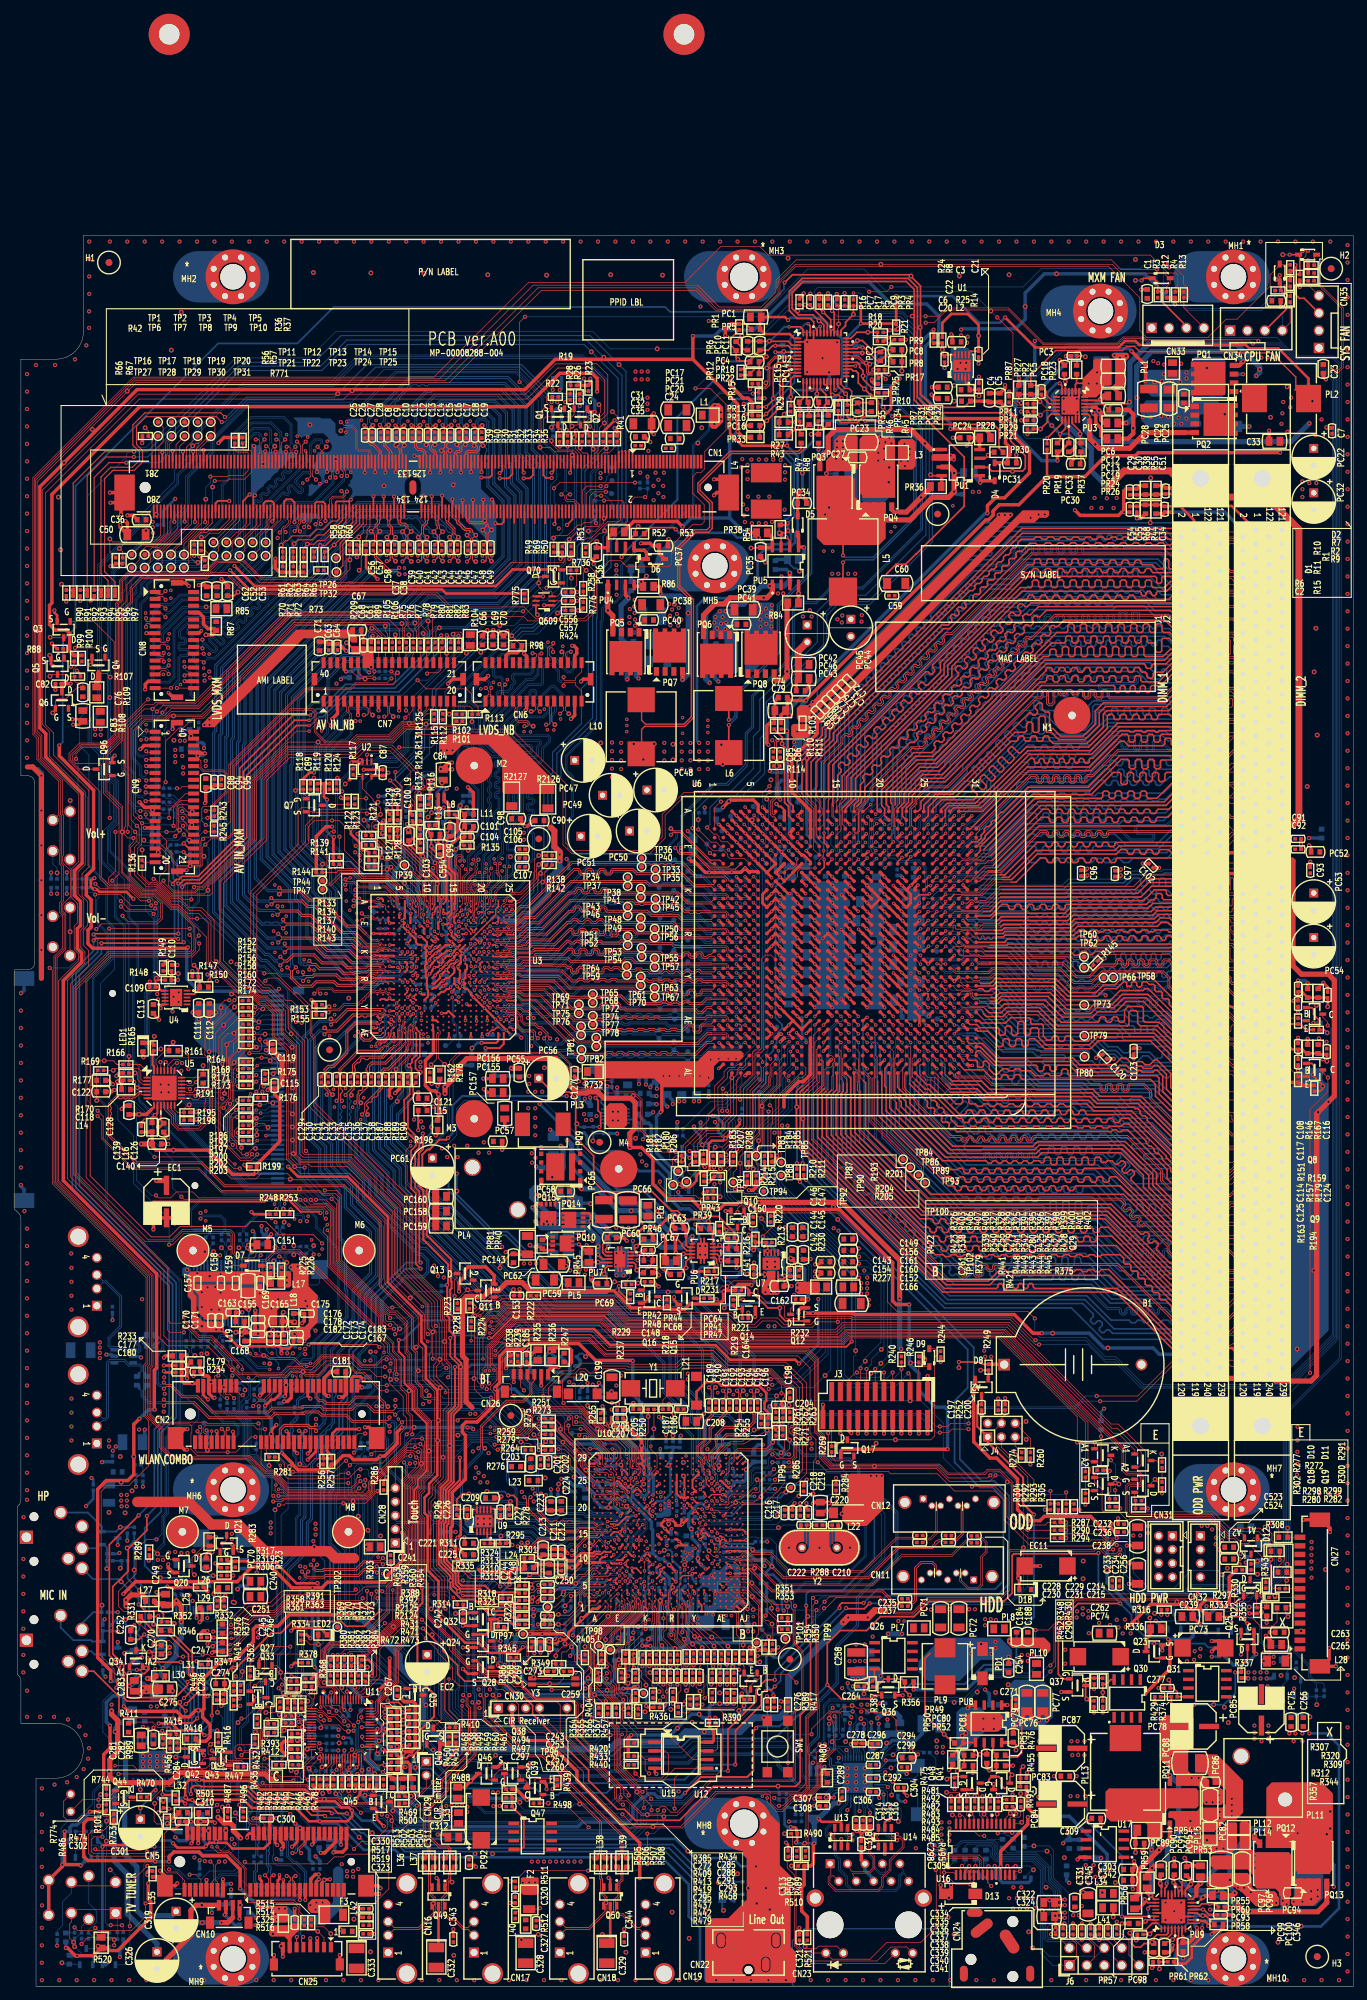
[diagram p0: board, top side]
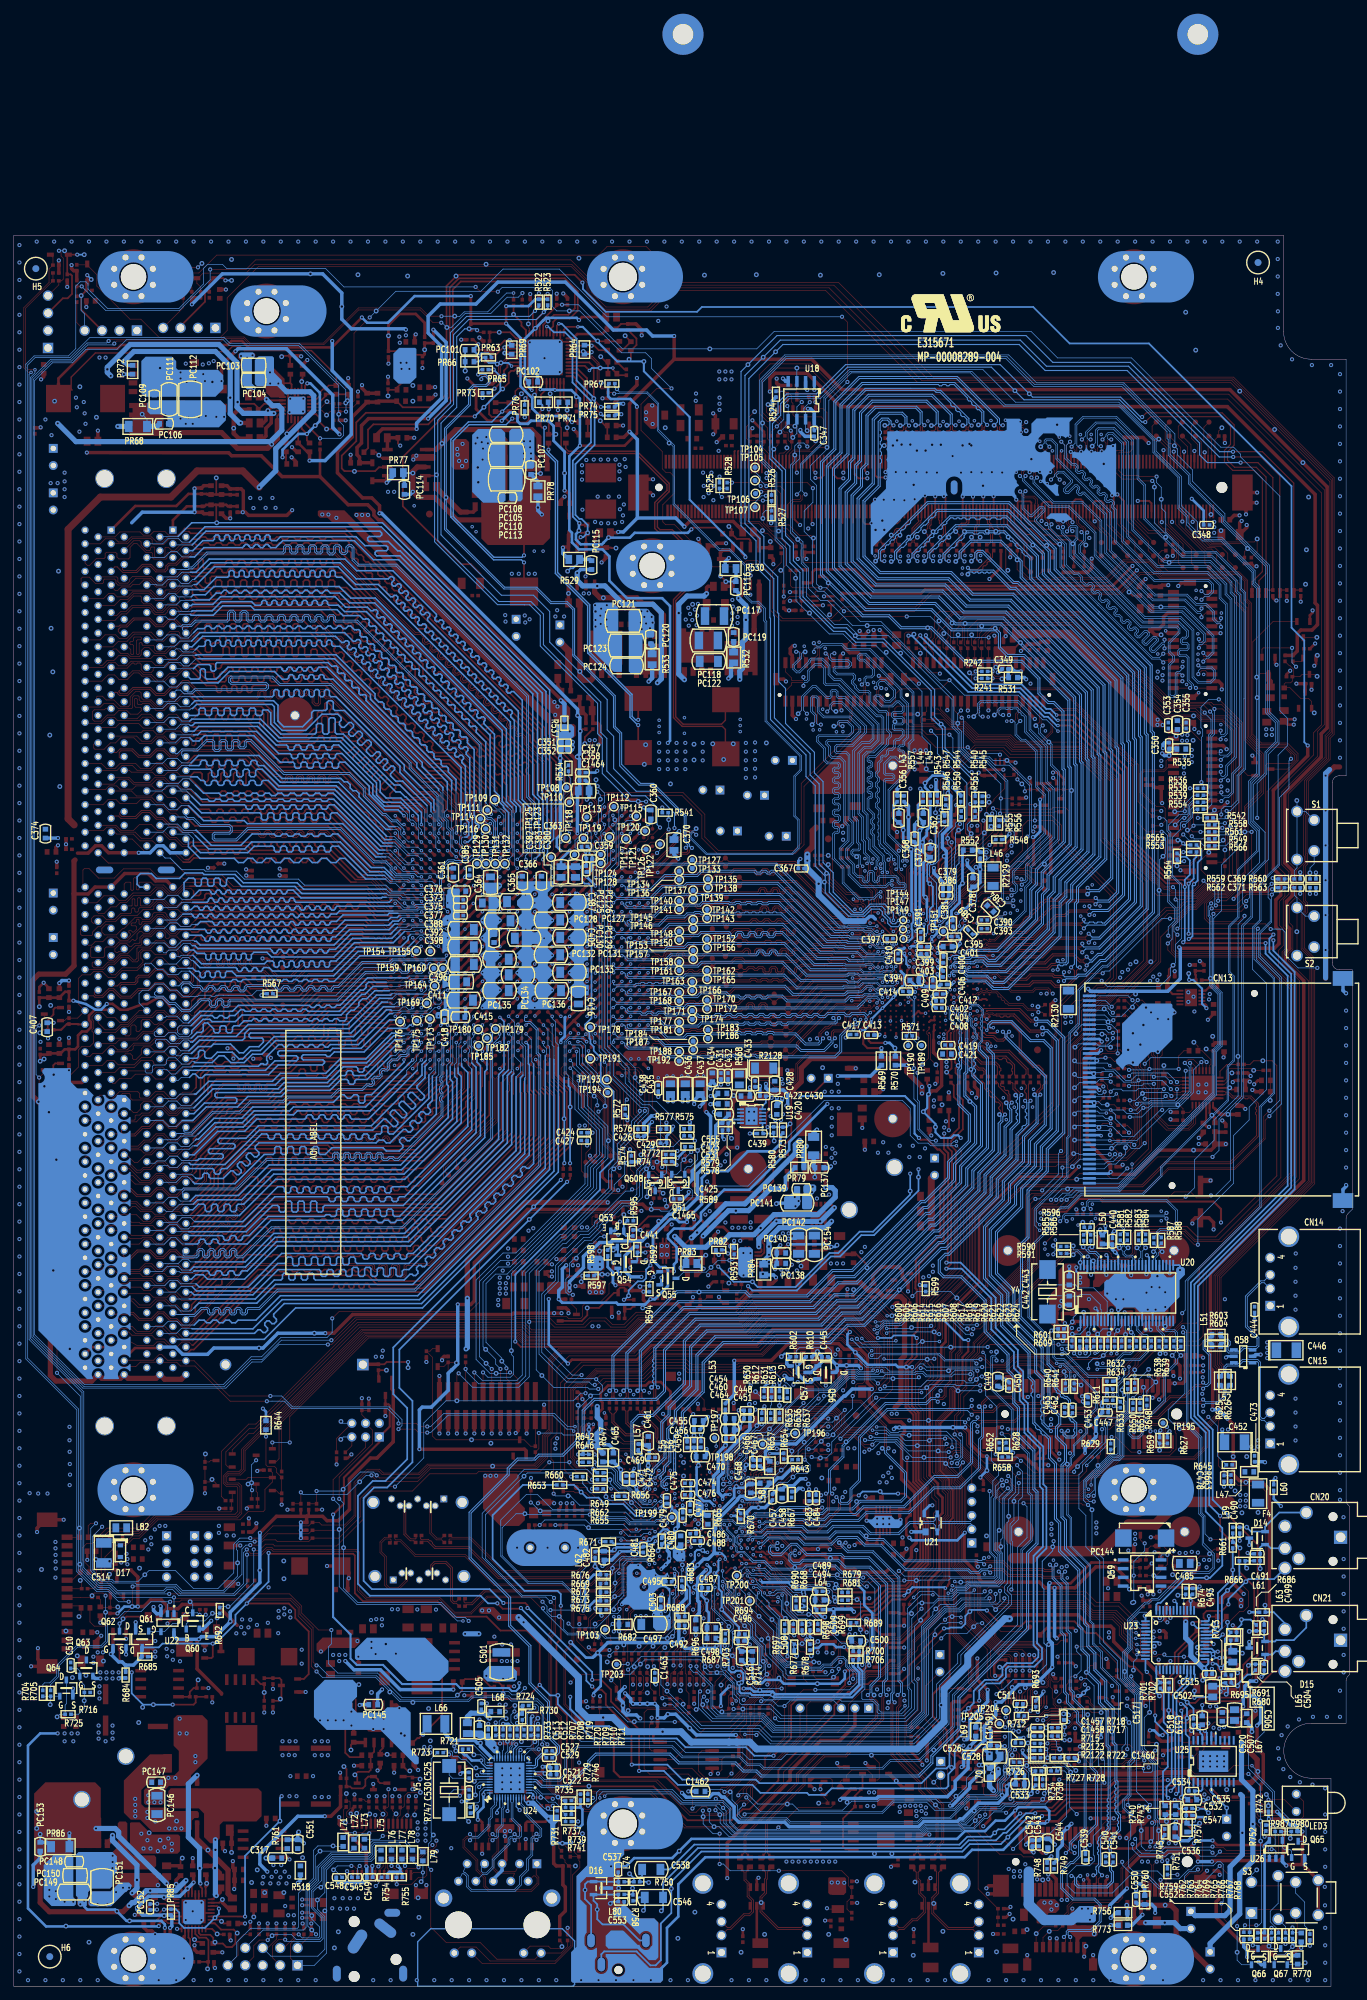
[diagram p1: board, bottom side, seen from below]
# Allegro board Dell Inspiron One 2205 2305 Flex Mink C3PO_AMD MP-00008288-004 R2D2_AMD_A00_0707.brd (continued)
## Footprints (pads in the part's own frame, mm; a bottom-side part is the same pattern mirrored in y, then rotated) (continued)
BGA941_127P5115L4808W620H
  round 0.559 smd: A3(-19.05,-16.51) A4(-19.05,-15.24) A5(-19.05,-13.97) A6(-19.05,-12.7) A7(-19.05,-11.43) A8(-19.05,-10.16) A9(-19.05,-8.89) A10(-19.05,-7.62) A11(-19.05,-6.35) A12(-19.05,-5.08) A13(-19.05,-3.81) A14(-19.05,-2.54) A15(-19.05,-1.27) A16(-19.05,0) A17(-19.05,1.27) A18(-19.05,2.54) A19(-19.05,3.81) A20(-19.05,5.08) A21(-19.05,6.35) A22(-19.05,7.62) A23(-19.05,8.89) A24(-19.05,10.16) A25(-19.05,11.43) A26(-19.05,12.7) A27(-19.05,13.97) A28(-19.05,15.24) A29(-19.05,16.51) AA1(6.35,-19.05) AA2(6.35,-17.78) AA3(6.35,-16.51) AA4(6.35,-15.24) AA5(6.35,-13.97) AA6(6.35,-12.7) AA7(6.35,-11.43) AA8(6.35,-10.16) AA9(6.35,-8.89) AA10(6.35,-7.62) AA11(6.35,-6.35) AA12(6.35,-5.08) AA13(6.35,-3.81) AA14(6.35,-2.54) AA15(6.35,-1.27) AA16(6.35,0) AA17(6.35,1.27) AA18(6.35,2.54) AA19(6.35,3.81) AA20(6.35,5.08) AA21(6.35,6.35) AA22(6.35,7.62) AA23(6.35,8.89) AA24(6.35,10.16) AA25(6.35,11.43) AA26(6.35,12.7) AA27(6.35,13.97) AA28(6.35,15.24) AA29(6.35,16.51) AA30(6.35,17.78) AA31(6.35,19.05) AB1(7.62,-19.05) AB2(7.62,-17.78) AB3(7.62,-16.51) AB4(7.62,-15.24) AB5(7.62,-13.97) AB6(7.62,-12.7) AB7(7.62,-11.43) AB8(7.62,-10.16) AB9(7.62,-8.89) AB10(7.62,-7.62) AB11(7.62,-6.35) AB12(7.62,-5.08) AB13(7.62,-3.81) AB14(7.62,-2.54) AB15(7.62,-1.27) AB16(7.62,0) AB17(7.62,1.27) AB18(7.62,2.54) AB19(7.62,3.81) AB20(7.62,5.08) AB21(7.62,6.35) AB22(7.62,7.62) AB23(7.62,8.89) AB24(7.62,10.16) AB25(7.62,11.43) AB26(7.62,12.7) AB27(7.62,13.97) AB28(7.62,15.24) AB29(7.62,16.51) AB30(7.62,17.78) AB31(7.62,19.05) AC1(8.89,-19.05) AC2(8.89,-17.78) AC3(8.89,-16.51) AC4(8.89,-15.24) AC5(8.89,-13.97) AC6(8.89,-12.7) AC7(8.89,-11.43) AC8(8.89,-10.16) AC9(8.89,-8.89) AC10(8.89,-7.62) AC11(8.89,-6.35) AC12(8.89,-5.08) AC13(8.89,-3.81) AC14(8.89,-2.54) AC15(8.89,-1.27) AC16(8.89,0) AC17(8.89,1.27) AC18(8.89,2.54) AC19(8.89,3.81) AC20(8.89,5.08) AC21(8.89,6.35) AC22(8.89,7.62) AC23(8.89,8.89) AC24(8.89,10.16) AC25(8.89,11.43) AC26(8.89,12.7) AC27(8.89,13.97) AC28(8.89,15.24) AC29(8.89,16.51) AC30(8.89,17.78) AC31(8.89,19.05) AD1(10.16,-19.05) AD2(10.16,-17.78) AD3(10.16,-16.51) AD4(10.16,-15.24) AD5(10.16,-13.97) AD6(10.16,-12.7) AD7(10.16,-11.43) AD8(10.16,-10.16) AD9(10.16,-8.89) AD10(10.16,-7.62) AD11(10.16,-6.35) AD12(10.16,-5.08) AD13(10.16,-3.81) AD14(10.16,-2.54) AD15(10.16,-1.27) AD16(10.16,0) AD17(10.16,1.27) AD20(10.16,5.08) AD21(10.16,6.35) AD22(10.16,7.62) AD23(10.16,8.89) AD24(10.16,10.16) AD25(10.16,11.43) AD26(10.16,12.7) AD27(10.16,13.97) AD28(10.16,15.24) AD29(10.16,16.51) AD30(10.16,17.78) AD31(10.16,19.05) AE1(11.43,-19.05) AE2(11.43,-17.78) AE3(11.43,-16.51) AE4(11.43,-15.24) AE5(11.43,-13.97) AE6(11.43,-12.7) AE7(11.43,-11.43) AE10(11.43,-7.62) AE11(11.43,-6.35) AE12(11.43,-5.08) AE13(11.43,-3.81) AE14(11.43,-2.54) AE15(11.43,-1.27) AE16(11.43,0) AE17(11.43,1.27) AE18(11.43,2.54) AE19(11.43,3.81) AE20(11.43,5.08) AE21(11.43,6.35) AE22(11.43,7.62) AE23(11.43,8.89) AE24(11.43,10.16) AE25(11.43,11.43) AE26(11.43,12.7) AE27(11.43,13.97) AE28(11.43,15.24) AE29(11.43,16.51) AE30(11.43,17.78) AE31(11.43,19.05) AF1(12.7,-19.05) AF2(12.7,-17.78) AF3(12.7,-16.51) AF4(12.7,-15.24) AF5(12.7,-13.97) AF6(12.7,-12.7) AF7(12.7,-11.43) AF8(12.7,-10.16) AF9(12.7,-8.89) AF10(12.7,-7.62) AF11(12.7,-6.35) AF12(12.7,-5.08) AF13(12.7,-3.81) AF14(12.7,-2.54) AF15(12.7,-1.27) AF16(12.7,0) AF17(12.7,1.27) AF18(12.7,2.54) AF19(12.7,3.81) AF20(12.7,5.08) AF21(12.7,6.35) AF22(12.7,7.62) AF23(12.7,8.89) AF24(12.7,10.16) AF25(12.7,11.43) AF26(12.7,12.7) AF27(12.7,13.97) AF28(12.7,15.24) AF29(12.7,16.51) AF30(12.7,17.78) AF31(12.7,19.05) AG1(13.97,-19.05) AG2(13.97,-17.78) AG3(13.97,-16.51) AG4(13.97,-15.24) AG5(13.97,-13.97) AG6(13.97,-12.7) AG7(13.97,-11.43) AG8(13.97,-10.16) AG9(13.97,-8.89) AG10(13.97,-7.62) AG11(13.97,-6.35) AG12(13.97,-5.08) AG13(13.97,-3.81) AG14(13.97,-2.54) AG15(13.97,-1.27) AG16(13.97,0) AG17(13.97,1.27) AG18(13.97,2.54) AG19(13.97,3.81) AG20(13.97,5.08) AG21(13.97,6.35) AG22(13.97,7.62) AG23(13.97,8.89) AG24(13.97,10.16) AG25(13.97,11.43) AG26(13.97,12.7) AG27(13.97,13.97) AG28(13.97,15.24) AG29(13.97,16.51) AG30(13.97,17.78) AG31(13.97,19.05) AH1(15.24,-19.05) AH2(15.24,-17.78) AH3(15.24,-16.51) AH4(15.24,-15.24) AH5(15.24,-13.97) AH6(15.24,-12.7) AH7(15.24,-11.43) AH8(15.24,-10.16) AH9(15.24,-8.89) AH10(15.24,-7.62) AH11(15.24,-6.35) AH12(15.24,-5.08) AH13(15.24,-3.81) AH14(15.24,-2.54) AH15(15.24,-1.27) AH16(15.24,0) AH17(15.24,1.27) AH18(15.24,2.54) AH19(15.24,3.81) AH20(15.24,5.08) AH21(15.24,6.35) AH22(15.24,7.62) AH23(15.24,8.89) AH24(15.24,10.16) AH25(15.24,11.43) AH26(15.24,12.7) AH27(15.24,13.97) AH28(15.24,15.24) AH29(15.24,16.51) AH30(15.24,17.78) AH31(15.24,19.05) AJ1(16.51,-19.05) AJ2(16.51,-17.78) AJ3(16.51,-16.51) AJ4(16.51,-15.24) AJ5(16.51,-13.97) AJ6(16.51,-12.7) AJ7(16.51,-11.43) AJ8(16.51,-10.16) AJ9(16.51,-8.89) AJ10(16.51,-7.62) AJ11(16.51,-6.35) AJ12(16.51,-5.08) AJ13(16.51,-3.81) AJ14(16.51,-2.54) AJ15(16.51,-1.27) AJ16(16.51,0) AJ17(16.51,1.27) AJ18(16.51,2.54) AJ19(16.51,3.81) AJ20(16.51,5.08) AJ21(16.51,6.35) AJ22(16.51,7.62) AJ23(16.51,8.89) AJ24(16.51,10.16) AJ25(16.51,11.43) AJ26(16.51,12.7) AJ27(16.51,13.97) AJ28(16.51,15.24) AJ29(16.51,16.51) AJ30(16.51,17.78) AJ31(16.51,19.05) AK2(17.78,-17.78) AK3(17.78,-16.51) AK4(17.78,-15.24) AK5(17.78,-13.97) AK6(17.78,-12.7) AK7(17.78,-11.43) AK8(17.78,-10.16) AK9(17.78,-8.89) AK10(17.78,-7.62) AK11(17.78,-6.35) AK12(17.78,-5.08) AK13(17.78,-3.81) AK14(17.78,-2.54) AK15(17.78,-1.27) AK16(17.78,0) AK17(17.78,1.27) AK18(17.78,2.54) AK19(17.78,3.81) AK20(17.78,5.08) AK21(17.78,6.35) AK22(17.78,7.62) AK23(17.78,8.89) AK24(17.78,10.16) AK25(17.78,11.43) AK26(17.78,12.7) AK27(17.78,13.97) AK28(17.78,15.24) AK29(17.78,16.51) AK30(17.78,17.78) AL3(19.05,-16.51) AL4(19.05,-15.24) AL5(19.05,-13.97) AL6(19.05,-12.7) AL7(19.05,-11.43) AL8(19.05,-10.16) AL9(19.05,-8.89) AL10(19.05,-7.62) AL11(19.05,-6.35) AL12(19.05,-5.08) AL13(19.05,-3.81) AL14(19.05,-2.54) AL15(19.05,-1.27) AL16(19.05,0) AL17(19.05,1.27) AL18(19.05,2.54) AL19(19.05,3.81) AL20(19.05,5.08) AL21(19.05,6.35) AL22(19.05,7.62) AL23(19.05,8.89) AL24(19.05,10.16) AL25(19.05,11.43) AL26(19.05,12.7) AL27(19.05,13.97) AL28(19.05,15.24) AL29(19.05,16.51) B2(-17.78,-17.78) B3(-17.78,-16.51) B4(-17.78,-15.24) B5(-17.78,-13.97) B6(-17.78,-12.7) B7(-17.78,-11.43) B8(-17.78,-10.16) B9(-17.78,-8.89) B10(-17.78,-7.62) B11(-17.78,-6.35) B12(-17.78,-5.08) B13(-17.78,-3.81) B14(-17.78,-2.54) B15(-17.78,-1.27) B16(-17.78,0) B17(-17.78,1.27) B18(-17.78,2.54) B19(-17.78,3.81) B20(-17.78,5.08) B21(-17.78,6.35) B22(-17.78,7.62) B23(-17.78,8.89) B24(-17.78,10.16) B25(-17.78,11.43) B26(-17.78,12.7) B27(-17.78,13.97) B28(-17.78,15.24) B29(-17.78,16.51) B30(-17.78,17.78) C1(-16.51,-19.05) C2(-16.51,-17.78) C3(-16.51,-16.51) C4(-16.51,-15.24) C5(-16.51,-13.97) C6(-16.51,-12.7) C7(-16.51,-11.43) C8(-16.51,-10.16) C9(-16.51,-8.89) C10(-16.51,-7.62) C11(-16.51,-6.35) C12(-16.51,-5.08) C13(-16.51,-3.81) C14(-16.51,-2.54) C15(-16.51,-1.27) C16(-16.51,0) C17(-16.51,1.27) C18(-16.51,2.54) C19(-16.51,3.81) C20(-16.51,5.08) C21(-16.51,6.35) C22(-16.51,7.62) C23(-16.51,8.89) C24(-16.51,10.16) C25(-16.51,11.43) C26(-16.51,12.7) C27(-16.51,13.97) C28(-16.51,15.24) C29(-16.51,16.51) C30(-16.51,17.78) C31(-16.51,19.05) D1(-15.24,-19.05) D2(-15.24,-17.78) D3(-15.24,-16.51) D4(-15.24,-15.24) D5(-15.24,-13.97) D6(-15.24,-12.7) D7(-15.24,-11.43) D8(-15.24,-10.16) D9(-15.24,-8.89) D10(-15.24,-7.62) D11(-15.24,-6.35) D12(-15.24,-5.08) D13(-15.24,-3.81) D14(-15.24,-2.54) D15(-15.24,-1.27) D16(-15.24,0) D17(-15.24,1.27) D18(-15.24,2.54) D19(-15.24,3.81) D20(-15.24,5.08) D21(-15.24,6.35) D22(-15.24,7.62) D23(-15.24,8.89) D24(-15.24,10.16) D25(-15.24,11.43) D26(-15.24,12.7) D27(-15.24,13.97) D28(-15.24,15.24) D29(-15.24,16.51) D30(-15.24,17.78) D31(-15.24,19.05) E1(-13.97,-19.05) E2(-13.97,-17.78) E3(-13.97,-16.51) E4(-13.97,-15.24) E5(-13.97,-13.97) E6(-13.97,-12.7) E7(-13.97,-11.43) E8(-13.97,-10.16) E9(-13.97,-8.89) E10(-13.97,-7.62) E11(-13.97,-6.35) E12(-13.97,-5.08) E13(-13.97,-3.81) E14(-13.97,-2.54) E15(-13.97,-1.27) E16(-13.97,0) E17(-13.97,1.27) E18(-13.97,2.54) E19(-13.97,3.81) E20(-13.97,5.08) E21(-13.97,6.35) E22(-13.97,7.62) E23(-13.97,8.89) E24(-13.97,10.16) E25(-13.97,11.43) E26(-13.97,12.7) E27(-13.97,13.97) E28(-13.97,15.24) E29(-13.97,16.51) E30(-13.97,17.78) E31(-13.97,19.05) F1(-12.7,-19.05) F2(-12.7,-17.78) F3(-12.7,-16.51) F4(-12.7,-15.24) F5(-12.7,-13.97) F6(-12.7,-12.7) F7(-12.7,-11.43) F8(-12.7,-10.16) F9(-12.7,-8.89) F10(-12.7,-7.62) F11(-12.7,-6.35) F12(-12.7,-5.08) F13(-12.7,-3.81) F14(-12.7,-2.54) F15(-12.7,-1.27) F16(-12.7,0) F17(-12.7,1.27) F18(-12.7,2.54) F19(-12.7,3.81) F20(-12.7,5.08) F21(-12.7,6.35) F22(-12.7,7.62) F23(-12.7,8.89) F24(-12.7,10.16) F25(-12.7,11.43) F26(-12.7,12.7) F27(-12.7,13.97) F28(-12.7,15.24) F29(-12.7,16.51) F30(-12.7,17.78) F31(-12.7,19.05) G1(-11.43,-19.05) G2(-11.43,-17.78) G3(-11.43,-16.51) G4(-11.43,-15.24) G5(-11.43,-13.97) G6(-11.43,-12.7) G7(-11.43,-11.43) G8(-11.43,-10.16) G9(-11.43,-8.89) G10(-11.43,-7.62) G11(-11.43,-6.35) G12(-11.43,-5.08) G13(-11.43,-3.81) G14(-11.43,-2.54) G15(-11.43,-1.27) G16(-11.43,0) G17(-11.43,1.27) G18(-11.43,2.54) G19(-11.43,3.81) G20(-11.43,5.08) G21(-11.43,6.35) G22(-11.43,7.62) G23(-11.43,8.89) G24(-11.43,10.16) G25(-11.43,11.43) G26(-11.43,12.7) G27(-11.43,13.97) G28(-11.43,15.24) G29(-11.43,16.51) G30(-11.43,17.78) G31(-11.43,19.05) H1(-10.16,-19.05) H2(-10.16,-17.78) H5(-10.16,-13.97) H6(-10.16,-12.7) H7(-10.16,-11.43) H8(-10.16,-10.16) H9(-10.16,-8.89) H10(-10.16,-7.62) H11(-10.16,-6.35) H12(-10.16,-5.08) H13(-10.16,-3.81) H14(-10.16,-2.54) H15(-10.16,-1.27) H16(-10.16,0) H17(-10.16,1.27) H18(-10.16,2.54) H19(-10.16,3.81) H20(-10.16,5.08) H23(-10.16,8.89) H24(-10.16,10.16) H25(-10.16,11.43) H26(-10.16,12.7) H27(-10.16,13.97) H28(-10.16,15.24) H29(-10.16,16.51) H30(-10.16,17.78) H31(-10.16,19.05) J1(-8.89,-19.05) J2(-8.89,-17.78) J3(-8.89,-16.51) J4(-8.89,-15.24) J5(-8.89,-13.97) J6(-8.89,-12.7) J7(-8.89,-11.43) J8(-8.89,-10.16) J9(-8.89,-8.89) J10(-8.89,-7.62) J11(-8.89,-6.35) J12(-8.89,-5.08) J13(-8.89,-3.81) J14(-8.89,-2.54) J15(-8.89,-1.27) J16(-8.89,0) J17(-8.89,1.27) J18(-8.89,2.54) J19(-8.89,3.81) J20(-8.89,5.08) J21(-8.89,6.35) J22(-8.89,7.62) J23(-8.89,8.89) J24(-8.89,10.16) J25(-8.89,11.43) J26(-8.89,12.7) J27(-8.89,13.97) J28(-8.89,15.24) J29(-8.89,16.51) J30(-8.89,17.78) J31(-8.89,19.05) K1(-7.62,-19.05) K2(-7.62,-17.78) K3(-7.62,-16.51) K4(-7.62,-15.24) K5(-7.62,-13.97) K6(-7.62,-12.7) K7(-7.62,-11.43) K8(-7.62,-10.16) K9(-7.62,-8.89) K10(-7.62,-7.62) K11(-7.62,-6.35) K12(-7.62,-5.08) K13(-7.62,-3.81) K14(-7.62,-2.54) K15(-7.62,-1.27) K16(-7.62,0) K17(-7.62,1.27) K18(-7.62,2.54) K19(-7.62,3.81) K20(-7.62,5.08) K21(-7.62,6.35) K22(-7.62,7.62) K23(-7.62,8.89) K24(-7.62,10.16) K25(-7.62,11.43) K26(-7.62,12.7) K27(-7.62,13.97) K28(-7.62,15.24) K29(-7.62,16.51) K30(-7.62,17.78) K31(-7.62,19.05) L1(-6.35,-19.05) L2(-6.35,-17.78) L3(-6.35,-16.51) L4(-6.35,-15.24) L5(-6.35,-13.97) L6(-6.35,-12.7) L7(-6.35,-11.43) L8(-6.35,-10.16) L9(-6.35,-8.89) L10(-6.35,-7.62) L11(-6.35,-6.35) L12(-6.35,-5.08) L13(-6.35,-3.81) L14(-6.35,-2.54) L15(-6.35,-1.27) L16(-6.35,0) L17(-6.35,1.27) L18(-6.35,2.54) L19(-6.35,3.81) L20(-6.35,5.08) L21(-6.35,6.35) L22(-6.35,7.62) L23(-6.35,8.89) L24(-6.35,10.16) L25(-6.35,11.43) L26(-6.35,12.7) L27(-6.35,13.97) L28(-6.35,15.24) L29(-6.35,16.51) L30(-6.35,17.78) L31(-6.35,19.05) M1(-5.08,-19.05) M2(-5.08,-17.78) M3(-5.08,-16.51) M4(-5.08,-15.24) M5(-5.08,-13.97) M6(-5.08,-12.7) M7(-5.08,-11.43) M8(-5.08,-10.16) M9(-5.08,-8.89) M10(-5.08,-7.62) M11(-5.08,-6.35) M12(-5.08,-5.08) M13(-5.08,-3.81) M14(-5.08,-2.54) M15(-5.08,-1.27) M16(-5.08,0) M17(-5.08,1.27) M18(-5.08,2.54) M19(-5.08,3.81) M20(-5.08,5.08) M21(-5.08,6.35) M22(-5.08,7.62) M23(-5.08,8.89) M24(-5.08,10.16) M25(-5.08,11.43) M26(-5.08,12.7) M27(-5.08,13.97) M28(-5.08,15.24) M29(-5.08,16.51) M30(-5.08,17.78) M31(-5.08,19.05) N1(-3.81,-19.05) N2(-3.81,-17.78) N3(-3.81,-16.51) N4(-3.81,-15.24) N5(-3.81,-13.97) N6(-3.81,-12.7) N7(-3.81,-11.43) N8(-3.81,-10.16) N9(-3.81,-8.89) N10(-3.81,-7.62) N11(-3.81,-6.35) N12(-3.81,-5.08) N13(-3.81,-3.81) N14(-3.81,-2.54) N15(-3.81,-1.27) N16(-3.81,0) N17(-3.81,1.27) N18(-3.81,2.54) N19(-3.81,3.81) N20(-3.81,5.08) N21(-3.81,6.35) N22(-3.81,7.62) N23(-3.81,8.89) N24(-3.81,10.16) N25(-3.81,11.43) N26(-3.81,12.7) N27(-3.81,13.97) N28(-3.81,15.24) N29(-3.81,16.51) N30(-3.81,17.78) N31(-3.81,19.05) P1(-2.54,-19.05) P2(-2.54,-17.78) P3(-2.54,-16.51) P4(-2.54,-15.24) P5(-2.54,-13.97) P6(-2.54,-12.7) P7(-2.54,-11.43) P8(-2.54,-10.16) P9(-2.54,-8.89) P10(-2.54,-7.62) P11(-2.54,-6.35) P12(-2.54,-5.08) P13(-2.54,-3.81) P14(-2.54,-2.54) P15(-2.54,-1.27) P16(-2.54,0) P17(-2.54,1.27) P18(-2.54,2.54) P19(-2.54,3.81) P20(-2.54,5.08) P21(-2.54,6.35) P22(-2.54,7.62) P23(-2.54,8.89) P24(-2.54,10.16) P25(-2.54,11.43) P26(-2.54,12.7) P27(-2.54,13.97) P28(-2.54,15.24) P29(-2.54,16.51) P30(-2.54,17.78) P31(-2.54,19.05) R1(-1.27,-19.05) R2(-1.27,-17.78) R3(-1.27,-16.51) R4(-1.27,-15.24) R5(-1.27,-13.97) R6(-1.27,-12.7) R7(-1.27,-11.43) R8(-1.27,-10.16) R9(-1.27,-8.89) R10(-1.27,-7.62) R11(-1.27,-6.35) R12(-1.27,-5.08) R13(-1.27,-3.81) R14(-1.27,-2.54) R15(-1.27,-1.27) R16(-1.27,0) R17(-1.27,1.27) R18(-1.27,2.54) R19(-1.27,3.81) R20(-1.27,5.08) R21(-1.27,6.35) R22(-1.27,7.62) R23(-1.27,8.89) R24(-1.27,10.16) R25(-1.27,11.43) R26(-1.27,12.7) R27(-1.27,13.97) R28(-1.27,15.24) R29(-1.27,16.51) R30(-1.27,17.78) R31(-1.27,19.05) T1(0,-19.05) T2(0,-17.78) T3(0,-16.51) T4(0,-15.24) T5(0,-13.97) T6(0,-12.7) T7(0,-11.43) T8(0,-10.16) T9(0,-8.89) T10(0,-7.62) T11(0,-6.35) T12(0,-5.08) T13(0,-3.81) T14(0,-2.54) T15(0,-1.27) T16(0,0) T17(0,1.27) T18(0,2.54) T19(0,3.81) T20(0,5.08) T21(0,6.35) T22(0,7.62) T23(0,8.89) T24(0,10.16) T25(0,11.43) T26(0,12.7) T27(0,13.97) T28(0,15.24) T29(0,16.51) T30(0,17.78) T31(0,19.05) U1(1.27,-19.05) U2(1.27,-17.78) U3(1.27,-16.51) U4(1.27,-15.24) U5(1.27,-13.97) U6(1.27,-12.7) U7(1.27,-11.43) U8(1.27,-10.16) U9(1.27,-8.89) U10(1.27,-7.62) U11(1.27,-6.35) U12(1.27,-5.08) U13(1.27,-3.81) U14(1.27,-2.54) U15(1.27,-1.27) U16(1.27,0) U17(1.27,1.27) U18(1.27,2.54) U19(1.27,3.81) U20(1.27,5.08) U21(1.27,6.35) U22(1.27,7.62) U23(1.27,8.89) U24(1.27,10.16) U25(1.27,11.43) U26(1.27,12.7) U27(1.27,13.97) U28(1.27,15.24) U29(1.27,16.51) U30(1.27,17.78) U31(1.27,19.05) V1(2.54,-19.05) V2(2.54,-17.78) V3(2.54,-16.51) V4(2.54,-15.24) V5(2.54,-13.97) V6(2.54,-12.7) V7(2.54,-11.43) V8(2.54,-10.16) V9(2.54,-8.89) V10(2.54,-7.62) V11(2.54,-6.35) V12(2.54,-5.08) V13(2.54,-3.81) V14(2.54,-2.54) V15(2.54,-1.27) V16(2.54,0) V17(2.54,1.27) V18(2.54,2.54) V19(2.54,3.81) V20(2.54,5.08) V21(2.54,6.35) V22(2.54,7.62) V23(2.54,8.89) V24(2.54,10.16) V25(2.54,11.43) V26(2.54,12.7) V27(2.54,13.97) V28(2.54,15.24) V29(2.54,16.51) V30(2.54,17.78) V31(2.54,19.05) W1(3.81,-19.05) W2(3.81,-17.78) W3(3.81,-16.51) W4(3.81,-15.24) W5(3.81,-13.97) W6(3.81,-12.7) W7(3.81,-11.43) W8(3.81,-10.16) W9(3.81,-8.89) W10(3.81,-7.62) W11(3.81,-6.35) W12(3.81,-5.08) W13(3.81,-3.81) W14(3.81,-2.54) W15(3.81,-1.27) W16(3.81,0) W17(3.81,1.27) W18(3.81,2.54) W19(3.81,3.81) W20(3.81,5.08) W21(3.81,6.35) W22(3.81,7.62) W23(3.81,8.89) W24(3.81,10.16) W25(3.81,11.43) W26(3.81,12.7) W27(3.81,13.97) W28(3.81,15.24) W29(3.81,16.51) W30(3.81,17.78) W31(3.81,19.05) Y1(5.08,-19.05) Y2(5.08,-17.78) Y3(5.08,-16.51) Y4(5.08,-15.24) Y5(5.08,-13.97) Y6(5.08,-12.7) Y7(5.08,-11.43) Y8(5.08,-10.16) Y9(5.08,-8.89) Y10(5.08,-7.62) Y11(5.08,-6.35) Y12(5.08,-5.08) Y13(5.08,-3.81) Y14(5.08,-2.54) Y15(5.08,-1.27) Y16(5.08,0) Y17(5.08,1.27) Y18(5.08,2.54) Y19(5.08,3.81) Y20(5.08,5.08) Y21(5.08,6.35) Y22(5.08,7.62) Y23(5.08,8.89) Y24(5.08,10.16) Y25(5.08,11.43) Y26(5.08,12.7) Y27(5.08,13.97) Y28(5.08,15.24) Y29(5.08,16.51) Y30(5.08,17.78) Y31(5.08,19.05)
C0402
  rect 0.559x0.508 smd: 1(-0.429,0) 2(0.429,0)
C0603
  rect 0.711x0.813 smd: 1(-0.645,0) 2(0.645,0)
C0805
  rect 0.991x1.321 smd: 1(-0.785,0) 2(0.785,0)
C1206
  rect 1.143x1.651 smd: 1(-1.331,0) 2(1.331,0)
C1210
  rect 1.245x2.591 smd: 1(-1.382,0) 2(1.382,0)
CKR900P1140L1140W820H
  round 2.54 hole 2.057: 1(3.2,-3.15) 2(-3.2,3.15)
CKR905P1150L1150W1050H
  round 2.54 hole 2.057: 1(-3.099,-3.299) 2(3.099,3.299)
CKS290L250W210H
  rect 1.321x2.54 smd: 1(-1.295,0) 2(1.295,0)
CKS660L660W280H
  rect 2.794x3.048 smd: 1(-2.697,0) 2(2.697,0)
CKS686L647W500H
  rect 2.21x3.429 smd: 1(-2.959,0) 2(2.959,0)
CKS750L700W520H
  rect 2.794x4.496 smd: 1(-2.647,0) 2(2.647,0)
CKS1000L1000W400H
  rect 3.632x3.988 smd: 1(-3.94,0) 2(3.94,0)
CKS1100L1000W400H
  rect 3.81x4.597 smd: 1(-4.905,0) 2(4.905,0)
CKS1150L1000W500H
  rect 4.115x4.115 smd: 1(-4.757,0) 2(4.757,0)
CMC-2012_CHILISIN
  rect 0.889x0.356 smd: 1(0.843,-0.427) 2(-0.843,-0.427) 3(-0.843,0.427) 4(0.843,0.427)
D0603_AC
  rect 0.61x0.787 smd: A(0.851,0) C(-0.851,0)
DBH4_200P1X4_1000X450
  rect 1.346x1.346 hole 0.838: 1(-3,0)
  round 1.346 hole 0.838: 2(-1.001,0) 3(1.001,0) 4(3,0)
DBH8_200P2X4_1000X505N
  rect 1.346x1.346 hole 0.838: 1(-3,1.001)
  round 1.346 hole 0.838: 2(-3,-1.001) 3(-1.001,1.001) 4(-1.001,-1.001) 5(1.001,1.001) 6(1.001,-1.001) 7(3,1.001) 8(3,-1.001)
DCON_FAN_4_KORTAK
  rect 1.524x1.524 hole 1.092: 1(-3.81,0)
  round 1.524 hole 1.092: 2(-1.27,0) 3(1.27,0) 4(3.81,0)
DCON_JACK_PLUG_5_HOMETOM
  round 1.194 hole 1.194 unplated: (0,-2.55)
  oval 2.007x1.118 hole 0.02: 2(0,2.55)
  oval 1.118x2.007 hole 0.023: 3(-4,1.75) 4(-2.499,-1.75) 5(2.499,-1.75) 6(4,1.75) MH1(-5.1,0) MH2(5.1,0)
DCON_PLUG-AUD_8_SINGATRON
  round 1.295 hole 1.295 unplated: (-3,0) (3.5,0)
  rect 1.93x1.93 hole 1.397: 1(0,1.1)
  round 1.93 hole 1.397: 2(-3.599,-3.899) 3(1.6,-7) 4(3.099,-5.004) 5(4.501,-7) 6(-1.6,-7)
DCON_POWER-JACK_2_SINGATRON
  round 1.6 hole 1.6 unplated: (-3.8,-1.501) (2.301,4) (2.301,-4)
  oval 1.702x3.835 hole 0.036 rot 33: 1(1.826,1.095)
  oval 1.499x3.658 hole 0.033 rot 128: 2(-2.23,3.04)
  oval 2.311x1.168 hole 0.038: MH1(-3.251,5.281)
  oval 1.168x2.311 hole 0.041: MH2(-4.831,-3.579) MH3(4.831,-3.579)
DCON_PUBTON_8_HIGHLY-A
  rect 1.702x1.702 hole 1.194: 1(2.25,-3.899)
  round 1.702 hole 1.194: 2(2.25,2.54) 3(-2.25,-3.899) 4(-2.25,2.54) L1(3.15,0) L2(-3.15,0) M1(2.54,5.839) M2(-2.54,5.839)
DCON_RJ45LEDX2_14_UDE_3
  round 3.912 hole 3.912 unplated: (-5.715,0) (5.715,0)
  rect 1.295x1.295 hole 0.787: 1(5.715,-8.89)
  round 1.295 hole 0.787: 2(4.445,-6.35) 3(3.175,-8.89) 4(1.905,-6.35) 5(0.635,-8.89) 6(-0.635,-6.35) 7(-1.905,-8.89) 8(-3.175,-6.35) 9(-4.445,-8.89) 10(-5.715,-6.35)
  round 2.54 hole 1.6: G1(-7.877,-3.889) G2(7.877,-3.889)
  round 1.346 hole 0.838: L1(6.325,4.11) L2(3.785,4.11) L3(-3.785,4.11) L4(-6.325,4.11)
DCON_SATABOX_7_HOMETOM
  rect 1.016x1.016 hole 0.711: 1(3.81,-0.5)
  round 1.016 hole 0.711: 2(2.54,0.5) 3(1.27,0.5) 4(0,-0.5) 5(-1.27,0.5) 6(-2.54,0.5) 7(-3.81,-0.5)
  round 1.905 hole 1.346: 8(6.48,0) 9(-6.48,0)
DCON_SW_4_DIPTRONICS
  round 1.702 hole 1.194: 1(-2.25,-2.499) 2(2.25,-2.499) 3(-3.5,0) 4(3.5,0)
DCON_USBX1_4_AUK_3
  rect 1.448x1.448 hole 1.041: 1(-3.5,2.71)
  round 1.448 hole 1.041: 2(-1.001,2.71) 3(1.001,2.71) 4(3.5,2.71)
  round 3.048 hole 2.311: H1(-6.571,0) H2(6.571,0)
DCON_USBX1_4_FOXCONN
  rect 1.448x1.448 hole 1.041: 1(-3.5,2.71)
  round 1.448 hole 1.041: 2(-1.001,2.71) 3(1.001,2.71) 4(3.5,2.71)
  round 3.048 hole 2.311: H1(-6.571,0) H2(6.571,0)
DCRY2_49US034H
  round 1.27 hole 0.762: 1(-2.54,0) 2(2.54,0)
DEC063D60H
  rect 1.295x1.295 hole 0.787: 1(-1.25,0)
  round 1.295 hole 0.787: 2(1.25,0)
DEC063D70H
  rect 1.346x1.346 hole 0.838: 1(-1.25,0)
  round 1.346 hole 0.838: 2(1.25,0)
DEC063D110H
  rect 1.346x1.346 hole 0.838: 1(-1.25,0)
  round 1.346 hole 0.838: 2(1.25,0)
DFN5_065P330W080H
  custom 0.537x0.537 smd: D(0,0.681)
  rect 0.432x0.711 smd: G1(0.975,-1.4) S1(-0.975,-1.4) S2(-0.325,-1.4) S3(0.325,-1.4)
DFN5_127P610W110H
  custom 1.201x1.201 smd: D(0,0.925)
  rect 0.762x1.27 smd: G1(1.905,-2.86) S1(-1.905,-2.86) S2(-0.635,-2.86) S3(0.635,-2.86)
DFN10_127P600W080H
  rect 3.988x0.914 smd: D1(0,-1.661)
  rect 0.66x0.635 smd: D2(-0.635,-2.835) D3(0.635,-2.835) D4(1.905,-2.835) G2(-1.905,-2.835) G3(-1.905,2.84) S1(-0.635,2.84) S2(0.635,2.84) S3(1.905,2.84)
  rect 3.988x2.667 smd: G1(0,0.79)
DH2_200P1X3_K3
  rect 1.346x1.346 hole 0.838: 1(-1.999,0)
  round 1.346 hole 0.838: 2(0,0)
DH5_200P1X6_K5
  rect 1.346x1.346 hole 0.838: 1(-5.001,0)
  round 1.346 hole 0.838: 2(-3,0) 3(-1.001,0) 4(1.001,0) 6(5.001,0)
DH5_200P1X6_K6
  rect 1.346x1.346 hole 0.838: 1(-5.001,0)
  round 1.346 hole 0.838: 2(-3.002,0) 3(-1.003,0) 4(0.996,0) 5(2.995,0)
DH6_200P2X3N
  rect 1.346x1.346 hole 0.838: 1(0,0)
  round 1.346 hole 0.838: 2(0,1.999) 3(1.999,0) 4(1.999,1.999) 5(4,0) 6(4,1.999)
DH9_254P2X5N_K10
  rect 1.524x1.524 hole 1.092: 1(0,0)
  round 1.524 hole 1.092: 2(0,2.54) 3(2.54,0) 4(2.54,2.54) 5(5.08,0) 6(5.08,2.54) 7(7.62,0) 8(7.62,2.54) 9(10.16,0)
DWAF4_254P575W1006L
  rect 1.524x1.524 hole 1.092: 1(-3.81,0)
  round 1.524 hole 1.092: 2(-1.27,0) 3(1.27,0) 4(3.81,0)
FM_A
  round 1.016 smd: 1(0,0)
HOLE_3-7_8MM_BOT14
  round 3.708 hole 3.708 unplated: (0,0)
  round 1.27 hole 0.889: 2(2.817,1.166) 3(1.166,2.817) 4(-1.166,2.817) 5(-2.817,1.166) 6(-2.817,-1.166) 7(-1.166,-2.817) 8(1.166,-2.817) 9(2.817,-1.166)
HOLE_4-1_8MM_BOT14
  round 4.089 hole 4.089 unplated: (0,0)
  round 1.27 hole 0.889: 2(2.817,1.166) 3(1.166,2.817) 4(-1.166,2.817) 5(-2.817,1.166) 6(-2.817,-1.166) 7(-1.166,-2.817) 8(1.166,-2.817) 9(2.817,-1.166)
HOLE_STEEL-INSERT
  round 4.496 hole 1.118: 1(0,0)
L0402
  rect 0.559x0.508 smd: 1(-0.429,0) 2(0.429,0)
L0603
  rect 0.711x0.813 smd: 1(-0.645,0) 2(0.645,0)
L0805
  rect 0.991x1.321 smd: 1(-0.785,0) 2(0.785,0)
L1206
  rect 1.143x1.651 smd: 1(-1.331,0) 2(1.331,0)
L1806
  rect 1.346x1.6 smd: 1(-2.095,0) 2(2.095,0)
LED2_254P460L880W074H
  round 1.321 hole 0.838: A(-1.27,0) C(1.27,0)
LED0603
  rect 0.711x0.813 smd: A(0.645,0) C(-0.645,0)
LED0603_BRIGHT
  rect 0.711x0.813 smd: A(-0.645,0) C(0.645,0)
LQFP48_710L710W160H
  rect 0.279x1.27 smd: 1(-2.751,-4.333) 2(-2.25,-4.333) 3(-1.75,-4.333) 4(-1.25,-4.333) 5(-0.749,-4.333) 6(-0.249,-4.333) 7(0.249,-4.333) 8(0.749,-4.333) 9(1.25,-4.333) 10(1.75,-4.333) 11(2.25,-4.333) 12(2.751,-4.333) 25(2.751,4.333) 26(2.25,4.333) 27(1.75,4.333) 28(1.25,4.333) 29(0.749,4.333) 30(0.249,4.333) 31(-0.249,4.333) 32(-0.749,4.333) 33(-1.25,4.333) 34(-1.75,4.333) 35(-2.25,4.333) 36(-2.751,4.333)
  rect 1.27x0.279 smd: 13(4.333,-2.751) 14(4.333,-2.25) 15(4.333,-1.75) 16(4.333,-1.25) 17(4.333,-0.749) 18(4.333,-0.249) 19(4.333,0.249) 20(4.333,0.749) 21(4.333,1.25) 22(4.333,1.75) 23(4.333,2.25) 24(4.333,2.751) 37(-4.333,2.751) 38(-4.333,2.25) 39(-4.333,1.75) 40(-4.333,1.25) 41(-4.333,0.749) 42(-4.333,0.249) 43(-4.333,-0.249) 44(-4.333,-0.749) 45(-4.333,-1.25) 46(-4.333,-1.75) 47(-4.333,-2.25) 48(-4.333,-2.751)
LQFP64_700L700W160H
  rect 0.178x1.27 smd: 1(-3,-4.257) 2(-2.601,-4.257) 3(-2.2,-4.257) 4(-1.801,-4.257) 5(-1.4,-4.257) 6(-1.001,-4.257) 7(-0.599,-4.257) 8(-0.201,-4.257) 9(0.201,-4.257) 10(0.599,-4.257) 11(1.001,-4.257) 12(1.4,-4.257) 13(1.801,-4.257) 14(2.2,-4.257) 15(2.601,-4.257) 16(3,-4.257) 33(3,4.257) 34(2.601,4.257) 35(2.2,4.257) 36(1.801,4.257) 37(1.4,4.257) 38(1.001,4.257) 39(0.599,4.257) 40(0.201,4.257) 41(-0.201,4.257) 42(-0.599,4.257) 43(-1.001,4.257) 44(-1.4,4.257) 45(-1.801,4.257) 46(-2.2,4.257) 47(-2.601,4.257) 48(-3,4.257)
  rect 1.27x0.178 smd: 17(4.257,-3) 18(4.257,-2.601) 19(4.257,-2.2) 20(4.257,-1.801) 21(4.257,-1.4) 22(4.257,-1.001) 23(4.257,-0.599) 24(4.257,-0.201) 25(4.257,0.201) 26(4.257,0.599) 27(4.257,1.001) 28(4.257,1.4) 29(4.257,1.801) 30(4.257,2.2) 31(4.257,2.601) 32(4.257,3) 49(-4.257,3) 50(-4.257,2.601) 51(-4.257,2.2) 52(-4.257,1.801) 53(-4.257,1.4) 54(-4.257,1.001) 55(-4.257,0.599) 56(-4.257,0.201) 57(-4.257,-0.201) 58(-4.257,-0.599) 59(-4.257,-1.001) 60(-4.257,-1.4) 61(-4.257,-1.801) 62(-4.257,-2.2) 63(-4.257,-2.601) 64(-4.257,-3)
OTHER_SMT213
  round 5.41 hole 1.118: 1(0,0)
QFN10_050P310W100HG
  rect 0.279x1.016 smd: 1(-1.001,-1.6) 2(-0.5,-1.6) 3(0,-1.6) 4(0.5,-1.6) 5(1.001,-1.6) 6(1.001,1.6) 7(0.5,1.6) 8(0,1.6) 9(-0.5,1.6) 10(-1.001,1.6)
  rect 2.54x1.778 smd: G(0,0)
QFN28_500L500W080HG
  rect 0.279x1.016 smd: 1(-1.501,-2.515) 2(-1.001,-2.515) 3(-0.5,-2.515) 4(0,-2.515) 5(0.5,-2.515) 6(1.001,-2.515) 7(1.501,-2.515) 15(1.501,2.515) 16(1.001,2.515) 17(0.5,2.515) 18(0,2.515) 19(-0.5,2.515) 20(-1.001,2.515) 21(-1.501,2.515)
  rect 1.016x0.279 smd: 8(2.515,-1.501) 9(2.515,-1.001) 10(2.515,-0.5) 11(2.515,0) 12(2.515,0.5) 13(2.515,1.001) 14(2.515,1.501) 22(-2.515,1.501) 23(-2.515,1.001) 24(-2.515,0.5) 25(-2.515,0) 26(-2.515,-0.5) 27(-2.515,-1.001) 28(-2.515,-1.501)
  rect 3.607x3.607 smd: G(0,0)
QFN32_510L510W093HG
  rect 0.254x1.016 smd: 1(-1.75,-2.558) 2(-1.25,-2.558) 3(-0.749,-2.558) 4(-0.249,-2.558) 5(0.249,-2.558) 6(0.749,-2.558) 7(1.25,-2.558) 8(1.75,-2.558) 17(1.75,2.558) 18(1.25,2.558) 19(0.749,2.558) 20(0.249,2.558) 21(-0.249,2.558) 22(-0.749,2.558) 23(-1.25,2.558) 24(-1.75,2.558)
  rect 1.016x0.254 smd: 9(2.558,-1.75) 10(2.558,-1.25) 11(2.558,-0.749) 12(2.558,-0.249) 13(2.558,0.249) 14(2.558,0.749) 15(2.558,1.25) 16(2.558,1.75) 25(-2.558,1.75) 26(-2.558,1.25) 27(-2.558,0.749) 28(-2.558,0.249) 29(-2.558,-0.249) 30(-2.558,-0.749) 31(-2.558,-1.25) 32(-2.558,-1.75)
  rect 3.505x3.505 smd: G(0,0)
QFN48_600L600W090HG
  oval 0.178x0.914 smd: 1(-2.2,-2.857) 2(-1.801,-2.857) 3(-1.4,-2.857) 4(-1.001,-2.857) 5(-0.599,-2.857) 6(-0.201,-2.857) 7(0.201,-2.857) 8(0.599,-2.857) 9(1.001,-2.857) 10(1.4,-2.857) 11(1.801,-2.857) 12(2.2,-2.857) 25(2.2,2.857) 26(1.801,2.857) 27(1.4,2.857) 28(1.001,2.857) 29(0.599,2.857) 30(0.201,2.857) 31(-0.201,2.857) 32(-0.599,2.857) 33(-1.001,2.857) 34(-1.4,2.857) 35(-1.801,2.857) 36(-2.2,2.857)
  oval 0.914x0.178 smd: 13(2.857,-2.2) 14(2.857,-1.801) 15(2.857,-1.4) 16(2.857,-1.001) 17(2.857,-0.599) 18(2.857,-0.201) 19(2.857,0.201) 20(2.857,0.599) 21(2.857,1.001) 22(2.857,1.4) 23(2.857,1.801) 24(2.857,2.2) 37(-2.857,2.2) 38(-2.857,1.801) 39(-2.857,1.4) 40(-2.857,1.001) 41(-2.857,0.599) 42(-2.857,0.201) 43(-2.857,-0.201) 44(-2.857,-0.599) 45(-2.857,-1.001) 46(-2.857,-1.4) 47(-2.857,-1.801) 48(-2.857,-2.2)
  rect 4.394x4.394 smd: G(0,0)
QFN48_700L700W100HG
  oval 0.305x1.016 smd: 1(-2.751,-3.51) 2(-2.25,-3.51) 3(-1.75,-3.51) 4(-1.25,-3.51) 5(-0.749,-3.51) 6(-0.249,-3.51) 7(0.249,-3.51) 8(0.749,-3.51) 9(1.25,-3.51) 10(1.75,-3.51) 11(2.25,-3.51) 12(2.751,-3.51) 25(2.751,3.51) 26(2.25,3.51) 27(1.75,3.51) 28(1.25,3.51) 29(0.749,3.51) 30(0.249,3.51) 31(-0.249,3.51) 32(-0.749,3.51) 33(-1.25,3.51) 34(-1.75,3.51) 35(-2.25,3.51) 36(-2.751,3.51)
  oval 1.016x0.305 smd: 13(3.51,-2.751) 14(3.51,-2.25) 15(3.51,-1.75) 16(3.51,-1.25) 17(3.51,-0.749) 18(3.51,-0.249) 19(3.51,0.249) 20(3.51,0.749) 21(3.51,1.25) 22(3.51,1.75) 23(3.51,2.25) 24(3.51,2.751) 37(-3.51,2.751) 38(-3.51,2.25) 39(-3.51,1.75) 40(-3.51,1.25) 41(-3.51,0.749) 42(-3.51,0.249) 43(-3.51,-0.249) 44(-3.51,-0.749) 45(-3.51,-1.25) 46(-3.51,-1.75) 47(-3.51,-2.25) 48(-3.51,-2.751)
  rect 5.232x5.232 smd: G(0,0)
R0402
  rect 0.559x0.508 smd: 1(-0.429,0) 2(0.429,0)
R0603
  rect 0.711x0.813 smd: 1(-0.645,0) 2(0.645,0)
R0805
  rect 0.991x1.321 smd: 1(-0.785,0) 2(0.785,0)
R1206
  rect 1.143x1.651 smd: 1(-1.331,0) 2(1.331,0)
SCON_B2B_40_AUK
  round 0.559 hole 0.559 unplated: (-10.351,-1.9) (10.351,-1.9)
  rect 0.61x1.6 smd: 1(-9.5,-2.799) 2(-8.499,-2.799) 3(-7.501,-2.799) 4(-6.5,-2.799) 5(-5.499,-2.799) 6(-4.501,-2.799) 7(-3.5,-2.799) 8(-2.499,-2.799) 9(-1.501,-2.799) 10(-0.5,-2.799) 11(0.5,-2.799) 12(1.501,-2.799) 13(2.499,-2.799) 14(3.5,-2.799) 15(4.501,-2.799) 16(5.499,-2.799) 17(6.5,-2.799) 18(7.501,-2.799) 19(8.499,-2.799) 20(9.5,-2.799) 21(9.5,2.799) 22(8.499,2.799) 23(7.501,2.799) 24(6.5,2.799) 25(5.499,2.799) 26(4.501,2.799) 27(3.5,2.799) 28(2.499,2.799) 29(1.501,2.799) 30(0.5,2.799) 31(-0.5,2.799) 32(-1.501,2.799) 33(-2.499,2.799) 34(-3.5,2.799) 35(-4.501,2.799) 36(-5.499,2.799) 37(-6.5,2.799) 38(-7.501,2.799) 39(-8.499,2.799) 40(-9.5,2.799)
  rect 0.838x1.803 smd: 41(-10.825,0.401) 42(10.825,0.401)
SCON_HAD-VERTICAL_25P_K25
  rect 0.737x2.794 smd: 1(-7.62,-2.032) 2(-7.62,2.032) 3(-6.35,-2.032) 4(-6.35,2.032) 5(-5.08,-2.032) 6(-5.08,2.032) 7(-3.81,-2.032) 8(-3.81,2.032) 9(-2.54,-2.032) 10(-2.54,2.032) 11(-1.27,-2.032) 12(-1.27,2.032) 13(0,-2.032) 14(0,2.032) 15(1.27,-2.032) 16(1.27,2.032) 17(2.54,-2.032) 18(2.54,2.032) 19(3.81,-2.032) 20(3.81,2.032) 21(5.08,-2.032) 22(5.08,2.032) 23(6.35,-2.032) 24(6.35,2.032) 26(7.62,2.032)
SCON_MINIPCI_52_ACES
  round 1.6 hole 1.6 unplated: (-12.499,0)
  round 1.092 hole 1.092 unplated: (12.499,0)
  rect 0.61x2.007 smd: 1(-11.801,-4.1) 2(-11.4,4.1) 3(-11.001,-4.1) 4(-10.599,4.1) 5(-10.201,-4.1) 6(-9.799,4.1) 7(-9.401,-4.1) 8(-8.999,4.1) 9(-8.6,-4.1) 10(-8.199,4.1) 11(-7.8,-4.1) 12(-7.399,4.1) 13(-7,-4.1) 14(-6.599,4.1) 15(-6.2,-4.1) 16(-5.799,4.1) 17(-2.2,-4.1) 18(-1.801,4.1) 19(-1.4,-4.1) 20(-1.001,4.1) 21(-0.599,-4.1) 22(-0.201,4.1) 23(0.201,-4.1) 24(0.599,4.1) 25(1.001,-4.1) 26(1.4,4.1) 27(1.801,-4.1) 28(2.2,4.1) 29(2.601,-4.1) 30(3,4.1) 31(3.401,-4.1) 32(3.8,4.1) 33(4.201,-4.1) 34(4.6,4.1) 35(5.001,-4.1) 36(5.4,4.1) 37(5.801,-4.1) 38(6.2,4.1) 39(6.601,-4.1) 40(7,4.1) 41(7.402,-4.1) 42(7.8,4.1) 43(8.199,-4.1) 44(8.6,4.1) 45(8.999,-4.1) 46(9.401,4.1) 47(9.799,-4.1) 48(10.201,4.1) 49(10.599,-4.1) 50(11.001,4.1) 51(11.4,-4.1) 52(11.801,4.1)
  rect 2.311x3.2 smd: X1(-14.651,-3.5) X2(14.651,-3.5)
SCON_SKT_MEMARY-CARD_40_TAI
  round 0.991 hole 0.991 unplated: (-14,0) (14,-11.999)
  rect 0.406x1.905 smd: P1(-13.65,12.05) P2(-12.949,12.05) P3(-12.25,12.05) P4(-11.549,12.05) P5(-10.851,12.05) P6(-10.15,12.05) P7(-9.449,12.05) P8(-8.75,12.05) P9(-8.049,12.05) P10(-7.351,12.05) P11(-6.65,12.05) P12(-5.951,12.05) P13(-5.25,12.05) P14(-4.549,12.05) P15(-3.851,12.05) P16(-3.15,12.05) P17(-2.451,12.05) P18(-1.75,12.05) P19(-1.049,12.05) P20(-0.351,12.05) P21(0.351,12.05) P22(1.049,12.05) P23(1.75,12.05) P24(2.451,12.05) P25(3.15,12.05) P26(3.851,12.05) P27(4.549,12.05) P28(5.25,12.05) P29(5.951,12.05) P30(6.65,12.05) P31(7.351,12.05) P32(8.049,12.05) P33(8.75,12.05) P34(9.449,12.05) P35(10.15,12.05) P36(10.851,12.05) P37(11.549,12.05) P38(12.25,12.05) P39(12.949,12.05) P40(13.65,12.05)
  rect 2.159x2.997 smd: P41(-16.175,-24.9) P42(16.175,-24.9)
SCON_SW_4_HUA-JIE
  rect 1.524x1.397 smd: 1(-3.752,1.501) 2(3.752,1.501) 3(-3.752,-1.501) 4(3.752,-1.501)
SCRY2_450W800L150H
  rect 2.032x2.032 smd: 1(-3.515,0) 2(3.515,0)
SCRY2_450W800L150H_TXC
  rect 2.743x2.413 smd: 1(-3.244,0) 2(3.244,0)
SCRY4_140W670L130H
  rect 1.194x0.61 smd: 1(-3.15,-0.45) 2(3.15,-0.45) 3(3.15,0.45) 4(-3.15,0.45)
SEC630D580H
  rect 2.921x0.787 smd: 1(2.283,0) 2(-2.283,0)
SEC630D600H
  rect 2.794x0.787 smd: 1(2.37,0) 2(-2.37,0)
SF1206
  rect 1.143x1.803 smd: 1(-1.331,0) 2(1.331,0)
SKT_BAT2032
  rect 1.702x1.702 hole 1.194: 1(12.078,0)
  round 1.702 hole 1.194: 2(-7.922,0)
SKT_SSO8
  rect 0.457x1.981 smd: 1(-1.905,-3.785) 2(-0.635,-3.785) 3(0.635,-3.785) 4(1.905,-3.785) 5(1.905,3.785) 6(0.635,3.785) 7(-0.635,3.785) 8(-1.905,3.785)
SLT_DDR3-240_LOTES_WHT
  round 2.743 hole 2.438: (0,0) (138.001,0)
  oval 0.991x2.54 hole 0.028 unplated: (57,0.005)
  rect 1.067x1.067 hole 0.66: 1(7.501,-0.95)
  round 1.067 hole 0.66: 2(8.501,-2.85) 3(9.5,-0.95) 4(10.5,-2.85) 5(11.501,-0.95) 6(12.502,-2.85) 7(13.5,-0.95) 8(14.501,-2.85) 9(15.502,-0.95) 10(16.502,-2.85) 11(17.501,-0.95) 12(18.501,-2.85) 13(19.5,-0.95) 14(20.5,-2.85) 15(21.501,-0.95) 16(22.502,-2.85) 17(23.5,-0.95) 18(24.501,-2.85) 19(25.502,-0.95) 20(26.502,-2.85) 21(27.501,-0.95) 22(28.501,-2.85) 23(29.5,-0.95) 24(30.5,-2.85) 25(31.501,-0.95) 26(32.502,-2.85) 27(33.5,-0.95) 28(34.501,-2.85) 29(35.502,-0.95) 30(36.502,-2.85) 31(37.501,-0.95) 32(38.501,-2.85) 33(39.5,-0.95) 34(40.5,-2.85) 35(41.501,-0.95) 36(42.502,-2.85) 37(43.5,-0.95) 38(44.501,-2.85) 39(45.502,-0.95) 40(46.502,-2.85) 41(47.501,-0.95) 42(48.501,-2.85) 43(49.5,-0.95) 44(50.5,-2.85) 45(51.501,-0.95) 46(52.502,-2.85) 47(53.5,-0.95) 48(54.501,-2.85) 49(59.499,-0.95) 50(60.5,-2.85) 51(61.501,-0.95) 52(62.502,-2.85) 53(63.5,-0.95) 54(64.501,-2.85) 55(65.502,-0.95) 56(66.502,-2.85) 57(67.501,-0.95) 58(68.501,-2.85) 59(69.499,-0.95) 60(70.5,-2.85) 61(71.501,-0.95) 62(72.502,-2.85) 63(73.5,-0.95) 64(74.501,-2.85) 65(75.501,-0.95) 66(76.502,-2.85) 67(77.5,-0.95) 68(78.501,-2.85) 69(79.499,-0.95) 70(80.5,-2.85) 71(81.501,-0.95) 72(82.502,-2.85) 73(83.5,-0.95) 74(84.501,-2.85) 75(85.501,-0.95) 76(86.502,-2.85) 77(87.5,-0.95) 78(88.501,-2.85) 79(89.499,-0.95) 80(90.5,-2.85) 81(91.501,-0.95) 82(92.502,-2.85) 83(93.5,-0.95) 84(94.501,-2.85) 85(95.501,-0.95) 86(96.502,-2.85) 87(97.5,-0.95) 88(98.501,-2.85) 89(99.499,-0.95) 90(100.5,-2.85) 91(101.501,-0.95) 92(102.502,-2.85) 93(103.5,-0.95) 94(104.501,-2.85) 95(105.501,-0.95) 96(106.502,-2.85) 97(107.5,-0.95) 98(108.501,-2.85) 99(109.499,-0.95) 100(110.5,-2.85) 101(111.501,-0.95) 102(112.502,-2.85) 103(113.5,-0.95) 104(114.501,-2.85) 105(115.501,-0.95) 106(116.502,-2.85) 107(117.5,-0.95) 108(118.501,-2.85) 109(119.499,-0.95) 110(120.503,-2.85) 111(121.501,-0.95) 112(122.502,-2.85) 113(123.5,-0.95) 114(124.501,-2.85) 115(125.501,-0.95) 116(126.502,-2.85) 117(127.5,-0.95) 118(128.501,-2.85) 119(129.499,-0.95) 120(130.503,-2.85) 121(7.501,2.85) 122(8.501,0.95) 123(9.5,2.85) 124(10.5,0.95) 125(11.501,2.85) 126(12.502,0.95) 127(13.5,2.85) 128(14.501,0.95) 129(15.502,2.85) 130(16.502,0.95) 131(17.501,2.85) 132(18.501,0.95) 133(19.5,2.85) 134(20.5,0.95) 135(21.501,2.85) 136(22.502,0.95) 137(23.5,2.85) 138(24.501,0.95) 139(25.502,2.85) 140(26.502,0.95) 141(27.501,2.85) 142(28.501,0.95) 143(29.5,2.85) 144(30.5,0.95) 145(31.501,2.85) 146(32.502,0.95) 147(33.5,2.85) 148(34.501,0.95) 149(35.502,2.85) 150(36.502,0.95) 151(37.501,2.85) 152(38.501,0.95) 153(39.5,2.85) 154(40.5,0.95) 155(41.501,2.85) 156(42.502,0.95) 157(43.5,2.85) 158(44.501,0.95) 159(45.502,2.85) 160(46.502,0.95) 161(47.501,2.85) 162(48.501,0.95) 163(49.5,2.85) 164(50.5,0.95) 165(51.501,2.85) 166(52.502,0.95) 167(53.5,2.85) 168(54.501,0.95) 169(59.499,2.85) 170(60.5,0.95) 171(61.501,2.85) 172(62.502,0.95) 173(63.5,2.85) 174(64.501,0.95) 175(65.502,2.85) 176(66.502,0.95) 177(67.501,2.85) 178(68.501,0.95) 179(69.499,2.85) 180(70.5,0.95) 181(71.501,2.85) 182(72.502,0.95) 183(73.5,2.85) 184(74.501,0.95) 185(75.501,2.85) 186(76.502,0.95) 187(77.5,2.85) 188(78.501,0.95) 189(79.499,2.85) 190(80.5,0.95) 191(81.501,2.85) 192(82.502,0.95) 193(83.5,2.85) 194(84.501,0.95) 195(85.501,2.85) 196(86.502,0.95) 197(87.5,2.85) 198(88.501,0.95) 199(89.499,2.85) 200(90.5,0.95) 201(91.501,2.85) 202(92.502,0.95) 203(93.5,2.85) 204(94.501,0.95) 205(95.501,2.85) 206(96.502,0.95) 207(97.5,2.85) 208(98.501,0.95) 209(99.499,2.85) 210(100.5,0.95) 211(101.501,2.85) 212(102.502,0.95) 213(103.5,2.85) 214(104.501,0.95) 215(105.501,2.85) 216(106.502,0.95) 217(107.5,2.85) 218(108.501,0.95) 219(109.499,2.85) 220(110.5,0.95) 221(111.501,2.85) 222(112.502,0.95) 223(113.5,2.85) 224(114.501,0.95) 225(115.501,2.85) 226(116.502,0.95) 227(117.5,2.85) 228(118.501,0.95) 229(119.499,2.85) 230(120.503,0.95) 231(121.501,2.85) 232(122.502,0.95) 233(123.5,2.85) 234(124.501,0.95) 235(125.501,2.85) 236(126.502,0.95) 237(127.5,2.85) 238(128.501,0.95) 239(129.499,2.85) 240(130.503,0.95)
SLT_MXM-3_314_ACES_1
  round 1.092 hole 1.092 unplated: (-41.001,0)
  oval 0.991x2.057 hole 0.008 unplated: (1.999,0)
  round 1.6 hole 1.6 unplated: (41.001,0)
  rect 0.279x2.007 smd: 1(-30,-3.749) 2(-29.751,3.5) 3(-29.5,-3.749) 4(-29.251,3.5) 5(-29.002,-3.749) 6(-28.75,3.5) 7(-28.501,-3.749) 8(-28.25,3.5) 9(-28.001,-3.749) 10(-27.75,3.5) 11(-27.501,-3.749) 12(-27.252,3.5) 13(-27,-3.749) 14(-26.751,3.5) 15(-26.5,-3.749) 16(-26.251,3.5) 17(-25.999,-3.749) 18(-25.751,3.5) 19(-25.502,-3.749) 20(-25.25,3.5) 21(-25.001,-3.749) 22(-24.75,3.5) 23(-24.501,-3.749) 24(-24.252,3.5) 25(-24,-3.749) 26(-23.752,3.5) 27(-23.5,-3.749) 28(-23.251,3.5) 29(-23,-3.749) 30(-22.751,3.5) 31(-22.502,-3.749) 32(-22.25,3.5) 33(-22.001,-3.749) 34(-21.75,3.5) 35(-21.501,-3.749) 36(-21.25,3.5) 37(-21.001,-3.749) 38(-20.752,3.5) 39(-20.5,-3.749) 40(-20.251,3.5) 41(-20,-3.749) 42(-19.751,3.5) 43(-19.5,-3.749) 44(-19.251,3.5) 45(-19.002,-3.749) 46(-18.75,3.5) 47(-18.501,-3.749) 48(-18.25,3.5) 49(-18.001,-3.749) 50(-17.75,3.5) 51(-17.501,-3.749) 52(-17.252,3.5) 53(-17,-3.749) 54(-16.751,3.5) 55(-16.5,-3.749) 56(-16.251,3.5) 57(-15.999,-3.749) 58(-15.751,3.5) 59(-15.502,-3.749) 60(-15.25,3.5) 61(-15.001,-3.749) 62(-14.75,3.5) 63(-14.501,-3.749) 64(-14.252,3.5) 65(-14,-3.749) 66(-13.752,3.5) 67(-13.5,-3.749) 68(-13.251,3.5) 69(-13,-3.749) 70(-12.751,3.5) 71(-12.502,-3.749) 72(-12.25,3.5) 73(-12.002,-3.749) 74(-11.75,3.5) 75(-11.501,-3.749) 76(-11.25,3.5) 77(-11.001,-3.749) 78(-10.752,3.5) 79(-10.5,-3.749) 80(-10.251,3.5) 81(-10,-3.749) 82(-9.751,3.5) 83(-9.5,-3.749) 84(-9.251,3.5) 85(-9.002,-3.749) 86(-8.75,3.5) 87(-8.501,-3.749) 88(-8.25,3.5) 89(-8.001,-3.749) 90(-7.75,3.5) 91(-7.501,-3.749) 92(-7.252,3.5) 93(-7,-3.749) 94(-6.751,3.5) 95(-6.5,-3.749) 96(-6.251,3.5) 97(-5.999,-3.749) 98(-5.751,3.5) 99(-5.502,-3.749) 100(-5.25,3.5) 101(-5.001,-3.749) 102(-4.75,3.5) 103(-4.501,-3.749) 104(-4.249,3.5) 105(-4,-3.749) 106(-3.752,3.5) 107(-3.5,-3.749) 108(-3.251,3.5) 109(-3,-3.749) 110(-2.751,3.5) 111(-2.502,-3.749) 112(-2.25,3.5) 113(-2.002,-3.749) 114(-1.75,3.5) 115(-1.501,-3.749) 116(-1.25,3.5) 117(-1.001,-3.749) 118(-0.752,3.5) 119(-0.5,-3.749) 120(-0.251,3.5) 121(0,-3.749) 122(0.249,3.5) 123(0.5,-3.749) 124(0.749,3.5) 125(0.998,-3.749) 133(3,-3.749) 134(3.249,3.5) 135(3.5,-3.749) 136(3.749,3.5) 137(4,-3.749) 138(4.249,3.5) 139(4.498,-3.749) 140(4.75,3.5) 141(4.999,-3.749) 142(5.25,3.5) 143(5.499,-3.749) 144(5.751,3.5) 145(5.999,-3.749) 146(6.248,3.5) 147(6.5,-3.749) 148(6.749,3.5) 149(7,-3.749) 150(7.249,3.5) 151(7.498,-3.749) 152(7.75,3.5) 153(7.998,-3.749) 154(8.25,3.5) 155(8.499,-3.749) 156(8.75,3.5) 157(8.999,-3.749) 158(9.248,3.5) 159(9.5,-3.749) 160(9.749,3.5) 161(10,-3.749) 162(10.249,3.5) 163(10.5,-3.749) 164(10.749,3.5) 165(10.998,-3.749) 166(11.25,3.5) 167(11.499,-3.749) 168(11.75,3.5) 169(11.999,-3.749) 170(12.25,3.5) 171(12.499,-3.749) 172(12.748,3.5) 173(13,-3.749) 174(13.249,3.5) 175(13.5,-3.749) 176(13.749,3.5) 177(14,-3.749) 178(14.249,3.5) 179(14.498,-3.749) 180(14.75,3.5) 181(14.999,-3.749) 182(15.25,3.5) 183(15.499,-3.749) 184(15.751,3.5) 185(15.999,-3.749) 186(16.248,3.5) 187(16.5,-3.749) 188(16.749,3.5) 189(17,-3.749) 190(17.249,3.5) 191(17.498,-3.749) 192(17.75,3.5) 193(17.998,-3.749) 194(18.25,3.5) 195(18.499,-3.749) 196(18.75,3.5) 197(18.999,-3.749) 198(19.248,3.5) 199(19.5,-3.749) 200(19.748,3.5) 201(20,-3.749) 202(20.249,3.5) 203(20.5,-3.749) 204(20.749,3.5) 205(20.998,-3.749) 206(21.25,3.5) 207(21.499,-3.749) 208(21.75,3.5) 209(21.999,-3.749) 210(22.25,3.5) 211(22.499,-3.749) 212(22.748,3.5) 213(23,-3.749) 214(23.249,3.5) 215(23.5,-3.749) 216(23.749,3.5) 217(24,-3.749) 218(24.249,3.5) 219(24.498,-3.749) 220(24.75,3.5) 221(24.999,-3.749) 222(25.25,3.5) 223(25.499,-3.749) 224(25.751,3.5) 225(25.999,-3.749) 226(26.248,3.5) 227(26.5,-3.749) 228(26.749,3.5) 229(27,-3.749) 230(27.249,3.5) 231(27.501,-3.749) 232(27.75,3.5) 233(27.998,-3.749) 234(28.25,3.5) 235(28.499,-3.749) 236(28.75,3.5) 237(28.999,-3.749) 238(29.248,3.5) 239(29.5,-3.749) 240(29.748,3.5) 241(30,-3.749) 242(30.249,3.5) 243(30.5,-3.749) 244(30.749,3.5) 245(30.998,-3.749) 246(31.25,3.5) 247(31.499,-3.749) 248(31.75,3.5) 249(31.999,-3.749) 250(32.25,3.5) 251(32.499,-3.749) 252(32.748,3.5) 253(33,-3.749) 254(33.249,3.5) 255(33.5,-3.749) 256(33.749,3.5) 257(34,-3.749) 258(34.249,3.5) 259(34.498,-3.749) 260(34.75,3.5) 261(34.999,-3.749) 262(35.25,3.5) 263(35.499,-3.749) 264(35.751,3.5) 265(35.999,-3.749) 266(36.248,3.5) 267(36.5,-3.749) 268(36.749,3.5) 269(37,-3.749) 270(37.249,3.5) 271(37.501,-3.749) 272(37.749,3.5) 273(37.998,-3.749) 274(38.25,3.5) 275(38.499,-3.749) 276(38.75,3.5) 277(38.999,-3.749) 278(39.248,3.5) 279(39.5,-3.749) 280(39.748,3.5) 281(40,-3.749)
  rect 0.356x2.007 smd: EA1(-35.499,-3.749) EA2(-35.999,-3.749) EA3(-36.5,-3.749) EA4(-37,-3.749) EA5(-37.501,-3.749) EA6(-37.998,-3.749) EA7(-38.499,-3.749) EA8(-38.999,-3.749) EA9(-39.5,-3.749) EA10(-40,-3.749) EB1(-35.25,3.5) EB2(-35.751,3.5) EB3(-36.248,3.5) EB4(-36.749,3.5) EB5(-37.249,3.5) EB6(-37.749,3.5) EB7(-38.25,3.5) EB8(-38.75,3.5) EB9(-39.248,3.5) EB10(-39.748,3.5) EC1(-30.5,-3.749) EC2(-30.998,-3.749) EC3(-31.499,-3.749) EC4(-31.999,-3.749) EC5(-32.499,-3.749) EC6(-33,-3.749) EC7(-33.5,-3.749) EC8(-34,-3.749) EC9(-34.498,-3.749) EC10(-34.999,-3.749) ED1(-30.249,3.5) ED2(-30.749,3.5) ED3(-31.25,3.5) ED4(-31.75,3.5) ED5(-32.25,3.5) ED6(-32.748,3.5) ED7(-33.249,3.5) ED8(-33.749,3.5) ED9(-34.249,3.5) ED10(-34.75,3.5)
  rect 2.997x5.258 smd: X1(-44,0.749) X2(43.998,0.749)
  round 5.994 hole 2.997: XH1(-37.501,-65.999) XH2(37.501,-65.999)
SMA
  rect 2.032x1.524 smd: A(2.134,0) C(-2.134,0)
SO8_127P400W175H
  rect 0.508x1.575 smd: 1(-1.905,-2.756) 2(-0.635,-2.756) 3(0.635,-2.756) 4(1.905,-2.756) 5(1.905,2.756) 6(0.635,2.756) 7(-0.635,2.756) 8(-1.905,2.756)
SO8_127P540W216H
  rect 0.508x1.397 smd: 1(-1.905,-3.978) 2(-0.635,-3.978) 3(0.635,-3.978) 4(1.905,-3.978) 5(1.905,3.978) 6(0.635,3.978) 7(-0.635,3.978) 8(-1.905,3.978)
SOD323
  rect 1.016x0.61 smd: A(1.308,0) C(-1.308,0)
SON10_050P315W100H
  rect 0.279x0.864 smd: 1(-1.001,-1.481) 2(-0.5,-1.481) 3(0,-1.481) 4(0.5,-1.481) 5(1.001,-1.481) 6(1.001,1.481) 7(0.5,1.481) 8(0,1.481) 9(-0.5,1.481) 10(-1.001,1.481)
  custom 0.413x0.413 smd: G(0,0)
SOP8_127P394W168HG
  rect 0.508x1.397 smd: 1(-1.905,-2.728) 2(-0.635,-2.728) 3(0.635,-2.728) 4(1.905,-2.728) 5(1.905,2.728) 6(0.635,2.728) 7(-0.635,2.728) 8(-1.905,2.728)
  rect 2.286x2.286 smd: G(0,0)
SOT23_3P
  rect 0.508x1.118 smd: 1(-0.95,-1.151) 2(0.95,-1.151) 3(0,1.151)
SOT23_3P_AKA
  rect 0.508x1.016 smd: A1(-0.95,-1.181) A2(0.95,-1.181) K(0,1.181)
SOT23_3P_BCE
  rect 0.508x1.016 smd: B(-0.95,-1.181) C(0,1.181) E(0.95,-1.181)
SOT23_3P_GDS
  rect 0.508x1.016 smd: D(0,1.181) G(-0.95,-1.181) S(0.95,-1.181)
SOT23_5P
  rect 0.508x1.016 smd: 1(-0.95,-1.311) 2(0,-1.311) 3(0.95,-1.311) 4(0.95,1.311) 5(-0.95,1.311)
SOT23_6P
  rect 0.508x1.143 smd: 1(-0.94,-1.359) 2(0,-1.359) 3(0.94,-1.359) 4(0.94,1.359) 5(0,1.359) 6(-0.94,1.359)
SOT143_4P
  rect 0.889x1.016 smd: 1(-0.749,-1.308)
  rect 0.508x1.016 smd: 2(0.95,-1.308) 3(0.95,1.308) 4(-0.95,1.308)
SOT363_5P
  rect 0.305x0.965 smd: 1(-0.65,-1.095) 2(0,-1.095) 3(0.65,-1.095) 4(0.65,1.095) 5(-0.65,1.095)
SOT363_6P
  rect 0.305x1.067 smd: 1(-0.65,-1.168) 2(0,-1.168) 3(0.65,-1.168) 4(0.65,1.168) 5(0,1.168) 6(-0.65,1.168)
SSOP28_065P538W199H
  rect 0.381x1.473 smd: 1(-4.224,-3.736) 2(-3.574,-3.736) 3(-2.926,-3.736) 4(-2.276,-3.736) 5(-1.626,-3.736) 6(-0.975,-3.736) 7(-0.325,-3.736) 8(0.325,-3.736) 9(0.975,-3.736) 10(1.626,-3.736) 11(2.276,-3.736) 12(2.926,-3.736) 13(3.574,-3.736) 14(4.224,-3.736) 15(4.224,3.736) 16(3.574,3.736) 17(2.926,3.736) 18(2.276,3.736) 19(1.626,3.736) 20(0.975,3.736) 21(0.325,3.736) 22(-0.325,3.736) 23(-0.975,3.736) 24(-1.626,3.736) 25(-2.276,3.736) 26(-2.926,3.736) 27(-3.574,3.736) 28(-4.224,3.736)
SWAF4_100P290W600L
  rect 0.61x1.549 smd: 1(1.501,2.527) 2(0.5,2.527) 3(-0.5,2.527) 4(-1.501,2.527)
  rect 1.194x1.803 smd: MH1(2.799,0) MH2(-2.799,0)
SWAF6_100P290W800L
  rect 0.61x1.549 smd: 1(2.499,2.53) 2(1.501,2.53) 3(0.5,2.53) 4(-0.5,2.53) 5(-1.501,2.53) 6(-2.499,2.53)
  rect 1.194x1.803 smd: MH1(3.8,0) MH2(-3.8,0)
SWAF8_100P290W1000L_AUK
  rect 0.61x1.524 smd: 1(3.5,2.525) 2(2.499,2.525) 3(1.501,2.525) 4(0.5,2.525) 5(-0.5,2.525) 6(-1.501,2.525) 7(-2.499,2.525) 8(-3.5,2.525)
  rect 1.194x1.778 smd: G1(-4.801,0) G2(4.801,0)
SWAF14_125P370W2225L
  rect 0.787x1.6 smd: 1(-8.125,2.901) 2(-6.876,2.901) 3(-5.626,2.901) 4(-4.374,2.901) 5(-3.124,2.901) 6(-1.875,2.901) 7(-0.625,2.901) 8(0.625,2.901) 9(1.875,2.901) 10(3.124,2.901) 11(4.374,2.901) 12(5.626,2.901) 13(6.876,2.901) 14(8.125,2.901)
  rect 2.108x2.997 smd: H1(-10.676,0) H2(10.676,0)
SWAF30_100P580W1730L
  round 0.559 hole 0.559 unplated: (-7.851,-1.9) (7.851,-1.9)
  rect 0.61x1.6 smd: 1(-7,-2.799) 2(-5.999,-2.799) 3(-5.001,-2.799) 4(-4,-2.799) 5(-3,-2.799) 6(-1.999,-2.799) 7(-1.001,-2.799) 8(0,-2.799) 9(1.001,-2.799) 10(1.999,-2.799) 11(3,-2.799) 12(4,-2.799) 13(5.001,-2.799) 14(5.999,-2.799) 15(7,-2.799) 16(7,2.799) 17(5.999,2.799) 18(5.001,2.799) 19(4,2.799) 20(3,2.799) 21(1.999,2.799) 22(1.001,2.799) 23(0,2.799) 24(-1.001,2.799) 25(-1.999,2.799) 26(-3,2.799) 27(-4,2.799) 28(-5.001,2.799) 29(-5.999,2.799) 30(-7,2.799)
  rect 0.838x1.803 smd: 31(-8.326,0.401) 32(8.326,0.401)
TC352819B
  rect 1.397x2.286 smd: 1(-1.458,0) 2(1.458,0)
TC734318D
  rect 2.413x2.54 smd: 1(-3.111,0) 2(3.111,0)
TC734328D
  rect 2.413x2.54 smd: 1(-3.111,0) 2(3.111,0)
TC734331D
  rect 2.413x2.54 smd: 1(-3.111,0) 2(3.111,0)
TP20
  round 0.508 smd: 1(0,0)
TP30
  round 0.762 smd: 1(0,0)
TQFN24_410L410W080HG
  rect 0.305x1.016 smd: 1(-1.25,-2.057) 2(-0.749,-2.057) 3(-0.249,-2.057) 4(0.249,-2.057) 5(0.749,-2.057) 6(1.25,-2.057) 13(1.25,2.057) 14(0.749,2.057) 15(0.249,2.057) 16(-0.249,2.057) 17(-0.749,2.057) 18(-1.25,2.057)
  rect 1.016x0.305 smd: 7(2.057,-1.25) 8(2.057,-0.749) 9(2.057,-0.249) 10(2.057,0.249) 11(2.057,0.749) 12(2.057,1.25) 19(-2.057,1.25) 20(-2.057,0.749) 21(-2.057,0.249) 22(-2.057,-0.249) 23(-2.057,-0.749) 24(-2.057,-1.25)
  rect 2.642x2.642 smd: G(0,0)
TSSOP20_065P450W110HG
  rect 0.305x1.27 smd: 1(-2.926,-3.058) 2(-2.276,-3.058) 3(-1.626,-3.058) 4(-0.975,-3.058) 5(-0.325,-3.058) 6(0.325,-3.058) 7(0.975,-3.058) 8(1.626,-3.058) 9(2.276,-3.058) 10(2.926,-3.058) 11(2.926,3.058) 12(2.276,3.058) 13(1.626,3.058) 14(0.975,3.058) 15(0.325,3.058) 16(-0.325,3.058) 17(-0.975,3.058) 18(-1.626,3.058) 19(-2.276,3.058) 20(-2.926,3.058)
  rect 4.293x3.099 smd: G(0,0)
TSSOP56_050P620W120H
  rect 0.279x1.524 smd: 1(-6.749,-4.061) 2(-6.251,-4.061) 3(-5.751,-4.061) 4(-5.25,-4.061) 5(-4.75,-4.061) 6(-4.249,-4.061) 7(-3.749,-4.061) 8(-3.251,-4.061) 9(-2.751,-4.061) 10(-2.25,-4.061) 11(-1.75,-4.061) 12(-1.25,-4.061) 13(-0.749,-4.061) 14(-0.249,-4.061) 15(0.249,-4.061) 16(0.749,-4.061) 17(1.25,-4.061) 18(1.75,-4.061) 19(2.25,-4.061) 20(2.751,-4.061) 21(3.251,-4.061) 22(3.749,-4.061) 23(4.249,-4.061) 24(4.75,-4.061) 25(5.25,-4.061) 26(5.751,-4.061) 27(6.251,-4.061) 28(6.749,-4.061) 29(6.749,4.061) 30(6.251,4.061) 31(5.751,4.061) 32(5.25,4.061) 33(4.75,4.061) 34(4.249,4.061) 35(3.749,4.061) 36(3.251,4.061) 37(2.751,4.061) 38(2.25,4.061) 39(1.75,4.061) 40(1.25,4.061) 41(0.749,4.061) 42(0.249,4.061) 43(-0.249,4.061) 44(-0.749,4.061) 45(-1.25,4.061) 46(-1.75,4.061) 47(-2.25,4.061) 48(-2.751,4.061) 49(-3.251,4.061) 50(-3.749,4.061) 51(-4.249,4.061) 52(-4.75,4.061) 53(-5.25,4.061) 54(-5.751,4.061) 55(-6.251,4.061) 56(-6.749,4.061)
unnamed
  round 1.016 smd: 1(0,0)

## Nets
AVDD: C372.1 L45.2 U3.E12(AVDD2(NC)) U3.F12(AVDD1(NC))
AVDD33_LAN: C287.1 C289.1 C292.1 C296.1 C306.1 C505.1 L68.2 R490.1 R510.1 R521.1 R707.2 R721.1 R724.1 R729.1 R730.1 R731.1 R733.1 R737.1 R739.1 U13.5 U14.5 U24.12(AVDD33_1) U24.27(DVDD33_1) U24.39(DVDD33_2) U24.42(AVDD33_2) U24.47(AVDD33_3) U24.48(AVDD33_4)
AVDD33_REG: C512.1 C513.1 R733.2 U24.34(VDDREG_2) U24.35(VDDREG_1)
AVDDDI: C368.1 R557.2 U3.F14(AVDDDI(NC))
AVDDQ: C362.1 L44.2 U3.H15(AVDDQ(NC))
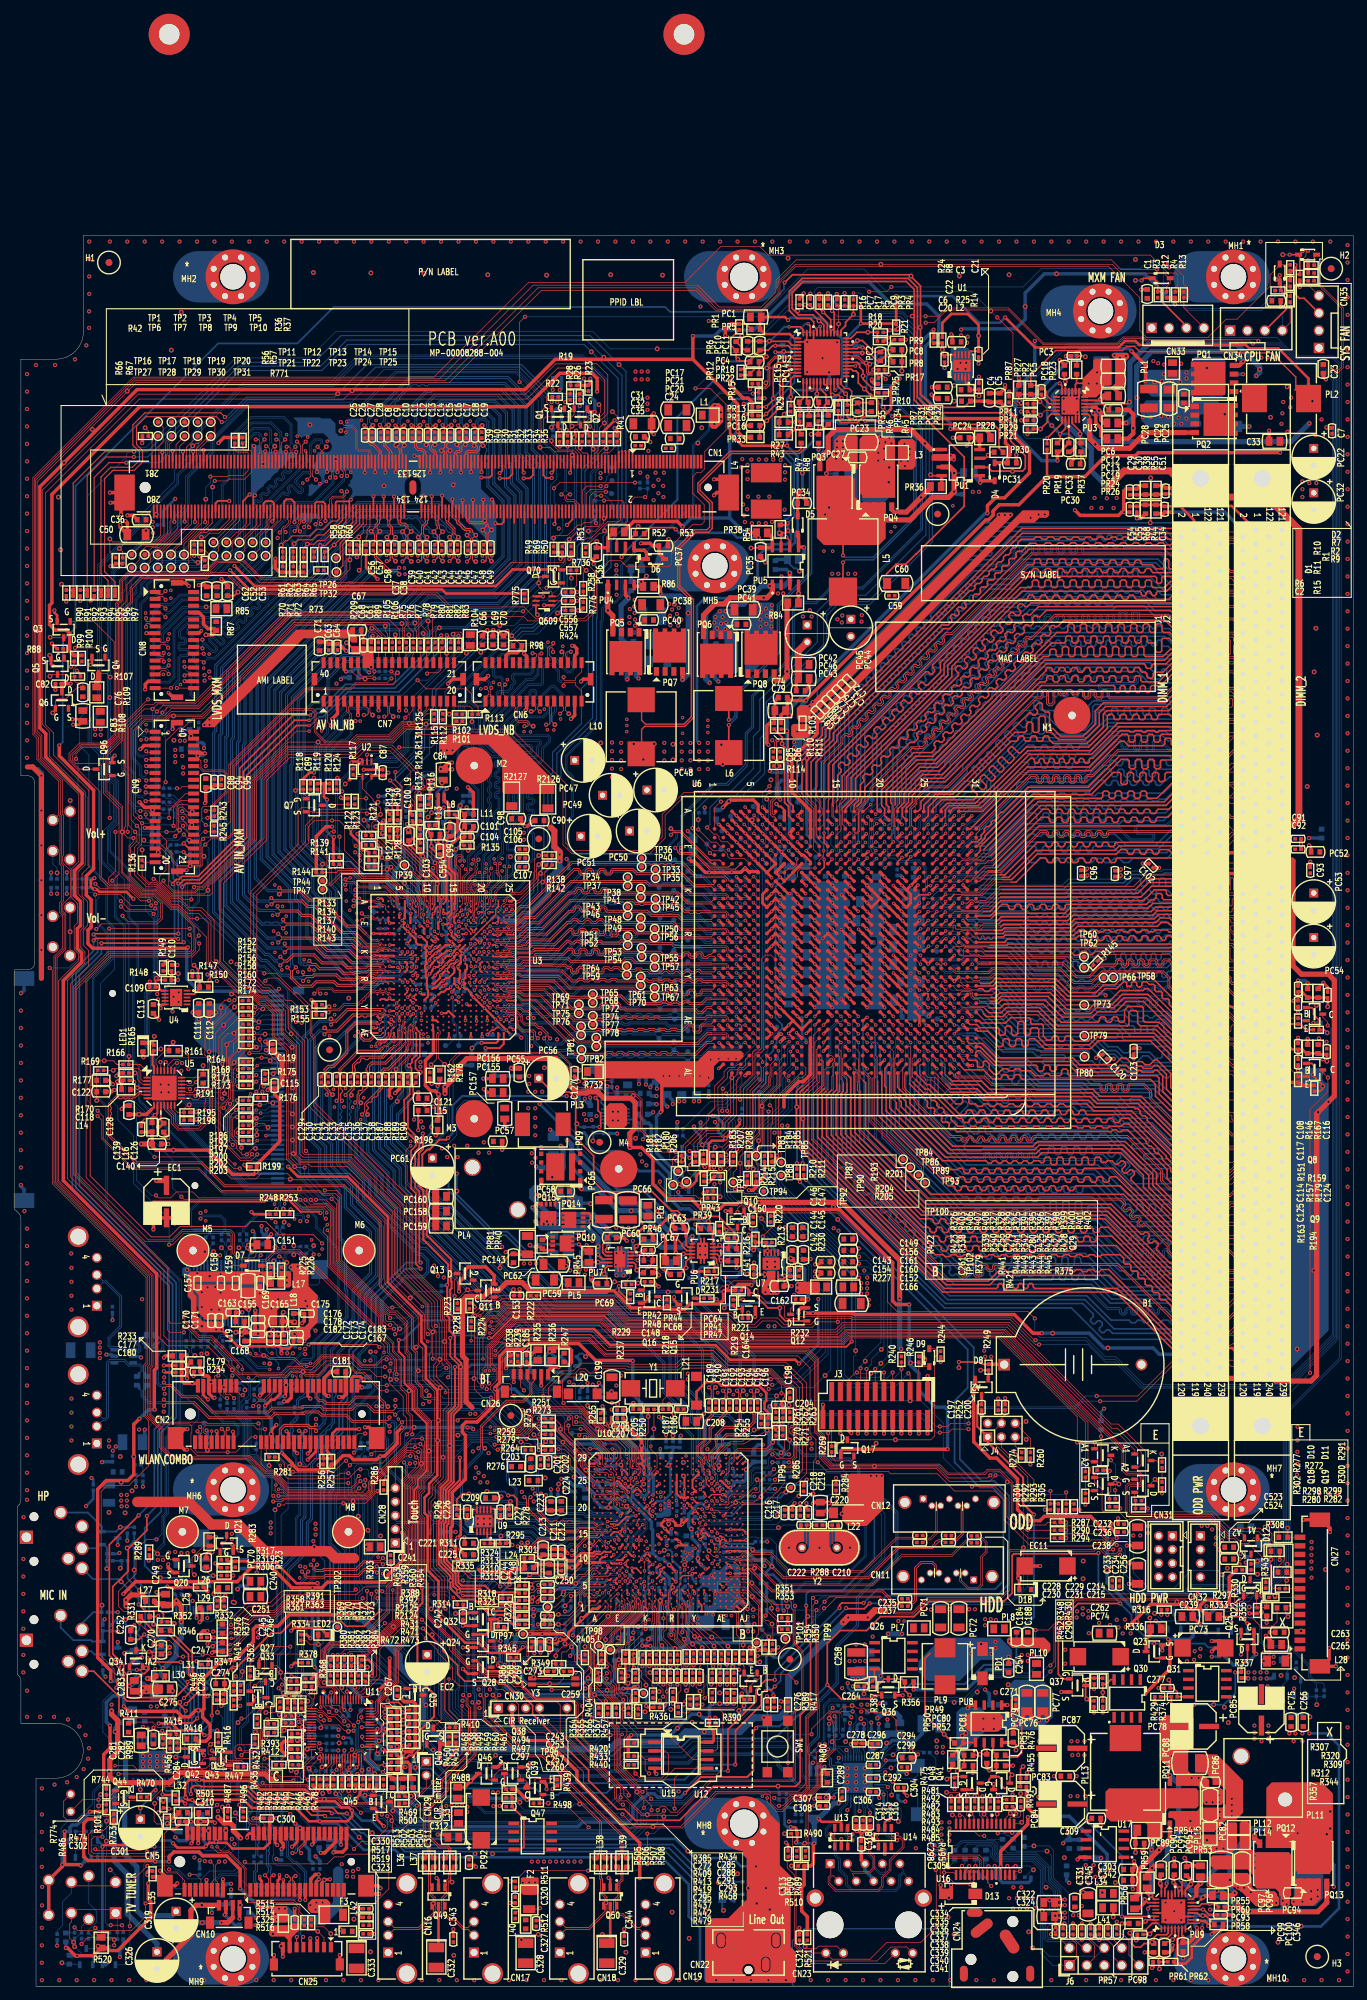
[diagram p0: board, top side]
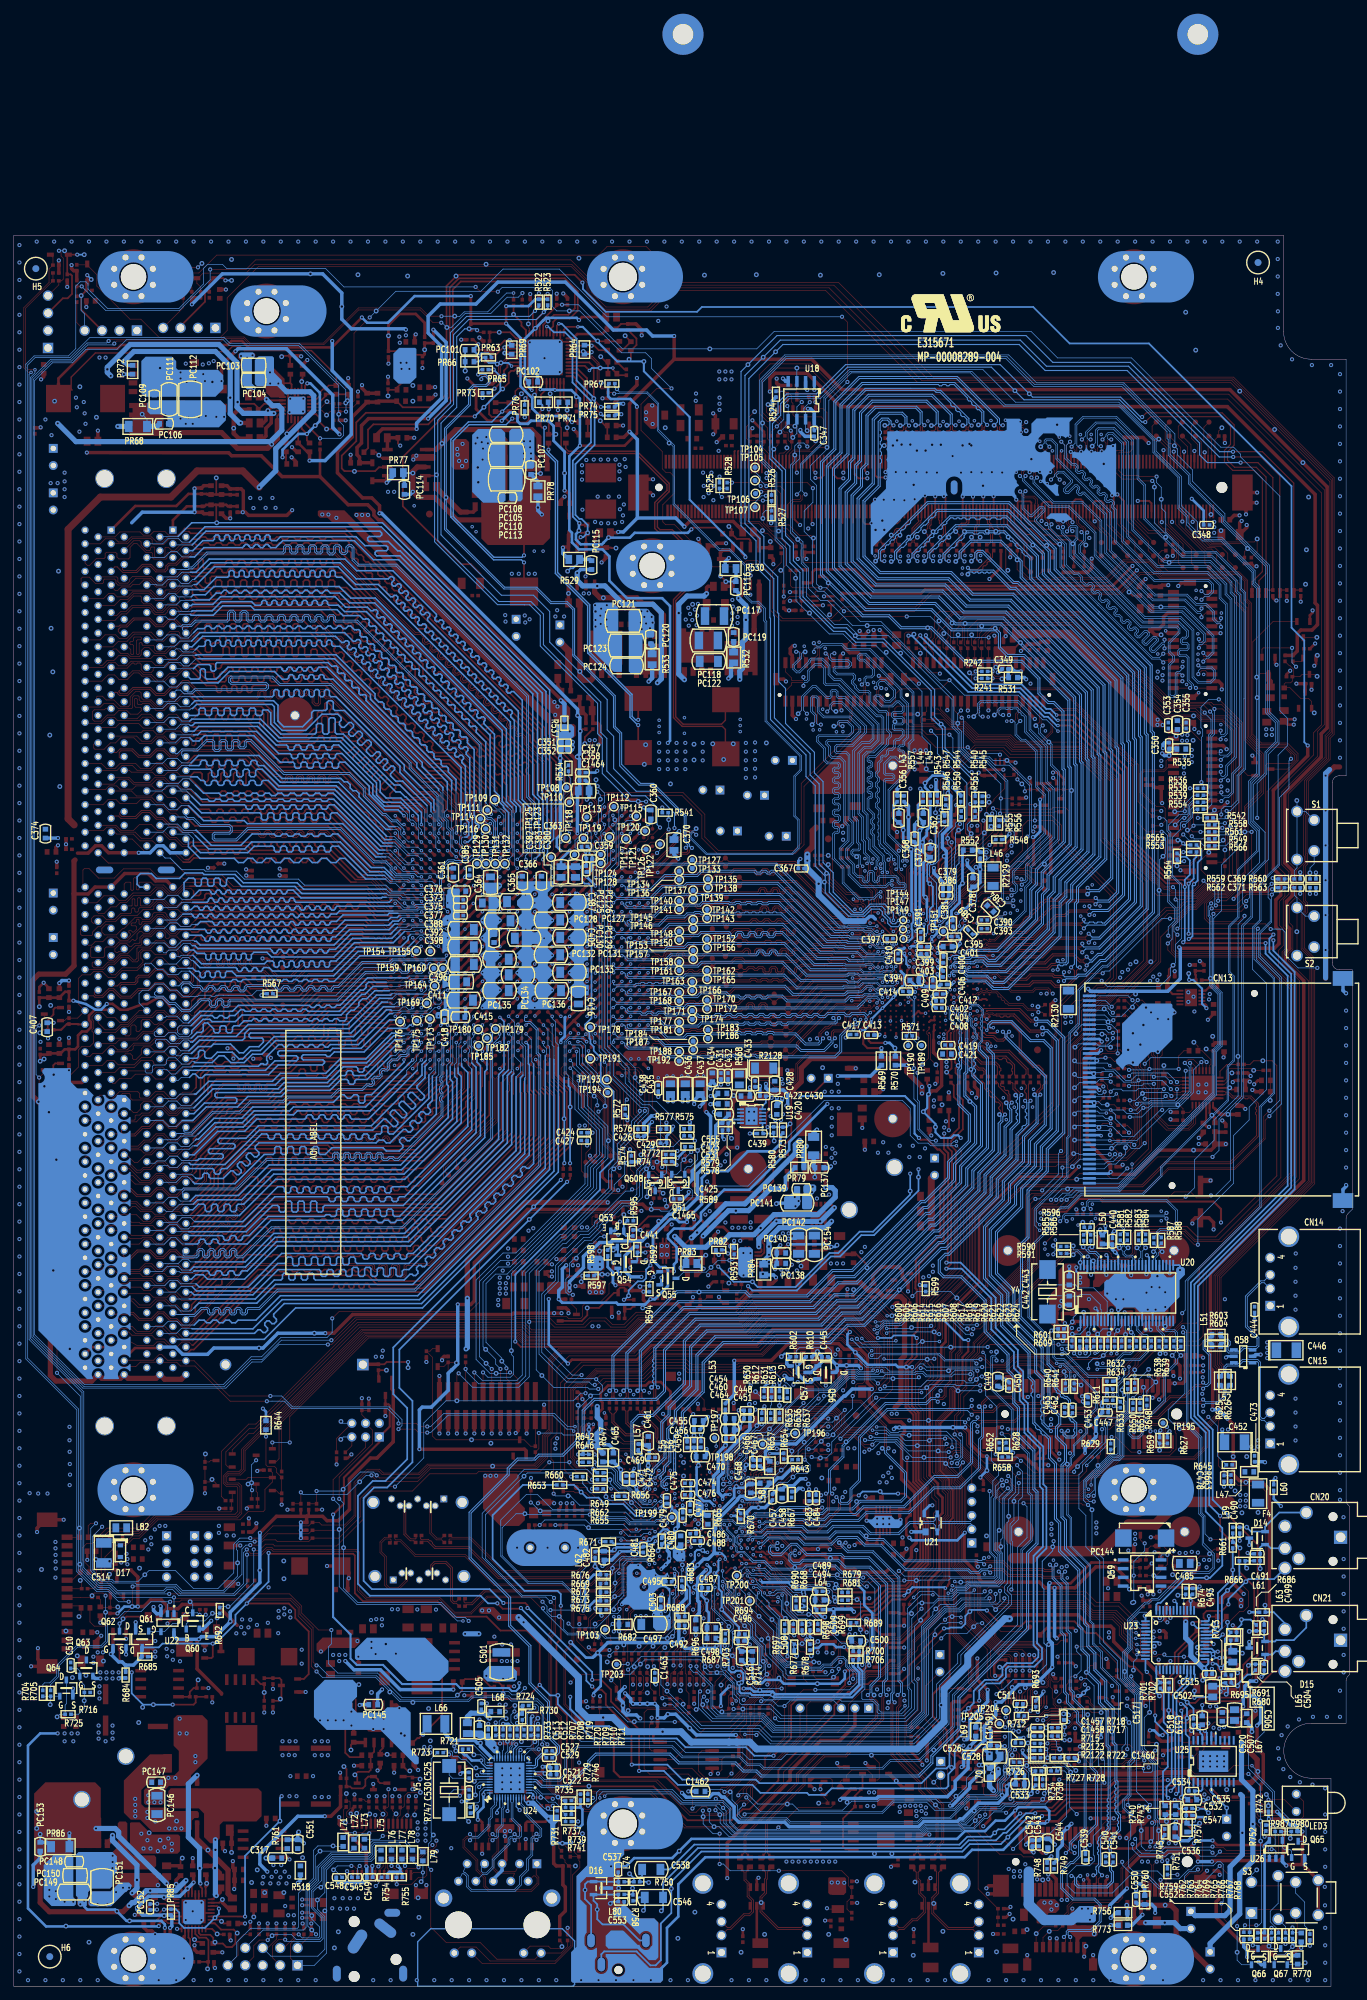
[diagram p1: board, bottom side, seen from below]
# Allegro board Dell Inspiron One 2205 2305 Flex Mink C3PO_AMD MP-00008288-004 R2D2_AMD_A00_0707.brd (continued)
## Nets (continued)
GND: B1.2(NEG) C1.2 C2.2 C3.2 C4.2 C5.2 C6.2 C7.2 C20.2 C21.2 C22.2 C23.2 C24.1 C29.2 C30.2 C31.2 C32.2 C33.2 C35.1 C36.2 C50.2 C52.2 C53.2 C54.2 C55.2 C59.2 C60.2 C61.2 C62.2 C63.2 C64.2 C66.2 C67.2 C68.2 C69.2 C70.2 C71.2 C72.2 C73.2 C74.2 C75.2 C77.2 C78.2 C79.2 C80.2 C81.2 C82.2 C83.2 C84.2 C87.1 C88.2 C89.1 C90.2 C91.2 C92.2 C93.2 C94.2 C95.2 C96.2 C97.2 C98.2 C99.2 C100.2 C101.2 C102.2 C103.2 C104.2 C105.2 C106.2 C107.2 C108.2 C109.2 C110.2 C111.2 C112.2 C113.2 C114.2 C115.2 C117.2 C118.2 C119.2 C120.2 C121.2 C122.2 C123.2 C125.2 C126.2 C127.2 C128.2 C139.2 C140.2 C141.2 C142.2 C143.2 C144.2 C145.2 C146.2 C147.2 C148.2 C149.2 C150.2 C151.2 C152.2 C153.2 C154.2 C155.2 C156.2 C157.2 C158.2 C159.2 C160.2 C161.2 C162.2 C163.2 C164.2 C165.2 C166.2 C167.2 C168.2 C169.2 C170.2 C171.2 C172.2 C173.2 C174.2 C175.2 C176.2 C177.2 C178.2 C179.2 C180.2 C181.2 C182.2 C183.2 C184.2 C185.2 C186.2 C187.1 C188.2 C197.2 C198.2 C199.2 C200.2 C201.2 C202.2 C203.2 C204.2 C205.1 C206.2 C207.2 C208.2 C209.2 C210.1 C211.2 C212.2 C213.2 C216.2 C217.2 C218.2 C219.2 C220.2 C221.2 C222.1 C223.2 C224.2 C225.2 C226.2 C227.2 C232.2 C233.2 C234.2 C236.2 C238.2 C239.2 C240.2 C241.2 C242.2 C243.2 C244.2 C245.2 C246.2 C247.1 C248.2 C250.2 C251.2 C253.2 C254.2 C255.1 C256.2 C257.2 C258.2 C259.1 C260.2 C261.1 C262.2 C263.2 C264.2 C265.2 C266.2 C268.2 C269.2 C271.2 C272.2 C273.1 C276.2 C277.2 C278.2 C279.2 C280.2 C284.2 C286.2 C287.2 C289.2 C290.2 C292.2 C294.2 C296.2 C297.2 C298.1 C299.2 C300.2 C302.2 C303.2 C304.2 C306.2 C307.2 C308.2 C309.2 C310.2 C311.2 C312.2 C313.2 C314.2 C315.2 C316.2 C318.1 C320.2 C321.2 C322.2 C323.2 C324.2 C325.2 C327.2 C328.2 C329.2 C330.2 C331.2 C332.2 C333.2 C334.2 C335.2 C336.2 C337.2 C338.2 C339.2 C340.2 C341.2 C342.2 C343.2 C344.2 C345.2 C346.2 C347.2 C348.1 C349.2 C350.2 C351.2 C352.2 C353.2 C354.2 C355.2 C356.2 C357.2 C358.2 C359.2 C361.2 C362.2 C363.2 C364.2 C365.2 C366.2 C367.2 C368.2 C369.2 C370.2 C371.2 C372.2 C373.2 C374.2 C375.2 C377.2 C378.2 C379.2 C380.2 C381.2 C382.2 C383.2 C384.2 C385.2 C386.2 C387.2 C388.2 C389.2 C390.2 C391.2 C392.2 C393.2 C394.2 C395.2 C396.2 C397.2 C398.2 C399.2 C400.2 C401.2 C402.2 C403.2 C404.2 C405.2 C406.2 C407.2 C408.2 C409.2 C410.2 C411.2 C412.2 C413.2 C414.2 C416.2 C417.2 C418.2 C419.2 C420.2 C421.2 C422.2 C423.2 C424.2 C425.2 C426.2 C427.2 C428.2 C429.2 C430.2 C431.2 C432.2 C433.2 C434.2 C435.2 C436.2 C437.2 C438.2 C439.2 C440.2 C441.2 C442.2 C443.2 C444.2 C446.2 C447.2 C448.2 C449.2 C450.2 C451.2 C452.2 C453.2 C454.2 C455.2 C456.2 C457.2 C458.2 C459.2 C460.2 C461.2 C464.2 C465.2 C466.2 C467.2 C468.2 C469.2 C470.2 C471.2 C472.2 C473.2 C474.2 C475.2 C476.2 C477.2 C478.2 C479.2 C480.2 C481.2 C482.2 C483.2 C484.2 C485.2 C486.2 C487.2 C488.2 C489.2 C492.2 C494.2 C495.2 C496.2 C497.2 C498.2 C500.2 C501.2 C503.2 C505.2 C508.2 C509.2 C511.1 C512.2 C513.2 C514.2 C516.2 C517.1 C521.2 C522.2 C523.2 C524.2 C525.1 C530.1 C531.2 C533.2 C536.2 C539.2 C542.2 C543.2 C544.2 C547.1 C549.2 C550.2 C552.2 C554.2 C555.2 C556.2 C557.2 C1457.2 C1458.2 C1459.2 C1460.2 C1462.2 C1463.2 C1464.2 C1465.2 CN1.11(GND#11) CN1.13(GND#13) CN1.15(GND#15) CN1.17(GND#17) CN1.36(GND#36) CN1.37(GND#37) CN1.46(GND#46) CN1.47(GND#47) CN1.52(GND#52) CN1.53(GND#53) CN1.58(GND#58) CN1.59(GND#59) CN1.64(GND#64) CN1.65(GND#65) CN1.70(GND#70) CN1.71(GND#71) CN1.76(GND#76) CN1.77(GND#77) CN1.82(GND#82) CN1.83(GND#83) CN1.88(GND#88) CN1.89(GND#89) CN1.94(GND#94) CN1.95(GND#95) CN1.100(GND#100) CN1.101(GND#101) CN1.106(GND#106) CN1.107(GND#107) CN1.112(GND#112) CN1.113(GND#113) CN1.118(GND#118) CN1.119(GND#119) CN1.124(GND#124) CN1.125(GND#125) CN1.133(GND#133) CN1.134(GND#134) CN1.139(GND#139) CN1.140(GND#140) CN1.145(GND#145) CN1.146(GND#146) CN1.151(GND#151) CN1.152(GND#152) CN1.157(GND#157) CN1.166(GND#166) CN1.173(GND#173) CN1.174(GND#174) CN1.179(GND#179) CN1.180(GND#180) CN1.185(GND#185) CN1.186(GND#186) CN1.191(GND#191) CN1.192(GND#192) CN1.197(GND#197) CN1.198(GND#198) CN1.203(GND#203) CN1.204(GND#204) CN1.209(GND#209) CN1.210(GND#210) CN1.215(GND#215) CN1.216(GND#216) CN1.221(GND#221) CN1.222(GND#222) CN1.228(GND#228) CN1.244(GND#244) CN1.250(GND#250) CN1.251(GND#251) CN1.256(GND#256) CN1.257(GND#257) CN1.262(GND#262) CN1.263(GND#263) CN1.268(GND#268) CN1.269(GND#269) CN1.275(GND#275) CN1.EC1(GND#EC1) CN1.EC2(GND#EC2) CN1.EC3(GND#EC3) CN1.EC4(GND#EC4) CN1.EC5(GND#EC5) CN1.EC6(GND#EC6) CN1.EC7(GND#EC7) CN1.EC8(GND#EC8) CN1.EC9(GND#EC9) CN1.EC10(GND#EC10) CN1.ED1(GND#ED1) CN1.ED2(GND#ED2) CN1.ED3(GND#ED3) CN1.ED4(GND#ED4) CN1.ED5(GND#ED5) CN1.ED6(GND#ED6) CN1.ED7(GND#ED7) CN1.ED8(GND#ED8) CN1.ED9(GND#ED9) CN1.ED10(GND#ED10) CN1.X1 CN1.X2 CN2.4(GND_4) CN2.9(GND_9) CN2.15(GND_15) CN2.18(GND_18) CN2.21(GND_21) CN2.26(GND_26) CN2.27(GND_27) CN2.29(GND_29) CN2.34(GND_34) CN2.35(GND_35) CN2.37(RESERVED_37) CN2.40(GND_40) CN2.43(RESERVED_43) CN2.50(GND_50) CN2.X1 CN2.X2 CN5.4(GND_4) CN5.9(GND_9) CN5.15(GND_15) CN5.18(GND_18) CN5.21(GND_21) CN5.26(GND_26) CN5.27(GND_27) CN5.29(GND_29) CN5.34(GND_34) CN5.35(GND_35) CN5.37(RESERVED_37) CN5.40(GND_40) CN5.43(RESERVED_43) CN5.50(GND_50) CN5.X1 CN5.X2 CN6.7 CN6.14 CN6.17 CN6.24 CN6.31(GND1) CN6.32(GND2) CN7.3 CN7.6 CN7.9 CN7.12 CN7.15 CN7.42(GND2) CN8.7 CN8.14 CN8.17 CN8.24 CN8.31(GND1) CN8.32(GND2) CN9.3 CN9.6 CN9.9 CN9.12 CN9.15 CN9.41(GND1) CN9.42(GND2) CN11.1(G1) CN11.4(G2) CN11.7(G3) CN11.8(X1) CN11.9(X2) CN12.1(G1) CN12.4(G2) CN12.7(G3) CN12.8(X1) CN12.9(X2) CN13.P11(GND_1) CN13.P31(GND_2) CN13.P41(GND_3) CN13.P42(GND_4) CN14.4(GND) CN14.H1(GND3) CN14.H2(GND4) CN15.4(GND) CN15.H1(GND3) CN15.H2(GND4) CN16.4(GND) CN16.H1(GND3) CN16.H2(GND4) CN17.4(GND) CN17.H1(GND3) CN17.H2(GND4) CN18.4(GND) CN18.H1(GND3) CN18.H2(GND4) CN19.4(GND) CN19.H1(GND3) CN19.H2(GND4) CN23.G1 CN23.G2 CN24.2 CN24.MH1 CN24.MH2 CN24.MH3 CN25.3 CN25.4 CN25.8 CN25.G1(GND1) CN25.G2(GND2) CN26.2 CN27.10 CN27.11 CN27.12 CN27.13 CN27.H1 CN27.H2 CN28.4 CN30.1 CN31.1 CN31.3 CN31.5 CN31.7 CN32.3 CN32.4 CN33.1(GND) CN34.1(GND) CN35.1(GND) D13.A D17.A D18.A EC1.2 EC11.2 J1.2(VSS58) J1.5(VSS57) J1.8(VSS56) J1.11(VSS55) J1.14(VSS54) J1.17(VSS53) J1.20(VSS52) J1.23(VSS51) J1.26(VSS50) J1.29(VSS49) J1.32(VSS48) J1.35(VSS47) J1.38(VSS46) J1.41(VSS45) J1.44(VSS44) J1.47(VSS43) J1.80(VSS42) J1.83(VSS41) J1.86(VSS40) J1.89(VSS39) J1.92(VSS38) J1.95(VSS37) J1.98(VSS36) J1.101(VSS35) J1.104(VSS34) J1.107(VSS33) J1.110(VSS32) J1.113(VSS31) J1.116(VSS30) J1.117(SA0) J1.119(SA2) J1.121(VSS29) J1.124(VSS28) J1.127(VSS27) J1.130(VSS26) J1.133(VSS25) J1.136(VSS24) J1.139(VSS23) J1.142(VSS22) J1.145(VSS21) J1.148(VSS20) J1.151(VSS19) J1.154(VSS18) J1.157(VSS17) J1.160(VSS16) J1.163(VSS15) J1.166(VSS14) J1.199(VSS13) J1.202(VSS12) J1.205(VSS11) J1.208(VSS10) J1.211(VSS9) J1.214(VSS8) J1.217(VSS7) J1.220(VSS6) J1.223(VSS5) J1.226(VSS4) J1.229(VSS3) J1.232(VSS2) J1.235(VSS1) J1.237(SA1) J1.239(VSS0) J2.2(VSS58) J2.5(VSS57) J2.8(VSS56) J2.11(VSS55) J2.14(VSS54) J2.17(VSS53) J2.20(VSS52) J2.23(VSS51) J2.26(VSS50) J2.29(VSS49) J2.32(VSS48) J2.35(VSS47) J2.38(VSS46) J2.41(VSS45) J2.44(VSS44) J2.47(VSS43) J2.80(VSS42) J2.83(VSS41) J2.86(VSS40) J2.89(VSS39) J2.92(VSS38) J2.95(VSS37) J2.98(VSS36) J2.101(VSS35) J2.104(VSS34) J2.107(VSS33) J2.110(VSS32) J2.113(VSS31) J2.116(VSS30) J2.117(SA0) J2.119(SA2) J2.121(VSS29) J2.124(VSS28) J2.127(VSS27) J2.130(VSS26) J2.133(VSS25) J2.136(VSS24) J2.139(VSS23) J2.142(VSS22) J2.145(VSS21) J2.148(VSS20) J2.151(VSS19) J2.154(VSS18) J2.157(VSS17) J2.160(VSS16) J2.163(VSS15) J2.166(VSS14) J2.199(VSS13) J2.202(VSS12) J2.205(VSS11) J2.208(VSS10) J2.211(VSS9) J2.214(VSS8) J2.217(VSS7) J2.220(VSS6) J2.223(VSS5) J2.226(VSS4) J2.229(VSS3) J2.232(VSS2) J2.235(VSS1) J2.239(VSS0) J3.1 J3.2(14) J3.4(15) J3.6(16) J3.8(17) J3.10(18) J3.12(19) J3.14(20) J3.16(21) J3.18(22) J3.20(23) J3.22(24) J3.26 J6.5 L25.2 L31.2 L32.2 L35.2 L60.2 L69.1 LED2.C M1.1 M2.1 M3.1 M4.1 M5.1 M6.1 M7.1 M8.1 MH1.2 MH1.3 MH1.4 MH1.5 MH1.6 MH1.7 MH1.8 MH1.9 MH2.2 MH2.3 MH2.4 MH2.5 MH2.6 MH2.7 MH2.8 MH2.9 MH3.2 MH3.3 MH3.4 MH3.5 MH3.6 MH3.7 MH3.8 MH3.9 MH4.2 MH4.3 MH4.4 MH4.5 MH4.6 MH4.7 MH4.8 MH4.9 MH5.2 MH5.3 MH5.4 MH5.5 MH5.6 MH5.7 MH5.8 MH5.9 MH6.2 MH6.3 MH6.4 MH6.5 MH6.6 MH6.7 MH6.8 MH6.9 MH7.2 MH7.3 MH7.4 MH7.5 MH7.6 MH7.7 MH7.8 MH7.9 MH8.4 MH8.5 MH8.6 MH8.7 MH9.2 MH9.3 MH9.4 MH9.5 MH9.6 MH9.7 MH9.8 MH9.9 MH10.2 MH10.3 MH10.4 MH10.5 MH10.6 MH10.7 MH10.8 MH10.9 PC1.2 PC3.1 PC6.2 PC7.1 PC9.1 PC12.2 PC13.2 PC16.2 PC17.2 PC18.1 PC20.2 PC21.2 PC22.2 PC23.2 PC24.1 PC25.2 PC27.2 PC28.2 PC29.2 PC30.2 PC31.2 PC32.2 PC33.2 PC34.2 PC35.1 PC36.1 PC37.2 PC38.2 PC39.2 PC40.2 PC41.2 PC42.2 PC43.2 PC44.2 PC45.2 PC46.2 PC47.2 PC48.2 PC49.2 PC50.2 PC51.2 PC52.2 PC53.2 PC54.2 PC55.2 PC56.2 PC57.2 PC58.2 PC59.2 PC60.1 PC61.2 PC62.2 PC63.1 PC65.2 PC66.2 PC70.2 PC71.2 PC72.2 PC73.2 PC74.2 PC75.2 PC76.2 PC77.2 PC78.2 PC79.1 PC81.2 PC82.2 PC83.2 PC84.2 PC85.2 PC86.2 PC87.2 PC88.2 PC89.2 PC91.2 PC92.2 PC93.2 PC94.2 PC96.2 PC97.2 PC98.2 PC99.2 PC100.2 PC102.2 PC103.2 PC104.2 PC105.2 PC106.2 PC107.2 PC108.2 PC109.2 PC110.2 PC111.2 PC112.2 PC113.2 PC117.2 PC118.2 PC119.2 PC120.2 PC121.2 PC122.2 PC123.2 PC124.2 PC125.2 PC126.2 PC127.2 PC128.2 PC129.2 PC130.2 PC131.2 PC132.2 PC133.2 PC134.2 PC135.2 PC136.2 PC137.2 PC138.2 PC139.2 PC140.2 PC141.2 PC142.2 PC143.2 PC144.2 PC146.2 PC147.2 PC148.2 PC149.2 PC150.2 PC151.2 PC152.2 PC153.2 PC154.2 PC155.2 PC156.2 PC157.2 PC158.2 PC159.2 PC160.2 PD1.A PQ2.S1(1) PQ2.S2(2) PQ2.S3(3) PQ3.S1(1) PQ3.S2(2) PQ3.S3(3) PQ5.S1(1) PQ5.S2(2) PQ5.S3(3) PQ6.S1(1) PQ6.S2(2) PQ6.S3(3) PQ9.S1(7) PQ9.S2(6) PQ9.S3(5) PQ11.S1(7) PQ11.S2(6) PQ11.S3(5) PQ13.S1(1) PQ13.S2(2) PQ13.S3(3) PQ14.S1(1) PQ14.S2(2) PQ14.S3(3) PQ15.S1(1) PQ15.S2(2) PQ15.S3(3) PR15.2 PR25.2 PR27.1 PR29.2 PR39.2 PR43.2 PR46.2 PR47.2 PR48.2 PR50.1 PR52.2 PR57.2 PR58.2 PR61.1 PR73.2 PR74.2 PR75.2 PR76.2 PR82.2 PR87.2 PU1.6(GND) PU2.2(GND) PU2.45(VDD_G4) PU2.47(VDD_G2) PU2.G(PAD_GND) PU3.1(VTTGND) PU3.3(GND) PU3.4(MODE) PU3.17(NC) PU3.18(PGND) PU3.G(PAD) PU4.6(GND) PU5.6(GND) PU6.G PU7.G PU8.4(GND) PU8.G PU9.8(NC) PU9.11(FB1) PU9.21(GND) PU9.22(PGND) PU9.29(SKIP#) PU9.G Q3.S Q4.S Q5.S Q10.E Q11.E Q12.S Q13.S Q14.E Q15.S Q16.E Q20.S Q21.S Q23.S Q24.S Q25.S Q27.E Q28.S Q32.E Q33.E Q36.S Q37.S Q38.S Q39.E Q40.S Q41.S Q42.S Q43.S Q45.E Q46.S Q48.S Q49.2 Q50.2 Q53.E Q54.S Q55.S Q57.S Q58.2 Q60.E Q61.S Q62.S Q64.S Q65.S Q66.S Q96.S Q609.1(S1) Q609.4(S2) R5.2 R14.2 R17.1 R20.1 R22.2 R35.1 R38.2 R41.2 R43.2 R56.2 R59.2 R66.2 R67.2 R68.2 R70.2 R71.2 R72.2 R88.2 R90.2 R92.2 R94.2 R103.2 R107.2 R110.1 R116.2 R118.1 R129.2 R130.2 R135.2 R144.1 R146.2 R147.2 R153.2 R155.2 R157.2 R162.1 R170.1 R181.1 R185.1 R188.2 R195.2 R196.1 R199.2 R206.2 R208.2 R214.2 R216.2 R248.2 R253.2 R254.1 R259.1 R260.2 R262.2 R264.1 R270.2 R274.2 R283.2 R295.2 R304.2 R305.2 R307.2 R316.1 R319.2 R325.1 R335.2 R340.1 R341.1 R342.1 R347.2 R350.2 R351.2 R357.2 R391.2 R394.2 R403.2 R406.2 R407.2 R408.2 R417.2 R425.2 R426.2 R427.2 R428.2 R429.2 R441.2 R446.2 R450.1 R452.2 R455.2 R476.2 R481.1 R484.1 R497.2 R500.2 R511.2 R517.2 R518.2 R541.2 R543.2 R544.2 R545.2 R546.1 R555.2 R560.2 R563.2 R578.2 R605.1 R609.2 R627.2 R630.2 R631.2 R634.2 R644.2 R654.2 R663.2 R664.1 R669.2 R670.2 R672.2 R673.2 R675.2 R685.2 R690.2 R693.2 R694.1 R696.2 R708.2 R710.2 R719.1 R720.1 R741.1 R747.2 R757.1 R760.2 R768.2 R980.2 R1017.2 S3.M1 S3.M2 U1.G U2.3(G) U3.A2(VSSAPCIE1) U3.A25(VSSAHT1) U3.AA4(VSSAPCIE32) U3.AA11(VDD_MEM2(NC)) U3.AA14(VSS26) U3.AB1(VSSAPCIE34) U3.AB2(VSSAPCIE40) U3.AB5(VSSAPCIE33) U3.AB7(VSSAPCIE35) U3.AB10(VDD_MEM5(NC)) U3.AB11(VSS28) U3.AB15(VSS29) U3.AB17(VSS30) U3.AB19(VSS31) U3.AB21(VSS33) U3.AC3(VSSAPCIE36) U3.AC4(VSSAPCIE37) U3.AC10(VDD_MEM6(NC)) U3.AC12(VSS25) U3.AD10(VDD_MEM4(NC)) U3.AD23(IOPLLVSS(NC)) U3.AD25(VSSAHT27) U3.AE1(VSSAPCIE38) U3.AE4(VSSAPCIE39) U3.AE10(VDD_MEM1(NC)) U3.AE14(VSS1) U3.AE18(MEM_VREF(NC)) U3.AE20(VSS32) U3.B1(VSSAPCIE2) U3.B12(PLLVSS(NC)) U3.B13(VSSLTP18(NC)) U3.C14(VSSLT1(VSS)) U3.C16(VSSLT3(VSS)) U3.C18(VSSLT4(VSS)) U3.C20(VSSLT5(VSS)) U3.C22(VSSLT7(VSS)) U3.D3(VSSAPCIE3) U3.D5(VSSAPCIE4) U3.D11(VSS2) U3.D15(VSSLT2(VSS)) U3.D23(VSSAHT2) U3.E4(VSSAPCIE5) U3.E14(VSS4) U3.E15(VSS5) U3.E20(VSSLT6(VSS)) U3.E22(VSSAHT3) U3.F18(GREEN#(NC)) U3.F19(BLUE#(NC)) U3.G1(VSSAPCIE6) U3.G2(VSSAPCIE7) U3.G4(VSSAPCIE8) U3.G8(VSS3) U3.G15(AVSSDI(NC)) U3.G17(RED#(NC)) U3.G22(VSSAHT4) U3.G24(VSSAHT5) U3.G25(VSSAHT6) U3.H7(VSSAPCIE9) U3.H14(AVSSQ(NC)) U3.H19(VSSAHT7) U3.H20(VSSAHT20) U3.J4(VSSAPCIE10) U3.J12(VSS7) U3.J15(VSS6) U3.J22(VSSAHT8) U3.K11(VSS34) U3.K14(VSS8) U3.L1(VSSAPCIE12) U3.L2(VSSAPCIE13) U3.L4(VSSAPCIE14) U3.L7(VSSAPCIE15) U3.L12(VSS11) U3.L15(VSS10) U3.L17(VSSAHT9) U3.L22(VSSAHT10) U3.L24(VSSAHT11) U3.L25(VSSAHT12) U3.M6(VSSAPCIE16) U3.M11(VSS9) U3.M14(VSS12) U3.M20(VSSAHT13) U3.N4(VSSAPCIE17) U3.N13(VSS13) U3.N22(VSSAHT14) U3.P6(VSSAPCIE18) U3.P12(VSS14) U3.P15(VSS15) U3.P20(VSSAHT15) U3.R1(VSSAPCIE19) U3.R2(VSSAPCIE20) U3.R4(VSSAPCIE21) U3.R7(VSSAPCIE11) U3.R11(VSS16) U3.R14(VSS17) U3.R19(VSSAHT16) U3.R22(VSSAHT17) U3.R24(VSSAHT18) U3.R25(VSSAHT19) U3.T12(VSS18) U3.U4(VSSAPCIE23) U3.U11(VSS20) U3.U14(VSS19) U3.U15(VSS21) U3.U22(VSSAHT21) U3.V6(VSSAPCIE25) U3.V7(VSSAPCIE22) U3.V8(VSSAPCIE24) U3.V12(VSS22) U3.V19(VSSAHT22) U3.W1(VSSAPCIE26) U3.W2(VSSAPCIE27) U3.W4(VSSAPCIE28) U3.W7(VSSAPCIE29) U3.W8(VSSAPCIE30) U3.W11(VSS23) U3.W15(VSS24) U3.W22(VSSAHT23) U3.W24(VSSAHT24) U3.W25(VSSAHT25) U3.Y6(VSSAPCIE31) U3.Y11(VDD_MEM3(NC)) U3.Y18(VSS27) U3.Y21(VSSAHT26) U4.G U5.7(VD33P) U5.G(GND) U6.A3(VSS_1) U6.A7(VSS_2) U6.A9(VSS_3) U6.A11(VSS_4) U6.AA4(VSS_167) U6.AA5(VSS_168) U6.AA7(VSS_169) U6.AA9(VSS_170) U6.AA11(VSS_171) U6.AA13(VSS_172) U6.AA15(VSS_173) U6.AA17(VSS_174) U6.AA19(VSS_175) U6.AA21(VSS_176) U6.AA23(VSS_177) U6.AB2(VSS_178) U6.AB3(VSS_179) U6.AB8(VSS_180) U6.AB10(VSS_181) U6.AB12(VSS_182) U6.AB14(VSS_183) U6.AB16(VSS_184) U6.AB18(VSS_185) U6.AB20(VSS_186) U6.AB22(VSS_187) U6.AC7(VSS_188) U6.AC9(VSS_189) U6.AC11(VSS_190) U6.AC13(VSS_191) U6.AC15(VSS_192) U6.AC17(VSS_193) U6.AC19(VSS_194) U6.AC21(VSS_195) U6.AC23(VSS_196) U6.AD8(VSS_197) U6.AD10(VSS_198) U6.AD12(VSS_199) U6.AD14(VSS_200) U6.AD16(VSS_201) U6.AD20(VSS_202) U6.AD22(VSS_203) U6.AD24(VSS_204) U6.AE4(VSS_205) U6.AE5(VSS_206) U6.AE7(NP/VSS2) U6.AE11(VSS_207) U6.AF2(VSS_208) U6.AF3(VSS_209) U6.AF8(VSS_210) U6.AF10(VSS_211) U6.AF12(VSS_212) U6.AF14(VSS_213) U6.AF16(VSS_214) U6.AF18(VSS_215) U6.AF20(VSS_216) U6.AF22(VSS_217) U6.AF24(VSS_218) U6.AF26(VSS_219) U6.AF28(VSS_220) U6.AG10(VSS_221) U6.AG11(VSS_222) U6.AH14(VSS_223) U6.AH16(VSS_224) U6.AH18(VSS_225) U6.AH20(VSS_226) U6.AH22(VSS_227) U6.AH24(VSS_228) U6.AH26(VSS_229) U6.AH28(VSS_230) U6.AH30(VSS_231) U6.AJ7(TEST13) U6.AK2(VSS_232) U6.AK14(VSS_233) U6.AK16(VSS_234) U6.AK18(VSS_235) U6.AK20(VSS_236) U6.AK22(VSS_237) U6.AK24(VSS_238) U6.AK26(VSS_239) U6.AK28(VSS_240) U6.AK30(VSS_241) U6.AL5(VSS_242) U6.B4(VSS_5) U6.B9(VSS_6) U6.B11(VSS_7) U6.B14(VSS_8) U6.B16(VSS_9) U6.B18(VSS_10) U6.B20(VSS_11) U6.B22(VSS_12) U6.B24(VSS_13) U6.B26(VSS_14) U6.B28(VSS_15) U6.B30(VSS_16) U6.C3(VSS_17) U6.D14(VSS_18) U6.D16(VSS_19) U6.D18(VSS_20) U6.D20(VSS_21) U6.D22(VSS_22) U6.D24(VSS_23) U6.D26(VSS_24) U6.D28(VSS_25) U6.D30(VSS_26) U6.E11(VSS_27) U6.F4(VSS_28) U6.F6(TEST9) U6.F14(VSS_29) U6.F16(VSS_30) U6.F18(VSS_31) U6.F20(VSS_32) U6.F22(VSS_33) U6.F24(VSS_34) U6.F26(VSS_35) U6.F28(VSS_36) U6.F30(VSS_37) U6.G9(VSS_38) U6.G11(VSS_39) U6.H8(VSS_40) U6.H10(VSS_41) U6.H12(VSS_42) U6.H14(VSS_43) U6.H16(VSS_44) U6.H18(VSS_45) U6.H20(NP/VSS1) U6.H24(VSS_46) U6.H26(VSS_47) U6.H28(VSS_48) U6.H30(VSS_49) U6.J4(VSS_50) U6.J5(VSS_51) U6.J7(VSS_52) U6.J9(VSS_53) U6.J11(VSS_54) U6.J13(VSS_55) U6.J15(VSS_56) U6.J17(VSS_57) U6.J19(VSS_58) U6.J21(VSS_59) U6.J23(VSS_60) U6.K2(VSS_61) U6.K3(VSS_62) U6.K8(VSS_63) U6.K10(VSS_64) U6.K12(VSS_65) U6.K14(VSS_66) U6.K16(VSS_67) U6.K18(VSS_68) U6.K20(VSS_69) U6.K22(VSS_70) U6.K24(VSS_71) U6.K26(VSS_72) U6.K28(VSS_73) U6.K30(VSS_74) U6.L7(VSS_75) U6.L9(VSS_76) U6.L11(VSS_77) U6.L13(VSS_78) U6.L15(VSS_79) U6.L17(VSS_80) U6.L19(VSS_81) U6.L21(VSS_82) U6.L23(VSS_83) U6.M8(VSS_84) U6.M10(VSS_85) U6.M12(VSS_86) U6.M14(VSS_87) U6.M16(VSS_88) U6.M18(VSS_89) U6.M20(VSS_90) U6.M22(VSS_91) U6.N4(VSS_92) U6.N5(VSS_93) U6.N7(VSS_94) U6.N9(VSS_95) U6.N11(VSS_96) U6.N13(VSS_97) U6.N15(VSS_98) U6.N17(VSS_99) U6.N19(VSS_100) U6.N21(VSS_101) U6.N23(VSS_102) U6.P2(VSS_103) U6.P3(VSS_104) U6.P8(VSS_105) U6.P10(VSS_106) U6.P12(VSS_107) U6.P14(VSS_108) U6.P16(VSS_109) U6.P18(VSS_110) U6.P20(VSS_111) U6.P22(VSS_112) U6.R7(VSS_113) U6.R9(VSS_114) U6.R11(VSS_115) U6.R13(VSS_116) U6.R15(VSS_117) U6.R17(VSS_118) U6.R19(VSS_119) U6.R21(VSS_120) U6.R23(VSS_121) U6.T8(VSS_122) U6.T10(VSS_123) U6.T12(VSS_124) U6.T14(VSS_125) U6.T16(VSS_126) U6.T18(VSS_127) U6.T20(VSS_128) U6.T22(VSS_129) U6.U4(VSS_130) U6.U5(VSS_131) U6.U7(VSS_132) U6.U9(VSS_133) U6.U11(VSS_134) U6.U13(VSS_135) U6.U15(VSS_136) U6.U17(VSS_137) U6.U19(VSS_138) U6.U21(VSS_139) U6.U23(VSS_140) U6.V2(VSS_141) U6.V3(VSS_142) U6.V10(VSS_143) U6.V12(VSS_144) U6.V14(VSS_145) U6.V16(VSS_146) U6.V18(VSS_147) U6.V20(VSS_148) U6.V22(VSS_149) U6.W7(VSS_150) U6.W9(VSS_151) U6.W11(VSS_152) U6.W13(VSS_153) U6.W15(VSS_154) U6.W17(VSS_155) U6.W19(VSS_156) U6.W21(VSS_157) U6.W23(VSS_158) U6.Y8(VSS_159) U6.Y10(VSS_160) U6.Y12(VSS_161) U6.Y14(VSS_162) U6.Y16(VSS_163) U6.Y18(VSS_164) U6.Y20(VSS_165) U6.Y22(VSS_166) U7.G U9.G U10.A2(VSS_3) U10.A9(VSSIO_USB_1) U10.A28(VSS_2) U10.AA11(VSS_38) U10.AA12(VSS_39) U10.AA21(VSSIO_PCIECLK_16) U10.AA23(VSSIO_PCIECLK_17) U10.AA26(VSSIO_PCIECLK_20) U10.AB7(VSS_26) U10.AB16(VSSIO_SATA_3) U10.AB23(VSSIO_PCIECLK_18) U10.AC9(VSS_27) U10.AC14(VSSIO_SATA_4) U10.AC26(VSSIO_PCIECLK_21) U10.AD4(VSS_25) U10.AD6(VSS_24) U10.AD23(VSSIO_PCIECLK_19) U10.AE12(VSSIO_SATA_5) U10.AE14(VSSIO_SATA_6) U10.AE26(VSSIO_PCIECLK_25) U10.AF9(VSSIO_SATA_7) U10.AF11(VSSIO_SATA_8) U10.AF13(VSSIO_SATA_9) U10.AF16(VSSIO_SATA_10) U10.AF25(VSS_45) U10.AG8(VSSIO_SATA_11) U10.AH7(VSSIO_SATA_12) U10.AH11(VSSIO_SATA_13) U10.AH13(VSSIO_SATA_14) U10.AH16(VSSIO_SATA_15) U10.AH29(VSS_47) U10.AJ2(VSS_1) U10.AJ7(VSSIO_SATA_16) U10.AJ11(VSSIO_SATA_17) U10.AJ13(VSSIO_SATA_18) U10.AJ16(VSSIO_SATA_19) U10.AJ28(VSS_31) U10.B9(VSSIO_USB_4) U10.B10(VSSIO_USB_2) U10.B29(VSS_32) U10.C7(TEMP_COMM) U10.C9(VSSIO_USB_14) U10.D8(VSSAN_HWM) U10.D9(VSSIO_USB_17) U10.D10(VSSIO_USB_5) U10.D12(VSSIO_USB_6) U10.D14(VSSIO_USB_7) U10.D17(VSSIO_USB_8) U10.D23(VSS_5) U10.E5(VSS_4) U10.E6(VSS_7) U10.E9(VSSIO_USB_9) U10.E25(VSS_6) U10.F9(VSSIO_USB_10) U10.F12(VSSIO_USB_11) U10.F14(VSSIO_USB_12) U10.F16(VSSIO_USB_13) U10.F18(VSSIO_USB_16) U10.F24(VSS_8) U10.G4(VSS_40) U10.G8(VSS_42) U10.G9(VSS_43) U10.G11(VSSIO_USB_15) U10.H7(VSS_46) U10.H12(VSSIO_USB_18) U10.H14(VSSIO_USB_19) U10.H16(VSSIO_USB_20) U10.H18(VSSIO_USB_21) U10.H19(VSSIO_USB_28) U10.H23(VSSIO_PCIECLK_14) U10.H26(VSSIO_PCIECLK_15) U10.J4(VSS_41) U10.J7(VSS_21) U10.J11(VSSIO_USB_22) U10.J19(VSSIO_USB_23) U10.J23(VSSIO_PCIECLK_13) U10.K11(VSSIO_USB_3) U10.K12(VSSIO_USB_24) U10.K14(VSSIO_USB_25) U10.K16(VSSIO_USB_26) U10.K18(VSSIO_USB_27) U10.K20(VSSIO_PCIECLK_27) U10.L4(VSS_51) U10.L8(VSS_52) U10.L12(VSS_19) U10.L18(VSS_20) U10.L21(VSSIO_PCIECLK_26) U10.M11(VSS_18) U10.M12(VSS_44) U10.M18(VSS_16) U10.M19(VSSXL) U10.M20(VSSPL_SYS) U10.M22(VSSIO_PCIECLK_3) U10.M24(VSSIO_PCIECLK_4) U10.M26(VSSIO_PCIECLK_5) U10.N4(VSS_50) U10.N15(VSS_9) U10.P3(VSS_22) U10.P6(VSS_49) U10.P10(VSS_13) U10.P20(VSSIO_PCIECLK_2) U10.P21(VSSIO_PCIECLK_1) U10.P22(VSSIO_PCIECLK_6) U10.P24(VSSIO_PCIECLK_7) U10.P26(VSSIO_PCIECLK_8) U10.R13(VSS_10) U10.R17(VSS_11) U10.T10(VSS_12) U10.T20(VSSIO_PCIECLK_9) U10.T22(VSSIO_PCIECLK_10) U10.T24(VSSIO_PCIECLK_11) U10.U4(VSS_33) U10.U15(VSS_15) U10.V4(VSS_23) U10.V8(VSS_28) U10.V10(VSS_48) U10.V11(VSS_14) U10.V19(VSS_17) U10.V20(VSSIO_PCIECLK_12) U10.W9(VSS_29) U10.W10(VSS_30) U10.W20(VSSIO_PCIECLK_24) U10.W21(VSSIO_PCIECLK_23) U10.Y4(EFUSE) U10.Y10(VSS_35) U10.Y11(VSS_37) U10.Y12(VSS_36) U10.Y14(VSSIO_SATA_1) U10.Y16(VSSIO_SATA_2) U10.Y18(VSS_34) U10.Y20(VSSIO_PCIECLK_22) U11.44(VSS) U12.4(VSS) U13.2 U14.2 U15.4(GND) U16.10(GND) U18.1(A0) U18.2(A1) U18.4(GND) U19.G U20.6(GNDREF) U20.12(GND48) U20.19(GNDSRC#19) U20.22(GNDSRC#22) U20.29(GNDSB_SRC) U20.33(GNDATIG#33) U20.36(GNDATIG#36) U20.43(GND) U20.44(GNDA) U20.48(GNDCPU) U20.54(GNDHTT) U21.1(GND) U22.3(GND) U23.4(DVSS1) U23.7(DVSS2) U24.24(GND) U24.G U26.3(GND)
GND_AUDIO: C249.2 C252.1 C275.2 C281.2 C282.2 C283.2 C301.2 C490.2 C491.2 C493.2 C499.2 C504.2 C507.2 C515.2 C520.2 C537.2 C550.1 C553.2 CN20.1(PIN1) CN20.4(PIN4) CN20.6(PIN6) CN21.1(PIN1) CN21.4(PIN4) CN22.2 CN22.4 CN22.MH1 CN22.MH2 D14.3 D15.3 D16.3 L25.1 L31.1 L32.1 L35.1 L60.1 MH8.2 MH8.3 MH8.8 MH8.9 R674.1 R686.1 R756.2 R760.1 R773.2 U23.26(AVSS1) U23.42(AVSS2) U25.1(NC1) U25.2(NC2) U25.4(SGND) U25.6(NC6) U25.7(NC7) U25.10(PGND1) U25.11(PGND2) U25.14(NC14) U25.19(NC19) U25.20(NC20) U25.G
P0V75_VTT_SUS: C91.1 C92.1 J1.48(VTT2) J1.49(VTT3) J1.120(VTT1) J1.240(VTT0) J2.48(VTT2) J2.49(VTT3) J2.120(VTT1) J2.240(VTT0) PC6.1 PC12.1 PC103.1 PC104.1 PR23.2 PU3.2(VTTSNS) PU3.24(VTT)
P1V1: L9.1 L20.2 L21.1 L22.1 PC55.1 PC56.1 PC64.2 PC155.1 PC156.1 PC157.1 PL3.2 PR41.1 R187.2 R217.2 R310.1 R540.1 R569.2 R665.2 R2126.1 R2127.1 R2129.2 R2130.2
P1V1_PWRGD: Q12.D R220.1 R232.2
P1V1ALW: C221.1 C225.1 L24.1 L53.1 R301.1 R311.2 R657.2 R714.2 U9.1(VOUT#1) U9.2(VOUT#2) U9.3(VOUT#3)
P1V2_CPU_VDDHT: C431.1 C432.1 C433.1 C434.1 C435.1 C436.1 C437.1 C438.1 R568.2 R572.1 R732.2 R2128.1 U6.AJ1(VLDT_A_1) U6.AJ2(VLDT_A_2) U6.AJ3(VLDT_A_3) U6.AJ4(VLDT_A_4)
P1V2_CPU_VDDNB_RUN: C59.1 C60.1 C359.1 C360.2 C363.1 C380.1 C382.1 C383.1 L5.2 PC26.2 PC42.1 PC43.1 PC44.1 PC45.1 PC46.1 PR32.2 PR65.2 PU2.24(NB_CSN) R315.1 U6.A4(VDDNB_1) U6.A6(VDDNB_2) U6.B5(VDDNB_3) U6.B7(VDDNB_4) U6.C6(VDDNB_5) U6.C8(VDDNB_6) U6.D7(VDDNB_7) U6.D9(VDDNB_8) U6.E8(VDDNB_9) U6.E10(VDDNB_10) U6.F9(VDDNB_11) U6.F11(VDDNB_12) U6.G10(VDDNB_13) U6.G12(VDDNB_14)
P1V2_CPU_VDDR: C72.1 C73.1 C75.1 C77.1 C78.1 C80.1 C81.1 C143.1 C144.1 C145.1 C146.1 C147.1 C149.1 C152.1 C154.1 C156.1 C160.1 C161.1 C166.1 C424.1 C427.1 R213.1 R227.2 R321.1 U6.A12(VDDR_1) U6.AG12(VDDR_5) U6.AH12(VDDR_6) U6.AJ12(VDDR_7) U6.AK12(VDDR_8) U6.AL12(VDDR_9) U6.B12(VDDR_2) U6.C12(VDDR_3) U6.D12(VDDR_4) U7.1(VOUT#1) U7.2(VOUT#2) U7.3(VOUT#3)
P1V5: C485.1 PC144.1 Q59.1(S1) Q59.2(S2) Q59.3(S3) R178.1 R234.2 R436.2 R501.2 R706.2
P1V5_CPU_VDDIO_SUS: C7.1 C33.1 C34.1 C51.1 C74.1 C79.1 C93.1 C96.1 C97.1 C102.1 C116.1 C120.1 C123.1 C124.1 C162.1 C272.1 C373.1 C374.1 C375.1 C376.2 C377.1 C388.1 C392.1 C396.1 C398.1 C407.1 C411.1 C415.2 C418.1 C420.1 J1.51(VDD21) J1.54(VDD20) J1.57(VDD19) J1.60(VDD18) J1.62(VDD17) J1.65(VDD16) J1.66(VDD15) J1.69(VDD14) J1.72(VDD13) J1.75(VDD12) J1.78(VDD11) J1.170(VDD10) J1.173(VDD9) J1.176(VDD8) J1.179(VDD7) J1.182(VDD6) J1.183(VDD5) J1.186(VDD4) J1.189(VDD3) J1.191(VDD2) J1.194(VDD1) J1.197(VDD0) J2.51(VDD21) J2.54(VDD20) J2.57(VDD19) J2.60(VDD18) J2.62(VDD17) J2.65(VDD16) J2.66(VDD15) J2.69(VDD14) J2.72(VDD13) J2.75(VDD12) J2.78(VDD11) J2.170(VDD10) J2.173(VDD9) J2.176(VDD8) J2.179(VDD7) J2.182(VDD6) J2.183(VDD5) J2.186(VDD4) J2.189(VDD3) J2.191(VDD2) J2.194(VDD1) J2.197(VDD0) J3.21(11) J3.23(12) PC5.2 PC13.1 PC22.1 PC32.1 PC52.1 PC53.1 PC54.1 PL2.2 PR2.2 PR20.1 PU3.8(VDDQ) PU3.23(VLDOIN) Q59.5(D1) Q59.6(D2) Q59.7(D3) Q59.8(D4) R21.1 R27.1 R44.1 R55.1 R74.1 R111.1 R145.2 R151.1 R159.1 R163.1 R167.1 R179.1 R180.1 R182.1 R183.1 R184.1 R193.1 R194.1 R201.1 R215.2 R240.1 R385.1 R419.1 R522.1 R523.1 R537.1 R567.2 R574.1 R575.1 R576.1 R577.1 R677.1 U6.AB24(VDDIO_21) U6.AB26(VDDIO_22) U6.AB28(VDDIO_23) U6.AB30(VDDIO_24) U6.AC24(VDDIO_25) U6.AD26(VDDIO_26) U6.AD28(VDDIO_27) U6.AD30(VDDIO_28) U6.AF30(VDDIO_29) U6.M24(VDDIO_1) U6.M26(VDDIO_2) U6.M28(VDDIO_3) U6.M30(VDDIO_4) U6.P24(VDDIO_5) U6.P26(VDDIO_6) U6.P28(VDDIO_7) U6.P30(VDDIO_8) U6.T24(VDDIO_9) U6.T26(VDDIO_10) U6.T28(VDDIO_11) U6.T30(VDDIO_12) U6.V25(VDDIO_13) U6.V26(VDDIO_14) U6.V28(VDDIO_15) U6.V30(VDDIO_16) U6.Y24(VDDIO_17) U6.Y26(VDDIO_18) U6.Y28(VDDIO_19) U6.Y29(VDDIO_20) U7.7(VIN#7) U7.8(VIN#8) U7.9(VIN#9) U19.7(VIN#7) U19.8(VIN#8) U19.9(VIN#9)
P1V5_CTL: Q20.G R289.2
P1V5_DDR3_PWRGD: PR20.2 PU3.13(PGOOD) R595.1
P1V5_TV: C310.1 C539.1 C544.1 CN5.6(1.5V) CN5.28(P_1.5V_28) CN5.48(P_1.5V_48) R501.1
P1V5_WW: C179.1 C181.1 C453.1 CN2.6(1.5V) CN2.28(P_1.5V_28) CN2.48(P_1.5V_48) R234.1
P1V8: C84.1 C87.2 C111.1 C112.1 L8.1 L11.2 L13.2 L15.1 L43.1 L44.1 L46.1 Q17.G R124.2 R132.2 R150.1 R313.1 R552.1 R557.1 R570.2 R599.2 R647.1 U2.5(VCC) U4.1(VOUT#1) U4.2(VOUT#2) U4.3(VOUT#3)
P1V8_CARD: C128.1 U5.8(VDDU)
P1V25: C391.1 C394.1 C399.1 C400.1 C401.1 C403.1 C406.1 C409.1 C412.1 PC57.1 PC61.1 PC67.2 PC158.1 PC159.1 PC160.1 PL4.2 PR42.1 R237.2 R732.1 U3.J11(VDDC_4) U3.J14(VDDC_2) U3.J16(VDDC_22) U3.K12(VDDC_1) U3.K15(VDDC_5) U3.L11(VDDC_8) U3.L14(VDDC_7) U3.M12(VDDC_6) U3.M13(VDDC_9) U3.M15(VDDC_10) U3.N12(VDDC_11) U3.N14(VDDC_12) U3.P11(VDDC_13) U3.P13(VDDC_14) U3.P14(VDDC_15) U3.R12(VDDC_16) U3.R15(VDDC_17) U3.T11(VDDC_18) U3.T14(VDDC_21) U3.T15(VDDC_19) U3.U12(VDDC_20) U3.U16(VDDC_3)
P1V25_PWRGD: PR3.1 Q15.D R231.2
P2V5_CPU_VDDA_RUN: C4.1 C5.1 C357.1 C358.1 C1464.1 L2.2 R678.1 U6.C10(VDDA_1) U6.D10(VDDA_2)
P3V3: C3.1 C36.1 C50.1 C113.1 C118.1 C126.1 C163.1 C175.1 C262.1 C347.1 C348.2 C379.1 C386.1 C511.2 CN1.278(3V3#278) CN1.280(3V3#280) J1.236(VDDSPD) J2.236(VDDSPD) J2.237(SA1) L14.1 L17.1 L18.1 L19.1 L29.1 L45.1 L50.1 L55.1 L57.1 L62.1 L70.1 LED1.A PC74.1 Q1.G Q2.G Q30.1 Q30.2 Q30.3 R2.1 R4.1 R7.2 R10.2 R11.1 R12.2 R19.1 R23.1 R30.1 R34.1 R36.1 R37.1 R42.1 R49.1 R50.1 R60.2 R69.1 R119.1 R120.1 R121.2 R122.1 R125.2 R127.1 R128.1 R137.1 R139.1 R140.1 R141.1 R177.2 R198.2 R223.1 R226.1 R233.2 R235.1 R244.1 R246.2 R252.1 R256.1 R271.2 R280.2 R282.2 R284.2 R285.2 R289.1 R297.2 R300.2 R302.2 R333.1 R354.1 R355.2 R363.1 R369.2 R370.2 R371.2 R372.2 R373.2 R375.1 R384.2 R390.1 R393.2 R402.1 R412.2 R420.1 R424.1 R433.1 R438.1 R443.2 R444.2 R445.2 R466.2 R467.2 R474.2 R487.1 R492.2 R493.2 R495.2 R524.2 R525.1 R527.1 R548.2 R589.2 R592.1 R593.1 R628.1 R632.1 R642.2 R646.2 R649.2 R655.2 R656.2 R659.1 R676.1 R682.1 R689.2 R700.2 R711.2 R712.1 R734.2 R748.1 R751.1 R754.2 R755.2 R771.2 R772.1 R776.1 U1.7(VIN#7) U1.8(VIN#8) U1.9(VIN#9) U3.H11(VDD33_1(NC)) U3.H12(VDD33_2(NC)) U4.7(VIN#7) U4.8(VIN#8) U4.9(VIN#9) U5.10(V33) U11.8(3VCC) U12.8(VDD) U15.8(VCC) U18.8(VCC)
P3V3_AUDIO_DVDD: C240.1 C245.1 C246.1 C251.1 L26.2 L29.2 R332.1 U23.1(DVDD)
P3V3_AVCC_SIO: C526.1 C528.1 L70.2 U11.50(AVCC(3.3V))
P3V3_BAT: B1.1(POS) R249.2
P3V3_BT: C185.1 C445.2 CN26.1 Q56.D R235.2 R236.2 R238.1 R247.1 R247.2
P3V3_CARD: C115.1 C119.1 C139.1 C140.1 CN13.P3(XD-VCC) CN13.P21(SD-VCC) CN13.P28(MS-VCC) EC1.1 L16.1 R199.1
P3V3_CF33: L16.2 U5.9(CF_V33)
P3V3_SB: C475.1 C495.1 C497.1 C503.1 R682.2 U10.AA2(VDDIO_33_PCIGP_6) U10.AA7(VDDIO_33_PCIGP_9) U10.AA9(VDDIO_33_PCIGP_10) U10.AA19(VDDIO_33_PCIGP_12) U10.AB4(VDDIO_33_PCIGP_7) U10.AC8(VDDIO_33_PCIGP_8) U10.AC21(VDDIO_33_PCIGP_5) U10.AE5(VDDIO_33_PCIGP_4) U10.AF7(VDDIO_33_PCIGP_11) U10.AH1(VDDIO_33_PCIGP_1) U10.V6(VDDIO_33_PCIGP_2) U10.Y19(VDDIO_33_PCIGP_3)
P3V3_STB_EN: PC93.1 PR85.2 PU9.13(PGOOD1) PU9.27(EN2)
P3V3_STBY: C67.1 C88.1 C94.1 C95.1 C209.1 C300.1 C447.1 C492.1 C517.2 CN2.24(P_3.3VAUX) CN5.24(P_3.3VAUX) CN9.33 CN9.34 D8.A2 L23.1 L26.1 L64.1 L68.1 PC83.1 PC84.1 PC87.1 PL13.2 PU9.30(VOUT2) Q30.5 Q30.6 Q30.7 Q30.8 Q56.S Q70.G R209.1 R218.1 R221.1 R228.2 R236.1 R251.2 R257.1 R265.2 R273.2 R275.2 R276.2 R279.2 R286.2 R287.1 R290.1 R292.1 R293.1 R294.1 R322.2 R326.1 R359.2 R360.2 R361.2 R378.1 R389.1 R404.2 R405.2 R422.2 R423.2 R431.2 R439.1 R451.1 R462.2 R463.2 R464.2 R465.2 R468.2 R559.1 R562.1 R594.1 R598.1 R610.1 R611.2 R612.1 R613.1 R635.2 R683.2 R688.2 R697.2 R698.2 R699.2 R703.2 R745.1 R749.1 R762.1 R763.1 U9.7(VIN#7) U9.8(VIN#8) U9.9(VIN#9) U11.24(3VSB) U22.5(VCC) U26.5(VCC)
P3V3_TV: C302.1 C536.1 C542.1 C543.1 CN5.2(3.3V) CN5.52(P_3.3V) R474.1
P3V3_TV1: CN5.39(RESERVED_39) CN5.41(RESERVED_41) R748.2 R749.2
P3V3_WLAN: CN2.39(RESERVED_39) CN2.41(RESERVED_41) R256.2 R257.2
P3V3_WW: C177.1 C180.1 C449.1 C450.1 CN2.2(3.3V) CN2.52(P_3.3V) R233.1
P5V: C1.1 C2.1 C23.1 C31.1 C32.1 C35.2 C232.1 C236.1 C238.1 C239.1 C548.1 C549.1 CN1.1(5V#1) CN1.3(5V#3) CN1.5(5V#5) CN1.7(5V#7) CN1.9(5V#9) CN31.2 CN33.2(+12V) CN34.2(+12V) CN35.2(+12V) D4.A D5.A D6.A L82.1 PC31.1 PC34.1 PC37.1 PC60.2 PC63.2 PC73.1 PR1.1 PR5.1 PR9.1 PR10.2 PR13.2 PR16.2 PU6.7(V5IN) PU7.7(V5IN) Q31.1 Q31.2 Q31.3 R1.1 R3.1 R6.1 R16.1 R24.1 R149.1 R230.1 R231.1 R232.1 R272.2 R336.1 R442.1 R459.1 R460.1 R461.1 R475.1 R482.1 R483.1 R516.2 R573.1 R742.2 U16.11(VCC)
P5V_AUDIO_AVDD: C249.1 C275.1 C493.1 C515.1 L27.2 L30.2 U23.25(AVDD1) U23.38(AVDD2)
P5V_LDO: C346.1 PC91.1 PR60.1 PR85.1 PU9.7(LDO) PU9.19(PVCC) PU9.20(NC_2)
P5V_ODD: C514.1 C523.1 C524.1 CN32.1 CN32.2 D17.C L82.2
P5V_STB_EN: PC152.1 PR60.2 PU9.14(EN1)
P5V_STBY: C82.1 C266.1 CN7.41(GND1) CN30.2 L30.1 PC33.1 PC75.1 PC78.1 PC85.1 PL11.1 PR19.1 PU3.15(VDDP) PU9.9(BYP) PU9.10(VOUT1) Q6.D Q31.5 Q31.6 Q31.7 Q31.8 Q47.5 Q47.6 Q47.7 Q47.8 R296.1 R334.1 R416.1 R531.1 R535.1 R752.2 R775.1
P5V_TOUCH: C241.1 CN28.1 R303.2 U21.4(VCC)
P5V_USB: F2.1 F3.1 F4.1 L27.1 L33.2 R303.1 R488.1 R520.1 R767.1 R770.2 R2122.1 R2123.1 R2124.1 R2125.1
P5V_USB5V1: C327.1 C328.1 C329.1 C344.1 CN18.1(VCC) CN19.1(VCC) L40.2 Q50.5 R512.2
P5V_USB5V3: C323.1 C332.1 C333.1 C343.1 CN16.1(VCC) CN17.1(VCC) L42.2 Q49.5 R519.2
P5V_USB_CAM: C325.1 CN25.7 R516.1
P5V_USB_CTL: Q39.B R498.2
P5V_USB_CTL1: Q38.G Q39.C Q46.G R439.2
P12V: C258.1 C501.1 PL8.1 PR28.2 PR33.1 PR38.2 Q26.1 Q26.2 Q26.3 R52.1 R418.1 R744.1
P12V_HDD: C184.1 C188.1 C233.1 C234.1 C256.1 CN31.4 CN31.6 CN31.8 D18.C EC11.1 PL8.2
P12V_STBY: L67.1 PL7.2 Q26.5 Q26.6 Q26.7 Q26.8
P12VFAN_SON_N: Q41.G Q48.D R455.1 R491.2
P19V_CONVERTER: C510.2 L28.1 Q63.D
P19V_FILT: L4.1 PC38.1 PC39.1 PC40.1 PC41.1 PC117.1 PC118.1 PC121.1 PC122.1 PC123.1 PC124.1 PQ7.D(5) PQ8.D(5)
P19V_FILT_NB: L3.1 PC23.1 PC27.1 PC105.1 PC108.1 PC110.1 PC113.1 PQ4.D(5)
P19V_INVERTER: C263.1 C265.1 CN27.1 CN27.2 CN27.3 CN27.4 CN27.5 L28.2
P19V_MXM: C24.2 CN1.EA1(PWR_SRC1) CN1.EA2(PWR_SRC2) CN1.EA3(PWR_SRC3) CN1.EA4(PWR_SRC4) CN1.EA5(PWR_SRC5) CN1.EA6(PWR_SRC6) CN1.EA7(PWR_SRC7) CN1.EA8(PWR_SRC8) CN1.EA9(PWR_SRC9) CN1.EA10(PWR_SRC10) CN1.EB1(PWR_SRC11) CN1.EB2(PWR_SRC12) CN1.EB3(PWR_SRC13) CN1.EB4(PWR_SRC14) CN1.EB5(PWR_SRC15) CN1.EB6(PWR_SRC16) CN1.EB7(PWR_SRC17) CN1.EB8(PWR_SRC18) CN1.EB9(PWR_SRC19) CN1.EB10(PWR_SRC20) L1.1 PC17.1 PC20.1 PC21.1
P19V_SYS: C331.1 C345.1 L1.2 L3.2 L4.2 L34.2 L41.2 PL1.2 PL5.2 PL6.2 PL10.1 PL12.1 PL14.1 PL15.2 Q63.S R99.1 R100.1 R317.1 R323.1 R337.1 R348.1 R356.1 R491.1 R494.1 R684.1 R716.2
P19V_SYS_FILE: PC94.1 PC96.1 PC97.1 PC148.1 PC149.1 PC150.1 PC151.1 PL12.2 PL14.2 PQ12.D(5) PR62.2 PU9.6(VIN)
VBAT: D8.A1 R249.1
VBAT_IN: C268.1 C269.1 R386.1 U10.B1(VDDBT_RTC_G)
VDD0_NB_CS: PC26.1 PR31.1 PR32.1 PU2.23(NB_CS)
VDD0_NB_ENABLE: PR30.1 PU2.42(NB_DRVON)
VDD0_NB_PWM: PU1.2(PWM) PU2.44(NB_G)
VDD18: C381.1 R552.2 U3.F9(VDD18_1) U3.G9(VDD18_2)
VDD18_MEM: R196.2 U3.AD11(VDD18_MEM2(NC)) U3.AE11(VDD18_MEM1(NC))
VDD_PCIE: C384.1 C389.1 C390.1 C393.1 C402.1 R2129.1 R2130.1 U3.A6(VDDPCIE_1) U3.B6(VDDPCIE_2) U3.C6(VDDPCIE_3) U3.D6(VDDPCIE_4) U3.E6(VDDPCIE_5) U3.F6(VDDPCIE_6) U3.G7(VDDPCIE_7) U3.H8(VDDPCIE_8) U3.J9(VDDPCIE_9) U3.K9(VDDPCIE_10) U3.L9(VDDPCIE_12) U3.M9(VDDPCIE_11) U3.P9(VDDPCIE_13) U3.R9(VDDPCIE_14) U3.T9(VDDPCIE_15) U3.U9(VDDPCIE_17) U3.V9(VDDPCIE_16)
VDDA18HTPLL: C356.1 L43.2 U3.H17(VDDA18HTPLL)
VDDA18PCIE: C121.1 C395.1 C404.1 C408.1 C419.1 C421.1 L15.2 U3.AA9(VDDA18PCIE_11) U3.AB9(VDDA18PCIE_12) U3.AD9(VDDA18PCIE_13) U3.AE9(VDDA18PCIE_14) U3.H9(VDDA18PCIE_7) U3.J10(VDDA18PCIE_1) U3.K10(VDDA18PCIE_3) U3.L10(VDDA18PCIE_5) U3.M10(VDDA18PCIE_4) U3.P10(VDDA18PCIE_2) U3.R10(VDDA18PCIE_9) U3.T10(VDDA18PCIE_8) U3.U10(VDDA18PCIE_15) U3.W9(VDDA18PCIE_6) U3.Y9(VDDA18PCIE_10)
VDDA18PCIEPLL: C378.1 L46.2 U3.D7(VDDA18PCIEPLL1) U3.E7(VDDA18PCIEPLL2)
VDDAN_1.1V_USB_S: C244.1 C248.1 L24.2 U10.C11(VDDAN_11_USB_S_1) U10.D11(VDDAN_11_USB_S_2)
VDDAN_P1V1_CLK: C199.1 C206.1 C207.1 C448.1 C451.1 L20.1 U10.J20(VDDAN_11_CLK_6) U10.J21(VDDAN_11_CLK_5) U10.J22(VDDAN_11_CLK_8) U10.J28(VDDAN_11_CLK_3) U10.K21(VDDAN_11_CLK_7) U10.K26(VDDAN_11_CLK_4) U10.K28(VDDAN_11_CLK_1) U10.K29(VDDAN_11_CLK_2)
VDDAN_P1V1_PCIE: C186.1 C208.1 C474.1 C476.1 L21.2 R255.1 U10.U26(VDDAN_11_PCIE_1) U10.V22(VDDAN_11_PCIE_2) U10.V26(VDDAN_11_PCIE_3) U10.V27(VDDAN_11_PCIE_4) U10.V28(VDDAN_11_PCIE_5) U10.V29(VDDAN_11_PCIE_6) U10.W22(VDDAN_11_PCIE_7) U10.W26(VDDAN_11_PCIE_8)
VDDAN_P1V1_SATA: C216.1 C217.1 C218.1 C219.1 C220.1 L22.2 R671.1 U10.AD18(VDDAN_11_SATA_6) U10.AE16(VDDAN_11_SATA_7) U10.AE18(VDDAN_11_SATA_5) U10.AF18(VDDAN_11_SATA_4) U10.AG19(VDDAN_11_SATA_3) U10.AH20(VDDAN_11_SATA_2) U10.AJ20(VDDAN_11_SATA_1)
VDDAN_P3V3_HWM_S: C489.1 C494.1 L64.2 U10.D6(VDDAN_33_HWM_S)
VDDAN_P3V3_USB_S: C223.1 C224.1 C483.1 C484.1 L23.2 R667.1 U10.A18(VDDAN_33_USB_S_1) U10.A19(VDDAN_33_USB_S_2) U10.A20(VDDAN_33_USB_S_3) U10.B18(VDDAN_33_USB_S_4) U10.B19(VDDAN_33_USB_S_5) U10.B20(VDDAN_33_USB_S_6) U10.C18(VDDAN_33_USB_S_7) U10.C20(VDDAN_33_USB_S_8) U10.D18(VDDAN_33_USB_S_9) U10.D19(VDDAN_33_USB_S_10) U10.D20(VDDAN_33_USB_S_11) U10.E19(VDDAN_33_USB_S_12)
VDDCR_P1V1: C477.1 C479.1 C480.1 C486.1 C488.1 R665.1 U10.N13(VDDCR_11_1) U10.N17(VDDCR_11_3) U10.R15(VDDCR_11_2) U10.U13(VDDCR_11_4) U10.U17(VDDCR_11_5) U10.V12(VDDCR_11_6) U10.V18(VDDCR_11_7) U10.W12(VDDCR_11_8) U10.W18(VDDCR_11_9)
VDDCR_P1V1_GBE_S: C496.1 C516.1 R694.2 R714.1 U10.L7(VDDCR_11_GBE_S_1) U10.L9(VDDCR_11_GBE_S_2)
VDDCR_P1V1_S: C466.1 C467.1 R657.1 U10.F26(VDDCR_11_S_1) U10.G26(VDDCR_11_S_2)
VDDCR_P1V1_USB_S: C211.1 C212.1 C213.1 R301.2 U10.A11(VDDCR_11_USB_S_1) U10.B11(VDDCR_11_USB_S_2)
VDDG_NB: R117.1 R120.2 R124.1
VDDHTRX: C98.1 C105.1 C106.1 C107.1 R2127.2 U3.A23(VDDHTRX_7) U3.B23(VDDHTRX_6) U3.D22(VDDHTRX_5) U3.E21(VDDHTRX_4) U3.F20(VDDHTRX_3) U3.G19(VDDHTRX_2) U3.H18(VDDHTRX_1)
VDDHTTX: C127.1 C413.1 C414.1 C417.1 C428.1 R2128.2 U3.AA21(VDDHTTX_5) U3.AB22(VDDHTTX_4) U3.AC23(VDDHTTX_3) U3.AD24(VDDHTTX_2) U3.AE25(VDDHTTX_1) U3.M17(VDDHTTX_13) U3.P17(VDDHTTX_12) U3.R17(VDDHTTX_11) U3.T17(VDDHTTX_10) U3.U17(VDDHTTX_9) U3.V18(VDDHTTX_8) U3.W19(VDDHTTX_7) U3.Y20(VDDHTTX_6)
VDDIO_AZ_S: C487.1 C498.1 R687.1 U10.M8(VDDIO_AZ_S)
VDDIO_GBE_S: R696.1 U10.M6(VDDIO_GBE_S_1) U10.P8(VDDIO_GBE_S_2)
VDDIO_P1V8_FC: C465.1 C471.1 C472.1 R647.2 U10.AC22(VDDIO_18_FC_4) U10.AE25(VDDIO_18_FC_2) U10.AF22(VDDIO_18_FC_1) U10.AF24(VDDIO_18_FC_3)
VDDIO_P3V3_GBE_S: R688.1 U10.M10(VDDIO_33_GBE_S)
VDDIO_P3V3_PCIGP: C455.1 C456.1 L56.2
VDDIO_P3V3_S: C201.1 C202.1 C203.1 L58.2 R276.1 U10.A21(VDDIO_33_S_1) U10.B21(VDDIO_33_S_3) U10.D21(VDDIO_33_S_2) U10.J9(VDDIO_33_S_6) U10.K10(VDDIO_33_S_4) U10.L10(VDDIO_33_S_5) U10.T6(VDDIO_33_S_7) U10.T8(VDDIO_33_S_8)
VDDLT18: C101.1 C104.1 L11.1 U3.A15(VDDLT18_1(NC)) U3.B15(VDDLT18_2(NC))
VDDLTP18: C103.1 C554.1 L13.1 U3.A13(VDDLTP18(NC))
VDDPL_P1V1_SYS_S: C454.1 C460.1 C464.1 L53.2 U10.L22(VDDPL_11_SYS_S)
VDDPL_P3V3_PCIE: C461.1 C469.1 L57.2 U10.AE28(VDDPL_33_PCIE)
VDDPL_P3V3_SATA: C481.1 C482.1 L62.2 U10.AD14(VDDPL_33_SATA)
VDDPL_P3V3_SYS: C459.1 C470.1 L55.2 L56.1 U10.M21(VDDPL_33_SYS)
VDDPL_P3V3_USB_S: C457.1 C458.1 R667.2 U10.F19(VDDPL_33_USB_S)
VDDRF_GBE_S: R394.1 U10.V1(VDDRF_GBE_S)
VDDXL_P3V3_S: C468.1 L58.1 U10.L20(VDDXL_33_S)
VIN0: C508.1 R677.2 U10.A3(VIN0/GPIO175)
VIN1: C509.1 R678.2 U10.B4(VIN1/GPIO176)
VIN2: C260.1 R321.2 U10.A4(VIN2/GPIO177)
VIN3: C257.1 R318.2 U10.C5(VIN3/GPIO178)
VIN4: C253.1 R315.2 U10.A7(VIN4/GPIO179)
VIN5: C250.1 R313.2 U10.B7(VIN5/GPIO180)
VIN6: C243.1 R310.2 U10.B8(VIN6/GBE_STAT3/GPIO181)
VIN_19: C303.1 C317.1 C342.1 L34.1 L41.1 U17.5(D_0) U17.6(D_1) U17.7(D_2) U17.8(D_3)
14M_25M_48M_OSC: TP197.1 U10.L25(14M_25M_48M_OSC)
32K_X1: C273.2 R349.2 U10.C1(32K_X1) Y3.4
32K_X2: C259.2 R349.1 U10.C2(32K_X2) Y3.1
2668_BK_ENA: R106.1 R343.1 R558.1
2668_BK_ENA_MXM_R: CN9.30 R558.2
2668_BK_ENA_NB_R: CN7.30 R106.2
2668_BK_PWM: R75.2 R299.1 R561.1
2668_BK_PWM_MXM_R: CN9.29 R561.2
2668_BK_PWM_NB_R: CN7.29 R75.1
2668_DETECT_N: Q18.G Q19.G Q22.G Q96.G R89.1 R272.1 R536.1 R752.1 U10.H3(BLINK/USB_OC7#/GEVENT18#)
2668_DETECT_N_MXM_R: CN9.32 R536.2
2668_DETECT_N_NB_R: CN7.32 R89.2
2668_LVDD_EN: R105.1 R277.1 R542.1
2668_LVDD_EN_MXM_R: CN9.31 R542.2
2668_LVDD_EN_NB_R: CN7.31 R105.2
A_RST_N: C261.2 R338.1 R457.1
A_RX0N: C196.1 U3.Y8(SB_RX0N)
A_RX0N_C: C196.2 U10.AD27(A_TX0N)
A_RX0P: C195.1 U3.AA8(SB_RX0P)
A_RX0P_C: C195.2 U10.AD26(A_TX0P)
A_RX1N: C194.1 U3.Y7(SB_RX1N)
A_RX1N_C: C194.2 U10.AC29(A_TX1N)
A_RX1P: C193.1 U3.AA7(SB_RX1P)
A_RX1P_C: C193.2 U10.AC28(A_TX1P)
A_RX2N: C192.1 U3.AA6(SB_RX2N)
A_RX2N_C: C192.2 U10.AB28(A_TX2N)
A_RX2P: C191.1 U3.AA5(SB_RX2P)
A_RX2P_C: C191.2 U10.AB29(A_TX2P)
A_RX3N: C190.1 U3.Y5(SB_RX3N)
A_RX3N_C: C190.2 U10.AB27(A_TX3N)
A_RX3P: C189.1 U3.W5(SB_RX3P)
A_RX3P_C: C189.2 U10.AB26(A_TX3P)
A_TX0N: C138.2 U10.AE23(A_RX0N)
A_TX0N_C: C138.1 U3.AE7(SB_TX0N)
A_TX0P: C137.2 U10.AE24(A_RX0P)
A_TX0P_C: C137.1 U3.AD7(SB_TX0P)
A_TX1N: C136.2 U10.AD24(A_RX1N)
A_TX1N_C: C136.1 U3.AD6(SB_TX1N)
A_TX1P: C135.2 U10.AD25(A_RX1P)
A_TX1P_C: C135.1 U3.AE6(SB_TX1P)
A_TX2N: C134.2 U10.AC25(A_RX2N)
A_TX2N_C: C134.1 U3.AC6(SB_TX2N)
A_TX2P: C133.2 U10.AC24(A_RX2P)
A_TX2P_C: C133.1 U3.AB6(SB_TX2P)
A_TX3N: C132.2 U10.AB24(A_RX3N)
A_TX3N_C: C132.1 U3.AE5(SB_TX3N)
A_TX3P: C131.2 U10.AB25(A_RX3P)
A_TX3P_C: C131.1 U3.AD5(SB_TX3P)
A_VBAT: C197.1 C533.1 D8.K J4.1 U11.47(VBAT)
ALLOW_LDTSTOP: R126.1 U10.G21(ALLOW_LDTSTP/DMA_ACTIVE#)
AMP_IN_L: C534.2 C535.2 R774.2 U25.3(IN1+)
AMP_IN_R: C518.2 C519.2 U25.18(IN2-)
AMP_MODE: R415.2 R456.1 R989.1 U25.17(MODE)
AMP_SVRR: C301.1 R470.2 U25.5(SVRR)
AP_VOLUME_DOWN: C371.1 R112.1 R115.1 R562.2 S2.2 S2.3 S2.4 U10.D4(USB_OC4#/IR_RX0/GEVENT16#)
AP_VOLUME_DOWN_MXM_R: CN9.18 R115.2
AP_VOLUME_DOWN_NB_R: CN7.18 R112.2
AP_VOLUME_UP: C369.1 R101.1 R102.1 R559.2 S1.2 S1.3 S1.4 U10.E8(USB_OC3#/AC_PRES/TDO/GEVENT15#)
AP_VOLUME_UP_MXM_R: CN9.19 R101.2
AP_VOLUME_UP_NB_R: CN7.19 R102.2
AU6433_RST_N: R169.2 U5.2(CHIPRESETN)
AUDIO_INDICATE: R78.2 R539.1 U23.3(GPIO1/DMIC-DATA3/4)
AUDIO_INDICATE_MXM_R: CN9.26 R539.2
AUDIO_INDICATE_NB_R: CN7.26 R78.1
AUDIO_MUTE: R79.2 R554.2 R987.1 U26.1(A)
AUDIO_MUTE_AMP_CTRL: Q65.G R980.1 R987.2 U26.4(Y)
AUDIO_MUTE_MXM_R: CN9.25 R554.1
AUDIO_MUTE_NB_R: CN7.25 R79.1
AUX_CAL: R144.2 U3.C8(AUX_CAL(NC))
AUX_MUX: TP203.1 U10.AF1(AD20/GPIO20)
AV_MODE: R77.2 R538.1 U10.D1(USB_OC6#/IR_TX1/GEVENT6#)
AV_MODE_MXM_R: CN9.27 R538.2
AV_MODE_NB_R: CN7.27 R77.1
AZ_BIT_CLK: C247.2 R339.1 U23.6(BIT-CLK)
AZ_BIT_CLK_R: R339.2 R408.1 U10.M3(AZ_BITCLK)
AZ_RST_N: C279.1 R329.1 R441.1 U23.11(RESET#)
AZ_RST_R_N: R329.2 U10.P2(AZ_RST#)
AZ_SDATA_IN0: R403.1 U10.L2(AZ_SDIN0/GPIO167)
AZ_SDATA_IN1: R379.1 R406.1 U10.M2(AZ_SDIN1/GPIO168)
AZ_SDATA_IN1_R: R379.2 U23.8(SDATA-IN)
AZ_SDATA_IN2: R407.1 U10.M1(AZ_SDIN2/GPIO169)
AZ_SDATA_OUT: R327.1 R340.2 R436.1 U23.5(SDATA-OUT)
AZ_SDOUT_R: R327.2 U10.N1(AZ_SDOUT)
AZ_SYNC: C255.2 R328.1 U23.10(SYNC)
AZ_SYNC_R: R328.2 U10.N2(AZ_SYNC)
BKL_PWM_R: Q19.S R282.1 R299.2 R307.1 R309.1
BLK_EN: D12.K R330.1
BLK_PWM: D11.K R291.1
BOARD_ID0: R292.2 R304.1 U10.G24(KSI_0/GPIO201)
BOARD_ID1: R293.2 R305.1 U10.G25(KSI_1/GPIO202)
BRIGHT_ADJUST: CN27.8 R309.2
BT_DISABLE: R652.1 R658.1 U10.AF20(SATA_IS4#/FANOUT3/GPIO55)
BT_DISABLE_N: CN26.6 R238.2
BT_DISABLE_R: CN2.5(RESERVED_5) CN2.51(RESERVED_51) R628.2 R652.2 R658.2
BT_LED: R239.1 U10.E22(EC_PWM1/EC_TIMER1/GPIO198)
CIR_BLTX_TIP_DRIVE: Q45.C R459.2 R460.2 R461.2 R469.2
CLK_48M_CARD: R166.1 R614.2
CLK_48M_R_CARD: R614.1 R615.1 U20.10(48MHZ_1)
CLK_48M_R_USB: R616.1 U20.11(48MHZ_0)
CLK_48M_SIO: R615.2 U11.1(IOCLK)
CLK_48M_USB: R324.2 R616.2
CLK_100M_NBGFX_DN: R253.1 R588.2 U3.T1(GFX_REFCLKN)
CLK_100M_NBGFX_DP: R248.1 R587.2 U3.T2(GFX_REFCLKP)
CLK_100M_NBGFX_R_DN: R588.1 U20.34(ATIG2C_LPRS)
CLK_100M_NBGFX_R_DP: R587.1 U20.35(ATIG2T_LPRS)
CLK_100M_NBHT_DN: R590.1 U3.C24(HT_REFCLKN)
CLK_100M_NBHT_DP: R591.1 U3.C25(HT_REFCLKP)
CLK_100M_NBHT_R_DN: R590.2 U20.55(HTT0C/66M_LPRS)
CLK_100M_NBHT_R_DP: R591.2 U20.56(HTT0T/66M_LPRS)
CLK_100M_PCIE_LAN_DN: R619.2 U24.20(REFCLK_N)
CLK_100M_PCIE_LAN_DP: R620.2 U24.19(REFCLK_P)
CLK_100M_PCIE_LAN_R_DN: R619.1 U20.17(SRC2C_LPRS)
CLK_100M_PCIE_LAN_R_DP: R620.1 U20.18(SRC2T_LPRS)
CLK_100M_PCIE_TUNER_DN: CN5.11(REFCLK_N) R621.2
CLK_100M_PCIE_TUNER_DP: CN5.13(REFCLK_P) R622.2
CLK_100M_PCIE_TUNER_R_DN: R621.1 U20.23(SRC1C_LPRS)
CLK_100M_PCIE_TUNER_R_DP: R622.1 U20.24(SRC1T_LPRS)
CLK_100M_PCIE_WLAN_DN: CN2.11(REFCLK_N) R623.2
CLK_100M_PCIE_WLAN_DP: CN2.13(REFCLK_P) R624.2
CLK_100M_PCIE_WLAN_R_DN: R623.1 U20.25(SRC0C_LPRS)
CLK_100M_PCIE_WLAN_R_DP: R624.1 U20.26(SRC0T_LPRS)
CLK_200M_CPU_DN: C85.1 R586.2 R596.2
CLK_200M_CPU_DN_R: R586.1 U20.50(CPUKG0C_LPRS)
CLK_200M_CPU_DP: C86.1 R585.2 R596.1
CLK_200M_CPU_DP_R: R585.1 U20.51(CPUKG0T_LPRS)
CLK_ICH_RTCX1: C187.2 R250.1 U10.L26(25M_X1) Y1.2
CLK_ICH_RTCX2: C205.2 R250.2 U10.L27(25M_X2) Y1.1
CLK_PCI_33M_DEBUG: R281.1 R396.2
CLK_PCI_33M_DEBUG_R: CN2.19(RESERVED/UIM_C4) R281.2
CLK_PCI_33M_SIO: C1463.1 R397.2 R425.1 U11.2(PCICLK)
CLK_REQ1_N: TP199.1 U10.AB18(CLK_REQ1#/FANOUT4/GPIO61)
CLK_REQ2_N: TP95.1 U10.AH21(CLK_REQ2#/FANIN4/GPIO62)
CLK_REQG_N: R655.1 R660.2 U10.AA20(CLK_REQG#/GPIO65/OSCIN)
CLK_VDD: C155.1 C157.1 C158.1 C159.1 C167.1 C169.1 C170.1 C171.1 C183.1 L17.2 R225.1 R606.1 U20.1(VDDHTT) U20.20(VDDSRC#20) U20.21(VDDSRC#21) U20.30(VDDSB_SRC) U20.37(VDDATIG) U20.42(VDD) U20.49(VDDCPU)
CLK_VDD48: C168.1 C176.1 C178.1 C182.1 L19.2 U20.9(VDD48)
CLK_VDDA: C151.1 C440.1 L50.2 U20.45(VDDA)
CLK_VDDREF: C165.1 C172.1 C173.1 C174.1 L18.2 U20.5(VDDREF)
CLK_XTAL_IN: C442.1 U20.7(X1) Y4.1
CLK_XTAL_OUT: C443.1 U20.8(X2) Y4.2
CLPCLK0_R: R636.1 U10.H24(LPCCLK0)
CLPCLK1_R: R637.1 U10.H25(LPCCLK1)
CMOS_CLR: J4.5 R274.1
CMOS_PW_CLR: J4.6 R260.1
COM1_C1N: C545.2 U16.14(C1-)
COM1_C1P: C545.1 U16.12(C1+)
COM1_C2N: C305.2 U16.16(C2-)
COM1_C2P: C305.1 U16.15(C2+)
COM1_CTS_N: R493.1 U11.13(CTSA#/GP67) U16.22(R4OUT)
COM1_DCD_N: R754.1 U11.19(GP61/DCDA#) U16.8(R1OUT)
COM1_DSR_N: R755.1 U11.14(DSRA#/GP66) U16.5(R2OUT)
COM1_DTR_N: U11.16(DTRA#/GP64) U16.20(T3IN)
COM1_EN: R483.2 U16.24(EN)
COM1_RI_N: R485.1 R495.1 U11.20(GP60/RIA#)
COM1_RTS_N: R693.1 R712.2 U11.15((2E_4E_SEL) RTSA#/GP65) U16.7(T1IN)
COM1_RXD: CN7.17 CN9.17 R492.1 U11.17(GP63/SINA) U16.26(R3OUT)
COM1_SD: R482.2 U16.25(S\D\)
COM1_T4IN: R484.2 U16.21(T4IN)
COM1_T4OUT: R481.2 U16.28(T4OUT)
COM1_TXD: CN7.16 CN9.16 R363.2 R391.1 U11.18(GP62/SOUTA (FAN_SET)) U16.6(T2IN)
COM1_V1N: C298.2 U16.17(V-)
COM1_V1P: C548.2 U16.13(V+)
CPU_ALERT_N: R180.2 U6.AL4(ALERT_L)
CPU_CLKIN_SC_N: C85.2 R114.2 U6.B8(CLKIN_L)
CPU_CLKIN_SC_P: C86.2 R114.1 U6.A8(CLKIN_H)
CPU_CORE_TYPE: R18.1 R21.2 U6.G5(CORE_TYPE)
CPU_DBRDY: J3.9(5) U6.B6(DBRDY)
CPU_DBREQ_N: J3.7(4) R240.2 U6.A5(DBREQ_L)
CPU_FAN_PWM: R11.2 R15.1 U11.61(CPUFANOUT/GP94)
CPU_FAN_TACH: D1.A R10.1 U11.60(CPUFANIN/GP93)
CPU_HTREF0: R206.1 U6.V7(HTREF0)
CPU_HTREF1: R572.2 U6.V8(HTREF1)
CPU_M_VREF_SUS: C351.1 C352.1 R103.1 R537.2 U6.F12(M_VREF)
CPU_M_ZN: R184.2 U6.AH11(M_ZN)
CPU_M_ZP: R185.2 U6.AJ11(M_ZP)
CPU_MEMHOT_N: Q8.C Q9.C Q29.C U10.J2(PCI_PME#/GEVENT4#)
CPU_PRESENT_N: R182.2 R662.1 R692.1 U6.AL3(CPU_PRESENT_L)
CPU_PRESENT_R_N: R662.2 U10.AB21(SMARTVOLT1/SATA_IS2#/GPIO50)
CPU_PROCHOT_1.5_N: R207.2 U10.H21(PROCHOT#)
CPU_PROCHOT_1.5_R_N: R207.1 R574.2 U6.AL7(PROCHOT_L)
CPU_PSI_N: TP122.1 U6.F1(PSI_L)
CPU_PWRGD: C426.1 J3.5(3) R222.1 R576.2 U6.C9(PWROK) U10.K19(LDT_PG)
CPU_SIC: R193.2 U6.AL6(SIC)
CPU_SID: R183.2 U6.AK6(SID)
CPU_SVC: PU2.39(SVC/VID3) R5.1 R522.2 U6.C1(SVC/VID3)
CPU_SVD: PU2.40(SVD/VID2) R17.2 R523.2 U6.E3(SVD/VID2)
CPU_TCK: J3.11(6) U6.AH10(TCK)
CPU_TDI: J3.15(8) U6.AL10(TDI)
CPU_TDO: J3.19(10) U6.AK10(TDO)
CPU_TEST2: TP193.1 U6.AJ6(TEST2)
CPU_TEST3: TP178.1 U6.AH7(TEST3)
CPU_TEST6: TP92.1 U6.AJ5(TEST6)
CPU_TEST7: TP121.1 U6.E5(TEST7)
CPU_TEST8_DIG_T: TP120.1 U6.D4(TEST8)
CPU_TEST10_ANALOGOUT: TP128.1 U6.G7(TEST10)
CPU_TEST12: TP194.1 U6.AH9(TEST12)
CPU_TEST14: TP115.1 U6.C5(TEST14)
CPU_TEST15: TP124.1 U6.F8(TEST15)
CPU_TEST16: TP117.1 U6.E7(TEST16)
CPU_TEST17: TP112.1 U6.D6(TEST17)
CPU_TEST18: TP119.1 U6.E9(TEST18)
CPU_TEST19: TP113.1 U6.F10(TEST19)
CPU_TEST20: TP91.1 U6.AJ8(TEST20)
CPU_TEST21_SCANEN: R208.1 U6.AL8(TEST21)
CPU_TEST22_SCANSHIFTEN: R214.1 U6.AJ9(TEST22)
CPU_TEST23_TSTUPD: TP191.1 U6.AH8(TEST23)
CPU_TEST24: TP94.1 U6.AK8(TEST24)
CPU_TEST25_H_BYPASSCLK_H: R111.2 U6.A10(TEST25_H)
CPU_TEST25_H_BYPASSCLK_L: R110.2 U6.B10(TEST25_L)
CPU_TEST26_BURNIN_L: TP90.1 U6.AK5(TEST26)
CPU_TEST27_SINGLECHAIN: R215.1 TP83.1 U6.AK9(TEST27)
CPU_TEST28_H_PLLCHRZ_H: TP125.1 U6.J10(TEST28_H)
CPU_TEST28_L_PLLCHRZ_L: TP123.1 U6.H9(TEST28_L)
CPU_TEST29_H_FBCLKOUT_H: R534.1 TP110.1 U6.C11(TEST29_H)
CPU_TEST29_L_FBCLKOUT_L: R534.2 TP108.1 U6.D11(TEST29_L)
CPU_THERMDA: C291.1 C293.1 R211.2 R413.1
CPU_THERMDA_R: R211.1 U6.AG8(THERMDA)
CPU_THERMDC: R210.2 R458.1
CPU_THERMDC_R: R210.1 U6.AG9(THERMDC)
CPU_THERMTRIP_L: Q608.S R201.2 U6.AK7(THERMTRIP_L)
CPU_THERMTRIP_N: R204.2 R205.2 U10.J6(THRMTRIP#/SMBALERT#/GEVENT2#)
CPU_THERMTRIP_R_N: Q608.D R204.1
CPU_TMS: J3.13(7) U6.AL9(TMS)
CPU_TRST_N: J3.17(9) U6.AJ10(TRST_L)
CPU_VCORE: C360.1 C361.1 C364.1 C365.1 C366.1 C376.1 C385.1 C387.1 C405.1 C415.1 C416.1 L6.2 L10.2 PC47.1 PC48.1 PC49.1 PC50.1 PC51.1 PC125.1 PC126.1 PC127.1 PC128.1 PC129.1 PC130.1 PC131.1 PC132.1 PC133.1 PC134.1 PC135.1 PC136.1 PR67.2 PU2.15(VDD_CS2) PU2.16(VDD_CS2N) PU2.19(VDD_CS4) PU2.20(VDD_CS4N) R45.2 R46.2 R318.1 R437.1 U6.AA8(VDD_128) U6.AA10(VDD_129) U6.AA12(VDD_130) U6.AA14(VDD_131) U6.AA16(VDD_132) U6.AA18(VDD_133) U6.AA20(VDD_134) U6.AA22(VDD_135) U6.AB7(VDD_136) U6.AB9(VDD_137) U6.AB11(VDD_138) U6.AB13(VDD_139) U6.AB15(VDD_140) U6.AB17(VDD_141) U6.AB19(VDD_142) U6.AB21(VDD_143) U6.AB23(VDD_144) U6.AC4(VDD_145) U6.AC5(VDD_146) U6.AC8(VDD_147) U6.AC10(VDD_148) U6.AC12(VDD_149) U6.AC14(VDD_150) U6.AC16(VDD_151) U6.AC18(VDD_152) U6.AC20(VDD_153) U6.AC22(VDD_154) U6.AD2(VDD_155) U6.AD3(VDD_156) U6.AD7(VDD_157) U6.AD9(VDD_158) U6.AD11(VDD_159) U6.AD23(VDD_160) U6.AE10(VDD_161) U6.AE12(VDD_162) U6.AF7(VDD_163) U6.AF9(VDD_164) U6.AF11(VDD_165) U6.AG4(VDD_166) U6.AG5(VDD_167) U6.AG7(VDD_168) U6.AH2(VDD_169) U6.AH3(VDD_170) U6.B3(VDD_1) U6.C2(VDD_2) U6.C4(VDD_3) U6.D3(VDD_4) U6.D5(VDD_5) U6.E4(VDD_6) U6.E6(VDD_7) U6.F5(VDD_8) U6.F7(VDD_9) U6.G6(VDD_10) U6.G8(VDD_11) U6.H7(VDD_12) U6.H11(VDD_13) U6.H23(VDD_14) U6.J8(VDD_15) U6.J12(VDD_16) U6.J14(VDD_17) U6.J16(VDD_18) U6.J18(VDD_19) U6.J20(VDD_20) U6.J22(VDD_21) U6.J24(VDD_22) U6.K7(VDD_23) U6.K9(VDD_24) U6.K11(VDD_25) U6.K13(VDD_26) U6.K15(VDD_27) U6.K17(VDD_28) U6.K19(VDD_29) U6.K21(VDD_30) U6.K23(VDD_31) U6.L4(VDD_32) U6.L5(VDD_33) U6.L8(VDD_34) U6.L10(VDD_35) U6.L12(VDD_36) U6.L14(VDD_37) U6.L16(VDD_38) U6.L18(VDD_39) U6.L20(VDD_40) U6.L22(VDD_41) U6.M2(VDD_42) U6.M3(VDD_43) U6.M7(VDD_44) U6.M9(VDD_45) U6.M11(VDD_46) U6.M13(VDD_47) U6.M15(VDD_48) U6.M17(VDD_49) U6.M19(VDD_50) U6.M21(VDD_51) U6.M23(VDD_52) U6.N8(VDD_53) U6.N10(VDD_54) U6.N12(VDD_55) U6.N14(VDD_56) U6.N16(VDD_57) U6.N18(VDD_58) U6.N20(VDD_59) U6.N22(VDD_60) U6.P7(VDD_61) U6.P9(VDD_62) U6.P11(VDD_63) U6.P13(VDD_64) U6.P15(VDD_65) U6.P17(VDD_66) U6.P19(VDD_67) U6.P21(VDD_68) U6.P23(VDD_69) U6.R4(VDD_70) U6.R5(VDD_71) U6.R8(VDD_72) U6.R10(VDD_73) U6.R12(VDD_74) U6.R14(VDD_75) U6.R16(VDD_76) U6.R18(VDD_77) U6.R20(VDD_78) U6.R22(VDD_79) U6.T2(VDD_80) U6.T3(VDD_81) U6.T7(VDD_82) U6.T9(VDD_83) U6.T11(VDD_84) U6.T13(VDD_85) U6.T15(VDD_86) U6.T17(VDD_87) U6.T19(VDD_88) U6.T21(VDD_89) U6.T23(VDD_90) U6.U8(VDD_91) U6.U10(VDD_92) U6.U12(VDD_93) U6.U14(VDD_94) U6.U16(VDD_95) U6.U18(VDD_96) U6.U20(VDD_97) U6.U22(VDD_98) U6.V9(VDD_99) U6.V11(VDD_100) U6.V13(VDD_101) U6.V15(VDD_102) U6.V17(VDD_103) U6.V19(VDD_104) U6.V21(VDD_105) U6.V23(VDD_106) U6.W4(VDD_107) U6.W5(VDD_108) U6.W8(VDD_109) U6.W10(VDD_110) U6.W12(VDD_111) U6.W14(VDD_112) U6.W16(VDD_113) U6.W18(VDD_114) U6.W20(VDD_115) U6.W22(VDD_116) U6.Y2(VDD_117) U6.Y3(VDD_118) U6.Y7(VDD_119) U6.Y9(VDD_120) U6.Y11(VDD_121) U6.Y13(VDD_122) U6.Y15(VDD_123) U6.Y17(VDD_124) U6.Y19(VDD_125) U6.Y21(VDD_126) U6.Y23(VDD_127)
CPU_VDD_FB_H: PR22.1 PR67.1 U6.G2(VDD_FB_H)
CPU_VDD_FB_L: PR15.1 PU2.7(VDD_VS-) U6.G1(VDD_FB_L)
CPU_VDDA_RUN_OUT: C6.1 C20.1 L2.1 R25.2 U1.1(VOUT#1) U1.2(VOUT#2) U1.3(VOUT#3)
CPU_VDDIO_FB_H: TP88.1 U6.AK11(VDDIO_FB_H)
CPU_VDDIO_FB_L: TP85.1 U6.AL11(VDDIO_FB_L)
CPU_VDDNB_RUN_FB_H: PR17.1 PR65.1 U6.G4(VDDNB_FB_H)
CPU_VDDNB_RUN_FB_L: PR25.1 PU2.30(NB_VS-) U6.G3(VDDNB_FB_L)
CPU_VDDR_SUS_SENSE: TP118.1 U6.E12(VDDR_SENSE)
CTSA: L72.1 U16.23(R4IN)
CTSA_L: C340.1 J6.8 L72.2
DAC_RSET: R546.2 U3.G14(DAC_RSET(PWM_GPIO1))
DBGSELECT2: R270.1 R271.1 U10.AF26(FC_FBCLKIN)
DCDA: L75.1 U16.9(R1IN)
DCDA_L: C335.1 J6.1 L75.2
DCIN: C309.1 C322.1 C324.1 C551.1 CN24.1(1+) D13.C R761.1 U17.1(S_0) U17.2(S_1) U17.3(S_2)
DDC_CLK0: CN7.13 R139.2 U3.A8(DDC_CLK0/AUX0P(NC))
DDC_CLK1: TP47.1 U3.B7(DDC_CLK1/AUX1P(NC))
DDC_DATA0: CN7.14 R141.2 U3.B8(DDC_DATA0/AUX0N(NC))
DDC_DATA1: TP44.1 U3.A7(DDC_DATA1/AUX1N(NC))
DDR3_P1V5_CS: PR37.1 PU3.16(CS)
DDR3_P1V5_DH: PR24.1 PU3.21(UGATE)
DDR3_P1V5_DL: PQ2.G1(4) PU3.19(LGATE)
DDR3_P1V5_EN_S3: PR11.2 PR87.1 PU3.10(S3)
DDR3_P1V5_EN_S5: PR14.2 PR29.1 PU3.11(S5)
DDR3_P1V5_FILT: PC30.1 PR19.2 PR37.2 PU3.6(DEM) PU3.14(VDD)
DDR3_P1V5_LL: PL2.1 PQ1.S1(1) PQ1.S2(2) PQ1.S3(3) PQ2.D(5) PR26.2 PR68.1 PR72.2 PU3.20(PHASE)
DDR3_P1V5_SET: PC5.1 PR2.1 PR27.2 PU3.9(FB)
DDR3_P1V5_VBST: PC19.1 PU3.22(BOOT)
DDRQ0_N: R635.1 U10.J25(LDRQ0#)
DDRQ1_N: R284.1 U10.AA18(LDRQ1#/CLK_REQ6#/GPIO49)
DDSPC_HPD: Q96.D R57.2 R771.1
DP_A_HPD: CN1.276(DP_A_HPD) R66.1
DP_B_HPD: CN1.274(DP_B_HPD) R67.1
DP_D_HPD: CN1.236(DP_D_HPD) R56.1
DRV_P0_ENABLE: PU2.43(VDD_DRVON) R53.1 R54.1
DSRA: L76.1 U16.4(R2IN)
DSRA_L: C338.1 J6.6 L76.2
DTRA: L79.1 U16.1(T3OUT)
DTRA_L: C336.1 J6.4 L79.2
EAPD_MUTE_CTRL: R414.1 U26.2(B)
EAR_L_FIL: C490.1 CN20.2(PIN2) D14.2 L59.2
EAR_R_FIL: C491.1 CN20.3(PIN3) D14.1 L61.2
EC_A20M_N: R649.1 U10.AD21(GA20IN/GEVENT0#) U11.11(GA20M)
EECS_LAN: R720.2 U24.30(EECS/SCL)
EEDI: R719.2 U24.32(EEDI/SDA)
EEDO_LED3: R489.2 U24.31(LED3/EEDO)
EEDO_LED3_R: CN23.L4 R489.1 R510.2
EESK_LED1: R509.2 U24.37(LED1/EESK)
EESK_LED1_R: C313.1 CN23.L3 R490.2 R509.1
EN_LAN_SW: R707.1 R708.1 U24.33(ENSWREG)
ENABKL: CN27.7 R312.2 R704.1
ENABKL_R: Q22.S R312.1 R343.2 R355.1 R357.1
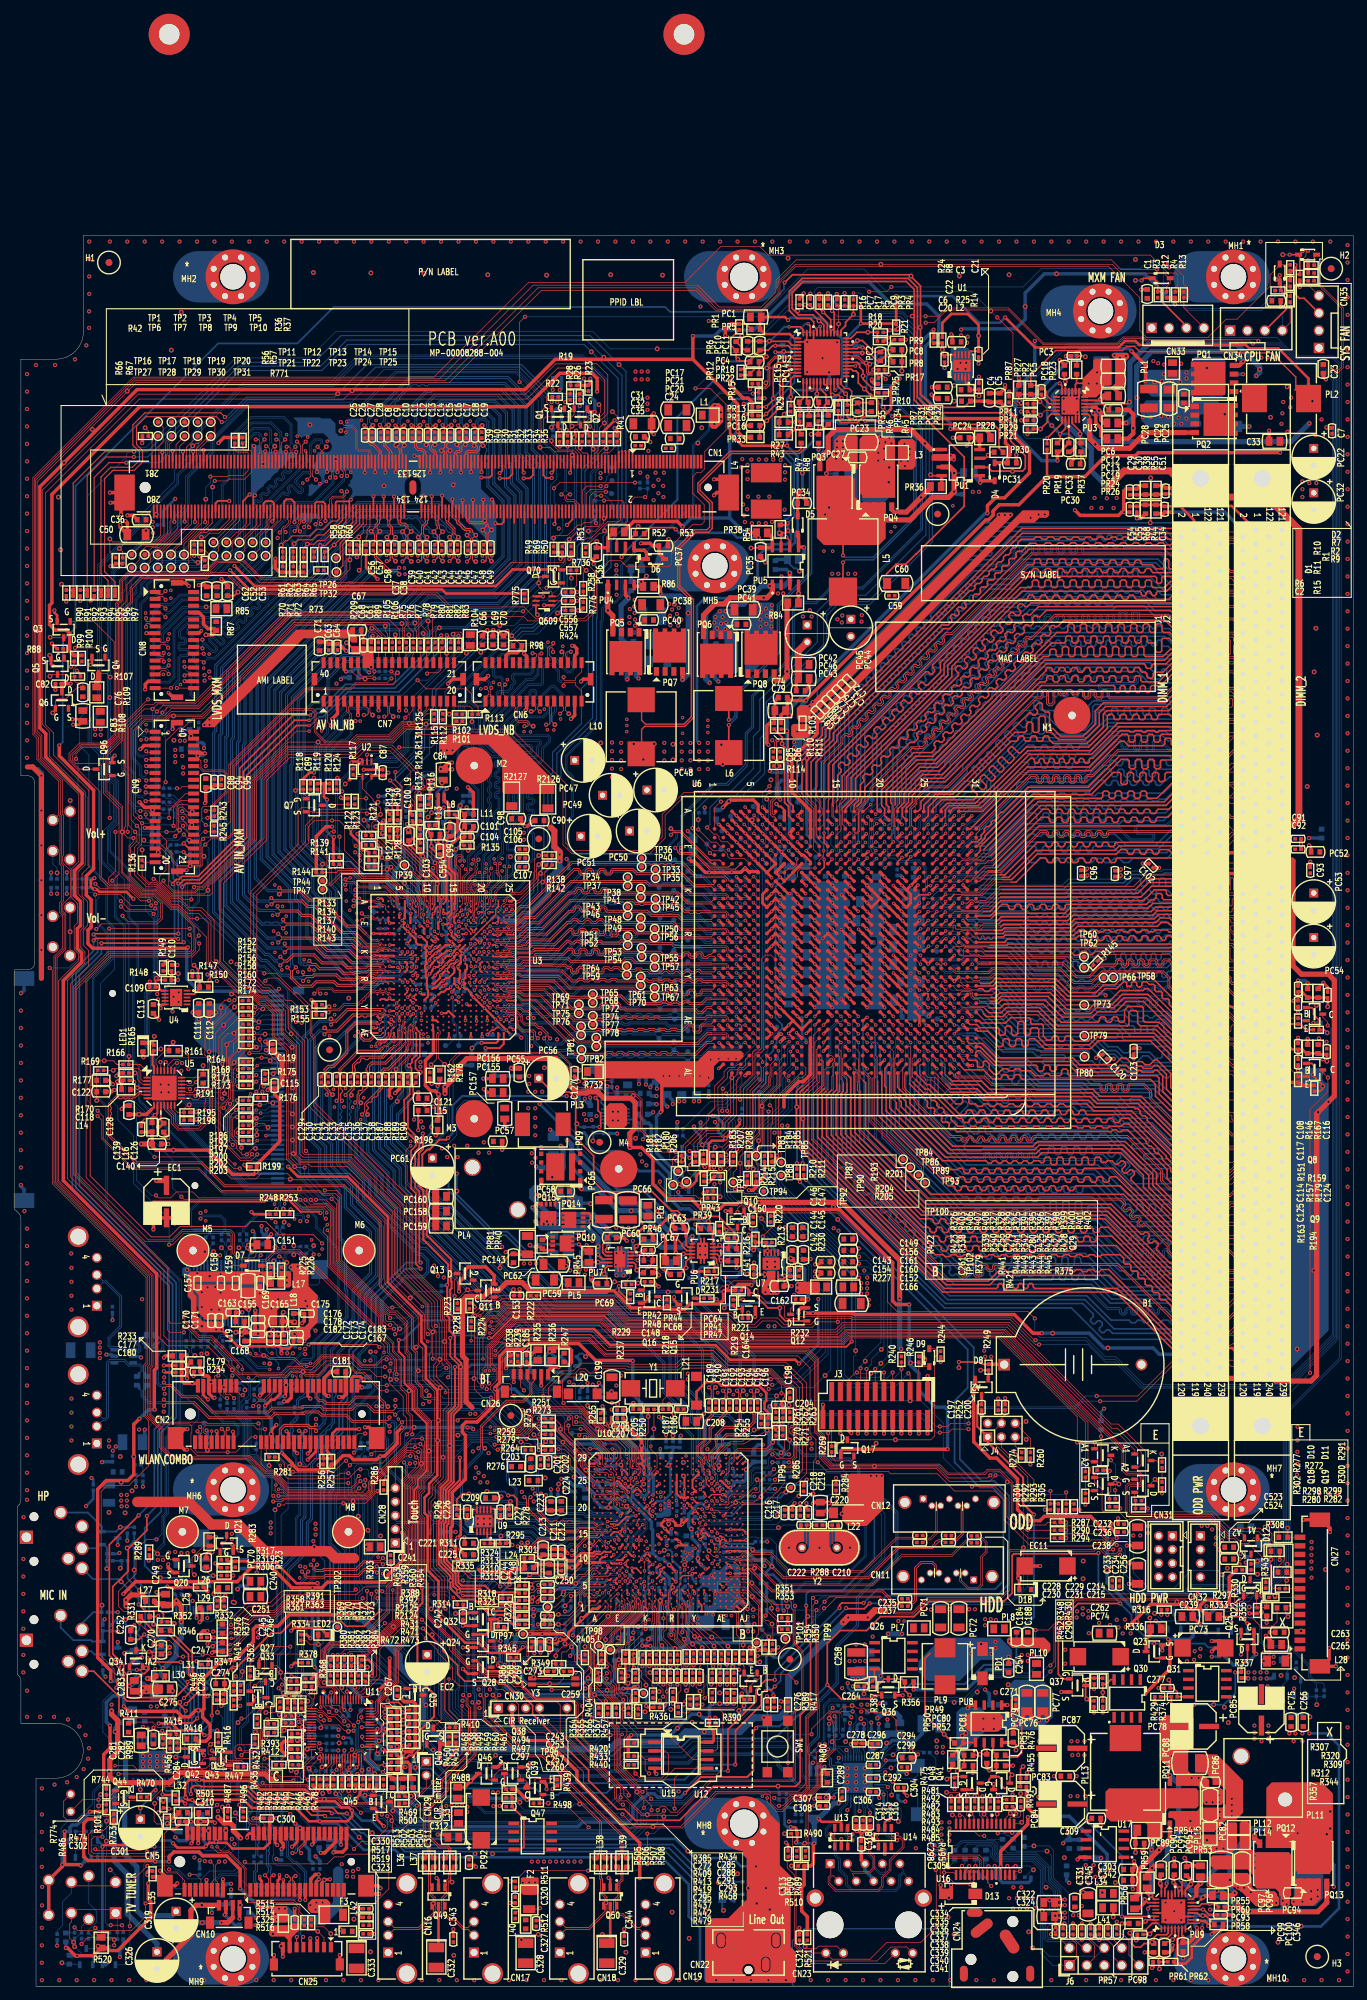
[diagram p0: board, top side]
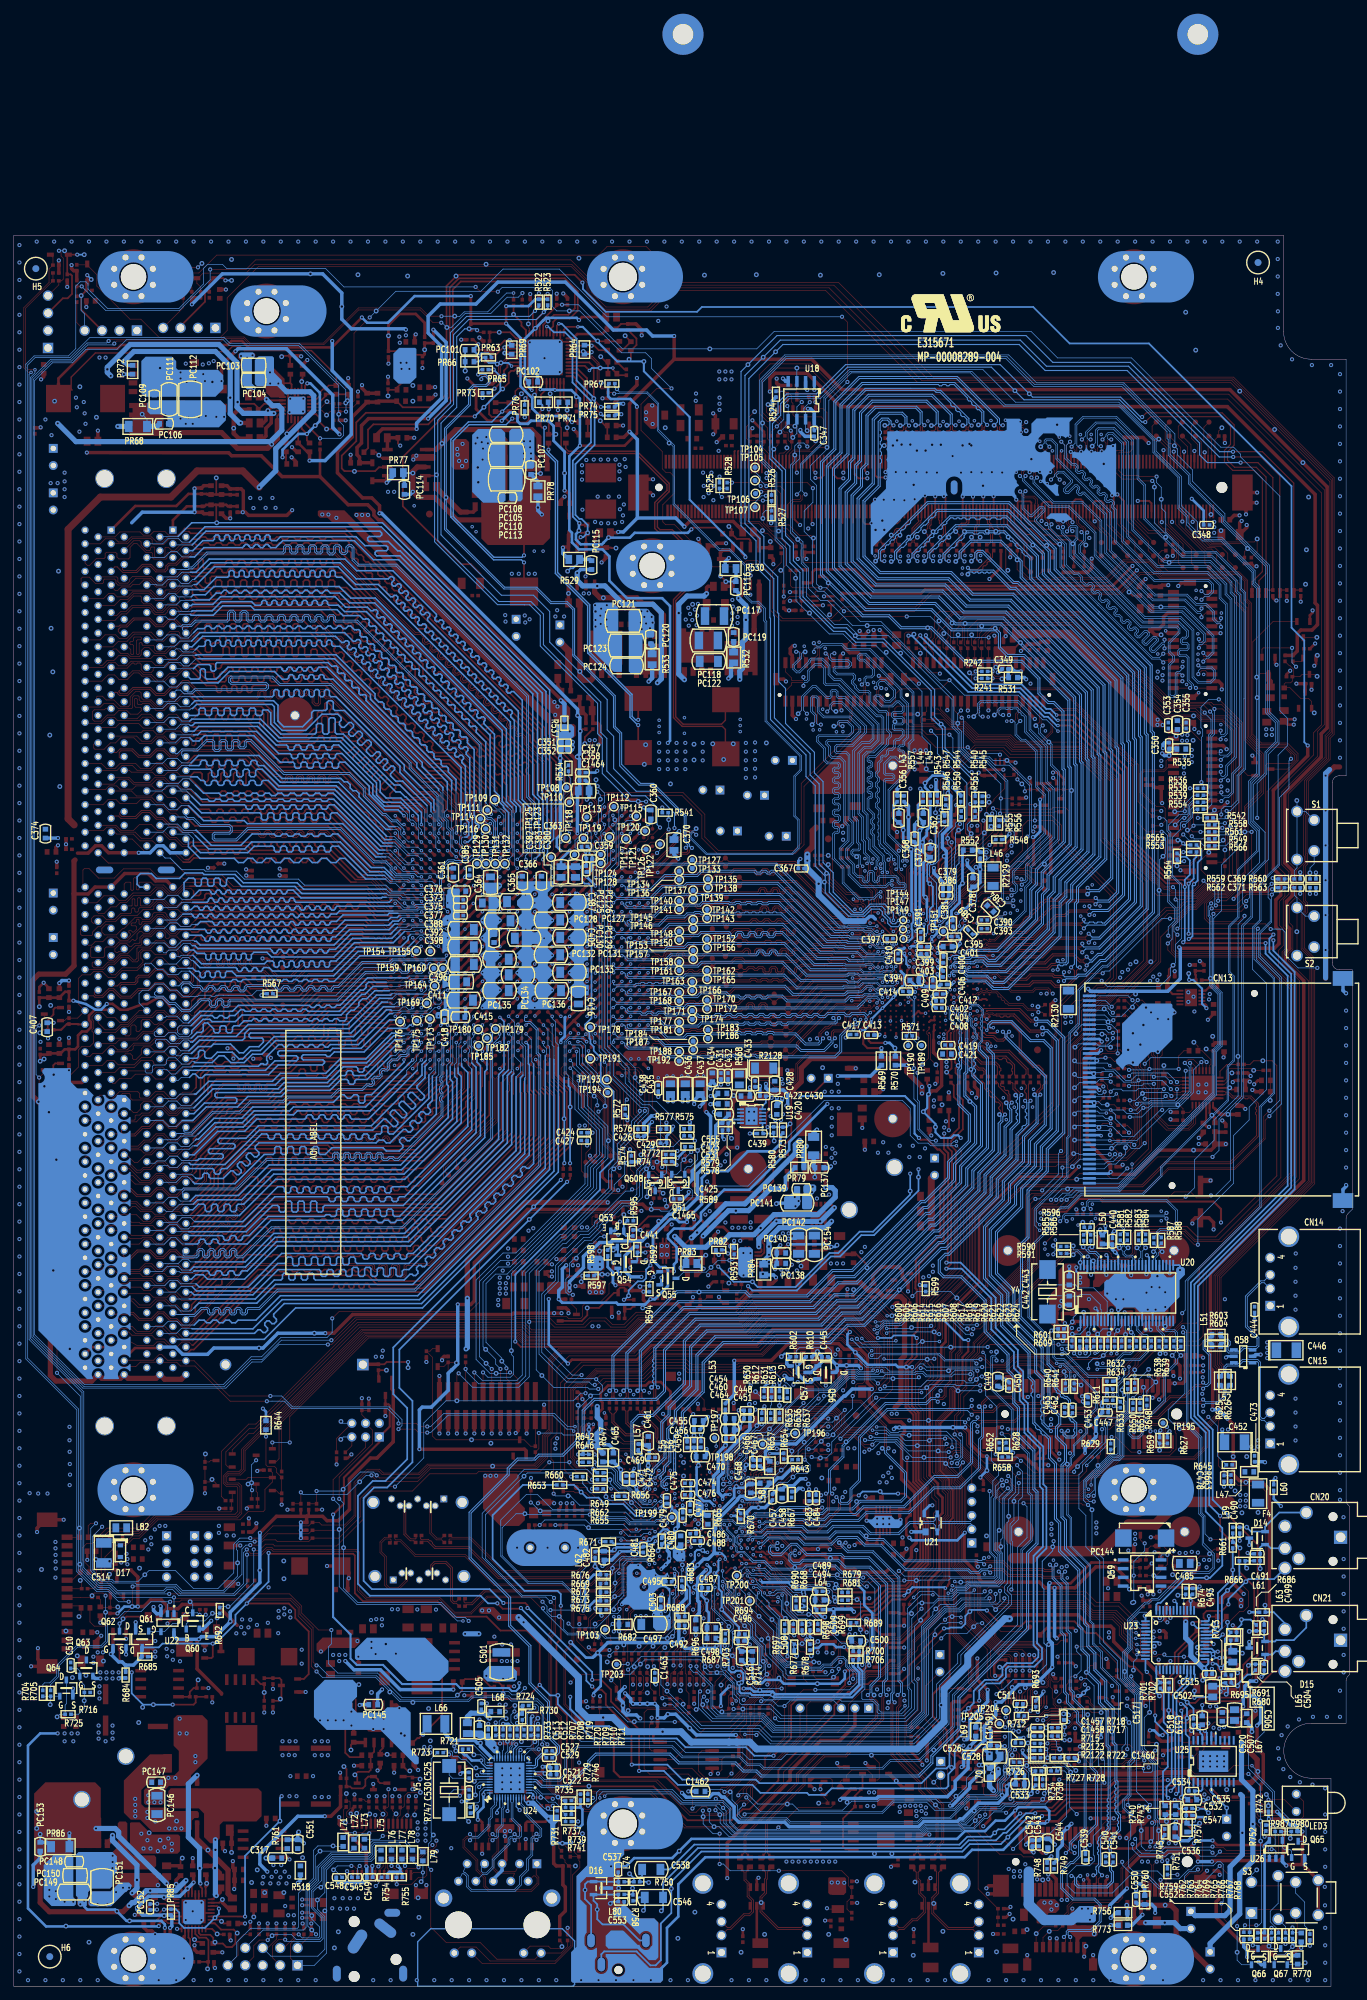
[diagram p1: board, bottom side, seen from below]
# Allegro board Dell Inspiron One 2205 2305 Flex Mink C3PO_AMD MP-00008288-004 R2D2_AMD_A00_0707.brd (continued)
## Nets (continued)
EXT_PCIE_LAN_CLKREQ_N: R735.2 R737.2 U24.16(CLKREQB)
FC_CLK_R: R263.1 U10.AH28(FC_CLK)
FC_FBCLKOUT_R: R261.1 R262.1 U10.AG28(FC_FBCLKOUT)
FP_RST_N: C276.1 R367.1 R389.2 SW1.1(A) SW1.2(A1)
FP_RST_R_N: R367.2 U10.J1(SYS_RESET#/GEVENT19#)
GBE_COL: R325.2 U10.T1(GBE_COL)
GBE_CRS: R341.2 U10.T4(GBE_CRS)
GBE_LED1: TP96.1 U10.D7(GBE_LED1/GEVENT9#)
GBE_LED2: TP200.1 U10.G5(GBE_LED2/GEVENT10#)
GBE_MDIO: R703.1 U10.L5(GBE_MDIO)
GBE_PHY_INTR: R683.1 U10.V7(GBE_PHY_INTR)
GBE_RXERR: R342.2 U10.V5(GBE_RXERR)
GBE_SATA0: TP102.1 U10.K3(GBE_STAT0/GEVENT11#)
GFX_CLK_DN: CN1.153(PEX_REFCLK#) R584.2
GFX_CLK_DP: CN1.155(PEX_REFCLK) R583.2
GFX_CLK_R_DN: R584.1 U20.38(ATIG1C_LPRS)
GFX_CLK_R_DP: R583.1 U20.39(ATIG1T_LPRS)
GFX_TX8N_C: C57.1 U3.H2(GFX_TX8N)
GFX_TX8P_C: C56.1 U3.H1(GFX_TX8P)
GFX_TX9N_C: C37.1 U3.J1(GFX_TX9N)
GFX_TX9P_C: C58.1 U3.J2(GFX_TX9P)
GFX_TX10N_C: C39.1 U3.K3(GFX_TX10N)
GFX_TX10P_C: C38.1 U3.K4(GFX_TX10P)
GFX_TX11N_C: C41.1 U3.K2(GFX_TX11N)
GFX_TX11P_C: C40.1 U3.K1(GFX_TX11P)
GFX_TX12N_C: C43.1 U3.M3(GFX_TX12N)
GFX_TX12P_C: C42.1 U3.M4(GFX_TX12P)
GFX_TX13N_C: C45.1 U3.M2(GFX_TX13N)
GFX_TX13P_C: C44.1 U3.M1(GFX_TX13P)
GFX_TX14N_C: C47.1 U3.N1(GFX_TX14N)
GFX_TX14P_C: C46.1 U3.N2(GFX_TX14P)
GFX_TX15N_C: C49.1 U3.P2(GFX_TX15N)
GFX_TX15P_C: C48.1 U3.P1(GFX_TX15P)
GPIO33: TP103.1 U10.AG6(INTF#/GPIO33)
GPIO170: R450.2 R451.2 U10.M4(AZ_SDIN3/GPIO170)
GPIO196: R654.1 U10.E26(SDA3_LV/GPIO196)
GPIO199: R259.2 R275.1 U10.F22(EC_PWM2/EC_TIMER2/GPIO199)
GPIO200: R264.2 R279.1 U10.E21(EC_PWM3/EC_TIMER3/GPIO200)
GPIO206: TP202.1 U10.D28(KSI_5/GPIO206)
GPIO207: TP198.1 U10.C29(KSI_6/GPIO207)
GPIO208: TP196.1 U10.C28(KSI_7/GPIO208)
GPIO208_MXM_R: CN9.20 R136.2
GPIO208_NB_N: CN7.20 R113.2
GPON7: R165.2 U5.28(GPON7)
GPP_TX0N_C: C130.1 U3.AC2(GPP_TX0N)
GPP_TX0P_C: C129.1 U3.AC1(GPP_TX0P)
GPP_TX1N_C: C540.1 U3.AB3(GPP_TX1N)
GPP_TX1P_C: C541.1 U3.AB4(GPP_TX1P)
GPP_TX2N_C: C462.1 U3.AA1(GPP_TX2N)
GPP_TX2P_C: C463.1 U3.AA2(GPP_TX2P)
HDA_SPKR: R653.1 U10.AF19(SPKR/GPIO66)
HDT_RST#_OUT: D9.C J3.3(2) R246.1
HP_L: R661.1 U23.33(HPOUT-L(PORT-I-L))
HP_R: R666.1 U23.32(HPOUT-R(PORT-I-R))
HP_SENSE: CN20.5(PIN5) R352.1
HPD: R121.1 U3.D10(HPD(NC))
HSYNC: CN1.164(VGA_HSYNC) R64.1 R64.2
HSYNC_N: R96.1 R96.2 R127.2 R129.1 U3.A11(DAC_HSYNC(PWM_GPIO4))
HT_CADIN0_N: TP40.1 U3.D25(HT_TXCAD0N) U6.J2(L0_CADIN_L0)
HT_CADIN0_P: TP36.1 U3.D24(HT_TXCAD0P) U6.J3(L0_CADIN_H0)
HT_CADIN1_N: TP35.1 U3.E25(HT_TXCAD1N) U6.K1(L0_CADIN_L1)
HT_CADIN1_P: TP33.1 U3.E24(HT_TXCAD1P) U6.J1(L0_CADIN_H1)
HT_CADIN2_N: TP37.1 U3.F25(HT_TXCAD2N) U6.L2(L0_CADIN_L2)
HT_CADIN2_P: TP34.1 U3.F24(HT_TXCAD2P) U6.L3(L0_CADIN_H2)
HT_CADIN3_N: TP41.1 U3.F22(HT_TXCAD3N) U6.M1(L0_CADIN_L3)
HT_CADIN3_P: TP38.1 U3.F23(HT_TXCAD3P) U6.L1(L0_CADIN_H3)
HT_CADIN4_N: TP46.1 U3.H22(HT_TXCAD4N) U6.P1(L0_CADIN_L4)
HT_CADIN4_P: TP43.1 U3.H23(HT_TXCAD4P) U6.N1(L0_CADIN_H4)
HT_CADIN5_N: TP49.1 U3.J24(HT_TXCAD5N) U6.R2(L0_CADIN_L5)
HT_CADIN5_P: TP48.1 U3.J25(HT_TXCAD5P) U6.R3(L0_CADIN_H5)
HT_CADIN6_N: TP56.1 U3.K25(HT_TXCAD6N) U6.T1(L0_CADIN_L6)
HT_CADIN6_P: TP50.1 U3.K24(HT_TXCAD6P) U6.R1(L0_CADIN_H6)
HT_CADIN7_N: TP52.1 U3.K22(HT_TXCAD7N) U6.U2(L0_CADIN_L7)
HT_CADIN7_P: TP51.1 U3.K23(HT_TXCAD7P) U6.U3(L0_CADIN_H7)
HT_CADIN8_N: TP133.1 U3.G21(HT_TXCAD8N) U6.K6(L0_CADIN_L8)
HT_CADIN8_P: TP127.1 U3.F21(HT_TXCAD8P) U6.J6(L0_CADIN_H8)
HT_CADIN9_N: TP136.1 U3.H21(HT_TXCAD9N) U6.K5(L0_CADIN_L9)
HT_CADIN9_P: TP134.1 U3.G20(HT_TXCAD9P) U6.K4(L0_CADIN_H9)
HT_CADIN10_N: TP138.1 U3.J21(HT_TXCAD10N) U6.M6(L0_CADIN_L10)
HT_CADIN10_P: TP135.1 U3.J20(HT_TXCAD10P) U6.L6(L0_CADIN_H10)
HT_CADIN11_N: TP139.1 U3.K17(HT_TXCAD11N) U6.M5(L0_CADIN_L11)
HT_CADIN11_P: TP137.1 U3.J18(HT_TXCAD11P) U6.M4(L0_CADIN_H11)
HT_CADIN12_N: TP143.1 U3.J19(HT_TXCAD12N) U6.P5(L0_CADIN_L12)
HT_CADIN12_P: TP142.1 U3.L19(HT_TXCAD12P) U6.P4(L0_CADIN_H12)
HT_CADIN13_N: TP146.1 U3.L18(HT_TXCAD13N) U6.T6(L0_CADIN_L13)
HT_CADIN13_P: TP145.1 U3.M19(HT_TXCAD13P) U6.R6(L0_CADIN_H13)
HT_CADIN14_N: TP150.1 U3.P21(HT_TXCAD14N) U6.T5(L0_CADIN_L14)
HT_CADIN14_P: TP148.1 U3.M21(HT_TXCAD14P) U6.T4(L0_CADIN_H14)
HT_CADIN15_N: TP156.1 U3.M18(HT_TXCAD15N) U6.V6(L0_CADIN_L15)
HT_CADIN15_P: TP152.1 U3.P18(HT_TXCAD15P) U6.U6(L0_CADIN_H15)
HT_CADOUT0_N: TP81.1 U3.Y24(HT_RXCAD0N) U6.AG1(L0_CADOUT_L0)
HT_CADOUT0_P: TP82.1 U3.Y25(HT_RXCAD0P) U6.AH1(L0_CADOUT_H0)
HT_CADOUT1_N: TP77.1 U3.V23(HT_RXCAD1N) U6.AG3(L0_CADOUT_L1)
HT_CADOUT1_P: TP78.1 U3.V22(HT_RXCAD1P) U6.AG2(L0_CADOUT_H1)
HT_CADOUT2_N: TP75.1 U3.V24(HT_RXCAD2N) U6.AE1(L0_CADOUT_L2)
HT_CADOUT2_P: TP76.1 U3.V25(HT_RXCAD2P) U6.AF1(L0_CADOUT_H2)
HT_CADOUT3_N: TP72.1 U3.U25(HT_RXCAD3N) U6.AE3(L0_CADOUT_L3)
HT_CADOUT3_P: TP74.1 U3.U24(HT_RXCAD3P) U6.AE2(L0_CADOUT_H3)
HT_CADOUT4_N: TP65.1 U3.T24(HT_RXCAD4N) U6.AC3(L0_CADOUT_L4)
HT_CADOUT4_P: TP68.1 U3.T25(HT_RXCAD4P) U6.AC2(L0_CADOUT_H4)
HT_CADOUT5_N: TP63.1 U3.P23(HT_RXCAD5N) U6.AA1(L0_CADOUT_L5)
HT_CADOUT5_P: TP67.1 U3.P22(HT_RXCAD5P) U6.AB1(L0_CADOUT_H5)
HT_CADOUT6_N: TP61.1 U3.P24(HT_RXCAD6N) U6.AA3(L0_CADOUT_L6)
HT_CADOUT6_P: TP70.1 U3.P25(HT_RXCAD6P) U6.AA2(L0_CADOUT_H6)
HT_CADOUT7_N: TP64.1 U3.N25(HT_RXCAD7N) U6.W1(L0_CADOUT_L7)
HT_CADOUT7_P: TP59.1 U3.N24(HT_RXCAD7P) U6.Y1(L0_CADOUT_H7)
HT_CADOUT8_N: TP188.1 U3.AC25(HT_RXCAD8N) U6.AH4(L0_CADOUT_L8)
HT_CADOUT8_P: TP192.1 U3.AC24(HT_RXCAD8P) U6.AH5(L0_CADOUT_H8)
HT_CADOUT9_N: TP184.1 U3.AB24(HT_RXCAD9N) U6.AG6(L0_CADOUT_L9)
HT_CADOUT9_P: TP187.1 U3.AB25(HT_RXCAD9P) U6.AH6(L0_CADOUT_H9)
HT_CADOUT10_N: TP183.1 U3.AA25(HT_RXCAD10N) U6.AF4(L0_CADOUT_L10)
HT_CADOUT10_P: TP186.1 U3.AA24(HT_RXCAD10P) U6.AF5(L0_CADOUT_H10)
HT_CADOUT11_N: TP177.1 U3.Y23(HT_RXCAD11N) U6.AE6(L0_CADOUT_L11)
HT_CADOUT11_P: TP181.1 U3.Y22(HT_RXCAD11P) U6.AF6(L0_CADOUT_H11)
HT_CADOUT12_N: TP170.1 U3.W20(HT_RXCAD12N) U6.AC6(L0_CADOUT_L12)
HT_CADOUT12_P: TP172.1 U3.W21(HT_RXCAD12P) U6.AD6(L0_CADOUT_H12)
HT_CADOUT13_N: TP167.1 U3.V20(HT_RXCAD13N) U6.AB4(L0_CADOUT_L13)
HT_CADOUT13_P: TP168.1 U3.V21(HT_RXCAD13P) U6.AB5(L0_CADOUT_H13)
HT_CADOUT14_N: TP163.1 U3.U21(HT_RXCAD14N) U6.AA6(L0_CADOUT_L14)
HT_CADOUT14_P: TP166.1 U3.U20(HT_RXCAD14P) U6.AB6(L0_CADOUT_H14)
HT_CADOUT15_N: TP162.1 U3.U18(HT_RXCAD15N) U6.Y4(L0_CADOUT_L15)
HT_CADOUT15_P: TP165.1 U3.U19(HT_RXCAD15P) U6.Y5(L0_CADOUT_H15)
HT_CLKIN0_N: TP45.1 U3.H25(HT_TXCLK0N) U6.N2(L0_CLKIN_L0)
HT_CLKIN0_P: TP42.1 U3.H24(HT_TXCLK0P) U6.N3(L0_CLKIN_H0)
HT_CLKIN1_N: TP141.1 U3.L20(HT_TXCLK1N) U6.P6(L0_CLKIN_L1)
HT_CLKIN1_P: TP140.1 U3.L21(HT_TXCLK1P) U6.N6(L0_CLKIN_H1)
HT_CLKOUT0_N: TP69.1 U3.T23(HT_RXCLK0N) U6.AC1(L0_CLKOUT_L0)
HT_CLKOUT0_P: TP71.1 U3.T22(HT_RXCLK0P) U6.AD1(L0_CLKOUT_H0)
HT_CLKOUT1_N: TP171.1 U3.AA22(HT_RXCLK1N) U6.AD4(L0_CLKOUT_L1)
HT_CLKOUT1_P: TP174.1 U3.AB23(HT_RXCLK1P) U6.AD5(L0_CLKOUT_H1)
HT_CTLIN0_N: TP54.1 U3.M25(HT_TXCTL0N) U6.V1(L0_CTLIN_L0)
HT_CTLIN0_P: TP53.1 U3.M24(HT_TXCTL0P) U6.U1(L0_CTLIN_H0)
HT_CTLIN1_N: TP157.1 U3.R18(HT_TXCTL1N) U6.V5(L0_CTLIN_L1)
HT_CTLIN1_P: TP153.1 U3.P19(HT_TXCTL1P) U6.V4(L0_CTLIN_H1)
HT_CTLOUT0_N: TP55.1 U3.M23(HT_RXCTL0N) U6.W3(L0_CTLOUT_L0)
HT_CTLOUT0_P: TP57.1 U3.M22(HT_RXCTL0P) U6.W2(L0_CTLOUT_H0)
HT_CTLOUT1_N: TP158.1 U3.R20(HT_RXCTL1N) U6.W6(L0_CTLOUT_L1)
HT_CTLOUT1_P: TP161.1 U3.R21(HT_RXCTL1P) U6.Y6(L0_CTLOUT_H1)
HT_RXCALN: R138.1 U3.A24(HT_RXCALN)
HT_RXCALP: R138.2 U3.C23(HT_RXCALP)
HT_TXCALN: R142.2 U3.B25(HT_TXCALN)
HT_TXCALP: R142.1 U3.B24(HT_TXCALP)
I2C_CLK: R140.2 R143.2 U3.B9(I2C_CLK)
I2C_DATA: R134.2 R137.2 U3.A9(I2C_DATA)
INL: C535.1 R82.2 R553.2
INL_MXM_R: CN9.22 R553.1
INL_NB_R: CN7.22 R82.1
INR: C519.1 R81.2 R565.2
INR_MXM_R: CN9.23 R565.1
INR_NB_R: CN7.23 R81.1
INTR_ALERT_N: TP97.1 U10.B2(INTRUDER_ALERT#)
IOPLLVDD18(NC): R570.1 U3.AE23(IOPLLVDD18(NC))
IOPLLVDD(NC): R569.1 U3.AE24(IOPLLVDD(NC))
ISOLATEB_N: R710.1 R711.1 U24.26(ISOLATEB)
JDREF_AUD: R674.2 U23.40(JDREF)
KB_RST_N: U10.AE21(KBRST#/GEVENT1#) U11.12(KBRST#)
KBC_LOW_BAT_N: R404.1 U10.E1(IR_LED#/LLB#/GPIO184)
LAD0: R370.1 R380.2 R648.2 U10.J27(LAD0)
LAD0_R: CN2.8(UIM_PWR) R648.1
LAD1: R371.1 R381.2 R651.2 U10.J26(LAD1)
LAD1_R: CN2.10(UIM_DATA) R651.1
LAD2: R372.1 R382.2 R650.2 U10.H29(LAD2)
LAD2_R: CN2.12(UIM_CLK) R650.1
LAD3: R373.1 R383.2 R639.2 U10.H28(LAD3)
LAD3_R: CN2.14(UIM_RESET) R639.1
LAN_ACT_LED_N: R723.2 U24.40(LED0)
LAN_ACT_LED_R_N: C321.1 CN23.L1 R723.1
LAN_EVDD10: C521.1 C522.1 R480.2 U24.21(EVDD10)
LAN_MDI0_DN: CN23.2 U14.3 U24.2(MDIN0)
LAN_MDI0_DP: CN23.1 U14.4 U24.1(MDIP0)
LAN_MDI1_DN: CN23.4 U14.1 U24.5(MDIN1)
LAN_MDI1_DP: CN23.3 U14.6 U24.4(MDIP1)
LAN_MDI2_DN: CN23.8 U13.3 U24.8(MDIN2)
LAN_MDI2_DP: CN23.7 U13.4 U24.7(MDIP2)
LAN_MDI3_DN: CN23.10 U13.1 U24.11(MDIN3)
LAN_MDI3_DP: CN23.9 U13.6 U24.10(MDIP3)
LAN_REGOUT: L66.1 U24.36(REGOUT)
LAN_SMBALERT: R721.2 U24.38(GPO/SMBALERT)
LAN_VDD10: C278.1 C294.1 C299.1 C304.1 C307.1 C308.1 C314.1 C315.1 C316.1 L66.2 R480.1 U24.3(AVDD10_1) U24.6(AVDD10_2) U24.9(AVDD10_3) U24.13(DVDD10_1) U24.29(DVDD10_2) U24.41(DVDD10_3) U24.45(AVDD10_4)
LAN_XTAL1: C525.2 U24.43(CKXTAL1) Y5.1
LAN_XTAL2: C530.2 U24.44(CKXTAL2) Y5.2
LCDVCC: C63.1 C64.1 C71.1 C353.1 C354.1 C355.1 CN7.38 CN7.39 CN7.40 CN9.38 CN9.39 CN9.40 R85.1 R104.1 R108.2
LCDVCC_1: C76.2 C83.1 Q6.S R108.1 R109.1
LCDVCC_DISCHARGHE: Q4.D R109.2
LCDVCC_MXM: C52.1 C53.1 C62.1 CN8.28 CN8.29 CN8.30 R85.2 R87.1
LCDVCC_NB: C66.1 C69.1 C70.1 CN6.28 CN6.29 CN6.30 R98.1 R104.2
LDT_RST_D_N: D9.A J3.24(25) Q17.D R244.2 R269.1
LDT_RST_N: C425.1 Q7.S Q17.S R123.1 R269.2 R575.2 U6.C7(RESET_L) U10.J24(LDT_RST#)
LDT_STOP_N: C429.1 R577.2 U2.2(IN) U6.D8(LDTSTOP_L) U10.G22(LDT_STP#)
LED_AMBER_EN: R410.1 U10.D5(GBE_LED0/GPIO183)
LED_SATA_N: LED3.C(CATHODE) U10.AD11(SATA_ACT#/GPIO67)
LINE_L: C546.1 U23.23(LINE1-L(PORT-C-L))
LINE_L_FIL: C553.1 CN22.3 D16.2 L80.2
LINE_R: C538.1 U23.24(LINE1-R(PORT-C-R))
LINE_R_FIL: C537.1 CN22.6 D16.1 L74.2
LINE_SENSE: CN22.5 R701.2
LPC_CLK0: R612.2 R630.1 R636.2
LPC_CLK1: R613.2 R631.1 R637.2
LPC_LFRAME_N: R368.1 R369.1 R638.2 U10.G28(LFRAME#)
LPC_LFRAME_R_N: CN2.16(UIM_VPP) R638.1
LPC_SCI_N: R423.1 U10.K2(LPC_PME#/GEVENT3#)
LPC_SMI_N: R265.1 U10.J29(LPC_SMI#/GEVENT23#)
LVDDPWR_EN: Q3.G Q18.S R277.2 R302.1 R644.1
LVDDPWR_R_EN: D10.K R298.1
M704_1: C76.1 Q5.D Q6.G R100.2 R107.1
M_VDDIO_PWRGD: TP126.1 U6.F3(M_VDDIO_PWRGD)
MA1_CS_L0: TP164.1 U6.AA25(MA1_CS_L0)
MA1_CS_L1: TP173.1 U6.AD27(MA1_CS_L1)
MA1_ODT0: TP169.1 U6.AC27(MA1_ODT0)
MA1_ODT1: TP175.1 U6.AE27(MA1_ODT1)
MA_CLK_H0: TP130.1 U6.G20(MA_CLK_H0)
MA_CLK_H1: TP131.1 U6.G19(MA_CLK_H1)
MA_CLK_H3: TP159.1 U6.W26(MA_CLK_H3)
MA_CLK_H5: TP154.1 U6.U27(MA_CLK_H5)
MA_CLK_H6: TP180.1 U6.AE20(MA_CLK_H6)
MA_CLK_H7: TP185.1 U6.AG21(MA_CLK_H7)
MA_CLK_L0: TP129.1 U6.G21(MA_CLK_L0)
MA_CLK_L1: TP132.1 U6.H19(MA_CLK_L1)
MA_CLK_L3: TP160.1 U6.W25(MA_CLK_L3)
MA_CLK_L5: TP155.1 U6.U26(MA_CLK_L5)
MA_CLK_L6: TP179.1 U6.AE19(MA_CLK_L6)
MA_CLK_L7: TP182.1 U6.AG20(MA_CLK_L7)
MB1_CS_DT0: TP79.1 U6.AD31(MB1_ODT0)
MB1_CS_DT1: TP80.1 U6.AG31(MB1_ODT1)
MB1_CS_L0: TP73.1 U6.AB31(MB1_CS_L0)
MB1_CS_L1: TP176.1 U6.AE29(MB1_CS_L1)
MB_CLK_H0: TP114.1 U6.C19(MB_CLK_H0)
MB_CLK_H1: TP109.1 U6.A18(MB_CLK_H1)
MB_CLK_H3: TP66.1 U6.Y31(MB_CLK_H3)
MB_CLK_H5: TP60.1 U6.U31(MB_CLK_H5)
MB_CLK_H6: TP86.1 U6.AL19(MB_CLK_H6)
MB_CLK_H7: TP93.1 U6.AJ19(MB_CLK_H7)
MB_CLK_L0: TP116.1 U6.D19(MB_CLK_L0)
MB_CLK_L1: TP111.1 U6.A19(MB_CLK_L1)
MB_CLK_L3: TP58.1 U6.Y30(MB_CLK_L3)
MB_CLK_L5: TP62.1 U6.U30(MB_CLK_L5)
MB_CLK_L6: TP84.1 U6.AL18(MB_CLK_L6)
MB_CLK_L7: TP89.1 U6.AK19(MB_CLK_L7)
MEM_MA0_CLK0_N: J1.185(CK0N) U6.W27(MA_CLK_L4)
MEM_MA0_CLK0_P: J1.184(CK0P) U6.V27(MA_CLK_H4)
MEM_MA0_CLK1_N: J1.64(NC_CK1N) U6.V24(MA_CLK_L2)
MEM_MA0_CLK1_P: J1.63(NC_CK1P) U6.U24(MA_CLK_H2)
MEM_MA0_CS_L0: J1.193(CS0) U6.AA24(MA0_CS_L0)
MEM_MA0_CS_L1: J1.76(CS1) U6.AC25(MA0_CS_L1)
MEM_MA0_ODT0: J1.195(ODT0) U6.AC28(MA0_ODT0)
MEM_MA0_ODT1: J1.77(ODT1) U6.AE28(MA0_ODT1)
MEM_MA_ADD0: J1.188(A0) U6.W24(MA_ADD0)
MEM_MA_ADD1: J1.181(A1) U6.T27(MA_ADD1)
MEM_MA_ADD2: J1.61(A2) U6.U25(MA_ADD2)
MEM_MA_ADD3: J1.180(A3) U6.T25(MA_ADD3)
MEM_MA_ADD4: J1.59(A4) U6.R27(MA_ADD4)
MEM_MA_ADD5: J1.58(A5) U6.R26(MA_ADD5)
MEM_MA_ADD6: J1.178(A6) U6.R25(MA_ADD6)
MEM_MA_ADD7: J1.56(A7) U6.P27(MA_ADD7)
MEM_MA_ADD8: J1.177(A8) U6.R24(MA_ADD8)
MEM_MA_ADD9: J1.175(A9) U6.N27(MA_ADD9)
MEM_MA_ADD10: J1.70(A10) U6.Y25(MA_ADD10)
MEM_MA_ADD11: J1.55(A11) U6.P25(MA_ADD11)
MEM_MA_ADD12: J1.174(A12) U6.N26(MA_ADD12)
MEM_MA_ADD13: J1.196(A13) U6.AC26(MA_ADD13)
MEM_MA_ADD14: J1.172(A14) U6.N24(MA_ADD14)
MEM_MA_ADD15: J1.171(A15) U6.M27(MA_ADD15)
MEM_MA_BANK0: J1.71(BA0) U6.AA27(MA_BANK0)
MEM_MA_BANK1: J1.190(BA1) U6.Y27(MA_BANK1)
MEM_MA_BANK2: J1.52(A16_BA2) U6.N25(MA_BANK2)
MEM_MA_CAS_N: J1.74(CAS_N) U6.AB25(MA_CAS_L)
MEM_MA_CHECK0: J1.39(CB0) U6.H27(MA_CHECK0)
MEM_MA_CHECK1: J1.40(CB1) U6.H29(MA_CHECK1)
MEM_MA_CHECK2: J1.45(CB2) U6.K27(MA_CHECK2)
MEM_MA_CHECK3: J1.46(CB3) U6.L24(MA_CHECK3)
MEM_MA_CHECK4: J1.158(CB4) U6.G27(MA_CHECK4)
MEM_MA_CHECK5: J1.159(CB5) U6.G28(MA_CHECK5)
MEM_MA_CHECK6: J1.164(CB6) U6.J26(MA_CHECK6)
MEM_MA_CHECK7: J1.165(CB7) U6.K25(MA_CHECK7)
MEM_MA_CKE0: J1.50(CKE0) U6.M25(MA_CKE0)
MEM_MA_CKE1: J1.169(CKE1) U6.L27(MA_CKE1)
MEM_MA_DATA0: J1.3(DQ0) U6.G14(MA_DATA0)
MEM_MA_DATA1: J1.4(DQ1) U6.E14(MA_DATA1)
MEM_MA_DATA2: J1.9(DQ2) U6.E16(MA_DATA2)
MEM_MA_DATA3: J1.10(DQ3) U6.H17(MA_DATA3)
MEM_MA_DATA4: J1.122(DQ4) U6.H13(MA_DATA4)
MEM_MA_DATA5: J1.123(DQ5) U6.G13(MA_DATA5)
MEM_MA_DATA6: J1.128(DQ6) U6.E15(MA_DATA6)
MEM_MA_DATA7: J1.129(DQ7) U6.G16(MA_DATA7)
MEM_MA_DATA8: J1.12(DQ8) U6.E17(MA_DATA8)
MEM_MA_DATA9: J1.13(DQ9) U6.G18(MA_DATA9)
MEM_MA_DATA10: J1.18(DQ10) U6.F21(MA_DATA10)
MEM_MA_DATA11: J1.19(DQ11) U6.G22(MA_DATA11)
MEM_MA_DATA12: J1.131(DQ12) U6.G17(MA_DATA12)
MEM_MA_DATA13: J1.132(DQ13) U6.F17(MA_DATA13)
MEM_MA_DATA14: J1.137(DQ14) U6.E21(MA_DATA14)
MEM_MA_DATA15: J1.138(DQ15) U6.E22(MA_DATA15)
MEM_MA_DATA16: J1.21(DQ16) U6.F23(MA_DATA16)
MEM_MA_DATA17: J1.22(DQ17) U6.G23(MA_DATA17)
MEM_MA_DATA18: J1.27(DQ18) U6.C26(MA_DATA18)
MEM_MA_DATA19: J1.28(DQ19) U6.E26(MA_DATA19)
MEM_MA_DATA20: J1.140(DQ20) U6.D23(MA_DATA20)
MEM_MA_DATA21: J1.141(DQ21) U6.E23(MA_DATA21)
MEM_MA_DATA22: J1.146(DQ22) U6.E25(MA_DATA22)
MEM_MA_DATA23: J1.147(DQ23) U6.F25(MA_DATA23)
MEM_MA_DATA24: J1.30(DQ24) U6.E27(MA_DATA24)
MEM_MA_DATA25: J1.31(DQ25) U6.C28(MA_DATA25)
MEM_MA_DATA26: J1.36(DQ26) U6.F27(MA_DATA26)
MEM_MA_DATA27: J1.37(DQ27) U6.G26(MA_DATA27)
MEM_MA_DATA28: J1.149(DQ28) U6.C27(MA_DATA28)
MEM_MA_DATA29: J1.150(DQ29) U6.D27(MA_DATA29)
MEM_MA_DATA30: J1.155(DQ30) U6.E28(MA_DATA30)
MEM_MA_DATA31: J1.156(DQ31) U6.E29(MA_DATA31)
MEM_MA_DATA32: J1.81(DQ32) U6.AF27(MA_DATA32)
MEM_MA_DATA33: J1.82(DQ33) U6.AG29(MA_DATA33)
MEM_MA_DATA34: J1.87(DQ34) U6.AH27(MA_DATA34)
MEM_MA_DATA35: J1.88(DQ35) U6.AJ27(MA_DATA35)
MEM_MA_DATA36: J1.200(DQ36) U6.AE26(MA_DATA36)
MEM_MA_DATA37: J1.201(DQ37) U6.AF29(MA_DATA37)
MEM_MA_DATA38: J1.206(DQ38) U6.AJ29(MA_DATA38)
MEM_MA_DATA39: J1.207(DQ39) U6.AJ28(MA_DATA39)
MEM_MA_DATA40: J1.90(DQ40) U6.AF25(MA_DATA40)
MEM_MA_DATA41: J1.91(DQ41) U6.AH25(MA_DATA41)
MEM_MA_DATA42: J1.96(DQ42) U6.AG23(MA_DATA42)
MEM_MA_DATA43: J1.97(DQ43) U6.AE22(MA_DATA43)
MEM_MA_DATA44: J1.209(DQ44) U6.AG26(MA_DATA44)
MEM_MA_DATA45: J1.210(DQ45) U6.AJ26(MA_DATA45)
MEM_MA_DATA46: J1.215(DQ46) U6.AE23(MA_DATA46)
MEM_MA_DATA47: J1.216(DQ47) U6.AF23(MA_DATA47)
MEM_MA_DATA48: J1.99(DQ48) U6.AE21(MA_DATA48)
MEM_MA_DATA49: J1.100(DQ49) U6.AF21(MA_DATA49)
MEM_MA_DATA50: J1.105(DQ50) U6.AF17(MA_DATA50)
MEM_MA_DATA51: J1.106(DQ51) U6.AE17(MA_DATA51)
MEM_MA_DATA52: J1.218(DQ52) U6.AG22(MA_DATA52)
MEM_MA_DATA53: J1.219(DQ53) U6.AD21(MA_DATA53)
MEM_MA_DATA54: J1.224(DQ54) U6.AE18(MA_DATA54)
MEM_MA_DATA55: J1.225(DQ55) U6.AG17(MA_DATA55)
MEM_MA_DATA56: J1.108(DQ56) U6.AE16(MA_DATA56)
MEM_MA_DATA57: J1.109(DQ57) U6.AG15(MA_DATA57)
MEM_MA_DATA58: J1.114(DQ58) U6.AE13(MA_DATA58)
MEM_MA_DATA59: J1.115(DQ59) U6.AD13(MA_DATA59)
MEM_MA_DATA60: J1.227(DQ60) U6.AD17(MA_DATA60)
MEM_MA_DATA61: J1.228(DQ61) U6.AG16(MA_DATA61)
MEM_MA_DATA62: J1.233(DQ62) U6.AG14(MA_DATA62)
MEM_MA_DATA63: J1.234(DQ63) U6.AE14(MA_DATA63)
MEM_MA_DM0: J1.125(DQS9P_DM0) U6.H15(MA_DM0)
MEM_MA_DM1: J1.134(DQS10P_DM1) U6.E18(MA_DM1)
MEM_MA_DM2: J1.143(DQS11P_DM2) U6.E24(MA_DM2)
MEM_MA_DM3: J1.152(DQS12P_DM3) U6.B29(MA_DM3)
MEM_MA_DM4: J1.203(DQS13P_DM4) U6.AH29(MA_DM4)
MEM_MA_DM5: J1.212(DQS14P_DM5) U6.AJ25(MA_DM5)
MEM_MA_DM6: J1.221(DQS15P_DM6) U6.AF19(MA_DM6)
MEM_MA_DM7: J1.230(DQS16P_DM7) U6.AF15(MA_DM7)
MEM_MA_DM8: J1.161(DQS17P_DM8) U6.J25(MA_DM8)
MEM_MA_DQS0_N: J1.6(DQS0N) U6.G15(MA_DQS_L0)
MEM_MA_DQS0_P: J1.7(DQS0P) U6.F15(MA_DQS_H0)
MEM_MA_DQS1_N: J1.15(DQS1N) U6.F19(MA_DQS_L1)
MEM_MA_DQS1_P: J1.16(DQS1P) U6.E19(MA_DQS_H1)
MEM_MA_DQS2_N: J1.24(DQS2N) U6.D25(MA_DQS_L2)
MEM_MA_DQS2_P: J1.25(DQS2P) U6.C25(MA_DQS_H2)
MEM_MA_DQS3_N: J1.33(DQS3N) U6.C29(MA_DQS_L3)
MEM_MA_DQS3_P: J1.34(DQS3P) U6.D29(MA_DQS_H3)
MEM_MA_DQS4_N: J1.84(DQS4N) U6.AG28(MA_DQS_L4)
MEM_MA_DQS4_P: J1.85(DQS4P) U6.AG27(MA_DQS_H4)
MEM_MA_DQS5_N: J1.93(DQS5N) U6.AG25(MA_DQS_L5)
MEM_MA_DQS5_P: J1.94(DQS5P) U6.AG24(MA_DQS_H5)
MEM_MA_DQS6_N: J1.102(DQS6N) U6.AG19(MA_DQS_L6)
MEM_MA_DQS6_P: J1.103(DQS6P) U6.AG18(MA_DQS_H6)
MEM_MA_DQS7_N: J1.111(DQS7N) U6.AE15(MA_DQS_L7)
MEM_MA_DQS7_P: J1.112(DQS7P) U6.AD15(MA_DQS_H7)
MEM_MA_DQS8_N: J1.42(DQS8N) U6.J27(MA_DQS_L8)
MEM_MA_DQS8_P: J1.43(DQS8P) U6.J28(MA_DQS_H8)
MEM_MA_EVENT_L: J1.187(NC) Q9.E R163.2 R567.1 U6.W30(MA_EVENT_L)
MEM_MA_RAS_N: J1.192(RAS_N) U6.AA26(MA_RAS_L)
MEM_MA_RESET_N: J1.168(RESET_N) U6.E20(MA_RESET_L)
MEM_MA_WE_N: J1.73(WE_N) U6.AB27(MA_WE_L)
MEM_MB0_CLK0_N: J2.185(CK0N) U6.W28(MB_CLK_L4)
MEM_MB0_CLK0_P: J2.184(CK0P) U6.W29(MB_CLK_H4)
MEM_MB0_CLK1_N: J2.64(NC_CK1N) U6.W31(MB_CLK_L2)
MEM_MB0_CLK1_P: J2.63(NC_CK1P) U6.V31(MB_CLK_H2)
MEM_MB0_CS_L0: J2.193(CS0) U6.AC31(MB0_CS_L0)
MEM_MB0_CS_L1: J2.76(CS1) U6.AE30(MB0_CS_L1)
MEM_MB0_ODT0: J2.195(ODT0) U6.AD29(MB0_ODT0)
MEM_MB0_ODT1: J2.77(ODT1) U6.AF31(MB0_ODT1)
MEM_MB_ADD0: J2.188(A0) U6.AA30(MB_ADD0)
MEM_MB_ADD1: J2.181(A1) U6.U28(MB_ADD1)
MEM_MB_ADD2: J2.61(A2) U6.U29(MB_ADD2)
MEM_MB_ADD3: J2.180(A3) U6.T29(MB_ADD3)
MEM_MB_ADD4: J2.59(A4) U6.T31(MB_ADD4)
MEM_MB_ADD5: J2.58(A5) U6.R30(MB_ADD5)
MEM_MB_ADD6: J2.178(A6) U6.R31(MB_ADD6)
MEM_MB_ADD7: J2.56(A7) U6.R28(MB_ADD7)
MEM_MB_ADD8: J2.177(A8) U6.R29(MB_ADD8)
MEM_MB_ADD9: J2.175(A9) U6.P31(MB_ADD9)
MEM_MB_ADD10: J2.70(A10) U6.AA29(MB_ADD10)
MEM_MB_ADD11: J2.55(A11) U6.P29(MB_ADD11)
MEM_MB_ADD12: J2.174(A12) U6.N30(MB_ADD12)
MEM_MB_ADD13: J2.196(A13) U6.AE31(MB_ADD13)
MEM_MB_ADD14: J2.172(A14) U6.N29(MB_ADD14)
MEM_MB_ADD15: J2.171(A15) U6.N28(MB_ADD15)
MEM_MB_BANK0: J2.71(BA0) U6.AA28(MB_BANK0)
MEM_MB_BANK1: J2.190(BA1) U6.AA31(MB_BANK1)
MEM_MB_BANK2: J2.52(A16_BA2) U6.N31(MB_BANK2)
MEM_MB_CAS_N: J2.74(CAS_N) U6.AC29(MB_CAS_L)
MEM_MB_CHECK0: J2.39(CB0) U6.G31(MB_CHECK0)
MEM_MB_CHECK1: J2.40(CB1) U6.H31(MB_CHECK1)
MEM_MB_CHECK2: J2.45(CB2) U6.L28(MB_CHECK2)
MEM_MB_CHECK3: J2.46(CB3) U6.L29(MB_CHECK3)
MEM_MB_CHECK4: J2.158(CB4) U6.G29(MB_CHECK4)
MEM_MB_CHECK5: J2.159(CB5) U6.G30(MB_CHECK5)
MEM_MB_CHECK6: J2.164(CB6) U6.K31(MB_CHECK6)
MEM_MB_CHECK7: J2.165(CB7) U6.K29(MB_CHECK7)
MEM_MB_CKE0: J2.50(CKE0) U6.M29(MB_CKE0)
MEM_MB_CKE1: J2.169(CKE1) U6.M31(MB_CKE1)
MEM_MB_DATA0: J2.3(DQ0) U6.D13(MB_DATA0)
MEM_MB_DATA1: J2.4(DQ1) U6.A13(MB_DATA1)
MEM_MB_DATA2: J2.9(DQ2) U6.A15(MB_DATA2)
MEM_MB_DATA3: J2.10(DQ3) U6.C15(MB_DATA3)
MEM_MB_DATA4: J2.122(DQ4) U6.F13(MB_DATA4)
MEM_MB_DATA5: J2.123(DQ5) U6.E13(MB_DATA5)
MEM_MB_DATA6: J2.128(DQ6) U6.A14(MB_DATA6)
MEM_MB_DATA7: J2.129(DQ7) U6.B15(MB_DATA7)
MEM_MB_DATA8: J2.12(DQ8) U6.A16(MB_DATA8)
MEM_MB_DATA9: J2.13(DQ9) U6.A17(MB_DATA9)
MEM_MB_DATA10: J2.18(DQ10) U6.A21(MB_DATA10)
MEM_MB_DATA11: J2.19(DQ11) U6.C21(MB_DATA11)
MEM_MB_DATA12: J2.131(DQ12) U6.D15(MB_DATA12)
MEM_MB_DATA13: J2.132(DQ13) U6.C16(MB_DATA13)
MEM_MB_DATA14: J2.137(DQ14) U6.A20(MB_DATA14)
MEM_MB_DATA15: J2.138(DQ15) U6.B21(MB_DATA15)
MEM_MB_DATA16: J2.21(DQ16) U6.A22(MB_DATA16)
MEM_MB_DATA17: J2.22(DQ17) U6.B23(MB_DATA17)
MEM_MB_DATA18: J2.27(DQ18) U6.B25(MB_DATA18)
MEM_MB_DATA19: J2.28(DQ19) U6.A26(MB_DATA19)
MEM_MB_DATA20: J2.140(DQ20) U6.D21(MB_DATA20)
MEM_MB_DATA21: J2.141(DQ21) U6.C22(MB_DATA21)
MEM_MB_DATA22: J2.146(DQ22) U6.A24(MB_DATA22)
MEM_MB_DATA23: J2.147(DQ23) U6.A25(MB_DATA23)
MEM_MB_DATA24: J2.30(DQ24) U6.A28(MB_DATA24)
MEM_MB_DATA25: J2.31(DQ25) U6.A29(MB_DATA25)
MEM_MB_DATA26: J2.36(DQ26) U6.F31(MB_DATA26)
MEM_MB_DATA27: J2.37(DQ27) U6.F29(MB_DATA27)
MEM_MB_DATA28: J2.149(DQ28) U6.A27(MB_DATA28)
MEM_MB_DATA29: J2.150(DQ29) U6.B27(MB_DATA29)
MEM_MB_DATA30: J2.155(DQ30) U6.E30(MB_DATA30)
MEM_MB_DATA31: J2.156(DQ31) U6.E31(MB_DATA31)
MEM_MB_DATA32: J2.81(DQ32) U6.AJ31(MB_DATA32)
MEM_MB_DATA33: J2.82(DQ33) U6.AJ30(MB_DATA33)
MEM_MB_DATA34: J2.87(DQ34) U6.AL26(MB_DATA34)
MEM_MB_DATA35: J2.88(DQ35) U6.AL25(MB_DATA35)
MEM_MB_DATA36: J2.200(DQ36) U6.AG30(MB_DATA36)
MEM_MB_DATA37: J2.201(DQ37) U6.AH31(MB_DATA37)
MEM_MB_DATA38: J2.206(DQ38) U6.AK27(MB_DATA38)
MEM_MB_DATA39: J2.207(DQ39) U6.AL27(MB_DATA39)
MEM_MB_DATA40: J2.90(DQ40) U6.AJ24(MB_DATA40)
MEM_MB_DATA41: J2.91(DQ41) U6.AH23(MB_DATA41)
MEM_MB_DATA42: J2.96(DQ42) U6.AH21(MB_DATA42)
MEM_MB_DATA43: J2.97(DQ43) U6.AJ21(MB_DATA43)
MEM_MB_DATA44: J2.209(DQ44) U6.AK25(MB_DATA44)
MEM_MB_DATA45: J2.210(DQ45) U6.AL24(MB_DATA45)
MEM_MB_DATA46: J2.215(DQ46) U6.AL22(MB_DATA46)
MEM_MB_DATA47: J2.216(DQ47) U6.AJ22(MB_DATA47)
MEM_MB_DATA48: J2.99(DQ48) U6.AL20(MB_DATA48)
MEM_MB_DATA49: J2.100(DQ49) U6.AH19(MB_DATA49)
MEM_MB_DATA50: J2.105(DQ50) U6.AJ16(MB_DATA50)
MEM_MB_DATA51: J2.106(DQ51) U6.AH15(MB_DATA51)
MEM_MB_DATA52: J2.218(DQ52) U6.AL21(MB_DATA52)
MEM_MB_DATA53: J2.219(DQ53) U6.AK21(MB_DATA53)
MEM_MB_DATA54: J2.224(DQ54) U6.AL17(MB_DATA54)
MEM_MB_DATA55: J2.225(DQ55) U6.AL16(MB_DATA55)
MEM_MB_DATA56: J2.108(DQ56) U6.AK15(MB_DATA56)
MEM_MB_DATA57: J2.109(DQ57) U6.AL14(MB_DATA57)
MEM_MB_DATA58: J2.114(DQ58) U6.AG13(MB_DATA58)
MEM_MB_DATA59: J2.115(DQ59) U6.AF13(MB_DATA59)
MEM_MB_DATA60: J2.227(DQ60) U6.AJ15(MB_DATA60)
MEM_MB_DATA61: J2.228(DQ61) U6.AL15(MB_DATA61)
MEM_MB_DATA62: J2.233(DQ62) U6.AL13(MB_DATA62)
MEM_MB_DATA63: J2.234(DQ63) U6.AH13(MB_DATA63)
MEM_MB_DM0: J2.125(DQS9P_DM0) U6.B13(MB_DM0)
MEM_MB_DM1: J2.134(DQS10P_DM1) U6.B17(MB_DM1)
MEM_MB_DM2: J2.143(DQS11P_DM2) U6.A23(MB_DM2)
MEM_MB_DM3: J2.152(DQS12P_DM3) U6.C30(MB_DM3)
MEM_MB_DM4: J2.203(DQS13P_DM4) U6.AK29(MB_DM4)
MEM_MB_DM5: J2.212(DQS14P_DM5) U6.AJ23(MB_DM5)
MEM_MB_DM6: J2.221(DQS15P_DM6) U6.AH17(MB_DM6)
MEM_MB_DM7: J2.230(DQS16P_DM7) U6.AJ14(MB_DM7)
MEM_MB_DM8: J2.161(DQS17P_DM8) U6.J29(MB_DM8)
MEM_MB_DQS0_N: J2.6(DQS0N) U6.C13(MB_DQS_L0)
MEM_MB_DQS0_P: J2.7(DQS0P) U6.C14(MB_DQS_H0)
MEM_MB_DQS1_N: J2.15(DQS1N) U6.C17(MB_DQS_L1)
MEM_MB_DQS1_P: J2.16(DQS1P) U6.D17(MB_DQS_H1)
MEM_MB_DQS2_N: J2.24(DQS2N) U6.C23(MB_DQS_L2)
MEM_MB_DQS2_P: J2.25(DQS2P) U6.C24(MB_DQS_H2)
MEM_MB_DQS3_N: J2.33(DQS3N) U6.C31(MB_DQS_L3)
MEM_MB_DQS3_P: J2.34(DQS3P) U6.D31(MB_DQS_H3)
MEM_MB_DQS4_N: J2.84(DQS4N) U6.AL29(MB_DQS_L4)
MEM_MB_DQS4_P: J2.85(DQS4P) U6.AL28(MB_DQS_H4)
MEM_MB_DQS5_N: J2.93(DQS5N) U6.AL23(MB_DQS_L5)
MEM_MB_DQS5_P: J2.94(DQS5P) U6.AK23(MB_DQS_H5)
MEM_MB_DQS6_N: J2.102(DQS6N) U6.AJ17(MB_DQS_L6)
MEM_MB_DQS6_P: J2.103(DQS6P) U6.AK17(MB_DQS_H6)
MEM_MB_DQS7_N: J2.111(DQS7N) U6.AJ13(MB_DQS_L7)
MEM_MB_DQS7_P: J2.112(DQS7P) U6.AK13(MB_DQS_H7)
MEM_MB_DQS8_N: J2.42(DQS8N) U6.J30(MB_DQS_L8)
MEM_MB_DQS8_P: J2.43(DQS8P) U6.J31(MB_DQS_H8)
MEM_MB_EVENT_L: J2.187(NC) Q8.E R145.1 R151.2 U6.V29(MB_EVENT_L)
MEM_MB_RAS_N: J2.192(RAS_N) U6.AB29(MB_RAS_L)
MEM_MB_RESET_N: J2.168(RESET_N) U6.B19(MB_RESET_L)
MEM_MB_WE_N: J2.73(WE_N) U6.AC30(MB_WE_L)
MEMA_VREFCA_SUS: C108.1 C116.2 C117.1 J1.67(VREFCA) R146.1 R167.2
MEMA_VREFDQ_SUS: C34.2 C54.1 C55.1 J1.1(VREFDQ) R44.2 R68.1
MEMB_VREFCA_SUS: C114.1 C124.2 C125.1 J2.67(VREFCA) R157.1 R179.2
MEMB_VREFDQ_SUS: C29.1 C30.1 C51.2 J2.1(VREFDQ) R38.1 R55.2
MIC1-VREFO: Q34.K U23.28(MIC1-VREFO)
MIC1_JD: CN21.5(PIN5) R702.2
MIC1_L: C506.1 U23.21(MIC1-L(PORT-B-L))
MIC1_L_FIL: C499.1 CN21.2(PIN2) D15.2 L63.2
MIC1_R: C502.1 U23.22(MIC1-R(PORT-B-R))
MIC1_R_FIL: C504.1 CN21.3(PIN3) D15.1 L65.2
MIC_CLK: R515.1 U23.46(DMIC-CLK1/2)
MIC_CLK_R: CN25.1 R515.2
MIC_DAT: R514.1 U23.2(GPIO0/DMIC-DATA1/2)
MIC_DAT_R: CN25.2 R514.2
MXM_BLEN: D12.A2 R32.1
MXM_CLKREQ_N: CN1.154(PEX_CLK_REQ#) R59.1 R60.1
MXM_DDPC_CTRLCLK: CN1.225(DP_C_AUX) CN9.13 R36.2
MXM_DDPC_CTRLDATA: CN1.223(DP_C_AUX#) CN9.14 R37.2
MXM_DDSP_CLK_DN: CN1.217(DP_C_L3#) CN9.2
MXM_DDSP_CLK_DP: CN1.219(DP_C_L3) CN9.1
MXM_DDSP_TX0_DN: CN1.211(DP_C_L2#) CN9.5
MXM_DDSP_TX0_DP: CN1.213(DP_C_L2) CN9.4
MXM_DDSP_TX1_DN: CN1.205(DP_C_L1#) CN9.8
MXM_DDSP_TX1_DP: CN1.207(DP_C_L1) CN9.7
MXM_DDSP_TX2_DN: CN1.199(DP_C_L0#) CN9.11
MXM_DDSP_TX2_DP: CN1.201(DP_C_L0) CN9.10
MXM_DDSPC_HPD: CN1.234(DP_C_HPD) R57.1
MXM_LVDS_DDC_CLK: CN1.35(LVDS_DDC_CLK) Q1.S R19.2 R28.2
MXM_LVDS_DDC_DATA: CN1.33(LVDS_DDC_DAT) Q2.S R23.2 R26.1
MXM_LVDS_L_CLK_DN: CN1.176(LVDS_LCLK#) CN8.20
MXM_LVDS_L_CLK_DP: CN1.178(LVDS_LCLK) CN8.21
MXM_LVDS_L_TX0_DN: CN1.200(LVDS_LTX0#) CN8.12
MXM_LVDS_L_TX0_DP: CN1.202(LVDS_LTX0) CN8.13
MXM_LVDS_L_TX1_DN: CN1.194(LVDS_LTX1#) CN8.15
MXM_LVDS_L_TX1_DP: CN1.196(LVDS_LTX1) CN8.16
MXM_LVDS_L_TX2_DN: CN1.188(LVDS_LTX2#) CN8.18
MXM_LVDS_L_TX2_DP: CN1.190(LVDS_LTX2) CN8.19
MXM_LVDS_L_TX3_DN: CN1.182(LVDS_LTX3#) CN8.22
MXM_LVDS_L_TX3_DP: CN1.184(LVDS_LTX3) CN8.23
MXM_LVDS_PWM: D11.A2 R31.1
MXM_LVDS_U_CLK_DN: CN1.169(LVDS_UCLK#) CN8.8
MXM_LVDS_U_CLK_DP: CN1.171(LVDS_UCLK) CN8.9
MXM_LVDS_U_TX0_DN: CN1.193(LVDS_UTX0#) CN8.1
MXM_LVDS_U_TX0_DP: CN1.195(LVDS_UTX0) CN8.2
MXM_LVDS_U_TX1_DN: CN1.187(LVDS_UTX1#) CN8.3
MXM_LVDS_U_TX1_DP: CN1.189(LVDS_UTX1) CN8.4
MXM_LVDS_U_TX2_DN: CN1.181(LVDS_UTX2#) CN8.5
MXM_LVDS_U_TX2_DP: CN1.183(LVDS_UTX2) CN8.6
MXM_LVDS_U_TX3_DN: CN1.175(LVDS_UTX3#) CN8.10
MXM_LVDS_U_TX3_DP: CN1.177(LVDS_UTX3) CN8.11
MXM_LVDSPWR_EN: D10.A2 R33.1
MXM_PANEL_ID0: CN9.35 R245.1
MXM_PANEL_ID2: CN9.36 R243.1
MXM_PWR_EN: CN1.8(PWR_EN) R258.2
MXM_PWR_GOOD: CN1.6(PWR_GOOD) R526.2 R527.2
MXM_PWR_LEVEL: CN1.18(PWR_LEVEL) R50.2
MXM_PWRGD: R353.2 R526.1
MXM_PWRGD_R: R353.1 U10.AJ6(INTE#/GPIO32)
MXM_RST_N: CN1.156(PEX_RST#) R58.1 R73.1
MXM_STD_SW_N: CN1.19(PEX_STD_SW#) R41.1
MXM_VGA_DDC_CLK: CN1.160(VGA_DDC_CLK) TP26.1
MXM_VGA_DDC_DATA: CN1.158(VGA_DDC_DAT) TP32.1
MXM_VGA_DISABLE_N: CN1.21(VGA_DISABLE#) R34.2 R35.2
NB_ALLOW_LDTSTOP: R126.2 R132.1 U3.C12(ALLOW_LDTSTOP)
NB_HDMI_CLK_TX3_DN: CN7.2 U3.D2(GFX_TX3N)
NB_HDMI_CLK_TX3_DP: CN7.1 U3.D1(GFX_TX3P)
NB_LCD_BKL_EN: D12.A1 R547.2
NB_LCD_BKL_EN_R: R543.1 R547.1 U3.G12(LVDS_ENA_BL(PWM_GPIO2))
NB_LCD_BKL_PWM: D11.A1 R556.2
NB_LCD_BKL_PWM_R: R555.1 R556.1 U3.F7(LVDS_BLON(PCE_RCALRP))
NB_LCD_DDC_CLK: R39.1 R143.1
NB_LCD_DDC_DATA: R40.1 R134.1
NB_LCD_PWR_EN: D10.A1 R550.2
NB_LCD_PWR_EN_R: R544.1 R550.1 U3.E9(LVDS_DIGON(PCE_TCALRP))
NB_LDT_STOP_N: R117.2 U2.4(OUTPUT) U3.C10(LDTSTOP#)
NB_LVDS_L_CLK_DN: CN6.20 U3.A16(TXCLK_LN(DBG_GPIO3))
NB_LVDS_L_CLK_DP: CN6.21 U3.B16(TXCLK_LP(DBG_GPIO1))
NB_LVDS_L_TX0_DN: CN6.12 U3.B22(TXOUT_L0N(NC))
NB_LVDS_L_TX0_DP: CN6.13 U3.A22(TXOUT_L0P(NC))
NB_LVDS_L_TX1_DN: CN6.15 U3.B21(TXOUT_L1N(NC))
NB_LVDS_L_TX1_DP: CN6.16 U3.A21(TXOUT_L1P(NC))
NB_LVDS_L_TX2_DN: CN6.18 U3.A20(TXOUT_L2N(DBG_GPIO0))
NB_LVDS_L_TX2_DP: CN6.19 U3.B20(TXOUT_L2P(NC))
NB_LVDS_L_TX3_DN: CN6.22 U3.B19(TXOUT_L3N(DBG_GPIO2))
NB_LVDS_L_TX3_DP: CN6.23 U3.A19(TXOUT_L3P(NC))
NB_LVDS_U_CLK_DN: CN6.8 U3.D17(TXCLK_UN(PCIE_RESET_GPIO1))
NB_LVDS_U_CLK_DP: CN6.9 U3.D16(TXCLK_UP(PCIE_RESET_GPIO4))
NB_LVDS_U_TX0_DN: CN6.1 U3.A18(TXOUT_U0N(NC))
NB_LVDS_U_TX0_DP: CN6.2 U3.B18(TXOUT_U0P(NC))
NB_LVDS_U_TX1_DN: CN6.3 U3.B17(TXOUT_U1N(PCIE_RESET_GPIO2))
NB_LVDS_U_TX1_DP: CN6.4 U3.A17(TXOUT_U1P(PCIE_RESET_GPIO3))
NB_LVDS_U_TX2_DN: CN6.5 U3.D21(TXOUT_U2N(NC))
NB_LVDS_U_TX2_DP: CN6.6 U3.D20(TXOUT_U2P(NC))
NB_LVDS_U_TX3_DN: CN6.10 U3.D19(TXOUT_U3N(NC))
NB_LVDS_U_TX3_DP: CN6.11 U3.D18(TXOUT_U3P(PCIE_RESET_GPIO5))
NB_OSC: R601.1 R609.1 U3.E11(REFCLK_P/OSCIN(OSCIN))
NB_OSC_R: R601.2 U20.2(REF2)
NB_PANEL_ID0: CN7.35 R242.1
NB_PANEL_ID2: CN7.36 R241.1
NB_PWRGD: R223.2 R224.1 U10.AC19(NB_PWRGD)
NB_PWRGD_IN: R133.2 U3.A10(POWERGOOD)
NB_RST_IN_N: Q7.D R122.2 R123.2 R457.2 U3.D8(SYSRESET#)
NB_THERMDA: C285.1 C288.1 R189.2 R409.1
NB_THERMDA_R: R189.1 U3.AE8(THERMALDIODE_P)
NB_THERMDC: R190.2 R434.1
NB_THERMDC_R: R190.1 U3.AD8(THERMALDIODE_N)
NB_VDDHT: C90.1 C367.1 C397.1 C410.1 R2126.2 U3.J17(VDDHT_1) U3.K16(VDDHT_2) U3.L16(VDDHT_3) U3.M16(VDDHT_4) U3.P16(VDDHT_5) U3.R16(VDDHT_6) U3.T16(VDDHT_7)
NB_VGA_B: R94.1 R95.1 R95.2 U3.E19(BLUE(DFT_GPIO3))
NB_VGA_G: R92.1 R93.1 R93.2 U3.E18(GREEN(DFT_GPIO1))
NB_VGA_R: R90.1 R91.1 R91.2 U3.G18(RED(DFT_GPIO0))
NBLINK_RCLK_DN: R155.1 R582.2 U3.V3(GPPSB_REFCLKN(SB_REFCLKN))
NBLINK_RCLK_DP: R153.1 R581.2 U3.V4(GPPSB_REFCLKP(SB_REFCLKP))
NBSILK_CLK_R_DN: R582.1 U20.40(ATIG0C_LPRS)
NBSILK_CLK_R_DP: R581.1 U20.41(ATIG0T_LPRS)
NC_MXM_GPIO0: CN1.26(GPIO0) TP106.1
NC_MXM_GPIO1: CN1.28(GPIO1) TP105.1
NC_MXM_GPIO2: CN1.30(GPIO2) TP104.1
P2E_SLOT0_PRSNT_1_N: R528.1 U10.AJ21(SMARTVOLT2/SHUTDOWN#/GPIO51)
P2E_SLOT0_PRSNT_1_N_R: CN1.2(PRSNT_R#) R525.2 R528.2
P2E_SLOT0_PRSNT_2_N: CN1.281(PRSNT_L#) R42.2
PANEL_ID0: R242.2 R245.2 R290.2 R308.1 U10.E28(KSI_2/GPIO203)
PANEL_ID0_R: CN27.14 R308.2
PANEL_ID1: R287.2 R320.1 U10.E29(KSI_3/GPIO204)
PANEL_ID1_R: CN27.9 R320.2
PANEL_ID2: R241.2 R243.2 R294.2 R344.1 U10.B28(KSO_0/GPIO209)
PANEL_ID2_R: CN27.6 R344.2
PC_BEEP: C274.2 C286.1 R446.1 R653.2 R740.1
PC_BEEP_SPEAKER: R740.2 R743.1
PC_MODE: R76.2 R549.1 U10.E4(USB_OC5#/IR_TX0/GEVENT17#)
PC_MODE_MXM_R: CN9.28 R549.2
PC_MODE_NB_R: CN7.28 R76.1
PC_STATUS: R80.2 R566.2 U10.D29(KSI_4/GPIO205)
PC_STATUS_MXM_R: CN9.24 R566.1
PC_STATUS_NB_R: CN7.24 R80.1
PCE_CALRN: R187.1 U3.AB8(PCE_CALRN(PCE_BCALRN))
PCE_CALRP: R188.1 U3.AC8(PCE_CALRP(PCE_BCALRP))
PCI_AD23: R675.1 U10.AE9(AD23/GPIO23)
PCI_AD24: R673.1 U10.AD9(AD24/GPIO24)
PCI_AD25: R672.1 U10.AC11(AD25/GPIO25)
PCI_AD26: R351.1 U10.AF6(AD26/GPIO26)
PCI_AD27: R350.1 U10.AF4(AD27/GPIO27)
PCI_AD29: R401.1 U10.AH2(AD29/GPIO29)
PCI_CLK0: R396.1 U10.W2(PCICLK0)
PCI_CLK1_R: R397.1 U10.W1(PCICLK1/GPO36)
PCI_CLK2: R398.2 R426.1 R443.1
PCI_CLK2_R: R398.1 U10.W3(PCICLK2/GPO37)
PCI_CLK3: R399.2 R427.1 R444.1
PCI_CLK3_R: R399.1 U10.W4(PCICLK3/GPO38)
PCI_CLK4: R400.2 R428.1 R445.1
PCI_CLK4_R: R400.1 U10.Y1(PCICLK4/14M_OSC/GPO39)
PCI_GNT0_N: R669.1 R676.2 U10.AD12(GNT0#)
PCI_GNT2_N: TP99.1 U10.AH6(GNT2#/GPO45)
PCI_REQ2_N: TP101.1 U10.AH4(REQ2#/CLK_REQ8#/GPIO41)
PCI_RI_R_N: R326.2 U10.K1(RI#/GEVENT22#)
PCI_RST_N: C280.1 R395.2 R448.1 R449.1
PCI_RST_R_N: CN2.17(RESERVED/UIM_C8) R449.2
PCIE_CALRN_R: R255.2 U10.AD28(PCIE_CALRN)
PCIE_CALRP_R: R254.2 U10.AD29(PCIE_CALRP)
PCIE_EXPCARD_PWREN_N: R405.1 U10.H2(GEVENT5#)
PCIE_LAN_CLKREQ_N: R729.2 R735.1 R746.1
PCIE_MXM_NB_RX8N: C26.1 CN1.147(PEX_RX0#)
PCIE_MXM_NB_RX8N_C: C26.2 U3.L6(GFX_RX8N)
PCIE_MXM_NB_RX8P: C25.1 CN1.149(PEX_RX0)
PCIE_MXM_NB_RX8P_C: C25.2 U3.L5(GFX_RX8P)
PCIE_MXM_NB_RX9N: C28.1 CN1.141(PEX_RX1#)
PCIE_MXM_NB_RX9N_C: C28.2 U3.L8(GFX_RX9N)
PCIE_MXM_NB_RX9P: C27.1 CN1.143(PEX_RX1)
PCIE_MXM_NB_RX9P_C: C27.2 U3.M8(GFX_RX9P)
PCIE_MXM_NB_RX10N: C9.1 CN1.135(PEX_RX2#)
PCIE_MXM_NB_RX10N_C: C9.2 U3.M7(GFX_RX10N)
PCIE_MXM_NB_RX10P: C8.1 CN1.137(PEX_RX2)
PCIE_MXM_NB_RX10P_C: C8.2 U3.P7(GFX_RX10P)
PCIE_MXM_NB_RX11N: C11.1 CN1.121(PEX_RX3#)
PCIE_MXM_NB_RX11N_C: C11.2 U3.M5(GFX_RX11N)
PCIE_MXM_NB_RX11P: C10.1 CN1.123(PEX_RX3)
PCIE_MXM_NB_RX11P_C: C10.2 U3.P5(GFX_RX11P)
PCIE_MXM_NB_RX12N: C13.1 CN1.115(PEX_RX4#)
PCIE_MXM_NB_RX12N_C: C13.2 U3.P8(GFX_RX12N)
PCIE_MXM_NB_RX12P: C12.1 CN1.117(PEX_RX4)
PCIE_MXM_NB_RX12P_C: C12.2 U3.R8(GFX_RX12P)
PCIE_MXM_NB_RX13N: C15.1 CN1.109(PEX_RX5#)
PCIE_MXM_NB_RX13N_C: C15.2 U3.R5(GFX_RX13N)
PCIE_MXM_NB_RX13P: C14.1 CN1.111(PEX_RX5)
PCIE_MXM_NB_RX13P_C: C14.2 U3.R6(GFX_RX13P)
PCIE_MXM_NB_RX14N: C17.1 CN1.103(PEX_RX6#)
PCIE_MXM_NB_RX14N_C: C17.2 U3.P3(GFX_RX14N)
PCIE_MXM_NB_RX14P: C16.1 CN1.105(PEX_RX6)
PCIE_MXM_NB_RX14P_C: C16.2 U3.P4(GFX_RX14P)
PCIE_MXM_NB_RX15N: C19.1 CN1.97(PEX_RX7#)
PCIE_MXM_NB_RX15N_C: C19.2 U3.T3(GFX_RX15N)
PCIE_MXM_NB_RX15P: C18.1 CN1.99(PEX_RX7)
PCIE_MXM_NB_RX15P_C: C18.2 U3.T4(GFX_RX15P)
PCIE_NB_HDMI_TX0_DN: CN7.5 U3.B2(GFX_TX2N)
PCIE_NB_HDMI_TX0_DP: CN7.4 U3.C3(GFX_TX2P)
PCIE_NB_HDMI_TX1_DN: CN7.8 U3.B4(GFX_TX1N)
PCIE_NB_HDMI_TX1_DP: CN7.7 U3.A4(GFX_TX1P)
PCIE_NB_HDMI_TX2_DN: CN7.11 U3.B5(GFX_TX0N)
PCIE_NB_HDMI_TX2_DP: CN7.10 U3.A5(GFX_TX0P)
PCIE_NB_MXM_TX8N: C57.2 CN1.148(PEX_TX0#)
PCIE_NB_MXM_TX8P: C56.2 CN1.150(PEX_TX0)
PCIE_NB_MXM_TX9N: C37.2 CN1.142(PEX_TX1#)
PCIE_NB_MXM_TX9P: C58.2 CN1.144(PEX_TX1)
PCIE_NB_MXM_TX10N: C39.2 CN1.136(PEX_TX2#)
PCIE_NB_MXM_TX10P: C38.2 CN1.138(PEX_TX2)
PCIE_NB_MXM_TX11N: C41.2 CN1.120(PEX_TX3#)
PCIE_NB_MXM_TX11P: C40.2 CN1.122(PEX_TX3)
PCIE_NB_MXM_TX12N: C43.2 CN1.114(PEX_TX4#)
PCIE_NB_MXM_TX12P: C42.2 CN1.116(PEX_TX4)
PCIE_NB_MXM_TX13N: C45.2 CN1.108(PEX_TX5#)
PCIE_NB_MXM_TX13P: C44.2 CN1.110(PEX_TX5)
PCIE_NB_MXM_TX14N: C47.2 CN1.102(PEX_TX6#)
PCIE_NB_MXM_TX14P: C46.2 CN1.104(PEX_TX6)
PCIE_NB_MXM_TX15N: C49.2 CN1.96(PEX_TX7#)
PCIE_NB_MXM_TX15P: C48.2 CN1.98(PEX_TX7)
PCIE_NIC_RX_DN0: C527.1 U3.AD4(GPP_RX0N)
PCIE_NIC_RX_DP0: C529.1 U3.AE3(GPP_RX0P)
PCIE_NIC_TX_DN0: C130.2 U24.18(HSIN)
PCIE_NIC_TX_DP0: C129.2 U24.17(HSIP)
PCIE_RST_N: R421.1 R728.1
PCIE_RST_R_N: R421.2 U10.P1(PCIE_RST#)
PCIE_RST_TV_N: CN5.22(PERST*) R496.1
PCIE_RST_WLAN_N: CN2.22(PERST*) R633.1
PCIE_TUNER_CLKREQ_N: CN5.7(CLKREQ*) R751.2
PCIE_TUNER_RX_DN1: CN5.23(PERN0) U3.AD3(GPP_RX1N)
PCIE_TUNER_RX_DP1: CN5.25(PERP0) U3.AE2(GPP_RX1P)
PCIE_TUNER_TX_DN1: C540.2 CN5.31(PETN0)
PCIE_TUNER_TX_DP1: C541.2 CN5.33(PETP0)
PCIE_WAKE_MXM_N: CN1.4(WAKE#) R51.2
PCIE_WAKE_N: R51.1 R486.1 R629.1 R709.2 R730.2 U10.H6(WAKE#/GEVENT8#)
PCIE_WAKE_TV_N: CN5.1(WAKE*) R486.2
PCIE_WAKE_WLAN_N: CN2.1(WAKE*) R629.2
PCIE_WLAN_CLKREQ_N: CN2.7(CLKREQ*) R627.1 R659.2
PCIE_WLAN_RX_DN2: CN2.23(PERN0) U3.AD2(GPP_RX2N)
PCIE_WLAN_RX_DP2: CN2.25(PERP0) U3.AD1(GPP_RX2P)
PCIE_WLAN_TX_DN2: C462.2 CN2.31(PETN0)
PCIE_WLAN_TX_DP2: C463.2 CN2.33(PETP0)
PD#: D7.A R225.2 U20.52(PD#)
PE6_LAN_RXN_C: C527.2 U24.23(HSON)
PE6_LAN_RXP_C: C529.2 U24.22(HSOP)
PE_GPIO0: R354.2 U10.AJ4(INTH#/GPIO35)
PE_WAKE_NIC_N: R709.1 R724.2 U24.28(LANWAKEB)
PERSTB: R738.1 U24.25(PERSTB)
PLLVDD: C100.1 L9.2 U3.A12(PLLVDD(NC))
PLLVDD18: C99.1 L8.2 U3.D14(PLLVDD18(NC))
PSON_N: Q23.G Q25.G Q28.G Q36.G Q37.G Q61.D Q62.G R684.2 R685.1
PSON_N_1V5: Q20.D Q21.G R283.1 R317.2
PSON_N_1V5_CTRL: PC70.1 Q59.4(G) R306.2
PSON_N_3V3_CTRL: C290.1 Q30.4 R430.2
PSON_N_5V_CTRL: C277.1 Q31.4 R374.2
PSON_N_12V_CTRL: C264.1 Q26.4 R387.2
PSOUT_SIO_N: R365.1 R471.1 R472.1
PU_DVI_HPD: CN1.31(DVI_HPD) R30.2
PU_SIO_PSON_N: R462.1 U11.33(GP51/PSON#)
PU_SIO_RSTOUT1_N: R465.1 U11.38(GP36/RSTOUT1#)
PU_SIO_RSTOUT2_N: R464.1 U11.37(GP37/RSTOUT2#)
PVIEN: R541.1 U6.E2(PVIEN/VID1)
PWM1_P0: PU2.48(VDD_G1) PU4.2(PWM)
PWM1_P0_SENSE_N: PR35.2 R47.1
PWM1_P0_SENSE_P: PC15.1 PR71.2 PU2.14(VDD_CS1N) R46.1
PWM3_P0: PU2.46(VDD_G3) PU5.2(PWM)
PWM3_P0_SENSE_N: PR34.2 R48.1
PWM3_P0_SENSE_P: PC14.1 PR70.2 PU2.18(VDD_CS3N) R45.1
PWR_ACT_LED1_N: R358.1 R362.1 R454.1
PWR_ACT_LED1_WHITE: Q67.G R765.1 R766.2 S3.L1
PWR_ACT_LED1_WHITE_R: Q66.D R520.2 R765.2 R769.1
PWR_ACT_LED_AMBER: Q67.D R764.2 R769.2 S3.L2
PWR_ACT_LED_AMBER_R: Q33.C R763.2 R764.1 R766.1 R767.2
PWR_ACT_LED_N: R432.1 R435.1 R453.1
PWRBTN_R_N: C552.1 R759.1 R762.2 S3.1 S3.2
PWRBTN_SIO_N: R472.2 R473.1 R759.2
PWRGD_PS: C556.1 Q70.D Q609.3(D2) R258.1 R477.1 R776.2
PWROK_SIO: R466.1 U11.41(GP32/PWROK)
REF0/SEL_HTT6: R605.2 R606.2 U20.4(REF0/SEL_HTT66)
REFCLK_N: R551.1 U3.F11(REFCLK_N(PWM_GPIO3))
REMOTE_P: C267.1 Q35.B Q35.C
RESERVED_3: CN2.3(RESERVED_3) TP195.1
RESTORE#: R226.2 U20.53(RESTORE#)
RIA: L71.1 U16.18(R5IN)
RIA_L: C341.1 J6.9 L71.2
RSMRST_N: C1462.1 R422.1 R478.1 U10.G1(RSMRST#)
RST_PLTRST_N: R58.2 R496.2 R633.2 R727.1 R728.2 R738.2
RSVD: TP151.1 U3.G11(RSVD4)
RSVD1: TP144.1 U3.E17(RSVD1)
RSVD2: TP149.1 U3.F17(RSVD2)
RSVD3: TP147.1 U3.F15(RSVD3)
RTC_CLK: TP201.1 U10.D2(RTCCLK)
RTSA: L78.1 U16.2(T1OUT)
RTSA_L: C339.1 J6.7 L78.2
RXDA: L73.1 U16.27(R3IN)
RXDA_L: C334.1 J6.2 L73.2
SA0: R181.2 TP87.1 U6.AK4(SA0)
SATA_CALRN: R671.2 U10.AA14(SATA_CALRN)
SATA_CALRP: R664.2 U10.AB14(SATA_CALRP)
SATA_RX_C_DN0: C235.1 CN11.5(RX-)
SATA_RX_C_DN1: C229.1 CN12.5(RX-)
SATA_RX_C_DP0: C237.1 CN11.6(RX+)
SATA_RX_C_DP1: C231.1 CN12.6(RX+)
SATA_RXN0: C235.2 U10.AJ8(SATA_RX0N)
SATA_RXN1: C229.2 U10.AG10(SATA_RX1N)
SATA_RXP0: C237.2 U10.AH8(SATA_RX0P)
SATA_RXP1: C231.2 U10.AF10(SATA_RX1P)
SATA_TX_C_DN0: C214.1 CN11.3(TX-)
SATA_TX_C_DN1: C230.1 CN12.3(TX-)
SATA_TX_C_DP0: C215.1 CN11.2(TX+)
SATA_TX_C_DP1: C228.1 CN12.2(TX+)
SATA_TXN0: C214.2 U10.AJ9(SATA_TX0N)
SATA_TXN1: C230.2 U10.AJ10(SATA_TX1N)
SATA_TXP0: C215.2 U10.AH9(SATA_TX0P)
SATA_TXP1: C228.2 U10.AH10(SATA_TX1P)
SATA_X1: C222.2 R288.2 U10.AD16(SATA_X1) Y2.2
SATA_X2: C210.2 R288.1 U10.AC16(SATA_X2) Y2.1
SB800_MEMHOT_N: Q29.E R401.2 R402.2
SB_A_RST_N: R338.2 U10.L1(A_RST#)
SB_AZ_VDDIO: C500.1 R687.2 R700.1 R706.1
SB_OSC: R600.1 R660.1
SB_OSC_R: R600.2 U20.3(REF1)
SB_PCI_RST_R_N: R395.1 U10.V2(PCIRST#)
SB_PCIE_LAN_CLKREQ_N: R285.1 R746.2 U10.AA16(CLK_REQ3#/SATA_IS1#/GPIO63)
SB_PDRST_N: C200.1 J4.4 R252.2 U10.AG4(INTG#/GPIO34)
SB_PWRGD: R345.2 R753.1 U10.H5(PWR_GOOD)
SB_RTCRST_N: J4.3 R386.2
SB_SRC_CLK_DN: R617.2 U10.P23(PCIE_RCLKN/NB_LNK_CLKN)
SB_SRC_CLK_DP: R618.2 U10.M23(PCIE_RCLKP/NB_LNK_CLKP)
SB_SRC_CLK_R_DN: R617.1 U20.15(SRC3C_LPRS)
SB_SRC_CLK_R_DP: R618.1 U20.16(SRC3T_LPRS)
SB_TEST0: R697.1 U10.B3(TEST0)
SB_TEST1: R698.1 U10.C4(TEST1/TMS)
SB_TEST2: R699.1 U10.F6(TEST2)
SCLK1: R731.2 U24.14(SMBCLK)
SCLK2: R273.1 U10.D25(SCL2/GPIO193)
SD_D0/MMC_D0/MS_D0/XD_D0: CN13.P17(MS-DATA0) CN13.P32(XD-D0) R202.1 U5.24(DATA0)
SD_D1/MMC_D1/MS_D1/XD_D1: CN13.P10(XD-D1) R200.1 R203.1 U5.25(DATA1)
SD_D2/MMC_D2/MS_D2/XD_D2: CN13.P9(XD-D2) R172.1 R186.1 U5.16(DATA2)
SD_D3/MMC_D3/MS_D3/XD_D3: CN13.P8(XD-D3) CN13.P24(MS-DATA3) R174.1 U5.17(DATA3)
SD_D4/MMC_D4/MS_D4/XD_D4: CN13.P7(XD-D4) R164.1 U5.18(DATA4)
SD_D5/MMC_D5/MS_D5/XD_D5: CN13.P6(XD-D5) R171.1 U5.20(DATA5)
SD_D6/MMC_D6/MS_D6/XD_D6: CN13.P5(XD-D6) R192.1 U5.22(DATA6)
SD_D7/MMC_D7/MS_D7/XD_D7: CN13.P4(XD-D7) R197.1 U5.23(DATA7)
SD_ON: R656.1 U10.AE19(SATA_IS5#/FANIN3/GPIO59)
SDA2: R251.1 U10.F23(SDA2/GPIO194)
SDATA1: R739.2 R741.2 U24.15(SMBDATE)
SDCDN/XDWRN: CN13.P1(SD-CD) R158.2 U5.26(CTRL3)
SDCLK/XDALE/MSBS: CN13.P13(MS-BS) R175.2 R176.1 R191.2
SDCLK/XDALE/MSBS_P35_R: CN13.P35(XD-ALE) R175.1
SDCLK/XDALE/MSBS_R: CN13.P20(SD-CLK) R176.2
SDCMD/XDRBN: CN13.P25(SD-CMD) R152.2 U5.19(CTRL2)
SDWP/XDCLE/MSCLK: CN13.P2(SD-WP) R156.2 R161.1 R168.1
SENSE_A: R701.1 R702.1 U23.13(SENSE A)
SENSE_B: R352.2 U23.34(SENSE B)
SERIRQ: R384.1 U10.AB19(SERIRQ/GPIO48) U11.3(SERIRQ)
SIO_CIR_LED: CN30.6 U11.64(CIRLED/GP57)
SIO_CIR_RX: CN30.3 U10.F3(IR_RX1/GEVENT20#) U11.45(GP24/CIRRX)
SIO_CIR_TX: R438.2 R499.1 U11.46(GP25/CIRTX)
SIO_CIR_WB: CN30.4 U11.21(GP97/CIRRXWB)
SIO_DEEP_S5: R463.1 U11.36(DEEP_S5)
SIO_GND: C267.2 C285.2 C288.2 C291.2 C293.2 C295.2 C526.2 C528.2 L69.2 Q35.E R434.2 R458.2 R479.2 U11.56(CPUD-(AGND))
SIO_GRN_LED: R359.1 R453.2 U11.23(GP86/GRN_LED)
SIO_KBCLK: R715.1 R2123.2 U11.29(GP21/KCLK)
SIO_KBDATA: R722.1 R2122.2 U11.30(GP20/KDAT)
SIO_LPC_LAD0: R380.1 U11.7(LAD0)
SIO_LPC_LAD1: R381.1 U11.6(LAD1)
SIO_LPC_LAD2: R382.1 U11.5(LAD2)
SIO_LPC_LAD3: R383.1 U11.4(LAD3)
SIO_MSECLK: R718.1 R2125.2 U11.27(GP23/MCLK)
SIO_MSEDATA: R717.1 R2124.2 U11.28(GP22/MDAT)
SIO_OVT_N: R467.1 U11.42(OVT#/GP31/RESETCON#)
SIO_P1V5_DDR3_SENSE: R419.2 U11.53(VIN3/AUXTIN)
SIO_P5V_SENSE: R442.2 R479.1 U11.49(VIN2)
SIO_PSIN_N: R473.2 U11.32(GP53/PSIN#)
SIO_PSOUT_N: R431.1 R471.2 U11.31(GP54/PSOUT#)
SIO_RSMRST_N: R468.1 R478.2 U11.48(GP90/RSMRST#)
SIO_RSTOUT0_N: R727.2 R734.1 U11.39(GP35/RSTOUT0#)
SIO_SMB_CLK: R392.1 R412.1 U11.26(GP83/MSCL2/SCL2)
SIO_SMB_DATA: R388.1 R393.1 U11.25(BEEP/GP84/MSDA2/SDA2)
SIO_VCCP_SENSE: R437.2 U11.51(CPUVCORE)
SIO_YLW_LED: R360.1 R454.2 U11.22(GP87/YLW_LED)
SLP_S3_N: PR11.1 R113.1 R136.1 R364.1 R447.1 R705.1 R736.1 U11.34(GP50/SLP_S3#) U22.2(1B)
SLP_S5_N: PR14.1 R366.1 R498.1 R602.1 R726.1 U22.1(1A)
SMB_CLK_MAIN: J1.118(SCL) J2.118(SCL) R607.1 R641.2 R646.1 U10.AD22(SCL0/GPIO43)
SMB_CLK_MAIN_R: R607.2 U20.13(SMBCLK)
SMB_CLK_SUS: CN1.34(SMB_CLK) R392.2
SMB_CLK_WLAN_R: CN2.30(SMB_CLK) R641.1
SMB_DATA_MAIN: J1.238(SDA) J2.238(SDA) R608.1 R640.2 R642.1 U10.AE22(SDA0/GPIO47)
SMB_DATA_MAIN_R: R608.2 U20.14(SMBDAT)
SMB_DATA_SUS: CN1.32(SMB_DAT) R388.2
SMB_DATA_WLAN_R: CN2.32(SMB_DATA) R640.1
SP_DDR3_RST_N: TP100.1 U10.H4(DDR3_RST#/GEVENT7#)
SPDIF-OUT: R83.2 R564.2 U23.48(SPDIFO1)
SPDIF-OUT_MXM_R: CN9.21 R564.1
SPDIF-OUT_NB_R: CN7.21 R83.1
SPEK_SUMOUT_L: C534.1 R346.2
SPEK_SUMOUT_R: C518.1 R331.2
SPI_CLK: U10.K4(SPI_CLK/GPIO162) U12.6(SCK) U15.6(SCK)
SPI_CS_N: R420.2 U10.K9(SPI_CS1#/GPIO165) U12.1(C\E\) U15.1(CS#)
SPI_DATAIN: R440.1 U10.J5(SPI_DI/GPIO164)
SPI_DATAOUT: U10.E2(SPI_DO/GPIO163) U12.5(SI) U15.5(SI)
SPI_DI_R: R440.2 U12.2(SO) U15.2(SO)
SPI_HOLD_N: R390.2 U12.7(HOLD#) U15.7(HOLD#)
SPI_WP_N: R433.2 U12.3(WP#) U15.3(WP#)
SPK_L-N: CN10.1 R756.1
SPK_L-P: C319.2 CN10.2
SPK_R-N: C326.2 CN10.4
SPK_R-P: CN10.3 R773.1
SPM_CLKN: R571.2 TP189.1 U3.W14(MEM_CKN(NC))
SPM_CLKP: R571.1 TP190.1 U3.V15(MEM_CKP(NC))
SPM_COMPN: R178.2 U3.AD12(MEM_COMPN(NC))
SPM_COMPP: R162.2 U3.AE12(MEM_COMPP(NC))
STRP_DAT: TP39.1 U3.B10(STRP_DATA)
SUMOUT_L: R346.1 U23.35(LOUT1-L(PORT-D-L))
SUMOUT_R: R331.1 U23.36(LOUT1-R(PORT-D-R))
SUS_STAT_N: R131.2 U10.G6(SUS_STAT#)
SUS_STAT_R_N: R116.1 R125.1 R131.1 U3.D12(SUS_STAT#(PWM_GPIO5))
SYS_FAN1_PWM: R2.2 R9.1 U10.W5(FANOUT0/GPIO52)
SYS_FAN1_TACH: D2.A R7.1 U10.W7(FANIN0/GPIO56)
SYS_FAN_PWM: R4.2 R13.1 U11.63(SYSFANOUT/GP96)
SYS_FAN_TACH: D3.A R12.1 U11.62(SYSFANIN/GP95)
SYS_PWROK: PR4.1 R222.2
TDMS_HPD: R548.1 U3.D9(TMDS_HPD(NC))
TEMPIN: R690.1 U10.A5(TEMPIN2/GPIO173) U10.A6(TEMPIN1/GPIO172) U10.B5(TEMPIN3/TALERT#/GPIO174) U10.B6(TEMPIN0/GPIO171)
TEST_EN: R135.1 U3.D13(TESTMODE)
TH_PWM_MXM: CN1.24(TH_PWM) TP107.1
THERMALERT_VGA_N: CN1.22(TH_ALERT#) R49.2
THERMTRIP_VGA_N: C1465.1 CN1.20(TH_OVERT#) Q51.S R69.2
TOUCH_PANEL_DETECT: CN28.5 R286.1 R643.2
TP_DP_A_AUX: CN1.279(DP_A_AUX) TP6.1
TP_DP_A_AUX_N: CN1.277(DP_A_AUX#) TP1.1
TP_DP_A_L0: CN1.255(DP_A_L0) TP10.1
TP_DP_A_L0_N: CN1.253(DP_A_L0#) TP5.1
TP_DP_A_L1: CN1.261(DP_A_L1) TP9.1
TP_DP_A_L1_N: CN1.259(DP_A_L1#) TP4.1
TP_DP_A_L2: CN1.267(DP_A_L2) TP8.1
TP_DP_A_L2_N: CN1.265(DP_A_L2#) TP3.1
TP_DP_A_L3: CN1.273(DP_A_L3) TP7.1
TP_DP_A_L3_N: CN1.271(DP_A_L3#) TP2.1
TP_DP_B_AUX: CN1.272(DP_B_AUX) TP16.1
TP_DP_B_AUX_N: CN1.270(DP_B_AUX#) TP27.1
TP_DP_B_L0: CN1.248(DP_B_L0) TP20.1
TP_DP_B_L0_N: CN1.246(DP_B_L0#) TP31.1
TP_DP_B_L1: CN1.254(DP_B_L1) TP19.1
TP_DP_B_L1_N: CN1.252(DP_B_L1#) TP30.1
TP_DP_B_L2: CN1.260(DP_B_L2) TP18.1
TP_DP_B_L2_N: CN1.258(DP_B_L2#) TP29.1
TP_DP_B_L3: CN1.266(DP_B_L3) TP17.1
TP_DP_B_L3_N: CN1.264(DP_B_L3#) TP28.1
TP_DP_D_AUX: CN1.232(DP_D_AUX) TP11.1
TP_DP_D_AUX_N: CN1.230(DP_D_AUX#) TP21.1
TP_DP_D_L0: CN1.208(DP_D_L0) TP15.1
TP_DP_D_L0_N: CN1.206(DP_D_L0#) TP25.1
TP_DP_D_L1: CN1.214(DP_D_L1) TP14.1
TP_DP_D_L1_N: CN1.212(DP_D_L1#) TP24.1
TP_DP_D_L2: CN1.220(DP_D_L2) TP13.1
TP_DP_D_L2_N: CN1.218(DP_D_L2#) TP23.1
TP_DP_D_L3: CN1.226(DP_D_L3) TP12.1
TP_DP_D_L3_N: CN1.224(DP_D_L3#) TP22.1
TP_GPIO61: TP98.1 U10.G2(ROM_RST#/GPIO161)
TP_SIO_PECI_REQ_N: TP205.1 U11.57(GP92/PECI_REQ#/TSI_CLK)
TSI: TP204.1 U11.59(PECI/TSI_DAT)
TV_ON: CN5.20(W_DISABLE*) R487.2
TXDA: L77.1 U16.3(T2OUT)
TXDA_L: C337.1 J6.3 L77.2
USB0N: CN14.2(D-) L51.3 Q58.3 R604.2
USB0P: CN14.3(D+) L51.2 Q58.4 R603.2
USB5V2: C444.1 C446.1 C452.1 C473.1 CN14.1(VCC) CN15.1(VCC) L47.2 Q58.5 R645.2
USB6N: CN15.2(D-) L52.3 Q58.1 R626.2
USB6P: CN15.3(D+) L52.2 Q58.6 R625.2
USB_0N: L51.4 R604.1 U10.B16(USB_HSD0N)
USB_0P: L51.1 R603.1 U10.A16(USB_HSD0P)
USB_1N: U5.6(DM) U10.A17(USB_HSD1N)
USB_1P: U5.5(DP) U10.B17(USB_HSD1P)
USB_2N: L39.4 R507.1 U10.J18(USB_HSD2N)
USB_2P: L39.1 R508.1 U10.J16(USB_HSD2P)
USB_3N: CN2.36(USB_D_N) U10.E16(USB_HSD3N)
USB_3P: CN2.38(USB_D_P) U10.E18(USB_HSD3P)
USB_4N: L38.1 R506.1 U10.A14(USB_HSD4N)
USB_4P: L38.4 R505.1 U10.B14(USB_HSD4P)
USB_5N: L36.1 R502.1 U10.C16(USB_HSD5N)
USB_5P: L36.4 R513.1 U10.D16(USB_HSD5P)
USB_6N: L52.4 R626.1 U10.G18(USB_HSD6N)
USB_6P: L52.1 R625.1 U10.G16(USB_HSD6P)
USB_7N: CN28.2 U10.G14(USB_HSD7N) U21.2(I/O-1)
USB_7P: CN28.3 U10.G12(USB_HSD7P) U21.3(I/O-2)
USB_8N: CN25.6 U10.C13(USB_HSD8N)
USB_8P: CN25.5 U10.D13(USB_HSD8P)
USB_9N: L37.4 R503.1 U10.B13(USB_HSD9N)
USB_9P: L37.1 R504.1 U10.A13(USB_HSD9P)
USB_10N: CN26.4 U10.J14(USB_HSD10N)
USB_10P: CN26.3 U10.J12(USB_HSD10P)
USB_11N: CN5.36(USB_D_N) U10.E12(USB_HSD11N)
USB_11P: CN5.38(USB_D_P) U10.E14(USB_HSD11P)
USB_48M_R: R324.1 U10.A10(USBCLK/14M_25M_48M_OSC)
USB_OC0: R679.2 U10.F8(USB_OC0#/TRST#/GEVENT12#)
USB_OC1: R668.2 U10.E7(USB_OC1#/TDI/GEVENT13#)
USB_OC2: R681.2 U10.F7(USB_OC2#/TCK/GEVENT14#)
USB_OCP_0_6: C478.1 R645.1 R663.1 R679.1
USB_OCP_2_4: C320.1 R511.1 R512.1 R668.1
USB_OCP_5_9: C330.1 R517.1 R519.1 R681.1
USB_RCOMP_R: R670.1 U10.G19(USB_RCOMP)
USB_SB_REAR_P_DN2_FILTER: CN19.2(D-) L39.3 Q50.1 R507.2
USB_SB_REAR_P_DN4_FILTER: CN18.2(D-) L38.2 Q50.3 R506.2
USB_SB_REAR_P_DN5_FILTER: CN16.2(D-) L36.2 Q49.3 R502.2
USB_SB_REAR_P_DN9_FILTER: CN17.2(D-) L37.3 Q49.1 R503.2
USB_SB_REAR_P_DP2_FILTER: CN19.3(D+) L39.2 Q50.6 R508.2
USB_SB_REAR_P_DP4_FILTER: CN18.3(D+) L38.3 Q50.4 R505.2
USB_SB_REAR_P_DP5_FILTER: CN16.3(D+) L36.3 Q49.4 R513.2
USB_SB_REAR_P_DP9_FILTER: CN17.3(D+) L37.2 Q49.6 R504.2
V_AMP: C281.1 C282.1 C507.1 C520.1 L67.2 R411.1 U25.15(VP1) U25.16(VP2)
VCT_LAN: C318.2 CN23.5 CN23.6
VGA_BLUE: CN1.172(VGA_BLUE) R61.1 R61.2 R70.1
VGA_GREEN: CN1.170(VGA_GREEN) R62.1 R62.2 R71.1
VGA_RED: CN1.168(VGA_RED) R63.1 R63.2 R72.1
VLDT_HT3_RUN_B: C370.1 U6.H1(VLDT_B_1) U6.H2(VLDT_B_2) U6.H5(VLDT_B_3) U6.H6(VLDT_B_4)
VLDT_P1V2: C422.1 C423.1 C531.1 C555.1 R227.1 R568.1 R579.1 U19.1(VOUT#1) U19.2(VOUT#2) U19.3(VOUT#3)
VREF_AUD: C283.1 U23.27(VREF)
VREF_DDR: PC18.2 PU3.5(VTTREF)
VREF_SIO: C295.1 U11.52(VREF)
VRM_PWRGD: D7.C PC7.2 PU2.41(PWRGOOD) R16.2 R314.1
VSYNC: CN1.162(VGA_VSYNC) R65.1 R65.2
VSYNC_N: R97.1 R97.2 R128.2 R130.1 U3.B11(DAC_VSYNC(PWM_GPIO6))
WLAN_ON: CN2.20(W_DISABLE*) R611.1 R632.2 R634.1 U10.B26(SCL3_LV/GPIO195)
XDCDN: CN13.P40(XD-CD) U5.12(XDCDN)
XDCEN: CN13.P37(XD-CE) U5.13(XDCEN)
XDCIS: R195.1 R198.1 U5.14(XDCIN)
XDRDN/MSINS: R154.2 R173.1 U5.11(CTRL4)
XDWPN: R160.2 U5.15(XDWPN)
N52255643: R540.2 R545.1 R551.2
N56144747: C89.2 Q7.G R118.2 R119.2
N87830775: CN1.27(PNL_BL_PWM) R31.2
N87830784: CN1.25(PNL_BL_EN) R32.2
N87830786: CN1.23(PNL_PWR_EN) R33.2
N174239812: R366.2 U10.H1(SLP_S5#)
N174239814: R364.2 U10.F1(SLP_S3#)
N182610771: C198.1 R263.2
N182623261: C204.1 R261.2
N182697602: C122.1 R169.1 R177.1
N182697659: R191.1 U5.21(CTRL0)
N182697747: CN13.P26(MS-SCLK) R168.2
N182697749: CN13.P23(MMC-DAT5) R171.2
N182697751: CN13.P18(MMC-DAT6) R192.2
N182697755: CN13.P16(MMC-DAT7) R197.2
N182697757: CN13.P27(MMC-DAT4) R164.2
N182697759: CN13.P22(MS-INS) R173.2
N182697767: CN13.P12(SD-DAT1) R203.2
N182697769: CN13.P30(SD-DAT2) R172.2
N182697771: CN13.P29(SD-DAT3) R174.2
N182697773: CN13.P14(SD-DAT0) R202.2
N182697798: CN13.P38(XD-RE) R154.1
N182697803: CN13.P36(XD-CLE) R156.1
N182697808: CN13.P15(MS-DATA1) R200.2
N182697810: CN13.P19(MS-DATA2) R186.2
N182697812: CN13.P34(XD-WE) R158.1
N182697814: CN13.P33(XD-WP) R160.1
N182697816: CN13.P39(XD-R/B) R152.1
N182697915: R161.2 U5.27(CTRL1)
N182698008: R170.2 U5.3(REXT)
N182698044: LED1.C R165.1
N182698057: R166.2 U5.1(EXT48IN)
N182846361: Q3.D Q4.G Q5.G R88.1 R99.2
N183186081: R413.2 U11.54(CPUTIN)
N183186300: R409.2 U11.55(SYSTIN)
N183418266: R448.2 U11.10(LRESET#)
N183418576: R368.2 U11.9(LFRAME#)
N184743934: Q1.D R39.2
N184744092: Q2.D R40.2
N185605081: R332.2 R347.1 U23.9(DVDD-IO)
N185663521: CN21.6(PIN6) R686.2
N185663595: L65.1 R695.1 R713.2
N185663597: L63.1 R680.1 R691.2
N185693726: C326.1 U25.12(OUT2A) U25.13(OUT2B)
N185693750: C319.1 U25.8(OUT1A) U25.9(OUT1B)
N187384381: Q37.D R348.2 R430.1 R452.1
N187384477: Q25.D R337.2 R374.1 R429.1
N187857917: R385.2 U11.58(VTT)
N188827131: R365.2 U10.F2(PWR_BTN#)
N188975577: R477.2 U11.40(GP34/ATXPGD)
N192917727: C317.2 C551.2 R518.1 R761.2 U17.4(G)
N192922009: L6.1 PC115.2 PQ6.D(5) PQ8.S1(1) PQ8.S2(2) PQ8.S3(3) PU5.7(SW) R48.2 R533.1
N192922017: PQ8.G1(4) R84.2
N192922021: PQ7.G1(4) R86.2
N192922293: L10.1 PC116.2 PQ5.D(5) PQ7.S1(1) PQ7.S2(2) PQ7.S3(3) PU4.7(SW) R47.2 R532.1
N192922340: D6.C PU4.1(BST) R530.1
N192922344: PU4.3(EN) R53.2
N192922348: PQ5.G1(4) PU4.5(DRVL)
N192922350: PU4.8(DRVH) R86.1
N192922354: PC116.1 R530.2
N192922358: PC36.2 PU4.4(VCC) R52.2
N192922382: D5.C PU5.1(BST) R529.1
N192922384: PC115.1 R529.2
N192922424: PC119.1 R532.2
N192922446: PC120.1 R533.2
N192922456: PU5.3(EN) R54.2
N192922460: PQ6.G1(4) PU5.5(DRVL)
N192922462: PU5.8(DRVH) R84.1
N192922466: PC35.2 PR38.1 PU5.4(VCC)
N192993943: PC16.1 PR33.2 PU2.11(12VMON)
N192993945: PR13.1 PR74.1 PU2.8(VDD_OFFSET)
N192993947: PR7.2 PR76.1 PU2.21(ILIM)
N192993966: PR16.1 PR75.1 PU2.10(V_FIX)
N192993980: PR12.1 PR18.1 PU2.9(VDD_DIFFOUT)
N192993988: PC9.2 PR3.2 PU2.38(ENABLE)
N192993994: PR4.2 PU2.37(PWROK)
N192994000: PC1.1 PC102.1 PR5.2 PU2.1(VCCA) PU2.22(VCCB)
N192994006: PR10.1 PR73.1 PU2.29(NB_OFFSET)
N192994026: PC8.1 PR8.2
N192994032: PC10.2 PC11.2 PU2.3(VDD_COMP)
N192994036: PC15.2 PR35.1 PR71.1 PU2.13(VDD_CS1)
N192994062: PR17.2 PU2.31(NB_VS+)
N192994066: PU2.36(VID1) R18.2 R20.2
N192994068: PC2.1 PC101.2 PR8.1 PR9.2 PR63.2 PR69.1 PU2.33(NB_FB)
N192994078: PR7.1 PU2.27(ROSC)
N192994094: PC4.2 PC11.1 PR1.2 PR6.1 PR12.2 PR64.1 PU2.4(VDD_FB)
N192994131: PC2.2 PC8.2 PU2.34(NB_COMP)
N192994159: PQ3.G1(4) PU1.5(DRVL)
N192994176: PR30.2 PU1.3(EN)
N192994181: PC24.2 PR28.1 PU1.4(VCC)
N192994193: PQ4.G1(4) PR36.2
N192994197: D4.C PR77.1 PU1.1(BST)
N192994201: L5.1 PC114.2 PQ3.D(5) PQ4.S1(1) PQ4.S2(2) PQ4.S3(3) PR31.2 PR78.2 PU1.7(SW)
N192994203: PC114.1 PR77.2
N192994205: PR36.1 PU1.8(DRVH)
N192994229: PU2.12(PSI_L) R29.2
N192994235: PC107.1 PR78.1
N192994292: PR64.2 PU2.5(VDD_DROOP)
N192994300: R27.2 R29.1 R43.1
N192994369: PR63.1 PR66.1 PU2.28(NB_DIFFOUT)
N192994816: PR69.2 PU2.32(NB_DROOP)
N192995254: PC4.1 PR18.2
N192995282: PC101.1 PR66.2
N192995298: PR22.2 PU2.6(VDD_VS+)
N192995372: PC10.1 PR6.2
N193056398: PR57.1 PU9.31(ILIM2)
N193056406: PC82.1 PC86.1 PC88.1 PC146.1 PC147.1 PL15.1 PQ11.D1 PQ11.D2(2) PQ11.D3(3) PQ11.D4(4)
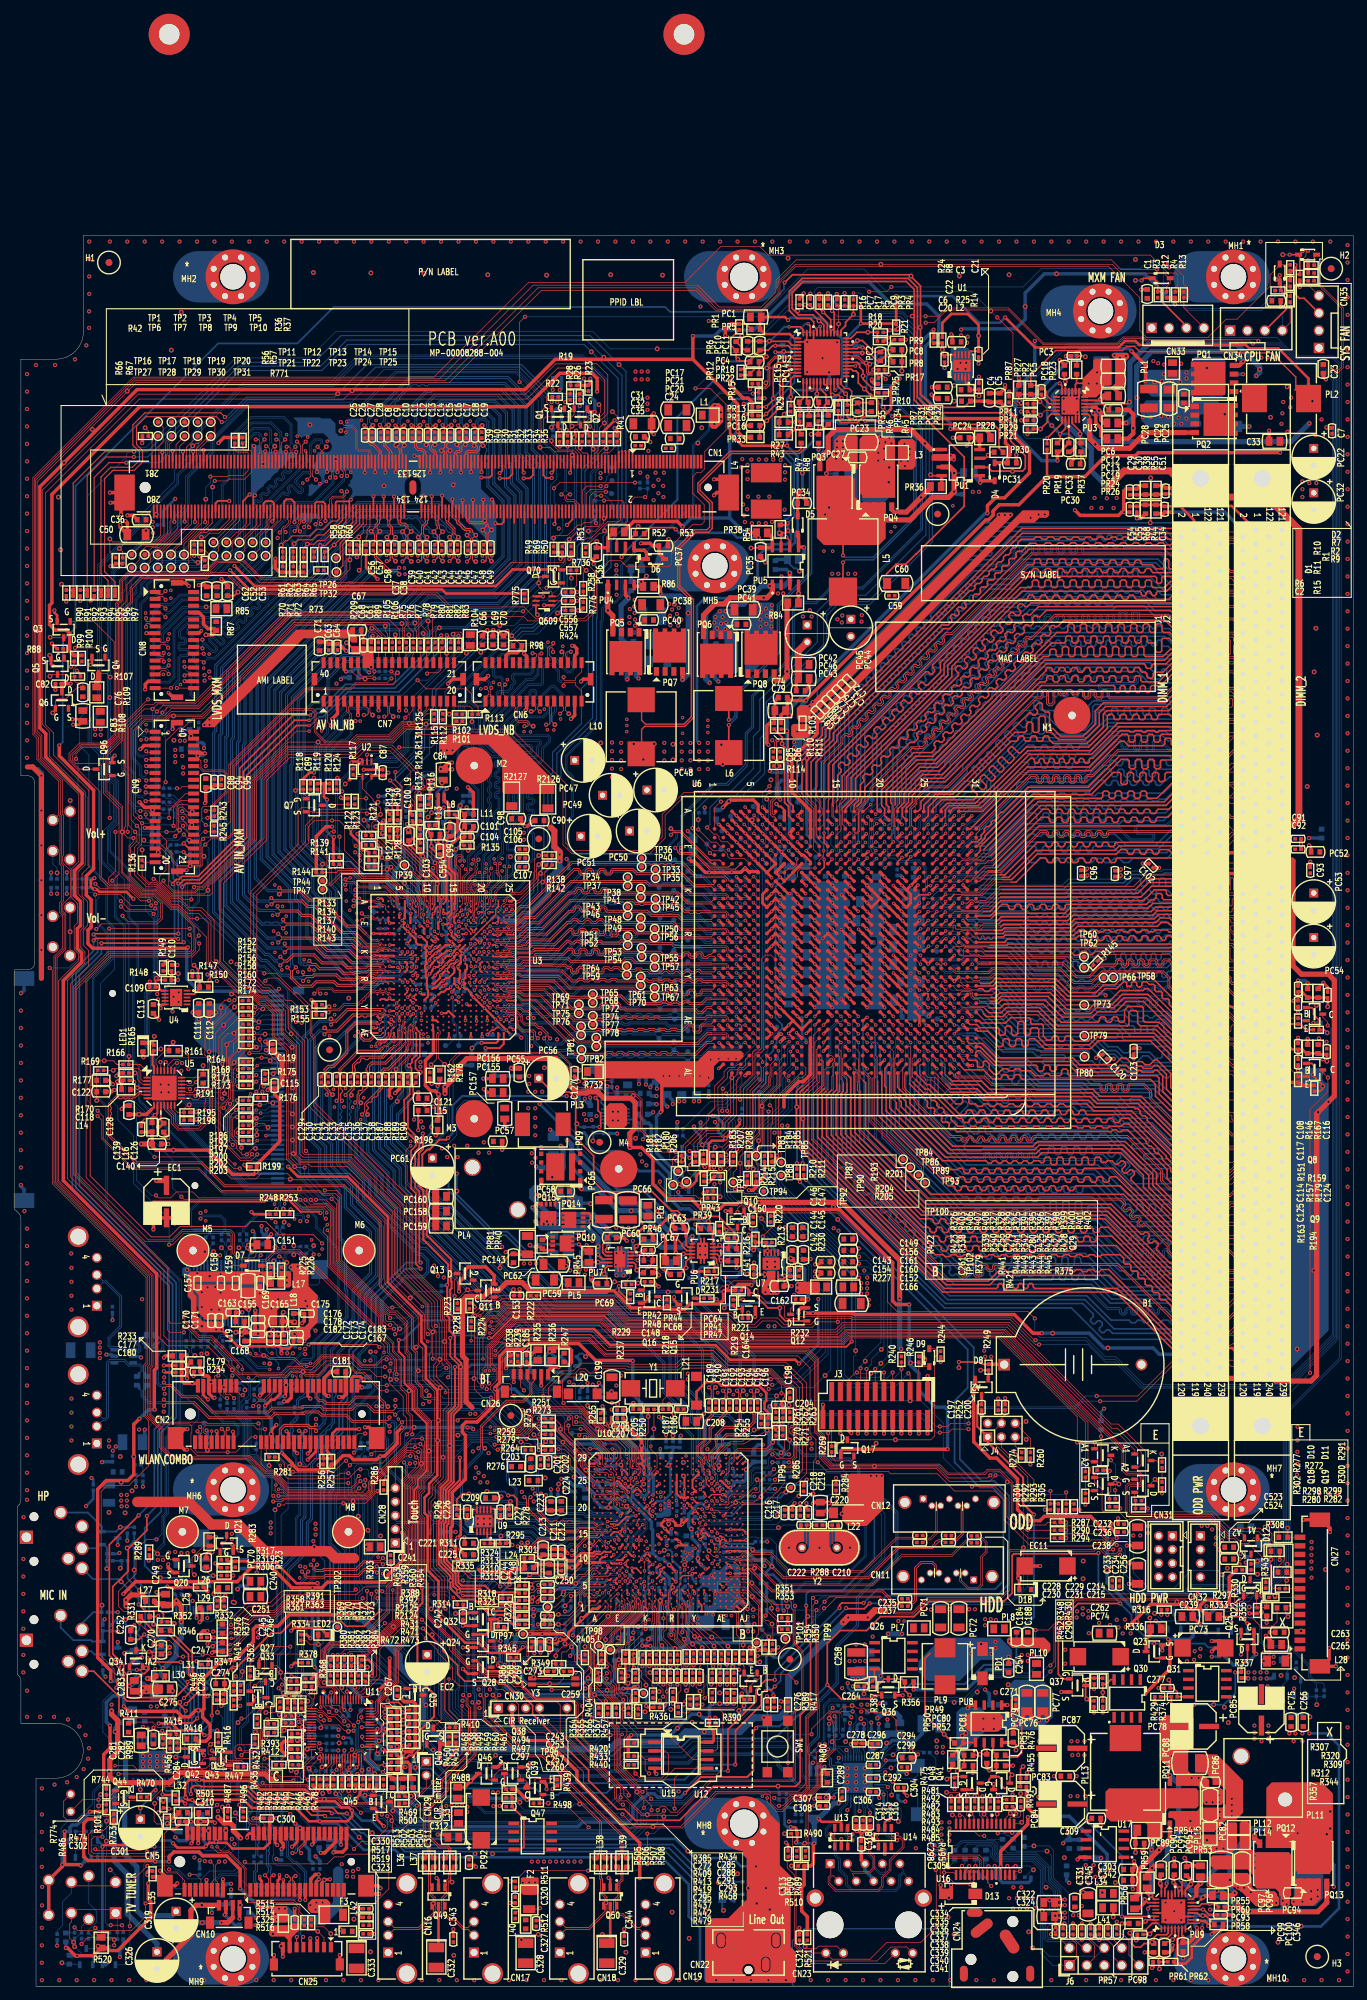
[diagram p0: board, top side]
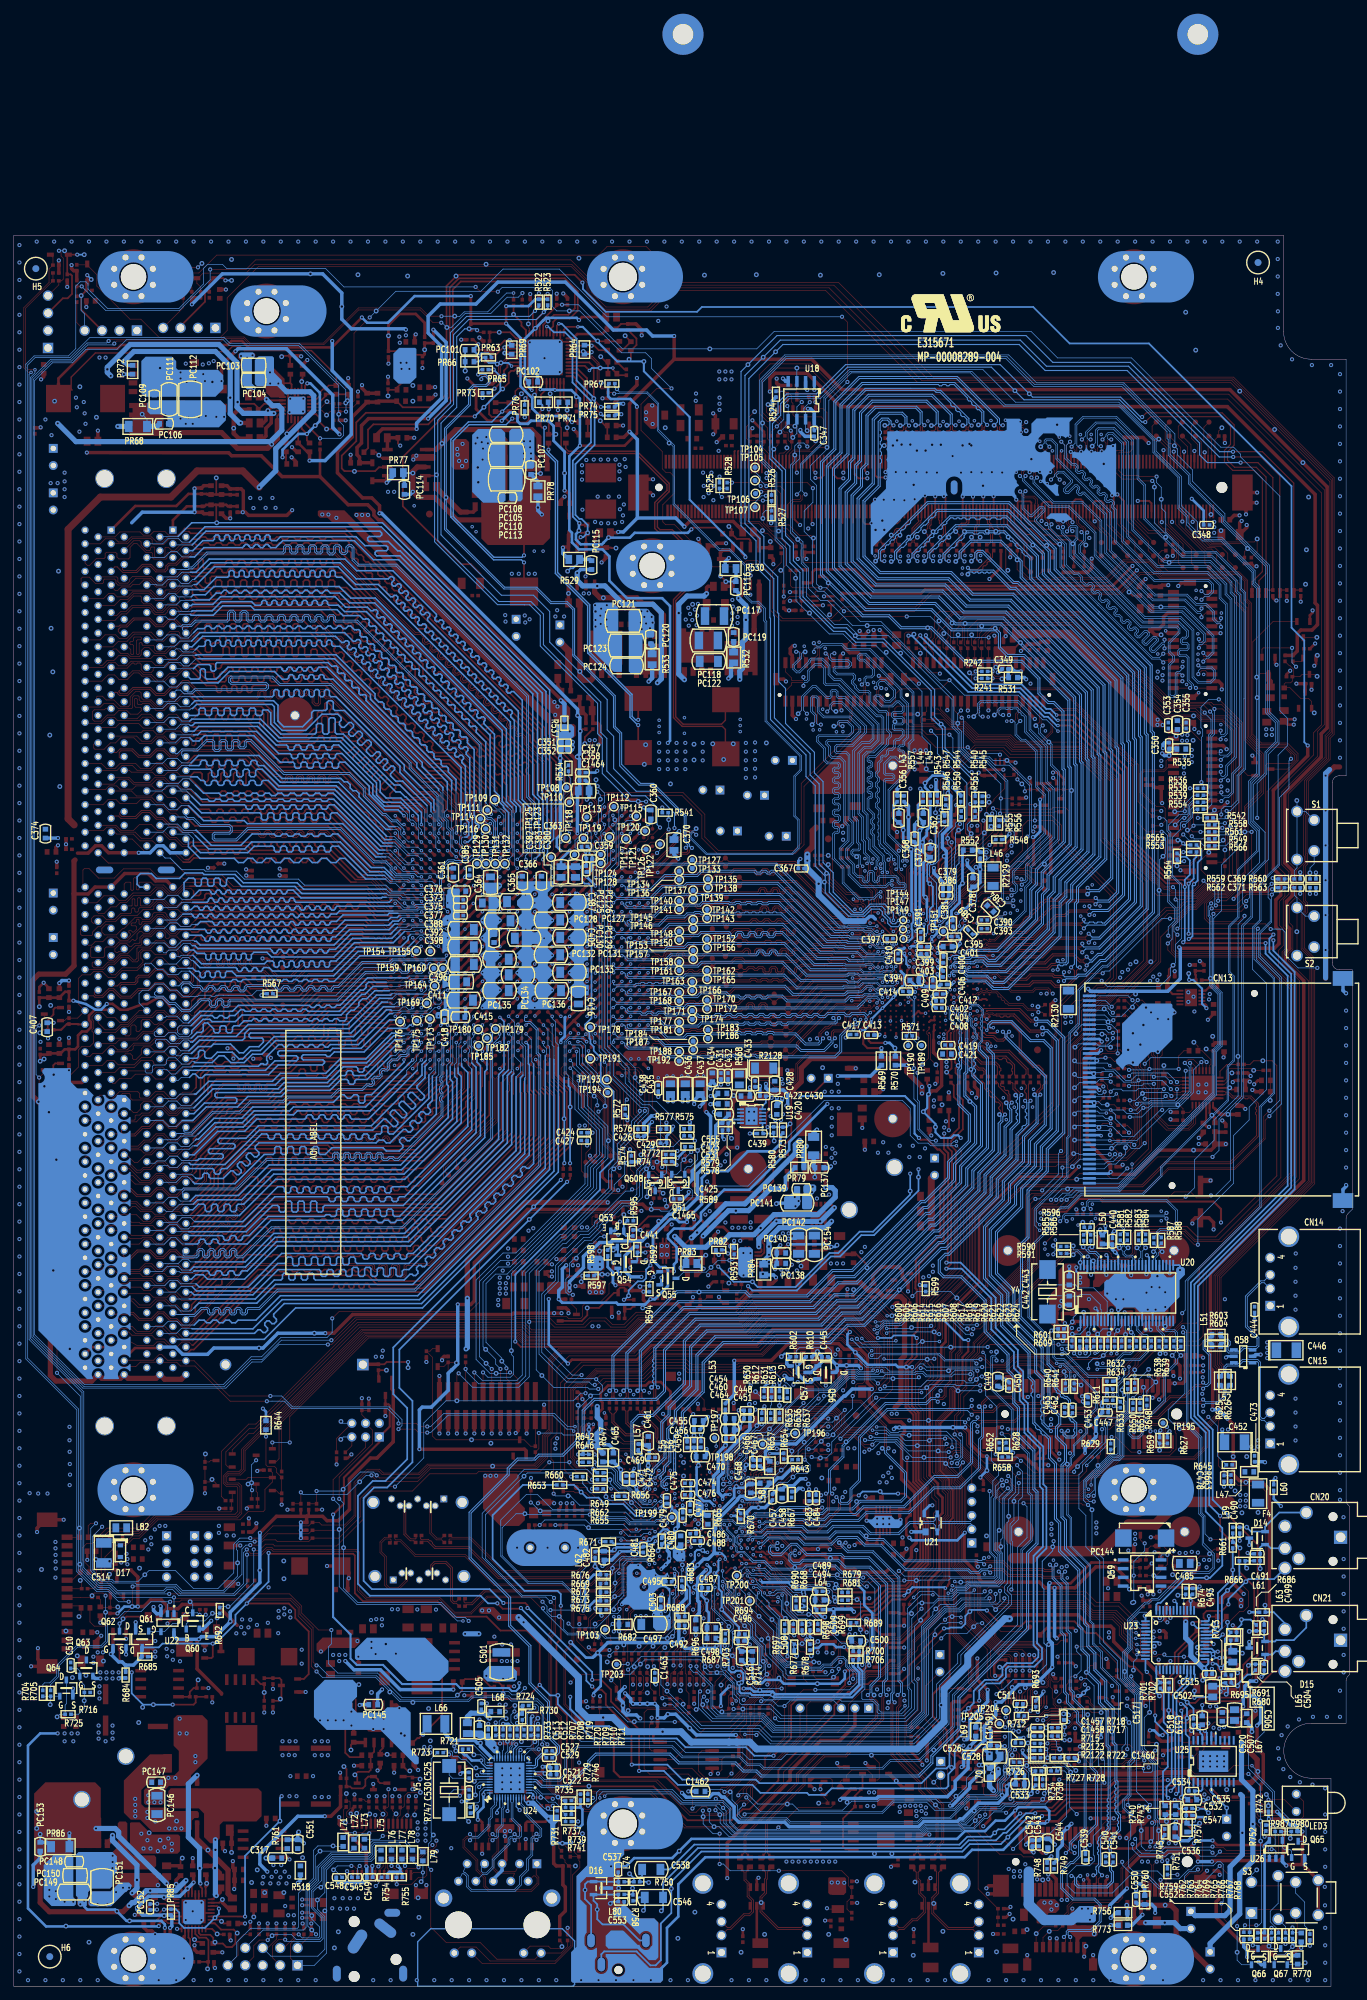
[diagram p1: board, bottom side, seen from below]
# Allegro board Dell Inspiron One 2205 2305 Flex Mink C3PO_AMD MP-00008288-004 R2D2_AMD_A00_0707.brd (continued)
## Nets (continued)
N193056421: PL11.2 PQ12.S1(1) PQ12.S2(2) PQ12.S3(3) PQ13.D(5) PR53.1 PR86.1 PU9.16(PHASE1)
N193056423: PC95.1 PR53.2
N193056457: PR61.2 PR62.1 PU9.4(ENLDO)
N193056459: PC95.2 PU9.17(BOOT1)
N193056479: PQ12.G1(4) PR55.1
N193056505: PR58.1 PU9.12(ILIM1)
N193056515: PQ13.G1(4) PU9.18(LGATE1)
N193056523: PR55.2 PU9.15(UGATE1)
N193057133: PQ11.G3(8) PU9.23(LGATE2)
N193057135: PQ11.G2(1) PR56.2
N193057155: PL13.1 PQ11.G1 PR54.1 PR59.2 PU9.25(PHASE2)
N193057159: PC89.1 PR54.2
N193057381: PC99.1 PU9.3(VCC) PU9.32(FB2)
N193057437: PC90.2 PR59.1
N193057441: PR56.1 PU9.26(UGATE2)
N193057451: PC90.1 PU9.24(BOOT2)
N193057466: PC100.1 PU9.5(NC_1)
N193057470: PC98.1 PU9.1(REF)
N193064874: C430.1 R573.2 R580.1 U19.10(VDD)
N193064906: R578.1 R579.2 U19.4(ADJ)
N193064914: C439.1 R580.2 U19.6(EN)
N193065496: C142.1 R230.2 R597.1 U7.10(VDD)
N193065531: R213.2 R216.1 U7.4(ADJ)
N193065687: C109.1 R148.2 U4.6(EN)
N193065695: C110.1 R148.1 R149.2 U4.10(VDD)
N193065727: R147.1 R150.2 U4.4(ADJ)
N193065785: C22.1 R8.1 R24.2 U1.10(VDD)
N193065820: R14.1 R25.1 U1.4(ADJ)
N193065828: C21.1 R8.2 U1.6(EN)
N193066078: Q21.D R306.1 R319.1 R323.2
N193066341: C226.1 R278.1 R296.2 U9.10(VDD)
N193066404: R295.1 R311.1 U9.4(ADJ)
N193066412: C227.1 R278.2 U9.6(EN)
N193073716: PR21.2 PU3.12(TON)
N193073747: PQ1.G1(4) PR24.2 PR72.1
N193073757: PC25.1 PC28.1 PC29.1 PC109.1 PC111.1 PC112.1 PL1.1 PQ1.D(5) PR21.1
N193073929: PC3.2 PR23.1
N193074055: PC19.2 PR26.1
N193074069: PC106.1 PR68.2
N193081910: C254.1 C271.1 PC76.1 PC77.1 PL10.2 PR51.2 PU8.2(VIN)
N193081924: PC71.1 PC72.1 PL7.1 PL9.2 PR49.2
N193082210: PC145.2 PD1.C PL9.1 PU8.3(SW)
N193082214: PR49.1 PR50.2 PU8.5(FB)
N193082220: PC80.1 PC81.1 PU8.6(COMP)
N193082230: PC145.1 PU8.1(BOOT)
N193082234: PC80.2 PR52.1
N193082279: PR51.1 PU8.7(EN) Q41.D R476.1
N193082337: PC79.2 PU8.8(SS)
N193417260: Q60.C Q61.G R316.2 U22.4(1Y)
N193492984: Q62.D R333.2
N193492998: Q23.D R336.2
N193522844: Q46.D R488.2
N193522855: C297.1 Q38.D Q47.4 R494.2 R497.1
N193554651: C311.1 C312.1 L33.1 PC92.1 Q47.1 Q47.2 Q47.3
N194450047: PC14.2 PR34.1 PR70.1 PU2.17(VDD_CS3)
N194724765: Q24.G Q32.C R322.1
N194724769: C242.1 Q32.B R314.2
N194724824: Q24.D Q28.D R345.1 R689.1
N194724852: Q11.C Q13.G R228.1
N194724856: C153.1 Q11.B R224.2
N194724902: Q13.D R133.1 R599.1
N195279140: CN29.1 R469.1
N195279169: CN29.2 R500.1
N195279187: Q45.B R499.2
N195352331: R417.1 SW1.3(B) SW1.4(B1)
N195361688: CN6.27 R98.2
N195453329: R28.1 U18.6(SCL)
N195453367: R22.1 U18.7(WP)
N195453377: R524.1 U18.3(A2)
N195454034: CN8.27 R87.2
N195764479: R747.1 U24.46(RSET)
N195806874: CN23.L2 R521.2
N196390709: R726.2 U11.43(GP30/SLP_S5#)
N196851843: C274.1 U23.12(PCBEEP-IN)
N197768843: C141.1 R597.2 U7.6(EN)
N198554672: R643.1 U10.F25(EC_PWM0/EC_TIMER0/GPIO197)
N198880140: Q60.B R692.2
N199565995: L59.1 R661.2
N199565999: L61.1 R666.2
N200059938: R26.2 U18.5(SDA)
N200259909: L80.1 R758.2
N200335304: C538.2 R750.1
N200335513: C546.2 R758.1
N200484025: R560.1 S1.1
N201366209: CN34.3 D1.C R6.2
N201366217: CN34.4 R15.2
N201366253: CN33.3 D3.C R3.2
N201366255: CN33.4 R13.2
N201793917: CN26.5 R239.2
N203761921: F2.2 L40.1
N203766757: F3.2 L42.1
N204331890: PL4.1 PQ10.S1(1) PQ10.S2(2) PQ10.S3(3) PQ14.D(5) PQ15.D(5) PR40.2 PR81.1 PR84.2 PU7.8(SW)
N204331892: PC143.1 PR81.2
N204331896: PR48.1 PU7.2(TRIP)
N204331899: PR46.1 PU7.5(RF)
N204331902: PU7.3(EN) Q55.D R593.2
N204331904: Q10.C Q55.G R594.2
N204331910: C150.1 Q10.B R220.2
N204331919: PC69.1 PU7.10(VBST)
N204331920: PC69.2 PR84.1
N204331927: PC59.1 PC62.1 PC138.1 PC140.1 PC142.1 PC154.1 PL5.1 PQ10.D(5)
N204331931: PR45.1 PU7.9(DRVH)
N204331932: PQ10.G1(4) PR40.1 PR45.2
N204331939: PC67.1 PR42.2 PR82.1 PU7.4(VFB)
N204332065: C148.1 Q16.B R229.1
N204332069: Q15.G Q16.C R218.2
N204332072: PU7.1(PGOOD) R229.2 R237.1
N205761409: C164.1 Q14.B R219.1
N205761415: PL3.1 PQ9.G1 PR79.2 PR80.1 PR83.2 PU6.8(SW)
N205761421: PC58.1 PC65.1 PC66.1 PC139.1 PC141.1 PL6.1 PQ9.D1 PQ9.D2(2) PQ9.D3(3) PQ9.D4(4)
N205761425: Q12.G Q14.C R221.2
N205761490: PU6.1(PGOOD) R217.1 R219.2
N205761590: PC137.1 PR80.2
N205761596: PR47.1 PU6.2(TRIP)
N205761604: PU6.3(EN) Q54.D R592.2
N205761606: Q53.C Q54.G R598.2
N205761614: PR39.1 PU6.5(RF)
N205761624: C441.1 Q53.B R595.2
N205761636: PC68.2 PR83.1
N205761638: PC68.1 PU6.10(VBST)
N205761660: PQ9.G2(1) PR44.2 PR79.1
N205761662: PR44.1 PU6.9(DRVH)
N205761686: PC64.1 PR41.2 PR43.1 PU6.4(VFB)
N205761688: PQ9.G3(8) PU6.6(DRVL)
N206167081: LED3.A R742.1
N206210192: R335.1 U10.A8(VIN7/GBE_LED3/GPIO182)
N207033685: LED2.A R334.2
N208253507: C270.1 U23.30(CBN)
N208253520: C270.2 U23.29(CBP)
N208262425: C252.2 U23.31(CPVEE)
N208289349: L74.1 R750.2
N208402932: Q34.A2 R713.1
N208403148: Q34.A1 R691.1
N208745696: CN35.3 D2.C R1.2
N208745698: CN35.4 R9.2
N208938368: C502.2 R695.2
N208939242: C506.2 R680.2
N209450511: C61.1 C68.1 CN7.33 CN7.34 R209.2
N209450591: C349.1 CN7.37 R531.2
N210544606: C350.1 CN9.37 R535.2
N211359803: Q48.G R475.2
N211486769: Q36.D R356.2 R387.1
N212412188: C445.1 Q56.G Q57.D R610.2
N212418796: Q57.G R602.2
N214468883: Q44.D R470.1
N214468911: Q42.D R456.2
N214468913: Q42.G Q43.D R416.2
N214468931: Q43.G R447.2
N214485400: C284.1 R411.2 R415.1 R418.2
N214797167: Q18.D R280.1 R298.2
N214902487: Q19.D R291.2 R300.1
N214902576: Q22.D R297.1 R330.2
N215117175: C532.1 C547.2 R743.2 R757.2
N215339663: Q64.D R725.1
N215339673: Q64.G R704.2 R705.2
N215401845: R768.1 S3.3 S3.4
N215440771: Q66.G R358.2 R435.2
N216543933: R485.2 U16.19(R5OUT)
N218750210: R563.1 S2.1
N218776850: C510.1 Q63.G R716.1 R725.2
N219210322: Q27.B R361.1 R432.2
N219249647: Q27.C R376.1 R745.2
N220111595: EC2.2 Q40.D
N220115319: Q40.G R410.2
N220126171: Q67.S R770.1
N221267533: Q51.D R205.1
N222009354: EC2.1 Q33.B R362.2 R377.1 R378.2
N222009357: R376.2 R377.2
N222245952: Q44.G R744.2 R1017.1
N222245969: Q44.S R753.2
N222289486: R414.2 U23.47(EAPD)
N222354100: L14.2 U5.4(VD33R)
N224524412: C532.2 R774.1
N224651695: Q65.D R989.2
N224726667: PC153.1 PR86.2
N224816065: PQ14.G1(4) PQ15.G1(4) PU7.6(DRVL)
N225179532: C1457.1 R718.2
N225179536: C1458.1 R717.2
N225179540: C1459.1 R715.2
N225179544: C1460.1 R722.2
N228109207: C557.1 Q609.2(G1) R424.2
N228109241: Q609.5(G2) Q609.6(D1) R775.2
N228109265: Q70.S R736.2
N228231724: Q608.G R74.2 R772.2
N228265287: Q51.G R73.2 R589.1
N229090690: F4.2 L47.1
N229157893: Q9.B R194.2
N229157940: Q8.B R159.2
N229158005: Q29.B R375.2

Pads without a net: CN1 10 12 14 16 29 38 39 40 41 42 43 44 45 48 49 50 51 54 55 56 57 60 61 62 63 66 67 68 69 72 73 74 75 78 79 80 81 84 85 86 87 90 91 92 93 159 161 163 165 167 227 229 231 233 235 237 238 239 240 241 242 243 245 247 249 XH1 XH2; CN2 42 44 45 46 47 49; CN5 3 5 8 10 12 14 16 17 19 30 32 42 44 45 46 47 49 51; CN6 25 26; CN8 25 26; CN10 MH1 MH2; CN26 MH1 MH2; H1 1; H2 1; H3 1; H4 1; H5 1; H6 1; J1 53 68 79 126 135 144 153 162 167 198 204 213 222 231; J2 53 68 79 126 135 144 153 162 167 198 204 213 222 231; J4 2; NOREF 1; NOREF#2 1; NOREF#4 1; NOREF#5 1; NOREF#6 1; NOREF#7 1; PU2 25 26 35; PU3 7; PU9 2 28; U1 5; U2 1; U3 A3 A14 AA12 AA15 AA17 AA18 AA19 AA20 AB12 AB13 AB14 AB16 AB18 AB20 AC14 AC16 AC18 AC20 AC22 AD13 AD14 AD15 AD16 AD17 AD18 AD19 AD20 AD21 AD22 AE13 AE15 AE16 AE17 AE19 AE21 AE22 B3 B14 C1 C2 C4 D4 E1 E2 E5 E8 F1 F2 F3 F4 F5 F8 G5 G6 H3 H4 H5 H6 J5 J6 J7 J8 U1 U2 U5 U6 U7 U8 V1 V2 V5 V11 V14 V17 W6 W12 W17 W18 Y1 Y2 Y3 Y4 Y12 Y14 Y15 Y17 Y19; U4 5; U6 AD25 AE24 AE25 AJ18 AJ20 AK3 B2 C18 C20 D1 D2 E1 F2 G24 G25 H25 L25 L26 L30 L31; U7 5; U9 5; U10 A12 A22 A23 A24 A25 A26 A27 AA1 AA3 AA4 AA5 AA6 AA8 AA10 AA22 AA24 AA25 AA28 AA29 AB1 AB2 AB5 AB6 AB9 AB11 AB12 AC1 AC2 AC3 AC4 AC5 AC6 AC12 AC18 AD1 AD2 AD5 AD7 AD8 AD19 AE1 AE2 AE3 AE4 AE6 AE7 AE8 AE11 AE29 AF2 AF3 AF5 AF8 AF12 AF14 AF17 AF21 AF23 AF27 AF28 AF29 AG1 AG2 AG12 AG14 AG17 AG21 AG23 AG25 AG26 AG29 AH3 AH5 AH12 AH14 AH17 AH18 AH19 AH22 AH23 AH24 AH25 AH26 AH27 AJ3 AJ5 AJ12 AJ14 AJ17 AJ18 AJ19 AJ22 AJ23 AJ24 AJ25 AJ26 AJ27 B12 B22 B23 B24 B25 B27 C22 C24 C26 D3 D22 D24 D26 D27 E11 E23 E24 E27 F4 F5 F11 F21 F28 F29 G27 G29 H9 H11 J8 J10 L6 L23 L24 L28 L29 M5 M7 M9 M25 M28 M29 N26 N27 N28 N29 P4 P5 P7 P9 P25 P28 P29 T2 T5 T7 T9 T21 T23 T25 T26 T27 T28 T29 U1 U2 U3 U28 U29 V9 V21 V23 V24 V25 W6 W8 W23 W24 W25 W28 W29 Y2 Y9 Y21 Y26 Y27 Y28 Y29; U11 35; U19 5; U20 27 28 31 32 46 47; U23 14 15 16 17 18 19 20 37 39 41 43 44 45; Y3 2 3

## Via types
v1: diameter 0.711, hole 0.356, TOP to BOTTOM, 1050 vias
v2: diameter 0.61, hole 0.305, TOP to BOTTOM, 3332 vias
v3: diameter 0.508, hole 0.254, TOP to BOTTOM, 1268 vias
v4: diameter 0.457, hole 0.254, TOP to BOTTOM, 12 vias
v5: diameter 0.711, hole 0.305, TOP to BOTTOM, 59 vias
v6: diameter 0.711, hole 0.254, TOP to BOTTOM, 4 vias

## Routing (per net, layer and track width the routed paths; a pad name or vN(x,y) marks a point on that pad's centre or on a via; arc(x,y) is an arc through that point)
AVDD: length 20.2
  TOP w0.3: v3(62.04,155.28) 61.69,154.93 U3.E12 61.68,154.85 61.68,154.07 U3.F12
  BOTTOM w0.25: 61.97,157.13 61.97,155.36 v3(62.04,155.28)
  BOTTOM w0.4: C372.1 61.64,164.45 ; 61.64,164.45 62.46,163.63 62.46,158.91 v1(62.18,158.62) 61.97,158.41 61.97,157.13 ; 61.64,164.45 61.72,164.45 62.46,165.19 62.46,167.17 61.99,167.64 61.99,168.4 61.48,168.91 L45.2
AVDD33_LAN: length 67.3
  TOP w0.381: U14.5 126.76,23.88 127.14,24.26 v2(127.39,24.26) ; v2(113.8,20.95) 113.98,21.13 R490.1 113.98,22.49 113.87,22.61 113.87,22.99 113.68,23.18 v2(113.04,23.18) ; U13.5 120.41,23.76 120.2,23.96 117.54,23.96 v2(117.08,24.42) ; C289.1 120.03,27 v2(120.03,26.67)
  TOP w0.508: v2(116.47,20.83) 116.34,20.7 116.34,17.91 115.96,17.53 R510.1 114.99,14.78 114.64,14.43 114.64,10.97 115.45,10.16 R521.1
  BOTTOM w0.178: v2(121.17,34.42) 121.4,34.19 U24.27 ; v2(127.52,30.73) 127.34,30.56 U24.42 ; U24.12 120.6,26.99 120.28,26.67 v2(120.03,26.67) ; v2(126.88,32.89) 126.88,32.51 126.13,31.76 U24.39 ; U24.47 126.33,28.56 126.57,28.32 v2(126.57,27.94) ; U24.48 125.66,27.71 v2(125.93,27.43)
  BOTTOM w0.381: v2(116.47,20.83) v1(115.07,20.83) 113.93,20.83 v2(113.8,20.95) ; R721.1 129.6,33.95 129.3,33.65 129.04,33.65 128.28,32.89 v2(126.88,32.89) ; 112.43,26.04 112.15,25.76 112.15,23.56 112.53,23.18 v2(113.04,23.18) ; 112.43,26.04 R729.1 ; 112.43,26.04 R737.1 R739.1 ; R707.2 v2(124.79,38.42) ; v2(126.57,27.94) 126.57,26.1 127.39,25.27 v2(127.39,24.26)
  BOTTOM w0.508: v2(121.87,39.18) 121.37,39.67 R730.1 120.91,40.82 R724.1
  BOTTOM w0.762: v2(117.08,24.42) 116.79,24.12 ; 116.79,24.12 116.79,24.13 119.33,26.67 v2(120.03,26.67) ; 116.79,24.12 116.47,23.8 v2(116.47,20.83) ; R733.1 128.92,39.24 128.38,39.78 126.41,39.78 v2(125.68,39.05)
AVDD33_REG: length 1.9
  BOTTOM w0.178: 124.34,34.16 124.2,34.02 U24.34 ; U24.35 124.6,34.1 124.6,34.1
  vias: v1(124.98,34.74)
AVDDDI: length 19.7
  TOP w0.127: 63.19,154.06 U3.F14
  TOP w0.3: v3(63.64,154.51) 63.19,154.06
  BOTTOM w0.4: v3(63.64,154.51) 63.47,154.68 63.47,156.66 63.61,156.8 63.61,166.55 C368.1
  BOTTOM w0.508: R557.2 64.65,171.91 v1(64.65,170.31) 64.65,167.26 64.1,166.7 C368.1
AVDDQ: length 21.6
  TOP w0.3: 63.65,153 63.94,152.71 U3.H15
  TOP w0.305: 63.65,153 63.65,153.57 v3(63.56,153.66)
  BOTTOM w0.305: 63.01,156.96 63.01,154.38 63.59,153.8 63.59,153.69 63.56,153.66 v3(63.56,153.66)
  BOTTOM w0.381: C362.1 62.49,169.57 63.26,170.33 63.26,172.03 62.75,172.54 L44.2
  BOTTOM w0.4: 63.01,156.96 63.01,168.33 v1(63,168.34) 62.49,168.85 C362.1
GND: length 1785.4
  TOP w0.102: v3(56.44,142.46) 56.83,142.86 U3.Y6 ; 99.23,72.02 U10.AA23 ; 101.24,74.52 U10.AC26 ; U3.M6 56.84,149.21 ; 99.64,74.52 U10.AA26 ; 60.84,148.98 U3.M11 ; U10.E6 87.74,59.42 ; U3.H14 63.19,152.46
  TOP w0.127: 63.19,154.86 U3.E14
  TOP w0.178: v2(48.78,31.88) 48.91,32.01 U11.44
  TOP w0.229: U3.AD23 70.2,139.66 69.81,139.26 69.47,139.26 v3(68.84,138.63)
  TOP w0.254: U10.J7 90.53,60.9 v3(89.93,60.9) 89.93,60.58 89.93,60.43 U10.H7 ; U10.E9 U10.F9 ; v3(57.14,151.86) 57.64,152.36 U3.H7 ; U10.D23 v4(86.27,72.12) ; CN1.53 77,220.09 77.38,219.71 v2(78.21,219.71) ; U3.E15 64.04,155.01 U3.D15 ; v3(106.53,64.99) 106.46,64.92 U10.AJ13 U10.AH13 ; CN1.58 75.75,213.11 ; v2(76.36,57.45) 76.44,57.53 C250.2 ; v3(92.95,61.44) 92.79,61.44 U10.L8 ; CN1.11 87.5,220.48 ; CN1.151 v2(52.5,220.54) ; CN1.112 v2(62.25,217.13) ; PU2.45 116.38,238.53 ; CN1.71 72.5,220.23 71.92,219.65 v2(70.65,219.65) ; v2(59.49,217.04) 59.25,216.8 CN1.124 ; CN1.145 v2(54,220.5) ; U10.E25 87.82,73.53 88,73.53 88.38,73.15 88.38,72.98 U10.F24 88.62,72.82 89.37,72.07 v3(89.37,71.98) ; PU9.29 168.55,10.67 PU9.G ; v3(98.69,71.06) 99.33,70.42 U10.AA21 ; U3.L22 69.71,149.99 70.78,149.99 U3.L24 70.95,149.95 71.54,149.95 U3.L25 71.71,149.99 72.73,149.99 v3(72.76,150.01) ; U10.N4 94.04,57.33 v3(94.22,57.15) 94.45,56.92 U10.P3 ; v3(70.24,151.44) 70.02,151.66 U3.J22 ; U3.W7 57.64,143.65 v3(58.03,143.26) ; v3(57.24,144.06) 57.64,144.46 U3.V7 ; v3(70.23,145.08) 69.82,145.08 U3.U22 ; CN1.59 75.5,220.11 75.03,219.65 v2(74.15,219.65) ; U3.AB7 58.05,141.67 58.07,141.67 v3(58.08,141.66) ; v2(70.03,213.11) 70.16,212.98 70.92,212.98 71.25,213.31 CN1.76 ; v3(103.21,74.91) 102.84,74.54 U10.AE26 ; CN1.186 43.75,215.99 44,216.23 44.94,216.23 45.25,215.92 CN1.180 ; v2(76.34,78.87) 76.92,78.87 R259.1 ; CN1.119 v2(60.5,220.48) ; v3(94.09,59) 94.5,59.42 U10.P6 ; v3(103.2,65.25) 103.53,64.92 U10.AF13 ; v3(103.2,65.25) 102.91,65.54 U10.AE14 ; v3(103.2,65.25) 102.74,64.79 U10.AE12 ; CN1.52 77.25,213.13 77.23,213.11 ; v3(106.56,66.04) 106.09,66.51 U10.AJ16 U10.AH16 104.36,66.51 v3(104.3,66.57) 104.24,66.51 U10.AF16 ; CN1.203 39.5,223.51 v2(39.49,223.52) ; U3.H19 67.24,152.45 67.75,151.94 v3(67.75,151.99) 67.8,151.99 68.04,152.23 U3.H20 ; v2(80.91,220.47) 81,220.56 CN1.37 ; CN1.77 71,220.76 v2(70.65,220.41) ; v2(34.22,217.3) 33.25,216.33 CN1.228 ; U10.A2 83.81,56.12 v3(83.7,56.01) ; PU2.47 115.38,239.53 PU2.2 ; v3(66.98,146.24) 66.96,146.22 67.24,146.5 U3.R19 ; CN1.215 v2(36.5,223.58) ; U10.AF9 104.02,61.33 v3(104.02,61.32) 104.04,61.32 U10.AG8 ; CN1.36 81.25,213.65 v2(80.45,212.85) ; U3.G17 65.66,153.26 v3(65.75,153.34) ; U3.F18 66.44,154.05 v3(66.85,153.64) 67.24,154.03 U3.F19 ; U10.AH7 U10.AJ7 105.68,60.15 106.82,60.15 v3(106.82,60.16) ; U10.AD6 101.94,59.42 v3(101.48,59.88) ; U3.N22 69.84,148.26 v3(70.25,148.26) ; U3.W25 71.74,143.56 v3(72.91,143.56) ; PU9.G 169.54,10.17 PU9.11 ; PU9.G 168.55,11.17 ; U10.D12 87.23,63.73 v3(87.31,63.73) ; v3(69.23,142.51) 69.19,142.51 U3.Y21 ; v3(87.26,62.87) 86.91,62.52 U10.D10 ; U3.W1 53.38,143.8 53.9,143.8 U3.W2 54.31,143.66 v3(54.6,143.95) 54.6,143.97 54.91,143.66 U3.W4 ; CN1.113 v2(62,220.5) ; v3(54.84,140.86) 55.24,140.46 U3.AC4 ; U10.D17 87.25,67.32 v3(87.39,67.18) 87.88,67.18 U10.F18 89.09,68.4 89.54,68.4 ; CN1.15 86.5,220.49 ; CN1.82 69.75,216.31 v2(69.53,216.53) ; U3.C20 67.67,156.46 v3(67.55,156.34) ; CN1.191 42.5,223.49 v3(42.35,223.65) ; U10.J4 90.84,57.34 v3(91.06,57.12) ; 48.75,216.33 48.7,216.28 46.92,216.28 46.75,216.11 CN1.174 ; 48.75,216.33 v2(48.95,216.53) ; 48.75,216.33 CN1.166 ; v3(69.07,156.34) 69.2,156.46 U3.C22 ; v3(90.4,74.9) 90.04,74.54 U10.H26 ; U3.G22 69.81,153.1 v3(70.34,153.1) 70.68,153.1 U3.G24 ; U10.F14 88.15,65.93 v3(88.15,66.17) ; CN1.46 78.75,213.11 v2(78.62,212.98) ; PU9.22 168.04,11.67 168.55,11.17 ; PU3.17 154.56,229.5 155.06,229 PU3.18 ; CN1.89 v2(68,220.55) ; v3(67.67,144.05) 67.26,144.46 U3.V19 ; CN1.125 59,222.88 v2(58.22,222.88) ; U3.AE20 68.04,138.38 v3(68.09,138.33) ; v2(34.98,217.17) 34.75,216.94 CN1.222 ; CN1.47 78.5,220.76 v2(78.21,220.47) ; U3.D23 70.44,155.06 v3(70.24,154.86) 70.24,154.86 U3.E22 ; v2(76.16,56.01) 76.16,56.19 76.49,56.52 C253.2 ; v3(72.65,139.37) 72.36,139.66 U3.AD25 ; U3.V6 57.19,144.81 v3(57.19,145.26) ; U3.U15 63.66,144.88 v3(63.66,144.83) ; U10.D14 87.29,66.17 v3(88.15,66.17) ; U3.W22 69.82,143.48 v3(70.28,143.48) 70.67,143.48 U3.W24 ; U10.AB23 100.55,71.8 v3(100.55,71.42) ; U10.AB16 100.04,66.39 v3(100.04,66.01) 100.67,66.01 U10.AC14 ; U10.AH29 105.24,76.92 v3(105.82,77.5) ; U10.G9 88.93,61.68 v3(88.93,61.57) 88.93,61.43 U10.G8 ; v3(88.15,66.17) 88.54,66.56 U10.F16 ; v3(92.44,57.12) 92.44,57.12 U10.L4 ; v2(74.15,220.47) 74,220.62 CN1.65 ; 168.55,11.17 PU9.21 ; CN1.209 v2(38,223.52) ; CN1.139 v2(55.5,220.54) ; CN1.70 72.75,213.16 ; U3.E20 68.04,154.9 v3(68.44,155.3) ; U10.G4 89.24,57.23 v3(89.37,57.1) ; CN1.101 v2(65,220.52) ; v2(96.4,120.27) 96.58,120.09 R181.1 ; U10.AF11 103.74,63.42 104.16,63.42 v3(104.24,63.34) 104.32,63.42 104.74,63.42 U10.AH11 104.97,63.45 105.51,63.45 U10.AJ11 105.67,63.35 106.63,63.35 v3(106.71,63.27) ; C243.2 76.39,58.55 v2(76.29,58.45) ; U3.M20 67.79,148.95 v3(67.79,148.45) 67.79,147.96 U3.P20 ; CN1.118 v2(60.75,217.03) ; U3.C18 66.44,156.53 v3(66.19,156.78) ; U3.R7 57.64,146.67 v3(58.04,146.26) ; U3.L7 57.65,150.21 57.94,150.5 v3(57.94,150.66) ; CN1.107 v2(63.5,220.59) ; CN1.100 v2(65.25,216.45) ; CN1.94 v2(66.75,216.52) ; U10.AC9 100.89,62.34 v3(100.89,62.63) ; CN1.146 v2(53.75,217.02) ; v3(101.56,72.39) U10.AD23 ; v3(99.76,59.73) 100.24,60.22 U10.AB7 ; CN1.83 69.5,220.08 69.19,219.77 v2(67.99,219.77) ; v3(60.44,150.46) U3.K11 v3(61.24,151.26) ; CN1.134 v2(56.75,216.99) ; CN1.152 v2(52.25,217.04) ; U3.W8 58.44,143.66 v3(58.04,144.06) 58.43,144.46 U3.V8 ; U3.R22 69.78,146.72 70.7,146.72 U3.R24 70.96,146.74 71.53,146.74 U3.R25 71.73,146.77 72.73,146.77 v3(72.81,146.85) ; CN1.95 v2(66.5,220.56) ; U3.D11 60.84,156.21 v3(61.02,156.26) 61.27,156.63 61.27,156.89 U3.B12 ; U10.C7 86.38,60.46 v3(86.38,61.26) 86.73,60.92 U10.D8 ; CN1.133 v2(57,220.47) ; CN1.88 v2(68.25,216.53) ; C22.2 v2(135.46,235.71) ; v2(34.86,224.35) 35,224.2 CN1.221 ; CN1.17 86,220.5 ; CN1.197 v2(41,223.51) ; CN1.13 87,220.47 ; PU9.8 v2(171.21,8.36) ; CN1.157 v2(51,220.49) ; v3(72.84,153.32) 72.69,153.18 71.72,153.18 U3.G25 ; CN1.64 74.25,213.13 ; CN1.140 v2(55.25,216.99) ; CN1.106 v2(63.75,216.6)
  TOP w0.279: v2(40.75,213.26) CN1.198 40.75,216.15 40.31,216.59 39.55,216.59 39.25,216.29 CN1.204 ; CN1.180 45.25,213.45 v2(45.27,213.44) ; CN1.257 v2(26,223.53) ; CN1.192 42.25,213.49 v2(42.12,213.36) ; CN1.268 v2(23.25,213.31) ; CN1.275 v2(21.5,223.43) ; CN1.262 v2(24.75,213.35) ; CN1.185 v2(44,220.57) ; CN1.216 36.25,216 36.58,216.33 37.44,216.33 37.75,216.02 CN1.210 37.75,213.62 v2(37.52,213.39) ; CN1.250 v2(27.75,213.27) ; CN1.263 v2(24.5,223.53) ; v2(31.25,216.36) 29.59,216.36 29.25,216.01 CN1.244 ; CN1.173 v2(47,220.54) ; CN1.179 v2(45.5,220.59) ; CN1.256 v2(26.25,213.29) ; CN1.251 v2(27.5,223.75) ; CN1.269 v2(23,223.63)
  TOP w0.3: v3(64.69,152.91) 64.54,152.91 U3.G15 ; U10.K20 91.78,69.62 v3(92.15,69.98) ; v3(99.01,57.19) 99.01,57.54 U10.Y4 ; U10.AJ28 v3(106.63,76.58) ; U3.E4 v3(54.64,154.86) 54.44,155.06 54.44,155.66 U3.D3 ; U10.Y20 98.74,69.68 98.36,70.06 v3(98.36,70.04) 98.38,70.02 98.38,70.02 97.98,70.42 U10.W21 ; U3.B13 62.44,156.29 v3(62.48,156.26) 63.04,156.26 U3.C14 ; U10.AJ2 106.04,56.01 v3(106.43,55.62) ; v3(54.64,142.06) U3.AA4 ; U3.P6 57.14,148.01 57.14,148.01 v3(57.14,148.46) 57.14,148.47 57.14,149.06 56.99,149.21 56.84,149.21 ; v3(84.85,77.6) 85.24,77.2 U10.B29 ; U3.R11 v3(61.24,147.26) U3.P12 v3(62.04,148.06) U3.N13 v3(62.84,148.86) U3.M14 63.44,149.46 63.69,149.46 v3(63.82,149.58) 64.04,149.81 U3.L15 64.09,150.06 64.45,150.42 v3(64.45,150.42) ; U3.R14 63.22,146.86 63.79,147.43 ; v3(104.02,73.34) U10.AF25 ; U3.J12 61.54,151.26 v3(61.24,151.26) ; v3(55.24,138.26) 55.24,138.86 U3.AE4 ; U3.AB21 68.84,141.26 v3(68.84,140.66) ; 87.74,59.42 87.34,59.02 v3(87.34,58.99) 87.36,58.99 87.56,58.79 87.56,58.79 U10.E5 ; v3(99.37,75.15) 99.64,74.87 99.64,74.52 99.5,74.52 98.74,73.75 98.74,72.59 99.23,72.1 ; v3(54.64,145.26) U3.U4 ; 61.72,149.83 61.42,149.83 v3(61.24,149.66) 61.24,149.46 60.84,149.06 60.84,148.98 60.36,148.5 v3(60.36,148.47) ; v3(54.62,148.57) 54.73,148.46 U3.N4 ; 63.19,154.86 63.02,154.69 v3(62.39,154.69) ; 101.24,74.52 101.24,74.95 v3(101,75.13) ; v3(52.27,153.34) 53.16,153.34 U3.G1 53.32,153.33 53.97,153.33 U3.G2 54.14,153.35 v3(54.59,153.35) 55.15,153.35 ; 63.19,152.46 63.49,152.16 v3(63.64,152.16) 64.04,151.76 U3.J15 ; U3.A2 53.64,158.27 53.48,158.43 v3(52.93,158.43) ; v3(61.19,144.21) 61.19,144.11 60.74,143.66 U3.W11 ; U3.AE14 63.24,138.16 v3(63.29,138.11) ; U3.AC3 54.63,140.27 54.63,140.27 v3(54.84,140.06) ; U3.J4 54.65,151.66 v3(54.64,151.66) ; U3.AE1 52.84,138.86 51.93,138.86 v3(51.7,139.09) ; v3(56.04,140.66) 56.04,141.26 U3.AB5
  TOP w0.305: 63.79,147.43 64.04,147.68 U3.P15 64.04,148.26 v3(63.84,148.46) ; U3.AE18 66.44,138.24 v3(66.46,138.23) ; v3(83.73,76.23) 83.84,76.12 U10.A28 ; U6.A9 112.11,171.34 111.82,171.63 111.61,171.84 111.33,171.84 v2(110.95,172.22) ; v3(63.49,145.51) 63.23,145.26 U3.U14 62.54,144.86 62.16,144.86 61.77,144.46 U3.V12 ; R425.2 101.61,44.12 v2(101.46,43.97) ; v3(93.61,74.9) 93.24,74.54 U10.M26 ; U10.M24 93.53,72.82 v3(93.91,73.2) ; v3(52.09,146.94) 52.14,146.89 53.21,146.89 U3.R1 53.27,146.89 54.01,146.89 U3.R2 U3.R4 ; v3(88.12,63.83) 88.54,64.25 U10.F12 ; U3.R14 62.83,146.86 v3(62.4,146.43) 62.3,146.33 62.17,146.33 61.94,146.1 U3.T12 61.32,145.44 61.03,145.44 U3.U11 ; U3.AB15 63.99,141.26 U3.AA14 62.87,141.73 v3(62.16,141.73) ; U5.7 20.28,129.35 U5.G ; U10.AD4 v3(102.04,57.15) ; v3(65.55,149.49) 65.64,149.59 U3.L17 ; U10.V4 97.24,57.71 v3(97.65,57.3) ; 154.06,230.5 155.06,231.5 PU3.1 ; 154.06,230.5 PU3.G 153.56,230.5 PU3.4 ; 154.06,230.5 PU3.3 ; U3.G8 58.05,153.65 v3(58.05,153.67) ; U3.Y18 66.07,142.86 v3(65.85,143.08) ; U10.D9 86.99,61.57 v3(88.29,61.57) ; v3(96,57.28) U10.U4 ; U6.AF10 113.34,139.38 v3(112.73,138.77) 113.38,138.12 U6.AG10 ; v3(65.66,140.66) 65.64,140.67 U3.AB17 ; v3(92.91,70.87) 92.91,70.79 U10.L21 ; U10.G11 89.91,62.67 v3(90.24,62.67) ; v3(56.14,156.21) 56.02,156.08 56.02,155.66 U3.D5 ; v3(64.5,156.08) 64.47,156.08 U3.D15 ; v3(98.99,67.43) 98.74,67.68 U10.Y18 ; U3.W15 64.35,143.66 v3(64.68,143.33) ; U3.AB2 53.64,141.26 v3(53.24,140.86) 52.84,141.26 U3.AB1 ; v3(110.09,135.06) 109.58,135.57 U6.AJ7 ; U3.AC12 61.4,140.7 60.84,140.7 60.89,140.75 60.89,141.2 U3.AB11 ; v3(90.46,63.86) 90.14,64.18 U10.H12 ; v3(67.28,140.61) 67.24,140.64 U3.AB19 ; v3(89.02,62.72) 88.54,62.24 U10.F9 ; v3(86.18,62.74) 85.96,62.52 U10.B10 85.24,62.12 U10.B9 U10.C9 ; U3.C16 65.11,156.73 v3(65.11,156.77) ; v3(63.49,150.86) U3.K14 62.42,150.33 62.22,150.33 U3.L12 61.72,149.83 61.72,149.83 ; U3.B1 51.86,157.26 v3(51.7,157.1) ; v3(52.34,150.14) 53.16,150.14 U3.L1 53.3,150.11 53.99,150.11 U3.L2 54.1,150.11 55.18,150.11 U3.L4 ; 99.23,72.1 99.23,72.02 98.95,72.02 v3(98.69,71.75) ; Q609.4 v2(76.96,202.45) ; U6.H10 U6.J9 ; v2(142.76,17.53) 142.99,17.3 U16.10 ; U3.G4 55.15,153.35 ; U10.H23 90.61,72.49 v3(90.64,72.49) 90.74,72.49 U10.J23
  TOP w0.381: Q96.S 14.21,178.92 v2(14.55,179.26) ; v3(126.72,136.2) U6.AH20 ; v3(115.3,160.32) U6.J11 ; v2(43.6,176.79) 42.94,176.79 42.05,175.9 R118.1 ; U6.K10 v3(114.02,159.06) U6.L11 ; v2(29.35,65.41) 29.34,65.42 R283.2 ; U6.L19 v3(124.18,159.06) U6.K18 ; v3(121.64,165.41) U6.F16 ; U6.D18 124.06,167.83 124.06,167.85 v3(124.03,167.88) ; v2(65.29,49.34) 65.29,49.34 Q24.S ; R116.2 60.46,173.15 60.46,175.51 v2(60.65,175.7) ; U6.P2 102.9,154.95 102.89,154.95 v3(102.59,155.25) ; C341.2 v2(160.54,9.4) ; U6.N7 110.24,156.55 v3(110.27,156.55) 110.27,156.58 U6.M8 v3(111.48,156.52) U6.N9 ; U6.P12 v3(116.56,153.98) U6.R13 ; U6.AF16 121.51,138.87 v3(121.52,138.87) ; C171.2 v2(29.79,98.55) ; U6.N17 v3(121.64,156.52) U6.M16 ; v3(134.34,133.66) U6.AK26 ; v3(129.26,165.41) U6.F22 ; U6.AA13 v3(116.56,146.36) U6.Y12 ; U6.AB12 v3(116.56,143.82) U6.AC13 ; v2(75.04,32.51) 75.04,32.29 74.68,31.94 Q38.S ; v2(152.98,11.81) 151.86,11.81 C322.2 151.93,12.64 v2(152.98,12.64) ; v2(28.08,57.53) 27.51,58.1 L25.2 ; 111.9,84.5 C204.2 111.69,85.06 v2(112.15,85.52) 112.28,85.65 112.28,86.08 112.73,86.54 C198.2 ; U6.AA21 v3(126.71,146.37) U6.Y20 ; v3(111.48,141.28) U6.AD8 ; C254.2 v2(144.79,48.01) ; U6.M12 v3(116.56,156.52) U6.N13 ; U6.L17 v3(121.64,159.06) U6.K16 ; U6.L13 v3(116.56,159.06) U6.K12 ; R107.2 9.58,191.08 v2(9.04,191.62) ; U6.U21 v3(126.72,151.44) U6.T20 ; v3(134.34,160.33) U6.K26 ; v2(11.03,192.48) 11.25,192.7 Q4.S ; U6.L21 v3(126.72,159.06) U6.K20 ; CN2.15 31.86,79.28 31.86,80.7 v2(31.79,80.77) ; v2(112.36,20.93) 112.66,20.62 C313.2 ; v2(147.46,31.11) 147.38,31.04 R455.2 ; v3(121.64,133.66) U6.AK16 ; Q609.1 v2(77.12,201.15) ; v3(119.1,167.95) U6.D14 ; U6.A7 v3(108.94,171.76) ; v2(34.89,42.12) 34.89,41.48 34.49,41.09 Q33.E ; L31.2 28.2,46.86 v2(28.2,47.56) ; U6.W17 v3(121.64,148.9) U6.V16 ; U6.W23 U6.V22 v3(127.99,150.17) ; U6.J15 v3(119.1,161.6) U6.H14 ; U6.R23 v3(129.26,153.98) U6.P22 ; v2(23.06,22.86) 23.32,22.86 23.97,23.51 C302.2 ; PR87.2 v2(144.85,232.28) ; R94.2 11.57,202.21 11.21,201.85 v2(11.04,201.85) ; v2(98.88,46.74) R394.2 ; C118.2 17.16,131.95 v2(17.41,131.7) ; U6.AF2 v3(102.59,140.01) ; U6.AB8 v3(111.48,143.82) U6.AC9 ; R307.2 184.29,63.36 v2(184.29,62.1) ; v3(134.34,136.2) U6.AH26 ; v3(114.02,170.49) U6.B11 ; C180.2 21.92,89.41 v2(21.73,89.6) ; v2(102.75,43.94) R426.2 ; R484.1 v2(142.12,27.69) ; v3(121.64,169.22) U6.B16 ; U6.AB18 v3(124.18,143.82) U6.AC19 ; U6.AB20 v3(126.72,143.82) U6.AC21 U6.AD22 ; v2(21.03,140.78) 20.2,141.6 C113.2 ; U6.N11 v3(114.02,156.52) U6.M10 ; v2(86.51,15.8) 86.75,15.55 Q50.2 ; R274.2 146.36,76.91 v2(145.81,77.47) ; Q25.S v2(178.64,50.61) ; U13.2 120.41,21.43 v2(120.41,21.43) ; U6.AK20 v3(126.72,134.93) ; U6.R9 v3(111.48,153.98) U6.P8 110.29,154.07 v3(110.29,154.04) 110.26,154.04 U6.R7 ; v2(34.49,112.78) 34.81,112.46 R248.2 ; U6.L9 112.11,158.47 111.53,159.05 v3(111.51,159.05) 111.51,159.07 110.88,159.7 U6.K8 110.26,159.12 v3(110.24,159.12) 110.24,159.09 U6.L7 ; U6.AH16 121.53,136.31 v3(121.54,136.31) ; C336.2 v2(154.19,9.14) ; R253.2 40.06,113.01 v2(40.21,113.16) ; v2(5.54,192.34) 5.28,192.59 Q5.S ; v2(104.79,43.94) R428.2 ; U6.P18 v3(124.13,154.03) U6.R19 ; U6.T18 v3(124.18,151.44) U6.U19 ; v3(111.48,148.9) U6.W9 ; v2(145.91,25.15) 145.91,25.35 145.6,25.65 145.6,25.91 C298.1 ; U6.P16 v3(121.64,153.98) U6.R17 ; U6.J21 v3(126.72,161.6) ; U6.AB14 v3(119.1,143.82) U6.AC15 ; L32.2 24.44,27 v2(24.84,26.61) ; U6.AB2 v3(102.59,145.09) ; U6.AD10 v3(114.02,141.28) U6.AE11 ; v2(93.48,30.92) 93.25,31.15 U15.4 U12.4 ; C200.2 v2(144.28,85.66) ; U6.C3 v3(103.86,169.22) ; v2(5.78,200.41) 5.78,200.09 6.17,199.69 Q3.S ; U6.AF26 133.1,139.98 v3(132.8,139.98) ; C277.2 v2(166.63,43.43) ; R406.2 v2(91.45,46.61) ; C334.2 v2(151.65,9.14) ; U6.V3 104.19,149.84 v3(103.86,150.17) ; v3(110.24,139.97) 110.26,139.97 U6.AF8 ; v3(103.86,160.33) U6.K3 ; v3(107.68,165.39) 107.69,165.39 U6.F6 ; C255.1 v2(95.51,43.94) ; v3(127.99,160.33) U6.K22 U6.L23 ; C221.2 65.52,64.53 v2(65.52,65.38) ; U6.AC17 v3(121.64,143.82) U6.AB16 ; R260.2 v2(147.97,76.01) ; v2(142.63,29.46) 142.59,29.43 Q41.S ; U6.AK2 102.62,133.69 v3(102.54,133.69) ; U6.B30 v3(139.42,170.49) ; U6.L15 v3(119.1,159.06) U6.K14 ; R129.2 54.18,171.18 v2(54.18,171.45) ; v2(76.21,52.7) C260.2 C257.2 ; C339.2 v2(158,9.14) ; v2(152.98,10.73) 152.05,10.73 C324.2 151.67,9.97 v2(152.98,9.97) ; v3(124.32,165.27) 124.31,165.27 124.3,165.27 123.8,164.78 U6.F18 ; v3(102.59,160.33) 102.92,160 U6.K2 ; U6.AF12 115.34,138.8 v3(115.32,138.8) ; v2(77.23,69.72) 77.62,69.33 C223.2 C224.2 ; U6.AK24 v3(131.8,134.93) ; U6.AA5 v3(106.4,146.36) ; C320.2 v2(72.13,12.14) ; v2(109.58,42.26) 109.61,42.23 C276.2 ; U6.AD12 v3(115.29,141.28) ; v2(8.52,183.77) 9.41,183.77 9.89,184.25 C83.2 9.92,184.28 9.65,184.55 v2(8.39,184.55) ; U6.Y8 v3(111.48,146.36) U6.AA9 ; v3(134.34,170.49) U6.B26 ; C271.2 v2(145.81,40.01) ; v3(139.52,134.13) 138.95,134.13 U6.AK30 ; U6.W15 v3(119.1,148.9) U6.V14 ; R340.1 v2(94.5,43.94) ; v3(139.42,165.41) U6.F30 ; v2(49.06,178.23) 49.21,178.39 U2.3 ; U6.AB22 v3(129.26,143.82) U6.AC23 ; U6.AB3 v3(103.86,145.09) ; v3(124.03,169.35) 124.06,169.33 124.07,169.33 U6.B18 ; C284.2 26.22,34.62 26.49,34.35 Q42.S 27.35,33.87 v2(27.57,33.66) ; U6.AA19 v3(124.18,146.36) U6.Y18 ; v2(113.61,70.36) 113.29,70.04 C217.2 C216.2 ; v3(110.56,81.85) 110.56,81.39 R270.2 ; v2(129.93,30.92) 130.04,31.04 C299.2 ; U6.U15 v3(119.1,151.44) U6.T14 ; v3(121.64,167.95) U6.D16 ; R305.2 v2(155.13,69.42) ; U6.J5 v3(106.4,161.6) ; U6.W21 v3(126.72,148.9) U6.V20 ; v3(114.02,166.68) U6.E11 ; v2(99.15,110.97) 99.35,110.97 99.95,110.37 PR39.2 ; U6.AD24 131.8,141.28 v3(131.8,140.01) ; C338.2 v2(156.73,9.14) ; v3(108.95,83.52) 108.72,83.19 R254.1 ; U6.R15 v3(119.1,153.98) U6.P14 ; C218.2 v2(114.44,70.36) ; C167.2 v2(42.17,93.98) ; v3(128.02,147.58) 128.02,147.61 U6.Y22 U6.AA23 ; U6.Y14 v3(119.1,146.36) U6.AA15 ; U6.T16 v3(121.64,151.44) U6.U17 ; U6.AC11 v3(114.02,143.82) U6.AB10 ; R88.2 6.17,194.82 v2(5.41,195.58) ; C557.2 v2(81.93,201.8) ; Q28.S 65.98,45.53 v2(65.29,46.23) ; U6.H16 v3(121.64,161.6) U6.J17 ; R511.2 v2(72.16,15.29) ; v2(53.76,23.32) 52.77,24.31 52.77,25.53 52.38,25.91 Q45.E ; v3(110.26,160.28) U6.J7 ; v2(172.6,52.83) 171.61,53.83 C239.2 ; R316.1 v2(167.03,54.12) ; C259.1 81.59,45.87 v2(81.75,45.72) ; U6.B4 105.76,169.89 105.16,170.49 v3(105.13,170.49) U6.A3 ; C343.2 v2(63.89,8.32) ; Q43.S 28.96,34.1 v2(28.71,34.34) ; v3(129.26,138.74) U6.AF22 ; v3(117.83,136.2) U6.AH14 ; U6.U7 110.24,151.47 v3(110.24,151.47) 110.24,151.47 U6.T8 v3(111.48,151.44) U6.U9 ; R90.2 v2(7.5,201.68) ; C115.2 37.33,131.62 37.03,131.32 36.52,131.32 v2(36.27,131.06) ; v2(92.26,100.41) 92.26,100.13 91.64,99.51 Q16.E ; v3(113.9,138.87) 113.9,138.86 U6.AG11 ; U6.V10 v3(114.02,148.9) U6.W11 ; U6.J23 129.87,160.97 v3(129.3,161.54) ; C269.2 v2(77.86,48.64) ; v3(110.29,145.07) 110.23,145.07 U6.AA7 ; v3(103.86,155.25) 104.13,154.98 104.13,154.98 U6.P3 ; U6.AA11 v3(114.02,146.36) U6.Y10 ; C144.2 113.55,105.58 v2(113.55,105.03) ; v3(131.8,136.2) U6.AH24 ; v2(29.22,61.59) 29.86,60.96 R319.2 ; v3(136.88,167.95) U6.D28 ; v2(96.02,83.34) 96.61,83.92 C186.2 ; U6.F4 v3(105.26,165.29) ; v3(110.27,147.59) 110.26,147.59 U6.W7 ; U6.W19 v3(124.18,148.9) U6.V18 ; C327.2 v2(76.8,9.57) ; Q49.2 61.73,15.48 v2(61.45,15.76) ; v2(30.68,56.9) 30.49,56.71 C246.2 C245.2 ; U6.AA17 v3(121.64,146.36) U6.Y16 ; v3(131.8,138.74) U6.AF24 ; R67.2 R66.2 14.69,207.24 14.29,206.83 v2(13.95,206.83) ; R350.2 110.82,48.97 v2(111.22,49.37) ; C307.2 116.66,27.5 v2(116.47,27.3) ; R325.1 v2(97.86,46.74) ; v3(126.72,138.74) U6.AF20 ; U6.AE4 v3(105.13,141.28) ; C153.2 73.59,101.39 v2(73.54,101.54) ; v2(130,27.75) 129.54,28.21 C304.2 ; v3(119.1,169.22) U6.B14 ; C268.2 v2(76.59,48.62) ; v2(139.46,28.7) 139.4,28.64 Q48.S ; v2(77.48,28.7) 77.48,29.31 Q39.E ; PC70.2 27.89,62.93 28.18,63.22 v2(28.79,63.22) ; U6.U11 v3(114.02,151.44) U6.T10 ; v3(139.42,162.87) U6.H30 ; v3(126.72,167.95) U6.D20 ; v3(135.61,138.74) U6.AF28 ; CN2.4 27.48,86.13 v2(28.14,85.47) ; R335.2 v2(70.37,56.52) ; v3(139.42,136.2) U6.AH30 ; v3(136.88,162.87) U6.H28 ; U6.P10 v3(114.02,153.98) U6.R11 ; C226.2 65.92,68.05 v2(65.82,67.94) ; U6.W13 v3(116.56,148.9) U6.V12 ; v3(136.88,136.2) U6.AH28 ; v2(99.77,44.01) C280.2 ; C340.2 v2(159.27,9.14) ; C344.2 v2(88.78,8.32) ; v2(100.4,83.38) 100.4,83.35 C208.2 ; Q27.E 35.57,47.44 v2(35.82,47.69) ; U6.T12 v3(116.56,151.44) U6.U13 ; U6.H18 123.53,162.24 v3(122.97,162.8) ; R295.2 71.64,64.59 72.17,64.59 v2(72.5,64.26) ; v3(131.8,165.41) U6.F24 ; v3(102.59,150.17) 102.92,149.84 U6.V2 ; U6.U4 v3(105.13,151.44) ; C556.2 v2(81.93,203.07) ; U6.J13 v3(116.56,161.6) U6.H12 ; C89.1 43.06,175.51 v2(43.57,176.02) ; v3(121.64,141.28) U6.AD16 ; v2(42.62,99.06) 43.05,98.63 C175.2 ; v3(129.26,167.95) U6.D22 ; v2(182.83,51.56) C263.2 ; R429.2 v2(166.08,41.35) ; R403.2 90.12,46.52 v2(90.25,46.39) ; v2(40.27,51.79) 40.68,52.2 44.47,52.2 LED2.C ; R408.2 v2(93.48,46.61) ; U6.AC7 110.26,142.51 v3(110.27,142.51) ; C278.2 v2(124.15,35.37) 124.85,35.37 C296.2 ; R481.1 v2(136.41,27.69) ; v2(115.33,70.36) 115.33,69.77 C219.2 ; Q32.E 65.29,52.51 v2(65.29,52.52) ; U6.N5 v3(106.4,156.52) ; C227.2 v2(70.75,67.82) ; v3(134.34,162.87) U6.H26 ; v3(119.1,165.41) U6.F14 ; v3(136.88,170.49) U6.B28 ; R304.2 v2(150.08,69.42) ; U6.U5 v3(106.43,151.41) ; U6.J19 v3(124.18,161.6) ; U6.N19 v3(124.18,156.52) U6.M18 ; U6.AE5 v3(106.4,141.28) ; C248.2 78.95,60.53 v2(78.9,60.58) ; U6.M14 v3(119.1,156.52) U6.N15 ; C337.2 v2(155.46,9.14) ; C187.1 95.28,84.79 v2(95.32,84.84) ; U6.N21 v3(126.72,156.52) U6.M20 ; CN5.4 25.93,21.03 v2(25.73,20.83) ; C294.2 131.07,33.27 v2(131.58,33.78) ; v3(126.72,141.28) U6.AD20 ; C273.1 76.87,45.87 v2(76.74,45.75) ; R41.2 R35.1 ; v2(152.92,9.14) 152.73,8.95 C335.2 ; v2(55.64,172.21) 55.76,172.09 R130.2 ; v2(76.82,60.58) 77.21,60.19 C244.2 ; R206.2 101.74,119.38 v2(101.86,119.25) ; v3(134.34,167.95) U6.D26 ; v2(116.47,26.29) C308.2 ; U6.AF3 v3(103.86,140.01) ; U6.N4 v3(105.13,156.52) ; R446.2 C286.2 30.41,41.12 v2(30.11,40.83) ; v3(136.88,165.41) U6.F28 ; U6.H8 v3(111.5,161.58) U6.J9 ; U6.P20 v3(126.72,153.98) U6.R21 U6.T22 U6.U23 ; v3(136.88,133.66) U6.AK28 ; v3(124.18,136.2) U6.AH18 ; R92.2 v2(9.54,201.8) ; v2(96.53,43.94) C279.2 ; v3(124.18,133.66) U6.AK18 ; U6.AK22 v3(129.26,134.93) ; R407.2 v2(92.47,46.61) ; v3(131.8,162.87) U6.H24 ; v3(117.83,138.74) U6.AF14 ; v3(139.42,167.95) U6.D30 ; U6.J4 v3(105.13,161.6) ; v3(129.26,136.2) U6.AH22 ; U6.N23 v3(129.2,156.58) U6.M22 v3(128.05,157.73) ; v3(126.72,165.41) U6.F20 ; U6.AA4 v3(105.13,146.36) ; v3(131.8,170.49) U6.B24 ; C310.2 28.97,24 v2(29.16,23.81) ; v3(129.26,169.22) U6.B22 ; v2(103.77,43.94) R427.2 ; v3(134.34,165.41) U6.F26 ; C87.1 v2(50.83,177.21) ; v3(131.8,167.95) U6.D24 ; C177.2 v2(21.73,90.42) ; v3(126.72,169.22) U6.B20
  TOP w0.4: v3(136.83,160.31) 136.88,160.36 136.89,160.36 136.24,159.71 U6.K28 ; U6.G11 114.42,163.27 114.4,163.27 113.38,162.26 U6.H10 ; U6.K24 131.16,160 131.58,160.41 v3(131.58,160.4) ; U6.K30 138.78,159.75 138.17,160.37 v3(138.17,160.41)
  TOP w0.406: CN5.50 v2(47.53,20.62) ; C142.2 112.79,104.49 v2(112.79,105.03) ; CN2.29 40.68,78.1 41.12,77.66 v2(41.12,77.65) ; U10.A9 U10.B9 ; R452.2 v2(157.24,39.88) ; C109.2 19.65,146.31 v2(19.67,146.33) ; v2(122.11,43.69) C264.2 ; v3(39.13,15.49) CN5.29 ; v2(38.24,20.57) 37.93,20.93 CN5.26 ; C21.2 v2(140.41,236.35) ; CN5.43 44.73,15.11 45.19,15.57 v2(45.91,15.57) ; U3.A25 72.4,158.06 v3(72.68,158.34) ; CN5.27 38.33,15.44 38.56,15.66 v3(38.56,16.22) ; v2(93.8,101.92) 93.1,102.62 C148.2 ; Q10.E v2(103.55,112.94) ; PR43.2 103.06,110.79 v2(103.7,110.16) ; v2(106.69,111.38) 106.87,111.2 C150.2 ; v2(39.35,85.93) 39.35,85.95 39.48,86.08 CN2.26 ; CN5.21 35.93,15.37 35.71,15.6 v3(35.71,15.99) ; v2(43.57,45.47) 43.57,45.16 R391.2 ; v2(50.18,81.15) 46.92,81.15 46.28,80.52 CN2.43 ; CN2.50 49.08,88.59 49.31,88.82 50.38,88.82 v2(50.82,88.39) ; C141.2 107.66,105.36 v2(107.71,105.41) ; v2(42.68,76.71) 43.88,77.91 CN2.37 ; v2(33.86,21.65) 33.86,21.97 34.13,22.24 CN5.18 ; PR47.2 105.18,104.66 v2(105.17,104.65) ; v2(40.4,20.32) 40.45,20.32 41.13,21 CN5.34 ; R14.2 v2(140.47,234.44) ; U6.A11 v3(114.02,170.49) ; CN2.27 39.88,80.55 v2(39.58,80.85) ; v2(96.05,100.38) 96.05,99.95 Q15.S ; v2(43.32,20.64) 43.53,20.85 CN5.40 ; v2(42.33,12.57) CN5.37 ; C330.2 50.05,11.3 v2(49.79,11.56) ; v2(116.6,104.14) 117.22,104.14 C154.2 116.97,103.38 v2(116.6,103.38) ; CN2.34 42.68,85.98 v2(43.06,85.6) ; v2(41.54,12.57) 41.53,12.58 CN5.35 ; Q36.S v2(129.36,42.38) ; v2(106.94,109.47) 107.18,109.24 R216.2 ; v2(29.4,80.85) 29.48,80.77 CN2.9 ; v2(116.6,105.16) 117.09,105.16 C143.2 ; CN2.21 37.48,81.13 v2(38.11,81.76) ; v2(49.92,10.54) 50.43,10.03 R517.2 ; CN2.35 43.08,78 v2(42.68,77.6) ; C290.2 v2(158.51,39.88)
  TOP w0.5: U6.AK14 118.46,134.49 v3(118.96,134.98) ; U6.B9 U6.A9 ; U6.AE7 110.24,139.98 v3(110.24,139.97) ; v3(119.07,141.33) 118.48,141.92 U6.AD14 ; U6.AF18 v3(124.18,140.01) ; U6.G9 U6.H8 ; v3(126.72,161.6) U6.H20
  TOP w0.508: Q12.S 114.58,98.82 114.18,98.42 v2(114.18,98.04) ; Q14.E 107.89,97.57 v2(107.83,97.51) ; v2(26.81,204.09) 27.71,204.09 C62.2 C52.2 ; v2(71.77,197.42) 71.77,197.24 C70.2 70.75,197.11 v2(70.5,197.36) ; C238.2 v2(162,64.2) ; CN2.18 36.28,86.61 v2(35.72,86.06) ; v2(46.24,168.91) 45.35,168.91 43.93,167.49 R144.1 ; J3.14 v2(125.36,80.52) ; v3(83.17,61.72) v3(83.83,61.72) 84.44,61.72 U10.A9 ; v2(30.11,204.98) 31,204.09 C53.2 ; C145.2 115.9,105.88 v2(115.94,105.92) ; C179.2 26.05,89.46 v2(26.05,88.9) ; PC16.2 v2(106.23,227.34) ; CN8.7 v2(19.19,197.09) ; v2(51.01,81.41) 51.62,81.41 52.73,80.3 CN2.X2 ; C93.2 v2(188.73,163.8) ; v2(121.87,80.58) 121.55,80.9 J3.20 ; v2(28.08,51.75) 27.44,51.75 27.14,51.45 C247.1 ; v2(61.99,32.89) 61.92,32.96 Q40.S 63.01,35.27 R450.1 ; v2(159.65,67.44) 159.65,66.8 160.28,66.17 C236.2 ; C127.2 81.54,132.46 v2(82.18,131.83) ; CN25.8 v2(39.06,4.32) ; PC63.1 96.15,110.32 95.87,110.6 v2(95.87,111.71) ; 51.91,14.64 51.91,13.7 52.16,13.46 v2(53.1,13.46) ; 51.91,14.64 CN5.X2 ; 51.91,14.64 52.93,14.64 v2(53.3,14.27) ; v2(66.05,165.4) 66.33,165.68 R135.2 ; C99.2 v2(63.38,169.54) ; C98.2 73.82,169.91 73.82,169.45 v2(74.31,168.96) 74.69,168.96 75.53,169.8 C90.2 ; R162.1 60.46,131.72 v2(60.74,131.44) ; v2(78.22,230.73) 78.22,230.73 78.32,230.83 R22.2 ; v2(154.52,222.71) 153.92,222.11 PC30.2 ; v2(106.74,119.2) 106.89,119.35 R208.2 ; PC46.2 113.86,190.2 PC43.2 ; R155.2 43.92,142.96 R153.2 43.5,143.39 43.49,143.39 v2(43.24,143.64) ; J3.1 v2(132.98,88.9) ; v2(162.29,58.61) C256.2 ; v2(15.38,212.85) 15.38,212.48 C50.2 16.4,213.15 v2(16.11,213.44) ; v2(177.37,10.4) 177.35,10.41 PC93.2 ; CN25.4 v2(43.06,6.98) ; PR61.1 165.82,2.81 v2(165.68,2.67) ; v2(29.31,141.85) C112.2 v2(28.33,140.92) ; v3(22.39,188.42) 23.04,187.76 CN8.32 ; CN7.42 63.79,190.39 v2(63.13,189.74) ; v2(109.8,180.85) 109.57,181.08 109.57,183.59 109.95,183.97 R110.1 110.63,185.7 C79.2 110.73,187.19 C74.2 ; C92.2 v2(187.38,166.35) C91.2 ; v2(93.1,226.06) 92.78,226.38 C31.2 92.78,228.79 v2(93.1,229.11) ; PU8.4 139.26,40.95 v2(138.82,40.51) ; U6.AL5 106.77,133.03 v3(106.4,132.65) ; C2.2 v2(184.43,244.59) ; R185.1 110.53,120.09 111.06,120.62 v2(111.06,120.98) ; C272.2 54.24,38.99 v2(53.99,39.12) ; v2(14.81,132.59) 15.25,133.03 R170.1 ; J3.6 v2(130.44,80.52) ; v2(24.75,190.09) 24.76,190.09 CN8.17 ; C1.2 164.11,247.15 v2(164.09,247.14) ; v2(81.04,184.59) 81.58,185.13 CN6.14 ; v2(19.01,188.9) 19.01,189.64 19.46,190.09 CN8.14 ; C20.2 134.12,231.27 v2(133.55,231.84) ; v2(89.16,108.58) 88.71,109.04 PC60.1 ; C232.2 v2(160.74,68.15) ; v2(144.26,233.22) 144.26,232.77 143.53,232.04 C5.2 C4.2 ; CN9.41 23.12,184.05 23,183.93 v2(23,183.13) ; J3.26 v2(117.74,84.71) ; C139.2 18.43,125.6 v2(18.93,126.11) ; U14.2 v2(126.76,19.3) ; PC89.2 164.55,20.01 v2(164.22,19.68) ; C321.2 v2(114.31,8.51) ; C207.2 89.16,82.14 v2(89.16,81.92) ; v2(19.14,177.75) 19.16,177.73 CN9.6 ; v2(70.9,71.35) 70.67,71.12 C209.2 ; PC36.1 84.34,207.86 v2(84.34,207.14) ; R146.2 v2(188.35,146.11) ; C265.2 183,50.31 v2(182.26,51.05) ; v2(81.22,195.25) 81.47,195.25 81.88,194.85 81.88,194.13 81.58,193.83 CN6.17 ; v2(160.06,232.82) 160.82,232.06 PC13.2 ; v2(76.08,63.63) 76.6,64.15 C213.2 77.37,64.15 v2(77.84,63.68) C211.2 C212.2 79.95,63.68 v3(80.55,63.07) ; v2(161.63,214.71) 161.25,214.71 160.79,214.25 155.2,214.25 v2(154.44,215.01) ; v2(161.63,214.71) 161.55,214.79 161.55,217.81 161.86,218.11 C29.2 C30.2 163.93,218.58 R38.2 ; v2(161.63,214.71) C54.2 ; PC24.1 v2(136.66,225.55) ; C119.2 36.89,137.21 v2(36.49,137.6) ; PR50.1 136.66,32.07 v2(136.09,31.5) ; v2(63.7,178.24) 63.19,178.24 62.43,177.48 C84.2 v2(63.74,177.25) ; v2(56.01,185.83) 56,185.84 CN7.12 ; C188.2 C184.2 v2(144.93,50.28) ; v2(192.47,46.6) 190.45,46.6 ; 190.45,46.6 191.48,47.62 v2(191.48,49.25) ; 190.45,46.6 CN27.H1 ; CN25.G1 v2(37.76,4.55) ; CN5.15 v2(30.33,15.59) ; R1017.2 13.17,25.43 v2(10.93,25.43) ; v2(13.86,217.57) 15.41,217.57 ; 15.41,217.57 CN1.X2 16,215.54 15.48,215.02 v2(15.48,214.4) ; 15.41,217.57 15.41,216.53 14.98,216.1 v2(13.94,216.1) ; PR46.2 92.99,109.32 92.4,109.91 v2(92.39,109.91) ; CN9.42 23.81,162.56 v2(25.03,162.56) ; v2(133.62,232.93) 133.63,232.92 C6.2 ; v2(149.36,61.21) EC11.2 146.19,60.26 v2(146.19,59.44) 146.35,59.27 D18.A ; v2(18.3,180.19) 18.84,180.73 CN9.3 ; C82.2 v2(5.93,188.85) ; CN6.32 82.84,190.39 v2(82.5,190.06) ; R500.2 55.97,26.16 v2(56.22,25.91) ; 21.88,15.68 21.88,16.1 v2(21.16,16.83) ; 21.88,15.68 21.61,15.95 L35.2 ; 21.88,15.68 CN5.X1 23.34,14.64 v2(23.68,14.99) ; CN7.15 58.99,185.88 v2(58.99,185.88) ; v2(6.93,17.72) 9.47,17.72 v2(9.61,17.58) ; v2(6.93,17.72) 6.93,17.44 S3.M2 S3.M1 ; v2(6.93,17.72) 7.26,18.05 v2(7.26,22.54) ; R5.2 v2(118.49,246.6) ; v2(174.41,7.59) 174.88,8.06 175.55,8.06 176.04,8.56 PR58.2 ; PC52.2 188.85,165.9 v2(188.56,166.19) ; C325.2 v2(40.78,11.3) ; J3.2 v2(132.98,80.52) ; v2(74.94,92.75) 74.56,92.37 C185.2 ; v2(25.9,141.85) C111.2 v2(26.81,140.87) ; v2(111.62,41.53) 111.7,41.45 R417.2 ; v2(40.84,95.89) 41.46,95.27 C183.2 ; v2(116.28,70.36) 116.43,70.51 C220.2 118.48,70.51 v2(118.63,70.36) ; R147.2 v2(25.87,147.85) ; R68.2 164.05,213.82 v2(163.46,213.82) C55.2 ; C68.2 50.81,196.34 v2(50.49,196.66) 50.5,196.67 C67.2 ; v2(156.25,162.79) 156.02,162.56 C96.2 ; v2(64.72,101.22) 64.72,102.5 65.54,103.33 65.54,104.27 66.05,104.77 Q13.S 68.59,104.77 69.84,103.53 Q11.E ; R341.1 v2(97.74,43.94) ; v2(68.97,190.88) 68.48,190.39 CN6.31 ; C300.2 v2(34.76,24.46) ; C261.1 90.43,41.27 v3(90.31,41.15) ; v2(50.01,185.17) 50.01,187.18 CN7.6 ; C225.2 64.92,63.47 64.92,63.74 v2(64.93,63.73) ; CN8.24 26.84,197.09 v3(27.19,197.43) ; v2(101.86,219.51) 103.49,219.51 104,219 CN1.X1 102.27,217.57 v2(101.86,217.17) ; PC9.1 v2(119.76,246.49) ; CN9.15 18.94,168.73 v2(18.93,168.73) ; C97.2 160.97,162.51 v2(161.15,162.69) ; v2(148.09,38.73) 148.09,39.44 PC76.2 146.95,39.56 v2(146.95,38.73) ; C120.2 v2(160.11,135.1) ; CN5.9 v2(27.93,15.49) ; C346.2 v2(170.19,4.06) ; v2(16.42,214.25) 17.21,214.25 C36.2 ; C121.2 v2(58.78,130.21) ; v2(69.73,197.55) 69.67,197.49 C69.2 ; C222.1 114.52,66.25 114.49,66.22 ; v2(28.75,48.57) 28.93,48.76 R347.2 ; C100.2 57.41,169.04 v2(57.16,169.29) ; J3.4 v2(131.71,80.52) ; R188.2 56.04,130.73 v2(55.41,130.1) ; v2(124.85,234.04) 124.85,233.81 125.26,233.4 PR25.2 ; PR15.2 v2(109.23,231.29) ; v2(46.24,184.59) 47,185.36 47,187.18 CN7.3 ; C197.2 v2(140.85,83.06) ; v2(23.3,111.1) 23.3,111.51 22.87,111.93 EC1.2 20.88,111.93 20.2,111.25 v2(20.2,110.24) ; PC3.1 153.2,237.49 v2(153.12,237.41) ; v2(150.38,38.73) 150.38,39.44 PC77.2 149.24,39.56 v2(149.24,38.73) ; 119.95,66.22 119.95,66.22 C210.1 ; v2(22.36,123.57) 21.71,124.23 C126.2 ; J3.18 v2(122.82,80.52) ; C61.2 51.95,196.53 v2(52.14,196.72) ; v2(67.19,17.4) 66.99,17.6 C311.2 ; PR29.2 v2(146.65,228.09) ; v2(25.09,78.17) 24.71,78.17 23.43,79.45 CN2.X1 24.72,81.15 v2(25.16,81.15) ; v2(113.42,226.82) 113.42,226.76 R43.2 ; PC34.2 115.34,216.4 v2(114.76,216.98) ; PC7.1 v2(115.9,246.54) ; J3.8 v2(129.17,80.52) ; v2(37.35,109.54) 37.35,109.47 36.86,108.99 C151.2 ; C108.2 v2(186.95,146.49) ; C125.2 v2(186.95,133.43) ; C3.2 136.59,240.46 v2(136.43,240.61) ; v2(187.72,67.95) CN27.H2 190.38,67.95 191.6,66.73 v2(191.6,66.17) ; PC91.2 v2(168.92,18.67) ; C181.2 45.98,89.53 45.08,88.63 CN2.40 45.08,86.37 45.48,85.98 v2(45.73,85.98) ; v2(18.17,172.47) 18.91,171.73 CN9.12 ; v2(163.38,6.68) 163.54,6.84 PC98.2 ; R157.2 v2(188.35,138) ; C101.2 66.82,168.64 v2(66.3,168.12) 66.35,168.07 C104.2 ; C33.2 v2(182.74,226.59) ; v2(142,31.43) 141.62,31.81 PC81.2 ; PC33.2 153.8,223.51 v2(154.47,224.18) ; PR52.2 v2(139.58,31.11) ; R476.2 v2(145.43,32.13) ; CN7.9 52.99,185.85 v2(53.01,185.84) ; v2(127.16,240.15) 126.65,239.64 R20.1 ; v2(26.46,127.38) 26.37,127.29 R195.2 ; CN26.2 v2(76.7,87.5) ; C66.2 68.15,196.85 v2(68.84,197.55) ; C110.2 v2(23.68,148.77) ; v2(106.31,116.46) 106.72,116.79 R214.2 ; R72.2 R71.2 R70.2 38.59,205.95 37.96,206.58 v2(37.96,207.95) ; v2(48.27,194.5) 47.27,195.5 C64.2 C63.2 45.39,195.84 C71.2 ; v2(174.38,50.29) 175.52,50.29 176.35,49.47 PC73.2 174.89,49.28 v2(174.38,48.77) ; C128.2 16.07,128.28 v2(15.58,127.79) ; v2(136.41,14.73) 136.41,14.22 135.67,13.49 D13.A 135.52,13.46 134.88,14.1 v2(134.88,14.73) ; C140.2 v2(22.36,122.68) ; v2(61.61,22.1) 62.73,22.1 C312.2 ; C102.2 v2(164.32,163.52) ; PC155.2 68.84,130.18 v2(68.34,130.68) ; v2(31.63,64.39) 31.82,64.2 Q21.S ; C242.2 v2(65.29,52.52) ; PC99.2 v2(164.61,4.94) ; PC157.2 v2(71.38,125.03) ; PC100.2 168.29,4.94 168.67,5.32 v2(168.67,5.97) ; C122.2 14.11,130.3 14.36,130.56 v2(14.55,130.56) ; C241.2 54.75,61.32 v2(54.54,61.11) ; CN25.G2 v2(47.36,4.55) ; PC156.2 v2(68.27,132.21) ; C7.2 191.08,227 v2(191.08,227.08) ; R357.2 v2(182.38,52.96) ; v2(109.36,207.39) 108.66,208.09 PC35.1 ; v2(61.33,123.93) 61.61,124.21 R196.1 ; Q20.S 23.06,60.26 22.36,60.96 v2(22.36,61.47) ; v2(27.7,172.34) 27.82,172.47 C88.2 28.75,174.61 C94.2 C95.2 ; R41.2 87.73,226.6 v2(87.39,226.95) ; C103.2 61.95,167.26 61.43,166.75 v2(61.43,166.78) 61.92,166.28 C554.2 ; PR57.2 v2(161.3,9.14) ; Q37.S v2(152.48,42.87) ; J3.12 v2(126.63,80.52) ; v2(145.81,37.97) 145.48,37.64 PC79.1 ; v2(33.46,119.66) 33.73,119.38 R199.2 ; v2(93.84,103.58) 93.48,103.94 PR48.2 ; C323.2 v2(52.33,7.62) ; Q46.S 70.35,31.94 v2(70.92,32.51) ; v2(19.09,174.77) 19.12,174.73 CN9.9 ; C206.2 v2(89.38,83.91) ; v2(49.84,208.15) 49.79,208.2 R59.2 ; J3.22 v2(120.28,80.52) ; C23.2 190.64,234.44 v2(191.02,234.06) ; C309.2 v2(158.2,23.38) ; C162.2 v2(113.17,101.98) ; 111.9,84.5 R262.2 ; PC18.1 152.92,236.19 v2(152.23,236.88) ; R56.2 v2(26.14,208.36) ; R351.2 v2(112.6,52.75) ; CN6.24 74.58,193.74 v2(74.18,194.13) ; v2(162.89,14.16) 162.84,14.3 C342.2 C303.2 163.08,17.26 v2(163.08,18.22) ; CN25.3 v2(44.06,7.01) ; PC31.2 v2(145.92,223.08) ; v2(74.41,185.85) 74.48,185.93 74.48,186 74.58,186.1 CN6.7 ; v2(92.59,224.92) 91.83,225.68 C32.2 ; J3.10 v2(127.9,80.52) ; R17.1 v2(117.22,246.51) ; C123.2 v2(163,135.13) ; PC37.2 95.14,210.7 v2(95.26,210.82) ; PR27.1 v2(146.28,234.24) ; v2(90.12,84.96) 90.11,84.95 C205.1 ; R441.2 v2(95.88,41.15) ; v2(25.35,203.96) 24.9,204.41 CN8.31 ; Q23.S v2(167.18,48.93) ; R342.1 v2(98.75,43.94) ; J3.16 v2(124.09,80.52) ; C164.2 v2(106.87,98.12) ; C117.2 v2(186.95,141.92) ; C114.2 v2(186.95,138.15)
  TOP w0.635: PC57.2 v2(71,121.86)
  TOP w0.762: 3.88,146.81 v2(3.88,150.94) v2(3.88,156.02) v2(3.88,161.1) v2(3.88,166.18) v2(3.88,171.26) v2(3.88,176.34) 2.61,177.61 1.85,177.61 ; PC55.2 v2(72.34,133.72)
  TOP w1.016: PC159.2 PC158.2 PC160.2 61.33,117.65 PC61.2 ; PC46.2 PC42.2 114.16,194.51 PC45.2
  INT1 w0.508: 0.77,147.13 1.53,147.13
  INT1 w0.762: 1.92,177.55 2.74,177.55 3.88,176.4 v2(3.88,176.34) v2(3.88,171.26) v2(3.88,166.18) v2(3.88,161.1) v2(3.88,156.02) v2(3.88,150.94) 3.88,147.76 3.25,147.13 1.53,147.13
  BOTTOM w0.178: U24.24 119.94,33.16 v2(120.05,33.26)
  BOTTOM w0.254: v2(28.08,49.91) 28.34,50.17 U23.7 ; U20.29 25.23,105.04 25.09,104.9 v2(25.09,104.33) ; v2(29.22,101.85) 29.22,103.82 29.59,104.19 U20.36 29.59,106.16 v2(29.92,106.49) ; U20.54 38.59,104.11 38.77,103.93 39.99,103.93 40.21,104.14 v2(40.21,104.71) ; U20.33 v2(28.09,101.8) ; U20.12 v2(34.09,98.53) ; U20.22 29.09,98.11 v2(28.65,98.55) ; C359.2 111.14,165.73 111.14,164.97 110.71,164.54 C363.2 ; v2(76.36,57.45) 76.44,57.53 C250.2 ; v2(37.41,98.74) 37.09,98.42 U20.6 ; U20.19 30.59,98.58 ; v2(35.82,106.49) 35.59,106.25 U20.48 ; U20.44 33.59,100.31 v2(33.35,100.08) ; U20.43 33.09,101.91
  BOTTOM w0.279: U23.4 v2(28.91,51.67)
  BOTTOM w0.305: v3(57.14,151.86) 57.14,152.56 C395.2 ; v3(62.39,154.69) 62.39,154.02 C391.2 ; C425.2 96.48,123.88 v2(95.77,123.16) ; v3(58.05,153.67) 58.05,154.26 C381.2 ; v2(142.76,17.53) 142.76,16.46 142.71,16.41 C549.2 ; C389.2 54.7,153.24 v3(54.59,153.35)
  BOTTOM w0.381: v2(82.12,109.66) 80.98,109.66 PC142.2 81.1,108.9 v2(82.12,108.9) ; R631.2 v2(83.45,87.88) ; v2(44.97,42.93) 45.12,42.77 45.12,42.57 R693.2 ; C547.1 22.87,24.89 22.62,24.64 21.66,24.64 v2(21.47,24.45) ; C356.2 66.05,171.5 v2(65.82,171.73) ; v2(119.44,39.32) 119.64,39.12 R710.2 ; v2(80.4,164.21) 80.7,163.91 C367.2 ; R675.2 109.53,54.15 v2(109.36,53.98) ; v3(90.49,68.53) 89.83,68.53 89.32,68.02 R670.2 ; v2(26.62,80.84) 26.93,80.52 R627.2 ; C369.2 v2(7.58,162.26) ; v2(109.99,177.04) 110.25,176.78 C357.2 ; C361.2 130.96,162.86 131.79,162.86 v3(131.8,162.87) ; v2(48.91,40.26) 48.91,41.07 C511.1 ; C480.2 98.37,63.79 v3(99.12,63.79) ; CN13.P31 36.86,137.97 v2(36.49,137.6) ; CN13.P11 36.67,123.97 v3(36.59,123.89) ; v3(132.8,139.98) 132.22,140.56 C418.2 ; C512.2 v2(125.87,38.23) ; v2(84.08,104.44) 84.08,105.04 PC138.2 PC140.2 83.84,107.43 v2(83.32,107.95) ; C1459.2 49.08,35.88 48.76,36.2 v2(47.89,36.2) ; R563.2 v2(5.3,159.13) ; v3(99.76,59.73) 100.01,59.48 C495.2 ; C459.2 v2(94.88,80.33) ; v2(88.17,46.73) 88.2,46.73 C516.2 ; R560.2 v2(5.3,162.23) ; v2(80.15,54.6) 80.68,54.6 81.04,54.96 R690.2 ; C1465.2 97.42,114.68 96.66,115.44 v2(96.66,115.7) ; R708.2 v2(123.71,38.23) 122.95,38.23 122.69,37.97 R719.1 ; v2(72.4,51.31) 72.92,50.79 C500.2 73.24,50.61 v2(73.24,51.26) ; C508.2 81.42,51.31 v2(81.3,51.12) ; C372.2 61.48,166.73 v2(61.43,166.78) ; C483.2 C484.2 v2(77.18,70.69) ; v3(87.36,77.67) 87.36,76.73 C466.2 ; v3(104.6,75.44) 104.79,75.12 C472.2 C471.2 ; v2(112.79,24) R741.1 ; v2(174.38,48.01) R685.2 ; C440.2 34.94,109.73 v2(34.68,109.98) ; R630.2 85.69,87.3 v2(85.1,87.88) ; C348.1 21.65,214.93 v2(23.38,216.66) ; C468.2 86.51,71.87 v4(86.27,72.12) ; C481.2 104.1,63.2 v3(104.24,63.34) 104.24,63.34 106.64,63.34 v3(106.71,63.27) ; R644.2 158.25,83.69 v2(158.7,84.14) ; C397.2 67.78,152.02 v3(67.75,151.99) ; R669.2 R672.2 R673.2 110.37,56.13 111.14,55.37 v2(111.14,54.86) ; v2(47.18,37.38) 46.91,37.66 C1457.2 ; R694.1 88.48,50.42 C496.2 88.28,50.29 v2(87.77,49.78) ; v2(129.74,26.92) 129.04,26.92 128.66,27.3 C530.1 ; C443.2 v2(41.22,104.84) ; R696.2 v2(95.64,51.18) ; v2(42.17,93.98) 42,94.16 R609.2 ; C444.2 v2(14.23,97.03) ; C1458.2 v2(47.13,36.45) ; C478.2 v2(18.68,72.77) ; v3(111.5,161.58) 110.26,160.34 v3(110.26,160.28) ; C477.2 96.47,70.64 v3(96.39,70.72) 96.39,71.59 C476.2 96.36,73.28 C474.2 ; v2(129.93,30.92) 129.69,31.16 C525.1 ; C442.2 41.78,99.24 v2(42.37,99.82) ; R578.2 91.75,123.62 v2(91.51,123.38) ; v2(127.52,26.16) 127.52,25.91 128.2,25.22 R747.2 ; C513.2 v2(127.14,38.86) ; v3(65.55,149.49) 65.61,149.56 C410.2 ; v3(84.85,77.6) 82.86,77.6 R654.2 ; R720.1 v2(121.68,38.35) ; R663.2 v2(17.66,72.77) ; C487.2 93.82,57.55 v3(94.22,57.15) ; v2(89.16,81.92) 88.6,82.48 C207.2 C206.2 v2(89.38,83.91) ; Q62.S v2(178.64,48.33) ; R545.2 v2(52.99,173.34) ; C407.2 v2(189.19,140.35) ; U18.1 v2(78.37,232.54) ; R541.2 v2(100.52,171.7) ; R605.1 v2(39.7,92.2) ; L60.2 11.44,73.79 v2(11.19,74.04) ; v2(78.69,50.61) 79,50.93 C509.2 ; C492.2 v2(97.24,51.56) ; R768.2 v2(6.17,5.91) ; C371.2 v2(7.58,159.13)
  BOTTOM w0.4: 114.63,141.18 114.72,141.09 114.72,138.38 115.29,137.81 v3(115.29,137.47)
  BOTTOM w0.406: v2(98.94,125.22) 99.07,125.09 99.07,124.67 99.91,123.83 C429.2 ; C403.2 62,150.21 61.45,149.66 v3(61.24,149.66) ; Q54.S 106.98,104.05 v2(106.69,103.76) ; v2(107.2,110.36) 107.2,110.27 107.45,110.02 Q53.E ; v3(61.33,143.26) 61.33,143.1 60.72,142.49 C408.2 ; v2(102.02,125.88) 102.47,125.43 102.47,124.46 103.11,123.83 C426.2 ; v2(52.46,170.81) 52.72,170.56 R555.2 ; v2(174.13,11.18) 174.18,11.13 PC152.2 ; v3(61.24,147.26) 61.1,147.11 C409.2 ; v2(100.65,103.2) 100.65,102.42 Q55.S ; v2(73.8,138.18) 73.34,138.63 C417.2 ; v3(61.19,144.21) 60.87,144.53 C402.2 ; C439.2 v2(87.77,124.21) ; C441.2 v2(103.7,110.16) ; v3(63.49,145.51) 63.49,145.57 64.44,146.52 C394.2 ; C505.2 v2(126.07,41.2)
  BOTTOM w0.5: C412.2 58.39,145.92 v3(58.04,146.26) ; v3(60.44,150.46) 60.36,150.54 59.7,150.54 ; v3(61.24,151.26) 61.41,151.42 C399.2 ; C406.2 59.99,148.28 60.17,148.28 v3(60.36,148.47)
  BOTTOM w0.508: C431.2 v2(91.96,131.34) ; v2(51.64,191.39) 51.49,191.39 50.99,191.89 C349.2 ; C531.2 92.67,127 v2(93,127.33) ; PC102.2 118.68,235.03 v2(118.63,235.09) ; C358.2 111.18,175.09 C1464.2 111.18,173.19 v2(111.52,172.85) ; C404.2 60.64,143.65 v3(61.19,144.21) ; C470.2 94.05,77.4 v3(94.05,78.3) ; C350.2 27.32,181.15 27.57,180.9 v2(27.57,180.34) ; v2(63.38,169.54) 63.76,169.16 C368.2 ; v3(57.14,151.86) 57.57,151.43 C401.2 ; C494.2 76.41,56.26 v2(76.16,56.01) ; v2(93.51,128.47) 93.46,128.52 C423.2 ; v2(93.86,82.93) 94.44,82.36 C455.2 94.55,81.56 C456.2 ; J2.199 186.25,130.11 186.95,130.81 v2(186.95,133.43) ; v2(99.71,128.91) 99.71,129.52 C435.2 98.94,129.52 v2(98.94,128.91) ; Q64.S v2(186.39,43.37) ; v2(48.78,31.88) 47.75,30.85 C533.2 v3(47.75,28.46) ; v2(166.23,53.24) 167.44,52.03 Q60.E ; Q57.S 82.14,88.46 82.61,88.93 v2(82.71,88.93) ; C475.2 100.3,71.17 v3(100.55,71.42) ; v2(47.53,20.62) 46.9,21.26 C542.2 C543.2 45.39,21.47 C544.2 44.15,21.47 v2(43.32,20.64) ; C427.2 v2(111.47,122.48) ; v2(192.16,14.48) 192.16,17.65 191.15,18.67 PC153.2 ; C1462.2 v2(96.72,28.38) ; v2(95.87,128.5) 95.87,129.03 C437.2 94.5,129.39 94.5,128.7 v2(95.06,128.14) ; C555.2 92.79,129.67 v2(93.48,129.67) ; 0.9,144.59 1.35,145.04 CN13.P42 ; v2(18.93,81.09) 18.93,79.57 C452.2 ; v2(31.51,14.92) 30.87,14.92 30.24,14.29 R760.2 ; v2(96.78,128.91) 96.78,129.52 C436.2 97.55,129.52 v2(97.55,128.91) ; v2(93.55,130.75) 93.55,131.43 C434.2 92.59,131.12 v2(92.59,130.94) ; C1460.2 40.17,32.97 40.04,32.97 v2(39.84,32.77) ; v2(59.95,171.32) 59.4,170.76 R546.1 ; C460.2 90.04,80.1 C464.2 ; C460.2 89.42,81.03 89.16,81.28 v2(89.16,81.92) ; C460.2 C454.2 ; v2(53.99,39.12) 54.85,38.25 L69.1 ; C453.2 38.65,85.93 v2(39.35,85.93) ; C422.2 v2(87.76,130.93) ; v2(109.23,61.21) 108.98,61.47 C482.2 107.89,62.09 v3(106.71,63.27) ; v2(83.04,129.29) 83.04,129.07 C420.2 v2(83.83,129.46) ; v2(35.72,86.06) 35.75,86.08 R634.2 ; v3(100.04,66.01) 100.59,65.45 R664.1 ; 59.7,150.54 59.55,150.39 C400.2 ; C467.2 C466.2 ; v2(79.64,73.91) 80.4,73.91 81.42,72.9 82.57,72.9 C458.2 83.74,72.4 C457.2 ; C550.2 v2(31.51,14.1) ; v2(10.93,25.43) 10.93,25.4 9.03,23.5 8.39,23.5 8.03,23.13 R980.2 v2(7.26,22.54) ; C363.2 110.75,164.23 110.75,163.86 110.81,163.8 110.81,162.69 111.17,162.32 C380.2 ; PR73.2 v2(126.7,231.34) ; v2(38.11,18.54) 38.54,18.37 C539.2 ; v2(58.18,174.62) 57.03,173.48 R544.2 ; C465.2 107.64,78.23 108.28,78.87 v3(109.04,78.87) ; C430.2 v2(86.29,131.11) 86.39,131.02 C433.2 ; v2(85.42,131.44) 85.42,130.81 85.15,130.55 C428.2 82.87,130.55 82.24,129.92 82.24,128.46 v2(82.43,128.27) ; C552.2 15.81,5.76 15.31,5.27 v2(15.31,4.25) ; v3(99.51,53.62) 100.42,52.7 C497.2 100.91,53.27 v3(101.75,54.11) ; C488.2 94.96,64.23 v3(95.01,64.18) ; v2(56.08,163.98) 56.08,163.26 55.26,162.43 C378.2 ; v3(95.7,66.65) 95.59,66.54 C486.2 ; R757.1 23.45,22.47 v2(23.06,22.86) ; v2(106.49,228.98) 107.24,228.98 PR75.2 ; C424.2 v2(110.68,124.33) ; C432.2 v2(90.94,131.42) ; v2(79.4,232.51) 79.64,232.75 U18.2 ; v3(68.84,138.63) 68.92,138.56 C413.2 ; Q58.2 14.31,91.76 14.06,92.01 13.35,92.01 v2(13.35,92.01) ; v2(82.94,234.19) 82.55,233.79 82.55,233.77 U18.4 ; v2(174.64,55.24) 174.64,54.74 174.17,54.27 U22.3 173.55,55.31 v2(173.62,55.37) ; CN13.P41 1.35,116.06 0.82,116.59 ; C374.2 v2(188.55,167.25) ; C370.2 98.82,167.51 v2(98.05,168.28) ; v2(106.21,230.5) 106.23,230.53 106.97,230.53 PR74.2 ; C449.2 51.15,88.72 v2(50.82,88.39) 50.43,88.39 C450.2 ; R543.2 60.46,174.12 60.65,174.31 v2(60.65,175.7) ; C473.2 12.79,76.41 v2(12.71,76.33) ; v3(129.3,161.54) 129.04,161.8 C385.2 ; U26.3 10.17,18.14 v2(9.61,17.58) ; v2(92.29,106.53) 92.72,106.96 PR82.2 ; v2(13.66,3.56) 13.24,3.14 Q66.S ; v2(120.56,228.54) 120.57,228.55 PR76.2 ; C503.2 v3(100.72,54.23) ; v2(153.62,15.05) 153.24,15.43 R518.2 ; C447.2 35.55,84.48 v2(35.55,84.48) ; C362.2 v2(62.49,171.7) ; R425.2 101.61,44.12 v2(101.46,43.97) ; v3(63.66,144.83) 64.53,144.83 C414.2 ; v2(80.4,226.69) 80.4,226.44 79.72,225.76 C347.2 ; U21.1 v2(64.23,66.19) ; C438.2 v2(101.1,129.54) ; v2(41.29,39.5) 41.46,39.67 C517.1 ; v2(186.95,146.49) 187.97,146.49 v2(188.35,146.11) ; Q61.S v2(177.24,53.03) ; C522.2 C521.2 115.92,32.22 v2(116.27,32.56) ; C536.2 25.59,21.77 25.03,21.21 23.89,21.21 v2(23.38,21.72) ; C386.2 C379.2 59.62,160.83 60.95,162.15 v2(60.95,162.89) ; C479.2 97.55,70.05 v3(97.54,70.05) ; Q65.S v2(6.93,17.72)
  BOTTOM w0.635: PC137.2 76.13,119.23 v2(75.96,119.41)
  BOTTOM w0.762: v2(170.7,228.35) 171.46,227.58 PC106.2 ; 3.88,146.88 v2(3.88,150.94) v2(3.88,156.02) v2(3.88,161.1) v2(3.88,166.18) v2(3.88,171.26) v2(3.88,176.34) 3.88,176.66 3.31,177.23
  vias: v1(5.09,193.87) v1(5.54,185.48) v1(6.36,216.92) v1(6.68,209.23) v1(6.81,204.22) v1(7.19,221.93) v1(11.31,226.76) v1(16.39,232.35) v1(22.81,238.32) v1(23.12,185.04) v1(24.27,243.84) v1(36.21,221.74) v1(38.81,5.84) v1(43,227.46) v1(43.51,249.62) v1(46.75,222.44) v1(47.38,8.26) v1(51.89,249.56) v1(53.8,218.57) v1(55.76,224.66) v1(59.64,249.49) v1(59.64,8) v1(60.97,12.06) v1(63.7,15.18) v1(63.89,218.69) v1(66.3,225.17) v1(68.46,213.49) v1(68.91,249.3) v1(73.8,6.79) v1(77.48,249.24) v1(85.61,7.56) v1(86.12,12.19) v1(86.82,249.3) v1(94.37,249.24) v1(95.77,10.79) v1(98.25,6.99) v1(112.66,251.71) v1(126.19,250.82) v1(130.57,249.11) v1(137.62,249.11) v1(138.57,36.83) v1(140.79,49.85) v1(144.85,249.3) v1(163.27,251.52) v1(165.68,6.41) v1(183.59,56.9) v1(184.03,6.41) v1(186.83,92.84) v1(187.4,51.75) v1(188.8,120.4) v1(189.18,132.78) v1(189.24,104.27) v1(190.96,60.71) v2(0.9,144.65) v2(0.9,142.11) v2(0.9,139.57) v2(0.9,137.03) v2(0.9,134.49) v2(0.9,131.95) v2(0.9,129.41) v2(0.9,126.87) v2(0.9,124.33) v2(0.9,121.79) v2(0.9,119.25) v2(0.9,116.71) v2(1.41,112.9) v2(1.79,234.82) v2(1.79,232.28) v2(1.79,229.74) v2(1.79,227.2) v2(1.79,224.66) v2(1.79,222.12) v2(1.79,219.58) v2(1.79,217.04) v2(1.79,214.5) v2(1.79,211.96) v2(1.79,209.42) v2(1.79,206.88) v2(1.79,204.34) v2(1.79,201.8) v2(1.79,199.26) v2(1.79,196.72) v2(1.79,194.18) v2(1.79,191.64) v2(1.79,189.1) v2(1.79,186.56) v2(1.79,184.02) v2(1.79,181.48) v2(1.79,178.94) v2(1.79,110.36) v2(1.79,107.82) v2(1.79,105.28) v2(1.79,102.74) v2(1.79,100.2) v2(1.79,97.66) v2(1.79,95.12) v2(1.79,92.58) v2(1.79,90.04) v2(1.79,87.5) v2(1.79,84.96) v2(1.79,82.42) v2(1.79,79.88) v2(1.79,77.34) v2(1.79,74.8) v2(1.79,72.26) v2(3.08,236.14) v2(5.88,236.14) v2(8.23,106.74) v2(8.27,104.65) v2(8.27,102.62) v2(8.27,100.58) v2(8.27,98.55) v2(8.27,85.6) v2(8.27,83.57) v2(8.27,81.53) v2(8.27,79.5) v2(8.77,236.98) v2(10.42,239.01) v2(10.83,243.97) v2(10.83,241.55) v2(10.86,254.13) v2(10.86,251.59) v2(10.86,249.05) v2(10.86,246.51) v2(13.85,254.13) v2(16.39,254.13) v2(18.11,175.64) v2(18.11,81.09) v2(18.17,174.18) v2(18.55,100.08) v2(18.93,254.13) v2(20.84,62.1) v2(21.22,61.02) v2(21.27,131.36) v2(21.35,130.21) v2(21.47,254.13) v2(21.6,62.1) v2(21.7,83.69) v2(21.78,88.7) v2(21.85,86.3) v2(22.36,182.63) v2(22.42,131.32) v2(22.42,130.21) v2(23,141.99) v2(23.12,144.15) v2(23.89,144.78) v2(23.89,143.38) v2(24.01,254.13) v2(26.17,18.77) v2(26.55,254.13) v2(27.24,98.94) v2(27.25,101.09) v2(27.57,0.89) v2(27.7,18.22) v2(29.09,254.13) v2(29.98,101.03) v2(30.62,18.16) v2(31.63,254.13) v2(31.63,65.91) v2(31.63,65.15) v2(32.62,63.47) v2(34.17,254.13) v2(34.43,100.08) v2(35.19,0.89) v2(35.25,60.26) v2(35.57,57.98) v2(35.7,100.9) v2(36.71,254.13) v2(37.73,0.89) v2(38.3,210.96) v2(38.36,100.08) v2(39.25,254.13) v2(40.27,0.89) v2(40.4,37.59) v2(41.59,61.19) v2(41.79,254.13) v2(42.33,61.04) v2(42.81,0.89) v2(43.88,82.63) v2(44.33,254.13) v2(45.35,0.89) v2(46.87,254.13) v2(47.89,0.89) v2(49.41,254.13) v2(50.43,0.89) v2(51.95,254.13) v2(52.68,84.48) v2(52.97,0.89) v2(54.49,254.13) v2(54.62,80.77) v2(55.45,85.41) v2(57.03,254.13) v2(59.12,134.62) v2(59.09,133.93) v2(59.32,0.89) v2(59.5,84.81) v2(59.57,254.13) v2(59.98,86.74) v2(61.86,0.89) v2(62.11,254.13) v2(64.4,0.89) v2(64.65,254.13) v2(65.24,41.61) v2(66.75,77.91) v2(66.94,0.89) v2(67.19,254.13) v2(67.45,67.31) v2(67.45,68.14) v2(67.57,43.24) v2(67.7,40.51) v2(68.34,68.12) v2(68.34,67.31) v2(69.04,77.66) v2(69.22,68.13) v2(69.23,67.31) v2(69.23,43.24) v2(69.73,254.13) v2(69.66,28.24) v2(69.73,26.24) v2(70.39,28.24) v2(70.65,26.26) v2(71,107.7) v2(71.07,77.85) v2(71.51,106.93) v2(72.02,0.89) v2(72.27,254.13) v2(72.53,78.36) v2(73.29,64.07) v2(73.44,78.36) v2(73.87,72.01) v2(74.18,168.02) v2(74.18,167) v2(74.18,105.28) v2(74.56,0.89) v2(74.81,254.13) v2(75.07,105.28) v2(75.25,136.96) v2(75.32,121.34) v2(75.37,119.96) v2(75.45,72.49) v2(75.6,70.61) v2(75.75,122) v2(75.86,120.68) v2(75.96,105.28) v2(76.21,115.32) v2(76.54,138.79) v2(76.69,122.25) v2(77.1,0.89) v2(77.16,115.32) v2(77.35,254.13) v2(77.38,71.53) v2(77.99,114.74) v2(78.6,116.46) v2(78.7,115.67) v2(79,137.92) v2(79.26,212.34) v2(79.64,0.89) v2(79.89,254.13) v2(82.43,254.13) v2(82.94,109.66) v2(83.04,64.14) v2(83.58,109.16) v2(84.15,108.58) v2(84.97,254.13) v2(85.34,220.41) v2(85.33,219.68) v2(85.35,0.89) v2(87.13,127.38) v2(87.13,126.11) v2(87.51,254.13) v2(87.64,207.01) v2(87.64,206.25) v2(87.64,205.49) v2(87.64,111.28) v2(87.64,110.49) v2(87.56,105.08) v2(87.64,87.5) v2(87.69,202.69) v2(87.67,106.78) v2(87.67,103.56) v2(87.89,127.38) v2(87.89,126.11) v2(87.89,0.89) v2(88.33,88.95) v2(88.53,110.49) v2(88.71,106.81) v2(88.68,103.56) v2(89.42,110.49) v2(89.55,199.45) v2(89.55,198.56) v2(89.61,200.6) v2(90.05,254.13) v2(90.24,200.98) v2(90.31,201.93) v2(90.31,200.03) v2(90.31,110.49) v2(90.37,199.07) v2(90.37,198.18) v2(90.43,0.89) v2(91.12,220.47) v2(91.92,52.02) v2(92.18,231.39) v2(92.18,230.5) v2(92.18,229.62) v2(92.31,223.65) v2(92.59,254.13) v2(93.05,218.54) v2(93.08,216.46) v2(93.36,220.47) v2(93.76,219.43) v2(93.76,217.47) v2(94.47,218.54) v2(94.5,216.92) v2(94.58,220.47) v2(95.13,254.13) v2(95.6,231.99) v2(95.64,230.94) v2(96.78,0.89) v2(97.67,254.13) v2(99.32,0.89) v2(99.83,107.82) v2(99.83,106.55) v2(99.9,244.67) v2(100.21,254.13) v2(100.59,107.82) v2(100.59,106.55) v2(100.91,78.23) v2(101.1,242.57) v2(101.93,198.63) v2(102.06,199.45) v2(102.31,197.8) v2(102.69,200.28) v2(102.75,254.13) v2(102.88,198.5) v2(103.13,199.45) v2(103.26,82.11) v2(103.52,197.68) v2(103.58,200.28) v2(103.64,198.63) v2(105.29,254.13) v2(107.83,254.13) v2(109.61,105.54) v2(109.61,104.78) v2(110.37,254.13) v2(110.75,105.54) v2(110.75,104.78) v2(111.2,202.88) v2(111.47,110.54) v2(111.71,205.36) v2(111.96,202.88) v2(112.23,110.54) v2(112.79,63.88) v2(112.91,254.13) v2(113.55,181.23) v2(113.55,180.47) v2(115.45,254.13) v2(115.45,239.52) v2(115.45,235.13) v2(115.78,186.41) v2(115.96,0.89) v2(116.11,185.19) v2(116.24,187.07) v2(117.23,63.88) v2(117.68,237.15) v2(117.99,254.13) v2(118.5,0.89) v2(119.64,223.27) v2(119.64,222.5) v2(119.82,239.46) v2(119.77,225.04) v2(119.77,224.16) v2(120.53,254.13) v2(120.64,222.44) v2(120.66,225.04) v2(120.66,224.16) v2(120.66,223.27) v2(121.04,0.89) v2(121.3,31.75) v2(121.3,30.73) v2(121.3,29.72) v2(121.3,28.7) v2(121.68,63.88) v2(122.08,44.78) v2(122.57,31.75) v2(122.57,30.73) v2(122.57,29.72) v2(122.57,28.7) v2(122.69,22.61) v2(122.87,44.78) v2(122.97,107.47) v2(123,106.27) v2(123,105.26) v2(123,103.23) v2(123.07,254.13) v2(123.3,102.41) v2(123.3,101.65) v2(123.3,100.89) v2(123.45,22.61) v2(123.45,21.84) v2(123.58,0.89) v2(123.71,44.78) v2(123.76,104.24) v2(123.84,31.75) v2(123.84,30.73) v2(123.84,29.72) v2(123.84,28.7) v2(124.19,103.23) v2(124.19,102.41) v2(124.19,101.65) v2(124.19,100.89) v2(124.42,99.97) v2(124.42,99.21) v2(125.61,254.13) v2(126.15,45.21) v2(126.12,0.89) v2(128.15,254.13) v2(128.66,0.89) v2(130.69,254.13) v2(131.2,0.89) v2(133.23,254.13) v2(133.49,54.86) v2(133.74,0.89) v2(135.77,254.13) v2(136.21,54.89) v2(136.35,222.95) v2(136.28,0.89) v2(136.79,222.38) v2(137.36,235.59) v2(137.78,236.47) v2(138.31,254.13) v2(138.5,235.59) v2(138.62,236.47) v2(139.05,54.91) v2(139.33,48.44) v2(139.58,217.68) v2(139.89,54.91) v2(140.09,0.89) v2(140.47,217.68) v2(140.85,254.13) v2(141.11,38.99) v2(141.11,37.47) v2(142.28,48.39) v2(142.63,38.99) v2(142.63,37.47) v2(142.63,0.89) v2(142.89,50.16) v2(142.89,49.28) v2(143.39,254.13) v2(143.4,214.31) v2(144.24,214.31) v2(145.07,214.31) v2(145.93,254.13) v2(148.47,254.13) v2(149.11,27.56) v2(149.24,35.69) v2(149.24,33.66) v2(150.12,35.69) v2(150.12,33.66) v2(150.12,27.56) v2(150.25,48.77) v2(151.01,254.13) v2(151.01,0.89) v2(151.14,35.69) v2(151.14,33.66) v2(151.14,27.56) v2(151.39,30.61) v2(152.8,231.25) v2(152.85,229.37) v2(153.05,49.02) v2(153.05,46.99) v2(153.55,254.13) v2(153.55,0.89) v2(154.19,10.35) v2(154.72,231.24) v2(154.82,229.26) v2(155.01,10.35) v2(155.46,11.68) v2(156.09,254.13) v2(156.09,0.89) v2(156.47,51.44) v2(157.87,58.1) v2(157.98,52.94) v2(158.63,254.13) v2(158.63,0.89) v2(160.21,237.57) v2(161.01,237.21) v2(161.17,254.13) v2(161.17,0.89) v2(161.89,237.46) v2(163.71,254.13) v2(163.71,0.89) v2(164.35,228.6) v2(165.49,228.6) v2(166.25,254.13) v2(166.25,0.89) v2(167.02,228.73) v2(167.65,12.19) v2(167.65,9.65) v2(168.03,228.6) v2(168.54,33.53) v2(168.54,32.64) v2(168.79,254.13) v2(168.79,0.89) v2(168.92,227.58) v2(168.92,10.92) v2(169.56,228.47) v2(169.81,36.83) v2(169.94,227.58) v2(169.94,12.19) v2(169.94,9.65) v2(170.83,38.99) v2(170.83,36.83) v2(171.33,254.13) v2(171.33,0.89) v2(171.46,30.35) v2(172.48,30.35) v2(173.49,28.83) v2(173.62,26.8) v2(173.87,254.13) v2(173.87,0.89) v2(174,14.73) v2(174.51,26.8) v2(175.4,27.81) v2(175.4,26.8) v2(176.41,254.13) v2(178.19,14.35) v2(178.45,62.23) v2(178.45,61.47) v2(178.57,62.99) v2(178.95,254.13) v2(179.08,14.35) v2(179.33,61.72) v2(180.1,13.72) v2(181.37,11.94) v2(181.49,254.13) v2(181.62,237.24) v2(182.51,237.24) v2(182.51,43.69) v2(182.51,42.8) v2(182.51,41.91) v2(182.76,11.94) v2(182.76,0.89) v2(183.78,12.14) v2(184.03,254.13) v2(185.3,0.89) v2(186.32,12.32) v2(186.57,254.13) v2(187.59,12.32) v2(187.84,0.89) v2(188.93,64.72) v2(188.92,63.79) v2(188.91,62.82) v2(188.91,61.86) v2(188.89,60.86) v2(188.93,59.52) v2(188.86,13.84) v2(188.86,12.7) v2(189.11,254.13) v2(189.81,14.03) v2(189.81,13.08) v2(190.38,0.89) v2(191.65,254.13) v2(192.92,0.89) v2(194.17,253.62) v2(194.17,251.08) v2(194.17,248.54) v2(194.17,246) v2(194.17,243.46) v2(194.17,240.92) v2(194.17,238.38) v2(194.17,235.84) v2(194.17,233.3) v2(194.17,230.76) v2(194.17,228.22) v2(194.17,225.68) v2(194.17,223.14) v2(194.17,220.6) v2(194.17,218.06) v2(194.17,215.52) v2(194.17,212.98) v2(194.17,210.44) v2(194.17,207.9) v2(194.17,205.36) v2(194.17,202.82) v2(194.17,200.28) v2(194.17,197.74) v2(194.17,195.2) v2(194.17,192.66) v2(194.17,190.12) v2(194.17,187.58) v2(194.17,185.04) v2(194.17,182.5) v2(194.17,179.96) v2(194.17,177.42) v2(194.17,174.88) v2(194.17,172.34) v2(194.17,169.8) v2(194.17,167.26) v2(194.17,164.72) v2(194.17,162.18) v2(194.17,159.64) v2(194.17,157.1) v2(194.17,154.56) v2(194.17,152.02) v2(194.17,149.48) v2(194.17,146.94) v2(194.17,144.4) v2(194.17,141.86) v2(194.17,139.32) v2(194.17,136.78) v2(194.17,134.24) v2(194.17,131.7) v2(194.17,129.16) v2(194.17,126.62) v2(194.17,124.08) v2(194.17,121.54) v2(194.17,119) v2(194.17,116.46) v2(194.17,113.92) v2(194.17,111.38) v2(194.17,108.84) v2(194.17,106.3) v2(194.17,103.76) v2(194.17,101.22) v2(194.17,98.68) v2(194.17,96.14) v2(194.17,93.6) v2(194.17,91.06) v2(194.17,88.52) v2(194.17,85.98) v2(194.17,83.44) v2(194.17,80.9) v2(194.17,78.36) v2(194.17,75.82) v2(194.17,73.28) v2(194.17,70.74) v2(194.17,68.2) v2(194.17,65.66) v2(194.17,63.12) v2(194.17,60.58) v2(194.17,58.04) v2(194.17,55.5) v2(194.17,52.96) v2(194.17,50.42) v2(194.17,47.88) v2(194.17,45.34) v2(194.17,42.8) v2(194.17,40.26) v2(194.17,37.72) v2(194.17,35.18) v2(194.17,32.64) v2(194.17,30.1) v2(194.17,27.56) v2(194.17,25.02) v2(194.17,22.48) v2(194.17,19.94) v2(194.17,17.4) v2(194.17,14.86) v2(194.17,12.32) v2(194.17,9.78) v2(194.17,7.24) v2(194.17,4.7) v2(194.17,2.16) v3(18.4,181.56) v3(19.06,200.03) v3(19.14,183.77) v3(21.64,191.08) v3(22.5,197) v3(22.46,194.03) v3(22.49,193.17) v3(22.74,203.33) v3(22.74,202.18) v3(24.14,189.61) v3(24.67,192.96) v3(27.52,192) v3(27.82,112.9) v3(27.82,111.51) v3(28.33,194.06) v3(28.27,91.38) v3(36.33,90.74) v3(36.58,226.03) v3(36.74,157.35) v3(37.41,111.82) v3(37.53,151.92) v3(37.58,156.01) v3(37.7,153.7) v3(37.88,160.43) v3(37.91,150.6) v3(37.86,113.92) v3(38.03,226.03) v3(38.9,148.03) v3(39.03,157.3) v3(39.32,113.98) v3(39.53,153.44) v3(39.61,226.01) v3(39.56,155.88) v3(39.95,110.88) v3(40.78,111.76) v3(41.16,225.78) v3(41.24,147.75) v3(41.54,92.9) v3(41.51,59.49) v3(41.97,218.95) v3(42.15,149.53) v3(42.68,225.65) v3(42.81,146.38) v3(42.76,112.18) v3(43.25,108.71) v3(43.53,62.07) v3(43.6,148.01) v3(43.68,223.65) v3(44.33,106.55) v3(44.44,218.88) v3(44.7,182.85) v3(44.78,107.38) v3(45.4,219.2) v3(45.35,144.59) v3(45.52,225.04) v3(45.87,138.44) v3(46.44,130.66) v3(46.61,142.86) v3(46.6,141.51) v3(46.57,128.06) v3(47.96,128.1) v3(48.24,226.36) v3(48.25,159.72) v3(48.2,130.79) v3(48.3,158.06) v3(48.37,227.89) v3(48.8,156.72) v3(48.86,161.47) v3(48.95,220.54) v3(49.23,128.05) v3(49.55,138.41) v3(49.79,156.31) v3(49.87,155.24) v3(50.23,158.47) v3(50.33,184.28) v3(50.4,126.23) v3(50.53,228.12) v3(50.83,129.42) v3(50.99,91.11) v3(51.95,136.91) v3(52.64,228.07) v3(52.6,92.42) v3(52.94,62.51) v3(53.03,184.89) v3(53.58,60.07) v3(54.14,208.41) v3(55.05,228.04) v3(55.54,208.41) v3(55.89,184.94) v3(55.89,82.61) v3(56.43,208.41) v3(56.78,206.58) v3(56.86,205.69) v3(57.28,227.97) v3(57.83,208.41) v3(58.72,208.34) v3(59.6,227.91) v3(60.11,208.34) v3(60.21,138.3) v3(60.21,137.41) v3(61,208.34) v3(61.83,227.99) v3(62.4,208.34) v3(63.29,208.34) v3(64.09,228.02) v3(64.68,208.34) v3(65.19,163.23) v3(65.83,208.28) v3(66.35,227.97) v3(66.64,163.47) v3(67.22,208.28) v3(67.89,188.98) v3(68.11,208.34) v3(68.69,163.47) v3(69.51,208.34) v3(69.73,189.93) v3(69.84,164.21) v3(71,164.26) v3(71,162.46) v3(71.77,190.31) v3(74.2,182.75) v3(75.14,182.73) v3(76.78,194.88) v3(77.15,186.02) v3(77.6,183.02) v3(77.67,195.77) v3(78.54,182.99) v3(79.51,184.59) v3(79.84,195.19) v3(89.16,184.53) v3(89.16,183.64) v3(89.16,182.75) v3(91.87,52.84) v3(92.01,64.82) v3(92.18,63.77) v3(92.4,53.41) v3(92.96,69.21) v3(93.88,64.42) v3(94.1,70.07) v3(94.08,69.4) v3(94.77,65.49) v3(95.21,62.85) v3(96.4,68.52) v3(96.36,62.84) v3(97.29,184.78) v3(97.29,182.5) v3(97.54,62.18) v3(97.67,63.25) v3(98.32,63.03) v3(100.98,184.4) v3(100.98,183.51) v3(100.98,182.63) v3(102.42,86.46) v3(104.7,86.18) v3(106.64,86.15) v3(108.7,86.16) v3(117.88,209.04) v3(119.17,209.04) v3(127.65,211.87) v3(128.21,212.6) v3(136.66,215.64)
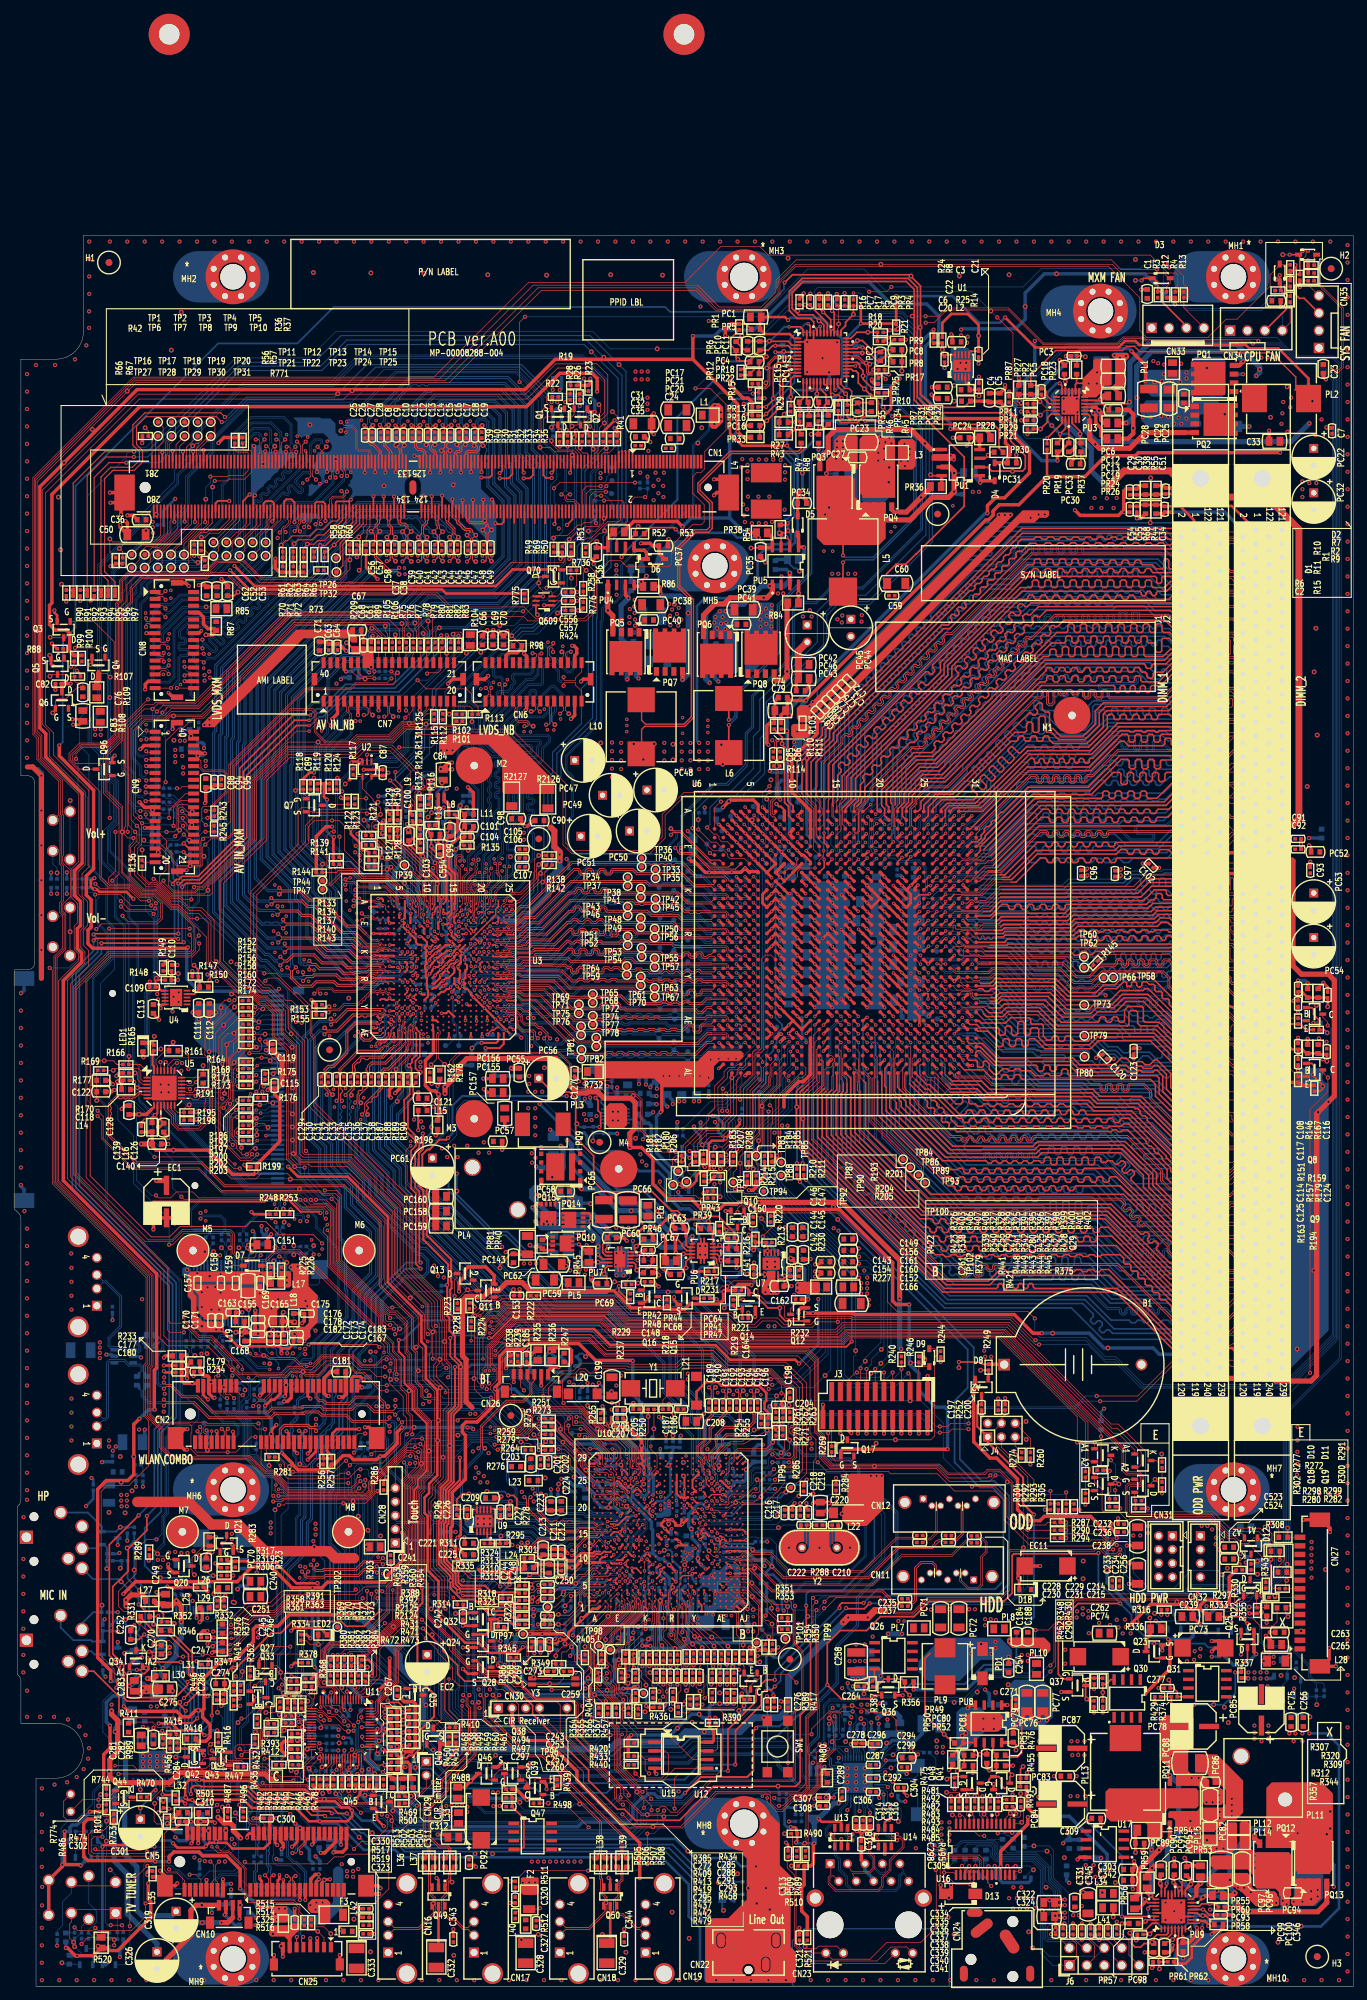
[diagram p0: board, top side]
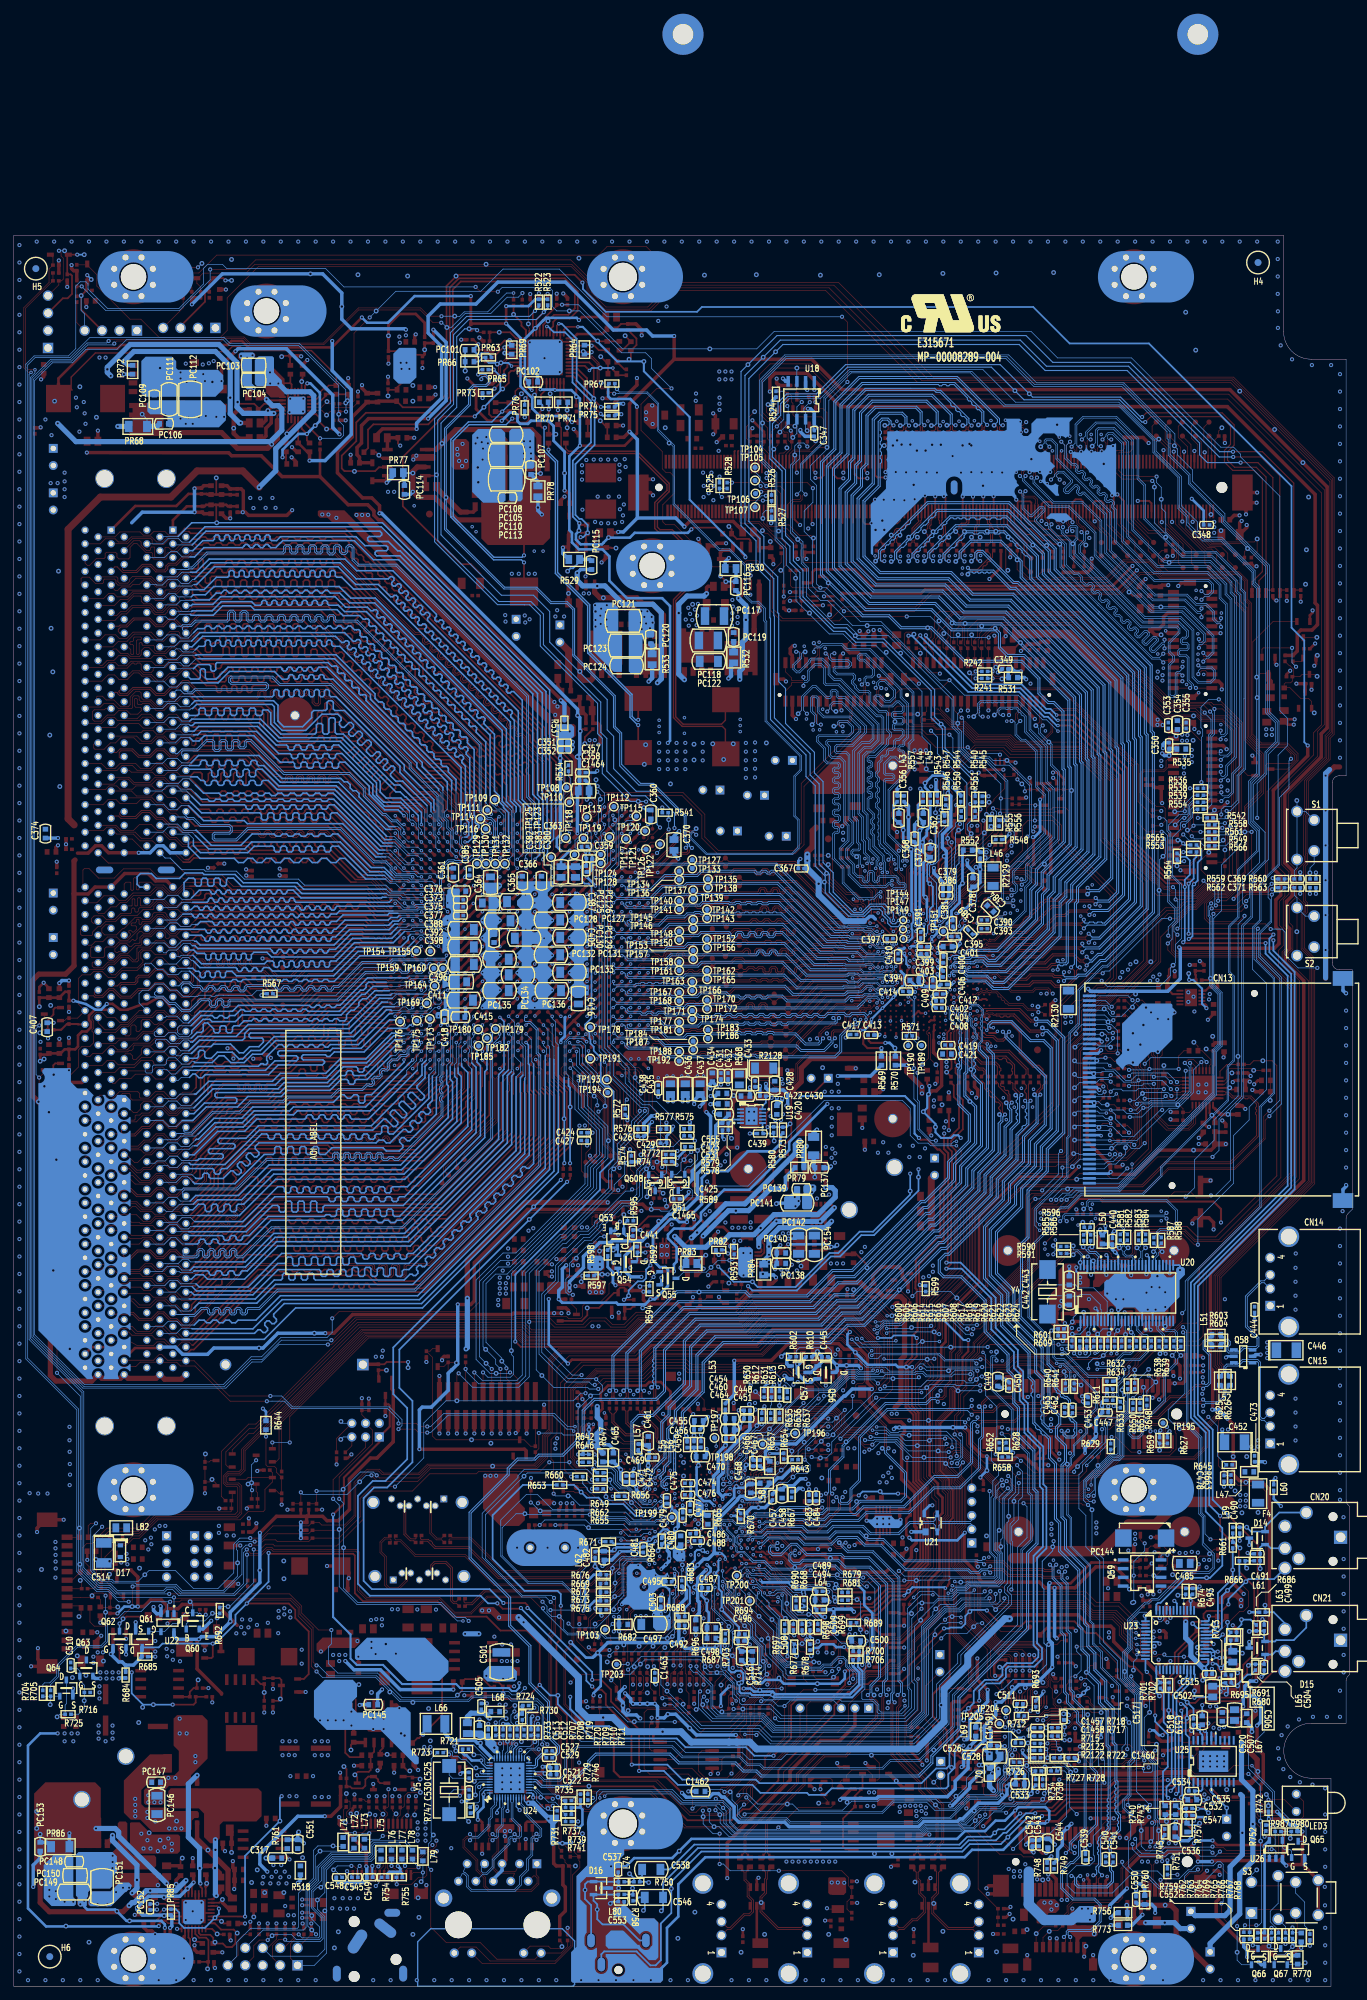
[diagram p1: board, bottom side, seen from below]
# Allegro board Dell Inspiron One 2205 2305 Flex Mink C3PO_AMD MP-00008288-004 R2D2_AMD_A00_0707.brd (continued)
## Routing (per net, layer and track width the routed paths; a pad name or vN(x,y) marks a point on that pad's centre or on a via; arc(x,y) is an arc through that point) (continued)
GND_AUDIO: length 248.5
  TOP w0.381: v2(26.49,47.37) 27,46.86 L31.1 ; L25.1 22.36,58.1 v2(22.24,58.23) ; v2(21.54,27.94) 21.62,27.86 L32.1 ; 42.29,28.66 35.74,28.66 34.49,29.91 27.61,29.91 27.48,30.04 v2(26.87,30.04) 25.41,30.04 24.84,29.46 24.84,27.5 25.2,27.14 25.85,27.14 v2(25.86,27.15) 26.15,26.86 26.17,26.86 26.22,26.86 26.47,26.61 27.15,26.61 27.51,26.61 28.08,27.18 33.34,27.18 34.53,25.98 40.9,25.98 42.86,24.03 v2(44.44,24.03) 48.45,24.03 49.16,24.74 49.16,25.55 v2(49.11,25.6) 48.68,26.03 47.57,26.03 46.65,26.95 44,26.95 42.29,28.66
  TOP w0.508: C249.2 20.94,57.11 v2(20.65,57.4) ; L35.1 19.55,16.81 19.31,16.57 v2(19.31,16.24) ; C252.1 16.9,52.07 v2(17.41,52.58)
  BOTTOM w0.254: U23.42 25.54,55.76 v2(25.92,56.13)
  BOTTOM w0.279: U23.26 22.22,48.17 v2(22.57,48.51)
  BOTTOM w0.381: C499.2 12.84,53.21 v2(13.09,53.47) ; L60.1 11.44,70.99 v2(10.39,69.94) ; C553.2 106.07,11.19 106.06,11.18 ; C490.2 v2(16.39,64.9) ; 100.85,2.41 99.83,3.43 99.83,8.51 98.18,10.16 98.18,14.86 94.24,18.8 56.46,18.8 55.38,19.88 50.85,19.88 47,23.72 44.74,23.72 v2(44.44,24.03) 44.14,24.32 44.14,25.53 44.71,26.1 48.61,26.1 v2(49.11,25.6) 50.58,24.13 51.95,24.13 53.48,22.61 56.43,22.61 57.57,21.46 96.28,21.46 v1(98.05,19.68) 99.07,18.67 104.61,18.67 105.8,17.47 C537.2 v2(107.98,17.47) 108.01,17.5 111.06,17.5 112.74,15.82 112.74,12.01 112.15,11.43 112.15,5.07 CN22.MH2 ; D14.3 v2(15,64.27) ; C491.2 15.12,62.99 v2(15.25,63.12) ; R686.1 v2(15,54.48) ; R674.1 C493.2 22.57,57.96 v2(22.24,58.23) ; C504.2 12.84,45.47 v2(13.22,45.09)
  BOTTOM w0.508: R773.2 35.16,8.89 v2(35.19,8.92) ; C550.1 31.23,11.93 R760.1 29.21,11.93 28.71,11.43 v2(28.71,10.69) ; R756.2 34.43,10.72 v2(35.19,9.96) ; C515.2 20.41,46.18 v2(20.46,46.23) ; D15.3 v2(15,50.16) ; D16.3 v2(109.43,14.3)
  vias: v2(1.28,68.33) v2(1.26,62.23) v2(1.26,59.69) v2(1.26,57.15) v2(1.26,54.61) v2(1.26,52.07) v2(1.26,48.26) v2(1.26,45.72) v2(1.79,70.87) v2(1.79,43.05) v2(1.79,39.24) v2(3.69,39.24) v2(3.95,28.83) v2(3.95,25.02) v2(3.95,22.48) v2(3.95,19.94) v2(3.95,17.4) v2(3.95,8.51) v2(3.95,5.97) v2(3.95,3.43) v2(3.95,0.89) v2(4,14.48) v2(3.97,11.79) v2(5.73,39.24) v2(5.79,29.38) v2(6.49,0.89) v2(7.63,29.72) v2(7.76,38.86) v2(9.03,30.48) v2(9.03,0.89) v2(9.41,37.85) v2(10.04,31.62) v2(10.3,36.58) v2(10.68,33.15) v2(10.81,34.67) v2(11.57,0.89) v2(14.11,0.89) v2(16.65,0.89) v2(18.68,43.43) v2(18.68,33.53) v2(18.68,32.77) v2(18.68,32) v2(19.19,42.93) v2(19.19,0.89) v2(19.7,33.53) v2(19.7,32.77) v2(19.7,32) v2(19.82,40.77) v2(20.71,40.77) v2(20.71,33.53) v2(20.71,32.77) v2(20.71,32) v2(21.73,33.53) v2(21.73,32.77) v2(21.73,32) v2(21.73,0.89) v2(102.18,0.89) v2(104.72,0.89) v2(107.26,0.89) v2(109.8,0.89) v2(112.34,0.89)
P0V75_VTT_SUS: length 238.8
  TOP w0.254: 154.7,233.5 PR23.2 ; 154.7,233.5 155.64,233.5 ; 154.7,233.5 154.52,233.32 154.52,232.35 PU3.2
  TOP w0.508: v2(176.79,165.11) J2.48 181.19,165.11 182.21,166.12 183.09,166.12 184.16,165.05 185.71,165.05 ; 186.22,159.11 184.16,159.11 183.16,160.11 J2.49 178.84,162.08 175.42,162.08 174.36,161.01 172.71,161.01 J1.49
  TOP w0.762: J1.120 170.6,88.42 173.02,88.42 J1.240 174.27,88.54 178.35,88.54 J2.120 179.47,88.54 182.15,88.54 J2.240 183.65,88.16 188.84,88.16 189.66,88.98 189.66,127.1 v1(189.88,127.32) v1(191.4,128.84) 192.24,129.68 192.24,146.53 191.35,147.42 187.44,147.42 186.22,148.64 186.22,163.91 186.07,164.06
  TOP w1.016: v2(159.24,218.34) 161.63,220.73 168.29,220.73 172.1,216.92 182.38,216.92 187.08,212.22 187.08,170.05 186.19,169.16
  BOTTOM w0.508: v2(176.79,165.11) 175.14,165.11 174.13,166.12 173.21,166.12 172.2,165.11 J1.48
  BOTTOM w0.762: v2(156.45,233.45) 155.26,232.26 151.85,232.26 151.29,231.7 151.29,229.49 156.83,223.95 156.83,220.75 v2(159.24,218.34)
  vias: v2(157.64,233.45) v2(157.67,235.08)
P1V1: length 131.1
  TOP w0.254: PR41.1 105.18,108.62 PC64.2 104.83,109.83 102.53,112.14 100.57,112.14 100.14,111.71 97.79,111.71 96.54,112.95 95.64,112.95 92.86,115.74 85.85,115.74 84.34,117.25 84.34,120.95 81.72,123.57 81.72,129.34 80.81,130.25 78.34,130.25 PC56.1
  TOP w0.305: v2(64.84,76.99) 64.84,73.76 63.21,72.12 63.21,67.36 62.93,67.08 62.93,62.03 64.63,60.33 64.63,58.83 65.1,58.36 68.51,58.36 69.49,57.38 73.32,57.38 R310.1
  TOP w0.406: R217.2 v2(98.82,104.14)
  TOP w0.508: v2(54.79,129.44) 54.57,129.66 54.57,130.58 55.03,131.04 R187.2 ; v2(57.69,172.03) 57.59,171.92 57.59,170.95 L9.1
  BOTTOM w0.356: R540.1 v2(54.94,174.37)
  BOTTOM w0.381: v2(76.46,128.52) 82.03,122.96 82.03,121.82 87.82,116.03 91.5,116.03 94.88,112.65 94.88,111.63 96.15,110.36 98.82,110.36 99.69,109.49 99.69,108.95 98.44,107.7 98.44,105.54 98.82,105.16 v2(98.82,104.14)
  BOTTOM w0.508: v2(74.94,132.59) 70.17,132.59 R569.2 ; R665.2 94.2,68.59 94.75,69.13 94.75,70.1 v3(95.32,70.68)
  vias: v1(125.23,75.76) v1(125.49,79.1) v2(40.97,141.29) v2(40.97,140.46) v2(41.79,141.22) v2(41.79,140.34) v2(49.6,165.16) v2(50.24,164.72) v2(50.3,163.96) v2(62.11,180.02) v2(62.94,180.02) v2(63.76,180.02) v2(74.81,130.3) v2(74.81,127.89) v2(74.94,131.44) v2(75.83,130.3) v2(75.83,127.89) v2(75.83,126.49) v2(75.83,125.22) v2(75.83,123.95) v2(76.85,130.3) v2(80.78,88.01) v2(81.42,87.63) v2(98.05,89.23) v2(98.05,88.42) v2(115.83,79.82) v2(116.09,79.06) v2(116.09,78.3) v2(124.72,74.36) v2(125.55,74.36) v2(126.31,74.36) v3(95.32,70.04)
P1V1_PWRGD: length 19.9
  TOP w0.102: v2(113.55,100.71) 113.75,100.51 R232.2 113.75,99.39 113.03,98.67 Q12.D ; R220.1 110.58,112.19 110.75,112.01 110.75,111 v2(108.98,109.22)
  BOTTOM w0.102: v2(108.98,109.22) 109.61,109.22 110.63,108.2 111.14,108.2 113.04,106.3 v1(113.04,106.05) 113.29,106.05 114.03,105.31 114.03,103.53 114.56,103 114.56,101.09 114.18,100.71 v2(113.55,100.71)
P1V1ALW: length 130.1
  TOP w0.381: v2(70.37,46.74) 70.56,46.74 71.27,46.02 73.75,46.02 v2(73.92,45.85)
  TOP w0.508: 67.57,60.71 67.96,60.33 72.09,60.33 ; 65.29,61.4 64.22,62.47 64.22,63.87 63.51,64.58 63.51,66.8 63.74,67.03 63.74,71.94 65.65,73.85 65.65,80.27 65.21,80.71 65.21,81.66 65.75,82.19 67.37,82.19 70.34,85.17 70.34,86.64 v2(69.99,87) 69.99,87.25 70.65,87.91 70.65,91.74 71.69,92.78 74.01,92.78 74.83,93.61 82.17,93.61 84.62,91.16 89.98,91.16 v2(90.03,91.11) ; 72.09,60.33 72.53,60.77 74.11,60.77 L24.1 74.26,61 R301.1 ; 72.09,60.33 v2(72.09,58.53)
  BOTTOM w0.381: v2(70.37,46.74) 70.37,47.04 70.65,47.32 70.65,48.49 69.91,49.23 69.91,54.33 71.09,55.51 71.09,57.53 v2(72.09,58.53) ; R714.2 87.39,44.83 86.72,44.16 85.97,44.16 85.51,44.63 83.37,44.63 82.81,44.07 v1(77.93,44.07) 74.69,44.07 73.92,44.83 v2(73.92,45.85)
  BOTTOM w0.508: L53.1 91.32,84.9 90.03,86.19 v2(90.03,91.11) ; R657.2 85.48,77.1 85.48,77.88 85.03,78.33 84.82,78.33 84.15,78.99 81.04,78.99 74.05,85.98 73.86,85.98 72.85,87 v2(69.99,87)
P1V2_CPU_VDDHT: length 34.7
  TOP w0.381: v2(105.6,126.14) 105.6,125.55 v1(103.54,123.49) 103.21,123.16 101.56,123.16 101.1,122.71 101.1,121.64 100.97,121.5 100.97,119.77 101.23,119.51 101.23,119 100.92,118.7 99.91,118.7 99.32,118.11 99.32,117.35 98.37,116.4 97.29,116.4 v2(96.85,116.84)
  TOP w0.508: v2(94.09,127.33) 94.27,127.51 94.27,132.36 v3(94.5,132.59)
  BOTTOM w0.381: R572.1 105.6,126.62 v2(105.6,126.14)
  BOTTOM w0.508: v2(96.85,116.84) 96.15,117.54 96.15,118.75 93.48,121.41 93.48,126.72 v2(94.09,127.33)
  vias: v3(95.39,132.59) v3(96.78,132.59) v3(97.67,132.59) v3(98.94,132.59) v3(99.83,132.59) v3(101.1,132.33) v3(101.4,134.96) v3(102.54,135.09) v3(103.94,135.09) v3(105.08,135.09)
P1V2_CPU_VDDNB_RUN: length 322.9
  TOP w0.203: v2(121.93,231.46) 121.93,232.35 121.55,232.73 120.98,232.73 120.38,233.33 PU2.24
  TOP w0.254: R315.1 69.78,55.19 67.5,57.47 64.72,57.47 63.84,58.34 63.84,59.97 62.14,61.67 62.14,67.54 62.42,67.82 62.42,72.45 63.56,73.59 63.56,83.4 64.68,84.52 64.68,90.53 63.45,91.76 v2(63.45,94.42) ; v2(69.1,94.44) 69.51,94.44 72.67,97.6 85.93,97.6 88.3,95.23 102.92,95.23 105,93.14 121.14,93.14 121.92,93.92 v2(121.93,93.92) ; 127.01,205.74 128.41,207.14 129.8,207.14 131.27,208.6 131.33,208.6 138.31,215.58 138.31,222.76 132.41,228.66 v2(127.84,228.66) ; PR32.2 124.79,229.37 v2(123.84,229.37) PC26.2 ; 120.66,203.23 v2(120.66,207.39)
  TOP w0.381: U6.G10 113.37,163.51 112.11,164.77 U6.F9 111.69,165.2 111.69,165.24 v3(111.66,165.26) 111.64,165.26 111.52,165.38 111.51,165.38 U6.E8 v3(110.21,166.68) U6.D7 v3(108.99,167.91) U6.C6 v3(107.71,169.18) U6.B5 v3(106.41,170.48) U6.A4 ; U6.A6 v3(108.93,170.5) U6.B7 110.13,169.3 v3(110.37,169.3) 110.37,169.06 U6.C8 v3(111.53,167.9) U6.D9 v3(112.73,166.7) U6.E10 v3(113.98,165.45) U6.F11 114.94,164.78 115.92,163.8 U6.G12
  TOP w0.5: v2(103.19,171.73) 104.24,172.79 107.61,172.79 108.3,172.1 U6.A6
  TOP w0.508: PC43.1 115.73,189.31 PC46.1
  BOTTOM w0.203: v2(121.93,231.46) 121.93,231.27 v2(123.84,229.37) 125.34,227.86 128.76,227.86 131.33,225.3 131.33,214.07 131.28,214.02 131.28,213.96 125.09,207.77 121.04,207.77 v2(120.66,207.39)
  BOTTOM w0.254: v2(69.1,94.44) 67.14,94.44 66.79,94.79 63.82,94.79 v2(63.45,94.42) ; 112.15,163.01 112.2,162.96 112.2,160.99 111.82,160.6 111.26,160.6 110.83,160.17 110.83,141.02 111.77,140.08 111.77,139.52 111.14,138.89 111.14,138.05 110.98,137.9 110.98,137.34 110.5,136.86 110.5,136.27 109.48,135.25 109.48,131.7 108.85,131.06 108.34,131.06 107.62,130.35 107.62,120.48 109.59,118.52 109.59,116.01 121.93,103.67 v2(121.93,93.92) ; PR65.2 v2(125.08,235.48) 124.12,234.52 124.12,232.38 v1(126.5,230) v2(127.84,228.66)
  BOTTOM w0.381: C359.1 112.29,165.78 111.77,165.26 v3(111.66,165.26) 111.66,164.36 111.58,164.27 C363.1 111.58,164.26 C380.1 ; v3(113.98,165.45) 115.26,164.17 C382.1
  BOTTOM w0.508: C360.2 102.79,171.33 v2(103.19,171.73) ; C382.1 115.19,163.01 113.25,163.01 C383.1 113.09,163.01 112.15,163.01 111.99,163.18 C380.1
  vias: v2(114.82,199.52) v2(115.83,200.43) v2(116.09,199.52) v2(119.09,205.74) v2(119.85,199.11) v2(119.98,205.74) v2(120.48,198.65) v2(120.56,199.67) v2(121.42,205.74) v2(122.44,205.74) v2(123.4,199.72) v2(123.35,198.78)
P1V2_CPU_VDDR: length 151.2
  TOP w0.305: v2(64.12,90.2) 64.15,90.17 64.15,84.52 63.18,83.56 63.18,73.75 62.04,72.61 62.04,68.05 61.76,67.77 61.76,61.47 63.46,59.77 63.46,57.96 65.09,56.34 67,56.34 69.23,54.1 71.13,54.1 72.53,52.7 R321.1
  TOP w0.381: v2(114.26,90.69) 113.69,91.26 104.21,91.26 102.08,93.39 86.76,93.39 84.42,95.73 73.62,95.73 v2(73.19,95.3)
  TOP w0.508: 117.23,184.4 116.93,184.1 116.93,182.5 113.22,178.79 113.22,173.94 115.92,171.23 U6.A12 U6.B12 U6.C12 U6.D12 ; 112.05,128.09 112.05,129.64 114.18,131.78 114.9,131.78 115.92,132.8 U6.AL12 U6.AK12 U6.AJ12 U6.AH12 U6.AG12 ; C72.1 C73.1 C75.1 C77.1 C78.1 C80.1 C81.1
  BOTTOM w0.381: v2(117.06,100.1) 117.06,93.49 v2(114.26,90.69) ; v2(64.12,90.2) v1(64.96,90.2) 66.18,90.2 66.51,90.53 70.6,90.53 v1(72.4,92.33) 73.54,93.47 73.54,94.95 v2(73.19,95.3)
  vias: v2(111.8,125.37) v2(112.58,125.35) v2(119.31,110.41) v2(120,110.06) v2(147.99,213.89) v2(149.16,214.37) v2(150.05,214.38)
P1V5: length 160
  TOP w0.305: R178.1 61.92,131.44 v2(61.61,131.13) ; v2(44.52,112.65) 44.35,112.82 41.64,112.82 39.78,114.68 36.78,114.68 36.4,114.3 20.2,114.3 19.12,113.22 v2(19.12,111.25)
  TOP w0.381: v2(91.98,40.82) 92.16,40.64 R436.2 ; v2(88.65,43.37) 89.42,43.37 89.86,43.37 90.18,43.69 v2(90.74,43.69)
  TOP w0.508: v2(25.09,88.52) 25.09,90.37 R234.2
  TOP w0.762: v2(29.6,24.64) 30.46,23.78 31.41,23.78 31.86,23.34 31.86,22.64 v2(32.9,21.59)
  INT1 w0.381: v2(57.03,123.57) 57.03,123.32 47.57,113.86 45.73,113.86 v2(44.52,112.65)
  INT1 w0.762: v2(72.73,46.94) 72.73,46.68 71.89,45.85 69.73,45.85 67.96,47.62 62.18,47.62 61.65,47.1 61.65,45.62 60.54,44.51 55.57,44.51 54.62,45.47 53.48,45.47 52.84,46.1 51.25,46.1 50.32,47.03 45.71,47.03 45.01,46.32 45.01,45.65 43.49,44.13 43.13,44.13 42.31,43.32 42.31,38.26 40.79,36.74 38.94,36.74 37.71,35.51 37.71,31.61 36.97,30.86 36.97,24.45 35.13,22.61 33.54,22.61 32.9,21.97 v2(32.9,21.59)
  BOTTOM w0.305: v2(57.03,123.57) 57.41,123.95 58.05,123.95 58.43,123.57 59.9,123.57 60.72,124.39 v1(60.72,125.16) 60.72,125.6 v1(62.49,127.38) 61.92,127.95 61.92,129.79 61.61,130.11 v2(61.61,131.13)
  BOTTOM w0.381: v2(90.74,43.69) 91.98,42.44 v2(91.98,40.82) ; v2(88.65,43.37) 87.67,43.37 87.17,42.93 84.44,42.93 84.05,42.53 73.18,42.53 71.82,43.89 71.82,45.69 72.73,46.61 v2(72.73,46.94) R706.2
  vias: v2(22.49,63.17) v2(23.38,63.27) v2(24.27,63.12) v2(25.16,63.12) v2(26.05,63.37) v2(29.6,25.53)
P1V5_CPU_VDDIO_SUS: length 488.5
  TOP w0.203: 186.62,232.61 186.62,234.39 183.11,237.9 178.26,237.9 178.06,238.1 163.89,238.1 163.13,238.86 161.99,238.86 161.38,238.25 151.64,238.25 148.02,234.63 PR2.2 149.11,233.18 PC5.2 149.86,232.71 150.27,232.3 150.27,231.78 151.05,231 PU3.8
  TOP w0.254: 186.52,232.51 186.62,232.61 ; v2(113.68,227.83) R27.1
  TOP w0.305: R159.1 188.1,139.32 187.26,140.16 R151.1 185.68,140.16 185.63,140.11 J2.189 ; v2(158.18,231.14) 158.04,231 PU3.23
  TOP w0.381: v3(131.8,155.25) U6.P24 ; v3(139.43,157.73) 139.36,157.73 U6.M30 ; v2(158.76,149.71) 158.1,149.71 R145.2 ; v3(136.88,152.71) U6.T28 ; v3(131.8,151.44) U6.T24 ; C116.1 191.27,145.54 v2(190.64,146.18) 189.88,145.41 R167.1 ; v3(136.88,155.25) U6.P28 ; v3(134.37,152.73) 134.36,152.73 U6.T26 ; 188.48,233.4 188.48,234.19 184.1,238.57 179.86,238.57 179.35,239.07 163.83,239.07 163.26,239.65 161.73,239.65 160.79,238.71 148.65,238.71 v2(144.28,243.08) ; v3(131.8,143.82) U6.AB24 ; v3(136.88,141.28) U6.AD28 ; v2(123.26,244.73) v2(123.26,242.19) 128.33,242.19 R21.1 ; U6.AB30 138.78,144.45 v3(138.17,143.83) ; v3(131.8,146.36) U6.Y24 ; U6.AD26 133.13,141.34 v3(133.13,141.31) ; U6.AF30 138.13,140.03 v3(138.12,140.03) ; v3(134.34,157.79) U6.M26 ; v2(56.53,35.94) R419.1 ; v3(134.34,146.36) U6.Y26 ; v3(138.15,152.71) U6.T30 ; v3(133.07,148.9) U6.V25 ; v3(136.88,157.79) U6.M28 ; U6.V28 136.25,149.54 v3(136.88,150.17) ; v3(138.15,155.25) U6.P30 ; v3(134.34,155.25) U6.P26 ; v3(134.34,143.82) U6.AB26 ; PR20.1 150.38,219.9 ; v3(131.8,142.55) U6.AC24 ; v3(138.15,148.9) U6.V30 ; U6.Y29 v3(136.88,146.36) U6.Y28 ; v3(136.88,143.82) U6.AB28 ; v3(131.8,157.79) U6.M24
  TOP w0.4: U6.V26 v3(133.07,148.9) ; U6.AD30 v3(139.42,141.28)
  TOP w0.406: R215.2 108.6,117.22 109.23,117.86 R184.1 ; v2(128.41,246.19) R21.1
  TOP w0.508: R194.1 187.37,131.24 R163.1 185.06,131.65 J2.197 ; v2(98.44,119.63) 98.9,120.09 R182.1 ; v2(184.35,223.39) 163.69,223.37 163.26,222.94 158.94,222.94 155.9,219.9 150.38,219.9 146.27,215.8 143.43,215.8 142.57,214.94 142.57,214.85 142.52,214.8 142.52,214.26 141.86,213.6 141.47,213.6 115.3,187.42 v2(115.3,187.29) 112.96,187.29 C74.1 112.54,186.04 C79.1 111.64,185.14 R111.1 ; R201.1 101.18,117.22 v2(101.05,117.22) R193.1 ; C272.1 R385.1 55.69,40.34 55.31,40.72 53.88,40.72 v2(53.78,40.82) ; R215.2 107.99,116.38 107.55,115.95 v2(106.94,115.95) ; v2(54.62,47.75) 54.62,44.68 v2(53.12,43.18) ; v2(157.54,135.23) 158.02,135.71 C120.1 ; PL2.2 188.48,233.4 ; R55.1 167.31,218.58 C51.1 168.59,218.23 v2(168.66,218.16) ; C97.1 160.97,161.65 v2(161.12,161.8) ; R44.1 167.31,214.49 C34.1 v2(168.66,214.71) ; R183.1 103.49,120.09 103.69,120.3 v2(103.69,120.32) ; C96.1 156.15,161.7 v2(156.27,161.82) ; v2(100.53,119.32) 100.34,119.51 R180.1 ; C102.1 v2(166.71,162.92) ; C123.1 v2(163.86,136.62)
  TOP w0.762: v2(158.18,231.14) 158.68,231.65 PC13.1 ; v2(128.92,100.2) 128.92,105.79 120.53,114.17 v2(108.47,114.17)
  INT1 w0.508: 36.14,50.8 41.41,50.8 42.43,49.78 50.49,49.78 51.89,48.39 53.99,48.39 v2(54.62,47.75) 56.34,49.47 62.62,49.47 63.19,50.04 67.07,50.04 67.96,49.15 71.13,49.15 71.89,48.39 74.56,48.39 75.13,47.82 79.2,47.82 79.51,48.13 v2(80.91,48.13)
  BOTTOM w0.381: R567.2 158.68,144.58 v2(158.91,144.35) ; v2(113.68,227.83) 114.57,228.73 118.37,228.73 119.45,229.81 119.45,231.33 121.17,233.04 121.17,240.09 v2(123.26,242.19) ; R74.1 98.94,120.14 v2(98.44,119.63) ; v2(144.28,243.08) 143.52,242.32 140.47,242.32 136.6,246.19 v2(128.41,246.19) ; R523.1 R522.1 119.02,245.73 120.03,244.73 v2(123.26,244.73)
  BOTTOM w0.508: R677.1 81.29,48.51 v2(80.91,48.13) ; v2(101.66,126.77) 102.12,126.77 103.21,125.68 R576.1 ; R577.1 v2(99.91,125.81) ; v2(56.53,35.94) 56.14,35.94 55.7,36.39 55.7,38.9 53.78,40.82 v2(53.78,40.82) 53.12,41.48 v2(53.12,43.18) ; v2(96.53,125.88) 96.48,125.83 R575.1 ; R574.1 103.92,120.09 v2(103.69,120.32) ; v2(168.66,218.16) v2(168.66,214.71) 176.27,214.71 177.81,213.17
  BOTTOM w0.635: R537.1 114.77,186.76 v2(115.3,187.29)
  BOTTOM w0.762: v2(158.18,231.14) 158.18,231.09 157.32,230.23 156.44,230.23 155.94,229.73 155.94,226.65 157.61,224.99 185.94,224.99 v2(188.6,227.65) ; v2(128.92,100.2) 128.92,93.03 v2(129.11,92.84)
  vias: v1(182.95,228.54) v1(185.37,232.98) v1(188.29,174.75) v1(188.48,206.12) v1(189.05,230.89) v1(189.3,191.45) v1(189.56,197.8) v1(189.62,142.88) v1(189.75,182.25) v1(190.57,135.06) v2(35.44,51.56) v2(35.44,50.8) v2(37.29,67.56) v2(37.29,66.8) v2(37.29,65.98) v2(43.83,67.37) v2(43.83,66.61) v2(43.83,65.79) v2(61.1,104.97) v2(61.1,104.08) v2(61.67,103.44) v2(62.49,103.25) v2(82.94,127.03) v2(83.22,126.19) v2(84.03,126.19) v2(84.75,126.75) v2(91.15,121.18) v2(91.39,120.14) v2(92.02,119.57) v2(109.36,101.09) v2(109.8,101.85) v2(110.18,101.09) v2(111.07,101.09) v2(184.54,227.58) v2(184.67,229.11) v2(184.8,230.76) v2(185.43,226.44) v2(185.81,230) v2(185.94,231.39) v2(187.59,220.47) v2(187.59,219.2) v2(187.59,218.06) v2(187.59,216.92) v2(188.61,218.95) v2(189.49,225.93) v2(189.62,218.95) v2(190,138.07) v2(190.38,228.22) v2(191.1,137.57) v3(130.53,150.17) v3(130.54,147.56) v3(130.53,145.09) v3(131.8,152.71)
P1V5_CTL: length 4.5
  TOP w0.102: R289.2 20.11,63.68 v1(20.79,62.99) 21.12,62.66 22.19,62.66 22.68,62.16 Q20.G
P1V5_DDR3_PWRGD: length 311.1
  TOP w0.102: v2(105.29,112.78) 105.29,113.28 105.67,113.67 106.56,113.67 107.58,112.65 119.77,112.65 127.14,105.28 127.14,99.69 128.53,98.3 147.58,98.3 v2(148.6,97.28)
  TOP w0.254: 150.38,225.48 152.56,227.66 PU3.13 ; 150.38,225.48 v2(150.37,225.48) ; 150.38,225.48 PR20.2
  BOTTOM w0.102: v2(105.29,112.78) 104.74,112.22 R595.1 ; v2(150.37,225.48) 147.36,225.48 146.98,225.86 146.98,227.36 147.65,228.03 v1(147.65,228.98) 147.65,233.16 153.5,239.01 163.65,239.01 164.48,239.84 178.57,239.84 179.97,238.44 184.48,238.44 186.45,236.47 189.37,236.47 191.95,233.89 191.95,94.91 184.67,87.63 164.48,87.63 160.41,91.69 158.89,91.69 156.09,94.49 149.36,94.49 148.6,95.25 v2(148.6,97.28)
P1V5_TV: length 33.1
  TOP w0.508: CN5.28 38.73,21.16 39.13,20.76 39.13,20.26 v2(38.87,20) ; CN5.48 46.73,21.02 45.14,19.43 v2(44.59,19.43) ; R501.1 26.76,25.23 C310.1 26.73,23.98 CN5.6 v2(26.73,20.84)
  INT1 w0.508: v2(44.59,19.43) 44.21,19.81 42.87,19.81 41.54,21.15 40.02,21.15 v2(38.87,20) 38.3,19.43 37.48,19.43 36.97,18.92 31.81,18.92 29.65,21.08 26.97,21.08 v2(26.73,20.84)
  BOTTOM w0.508: C539.1 v2(38.87,20) ; v2(44.59,19.43) 44.33,19.68 C544.1
P1V5_WW: length 14.8
  TOP w0.508: C181.1 48.28,89.47 CN2.48 48.28,86.24 47.86,85.83 v2(47.25,85.83) ; R234.1 26.98,90.89 C179.1 27.62,88.9 28.08,88.9 28.28,88.7 CN2.6 28.28,86.35 28.9,85.72 v2(29.09,85.72) ; v2(39.25,85.19) 39.74,85.19 40.28,85.74 CN2.28
  BOTTOM w0.508: v2(39.25,85.19) 38.98,84.91 C453.1
P1V8: length 329.1
  TOP w0.305: R313.1 72.94,55.68 70.02,55.68 67.79,57.91 64.91,57.91 64.22,58.6 64.22,60.15 62.52,61.85 62.52,67.36 62.8,67.64 62.8,72.29 63.94,73.43 63.94,83.24 65.06,84.36 65.06,90.74 64.11,91.69 64.11,94.71 63.32,95.5 63.32,97.35 63,97.66 v2(63,102.16) 63.13,102.29 63.13,105.16 59.52,108.76 59.52,115.95 58.86,116.61 58.86,121.35 59.47,121.96 59.47,124.18 v2(59.45,124.21) ; L15.1 v2(58.78,124.69)
  TOP w0.381: v2(58.37,166.62) 58.37,166.18 58.86,165.69 R132.2 ; U2.5 52.13,176.35 C87.2 54,176.35 v2(54.43,176.78) ; v2(47,176.02) 46.87,175.9 R124.2
  TOP w0.508: L8.1 63.21,172.13 62.56,172.78 62.56,173.67 ; L11.2 66.82,173.85 v2(66.03,174.65) ; v2(135.9,78.23) 120.6,78.23 120.35,77.98 Q17.G ; 61.73,173.61 61.71,173.58 61.71,169.42 61.43,169.14 L13.2 ; v2(130.31,99.31) 130.3,99.3 128.42,99.3 127.9,99.82 127.9,105.41 120.15,113.16 107.96,113.16 106.94,114.17 105.42,114.17 105.17,113.92 103.39,113.92 102.75,113.28 99.96,113.28 98.54,114.71 95.13,114.71 92.97,116.87 92.97,120.52 91.32,122.17 v2(89.61,122.17)
  TOP w0.762: v2(62.69,130.05) v2(62.69,131) 64.91,133.22 v2(64.91,134.18) 65.86,135.13 78.88,135.13 80.27,133.73 80.27,131.75 81.92,130.1 83.32,130.1 83.5,130.28 84.94,130.28 85.86,129.35 89.74,129.35 90.37,128.71 90.37,124.97 89.61,124.21 v2(89.61,122.17)
  INT1 w0.762: v2(89.61,122.17) 85.2,122.17 84.01,120.98 84.01,114.73 82.98,113.7 82.98,112.24 80.9,110.16 80.9,107.56 79.64,106.3 79.64,104.33 81.1,102.87 81.1,93.09 82.27,91.92 108.3,91.92 111.3,88.93 111.3,87.23 109.99,85.93 v2(109.99,84.45)
  BOTTOM w0.381: L44.1 62.49,173.99 v2(62.94,174.43)
  BOTTOM w0.406: R599.2 62.9,102.05 v2(63,102.16)
  BOTTOM w0.508: R570.2 66.55,134.18 v2(64.91,134.18) ; v2(130.31,99.31) 130.31,90.64 131.2,89.76 131.23,89.76 131.71,89.28 131.71,86.8 134.15,84.36 135.49,84.36 135.9,83.95 v2(135.9,78.23) ; v2(66.03,174.65) 66.3,174.37 L43.1 R557.1 ; v2(53.3,165.17) L46.1 54.52,165.48 R552.1
  BOTTOM w0.762: v2(109.99,84.45) 109.99,82.87 109.48,82.36 109.48,81.03 110.03,80.48 110.03,78.53 109.18,77.67 R647.1
  vias: v1(29.35,149.22) v1(31.51,149.22) v2(28.08,147.37) v2(28.38,146.56) v2(28.99,147.07) v2(29.45,146.43) v2(32.32,148.87) v2(32.68,148.08) v2(33.51,147.73) v2(33.82,146.91) v2(58.18,126.24) v2(59.19,125.98) v2(59.45,125.09) v2(61.35,174.75) v2(64.37,174.45)
P1V8_CARD: length 4.3
  TOP w0.305: 19.95,127.76 20.28,128.09 U5.8
  TOP w0.508: C128.1 18.1,126.99 v1(18.11,127) 18.12,126.99 19.18,126.99 19.95,127.76
P1V25: length 114.2
  TOP w0.254: v2(92.37,104.83) 92.93,105.39 PR42.1 92.93,107.05 92.72,107.26 PC67.2 ; v3(60.46,151.26) 60.84,151.64 U3.J11 ; R237.2 89.26,100.03 88.02,101.27 v2(88.02,101.98) ; U3.T14 62.79,146.06 v3(62.44,145.71) 62.38,145.71 61.94,145.27 U3.U12 ; v3(63.52,150.22) 63.57,150.22 63.93,150.59 63.93,150.62 64.04,150.72 U3.K15 ; U3.M15 64.03,148.97 63.59,148.97 63.33,148.72 63.33,148.55 U3.N14 ; v3(61.14,148.37) 60.84,148.08 U3.P11 60.84,147.86 v3(60.44,147.46)
  TOP w0.3: U3.P14 v3(62.84,148.06) ; v3(62.84,148.06) U3.P13 62.44,147.64 v3(62.09,147.29) ; v3(62.84,148.06) U3.N14 ; v3(61.14,148.37) 61.14,148.41 61.19,148.46 U3.N12 v3(62.04,148.86) ; v3(62.04,148.86) U3.M12 ; v3(62.04,148.86) U3.M13 v3(62.44,149.78) ; U3.T15 U3.R15
  TOP w0.305: U3.U16 64.84,145.26 v3(64.44,145.66) 64.04,146.05 U3.T15 ; v3(62.09,147.29) 61.94,147.14 U3.R12 61.14,146.06 U3.T11 ; v3(63.52,150.22) 63.36,150.06 U3.L14 62.67,149.78 v3(62.44,149.78) ; U3.K15 64.05,150.86 v3(64.45,151.26) 64.84,151.65 U3.J16 ; v3(64.44,149.36) U3.M15 ; v3(60.44,149.46) 60.44,149.66 U3.L11 61.24,150.45 v3(61.34,150.45) 61.74,150.86 U3.K12 62.74,151.66 U3.J14 63.34,151.66 v3(63.51,151.49)
  BOTTOM w0.102: v3(60.46,151.26) 59.76,151.26 C401.1
  BOTTOM w0.254: v2(63.19,119) v1(63.19,117.86) 63.19,115.89 69.67,109.41 71.51,109.41 74.62,106.3 75.96,106.3 80.91,101.35 87.39,101.35 v2(88.02,101.98) ; v2(64.4,118.36) v1(64.4,115.82) 64.4,115.32 69.8,109.92 71.77,109.92 74.88,106.81 76.15,106.81 81.1,101.85 86.62,101.85 87.39,102.62 90.13,102.62 92.34,104.83 v2(92.37,104.83)
  BOTTOM w0.305: v3(63.52,150.22) 63.06,150.22 C403.1 ; C391.1 62.87,152.13 v3(63.51,151.49) 63.44,151.42 C399.1
  BOTTOM w0.381: C401.1 60.29,151.43 v3(60.46,151.26) ; v3(63.51,151.49) 64.21,151.49 v3(64.45,151.26)
  BOTTOM w0.508: v3(62.09,147.29) 62.9,147.29 63.14,147.05 63.14,146.54 C394.1 63.16,146.13 62.74,145.71 v3(62.44,145.71) 62.35,145.62 C409.1 60.24,145.62 C412.1 ; C403.1 62.86,150.2 v3(62.44,149.78) 62.04,149.38 v3(62.04,148.86) ; v3(60.44,149.46) 60.07,149.09 C400.1 ; C406.1 60.01,147.03 v3(60.44,147.46)
  vias: v2(62.24,122.05) v2(63,120.78) v2(64.02,122.43) v2(64.53,120.78) v2(65.92,122.43) v2(67.57,121.41) v2(68.34,122.94) v2(69.1,121.41) v2(82.97,131.47) v2(83.13,132.14)
P1V25_PWRGD: length 325.4
  TOP w0.102: v2(148.73,94.11) 148.52,94.11 145.27,97.36 122.11,97.36 121.93,97.54 114.44,97.54 114.18,97.28 112.41,97.28 112.15,97.54 112.15,99.06 111.77,99.44 109.74,99.44 108.28,100.9 108.28,102.3 107.83,102.74 104.66,102.74 103.9,101.98 103.08,101.98 102.09,100.99 100.75,100.99 100.42,100.66 R231.2 Q15.D ; PR3.1 120.91,246.61 v2(120.89,246.63) ; v2(180.35,239.27) 179.97,239.65 164.73,239.65 164.35,240.03 161.55,240.03 160.64,239.12 149.82,239.12 144.77,244.17 135.77,244.17 133.92,242.32 v2(132.71,242.32)
  BOTTOM w0.102: v2(148.73,94.11) 156,94.11 158.81,91.3 160.38,91.3 164.35,87.33 184.75,87.33 192.15,94.73 192.15,234.07 189.49,236.73 186.57,236.73 184.22,239.08 180.54,239.08 v2(180.35,239.27) ; v2(120.89,246.63) 121.5,246.02 123.12,246.02 125.49,243.66 129.22,243.66 131.27,241.62 v1(131.9,241.62) 132.6,242.32 v2(132.71,242.32)
P2V5_CPU_VDDA_RUN: length 481.1
  TOP w0.254: L2.2 138.32,230 133.87,230 131.95,231.91 131.95,247.66 130.33,249.29 113.28,249.29 v2(112.15,248.16)
  TOP w0.381: v2(74.03,49.4) 73.19,48.56 69.05,48.56 67.57,50.04 65.61,50.04 61.73,53.91 61.73,59 60.15,60.59 60.15,68.49 59.7,68.94 59.7,71.18 60.36,71.84 60.36,73.21 61.57,74.42 61.57,86.84 59.89,88.52 59.89,93.22 59.24,93.87 59.24,97.63 54.37,102.51 54.37,112.06 48.49,117.93 41.27,117.93 v2(39.83,119.38)
  TOP w0.508: U6.C10 113.38,168.48 v3(112.88,167.91) 113.29,167.32 U6.D10 ; v2(141.71,214.55) 141.71,215.67 142.84,216.8 144.19,216.8 147.84,220.45 147.84,223.52 145.68,225.68 145.68,228.59 C5.1 C4.1 141.86,230.89 L2.2 ; v2(6.49,180.72) 6.49,179.22 11.49,174.22 11.49,162.78 10.42,161.71 10.42,158.95 11.13,158.25 11.13,154.28 10.67,153.82 10.67,151.87 11.35,151.19 25.07,151.19 v2(25.21,151.33)
  INT1 w0.381: v2(38.49,145.29) 37.29,144.08 37.29,139.27 38.56,138 38.56,120.65 v2(39.83,119.38)
  BOTTOM w0.254: v2(6.49,180.72) 6.99,181.22 6.99,196.03 8.85,197.89 8.85,218.52 29.63,239.29 41.17,239.29 46.48,244.6 94.75,244.6 95.45,243.9 108.76,243.9 112.07,247.22 112.07,248.08 v2(112.15,248.16)
  BOTTOM w0.381: v2(74.03,49.4) 75.17,49.4 75.58,49.81 77.25,49.81 77.79,49.28 78.42,49.28 78.73,48.97 R678.1
  BOTTOM w0.508: v2(25.21,151.33) 25.06,151.18 25.06,146.76 26.88,144.93 38.14,144.93 v2(38.49,145.29) ; v3(112.88,167.91) 112.88,173.98 C1464.1 112.58,174.28 C358.1 C357.1 112.58,178.74 v1(112.91,179.07) 112.91,179.13 112.53,179.51 112.53,184.78 v1(112.85,185.1) 112.85,185.99 141.41,214.55 v2(141.71,214.55)
P3V3: length 491.2
  TOP w0.178: v2(48.02,40.26) 47.71,40.57 U11.8
  TOP w0.254: v2(104.79,41.15) R445.2 ; v2(103.77,41.15) R444.2 ; v2(105.93,42.67) 105.93,42.12 R375.1 ; R443.2 v2(101.61,41.15)
  TOP w0.3: v3(61.24,152.16) 60.99,152.16 U3.H11 ; U3.H12 61.29,152.86 v3(61.24,152.86)
  TOP w0.305: U5.10 21.28,126.15 C126.1
  TOP w0.381: R487.1 31.06,25.51 v2(31.06,26.29) ; v2(47.05,48.26) 47.05,47.6 R370.2 ; R302.2 v2(155.97,70.15) ; 45.03,175.18 45.03,173.29 v2(45.48,172.85) ; 45.03,175.18 R119.1 ; 45.03,175.18 R120.1 ; R282.2 v2(165.06,69.6) ; 51.97,45.26 v2(52.02,45.21) ; 51.97,45.26 R384.2 ; 51.97,45.26 52.16,45.45 52.16,46.91 51.52,47.55 R373.2 ; R355.2 v2(179.89,54.31) ; R492.2 137.55,27.56 v2(137.42,27.69) ; R372.2 v2(49.03,48.26) ; R393.2 36.92,38.72 v2(36.75,38.88) ; R402.1 107.26,49.15 v2(107.07,49.34) ; v2(79.51,207.9) 79.77,208.15 R69.1 R49.1 ; J2.237 183.61,93.1 J2.236 180.35,93.1 179.35,92.11 178.19,92.11 177.34,92.96 173.85,92.96 J1.236 ; R493.2 v2(140.98,27.69) ; R223.1 66.56,99.55 67,99.11 v2(67,98.93) ; v2(52.85,204.99) 51.18,206.65 R60.2 ; R140.1 R137.1 51.22,165.48 50.68,165.48 50.43,165.74 50.43,166.37 48.96,167.84 v2(48.96,168.55) ; v2(119.64,74.04) R284.2 ; Q1.G v2(79.3,229.78) ; R412.2 36.92,36.59 v2(36.59,36.26) ; v2(46.34,48.23) 46.34,47.9 45.98,47.55 R369.2 ; v2(55.45,169.04) 55.76,168.72 R128.1 ; R289.1 19.59,62.08 v2(19.52,62) ; v3(111.2,81.85) 111.45,81.85 111.9,81.41 R271.2 ; U15.8 U12.8 101.64,35.56 101.81,35.74 101.81,37.16 101.21,37.77 R390.1 ; v2(52.27,28.51) 52.72,28.96 R438.1 ; R127.1 v2(54.62,169.04) ; R285.2 114.95,73.41 115.33,73.79 v2(115.38,73.79) ; v2(26.93,208.28) 26.98,208.28 27.56,207.69 R771.2 ; R300.2 v2(167.14,71.81) ; R495.2 145.35,27.92 v2(145.36,27.94) ; R252.1 v2(143.27,85.6) ; v2(49.54,28.45) 49.67,28.57 R467.2 R466.2 ; R34.1 85.7,226.41 v2(87.39,228.09) ; v2(81.8,226.58) 81.66,226.44 R30.1 ; R371.2 v2(48.02,48.26)
  TOP w0.406: v2(14.3,131.38) 13.73,131.95 R177.2 ; R280.2 160.79,69.85 v2(161.05,69.6) ; R121.2 53.48,169.54 v2(53.73,169.8) ; R363.1 43.24,43.03 v2(43.14,42.93) ; v2(46.52,167.39) 46.42,167.29 R139.1 R141.1 ; C126.1 21.15,125.17 v2(20.86,125.17)
  TOP w0.508: R297.2 176.92,59.61 v2(176.92,55.31) 176.03,55.31 175.08,56.26 173.49,56.26 172.71,55.48 172.71,54.99 ; L14.1 15.56,131.67 C118.1 15.12,131.95 v2(14.93,131.76) ; v2(186.57,250.7) 186.57,250.19 186.27,249.89 R10.2 R11.1 ; v2(83.86,234.16) 83.86,233.5 R23.1 83.53,233.17 R19.1 ; R233.2 21.98,91.82 v2(21.73,91.57) ; R246.2 132.3,91.74 132.6,91.44 v2(132.6,91.19) ; v2(26.93,53.02) 27.32,53.4 27.32,54.85 L29.1 26.78,55.12 26.49,54.83 v2(26.49,53.66) ; v2(169.05,244.98) R4.1 R12.2 ; v2(29.67,224.79) 30.48,225.6 R36.1 R37.1 ; R198.2 26.34,126.15 v2(26.48,126.29) ; v2(149.62,95.12) 148.35,95.12 145.63,97.84 122.39,97.84 122.18,98.04 v2(116.28,98.04) v2(115.2,98.04) ; v2(80.78,207.9) 81.04,208.15 R50.1 ; v2(188.43,251.38) R7.2 R2.1 ; 172.71,54.99 R333.1 ; 172.71,54.99 171.08,54.99 170.44,55.63 165.49,55.63 162.44,52.58 ; R354.1 v2(108.21,48.97) ; v2(58.94,173.8) 59.07,173.67 R125.2 ; R424.1 v2(82.05,200.41) 82.48,200.41 R776.1 ; R256.1 44.41,76.02 v2(44.28,75.9) ; v2(84.49,229.31) 83.68,229.31 83.38,229.61 Q2.G ; v2(75.3,92.02) 76.01,92.73 R235.1 ; LED1.A 18.68,135.38 v2(18.76,135.31) ; v2(41.86,96.58) 42.19,96.92 C175.1 42.18,97.99 L18.1 ; v2(89.8,36.6) 89.37,36.17 R420.1 R433.1 ; R42.1 18.6,224.84 v2(18.55,224.79) ; v2(33.16,98.17) C163.1 L19.1 ; v2(101.21,39.09) R390.1 ; v2(134.88,90.93) R244.1 ; R122.1 47.71,173.02 v2(47.51,173.16)
  TOP w0.635: v2(23.06,24.13) 23.06,24.46 R474.2
  INT1 w0.381: v2(118.63,38.23) 119.39,37.59 122.18,37.59 122.82,38.23 122.82,38.48 123.58,39.24 124.09,39.24 124.72,39.88 127.77,39.88 129.58,38.07 136.06,38.07 140.37,33.76 140.37,30.28 141.62,29.03 141.62,28.77 ; 141.62,28.77 140.98,28.13 v2(140.98,27.69) 140.16,26.86 138.25,26.86 v2(137.42,27.69) ; 141.62,28.77 142.12,28.77 142.38,28.51 144.79,28.51 v2(145.36,27.94) 143.53,26.1 143.53,24.54 143.05,24.06 140.22,24.06 139.04,22.89 v2(139.04,17.5)
  INT1 w0.508: v2(188.43,251.38) 187.75,250.7 v2(186.57,250.7) 186.57,250.41 180.43,244.27 169.76,244.27 v2(169.05,244.98) ; v2(118.63,38.23) 118.63,38.3 117.49,39.45 114.29,39.45 113.04,38.2 108.98,38.2 108.62,38.56 104.18,38.56 v2(103.72,39.01)
  BOTTOM w0.381: v3(34.05,88.65) 34.55,88.14 R632.1 ; v2(176.92,55.31) v1(177.75,55.31) 178.89,55.31 v2(179.89,54.31) ; v2(58.94,173.8) 58.81,173.93 58.81,175.58 59.57,176.34 61.16,176.34 v1(62.24,175.26) 62.24,174.62 61.48,173.86 L45.1 ; R689.2 73.08,52.1 v2(73.16,52.02) ; v2(36.71,110.24) 36.71,109.66 36.47,109.42 L50.1 35.95,109.87 v2(35.95,110.74) ; R646.2 v2(112.79,76.33) ; R525.1 92.18,219.03 v2(92.18,219.9) ; R734.2 46.62,28.78 46.62,28.19 47.38,27.43 48.52,27.43 v2(48.78,27.69) ; R712.1 48.64,39.64 v2(48.02,40.26) ; v2(36.59,36.26) 36.59,38.72 v2(36.75,38.88) ; v2(110.6,75.34) 110.07,74.8 R649.2 ; R700.2 72.7,49.17 v2(72.99,49.45) ; 138.66,16.68 140.27,16.68 140.54,16.41 140.54,15.89 R754.2 ; 138.66,16.68 138.39,16.41 R755.2 ; 138.66,16.68 138.66,17.1 138.81,17.24 138.81,17.27 v2(139.04,17.5) ; v2(112.02,54.72) 111.76,54.99 111.76,58.69 110.5,59.94 R676.1 109.53,60.37 v1(110.31,61.15) L62.1 ; R751.1 v2(26.93,18.35) ; v2(118.63,38.23) R711.2 ; v3(111.2,81.85) v1(111.2,81.09) 111.2,79.06 112.07,78.18 R642.2 v2(112.79,77.47) ; v3(61.24,152.16) v3(61.24,152.86) 61.02,152.86 60.53,153.35 60.53,153.92 60.82,154.22 60.82,155.28 60.16,155.94 60.16,157.02 59.14,158.04 C386.1 ; v2(49.41,77.72) 50,78.31 R628.1 ; R655.2 v2(110.75,72.45) ; R656.2 v3(107.77,71.37) ; R772.1 98.82,121.16 v2(98.31,120.65) 97.21,121.74 R589.2
  BOTTOM w0.406: v2(45.48,172.85) 45.48,168.2 46.29,167.39 v2(46.52,167.39) ; R548.2 50.76,167.03 v2(49.92,167.87) ; v2(48.02,40.26) 48.02,41.1 C511.2 ; R593.1 v2(90.05,108.58) ; R659.1 28.08,80.84 v2(27.95,80.96)
  BOTTOM w0.508: J1.236 171.45,93.1 170.39,92.05 166.76,92.05 165.85,92.96 v1(159.27,92.96) 158.68,92.96 156.53,95.12 v1(151.2,95.12) v2(149.62,95.12) ; v2(105.93,42.67) 105.13,41.87 105.13,41.49 v2(104.79,41.15) v2(103.77,41.15) v1(102.69,41.15) v2(101.61,41.15) 101.21,40.74 v2(101.21,39.09) 100.24,39.09 v1(99.71,39.62) 98.56,39.62 v1(96.53,37.59) 95.54,36.6 v2(89.8,36.6) ; L55.1 96.91,80.07 v2(97.04,80.2) ; v2(84.67,213.11) 84.59,213.18 R527.1 ; v2(137.87,241.3) 138,241.43 145.81,241.43 147.2,242.82 v1(147.2,244.67) 147.2,246.63 150,249.43 v1(151.78,249.43) 164.6,249.43 v2(169.05,244.98) ; v2(84.49,229.31) 84.49,230.94 R524.2 ; C386.1 C379.1 58.76,161.37 59.14,161.75 59.14,165.32 59.7,165.87 59.7,167.77 58.48,168.99 58.48,173.34 v2(58.94,173.8) ; v2(103.56,103.33) 105.12,103.33 105.93,104.14 105.93,106.43 104.61,107.74 R592.1 ; R748.1 44.46,18.29 v2(43.83,18.92) ; v2(79.3,229.78) 78.92,229.78 78.37,229.24 U18.8 C347.1 ; v2(103.72,39.01) 103.8,39.01 104.3,39.52 105.73,39.52 106.23,40.03 106.23,40.88 v1(106.25,40.89) 106.23,40.91 106.23,41.35 106.79,41.91 106.79,42.77 v2(105.98,43.59) ; v3(106.83,53.84) R682.1 v2(106.83,51.7) ; v3(103.58,77.47) 104.02,77.91 L57.1
  BOTTOM w0.762: v2(51.57,31.62) 51.57,30.99 52.09,30.47 L70.1 52.84,29.08 v2(52.27,28.51)
  vias: v1(19.12,212.03) v1(20.58,214.38) v2(20.11,213.3) v2(20.11,212.53) v2(20.12,211.71) v2(20.76,144.53) v2(20.86,143.74) v2(39.63,103.25) v2(39.63,102.49) v2(107.58,51.69) v2(137.87,240.47) v2(138.82,240.28) v2(138.76,239.4) v2(159.57,52.63) v2(160.54,53.39) v2(160.81,52.28) v2(161.41,51.39) v2(161.73,53.43) v2(161.86,52.32) v2(162.58,51.41) v3(107.58,53.85)
P3V3_AUDIO_DVDD: length 0.9
  BOTTOM w0.305: v2(30.24,53.98) 30.13,53.86 U23.1
  vias: v1(32.01,55.88) v1(32.46,57.85)
P3V3_AVCC_SIO: length 8.3
  TOP w0.178: v2(50.62,34.99) 50.74,34.86 U11.50
  BOTTOM w0.254: v1(54.37,32.23) 53.32,32.23 L70.2
  BOTTOM w0.381: v2(50.62,34.99) 51.72,34.99 C526.1 51.78,34.01 C528.1
  BOTTOM w0.762: L70.2 52.71,31.76 51.3,33.17 C528.1
P3V3_BAT: length 7.6
  TOP w0.254: R249.2 141,90.6 140.66,90.93 v2(137.55,90.93)
  TOP w0.508: B1.1 144.09,90.6 R249.2
  BOTTOM w0.254: v1(137.55,90.11) v2(137.55,90.93)
P3V3_BT: length 12.3
  TOP w0.508: CN26.1 77.69,89.65 78.22,90.17 v2(79.23,90.17) ; R238.1 71.94,91.87 71.56,91.49 v2(71.56,90.02) ; C185.1 74.56,90.93 v2(75.07,90.42)
  BOTTOM w0.508: C445.2 76.34,91.69 v2(75.07,90.42) ; v2(71.56,90.02) 71.97,90.42 v1(73.67,90.42) v2(75.07,90.42) ; v2(75.07,90.42) 75.04,90.4 75.04,89.64 75.26,89.42 Q56.D
P3V3_CARD: length 60.7
  TOP w0.508: C115.1 37.05,130.76 v2(36.84,130.56) ; C115.1 37.86,129.92 38.62,129.16 38.62,123.06 35.24,119.68 R199.1 35.24,118.67 v2(35.19,118.62) 34.83,118.26 31.74,118.26 28.2,121.79 v1(23.12,121.79) 20.58,121.79 20.07,122.31 C140.1 20,122.74 L16.1 19.93,124.41 C139.1 ; C115.1 38.32,130.76 38.94,131.38 ; C119.1 v2(36.59,136.35)
  TOP w0.762: v2(20.65,117.37) 21.91,117.37 22.11,117.17 EC1.1 ; C140.1 v2(18.43,122.68) ; 38.94,131.38 38.94,135.02 C119.1
  INT1 w0.762: v2(18.43,122.68) 18.43,118.81 19.87,117.37 v2(20.65,117.37)
  BOTTOM w0.406: CN13.P21 37.26,130.97 v2(36.84,130.56) ; v2(35.19,118.62) 35.44,118.37 CN13.P3 ; v2(36.59,136.35) 37.07,135.87 CN13.P28
P3V3_CF33: length 2.9
  TOP w0.305: U5.9 20.78,127.2 v1(20.46,126.87)
  TOP w0.508: L16.2 20,126.42 v1(20.46,126.87)
P3V3_SB: length 26.9
  TOP w0.203: v3(98.72,60.11) 98.42,59.81 97.38,59.81 96.98,59.42 U10.V6
  TOP w0.254: U10.AA7 98.82,60.22 v3(98.72,60.11) ; U10.AC21 101.14,69.91 v3(100.85,69.62) ; v3(99.11,69.22) 99.11,69.25 ; 99.11,69.25 98.74,68.88 U10.Y19 ; 99.11,69.25 99.11,69.29 99.54,68.87 U10.AA19 ; v3(100.09,54.61) 100.09,55.5 99.64,55.95 U10.AA2 ; U10.AE5 102.75,58.62 v3(103.19,58.17) ; v3(100.66,60.77) 100.89,60.77 U10.AC8 ; v3(100.51,57.12) 100.44,57.19 U10.AB4 ; v3(99.99,61.41) 99.59,61.82 U10.AA9
  TOP w0.3: v3(104.23,60.16) 104.18,60.12 U10.AF7 ; v3(105.69,54.86) U10.AH1
  BOTTOM w0.102: v3(103.64,53.98) 103.58,53.91 C497.1
  BOTTOM w0.381: C495.1 98.72,59.36 v3(98.72,60.11)
  BOTTOM w0.4: v3(100.85,69.62) 100.16,70.31 C475.1 99.58,70.31 99.11,69.84 v3(99.11,69.22)
  BOTTOM w0.508: v3(100.66,60.77) 100.02,61.41 v3(99.99,61.41) 99.99,61.43 99.53,61.9 v1(99.53,62.31) 99.52,62.32 99.52,63.18 99.77,63.44 99.77,64.16 98.67,65.27 98.67,66.51 v1(98.56,66.61) 98.18,66.99 98.18,68.76 98.64,69.22 v3(99.11,69.22) ; C503.1 100.72,56.91 v3(100.51,57.12)
  vias: v3(102.88,53.98) v3(104.4,53.98)
P3V3_STB_EN: length 17.2
  TOP w0.254: v2(165.11,11.3) 165.11,11.41 165.37,11.67 PU9.27 ; PC93.1 174,10.41 173.24,11.18 v2(173.11,11.18) 172.36,11.18 172.35,11.17 PU9.13
  BOTTOM w0.254: v2(173.11,11.18) 173.06,11.22 PR85.2 171.38,11.22 170.89,10.73 170.89,9.21 170.19,8.51 167.14,8.51 v1(165.68,9.97) 165.11,10.54 v2(165.11,11.3)
P3V3_STBY: length 617.7
  TOP w0.102: 154.92,34.67 v2(154.92,33.69)
  TOP w0.178: v2(41.36,38.51) 41.46,38.51 42.3,37.67 U11.24
  TOP w0.254: v2(161.3,10.16) PU9.30 ; v2(84.95,46.69) 84.95,46.96 85.43,47.45 R405.2 ; R273.2 v2(76.34,81.53) ; R279.2 v2(76.34,78.11) ; R251.2 v2(76.34,82.68) ; R275.2 v2(76.46,80.39)
  TOP w0.381: R378.1 40.78,47.12 v2(40.27,46.61) ; R359.2 39.76,42.1 v2(39.95,42.29) 40.78,42.29 ; v2(82.28,48.06) 82.28,47.78 82.61,47.45 R404.2 ; R326.1 88.95,45.61 v2(89.36,45.21) 88.99,44.84 R423.2 ; v2(12.77,20.32) 13.03,20.57 19.7,20.57 v2(20.36,21.23) ; Q70.G 78.81,204.41 78.62,204.6 78.62,205.99 78.24,206.38 72.53,206.38 70.11,203.96 34.94,203.96 v2(32.01,206.88) ; v2(62.62,32.26) 62.62,32.51 64.27,34.16 R451.1 ; v2(17.28,158.39) 16.27,159.41 12.3,159.41 11.92,159.79 v2(11.67,159.79) 11.49,159.79 11.09,160.2 11.09,161.01 11.49,161.42 v2(11.59,161.42) ; R465.2 R464.2 45.48,28.68 v2(45.86,28.3) ; 40.78,42.29 R360.2 ; 40.78,42.29 41.08,42.59 R361.2 ; v2(23.06,20.83) 23.7,20.19 27.62,20.19 v2(27.82,20.4) 28.33,20.9 30.86,20.9 31.7,20.07 36.31,20.07 37.13,20.89 CN5.24 ; v2(78.34,28.7) 78.87,29.23 R439.1 ; 152.03,68.45 R292.1 ; R286.2 53.73,73.66 v2(54.18,74.1) ; 71.26,52.07 71.28,52.07 71.28,52.09 ; 71.26,52.07 v2(70.75,51.56) ; 71.26,52.07 71.28,52.09 ; 71.28,52.09 R322.2 ; R293.1 153.17,68.45 ; R389.1 110.63,42.29 v2(110.53,42.39) ; v2(92.59,49.59) v2(91.42,49.59) ; v2(49.79,27.3) 49.79,27.43 50.3,27.94 50.3,28.32 50.56,28.57 51.32,28.57 51.7,28.96 R468.2
  TOP w0.406: v2(85.63,84.48) 85.63,83.77 R265.2 ; CN2.24 38.68,86.32 37.81,85.45 37.37,85.45 v2(36.49,84.56) ; R463.2 44.46,28.75 v2(44.13,28.42) 43.44,29.11 R462.2
  TOP w0.508: CN5.24 37.13,24.45 C300.1 v2(38.12,24.46) ; 65.23,98.63 R228.2 ; 152.33,68.45 156.73,68.45 v2(159.14,66.04) ; 152.33,68.45 150,68.45 149.36,67.82 147.71,67.82 146.09,69.44 146.09,73.88 143.04,76.93 142.09,76.93 139.71,79.31 139.71,86.8 139.9,87 D8.A2 ; 152.33,68.45 152.33,68.45 R287.1 v2(153.17,67.56) ; v2(29.79,57.09) 29.79,57.97 L26.1 28.97,57.29 v2(28.97,57.09) ; v2(168.03,50.55) 168.29,50.29 168.29,46.23 164.73,42.67 164.73,42.55 ; v2(80.86,90.63) 81.11,90.88 81.11,92.61 80.73,92.99 78.5,92.99 R236.1 ; v2(107.33,102.11) 107.2,102.23 105.42,102.23 104.99,101.81 R221.1 103.39,101.35 103.26,101.22 v2(103.26,101.17) 103.26,99.97 102.68,99.39 98.36,99.39 97.55,98.58 95.57,98.58 R218.1 94.67,98.81 89.8,98.81 87.29,101.32 86.24,101.32 ; v2(153.17,65.28) R294.1 ; R422.2 85,44.17 v2(85.21,43.96) ; R431.2 40.04,34.54 v2(39.66,34.92) ; v3(38.92,77.67) 40.42,76.17 40.42,76.05 41.26,75.21 45.63,75.21 46.11,75.69 R257.1 46.55,76.02 47.81,77.29 48.75,77.29 49.34,76.71 52.72,76.71 v3(53.22,77.22) 53.86,77.22 55.7,79.06 55.7,80.7 v2(56.4,81.4) ; v2(75.06,51.34) 75.08,51.32 v2(76.85,51.32) 79.9,51.32 v2(80.01,51.2) ; v2(153.17,66.42) R290.1
  TOP w0.762: 86.24,101.32 86.15,101.22 77.1,101.22 76.85,101.47 74.94,101.47 73.92,102.49 71.64,102.49 70.5,101.35 69.23,101.35 68.34,100.46 65.8,100.46 65.23,99.89 65.23,91.82 65.75,91.3 65.75,85.17 66.61,84.3
  INT1 w0.381: 29.98,185.67 29.98,192.41 32.4,194.82 32.4,206.5 v2(32.01,206.88) ; v2(40.27,46.61) 40.14,46.61 39.13,45.59
  INT1 w0.762: v2(24.52,176.66) 21.09,176.66 20.33,175.9 20.33,170.31 19.76,169.74 19.76,167.7 17.28,165.23 v2(17.28,158.39) 17.28,141.54 16.01,140.27 16.01,129.98 14.62,128.59 14.62,117.54 23.82,108.33 23.82,91.44 25.47,89.79 26.36,89.79 26.87,89.28 26.87,87.57 24.08,84.77 24.08,68.45 25.73,66.8 25.73,65.34 27.89,63.18 27.89,59.25 28.97,58.17 v2(28.97,57.09)
  BOTTOM w0.254: v2(161.3,10.16) 161.3,18.99 v1(156.22,24.07) 156.22,27.43 v2(155.97,27.69) ; R635.2 86.02,84.1 v2(85.63,84.48)
  BOTTOM w0.381: R698.2 80.15,51.34 v2(80.01,51.2) ; v2(82.28,48.06) 82.28,50.01 82.69,50.42 R697.2 ; v2(11.59,161.42) 11.47,161.29 R559.1 ; v2(110.53,42.39) 110.53,42.7 109.48,43.74 109.48,48.13 v1(109.93,48.58) ; v2(54.18,74.1) 54.18,74.17 v1(53.22,75.12) v3(53.22,77.22) ; v1(113.87,50.1) 111.64,47.87 110.63,47.87 110.48,48.02 ; v2(76.85,51.32) 77.43,51.89 R699.2 ; v2(11.67,159.79) 11.42,159.79 11.19,160.02 R562.1 ; v2(36.49,84.56) 36.49,85.13 36.27,85.34 R611.2 ; U26.5 12.77,20.55 v2(12.77,20.32) R763.1 R762.1 ; v2(27.82,20.4) 27.82,20.84 27.57,21.09 27.57,21.8 R745.1 ; v2(23.06,20.83) 22.66,21.23 v2(20.36,21.23) ; R703.2 91.42,50.4 v2(91.42,49.59) ; v2(38.46,43.42) 39.13,42.75 v1(39.13,42.74) 39.57,42.29 v2(39.95,42.29) ; R612.1 84.59,87.25 v2(84.21,87.63)
  BOTTOM w0.406: R598.1 108.47,104.78 107.71,104.01 107.71,102.49 v2(107.33,102.11) ; v2(82.71,87.34) 82.31,86.93 R613.1 ; R594.1 v2(103.26,101.17)
  BOTTOM w0.508: R749.1 42.93,18.47 42.93,19.88 42.24,20.57 42.24,22.35 41.53,23.05 ; v2(153.17,65.28) v2(153.17,66.42) v2(153.17,67.56) ; v2(41.36,38.51) 41.67,38.81 C517.2 ; 98.02,50.06 97.17,49.21 92.97,49.21 v2(92.59,49.59) ; 98.02,50.06 98.1,50.15 C492.1 R688.2 98.31,54.05 98.31,55.23 97.01,56.53 97.01,57.63 97.63,58.24 R683.2 ; 98.02,50.06 108.44,50.06 v1(109.93,48.58) 110.48,48.02 ; v2(56.4,81.4) 56.41,81.39 58.16,81.39 ; v2(75.6,54.95) 72.99,54.95 v2(72.59,54.55) ; v2(75.6,54.95) 75.51,54.86 75.51,51.8 v2(75.06,51.34) ; v2(75.6,54.95) 75.68,54.86 L64.1 ; U22.5 171.65,50.99 171.21,50.55 v2(168.03,50.55) 167.65,50.93 165.62,50.93 163.46,53.09 v1(163.46,53.15) 163.46,54.48 159.14,58.8 v1(159.14,60.58) v2(159.14,66.04) ; v2(36.49,84.56) 36.41,84.48 C447.1 37.35,82.62 v1(37.35,80.45) 37.35,80.01 38.92,78.44 v3(38.92,77.67) ; 41.53,23.05 v1(41.54,23.05) ; 41.53,23.05 v2(40.9,23.68) ; 58.16,81.39 v1(58.18,81.41) ; 58.16,81.39 v2(65.97,81.39) 66.55,81.39 v2(66.79,81.15) ; R610.1 80.63,90.63 v2(80.86,90.63) 80.86,89.26 79.61,88.01 v2(79.31,88.01) 78.8,88.01 78.34,88.47 Q56.S
  vias: v2(24.52,177.55) v2(27.63,183.71) v2(28.35,184.49) v2(28.39,183.73) v2(38.94,43.94) v2(66.36,83.39) v2(67.09,83.39) v2(67.07,74.04) v2(67.19,75.56) v2(67.57,74.8) v2(67.83,73.41) v2(68.34,74.3) v2(68.84,73.41) v2(123.33,41.02) v2(123.33,40.01) v2(124.22,41.02) v2(153.81,27.69) v2(153.93,35.69) v2(154.06,33.66) v2(154.7,30.61) v2(154.82,35.69) v2(154.82,27.69) v2(155.84,35.69) v2(155.84,33.66)
P3V3_TV: length 36.1
  TOP w0.508: CN5.52 48.33,20.13 47.76,19.56 46.49,19.56 v2(46.43,19.49) ; C302.1 24.79,24.04 ; C302.1 v2(25.66,24) ; C302.1 25.13,23.7 CN5.2
  INT1 w0.508: v2(25.66,24) 26.05,23.62 26.05,22.54 26.81,21.78 29.86,21.78 31.95,19.68 36.21,19.68 38.49,21.97 45.41,21.97 46.43,20.95 v2(46.43,19.49)
  BOTTOM w0.508: v2(25.66,24) 25.79,23.88 C536.1 ; v2(46.43,19.49) 46.62,19.68 C542.1 C543.1
P3V3_TV1: length 4.7
  TOP w0.508: v2(44.29,16.29) 43.8,16.29 43.13,15.62 CN5.39 ; CN5.41 43.93,15.23 v2(44.3,15.59)
  vias: v1(45.1,15.49)
P3V3_WLAN: length 10.3
  TOP w0.102: R256.2 44.92,76.83 43.7,76.83 42.58,75.72 41.84,75.72 v1(41.51,76.05)
  TOP w0.406: CN2.39 44.68,77.63 44.97,77.34 R256.2 R257.2 46.11,77.34 45.48,77.97 CN2.41
P3V3_WW: length 9
  TOP w0.381: CN2.52 50.36,87.46 v2(50.59,87.23)
  TOP w0.508: CN2.2 26.68,87.62 26.48,87.82 v2(25.86,87.82) 24.71,87.82 24.33,88.2 24.33,89.39 C180.1 C177.1 24.32,91.78 R233.1
  BOTTOM w0.381: C450.1 50.43,87.07 v2(50.59,87.23)
  BOTTOM w0.508: v2(50.59,87.23) 51.44,87.23 C449.1
P5V: length 271.8
  TOP w0.254: 89.42,223.65 89.5,223.57 CN1.3 ; CN1.5 89,223.56 88.91,223.65 ; 89.93,223.65 90,223.57 CN1.1 ; 89.27,109.49 88.99,109.78 86.93,109.78 86.34,109.18 PC60.2 85.91,108.61 85.91,108.31 85.66,108.07 85.66,106.86 86.1,106.42 PU7.7 ; PR1.1 106.52,242.14 PR5.1 ; CN1.7 88.5,223.55 88.4,223.65 ; 97.8,109.22 97.8,107.95 98.11,107.64 PU6.7 ; 88.02,223.52 88,223.5 CN1.9
  TOP w0.305: v2(143.64,17.45) U16.11
  TOP w0.381: R475.1 v2(136.92,28.7) ; v2(138.82,27.69) 138.69,27.37 R482.1 ; R483.1 v2(139.84,27.69)
  TOP w0.406: 127.65,232.11 127.65,232.92 v2(128.92,234.19) ; 127.65,232.11 127.65,229.74 125.93,228.03 v2(123.9,228.03) ; 127.65,232.11 PR10.2 ; R230.1 114.51,104.54 v2(114.51,105.03) ; 89.27,109.49 90.53,109.49 91.63,110.59 93.81,110.59 95.64,112.42 96.25,112.42 96.91,111.76 96.91,111.34 ; v2(159.52,75.06) 159.4,75.18 R272.2 ; PR16.2 PR13.2 ; v2(102.25,100.08) 102.12,100.2 R231.1 ; R24.1 v2(133.87,241.3)
  TOP w0.508: v2(147.58,24.64) 147.58,23.62 143.64,19.67 v2(143.64,17.45) ; v2(114.76,217.87) 114.05,217.41 PC34.1 114.06,216.02 D5.A ; v2(91.22,210.19) 92.54,210.19 92.92,209.8 PC37.1 93.85,208.71 D6.A ; v2(114.95,246.57) 114.32,245.95 R16.1 ; v2(96.91,111.32) 96.91,111.34 97.51,110.74 PC63.2 97.8,110.09 97.8,109.22 ; R232.1 v2(115.61,100.08) ; R1.1 v2(187.21,247.52) ; v2(22.21,149.33) 22.19,149.3 22.16,149.3 21.62,148.77 R149.1 ; v2(103.52,240.47) 103.52,241.3 104.35,242.14 PR1.1 ; v2(22.49,18.16) 22.49,18.86 23.19,19.56 26.81,19.56 27.37,19 30.87,19 32.83,17.04 v2(32.83,14.25) ; PR13.2 107.44,230.71 106.82,231.33 106.12,231.33 104.21,233.24 v2(104.21,234.25) ; v2(54.37,30.91) 55,30.28 R459.1 R460.1 R461.1 57.61,30.68 57.61,32.26 57.22,32.64 R442.1 ; v2(129.81,239.84) PR9.1 ; v2(12.15,24.36) 10.65,24.36 10.04,23.75 10.04,18.91 10.64,18.31 20.31,18.31 v2(20.46,18.16) ; D4.A 144.62,221.91 PC31.1 144.63,222.72 144.99,223.08 144.99,224.14 144.33,224.79 144.33,227.33 143.32,228.35 v2(134.63,228.35) ; 37.55,11.38 37.4,11.53 37.4,11.56 v2(35.29,11.56)
  BOTTOM w0.381: v2(12.15,24.36) 12.2,24.41 R742.2
  BOTTOM w0.406: v2(115.61,100.08) 115.1,99.57 107.2,99.57 106.94,99.31 103.01,99.31 v2(102.25,100.08) 101.61,100.08 99.71,101.98 99.71,104.41 100.05,104.75 100.89,104.75 101.88,105.74 101.88,109.21 99.32,111.76 98.5,111.76 98.05,111.32 v2(96.91,111.32) 96.91,111.76 94.75,113.92 94.75,117.73 93.74,118.75 90.94,118.75 88.07,121.62 84.44,121.62 83.32,122.73 83.32,123.9 R573.1 ; v2(114.76,217.87) v1(114.76,220.41) 114.76,223.52 116.34,225.11 116.34,227.27 117.1,228.03 119.64,228.03 120.09,227.58 121.23,227.58 121.61,227.97 121.61,228.85 121.98,229.23 122.7,229.23 v2(123.9,228.03)
  BOTTOM w0.508: v2(22.49,18.16) v2(20.46,18.16) ; v2(134.63,228.35) 132.01,230.96 132.01,239.45 v2(133.87,241.3) ; v2(35.29,11.56) 35.29,11.81 v2(32.83,14.25) ; v2(143.64,17.45) 143.57,17.38 C549.1 143.57,15.45 143.9,15.11 147.71,15.11 148.01,15.42 C548.1 ; v2(54.37,30.91) 55.74,29.54 55.74,28.85 58.28,26.31 v2(58.58,26.31) ; v2(114.51,105.03) 115.07,104.47 115.07,101.85 115.61,101.32 v2(115.61,100.08)
  BOTTOM w1.524: 40.52,10.03 40.9,9.65 44.84,9.65 47.13,11.94 47.13,16.7
  vias: v2(37.98,10.54) v2(38.21,9.68) v2(38.49,11.3) v2(39.38,11.3) v2(47.64,17.78) v2(48.4,16.76) v2(48.4,16) v2(49.29,16.76) v2(49.29,15.94) v2(50.05,17.08) v2(90.43,235.2) v2(90.43,234.06) v2(91.32,235.2) v2(91.32,234.06) v2(92.21,235.2) v2(92.21,234.06) v2(109.8,96.14) v2(110.69,96.14) v2(135.01,23.88) v2(135.01,22.99) v2(135.01,22.1) v2(135.01,21.21) v2(136.15,23.88) v2(136.15,22.99) v2(136.15,22.1) v2(136.15,21.21) v2(141.23,92.58) v2(141.36,91.69) v2(142.25,91.69) v2(154.7,53.72) v2(154.76,54.61) v2(155.59,55.05) v2(155.59,54.17) v2(156.41,54.67) v2(156.41,53.72) v2(162.95,65.66) v2(163.97,65.66) v2(165.11,67.06) v2(165.11,66.04) v2(170.78,47.34) v2(171.82,47.56) v2(171.89,48.8) v2(172.73,49.15) v2(172.65,48.06) v2(172.92,67.06) v2(173.75,67.06) v2(174.45,66.55)
P5V_AUDIO_AVDD: length 21.6
  TOP w0.762: L27.2 20.72,55.69 21.73,55.69 21.88,55.54 C249.1 22.95,55.54 v2(23.54,56.13) 24.27,55.41 v2(24.27,53.09)
  BOTTOM w0.254: v1(21.79,44.58) 21.27,45.1 C515.1 ; C493.1 23.54,57.07 v2(23.54,56.13) U23.38
  BOTTOM w0.279: U23.25 21.14,47.67 20.97,47.5 20.97,46.96 v2(21.58,46.35)
  BOTTOM w0.508: C515.1 21.27,46.05 v2(21.58,46.35)
  BOTTOM w0.762: v2(24.27,53.09) 24.27,50.74 23.51,49.97 23.51,48.13 21.73,46.35 v2(21.58,46.35)
P5V_LDO: length 28.2
  TOP w0.254: 170.19,7.24 170.04,7.39 PU9.7 ; PU9.19 169.54,14.22 169.04,14.72 PU9.20
  TOP w0.508: v2(177.05,11.43) 176.92,11.56 PR60.1 ; PC91.1 168.79,16.12 v2(168.79,15.11) 169.04,14.86 169.04,14.72 ; v2(172.22,8.51) 172.22,7.49 171.09,6.36 C346.1 170.19,7.24
  BOTTOM w0.508: v2(172.22,8.51) 171.97,8.76 171.97,10.24 PR85.1 176.24,10.37 177.05,11.18 v2(177.05,11.43) 175.37,13.11 170.8,13.11 v1(169.68,14.22) v2(168.79,15.11)
P5V_ODD:
  vias: v1(176.67,60.9) v2(175.02,65.34) v2(174.95,64.39) v2(175.4,63.63) v2(175.84,64.96)
P5V_STB_EN: length 5.4
  TOP w0.254: PR60.2 174.89,12.01 v2(174.1,12.01) 172.93,12.01 172.59,11.67 PU9.14
  BOTTOM w0.254: PC152.1 175.12,12.01 v2(174.1,12.01)
P5V_STBY: length 249.2
  TOP w0.203: PU9.10 172.71,9.67 172.86,9.53 172.5,9.17 PU9.9
  TOP w0.254: PU3.15 153.56,224.81 PC33.1
  TOP w0.381: v2(27.63,36.58) 26.93,37.27 23.89,37.27 22.87,38.29 v2(20.97,38.29) ; PC33.1 152.26,223.51 PR19.1 ; 172.86,9.53 173.37,9.53 173.87,9.02 v2(173.87,8.76) ; v2(29.47,37.27) 29.67,37.08 R416.1 ; v2(43.06,50.67) 42.51,51.23 R334.1 ; v2(31.38,206.25) 34.17,203.45 62.24,203.45 62.83,202.87 R775.1 ; v2(64.53,65.34) 64.97,65.79 64.97,68.09 R296.1
  TOP w0.508: Q6.D 6.87,189.66 C82.1 v2(8.14,189.74) ; v2(56.45,66.07) 56.54,65.98 56.54,62.08 54.37,59.91 54.37,59.33 53.9,58.86 45.57,58.86 44.74,58.04 v2(43.37,58.04) 40.4,58.04 37.35,61.09 34.55,61.09 32.4,58.93 17.6,58.93 v2(15.82,57.15) ; v2(91.05,15.75) 91.05,20.87 81.9,30.02 81.9,31.33 77.44,35.79 74.64,35.79 72.45,37.99 CN30.2 ; v2(151.9,222.22) PR19.1
  TOP w0.762: L30.1 20.19,44.83 v2(19.31,44.83)
  BOTTOM w0.381: R752.2 v2(11.87,23.48) ; v2(188.61,36.83) 191.15,36.83 192.92,35.05 192.92,11.35 190.29,8.71 187.45,8.71 v1(187.4,8.76) 187.35,8.71 173.92,8.71 v2(173.87,8.76) ; v2(56.45,66.07) 56.45,66.05 57.54,64.96 64.15,64.96 v2(64.53,65.34) ; v2(27.63,36.58) 28.16,36.58 28.86,37.27 v2(29.47,37.27)
  BOTTOM w0.508: v2(43.37,58.04) 43.37,50.98 v2(43.06,50.67) ; v2(47.51,190.37) 47.76,190.63 R531.1 ; v2(148.6,239.65) 148.6,235.33 145.83,232.56 145.83,226.03 149.64,222.22 v2(151.9,222.22)
  vias: v1(176.22,40.64) v1(176.79,38.42) v2(23.38,180.09) v2(23.38,179.2) v2(23.38,178.31) v2(24.39,179.2) v2(27.82,178.5) v2(27.82,177.74) v2(46.87,189.74) v2(75.32,18.16) v2(76.21,18.16) v2(77.1,18.16) v2(77.99,18.16) v2(78.88,18.16) v2(79.77,18.16) v2(80.66,18.16) v2(81.54,18.16) v2(82.43,18.16) v2(180.6,37.97) v2(180.6,36.96) v2(180.6,36.07) v2(181.62,35.69) v2(182.64,37.97) v2(182.64,36.96) v2(182.64,36.07) v2(185.68,36.83) v2(186.32,35.69) v2(186.57,36.83) v2(187.59,36.83) v2(187.59,35.69)
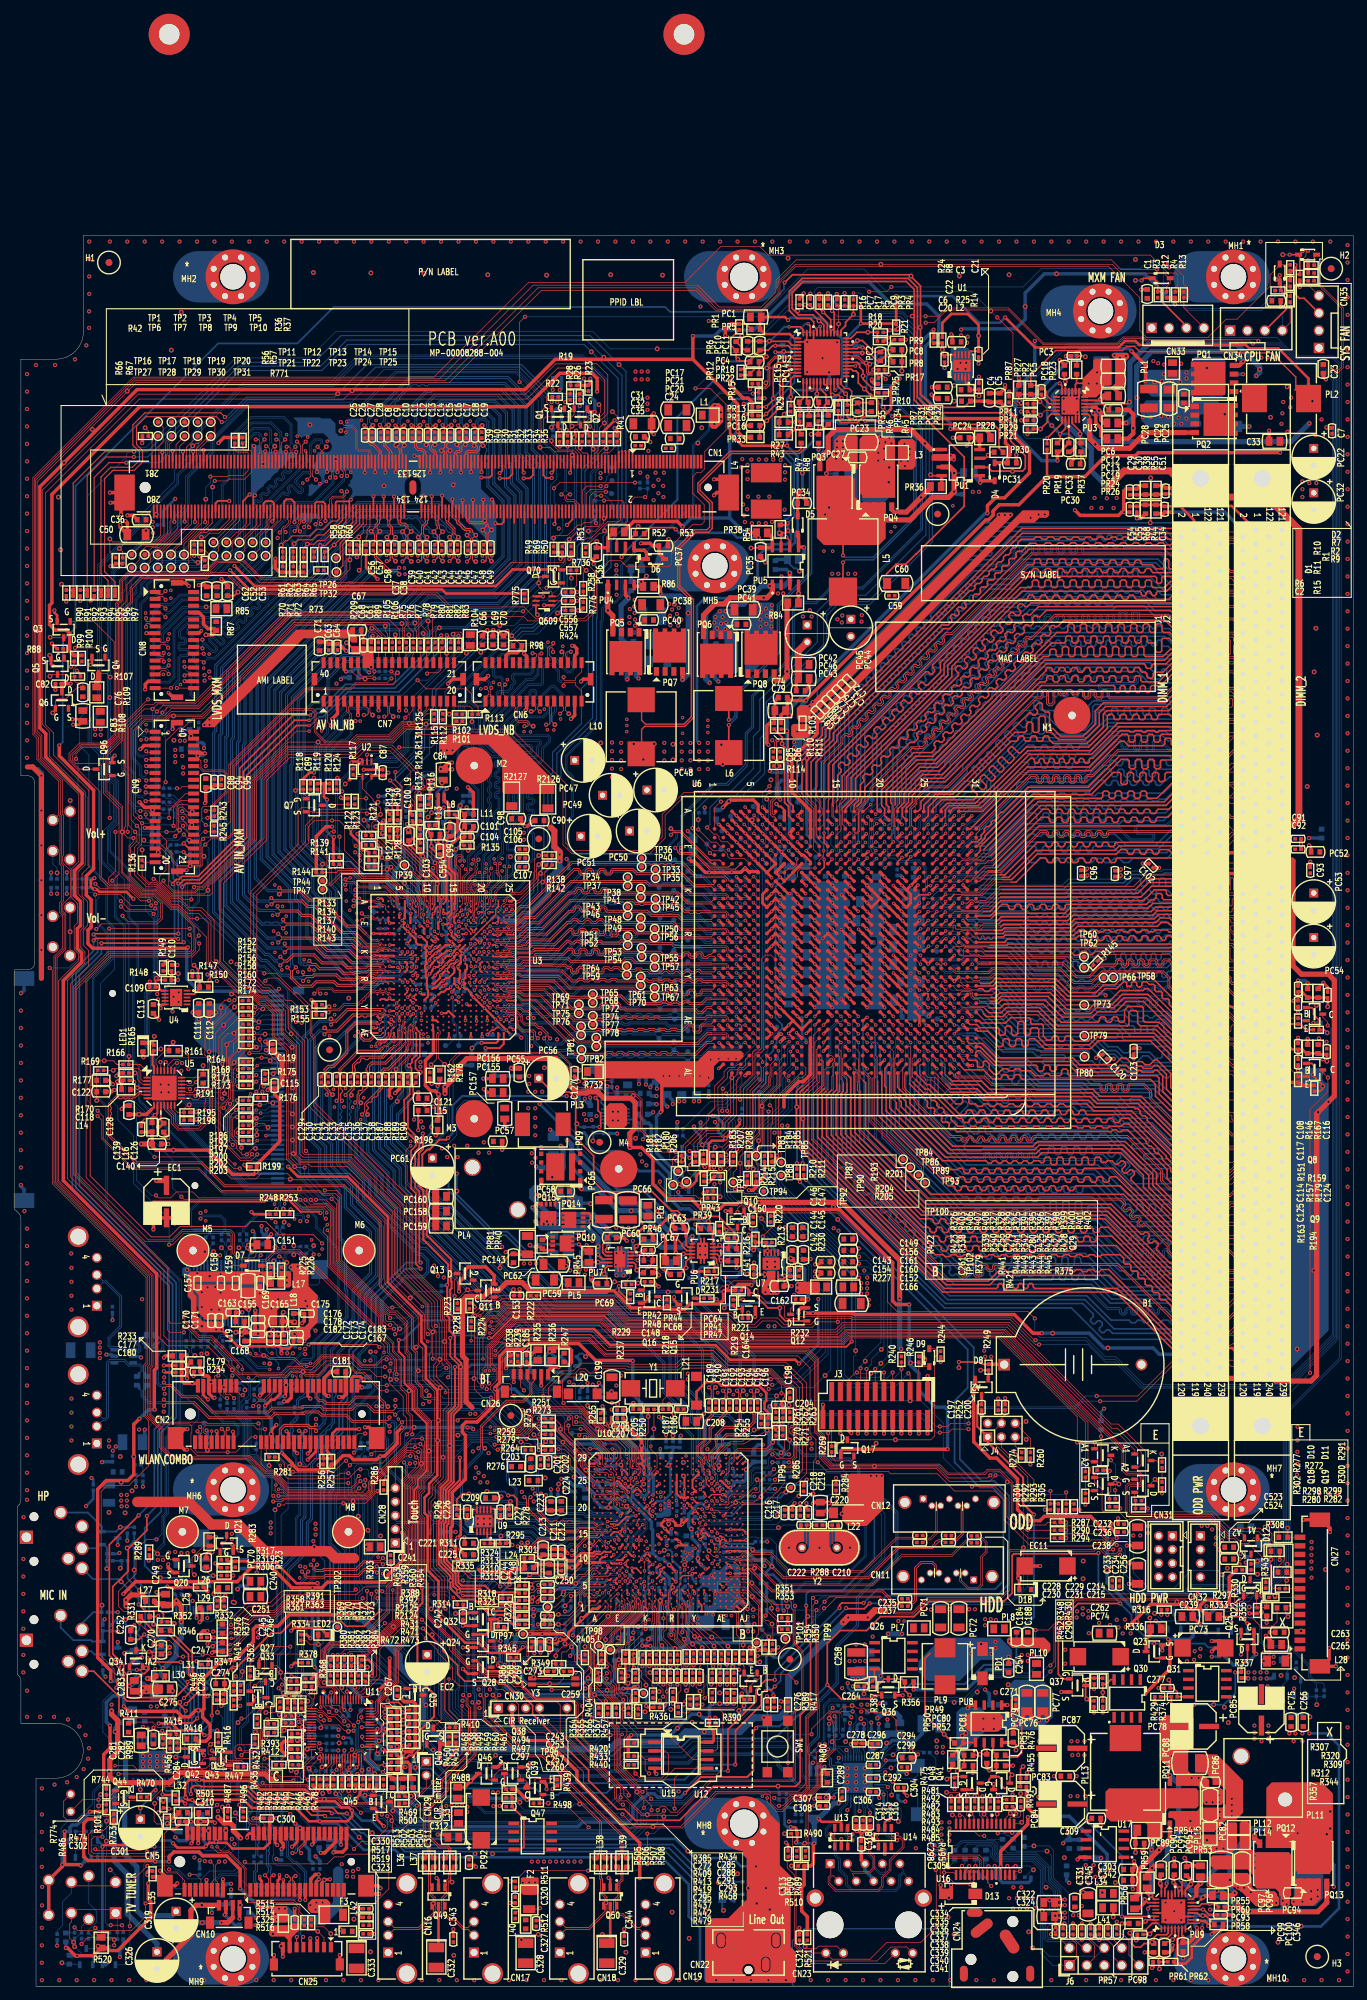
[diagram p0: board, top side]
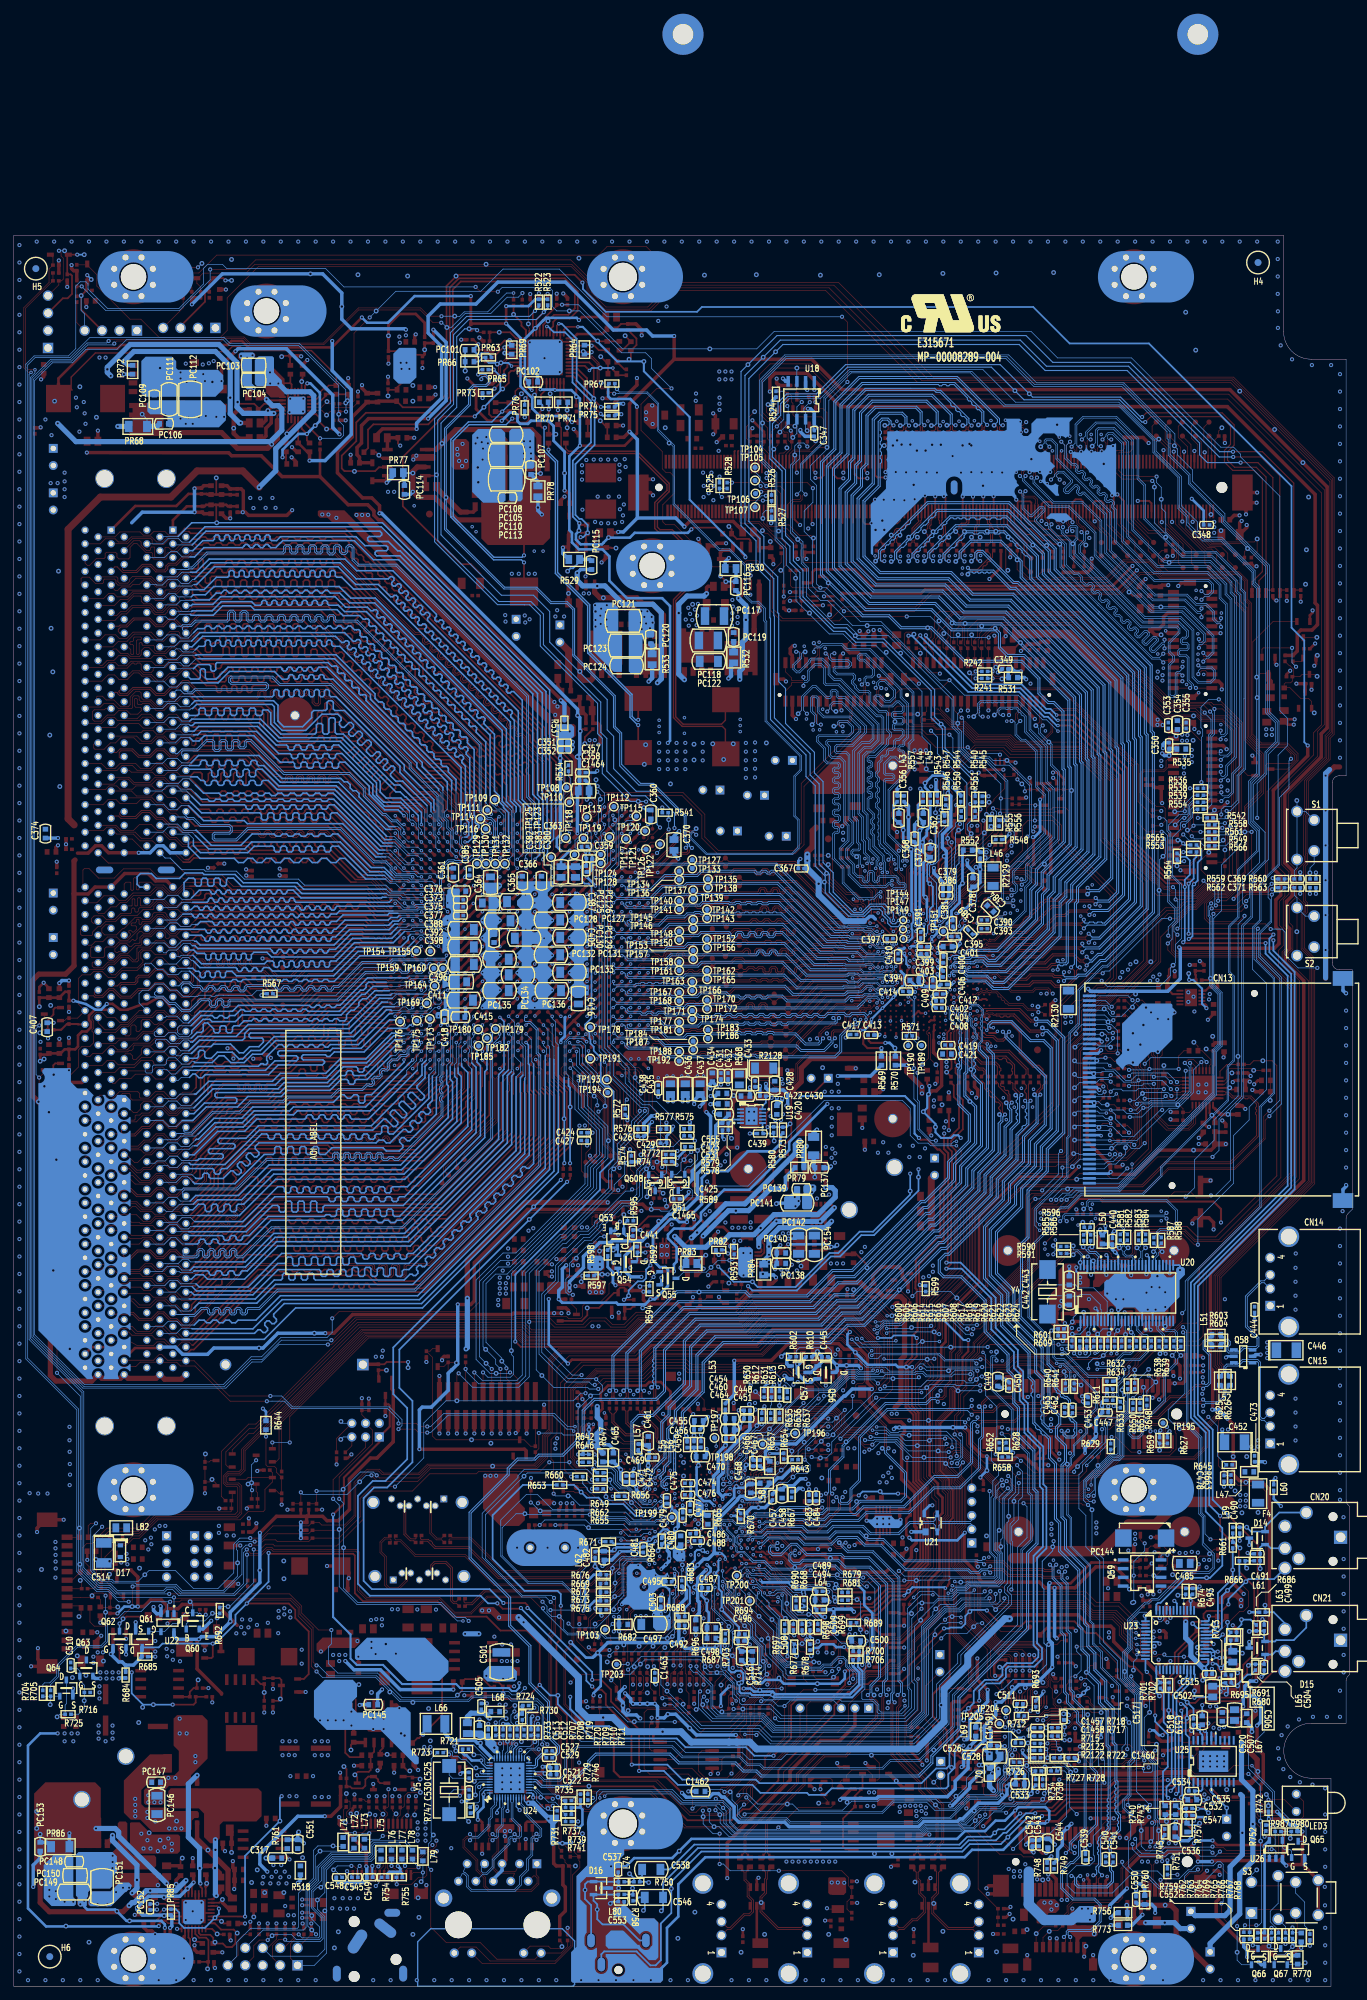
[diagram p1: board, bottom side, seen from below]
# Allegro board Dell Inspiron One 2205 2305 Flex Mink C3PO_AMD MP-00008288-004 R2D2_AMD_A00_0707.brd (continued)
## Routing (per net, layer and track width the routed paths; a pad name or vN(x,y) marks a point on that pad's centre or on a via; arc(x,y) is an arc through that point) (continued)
P5V_TOUCH: length 10.8
  INT1 w0.508: CN28.1 55.44,64.57 57.15,64.57 59.83,67.25 59.83,67.26 61.17,68.61 v2(61.17,70.05)
  BOTTOM w0.381: U21.4 62.37,69.24 61.56,70.05 v2(61.17,70.05)
  vias: v1(53.29,65.6)
P5V_USB: length 75.2
  TOP w0.508: v2(39.7,33.91) 39.32,33.91 38.9,34.33 38.9,35.33 39.25,35.69 R2124.1 R2125.1 ; v2(19.44,14.99) 19.44,12.7 19.82,12.32 19.82,10.03 15,5.21 13.73,5.21 13.37,5.57 R520.1 11.46,4.45 v2(9.09,4.45) 8.84,4.45 7.69,5.59 v2(7.44,5.59) ; v2(74.01,15.07) 74.01,14.26 74.37,13.9 F2.1 ; v2(75.83,15.11) 75.83,14.35 75.38,13.9 F2.1 ; F2.1 v2(74.94,15.11)
  TOP w0.762: L27.1 19.05,56.46 18.51,57 16.94,57 v2(16.2,56.26) v2(16.2,55.37)
  TOP w1.524: 49.41,62.36 46.68,62.36 45.67,63.37 36.46,63.37 32.57,67.26 28.64,67.26 25.35,70.55 17.85,70.55
  BOTTOM w0.381: v2(47.13,34.35) R2123.1 ; R2122.1 47.38,33.27 48.02,33.91 v2(48.02,34.35)
  BOTTOM w0.508: R770.2 8.02,4.45 v2(9.09,4.45) ; v2(7.44,5.59) R767.1
  vias: v1(13.73,69.02) v1(16.08,68.96) v2(15.5,71.56) v2(15.5,70.74) v2(15.57,69.91) v2(16.33,71.56) v2(16.33,70.74) v2(16.33,69.91) v2(43.06,11.81) v2(43.83,11.18) v2(43.95,12.19) v2(44.84,12.19) v2(62.11,26.04) v2(62.11,25.15) v2(62.75,25.53) v2(62.88,26.29) v2(63.51,25.53) v2(63.49,24.79) v2(63.64,26.29) v2(64.4,26.29) v2(65.16,26.29) v2(65.92,26.16) v2(65.92,25.4)
P5V_USB5V1: length 5.7
  TOP w0.381: 86.24,6.21 86.75,6.72 Q50.5
  vias: v1(76.27,7.56) v1(89.04,4.95)
P5V_USB5V3: length 6.3
  TOP w0.381: Q49.5 61.73,5.89 61.42,5.57
  vias: v1(51.83,5.02) v1(63.96,4.51)
P5V_USB_CAM:
  vias: v1(37.6,7.62)
P5V_USB_CTL: length 2.8
  TOP w0.102: v1(77.73,26.67) R498.2 76.44,27.02 76.96,27.55 Q39.B
P5V_USB_CTL1: length 18.4
  TOP w0.102: R439.2 78.85,30.3 76.02,30.3 75.77,30.05 75.77,29.08 75.56,28.88 Q39.C 74.6,29.81 74.37,30.04 73.71,30.04 Q38.G 73.71,30.7 72.91,31.5 70.62,31.5 69.9,30.77 Q46.G 69.16,30.04 68.91,30.29 68.91,32.51 v1(70.05,33.66)
P12V: length 587.2
  TOP w0.508: v2(106.94,211.84) 107.05,211.73 108.04,211.73 PR38.2 ; v2(136.31,226.85) 141.29,226.85 142.15,225.99 PR28.2 ; 27.37,40.2 27.57,40.4 27.57,44.89 30.14,47.47 32,47.47 34.76,50.22 34.76,52.02 35.19,52.45 38.29,52.45 39.94,54.1 49.35,54.1 v2(49.92,53.53) ; 27.37,40.2 27.37,39.19 28.46,38.1 28.46,36.32 27.82,35.69 26.69,35.69 R418.1 ; 27.37,40.2 26.36,40.2 25.41,39.24 24.39,39.24 23.58,40.06 16.6,40.06 v2(15.89,40.77) ; 98.79,236.98 105.29,230.48 v2(105.29,226.44) 106.11,225.62 PR33.1 ; 98.79,236.98 v2(98.79,240.37) ; 98.79,236.98 78.75,236.98 74.33,232.57 17.82,232.57 3.66,218.41 3.66,183.29 4.52,182.43 4.52,179.05 9.82,173.76 9.82,163.61 8.75,162.54 8.75,158.85 9.58,158.02 9.58,154.51 9.11,154.05 9.11,151.15 9.74,150.52 9.74,149.16 7.07,146.48 7.07,117.37 20.66,103.78 20.66,90.06 20.33,89.73 20.33,84.07 v2(20.39,84.01) ; v2(18.17,82.68) 17.35,81.85 17.35,74.55 16.46,73.66 13.35,73.66 12.08,72.39 12.08,47.88 13.98,45.97 v2(13.98,44.45) ; v2(13.88,37.97) 13.88,34.67 12.96,33.76 12.96,29.72 13.35,29.34 R744.1 ; v2(97.29,212.6) 96.52,213.37 90.18,213.37 89.57,212.77 89.57,212.77 88.81,212 R52.1
  TOP w1.016: v2(120.72,53.02) v2(121.42,53.72) v2(124.28,53.72) 125.3,54.74 v2(125.77,54.74) v2(126.76,54.74)
  BOTTOM w0.508: 15.64,42.28 15.64,43.71 14.9,44.45 v2(13.98,44.45) ; 15.64,42.28 15.89,42.04 v2(15.89,40.77) ; 15.64,42.28 14.29,42.28 13.35,41.34 13.35,38.5 v2(13.88,37.97) ; 104.15,213.87 106.18,211.84 v2(106.94,211.84) ; 104.15,213.87 98.56,213.87 v2(97.29,212.6) ; 104.15,213.87 104.15,225.3 v2(105.29,226.44) ; v2(20.39,84.01) 20.36,83.97 19.47,83.97 v2(18.17,82.68) ; v2(98.79,240.37) 101.93,240.37 102.8,241.25 107.66,241.25 114.63,248.22 124.47,248.22 127.66,245.03 132.87,245.03 134.63,243.27 134.63,240.82 132.66,238.85 132.66,231.33 136.31,227.69 v2(136.31,226.85)
  BOTTOM w1.016: v2(121.42,53.72) v2(120.72,53.02) 112.72,45.02 112.72,40.45 111.42,39.14 v1(109.13,39.14) 107.71,39.14 105.65,37.08 v1(100.47,37.08) 97.8,37.08 96.29,35.57 90.81,35.57 90.8,35.57 89.69,35.57 89.68,35.57 87.78,35.57 86.78,34.57 63.42,34.57 59.46,38.53 59.46,43.31 56.02,46.75 56.02,48.13 50.61,53.54 v2(49.92,53.53)
  vias: v2(121.61,47.37) v2(122.38,47.37) v2(122.57,49.78) v2(123.14,47.37) v2(123.84,49.78) v2(123.9,47.37) v2(124.98,50.93) v2(141.36,53.47) v2(141.36,52.58) v2(142.19,53.47) v2(142.95,53.34)
P12V_HDD:
  vias: v1(155.64,59.36) v1(155.66,61.95)
P12V_STBY: length 149.7
  TOP w0.762: v2(14.11,40.13) 14.11,39.62 15,38.73 15,34.16 13.85,33.02 13.85,30.54 14.74,29.65 22.55,29.65 24.01,31.11 28.33,31.11 28.52,30.92 36.46,30.92 37.22,30.16 v2(37.92,30.16)
  INT1 w0.762: v2(37.92,30.16) 38.61,30.85 38.61,35.07 39.36,35.81 40.55,35.81 41.45,34.91 42.52,34.91 43.23,35.62 43.23,36.81 43.35,36.93 43.35,41.17 44.08,41.9 44.08,43.31 44.79,44.01 49.8,44.01 50.05,44.26 53.8,44.26 54.49,43.56 60.91,43.56 62.94,45.59 64.65,45.59 64.91,45.34 66.69,45.34 67.61,44.42 71.27,44.42 72.61,43.08 75.96,43.08 77.27,44.39 81.8,44.39 83.51,46.1 83.51,47.18 84.31,47.98 88.87,47.98 89.29,47.56 102.53,47.56 102.78,47.82 106.12,47.82 107.14,46.8 110.92,46.8 112.91,48.79 124.7,48.79 v2(127.24,51.33) v2(129.25,51.33)
  BOTTOM w0.762: v2(129.25,51.33) v2(127.24,51.33)
  vias: v2(14.11,41.02)
P12VFAN_SON_N: length 10.9
  TOP w0.254: Q48.D 141.64,29.59 141.91,29.85 141.91,30.11 142.34,30.54 Q41.G 143.36,30.54 143.77,30.12 143.77,29.21 144.16,28.83 145.73,28.83 145.99,29.08 R491.2 R455.1 146.52,31.63 v1(146.9,32)
P19V_CONVERTER:
  vias: v1(181.94,47.37) v1(185.75,48.13) v2(182,48.64) v2(182.76,48.64) v2(183.4,48.01) v2(183.4,47.12)
P19V_FILT:
  vias: v1(96.1,201.29) v1(110.25,200.25) v2(95.32,201.36) v2(95.45,199.64) v2(95.51,198.25) v2(95.77,200.53) v2(96.15,199.01) v2(96.47,199.9) v2(96.72,200.79) v2(96.66,198.18) v2(97.1,199.07) v2(106.12,215.84) v2(106.25,214.25) v2(106.37,213.3) v2(106.69,215.14) v2(106.82,216.98) v2(107.39,213.11) v2(108.34,216.98) v2(108.41,213.11) v2(108.6,201.17) v2(108.63,198.02) v2(108.72,200.15) v2(108.66,199.07) v2(109.42,213.11) v2(109.42,200.66) v2(109.55,199.64) v2(109.48,198.44) v2(109.93,216.98) v2(110.25,199.01) v2(110.25,198.06) v2(110.31,213.3) v2(110.31,201.17) v2(112.15,215.07)
P19V_FILT_NB:
  vias: v1(127.33,219.07) v1(127.39,221.23) v2(125.8,223.35) v2(125.78,222.23) v2(125.93,224.75) v2(126.15,225.66) v2(126.64,223.98) v2(126.69,222.38) v2(126.82,224.91) v2(127.45,225.56) v2(127.71,224.73)
P19V_INVERTER:
  vias: v1(184.48,45.28) v1(186.45,44.96)
P19V_MXM:
  vias: v1(99.52,224.79) v1(100.09,227.01)
P19V_SYS: length 315.8
  TOP w0.254: R348.1 v2(157.24,43.31)
  TOP w0.381: v2(44.08,58.75) 44.03,58.7 41.03,58.7 38.01,61.72 33.97,61.72 33.8,61.9 R323.1
  TOP w0.406: R323.1 31.13,61.9 R317.1
  TOP w0.508: v2(149.68,24.77) 148.79,24.77 147.39,26.16 147.39,27.8 147.38,27.81 R491.1 ; v2(179.72,44.83) 179.64,44.91 R337.1 ; R100.1 R99.1 8.01,194.49 8.01,197.04 7.5,197.55 5.85,197.55 5.07,198.34 5.07,201.14 5.41,201.49 5.41,217.3 18.2,230.09 74.55,230.09 79.41,234.95 84.08,234.95 84.85,234.19 v2(84.85,232.28) ; R356.1 v2(130.96,43.22) ; v2(74.61,27.15) 73.06,28.7 R494.1
  INT1 w0.508: v2(130.96,43.22) 123.74,43.22 122.25,41.72 115.14,41.72 112.98,39.56 109.99,39.56 109.68,39.88 93.42,39.88 92.85,39.31 86.5,39.31 85.8,40.01 83.45,40.01 82.18,38.73 63.13,38.73 59.45,42.42 53.99,42.42 52.97,41.4 v2(51.95,41.4)
  BOTTOM w0.508: v2(74.61,27.15) 74.41,27.36 69.29,27.36 69.03,27.61 58.98,27.61 57.85,28.75 57.85,29.87 55.97,31.75 55.97,33.45 53.59,35.83 53.59,37.86 51.94,39.51 51.94,41.39 v2(51.95,41.4) 51.09,41.4 48.55,43.94 46.18,43.94 43.7,46.42 v2(43.7,46.48) 43.7,49.97 44.21,50.48 44.21,58.62 v2(44.08,58.75) ; v2(182.38,44.83) 183.12,44.83 Q63.S ; v2(179.72,44.83) 179.64,44.91 R337.1 ; v2(146.7,47.37) 145.43,46.1 141.59,46.1 138.71,43.22 v2(130.96,43.22) ; v2(158.06,16.7) 159.14,17.78 159.14,19.24 153.62,24.77 v2(149.68,24.77)
  vias: v1(155.65,13.65) v1(158.44,13.65) v1(159.52,16.95) v1(173.68,21.27) v1(175.27,22.35) v2(82.05,103.63) v2(82.31,104.39) v2(83.07,103.63) v2(83.2,104.39) v2(91.32,111.25) v2(93.61,112.9) v2(94.24,112.39) v2(101.92,227.56) v2(101.99,230.25) v2(102.87,229.26) v2(102.9,228.3) v2(105.87,221.3) v2(105.99,222.44) v2(106.75,221.62) v2(106.75,220.66) v2(106.75,219.52) v2(107.33,222.38) v2(108.41,222.38) v2(109.48,222.38) v2(110.5,222.38) v2(111.58,222.31) v2(112.22,221.55) v2(112.22,220.54) v2(112.22,219.46) v2(129.11,222.19) v2(129.61,224.66) v2(129.68,221.42) v2(130.12,222.19) v2(130.34,223.09) v2(130.39,223.93) v2(146.7,48.26) v2(147.58,48.26) v2(147.58,47.37) v2(148.47,48.26) v2(154.89,15.94) v2(155.27,14.99) v2(155.52,16.7) v2(156.03,17.65) v2(156.16,15.88) v2(156.41,14.99) v2(156.79,16.7) v2(156.86,215.34) v2(157.17,17.65) v2(157.31,216.79) v2(157.43,15.94) v2(157.62,14.99) v2(158.3,215.34) v2(158.63,15.94) v2(158.76,14.99) v2(159.09,216.74) v2(160.08,215.32) v2(160.54,216.79) v2(165.87,236.73) v2(166.57,236.41) v2(167.46,236.22) v2(169.94,236.35) v2(171.97,20.76) v2(171.97,19.81) v2(172.48,21.53) v2(173.05,20.26) v2(174,19.68) v2(175.08,20.07) v2(175.52,21.27) v2(176.1,20.07) v2(176.41,22.23) v2(179.72,45.72) v2(180.6,45.72) v2(180.6,44.83) v2(181.49,45.72) v2(181.49,44.83) v2(182.38,45.72) v2(186.83,76.07) v2(186.8,74.52) v2(186.88,81.48) v2(186.88,79.53) v2(186.85,77.85) v2(186.85,73) v2(190.08,71.77) v2(191.44,71.77) v2(192.68,71.83)
P19V_SYS_FILE: length 26.6
  TOP w0.254: PU9.6 169.54,7.11 169.3,6.87 169.3,4.02 PR62.2
  TOP w0.381: v2(172.98,8.51) 172.98,7.24 171.46,5.71 171.46,4.19 170.57,3.3 169.1,3.3 PR62.2
  BOTTOM w0.381: 184.67,11.75 184.67,11.56 184.29,11.18 180.22,11.18 v1(179.97,10.92) 178.57,9.53 v1(178.13,9.53) 173.49,9.53 172.98,9.02 v2(172.98,8.51)
  vias: v2(180.59,19.01) v2(180.59,18.1) v2(180.62,17.21) v2(184.73,12.45) v2(185.3,11.94)
VBAT: length 2.6
  TOP w0.102: 140.68,89.74 140.68,89.74 v1(140.7,89.74)
  TOP w0.254: 140.68,89.74 R249.1
  TOP w0.305: R249.1 141.87,88.94 141.8,88.87 D8.A1
VBAT_IN: length 12.6
  TOP w0.381: C269.1 78.1,50.21 78.36,49.96 78.95,49.96 v1(79.49,50.5)
  TOP w0.406: v1(79.49,50.5) 80.27,50.5 80.66,50.88 80.66,51.5 81.43,52.27 81.47,52.27 84.19,54.99 84.91,54.99 U10.B1 ; C269.1 C268.1 R386.1
VDD0_NB_CS: length 7.7
  TOP w0.254: PR32.1 124.79,230.66 PC26.1 122.49,230.34 PR31.1 121.27,230.36 121.27,231.74 v1(121.04,231.97) 120.99,231.97 119.88,233.08 PU2.23
VDD0_NB_ENABLE: length 61.8
  TOP w0.254: PR30.1 143.38,224.05 143.38,226.73 142.61,227.51 134.61,227.51 131.04,231.08 131.04,247.15 129.88,248.32 114.86,248.32 113.25,246.71 113.25,244.41 114.2,243.46 116.28,243.46 v1(117.17,242.57) 117.28,242.57 117.87,241.98 PU2.42
VDD0_NB_PWM: length 74.6
  TOP w0.254: PU1.2 140.61,221.25 141.8,221.25 142.34,220.7 145.32,220.7 v1(145.36,220.66) 145.4,220.7 146.82,220.7 147.22,221.1 147.22,222.94 145.1,225.06 145.1,227.79 143.69,229.19 133.78,229.19 131.49,231.48 131.49,247.43 130.16,248.77 114.71,248.77 112.84,246.9 112.84,244.07 113.99,242.93 115.91,242.93 116.41,242.43 116.41,241.79 116.88,241.32 PU2.44
VDD18: length 14.2
  TOP w0.254: v3(59.04,154.46) 59.29,154.46 U3.F9 59.58,153.95 59.58,153.37 U3.G9
  BOTTOM w0.381: v3(59.04,154.46) 59.04,154.84 58.64,155.24 C381.1
  BOTTOM w0.4: R552.2 56.78,165.36 v1(56.78,160.66) 57.21,160.22 57.21,157.81 58.38,156.64 58.38,155.91 58.18,155.7 C381.1
VDD18_MEM: length 15.8
  TOP w0.3: U3.AE11 60.95,139.36 60.95,139.95 U3.AD11
  TOP w0.305: 61,137.79 61,139.1 U3.AE11
  TOP w0.508: R196.2 61.73,126.25 v1(61.73,129.92) 61.22,130.43 60.59,130.43 59.83,131.19 59.83,134.85 61,136.02 61,137.79
VDD_PCIE: length 11.6
  TOP w0.3: v3(56.44,154.46) U3.F6 v3(57.24,153.66) U3.G7 U3.H8 58.44,152.06 58.79,151.71 59.19,151.71 U3.J9
  TOP w0.305: U3.V9 59.35,144.46 v3(59.07,144.74) ; v3(56.44,154.46) U3.E6 56.84,154.86 v3(56.45,155.24) 56.84,155.64 U3.D6 U3.C6 U3.B6 U3.A6
  BOTTOM w0.3: v3(56.44,154.46) v3(57.24,153.66)
  BOTTOM w0.305: C389.1 55.94,153.96 v3(56.44,154.46) ; C402.1 59.28,144.53 v3(59.07,144.74)
  vias: v1(48.65,143.92) v3(57.92,145.14) v3(58.56,145.16)
VDDA18HTPLL: length 22.9
  TOP w0.3: U3.H17 64.98,152.24 64.75,152.24 v3(64.73,152.22)
  BOTTOM w0.3: v3(64.73,152.22) 64.6,152.22 64.09,152.73 64.09,153.86 64.19,153.96 64.19,154.74 63.95,154.98 63.95,156.37 64.2,156.62
  BOTTOM w0.381: C356.1 66.22,169.53 66.81,170.13 66.81,172.04 L43.2
  BOTTOM w0.4: 64.2,156.62 64.2,165.53 65.42,166.75 v1(65.42,168.4) 65.42,168.9 C356.1
VDDA18PCIE: length 11.6
  TOP w0.3: 60.19,145.11 60.19,144.16 U3.W9
  TOP w0.305: 60.19,145.11 U3.U10 U3.T10 U3.R10 59.88,147.02 59.88,147.8 U3.P10 59.79,148.21 59.79,148.71 U3.M10 59.89,149.11 59.89,149.91 U3.L10 59.89,150.21 59.89,150.7 U3.K10 59.78,151.12 59.78,151.39 U3.J10 60.04,152.11 U3.H9 59.27,152.88 v3(59.02,152.88)
  BOTTOM w0.305: v3(59.02,152.88) 58.99,152.91 C395.1
  vias: v1(59.76,128.4) v2(60.95,129.03) v2(60.97,128.14) v3(59.24,141.76) v3(59.24,140.69) v3(59.51,138.68) v3(59.51,138.05)
VDDA18PCIEPLL: length 12.4
  TOP w0.3: U3.D7 57.64,154.86 U3.E7
  TOP w0.305: 57.64,156.2 U3.D7 U3.E7
  TOP w0.381: 57.64,156.2 v3(57.72,156.28)
  BOTTOM w0.4: C378.1 55.61,159.78 55.61,157.66 56.25,157.02 56.68,157.02 57.42,156.28 v3(57.72,156.28)
  BOTTOM w0.508: L46.2 54.21,162.7 v1(54.23,162.69) 54.23,160.79 54.89,160.14 C378.1
VDDAN_1.1V_USB_S: length 12.9
  TOP w0.254: 84.34,62.61 84.69,62.96 85.02,62.96 85.07,62.91 85.41,62.91 85.65,63.15 85.65,63.16 85.81,63.32 U10.C11 86.11,63.25 86.77,63.25 U10.D11
  TOP w0.305: 84.34,62.61 82.85,62.61 82.19,61.96
  TOP w0.508: L24.2 76.1,61.48 C244.1 77.96,61.39 C248.1 80.23,61.39 80.61,61.01 v1(81.21,61.01) 81.6,61.01 82.19,61.6 82.19,61.96
VDDAN_P1V1_CLK: length 28.4
  TOP w0.305: 91.24,76.12 U10.K28 91.67,75.69 v3(91.67,75.13) 91.67,74.55 U10.K26 ; 91.24,76.12 U10.K29 91.34,76.82 91.34,77.32 ; 91.24,76.12 U10.J28
  TOP w0.508: 91.34,77.32 v2(91.34,77.58) 91.34,79.41 89.58,81.17 88.85,81.17 88.5,81.51 87.54,81.51 86.94,82.11 86.94,82.87
  BOTTOM w0.381: 91.73,71.3 91.4,71.63 v3(90.66,71.63)
  BOTTOM w0.5: v3(91.73,70.95) 91.73,71.3 92.37,71.94 92.37,73.48
  BOTTOM w0.508: 92.37,73.48 92.37,74.07 91.67,74.77 v3(91.67,75.13) 91.67,77.25 v2(91.34,77.58) 87.77,81.15 87.77,81.34 87.76,81.35 87.76,82.69 C207.1 C206.1
  vias: v1(87.83,84.77) v2(87.01,84.96) v2(86.96,84)
VDDAN_P1V1_PCIE: length 25.8
  TOP w0.3: v3(97.58,70.87) 97.92,71.22 U10.W22 ; U10.V22 97.23,71.22 97.56,70.89
  TOP w0.305: v3(97.58,70.87) 97.56,70.89 v3(97.56,72.37) 97.56,74.36 ; U10.V22 96.44,71.74 U10.U26
  TOP w0.381: R255.1 109.74,83.59 109.23,84.1 109.23,85.03 109.48,85.28 109.48,86.44 108.42,87.5 102.93,87.5 102.42,88.01 100.72,88.01 99.32,86.61 L21.2
  vias: v1(97.42,76.3) v1(97.42,74.32) v3(97.8,77.24)
VDDAN_P1V1_SATA: length 0.8
  BOTTOM w0.381: R671.1 v2(109.61,64.77)
  vias: v1(111.26,66.8)
VDDAN_P3V3_HWM_S: length 14.2
  TOP w0.254: U10.D6 86.69,59.16 v4(86.25,59.16)
  BOTTOM w0.381: v1(76.85,53.78) 77.23,53.78 78.04,54.59 L64.2 78.25,55.08 C494.1 78.25,56.89 78.04,57.1 C489.1
  BOTTOM w0.406: v4(86.25,59.16) 85.91,58.83 82.13,58.83 81.11,57.81 78.31,57.81 C489.1
VDDAN_P3V3_USB_S: length 3.6
  BOTTOM w0.381: C483.1 v2(79.13,72.39) ; C484.1 v2(78.12,72.39)
  BOTTOM w0.508: R667.1 81.12,72.06 80.66,72.52 80.15,72.52 v2(80.02,72.39)
  vias: v1(77.28,74.04) v1(79.23,73.15)
VDDCR_P1V1: length 11.3
  TOP w0.102: 94.2,65.12 U10.N13
  TOP w0.305: U10.W12 97.36,64.22 v3(96.78,64.8) ; v3(96.34,63.98) 96.58,64.22 U10.V12
  TOP w0.381: U10.U13 96.47,65.12 v3(96.78,64.8) ; 94.24,67.12 U10.N17
  TOP w0.4: U10.R15 94.74,66.62 v3(94.74,66.67) 94.68,66.67 94.24,67.12 94.24,67.44 v3(94.76,67.97) 94.79,67.94 v3(95.76,67.94) 96.24,67.47 U10.U17 97.06,67.12 v3(97.24,67.29) ; U10.V18 97.14,67.39 v3(97.24,67.29) ; v3(97.24,67.29) 97.94,67.99 U10.W18 ; 94.2,65.12 93.71,65.61 93.71,65.74 v3(93.69,65.76)
  vias: v1(95.26,67.37)
VDDCR_P1V1_GBE_S: length 18.3
  TOP w0.254: U10.L7 92.92,60.22 v3(92.95,60.19) ; U10.L9 92.15,62.2 v3(92.11,62.2)
  BOTTOM w0.305: 92.82,60.19 92.75,60.19 92.34,60.6 92.34,61.98 v3(92.11,62.2) ; 92.82,60.19 92.29,59.66 92.29,57.89 91.86,57.45 v1(91.86,54.89) 91.86,54.83 89.34,52.31 R694.2 ; 92.82,60.19 v3(92.95,60.19)
  BOTTOM w0.381: R714.1 C516.1 89.47,49.29 C496.1 89.47,51.18 R694.2
VDDCR_P1V1_S: length 6.5
  TOP w0.254: U10.G26 89.24,74.73 88.78,75.18 88.48,75.18 v3(88.46,75.17) 88.44,75.14 U10.F26
  BOTTOM w0.406: v3(88.46,75.17) 88.46,75.78 v1(88.3,75.95) 87.79,75.95 87.62,75.77 C466.1 C467.1 85.65,75.17 R657.1
VDDCR_P1V1_USB_S: length 11.2
  TOP w0.254: 84.18,63.06 U10.A11 U10.B11
  TOP w0.381: 81.4,62.01 82.45,63.06 84.18,63.06
  TOP w0.508: 81.4,62.01 80.5,62.01 79.69,62.82 C212.1 C211.1 77.01,62.82 C213.1 76.48,62.36 v1(76.02,62.36) R301.2
VDDG_NB: length 6.1
  TOP w0.102: v2(47.7,174.05) 47.43,174.32 R124.1 R120.2 ; v2(48.78,175.79) 48.78,177.16 48.95,177.34 R117.1
  BOTTOM w0.102: v2(47.7,174.05) 47.7,174.69 v1(48.14,175.13) 48.78,175.77 v2(48.78,175.79)
VDDHTRX: length 7.3
  TOP w0.203: U3.A23 U3.B23 70.06,156.88 70.06,156.08 U3.D22 U3.E21 U3.F20 U3.G19 U3.H18
  vias: v1(72.21,164.53)
VDDHTTX: length 26.9
  TOP w0.3: U3.P17 U3.R17 v3(65.24,146.46) 65.52,146.18 65.52,146.18 U3.T17 65.5,145.92 65.5,145.91 v3(65.24,145.65) 65.5,145.39 65.5,145.39 U3.U17 65.89,145.26 66.44,144.7 U3.V18 ; U3.P17 65.89,148.21 ; U3.P17 65.89,148.21 ; 65.89,148.21 65.89,148.71 U3.M17 ; U3.AB22 v3(70.04,140.86) U3.AC23 U3.AD24 v3(71.64,139.26) U3.AE25
  TOP w0.305: U3.AB22 U3.AA21 68.84,142.06 v3(68.44,142.47) 68.43,142.47 U3.Y20 U3.W19 v3(66.84,144.06) U3.V18
  TOP w0.508: v2(82.31,133.41) 82.29,133.4 C127.1
  BOTTOM w0.305: v3(71.64,139.26) 71.03,139.26 70.14,140.15 70.04,140.25 v3(70.04,140.86) 70.04,140.89 68.29,142.65 68.23,142.65 67.06,143.81 67.06,143.83 v3(66.84,144.06)
  BOTTOM w0.4: 65.79,147.87 65.24,147.32 v3(65.24,146.46) 65.24,145.65 v3(65.24,145.65) 65.26,145.63 65.55,145.63 66.57,144.61 66.57,144.33 v3(66.84,144.06)
  vias: v1(77.16,133.79)
VDDIO_AZ_S: length 12.7
  TOP w0.254: v3(93.99,61.39) 93.62,61.02 U10.M8
  BOTTOM w0.381: v3(93.99,61.39) 93.48,60.88 93.48,60.43 94.78,59.13 94.78,58.14 C487.1 94.8,57.92 94.8,56.92 v1(94.04,56.16) 94.04,56.16 94.04,54.72 93.74,54.42 93.74,53.1 94,52.83 C498.1 R687.1
VDDIO_GBE_S: length 10.7
  TOP w0.254: U10.P8 94.5,61.02 v3(94.14,60.66) 94.04,60.55 94.04,59.94 U10.M6
  BOTTOM w0.508: R696.1 95.64,53.85 95.13,54.36 95.13,55.93 95.36,56.16 95.36,57.63 v1(95.83,58.1) 95.36,58.57 95.36,59.44 94.15,60.66 v3(94.14,60.66)
VDDIO_P1V8_FC: length 14
  TOP w0.203: U10.AC22 101.54,71.62 103.14,71.62
  TOP w0.254: 103.14,71.62 v3(103.16,71.6) 103.35,71.6 U10.AF22
  TOP w0.305: U10.AE25 102.94,73.62 U10.AF24 103.91,72.64 v3(104.28,72.64)
  BOTTOM w0.508: v3(103.16,71.6) 103.61,71.6 103.89,71.89 104.28,72.27 v3(104.28,72.64) 104.79,73.15 C472.1 C471.1 106.2,73.48 106.56,73.85 v1(106.56,75.25) 106.56,75.3 C465.1 R647.2
VDDIO_P3V3_GBE_S: length 12.5
  BOTTOM w0.305: R688.1 97.24,55.05 96.51,55.79 96.51,58.1 96.98,58.57 96.98,60.9 95.77,62.1 95.77,63.25 95.45,63.56 94.69,63.56 v1(94.63,63.5) 94.34,63.21 v3(93.93,63.21)
VDDIO_P3V3_PCIGP: length 3
  BOTTOM w0.508: C455.1 95.88,82.32 C456.1 v1(95.9,80.2) L56.2
VDDIO_P3V3_S: length 34.5
  TOP w0.102: U10.K10 92.13,63.01 v3(92.13,63.05)
  TOP w0.254: U10.L10 92.54,62.64 v3(92.13,63.05) 91.74,62.66 U10.K10 ; U10.J9 v3(91.34,62.22) ; v3(96.37,60.35) 96.33,60.35 95.9,60.78 95.9,60.82 95.81,60.9 U10.T8 ; v3(96.31,58.9) 95.81,59.4 U10.T6
  TOP w0.305: 86.57,70.26 86.83,70.52 U10.D21
  BOTTOM w0.305: v3(92.13,63.05) 91.83,63.05 91.34,62.55 v3(91.34,62.22)
  BOTTOM w0.406: v3(92.13,63.05) 92.16,63.05
  BOTTOM w0.508: 92.75,63.05 93.02,63.05 93.83,62.23 94.49,62.23 v1(95.37,61.35) v3(96.37,60.35) 96.37,58.95 v3(96.31,58.9) ; 92.75,63.05 92.95,63.25 92.95,66.45 92.75,66.65 92.75,67.67 89.55,70.87 89.55,70.99 89.16,71.37 88.61,71.37 88.2,70.96 86.34,70.96 85.61,71.7 85.61,72.39 84.96,73.04 L58.2 84.47,73.28 83.7,74.04 83.07,74.04 81.67,75.44 v2(79.77,75.44) ; 92.75,63.05 92.16,63.05
VDDLT18: length 17.1
  TOP w0.254: v1(64.91,171.96) 64.91,171.31 L11.1
  TOP w0.305: 64.12,157.74 U3.A15 U3.B15
  TOP w0.4: C104.1 65.45,167.34 64.68,167.34 63.28,165.94 63.28,162.88 64.12,162.04 64.12,157.74
  TOP w0.508: L11.1 C101.1 65.53,167.42 C104.1
VDDLTP18: length 12.9
  TOP w0.254: U3.A13 62.44,157.68 62.83,158.06 62.83,158.24 62.85,158.27
  TOP w0.305: 62.85,158.27 62.85,161.87 62.16,162.55 62.16,164.68 C554.1 61.59,164.92 60.72,165.8 v1(60.72,166.05) 60.66,166.11 C103.1 60.34,168.06 L13.1
VDDPL_P1V1_SYS_S: length 14
  TOP w0.102: v3(92.97,71.56) 92.71,71.56 U10.L22
  BOTTOM w0.5: 92.37,75.55 92.37,77.72 v1(91.32,78.77)
  BOTTOM w0.508: v1(91.32,78.77) 91.25,78.84 C464.1 91.25,80.94 C460.1 C454.1 91.32,82.69 L53.2 ; v3(92.97,71.56) 93.05,71.64 93.05,74.3 92.37,74.98 92.37,75.55
VDDPL_P3V3_PCIE: length 6
  TOP w0.254: v3(102.57,75.15) 102.57,75.45 U10.AE28
  BOTTOM w0.508: v3(102.57,75.15) v1(102.57,75.84) 102.57,76.88 C469.1 102.42,78.65 C461.1 103.2,78.79 103.39,78.98 L57.2
VDDPL_P3V3_SATA: length 9.5
  BOTTOM w0.305: v3(101.51,64.85) 101.51,64.8 101.92,64.39 102.4,64.39 102.73,64.06 C481.1
  BOTTOM w0.381: L62.2 110.22,63.38 C482.1 107.71,63.38 v1(107.5,63.59) 107.16,63.93 103.39,63.93 C481.1
VDDPL_P3V3_SYS: length 13
  TOP w0.305: U10.M21 92.95,70.03 v3(92.95,70.02)
  BOTTOM w0.381: L56.1 95.9,78.03 95.59,77.72 C470.1 95.59,76.63 95.25,76.3 v1(95.25,75.88) 95.52,75.61 95.52,71.69 94.5,70.68 93.61,70.68 v3(92.95,70.02) ; L56.1 96.87,78.5 L55.2 ; L56.1 C459.1
VDDPL_P3V3_USB_S: length 5.6
  TOP w0.305: U10.F19 88.54,68.82 v3(88.23,68.5)
  BOTTOM w0.508: C457.1 85.56,69.72 v1(86.5,69.72) 87.51,69.72 88.23,69.01 v3(88.23,68.5)
VDDRF_GBE_S: length 8.4
  TOP w0.102: U10.V1 97.01,55.49 97.01,55.14 96.73,54.86 96.73,51.36 v1(97.55,50.55) 97.55,50.1 98.88,48.77 R394.1
VDDXL_P3V3_S: length 10.9
  TOP w0.254: U10.L20 92.44,69.52 92.44,68.88 v3(92.88,68.45)
  BOTTOM w0.406: C468.1 88.01,73.16 88.56,72.62 89.55,72.62 v1(89.72,72.8) 90.05,72.47 90.05,71.22 92.83,68.45 v3(92.88,68.45)
  BOTTOM w0.508: C468.1 86.37,73.16 L58.1
VIN0: length 11.4
  TOP w0.102: U10.A3 84.34,56.92 84.08,57.18 83.26,57.18 v3(83.07,56.98)
  BOTTOM w0.102: v3(83.07,56.98) 82.94,56.86 82.94,54.86 81.42,53.34 C508.1 81.88,52.75 82.05,52.58 82.05,50.59 R677.2 80.23,49.83 v1(80.15,49.91)
VIN1: length 14.8
  TOP w0.102: v3(84.84,57.32) 85.23,57.72 U10.B4
  BOTTOM w0.102: v3(84.84,57.32) 84.34,57.32 83.93,57.73 82.76,57.73 81.8,56.77 81.8,54.61 80.72,53.53 79.43,53.53 79,53.1 C509.1 79.08,52.75 79.51,52.32 79.51,50.34 R678.2 78.26,49.83 v1(77.86,50.23)
VIN2: length 13.6
  TOP w0.102: R321.2 75.39,52.7 75.89,52.2 77.53,52.2 C260.1 v1(79.21,52.7) 80.02,52.7 82.51,55.19 82.51,57 83.23,57.72 U10.A4
VIN3: length 15
  TOP w0.102: U10.C5 85.69,58.17 83.39,58.17 82.26,57.03 82.26,55.45 80.78,53.98 C257.1 77.4,54.61 76.21,54.61 v1(75.58,53.98) R318.2
VIN4: length 12.2
  TOP w0.102: R315.2 74.97,55.19 75.27,55.5 76.97,55.5 77.99,56.52 C253.1 79.06,56.52 v1(79.97,57.43) 80.32,57.78 82.14,57.78 84.44,60.08 U10.A7
VIN5: length 13.2
  TOP w0.102: U10.B7 84.84,60.52 84.26,60.52 84.03,60.28 84.03,59.96 82.17,58.1 79.31,58.1 78.74,57.53 C250.1 77.56,57.05 76.7,57.05 76.54,56.9 76.16,56.9 v1(75.32,56.06) 75.17,56.21 R313.2
VIN6: length 13.8
  TOP w0.102: U10.B8 85.3,61.25 84.19,61.25 82.94,60.01 82.22,60.01 81.01,58.8 78.29,58.8 C243.1 77.58,59 75.91,59 75.37,58.47 v1(75.37,58.01) 75.12,58.01 R310.2
VIN_19: length 2.3
  TOP w0.381: v1(160.03,10.1) 160.05,10.25 L34.1
  BOTTOM w0.762: C317.1 v2(158.25,18.67)
  vias: v1(160.35,15.11)
14M_25M_48M_OSC: length 7.2
  TOP w0.102: v3(92.67,78.66) 92.67,78.2 93.57,77.29 93.57,75.58 92.85,74.86 92.85,74.11 U10.L25
  BOTTOM w0.102: TP197.1 92.67,79.64 v3(92.67,78.66)
32K_X1: length 16.8
  TOP w0.102: U10.C1 86.04,55.17 80.3,49.43 79.74,49.43 78.81,48.5 v1(78.81,48.13) 78.81,47.54 R349.2 78.83,46.16 C273.2 78.55,45.26 78.13,44.85 Y3.4
32K_X2: length 19.6
  TOP w0.102: Y3.1 79.08,43.95 79.97,44.85 C259.2 79.69,46.16 R349.1 79.69,48.56 79.83,48.7 80.36,48.7 v1(81.11,49.45) 81.11,49.48 83.7,52.07 86.45,54.81 86.45,55.68 86.04,56.08 U10.C2
2668_BK_ENA: length 316.8
  TOP w0.102: R106.1 55,196.15 54.62,196.53 54.62,198.37 54.34,198.65 40.68,198.65 27.19,185.17 22.57,185.17 21.89,184.48 18.85,184.48 17.33,182.97 17.33,170.51 18.43,169.42 v2(18.55,169.42) 18.45,169.32 18.45,166.32 17.92,165.79 17.92,162.03 19.42,160.52 20.56,160.52 22.61,158.47 24.04,158.47 25.41,157.1 27.24,157.1 29.04,155.3 29.04,149.61 33.28,145.36 34.05,145.36 35.62,143.79 36.59,143.79 38.64,141.73 38.64,138.84 40.65,136.84 40.65,120.85 41.54,119.96 48.52,119.96 55.33,113.15 55.33,103.77 59.9,99.19 59.9,95.28 v2(60.18,95) ; R343.1 182.26,65.18 181.21,66.22 176.87,66.22 174.33,68.76 162.75,68.76 162.37,69.14 162.37,72.64 162.55,72.82 164.02,72.82 164.48,73.28 164.48,74.32 163.84,74.96 162.19,74.96 161.81,75.34 161.81,78.21 144.34,95.68 121.09,95.68 120.08,94.67 105.67,94.67 103.59,96.75 89.27,96.75 86.89,99.14 71.59,99.14 70.19,97.74 69.11,97.74 68.27,96.9 68.27,95.57 v3(67.83,95.12)
  BOTTOM w0.102: R558.1 19.77,169.42 v2(18.55,169.42) ; v2(60.18,95) 60.59,95 v1(60.91,95.31) 67.64,95.31 v3(67.83,95.12)
2668_BK_ENA_MXM_R: length 9.4
  TOP w0.102: v2(23.12,169.04) 23.12,171.65 24.2,172.73 CN9.30
  BOTTOM w0.102: v1(24.01,168.4) 23.76,168.4 v2(23.12,169.04) 23,169.16 R558.2
2668_BK_ENA_NB_R: length 4.3
  TOP w0.102: CN7.30 54.99,194.89 R106.2 55.47,195.37 55.47,196.83 v1(55.45,196.85)
2668_BK_PWM: length 284.9
  TOP w0.102: v3(67.77,97.66) 69.48,99.38 70.81,99.38 71.18,99.75 87.14,99.75 89.53,97.36 103.97,97.36 105.73,95.61 119.54,95.61 120.61,96.67 144.94,96.67 159.73,81.89 160.77,81.89 164.76,77.9 164.76,71.35 R299.1 ; R75.2 56.02,197.61 54.6,199.03 40.42,199.03 27.09,185.7 22.82,185.7 21.85,184.73 18.5,184.73 16.95,183.18 16.95,169.88 v2(17.79,169.04) 18.12,168.71 18.12,166.57 17.44,165.89 17.44,161.9 19.19,160.15 20.64,160.15 22.72,158.06 24.06,158.06 25.44,156.69 27.04,156.69 28.59,155.14 28.59,149.45 33.11,144.93 34.19,144.93 35.69,143.43 36.54,143.43 38.26,141.71 38.26,138.51 40.24,136.53 40.24,120.65 41.13,119.76 42.84,119.76 43.22,119.38 48.47,119.38 55.08,112.78 55.08,103.3 v3(59.38,99)
  BOTTOM w0.102: R561.1 18.68,168.15 v2(17.79,169.04) ; v3(67.77,97.66) v1(67.07,97.66) 66.88,97.66 65.54,99 v3(59.38,99)
2668_BK_PWM_MXM_R: length 8.9
  TOP w0.102: CN9.29 25.52,171.73 25.08,172.16 23.99,172.16 23.63,171.81 23.63,168.53 23.25,168.15 v2(22.11,168.15)
  BOTTOM w0.102: R561.2 v2(22.11,168.15)
2668_BK_PWM_NB_R: length 6
  TOP w0.102: CN7.29 56,194.87 R75.1 56.53,195.4 56.53,198.37 v1(56.4,198.5)
2668_DETECT_N: length 746.9
  TOP w0.102: Q18.G 157.33,74.81 R272.1 ; Q18.G 160.86,74.1 161.11,73.85 Q19.G ; Q18.G 157.33,73.44 158.41,72.36 158.41,69.39 158.66,69.14 160.84,69.14 162.04,67.94 174,67.94 176.7,65.25 177.59,65.25 178.57,64.26 179.97,64.26 181.71,62.52 181.71,59.11 179.45,56.86 Q22.G 179.02,56.26 178.76,56.01 v2(178.26,56.01) ; v2(127.71,247.52) 127.01,246.82 v2(124.47,246.82) ; v2(19.28,19.62) 19.02,19.35 11.47,19.35 11.14,19.68 11.14,21.35 11.57,21.78 v2(12.77,21.78) ; v2(99.17,232.74) 101.31,232.74 103.62,230.43 103.62,226.64 100.52,223.55 100.52,221.03 99.99,220.5 99.38,220.5 98.77,219.89 98.77,217.47 100.44,215.8 100.44,213.31 100.02,212.89 98.73,212.89 96.02,210.19 96.02,209.04 95.64,208.66 95.64,207.14 95.26,206.76 89.16,206.76 88.28,207.65 86.62,207.65 84.72,205.74 84.72,200.41 83.2,198.88 74.75,198.88 74.12,199.52 v2(64.91,199.52) ; R89.1 v2(52.97,196.47) 52.97,196.72 52.46,197.23 51.7,197.23 51.38,197.55 51.38,197.87 51.06,198.18 40.97,198.18 27.49,184.71 25.97,184.71 24.52,183.26 23.89,183.26 21.98,181.36 v2(21.98,175.39) ; v2(19.44,187.45) 19.4,187.45 15.95,184 15.95,177.1 15.19,176.34 14.21,176.34 Q96.G ; v2(88.66,41.72) 87.64,42.74 87.64,43.88 87.2,44.32 87.2,45.78 87.01,45.97 87.01,46.58 86.19,47.4 86.19,49.41 86.95,50.18 86.95,51.16 90.18,54.39 90.18,55.03 90.34,55.19 90.34,55.44 90.31,55.48 90.31,55.92 90.38,55.99 90.38,56.23 90.31,56.39 90.31,56.65 U10.H3
  INT1 w0.089: v2(32.01,20.7) 35.32,20.7 37.73,23.11 38.36,23.11 39.22,23.96 39.22,34.21 39.42,34.41 40.46,34.41 40.56,34.31 42.87,34.31 43.85,35.29 43.85,36.09 43.94,36.18 43.94,40.91 45.6,42.58 45.6,43.05 45.86,43.31 46.62,43.31 46.87,43.05 46.87,42.55 47.38,42.04 49.67,42.04 51.06,43.43 52.08,43.43 52.84,42.67 53.35,42.67 53.6,42.93 59.7,42.93 63.38,39.24 81.42,39.24 81.93,39.75 81.93,41.27 83.07,42.42 86.88,42.42 87.58,41.72 v2(88.66,41.72) ; v2(178.26,56.01) 173.18,56.01
  INT1 w0.102: 173.18,56.01 172.41,55.24 165.81,55.24 164.86,54.29 164.86,50.8 163.9,49.85 146.63,49.85 145.62,48.83 145.62,43.62 144.66,42.67 132.79,42.67 131.65,43.81 123.39,43.81 121.93,42.35 114.95,42.35 112.66,40.07 110.31,40.07 109.99,40.39 93.99,40.39 92.21,42.16 89.1,42.16 v2(88.66,41.72)
  BOTTOM w0.102: v2(32.01,20.7) 32.01,19.96 30.95,18.9 27.19,18.9 26.7,19.39 22.6,19.39 22.16,18.95 19.95,18.95 v2(19.28,19.62) ; v2(64.91,199.52) 61.48,199.52 58.43,196.47 v2(52.97,196.47) ; v2(124.47,246.82) 123.84,247.46 116.98,247.46 116.53,247.01 116.53,244.67 115.9,244.03 v1(114.06,244.03) 112.53,244.03 106.44,237.93 102.94,237.93 102.07,237.06 102.07,235.64 v2(99.17,232.74) ; v2(12.77,21.78) 12.77,22.43 R752.1 ; R536.1 21.68,175.08 v2(21.98,175.39) 21.98,181.93 21.79,182.12 21.79,183.07 22.05,183.32 22.05,186.31 20.9,187.45 v2(19.44,187.45) ; v2(178.26,56.01) 179.72,56.01 181.21,57.5 182.92,57.5 185.81,60.39 185.81,83.95 193.24,91.38 193.24,236.26 192.03,237.47 187.03,237.47 185.97,238.54 185.97,247.64 185.33,248.28 184.49,248.28 184.18,247.96 184.18,247.23 181.32,244.37 170.95,244.37 167.37,247.95 167.37,250.2 166.76,250.8 164.58,250.8 163.97,250.19 149.55,250.19 146.89,247.52 v2(127.71,247.52)
2668_DETECT_N_MXM_R: length 3.6
  TOP w0.102: CN9.32 24.37,174.73 24.14,174.5 v2(23.63,174.5)
  BOTTOM w0.102: v2(23.63,174.5) R536.2
2668_DETECT_N_NB_R: length 6.2
  TOP w0.102: CN7.32 52.99,194.87 R89.2 53.24,194.9 53.48,195.14 53.48,196.72 52.4,197.8 v1(52.02,197.8)
2668_LVDD_EN: length 276
  TOP w0.102: R277.1 155.97,82.17 143.5,94.64 121.63,94.64 120.64,93.65 105.22,93.65 103.13,95.73 88.74,95.73 86.35,98.12 72.3,98.12 69.84,95.66 v3(69.63,95.66) ; v2(55.23,95.76) 54.24,95.76 53.5,96.49 53.5,97.67 46,105.17 46,112.83 45.21,113.61 42.54,113.61 v2(41.6,114.55) ; v2(18.3,170.31) 17.59,171.02 17.59,182.93 18.93,184.28 22.01,184.28 22.67,184.94 27.34,184.94 40.8,198.4 52.18,198.4 53.99,196.6 R105.1
  BOTTOM w0.102: R542.1 20.16,170.05 18.55,170.05 v2(18.3,170.31) 17.79,170.31 17,169.51 17,167.74 16.77,167.51 16.77,165.61 19.06,163.32 19.06,156.67 20.18,155.55 20.18,145.97 18.96,144.75 18.96,136.93 19.8,136.09 19.8,129.82 33.89,115.72 39.86,115.72 40.65,114.94 41.22,114.94 v2(41.6,114.55) ; v3(69.63,95.66) 69.01,95.66 68.15,96.52 65.86,96.52 64.53,97.85 58.7,97.85 56.6,95.76 v1(56.08,95.76) v2(55.23,95.76)
2668_LVDD_EN_MXM_R: length 7
  TOP w0.102: CN9.31 24.9,173.73 22.49,171.32 v2(22.49,170.18)
  BOTTOM w0.102: R542.2 v2(22.49,170.18)
2668_LVDD_EN_NB_R: length 5.9
  TOP w0.102: v1(53.99,198.12) 53.99,197.36 54.3,197.04 54.3,196.34 54.49,196.15 54.49,195.14 54.26,194.9 R105.2 53.99,194.89 CN7.31
A_RST_N: length 6.8
  TOP w0.102: v1(91.83,39.98) 91.6,40.21 91.04,40.21 R457.1 90.89,40.51 90.89,42.26 C261.2 90.87,43.15 91.04,43.15 91.32,43.43 91.32,44.27 90.81,44.78 R338.1
A_RX0N: length 96.4
  TOP w0.152: v3(58.99,142.51) 58.64,142.86 U3.Y8 ; v5(108.17,86.74) 107.85,86.42 107.85,85.81 108.21,85.45 C196.1
  BOTTOM w0.102: 57.21,138.15 57.21,138.18 57.17,138.22 57.17,138.66 57.29,138.78 57.29,139.01 57.17,139.13 57.17,139.36 57.42,139.61 57.51,139.61 57.61,139.61 57.77,139.78 57.77,139.96 57.93,140.12 58.02,140.12 58.12,140.12 58.28,140.28 58.28,140.47 58.72,140.91 58.72,142.24 v3(58.99,142.51)
  BOTTOM w0.152: 57.21,138.15 57.21,137.85 57.36,137.7 57.36,137.42 57.21,137.26 57.21,136.99 57.36,136.83 57.36,136.55 57.21,136.4 57.21,136.12 57.36,135.97 57.36,135.69 57.21,135.54 57.21,135.26 57.36,135.11 57.36,134.83 57.21,134.67 57.21,133.81 57.45,133.57 57.45,128.43 55.93,126.9 55.93,123.16 58.98,120.11 58.98,117.79 62.34,114.43 62.88,114.43 72.92,104.39 75.79,104.39 79.47,100.71 87.74,100.71 88.33,101.31 98.42,101.31 107.85,91.88 107.85,87.06 v5(108.17,86.74)
A_RX0N_C: length 12.9
  TOP w0.102: U10.AD27 101.94,75.41 101.94,75.78 101.73,75.99 101.73,76.29 101.75,76.3 101.75,76.73 101.73,76.74 101.73,77.28 103.19,78.73 103.19,79.46 103.24,79.51 103.24,79.52
  TOP w0.152: C196.2 108.21,83.71 107.85,83.35 107.85,82.12 105.91,80.18 103.75,80.18 103.24,79.67 103.24,79.52
A_RX0P: length 95.5
  TOP w0.152: U3.AA8 58.44,142.06 v3(58.03,142.46) ; C195.1 107.2,85.45 107.56,85.81 107.56,85.96 107.56,85.96 107.56,86.42 v2(107.24,86.74)
  BOTTOM w0.102: 56.92,138.15 56.92,138.18 56.96,138.22 56.96,139.44 58.52,141 58.52,141.98 v3(58.03,142.46)
  BOTTOM w0.152: v2(107.24,86.74) 107.25,86.74 107.56,87.05 107.56,91.76 98.3,101.02 88.45,101.02 87.86,100.42 79.35,100.42 75.66,104.1 72.79,104.1 62.76,114.13 62.22,114.13 58.68,117.67 58.68,119.99 55.64,123.04 55.64,127.03 57.16,128.55 57.16,133.44 56.92,133.69 56.92,138.15
A_RX0P_C: length 13.8
  TOP w0.102: 102.95,79.52 102.95,79.51 102.99,79.47 102.99,78.81 101.53,77.36 101.53,76.65 101.54,76.64 101.54,76.39 101.53,76.38 101.53,75.91 101.74,75.7 101.74,75.45 101.73,75.44 101.73,75.19 102.04,74.88 U10.AD26
  TOP w0.152: C195.2 107.2,83.71 107.56,83.35 107.56,82.25 105.79,80.47 103.63,80.47 102.95,79.79 102.95,79.52
A_RX1N: length 94.3
  TOP w0.152: C194.1 106.18,85.45 105.76,85.87 105.76,86.36 v5(106.14,86.74) ; v3(57.25,142.47) 57.25,142.52 57.59,142.86 U3.Y7
  BOTTOM w0.102: 56.31,138 56.31,138.02 56.27,138.07 56.27,139.53 57.64,140.91 57.64,142.07 v3(57.25,142.47)
  BOTTOM w0.152: v5(106.14,86.74) 105.82,87.06 105.82,92.27 98.23,99.86 79.05,99.86 75.4,103.5 72.59,103.5 62.51,113.58 61.97,113.58 58.09,117.46 58.09,119.8 55.01,122.87 55.01,128.08 56.59,129.65 56.59,132.96 56.31,133.24 56.31,138
A_RX1N_C: length 10.7
  TOP w0.102: U10.AC29 101.26,76.53 101.26,77.53 102.3,78.57 102.3,79.3 102.34,79.35 102.34,79.36
  TOP w0.152: 102.34,79.36 102.34,80.21 103.4,81.27 105.09,81.27 105.45,81.63 105.82,82 105.82,83.78 106.18,84.14 C194.2
A_RX1P: length 93.3
  TOP w0.152: v2(105.21,86.74) 105.47,86.48 105.47,85.75 105.17,85.45 C193.1 ; v3(57.2,141.65) 57.61,142.06 U3.AA7
  BOTTOM w0.102: 56.02,138 56.02,138.02 56.06,138.07 56.06,139.62 57.44,141 57.44,141.41 v3(57.2,141.65)
  BOTTOM w0.152: 56.02,138 56.02,133.12 56.3,132.84 56.3,129.78 54.72,128.2 54.72,122.75 57.8,119.68 57.8,117.34 61.85,113.28 62.39,113.28 72.46,103.21 75.28,103.21 78.93,99.57 98.11,99.57 105.53,92.14 105.53,87.05 105.22,86.74 v2(105.21,86.74)
A_RX1P_C: length 11.6
  TOP w0.102: 102.05,79.36 102.05,79.35 102.09,79.3 102.09,78.65 101.05,77.61 101.05,76.77 100.93,76.65 100.93,76.33 101.24,76.01 U10.AC28
  TOP w0.152: 102.05,79.36 102.05,80.33 103.28,81.56 104.97,81.56 105.53,82.12 105.53,83.78 105.17,84.14 C193.2
A_RX2N: length 92.6
  TOP w0.102: U3.AA6 56.83,142.06 v3(56.44,141.66)
  TOP w0.152: C192.1 104.15,85.45 103.79,85.81 103.79,85.84 103.79,86.42 v5(104.11,86.74)
  BOTTOM w0.102: v3(56.44,141.66) 56.43,141.66 55.59,140.82 55.59,139.88 55.1,139.4 55.1,138.89 54.8,138.58 54.8,138.08 55.38,137.5 55.38,136.58 55.42,136.54 55.42,136.53
  BOTTOM w0.152: 55.42,136.53 55.42,132.6 54.16,131.34 54.16,122.52 57.2,119.48 57.2,117.13 61.61,112.73 62.15,112.73 72.26,102.62 74.95,102.62 78.55,99.01 97.47,99.01 103.87,92.61 103.87,86.99 v5(104.11,86.74)
A_RX2N_C: length 10.2
  TOP w0.102: 101.45,79.89 101.45,79.86 101.4,79.81 101.4,79.38 100.68,78.66 100.42,78.66 100.11,78.35 100.11,77.84 100.74,77.2 100.74,76.78 100.44,76.48 U10.AB28
  TOP w0.152: C192.2 104.15,84.12 103.79,83.76 103.79,83.49 101.45,81.15 101.45,79.89
A_RX2P: length 93.4
  TOP w0.102: U3.AA5 v3(55.64,141.66)
  TOP w0.152: v2(103.18,86.74) 103.5,86.42 103.5,85.96 103.5,85.96 103.5,85.81 103.13,85.45 C191.1
  BOTTOM w0.102: v3(55.64,141.66) 55.84,141.46 55.84,141.39 55.38,140.93 55.38,139.96 54.9,139.48 54.9,138.97 54.6,138.67 54.6,138 55.17,137.42 55.17,136.59 55.13,136.55 55.13,136.53
  BOTTOM w0.152: v2(103.18,86.74) 103.44,86.74 103.57,86.87 103.57,92.49 97.35,98.72 78.43,98.72 74.83,102.32 72.13,102.32 62.03,112.43 61.48,112.43 56.91,117.01 56.91,119.36 53.87,122.4 53.87,131.46 55.13,132.72 55.13,132.97 54.87,133.22 54.87,133.48 55.13,133.73 55.13,133.99 54.87,134.24 54.87,134.49 55.13,134.75 55.13,135 54.87,135.25 54.87,135.51 55.13,135.76 55.13,136.53
A_RX2P_C: length 9.4
  TOP w0.102: 101.16,79.89 101.16,79.88 101.19,79.84 101.19,79.47 100.59,78.87 100.34,78.87 99.9,78.43 99.9,77.76 100.54,77.12 100.54,77.02 U10.AB29
  TOP w0.152: C191.2 103.13,84.14 103.5,83.78 103.5,83.61 101.16,81.27 101.16,79.89
A_RX3N: length 94.8
  TOP w0.152: C190.1 102.12,85.45 101.76,85.81 101.76,86.92 v5(102.08,87.24) ; U3.Y5 55.65,142.46 v3(55.64,142.46)
  BOTTOM w0.102: v3(55.64,142.46) 55.64,142.67 55.51,142.8 54.56,142.8 53.94,142.17 53.94,141.59 54.06,141.46 54.06,141.16 54.19,141.03 54.19,140.8 54.06,140.68 54.06,140.45 54.19,140.32 54.19,140.09 54.06,139.96 54.06,139.74 54.19,139.61 54.19,139.38 54.06,139.25 54.06,137.73 54.43,137.36 54.43,136.86 54.47,136.81 54.47,136.8
  BOTTOM w0.152: 54.47,136.8 54.47,136.35 54.07,135.94 53.3,135.17 53.3,122.18 56.31,119.17 56.31,116.73 61.16,111.87 61.78,111.87 72.78,100.88 75.47,100.88 78.19,98.16 96.58,98.16 101.76,92.98 101.76,91.39 101.92,91.23 101.92,91.01 101.76,90.85 101.76,90.65 101.92,90.49 101.92,90.25 101.76,90.09 101.76,89.89 101.89,89.76 101.89,89.51 101.76,89.38 101.76,89.15 101.92,89 101.92,88.77 101.76,88.61 101.76,88.39 101.92,88.23 101.92,87.99 101.76,87.83 101.76,87.56 v5(102.08,87.24)
A_RX3N_C: length 10.4
  TOP w0.102: 100.59,79.61 100.59,79.6 100.54,79.56 100.54,79.35 100.31,79.12 100.12,79.12 99.57,78.57 99.57,77.35 100.17,76.75 100.17,76.29 100.13,76.26 100.13,75.99 100.34,75.79 100.34,75.42 U10.AB27
  TOP w0.152: C190.2 102.12,84.14 101.76,83.78 101.76,83.14 100.88,82.26 100.59,81.97 100.59,79.61
A_RX3P: length 94.1
  TOP w0.152: v2(101.14,87.24) 101.46,86.92 101.46,85.81 101.1,85.45 C189.1 ; U3.W5 55.63,143.25 v3(55.63,143.22)
  BOTTOM w0.102: 54.18,136.8 54.18,136.82 54.23,136.87 54.23,137.28 53.86,137.64 53.86,141.38 53.73,141.5 53.73,142.26 54.48,143 55.42,143 v3(55.63,143.22)
  BOTTOM w0.152: 54.18,136.8 54.18,136.47 53.86,136.14 53.01,135.29 53.01,122.06 56.02,119.05 56.02,116.6 61.04,111.58 61.66,111.58 72.65,100.58 75.35,100.58 78.07,97.87 96.45,97.87 101.46,92.86 101.46,87.56 v2(101.14,87.24)
A_RX3P_C: length 11.2
  TOP w0.102: 100.3,79.61 100.3,79.39 100.23,79.32 100.04,79.32 99.37,78.66 99.37,77.27 99.97,76.67 99.97,76.38 99.93,76.34 99.93,75.91 100.13,75.7 100.13,75.18 100.44,74.88 U10.AB26
  TOP w0.152: C189.2 101.1,84.14 101.46,83.78 101.46,83.26 100.76,82.56 100.3,82.09 100.3,79.61
A_TX0N: length 98.9
  TOP w0.152: U10.AE23 102.74,72.2 102.96,72.42 v3(103.14,72.42) ; C138.2 53.71,131.65 53.55,131.5 53.55,130.76 52.91,130.11 52.91,129.79 52.65,129.54 52.33,129.54 52.05,129.25 52.05,128.94 51.89,128.78 51.57,128.78 51.27,128.47 51.27,128.26 51.51,128.02 51.51,127.83 51.27,127.58 51.27,127.1 v5(51.4,126.97)
  BOTTOM w0.152: v5(51.4,126.97) 51.19,126.77 51.19,126.09 51.58,125.71 51.58,121.49 54.53,118.54 54.53,116 60.36,110.17 61.04,110.17 72.12,99.1 74.73,99.1 77.37,96.46 95.04,96.46 97.45,94.05 97.45,87.81 101.97,83.29 104.02,83.29 105.08,82.23 105.08,77.07 104.02,76.02 104.02,74.42 103.59,73.99 103.59,73.46 102.86,72.72 102.86,72.54 102.98,72.42 v3(103.14,72.42)
A_TX0N_C: length 8.9
  TOP w0.102: U3.AE7 57.62,139.24 57.62,137.13 57.28,136.79 57.28,136.53 57.32,136.49 57.32,136.46
  TOP w0.152: 57.32,136.46 57.32,136.29 57.17,136.14 54.48,133.45 53.87,133.45 53.66,133.24 53.66,132.86 C138.1
A_TX0P: length 97.9
  TOP w0.152: U10.AE24 102.74,72.79 v3(102.36,72.42) ; C137.2 53,131.65 53.26,131.38 53.26,130.88 50.98,128.59 50.98,127.37 v2(50.58,126.97)
  BOTTOM w0.152: v2(50.58,126.97) 50.9,126.66 50.9,125.97 51.29,125.59 51.29,121.37 54.24,118.42 54.24,115.87 60.23,109.88 60.92,109.88 71.99,98.81 74.61,98.81 77.25,96.16 94.92,96.16 97.15,93.93 97.15,87.69 101.85,82.99 103.9,82.99 104.79,82.11 104.79,77.19 103.73,76.14 103.73,74.54 103.3,74.11 103.3,73.58 102.75,73.03 102.56,72.84 102.56,72.62 v3(102.36,72.42)
A_TX0P_C: length 9.9
  TOP w0.102: U3.AD7 57.41,139.83 57.41,139.46 57.34,139.38 57.34,139.13 57.41,139.05 57.41,137.22 57.07,136.88 57.07,136.52 57.03,136.47 57.03,136.46
  TOP w0.152: C137.1 53.36,132.88 53.36,133.36 53.74,133.74 54.36,133.74 56.97,136.35 57.03,136.41 57.03,136.46
A_TX1N: length 94.3
  TOP w0.152: v5(50.4,128.68) 50.16,128.92 50.16,129.72 51.53,131.09 51.53,131.46 51.73,131.65 C136.2 ; v3(102.32,73.22) 101.94,72.83 U10.AD24
  BOTTOM w0.152: v3(102.32,73.22) 102.38,73.28 102.38,74.51 101.97,74.93 101.97,75.34 100.26,77.04 100.26,78.87 100.75,79.36 100.75,82.18 99.67,83.26 99.67,84.37 96.53,87.51 96.53,93.17 94.1,95.61 77.01,95.61 74.4,98.21 71.79,98.21 60.67,109.32 59.99,109.32 53.64,115.67 53.64,118.22 50.73,121.14 50.73,125.23 49.9,126.06 49.9,127.56 50.21,127.88 50.21,128.49 v5(50.4,128.68)
A_TX1N_C: length 10.8
  TOP w0.102: 56.18,136.44 56.19,136.45 56.19,136.46 56.63,136.9 56.63,137.01 57.16,137.54 57.16,138.97 56.84,139.29 U3.AD6
  TOP w0.152: 56.18,136.44 55.53,135.78 54.07,134.33 52.05,134.33 51.7,133.98 51.7,132.79 C136.1
A_TX1P: length 94.8
  TOP w0.152: C135.2 51.06,131.65 51.24,131.47 51.24,131.21 51.09,131.06 50.81,131.06 50.68,130.94 50.68,130.66 50.52,130.49 50.18,130.49 50.05,130.37 50.05,130.02 49.87,129.84 49.87,128.98 v2(49.6,128.71) ; v3(101.51,73.22) 101.91,73.62 U10.AD25
  BOTTOM w0.152: v2(49.6,128.71) 49.92,128.4 49.92,128 49.6,127.68 49.6,125.94 50.44,125.11 50.44,121.02 53.35,118.1 53.35,115.54 59.87,109.03 60.55,109.03 71.66,97.92 74.28,97.92 76.88,95.31 93.98,95.31 96.24,93.05 96.24,87.39 99.38,84.25 99.38,83.13 100.46,82.05 100.46,79.48 99.97,78.99 99.97,76.92 101.68,75.21 101.68,74.81 102.09,74.39 102.09,73.79 102.04,73.74 v3(101.51,73.22)
A_TX1P_C: length 10.4
  TOP w0.102: U3.AE6 56.96,138.74 56.96,137.63 56.42,137.09 56.42,136.98 56.11,136.67 56.09,136.66 56.08,136.65 55.99,136.65 55.98,136.64
  TOP w0.152: C135.1 51.04,132.51 51.41,132.88 51.41,133.2 51.19,133.41 51.19,133.67 51.41,133.88 51.41,134.1 51.93,134.62 53.95,134.62 55.32,135.99 55.98,136.64
A_TX2N: length 93.3
  TOP w0.152: v3(101.59,74.04) 101.16,73.62 U10.AC25 ; v5(49.03,129.79) 48.93,129.9 48.93,130.18 49.44,130.68 49.44,131.52 49.57,131.65 C134.2
  BOTTOM w0.152: v5(49.03,129.79) 48.75,129.51 48.75,129.24 48.97,129.02 48.97,128.79 48.75,128.57 48.75,127.81 48.98,127.58 48.98,127.3 48.75,127.08 48.75,126.91 48.94,126.72 48.94,126.34 48.75,126.15 48.75,125.95 49.86,124.84 49.86,120.8 52.75,117.91 52.75,115.31 59.59,108.47 60.3,108.47 71.46,97.32 73.94,97.32 76.51,94.75 92.85,94.75 95.62,91.99 95.62,87 98.75,83.86 98.75,82.34 99.87,81.22 99.87,79.71 99.56,79.39 99.56,76.48 100.35,75.69 100.35,75.09 100.93,74.51 101.12,74.51 101.59,74.04 v3(101.59,74.04)
A_TX2N_C: length 13.7
  TOP w0.102: U3.AC6 56.79,140.41 56.79,140.04 56.54,139.78 56.54,139.52 56.57,139.48 56.57,139.02 56.5,138.95 56.5,137.74 55.56,136.8 55.23,136.8 54.99,136.57 54.99,136.5 54.98,136.49
  TOP w0.152: C134.1 49.89,132.51 49.49,132.91 49.49,133.2 49.62,133.33 49.62,133.6 49.49,133.73 49.49,134.11 49.9,134.52 50.15,134.52 50.36,134.73 50.36,134.98 50.57,135.19 50.87,135.19 51.09,134.98 51.43,134.98 51.65,135.19 53.68,135.19 54.76,136.27 54.98,136.49
A_TX2P: length 93
  TOP w0.152: v3(100.81,74.04) 100.75,73.97 100.75,73.21 U10.AC24 ; C133.2 49.12,131.46 49.12,130.85 48.19,129.92 v2(48.19,129.82)
  BOTTOM w0.152: v3(100.81,74.04) 100.81,74.2 100.72,74.3 100.72,74.31 100.06,74.97 100.06,75.56 99.27,76.36 99.27,79.51 99.58,79.83 99.58,81.1 98.46,82.22 98.46,83.74 95.32,86.88 95.32,91.87 92.73,94.46 76.39,94.46 73.82,97.03 71.33,97.03 60.18,108.18 59.47,108.18 52.46,115.19 52.46,117.79 49.57,120.68 49.57,124.72 48.46,125.83 48.46,129.53 48.19,129.79 v2(48.19,129.82)
A_TX2P_C: length 14.1
  TOP w0.102: 54.78,136.7 54.79,136.71 54.85,136.71 55.15,137.01 55.48,137.01 56.3,137.83 56.3,139.03 56.37,139.11 56.37,139.39 56.33,139.43 56.33,139.87 56.54,140.07 56.54,140.58 56.84,140.89 U3.AB6
  TOP w0.152: C133.1 49.2,132.78 49.2,134.23 50.45,135.48 53.56,135.48 54.78,136.7
A_TX3N: length 95
  TOP w0.152: v3(99.88,72.36) 100.34,72.82 U10.AB24 ; v2(47.66,128.98) 47.48,129.16 47.48,130.02 47.74,130.28 47.74,130.51 47.48,130.76 47.48,131.22 C132.2
  BOTTOM w0.152: v2(47.66,128.98) 47.41,128.73 47.41,127.89 47.64,127.67 47.64,127.38 47.41,127.16 47.41,126.87 47.64,126.65 47.64,126.49 47.41,126.27 47.41,125.65 47.69,125.37 47.92,125.37 48.09,125.2 48.09,124.97 48.98,124.08 48.98,120.48 51.87,117.59 51.87,114.98 59.23,107.62 59.94,107.62 71.13,96.43 73.59,96.43 76.12,93.9 91.69,93.9 94.7,90.89 94.7,86.65 97.74,83.61 97.74,81.35 98.87,80.22 98.87,74.68 99.27,74.27 99.93,74.27 100.7,73.51 100.7,72.87 100.33,72.5 100.02,72.5 v3(99.88,72.36)
A_TX3N_C: length 12.8
  TOP w0.102: U3.AE5 55.94,139.16 55.94,138.02 55.44,137.52 54.95,137.52 54.29,136.86 53.91,136.86 53.73,136.67 53.73,136.61 53.71,136.59
  TOP w0.152: C132.1 47.52,132.9 47.52,133.49 50.07,136.04 53.16,136.04 53.71,136.59
A_TX3P: length 93.9
  TOP w0.152: U10.AB25 100.34,73.61 v3(99.88,73.15) ; C131.2 47.18,131.37 47.18,129.29 v2(46.87,128.98)
  BOTTOM w0.152: v3(99.88,73.15) 99.88,72.96 99.92,72.92 100.12,72.92 100.22,72.81 100.4,72.99 100.4,73.39 99.81,73.98 99.15,73.98 98.58,74.55 98.58,80.1 97.45,81.23 97.45,83.49 94.41,86.53 94.41,90.77 91.57,93.61 76,93.61 73.47,96.14 71,96.14 59.82,107.33 59.1,107.33 51.57,114.86 51.57,117.47 48.69,120.36 48.69,123.96 47.89,124.76 47.12,125.53 47.12,128.73 v2(46.87,128.98)
A_TX3P_C: length 13.7
  TOP w0.102: U3.AD5 56.04,139.69 55.74,139.38 55.74,139.13 55.74,139.13 55.74,138.1 55.36,137.72 54.87,137.72 54.21,137.06 53.83,137.06 53.57,136.81 53.51,136.81 53.5,136.8
  TOP w0.152: C131.1 47.23,132.84 47.23,133.61 49.95,136.33 53.04,136.33 53.5,136.8
A_VBAT: length 165.5
  TOP w0.178: v2(49.79,31.88) 50.11,32.19 U11.47
  TOP w0.305: v2(97.65,28.17) 99.94,30.46 106.7,30.46 107.58,31.34 107.58,37.19 v2(108.01,37.62) ; D8.K C197.1 140.39,84.76 140.22,84.58 140.22,81.53 J4.1 141.74,79.25 146.9,74.09 146.9,70.28 v2(148.47,68.71)
  INT1 w0.305: v2(113.93,42.16) 114.56,42.8 120.91,42.8 121.35,43.23 v2(121.35,44.15)
  BOTTOM w0.305: v2(113.93,42.16) 113.93,40.39 111.42,37.87 108.27,37.87 v2(108.01,37.62) ; v2(121.35,44.15) 121.35,43.48 121.83,43 122.44,43 122.87,43.43 129.96,43.43 130.54,44.02 138.42,44.02 141.21,46.81 145.02,46.81 145.93,47.73 145.93,51.24 148.47,53.78 v2(148.47,68.71)
  BOTTOM w0.508: v2(97.65,28.17) 97.02,27.54 93.66,27.54 93.13,28.07 92.34,28.07 91.83,27.56 91.48,27.56 90.05,26.14 90.05,24.59 89.37,23.9 82.69,23.9 82.04,23.25 63.17,23.25 62.42,24 57.53,24 57.16,24.37 56.77,24.37 54.47,26.67 51.57,26.67 50.3,27.94 v1(50.3,29.08) 49.92,29.46 C533.1 49.04,31.13 v2(49.79,31.88)
ALLOW_LDTSTOP: length 178.9
  TOP w0.102: R126.1 59.07,168.64 58.61,169.1 58.61,170.92 58.21,171.33 58.21,172.56 57.61,173.16 57.61,177.03 54.67,179.96 50.94,179.96 49.99,179.01 40.08,179.01 36.72,175.64 36.72,166.99 30.41,160.68 30.41,149.4 33.64,146.18 34.38,146.18 35.93,144.63 36.92,144.63 39.46,142.09 39.46,139.19 41.46,137.19 41.46,121.28 41.97,120.78 48.98,120.78 56.14,113.61 56.14,104.1 60.77,99.48 60.77,96.09 61.38,95.48 61.38,90.86 61.05,90.53 61.05,88.56 62.75,86.86 v3(62.75,86.49) ; v2(79.2,78.23) 80.09,78.23 81.86,76.46 81.86,75.63 84.13,73.36 84.13,72.77 84.34,72.57 86.89,72.57 87.19,72.27 87.19,71.78 87.4,71.56 87.4,71.06 88.1,70.36 88.1,69.88 88.23,69.75 88.95,69.75 U10.G21
  BOTTOM w0.102: v3(62.75,86.49) 69.61,86.49 76.21,79.88 76.85,79.88 v1(77.35,79.38) 78.5,78.23 v2(79.2,78.23)
AMP_IN_L: length 6.4
  TOP w0.254: v2(20.97,27.37) 21.49,26.85 R774.2
  BOTTOM w0.254: U25.3 21.83,28.66 22.05,28.45 C534.2 22.95,27.46 C535.2 21.73,27.18 v1(21.66,27.11) 21.22,27.11 v2(20.97,27.37)
AMP_IN_R: length 4.8
  BOTTOM w0.254: U25.18 21.83,36.61 22.17,36.96 22.17,37.77 C519.2 21.88,38.12 C518.2 23.12,37.54 v1(23.43,37.24)
AMP_MODE: length 5.3
  TOP w0.254: R989.1 21.47,36.24 v2(21.47,37.21) 21.98,36.7 R415.2 22.7,35.56 R456.1
  BOTTOM w0.254: U25.17 21.18,36.92 v2(21.47,37.21)
AMP_SVRR: length 8
  TOP w0.254: R470.2 19.25,27.56 20.27,28.57 v2(20.53,28.57)
  BOTTOM w0.254: U25.5 v2(20.53,28.57) 20.53,28.27 18.3,26.04 v1(18.3,25.97) C301.1
AP_VOLUME_DOWN: length 274.3
  TOP w0.102: S2.4 8.05,153.63 v1(8.08,153.61) 8.05,153.58 S2.3 ; v2(21.68,161.04) 21.68,160.76 23.12,159.31 26.35,159.31 26.81,159.77 27.43,159.77 34.68,167.02 34.68,175.71 39.6,180.63 49.22,180.63 50.18,181.58 54.85,181.58 56.78,183.51 58.53,183.51 59.5,184.48 R115.1 R112.1 ; v2(12.08,126.75) 12.69,126.14 12.69,123.43 17.11,119 26.74,119 30.04,115.7 44.37,115.7 44.82,115.24 46.29,115.24 47.13,114.4 47.13,105.6 54.62,98.11 55.51,98.11 57.06,96.56 57.06,92.43 57.54,91.95 57.54,87.8 58.45,86.89 58.45,84.28 60.51,82.21 60.51,74.88 59.27,73.63 59.27,72.51 58.76,72.01 58.76,68.53 59.27,68.02 59.27,59.46 60.11,58.62 60.11,54.01 63.97,50.15 63.97,49.07 66.24,46.8 67.45,46.8 68.59,45.66 70.56,45.66 71.02,45.19 72.32,45.19 v2(72.73,44.78) ; v2(19.87,157.44) 16.97,157.44 15.4,159.01 v2(11.72,159.01)
  TOP w0.125: U10.D4 86.84,57.64 86.54,57.35 86.53,57.35 v4(86.49,57.31)
  BOTTOM w0.102: v2(12.08,126.75) 10.3,128.52 10.3,146.97 13.42,150.09 13.42,153.34 11.75,155.02 11.75,158.98 v2(11.72,159.01) 11.37,159.36 10.53,159.36 R562.2 C371.1 8.44,158.93 8.05,158.53 S2.4 6.8,155.87 S2.2 ; v2(72.73,44.78) 72.73,45.8 73.61,46.67 73.61,47.49 74.12,48.01 74.94,48.01 76.02,46.93 77.1,46.93 77.54,46.48 79,46.48 79.45,46.93 82.37,46.93 83.63,48.18 83.63,53.52 86.65,56.54 86.65,57.16 v4(86.49,57.31) ; v2(21.68,161.04) 20.03,159.38 20.03,157.59 v2(19.87,157.44)
AP_VOLUME_DOWN_MXM_R: length 61.9
  TOP w0.102: R115.2 60,185.34 58.43,183.77 56.65,183.77 54.7,181.81 50.06,181.81 49.1,180.85 44.59,180.85 v1(44.21,181.23) 39.84,181.23 34.43,175.82 34.43,167.05 27.37,159.99 26.73,159.99 26.27,159.54 23.2,159.54 22.36,160.38 22.36,164.72 21.35,165.73 CN9.18
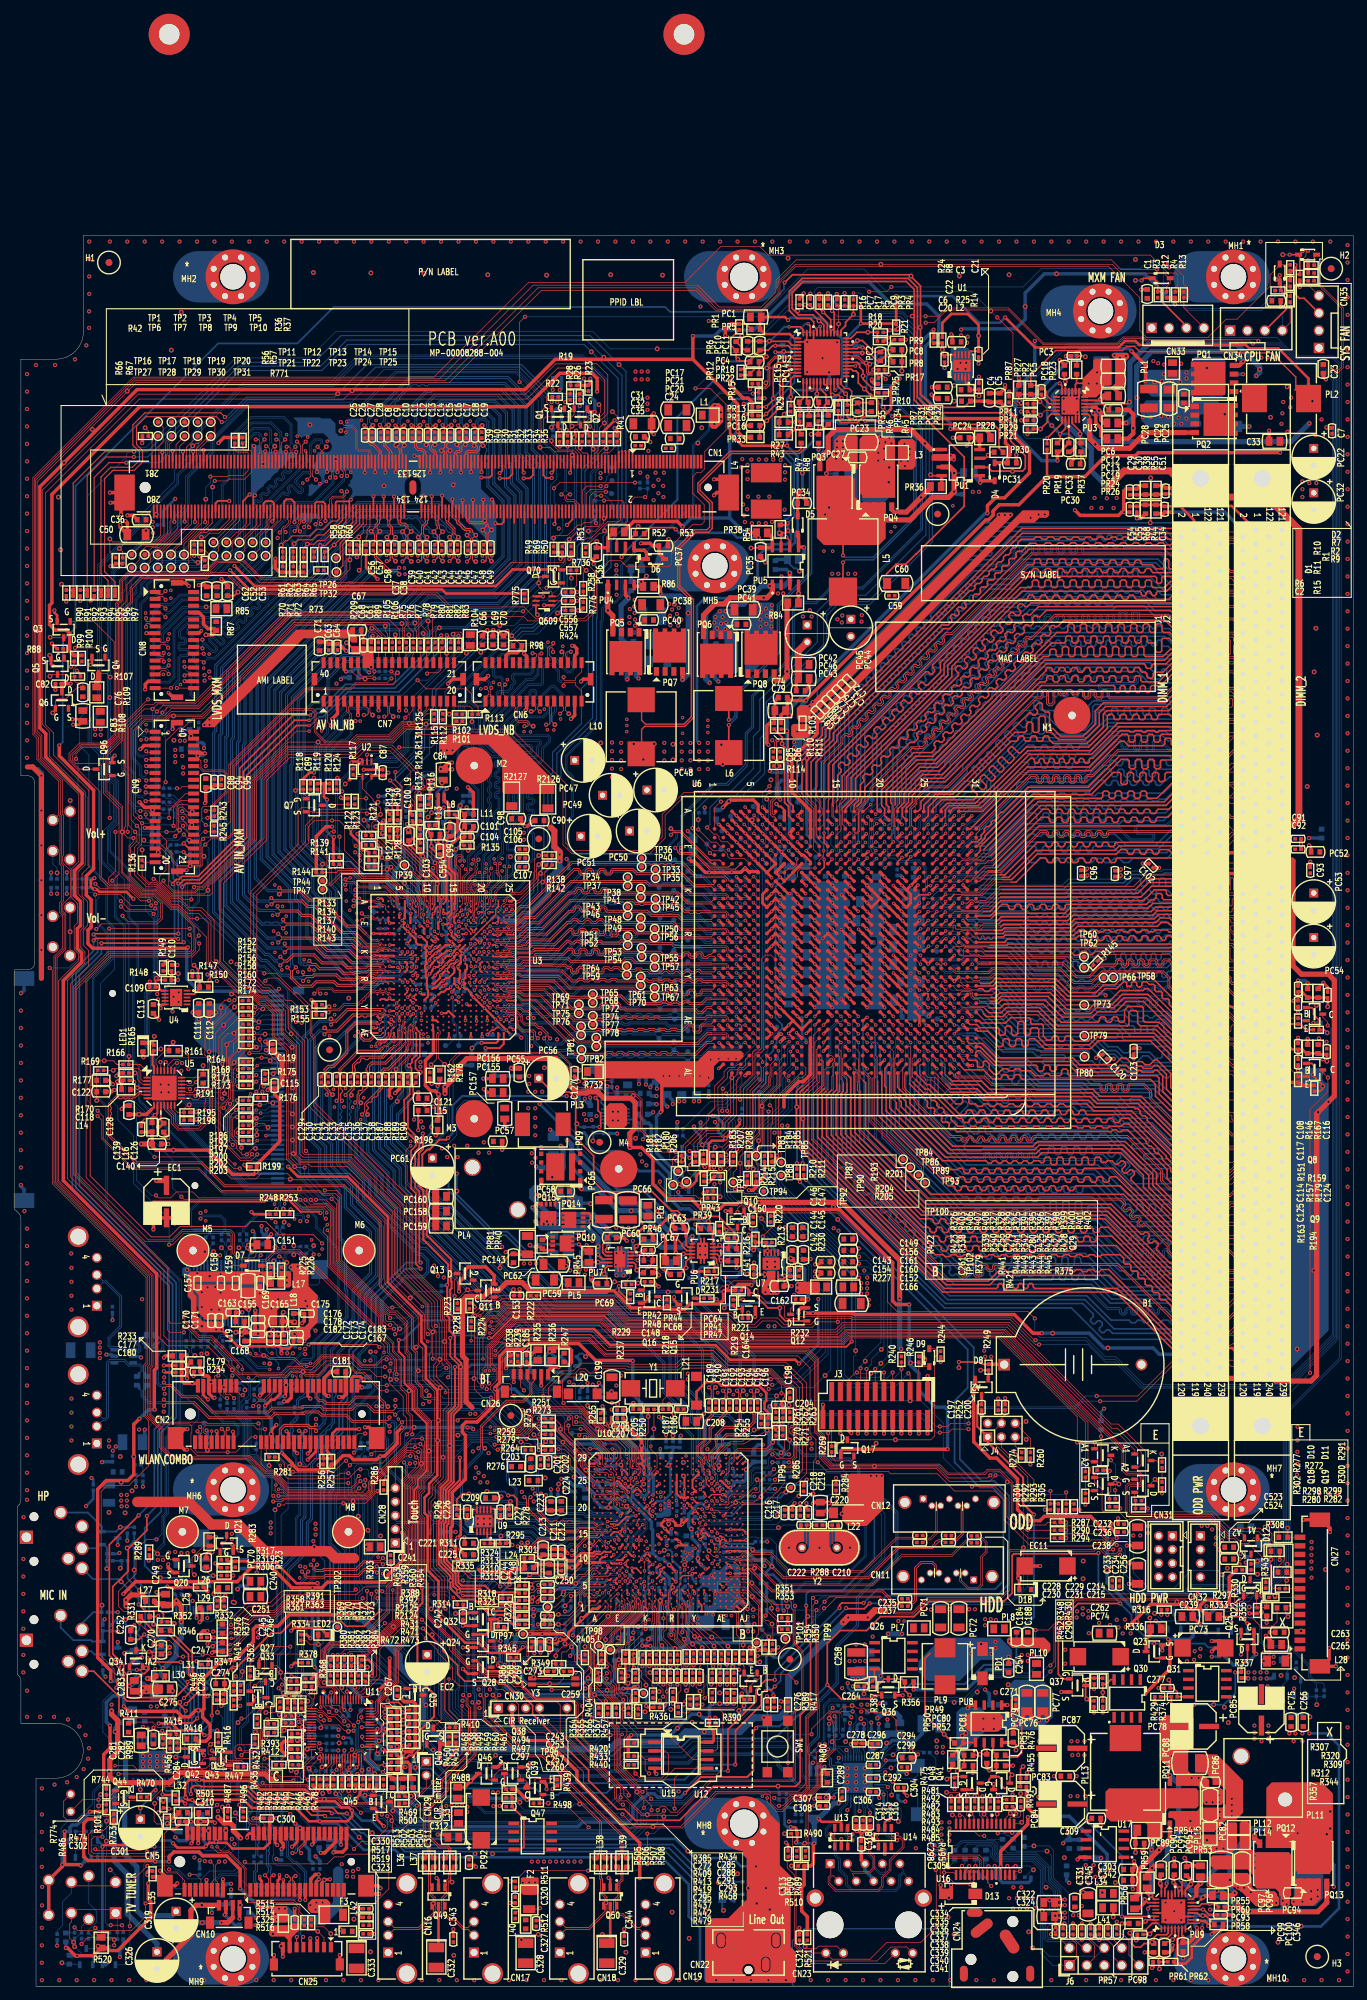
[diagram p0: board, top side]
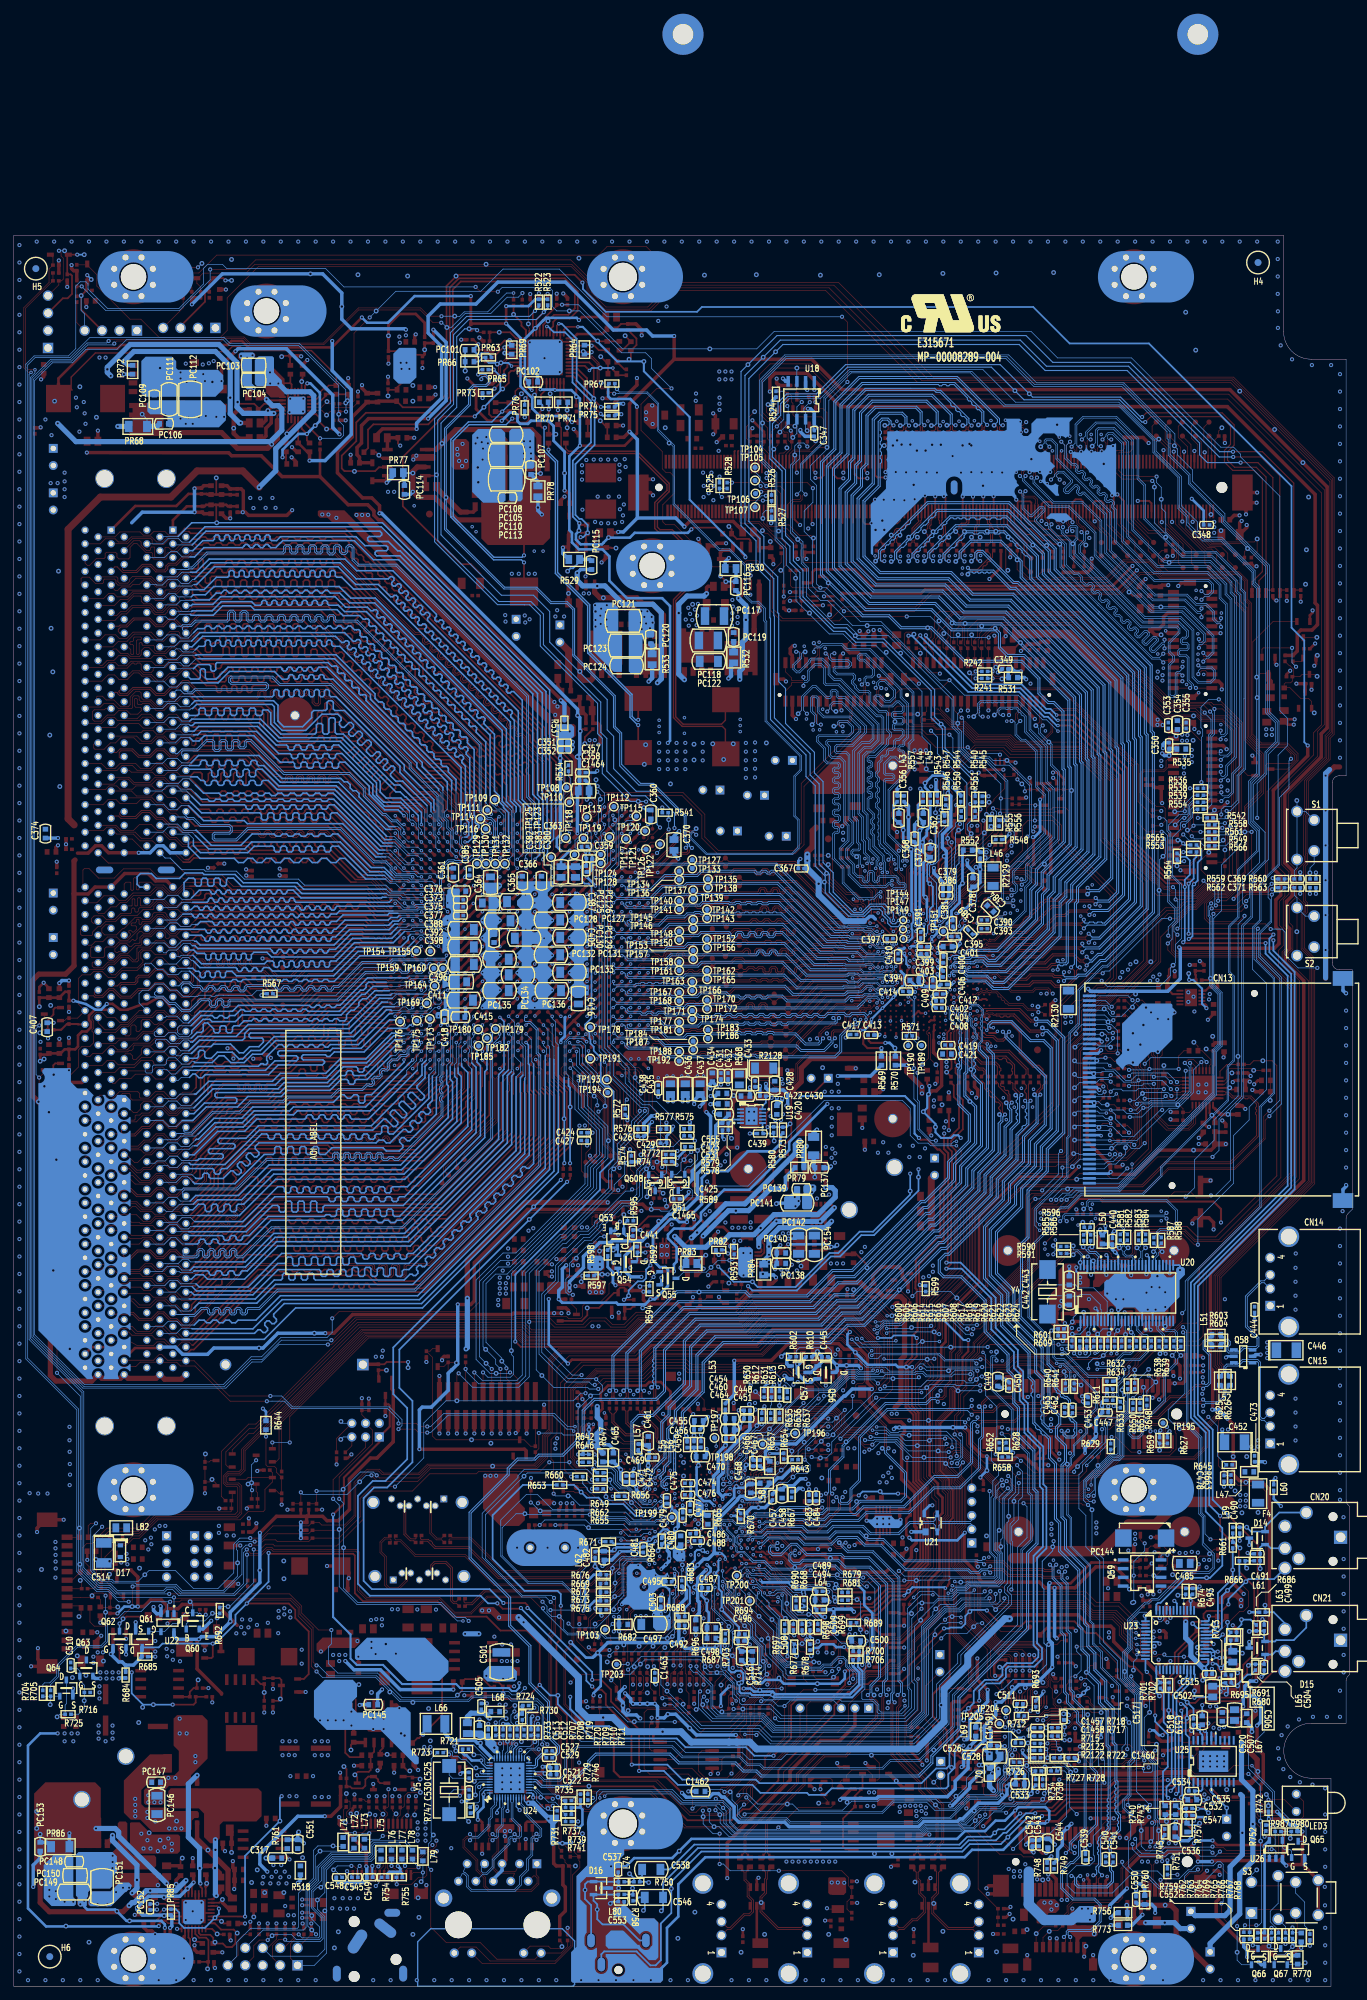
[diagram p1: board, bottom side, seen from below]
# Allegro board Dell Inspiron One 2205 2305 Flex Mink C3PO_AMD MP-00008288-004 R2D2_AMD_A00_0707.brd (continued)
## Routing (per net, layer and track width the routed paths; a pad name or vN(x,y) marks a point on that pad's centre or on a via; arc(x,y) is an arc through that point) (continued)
AP_VOLUME_DOWN_NB_R: length 6.6
  TOP w0.102: v1(59.9,183.85) 60.01,183.95 62.75,183.95 62.93,184.12 62.93,184.78 R112.2 61.99,185.71 CN7.18
AP_VOLUME_UP: length 283.1
  TOP w0.102: R102.1 R101.1 64.45,183.51 61.09,183.51 60.63,183.06 57.08,183.06 55.13,181.1 50.43,181.1 49.48,180.15 39.84,180.15 35.19,175.5 35.19,166.95 28.78,160.54 28.78,159.26 28.42,158.9 22.79,158.9 20.41,161.29 v2(20.23,161.29) ; v2(19.54,158.12) 18.32,158.12 16.57,159.87 12.46,159.87 v2(11.74,160.58) ; v2(69.94,47.75) 69.1,47.75 68.59,48.26 65.16,48.26 64.17,49.25 64.17,50.23 60.31,54.09 60.31,58.7 59.48,59.53 59.48,68.14 58.99,68.63 58.99,71.78 59.5,72.29 59.5,73.57 60.72,74.79 60.72,82.3 58.65,84.36 58.65,86.98 57.8,87.83 57.8,92.08 57.26,92.61 57.26,96.8 55.7,98.36 54.68,98.36 47.33,105.71 47.33,114.86 46.75,115.44 44.91,115.44 44.45,115.9 30.13,115.9 26.82,119.2 17.2,119.2 12.89,123.51 12.89,126.72 v2(12.08,127.53) ; U10.E8 87.67,61.02 v4(87.26,60.6)
  BOTTOM w0.102: v2(12.08,127.53) 10.55,129.06 10.55,146.84 13.63,149.91 13.63,153.44 11.95,155.12 11.95,158.26 12.26,158.57 12.26,160.07 v2(11.74,160.58) 11.62,160.71 10.12,160.71 9.87,160.96 R559.2 C369.1 8.44,162.51 8.05,162.9 S1.3 S1.4 ; S1.4 8.05,172.69 v1(8.08,172.72) ; S1.4 6.8,171.12 S1.2 ; v2(19.54,158.12) 19.54,160.45 20.23,161.14 v2(20.23,161.29) ; v2(69.94,47.75) 69.56,48.13 69.56,57.94 70.52,58.9 71.36,58.9 71.74,59.28 75.02,59.28 75.42,59.69 84.72,59.69 85.63,60.6 v4(87.26,60.6)
AP_VOLUME_UP_MXM_R: length 65.2
  TOP w0.102: CN9.19 21.34,164.73 22.03,164.03 22.03,162.61 21.09,161.67 21.09,160.91 22.9,159.11 27.61,159.11 v1(28.14,159.64) 28.14,160.19 34.93,166.99 34.93,175.61 39.73,180.4 49.35,180.4 50.3,181.36 55,181.36 56.91,183.26 60.55,183.26 61,183.72 63.79,183.72 R101.2
AP_VOLUME_UP_NB_R: length 3.1
  TOP w0.102: CN7.19 62.99,185.61 v1(63.31,185.29) R102.2
AU6433_RST_N: length 7.9
  TOP w0.102: R169.2 v1(14.36,133.41) 14.62,133.67 18.04,133.67 18.36,133.35 18.36,132.14 18.66,131.85 U5.2
AUDIO_INDICATE: length 242.2
  TOP w0.102: v2(48.82,75.91) 49.11,76.2 53.54,76.2 56.21,78.87 56.21,80.52 57.1,81.41 57.1,82.74 56.59,83.25 56.59,85.85 54.62,87.82 v2(54.62,89.66) ; R78.2 59.07,196.22 58.88,196.41 58.88,199.14 58.15,199.86 39.85,199.86 26.55,186.56 21.6,186.56 v2(20.71,185.67) ; v2(62.88,90.04) 62.24,90.68 62.24,96.77 62.05,96.96 62.05,99.93 57.48,104.5 57.48,114.27 43.5,128.25 43.5,138.07 43.04,138.52 43.04,142.2 40.71,144.53 40.68,144.53 38.36,146.85 36.91,146.85 v2(36.51,146.46) ; v2(49.67,57.78) 49.35,57.47 38.81,57.47 37.22,55.88 33.86,55.88 31.51,53.53 v2(31.51,52.64)
  BOTTOM w0.102: v2(62.88,90.04) 62.39,90.04 62.01,89.66 v1(58.81,89.66) 58.56,89.92 54.87,89.92 v2(54.62,89.66) ; U23.3 31.03,52.17 v2(31.51,52.64) ; v2(20.71,185.67) 20.33,185.29 20.33,182.5 20.71,182.12 20.71,173 21.25,172.47 R539.1 22.16,171.98 22.97,171.98 23.51,171.45 23.51,170.36 24.22,169.65 24.83,169.65 25.03,169.44 25.03,168.53 26.17,167.39 26.17,161.82 24.9,160.55 24.9,152.59 25.76,151.73 25.76,149.07 26.49,148.34 26.49,147.19 28.04,145.64 35.7,145.64 v2(36.51,146.46) ; v2(49.67,57.78) 49.49,57.96 49.49,64.78 49.6,64.9 49.6,66.99 48.65,67.94 48.65,70.68 48.04,71.29 48.04,74.97 48.82,75.75 v2(48.82,75.91)
AUDIO_INDICATE_MXM_R: length 7.7
  TOP w0.102: v2(24.47,170.18) 24.47,169.85 25.59,168.73 CN9.26
  BOTTOM w0.102: R539.2 23.14,172.47 23.71,171.9 23.71,170.71 24.24,170.18 v2(24.47,170.18) 24.78,170.18 v1(25.79,169.16)
AUDIO_INDICATE_NB_R: length 4.8
  TOP w0.102: CN7.26 59.07,192.86 R78.1 59.5,194.9 59.61,195.01 59.61,196.94 v1(59.51,197.04)
AUDIO_MUTE: length 273
  TOP w0.102: R79.2 60.21,196.21 60.08,196.34 60.08,197.36 59.19,198.25 59.19,199.2 58.33,200.06 39.55,200.06 26.27,186.79 20.81,186.79 v2(20.08,186.06) 18.9,186.06 16.39,183.55 16.39,168.21 v2(16.46,168.15) ; v2(5.09,148.34) 5.47,147.96 5.47,116.9 19.12,103.25 19.12,90.81 18.81,90.49 18.81,83.06 19.51,82.36 19.51,75.82 16.65,72.96 13.47,72.96 12.58,72.07 12.58,48.13 14.49,46.23 14.49,44.96 14.81,44.64 v2(14.81,43.5) ; v2(14.67,168.15) 14.67,162.43 13.68,161.44 13.68,160.82 13.97,160.53 16.88,160.53 18.4,159 20.29,159 21.56,157.74 21.56,155.53 20.78,154.75 12.65,154.75 v2(11.89,153.99)
  BOTTOM w0.102: v2(5.09,148.34) 7.88,148.34 9.79,150.24 9.79,153.54 10.23,153.99 v2(11.89,153.99) ; v2(14.67,168.15) v1(15.66,168.15) v2(16.46,168.15) ; R554.2 21.19,171.45 20.46,172.19 20.46,181.99 20.08,182.37 v2(20.08,186.06) ; v2(14.81,43.5) 12.84,41.53 12.84,37.02 15.12,34.73 15.12,31.75 11.6,28.22 11.6,24.16 11.24,23.8 R987.1 11.24,20.65 11.34,20.55 12.08,20.55 12.25,20.37 12.25,19.43 12.07,19.25 U26.1
AUDIO_MUTE_AMP_CTRL: length 7.5
  BOTTOM w0.102: v1(9.03,21.54) 8.89,21.68 R980.1 R987.2 10.17,22.34 U26.4 10.17,21.25 10.17,20.19 9.92,19.94 9.09,19.94 8.83,19.68 Q65.G
AUDIO_MUTE_MXM_R: length 8.7
  TOP w0.102: v2(24.52,169.04) 24.52,168.78 25.58,167.73 CN9.25
  BOTTOM w0.102: v2(24.52,169.04) 23.3,170.26 23.3,170.94 22.79,171.45 R554.1 22.54,171.05 22.36,170.88 20.52,170.88 v1(20.08,171.32)
AUDIO_MUTE_NB_R: length 6.6
  TOP w0.102: CN7.25 59.99,194.68 R79.1 60.21,194.92 60.7,195.41 60.7,196.22 60.4,196.51 60.4,197.55 60.21,197.74 v1(60.21,198.88)
AUX_CAL: length 18.2
  TOP w0.1: 57.86,158.03 57.88,157.99 57.88,157.95
  TOP w0.102: U3.C8 57.97,156.93 57.97,157.79 57.97,157.8 57.92,157.85 57.88,157.95 ; 57.11,158.93 57.86,158.18 57.86,158.03 ; v1(44.84,163.45) 44.79,163.4 R144.2
  TOP w0.125: 57.11,158.93 56.83,158.93 54.39,161.37 50.54,161.37 49.4,162.51 47.14,162.51 46.86,162.23 46.06,162.23 46.05,162.24 46.04,162.23 R144.2
AUX_MUX: length 11.2
  TOP w0.102: U10.AF1 103.64,55.12 103.9,54.86 104.53,54.86 105.17,54.23 105.17,51.18 105.55,50.8 v2(105.55,46.96)
  BOTTOM w0.102: v2(105.55,46.96) 105.62,46.89 TP203.1
AV_MODE: length 319.1
  TOP w0.102: v2(21.5,185.52) 22.31,186.33 26.68,186.33 40,199.66 56.64,199.66 57.29,199.01 57.29,198.06 58.05,197.29 R77.2 ; v2(84.08,39.04) 84.29,39.24 84.29,40.94 82.61,42.62 82.61,46.3 81.54,47.37 81.54,48.2 82.21,48.86 82.21,49.69 86.84,54.32 U10.D1 ; v2(24.52,48.01) 23.94,48.01 23.37,48.57 23.37,49.51 22.49,50.39 20.61,50.39 16.39,54.61 15.82,54.61 15.12,55.31 15.12,57.53 17.66,60.07 17.66,63.56 19.19,65.09 v2(20.65,65.09) ; v2(53.54,57.53) 52.91,58.17 50.94,58.17 49.86,57.09 39.25,57.09 37.54,55.37 34.05,55.37 32,53.33 32,52.44 31.7,52.13 31.06,52.13 30.87,51.94 30.87,48.2 30.68,48.01 28.59,48.01 28.27,48.32 v2(27.38,48.32) ; v2(25.47,154.05) v2(13.75,154.05)
  BOTTOM w0.102: v2(84.08,39.04) 83.63,38.58 65.03,38.58 63.38,40.23 63.38,44.26 63.75,44.63 63.75,52.44 v1(62.88,53.31) 62.88,53.64 60.26,56.26 58.15,56.26 57.24,57.18 53.9,57.18 v2(53.54,57.53) ; v2(20.65,65.09) 21.45,65.89 21.45,68.49 21.91,68.95 21.91,80 23.94,82.03 23.94,102.82 13.27,113.49 13.27,128.09 11.31,130.05 11.31,146.89 13.98,149.56 13.98,153.82 v2(13.75,154.05) ; v2(24.52,48.01) 27.06,48.01 v2(27.38,48.32) ; v2(21.5,185.52) 21.5,185.45 20.58,184.53 20.58,182.63 20.97,182.25 20.97,173.74 21.22,173.48 R538.1 22.19,172.97 23,172.97 23.91,172.06 23.91,170.81 24.06,170.66 25.25,170.66 26.74,169.16 26.74,168.4 26.43,168.08 26.43,161.77 25.16,160.5 25.16,154.37 v2(25.47,154.05)
AV_MODE_MXM_R: length 7.3
  TOP w0.102: CN9.27 25.63,169.73 24.98,170.38 24.98,170.56 v2(24.39,171.15)
  BOTTOM w0.102: R538.2 23.12,173.48 24.39,172.21 v2(24.39,171.15) 25.82,171.15 v1(25.87,171.09)
AV_MODE_NB_R: length 6.3
  TOP w0.102: CN7.27 57.99,193.94 58.05,194 R77.1 58.38,194.9 58.56,195.07 58.56,197.36 58.3,197.61 v1(58.3,198.56)
AZ_BIT_CLK: length 93.9
  TOP w0.102: v3(31.56,50.67) 31.95,50.67 32.95,51.68 32.95,52.82 34.55,54.42 37.81,54.42 39.27,55.88 50.94,55.88 51.32,56.26 v2(51.32,57.59) ; C247.2 v2(28.97,50.8) ; R339.1 93.48,44.17 94.45,43.21 v2(94.45,42.19)
  BOTTOM w0.102: v2(51.32,57.59) 51.32,56.07 51.73,55.66 56.34,55.66 57.19,54.81 59.24,54.81 62.01,52.04 62.01,39.66 64.46,37.21 84.29,37.21 86.04,38.97 93.15,38.97 94.63,40.45 v1(94.63,41.02) 94.82,41.21 94.82,41.82 v2(94.45,42.19) ; v3(31.56,50.67) 31.56,50.67 U23.6 29.42,50.67 29.28,50.8 v2(28.97,50.8)
AZ_BIT_CLK_R: length 12.3
  TOP w0.102: R339.2 93.48,45.75 v1(94.29,46.56) 93.99,46.85 93.99,47.8 R408.1 93.69,48.51 93.69,52.39 93.74,52.44 93.74,56.14 93.24,56.63 U10.M3
AZ_RST_N: length 99.5
  TOP w0.102: v2(52.84,56.52) 52.84,55.94 51.94,55.04 39.51,55.04 37.94,53.47 35,53.47 33.94,52.41 33.94,51.14 31.95,49.15 31.95,48.64 31.62,48.31 v3(31.37,48.31) ; R441.1 96.02,43 96.02,45.13 C279.1 96.53,46.51 v2(96.4,46.63) 96.53,46.76 R329.1
  BOTTOM w0.102: v2(52.84,56.52) 52.86,56.52 53.1,56.27 56.87,56.27 57.8,55.35 59.45,55.35 62.52,52.27 62.52,39.87 64.67,37.72 84.08,37.72 85.86,39.5 92.41,39.5 93.42,40.51 93.42,43.69 95.45,45.72 95.96,45.72 96.4,46.16 v2(96.4,46.63) ; v1(31.89,46.04) 31.89,47.24 31.37,47.76 v3(31.37,48.31) 31.3,48.24 30.2,48.24 U23.11
AZ_RST_R_N: length 9.2
  TOP w0.102: R329.2 96.53,48.84 v1(96.18,49.2) 96.05,49.2 94.55,50.7 94.55,51.63 95.01,52.09 95.01,54.38 94.54,54.85 94.54,55.49 94.84,55.79 U10.P2
AZ_SDATA_IN0: length 10.1
  TOP w0.102: R403.1 90.12,49.15 91.41,50.44 92.19,50.44 v1(92.31,50.57) 92.82,51.08 92.82,53.09 92.95,53.21 92.95,54.83 92.69,55.09 92.69,55.49 92.84,55.72 92.84,56.05 92.44,56.45 U10.L2
AZ_SDATA_IN1: length 16.2
  TOP w0.102: U10.M2 93.17,55.93 93.11,55.78 92.91,55.43 92.91,55.18 93.23,54.86 93.23,52.9 93.1,52.77 93.1,49.3 92.6,48.8 91.81,48.8 91.45,48.44 R406.1 91.45,48.28 91.96,47.77 91.96,45.2 92.83,44.33 92.83,43.84 92.97,43.69 R379.1 93.06,42.93 v1(93.87,42.93)
AZ_SDATA_IN1_R: length 87.8
  TOP w0.102: R379.2 93.59,41.99 v2(93.99,41.59) ; v2(51.95,57.15) 51.95,55.94 51.59,55.58 39.32,55.58 37.85,54.1 34.75,54.1 33.3,52.65 33.3,51.45 31.63,49.78 v3(31.38,49.78)
  BOTTOM w0.102: U23.8 31.27,49.67 v3(31.38,49.78) ; v2(51.95,57.15) 51.95,56.2 52.21,55.94 56.42,55.94 57.3,55.07 59.34,55.07 62.27,52.15 62.27,39.76 64.56,37.47 84.18,37.47 85.95,39.24 92.66,39.24 93.99,40.56 v2(93.99,41.59)
AZ_SDATA_IN2: length 10.7
  TOP w0.102: U10.M1 93.51,55.05 93.51,52.67 93.38,52.54 93.38,49.04 92.65,48.31 R407.1 92.47,48.28 92.97,47.78 92.97,46.11 92.56,45.69 v1(92.55,45.69)
AZ_SDATA_OUT: length 96.2
  TOP w0.102: R436.1 94.75,40.64 95.01,40.89 v2(95.01,42.95) 95.01,45.13 R340.2 94.5,45.67 94.99,46.16 94.99,46.93 94.5,47.42 R327.1 ; v3(31.51,51.5) 31.95,51.5 32.62,52.16 32.62,52.99 34.36,54.74 37.77,54.74 39.23,56.2 50.37,56.2 v2(50.68,56.52)
  BOTTOM w0.102: U23.5 31.18,51.17 v3(31.51,51.5) ; v2(95.01,42.95) 95.01,42.93 95.26,42.67 95.26,40.58 93.28,38.59 86.03,38.59 84.39,36.96 64.35,36.96 61.76,39.55 61.76,51.94 59.16,54.53 57.11,54.53 56.26,55.38 52.47,55.38 v1(51.95,54.86) 50.68,56.13 v2(50.68,56.52)
AZ_SDOUT_R: length 7.7
  TOP w0.102: R327.2 94.5,49.4 v1(94.27,49.63) 93.95,49.95 93.95,52.2 93.99,52.24 93.99,54.53 93.95,54.57 93.95,55.63 U10.N1
AZ_SYNC: length 93.6
  TOP w0.102: C255.2 95.51,46.56 v2(95.54,46.58) 95.51,46.61 R328.1 ; v3(31.35,48.96) 31.7,49.3 31.7,49.34 33.62,51.26 33.62,52.53 34.87,53.78 37.89,53.78 39.4,55.3 51.69,55.3 52.33,55.94 52.33,56.77 52.72,57.15 v2(52.72,57.53)
  BOTTOM w0.102: v2(52.72,57.53) 52.72,57.4 53.57,56.55 57,56.55 57.92,55.63 60.01,55.63 v1(60.67,54.97) 61.1,54.53 61.1,54.08 62.77,52.4 62.77,39.97 64.77,37.97 83.96,37.97 85.76,39.77 92.09,39.77 93.15,40.84 93.15,43.87 95.54,46.25 v2(95.54,46.58) ; v3(31.35,48.96) 31.06,48.67 U23.10
AZ_SYNC_R: length 9.1
  TOP w0.102: U10.N2 94.35,56.21 94.35,55.59 94.23,55.48 94.23,54.66 94.5,54.4 v2(94.5,53.59) 94.5,52.02 94.23,51.76 94.23,50.58 95.13,49.68 95.13,48.69 R328.2
BKL_PWM_R: length 32.5
  TOP w0.102: Q19.S 163.17,70.86 R299.2 R282.1 163.28,69.21 163.38,69.11 174.59,69.11 176.97,66.73 181.42,66.73 182.66,65.48 182.66,64.55 183.01,64.21 R307.1 183.01,62.18 v1(183.02,62.17) 182.95,62.1 182.95,58.36 183.4,57.91 R309.1
BLK_EN: length 2.6
  TOP w0.102: v1(181.05,61.91) 180.65,61.52 R330.1 D12.K
BLK_PWM: length 2.9
  TOP w0.102: v1(167.08,77.53) 167.14,77.47 R291.1 166.52,76.38 166.32,76.58 D11.K
BOARD_ID0: length 139.6
  TOP w0.102: v3(69.18,89.66) 69.1,89.74 69.1,92.99 73.02,96.91 85.38,96.91 87.75,94.54 102.56,94.54 104.66,92.44 115.35,92.44 116.72,91.08 116.72,80.84 117.49,80.07 117.49,77.07 118.91,75.64 134.43,75.64 136.03,74.04 141.74,74.04 v2(142.12,74.42) ; R292.2 R304.1 v2(150.89,72.14) ; U10.G24 v3(88.94,73.22)
  BOTTOM w0.102: v3(69.18,89.66) 69.53,89.31 71.85,89.31 72.15,89.6 73.54,89.6 76.4,86.74 79.58,86.74 82.33,83.99 82.33,82.04 84.75,79.63 86.3,79.63 88.15,77.79 88.15,76.96 88.91,76.2 88.91,74.9 88.48,74.47 88.48,73.68 v3(88.94,73.22) ; v2(150.89,72.14) 147.27,72.14 v1(147.01,72.39) 144.5,74.9 142.61,74.9 v2(142.12,74.42)
BOARD_ID1: length 140.3
  TOP w0.102: R305.1 R293.2 v2(153.17,71.95) ; U10.G25 v3(88.91,74.04) ; v3(69.81,89.74) 69.33,90.22 69.33,92.91 73.11,96.7 85.31,96.7 87.66,94.34 102.48,94.34 104.58,92.24 115.19,92.24 116.51,90.92 116.51,80.73 117.23,80.01 117.23,76.96 118.76,75.44 134.25,75.44 136.15,73.53 142,73.53 v2(142.89,74.42)
  BOTTOM w0.102: v3(69.81,89.74) 70.04,89.51 71.74,89.51 72.08,89.85 73.61,89.85 76.46,87 79.61,87 82.54,84.07 82.54,82.13 84.83,79.83 86.39,79.83 88.35,77.87 88.35,77.06 89.11,76.3 89.11,74.78 88.91,74.57 v3(88.91,74.04) ; v2(153.17,71.95) 152.86,71.63 146.44,71.63 v1(144.6,73.47) 143.65,74.42 v2(142.89,74.42)
BRIGHT_ADJUST: length 3.4
  TOP w0.102: CN27.8 185.11,57.9 R309.2 185.1,58.91 v1(185.3,59.12)
BT_DISABLE: length 105.6
  TOP w0.102: U10.AF20 104.02,69.72 104.4,70.1 104.6,70.1 104.85,70.36 104.85,70.74 105.04,70.93 105.8,70.93 106.31,71.44 107.07,71.44 107.58,71.95 108.34,71.95 108.53,72.14 108.53,73.47 109.54,74.47 110.75,74.47 111.8,75.52 113.04,75.52 113.52,76 113.52,76.66 113.92,77.05 113.92,86.96 113.07,87.81 112.38,87.81 110.25,89.94 103.85,89.94 101.59,92.2 86.05,92.2 83.74,94.51 74.3,94.51 73.59,93.8 70.52,93.8 69.56,92.84 69.56,90.65 70.24,89.97 70.24,88.27 69.3,87.33 69.3,86.94 69.89,86.36 69.89,85.32 67.3,82.73 64.83,82.73 v2(64.53,82.42) ; v2(51.95,77.49) 52.33,77.87 53.81,77.87 55.26,79.31 55.26,81 v2(56.4,82.14)
  BOTTOM w0.102: R658.1 51.55,77.09 v2(51.95,77.49) 51.45,78 R652.1 ; v2(64.53,82.42) v1(61.73,82.42) 56.68,82.42 v2(56.4,82.14)
BT_DISABLE_N: length 3.2
  TOP w0.102: R238.2 72.7,90.59 CN26.6 v2(72.7,88.01)
BT_DISABLE_R: length 38
  TOP w0.102: CN2.5 27.88,80.4 27.76,80.52 27.63,80.52 27.44,80.71 27.44,81.28 27.89,81.72 34.75,81.72 35.32,81.15 v2(36.46,81.15) ; CN2.51 49.48,79.95 50.05,80.52 v2(51.06,80.52) ; v2(40.52,74.93) 40.65,74.8 46.37,74.8 48.09,76.53 v2(48.27,76.53)
  BOTTOM w0.102: v2(36.46,81.15) 36.46,79.25 v1(40.02,75.69) 40.52,75.18 v2(40.52,74.93) ; R628.2 50.43,79.88 v2(51.06,80.52) ; R628.2 R652.2 ; R628.2 50.43,79.12 50.94,78.61 50.94,77.9 R658.2 48.83,77.09 v2(48.27,76.53)
BT_LED: length 38
  TOP w0.102: v2(72.78,85.98) 72.34,86.42 72.34,87.57 72.08,87.82 71.32,87.82 71.05,88.09 71.05,91.57 71.84,92.35 72.81,92.35 R239.1 ; U10.E22 87.89,71.22 88.42,70.69 88.86,70.69 v3(88.88,70.71)
  BOTTOM w0.102: v2(72.78,85.98) 72.78,84.2 76.08,80.9 77.23,80.9 79.69,78.44 79.69,76.78 v2(79.77,76.71) 78.98,75.92 78.98,75.13 79.44,74.68 80.97,74.68 v1(81.48,74.17) 82.24,73.41 83.58,73.41 84.47,72.52 84.67,72.52 85.1,72.09 85.1,71.4 86.09,70.41 88.58,70.41 v3(88.88,70.71)
CIR_BLTX_TIP_DRIVE: length 8.2
  TOP w0.102: R461.2 R460.2 ; R460.2 56.53,28.57 55.97,28.02 R469.2 54.85,27.69 54.6,27.43 Q45.C 54.79,26.86 55.08,26.57 v1(55.08,25.55) ; R460.2 R459.2
CLK_48M_CARD: length 85.1
  TOP w0.13: v2(44.78,108.2) 43.51,109.47 38.49,109.47 36.59,111.38 34.36,111.38 33.67,110.68 24.08,110.68 22.55,109.16 19.89,109.16 11,118.05 11,134.11 11.69,134.81 v1(13.03,134.81) 14.35,134.81 14.89,134.28 R166.1
  INT1 w0.114: v2(44.78,108.2) 45.35,107.63 45.35,95.38 44.71,94.74 41.73,94.74 40.52,93.54 v2(40.52,92.2)
  BOTTOM w0.13: v2(40.52,92.2) 39.95,91.63 38.56,91.63 38.11,92.08 38.11,92.73 R614.2
CLK_48M_R_CARD: length 5.7
  BOTTOM w0.13: v1(37.09,95) 36.33,95.76 35.32,95.76 35.09,95.99 U20.10 ; v1(37.09,95) 36.65,94.55 R615.1 ; v1(37.09,95) 37.67,94.42 R614.1
CLK_48M_R_USB: length 3.3
  BOTTOM w0.13: U20.11 34.59,95.92 v1(35.44,95.06) 35.63,94.87 R616.1
CLK_48M_SIO: length 89.3
  TOP w0.13: U11.1 50.51,42.16 51.45,42.16 v2(51.83,42.55)
  INT1 w0.114: v3(37.48,92.2) 38.17,91.5 43.86,91.5 43.98,91.39 43.98,90.09 44.09,89.98 44.55,89.98 44.66,90.09 44.66,91.39 44.78,91.5 45.24,91.5 45.35,91.39 45.35,90.09 45.46,89.98 45.92,89.98 46.04,90.09 46.04,91.39 46.15,91.5 47.51,91.5 48.14,90.87 48.14,86.49 48.33,86.3 48.84,86.3 49.1,86.55 49.1,89.34 49.6,89.85 51.89,89.85 52.65,89.09 52.65,88.07 47.32,82.74 47.32,75.63 42.81,71.12 42.81,65.53 v2(43.51,64.83)
  BOTTOM w0.13: v2(43.51,64.83) 43.51,64.14 v1(43.64,64.01) 43.64,63.44 45.16,61.91 45.16,58.09 44.92,57.85 44.92,49.99 44.52,49.59 44.52,46.86 46.68,44.7 49.41,44.7 50.87,43.24 51.13,43.24 v2(51.83,42.55) ; v3(37.48,92.2) 37.09,92.2 36.65,92.65 R615.2
CLK_48M_USB: length 76.2
  TOP w0.13: v2(63.51,63.53) 63.51,62.23 66.37,59.37 70.46,59.37 71.92,57.91 73.01,57.91 R324.2
  INT1 w0.114: v2(63.51,63.53) 60.56,60.58 56.4,60.58 55.13,59.31 52.21,59.31 48.65,62.87 41.92,62.87 40.9,63.88 40.9,73.66 44.97,77.72 44.97,85.22 42.68,87.5 40.52,87.5 38.43,89.6 v3(38.43,89.98)
  BOTTOM w0.13: R616.2 35.63,92.52 v1(36.27,91.88) 36.71,91.44 37.73,91.44 38.43,90.74 v3(38.43,89.98)
CLK_100M_NBGFX_DN: length 71.3
  TOP w0.099: v2(43.64,144.59) 43.76,144.59 43.95,144.78 43.95,145.11 44.26,145.41 46.24,145.41 46.59,145.06 49.62,145.06 50.09,145.53 50.6,145.53 51.07,146.01 52.79,146.01 U3.T1 ; v5(39.13,113.22) 39.13,112.54 R253.1
  INT1 w0.089: v5(39.13,113.22) 38.74,113.61 38.74,116.11 41.1,118.47 41.1,121.35 39.72,122.73 39.72,138.33 38.8,139.25 38.8,142.8 41.35,145.35 43.64,145.35 43.96,145.03 43.96,144.91 v2(43.64,144.59)
  BOTTOM w0.099: R588.2 28.24,109.49 28.24,109.8 27.93,110.11 26.11,110.11 25.47,110.74 25.47,113.07 27.02,114.62 38.36,114.62 38.75,114.24 38.75,113.6 v5(39.13,113.22)
CLK_100M_NBGFX_DP: length 71.7
  TOP w0.099: v2(38.11,113.22) 38.11,112.54 R248.1 ; U3.T2 53.27,146.06 52.97,145.75 51.18,145.75 50.7,145.28 50.19,145.28 49.72,144.81 46.49,144.81 46.13,145.16 44.36,145.16 44.21,145.01 44.21,144.78 44.4,144.59 v2(44.52,144.59)
  INT1 w0.089: v2(38.11,113.22) 38.5,113.61 38.5,116.21 40.85,118.57 40.85,121.25 39.48,122.63 39.48,138.23 38.56,139.15 38.56,142.9 41.25,145.59 43.74,145.59 44.2,145.13 44.2,144.91 v2(44.52,144.59)
  BOTTOM w0.099: R587.2 28.49,109.49 28.49,109.91 28.03,110.36 26.21,110.36 25.73,110.85 25.73,112.97 27.13,114.36 38.26,114.36 38.49,114.13 38.49,113.6 v2(38.11,113.22)
CLK_100M_NBGFX_R_DN: length 4.3
  BOTTOM w0.099: 27.74,107 28.24,107.5 28.24,107.81 R588.1 ; 27.74,107 v1(27.7,107) ; 27.74,107 28.08,107 28.27,106.81 28.27,106.45 28.71,106 28.71,105.85 28.59,105.73 U20.34
CLK_100M_NBGFX_R_DP: length 4.1
  BOTTOM w0.099: R587.1 28.49,107.81 28.49,107.47 v1(28.97,107) 28.71,107 28.52,106.81 28.52,106.55 28.97,106.11 28.97,105.85 29.09,105.73 U20.35
CLK_100M_NBHT_DN: length 134.7
  TOP w0.099: v3(71.64,156.9) 71.64,156.86 U3.C24
  INT1 w0.089: v5(43.55,107.89) 43.55,107.57 43.35,107.37 42.63,107.37 42.17,107.82 42.17,109.69 39.47,112.39 37.88,112.39 37.4,112.88 37.4,122.52 37.65,122.77 37.65,137.72 36.46,138.91 36.46,144.42 35.75,145.13 35.75,160.11 40.38,164.75 40.38,171.41 49.56,180.59 52.63,180.59 53.7,179.53 57.07,179.53 57.82,180.28 60.23,180.28 60.93,180.97 67.23,180.97 68.19,180.02 71.38,180.02 72.54,178.87 72.54,164.83 73.68,163.69 73.68,162.15 71.9,160.37 71.9,157.04 71.75,156.9 v3(71.64,156.9)
  BOTTOM w0.099: v5(43.55,107.89) 43.55,107.61 43.32,107.38 42.86,107.38 R590.1
CLK_100M_NBHT_DP: length 135.9
  TOP w0.099: v3(72.45,156.87) 72.04,156.46 U3.C25
  INT1 w0.089: v3(72.45,156.87) 72.31,156.87 72.14,157.04 72.14,160.27 73.92,162.05 73.92,163.79 72.78,164.93 72.78,178.97 71.48,180.26 68.29,180.26 67.33,181.22 60.83,181.22 60.13,180.52 57.72,180.52 56.97,179.77 53.8,179.77 52.73,180.84 49.46,180.84 40.14,171.51 40.14,164.85 35.51,160.21 35.51,145.03 36.22,144.32 36.22,138.81 37.41,137.62 37.41,122.87 37.16,122.62 37.16,112.78 37.78,112.15 39.37,112.15 41.93,109.59 41.93,107.72 42.53,107.13 43.35,107.13 43.55,106.93 v2(43.55,106.62)
  BOTTOM w0.099: R591.1 42.86,107.12 43.32,107.12 43.55,106.89 v2(43.55,106.62)
CLK_100M_NBHT_R_DN: length 4.9
  BOTTOM w0.099: U20.55 39.09,105.95 39.25,106.11 39.25,106.55 39.95,107.25 40.59,107.25 40.65,107.31 v1(40.65,107.85) 40.8,107.7 41.56,107.7 R590.2
CLK_100M_NBHT_R_DP: length 4.1
  BOTTOM w0.099: R591.2 40.84,106.74 v1(40.65,106.55) 40.65,106.62 40.27,107 40.06,107 39.51,106.45 39.51,106.03 39.59,105.95 U20.56
CLK_100M_PCIE_LAN_DN: length 157.9
  INT1 w0.089: v5(51.82,92.42) 51.31,91.91 50.79,91.91 50.12,92.58 42.56,92.58 v2(42.3,92.84)
  BOTTOM w0.099: R619.2 29.92,92.79 29.92,92.52 31.06,91.38 33.22,91.38 35.63,88.96 38.36,88.96 41.92,92.52 42.05,92.52 42.3,92.77 v2(42.3,92.84) ; U24.20 119.31,30.96 119.22,30.86 118.4,30.86 117.66,30.12 115.5,30.12 114.72,30.91 114.72,33.2 112.89,35.03 99.02,35.03 97.52,33.53 89.16,33.53 88.02,32.38 86.21,32.38 85.71,31.88 68.46,31.88 67.32,33.02 63.09,33.02 58.24,37.87 58.24,42.44 48.27,52.41 48.27,63.63 46.87,65.02 46.87,71.45 47.32,71.89 47.32,77.56 49.67,79.91 49.67,83.97 52.67,86.97 52.67,91.69 52.45,91.91 51.98,91.91 51.82,92.07 v5(51.82,92.42)
CLK_100M_PCIE_LAN_DP: length 158.3
  INT1 w0.089: v2(51.82,91.15) 51.31,91.67 50.69,91.67 50.02,92.34 42.56,92.34 v2(42.3,92.08)
  BOTTOM w0.099: v2(51.82,91.15) 51.82,91.5 51.98,91.66 52.34,91.66 52.41,91.59 52.41,87.08 49.41,84.08 49.41,80.01 47.06,77.66 47.06,72 46.62,71.55 46.62,64.92 48.02,63.52 48.02,52.3 57.99,42.33 57.99,37.77 62.99,32.77 67.22,32.77 68.36,31.62 85.81,31.62 86.32,32.13 88.12,32.13 89.27,33.28 97.63,33.28 99.13,34.77 112.78,34.77 114.46,33.09 114.46,30.81 115.4,29.87 117.77,29.87 118.5,30.61 119.26,30.61 119.31,30.56 U24.19 ; R620.2 29.67,92.79 29.67,92.41 30.96,91.12 33.12,91.12 35.53,88.71 38.47,88.71 42.03,92.27 42.17,92.27 42.3,92.14 v2(42.3,92.08)
CLK_100M_PCIE_LAN_R_DN: length 4
  BOTTOM w0.099: R619.1 29.92,94.41 29.92,94.57 30.02,94.68 30.55,94.68 31.47,95.59 31.47,96.14 31.59,96.26 U20.17
CLK_100M_PCIE_LAN_R_DP: length 4
  BOTTOM w0.099: R620.1 29.67,94.41 29.67,94.68 29.92,94.93 30.45,94.93 31.21,95.69 31.21,96.14 31.09,96.26 U20.18
CLK_100M_PCIE_TUNER_DN: length 110.3
  TOP w0.099: v2(28.5,18.16) 29,17.65 29,15.47 28.73,15.2 CN5.11
  INT1 w0.089: v5(28.01,92.14) 27.75,91.88 27.75,90.9 28.26,90.4 28.26,86.77 27.49,86.01 27.49,82.83 25.98,81.32 25.98,77.19 25.46,76.67 25.46,69.57 27.37,67.66 27.37,66.01 30.41,62.97 30.41,59.22 34.3,55.33 34.3,50.42 35.7,49.02 39.51,49.02 41.48,47.05 41.48,44.64 40.7,43.87 40.7,41.87 38.72,39.89 36.33,39.89 34.67,38.23 34.67,33.81 34.3,33.44 34.3,26.27 30.84,22.81 28.49,22.81 26.02,25.27 25.12,25.27 24.52,24.68 24.52,20.92 25.66,19.77 25.66,18.18 26.32,17.53 28.75,17.53 29.01,17.78 29.01,17.96 28.81,18.16 v2(28.5,18.16)
  BOTTOM w0.099: v5(28.01,92.14) 28.01,92.15 27.76,92.4 27.76,92.79 R621.2
CLK_100M_PCIE_TUNER_DP: length 111.1
  TOP w0.099: CN5.13 29.53,15.2 29.26,15.47 29.26,17.65 v2(29.77,18.16)
  INT1 w0.089: v2(29.77,18.16) 29.44,18.16 29.25,17.97 29.25,17.68 28.85,17.28 26.22,17.28 25.42,18.08 25.42,19.67 24.28,20.82 24.28,24.78 25.02,25.51 26.12,25.51 28.59,23.05 30.74,23.05 34.06,26.37 34.06,33.54 34.43,33.91 34.43,38.33 36.23,40.13 38.62,40.13 40.46,41.97 40.46,43.97 41.24,44.74 41.24,46.95 39.41,48.78 35.6,48.78 34.06,50.32 34.06,55.23 30.17,59.12 30.17,62.87 27.13,65.91 27.13,67.56 25.22,69.47 25.22,76.77 25.74,77.29 25.74,81.42 27.25,82.93 27.25,86.11 28.01,86.87 28.01,90.3 27.51,90.8 27.51,91.81 v2(27.19,92.14)
  BOTTOM w0.099: v2(27.19,92.14) 27.25,92.15 27.51,92.4 27.51,92.79 R622.2
CLK_100M_PCIE_TUNER_R_DN: length 3.7
  BOTTOM w0.099: U20.23 28.59,96.26 28.47,96.14 28.47,95.66 27.63,94.83 27.63,94.82 27.64,94.82 27.64,94.17 27.78,94.03 R621.1
CLK_100M_PCIE_TUNER_R_DP: length 3.4
  BOTTOM w0.099: R622.1 27.38,94.28 27.38,94.71 27.38,94.71 27.38,94.93 28.21,95.77 28.21,96.14 28.09,96.26 U20.24
CLK_100M_PCIE_WLAN_DN: length 22.8
  TOP w0.099: v2(30.16,81.18) 30.55,80.79 30.55,80.28 30.28,80 CN2.11
  BOTTOM w0.099: R623.2 25.73,92.92 25.73,92.39 v1(26.24,91.88) 25.73,91.38 25.73,90.87 27.44,89.15 27.44,85.34 30.55,82.23 31.95,82.23 32.66,81.52 32.66,80.4 32.01,79.76 31.13,79.76 30.48,80.4 30.48,80.87 v2(30.16,81.18)
CLK_100M_PCIE_WLAN_DP: length 22
  TOP w0.099: CN2.13 31.08,80 30.81,80.28 30.81,80.94 v2(31.05,81.18)
  BOTTOM w0.099: v2(31.05,81.18) 30.73,80.87 30.73,80.51 31.23,80.01 31.91,80.01 32.41,80.51 32.41,81.42 31.85,81.98 30.45,81.98 27.19,85.24 27.19,89.05 25.47,90.76 25.47,91.38 v1(24.97,91.88) 25.47,92.39 25.47,92.71 25.01,93.17 R624.2
CLK_100M_PCIE_WLAN_R_DN: length 4.5
  BOTTOM w0.099: R623.1 25.73,94.28 25.73,95.14 25.96,95.38 27.16,95.38 27.46,95.68 27.46,96.14 27.59,96.26 U20.25
CLK_100M_PCIE_WLAN_R_DP: length 4.7
  BOTTOM w0.099: U20.26 27.09,96.26 27.21,96.14 27.21,95.79 27.06,95.63 25.86,95.63 25.47,95.25 25.47,94.23 25.27,94.03 R624.1
CLK_200M_CPU_DN: length 222.5
  TOP w0.127: v2(110.35,181.5) 110.67,181.18 110.67,180 C85.1
  INT1 w0.102: v2(37.98,111.3) 38.45,111.3 38.62,111.12 38.62,110.78 38.33,110.49 37.86,110.49 36.45,111.9 36.45,121.89 35.92,122.42 34.65,122.42 33.4,123.67 33.4,145.44 31.19,147.65 31.19,157.57 39.51,165.88 39.51,173.84 47.67,182 56.74,182 57.39,181.36 59.72,181.36 60.25,181.88 68.68,181.88 69.44,181.11 81.01,181.11 84.9,185 84.9,202.66 86.53,204.29 89.77,204.29 92.53,207.05 92.53,212.96 95.42,215.85 102.83,215.85 105.05,218.07 110.96,218.07 116.53,212.5 116.53,203.07 113.29,199.83 113.29,193.83 112.04,192.57 112.04,188.76 110.61,187.33 110.61,181.76 v2(110.35,181.5)
  BOTTOM w0.127: v2(37.98,111.3) 38.19,111.09 R596.2 38.46,110.28 38.46,109.81 R586.2
CLK_200M_CPU_DN_R: length 5.4
  BOTTOM w0.127: U20.50 36.59,105.97 36.69,106.08 36.69,106.41 37.32,107.03 38.18,107.03 38.48,107.32 38.48,107.57 38.35,107.7 v1(37.92,107.7) 38.11,107.89 R586.1
CLK_200M_CPU_DP: length 223.9
  TOP w0.127: v2(111.11,181.5) 110.96,181.35 110.96,180.21 111.34,179.83 C86.1
  INT1 w0.102: v2(111.11,181.5) 110.85,181.76 110.85,187.23 112.28,188.66 112.28,192.47 113.54,193.73 113.54,199.73 116.77,202.97 116.77,212.6 111.06,218.31 104.95,218.31 102.73,216.09 95.32,216.09 92.29,213.06 92.29,207.15 89.67,204.53 86.43,204.53 84.66,202.76 84.66,185.1 80.91,181.36 69.54,181.36 68.78,182.12 60.15,182.12 59.62,181.6 57.49,181.6 56.84,182.25 47.57,182.25 39.27,173.94 39.27,165.98 30.95,157.67 30.95,147.55 33.16,145.34 33.16,123.57 34.55,122.17 35.82,122.17 36.21,121.79 36.21,111.8 37.76,110.25 38.43,110.25 38.86,110.68 38.86,110.9 v5(39.25,111.3)
  BOTTOM w0.127: R585.2 38.75,109.84 38.75,110.25 R596.1 39.05,111.09 v5(39.25,111.3)
CLK_200M_CPU_DP_R: length 5.1
  BOTTOM w0.127: U20.51 37.09,105.97 36.98,106.08 36.98,106.29 37.43,106.74 38.3,106.74 38.76,107.2 38.76,107.27 v1(39.19,107.7) 39.13,107.76 R585.1
CLK_ICH_RTCX1: length 15.7
  TOP w0.102: Y1.2 96.12,87.09 94.42,85.4 C187.2 R250.1 93.12,81.23 v1(93.1,81.2) 93.1,80.35 92.21,79.46 92.21,77.72 92.09,77.6 92.09,76.79 92.14,76.74 92.14,76.74 92.15,76.73 92.15,76.3 92.14,76.29 92.14,75.99 92.31,75.81 92.45,75.81 92.8,75.46 92.8,75.23 92.44,74.88 U10.L26
CLK_ICH_RTCX2: length 14.1
  TOP w0.102: U10.L27 92.44,75.53 92.36,75.61 92.23,75.61 91.93,75.91 91.93,76.38 91.94,76.39 91.94,76.64 91.93,76.65 91.93,76.66 91.86,76.73 91.86,80.21 92.28,80.63 v1(92.28,82.99) 92.28,84.03 R250.2 C205.2 90.96,85.88 Y1.1
CLK_PCI_33M_DEBUG: length 103.4
  TOP w0.102: R281.1 38.42,77.09 39.28,76.23 39.28,75.16 40.08,74.36 47.06,74.36 47.45,74.74 v2(48.59,74.74) ; v2(100.51,41.96) 100.91,42.36 R396.2
  BOTTOM w0.102: v2(100.51,41.96) 99.39,41.96 94.97,37.55 86.42,37.55 84.58,35.71 64.03,35.71 60.54,39.2 60.54,44.01 57.48,47.07 57.48,48.39 50.05,55.82 50.05,56.77 50.68,57.4 50.68,58.24 50.25,58.67 50.25,64.38 50.3,64.43 50.3,67.5 50.05,67.75 v1(50.05,68.45) 50.05,70.94 49.08,71.91 49.08,74.25 v2(48.59,74.74)
CLK_PCI_33M_DEBUG_R: length 3.6
  TOP w0.102: v1(37.05,75.86) 37.05,75.86 R281.2 36.68,77.45 CN2.19
CLK_PCI_33M_SIO: length 80.9
  TOP w0.102: v3(57.01,52.96) 57.01,52.9 53.19,49.08 53.19,45.05 51.6,43.47 51.6,43.4 50.75,42.55 50.24,42.55 50.11,42.42 U11.2 ; R425.1 101.61,46.48 v2(101.74,46.61) 101.93,46.8 R397.2
  BOTTOM w0.102: v3(57.01,52.96) 58.96,52.96 59.12,52.81 60.01,52.81 60.79,52.02 v1(60.79,51.21) 61.14,50.86 61.14,39.26 64.08,36.32 84.62,36.32 86.25,37.96 94.77,37.96 100.72,43.91 100.72,45.21 101.15,45.64 R425.1 101.61,46.48 v2(101.74,46.61)
CLK_REQ1_N: length 1.8
  TOP w0.102: U10.AB18 100.14,67.84 v3(99.78,67.49)
  BOTTOM w0.102: TP199.1 99.78,67.66 v3(99.78,67.49)
CLK_REQ2_N: length 9
  TOP w0.102: TP95.1 111.64,72.64 109.23,70.23 106.28,70.23 106.23,70.19 105.9,70.19 105.57,70.52 U10.AH21
CLK_REQG_N: length 16.7
  TOP w0.13: U10.AA20 100.02,69.62 v3(100.14,69.49)
  BOTTOM w0.13: R660.2 112.1,73.22 111.45,72.57 111.45,72.33 111.01,71.88 109.68,71.88 109.12,72.44 R655.1 108.72,72.06 v1(108.72,71.31) 108.72,71.25 108.27,70.79 106.13,70.79 104.33,68.99 100.65,68.99 v3(100.14,69.49)
CLK_VDD: length 26.9
  TOP w0.381: v2(30.11,95.63) 32.52,93.22 38.56,93.22 38.87,92.9 ; C167.1 40.6,93.54 39.97,92.9 38.87,92.9 ; 38.87,92.9 v2(38.87,92.2)
  TOP w0.508: v2(26.59,103.86) 26.59,102.89 C157.1 ; v2(39.83,95.69) 40.52,95 C183.1 C167.1
  BOTTOM w0.254: v2(39.83,95.69) 39.59,95.93 U20.1 ; U20.37 30.09,103.8 v2(29.98,103.7) ; v2(29.35,95.63) 29.59,95.87 U20.21 ; U20.30 v2(26.59,103.86) ; v2(32.21,103.57) 32.59,103.95 U20.42 ; v2(30.11,95.63) 30.09,95.65 U20.20 ; U20.49 36.09,103.9 v2(35.82,103.63)
  BOTTOM w0.381: v2(38.87,92.2) 38.68,92.39 R606.1
  vias: v1(27.25,96.14) v1(28.4,103.44)
CLK_VDD48: length 9.7
  TOP w0.508: v2(35.06,98.42) 35.01,98.38 C176.1 C178.1 C182.1 34.44,95 34.17,95.26 C168.1 ; C168.1 32.22,95.26 v1(32.21,95.25) ; C168.1 33.49,95.31 L19.2
  BOTTOM w0.254: U20.9 35.59,97.77 35.06,98.3 v2(35.06,98.42)
CLK_VDDA: length 7.4
  TOP w0.508: v2(34.55,106.93) 34.05,107.44 v1(34.05,107.95) 34.11,108.01 C151.1
  BOTTOM w0.254: 34.36,106.74 34.34,106.74 34.09,106.49 U20.45
  BOTTOM w0.508: 34.36,106.74 v2(34.55,106.93) 34.94,107.31 C440.1 36.36,108.09 L50.2
CLK_VDDREF: length 9.5
  TOP w0.508: v1(39.13,98.17) 39.01,98.05 C165.1 ; C165.1 39.01,95.03 C174.1 C173.1 C172.1 37.22,95.25 v2(37.59,95.62) ; C165.1 40.51,96.84 L18.2
  BOTTOM w0.254: U20.5 v2(37.59,95.62)
CLK_XTAL_IN: length 13.3
  BOTTOM w0.102: U20.7 36.59,98.55 36.71,98.68 36.71,99.31 38.17,100.77 39.63,100.77 39.88,100.53 C442.1 41.26,100.57 44.04,100.57 44.4,100.21 Y4.1
CLK_XTAL_OUT: length 14.7
  BOTTOM w0.102: U20.8 36.09,97.91 35.7,98.3 35.7,99.76 37.67,101.73 39.89,101.73 40.32,102.16 C443.1 44.07,102.16 44.4,102.49 Y4.2
CLPCLK0_R: length 14.2
  TOP w0.102: v3(90.68,73.38) 90.63,73.3 U10.H24
  BOTTOM w0.102: v1(91.63,73.15) 91.4,73.38 v3(90.68,73.38) 90.68,73.65 91.03,74.01 91.03,76.77 86.85,80.95 86.32,80.95 84.72,82.55 R636.1
CLPCLK1_R: length 13.1
  TOP w0.102: v3(90.45,74.05) 90.45,73.93 90.14,73.62 U10.H25
  BOTTOM w0.102: v3(90.45,74.05) 90.82,74.42 90.82,76.55 86.72,80.65 85.43,80.65 v1(84.89,81.19) R637.1
CMOS_CLR: length 4.4
  TOP w0.102: J4.5 145.74,78.72 R274.1
  BOTTOM w0.102: v1(147.36,79.65) 147,80.01 J4.5
CMOS_PW_CLR: length 6.9
  TOP w0.102: J4.6 147.97,79.79 R260.1
  BOTTOM w0.102: v1(147.33,82.27) 147.07,82.01 J4.6
COM1_C1N: length 2.5
  TOP w0.102: v2(146.44,16.76) 145.69,16.76 145.59,16.66 U16.14
  BOTTOM w0.102: v2(146.44,16.76) 145.73,16.05 C545.2
COM1_C1P: length 3.3
  TOP w0.102: U16.12 144.26,16.23 144.26,17.18 v2(144.6,17.53)
  BOTTOM w0.102: C545.1 144.94,15.95 144.94,17.18 v2(144.6,17.53)
COM1_C2N: length 6.5
  TOP w0.102: v1(146.54,28.07) 146.57,28.04 C305.2 146.11,26.97 146,26.86 146,25.87 146.49,25.37 146.49,24.82 146.31,24.64 145.1,24.64 144.94,24.48 U16.16
COM1_C2P: length 3.7
  TOP w0.102: U16.15 146.5,23.68 v1(146.7,23.88) 146.94,24.12 146.94,25.71 146.57,26.09 C305.1
COM1_CTS_N: length 111.6
  TOP w0.102: v2(46.11,42.8) 46.09,42.8 45.71,42.42 U11.13 ; U16.22 141.04,24.46 140.57,24.92 140.57,25.25 140.98,25.65 R493.1 140.55,26.05 140.41,26.19 v2(140.41,28.7)
  INT1 w0.089: v2(46.11,42.8) 46.11,42.3 46.69,41.72 49.73,41.72 50.18,41.27 51.19,41.27 52.16,40.3 54.85,40.3 55.74,39.41 61.25,39.41 62.58,38.08 90.64,38.08 92.04,36.68 112.71,36.68 114.74,38.72 117.19,38.72 118.69,37.21 135.9,37.21 138,35.12 138,31.56 140.41,29.15 v2(140.41,28.7)
COM1_DCD_N: length 134.8
  TOP w0.102: v2(142.25,14.61) 141.69,15.17 U16.8 141.69,16.95 141.17,17.46 141.17,18.48 140.54,19.11 135.96,19.11 134.88,20.19 134.38,20.19 v2(134,20.57) ; U11.19 43.91,39.66 44.21,39.37 v2(44.59,39.37)
  INT1 w0.089: v2(44.59,39.37) 44.33,39.12 44.33,38.1 44.59,37.85 46.49,37.85 46.75,38.1 47.19,38.1 47.45,38.35 47.45,38.73 47.95,39.24 49.6,39.24 50.11,39.75 50.87,39.75 52.53,38.1 60.7,38.1 62.03,36.77 84.7,36.77 86.16,35.31 116.34,35.31 116.98,35.94 135.27,35.94 136.92,34.29 136.92,31.24 135.27,29.59 135.27,26.29 136.03,25.53 138.31,25.53 138.69,25.15 138.69,24.13 137.74,23.18 137.74,20.76 137.17,20.19 134.38,20.19 v2(134,20.57)
  BOTTOM w0.102: R754.1 141.44,15.88 141.82,15.5 141.82,15.04 v2(142.25,14.61)
COM1_DSR_N: length 131.7
  TOP w0.102: U16.5 139.74,15.39 v2(139.2,14.86) 137.04,14.86 136.03,15.88 135.14,15.88 134.82,16.19 134.82,18.92 134.63,19.11 v2(133.93,19.11) ; U11.14 45.31,40.93 45.42,40.82 45.93,40.82 46.24,40.51 46.49,40.51 v2(46.87,40.13)
  INT1 w0.089: v2(133.93,19.11) 136.85,19.11 138.12,20.38 138.12,22.92 139.08,23.88 139.08,25.4 138.5,25.97 136.22,25.97 135.65,26.54 135.65,29.34 137.42,31.11 137.42,34.54 135.52,36.45 118.31,36.45 116.85,37.91 115.07,37.91 113.04,35.88 91.7,35.88 90.31,37.27 62.24,37.27 60.91,38.61 52.78,38.61 51.13,40.26 49.86,40.26 49.35,39.75 47.25,39.75 v2(46.87,40.13)
  BOTTOM w0.102: v2(139.2,14.86) 139.2,15.39 139.25,15.44 R755.1
COM1_DTR_N: length 116
  TOP w0.102: v3(44.59,40.64) 44.51,40.72 U11.16 ; U16.20 v2(142.34,24.93)
  INT1 w0.089: v3(44.59,40.64) 45.16,41.21 49.48,41.21 49.92,40.77 50.94,40.77 51.95,39.75 54.62,39.75 55.51,38.86 61.02,38.86 62.35,37.53 90.41,37.53 91.81,36.13 112.94,36.13 114.97,38.16 116.96,38.16 118.42,36.7 135.65,36.7 137.62,34.73 137.62,30.92 135.84,29.15 135.84,26.67 136.28,26.23 141.04,26.23 v2(142.34,24.93)
COM1_EN: length 2.8
  TOP w0.102: U16.24 139.74,24.77 v1(139.3,25.12) 139.84,25.58 R483.2
COM1_RI_N: length 120.9
  TOP w0.102: v2(45.03,38.73) 44.46,38.73 43.93,39.27 U11.20 ; R495.1 143.97,27.18 143.7,26.91 R485.1 v2(143.27,27.69)
  INT1 w0.089: v2(45.03,38.73) 45.1,38.8 45.1,39.75 44.84,40.01 44.33,40.01 44.14,40.2 44.14,40.82 44.79,41.47 49.6,41.47 50.05,41.02 51.06,41.02 52.05,40.03 54.74,40.03 55.63,39.14 61.13,39.14 62.47,37.81 90.53,37.81 91.93,36.41 112.82,36.41 114.85,38.45 117.07,38.45 118.56,36.96 135.77,36.96 137.81,34.92 137.81,28.83 136.92,27.94 136.92,26.8 137.3,26.42 142.31,26.42 v2(143.27,27.69)
COM1_RTS_N: length 127.1
  TOP w0.102: v2(133.42,21.21) 133.42,20.45 133.93,19.94 134.76,19.94 135.84,18.86 140.28,18.86 140.79,18.35 140.79,17.27 141.04,17.03 U16.7 ; U11.15 44.91,40.95 45.06,40.81 45.06,40.7 v2(45.81,39.95) 46.14,39.62 47,39.62 v2(48.02,38.61)
  INT1 w0.089: v2(48.02,38.61) 48.02,36.83 48.4,36.45 49.79,36.45 50.3,36.96 51.45,36.96 51.95,36.45 54.87,36.45 55.95,37.53 60.46,37.53 61.8,36.2 84.47,36.2 85.93,34.73 116.03,34.73 117.04,33.72 119.2,33.72 119.45,33.97 120.28,33.97 120.66,33.59 130.5,33.59 131.2,34.29 131.96,34.29 134.88,31.37 134.88,26.04 137.55,23.37 137.55,21.02 136.98,20.45 134.88,20.45 134.12,21.21 v2(133.42,21.21)
  BOTTOM w0.102: R693.1 46.11,40.23 v2(45.81,39.95) ; v2(48.02,38.61) 48.02,39.13 R712.2
COM1_RXD: length 330.4
  TOP w0.102: R492.1 137.55,25.02 v2(137.68,24.89) 138.06,24.89 138.44,24.52 U16.26 ; CN9.17 20.9,166.73 22.85,164.78 22.85,163.91 23.71,163.04 27.07,163.04 27.32,163.29 27.32,165.86 v2(27.76,166.31) 28.59,167.13 31.13,167.13 32.04,168.05 32.04,177.72 40.19,185.86 43.25,185.86 43.64,185.48 43.64,182.69 45.22,181.1 48.97,181.1 49.91,182.04 54.54,182.04 56.53,184.02 58.3,184.02 60.34,186.06 60.82,186.06 60.99,186.23 CN7.17 ; v3(45.54,110.11) 45.79,109.86 45.79,105.02 53.22,97.59 53.22,95.76 55.23,93.75 55.23,92.54 56.35,91.43 56.35,87.36 57.35,86.36 57.35,83.69 57.92,83.12 v2(57.92,80.39) ; v2(48.58,37.97) 47.95,37.97 46.62,39.3 45.7,39.3 44.87,40.13 44.33,40.13 44,40.46 U11.17 43.25,40.73 43.57,41.05 43.57,41.91 43.7,42.04 43.7,43.28 44.02,43.6 44.02,44.64 44.27,44.9 44.27,45.37 44.77,45.86 44.77,48.78 45.99,50 51.2,50 52.13,50.93 52.13,51.94 54.62,54.43 54.62,58.04 55.32,58.74 55.32,59.52 57.37,61.57 57.37,66.6 56.75,67.21 56.75,73.43 57.37,74.04 57.37,74.59 58.35,75.58 v2(58.35,76.24)
  INT1 w0.089: v2(137.68,24.89) 136.35,24.89 135.08,26.16 135.08,29.72 136.66,31.31 136.66,34.16 135.39,35.43 129.32,35.43 127.73,33.85 120.77,33.85 120.39,34.23 119.35,34.23 119.1,33.97 117.15,33.97 116.13,34.99 86.03,34.99 84.57,36.45 61.9,36.45 60.57,37.78 55.76,37.78 54.68,36.7 52.08,36.7 51.57,37.21 50.18,37.21 49.67,36.7 48.91,36.7 48.58,37.03 v2(48.58,37.97)
  BOTTOM w0.102: v2(57.92,80.39) 57.03,79.5 57.03,77.1 57.45,76.69 57.9,76.69 v2(58.35,76.24) ; v2(27.76,166.31) 28.29,165.77 28.29,156.12 35.7,148.72 36.36,148.72 39.97,145.11 39.97,140.25 41.27,138.94 41.27,123.96 41.65,123.58 41.65,117.92 46.24,113.33 46.24,110.81 v3(45.54,110.11)
COM1_SD: length 7.2
  TOP w0.102: U16.25 139.09,24.55 138.69,24.94 R482.2 138.3,26.05 138.11,26.24 138.11,27.69 137.6,28.19 135.8,28.19 v1(135.75,28.24)
COM1_T4IN: length 3
  TOP w0.102: U16.21 141.69,24.59 v1(141.21,25.07) 141.21,25.14 R484.2
COM1_T4OUT: length 2.8
  TOP w0.102: R481.2 136.41,25.65 136.6,25.46 v1(136.6,24.96) 136.85,24.96 137.14,24.67 U16.28
COM1_TXD: length 351.6
  TOP w0.102: v2(57.56,76.15) 57.16,75.75 57.16,74.17 56.53,73.53 56.53,67.06 57.16,66.42 57.16,61.65 55.07,59.55 55.07,58.8 54.37,58.1 54.37,54.46 51.93,52.03 51.93,51.03 51.12,50.22 45.92,50.22 44.56,48.86 44.56,46.01 44.06,45.5 44.06,45.03 43.76,44.73 43.76,44.51 43.57,44.32 42.89,44.32 R391.1 R363.2 42.38,42.78 43.32,41.85 43.32,41.15 43,40.83 42.56,40.83 42.36,40.64 42.36,40.26 42.56,40.07 U11.18 44.02,40.07 44.21,39.88 44.79,39.88 45.53,39.14 45.53,39.14 v2(45.87,38.8) ; v2(57.1,80.39) 57.61,80.9 57.61,83.06 57.1,83.57 57.1,86.17 56.14,87.12 56.14,91.31 55.03,92.43 55.03,93.62 52.97,95.68 52.97,97.51 45.57,104.91 45.57,109.25 44.97,109.86 44.97,110.36 v3(45.54,110.93) ; U16.6 140.39,17.06 140.54,17.21 140.54,18.29 140.22,18.61 135.71,18.61 134.63,19.68 v2(133.36,19.68) ; CN7.16 59.99,186.04 58.21,184.26 56.43,184.26 54.44,182.27 49.76,182.27 48.84,181.36 45.29,181.36 43.89,182.75 43.89,185.67 43.44,186.12 40.12,186.12 31.81,177.81 31.81,168.14 31.06,167.39 27.7,167.39 v2(27.44,167.13) 27.11,166.8 27.11,163.37 26.99,163.25 23.84,163.25 23.05,164.03 23.05,164.92 22.11,165.86 22.11,166.88 21.26,167.73 CN9.16
  INT1 w0.089: v2(45.87,38.8) 46.75,38.8 47.45,39.5 49.48,39.5 49.99,40.01 51,40.01 52.65,38.35 60.81,38.35 62.14,37.02 84.81,37.02 86.27,35.56 116.24,35.56 116.87,36.2 135.39,36.2 137.23,34.35 137.23,31.24 135.46,29.46 135.46,26.42 136.15,25.72 138.44,25.72 138.89,25.27 138.89,24 137.93,23.05 137.93,20.51 137.11,19.68 v2(133.36,19.68)
  BOTTOM w0.102: v3(45.54,110.93) 45.98,111.38 45.98,113.23 41.41,117.81 41.41,123.51 41.06,123.86 41.06,138.81 39.73,140.14 39.73,145.02 36.28,148.46 35.62,148.46 28.05,156.03 28.05,164.11 v1(27.57,164.59) 27.19,164.97 27.19,166.88 v2(27.44,167.13) ; v2(57.56,76.15) 57.27,76.44 57.27,76.52 56.75,77.04 56.75,80.05 v2(57.1,80.39)
COM1_V1N: length 3
  TOP w0.102: C298.2 144.49,25.75 v1(145.04,25.2) 144.29,24.44 U16.17
COM1_V1P: length 6.4
  TOP w0.102: v2(145.81,17.53) 145.44,17.53 144.94,17.02 U16.13
  BOTTOM w0.102: v2(145.81,17.53) 147.84,17.53 v1(148.41,16.95) 148.24,16.95 C548.2
CPU_ALERT_N: length 15.2
  TOP w0.102: R180.2 100.34,122.38 v1(100.16,122.56) 101.38,123.77 103.02,123.77 103.92,124.68 103.92,125.63 105.12,126.82 105.12,131.88 105.76,132.52 U6.AL4
CPU_CLKIN_SC_N: length 10.3
  TOP w0.127: U6.B8 110.84,170.15 110.66,170.33 110.4,170.33 110.06,170.67 110.06,172.58 110.9,173.42 110.9,177.43 R114.2 110.88,178.05 110.88,178.6 C85.2
CPU_CLKIN_SC_P: length 9.8
  TOP w0.127: C86.2 111.16,178.62 111.16,178.03 R114.1 111.19,177.5 111.19,173.3 110.35,172.47 110.35,170.84 110.53,170.65 110.65,170.65 110.84,170.84 U6.A8
CPU_CORE_TYPE: length 107.1
  TOP w0.102: v2(98.74,168.71) 98.74,168.4 101.76,165.38 103.37,165.38 103.87,164.88 103.87,164.58 104.19,164.26 106.29,164.26 107.03,163.52 U6.G5
  TOP w0.152: R18.1 127.18,240.91 v2(127.49,241.22) 127.52,241.25 R21.2
  BOTTOM w0.152: v2(98.74,168.71) 98.74,170.87 101.94,174.07 104.32,174.07 107.61,177.35 107.61,182.07 108.54,183.01 108.54,187.41 116.92,195.79 116.92,200.25 119.28,202.62 123.95,202.62 132.75,211.41 132.75,227.69 130.47,229.97 130.47,240.26 129.3,241.43 v1(128.66,241.43) 127.7,241.43 v2(127.49,241.22)
CPU_DBRDY: length 103.1
  TOP w0.102: J3.9 v2(127.9,89.41) ; v3(107.71,170.56) 108.3,169.96 U6.B6 ; v2(103.64,130.05) 103.8,129.9 v2(103.8,127.51)
  BOTTOM w0.102: v2(103.8,127.51) 103.8,127.2 105.01,125.98 105.01,124.71 107.02,122.71 107.02,120.18 108.34,118.86 108.34,116.26 115.08,109.52 115.38,109.52 120.91,103.99 120.91,89.03 121.68,88.27 126.76,88.27 v2(127.9,89.41) ; v3(107.71,170.56) 107.71,170.18 v1(107.44,169.91) 107.25,169.72 107.25,163.63 108.5,162.38 108.5,136.94 105.37,133.8 105.37,131.77 v2(103.64,130.05)
CPU_DBREQ_N: length 108.5
  TOP w0.102: v2(103.06,127.51) 103.06,130.63 v2(103.16,130.73) ; R240.2 v2(129.17,89.92) J3.7 ; U6.A5 v3(106.4,171.76)
  BOTTOM w0.102: v2(103.06,127.51) 103.06,127.36 104.58,125.83 104.58,124.41 106.56,122.43 106.56,120.06 107.94,118.69 107.94,116.09 114.91,109.12 115.21,109.12 120.41,103.92 120.41,88.9 121.55,87.76 127.26,87.76 129.17,89.66 v2(129.17,89.92) ; v2(103.16,130.73) 104.47,132.04 v1(104.47,132.36) 104.47,133.77 108.09,137.39 108.09,162.05 106.84,163.3 106.84,171.32 v3(106.4,171.76)
CPU_FAN_PWM: length 432.2
  TOP w0.102: v2(50.17,72.54) 49.77,72.14 39.89,72.14 37.6,74.42 36.4,74.42 33.93,76.9 23,76.9 21.33,78.56 21.33,81.17 19.31,83.19 19.31,90.23 19.63,90.55 19.63,103.44 5.93,117.15 5.93,149.88 7.2,151.16 7.2,156.08 6.8,156.48 6.8,157.76 7.08,158.05 7.08,163.22 6.76,163.54 6.76,164.77 6.84,164.85 6.84,170.49 6.69,170.64 6.69,175.56 3.47,178.79 3.47,181.9 2.85,182.52 2.85,219.56 17.41,234.12 61.87,234.12 75.52,247.78 99.45,247.78 102.63,244.6 108.72,244.6 110.88,246.76 110.88,248.49 113.85,251.46 159.77,251.46 161.16,250.07 v2(166.38,250.07) ; v2(185.1,247.6) R11.2 R15.1 ; U11.61 52.48,39.27 53.02,39.8 53.02,41.38 53.91,42.27 53.91,42.53 55.66,44.28 55.66,48.84 58.1,51.28 58.1,57.4 v3(58.41,57.71)
  BOTTOM w0.102: v2(185.1,247.6) 181.6,244.09 170.85,244.09 166.38,248.56 v2(166.38,250.07) ; v3(58.41,57.71) 58.18,57.71 57.82,58.06 56.4,58.06 55.87,58.6 51.84,58.6 51.17,59.27 51.17,63.02 51.73,63.58 51.73,66.14 v1(51.45,66.42) 51.45,71.27 v2(50.17,72.54)
CPU_FAN_TACH: length 442.8
  TOP w0.102: v2(50.13,74.32) 49.73,73.93 49.73,73.34 49.03,72.64 39.95,72.64 37.67,74.93 36.6,74.93 34.22,77.3 26.59,77.3 25.66,78.23 25.66,80.52 25.79,80.64 25.79,81.6 25.47,81.92 21.22,81.92 19.82,83.31 19.82,89.98 20.14,90.3 20.14,103.57 6.37,117.34 6.37,146.44 9.28,149.35 9.28,150.39 8.66,151.02 8.66,154.41 9.13,154.89 9.13,157.68 8.32,158.49 8.32,162.82 9.33,163.82 9.33,173.64 3.95,179.01 3.95,182.18 3.25,182.87 3.25,219.14 17.73,233.62 63.33,233.62 76.73,247.01 99.2,247.01 102.19,244.03 109.07,244.03 111.48,246.44 111.48,248.2 113.79,250.51 159.33,250.51 163.9,245.94 163.9,241.17 164.92,240.16 173.81,240.16 176.48,242.82 178.06,242.82 182.89,247.65 182.89,249.3 184.29,250.7 D1.A 184.4,250.75 R10.1 ; v3(58.86,57.25) 58.86,55.92 58.33,55.39 58.33,51.21 55.89,48.77 55.89,44.2 54.11,42.42 54.11,42.19 53.25,41.33 53.25,39.59 52.53,38.86 U11.60
  BOTTOM w0.102: v3(58.86,57.25) 58.23,57.25 57.62,57.86 56.3,57.86 55.76,58.39 51.66,58.39 50.94,59.12 50.94,63.08 51.19,63.34 v1(51.19,64.03) 51.19,65.05 50.91,65.33 50.91,71.12 49.69,72.34 49.69,73.89 v2(50.13,74.32)
CPU_HTREF0: length 32.8
  TOP w0.102: U6.V7 109.12,149.08 109.12,136.44 108.72,136.04 108.06,136.04 107.84,135.82 107.84,132.44 106.18,130.78 106.18,125.32 103.11,122.25 v1(102.07,122.25) 101.74,121.92 R206.1
CPU_HTREF1: length 26.2
  TOP w0.102: U6.V8 110.18,150.2 109.35,150.2 108.76,149.61 108.76,136.6 108.54,136.38 107.79,136.38 107.5,136.09 107.5,132.77 105.67,130.94 v2(105.67,129.16)
  BOTTOM w0.102: v2(105.67,129.16) 105.93,128.91 R572.2
CPU_M_VREF_SUS: length 15.9
  TOP w0.381: U6.F12 v3(115.29,165.41)
  BOTTOM w0.381: v3(115.29,165.41) 115.88,166 115.88,167.22 115.37,167.73 115.37,169.33
  BOTTOM w0.5: 115.37,179.96 115.37,178.9 v1(115.39,178.88) 115.37,178.86 115.37,169.33
  vias: v2(114.01,182.78) v2(115.35,182.88)
CPU_M_ZN: length 21
  TOP w0.102: v3(114.03,137.43) 114.62,136.84 U6.AH11 ; R184.2 109.23,121.16 109.74,121.67 109.74,127.33 v2(109.82,127.41)
  BOTTOM w0.102: v3(114.03,137.43) 114.02,137.43 113.7,137.11 112.46,137.11 112.13,136.78 112.13,134.47 110.5,132.84 110.5,131.06 108.85,129.41 v1(108.85,128.21) 109.65,127.41 v2(109.82,127.41)
CPU_M_ZP: length 19.5
  TOP w0.102: v3(114.02,136.21) 114.65,135.57 U6.AJ11 ; R185.2 110.17,121.03 110.17,125.5 110.37,125.7 110.37,127.94 v2(109.99,128.32)
  BOTTOM w0.102: v3(114.02,136.21) 113.55,136.68 112.76,136.68 112.56,136.47 112.56,134.26 111.01,132.72 111.01,130.24 v1(110.44,129.67) 109.99,129.22 v2(109.99,128.32)
CPU_MEMHOT_N: length 220.5
  TOP w0.102: v2(113.88,44.25) 112.68,45.45 109.08,45.45 108.21,44.58 v2(107.96,44.58) 107.2,43.81 Q29.C ; v2(188.7,89.35) 188.7,127.73 191.3,130.33 v2(191.3,132.36) 190.55,133.11 Q9.C ; v3(89.75,41.55) 89.75,42.41 89.48,42.67 88.65,42.67 88.13,43.19 88.13,44.22 87.79,44.55 87.79,45.97 87.44,46.33 87.44,48.48 88.45,49.5 88.45,49.72 88.94,50.21 88.94,52.29 91.1,54.44 91.1,55.55 91.19,55.64 91.19,56.17 U10.J2 ; v2(191.27,139.95) 191.27,140.44 190.55,141.16 Q8.C ; v2(172.35,57.15) 154.82,57.15 153.05,55.37 153.05,54.36 150.58,51.89 v2(148.73,51.89)
  INT1 w0.089: v2(120.53,43.43) 120.22,43.12 115.01,43.12 v2(113.88,44.25)
  BOTTOM w0.102: v2(191.27,139.95) 191.75,139.48 191.75,132.81 v2(191.3,132.36) ; v2(172.35,57.15) 180.16,57.15 181.11,58.1 182.7,58.1 185.3,60.71 185.3,85.96 v2(188.7,89.35) ; v2(148.73,51.89) 148.73,49.86 149.16,49.43 149.16,46.99 147.79,45.62 142,45.62 138.47,42.09 130.67,42.09 129.83,42.93 122.9,42.93 122.41,42.44 121.52,42.44 v2(120.53,43.43) ; v3(89.75,41.55) 90.26,42.06 90.26,44.1 91.63,45.47 93.99,45.47 94.5,45.97 94.5,47.05 94.99,47.55 103.08,47.55 v1(103.71,46.93) 105.19,45.44 107.1,45.44 v2(107.96,44.58)
CPU_PRESENT_N: length 147.2
  TOP w0.102: v2(98.31,121.67) 99.02,120.95 R182.2 99.2,121.59 98.94,121.84 98.94,122.81 100.77,124.64 102.61,124.64 103.1,125.12 103.1,126.1 104.3,127.3 104.3,132.84 U6.AL3 ; v2(116.98,76.33) 118.31,74.99 127.25,74.99 127.6,74.65 134.4,74.65 136.92,72.14 142.76,72.14 144.11,70.79 144.11,68 147.97,64.14 156.98,64.14 157.24,64.39 158.33,64.39 159.22,63.5 159.9,63.5 v2(160.03,63.63) ; v2(112.28,89.03) 112.48,89.03 114.32,87.19 114.32,76.59 v2(114.06,76.33) 114.06,75.95 113.04,74.93 111.9,74.93 v2(110.75,73.79)
  BOTTOM w0.102: v2(116.98,76.33) v2(114.06,76.33) ; R692.1 164.84,55.31 v1(163.78,55.31) 163.52,55.31 160.03,58.8 v2(160.03,63.63) ; R662.1 v2(110.75,73.79) ; v2(98.31,121.67) 98.44,121.79 100.98,121.79 102.18,120.59 102.18,119.63 103.41,118.4 103.41,114.91 104.66,113.67 106.18,113.67 109.1,110.74 109.1,110.41 110.86,108.66 111.8,108.66 115.68,104.78 115.68,102.65 117.66,100.67 117.66,93.05 113.64,89.03 v2(112.28,89.03)
CPU_PRESENT_R_N: length 11.4
  TOP w0.102: U10.AB21 100.72,70.52 v3(100.72,70.61)
  BOTTOM w0.102: R662.2 v1(108.15,73.79) 108.04,73.67 108.04,73.15 106.89,72.01 105.78,72.01 103.47,69.7 101.95,69.7 101.04,70.61 v3(100.72,70.61)
CPU_PROCHOT_1.5_N: length 105.9
  TOP w0.102: v2(81.85,82.93) 82.54,82.93 86,79.48 87.86,79.48 88.96,78.38 88.96,77.67 89.16,77.47 v3(89.16,77.47) ; v2(109.84,87) 108.72,88.11 103.09,88.11 101.16,90.04 97.5,90.04 96.84,89.38 88.91,89.38 88.76,89.53 85.96,89.53 85.35,88.93 83.53,88.93 82.92,89.53 82.48,89.53 81.7,88.75 80.25,88.75 79.79,88.29 79.79,85.12 v2(79.94,84.96) ; U10.H21 90.14,70.4 89.81,70.73 89.81,72.51 89.7,72.62 89.7,73.94 v3(89.77,74.02) ; v2(104.91,116.08) 104.28,116.08 103.64,116.71 103.64,118.52 104.66,119.53 R207.2
  BOTTOM w0.102: v2(81.85,82.93) 79.94,84.84 v2(79.94,84.96) ; v2(109.84,87) 111.16,87 111.36,87.2 116.29,87.2 v1(118.06,88.96) 118.88,89.79 118.88,104.29 115,108.18 114.54,108.18 112.74,109.98 111.34,109.98 110.42,110.9 110.42,111.25 105.85,115.82 105.17,115.82 v2(104.91,116.08) ; v3(89.16,77.47) 89.95,76.68 89.95,74.24 89.77,74.06 v3(89.77,74.02)
CPU_PROCHOT_1.5_R_N: length 15.2
  TOP w0.102: U6.AL7 109.57,133.03 109.41,132.87 109.41,131.47 107.91,129.97 107.91,124.61 v2(105.22,121.92) 104.66,121.36 R207.1
  BOTTOM w0.102: R574.2 105.04,121.74 v2(105.22,121.92)
CPU_PSI_N: length 2.3
  TOP w0.102: v2(101.28,165.07) 101.58,164.78 U6.F1
  BOTTOM w0.102: TP122.1 100.85,165.51 v2(101.28,165.07)
CPU_PWRGD: length 210.5
  TOP w0.102: v2(130.19,89.28) 130.44,89.03 J3.5 ; U6.C9 112.11,168.59 v3(111.47,169.24) ; v2(119.9,96.77) 116.98,96.77 116.22,96.01 111.77,96.01 110.88,96.9 108.91,96.9 108.02,96.01 105.92,96.01 104.17,97.76 89.69,97.76 87.31,100.15 75.58,100.15 R222.1 74.71,100.15 70.95,100.15 70.69,99.89 69.35,99.89 66.98,97.51 66.98,86.96 68.18,85.75 v2(69.35,85.75) ; v2(78.75,77.09) 78.9,77.24 79.93,77.24 80.45,76.72 80.45,75.77 83.32,72.9 83.32,72.4 84.01,71.71 84.01,71.27 84.3,70.99 86.84,70.99 87.26,70.56 87.26,70.13 87.87,69.52 89.19,69.52 89.48,69.82 90.01,69.82 90.61,69.22 91.34,69.22 U10.K19
  BOTTOM w0.102: v2(130.19,89.28) 128.15,87.25 121.42,87.25 119.9,88.77 v2(119.9,96.77) 119.9,103.86 115.04,108.71 114.74,108.71 107.53,115.92 107.53,116.74 105.99,118.28 105.99,122.36 104.53,123.83 C426.1 R576.2 104.07,125.71 102.58,127.2 102.58,127.83 102.73,127.99 103.62,127.99 108.14,132.51 108.14,134.67 109.72,136.25 109.72,162.28 110.12,162.69 110.12,164.82 110.6,165.3 110.6,166.22 110.88,166.5 110.88,168.02 111.47,168.61 v3(111.47,169.24) ; v2(78.75,77.09) 78.62,76.96 v1(77.48,76.96) 76.59,76.96 75.83,77.72 75.83,79.27 v2(69.35,85.75)
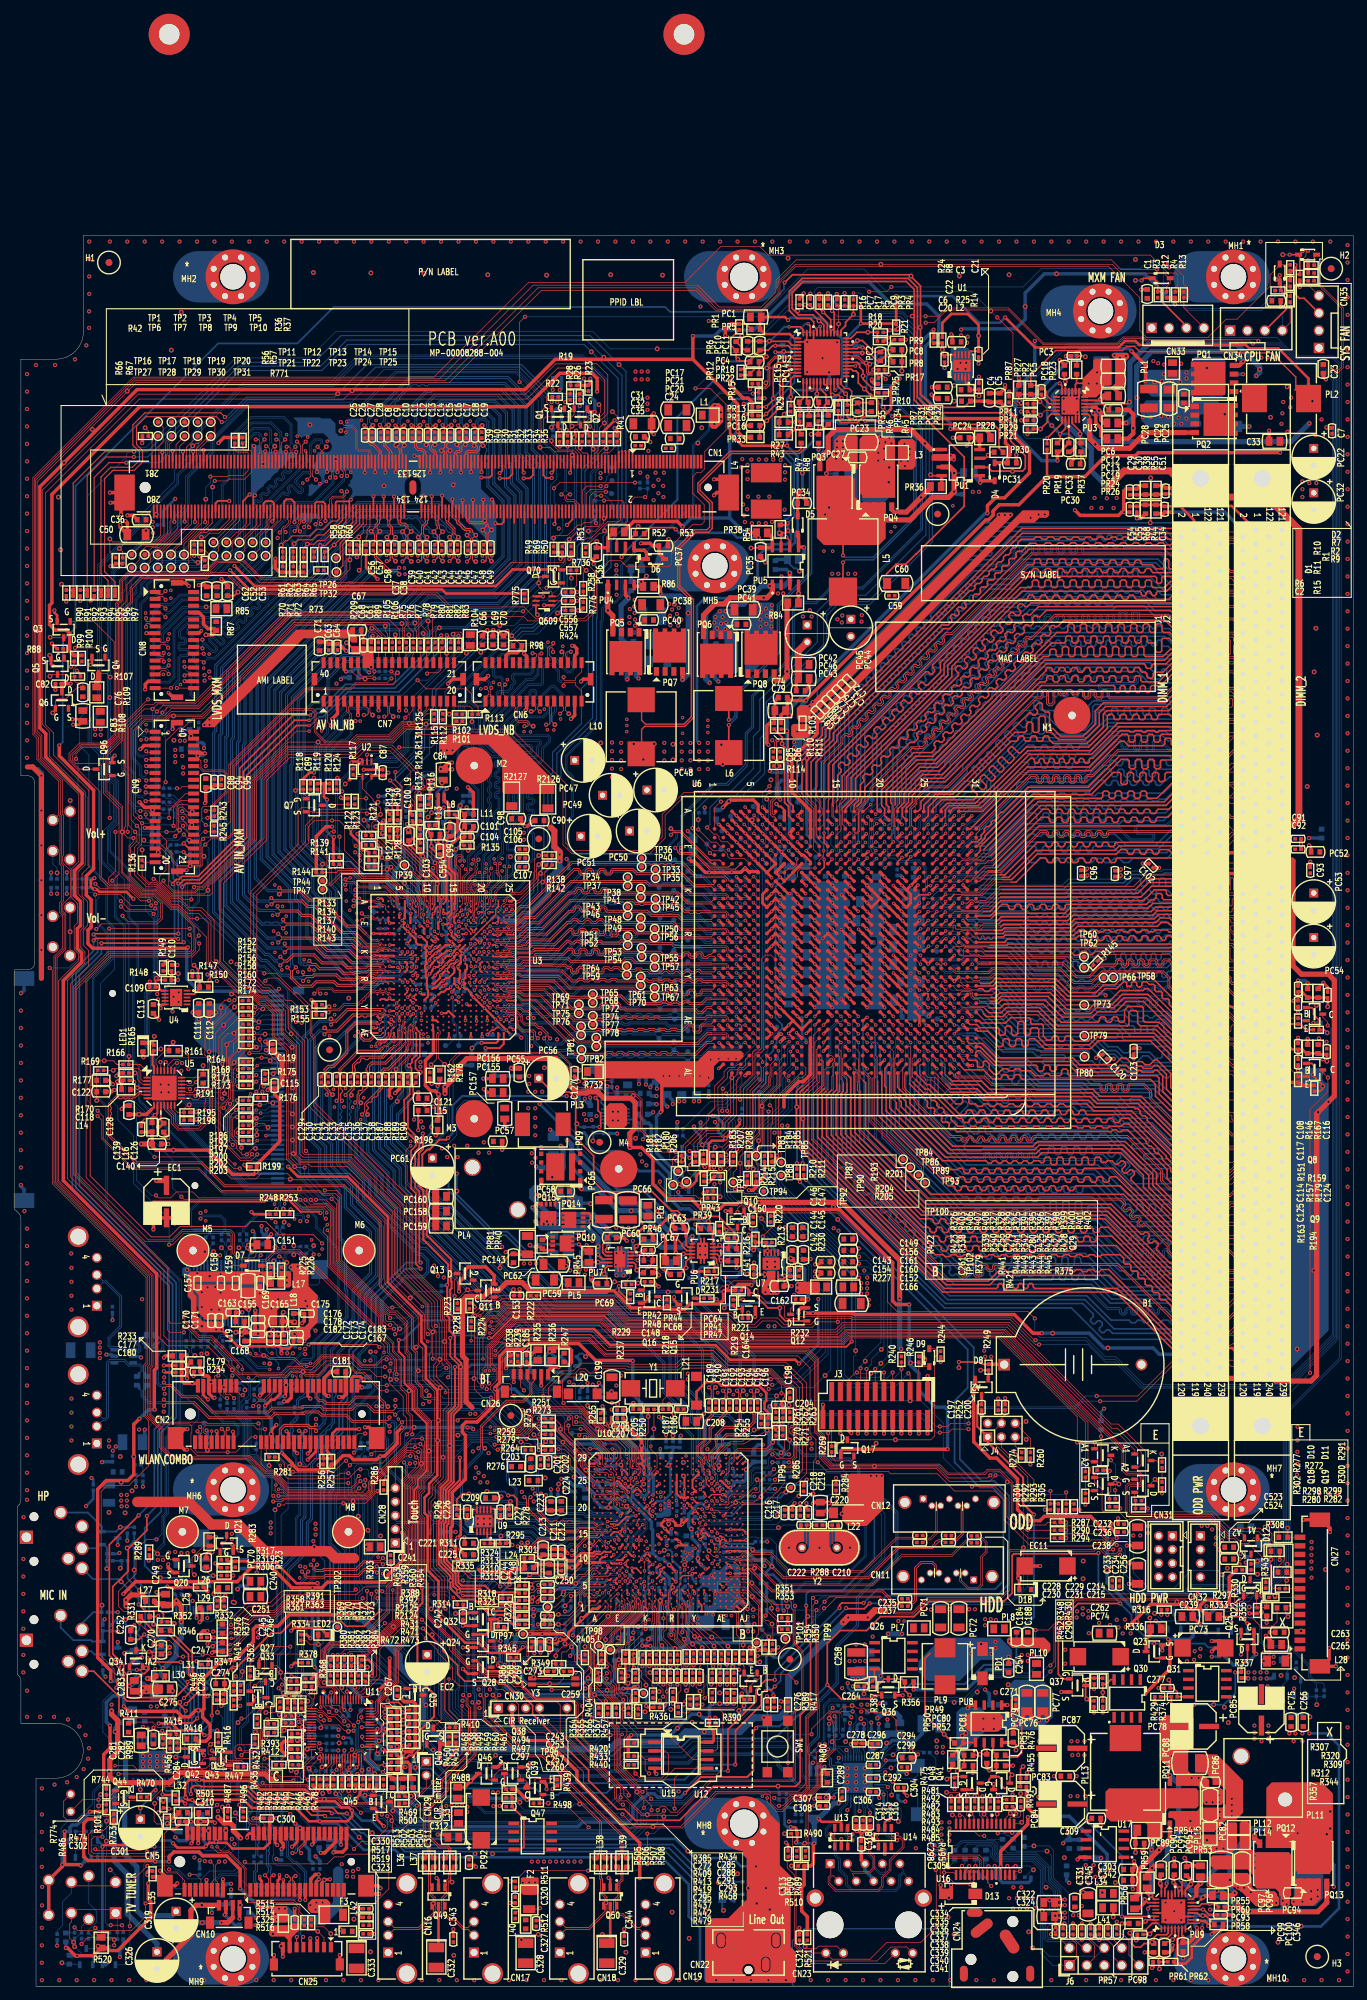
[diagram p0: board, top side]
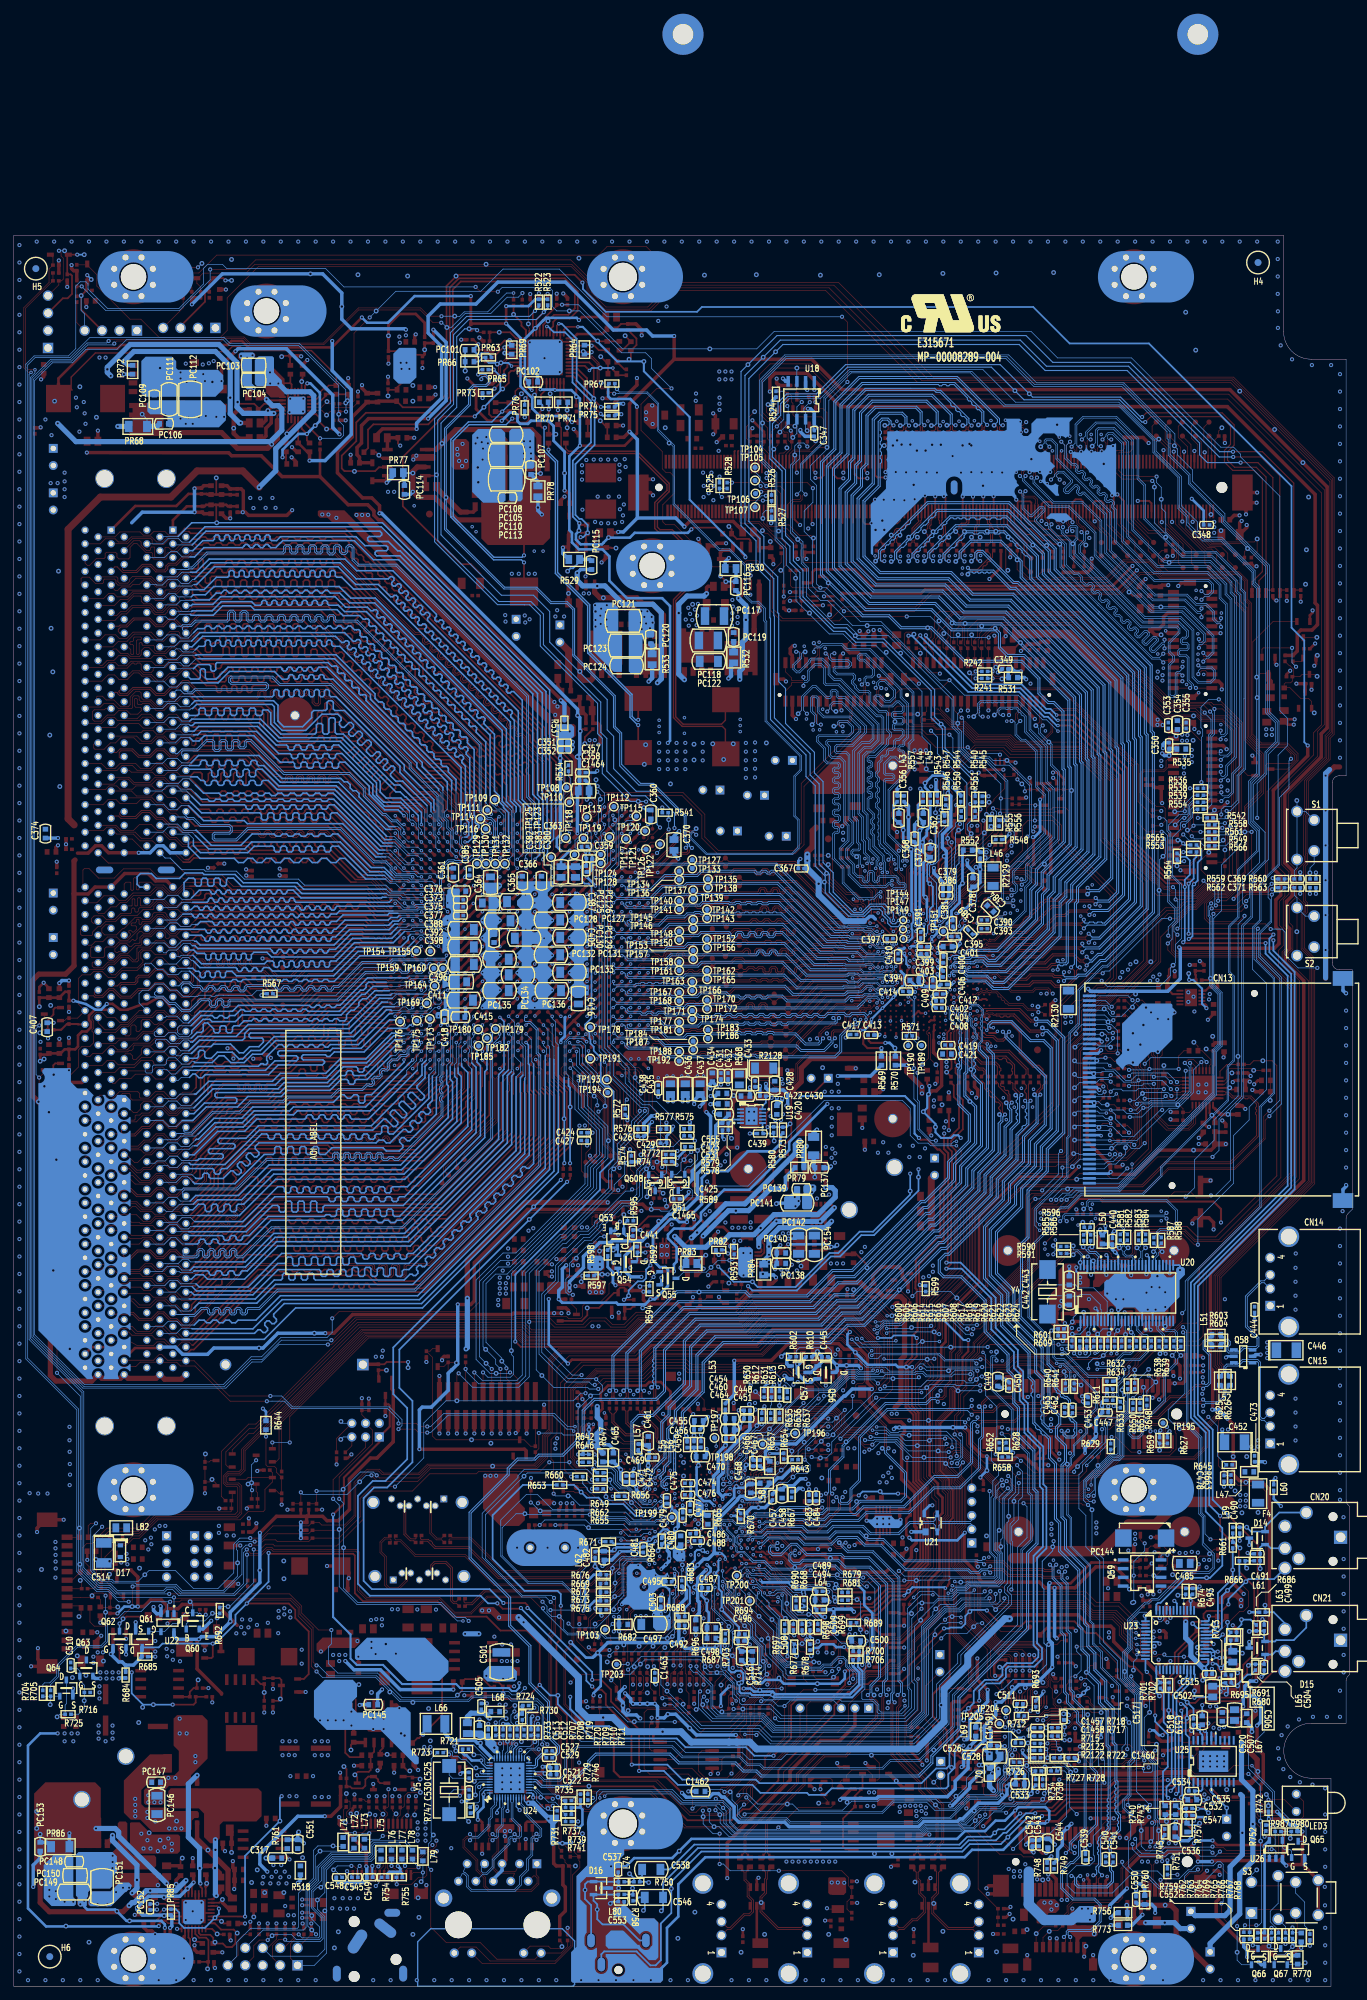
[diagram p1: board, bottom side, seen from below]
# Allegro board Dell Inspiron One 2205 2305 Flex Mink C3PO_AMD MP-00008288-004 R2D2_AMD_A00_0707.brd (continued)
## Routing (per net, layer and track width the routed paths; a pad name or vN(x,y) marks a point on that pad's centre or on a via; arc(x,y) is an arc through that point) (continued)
CPU_SIC: length 19.6
  TOP w0.102: U6.AL6 108.27,132.99 108.27,132.21 106.67,130.61 106.67,125.22 102.98,121.54 102.63,121.54 102.45,121.36 102.45,119.43 v1(102.82,119.06) 102.46,118.7 101.72,118.7 101.1,118.08 R193.2
CPU_SID: length 16.3
  TOP w0.102: R183.2 103.18,120.95 v1(103.64,121.11) 103.64,121.62 107.12,125.09 107.12,130.45 108.68,132.02 108.68,132.39 108.81,132.52 108.81,133.79 U6.AK6
CPU_SVC: length 109.7
  TOP w0.102: v2(102.88,172.55) 102.84,172.55 101.95,171.67 U6.C1
  TOP w0.254: PU2.39 119.38,243.8 119.15,244.03 v2(119.06,244.03) 119.06,244.3 R5.1
  BOTTOM w0.152: v2(119.06,244.03) 119.86,243.23 129.02,243.23 131.38,240.87 131.38,230.62 133.69,228.31 133.69,210.41 124.52,201.24 120.61,201.24 120.6,201.24 119.84,201.24 118.29,199.69 118.29,195.22 109.94,186.87 109.94,182.46 109.26,181.78 109.26,176.66 105.19,172.59 v1(104.02,172.59) 102.92,172.59 v2(102.88,172.55)
  BOTTOM w0.254: v2(119.06,244.03) 118.49,244.6 R5.1
CPU_SVD: length 115.6
  TOP w0.102: U6.E3 104.49,166.06 103.85,166.7 103.01,166.7 102.6,167.11 102.6,167.46 102.25,167.82 101.81,167.82 v2(100.85,168.78)
  TOP w0.254: R17.2 117.22,244.41 v2(117.78,243.85) 118.88,242.76 PU2.40
  BOTTOM w0.152: v2(100.85,168.78) 101.28,169.21 101.28,171.7 102.98,173.41 104.99,173.41 108.6,177.01 108.6,181.76 109.48,182.65 109.48,187.06 117.83,195.41 117.83,199.87 119.66,201.7 124.33,201.7 133.23,210.6 133.23,228.12 130.92,230.43 130.92,240.56 128.71,242.77 118.86,242.77 v2(117.78,243.85)
  BOTTOM w0.254: v2(117.78,243.85) 117.22,244.41 R17.2
CPU_TCK: length 63.4
  TOP w0.102: v3(113.01,136.16) 113.38,136.53 U6.AH10 ; v2(126.63,89.41) J3.11
  BOTTOM w0.102: v2(126.63,89.41) 125.93,88.71 122.63,88.71 122.21,89.13 122.21,91.72 122.52,92.02 122.52,92.57 v1(122.5,92.58) 122.52,92.6 122.52,103.77 110.07,116.21 110.07,118.99 108.44,120.61 108.44,125.26 111.44,128.26 111.44,132.51 113.01,134.08 v3(113.01,136.16)
CPU_TDI: length 57.5
  TOP w0.102: v3(112.76,132.59) 113.2,133.03 U6.AL10 ; v2(124.09,89.92) J3.15
  BOTTOM w0.102: v3(112.76,132.59) 112.33,132.15 112.33,128 109.26,124.92 109.26,120.95 110.96,119.25 110.96,116.51 122.69,104.78 124.41,104.78 126.63,102.55 126.63,93.15 v1(126.25,92.77) 124.79,91.31 124.79,90.61 v2(124.09,89.92)
CPU_TDO: length 62.4
  TOP w0.102: v3(113.93,133.73) 113.38,134.28 U6.AK10 ; v2(122.69,89.41) 122.52,89.41 121.55,88.44 J3.19
  BOTTOM w0.102: v2(122.69,89.41) 122.82,89.28 v1(124.72,89.28) 125.61,89.28 127.65,91.31 127.65,102.87 123.71,106.81 121.85,106.81 111.77,116.89 111.77,119.59 110.07,121.29 110.07,124.59 113.24,127.76 113.24,131.14 113.55,131.44 113.55,133.35 v3(113.93,133.73)
CPU_TEST2: length 3.9
  TOP w0.102: U6.AJ6 108.3,135.55 108.95,134.9 v3(108.95,134.62)
  BOTTOM w0.102: v3(108.95,134.62) 108.6,134.26 TP193.1
CPU_TEST3: length 3.5
  TOP w0.102: v3(110.35,137.52) 109.67,136.84 U6.AH7
  BOTTOM w0.102: TP178.1 110.75,139.45 110.75,138.56 110.5,138.3 110.5,137.67 v3(110.35,137.52)
CPU_TEST6: length 25.4
  TOP w0.102: U6.AJ5 107.01,135.57 106.48,135.04 106.48,134.2 106.1,133.82 105.56,133.82 105.23,133.49 104.19,133.49 103.81,133.11 103.81,132.3 102.45,130.94 102.45,127.53 102.58,127.41 102.58,125.58 102.04,125.04 100.57,125.04 97.75,122.22 97.75,118.85 95.9,116.99 TP92.1
CPU_TEST7: length 1.7
  TOP w0.125: v3(106.42,166.7) 106.65,166.46 107.03,166.08 U6.E5
  BOTTOM w0.102: v3(106.42,166.7) 106.24,166.7 TP121.1
CPU_TEST8_DIG_T: length 3.4
  TOP w0.125: v3(105.18,167.93) 105.76,167.35 U6.D4
  BOTTOM w0.102: TP120.1 103.25,168.52 104.59,168.52 v3(105.18,167.93)
CPU_TEST10_ANALOGOUT: length 1.7
  TOP w0.125: U6.G7 v3(108.94,164.14)
  BOTTOM w0.102: TP128.1 108.94,164.09 v3(108.94,164.14)
CPU_TEST12: length 10.6
  TOP w0.102: v3(112.81,137.6) 112.8,137.6 112.11,136.92 U6.AH9
  BOTTOM w0.102: v3(112.81,137.6) 112.32,137.6 111.69,136.98 111.69,134.67 109.99,132.97 109.99,131.7 TP194.1
CPU_TEST14: length 3.5
  TOP w0.125: v3(106.27,169.23) 106.91,168.59 U6.C5
  BOTTOM w0.102: v3(106.27,169.23) 105.67,169.82 104.89,169.82 TP115.1
CPU_TEST15: length 1.9
  TOP w0.102: U6.F8 110.26,165.37 v3(110.15,165.48)
  BOTTOM w0.102: v3(110.15,165.48) 110,165.37 TP124.1
CPU_TEST16: length 2
  TOP w0.125: v3(108.89,166.89) 108.9,166.89 108.9,166.75 109.57,166.08 U6.E7
  BOTTOM w0.102: TP117.1 108.71,166.89 v3(108.89,166.89)
CPU_TEST17: length 5.3
  TOP w0.125: v3(107.67,167.93) 107.9,167.7 108.28,167.32 U6.D6
  BOTTOM w0.102: TP112.1 108.29,171.12 108.29,168.91 107.67,168.29 v3(107.67,167.93)
CPU_TEST18: length 1.8
  TOP w0.127: v3(111.39,166.75) U6.E9
  BOTTOM w0.102: v3(111.39,166.75) 111.83,167.19 TP119.1
CPU_TEST19: length 6.7
  TOP w0.127: U6.F10 v3(112.75,165.41)
  BOTTOM w0.102: TP113.1 112.35,169.47 112.35,167.77 113.24,166.88 113.24,165.9 v3(112.75,165.41)
CPU_TEST20: length 21
  TOP w0.102: TP91.1 104.66,118.49 105.14,118.97 105.14,121.11 108.32,124.28 108.32,129.73 109.82,131.23 109.82,132.48 110.05,132.72 110.05,134.19 110.84,134.98 U6.AJ8
CPU_TEST21_SCANEN: length 13.9
  TOP w0.102: U6.AL8 111.05,132.82 111.05,131.34 108.72,129.01 108.72,123.52 v1(108.37,123.16) 108.37,122.43 R208.1
CPU_TEST22_SCANSHIFTEN: length 19.9
  TOP w0.102: R214.1 107.58,118.95 v1(107.58,119.06) 107.4,119.24 107.4,121.17 108.93,122.7 108.93,128.83 111.35,131.26 111.35,134.78 112.11,135.54 U6.AJ9
CPU_TEST23_TSTUPD: length 2
  TOP w0.102: U6.AH8 110.84,136.72 111.26,136.3 v3(111.26,136.25)
  BOTTOM w0.102: v3(111.26,136.25) 111.26,135.38 TP191.1
CPU_TEST24: length 24.1
  TOP w0.102: TP94.1 108.72,115.44 106.44,115.44 105.67,116.2 v1(105.67,119.89) 105.67,120.84 107.14,122.3 107.14,122.69 108.52,124.08 108.52,129.64 110.07,131.19 110.07,132.28 110.3,132.52 110.3,133.76 U6.AK8
CPU_TEST25_H_BYPASSCLK_H: length 13
  TOP w0.254: U6.A10 113.38,171.93 112.63,172.68 112.63,182.65 v1(112.47,182.82) 112.17,183.11 R111.2
CPU_TEST25_H_BYPASSCLK_L: length 14.4
  TOP w0.254: U6.B10 113.36,169.86 112.74,170.48 112.74,171.82 112.15,172.4 112.15,180.47 111.8,180.82 v1(111.8,181) 111.8,181.94 R110.2
CPU_TEST26_BURNIN_L: length 22.6
  TOP w0.102: U6.AK5 107.03,134.29 106.4,133.66 106.25,133.51 105.58,133.51 105.22,133.15 105.22,132.82 104.71,132.31 104.71,127.05 103.51,125.85 103.51,124.9 102.82,124.21 100.93,124.21 99.48,122.76 99.48,121.92 99.71,121.69 99.71,119.05 TP90.1
CPU_TEST27_SINGLECHAIN: length 18.1
  TOP w0.102: R215.1 108.28,118.37 108.28,119.51 108.02,119.76 TP83.1 108.02,121.51 109.13,122.61 109.13,128.74 111.62,131.24 111.62,133.81 U6.AK9
CPU_TEST28_H_PLLCHRZ_H: length 6.1
  TOP w0.102: U6.J10 113.39,160.97 114.05,161.63 114.05,162.39 114.53,162.88 v3(116.59,162.88)
  BOTTOM w0.102: TP125.1 116.59,164.33 v3(116.59,162.88)
CPU_TEST28_L_PLLCHRZ_L: length 4
  TOP w0.125: v3(113.94,164.18) 113.94,163.37 113.45,162.88 112.76,162.88 U6.H9
  BOTTOM w0.102: TP123.1 113.94,164.2 v3(113.94,164.18)
CPU_TEST29_H_FBCLKOUT_H: length 9.3
  TOP w0.102: U6.C11 114.65,168.64 v3(114.05,169.25)
  BOTTOM w0.102: v3(114.05,169.25) 114.61,169.82 114.61,171.91 TP110.1 113.85,172.67 113.85,175.95 114.18,176.28 R534.1
CPU_TEST29_L_FBCLKOUT_L: length 11.7
  TOP w0.102: U6.D11 114.65,167.32 v3(114.06,167.92)
  BOTTOM w0.102: v3(114.06,167.92) 114.06,168.06 114.86,168.87 114.86,174.2 TP108.1 114.44,175.03 114.84,175.44 114.84,177.19 R534.2
CPU_THERMDA: length 187.1
  TOP w0.254: v2(121.12,55.09) 121.22,54.99 123.76,54.99 v2(124.55,55.78) ; v2(110.73,43.66) 110.25,43.18 109.36,43.18 108.75,42.57 108.75,41 105.01,37.26 105.01,32.33 v2(104.96,32.28) ; v2(115.3,117.45) 114.95,117.81 R211.2 ; R413.1 v2(56.59,36.96) 56.84,37.21 C291.1 C293.1
  BOTTOM w0.254: v2(56.59,36.96) 56.6,36.96 58.68,34.87 58.68,32.16 59.12,31.72 60.62,31.72 62.75,29.59 86.37,29.59 86.88,30.1 97.6,30.1 99.78,32.28 v2(104.96,32.28) ; v2(115.3,117.45) 119.21,113.54 v1(119.26,113.54) 119.26,113.49 139.71,93.04 139.71,86.26 137.68,84.23 137.68,76.77 140.85,73.6 142.7,73.6 144.85,71.44 144.85,58.61 143.13,56.88 127,56.88 125.89,55.78 v2(124.55,55.78) ; v2(110.73,43.66) 111.58,44.51 111.58,45.53 121.12,55.07 v2(121.12,55.09)
CPU_THERMDA_R: length 23.3
  TOP w0.254: R211.1 114.95,119.73 v2(114.79,119.89)
  TOP w0.508: U6.AG8 111.43,138.7 v3(111.64,138.7)
  BOTTOM w0.102: v3(111.64,138.7) 112.05,138.29 114.1,138.29 114.81,137.58 114.81,132.35
  BOTTOM w0.254: v2(114.79,119.89) 114.79,126.33 v1(114.82,126.36) 114.79,126.4 114.79,130.72 114.81,130.75 114.81,132.35
CPU_THERMDC: length 186.3
  TOP w0.254: v2(114.39,117.17) 113.93,117.63 R210.2 ; v2(56.65,35.05) 57.37,35.05 R458.1 ; v2(110.73,44.63) 109.41,44.63 107.99,43.21 107.99,41.48 103.9,37.39 v2(103.9,31.37) ; v2(120.15,55.09) 120.15,55.5 120.48,55.83 v2(123.66,55.83)
  BOTTOM w0.254: v2(103.9,31.37) 100.28,31.37 98.25,29.34 87.39,29.34 86.22,28.17 79.44,28.17 79.14,27.88 76.8,27.88 75.86,28.82 59.19,28.82 58.84,29.17 58.84,30.91 57.92,31.83 57.92,34.14 57.01,35.05 v2(56.65,35.05) ; v2(120.15,55.09) 120.06,55.09 110.73,45.76 v2(110.73,44.63) ; v2(114.39,117.17) 119.86,111.7 v1(119.9,111.7) 119.9,111.66 138.82,92.74 138.82,87.17 136.92,85.27 136.92,76.33 140.6,72.64 142.5,72.64 144.03,71.12 144.03,59.05 142.82,57.85 125.68,57.85 v2(123.66,55.83)
CPU_THERMDC_R: length 23
  TOP w0.254: v2(113.96,119.89) 113.93,119.86 R210.1
  TOP w0.508: U6.AG9 112.07,138.11 v3(111.54,137.58)
  BOTTOM w0.102: v3(111.54,137.58) 111.56,137.58 112.04,138.06 114.03,138.06 114.53,137.55 114.53,132.95 114.17,132.6 114.17,132.21
  BOTTOM w0.254: 114.17,132.21 114.17,131.14 113.96,130.92 113.96,128.1 v1(113.93,128.08) 113.96,128.05 v2(113.96,119.89)
CPU_THERMTRIP_L: length 23.3
  TOP w0.102: v2(102.75,117.09) 102.75,117.49 102.8,117.54 R201.2 102.8,118.26 104.23,119.68 104.23,121.62 107.48,124.87 107.48,130.28 109.07,131.86 109.07,133.79 U6.AK7
  BOTTOM w0.102: v1(102.75,115) v2(102.75,117.09) 102.5,117.35 Q608.S
CPU_THERMTRIP_N: length 174.7
  TOP w0.102: 91.21,59.44 91.21,59.44 U10.J6 ; v3(57.67,122.43) 56.98,121.74 56.98,116.19 57.99,115.18 57.99,104.71 62.56,100.14 62.56,97.35 62.88,97.03 62.88,91.25 63.64,90.49 63.64,84.52 62.83,83.7 62.83,73.9 61.68,72.75 61.68,68.3 61.4,68.02 61.4,61.29 63.05,59.64 63.05,57.86 63.35,57.56 63.35,53.37 65.99,50.74 67.89,50.74 69.11,49.52 71.65,49.52 72.37,50.24 74.48,50.24 74.86,49.86 74.86,48.21 75.77,47.31 v2(75.77,45.91) ; R204.2 R205.2 100.4,114.81 v2(100.15,114.55) 99.9,114.81 99.58,114.81 99.2,115.19 95.51,115.19 93.99,116.71 v2(93.99,117.22)
  TOP w0.125: 91.21,59.44 91.19,59.47 91.03,59.47 v3(90.55,58.98)
  BOTTOM w0.102: v1(99.9,113.6) 99.9,114.3 v2(100.15,114.55) ; v3(57.67,122.43) 61.42,122.43 61.8,122.81 63.26,122.81 64.4,123.95 64.4,127.89 65.54,129.03 76.92,129.03 82.56,123.39 82.56,122.05 88.05,116.56 93.33,116.56 v2(93.99,117.22) ; v3(90.55,58.98) 90.55,58.79 89.8,58.04 89.8,56.05 85.1,51.35 v1(85.1,50.67) 84.85,50.42 84.85,48.39 82.5,46.04 82.5,45.53 82.18,45.21 76.46,45.21 v2(75.77,45.91)
CPU_THERMTRIP_R_N: length 3.5
  TOP w0.102: R204.1 101.79,116.17 101.94,116.33 v2(101.94,116.84)
  BOTTOM w0.102: v1(100.4,115.51) 100.75,115.85 Q608.D 101.55,116.44 v2(101.94,116.84)
CPU_TMS: length 57
  TOP w0.102: U6.AL9 112.11,132.6 112.76,131.96 v3(112.76,131.91) ; v2(125.36,89.92) J3.13
  BOTTOM w0.102: v2(125.36,89.92) v1(126.19,90.74) 127.14,91.69 127.14,102.67 124.06,105.74 122.31,105.74 111.36,116.69 111.36,119.42 109.66,121.12 109.66,124.75 112.76,127.85 v3(112.76,131.91)
CPU_TRST_N: length 60.9
  TOP w0.102: J3.17 122.82,88.11 123.23,88.52 v2(123.23,90.02) ; v3(113.93,134.87) 113.93,135.02 113.38,135.56 U6.AJ10
  BOTTOM w0.102: v2(123.23,90.02) 123.23,90.32 123.9,91 v1(123.9,91.06) 123.9,91.5 126.2,93.8 126.2,102.35 124.81,103.73 123.12,103.73 110.55,116.31 110.55,119.08 108.85,120.78 108.85,125.09 111.9,128.14 111.9,132.33 113.55,133.99 113.55,134.49 v3(113.93,134.87)
CPU_VCORE: length 572.3
  TOP w0.203: L10.2 91.32,179.58 91.32,183.07 91.77,183.51 97.61,183.51 98.88,184.78 98.88,201.99 96.9,203.97 96.9,209.47 99.22,211.79 101.06,211.79 101.61,212.34 101.61,216.12 99.83,217.89 99.83,218.72 104.38,223.27 114.31,223.27 115.25,224.21 115.25,227 R46.2
  TOP w0.254: v2(104.02,183.71) L6.2 104.02,178.97 ; 118.37,233.27 PU2.20 ; 118.37,233.27 118.02,233.27 117.87,233.41 PU2.19 ; 118.37,233.27 118.37,232.65 v3(118.29,232.57) ; PU2.16 116.38,232.71 v3(116.16,232.5) 116.08,232.5 115.88,232.7 PU2.15 ; v2(117.62,227.02) 118.01,227.02 R45.2
  TOP w0.305: R318.1 73.24,53.72 72.34,53.72 71.38,54.67 69.55,54.67 67.33,56.9 v3(65.29,56.9) ; v2(63.13,123.57) 62.87,123.31 61.86,123.31 60.43,121.88 60.12,121.88 59.37,121.13 59.37,116.89 60.02,116.24 60.02,109.41 63.57,105.85 63.57,102.68 63.64,102.62 63.64,101.66 63.45,101.47 63.45,97.98 64.02,97.41 v2(64.02,97.03) ; v2(55.94,94.13) 55.94,92.47 56.78,91.63 56.78,87.84 57.94,86.68 57.94,84.07 60.01,82 60.01,75.09 58.71,73.79 58.71,72.79 58.2,72.29 58.2,68.22 58.71,67.72 58.71,58.68 58.89,58.49 58.89,58.37 v3(59.27,57.99) 59.4,57.86 59.4,55.85 58.66,55.12 58.66,44.98 61.1,42.55 61.1,39.31 59.07,37.27 59.07,34.61 58.08,33.62 57.43,33.62 57.08,33.27 56.07,33.27 R437.1
  TOP w0.356: v3(110.27,138.76) 109.62,138.11 U6.AG7 ; v3(122.92,153.95) 123.52,153.35 U6.R18 ; U6.R16 120.98,153.35 v3(120.41,153.92) ; v3(117.74,152.65) 118.43,153.35 U6.R14
  TOP w0.381: U6.L22 U6.M23 ; U6.AB11 v3(114.02,145.09) U6.AA10 ; U6.L10 v3(114.02,157.79) U6.M11 ; v3(115.2,159.15) U6.K11 ; U6.AF9 v3(112.75,140.01) U6.AE10 ; U6.P11 v3(114.02,155.25) U6.N10 ; U6.W12 v3(116.56,147.63) U6.Y13 ; U6.L20 U6.M19 v3(124.18,157.79) U6.L18 ; U6.L20 U6.K19 v3(124.18,160.33) U6.J18 ; U6.L20 U6.M21 ; U6.N12 v3(116.56,155.25) U6.P13 ; v3(102.59,152.71) 102.83,152.47 U6.T2 ; U6.V15 119.09,150.18 ; 119.09,150.18 v3(119.12,150.18) ; 119.09,150.18 U6.U14 ; U6.W5 v3(106.4,148.9) ; U6.AC5 v3(106.4,143.82) ; U6.AG4 v3(105.13,138.74) ; U6.AB19 v3(124.18,145.09) U6.AA18 ; U6.W18 v3(124.18,147.63) U6.Y19 ; v3(129.26,162.87) U6.H23 ; U6.AD2 v3(102.59,142.55) ; v3(110.27,161.48) 110.2,161.54 110.2,161.58 109.57,162.21 U6.H7 ; U6.Y21 v3(126.71,147.64) U6.W20 ; U6.AA16 v3(121.64,145.09) U6.AB17 ; U6.AE12 U6.AF11 ; U6.W22 v3(129.26,147.63) U6.Y23 ; U6.D5 v3(107.69,166.67) U6.E6 v3(108.94,165.42) U6.F7 U6.G8 U6.H7 ; U6.P21 v3(126.72,155.25) U6.N20 ; U6.V9 v3(111.48,150.17) U6.U8 ; U6.AD9 v3(111.48,142.55) U6.AC8 ; U6.T13 v3(116.56,152.71) U6.R12 ; 119.07,155.28 U6.P15 ; 119.07,155.28 U6.N14 ; 119.07,155.28 v3(119.12,155.28) ; U6.W4 v3(105.13,148.9) ; U6.K23 130.52,160.33 v3(130.55,160.33) ; U6.R5 v3(106.4,153.98) ; v3(102.62,137.43) 103.21,136.84 U6.AH2 ; U6.K21 v3(126.72,160.33) U6.J20 ; U6.L14 v3(119.1,157.79) U6.M15 ; U6.U10 v3(114.02,150.17) U6.V11 ; U6.B3 v3(105.09,169.26) U6.C4 ; U6.AA22 v3(129.26,145.09) U6.AB23 ; v3(119.12,160.33) 119.1,160.33 ; 119.1,160.33 U6.J14 ; 119.1,160.33 U6.K15 ; U6.K13 v3(116.56,160.33) U6.J12 ; U6.AH3 104.48,136.84 v3(103.89,137.43) ; U6.Y15 v3(119.1,147.63) U6.W14 ; U6.P19 v3(124.18,155.25) U6.N18 ; U6.Y7 110.31,146.26 v3(110.32,146.26) ; U6.H7 U6.G6 v3(107.67,164.14) U6.F5 v3(106.4,165.41) U6.E4 v3(105.19,166.62) U6.D3 v3(103.86,167.95) U6.C2 v3(102.59,169.22) ; v3(122.85,156.58) U6.M17 ; U6.Y2 v3(102.59,147.63) ; U6.J8 U6.K9 112.63,159.18 v3(112.9,159.18) ; U6.V21 v3(126.72,150.17) U6.U20 ; U6.T11 v3(114.02,152.71) U6.R10 ; U6.T19 U6.R18 ; U6.AA8 v3(111.48,145.09) U6.AB9 ; U6.Y11 v3(114.02,147.63) U6.W10 ; v3(124.18,142.55) U6.AC18 ; U6.N22 129.33,155.18 v3(129.37,155.18) 129.37,155.14 U6.P23 ; v3(103.86,152.71) 104.11,152.46 U6.T3 ; U6.Y3 v3(103.86,147.63) ; U6.P7 110.26,155.31 v3(110.29,155.31) 110.29,155.34 U6.N8 v3(111.48,155.25) U6.P9 ; U6.AB7 110.23,143.8 v3(110.32,143.8) ; U6.AB13 v3(116.56,145.09) U6.AA12 ; U6.T17 U6.R16 ; U6.T23 v3(129.26,152.71) U6.R22 ; U6.T9 v3(111.48,152.71) U6.R8 110.29,152.79 v3(110.27,152.79) 110.27,152.77 U6.T7 ; U6.L12 v3(116.56,157.79) U6.M13 ; U6.R4 v3(105.13,153.98) ; U6.R20 v3(126.72,152.71) U6.T21 ; v2(112.52,224.4) 106.01,224.4 104.21,226.19 v2(104.21,230.06) ; U6.N16 v3(121.64,155.25) U6.P17 ; U6.AA14 119.11,145.08 ; 119.11,145.08 U6.AB15 ; 119.11,145.08 v3(119.12,145.08) ; U6.AC10 v3(114.02,142.55) U6.AD11 ; U6.AG5 v3(106.4,138.74) ; U6.Y17 v3(121.64,147.63) U6.W16 ; v3(116.56,142.55) U6.AC12 ; U6.U16 v3(121.64,150.17) U6.V17 ; U6.T15 U6.R14 ; U6.M7 110.24,157.82 v3(110.24,157.82) 110.24,157.82 U6.L8 v3(111.48,157.79) U6.M9 ; U6.V19 v3(124.18,150.17) U6.U18 ; U6.U12 v3(116.56,150.17) U6.V13 ; v3(126.72,142.55) U6.AC20 ; v3(110.27,138.76) 110.19,138.76 U6.AF7 ; U6.W8 v3(111.48,147.63) U6.Y9 ; U6.U22 v3(129.26,150.17) U6.V23 ; U6.AB21 v3(126.72,145.09) U6.AA20 ; U6.AD7 110.24,141.25 v3(110.24,141.24) ; U6.M3 v3(103.86,157.79) ; v3(119.1,142.55) U6.AC14 ; U6.AD3 v3(103.86,142.55) ; U6.K17 v3(121.64,160.33) U6.J16 ; U6.AC22 v3(129.26,142.55) U6.AD23 ; v3(131.8,161.6) U6.J24 ; U6.J22 v3(129.26,160.33) ; U6.L5 v3(106.4,159.06) ; U6.AC4 v3(105.13,143.82) ; U6.L16 v3(120.45,158.98) ; U6.L4 v3(105.13,159.06)
  TOP w0.4: U6.N22 U6.M21 ; U6.J24 130.55,160.36 v3(130.55,160.33) ; U6.H11 U6.J12 ; v3(120.39,143.81) 121,143.2 U6.AC16 ; U6.AD9 U6.AE10 U6.AF11 ; U6.K7 109.57,159.69 108.95,159.06 108.95,157.79 U6.M7 ; v3(129.26,160.33) U6.K23 130.52,159.08 130.52,157.78 U6.M23 ; U6.R22 U6.P21 ; U6.D5 v3(106.42,167.93) U6.C4 ; U6.AA22 U6.Y21 ; U6.W22 U6.V21 ; U6.AC22 U6.AB21 ; U6.K21 U6.L22 ; U6.U22 U6.T21
  TOP w0.508: U6.M2 v3(102.59,157.79)
  INT1 w0.305: v2(80.4,129.67) 80.4,132.84 81.35,133.79 81.35,134.43
  BOTTOM w0.203: v2(117.62,227.02) 117.74,226.9 117.74,223.65 116.09,222 116.09,205.79 111.39,201.09 111.39,194.22 111.31,194.14 105.22,188.05 105.22,184.84 104.09,183.71 v2(104.02,183.71)
  BOTTOM w0.305: v2(80.4,129.67) 65.16,129.67 63.76,128.27 63.76,124.21 v2(63.13,123.57) ; v2(55.94,94.13) 56.61,94.13 59.49,97 63.99,97 v2(64.02,97.03) ; v3(59.27,57.99) 59.4,58.12 64.07,58.12 v1(64.65,57.54) v3(65.29,56.9)
  BOTTOM w0.381: v2(99.71,181.1) 99.39,181.42 99.39,201.04 100.53,202.18 105.67,202.18 108.21,204.72 108.21,208.28 109.23,209.3 112.66,209.3 113.68,210.31 113.68,211.71 114.06,212.09 114.06,222.86 v2(112.52,224.4) 112.52,231.25 113.76,232.5 v3(116.16,232.5) 116.23,232.57 v3(118.29,232.57) ; PR67.2 108.41,233.33 108.41,231.58 108.02,231.2 105.17,231.2 104.21,230.25 v2(104.21,230.06)
  BOTTOM w0.5: v3(129.26,142.55) 129.17,142.46 129.17,141.28 C415.1
  BOTTOM w0.508: v3(102.59,169.22) 102.18,169.63 C360.1
  vias: v1(85.35,181.1) v1(90.18,180.97) v1(91.58,178.69) v1(93.17,180.97) v1(95.9,180.91) v1(95.9,178.63) v1(99.32,175.13) v1(102.94,180.85) v1(103.13,177.99) v2(87.01,181.17) v2(87.01,179.9) v2(87.01,178.63) v2(87.01,177.36) v2(87.01,176.09) v2(88.34,181.1) v2(88.34,179.83) v2(88.34,178.56) v2(88.34,177.29) v2(88.34,176.02) v2(94.63,181.1) v2(94.63,179.83) v2(94.63,178.56) v2(97.17,181.1) v2(97.17,179.83) v2(97.17,178.56) v2(97.17,177.29) v2(98.44,181.1) v2(98.44,179.83) v2(98.44,178.56) v2(98.44,177.29) v2(99.71,179.83) v2(99.71,178.56) v2(99.71,177.29) v2(100.98,181.1) v2(100.98,179.83) v2(100.98,178.56) v2(100.98,177.29)
CPU_VDD_FB_H: length 113.3
  TOP w0.152: U6.G2 102.7,164.03 101.34,164.03 97.07,168.3 95.9,168.3 v5(95.58,168.62) ; v2(107.12,232.64) 107.46,232.97 PR22.1
  BOTTOM w0.102: v5(95.58,168.62) 95.93,168.28 96.12,168.28 96.53,167.86 96.53,167.26 94.11,164.83 81.52,164.83 80.58,165.78 80.58,169.95 81.15,170.52 81.15,176.19 80.25,177.1 80.25,179.24 85.29,184.29 85.29,198.82 85.48,199.01 85.48,200.72 86.5,201.74 87.48,201.74 88.28,202.55 88.28,206.97 90.69,209.37 92.16,209.37 98.72,215.93 98.72,224.42 101.04,226.75 101.04,230.57 102.69,232.22 106.75,232.22 107.12,232.59 v2(107.12,232.64)
  BOTTOM w0.152: v2(107.12,232.64) 107.46,232.97 107.46,233.43 PR67.1
CPU_VDD_FB_L: length 119.7
  TOP w0.152: v2(95.58,167.73) 95.9,168.05 96.96,168.05 101.23,163.78 101.3,163.78 101.57,163.51 U6.G1 ; PU2.7 113.46,237.03 113.31,237.18 110.83,237.18 109.99,236.34 109.99,233.27 109.41,232.69 108.55,232.69 108.39,232.54 PR15.1 107.7,232.15 v2(107.53,231.98)
  BOTTOM w0.102: v2(95.58,167.73) 95.93,168.07 96.03,168.07 96.33,167.78 96.33,167.34 94.02,165.04 81.61,165.04 80.78,165.86 80.78,169.86 81.35,170.43 81.35,176.28 80.45,177.18 80.45,179.16 85.55,184.26 85.55,198.69 85.74,198.88 85.74,200.64 86.58,201.49 87.53,201.49 88.5,202.46 88.5,206.9 90.75,209.15 92.27,209.15 98.94,215.82 98.94,224.29 101.24,226.59 101.24,230.48 102.77,232.02 106.86,232.02 106.89,231.98 v2(107.53,231.98)
CPU_VDDA_RUN_OUT:
  vias: v1(136.85,233.17) v1(136.85,230.89)
CPU_VDDIO_FB_H: length 19.1
  TOP w0.102: TP88.1 112.28,118.75 112.28,122.71 111.54,123.44 111.54,124.82 111.26,125.09 111.26,129.44 114.16,132.33 114.74,132.33 115.25,132.84 115.25,133.73 114.68,134.3 U6.AK11
CPU_VDDIO_FB_L: length 15.2
  TOP w0.102: U6.AL11 114.5,133.03 110.88,129.41 110.88,124.97 111.24,124.61 111.24,123.93 110.96,123.65 110.96,122.05 111.64,121.36 TP85.1
CPU_VDDNB_RUN_FB_H: length 108
  TOP w0.152: v2(127.34,234.77) 127.24,234.67 126.93,234.67 126.71,234.89 PR17.1 ; U6.G4 104.98,162.73 101.17,162.73 99,164.9 96.87,164.9 96.58,165.18 96.58,165.43 v2(96.2,165.81)
  BOTTOM w0.152: PR65.1 126.99,235.48 127.34,235.13 v2(127.34,234.77) 127.32,234.79 126.23,234.79 125.61,234.17 125.61,233.54 126.14,233.02 127.97,233.02 128.48,232.5 128.48,230.32 131.99,226.81 131.99,212.3 123.47,203.78 118.8,203.78 116.69,201.68 114.35,201.68 113.29,200.62 113.29,193.9 107.38,187.98 107.38,183.49 106.44,182.55 106.44,177.98 103.67,175.21 101.78,175.21 97.06,170.49 97.06,166.86 96.54,166.34 96.54,166.04 96.32,165.81 v2(96.2,165.81)
CPU_VDDNB_RUN_FB_L: length 111.2
  TOP w0.152: v2(97.09,165.84) 96.84,165.59 96.84,165.28 96.97,165.15 99.11,165.15 101.24,163.02 104,163.02 U6.G3 ; PU2.30 121.79,237.03 121.92,237.16 122.87,237.16 124.12,235.92 124.12,235.02 124.41,234.72 125.61,234.72 125.82,234.52 PR25.1 125.84,234.26 126.22,234.65 126.4,234.65 126.88,234.16 v2(126.88,234.09)
  BOTTOM w0.152: v2(97.09,165.84) 96.95,165.84 96.8,165.99 96.8,166.23 97.32,166.76 97.32,170.39 101.89,174.96 103.91,174.96 106.72,177.76 106.72,182.47 107.63,183.38 107.63,187.88 113.55,193.8 113.55,194.01 113.55,194.01 113.55,200.51 114.43,201.4 116.77,201.4 118.9,203.53 123.58,203.53 132.24,212.2 132.24,226.92 128.74,230.42 128.74,232.61 128.07,233.27 126.24,233.27 125.87,233.65 125.87,234.07 126.27,234.47 126.76,234.47 126.88,234.34 v2(126.88,234.09)
CPU_VDDR_SUS_SENSE: length 1.9
  TOP w0.102: v3(115.29,166.69) 115.92,166.05 U6.E12
  BOTTOM w0.102: v3(115.29,166.69) 114.72,167.26 TP118.1
CTSA: length 6.5
  TOP w0.102: U16.23 140.39,22.76 140.54,22.61 142.89,22.61 v2(143.2,22.29)
  BOTTOM w0.102: v2(143.2,22.29) 144.22,22.29 144.54,21.97 144.81,21.97 145.38,21.41 L72.1
CTSA_L: length 30
  TOP w0.102: C340.1 J6.8
  BOTTOM w0.102: L72.2 145.48,20.12 145.91,19.68 v1(150.38,19.68) 151.08,18.99 151.08,15.62 152.41,14.29 152.41,8.57 152.79,8.19 158.67,8.19 J6.8
DAC_RSET: length 20.2
  TOP w0.165: v3(62.22,153.11) 63.04,153.11 U3.G14
  BOTTOM w0.165: v3(62.22,153.11) 61.86,153.46 61.86,154.51 61.55,154.82 61.55,155.82
  BOTTOM w0.254: 61.55,155.82 61.55,156.9 61.1,157.35 61.1,160.15 v1(61.54,160.59) 61.92,160.97 61.92,163.39 61.5,163.8 61.01,163.8 60.72,164.1 60.72,169.16 60.26,169.62 R546.2
DBGSELECT2: length 12.2
  TOP w0.102: R271.1 R270.1 110.88,79.68 v1(110.42,79.22) 109.52,78.31 105.27,78.31 104.07,77.11 104.07,74.95 U10.AF26
DCDA: length 2.8
  TOP w0.102: v2(141.87,17.46) 141.99,17.46 142.34,17.12 U16.9
  BOTTOM w0.102: L75.1 141.49,17.84 v2(141.87,17.46)
DCDA_L: length 33.2
  TOP w0.102: J6.1 154.7,4.09 154.7,6.16 154.06,6.79 153.05,6.79 152.73,7.11 C335.1
  BOTTOM w0.102: J6.1 151.2,3.05 149.43,4.83 149.43,10.73 v1(149.68,10.99) 149.43,11.24 149.43,16.95 148.22,18.16 142.95,18.16 142.19,18.92 142.19,19.65 142.01,19.82 L75.2
DCIN: length 3.8
  BOTTOM w0.508: C551.1 R761.1 ; C551.1 153.62,22.35 v1(153.49,22.48) ; C551.1 153.25,21.35 v2(152.73,20.83)
  vias: v1(135.96,10.03) v1(136.09,12.89) v1(136.85,7.56) v1(147.71,7.94) v1(148.28,5.59) v2(144.85,12.83) v2(145.43,11.3) v2(145.49,14.41) v2(146,12.83) v2(146.44,11.3) v2(146.63,14.41) v2(147.08,12.83) v2(147.46,11.3) v2(148.28,12.83) v2(148.6,11.37)
DDC_CLK0: length 44.1
  TOP w0.102: v2(47.31,167.46) 47.28,167.43 R139.2 ; CN7.13 56.99,185.84 v2(57.01,185.83)
  TOP w0.125: R139.2 47.89,163.83 48.91,163.83 50.71,162.03 54.47,162.03 57.03,159.46 57.31,159.46 58.35,158.42 58.35,158.15 U3.A8
  BOTTOM w0.102: v2(47.31,167.46) 47,167.77 47,174.88 49.99,177.86 52.02,177.86 52.97,178.82 55.51,178.82 56.91,180.21 56.91,182.75 57.48,183.32 v1(57.48,183.96) 57.48,185.35 v2(57.01,185.83)
DDC_CLK1: length 16.7
  TOP w0.102: TP47.1 44.84,160.22 45.02,160.4 46.16,160.4 47.75,161.99 49.23,161.99 50.43,160.78 53.96,160.78 56.25,158.5 56.93,158.5 57.19,158.24 57.19,157.31 U3.B7
DDC_DATA0: length 48.4
  TOP w0.1: 58.19,157.8 58.16,157.87
  TOP w0.102: CN7.14 57.99,185.87 v2(56.91,184.78) ; U3.B8 58.19,157.8 ; 58.16,157.87 58.16,157.87 58.1,158.03 58.1,158.24 57.14,159.21 ; v2(46.47,168.2) 46.04,168.2 45.48,167.64 45.48,163.19 45.86,162.81 46.67,162.81 R141.2
  TOP w0.125: R141.2 47.91,162.79 49.5,162.79 50.6,161.7 54.44,161.7 56.93,159.21 57.14,159.21
  BOTTOM w0.102: v2(46.47,168.2) 46.75,168.48 46.75,175.01 v1(50.3,178.56) 52.33,178.56 52.84,179.07 55.38,179.07 56.65,180.34 56.65,184.53 v2(56.91,184.78)
DDC_DATA1: length 15.8
  TOP w0.102: U3.A7 57.54,157.76 57.54,158.19 57.03,158.7 56.73,158.7 54.44,160.99 50.54,160.99 49.25,162.28 47.59,162.28 45.98,160.68 45.2,160.68 TP44.1
DDR3_P1V5_CS: length 3.9
  TOP w0.254: PR37.1 155.2,224.93 v1(155.2,226.12) 155.2,226.49 154.06,227.64 PU3.16
DDR3_P1V5_DH: length 4.9
  TOP w0.254: 156.98,230 155.87,230 PU3.21
  TOP w0.508: 156.98,230 157.49,230 v1(157.97,229.51) 158.25,229.24 158.25,228.09 158.63,227.71 PR24.1
DDR3_P1V5_DL: length 21
  TOP w0.254: 156.6,228.09 156.6,228.73 156.33,229 PU3.19
  TOP w0.635: PQ2.G1 170.52,226.31
  TOP w0.762: 170.52,226.31 164.73,226.31 162.44,224.03 158,224.03 v1(157.43,224.6) 156.6,225.43 156.6,228.09
DDR3_P1V5_EN_S3: length 8.1
  TOP w0.102: PR87.1 145.63,229.93 148.16,229.93 148.4,230.17 PR11.2 149.05,230.5 v1(149.36,230.82) 150.18,230 PU3.10
DDR3_P1V5_EN_S5: length 5.1
  TOP w0.102: PU3.11 150.07,229.5 v1(149.43,228.85) 148.92,229.36 PR14.2 PR29.1
DDR3_P1V5_FILT: length 22.3
  TOP w0.254: PU3.14 153.06,226.89 v2(152.28,226.11) 152.28,225.18 PR19.2 ; PU3.6 152.56,233.15 v2(152.23,233.48) ; 155.33,222.71 PR37.2 ; 155.33,222.71 v2(155.84,222.71) ; 155.33,222.71 155.33,221.86 PC30.1
  BOTTOM w0.381: v2(152.23,233.48) 151.78,233.48 150.4,232.11 150.4,228 v1(151.08,227.33) 151.86,226.54 151.86,226.53 v2(152.28,226.11) 153.53,226.11 155.84,223.8 v2(155.84,222.71)
DDR3_P1V5_LL: length 44.1
  TOP w0.254: v2(157.11,229.11) 156.72,229.5 PU3.20
  TOP w0.508: v2(157.11,229.11) 157.49,228.73 157.49,227.71 158.25,226.95 158.25,225.81 158.63,225.43 PR26.2
  BOTTOM w0.508: PR72.2 v2(178.94,234.81)
  BOTTOM w0.762: v2(157.11,229.11) 161.55,229.11 162.47,230.02 162.47,236.5 165.11,239.14 178.04,239.14 181.37,235.82 v1(181.37,235.52) 181.37,235.08 v2(180.86,234.57) ; PR68.1 v2(179.84,227.2)
DDR3_P1V5_SET: length 7.2
  TOP w0.254: PU3.9 150.7,230.5 149.58,231.62 PC5.1 149.54,231.89 PR2.1 148.02,231.89 PR27.2 146.28,231.05 v1(146.38,230.95)
DDR3_P1V5_VBST: length 7.5
  TOP w0.254: v1(162.38,230.76) 162.13,230.5 159.97,230.5 159.39,229.92 PC19.1 158.5,230.5 PU3.22
DDRQ0_N: length 11.6
  TOP w0.102: U10.J25 91.37,73.62 v3(91.64,73.89)
  BOTTOM w0.102: R635.1 86.75,81.89 v1(86.75,81.66) 86.75,81.48 91.24,77 91.24,74.29 v3(91.64,73.89)
DDRQ1_N: length 23.7
  TOP w0.102: v2(119.67,70.46) 119.67,72.19 R284.1 ; U10.AA18 99.55,68.02 v3(99.91,68.38)
  BOTTOM w0.102: v3(99.91,68.38) 99.91,68.35 100.52,67.74 101.31,67.74 101.59,67.47 105.28,67.47 105.94,68.14 109.83,68.14 110.94,69.24 v1(118.3,69.24) 118.37,69.24 119.49,70.36 119.57,70.36 v2(119.67,70.46)
DDSPC_HPD: length 52.1
  TOP w0.102: R57.2 27.75,209.12 28.2,208.66 28.2,207.34 R771.1 27.59,206.83 26.81,206.06 16.52,206.06 15.25,204.79 15.25,202.02 14.69,201.47 14.69,182.21 13.35,180.87 9.67,180.87 8.16,179.36 8.16,178.57 9.44,177.29 Q96.D
DP_A_HPD: length 14.5
  TOP w0.102: R66.1 13.85,208.94 v1(13.85,210.82) 14.3,210.38 20.29,210.38 21.25,211.34 CN1.276
DP_B_HPD: length 12.2
  TOP w0.102: CN1.274 21.75,211.46 20.45,210.16 15.99,210.16 v1(15.25,209.42) 15.72,208.96 R67.1
DP_D_HPD: length 11.9
  TOP w0.102: v1(26.68,207.39) 26.3,207.39 25.6,208.09 25.6,209.68 25.9,209.98 R56.1 26.14,210.8 27.11,211.77 27.93,211.77 28.2,212.04 29.63,212.04 31.25,213.66 CN1.236
DRV_P0_ENABLE: length 61.7
  TOP w0.254: v2(96.28,212.22) 96.02,212.47 92.6,212.47 R53.1 ; PU2.43 117.38,241.71 v3(117.33,241.76)
  TOP w0.305: v2(112.6,213.11) 112.35,212.86 R54.1
  BOTTOM w0.254: v2(112.6,213.11) 113.55,214.06 113.55,222.22 110.91,224.87 110.91,230.91 113.6,233.6 113.6,239.83 114.69,240.92 116.32,240.92 117.16,241.76 v3(117.33,241.76)
  BOTTOM w0.381: v2(112.6,213.11) 112.66,213.04 112.66,211.96 113.09,211.53 113.09,210.72 112.41,210.03 109.31,210.03 109.1,210.24 109.1,210.25 v1(108.34,211.01) 105.23,211.01 104.53,211.71 96.78,211.71 v2(96.28,212.22)
DSRA: length 2.8
  TOP w0.102: U16.4 139.09,16.75 139.52,17.18 139.62,17.18 v2(139.96,17.53)
  BOTTOM w0.102: v2(139.96,17.53) L76.1
DSRA_L: length 38
  TOP w0.102: J6.6 158.01,5.59 156.73,6.85 C338.1
  BOTTOM w0.102: J6.6 157.52,4.38 150.7,4.38 149.68,5.4 149.68,10.16 150.76,11.24 v1(150.76,12.57) 149.68,13.65 149.68,17.08 148.35,18.41 143.08,18.41 142.44,19.05 142.44,20.19 142.19,20.45 140.22,20.45 139.96,20.19 L76.2
DTRA: length 5
  TOP w0.102: U16.1 136.77,16.57 v2(135.39,16.57)
  BOTTOM w0.102: L79.1 v2(135.39,16.57) 135.39,15.49 v1(135.65,15.24)
DTRA_L: length 37.3
  TOP w0.102: J6.4 155.66,5.59 154.19,7.04 154.19,7.56 ; 154.19,7.56 v2(153.49,7.56) 153.51,7.57 C336.1 154.19,7.56
  BOTTOM w0.102: v2(153.49,7.56) 152.98,7.05 150.63,7.05 150.44,7.24 150.44,8.64 151.59,9.78 v1(151.59,10.29) 151.9,10.6 151.9,14.03 150.57,15.37 150.57,17.27 148.66,19.18 143.46,19.18 143.2,19.43 143.2,20.7 142.72,21.18 137.87,21.18 137.18,20.49 136.37,20.49 135.44,19.57 L79.2
EAPD_MUTE_CTRL: length 44.9
  TOP w0.102: R414.1 v2(32.84,40.85) ; v2(20.36,20.35) 20.1,20.35 19.95,20.19 18.76,20.19 18.35,19.79 11.92,19.79 v2(11.75,19.96)
  BOTTOM w0.102: v2(32.84,40.85) 32.83,40.85 31.93,39.94 31.93,33.08 32.46,32.55 32.46,27.83 33.21,27.08 33.21,26.06 30.74,23.6 v1(30.74,22.68) 30.74,20.42 30.06,19.74 27.77,19.74 27.24,20.27 20.43,20.27 v2(20.36,20.35) ; U26.2 11.12,19.67 11.42,19.96 v2(11.75,19.96)
EAR_L_FIL: length 12.5
  BOTTOM w0.254: L59.2 C490.1 16.38,66.87 v1(15.38,66.87) 14.74,66.23 D14.2 12.7,66.94 10.65,69 CN20.2
EAR_R_FIL: length 7.1
  BOTTOM w0.254: v1(13.41,60.83) 13.42,60.85 L61.2 C491.1 13.42,63.61 13.44,63.62 13.44,63.89 13.01,64.33 D14.1 12.4,64.33 11.87,63.8 CN20.3
EC_A20M_N: length 179.5
  TOP w0.102: v2(116.77,55.98) 116.29,55.5 116.29,51.49 116.83,50.95 116.83,40.56 115.38,39.12 115.38,28.88 114.64,28.15 102.35,28.15 97.27,23.06 89.5,23.06 82.84,29.72 82.84,31.22 77.05,37.01 74.94,37.01 73.42,38.53 73.42,41.02 71.19,43.24 70.18,43.24 69.67,43.75 64.78,43.75 63.76,44.77 63.76,46.48 61.55,48.7 61.55,49 v2(59.88,50.67) ; v3(101.55,70.74) 101.94,70.35 U10.AD21 ; v2(53.92,52.9) 52.39,51.36 52.39,50.88 51.31,49.8 46.07,49.8 44.97,48.69 44.97,45.75 44.49,45.27 44.49,44.81 44.23,44.54 44.23,43.74 44.5,43.48 46.2,43.48 46.62,43.05 46.62,42.55 46.51,42.43 U11.11
  BOTTOM w0.102: v2(116.77,55.98) 117.49,56.69 120.97,56.69 126.76,62.48 126.76,68.88 121.55,74.09 121.55,74.36 120.66,75.25 111.39,75.25 110.44,74.3 109.48,74.3 109.12,74.66 R649.1 107.96,74.8 107.58,74.42 107.58,73.34 106.69,72.45 105.61,72.45 103.31,70.15 102.2,70.15 101.61,70.74 v3(101.55,70.74) ; v2(59.88,50.67) 59.14,51.41 56.12,51.41 v1(55.15,52.37) 54.63,52.9 v2(53.92,52.9)
EECS_LAN: length 4.8
  BOTTOM w0.102: v1(121.04,35.64) 121.3,35.89 121.3,36.12 121.68,36.5 ; U24.30 122.6,33.98 122.54,34.04 122.54,34.67 122.29,34.92 122.29,35.45 121.68,36.07 121.68,36.5 ; 121.68,36.5 R720.2
EEDI: length 3.6
  BOTTOM w0.102: U24.32 123.4,33.91 123.02,34.29 123.02,35.64 v1(123.07,35.69) 122.69,36.07 R719.2
EEDO_LED3: length 33.7
  TOP w0.102: v2(122.06,40.03) 120.43,40.03 120.23,39.83 119.09,39.83 118.88,39.62 118.88,39.01 119.52,38.38 119.52,34.47 117.36,32.31 117.36,28.98 115.58,27.2 115.58,20.11 R489.2
  BOTTOM w0.102: U24.31 123,33.96 122.79,34.17 122.79,34.8 122.51,35.08 122.51,35.56 122.18,35.89 122.18,38.1 122.57,38.48 122.57,39.52 v2(122.06,40.03) 121.99,40.09 v1(121.99,40.89)
EEDO_LED3_R: length 33.6
  TOP w0.102: R489.1 114.69,18.37 114.69,18.08 R510.2 ; R510.2 113.83,17.22 113.83,5.94 116.09,3.68 125.61,3.68 127.65,5.71 129.95,5.71 CN23.L4 ; R510.2 v1(113.17,17.53)
EESK_LED1: length 45.5
  TOP w0.102: v2(130.82,34.95) 128.41,37.36 128.41,38.73 127.26,39.88 124.34,39.88 123.71,40.51 122.69,40.51 122.5,40.7 120.67,40.7 120.03,40.06 118.96,40.06 118.63,39.73 118.63,38.91 119.26,38.28 119.26,34.54 117.16,32.44 117.16,29.08 115.26,27.19 115.26,21.07 113.93,19.74 R509.2
  BOTTOM w0.102: v1(130.59,34.29) 130.82,34.52 v2(130.82,34.95) 130.59,35.18 128.03,35.18 125.66,32.81 U24.37
EESK_LED1_R: length 35.8
  TOP w0.102: C313.1 112.66,18.29 112.53,18.16 112.53,17.27 113.6,16.21 113.6,5.85 116.15,3.3 126.74,3.3 CN23.L3 ; C313.1 R509.1 ; C313.1 113.29,19.51 113.29,22.05 R490.2 v1(112.15,22.23)
EN_LAN_SW: length 7.9
  BOTTOM w0.102: v1(123.26,38.99) 123.9,38.99 124.28,38.61 124.28,37.02 124.77,36.53 ; U24.33 123.8,34.27 123.65,34.43 123.65,35.62 123.71,35.69 R708.1 124.77,36.53 ; R707.1 124.77,36.53
ENABKL: length 26.3
  TOP w0.102: v2(181.62,56.9) 182,57.28 183.27,57.28 183.57,56.97 R312.2 185.24,56.64 185.25,56.65 CN27.7
  BOTTOM w0.102: v2(181.62,56.9) v1(181.62,54.48) 181.62,50.29 182.26,49.66 185.81,49.66 188.73,46.74 188.73,45.21 189.75,44.2 190.51,44.2 190.76,43.94 R704.1
ENABKL_R: length 7.9
  TOP w0.102: R355.1 182.29,55.17 R357.1 182.38,56.31 R312.1 ; R355.1 179.92,55.17 v1(179.84,55.24) ; R355.1 180.92,55.23 Q22.S 180.92,57.34 181.57,57.99 R343.2
EXT_PCIE_LAN_CLKREQ_N: length 7.3
  BOTTOM w0.102: R737.2 R735.2 115.2,27.05 v1(115.71,27.56) 116.15,28 117.99,28 119.35,29.36 U24.16
FC_CLK_R: length 14.1
  TOP w0.102: R263.1 112.91,82.17 112.66,81.92 112.66,79.78 v1(112.89,79.55) 112.89,78.31 112.28,77.7 112.28,77.44 111.9,77.06 111.49,77.06 110.58,77.98 110.12,77.98 109.39,77.25 106.37,77.25 U10.AH28
FC_FBCLKOUT_R: length 15.5
  TOP w0.102: U10.AG28 104.81,76.49 104.81,77.5 105.29,77.98 109.74,77.98 109.99,78.23 111.14,78.23 v1(111.64,77.72) 112.13,78.21 112.13,79.6 112.41,79.88 112.41,81.48 111.9,81.99 R262.1 R261.1
FP_RST_N: length 34.7
  TOP w0.102: v2(111.42,40.67) 111.34,40.59 R389.2 C276.1 109.63,40.57 SW1.2 SW1.1 ; R367.1 90.62,38.51 v2(98.69,38.51)
  BOTTOM w0.102: v2(111.42,40.67) 107.71,40.67 105.55,38.51 104.63,38.51 v1(104.6,38.54) 104.56,38.51 v2(98.69,38.51)
FP_RST_R_N: length 18
  TOP w0.102: U10.J1 90.84,54.47 88.25,51.89 88.25,51.03 v1(87.96,50.74) 88.25,50.44 88.25,49.58 87.23,48.57 87.23,46.19 87.59,45.83 87.59,44.44 87.92,44.11 87.92,43.07 88.58,42.42 88.97,42.42 89.29,42.1 89.29,41.14 89.42,41.01 R367.2
GBE_COL: length 8.2
  TOP w0.102: U10.T1 95.64,55.25 v2(96.02,54.86) 96.02,52.07 96.33,51.77 96.33,50.62 97.86,49.09 R325.2
GBE_CRS: length 16.4
  TOP w0.102: U10.T4 95.26,57.34 95.26,54.93 95.82,54.37 95.82,51.69 96.12,51.38 96.12,50.47 97.37,49.22 97.37,46.47 97.74,46.1 R341.2 98.12,45.64 98.25,45.51 98.25,43.43 v1(97.86,43.05)
GBE_LED1: length 11.3
  TOP w0.102: U10.D7 86.41,59.69 84.34,59.69 82.04,57.39 80.87,57.39 79.21,55.73 79.21,55.72 78.73,55.24 TP96.1
GBE_LED2: length 1.3
  TOP w0.102: v3(89.67,58.99) 89.34,58.66 U10.G5
  BOTTOM w0.102: v3(89.67,58.99) TP200.1
GBE_MDIO: length 9.8
  TOP w0.102: U10.L5 92.51,58.62 v3(92.92,59.03)
  BOTTOM w0.102: v3(92.92,59.03) 92.92,58.65 93.31,58.26 93.31,54.99 90.82,52.49 v1(90.82,52.39) 90.82,51.86 R703.1
GBE_PHY_INTR: length 3.1
  TOP w0.102: v3(97.6,60.66) 97.16,60.22 U10.V7
  BOTTOM w0.102: R683.1 97.67,60.58 v3(97.6,60.66) 97.59,60.66 v1(97.59,61.38)
GBE_RXERR: length 17.4
  TOP w0.102: v1(99.83,42.99) 99.26,43.56 99.26,45.51 99.13,45.64 R342.2 98.75,46.04 98.37,46.42 98.37,48.9 96.53,50.74 96.53,54.94 96.8,55.21 96.8,58.45 U10.V5
GBE_SATA0: length 16.1
  TOP w0.102: U10.K3 91.64,56.68 91.98,56.34 91.98,55.17 91.76,54.94 91.76,54.24 90.1,52.59 v2(90.1,51.52) ; TP102.1 91.96,43.05 v1(91.96,43.88) 91.96,44.26 91.32,44.89 91.32,45.85 90.76,46.41 v3(90.75,48.94)
  BOTTOM w0.102: v2(90.1,51.52) 90.31,51.32 90.31,49.38 v3(90.75,48.94)
GFX_CLK_DN: length 156.2
  TOP w0.099: v2(47.51,227.84) 48.02,227.33 49.2,227.33 49.88,226.65 49.88,224.12 50.23,223.77 51.65,223.77 51.88,223.55 51.88,223.27 52,223.14 CN1.153
  INT1 w0.089: v2(47.51,227.84) 47.51,227.52 47.31,227.32 46.81,227.32 46.43,226.95 46.43,222.57 45.67,221.81 41.58,221.81 40.14,220.37 40.14,214.76 36.71,211.33 36.71,190.94 32.64,186.87 32.64,179.02 26.45,172.83 22.52,172.83 21.3,171.61 21.3,169.37 20.98,169.05 20.98,166.83 18.62,164.47 18.62,137.54 17.47,136.4 17.47,133.41 18.04,132.84 18.04,130.39 16.72,129.07 16.72,117.78 22.41,112.09 26.8,112.09 v2(27.06,111.82)
  BOTTOM w0.099: v2(27.06,111.82) 27.32,112.08 29.92,112.08 30.49,111.51 30.49,109.9 R584.2
GFX_CLK_DP: length 155.4
  TOP w0.099: v5(47.51,226.57) 48.02,227.08 49.1,227.08 49.62,226.55 49.62,224.02 50.12,223.52 51.55,223.52 51.62,223.44 51.62,223.26 51.5,223.14 CN1.155
  INT1 w0.089: v5(47.51,226.57) 47.51,226.88 47.31,227.08 46.91,227.08 46.67,226.85 46.67,222.47 45.77,221.56 41.68,221.56 40.38,220.27 40.38,214.66 36.96,211.23 36.96,190.84 32.88,186.77 32.88,178.92 26.55,172.59 22.62,172.59 21.54,171.51 21.54,169.27 21.22,168.95 21.22,166.73 18.86,164.36 18.86,137.44 17.71,136.3 17.71,133.51 18.29,132.94 18.29,130.29 16.97,128.97 16.97,117.88 22.51,112.33 26.74,112.33 v2(27.06,112.65)
  BOTTOM w0.099: R583.2 30.74,109.9 30.74,111.61 30.02,112.33 27.38,112.33 v2(27.06,112.65)
GFX_CLK_R_DN: length 4.3
  BOTTOM w0.099: R584.1 30.22,108.66 30.46,108.43 30.46,108.43 30.55,108.33 30.55,108.01 v1(30.11,107.57) 30.62,107.06 30.62,105.98 30.59,105.95 U20.38
GFX_CLK_R_DP: length 4.5
  BOTTOM w0.099: U20.39 31.09,105.95 30.87,106.16 30.87,107.06 v1(31.38,107.57) 31.09,107.57 30.81,107.85 30.81,108.35 R583.1
GFX_TX8N_C: length 84.6
  TOP w0.102: U3.H2 53.27,152.46 52.97,152.15 52.71,152.15 52.61,152.26 52.05,152.26 51.07,153.24 51,153.24 50.99,153.26
  TOP w0.152: 50.99,153.26 49.97,154.27 48.38,154.27 44.6,158.05 42.89,158.05 41.54,159.39 38.87,159.39 v5(38.56,159.08) ; v2(55.99,206.6) 55.77,206.38 54.58,206.38 54.02,206.95 53.54,207.42 52.7,208.26 52.7,208.58 C57.1
  BOTTOM w0.152: v5(38.56,159.08) 38.54,159.08 38.19,159.44 36.83,159.44 34.9,161.37 34.9,180 35.17,180.27 35.17,189.95 48.99,203.77 49.75,203.77 52.26,206.28 55.67,206.28 v2(55.99,206.6)
GFX_TX8P_C: length 84.7
  TOP w0.102: U3.H1 52.14,152.46 51.2,153.39 51.2,153.46 51.19,153.47
  TOP w0.152: 51.19,153.47 50.09,154.57 48.5,154.57 47.92,155.14 47.92,155.15 47.92,155.36 47.5,155.79 47.27,155.79 46.85,156.22 46.85,156.23 46.85,156.44 46.42,156.87 46.2,156.87 45.77,157.3 45.77,157.3 45.77,157.52 45.34,157.95 45.12,157.95 44.72,158.34 44.26,158.34 44.08,158.52 43.75,158.52 43.57,158.34 43.01,158.34 41.67,159.69 38.87,159.69 v2(38.56,160) ; v5(55.99,205.67) 55.99,205.87 55.77,206.09 54.46,206.09 54.18,206.36 53.97,206.36 53.81,206.52 53.81,206.74 53.63,206.92 53.43,206.92 53.2,207.15 53.2,207.35 53.03,207.52 52.81,207.52 52.67,207.67 52.67,207.88 52.41,208.14 52.41,208.94 C56.1
  BOTTOM w0.152: v2(38.56,160) 38.29,159.73 36.96,159.73 35.19,161.49 35.19,179.88 35.46,180.15 35.46,189.82 49.11,203.48 49.87,203.48 52.38,205.99 52.64,205.99 52.77,205.86 53.01,205.86 53.14,205.99 53.3,205.99 53.45,205.84 53.69,205.84 53.83,205.99 54.08,205.99 54.23,205.84 54.45,205.84 54.6,205.99 54.83,205.99 54.97,205.84 55.21,205.84 55.36,205.99 55.87,205.99 55.99,205.86 v5(55.99,205.67)
GFX_TX9N_C: length 85.7
  TOP w0.102: 50.24,152.61 50.25,152.59 50.32,152.59 51.25,151.66 53.24,151.66 U3.J1
  TOP w0.152: v2(37.4,157.6) 37.75,157.95 41.77,157.95 42.59,157.14 43.71,157.14 47.5,153.34 49.5,153.34 50.24,152.61 ; C37.1 54.99,208.76 54.99,208.08 v5(55.48,207.59)
  BOTTOM w0.152: v5(55.48,207.59) 54.99,208.08 54.99,208.8 54.63,209.16 53.83,209.16 49.3,204.62 48.63,204.62 34.26,190.26 34.26,180.59 34.03,180.36 34.03,159.29 35.4,157.92 37.08,157.92 v2(37.4,157.6)
GFX_TX9P_C: length 85.6
  TOP w0.102: U3.J2 53.67,151.66 53.37,151.96 53.06,151.96 52.97,151.87 51.33,151.87 50.46,152.74 50.46,152.8 50.44,152.82
  TOP w0.152: v2(37.38,158.52) 37.38,158.52 37.65,158.24 41.9,158.24 42.71,157.43 43.83,157.43 47.62,153.64 49.62,153.64 50.44,152.82 ; C58.1 54.7,208.76 54.7,207.72 54.56,207.59 v2(54.21,207.59)
  BOTTOM w0.152: v2(37.38,158.52) 37.07,158.21 35.53,158.21 34.33,159.41 34.33,180.24 34.56,180.47 34.56,190.14 48.75,204.33 49.42,204.33 53.95,208.86 54.51,208.86 54.7,208.68 54.7,207.85 54.43,207.59 v2(54.21,207.59)
GFX_TX10N_C: length 94.6
  TOP w0.102: U3.K3 54.27,151.03 53.9,151.03 53.77,151.16 53.51,151.16 53.41,151.06 53.07,151.06 52.9,151.23 50.65,151.23 50.27,151.61 50.21,151.61 50.19,151.63
  TOP w0.152: v5(57.76,207.54) 57.27,208.03 57.27,208.76 C39.1 ; 50.19,151.63 49.35,152.47 46.42,152.47 43.06,155.83 41.79,155.83 41.14,156.48 38.7,156.48 v2(38.29,156.06)
  BOTTOM w0.152: v5(57.76,207.54) 57.27,208.03 57.27,208.99 55.64,210.63 51.14,210.63 48.09,207.58 48.09,205.29 33.41,190.61 33.41,181.12 33.17,180.88 33.17,158.91 35.53,156.55 37.8,156.55 v2(38.29,156.06)
GFX_TX10P_C: length 94.5
  TOP w0.102: 50.4,151.83 50.41,151.81 50.41,151.75 50.73,151.43 52.98,151.43 53.15,151.26 53.33,151.26 53.43,151.37 53.85,151.37 53.99,151.23 54.52,151.23 54.89,150.86 U3.K4
  TOP w0.152: C38.1 56.98,208.76 56.98,208.03 v2(56.49,207.54) ; v2(38.29,157.33) 38.29,157.05 38.57,156.77 41.26,156.77 41.91,156.12 43.18,156.12 46.54,152.76 49.47,152.76 50.4,151.83
  BOTTOM w0.152: v2(56.49,207.54) 56.5,207.54 56.98,208.02 56.98,208.87 55.52,210.34 51.26,210.34 48.38,207.45 48.38,205.17 33.7,190.49 33.7,181 33.46,180.76 33.46,159.03 35.65,156.84 38.09,156.84 38.29,157.05 v2(38.29,157.33)
GFX_TX11N_C: length 99.9
  TOP w0.102: U3.K2 53.5,150.86 53.27,150.86 52.97,150.55 50.19,150.55 49.87,150.88 49.73,151.02 49.54,151.21 49.48,151.21 49.46,151.22
  TOP w0.152: v2(39.1,154.08) 39.59,154.57 43.02,154.57 46,151.59 49.1,151.59 49.46,151.22 ; v5(60.05,207.59) 59.56,208.08 59.56,208.76 C41.1
  BOTTOM w0.152: v2(39.1,154.08) 38.61,154.57 35.98,154.57 32.31,158.25 32.31,181.22 32.56,181.47 32.56,190.98 46.69,205.11 46.69,208.08 47.73,209.12 48.81,210.2 50.62,212 56.26,212 59.64,208.63 59.64,208 v5(60.05,207.59)
GFX_TX11P_C: length 99.9
  TOP w0.102: U3.K1 52.74,150.76 50.28,150.76 49.87,151.16 49.69,151.35 49.69,151.41 49.67,151.43
  TOP w0.152: 49.67,151.43 49.22,151.88 46.12,151.88 43.14,154.86 39.41,154.86 39.1,155.17 v2(39.1,155.35) ; v2(58.78,207.59) 59.13,207.59 59.27,207.72 59.27,208.84 58.99,209.12 C40.1
  BOTTOM w0.152: v2(58.78,207.59) 59.19,207.59 59.34,207.75 59.34,208.51 58.31,209.54 58.22,209.54 58,209.54 57.61,209.93 57.62,210.02 57.62,210.24 57.23,210.62 57.14,210.62 56.92,210.62 56.54,211.01 56.54,211.1 56.54,211.31 56.14,211.71 55.28,211.71 55.11,211.53 54.52,211.53 54.34,211.71 53.76,211.71 53.58,211.53 53,211.53 52.82,211.71 52.24,211.71 52.06,211.53 51.47,211.53 51.3,211.71 50.74,211.71 50.19,211.16 50.19,211.15 50.19,210.94 49.76,210.51 49.54,210.51 49.11,210.08 49.11,210.07 49.11,209.86 48.68,209.43 48.46,209.43 48.09,209.06 48.09,208.84 47.6,208.35 47.38,208.35 46.98,207.96 46.98,204.99 32.85,190.86 32.85,181.35 32.6,181.1 32.6,158.37 36.1,154.86 36.38,154.86 36.54,155.02 37.07,155.02 37.22,154.86 37.55,154.86 37.7,155.02 38.26,155.02 38.42,154.86 38.95,154.86 39.1,155.02 v2(39.1,155.35)
GFX_TX12N_C: length 106.5
  TOP w0.102: U3.M3 54.17,149.53 53.8,149.53 53.77,149.56 53.51,149.56 53.48,149.53 53,149.53 52.97,149.56 52.71,149.56 52.68,149.53 52.09,149.53 51.84,149.78 50.17,149.78 50.13,149.74 50.1,149.74
  TOP w0.152: v5(62.33,207.59) 61.85,208.08 61.85,208.76 C43.1 ; 50.1,149.74 49.64,149.74 48.66,150.71 45.44,150.71 43.62,152.53 38.88,152.53 v2(38.39,152.04)
  BOTTOM w0.152: v5(62.33,207.59) 61.85,208.08 61.85,208.85 57.8,212.89 50.25,212.89 45.72,208.36 45.72,205.41 31.71,191.39 31.71,181.88 31.44,181.62 31.44,157.84 36.76,152.53 37.9,152.53 v2(38.39,152.04)
GFX_TX12P_C: length 106.4
  TOP w0.102: 50.1,150.03 50.13,150.03 50.17,149.98 51.92,149.98 52.17,149.73 52.6,149.73 52.63,149.77 53.05,149.77 53.09,149.73 53.4,149.73 53.43,149.77 53.85,149.77 53.89,149.73 54.42,149.73 54.89,149.26 U3.M4
  TOP w0.152: 50.1,150.03 49.76,150.03 48.79,151 45.56,151 43.74,152.82 38.88,152.82 v2(38.39,153.31) ; C42.1 61.55,208.76 61.55,208.08 v2(61.06,207.59)
  BOTTOM w0.152: v2(38.39,153.31) 37.9,152.82 36.88,152.82 31.74,157.96 31.74,181.49 32,181.76 32,191.27 46.02,205.29 46.02,208.24 50.37,212.6 57.68,212.6 58.08,212.2 58.08,211.96 58.49,211.54 58.71,211.54 58.74,211.54 59.16,211.12 59.16,210.88 59.57,210.46 59.79,210.46 59.82,210.46 60.24,210.05 60.24,209.8 60.65,209.38 60.87,209.38 60.9,209.38 61.55,208.73 61.55,208.08 v2(61.06,207.59)
GFX_TX13N_C: length 111.4
  TOP w0.102: U3.M2 53.43,149.05 53.06,149.05 52.97,148.95 52.71,148.95 52.66,149.01 49.57,149.01 49.52,148.97 49.51,148.97
  TOP w0.152: 49.51,148.97 49.05,148.97 48.22,149.8 45.11,149.8 43.81,151.09 39.82,151.09 v2(39.33,150.6) ; v5(64.62,207.59) 64.13,208.08 64.13,208.76 C45.1
  BOTTOM w0.152: v2(39.33,150.6) 38.84,151.09 36.8,151.09 30.59,157.3 30.59,181.97 30.85,182.23 30.85,191.75 44.86,205.76 44.86,208.72 50.33,214.19 58.62,214.19 62.25,210.55 64.13,208.68 64.13,208.08 v5(64.62,207.59)
GFX_TX13P_C: length 111.4
  TOP w0.102: 49.51,149.26 49.52,149.26 49.57,149.21 52.8,149.21 U3.M1
  TOP w0.152: C44.1 63.84,208.76 63.84,208.08 v2(63.35,207.59) ; 49.51,149.26 49.17,149.26 48.34,150.09 45.23,150.09 43.93,151.38 39.56,151.38 39.33,151.61 v2(39.33,151.87)
  BOTTOM w0.152: v2(63.35,207.59) 63.84,208.08 63.84,208.56 63.43,208.97 63.13,208.97 62.95,209.14 62.95,209.44 62.75,209.65 62.44,209.65 62.24,209.85 62.24,210.16 62,210.4 61.75,210.4 61.58,210.57 61.58,210.82 61.38,211.02 61.13,211.02 60.97,211.18 60.97,211.43 60.8,211.59 60.55,211.59 60.36,211.79 60.36,212.04 60.17,212.23 59.89,212.23 59.73,212.39 59.73,212.67 59.5,212.9 59.27,212.9 59.07,213.11 59.07,213.33 58.66,213.74 58.5,213.89 58.18,213.89 58.02,213.74 57.72,213.74 57.57,213.89 57.31,213.89 57.16,213.74 56.91,213.74 56.75,213.89 56.42,213.89 56.22,213.69 55.78,213.69 55.58,213.89 55.02,213.89 54.82,213.69 54.26,213.69 54.05,213.89 53.5,213.89 53.29,213.69 52.73,213.69 52.53,213.89 51.97,213.89 51.77,213.69 51.21,213.69 51.01,213.89 50.45,213.89 45.15,208.6 45.15,205.64 31.15,191.63 31.15,182.11 30.88,181.85 30.88,157.42 36.92,151.38 39.13,151.38 39.33,151.59 v2(39.33,151.87)
GFX_TX14N_C: length 118.1
  TOP w0.102: 48.98,148.23 49,148.23 49.05,148.27 51.21,148.27 51.49,148.55 53.15,148.55 U3.N1
  TOP w0.152: v2(38.7,148.7) 39.18,149.19 39.73,149.19 40.63,150.08 43.54,150.08 44.71,148.92 47.68,148.92 48.37,148.23 48.98,148.23 ; v5(67.16,207.52) 66.96,207.52 66.67,207.81 66.67,208.76 C47.1
  BOTTOM w0.152: v2(38.7,148.7) 38.21,149.19 37.91,149.19 36.95,150.15 36.45,150.15 29.73,156.87 29.73,182.31 30,182.58 30,192.1 44,206.1 44,209.1 50.02,215.13 60.54,215.13 66.67,208.99 66.67,207.81 66.96,207.52 v5(67.16,207.52)
GFX_TX14P_C: length 118.1
  TOP w0.102: 48.98,148.52 49,148.52 49.05,148.47 51.13,148.47 51.4,148.75 53.05,148.75 53.09,148.79 53.71,148.79 U3.N2
  TOP w0.152: v2(38.7,149.97) 39.18,149.48 39.61,149.48 40.51,150.38 43.67,150.38 44.83,149.21 47.8,149.21 48.49,148.52 48.98,148.52 ; C46.1 66.38,208.76 66.38,208.01 v2(65.89,207.52)
  BOTTOM w0.152: v2(38.7,149.97) 38.21,149.48 38.03,149.48 37.07,150.44 36.57,150.44 30.02,156.99 30.02,182.19 30.29,182.45 30.29,191.98 44.29,205.98 44.29,208.98 50.14,214.83 60.42,214.83 60.68,214.57 60.68,214.31 61.08,213.9 61.35,213.9 61.75,213.5 61.75,213.23 62.16,212.83 62.42,212.83 62.83,212.42 62.83,212.16 63.24,211.75 63.5,211.75 63.91,211.34 63.91,211.08 64.32,210.67 64.58,210.67 64.99,210.26 64.99,210 65.4,209.59 65.66,209.59 66.38,208.87 66.38,207.98 65.93,207.52 v2(65.89,207.52)
GFX_TX15N_C: length 124.3
  TOP w0.102: 50.62,146.75 51.2,146.75 51.85,147.4 52.38,147.4 52.48,147.3 53.28,147.3 U3.P2
  TOP w0.152: 50.62,146.75 50.01,146.75 49.79,146.53 47.43,146.53 46.79,147.18 43.71,147.18 43.46,146.93 42.49,146.93 v2(42,146.44) ; C49.1 68.96,208.76 68.96,208.08 v5(69.45,207.59)
  BOTTOM w0.152: v2(42,146.44) 41.69,146.75 40.2,146.75 39.82,147.13 38.73,147.13 36.59,149.26 35.93,149.26 28.83,156.37 28.83,182.61 29.14,182.93 29.14,192.45 33.13,196.44 43.13,206.44 43.13,209.45 49.93,216.24 61.92,216.24 69.04,209.13 69.04,208 v5(69.45,207.59)
GFX_TX15P_C: length 124.3
  TOP w0.102: 50.62,147.04 51.21,147.04 51.78,147.61 52.79,147.61 U3.P1
  TOP w0.152: v2(68.18,207.59) 68.27,207.49 68.51,207.49 68.67,207.64 68.67,208.76 C48.1 ; 50.62,147.04 49.89,147.04 49.67,146.82 47.55,146.82 46.91,147.47 43.58,147.47 43.34,147.22 42.05,147.22 41.92,147.35 41.92,147.63 v2(42,147.71)
  BOTTOM w0.152: v2(42,147.71) 42.12,147.58 42.12,147.27 41.9,147.04 40.32,147.04 39.94,147.42 38.85,147.42 36.71,149.56 36.05,149.56 29.12,156.49 29.12,182.49 29.44,182.81 29.44,192.33 33.34,196.24 37.01,199.91 43.42,206.32 43.42,209.33 50.05,215.95 61.8,215.95 64.35,213.4 64.35,213.16 64.58,212.93 64.82,212.93 65.09,212.67 65.09,212.45 65.37,212.17 65.59,212.17 65.8,211.96 65.8,211.71 66.05,211.46 66.3,211.46 66.56,211.19 66.56,210.92 66.81,210.67 67.09,210.67 67.32,210.43 67.32,210.21 67.57,209.96 67.8,209.96 68.01,209.75 68.01,209.5 68.24,209.27 68.48,209.27 68.74,209.01 68.74,207.7 68.64,207.59 v2(68.18,207.59)
GPIO33: length 14
  TOP w0.102: v2(107.75,52.78) 106.43,52.78 106.23,52.98 106.23,55.13 105.65,55.72 105.65,56.29 105.36,56.58 104.85,56.58 104.09,57.34 102.56,57.34 102.37,57.53 102.37,58.8 102.56,58.99 103.2,58.99 103.33,58.86 103.99,58.86 U10.AG6
  BOTTOM w0.102: TP103.1 108.58,51.94 v2(107.75,52.78)
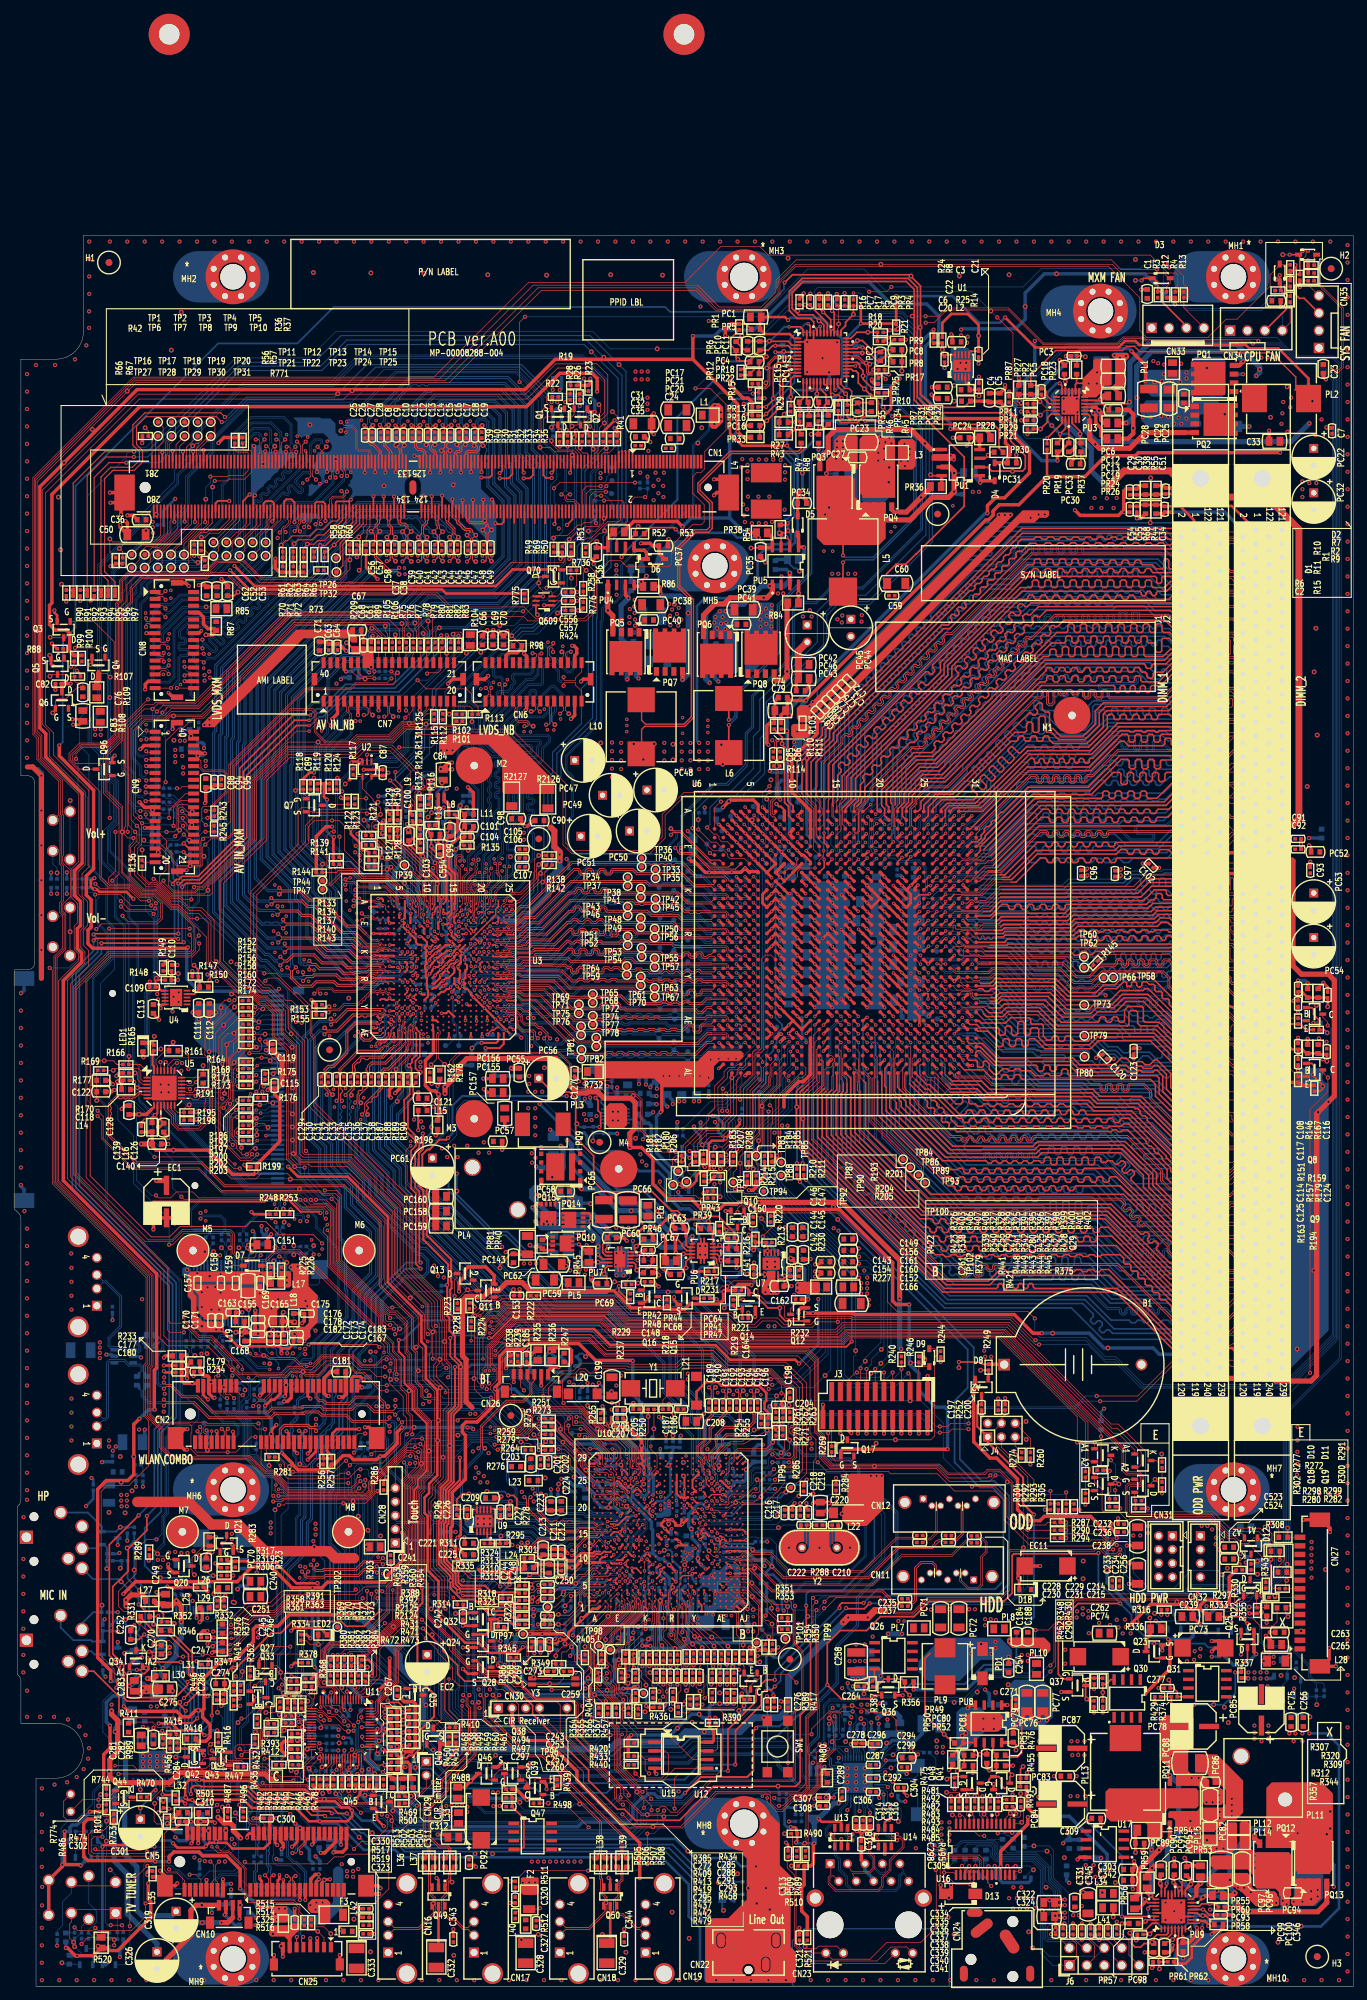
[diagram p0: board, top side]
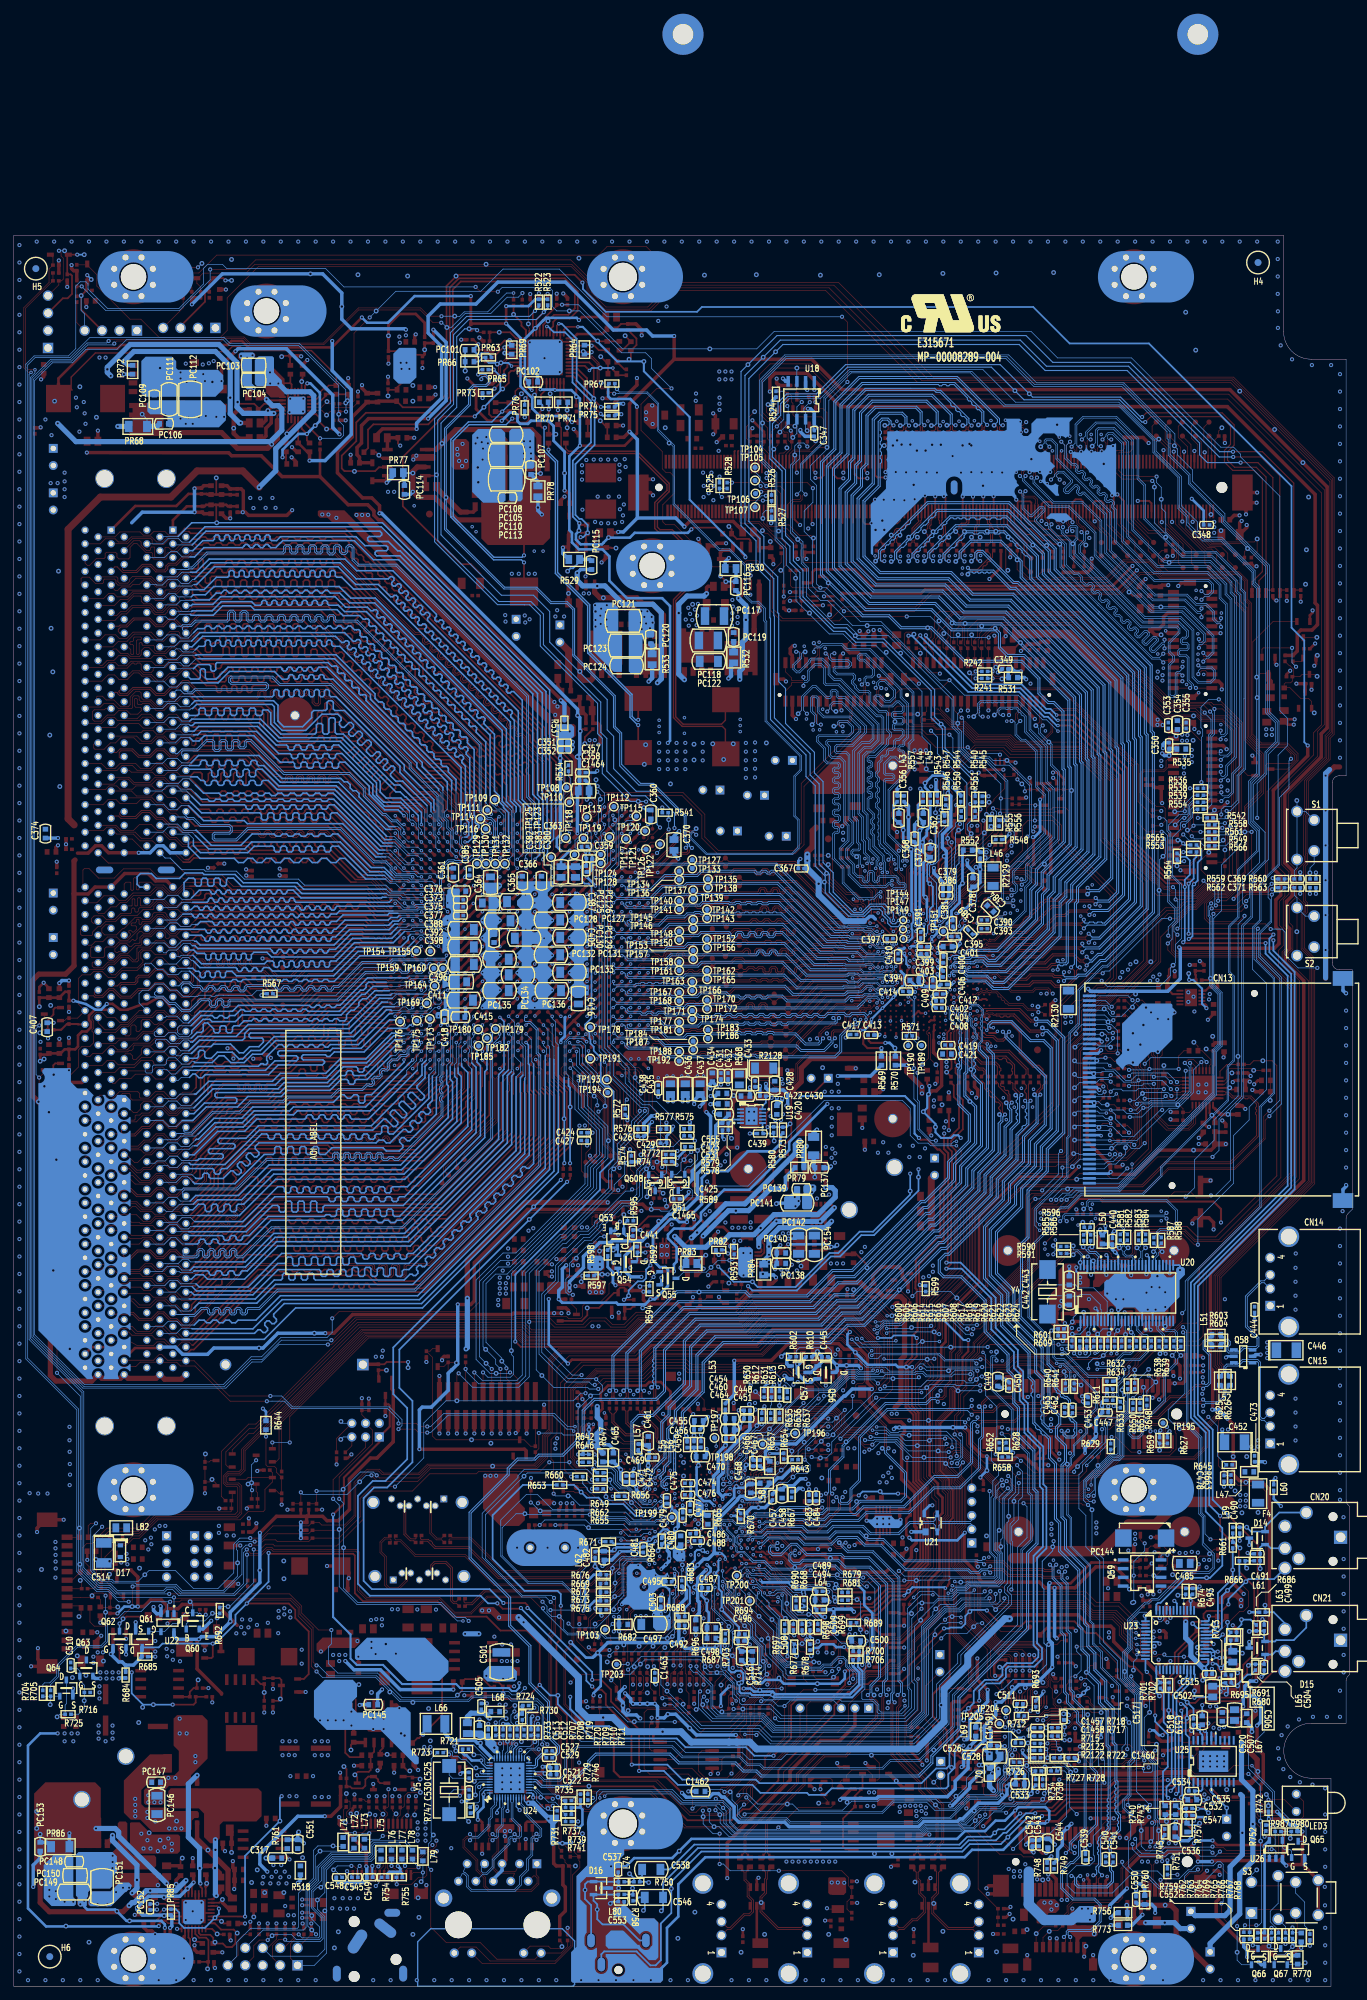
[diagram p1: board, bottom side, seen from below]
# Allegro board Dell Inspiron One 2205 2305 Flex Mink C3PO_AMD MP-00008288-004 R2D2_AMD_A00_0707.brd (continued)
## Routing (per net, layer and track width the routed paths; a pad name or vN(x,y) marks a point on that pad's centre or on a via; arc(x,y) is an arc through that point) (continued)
GPIO170: length 55.4
  TOP w0.102: v3(92.85,58.09) 93.23,57.72 U10.M4 ; v3(63.26,44.77) 63.26,40.2 64.91,38.54 64.91,36.51 64.77,36.37 R451.2 R450.2
  INT1 w0.089: v2(83.13,43.37) 83.13,42.86 82.62,42.35 72.34,42.35 70.94,43.75 64.27,43.75 v3(63.26,44.77)
  BOTTOM w0.102: v2(83.13,43.37) 86.93,43.37 88.39,44.83 88.39,45.85 88.99,46.45 89.45,46.45 89.66,46.66 89.66,47.48 v1(90.31,48.13) 90.68,48.51 90.99,48.51 91.19,48.71 91.19,49.11 90.82,49.49 90.82,51.49 90.18,52.13 90.18,52.64 90.82,53.28 91.25,53.28 92.95,54.97 92.95,57.99 v3(92.85,58.09)
GPIO196: length 10.9
  TOP w0.102: v2(83.83,78.31) 84.9,78.31 85.65,77.56 85.65,76.01 85.91,75.74 86.9,75.74 87.26,75.39 87.26,75.21 87.64,74.83 U10.E26
  BOTTOM w0.102: R654.1 82.36,76.79 81.65,77.5 v1(81.65,77.95) 81.65,78 81.95,78.31 v2(83.83,78.31)
GPIO199: length 18.9
  TOP w0.102: 78.16,79.26 R259.2 78.7,78.71 80.19,78.71 82.43,76.47 82.43,75.69 84.71,73.41 84.97,73.41 85.01,73.46 85.47,73.46 85.51,73.41 85.76,73.41 85.81,73.46 86.47,73.46 86.64,73.29 86.94,73.29 87.18,73.05 87.18,72.58 87.4,72.37 87.4,71.87 87.65,71.63 87.95,71.63 88.36,71.22 U10.F22 ; 78.16,79.26 R275.1 ; 78.16,79.26 77.61,79.82 76.15,79.82 v1(75.64,80.33)
GPIO200: length 20
  TOP w0.102: v1(73.75,79.3) 74.05,79.3 74.28,79.07 75.02,79.07 75.24,78.84 R264.2 75.88,77.47 77.53,77.47 R279.1 78.62,77.65 80.1,77.65 80.92,76.83 80.92,75.88 83.73,73.08 83.73,72.57 84.64,71.65 86.98,71.65 87.18,71.46 87.18,70.97 87.74,70.4 U10.E21
GPIO206: length 73
  TOP w0.102: U10.D28 86.86,76.12 87.26,76.52 87.26,77.11 86.9,77.47 86.9,77.56 82.8,81.66 81.42,81.66 81.23,81.85 81.23,83.06 81.1,83.19 75.83,83.19 75.45,82.8 75.45,81.34 74.01,79.91 72.43,79.91 70.94,78.42 70.61,78.42 v2(70.36,78.17) ; v2(56.72,76.31) 56.95,76.07 56.95,74.3 56.3,73.64 56.3,66.9 56.95,66.25 56.95,61.76 54.81,59.62 54.81,58.93 54.11,58.23 54.11,54.61 51.17,51.66 47.69,51.66 TP202.1
  BOTTOM w0.102: v2(70.36,78.17) 69.88,78.17 68.87,79.18 66.63,79.18 65.47,78.02 65.47,76.81 65.08,76.41 59.5,76.41 v1(59.24,76.15) 58.68,75.59 57.32,75.59 57.06,75.85 57.06,75.97 v2(56.72,76.31)
GPIO207: length 7.9
  TOP w0.102: U10.C29 86.04,77.48 83.51,80.01 v2(83.07,80.01)
  BOTTOM w0.102: v2(83.07,80.01) 84.06,80.01 84.76,79.31 85.55,79.31 TP198.1
GPIO208: length 8.2
  TOP w0.102: v2(82.24,80.26) 82.52,80.54 83.31,80.54 86.37,77.48 86.37,76.45 86.04,76.12 U10.C28
  BOTTOM w0.102: TP196.1 81.96,80.54 v2(82.24,80.26)
GPIO208_MXM_R: length 3.5
  TOP w0.102: v1(18.55,165.53) R136.2 18.83,163.73 CN9.20
GPIO208_NB_N: length 5.3
  TOP w0.102: CN7.20 63.99,186.61 64.15,186.46 66.28,186.46 66.64,186.1 R113.2 66.64,184.23 v1(66.62,184.21)
GPON7: length 4.2
  TOP w0.102: v1(21.28,136.53) 21.02,136.26 R165.2
  TOP w0.305: U5.28 20.28,133.99 20.08,134.19 20.08,136.08 R165.2
GPP_TX0N_C: length 14.1
  TOP w0.152: C130.1 45.35,132.84 45.35,133.44 45.76,133.86 46.49,133.86 48.52,135.89 48.52,138.96 49.73,140.16 52.67,140.16 52.7,140.13 53.12,140.13 53.45,140.46 U3.AC2
GPP_TX0P_C: length 13.7
  TOP w0.152: C129.1 45.06,132.9 45.06,133.57 45.64,134.15 46.37,134.15 48.23,136.01 48.23,139.08 49.61,140.46 U3.AC1
GPP_TX1N_C: length 146.6
  TOP w0.102: U3.AB3 54.34,141.36 53.97,141.36 53.77,141.56 53.51,141.56 53.43,141.48 53.05,141.48 52.97,141.56 52.45,141.56 52.27,141.38 51.92,141.38 51.88,141.33 51.85,141.33
  TOP w0.152: 51.85,141.33 51.37,141.33 51.18,141.15 50.91,141.15 50.73,141.33 50.41,141.33 50.25,141.17 50,141.17 49.85,141.33 49.35,141.33 47.01,138.99 45.45,138.99 v2(45.12,138.66)
  BOTTOM w0.152: C540.1 35.57,18.92 35.41,19.09 35.41,19.91 35.57,20.08 35.57,20.29 35.41,20.46 35.41,20.7 35.57,20.87 35.57,21.08 35.41,21.25 35.41,21.48 34.05,22.84 34.05,23.19 34.2,23.34 34.2,23.6 34.05,23.75 34.05,24 34.2,24.16 34.2,24.43 34.05,24.59 34.05,24.85 34.43,25.23 34.43,25.37 34.58,25.53 34.58,25.76 34.43,25.91 34.43,26.19 34.58,26.34 34.58,26.62 34.43,26.77 34.43,27.05 34.58,27.2 34.58,27.46 34.43,27.61 34.43,27.91 34.61,28.09 34.61,28.37 34.43,28.55 34.43,28.83 34.63,29.03 34.63,29.26 34.43,29.46 34.43,29.72 34.58,29.87 34.58,35.05 34.97,35.44 34.97,40.43 36.06,41.51 36.06,44.44 37.64,46.02 37.64,48.46 38.67,49.49 38.67,52.36 39.14,52.83 39.14,60.9 41.92,63.68 41.92,67.79 42.43,68.29 42.43,75.95 41.92,76.45 41.92,78.66 43.24,79.98 43.24,81.48 42.76,81.97 42.76,82.97 44.33,84.55 44.33,88.7 45.32,89.69 45.32,92.94 49.44,97.05 49.44,101.24 51.98,103.78 51.98,109.9 48.31,113.57 48.31,116.27 45.44,119.13 45.44,122.33 43.11,124.66 43.11,137.69 44.47,139.04 44.74,139.04 v2(45.12,138.66)
GPP_TX1P_C: length 146.1
  TOP w0.102: 51.85,141.62 51.88,141.62 51.92,141.58 52.18,141.58 52.37,141.77 53.05,141.77 53.14,141.68 53.35,141.68 53.43,141.77 53.85,141.77 54.05,141.56 54.57,141.56 54.69,141.44 55.05,141.44 U3.AB4
  TOP w0.152: v5(45.15,139.6) 45.46,139.28 46.89,139.28 49.23,141.62 51.85,141.62
  BOTTOM w0.152: C541.1 35.11,19.19 35.11,21.36 33.75,22.72 33.75,24.98 34.14,25.36 34.14,29.84 34.29,29.99 34.29,35.17 34.68,35.56 34.68,40.55 35.77,41.63 35.77,44.56 37.35,46.14 37.35,48.58 38.38,49.61 38.38,52.48 38.85,52.95 38.85,61.02 41.63,63.8 41.63,67.91 42.14,68.41 42.14,75.82 41.63,76.33 41.63,78.78 42.95,80.1 42.95,81.36 42.47,81.84 42.47,83.1 44.04,84.67 44.04,88.82 45.03,89.81 45.03,93.06 49.15,97.17 49.15,101.37 51.69,103.9 51.69,109.78 48.02,113.45 48.02,116.14 45.15,119.01 45.15,122.21 42.82,124.54 42.82,137.81 44.35,139.33 44.88,139.33 v5(45.15,139.6)
GPP_TX2N_C: length 73.9
  TOP w0.152: U3.AA1 53.17,142.13 48.54,142.13 46.87,140.45 46.4,140.45 46.09,140.13 v2(46.09,140.08)
  BOTTOM w0.152: v2(46.09,140.08) 46.09,140.13 45.79,140.42 44.46,140.42 42.17,138.14 42.17,124.4 44.58,121.99 44.58,118.78 47.38,115.98 47.38,109.15 48.33,108.2 48.33,101.54 48.52,101.34 48.52,97.43 44.46,93.37 44.46,90.6 43.9,90.04 43.9,89.81 43.74,89.65 43.51,89.65 43.32,89.46 43.32,89.1 43.47,88.95 43.47,88.72 43.32,88.57 43.32,88.34 43.47,88.19 43.47,87.99 43.32,87.83 43.32,87.66 43.47,87.5 43.47,87.33 43.32,87.17 43.32,86.97 43.11,86.77 43.11,86.54 42.96,86.39 42.73,86.39 42.53,86.18 42.53,85.95 42.38,85.8 42.15,85.8 41.95,85.6 41.67,85.6 41.34,85.27 41.34,84.51 41.48,84.36 C462.1
GPP_TX2P_C: length 73.9
  TOP w0.152: U3.AA2 53.68,142.42 48.42,142.42 46.75,140.74 46.21,140.74 v5(46.06,140.89)
  BOTTOM w0.152: v5(46.06,140.89) 45.88,140.72 44.33,140.72 41.88,138.26 41.88,124.28 44.29,121.87 44.29,118.66 47.09,115.86 47.09,109.03 48.04,108.08 48.04,101.41 48.23,101.22 48.23,97.55 44.17,93.49 44.17,90.72 43.03,89.58 43.03,87.09 41.83,85.89 41.55,85.89 41.04,85.39 41.04,84.64 C463.1
HDA_SPKR: length 14.2
  TOP w0.254: v3(103.24,68.53) 103.62,68.92 U10.AF19
  BOTTOM w0.254: v3(103.24,68.53) 104.48,68.53 106.18,70.23 108.88,70.23 109.82,71.17 111.53,71.17 v1(112.34,71.98) 113.38,73.03 R653.1
HDT_RST#_OUT: length 7.3
  TOP w0.102: R246.1 130.58,90.88 v1(130.5,90.81) ; R246.1 J3.3 ; R246.1 132.33,90.26 D9.C
HP_L: length 14.5
  BOTTOM w0.254: U23.33 20.61,51.67 20.27,52.01 19.95,52.01 19.57,52.39 19.57,57.28 17.41,59.44 v1(17.41,60.64) R661.1
HP_R: length 13.7
  BOTTOM w0.254: U23.32 20.41,51.17 20.08,51.5 19.7,51.5 19,52.2 19,56.83 v1(18.17,57.66) 16.44,59.39 R666.1
HP_SENSE: length 16.3
  TOP w0.254: R352.1 21.36,53.36 21.66,53.66 21.66,54.23 21.22,54.67 19,54.67 v2(18.04,55.63)
  BOTTOM w0.254: CN20.5 11.39,59.31 15.12,59.31 v1(15.5,58.93) 18.04,56.39 v2(18.04,55.63)
HPD: length 17.5
  TOP w0.102: U3.D10 60.4,156.01 60.52,156.96 60.57,157.06 60.57,157.46 60.53,157.53 60.48,157.74 60.57,157.88 60.57,158.91 60.78,159.12 60.78,160.9 58.98,162.7 58.98,163.16 56.4,165.74 55.38,165.74 53.48,167.64 R121.1 52.59,168.73 v1(52.59,168.91)
HSYNC: length 9.8
  TOP w0.165: R64.2 R64.1 43.62,208.96 v1(44.52,209.87) 45.32,209.87 46.9,211.46 47.43,211.46 49.25,213.28 CN1.164
HSYNC_N: length 197.6
  TOP w0.102: U3.A11 60.89,157.7 60.89,158.92 61.06,159.09 61.06,160.97 59.45,162.59
  TOP w0.165: v2(30.62,228.57) 30.01,229.18 18.95,229.18 17.2,227.43 17.2,224.49 18.17,223.52 18.17,222.28 17.16,221.26 13.98,221.26 12.56,219.84 12.56,205.76 13.6,204.72 R96.1 R96.2 ; v2(54.68,175.64) 55.83,174.5 55.83,173.55 55,172.72 55,171.58 55.19,171.39 55.19,170 55.07,169.88 R129.1 54.05,169.31 54.05,167.96 54.54,167.46 R127.2 54.62,167 55.38,166.24 56.37,166.24 59.45,163.17 59.45,162.59
  BOTTOM w0.165: v2(30.62,228.57) 30.67,228.63 30.9,228.63 33.74,231.47 46.55,231.47 v1(47.05,231.97) 51.29,236.21 73.81,236.21 78.07,231.95 82.39,231.95 83.65,230.68 83.65,229.11 84.85,227.91 84.85,222.5 83.07,220.73 83.07,210.9 81.93,209.75 81.93,207.39 80.47,205.93 80.47,202.25 75.58,197.36 73.92,197.36 72.34,195.77 68.4,195.77 61.35,188.72 61.35,184.78 59.7,183.13 59.7,180.15 55.19,175.64 v2(54.68,175.64)
HT_CADIN0_N: length 37.8
  TOP w0.099: 73.06,156.46 73.05,156.45 73.01,156.45 72.45,155.89 72.12,155.89 72.04,155.82 U3.D25 ; 99.93,161.47 99.96,161.47 99.96,161.47 103.4,161.47 103.72,161.15 103.72,161.02 103.63,160.93 103.26,160.93 U6.J2
  TOP w0.127: 73.06,156.46 73.7,157.11 74.8,157.11 81.24,163.55 90.84,163.55 TP40.1 91.32,163.3 91.59,163.56 92.45,163.56 92.59,163.42 92.96,163.42 93.1,163.56 93.47,163.56 93.6,163.42 93.98,163.42 94.11,163.56 94.48,163.56 94.62,163.42 94.99,163.42 95.13,163.56 95.5,163.56 95.74,163.32 96.02,163.32 96.26,163.56 97.16,163.56 99.25,161.47 99.93,161.47
HT_CADIN0_P: length 38.3
  TOP w0.099: U6.J3 104.1,160.97 103.95,161.12 103.95,161.24 103.49,161.7 100.05,161.7 100.05,161.7 100.03,161.71 99.99,161.71 99.94,161.76 99.93,161.76 ; U3.D24 71.51,155.93 71.79,155.93 71.99,156.13 72.37,156.13 72.81,156.57 72.81,156.59 72.85,156.63 72.85,156.65 72.86,156.66
  TOP w0.127: 72.86,156.66 73.59,157.39 74.68,157.39 81.12,163.84 90.82,163.84 TP36.1 91.82,163.85 97.28,163.85 99.37,161.76 99.93,161.76
HT_CADIN1_N: length 38.3
  TOP w0.099: U3.E25 71.41,154.86 71.35,154.91 71.35,155.06 71.41,155.11 72.82,155.11 72.85,155.14 72.88,155.14 72.91,155.17 72.98,155.17 72.98,155.18
  TOP w0.127: U6.K1 101.46,160.19 98.88,160.19 97.16,161.91 93.85,161.91 TP35.1 92.86,161.91 90.6,161.91 89.98,162.52 87.19,162.52 87.07,162.4 87.07,162.14 86.77,161.85 86.16,161.85 85.86,162.14 85.86,162.4 85.74,162.52 85.35,162.52 85.23,162.4 85.23,162.14 84.93,161.85 84.32,161.85 84.02,162.14 84.02,162.4 83.9,162.52 83.52,162.52 83.39,162.4 83.39,162.14 83.1,161.85 82.48,161.85 82.19,162.14 82.19,162.4 82.06,162.52 81.53,162.52 75.32,156.31 74.11,156.31 72.98,155.18
HT_CADIN1_P: length 38.8
  TOP w0.099: U3.E24 70.92,154.86 71.13,155.06 71.13,155.15 71.32,155.34 72.73,155.34 72.77,155.38 72.78,155.38
  TOP w0.127: U6.J1 101.95,160.61 101.81,160.47 99,160.47 97.28,162.19 93.85,162.19 TP33.1 92.86,162.19 90.71,162.19 90.1,162.81 87.08,162.81 86.78,162.52 86.78,162.26 86.66,162.13 86.27,162.13 86.15,162.26 86.15,162.52 85.85,162.81 85.24,162.81 84.94,162.52 84.94,162.26 84.82,162.13 84.44,162.13 84.31,162.26 84.31,162.52 84.01,162.81 83.4,162.81 83.1,162.52 83.1,162.26 82.98,162.13 82.6,162.13 82.47,162.26 82.47,162.52 82.18,162.81 81.42,162.81 75.2,156.59 73.99,156.59 72.78,155.38
HT_CADIN2_N: length 37.3
  TOP w0.099: U6.L2 103.36,158.29 103.56,158.29 103.77,158.51 103.77,158.73 103.57,158.93 101.43,158.93 101.42,158.92 101.41,158.92 ; 74.42,155.52 74.4,155.52 74.39,155.53 74.25,155.53 73.12,154.4 71.96,154.4 71.76,154.19 71.76,154.11 71.81,154.06 U3.F25
  TOP w0.127: 101.41,158.92 98.37,158.92 97.03,160.26 92.39,160.26 91.89,160.77 89.78,160.77 TP37.1 88.8,160.77 81.09,160.77 75.85,155.52 74.42,155.52
HT_CADIN2_P: length 37.8
  TOP w0.099: 101.41,159.21 101.42,159.21 101.46,159.16 101.51,159.16 101.51,159.16 103.67,159.16 104,158.83 104,158.59 104.16,158.43 U6.L3 ; 74.36,155.8 74.31,155.75 74.15,155.75 73.02,154.62 71.87,154.62 71.53,154.29 71.53,154.17 71.42,154.06 U3.F24
  TOP w0.127: 74.36,155.8 75.73,155.8 80.98,161.05 88.8,161.05 TP34.1 89.78,161.05 92.01,161.05 92.51,160.55 97.15,160.55 98.49,159.21 101.41,159.21
HT_CADIN3_N: length 38.4
  TOP w0.099: 73.42,153.76 73.4,153.76 73.37,153.79 72.65,153.79 72.37,153.52 71.81,153.52 71.77,153.56 71.5,153.56 71.46,153.53 71.03,153.53 70.99,153.56 70.72,153.56 70.69,153.54 70.16,153.54 U3.F22
  TOP w0.127: 73.42,153.76 73.61,153.76 74.61,154.76 76.41,154.76 80.76,159.12 81.61,159.12 81.91,159.41 81.91,159.61 82.03,159.74 82.41,159.74 82.54,159.61 82.54,159.41 82.83,159.12 83.45,159.12 83.74,159.41 83.74,159.61 83.87,159.74 84.25,159.74 84.38,159.61 84.38,159.41 84.67,159.12 85.29,159.12 85.58,159.41 85.58,159.61 85.71,159.74 86.09,159.74 86.22,159.61 86.22,159.41 86.51,159.12 90.7,159.12 TP41.1 91.69,159.12 96.52,159.12 97.99,157.65 101.46,157.65 U6.M1
HT_CADIN3_P: length 38.1
  TOP w0.099: U3.F23 70.23,154.06 70.14,153.97 70.14,153.88 70.25,153.77 70.6,153.77 70.62,153.79 71.08,153.79 71.12,153.75 71.36,153.75 71.4,153.79 71.86,153.79 71.9,153.75 72.28,153.75 72.55,154.02 73.37,154.02 73.4,154.05 73.42,154.05
  TOP w0.127: 73.42,154.05 73.49,154.05 74.49,155.05 76.29,155.05 80.65,159.4 81.49,159.4 81.62,159.53 81.62,159.73 81.92,160.02 82.53,160.02 82.83,159.73 82.83,159.53 82.95,159.4 83.33,159.4 83.46,159.53 83.46,159.73 83.75,160.02 84.37,160.02 84.66,159.73 84.66,159.53 84.79,159.4 85.17,159.4 85.3,159.53 85.3,159.73 85.59,160.02 86.21,160.02 86.5,159.73 86.5,159.53 86.63,159.4 90.7,159.4 TP38.1 91.69,159.4 96.64,159.4 98.11,157.93 101.46,157.93 U6.L1
HT_CADIN4_N: length 37.9
  TOP w0.099: 74.36,152.55 74.34,152.53 74.3,152.53 74.18,152.41 74.04,152.28 73.78,152.28 73.43,151.92 71.81,151.92 71.77,151.96 71.5,151.96 71.46,151.93 71.03,151.93 70.99,151.96 70.72,151.96 70.69,151.94 70.16,151.94 U3.H22
  TOP w0.127: U6.P1 101.46,155.11 97.23,155.11 96.53,155.81 92.72,155.81 92.09,156.45 89.78,156.45 TP46.1 88.8,156.45 88.53,156.45 88.52,156.44 86.27,156.44 85.98,156.73 85.98,156.94 85.85,157.07 85.47,157.07 85.34,156.94 85.34,156.73 85.05,156.44 84.43,156.44 84.14,156.73 84.14,156.94 84.01,157.07 83.63,157.07 83.5,156.94 83.5,156.73 83.21,156.44 82.59,156.44 82.3,156.73 82.3,156.94 82.17,157.07 81.79,157.07 81.66,156.94 81.66,156.73 81.37,156.44 80.86,156.44 77.53,153.11 74.92,153.11 74.36,152.55
HT_CADIN4_P: length 37.7
  TOP w0.099: U3.H23 70.23,152.46 70.14,152.37 70.14,152.28 70.25,152.17 70.6,152.17 70.62,152.19 71.08,152.19 71.12,152.15 71.36,152.15 71.4,152.19 71.86,152.19 71.9,152.15 73.33,152.15 73.69,152.5 73.95,152.5 74.14,152.69 74.14,152.73 74.16,152.75
  TOP w0.127: 74.16,152.75 74.8,153.4 77.41,153.4 80.74,156.72 81.25,156.72 81.38,156.85 81.38,157.06 81.67,157.35 82.29,157.35 82.58,157.06 82.58,156.85 82.71,156.72 83.09,156.72 83.22,156.85 83.22,157.06 83.51,157.35 84.13,157.35 84.42,157.06 84.42,156.85 84.55,156.72 84.93,156.72 85.06,156.85 85.06,157.06 85.35,157.35 85.97,157.35 86.26,157.06 86.26,156.85 86.39,156.72 88.4,156.72 88.41,156.73 88.8,156.73 TP43.1 89.78,156.73 92.21,156.73 92.84,156.1 96.65,156.1 97.35,155.39 101.46,155.39 U6.N1
HT_CADIN5_N: length 37.5
  TOP w0.099: U6.R2 103.56,153.35 103.72,153.51 103.72,153.73 103.58,153.87 101.49,153.87 101.45,153.83 101.43,153.83 ; 74.77,151.91 74.75,151.9 74.71,151.9 74.59,151.78 74.38,151.57 74.01,151.57 73.87,151.43 71.84,151.43 71.77,151.35 71.52,151.35 71.21,151.66 U3.J24
  TOP w0.127: 101.43,153.83 96.86,153.83 95.89,154.8 91.69,154.8 TP49.1 90.7,154.8 87.75,154.8 87.33,155.21 86.94,155.21 86.53,154.8 85.91,154.8 85.49,155.21 85.1,155.21 84.69,154.8 84.07,154.8 83.65,155.21 83.27,155.21 82.85,154.8 82.23,154.8 81.81,155.21 81.43,155.21 81.01,154.8 80.56,154.8 78.03,152.26 75.11,152.26 74.77,151.91
HT_CADIN5_P: length 37
  TOP w0.099: 101.43,154.12 101.45,154.12 101.46,154.1 103.67,154.1 103.95,153.82 103.95,153.56 104.16,153.35 U6.R3 ; 74.56,152.12 74.55,152.1 74.55,152.06 74.29,151.8 73.92,151.8 73.78,151.66 U3.J25
  TOP w0.127: 101.43,154.12 96.97,154.12 96.01,155.08 91.69,155.08 TP48.1 90.7,155.08 87.86,155.08 87.45,155.5 86.83,155.5 86.41,155.08 86.02,155.08 85.61,155.5 84.99,155.5 84.57,155.08 84.18,155.08 83.77,155.5 83.15,155.5 82.73,155.08 82.35,155.08 81.93,155.5 81.31,155.5 80.89,155.08 80.45,155.08 77.91,152.55 75,152.55 74.56,152.12
HT_CADIN6_N: length 37.1
  TOP w0.099: U3.K25 72.17,150.98 74.78,150.98 74.92,151.12 75.04,151.24 75.08,151.24 75.1,151.26
  TOP w0.127: U6.T1 102.04,152.17 102.04,152.37 101.84,152.57 96.47,152.57 95.76,153.27 93.72,153.27 TP56.1 92.74,153.27 90.47,153.27 89.94,153.8 88.03,153.8 87.91,153.67 87.91,153.12 87.64,152.86 86.98,152.86 86.7,153.14 86.7,153.67 86.58,153.8 86.19,153.8 86.07,153.67 86.07,153.33 85.77,153.03 85.16,153.03 84.86,153.33 84.86,153.67 84.74,153.8 84.36,153.8 84.23,153.67 84.23,153.33 83.94,153.03 83.32,153.03 83.02,153.33 83.02,153.67 82.9,153.8 82.52,153.8 82.39,153.67 82.39,153.33 82.1,153.03 81.48,153.03 81.19,153.33 81.19,153.67 81.06,153.8 80.91,153.8 78.68,151.56 75.41,151.56 75.1,151.26
HT_CADIN6_P: length 37.7
  TOP w0.099: U3.K24 71.61,150.86 71.96,151.21 74.69,151.21 74.88,151.4 74.88,151.44 74.9,151.46
  TOP w0.127: 74.9,151.46 75.29,151.85 78.56,151.85 80.79,154.08 81.18,154.08 81.47,153.79 81.47,153.45 81.6,153.32 81.98,153.32 82.11,153.45 82.11,153.79 82.4,154.08 83.02,154.08 83.31,153.79 83.31,153.45 83.44,153.32 83.82,153.32 83.94,153.45 83.94,153.79 84.24,154.08 84.85,154.08 85.15,153.79 85.15,153.45 85.28,153.32 85.66,153.32 85.78,153.45 85.78,153.79 86.08,154.08 86.69,154.08 86.99,153.79 86.99,153.25 87.1,153.14 87.52,153.14 87.62,153.24 87.62,153.79 87.92,154.08 90.06,154.08 90.58,153.56 92.74,153.56 TP50.1 93.72,153.56 95.88,153.56 96.58,152.85 101.46,152.85 U6.R1
HT_CADIN7_N: length 37.6
  TOP w0.099: 75.72,150.78 75.71,150.77 75.67,150.77 75.27,150.37 73.16,150.37 73.07,150.46 72.51,150.46 72.37,150.32 71.81,150.32 71.77,150.36 71.5,150.36 71.46,150.32 71.03,150.32 70.99,150.36 70.72,150.36 70.69,150.34 70.16,150.34 U3.K22 ; U6.U2 103.56,150.81 103.72,150.97 103.72,151.19 103.57,151.34 101.48,151.34 101.45,151.3 101.43,151.3
  TOP w0.127: 101.43,151.3 96.08,151.3 95.67,151.72 92.54,151.72 92.13,152.13 89.78,152.13 TP52.1 88.8,152.13 88.39,152.13 88.08,151.82 85.56,151.82 85.31,152.07 84.93,152.07 84.69,151.82 83.97,151.82 83.73,152.07 83.35,152.07 83.1,151.82 82.39,151.82 82.14,152.07 81.76,152.07 81.52,151.82 80.93,151.82 80.69,152.07 80.5,152.07 79.3,150.87 75.81,150.87 75.72,150.78
HT_CADIN7_P: length 37.8
  TOP w0.099: 75.52,150.98 75.5,150.96 75.51,150.92 75.18,150.6 73.25,150.6 73.17,150.68 72.42,150.68 72.28,150.55 71.9,150.55 71.86,150.59 71.4,150.59 71.36,150.55 71.12,150.55 71.08,150.59 70.62,150.59 70.6,150.57 70.25,150.57 70.14,150.68 70.14,150.77 70.23,150.86 U3.K23 ; U6.U3 104.16,150.81 103.95,151.02 103.95,151.28 103.67,151.56 101.47,151.56 101.45,151.59 101.43,151.59
  TOP w0.127: 75.52,150.98 75.7,151.15 79.19,151.15 80.39,152.35 80.8,152.35 81.05,152.11 81.4,152.11 81.64,152.35 82.26,152.35 82.51,152.11 82.98,152.11 83.23,152.35 83.85,152.35 84.09,152.11 84.57,152.11 84.81,152.35 85.43,152.35 85.68,152.11 87.96,152.11 88.27,152.42 88.8,152.42 TP51.1 89.78,152.42 92.24,152.42 92.66,152 95.79,152 96.2,151.59 101.43,151.59
HT_CADIN8_N: length 45.6
  TOP w0.102: U6.K6 108.29,159.7 108.29,159.7
  TOP w0.124: 108.29,159.7 108.28,159.7 107.67,160.31 v3(107.65,160.31)
  TOP w0.127: U3.G21 v3(69.24,153.66)
  BOTTOM w0.099: 74.04,154.15 74.03,154.15 74,154.18 73.48,154.18 73.43,154.23 70.78,154.23 70.67,154.13 70.04,154.13 69.57,153.66 v3(69.24,153.66)
  BOTTOM w0.127: 74.04,154.15 74.8,154.15 83.96,163.31 95.66,163.31 TP133.1 96.64,163.31 101.99,163.31 104.44,160.85 107.11,160.85 v3(107.65,160.31)
HT_CADIN8_P: length 45.4
  TOP w0.127: v3(69.25,154.42) 68.89,154.06 U3.F21 ; v3(107.62,161.63) 107.64,161.63 U6.J6
  BOTTOM w0.099: 74.04,154.44 74.03,154.44 74,154.41 73.57,154.41 73.52,154.45 70.68,154.45 70.58,154.35 69.33,154.35 v3(69.25,154.42)
  BOTTOM w0.127: 74.04,154.44 74.68,154.44 83.84,163.59 95.66,163.59 TP127.1 96.64,163.59 102.1,163.59 104.56,161.14 107.13,161.14 v3(107.62,161.63)
HT_CADIN9_N: length 46.2
  TOP w0.124: U6.K5 v3(106.4,160.33)
  TOP w0.127: v3(68.44,152.85) 68.83,152.46 U3.H21
  BOTTOM w0.099: v3(68.44,152.85) 68.44,152.88 68.7,153.14 68.82,153.14 68.97,152.99 69.61,152.99 70.17,153.54 71.06,153.54 71.27,153.75 73.14,153.75 73.39,153.51 73.75,153.51 73.78,153.48 73.8,153.48
  BOTTOM w0.127: 73.8,153.48 75.43,153.48 76.04,154.09 81.67,159.72 84.23,162.28 84.53,162.28 84.8,162 85.25,162 85.53,162.28 85.91,162.28 86.18,162 86.84,162 87.11,162.28 94.76,162.28 95.38,161.66 97.56,161.66 TP136.1 98.55,161.66 100.08,161.66 102.16,159.58 105.63,159.58 105.91,159.85 105.91,160.15 106.09,160.33 v3(106.4,160.33)
HT_CADIN9_P: length 45.7
  TOP w0.124: U6.K4 v3(105.13,160.33)
  TOP w0.127: v3(68.44,153.65) 68.05,153.26 U3.G20
  BOTTOM w0.099: 73.8,153.76 73.79,153.76 73.76,153.73 73.48,153.73 73.23,153.98 71.18,153.98 70.97,153.77 70.07,153.77 69.52,153.21 69.06,153.21 68.91,153.37 68.62,153.37 68.44,153.54 v3(68.44,153.65)
  BOTTOM w0.127: 73.8,153.76 75.31,153.76 75.84,154.29 81.67,160.12 84.11,162.56 84.64,162.56 84.92,162.29 85.14,162.29 85.41,162.56 86.03,162.56 86.3,162.29 86.72,162.29 87,162.56 94.88,162.56 95.5,161.94 97.56,161.94 TP134.1 98.55,161.94 100.2,161.94 102.28,159.86 105.51,159.86 105.62,159.97 105.62,160.13 105.42,160.33 v3(105.13,160.33)
HT_CADIN10_N: length 45.9
  TOP w0.124: U6.M6 108.29,157.16 v3(107.62,157.82)
  TOP w0.127: U3.J21 69.14,151.51 v3(69.14,151.85)
  BOTTOM w0.099: v3(69.14,151.85) 68.94,152.05 68.94,152.24 69.13,152.43 71.08,152.43 71.24,152.6 71.51,152.6 71.54,152.57 71.56,152.57
  BOTTOM w0.127: 71.56,152.57 73.2,152.57 73.39,152.76 76.01,152.76 76.69,153.44 81.67,158.42 83.77,160.52 93.36,160.52 TP138.1 94.35,160.5 96.87,160.5 97.3,160.07 100.43,160.07 102.18,158.31 107.13,158.31 v3(107.62,157.82)
HT_CADIN10_P: length 46.3
  TOP w0.124: U6.L6 108.29,158.43 v3(107.62,159.09)
  TOP w0.127: U3.J20 68.44,151.61 v3(68.44,151.85)
  BOTTOM w0.099: v3(68.44,151.85) 68.71,152.13 68.71,152.33 69.04,152.66 70.99,152.66 71.15,152.82 71.51,152.82 71.54,152.85 71.56,152.85
  BOTTOM w0.127: v3(107.62,159.09) 107.13,158.6 102.3,158.6 100.54,160.36 97.41,160.36 96.98,160.79 94.37,160.79 TP135.1 93.38,160.81 83.66,160.81 81.67,158.82 76.49,153.64 75.89,153.04 73.27,153.04 73.08,152.85 71.56,152.85
HT_CADIN11_N: length 47.5
  TOP w0.124: U6.M5 v3(106.4,157.79)
  TOP w0.125: v3(66.41,151.86) 66.41,151.67 65.94,151.19
  TOP w0.127: 65.94,151.19 65.94,151.07 65.72,150.86 U3.K17
  BOTTOM w0.099: 71.97,151.87 71.96,151.87 71.94,151.89 70.08,151.89 69.35,151.16 67.02,151.16 66.64,151.54 66.64,151.64 v3(66.41,151.86)
  BOTTOM w0.127: v3(106.4,157.79) 106.24,157.79 106.11,157.66 106.11,157.41 105.73,157.02 102.04,157.02 100.2,158.86 96.52,158.86 TP139.1 95.51,158.88 83.43,158.88 81.67,157.12 77.34,152.79 76.57,152.02 73.69,152.02 73.54,151.87 71.97,151.87
HT_CADIN11_P: length 46.9
  TOP w0.124: U6.M4 v3(105.13,157.79)
  TOP w0.127: U3.J18 67.07,151.83 v3(67.07,151.85)
  BOTTOM w0.099: 71.97,152.15 71.96,152.15 71.93,152.12 69.99,152.12 69.25,151.38 67.12,151.38 66.86,151.64 66.86,151.65 v3(67.07,151.85)
  BOTTOM w0.127: v3(105.13,157.79) 105.25,157.91 105.7,157.91 105.83,157.78 105.83,157.52 105.61,157.31 104.81,157.31 104.68,157.43 104.48,157.43 104.35,157.31 103.66,157.31 103.54,157.43 103.28,157.43 103.16,157.31 102.16,157.31 100.32,159.15 96.52,159.15 TP137.1 95.55,159.16 83.31,159.16 81.67,157.52 77.14,152.99 76.45,152.3 73.57,152.3 73.42,152.15 71.97,152.15
HT_CADIN12_N: length 45.9
  TOP w0.124: v3(106.43,155.25) 106.43,155.22 U6.P5
  TOP w0.127: v3(66.84,150.66) 67.24,151.06 U3.J19
  BOTTOM w0.099: v3(66.84,150.66) 67.01,150.66 67.52,150.14 67.88,150.14 68.26,149.77 71.38,149.77 72.13,150.51 72.24,150.51 72.29,150.47 72.3,150.47
  BOTTOM w0.127: v3(106.43,155.25) 106.19,155.25 105.92,154.98 105.92,154.78 105.57,154.43 100.96,154.43 99.76,155.63 97.24,155.63 96.8,156.07 95.87,156.07 95.69,156.26 95.09,156.26 94.91,156.07 94.48,156.07 TP143.1 93.5,156.07 83.22,156.07 77.62,150.47 72.3,150.47
HT_CADIN12_P: length 45.6
  TOP w0.124: v3(105.13,155.25) 105.41,154.97 U6.P4
  TOP w0.127: U3.L19 67.25,150.21 v3(67.69,150.65)
  BOTTOM w0.099: v3(67.69,150.65) 68.35,149.99 71.29,149.99 72.05,150.75 72.29,150.75 72.3,150.75
  BOTTOM w0.127: v3(105.13,155.25) 105.54,155.25 105.64,155.16 105.64,154.9 105.45,154.71 101.07,154.71 99.87,155.92 97.35,155.92 96.92,156.35 95.99,156.35 95.8,156.54 94.98,156.54 94.79,156.35 94.15,156.35 93.99,156.51 ; 72.3,150.75 77.5,150.75 83.1,156.35 83.83,156.35 83.96,156.49 84.33,156.49 84.47,156.35 84.84,156.35 84.98,156.49 85.35,156.49 85.49,156.35 85.86,156.35 86,156.49 86.37,156.49 86.5,156.35 86.87,156.35 87.01,156.49 87.38,156.49 87.52,156.35 87.89,156.35 88.03,156.49 88.4,156.49 88.54,156.35 89.17,156.35 89.31,156.49 89.68,156.49 89.82,156.35 90.19,156.35 90.32,156.49 90.69,156.49 90.83,156.35 91.2,156.35 91.34,156.49 91.71,156.49 91.85,156.35 92.22,156.35 92.36,156.49 92.73,156.49 92.86,156.35 93.88,156.35 93.99,156.46 93.99,156.51 ; 93.99,156.51 TP142.1
HT_CADIN13_N: length 46.6
  TOP w0.124: U6.T6 v3(107.67,152.71)
  TOP w0.127: v3(66.89,149.62) 66.44,150.06 U3.L18
  BOTTOM w0.099: v3(66.89,149.62) 67,149.62 67.15,149.47 67.15,149.18 67.43,148.89 67.96,148.89 68.33,149.27 71.16,149.27 71.19,149.24 71.22,149.24
  BOTTOM w0.127: 71.22,149.24 73.35,149.24 73.69,149.58 78.03,149.58 83,154.54 95.53,154.54 TP146.1 96.02,154.23 96.34,154.54 99.45,154.54 100.79,153.2 107.18,153.2 v3(107.67,152.71)
HT_CADIN13_P: length 46
  TOP w0.124: U6.R6 v3(107.67,153.98)
  TOP w0.127: U3.M19 67.24,149.24 v3(67.64,149.64)
  BOTTOM w0.099: 71.22,149.52 71.19,149.52 71.16,149.49 68.24,149.49 67.86,149.12 67.53,149.12 67.38,149.27 67.38,149.41 67.61,149.64 v3(67.64,149.64)
  BOTTOM w0.127: 71.22,149.52 73.23,149.52 73.57,149.86 77.91,149.86 82.88,154.83 95.53,154.83 TP145.1 96.02,155.06 96.25,154.83 99.56,154.83 100.9,153.49 107.18,153.49 v3(107.67,153.98)
HT_CADIN14_N: length 46.9
  TOP w0.127: U6.T5 v3(106.4,152.71) ; v3(68.44,148.45) 68.44,148.11 U3.P21
  BOTTOM w0.099: 74.29,148.69 74.27,148.69 74.24,148.72 73.97,148.72 73.86,148.62 70.93,148.62 70.84,148.7 70.04,148.7 69.34,148.01 68.89,148.01 v3(68.44,148.45)
  BOTTOM w0.127: 74.29,148.69 78.44,148.69 79.94,150.19 81.67,151.92 83.12,153.37 83.94,153.37 84.06,153.24 84.06,153.02 84.36,152.73 84.97,152.73 85.27,153.02 85.27,153.24 85.39,153.37 85.77,153.37 85.9,153.24 85.9,153.02 86.19,152.73 86.81,152.73 87.1,153.02 87.1,153.24 87.23,153.37 87.61,153.37 87.74,153.24 87.74,153.02 88.03,152.73 88.65,152.73 88.94,153.02 88.94,153.24 89.07,153.37 89.45,153.37 89.58,153.24 89.58,153.02 89.87,152.73 90.49,152.73 90.78,153.02 90.78,153.24 90.91,153.37 94.78,153.37 95.26,152.89 97.56,152.89 TP150.1 98.55,152.89 99.57,152.89 100.56,151.91 105.6,151.91 105.91,152.22 105.91,152.55 106.07,152.71 v3(106.4,152.71)
HT_CADIN14_P: length 46.6
  TOP w0.124: v3(105.13,152.71) 105.28,152.86 105.57,152.86 105.85,152.58 105.85,152.4
  TOP w0.127: U6.T4 105.85,152.17 105.85,152.4 ; U3.M21 69.09,148.96 v3(69.09,148.45)
  BOTTOM w0.099: 74.29,148.97 74.27,148.97 74.24,148.95 73.87,148.95 73.77,148.84 71.02,148.84 70.94,148.93 69.94,148.93 69.43,148.41 69.13,148.41 v3(69.09,148.45)
  BOTTOM w0.127: v3(105.13,152.71) 105.22,152.81 105.5,152.81 105.62,152.68 105.62,152.34 105.48,152.19 104.79,152.19 104.63,152.35 104.43,152.35 104.28,152.19 103.54,152.19 103.36,152.37 103.13,152.37 102.95,152.19 101.84,152.19 101.69,152.35 101.46,152.35 101.31,152.19 100.67,152.19 99.69,153.18 98.55,153.18 TP148.1 97.56,153.18 95.38,153.18 94.9,153.65 90.79,153.65 90.5,153.36 90.5,153.14 90.37,153.01 89.99,153.01 89.86,153.14 89.86,153.36 89.57,153.65 88.95,153.65 88.66,153.36 88.66,153.14 88.53,153.01 88.15,153.01 88.02,153.14 88.02,153.36 87.73,153.65 87.11,153.65 86.82,153.36 86.82,153.14 86.69,153.01 86.31,153.01 86.19,153.14 86.19,153.36 85.89,153.65 85.28,153.65 84.98,153.36 84.98,153.14 84.85,153.01 84.47,153.01 84.35,153.14 84.35,153.36 84.05,153.65 83,153.65 81.67,152.32 79.74,150.39 78.33,148.97 74.29,148.97
HT_CADIN15_N: length 46.2
  TOP w0.124: U6.V6 v3(107.67,150.17)
  TOP w0.127: U3.M18 66.44,148.61 v3(66.49,148.56)
  BOTTOM w0.099: v3(66.49,148.56) 66.7,148.35 66.7,148.04 66.99,147.75 68.23,147.75 68.4,147.57 71.28,147.57 71.66,147.96 73.75,147.96 73.78,147.93 73.8,147.93
  BOTTOM w0.127: 93.99,151.47 TP156.1 ; 93.99,151.47 93.99,151.54 93.78,151.75 82.8,151.75 78.99,147.93 73.8,147.93 ; 93.99,151.47 94.27,151.75 96.69,151.75 97.3,151.15 99.67,151.15 100.15,150.66 107.18,150.66 v3(107.67,150.17)
HT_CADIN15_P: length 46.3
  TOP w0.124: U6.U6 v3(107.67,151.44)
  TOP w0.127: U3.P18 66.44,147.85 v3(67.14,148.55)
  BOTTOM w0.099: v3(67.14,148.55) 66.92,148.34 66.92,148.14 67.09,147.97 68.33,147.97 68.5,147.8 71.19,147.8 71.57,148.19 73.75,148.19 73.78,148.22 73.8,148.22
  BOTTOM w0.127: 93.99,152.47 94.42,152.03 96.81,152.03 97.41,151.43 99.79,151.43 100.27,150.95 107.18,150.95 v3(107.67,151.44) ; 93.99,152.47 93.99,152.32 93.7,152.03 82.69,152.03 78.87,148.22 73.8,148.22 ; 93.99,152.47 TP152.1
HT_CADOUT0_N: length 37.1
  TOP w0.099: U3.Y24 71.61,142.86 71.92,143.16 72.52,143.16 72.63,143.05 73.85,143.05 73.96,143.16 75.16,143.16 75.85,142.47 75.91,142.47 75.91,142.46
  TOP w0.127: U6.AG1 101.46,137.61 100.8,137.61 99.09,135.91 96.75,135.91 96.51,136.14 95.78,136.14 95.55,135.91 95.17,135.91 94.93,136.14 94.2,136.14 93.96,135.91 93.58,135.91 93.34,136.14 92.62,136.14 92.38,135.91 92,135.91 91.76,136.14 91.03,136.14 90.79,135.91 90.41,135.91 90.17,136.14 89.45,136.14 89.21,135.91 88.83,135.91 88.59,136.14 87.86,136.14 87.62,135.91 87.24,135.91 87,136.14 86.28,136.14 86.04,135.91 83.05,135.91 TP81.1 82.07,135.91 81.65,135.91 80.93,136.62 80.93,137.45 75.91,142.46
HT_CADOUT0_P: length 36.5
  TOP w0.099: 75.71,142.26 75.7,142.27 75.7,142.3 75.07,142.93 74.08,142.93 74.08,142.93 73.98,142.82 72.53,142.82 72.53,142.83 72.43,142.93 72.12,142.93 U3.Y25
  TOP w0.127: U6.AH1 101.95,137.21 101.83,137.33 100.92,137.33 99.21,135.62 96.63,135.62 96.39,135.86 95.9,135.86 95.66,135.62 95.05,135.62 94.81,135.86 94.32,135.86 94.08,135.62 93.46,135.62 93.22,135.86 92.73,135.86 92.49,135.62 91.88,135.62 91.64,135.86 91.15,135.86 90.91,135.62 90.29,135.62 90.05,135.86 89.56,135.86 89.32,135.62 88.71,135.62 88.47,135.86 87.98,135.86 87.74,135.62 87.12,135.62 86.88,135.86 86.39,135.86 86.15,135.62 83.05,135.62 TP82.1 82.07,135.62 81.53,135.62 80.64,136.51 80.64,137.33 75.71,142.26
HT_CADOUT1_N: length 39.3
  TOP w0.099: U3.V23 70.23,144.46 70.14,144.37 70.14,144.28 70.25,144.17 70.6,144.17 70.62,144.19 71.08,144.19 71.12,144.15 71.36,144.15 71.4,144.19 71.86,144.19 71.9,144.15 72.28,144.15 72.46,144.32 73.43,144.32 73.97,143.79 75.91,143.79 76.67,143.02 76.67,143.02 76.75,142.94 76.8,142.94 76.81,142.93 ; 101.46,138.89 101.47,138.89 101.5,138.86 103.69,138.86 103.97,138.58 103.97,138.3 104.17,138.11 U6.AG3
  TOP w0.127: 101.46,138.89 100.83,138.89 99.38,137.44 86.32,137.44 86.08,137.68 85.21,137.68 TP77.1 84.23,137.68 82.06,137.68 76.81,142.93
HT_CADOUT1_P: length 39.2
  TOP w0.099: 101.46,138.61 101.47,138.61 101.5,138.64 103.6,138.64 103.74,138.49 103.74,138.32 103.53,138.11 U6.AG2 ; U3.V22 70.16,143.94 70.69,143.94 70.72,143.96 70.99,143.96 71.03,143.92 71.46,143.92 71.5,143.96 71.77,143.96 71.81,143.92 72.37,143.92 72.55,144.1 73.34,144.1 73.87,143.56 75.81,143.56 76.45,142.93 76.45,142.93 76.6,142.77 76.6,142.74 76.61,142.73
  TOP w0.127: 101.46,138.61 100.95,138.61 99.5,137.16 86.2,137.16 85.96,137.4 85.21,137.4 TP78.1 84.23,137.4 81.94,137.4 76.61,142.73
HT_CADOUT2_N: length 36.9
  TOP w0.099: U3.V24 71.61,144.46 71.97,144.82 73.83,144.82 74.25,144.4 76.67,144.4 77.3,143.76 77.35,143.76 77.39,143.72
  TOP w0.127: U6.AE1 101.46,140.15 100.01,140.15 99.72,139.86 99.72,139.25 99.59,139.12 99.21,139.12 99.08,139.25 99.08,139.86 98.79,140.15 98.03,140.15 97.21,139.33 96.57,139.33 96.38,139.52 95.56,139.52 95.37,139.33 94.99,139.33 94.8,139.52 93.97,139.52 93.78,139.33 93.4,139.33 93.21,139.52 92.39,139.52 92.2,139.33 91.82,139.33 91.63,139.52 90.8,139.52 90.61,139.33 90.23,139.33 90.04,139.52 89.22,139.52 89.03,139.33 88.65,139.33 88.46,139.52 87.63,139.52 87.44,139.33 87.06,139.33 86.87,139.52 86.05,139.52 85.86,139.33 85.48,139.33 85.29,139.52 84.65,139.52 84.47,139.33 82.99,139.33 TP75.1 82,139.33 81.78,139.33 77.39,143.72
HT_CADOUT2_P: length 36.3
  TOP w0.099: U3.V25 72.17,144.59 73.73,144.59 74.15,144.17 76.58,144.17 77.18,143.56 77.18,143.53 77.19,143.52
  TOP w0.127: 77.19,143.52 81.66,139.05 82,139.05 TP76.1 82.99,139.05 84.58,139.05 84.77,139.24 85.17,139.24 85.36,139.05 85.98,139.05 86.16,139.24 86.76,139.24 86.94,139.05 87.56,139.05 87.75,139.24 88.34,139.24 88.53,139.05 89.15,139.05 89.33,139.24 89.93,139.24 90.11,139.05 90.73,139.05 90.92,139.24 91.51,139.24 91.7,139.05 92.32,139.05 92.5,139.24 93.1,139.24 93.28,139.05 93.9,139.05 94.09,139.24 94.68,139.24 94.87,139.05 95.49,139.05 95.67,139.24 96.27,139.24 96.45,139.05 97.32,139.05 98.14,139.87 98.67,139.87 98.8,139.74 98.8,139.13 99.09,138.84 99.71,138.84 100,139.13 100,139.74 100.13,139.87 101.83,139.87 101.95,139.75 U6.AF1
HT_CADOUT3_N: length 36.8
  TOP w0.099: U3.U25 71.67,145.29 77.15,145.29 77.85,144.59 77.88,144.59 77.89,144.57 ; U6.AE3 104.36,140.51 104.21,140.51 103.97,140.75 103.97,141.07 103.64,141.4 101.48,141.4 101.45,141.43 101.44,141.43
  TOP w0.127: 101.44,141.43 100.83,141.43 100.53,141.13 94.02,141.13 93.82,141.33 93.2,141.33 93.01,141.13 92.43,141.13 92.24,141.33 91.62,141.33 91.42,141.13 90.85,141.13 90.65,141.33 90.03,141.33 89.84,141.13 89.26,141.13 89.07,141.33 88.45,141.33 88.25,141.13 87.68,141.13 87.48,141.33 86.86,141.33 86.67,141.13 85.82,141.13 85.61,140.92 84.64,140.92 TP72.1 83.72,140.86 81.58,140.86 77.89,144.55 77.89,144.57
HT_CADOUT3_P: length 37.3
  TOP w0.099: 77.61,144.49 77.61,144.51 77.06,145.06 71.9,145.06 71.72,144.88 71.22,144.88 U3.U24 ; U6.AE2 103.56,140.65 103.75,140.84 103.75,140.98 103.55,141.18 101.48,141.18 101.45,141.15 101.44,141.15
  TOP w0.127: 77.61,144.49 77.61,144.43 81.46,140.57 83.72,140.57 TP74.1 84.77,140.64 85.73,140.64 85.94,140.84 86.78,140.84 86.98,141.04 87.36,141.04 87.56,140.84 88.37,140.84 88.57,141.04 88.95,141.04 89.15,140.84 89.95,140.84 90.15,141.04 90.53,141.04 90.73,140.84 91.54,140.84 91.74,141.04 92.12,141.04 92.32,140.84 93.12,140.84 93.32,141.04 93.7,141.04 93.9,140.84 100.64,140.84 100.95,141.15 101.44,141.15
HT_CADOUT4_N: length 37.3
  TOP w0.099: U3.T24 71.61,146.06 71.97,146.42 73.1,146.42 73.21,146.53 73.75,146.53 73.77,146.56 73.8,146.56 ; 101.42,143.97 101.43,143.97 101.46,143.94 103.74,143.94 104.06,143.62 104.06,143.62 U6.AC3
  TOP w0.127: 101.42,143.97 100.68,143.97 100.01,143.31 98.41,143.31 98.18,143.54 97.43,143.54 97.2,143.31 96.82,143.31 96.59,143.54 95.85,143.54 95.62,143.31 95.24,143.31 95.01,143.54 94.26,143.54 94.03,143.31 91.44,143.31 91.32,143.43 91.32,143.7 91.02,143.99 90.41,143.99 90.11,143.7 90.11,143.43 89.99,143.31 89.47,143.31 88.37,144.4 85.81,144.4 85.61,144.2 84.54,144.2 TP65.1 83.88,144.2 80.96,144.2 78.59,146.56 73.8,146.56
HT_CADOUT4_P: length 36.7
  TOP w0.099: 73.8,146.27 73.77,146.27 73.75,146.3 73.3,146.3 73.19,146.19 72.18,146.19 U3.T25 ; U6.AC2 103.31,143.1 103.59,143.1 103.84,143.35 103.84,143.53 103.65,143.71 101.47,143.71 101.44,143.68 101.42,143.68
  TOP w0.127: 101.42,143.68 100.79,143.68 100.13,143.02 98.29,143.02 98.06,143.25 97.55,143.25 97.32,143.02 96.71,143.02 96.48,143.25 95.97,143.25 95.74,143.02 95.12,143.02 94.89,143.25 94.38,143.25 94.15,143.02 91.33,143.02 91.03,143.32 91.03,143.58 90.91,143.71 90.52,143.71 90.4,143.58 90.4,143.32 90.1,143.02 89.35,143.02 88.26,144.11 85.93,144.11 85.73,143.91 84.87,143.91 TP68.1 83.56,143.91 80.84,143.91 78.48,146.27 73.8,146.27
HT_CADOUT5_N: length 37
  TOP w0.099: 74.2,147.25 74.18,147.25 74.16,147.22 73.89,147.22 73.58,147.52 72.46,147.52 72.28,147.35 71.9,147.35 71.86,147.39 71.4,147.39 71.36,147.35 71.12,147.35 71.08,147.39 70.62,147.39 70.6,147.37 70.25,147.37 70.14,147.48 70.14,147.57 70.23,147.66 U3.P23
  TOP w0.127: U6.AA1 101.95,145.46 101.73,145.23 100.13,145.23 99.84,144.94 99.84,144.68 99.71,144.56 99.33,144.56 99.2,144.68 99.2,144.94 98.91,145.23 98.29,145.23 98,144.94 98,144.68 97.87,144.56 97.49,144.56 97.36,144.68 97.36,144.94 97.07,145.23 96.45,145.23 96.16,144.94 96.16,144.68 96.03,144.56 95.65,144.56 95.52,144.68 95.52,144.94 95.23,145.23 94.7,145.23 94.39,144.92 93.72,144.92 TP63.1 92.74,144.92 90.67,144.92 90.05,145.54 80.96,145.54 79.25,147.25 74.2,147.25
HT_CADOUT5_P: length 37.1
  TOP w0.099: 74.2,146.96 74.17,146.96 74.14,146.99 73.8,146.99 73.49,147.29 72.55,147.29 72.37,147.12 71.81,147.12 71.77,147.16 71.5,147.16 71.46,147.12 71.03,147.12 70.99,147.16 70.72,147.16 70.69,147.14 70.16,147.14 U3.P22
  TOP w0.127: U6.AB1 101.46,144.95 100.25,144.95 100.12,144.82 100.12,144.57 99.83,144.27 99.21,144.27 98.92,144.57 98.92,144.82 98.79,144.95 98.41,144.95 98.28,144.82 98.28,144.57 97.99,144.27 97.37,144.27 97.08,144.57 97.08,144.82 96.95,144.95 96.57,144.95 96.44,144.82 96.44,144.57 96.15,144.27 95.53,144.27 95.24,144.57 95.24,144.82 95.11,144.95 94.82,144.95 94.51,144.64 93.72,144.64 TP67.1 92.74,144.64 90.56,144.64 89.94,145.26 80.84,145.26 79.14,146.96 74.2,146.96
HT_CADOUT6_N: length 36.6
  TOP w0.099: U6.AA3 104.16,145.73 103.95,145.94 103.95,146.2 103.67,146.48 101.49,146.48 101.46,146.51 101.45,146.51 ; 74.66,148.04 74.63,148.04 74.6,148.01 71.96,148.01 71.61,147.66 U3.P24
  TOP w0.127: 74.66,148.04 79.78,148.04 81.25,146.57 81.88,146.57 82.12,146.81 82.85,146.81 83.09,146.57 83.47,146.57 83.7,146.81 84.43,146.81 84.67,146.57 85.05,146.57 85.29,146.81 86.02,146.81 86.26,146.57 86.64,146.57 86.87,146.81 87.6,146.81 87.84,146.57 90.7,146.57 TP61.1 91.54,146.73 92.16,146.73 92.38,146.51 92.76,146.51 92.99,146.74 93.74,146.74 93.96,146.51 94.35,146.51 94.57,146.74 95.32,146.74 95.55,146.51 95.93,146.51 96.16,146.74 96.91,146.74 97.13,146.51 97.52,146.51 97.74,146.74 98.49,146.74 98.72,146.51 99.1,146.51 99.33,146.74 100.08,146.74 100.3,146.51 101.45,146.51
HT_CADOUT6_P: length 36.2
  TOP w0.099: 101.45,146.23 101.47,146.23 101.5,146.25 103.58,146.25 103.72,146.11 103.72,145.65 103.54,145.47 103.31,145.47 103.22,145.55 U6.AA2 ; 74.66,147.75 74.63,147.75 74.6,147.78 72.16,147.78 U3.P25
  TOP w0.127: 101.45,146.23 100.19,146.23 99.96,146.45 99.44,146.45 99.22,146.23 98.6,146.23 98.38,146.45 97.86,146.45 97.63,146.23 97.02,146.23 96.79,146.45 96.27,146.45 96.05,146.23 95.43,146.23 95.21,146.45 94.69,146.45 94.46,146.23 93.85,146.23 93.62,146.45 93.1,146.45 92.88,146.23 92.26,146.23 92.05,146.44 91.38,146.44 91.2,146.26 TP70.1 90.7,146.29 87.72,146.29 87.48,146.53 86.99,146.53 86.75,146.29 86.14,146.29 85.9,146.53 85.41,146.53 85.17,146.29 84.55,146.29 84.31,146.53 83.82,146.53 83.58,146.29 82.97,146.29 82.73,146.53 82.24,146.53 82,146.29 81.13,146.29 79.67,147.75 74.66,147.75
HT_CADOUT7_N: length 36.6
  TOP w0.099: 76.91,148.87 76.88,148.87 76.85,148.84 76.49,148.84 76.39,148.74 74.24,148.74 73.96,148.46 U3.N25
  TOP w0.127: 76.91,148.87 80.27,148.87 80.63,148.51 80.96,148.51 81.25,148.22 81.25,147.88 81.38,147.76 81.76,147.76 81.89,147.88 81.89,148.22 82.18,148.51 82.8,148.51 83.09,148.22 83.09,147.88 83.22,147.76 83.6,147.76 83.73,147.88 83.73,148.22 84.02,148.51 84.64,148.51 84.93,148.22 84.93,147.88 85.06,147.76 85.44,147.76 85.57,147.88 85.57,148.22 85.86,148.51 86.52,148.51 86.78,148.26 86.96,148.26 87.22,148.51 88,148.51 88.41,148.1 88.67,148.1 TP64.1 89.16,148.37 89.44,148.1 90.29,148.1 90.52,148.32 91.27,148.32 91.5,148.1 92.32,148.1 92.65,147.77 94.22,147.77 94.53,148.08 95.13,148.08 95.44,147.77 95.81,147.77 96.11,148.08 96.72,148.08 97.02,147.77 97.39,147.77 97.7,148.08 98.3,148.08 98.61,147.77 98.98,147.77 99.28,148.08 99.76,148.08 100.09,147.75 101.89,147.75 102.09,147.96 102.09,148.13 U6.W1
HT_CADOUT7_P: length 37
  TOP w0.099: U3.N24 71.21,148.46 71.52,148.15 71.77,148.15 71.84,148.23 74.06,148.23 74.34,148.51 76.48,148.51 76.58,148.62 76.85,148.62 76.88,148.59 76.91,148.59
  TOP w0.127: U6.Y1 101.48,147.47 99.97,147.47 99.64,147.8 99.4,147.8 99.09,147.49 98.49,147.49 98.18,147.8 97.82,147.8 97.51,147.49 96.91,147.49 96.6,147.8 96.23,147.8 95.92,147.49 95.32,147.49 95.01,147.8 94.65,147.8 94.34,147.49 92.53,147.49 92.21,147.81 91.38,147.81 91.16,148.04 90.63,148.04 90.41,147.81 89.66,147.81 TP59.1 88.67,147.81 88.3,147.81 87.88,148.23 87.34,148.23 87.08,147.98 86.66,147.98 86.41,148.23 85.98,148.23 85.85,148.1 85.85,147.77 85.56,147.47 84.94,147.47 84.65,147.77 84.65,148.1 84.52,148.23 84.14,148.23 84.01,148.1 84.01,147.77 83.72,147.47 83.1,147.47 82.81,147.77 82.81,148.1 82.68,148.23 82.3,148.23 82.17,148.1 82.17,147.77 81.88,147.47 81.26,147.47 80.97,147.77 80.97,148.1 80.84,148.23 80.51,148.23 80.15,148.59 76.91,148.59
HT_CADOUT8_N: length 41.9
  TOP w0.124: U6.AH4 v3(105.13,137.47)
  TOP w0.127: v3(72.48,140.83) 72.11,140.46 U3.AC25
  BOTTOM w0.127: v3(72.48,140.83) 72.2,140.55 72.2,140.29 72.31,140.19 72.99,140.19 74.66,138.52 74.66,136.25 75.38,135.52 85.1,135.52 85.34,135.76 86.06,135.76 86.3,135.52 86.68,135.52 86.92,135.76 87.65,135.76 87.89,135.52 88.27,135.52 88.51,135.76 89.23,135.76 89.47,135.52 89.85,135.52 90.09,135.76 90.82,135.76 91.06,135.52 91.44,135.52 91.68,135.76 92.4,135.76 92.64,135.52 97.44,135.52 TP188.1 98.67,135.52 99.99,135.52 101.26,136.8 105.38,136.8 105.7,137.12 105.7,137.34 105.57,137.47 v3(105.13,137.47)
HT_CADOUT8_P: length 42.6
  TOP w0.124: U6.AH5 v3(106.4,137.47)
  TOP w0.127: U3.AC24 71.27,140.46 v3(71.63,140.82)
  BOTTOM w0.127: v3(106.4,137.47) 106.11,137.47 105.98,137.34 105.98,137 105.49,136.51 101.38,136.51 100.1,135.24 98.52,135.24 TP192.1 97.59,135.24 92.52,135.24 92.29,135.48 91.8,135.48 91.56,135.24 90.94,135.24 90.7,135.48 90.21,135.48 89.97,135.24 89.35,135.24 89.12,135.48 88.63,135.48 88.39,135.24 87.77,135.24 87.53,135.48 87.04,135.48 86.8,135.24 86.18,135.24 85.95,135.48 85.46,135.48 85.22,135.24 75.27,135.24 74.38,136.13 74.38,138.4 72.88,139.9 72.19,139.9 71.92,140.18 71.92,140.53 v3(71.63,140.82)
HT_CADOUT9_N: length 42.7
  TOP w0.099: U3.AB24 71.61,141.26 71.96,141.6 72.75,141.6 73.29,141.06 73.29,140.7 73.32,140.67 73.32,140.65
  TOP w0.124: U6.AG6 107.67,138.74 v3(107.57,138.84)
  TOP w0.127: 73.32,140.65 73.32,140.07 74.09,139.3 75.57,139.3 75.88,138.99 75.88,138.41 v2(76.2,138.09)
  BOTTOM w0.127: 96.05,137.64 96.52,137.18 100.1,137.18 101.18,138.26 106.98,138.26 v3(107.57,138.84) ; 96.05,137.64 TP184.1 ; 96.05,137.64 96.05,137.58 95.58,137.11 80.92,137.11 80.25,136.45 76.99,136.45 75.93,137.52 75.93,137.82 v2(76.2,138.09)
HT_CADOUT9_P: length 42
  TOP w0.099: 73.04,140.65 73.04,140.67 73.07,140.7 73.07,140.97 72.66,141.38 72.16,141.38 U3.AB25
  TOP w0.124: U6.AH6 108.3,136.85 107.65,137.5 v3(107.62,137.53)
  TOP w0.127: v2(75.37,138.09) 75.6,138.32 75.6,138.87 75.45,139.01 73.98,139.01 73.04,139.95 73.04,140.65
  BOTTOM w0.127: v2(75.37,138.09) 75.64,137.82 75.64,137.4 76.87,136.17 80.37,136.17 81.03,136.83 95.59,136.83 TP187.1 96.02,136.6 96.31,136.89 100.22,136.89 101.3,137.97 107.55,137.97 107.62,137.9 v3(107.62,137.53)
HT_CADOUT10_N: length 42.3
  TOP w0.099: U3.AA25 73.22,142.06 73.96,141.31 73.96,140.63 74.31,140.28 74.96,140.28 74.96,140.29
  TOP w0.124: U6.AF4 105.9,139.52 105.9,139.88 105.62,140.16 105.24,140.16 105.13,140.04 v3(105.13,140.01)
  TOP w0.127: v2(77.99,138.07) 77.69,138.37 77.69,138.85 76.79,139.76 76.38,139.76 75.85,140.29 74.96,140.29
  BOTTOM w0.127: v3(105.13,140.01) 105.22,140.11 105.52,140.11 105.62,140.01 105.62,139.7 105.46,139.53 101.02,139.53 99.77,138.28 97.45,138.28 96.94,138.79 94.4,138.79 TP183.1 93.41,138.87 90.15,138.87 89.95,139.06 89.14,139.06 88.94,138.87 88.56,138.87 88.36,139.06 87.56,139.06 87.36,138.87 86.98,138.87 86.78,139.06 85.97,139.06 85.77,138.87 85.39,138.87 85.19,139.06 84.39,139.06 84.19,138.87 81.07,138.87 80.01,137.8 79.6,137.39 77.8,137.39 77.63,137.56 77.63,137.71 v2(77.99,138.07)
HT_CADOUT10_P: length 42.9
  TOP w0.099: 74.85,140 74.27,140 73.74,140.53 73.74,141.22 73.13,141.83 71.84,141.83 71.77,141.75 71.52,141.75 71.21,142.06 U3.AA24
  TOP w0.124: U6.AF5 v3(106.4,140.01)
  TOP w0.127: v2(77.1,138.07) 77.4,138.37 77.4,138.73 76.67,139.47 76.26,139.47 75.73,140 74.85,140
  BOTTOM w0.127: v3(106.4,140.01) 106.08,140.01 105.91,139.84 105.91,139.58 105.58,139.25 101.14,139.25 99.88,137.99 97.33,137.99 96.82,138.5 94.32,138.5 TP186.1 93.33,138.58 90.03,138.58 89.83,138.78 89.26,138.78 89.06,138.58 88.44,138.58 88.25,138.78 87.67,138.78 87.48,138.58 86.86,138.58 86.66,138.78 86.09,138.78 85.89,138.58 85.27,138.58 85.08,138.78 84.5,138.78 84.31,138.58 81.19,138.58 80.21,137.6 79.72,137.11 77.68,137.11 77.35,137.44 77.35,137.83 77.34,137.84 77.33,137.84 77.33,137.85 v2(77.1,138.07)
HT_CADOUT11_N: length 42.7
  TOP w0.099: v2(75.6,141.03) 75.32,141.31 75.32,141.65 74.81,142.16 74.15,142.16 73.76,142.54 71.9,142.54 71.86,142.59 71.4,142.59 71.36,142.55 71.12,142.55 71.08,142.59 70.62,142.59 70.6,142.56 70.25,142.56 70.14,142.68 70.14,142.77 70.23,142.86 U3.Y23
  TOP w0.124: U6.AE6 107.94,141.01 v3(107.67,141.28)
  BOTTOM w0.127: 98.05,140.17 TP177.1 ; 98.05,140.17 98.05,140.12 97.94,140 95.34,140 94.88,140.46 89.52,140.46 89.33,140.26 88.75,140.26 88.56,140.46 87.94,140.46 87.74,140.26 87.17,140.26 86.97,140.46 86.35,140.46 86.16,140.26 85.58,140.26 85.39,140.46 84.77,140.46 84.57,140.26 84,140.26 83.8,140.46 83.18,140.46 82.99,140.26 82.41,140.26 82.22,140.46 75.39,140.46 75.33,140.52 75.33,140.76 v2(75.6,141.03) ; 98.05,140.17 98.24,139.98 99.95,139.98 100.76,140.79 107.18,140.79 v3(107.67,141.28)
HT_CADOUT11_P: length 43.1
  TOP w0.099: v2(74.77,141.03) 75.1,141.35 75.1,141.55 74.71,141.94 74.05,141.94 73.67,142.32 71.81,142.32 71.77,142.36 71.5,142.36 71.46,142.32 71.03,142.32 70.99,142.36 70.72,142.36 70.69,142.34 70.16,142.34 U3.Y22
  TOP w0.124: U6.AF6 v3(107.67,140.01)
  BOTTOM w0.127: v3(107.67,140.01) 107.18,140.5 100.87,140.5 100.07,139.7 98.33,139.7 98.05,139.42 ; 98.05,139.42 98.05,139.5 97.83,139.72 95.22,139.72 94.76,140.18 89.64,140.18 89.44,139.98 88.64,139.98 88.44,140.18 88.06,140.18 87.86,139.98 87.05,139.98 86.85,140.18 86.47,140.18 86.27,139.98 85.47,139.98 85.27,140.18 84.89,140.18 84.69,139.98 83.88,139.98 83.68,140.18 83.3,140.18 83.1,139.98 82.3,139.98 82.1,140.18 75.27,140.18 75.04,140.41 75.04,140.77 v2(74.77,141.03) ; 98.05,139.42 TP181.1
HT_CADOUT12_N: length 43.1
  TOP w0.124: U6.AC6 v3(107.67,143.82)
  TOP w0.127: v3(68.46,143.26) 68.46,143.24 68.04,143.65 U3.W20
  BOTTOM w0.099: v3(68.46,143.26) 68.46,143.27 68.83,143.64 68.83,143.78 69.2,144.14 70.6,144.14 71.23,143.51 71.27,143.51 71.28,143.5
  BOTTOM w0.127: 71.28,143.5 72.13,142.65 90.56,142.65 91.09,143.18 93.53,143.18 TP170.1 94.48,143.14 96.9,143.14 97.35,142.69 99.24,142.69 99.88,143.33 107.18,143.33 v3(107.67,143.82)
HT_CADOUT12_P: length 42.7
  TOP w0.124: U6.AD6 v3(107.67,142.55)
  TOP w0.127: v3(69.24,143.23) 68.84,143.63 U3.W21
  BOTTOM w0.099: 71.08,143.3 71.07,143.31 71.07,143.35 70.51,143.92 69.29,143.92 69.06,143.69 69.06,143.42 v3(69.24,143.23)
  BOTTOM w0.127: 71.08,143.3 72.01,142.37 90.68,142.37 91.21,142.9 93.46,142.9 TP172.1 94.48,142.86 96.78,142.86 97.23,142.41 99.36,142.41 99.99,143.04 107.18,143.04 v3(107.67,142.55)
HT_CADOUT13_N: length 42.6
  TOP w0.124: U6.AB4 105.41,144.81 v3(105.13,145.09)
  TOP w0.127: U3.V20 67.81,144.69 v3(67.81,144.97)
  BOTTOM w0.099: 71.78,144.3 71.77,144.3 71.76,144.29 71.38,144.29 71.07,144.6 68.18,144.6 v3(67.81,144.97)
  BOTTOM w0.127: v3(105.13,145.09) 105.42,145.09 105.62,144.89 105.62,144.7 105.49,144.57 99.38,144.57 99.1,144.29 98.55,144.29 TP167.1 97.56,144.29 95.5,144.29 94.96,144.83 91.13,144.83 90.68,144.37 89.35,144.37 89.07,144.1 88.65,144.1 88.38,144.37 87.76,144.37 87.49,144.1 87.07,144.1 86.79,144.37 86.18,144.37 85.9,144.1 85.48,144.1 85.21,144.37 83,144.37 82.29,143.66 73.9,143.66 73.26,144.3 71.78,144.3
HT_CADOUT13_P: length 42.6
  TOP w0.124: v3(106.4,145.09) 106.71,144.79 U6.AB5
  TOP w0.127: v3(68.44,144.02) 68.84,144.42 U3.V21
  BOTTOM w0.099: 71.78,144.02 71.77,144.02 71.73,144.06 71.29,144.06 70.97,144.38 68.54,144.38 68.44,144.28 v3(68.44,144.02)
  BOTTOM w0.127: v3(106.4,145.09) 106.09,145.09 105.91,144.9 105.91,144.58 105.61,144.28 99.5,144.28 99.22,144 98.55,144 TP168.1 97.56,144 95.38,144 94.84,144.54 91.25,144.54 90.8,144.09 89.46,144.09 89.19,143.81 88.53,143.81 88.26,144.09 87.88,144.09 87.61,143.81 86.95,143.81 86.67,144.09 86.29,144.09 86.02,143.81 85.36,143.81 85.09,144.09 83.11,144.09 82.4,143.38 73.78,143.38 73.14,144.02 71.78,144.02
HT_CADOUT14_N: length 42.8
  TOP w0.124: U6.AA6 108.25,145.73 v3(107.62,146.36)
  TOP w0.127: U3.U21 69.09,145.46 v3(69.09,145.24)
  BOTTOM w0.099: 71.91,144.99 71.9,144.99 71.88,144.97 71.56,144.97 70.79,145.74 69.95,145.74 69.44,145.24 v3(69.09,145.24)
  BOTTOM w0.127: v3(107.62,146.36) 107.62,145.95 107.54,145.87 104.55,145.87 104.34,146.08 103.71,146.08 103.56,146.23 103.2,146.23 103.05,146.08 102.69,146.08 102.54,146.23 102.18,146.23 102.04,146.08 101.68,146.08 101.53,146.23 101.17,146.23 101.02,146.08 100.66,146.08 100.51,146.23 100.15,146.23 100,146.08 97.45,146.08 97.18,145.81 96.41,145.81 96.15,146.08 ; 96.15,146.08 96.15,146.01 95.95,145.81 82.61,145.81 81.42,144.63 73.95,144.63 73.59,144.99 71.91,144.99 ; 96.15,146.08 TP163.1
HT_CADOUT14_P: length 43.2
  TOP w0.124: U6.AB6 108.25,144.46 v3(107.62,145.09)
  TOP w0.127: v3(68.44,145.11) 68.42,145.13 68.42,145.33 U3.U20
  BOTTOM w0.099: v3(68.44,145.11) 68.44,145.11 68.75,144.81 69.33,144.81 70.04,145.52 70.69,145.52 71.46,144.74 71.86,144.74 71.9,144.7 71.91,144.7
  BOTTOM w0.127: 71.91,144.7 73.47,144.7 73.83,144.34 81.54,144.34 82.72,145.53 95.95,145.53 96.15,145.32 96.15,145.26 ; 96.15,145.26 TP166.1 ; 96.15,145.26 96.41,145.53 97.3,145.53 97.57,145.8 104.22,145.8 104.44,145.58 107.13,145.58 v3(107.62,145.09)
HT_CADOUT15_N: length 43.8
  TOP w0.124: U6.Y4 105.4,147.36 v3(105.13,147.63)
  TOP w0.127: v3(66.26,146.2) 66.26,145.89 U3.U18
  BOTTOM w0.099: v3(66.26,146.2) 66.66,145.8 68.7,145.8 69.16,146.25 71.31,146.25 71.89,145.68 72.41,145.68 72.44,145.7 72.45,145.7
  BOTTOM w0.127: 72.45,145.7 74.14,145.7 74.28,145.57 80.84,145.57 82.7,147.43 93.75,147.43 93.99,147.67 ; 93.99,147.67 TP162.1 ; 93.99,147.67 93.99,147.65 94.18,147.46 97.17,147.46 97.53,147.1 105.44,147.1 105.62,147.29 105.62,147.48 105.42,147.68 105.17,147.68 v3(105.13,147.63)
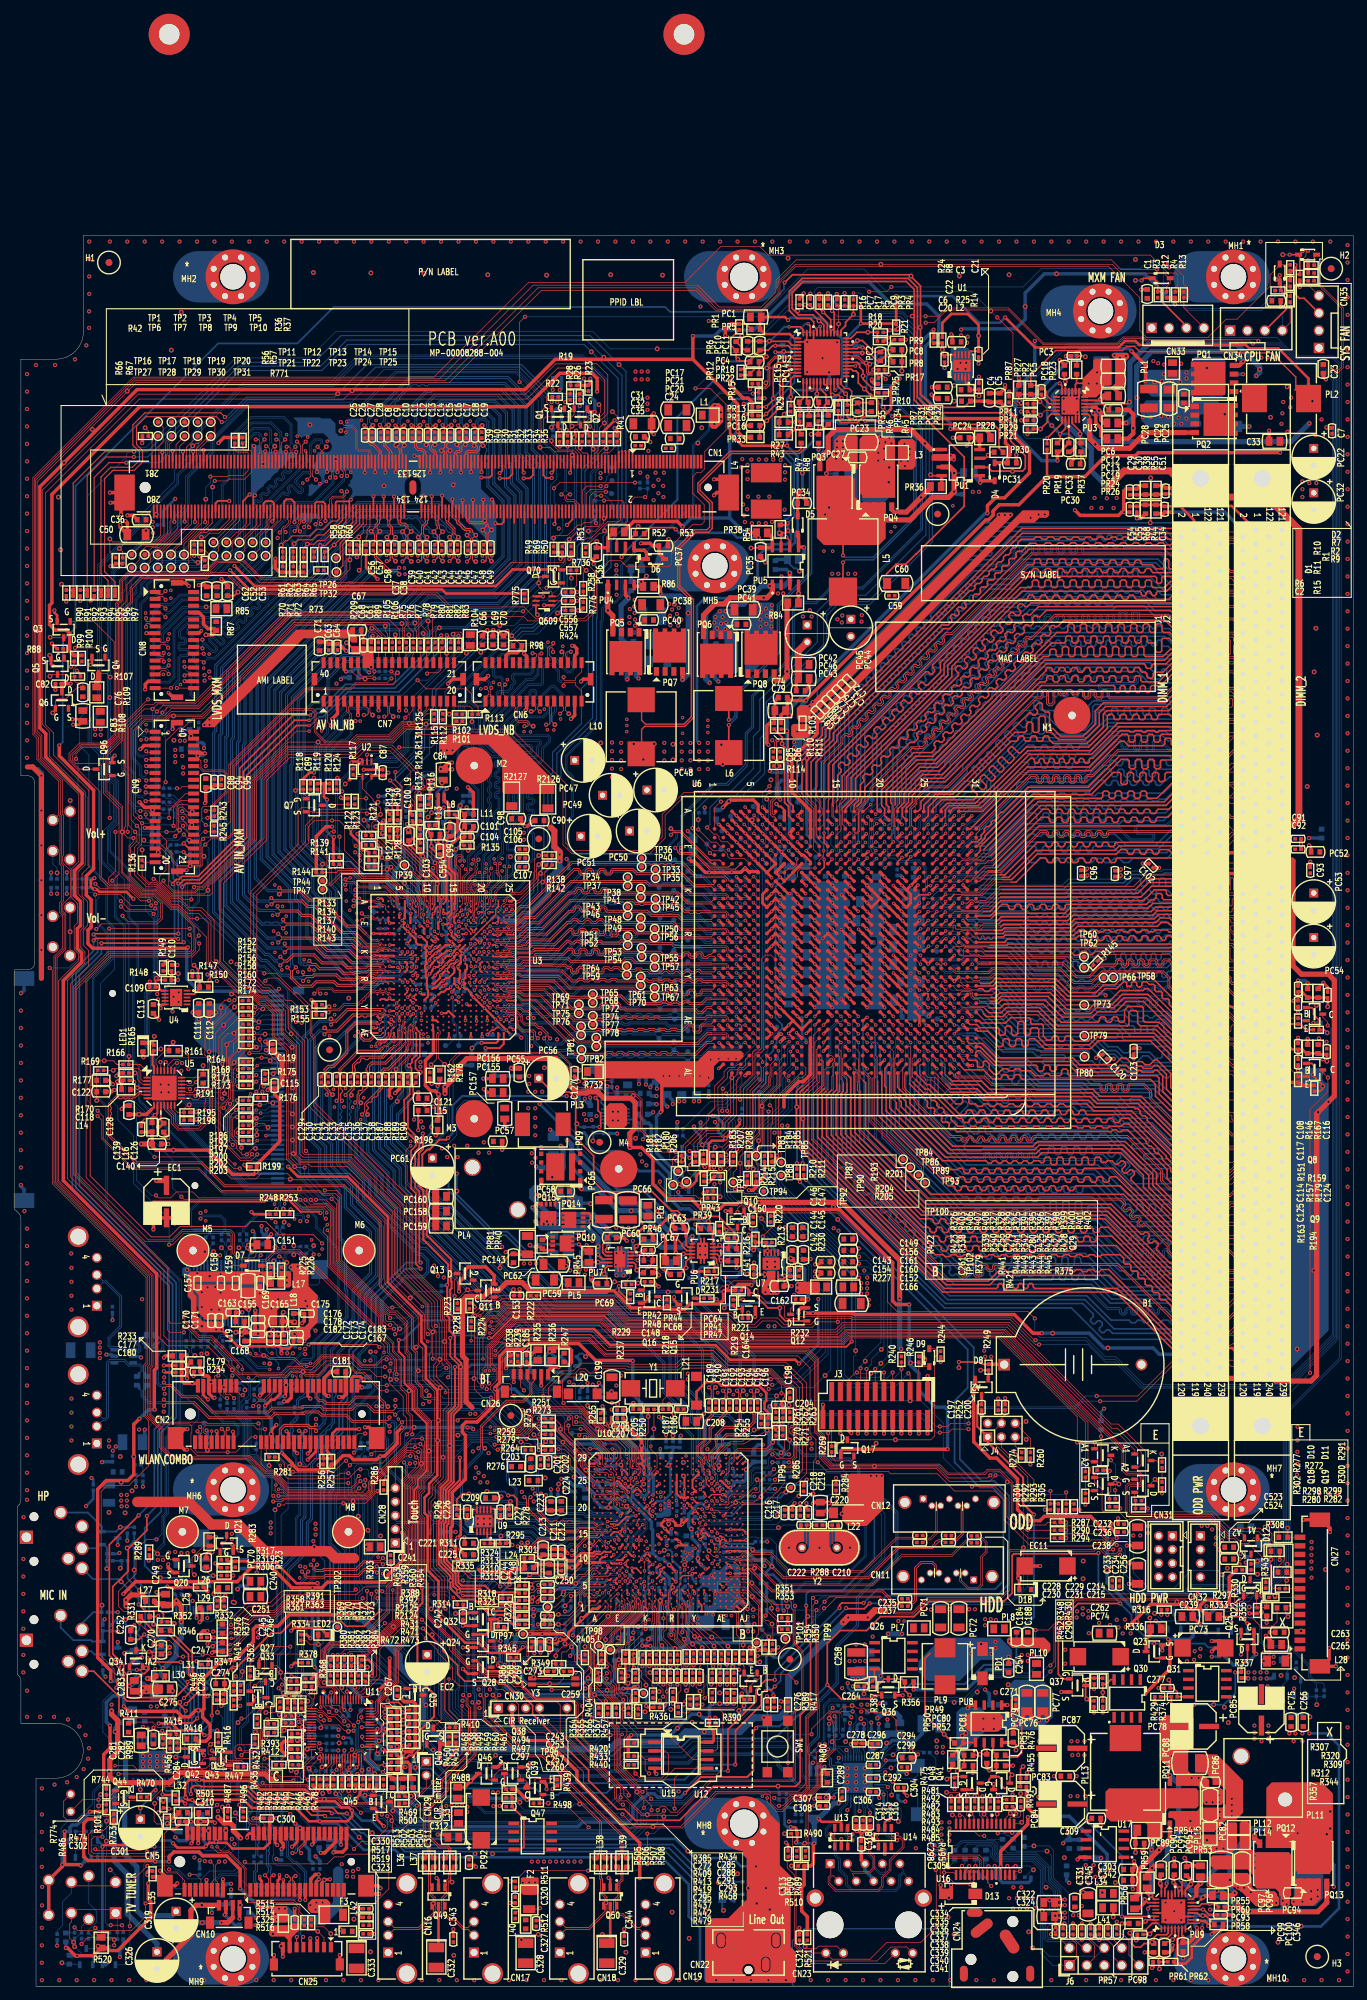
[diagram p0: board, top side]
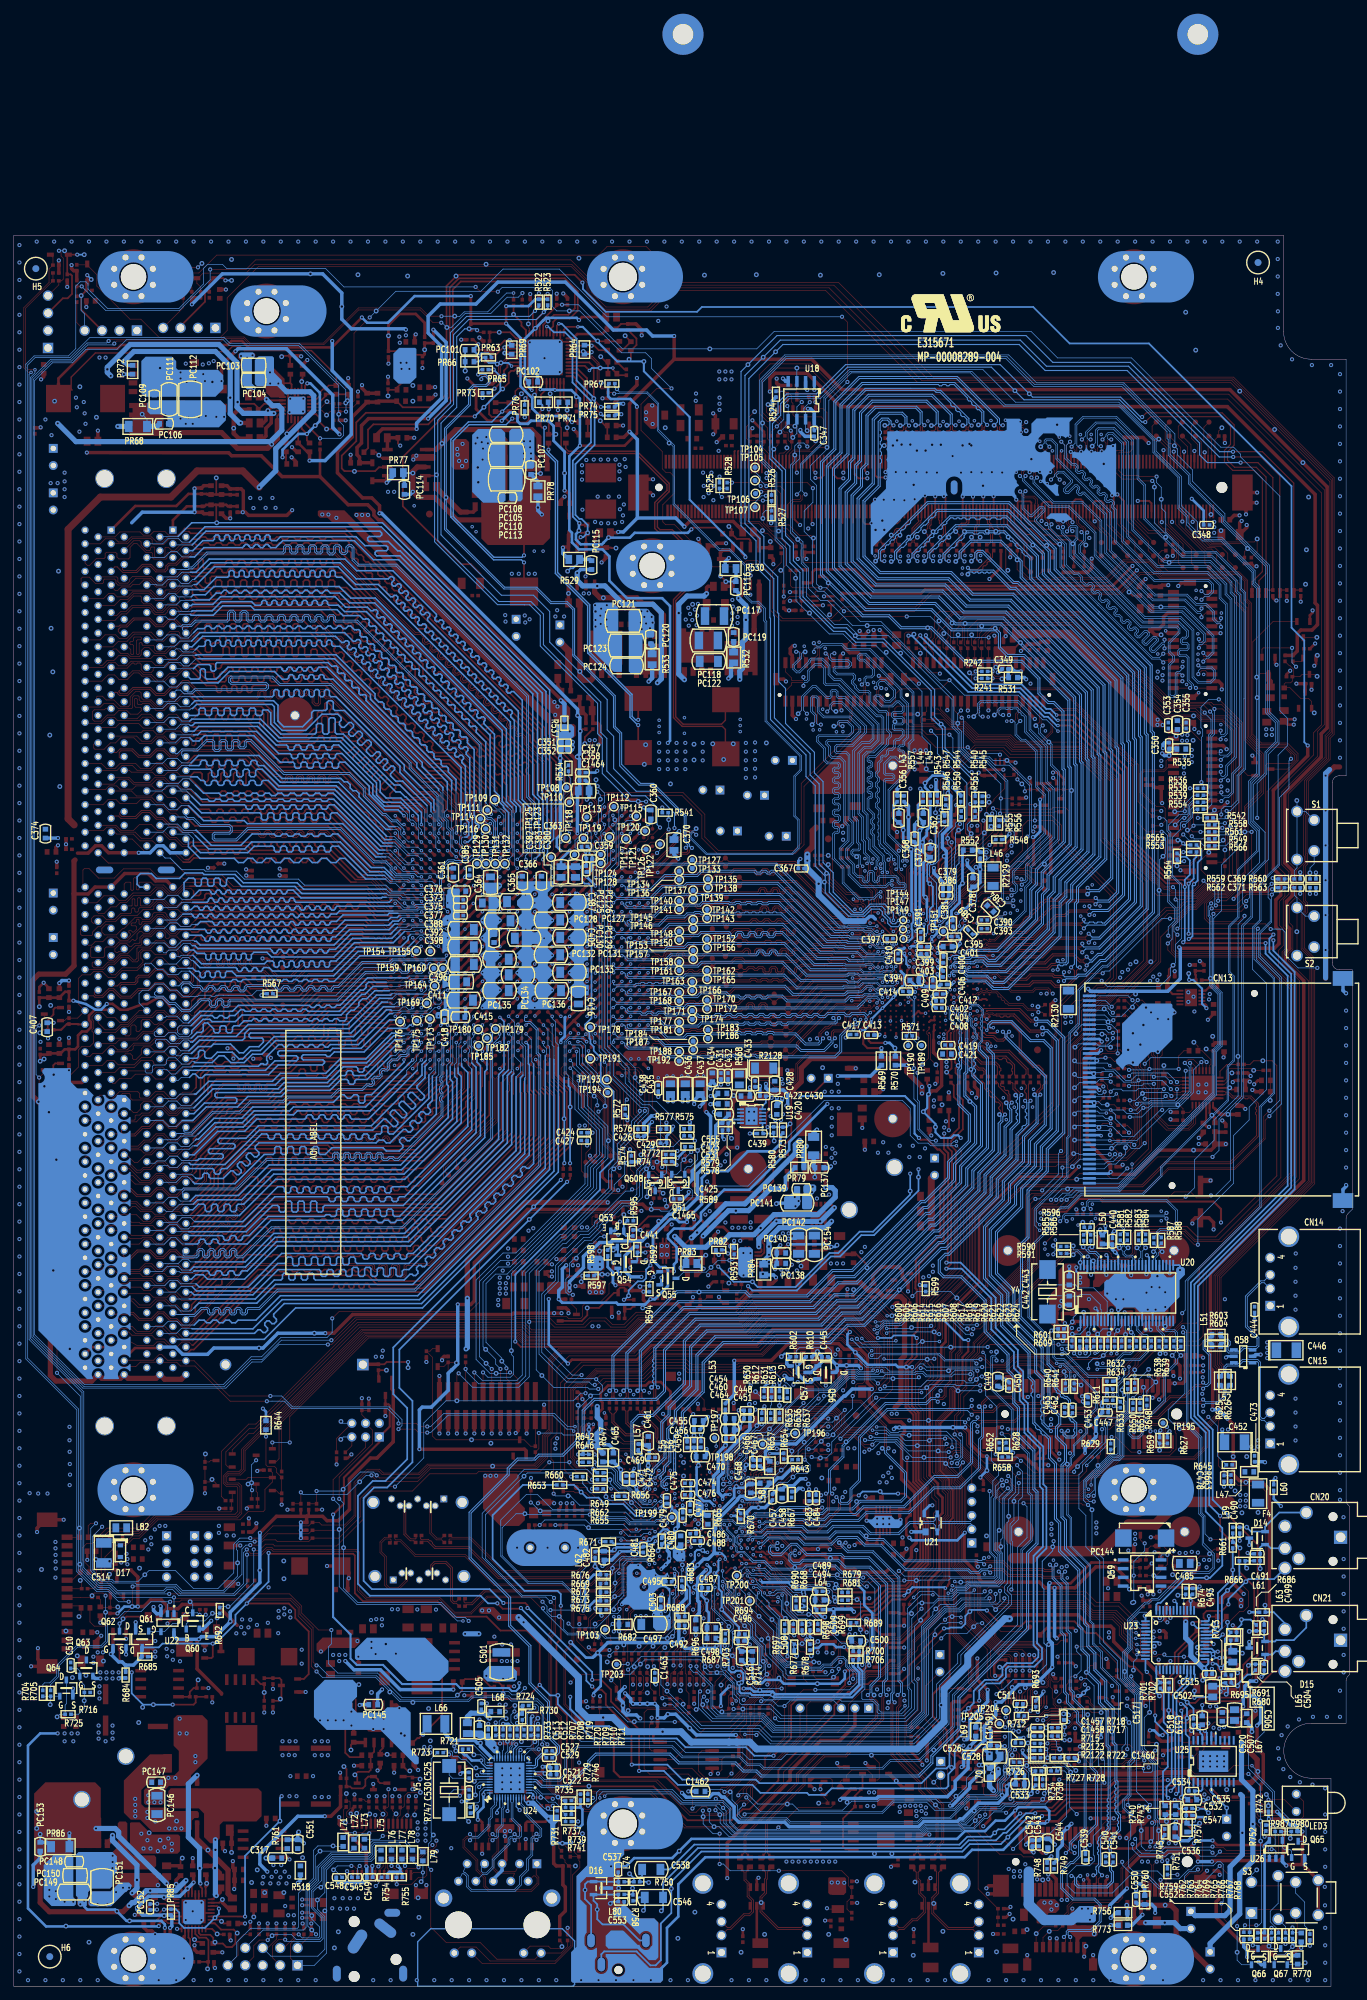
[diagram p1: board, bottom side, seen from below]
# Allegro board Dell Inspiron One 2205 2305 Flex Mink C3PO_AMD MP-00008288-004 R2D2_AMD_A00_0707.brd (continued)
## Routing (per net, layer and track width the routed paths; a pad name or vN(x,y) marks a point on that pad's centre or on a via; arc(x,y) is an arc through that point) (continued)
HT_CADOUT15_P: length 44.2
  TOP w0.124: v3(106.4,147.63) 106.68,147.35 U6.Y5
  TOP w0.127: U3.U19 67.24,145.35 66.97,145.08 v3(66.97,145.07)
  BOTTOM w0.099: 72.45,145.42 72.44,145.42 72.41,145.45 71.8,145.45 71.22,146.03 69.25,146.03 68.8,145.57 66.87,145.57 66.71,145.41 66.71,145.3 66.93,145.07 v3(66.97,145.07)
  BOTTOM w0.127: 93.99,146.86 93.99,146.89 93.74,147.14 82.81,147.14 80.96,145.28 74.16,145.28 74.03,145.42 72.45,145.42 ; 93.99,146.86 TP165.1 ; 93.99,146.86 94.31,147.18 97.06,147.18 97.41,146.82 105.56,146.82 105.91,147.17 105.91,147.47 106.07,147.63 v3(106.4,147.63)
HT_CLKIN0_N: length 37.8
  TOP w0.099: 101.24,156.38 101.26,156.38 101.27,156.39 103.55,156.39 103.72,156.22 103.72,155.78 103.54,155.6 103.31,155.6 103.22,155.69 U6.N2 ; 73.7,153.01 73.68,152.99 73.64,152.99 73.52,152.87 73.23,152.58 72.16,152.58 U3.H25
  TOP w0.127: TP45.1 93.36,157.48 ; 93.36,157.48 93.36,157.53 93.42,157.59 94.39,157.59 94.52,157.46 94.52,157.29 94.81,157 95.43,157 95.72,157.29 95.72,157.46 95.85,157.59 96.4,157.59 97.61,156.38 98.25,156.38 98.39,156.24 98.75,156.24 98.9,156.38 99.26,156.38 99.41,156.24 99.77,156.24 99.91,156.38 101.24,156.38 ; 93.36,157.48 93.24,157.59 91.7,157.59 91.54,157.43 91.2,157.43 91.03,157.59 90.4,157.59 89.95,158.04 89.2,158.04 89.05,157.89 88.7,157.89 88.54,158.04 88.19,158.04 88.04,157.89 87.68,157.89 87.53,158.04 81.01,158.04 76.9,153.92 74.74,153.92 73.83,153.01 73.71,153.01 73.7,153.01
HT_CLKIN0_P: length 38
  TOP w0.099: U6.N3 104.16,155.89 103.95,156.1 103.95,156.31 103.64,156.62 101.31,156.62 101.27,156.66 101.24,156.66 ; 73.5,153.21 73.48,153.19 73.48,153.15 73.13,152.8 71.96,152.8 71.61,152.46 U3.H24
  TOP w0.127: 73.5,153.21 73.59,153.3 73.71,153.3 74.62,154.21 76.78,154.21 80.89,158.32 90.07,158.32 90.52,157.88 92.86,157.88 TP42.1 93.36,158.22 93.7,157.88 94.51,157.88 94.81,157.58 94.81,157.41 94.93,157.28 95.31,157.28 95.44,157.41 95.44,157.58 95.73,157.88 96.52,157.88 97.73,156.66 101.24,156.66
HT_CLKIN1_N: length 46.3
  TOP w0.124: v3(107.64,155.25) 108.28,154.62 U6.P6
  TOP w0.127: v3(68.36,150.7) 68.36,150.52 U3.L20
  BOTTOM w0.099: v3(68.36,150.7) 68.8,150.26 70.72,150.26 71.67,151.21 71.79,151.21 71.82,151.18 71.85,151.18
  BOTTOM w0.127: 71.85,151.18 73.97,151.18 74.06,151.28 77.13,151.28 83.57,157.72 84.94,157.72 85.13,157.53 85.96,157.53 86.15,157.72 86.53,157.72 86.72,157.53 87.54,157.53 87.73,157.72 88.11,157.72 88.3,157.53 89.13,157.53 89.32,157.72 89.7,157.72 89.89,157.53 90.71,157.53 90.9,157.72 94.59,157.72 94.97,157.34 97.56,157.34 TP141.1 98.05,157.05 98.34,157.34 99.95,157.34 101.55,155.74 107.15,155.74 v3(107.64,155.25)
HT_CLKIN1_P: length 45.7
  TOP w0.124: v3(107.64,156.52) 108.28,155.89 U6.N6
  TOP w0.127: U3.L21 69.07,150.43 v3(69.07,150.71)
  BOTTOM w0.099: 71.85,151.47 71.83,151.47 71.81,151.44 71.58,151.44 70.62,150.48 69.29,150.48 v3(69.07,150.71)
  BOTTOM w0.127: 71.85,151.47 73.85,151.47 73.95,151.57 77.02,151.57 83.45,158 85.06,158 85.25,157.82 85.84,157.82 86.03,158 86.65,158 86.83,157.82 87.43,157.82 87.61,158 88.23,158 88.42,157.82 89.01,157.82 89.2,158 89.82,158 90,157.82 90.6,157.82 90.78,158 94.71,158 95.09,157.62 97.56,157.62 TP140.1 98.05,157.91 98.34,157.62 100.07,157.62 101.67,156.03 107.55,156.03 107.64,156.12 v3(107.64,156.52)
HT_CLKOUT0_N: length 36.9
  TOP w0.099: 78.17,145.63 78.16,145.64 78.11,145.64 77.88,145.87 73.52,145.87 73.36,145.71 71.93,145.71 71.86,145.79 71.42,145.79 71.33,145.69 71.16,145.69 71.06,145.79 70.62,145.79 70.58,145.75 70.27,145.75 70.17,145.85 70.17,145.98 70.25,146.06 U3.T23
  TOP w0.127: U6.AC1 101.46,142.69 100.76,142.69 100.08,142.02 99.59,142.02 99.27,142.34 89.11,142.34 88.95,142.51 88.41,142.51 88.28,142.64 88.28,142.96 87.99,143.26 87.37,143.26 87.08,142.96 87.08,142.64 86.95,142.51 86.57,142.51 86.44,142.64 86.44,142.96 86.15,143.26 85.53,143.26 85.24,142.96 85.24,142.64 85.11,142.51 82.67,142.51 TP69.1 81.69,142.51 81.3,142.51 78.17,145.63
HT_CLKOUT0_P: length 37.4
  TOP w0.099: U3.T22 69.83,146.06 69.95,145.94 69.95,145.75 70.18,145.52 70.67,145.52 70.72,145.56 70.97,145.56 71.06,145.47 71.42,145.47 71.52,145.56 71.77,145.56 71.84,145.49 73.45,145.49 73.61,145.65 77.78,145.65 77.97,145.46 77.97,145.43
  TOP w0.127: 77.97,145.43 81.18,142.22 81.69,142.22 TP71.1 82.67,142.22 85.23,142.22 85.52,142.52 85.52,142.84 85.65,142.97 86.03,142.97 86.16,142.84 86.16,142.52 86.45,142.22 87.07,142.22 87.36,142.52 87.36,142.84 87.49,142.97 87.87,142.97 88,142.84 88,142.52 88.29,142.22 88.83,142.22 89,142.06 99.15,142.06 99.47,141.73 100.2,141.73 100.88,142.41 101.46,142.41 U6.AD1
HT_CLKOUT1_N: length 42.5
  TOP w0.124: U6.AD4 105.76,141.93 105.14,142.55 v3(105.13,142.55)
  TOP w0.127: v3(70.21,141.82) 69.97,142.06 U3.AA22
  BOTTOM w0.127: v3(70.21,141.82) 70.59,141.43 70.63,141.43 71.02,141.82 72.97,141.82 73.28,141.51 73.64,141.51 73.95,141.82 76.47,141.82 76.91,141.38 77.55,141.38 77.87,141.71 78.46,141.71 78.78,141.38 79.13,141.38 79.46,141.71 80.04,141.71 80.37,141.38 80.72,141.38 81.04,141.71 81.63,141.71 81.95,141.38 82.3,141.38 82.63,141.71 83.21,141.71 83.54,141.38 83.89,141.38 84.21,141.71 84.8,141.71 85.12,141.38 85.47,141.38 85.8,141.71 86.38,141.71 86.71,141.38 87.06,141.38 87.38,141.71 87.97,141.71 88.29,141.38 88.64,141.38 88.97,141.71 89.55,141.71 89.88,141.38 90.23,141.38 90.55,141.71 91.14,141.71 91.46,141.38 91.81,141.38 92.14,141.71 92.72,141.71 93.05,141.38 95.07,141.38 95.31,141.62 95.66,141.62 TP171.1 96.64,141.62 97.4,141.62 97.56,141.78 98.45,141.78 98.6,141.62 99.85,141.62 100.25,142.01 101.12,142.01 101.39,141.74 101.81,141.74 102.09,142.01 102.7,142.01 102.98,141.74 103.39,141.74 103.67,142.01 105.43,142.01 105.62,142.21 105.62,142.38 105.45,142.55 v3(105.13,142.55)
HT_CLKOUT1_P: length 42.5
  TOP w0.124: v3(106.4,142.55) 106.41,142.55 107.03,141.93 U6.AD5
  TOP w0.127: v3(70.83,140.84) 70.83,140.87 U3.AB23
  BOTTOM w0.127: v3(70.83,140.84) 70.83,141.23 71.14,141.54 72.85,141.54 73.16,141.22 73.76,141.22 74.07,141.54 76.36,141.54 76.8,141.1 77.67,141.1 77.99,141.42 78.34,141.42 78.67,141.1 79.25,141.1 79.58,141.42 79.93,141.42 80.25,141.1 80.84,141.1 81.16,141.42 81.51,141.42 81.84,141.1 82.42,141.1 82.75,141.42 83.1,141.42 83.42,141.1 84.01,141.1 84.33,141.42 84.68,141.42 85.01,141.1 85.59,141.1 85.92,141.42 86.27,141.42 86.59,141.1 87.18,141.1 87.5,141.42 87.85,141.42 88.18,141.1 88.76,141.1 89.09,141.42 89.44,141.42 89.76,141.1 90.35,141.1 90.67,141.42 91.02,141.42 91.35,141.1 91.93,141.1 92.26,141.42 92.61,141.42 92.93,141.1 95.18,141.1 95.42,141.34 95.66,141.34 TP174.1 96.64,141.34 97.52,141.34 97.67,141.49 98.33,141.49 98.49,141.34 99.97,141.34 100.36,141.73 101,141.73 101.28,141.45 101.93,141.45 102.2,141.73 102.58,141.73 102.86,141.45 103.51,141.45 103.79,141.73 105.55,141.73 105.91,142.09 105.91,142.39 106.07,142.55 v3(106.4,142.55)
HT_CTLIN0_N: length 39
  TOP w0.099: U3.M25 72.12,149.34 73.11,149.34 73.56,149.79 75.62,149.79 75.78,149.95 75.9,150.07 75.94,150.07 75.96,150.09
  TOP w0.127: 75.96,150.09 76.04,150.17 79.92,150.17 80.66,150.9 81.14,150.9 81.26,150.78 81.26,150.41 81.56,150.11 82.17,150.11 82.47,150.41 82.47,150.78 82.59,150.9 82.97,150.9 83.1,150.78 83.1,150.41 83.4,150.11 84.01,150.11 84.31,150.41 84.31,150.78 84.43,150.9 84.81,150.9 84.94,150.78 84.94,150.41 85.23,150.11 85.85,150.11 86.14,150.41 86.14,150.78 86.27,150.9 86.65,150.9 86.78,150.78 86.78,150.41 87.07,150.11 87.69,150.11 87.98,150.41 87.98,150.78 88.11,150.9 88.33,150.9 88.75,150.48 90.83,150.48 TP54.1 91.82,150.48 93.97,150.48 94.71,149.73 95.39,149.73 95.69,150.03 95.69,150.26 95.81,150.38 96.19,150.38 96.32,150.26 96.32,150.03 96.62,149.73 97.23,149.73 97.53,150.03 97.53,150.26 97.65,150.38 98.03,150.38 98.16,150.26 98.16,150.03 98.45,149.73 99.07,149.73 99.36,150.03 99.36,150.26 99.49,150.38 99.87,150.38 100,150.26 100,150.03 100.29,149.73 100.91,149.73 101.21,150.03 101.89,150.03 102.09,149.83 102.09,149.68 U6.V1
HT_CTLIN0_P: length 39.5
  TOP w0.099: U3.M24 71.61,149.26 71.92,149.56 73.02,149.56 73.47,150.01 75.53,150.01 75.74,150.23 75.74,150.27 75.76,150.29
  TOP w0.127: 75.76,150.29 75.92,150.45 79.8,150.45 80.54,151.19 81.25,151.19 81.55,150.89 81.55,150.53 81.67,150.4 82.05,150.4 82.18,150.53 82.18,150.89 82.48,151.19 83.09,151.19 83.39,150.89 83.39,150.53 83.51,150.4 83.89,150.4 84.02,150.53 84.02,150.89 84.31,151.19 84.93,151.19 85.22,150.89 85.22,150.53 85.35,150.4 85.73,150.4 85.86,150.53 85.86,150.89 86.15,151.19 86.77,151.19 87.06,150.89 87.06,150.53 87.19,150.4 87.57,150.4 87.7,150.53 87.7,150.89 87.99,151.19 88.45,151.19 88.87,150.76 90.83,150.76 TP53.1 91.82,150.76 94.08,150.76 94.83,150.02 95.28,150.02 95.4,150.14 95.4,150.38 95.7,150.67 96.31,150.67 96.61,150.38 96.61,150.14 96.73,150.02 97.11,150.02 97.24,150.14 97.24,150.38 97.53,150.67 98.15,150.67 98.45,150.38 98.45,150.14 98.57,150.02 98.95,150.02 99.08,150.14 99.08,150.38 99.37,150.67 99.99,150.67 100.28,150.38 100.28,150.14 100.41,150.02 100.79,150.02 101.09,150.31 101.46,150.31 U6.U1
HT_CTLIN1_N: length 46
  TOP w0.124: U6.V5 106.98,149.54 v3(106.4,150.12)
  TOP w0.127: v3(66.19,147.23) 66.19,146.96 U3.R18
  BOTTOM w0.099: v3(66.19,147.23) 66.19,147.2 66.64,146.76 67.36,146.76 67.74,147.14 71.84,147.14 72.03,147.34 72.44,147.34 72.47,147.31 72.49,147.31
  BOTTOM w0.127: 96.02,149.89 TP157.1 ; 96.02,149.89 96.02,149.96 95.89,150.1 86.76,150.1 86.47,150.39 86.47,150.54 86.34,150.67 85.96,150.67 85.83,150.54 85.83,150.39 85.54,150.1 84.92,150.1 84.63,150.39 84.63,150.54 84.5,150.67 84.12,150.67 83.99,150.54 83.99,150.39 83.7,150.1 82.55,150.1 79.58,147.14 73.47,147.14 73.3,147.31 72.49,147.31 ; 96.02,149.89 96.24,150.1 99.19,150.1 99.92,149.37 105.57,149.37 105.93,149.73 105.93,149.91 106.13,150.12 v3(106.4,150.12)
HT_CTLIN1_P: length 45.2
  TOP w0.124: v3(105.18,150.13) 105.69,150.13 105.9,149.91 105.9,149.68 U6.V4
  TOP w0.127: U3.P19 67.24,147.58 v3(66.89,147.23)
  BOTTOM w0.099: v3(66.89,147.23) 66.89,147.11 66.96,147.05 67.33,147.05 67.65,147.37 71.75,147.37 71.94,147.56 72.44,147.56 72.47,147.59 72.49,147.59
  BOTTOM w0.127: 96.02,150.72 95.68,150.38 86.88,150.38 86.75,150.51 86.75,150.66 86.46,150.95 85.84,150.95 85.55,150.66 85.55,150.51 85.42,150.38 85.04,150.38 84.91,150.51 84.91,150.66 84.62,150.95 84,150.95 83.71,150.66 83.71,150.51 83.58,150.38 82.43,150.38 79.47,147.42 73.59,147.42 73.42,147.59 72.49,147.59 ; 96.02,150.72 TP153.1 ; 96.02,150.72 96.02,150.67 96.31,150.38 99.31,150.38 100.03,149.66 105.46,149.66 105.64,149.85 105.64,150.09 105.52,150.22 105.27,150.22 v3(105.18,150.13)
HT_CTLOUT0_N: length 37
  TOP w0.099: U3.M23 70.23,149.26 70.14,149.17 70.14,149.08 70.25,148.97 70.6,148.97 70.62,148.99 71.08,148.99 71.12,148.95 71.36,148.95 71.4,148.99 71.86,148.99 71.9,148.95 73.59,148.95 74.04,149.4 75.8,149.4 75.83,149.43 75.86,149.43 ; U6.W3 104.1,148.27 103.98,148.38 103.98,148.71 103.69,149 101.52,149 101.46,149.06 101.43,149.06
  TOP w0.127: 75.86,149.43 76.01,149.43 76.39,149.81 80.67,149.81 81.05,149.43 88.46,149.43 88.85,149.82 89.96,149.82 90.55,149.24 92.74,149.24 TP55.1 93.23,149.47 93.46,149.24 94.31,149.24 94.49,149.06 101.43,149.06
HT_CTLOUT0_P: length 36.8
  TOP w0.099: 101.4,148.77 101.42,148.77 101.43,148.77 103.6,148.77 103.76,148.61 103.76,148.4 103.63,148.27 U6.W2 ; U3.M22 70.16,148.74 70.69,148.74 70.72,148.76 70.99,148.76 71.03,148.72 71.46,148.72 71.5,148.76 71.77,148.76 71.81,148.72 73.68,148.72 74.14,149.18 75.8,149.18 75.83,149.15 75.86,149.15
  TOP w0.127: 75.86,149.15 76.13,149.15 76.51,149.53 80.55,149.53 80.94,149.15 88.58,149.15 88.97,149.54 89.84,149.54 90.43,148.96 92.74,148.96 TP57.1 93.23,148.74 93.44,148.96 94.19,148.96 94.37,148.77 101.4,148.77
HT_CTLOUT1_N: length 44.5
  TOP w0.124: v3(107.63,148.9) 108.26,148.27 U6.W6
  TOP w0.127: v3(67.74,146.26) 67.74,146.41 U3.R20
  BOTTOM w0.099: v3(67.74,146.26) 67.97,146.49 67.97,146.71 68.2,146.94 69.13,146.94 69.26,146.81 71.63,146.81 72.07,146.38 72.47,146.38 72.5,146.41 72.51,146.41
  BOTTOM w0.127: 98.05,149.1 TP158.1 ; 98.05,149.1 98.42,148.73 99.59,148.73 99.91,148.41 107.35,148.41 107.63,148.69 107.63,148.89 v3(107.63,148.9) ; 98.05,149.1 98.05,148.94 97.85,148.73 95.42,148.73 94.85,149.3 82.95,149.3 80.31,146.66 73.65,146.66 73.39,146.41 72.51,146.41
HT_CTLOUT1_P: length 44.1
  TOP w0.124: v3(107.6,147.63) 108.24,147 U6.Y6
  TOP w0.127: v3(68.44,146.25) 68.44,146.31 U3.R21
  BOTTOM w0.099: 72.51,146.12 72.48,146.12 72.45,146.15 71.97,146.15 71.54,146.59 69.16,146.59 69.04,146.72 68.29,146.72 68.19,146.62 68.19,146.5 v3(68.44,146.25)
  BOTTOM w0.127: 72.51,146.12 73.51,146.12 73.77,146.38 80.43,146.38 83.07,149.02 94.73,149.02 95.31,148.45 97.84,148.45 98.05,148.23 98.05,148.16 ; 98.05,148.16 98.34,148.45 99.47,148.45 99.79,148.12 107.35,148.12 107.6,147.87 v3(107.6,147.63) ; 98.05,148.16 TP161.1
HT_RXCALN: length 10.6
  TOP w0.102: R138.1 v1(76.34,164.72) 75.7,164.08 75.7,161.42 73.61,159.32 72.34,159.32 71.24,158.23 U3.A24
HT_RXCALP: length 13
  TOP w0.102: R138.2 78.29,164.32 77.99,164.02 76.97,164.02 v1(76.34,163.39) 76.02,163.07 76.02,161.29 73.73,159 72.34,159 71.64,158.31 71.64,157.99 71.38,157.73 71.19,157.73 70.88,157.42 70.88,156.89 U3.C23
HT_TXCALN: length 9.4
  TOP w0.102: U3.B25 72.14,157.35 72.85,157.35 73.35,157.86 73.54,157.86 76.53,160.85 v1(76.91,160.85) 77.23,161.16 77.23,162.33 78.22,163.32 R142.2
HT_TXCALP: length 9.4
  TOP w0.102: U3.B24 71.57,157.58 72.65,157.58 73.25,158.18 73.42,158.18 76.34,161.1 76.34,161.86 v1(76.59,162.12) 76.59,162.5 77.42,163.32 R142.1
I2C_CLK: length 11.9
  TOP w0.102: U3.B9 59.24,156.88 58.91,157.57 58.91,157.75 59,158 59,158.35 58.85,158.5 58.85,159.17 58.43,159.59 58.43,160.02 56.78,161.67 56.14,161.67 v1(54.81,163) 54.62,163.19 53.35,163.19 53.22,163.07 R143.2 52.38,163.98 R140.2
I2C_DATA: length 12.5
  TOP w0.102: U3.A9 59.22,157.68 59.22,158.51 59.12,158.61 59.12,159.49 58.94,159.66 58.94,160.15 56.91,162.18 56.4,162.18 54.62,163.96 53.92,163.96 v1(53.48,164.4) 53.22,164.66 52.9,164.66 R137.2 52.43,165.81 R134.2
INL: length 231.7
  TOP w0.254: R82.2 63.51,196.22 v2(62.94,196.79) ; v2(23.84,160.6) 24.09,160.6 24.65,161.16 26.92,161.16 33.28,167.53 33.28,176.91 40.78,184.4 v3(42.87,184.4) ; v2(24.9,40.13) 23.76,41.27 22.87,41.27 22.1,42.04 16.66,42.04 16.39,42.31 16.39,45.34 15.87,45.86 15.87,46.82 14.29,48.41 14.29,58.22 16.52,60.45 16.52,63.69 19.25,66.42 v2(19.25,68.52) ; v2(23.84,153.31) 11.62,153.31 v2(11.49,153.19)
  BOTTOM w0.254: R553.2 22.7,164.51 23.1,164.11 23.1,161.34 v2(23.84,160.6) v2(23.84,153.31) ; v3(42.87,184.4) 43.06,184.4 44.14,185.48 44.74,185.48 48.33,189.08 55.36,189.08 62.94,196.66 v2(62.94,196.79) ; v2(19.25,68.52) 20.84,70.1 20.84,80.88 23,83.03 23,102.23 8.9,116.33 8.9,147.45 12.08,150.62 12.08,152.6 v2(11.49,153.19) ; v2(24.9,40.13) 24.78,40.01 24.78,27.62 v1(24.9,27.5) 24.28,27.5 C535.1
INL_MXM_R: length 2.7
  TOP w0.254: v2(24.6,165.2) 25.07,164.73 CN9.22
  BOTTOM w0.254: R553.1 24.57,165.23 v2(24.6,165.2)
INL_NB_R: length 2.6
  TOP w0.102: R82.1 63.08,194.9 62.92,194.74 v1(62.92,194.17) 62.92,193.72 62.99,193.65 CN7.22
INR: length 218.3
  TOP w0.254: v2(18.04,68.58) 13.78,64.31 13.78,48.2 15.31,46.66 15.31,45.66 15.89,45.09 15.89,42.02 16.38,41.52 21.29,41.52 v2(21.85,40.96) ; R81.2 62.24,196.66 v2(62.11,196.79) ; v2(23.05,160.53) 23.05,160.73 23.53,161.21 23.91,161.21 24.37,161.67 26.71,161.67 32.78,167.74 32.78,177.42 40.53,185.17 v3(43.06,185.17) ; v2(11.49,152.35) 11.77,152.63 23.73,152.63 v2(23.81,152.55)
  BOTTOM w0.254: v3(43.06,185.17) 43.95,186.06 44.58,186.06 48.16,189.64 55.15,189.64 62.11,196.6 v2(62.11,196.79) ; C519.1 v2(21.85,40.96) ; v2(11.49,152.35) 11.49,150.85 8.39,147.75 8.39,116.08 22.49,101.98 22.49,83.25 20.33,81.09 20.33,70.87 v2(18.04,68.58) ; R565.2 21.98,165.53 21.98,164.21 22.52,163.68 22.52,161.06 v2(23.05,160.53) 23.28,160.3 23.28,152.96 23.68,152.55 v2(23.81,152.55)
INR_MXM_R: length 3.9
  TOP w0.254: CN9.23 25.37,165.73 v2(24.62,166.47)
  BOTTOM w0.254: v1(25.41,166.94) 25.09,166.94 v2(24.62,166.47) 24.39,166.24 R565.1
INR_NB_R: length 5.4
  TOP w0.102: R81.1 61.99,194.65 CN7.23 61.99,191.65 61.67,191.33 60.21,191.33 v2(60.08,191.2)
INTR_ALERT_N: length 13.2
  TOP w0.102: U10.B2 84.64,55.51 83.41,55.51 79.76,51.86 74.6,51.86 TP97.1
IOPLLVDD18(NC): length 6.6
  TOP w0.305: U3.AE23 70.44,137.72 70.14,137.41 v2(68.02,137.41)
  BOTTOM w0.381: v2(68.02,137.41) 67.38,137.41 v1(66.62,136.65) 66.56,136.59 R570.1
IOPLLVDD(NC): length 5.7
  TOP w0.305: U3.AE24 71.24,137.27 70.62,136.65 v2(68.59,136.65)
  BOTTOM w0.508: R569.1 v2(68.59,136.65)
ISOLATEB_N: length 9
  BOTTOM w0.102: v1(118.65,39.04) 119.14,38.56 119.14,37.04 R710.1 R711.1 118.63,36.09 118.53,35.99 118.53,35.18 119.04,34.67 120.18,34.67 121,33.85 U24.26
JDREF_AUD: length 3.7
  BOTTOM w0.102: v1(25.41,56.96) 25.27,57.1 R674.2 24.27,56.58 24.54,56.3 U23.40
KB_RST_N: length 161.4
  TOP w0.102: v2(88.53,25.04) 90.28,23.29 97.04,23.29 102.14,28.4 114.12,28.4 115.17,29.46 115.17,39.24 116.62,40.69 116.62,50.8 116.06,51.36 116.06,56.34 v2(116.29,56.57) ; U10.AE21 103.87,70.14 104.02,70.29 104.02,71.25 104.47,71.69 106.82,71.69 107.58,72.45 v3(107.96,72.45) ; U11.12 46.11,41.02 46.24,40.89 47.25,40.89 47.38,40.77 47.38,40.01 v2(49.41,37.97)
  BOTTOM w0.102: v3(107.96,72.45) 108.09,72.45 108.86,73.23 111.03,73.23 111.52,73.71 111.52,74.55 111.73,74.76 120.19,74.76 v1(120.66,74.3) 126.29,68.67 126.29,62.32 120.86,56.9 116.62,56.9 v2(116.29,56.57) ; v2(49.41,37.97) 49.85,37.54 49.85,34.62 50.28,34.19 50.28,32.36 50.61,32.03 50.61,30.56 51.45,29.72 51.45,28.19 51.95,27.69 55.84,27.69 57.9,25.63 60.82,25.63 61.99,26.8 66.81,26.8 68.4,25.21 88.34,25.21 88.5,25.04 v2(88.53,25.04)
KBC_LOW_BAT_N: length 9.3
  TOP w0.102: U10.E1 87.64,55.56 87.58,55.5 87.58,54.72 83.07,50.22 v1(83.07,49.45) R404.1
LAD0: length 123.4
  TOP w0.102: R380.2 v2(47,45.97) R370.1 47.02,46.69 47.53,47.21 47.53,48.48 48.08,49.02 51.41,49.02 55.76,53.38 55.76,59.39 57.77,61.4 57.77,66.95 57.21,67.51 57.21,73.1 57.77,73.66 57.77,74.17 59.09,75.49 59.09,77.52 v2(58.79,77.83) 58.3,77.83 58.1,78.03 57.07,78.03 52.16,73.11 52.16,71.98 51.25,71.07 39.01,71.07 38.87,70.93 38.17,70.93 v2(37.67,71.44) ; v2(70.98,79.55) 71.82,80.39 73.73,80.39 74.94,81.6 74.94,83.06 75.58,83.69 82.64,83.69 86.25,80.09 88.12,80.09 89.84,78.37 89.84,76.74 89.74,76.64 89.74,75.59 89.91,75.41 90.43,75.41 90.53,75.32 U10.J27
  BOTTOM w0.102: v2(70.98,79.55) 70.5,79.55 70.42,79.47 69.8,79.47 69.6,79.67 66.35,79.67 64.65,77.98 v1(60.34,77.98) 60.18,77.83 v2(58.79,77.83) ; R648.2 29.92,84.2 30.94,83.19 32.07,83.19 33.26,81.99 33.26,77.19 33.88,76.57 34.78,76.57 37.39,73.97 37.39,71.72 v2(37.67,71.44)
LAD0_R: length 6.6
  TOP w0.102: CN2.8 29.08,88.82 29.22,88.96 v2(29.67,88.96)
  BOTTOM w0.102: v2(29.67,88.96) 28.71,88.01 v1(28.61,88.01) 29.92,86.7 R648.1
LAD1: length 124.3
  TOP w0.102: R381.2 v2(48.02,45.97) R371.1 48.02,46.74 48.52,47.24 48.52,48.51 48.78,48.77 51.44,48.77 55.97,53.29 55.97,59.31 57.98,61.32 57.98,67.18 57.44,67.72 57.44,72.92 57.98,73.46 57.98,74.07 59.29,75.38 59.29,78.11 58.92,78.49 58.33,78.49 v2(58.3,78.51) 57.25,78.51 51.95,73.22 51.95,72.06 51.17,71.27 39.44,71.27 39.28,71.44 v2(38.43,71.44) ; v3(69.89,80.99) 70.05,81.15 73.29,81.15 74.18,82.04 74.18,83.34 75.29,84.45 82.74,84.45 86.5,80.7 88.37,80.7 90.51,78.55 90.51,76.76 90.55,76.73 90.55,76.3 90.51,76.27 90.51,75.79 90.61,75.69 90.94,75.69 91.2,75.44 91.2,74.87 U10.J26
  BOTTOM w0.102: v3(69.89,80.99) 67.92,80.99 67.34,80.41 65.3,80.41 65.15,80.26 v1(64.55,80.26) 59.07,80.26 58.3,79.5 v2(58.3,78.51) ; R651.2 30.94,83.63 31.13,83.44 32.1,83.44 33.47,82.07 33.47,77.27 33.97,76.78 34.87,76.78 37.59,74.05 37.59,72.27 v2(38.43,71.44)
LAD1_R: length 5
  TOP w0.102: CN2.10 29.88,86.33 30.55,85.66 v2(30.94,85.66)
  BOTTOM w0.102: v1(30.43,87.25) 30.43,86.17 v2(30.94,85.66) R651.1
LAD2: length 117.9
  TOP w0.102: v3(38.05,73.03) 37.92,72.9 37.92,72.26 38.24,71.95 39.13,71.95 39.6,71.48 51.08,71.48 51.75,72.14 51.75,73.32 57.43,78.99 v2(59.09,78.99) 59.5,78.59 59.5,75.3 58.18,73.98 58.18,73.31 57.67,72.8 57.67,67.82 58.18,67.31 58.18,61.23 56.17,59.22 56.17,53.21 51.28,48.32 49.92,48.32 49.54,47.94 49.54,47.24 49.03,46.74 R372.1 v2(49.03,45.97) R382.2 ; U10.H29 90.04,76.52 90.04,78.45 88.2,80.29 86.33,80.29 82.68,83.95 75.45,83.95 74.69,83.19 74.69,81.79 73.54,80.64 70.8,80.64 v2(70.17,80.01)
  BOTTOM w0.102: v2(59.09,78.99) 59.35,78.74 v1(63.36,78.74) 64.98,78.74 66.17,79.92 69.6,79.92 69.68,80.01 v2(70.17,80.01) ; v3(38.05,73.03) 38.05,73.88 34.92,77.01 34.04,77.01 33.7,77.34 33.7,82.17 31.95,83.92 R650.2
LAD2_R: length 8.5
  TOP w0.102: v2(31.95,85.66) 31.44,86.17 30.81,86.17 30.68,86.3 CN2.12
  BOTTOM w0.102: v1(29.67,89.85) 31.16,88.36 31.16,86.46 v2(31.95,85.66) R650.1
LAD3: length 123.4
  TOP w0.102: v3(69.29,80.52) 70.11,80.52 70.5,80.9 73.42,80.9 74.43,81.92 74.43,83.31 75.32,84.2 82.71,84.2 86.42,80.49 88.29,80.49 90.26,78.52 90.26,76.73 90.34,76.64 90.34,76.39 90.04,76.08 U10.H28 ; R383.2 49.77,45.54 v2(49.77,46) 50.46,46.69 ; R373.1 50.46,46.69 ; 50.46,46.69 50.03,46.69 49.79,46.93 49.79,47.82 50.05,48.07 51.32,48.07 56.37,53.13 56.37,59.14 58.38,61.15 58.38,67.43 57.9,67.92 57.9,72.59 58.38,73.08 58.38,73.9 59.7,75.22 59.7,79.4 v2(59.32,79.78) 57.86,79.78 51.55,73.47 51.55,72.23 51,71.68 39.71,71.68 39,72.39 v3(38.43,72.39)
  BOTTOM w0.102: v3(38.43,72.39) 38.68,72.64 38.68,73.53 34.99,77.23 34.13,77.23 33.92,77.44 33.92,82.26 32.52,83.66 32.52,86.18 R639.2 ; v3(69.29,80.52) 67.89,80.52 67.55,80.18 65.84,80.18 65.16,79.5 v1(61.61,79.5) 61.33,79.78 v2(59.32,79.78)
LAD3_R: length 3.5
  TOP w0.102: CN2.14 31.48,88.75 v2(31.7,88.96)
  BOTTOM w0.102: R639.1 v2(31.7,88.96) v1(31.7,89.79)
LAN_ACT_LED_N: length 8.3
  BOTTOM w0.102: R723.2 132.2,34.26 131.28,34.26 131.07,34.06 131.07,33.58 130.96,33.46 130.25,33.46 129.8,33.02 129.11,33.02 127.89,31.8 v1(127.65,31.8) 127.6,31.75 126.63,31.75 126.24,31.36 U24.40
LAN_ACT_LED_R_N: length 49.9
  TOP w0.102: v2(134.19,16.95) 134.25,16.89 134.25,8.64 131.96,6.35 127.01,6.35 124.6,3.94 119.08,3.94 CN23.L1 115.25,4.84 114.31,5.78 C321.1
  BOTTOM w0.102: R723.1 134.19,33.13 134.19,22.35 v1(133.87,22.03) 134.19,21.72 134.19,21.15 134.57,20.76 134.57,17.34 v2(134.19,16.95)
LAN_EVDD10: length 6.8
  TOP w0.381: v2(117.94,31.98) 117.94,31.43 R480.2
  BOTTOM w0.178: U24.21 119.13,31.36 119.01,31.24 117.87,31.24 v1(117.61,30.99) 117.44,30.81 C522.1
  BOTTOM w0.381: C521.1 C522.1
  BOTTOM w0.508: C521.1 116.93,31.98 v2(117.94,31.98)
LAN_MDI0_DN: length 30.2
  TOP w0.099: U14.3 127.7,21.49 127.8,21.59 128.21,21.59 v2(128.52,21.27) 128.84,21.59 128.94,21.59 129.3,21.23 129.3,20.3 127.39,18.39 127.39,17 126.25,15.85 126.25,14.58 125.76,14.1 119.64,14.1 118.76,14.99 118.76,15.77 119.06,16.08 119.28,16.08 CN23.2
  BOTTOM w0.099: U24.2 124.6,26.87 124.67,26.8 124.67,26.36 125.23,25.8 125.23,24.64 125.61,24.26 125.61,23.26 127.29,21.59 128.41,21.59 128.52,21.47 v2(128.52,21.27)
LAN_MDI0_DP: length 31.4
  TOP w0.099: CN23.1 118.88,17.74 118.88,16.26 118.5,15.88 118.5,14.88 119.54,13.84 125.87,13.84 126.5,14.48 126.5,15.75 127.65,16.89 127.65,18.29 129.55,20.19 129.55,21.34 129.05,21.84 128.84,21.84 v2(128.52,22.16) 128.21,21.84 127.8,21.84 127.7,21.94 U14.4
  BOTTOM w0.099: v2(128.52,22.16) 128.21,21.84 127.39,21.84 125.87,23.37 125.87,24.36 125.49,24.74 125.49,25.91 124.93,26.47 124.93,26.8 125,26.87 U24.1
LAN_MDI1_DN: length 19.3
  TOP w0.099: CN23.4 122.06,16.37 122.1,16.48 124.61,16.48 125.3,17.17 125.3,18.92 124.6,19.62 124.6,21.48 124.7,21.59 124.93,21.59 v2(125.24,21.27) 125.56,21.59 125.72,21.59 125.82,21.49 U14.1
  BOTTOM w0.099: U24.5 123.4,26.87 123.47,26.8 123.47,26.02 123.71,25.78 123.71,23.37 124.37,22.71 124.37,21.82 124.65,21.54 124.97,21.54 v2(125.24,21.27)
LAN_MDI1_DP: length 19
  TOP w0.099: U14.6 125.82,21.94 125.72,21.84 125.56,21.84 v2(125.24,22.16) 124.93,21.84 124.6,21.84 124.34,21.59 124.34,19.51 125.04,18.81 125.04,17.27 124.5,16.73 121.99,16.73 121.86,16.77 CN23.3
  BOTTOM w0.099: U24.4 123.8,26.87 123.73,26.8 123.73,26.12 123.96,25.89 123.96,23.47 124.62,22.81 124.62,21.92 124.75,21.8 124.88,21.8 v2(125.24,22.16)
LAN_MDI2_DN: length 18.9
  TOP w0.099: U13.3 121.35,21.49 121.45,21.59 121.72,21.59 v2(122.04,21.27)
  BOTTOM w0.099: CN23.8 126.72,16.26 126.09,16.26 125.04,17.3 125.04,18.38 122.72,20.7 122.72,21.43 122.56,21.59 122.35,21.59 v2(122.04,21.27) 121.72,21.59 121.3,21.59 121.04,21.84 121.04,23.24 122.27,24.47 122.27,26.8 122.2,26.87 U24.8
LAN_MDI2_DP: length 18.6
  TOP w0.099: U13.4 121.35,21.94 121.45,21.84 121.72,21.84 v2(122.04,22.16)
  BOTTOM w0.099: U24.7 122.6,26.87 122.53,26.8 122.53,24.37 121.3,23.14 121.3,21.95 121.4,21.84 121.68,21.84 121.99,22.16 v2(122.04,22.16) 122.05,22.16 122.36,21.84 122.67,21.84 122.97,21.54 122.97,20.8 125.29,18.48 125.29,17.41 126.19,16.51 126.63,16.51 126.88,16.76 126.88,17.36 CN23.7
LAN_MDI3_DN: length 30.1
  TOP w0.099: v2(118.84,21.31) 119.12,21.59 119.37,21.59 119.47,21.49 U13.1
  BOTTOM w0.099: U24.11 121,26.87 121.07,26.8 121.07,26.68 120.13,25.74 120.13,25 118.08,22.95 118.08,21.89 118.33,21.64 118.52,21.64 v2(118.84,21.31) 119.13,21.6 119.27,21.6 119.39,21.48 119.39,19.08 120.03,18.44 120.03,16.91 121.04,15.9 121.04,14.75 121.95,13.84 128.39,13.84 129.04,14.5 129.04,16.02 129.16,16.14 129.36,16.34 129.4,16.34 129.55,16.41 129.68,16.37 CN23.10
LAN_MDI3_DP: length 29.6
  TOP w0.099: U13.6 119.47,21.94 119.37,21.84 119.2,21.84 v2(118.84,22.2)
  BOTTOM w0.099: U24.10 121.4,26.87 121.33,26.8 121.33,26.57 120.38,25.63 120.38,24.89 118.33,22.84 118.33,21.99 118.43,21.89 118.53,21.89 v2(118.84,22.2) 119.16,21.88 119.35,21.88 119.64,21.59 119.64,19.18 120.28,18.55 120.28,17.02 121.3,16 121.3,14.86 122.06,14.1 128.28,14.1 128.79,14.61 128.79,16.13 129.26,16.6 129.34,16.6 129.43,16.64 129.48,16.77 CN23.9
LAN_REGOUT: length 10.4
  BOTTOM w0.203: 125.42,33.34 125.3,33.21 U24.36
  BOTTOM w0.508: 125.42,33.34 127.01,34.92 v1(127.01,35.43) 127.46,35.43 127.84,35.81 131.2,35.81 132.19,36.8 L66.1
LAN_SMBALERT: length 4.5
  BOTTOM w0.102: R721.2 128.74,34.5 v1(127.96,33.72) 127.01,33.72 126.38,33.08 126.38,32.38 126.15,32.16 U24.38
LAN_VDD10: length 14.8
  TOP w0.381: v2(121.8,35.24) 121.8,35.37 C278.1 ; v2(119.33,27.5) C307.1
  BOTTOM w0.178: U24.45 126.86,29.36 v2(127.2,29.02) ; U24.6 123,25.6 v2(123.07,25.53) ; U24.3 124.2,26.05 124.6,25.65 v2(124.6,25.27) ; U24.9 121.8,26.16 v2(121.3,25.65) ; v2(121.8,35.24) 121.8,34.92 122.2,34.53 U24.29 ; U24.13 119.55,28.16 119.33,27.94 ; v2(126.82,31.18) 126.6,30.96 U24.41
  BOTTOM w0.381: 119.33,27.94 v2(119.33,27.5)
  vias: v1(134.31,35.75) v1(134.57,40.45) v2(134.31,34.86) v2(134.31,34.04) v2(135.2,34.86) v2(135.2,34.04)
LAN_XTAL1: length 7.7
  BOTTOM w0.102: U24.43 127.59,30.16 v1(127.9,29.84) 128.2,29.84 C525.2 131.09,30.3 131.56,30.78 Y5.1
LAN_XTAL2: length 10.9
  BOTTOM w0.102: U24.44 127.16,29.76 127.75,29.17 v1(127.75,27.86) 128.51,28.62 C530.2 130.9,28.62 131.56,27.96 Y5.2
LCDVCC:
  vias: v1(23.19,181.48) v1(25.66,182.12) v2(11.71,183.1) v2(11.71,182.27) v2(12.53,183.1) v2(12.53,182.27) v2(24.01,182.25) v2(24.08,181.42) v2(24.78,182.31) v2(24.78,181.42) v2(27.64,190.97) v2(27.65,190.18) v2(28.33,191.49) v2(28.42,190.61)
LCDVCC_1:
  vias: v1(13.85,187.71)
LCDVCC_DISCHARGHE: length 4
  TOP w0.102: v1(13.92,190.69) 13.38,191.22 Q4.D
  TOP w0.762: R109.2 11.95,190.06 12.2,190.31 Q4.D
LCDVCC_MXM: length 1.7
  TOP w0.254: C53.1 32,202.55 v1(32.52,203.07)
  vias: v1(27.89,200.91)
LCDVCC_NB:
  vias: v1(65.8,194.18) v1(67.89,194.31)
LDT_RST_D_N: length 34
  TOP w0.102: D9.A 134,92.88 134.37,92.5 R244.2 134,91.62 134,80.14 133.46,79.6 v1(128.31,79.6) Q17.D 120.64,79.6 119.69,78.66 R269.1 J3.24
LDT_RST_N: length 286.6
  TOP w0.102: v2(118.5,80.58) 118.5,78.31 R269.2 119.01,77.03 119.52,76.52 121.93,76.52 122.25,76.83 Q17.S ; v3(91.74,72.24) 91.21,72.77 U10.J24 ; Q7.S 43.32,171.07 43.38,171.01 51.13,171.01 v2(51.32,170.81) ; v2(109.94,174.8) 109,173.86 97.48,173.86 94.32,170.7 94.32,167.41 92.34,165.43 81.34,165.43 80.27,166.5 80.27,175.2 72.36,183.11 62.73,183.11 61.93,182.31 v2(58.68,182.31) ; v3(84.66,89.84) 85.16,90.35 89.22,90.35 89.37,90.2 96.48,90.2 97.14,90.86 101.5,90.86 103.43,88.93 109.64,88.93 v2(110.15,88.42) ; v3(108.94,169.22) 109.57,168.59 U6.C7 ; v2(51.19,173.02) R123.1
  BOTTOM w0.102: v3(84.66,89.84) 84.54,89.84 82.59,87.88 82.38,87.88 81.67,87.17 81.67,85.53 82.94,84.26 82.94,82.3 85,80.24 86.56,80.24 88.76,78.04 88.76,77.24 89.55,76.45 89.55,74.57 89.34,74.37 89.34,73.81 89.6,73.56 89.9,73.56 90.51,72.95 91.03,72.95 v3(91.74,72.24) ; v1(110.17,175.74) 110.17,175.03 v2(109.94,174.8) 108.95,173.81 108.95,172.43 109.35,172.03 109.35,169.71 108.94,169.3 v3(108.94,169.22) 108.94,168.64 109.46,168.13 109.46,167.59 109.36,167.49 109.36,166.6 109.15,166.4 108.44,166.4 108.09,166.04 108.09,163.37 108.91,162.56 108.91,136.66 105.92,133.67 105.92,131.56 103.26,128.91 101.36,128.91 99.07,126.62 99.07,126.62 R575.2 C425.1 98.92,122.3 101.48,122.3 102.63,121.16 102.63,119.82 103.82,118.63 103.82,115.14 104.89,114.07 106.39,114.07 109.61,110.85 109.61,110.54 111.09,109.07 111.97,109.07 116.09,104.95 116.09,102.82 118.07,100.84 118.07,92.33 114.26,88.52 110.25,88.52 v2(110.15,88.42) 109.23,87.5 109.23,86.69 109.69,86.23 110.63,86.23 112.79,84.07 112.79,80.64 113.14,80.3 114.91,80.3 115.2,80.58 v2(118.5,80.58) ; v2(51.32,170.81) 51.19,170.94 v2(51.19,173.02) 51.19,175.13 53.6,177.55 55.89,177.55 58.18,179.83 58.18,181.8 v2(58.68,182.31)
LDT_STOP_N: length 246.3
  TOP w0.102: v3(110.2,167.96) 110.84,167.32 U6.D8 ; U2.2 v2(51.32,179.39) ; v2(77.73,85.6) 77.73,87.12 79.82,89.2 81.54,89.2 82.28,89.94 83.12,89.94 83.73,89.33 85.15,89.33 85.76,89.94 89.01,89.94 89.16,89.79 96.66,89.79 97.32,90.45 101.33,90.45 103.26,88.52 109.13,88.52 110.04,87.6 v2(110.35,87.6) ; v2(80.73,82.7) 80.07,82.04 80.07,80.64 83.59,77.11 83.6,77.11 84.06,76.66 84.44,76.66 84.85,76.25 84.85,75.93 85.09,75.69 85.38,75.69 85.81,75.26 86.4,75.26 86.75,74.9 86.98,74.9 87.18,74.7 87.18,74.35 87.39,74.14 87.39,73.49 87.65,73.23 87.82,73.23 88.07,72.97 88.07,72.77 88.43,72.42 88.61,72.42 88.89,72.14 88.89,71.83 89.34,71.38 U10.G22 ; v2(109.99,173.99) 109.46,173.46 97.65,173.46 94.75,170.56 94.75,167.23 92.54,165.02 81.11,165.02 79.87,166.27 79.87,174.78 71.96,182.69 62.89,182.69 60.66,180.47 v2(56.02,180.47)
  BOTTOM w0.102: v2(110.35,87.6) 110.75,87.6 111.16,88.01 114.41,88.01 118.48,92.08 118.48,104.06 114.97,107.57 114.36,107.57 112.43,109.5 111.24,109.5 110.02,110.72 110.02,111.05 106.59,114.48 105.12,114.48 104.23,115.37 104.23,118.86 103.07,120.02 103.07,122.11 102.37,122.81 C429.1 R577.2 100.77,126.85 102.32,128.4 103.39,128.4 107.66,132.66 107.66,134.82 109.31,136.48 109.31,162.79 108.49,163.61 108.49,165.74 108.7,165.94 109.41,165.94 109.76,166.29 109.76,167.08 110.2,167.52 v3(110.2,167.96) 109.84,168.32 109.84,172.62 v1(109.55,172.91) 109.55,173.55 v2(109.99,173.99) ; v2(77.73,85.6) 77.86,85.6 80.73,82.73 v2(80.73,82.7) ; v2(51.32,179.39) 51.51,179.58 55.13,179.58 v2(56.02,180.47)
LED_AMBER_EN: length 45.2
  TOP w0.102: R410.1 64.19,38.64 62.64,40.2 62.64,45.74 v3(63.26,46.35) ; v4(87.22,58.1) 87.22,58.14 U10.D5
  INT1 w0.089: v2(77.67,47.12) 77.67,45.78 77.04,45.15 73.54,45.15 73.23,45.47 72.53,45.47 72.27,45.21 69.16,45.21 67.48,46.89 63.8,46.89 v3(63.26,46.35)
  BOTTOM w0.125: v4(87.22,58.1) 86.67,58.1 86.07,57.5 86.07,56.98 84.97,55.88 84.97,55.37 83.39,53.78 83.39,48.32 82.31,47.24 v1(78.43,47.24) 77.8,47.24 v2(77.67,47.12)
LED_SATA_N: length 170.6
  TOP w0.102: v2(112.4,56.15) 112.98,56.15 113.17,55.96 113.17,54.99 113.4,54.76 113.4,49.96 114.64,48.72 114.64,41.12 113.52,40 113.52,30.32 113.24,30.04 101.2,30.04 96.51,25.35 95.59,25.35 94.75,26.19 94.14,26.19 93.67,25.72 v2(93.67,25.65) ; v3(104.28,64.99) 103.78,64.49 103.54,64.49 103.06,64.01 102.75,64.01 102.6,63.86 102.6,63.58 102.27,63.24 U10.AD11 ; v2(50.43,25.27) 49.54,26.16 49.16,26.16 48.86,26.46 47.77,26.46 46.94,27.29 44.27,27.29 42.4,29.16 35.82,29.16 34.69,30.29 28.08,30.29 27.82,30.54 24.54,30.54 23.08,29.08 21.86,29.08 19.8,27.03 16.04,27.03 15.5,27.56 14.36,27.56 13.85,27.05 13.85,25.02 13.6,24.77 12.96,24.77 12.84,24.89 9.79,24.89 9.15,24.26 7.57,24.26 7.12,24.7 7.12,26.96 LED3.C
  BOTTOM w0.102: v3(104.28,64.99) 104.39,64.88 105.71,64.88 106.26,65.43 108.06,65.43 108.21,65.28 110.06,65.28 110.95,64.39 110.95,61.72 112.4,60.27 v2(112.4,56.15) ; v2(50.43,25.27) 50.56,25.4 52.21,25.4 53.17,24.43 53.55,24.43 55.04,22.95 56.57,22.95 56.94,22.58 61.81,22.58 62.56,21.83 90.82,21.83 92.23,23.24 v1(92.97,23.24) 93.67,23.94 v2(93.67,25.65)
LINE_L: length 102.8
  TOP w0.254: v2(26.45,28.48) 26.55,28.57 33.84,28.57 35.09,27.33 41.67,27.33 43.5,25.5 45.88,25.5 v2(46.19,25.2)
  BOTTOM w0.254: v2(26.45,28.48) 26.45,28.49 25.79,29.15 25.79,39.03 26.11,39.34 26.11,42.4 23.54,44.97 U23.23 ; v2(46.19,25.2) 47.53,25.2 50.38,22.35 50.81,22.35 51.9,21.26 55.89,21.26 57.02,20.13 95.32,20.13 100.41,15.05 C546.1 100.41,11.24 v1(100.66,10.99)
LINE_L_FIL: length 18.1
  BOTTOM w0.254: v1(108.09,12.06) 107.83,12.32 C553.1 106.92,12.33 L80.2 106.95,13.35 D16.2 110.53,12.48 109.99,11.94 v1(109.99,11.18) 109.99,9.78 109.23,9.02 106.18,9.02 103.84,6.67 CN22.3
LINE_R: length 100.7
  TOP w0.254: v2(25.66,28.01) 25.66,28.83 26.05,29.21 27.06,29.21 27.19,29.08 34.07,29.08 35.32,27.84 41.92,27.84 43.75,26.01 46.29,26.01 47.13,25.17 v2(48.37,25.17)
  BOTTOM w0.254: v2(48.37,25.17) 50.68,22.86 51.57,22.86 v1(52.08,22.35) 52.65,21.78 56.08,21.78 57.23,20.64 95.85,20.64 99.47,17.02 C538.1 ; v2(25.66,28.01) 25.6,28.01 25.28,28.29 25.28,39.24 25.6,39.55 25.6,42.19 22.95,44.84 22.95,45.42 23.04,45.51 U23.24
LINE_R_FIL: length 15.9
  BOTTOM w0.254: C537.1 106.94,15.84 106.92,15.81 L74.2 ; v1(106.88,14.29) 106.92,14.32 L74.2 ; CN22.6 110.88,6.69 110.88,11.81 111.77,12.7 v1(111.77,14.03) 111.77,14.86 111.38,15.25 D16.1 108.61,15.25 108.57,15.21 L74.2
LINE_SENSE: length 118.5
  TOP w0.254: v2(45.2,24.79) 45.07,24.92 43.24,24.92 41.34,26.82 34.86,26.82 33.68,28 27.38,28 v2(26.81,27.43)
  BOTTOM w0.254: R701.2 27.47,42.9 27.47,38.44 26.3,37.27 26.3,29.78 27.06,29.02 27.06,27.69 v2(26.81,27.43) ; v2(45.2,24.79) 45.43,24.56 47.33,24.56 v1(50.18,21.72) 51.19,20.7 55.73,20.7 56.8,19.62 94.82,19.62 99.2,15.24 99.2,14.23 v1(99.2,14.22) 99.2,14.22 99.2,10.67 100.72,9.15 100.72,3.81 101.48,3.05 102.25,3.05 104.28,5.08 108.98,5.08 109.4,4.66 CN22.5
LPC_CLK0: length 5.1
  BOTTOM w0.102: v1(86.94,86.61) 86.13,85.8 R630.1 R612.2 84.59,84.71 84.72,84.58 R636.2
LPC_CLK1: length 3.5
  BOTTOM w0.102: R613.2 83.32,85.68 R631.1 v1(83.45,84.58) R637.2
LPC_LFRAME_N: length 125.9
  TOP w0.102: U10.G28 89.24,76.45 89.57,76.78 89.57,78.34 88.03,79.88 86.17,79.88 82.61,83.44 75.7,83.44 75.19,82.93 75.19,81.47 73.89,80.16 72.36,80.16 71.09,78.89 v2(69.91,78.89) ; R368.1 R369.1 45.98,46.69 45.4,47.27 45.4,48.44 46.35,49.39 51.49,49.39 55.56,53.46 55.56,59.47 57.57,61.48 57.57,66.8 56.98,67.39 56.98,73.23 57.57,73.81 57.57,74.4 58.85,75.68 58.85,76.7 v2(58.51,77.04) 58.17,77.38 58.17,77.54 57.94,77.77 57.1,77.77 52.36,73.03 52.36,71.89 51.31,70.84 39.1,70.84 38.87,70.61 v2(37.67,70.61)
  BOTTOM w0.102: v2(37.67,70.61) 38.3,70.61 38.93,71.24 38.93,73.58 35.03,77.47 34.3,77.47 34.12,77.65 34.12,82.35 32.74,83.73 32.74,86.99 R638.2 ; v2(69.91,78.89) 69.39,79.42 66.5,79.42 64.12,77.04 v1(62.39,77.04) v2(58.51,77.04)
LPC_LFRAME_R_N: length 4.2
  TOP w0.102: CN2.16 32.28,86.79 32.97,86.11 v2(33.22,86.11)
  BOTTOM w0.102: R638.1 32.92,87.87 33.54,87.25 v1(33.54,86.87) 33.54,86.42 v2(33.22,86.11)
LPC_SCI_N: length 12.4
  TOP w0.102: U10.K2 91.39,55.87 91.39,55.54 91.31,55.45 91.31,54.37 89.21,52.27 89.21,50.15 88.66,49.59 88.66,49.41 88.02,48.78 v1(88.02,47.56) 87.64,47.18 87.64,46.42 R423.1
LPC_SMI_N: length 8.9
  TOP w0.102: R265.1 85.35,82.61 v1(86.05,81.92) 86.05,81.72 86.88,80.9 88.45,80.9 90.84,78.51 U10.J29
LVDDPWR_EN: length 266.4
  TOP w0.102: Q18.S 156.75,72.2 156.35,71.8 R302.1 R277.2 156.73,74.88 156.73,75.44 156.98,75.69 158,75.69 158.25,75.95 v2(158.25,80.07) 158.25,80.64 143.85,95.05 121.42,95.05 120.43,94.06 105.42,94.06 103.34,96.14 88.91,96.14 86.52,98.53 71.99,98.53 70.24,96.77 v3(69.45,96.77) ; v2(43.89,114.55) 45.35,114.55 46.66,113.25 46.66,105.45 54.68,97.42 v2(54.68,97.35) ; Q3.G 11.53,198.79 14.49,195.83 14.49,182.35 13.22,181.09 9.43,181.09 7.9,179.56 7.9,178.53 12.4,174.03 12.4,161.33 13.63,160.1 16.7,160.1 18.2,158.6 19.82,158.6 20.56,157.86 v2(20.56,157.73)
  BOTTOM w0.102: v2(158.25,80.07) R644.1 ; v2(54.68,97.35) 57.16,97.35 58.18,98.36 64.78,98.36 66.11,97.03 68.34,97.03 68.59,96.77 v3(69.45,96.77) ; v2(43.89,114.55) 42.3,116.14 v1(41.48,116.14) 41.26,116.36 34.17,116.36 20.41,130.12 20.41,136.35 19.57,137.18 19.57,144.5 20.79,145.72 20.79,155.7 20.99,155.91 20.99,157.3 v2(20.56,157.73)
LVDDPWR_R_EN: length 6.7
  TOP w0.102: D10.K v2(159.69,76.62) ; v2(160.28,72.26) 160.33,72.21 R298.1
  BOTTOM w0.102: v2(159.69,76.62) 160.35,75.96 v1(160.35,73.34) 160.35,72.33 v2(160.28,72.26)
M704_1: length 15.2
  TOP w0.102: R100.2 9.79,192.97 9.16,192.35 9.04,192.35 8.53,191.83 8.53,190.95 R107.1 ; v1(5.12,190.8) 5.56,191.1 Q5.D 7.29,191.1 7.63,190.75 R107.1 ; R107.1 8.73,190.1 8.96,189.87 9.73,189.87 9.92,189.67 C76.1 9.86,189.17 9.09,189.17 7.5,187.58 6.36,187.58 5.92,187.14 Q6.G
M_VDDIO_PWRGD: length 2.1
  TOP w0.102: v3(103.97,165.53) 104.49,165.01 U6.F3
  BOTTOM w0.102: TP126.1 103.89,165.61 v3(103.97,165.53)
MA1_CS_L0: length 1.8
  TOP w0.249: U6.AA25 v3(133.07,145.09)
  BOTTOM w0.102: TP164.1 133.66,145.73 133.07,145.14 v3(133.07,145.09)
MA1_CS_L1: length 2.3
  TOP w0.249: U6.AD27 v3(135.61,141.28)
  BOTTOM w0.102: v3(135.61,141.28) 134.75,141.28 TP173.1
MA1_ODT0: length 2
  TOP w0.249: U6.AC27 v3(135.61,142.55)
  BOTTOM w0.102: v3(135.61,142.55) 135.47,142.55 134.83,143.19 TP169.1
MA1_ODT1: length 1.8
  TOP w0.125: v3(135.62,140.01) 134.98,140.65 U6.AE27
  BOTTOM w0.102: v3(135.62,140.01) 135.63,140.01 136.28,140.65 TP175.1
MA_CLK_H0: length 2.1
  TOP w0.125: v3(126.79,164.21) 126.72,164.15 126.08,163.51 U6.G20
  BOTTOM w0.102: v3(126.79,164.21) 126.79,163.91 126.39,163.51 TP130.1
MA_CLK_H1: length 2.2
  TOP w0.125: U6.G19 124.81,163.51 125.45,164.15 v3(125.55,164.25)
  BOTTOM w0.102: v3(125.55,164.25) 125.3,164.25 124.85,163.8 TP131.1
MA_CLK_H3: length 1.9
  TOP w0.125: U6.W26 134.34,147.63 v3(134.35,147.63)
  BOTTOM w0.102: TP159.1 133.81,148.28 133.79,148.3 133.79,148.19 v3(134.35,147.63)
MA_CLK_H5: length 1.9
  TOP w0.125: v3(135.64,151.48) 134.97,150.81 U6.U27
  BOTTOM w0.102: TP154.1 135.68,151.48 v3(135.64,151.48)
MA_CLK_H6: length 1.8
  TOP w0.125: U6.AE20 v3(126.72,140.01)
  BOTTOM w0.102: v3(126.72,140.01) 126.72,139.99 TP180.1
MA_CLK_H7: length 1.6
  TOP w0.125: v3(127.81,137.52) 127.35,137.98 U6.AG21
  BOTTOM w0.102: TP185.1 127.81,137.52 v3(127.81,137.52)
MA_CLK_L0: length 1.9
  TOP w0.102: U6.G21 127.35,163.5 v3(126.75,162.9)
  BOTTOM w0.102: v3(126.75,162.9) 126.9,162.9 127.51,163.51 TP129.1
MA_CLK_L1: length 2
  TOP w0.102: U6.H19 124.81,162.25 v3(124.29,162.77)
  BOTTOM w0.102: TP132.1 123.45,163.36 124.04,162.77 v3(124.29,162.77)
MA_CLK_L3: length 1.9
  TOP w0.125: U6.W25 133.07,147.63 v3(133.1,147.63)
  BOTTOM w0.102: v3(133.1,147.63) 132.52,148.21 132.52,148.3 132.49,148.27 TP160.1
MA_CLK_L5: length 1.7
  TOP w0.125: U6.U26 133.7,150.81 v3(134.37,151.48)
  BOTTOM w0.102: v3(134.37,151.48) 134.37,150.8 TP155.1
MA_CLK_L6: length 1.8
  TOP w0.125: v3(125.44,140.01) 124.81,140.64 U6.AE19
  BOTTOM w0.102: v3(125.44,140.01) 124.88,139.45 TP179.1
MA_CLK_L7: length 1.8
  TOP w0.125: v3(126.7,137.53) 126.7,137.63 126.22,138.11 U6.AG20
  BOTTOM w0.102: v3(126.7,137.53) 126.11,138.11 TP182.1
MB1_CS_DT0: length 17.8
  TOP w0.102: U6.AD31 140.3,141.68 140.3,141.66 141.14,140.81 144.06,140.81 144.79,141.54 148.9,141.54 151.55,138.88 155.4,138.88 TP79.1
MB1_CS_DT1: length 16.9
  TOP w0.102: U6.AG31 141.4,138.11 143.1,136.41 149.15,136.41 149.5,136.06 155.19,136.06 TP80.1
MB1_CS_L0: length 17
  TOP w0.102: U6.AB31 142.47,144.46 143.24,145.22 151.02,145.22 153.24,143 155.73,143 TP73.1
MB1_CS_L1: length 1.6
  TOP w0.102: v3(138.04,141.12) 137.57,140.65 U6.AE29
  BOTTOM w0.102: v3(138.04,141.12) 138.64,140.53 TP176.1
MB_CLK_H0: length 2.8
  TOP w0.125: U6.C19 124.81,168.6 v3(125.58,169.36)
  BOTTOM w0.102: TP114.1 126.71,170.05 126.02,169.36 v3(125.58,169.36)
MB_CLK_H1: length 2.4
  TOP w0.125: v3(124.69,172.12) 124.43,171.85 124.42,171.85 123.69,171.13 U6.A18
  BOTTOM w0.102: v3(124.69,172.12) 124.92,172.34 TP109.1
MB_CLK_H3: length 20.2
  TOP w0.102: U6.Y31 142.01,147 142.54,147.53 152.01,147.53 154,145.54 157.14,145.54 158.49,146.89 TP66.1
MB_CLK_H5: length 16.4
  TOP w0.102: U6.U31 140.83,150.81 141.4,150.24 153.59,150.24 154.24,149.58 155.4,149.58 TP60.1
MB_CLK_H6: length 16.7
  TOP w0.102: U6.AL19 124.43,133.03 124.29,132.88 124.29,132.7 124.75,132.24 124.75,126.09 130.47,120.38 TP86.1
MB_CLK_H7: length 22
  TOP w0.102: U6.AJ19 125.45,134.93 125.45,132.41 125.21,132.17 125.21,126.59 132.4,119.41 132.4,117.27 TP93.1
MB_CLK_L0: length 2
  TOP w0.125: v3(125.58,167.98) 125.5,167.98 125.45,167.93 124.83,167.32 U6.D19
  BOTTOM w0.102: TP116.1 126.24,168.59 125.64,167.99 125.59,167.99 v3(125.58,167.98)
MB_CLK_L1: length 1.6
  TOP w0.102: v3(125.43,170.72) 125.43,170.72 125.02,171.13 U6.A19
  BOTTOM w0.102: v3(125.43,170.72) 125.99,171.29 TP111.1
MB_CLK_L3: length 23.3
  TOP w0.102: U6.Y30 139.14,147 139.63,146.51 140.55,146.51 140.73,146.69 142.12,146.69 142.76,147.32 151.9,147.32 153.93,145.29 157.26,145.29 158.3,146.33 159.42,146.33 TP58.1
MB_CLK_L5: length 18.1
  TOP w0.102: U6.U30 138.78,150.74 139.2,150.33 140.42,150.33 140.78,149.97 153.34,149.97 154.05,149.26 154.92,149.26 TP62.1
MB_CLK_L6: length 15.1
  TOP w0.102: U6.AL18 123.66,133.03 124.47,132.21 124.47,125.99 129.4,121.06 TP84.1
MB_CLK_L7: length 19.5
  TOP w0.102: U6.AK19 125.25,133.87 125.25,132.51 125,132.27 125,126.39 132.09,119.3 132.09,118.59 TP89.1
MEM_MA0_CLK0_N: length 50.7
  TOP w0.13: v3(134.37,148.93) 134.68,148.93 134.97,148.63 U6.W27
  BOTTOM w0.13: v3(134.37,148.93) 134.57,148.93 134.77,148.73 134.77,148.33 135.54,147.56 136.41,147.56 136.7,147.85 136.7,148.32 136.83,148.45 137.21,148.45 137.34,148.32 137.34,147.85 137.63,147.56 138.49,147.56 138.82,147.89 139.29,147.89 139.62,147.56 143.68,147.56 147.73,143.51 163.42,143.51 163.5,143.43 163.5,142.9 163.79,142.61 164.39,142.61 164.68,142.9 164.68,143.43 164.81,143.56 165.19,143.56 165.32,143.43 165.32,142.9 165.61,142.61 166.21,142.61 166.5,142.9 166.5,143.43 166.63,143.56 167.69,143.56 169.24,142.01 170.56,142.01 171.54,143 172.39,143 173.34,143.95 174.34,143.95 174.5,144.11 J1.185
MEM_MA0_CLK0_P: length 50.6
  TOP w0.13: U6.V27 134.97,149.17 135.24,148.9 v3(135.61,148.9)
  BOTTOM w0.13: v3(135.61,148.9) 135.51,149 135.23,149 135.04,148.81 135.04,148.45 135.65,147.83 136.3,147.83 136.43,147.96 136.43,148.44 136.72,148.72 137.32,148.72 137.61,148.44 137.61,147.96 137.74,147.83 138.38,147.83 138.71,148.16 139.4,148.16 139.73,147.83 143.8,147.83 147.85,143.78 163.53,143.78 163.77,143.54 163.77,143.01 163.9,142.88 164.28,142.88 164.41,143.01 164.41,143.54 164.7,143.83 165.3,143.83 165.59,143.54 165.59,143.01 165.72,142.88 166.1,142.88 166.23,143.01 166.23,143.54 166.52,143.83 167.8,143.83 169.35,142.29 170.44,142.29 171.43,143.27 172.28,143.27 173.23,144.22 174.23,144.22 174.48,144.48 174.48,144.71 174.09,145.1 173.71,145.1 J1.184
MEM_MA0_CLK1_N: length 48.9
  TOP w0.125: v3(131.95,148.88) 131.29,149.54 U6.V24
  BOTTOM w0.13: v3(131.95,148.88) 131.95,149.33 132.1,149.48 134.64,149.48 134.75,149.37 139.75,149.37 140.12,148.99 144.14,148.99 147.65,145.48 148.29,145.48 148.42,145.35 148.42,145.24 148.71,144.95 149.31,144.95 149.6,145.24 149.6,145.35 149.73,145.48 150.11,145.48 150.24,145.35 150.24,145.24 150.53,144.95 151.13,144.95 151.42,145.24 151.42,145.35 151.55,145.48 151.93,145.48 152.06,145.35 152.06,145.24 152.34,144.95 152.95,144.95 153.24,145.24 153.24,145.35 153.37,145.48 153.74,145.48 153.87,145.35 153.87,145.24 154.16,144.95 154.77,144.95 155.06,145.24 155.06,145.35 155.18,145.48 155.56,145.48 155.69,145.35 155.69,145.24 155.98,144.95 156.59,144.95 156.87,145.24 156.87,145.35 157.15,145.63 160.96,145.63 161.15,145.44 161.15,145.18 161.49,144.84 161.99,144.84 162.33,145.17 162.33,145.4 162.41,145.48 162.84,145.48 162.97,145.35 162.97,145.21 163.31,144.86 163.8,144.86 164.15,145.21 164.15,145.35 164.28,145.48 164.66,145.48 164.79,145.35 164.79,145.24 165.07,144.95 165.68,144.95 165.97,145.24 165.97,145.35 166.1,145.48 166.47,145.48 166.6,145.35 166.6,145.24 166.89,144.95 167.5,144.95 167.79,145.24 167.79,145.35 167.92,145.48 168.93,145.48 169.47,146.02 170.24,146.02 170.35,145.91 170.59,145.67 170.59,145.37 170.33,145.11 J1.64
MEM_MA0_CLK1_P: length 49
  TOP w0.125: U6.U24 131.79,150.18 v3(131.95,150.18)
  BOTTOM w0.13: J1.63 171.43,145.72 170.92,145.72 170.65,146 170.54,146.11 170.35,146.29 169.36,146.29 168.81,145.75 167.8,145.75 167.51,145.46 167.51,145.35 167.38,145.22 167.01,145.22 166.88,145.35 166.88,145.46 166.59,145.75 165.98,145.75 165.7,145.46 165.7,145.35 165.57,145.22 165.19,145.22 165.06,145.35 165.06,145.46 164.77,145.75 164.17,145.75 163.88,145.46 163.88,145.32 163.69,145.14 163.43,145.14 163.24,145.32 163.24,145.46 162.95,145.75 162.3,145.75 162.06,145.51 162.06,145.29 161.88,145.11 161.61,145.11 161.42,145.3 161.42,145.55 161.07,145.9 157.04,145.9 156.6,145.46 156.6,145.35 156.47,145.22 156.09,145.22 155.96,145.35 155.96,145.46 155.68,145.75 155.07,145.75 154.78,145.46 154.78,145.35 154.65,145.22 154.28,145.22 154.15,145.35 154.15,145.46 153.86,145.75 153.25,145.75 152.96,145.46 152.96,145.35 152.84,145.22 152.46,145.22 152.33,145.35 152.33,145.46 152.04,145.75 151.43,145.75 151.15,145.46 151.15,145.35 151.02,145.22 150.64,145.22 150.51,145.35 150.51,145.46 150.22,145.75 149.62,145.75 149.33,145.46 149.33,145.35 149.2,145.22 148.82,145.22 148.69,145.35 148.69,145.46 148.4,145.75 147.76,145.75 144.25,149.27 140.24,149.27 139.86,149.64 134.86,149.64 134.75,149.75 132.16,149.75 131.95,149.95 v3(131.95,150.18)
MEM_MA0_CS_L0: length 49.3
  TOP w0.229: U6.AA24 v3(131.8,145.09)
  BOTTOM w0.099: v3(131.8,145.09) 132.27,145.09 132.8,144.56 134.63,144.56 134.75,144.44 139.32,144.44 139.86,143.9 ; 169.48,136.26 170.66,136.26 171.27,136.87 172.35,136.87 173.11,136.11 175.61,136.11 J1.193
  BOTTOM w0.229: 139.86,143.9 141.71,143.9 146.13,139.49 160.64,139.49 161.35,138.78 161.35,138.13 161.68,137.79 167.95,137.79 169.48,136.26
MEM_MA0_CS_L1: length 47.8
  TOP w0.229: U6.AC25 v3(133.07,142.55)
  BOTTOM w0.099: v3(133.07,142.55) 133.65,142.55 134.48,141.73 138.37,141.73 139.34,140.75
  BOTTOM w0.229: 139.34,140.75 140.25,140.75 144.37,136.62 148.54,136.62 148.9,136.27 156.3,136.27 156.53,136.04 156.53,135.76 156.3,135.53 153.83,135.53 153.6,135.3 153.6,135.02 153.83,134.79 156.95,134.79 158.32,133.42 169.59,133.42 J1.76
MEM_MA0_ODT0: length 47.7
  TOP w0.229: U6.AC28 v3(136.88,142.55)
  BOTTOM w0.099: 139.96,142.11 138.88,142.11 138.33,142.65 137.86,142.65 137.51,142.31 137.13,142.31 v3(136.88,142.55) ; J1.195 175.84,133.87 175.84,133.22 175.66,133.03 174.94,133.03 174.77,133.2 174.77,134.01 174.6,134.18 172.97,134.18 172.72,134.43 172.72,134.95 172.43,135.24 171.43,135.24 170.52,134.33 169.41,134.33 169.05,134.68 168.74,134.68
  BOTTOM w0.229: 139.96,142.11 140.08,142.23 140.7,142.23 145.17,137.75 156.85,137.75 158.84,135.76 160.22,135.76 161.44,134.54 163.38,134.54 164.36,135.52 165.11,135.52 166.09,134.54 168.6,134.54 168.74,134.68
MEM_MA0_ODT1: length 46.9
  TOP w0.229: U6.AE28 136.25,140.65 v3(136.89,140.01)
  BOTTOM w0.099: J1.77 171.61,131.91 171.08,131.91 170.6,132.38 169.4,132.38
  BOTTOM w0.229: 169.4,132.38 168.91,132.88 168.56,132.88 168.01,132.33 167.56,132.33 167.1,132.79 157.87,132.79 156.47,134.2 150.04,134.2 149.72,134.52 149.72,134.7 149.95,134.93 152.82,134.93 153.05,135.16 153.05,135.44 152.82,135.67 149.58,135.67 149.34,135.43 148.96,135.43 148.3,136.09 143.96,136.09 140.51,139.53 137.78,139.53 137.31,140.01 v3(136.89,140.01)
MEM_MA_ADD0: length 47.1
  TOP w0.229: v3(131.8,147.63) U6.W24
  BOTTOM w0.099: 169.55,140.32 170.25,140.32 171.23,141.3 172.74,141.3 172.93,141.11 J1.188 ; v3(131.8,147.63) 132.28,147.15 137.34,147.15 137.61,146.89
  BOTTOM w0.229: 169.55,140.32 167.86,142.01 163.14,142.01 162.28,142.88 151.93,142.88 151.63,142.58 151.22,142.58 150.89,142.9 150.48,142.9 150.16,142.58 149.74,142.58 149.42,142.9 149.01,142.9 148.68,142.58 148.27,142.58 147.95,142.9 147.45,142.9 143.45,146.89 137.61,146.89
MEM_MA_ADD1: length 48
  TOP w0.229: U6.T27 135.48,152.58 v3(135.67,152.58)
  BOTTOM w0.099: 136.63,151.47 135.67,152.43 v3(135.67,152.58) ; 169.37,147.86 170.57,147.86 171.06,147.37 172.54,147.37 173.28,148.11 174.07,148.11 174.99,149.02 175.81,149.02 175.96,148.87 175.96,148.45 J1.181
  BOTTOM w0.229: 136.63,151.47 138,150.1 144.57,150.1 148.31,146.36 149.05,146.36 149.33,146.64 149.79,146.64 150.07,146.36 150.52,146.36 150.81,146.64 151.26,146.64 151.54,146.36 152,146.36 152.28,146.64 152.73,146.64 153.01,146.36 153.47,146.36 153.75,146.64 154.21,146.64 154.49,146.36 154.94,146.36 155.22,146.64 155.68,146.64 155.96,146.36 156.42,146.36 156.7,146.64 161.57,146.64 161.85,146.36 162.31,146.36 162.59,146.64 163.05,146.64 163.33,146.36 167.87,146.36 169.37,147.86
MEM_MA_ADD2: length 47.2
  TOP w0.229: U6.U25 v3(133.12,151.49)
  BOTTOM w0.099: 136.71,152.2 135.88,153.02 135.44,153.02 134.63,152.2 134.26,152.2 133.92,151.87 133.55,151.49 v3(133.12,151.49) ; 169.6,148.27 171.64,148.27 J1.61
  BOTTOM w0.102: 136.71,152.18 136.71,152.2
  BOTTOM w0.229: 136.71,152.18 138.15,150.74 144.84,150.74 148.4,147.18 162.55,147.18 163.21,147.84 163.95,147.84 164.16,147.63 164.16,147.13 164.36,146.93 164.69,146.93 164.9,147.13 164.9,147.63 165.11,147.84 165.42,147.84 165.63,147.63 165.63,147.16 165.84,146.96 166.17,146.96 166.37,147.16 166.37,147.63 166.59,147.84 166.89,147.84 167.11,147.63 167.11,147.13 167.31,146.93 167.64,146.93 167.84,147.13 167.84,147.63 168.06,147.84 168.48,147.84 168.91,148.27 169.6,148.27
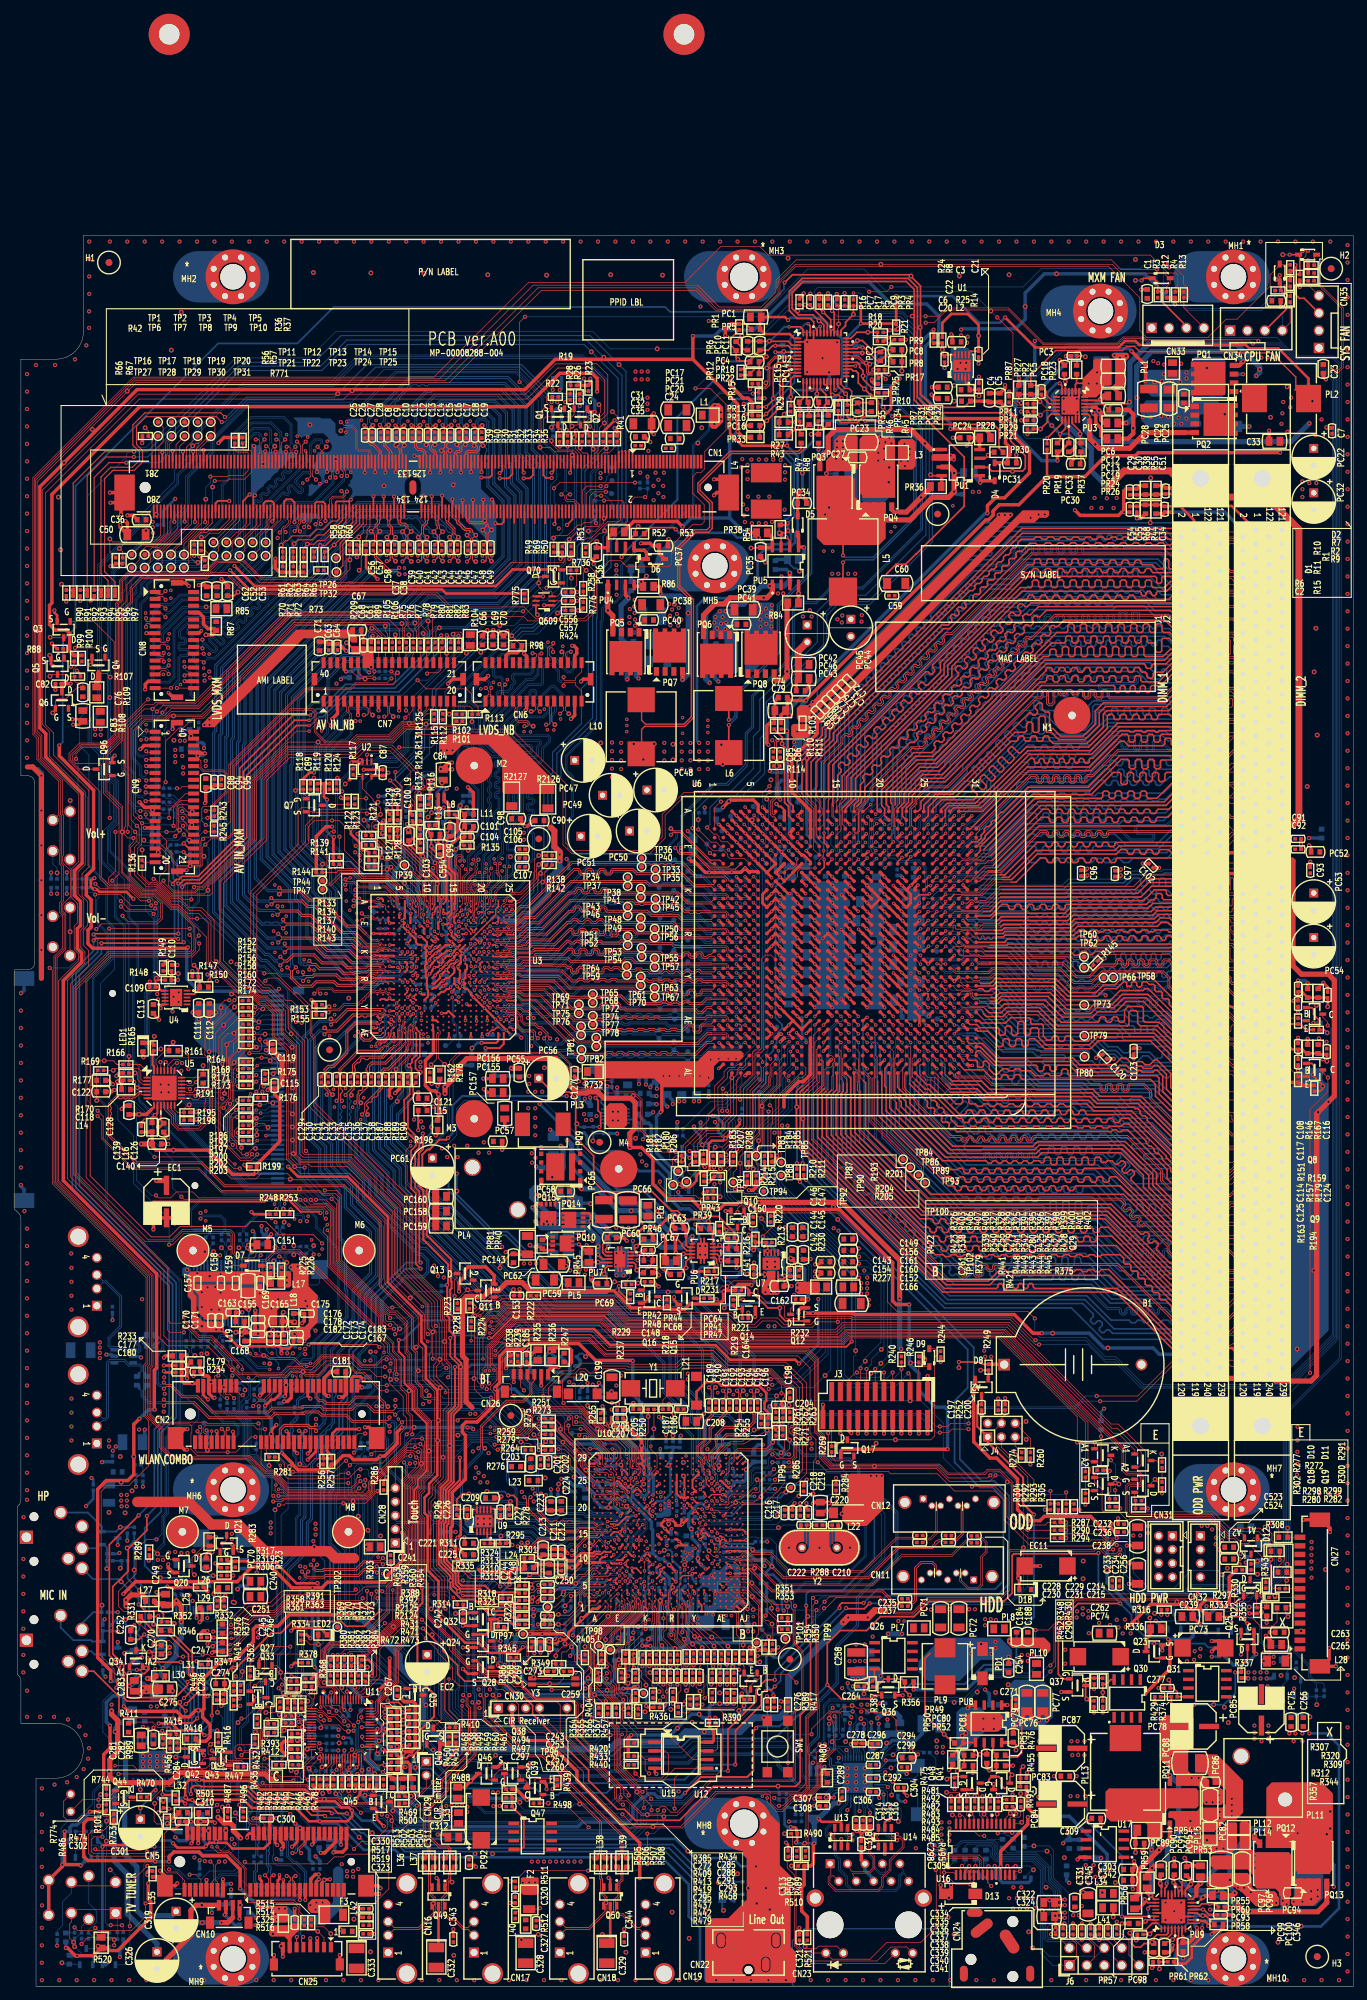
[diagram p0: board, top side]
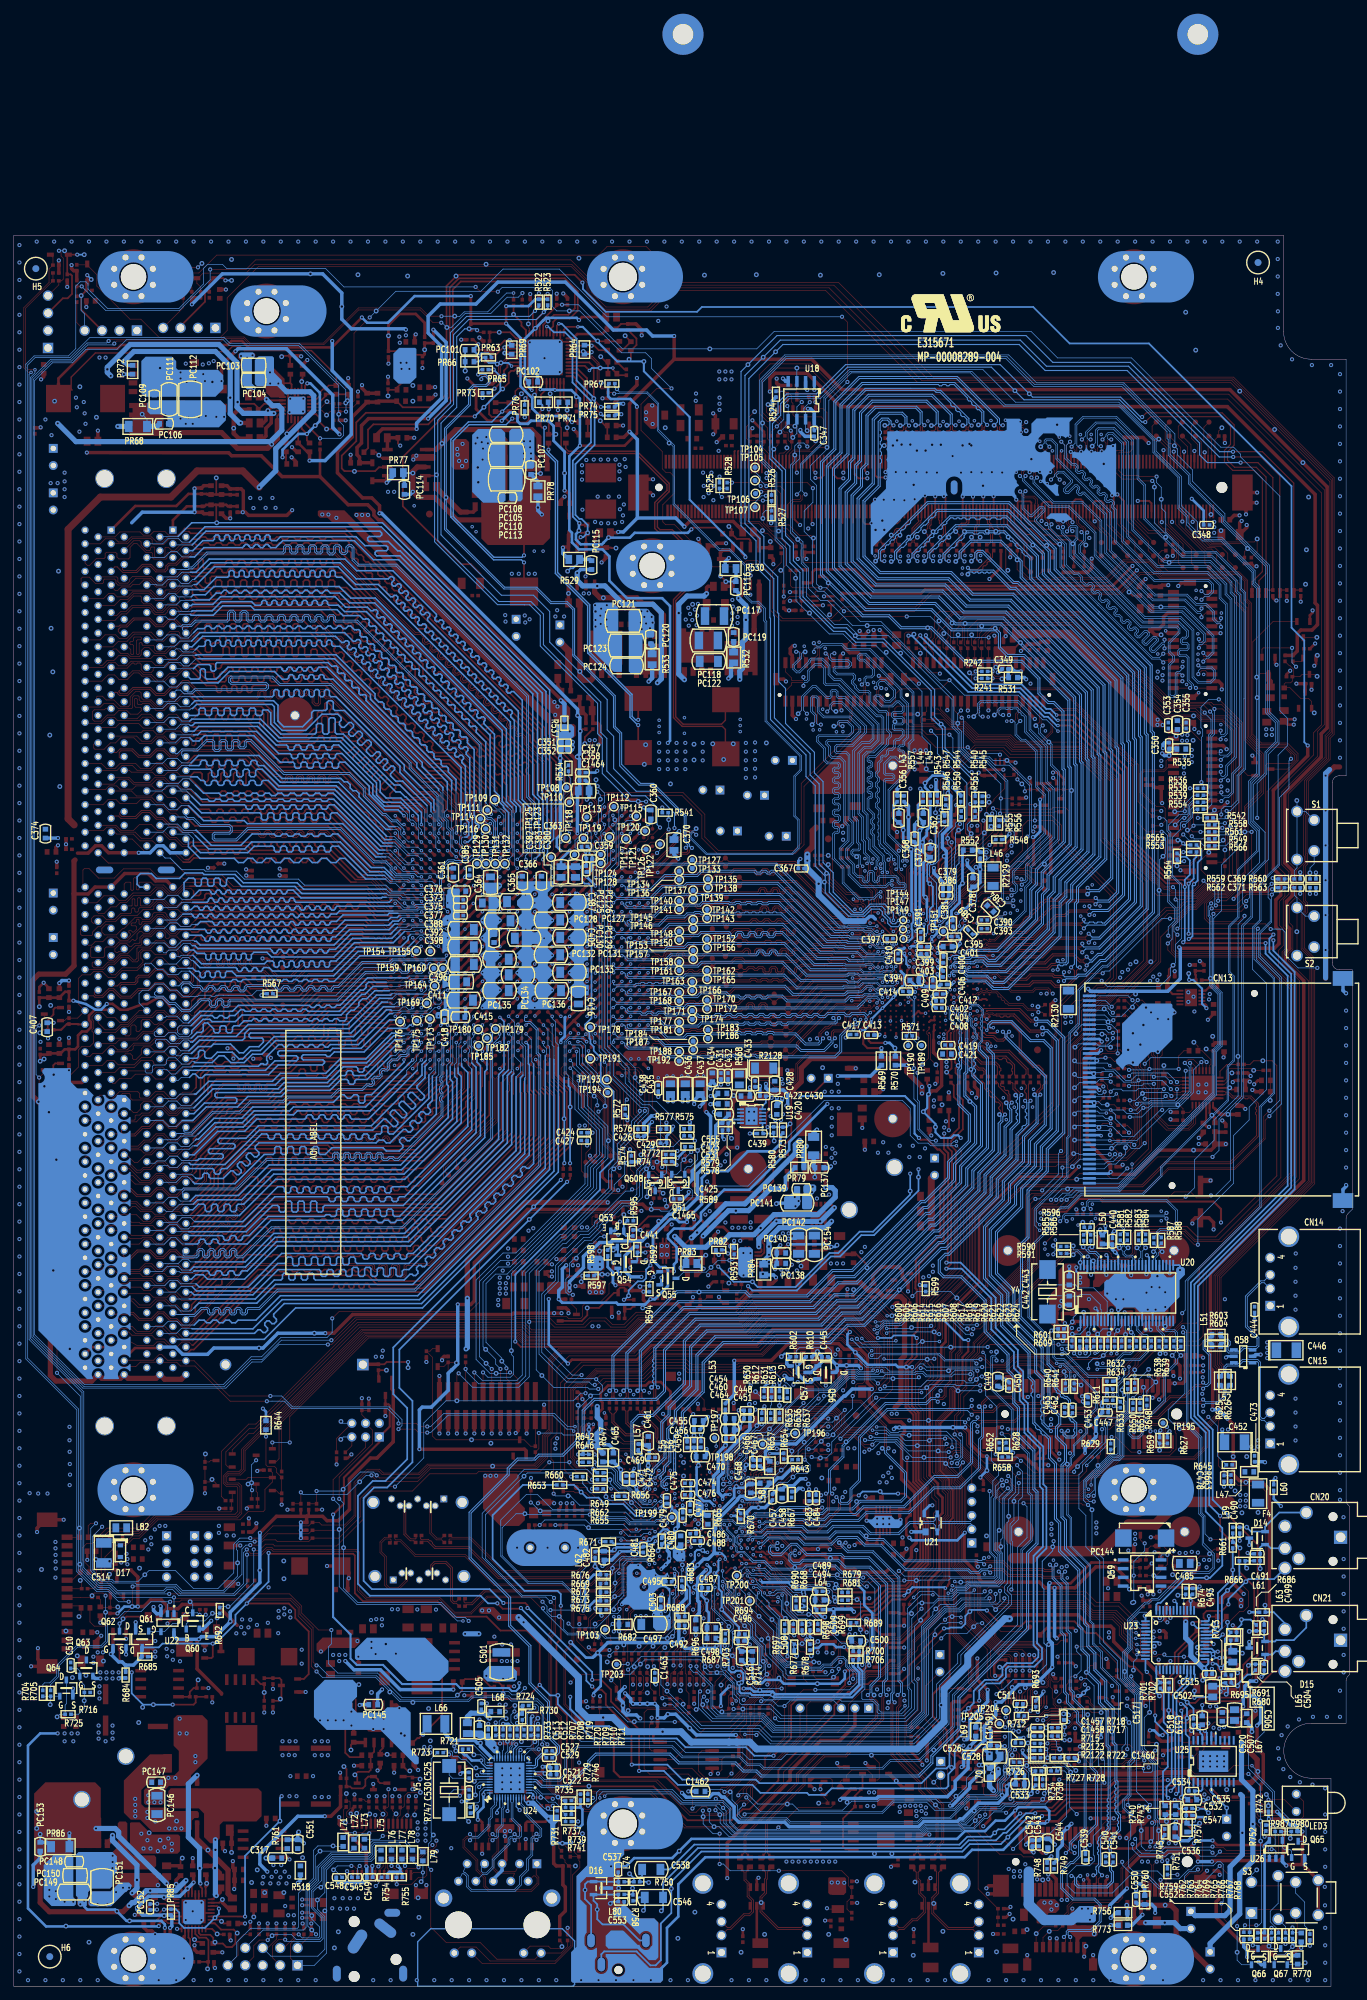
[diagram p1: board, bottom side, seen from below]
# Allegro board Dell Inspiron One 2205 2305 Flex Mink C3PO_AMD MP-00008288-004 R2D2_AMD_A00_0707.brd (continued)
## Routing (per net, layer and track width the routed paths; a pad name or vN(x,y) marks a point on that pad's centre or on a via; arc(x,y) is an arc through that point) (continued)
MEM_MA_ADD3: length 47.3
  TOP w0.229: U6.T25 133.04,152.69 v3(133.07,152.69)
  BOTTOM w0.099: J1.180 173.5,148.9 171.33,148.9 170.39,149.85 169.53,149.85 169.08,149.39 168.88,149.39 168.81,149.32 ; v3(133.07,152.69) 133.21,152.69 133.79,153.26 137.13,153.26 137.2,153.19
  BOTTOM w0.229: 137.2,153.19 137.52,152.87 137.52,152.44 138.58,151.37 145.1,151.37 148.6,147.87 157.3,147.87 157.81,148.38 158.54,148.38 158.76,148.17 158.76,148.05 158.97,147.83 159.28,147.83 159.49,148.05 159.49,148.17 159.71,148.38 160.02,148.38 160.23,148.17 160.23,148.05 160.45,147.83 160.75,147.83 160.97,148.05 160.97,148.17 161.18,148.38 161.49,148.38 161.7,148.17 161.7,148.05 161.92,147.83 162.23,147.83 162.44,148.05 162.44,148.17 162.66,148.38 167.87,148.38 168.81,149.32
MEM_MA_ADD4: length 47.2
  TOP w0.229: U6.R27 135.24,153.35 v3(135.61,153.72)
  BOTTOM w0.099: J1.59 171.68,149.98 170.8,149.98 170.61,150.18 168.88,150.18 ; v3(135.61,153.72) 136.49,153.72 136.58,153.63 138.08,153.63
  BOTTOM w0.229: 168.88,150.18 167.64,148.94 158.47,148.94 158.08,149.33 157.31,149.33 157.09,149.12 157.09,148.67 156.88,148.45 156.57,148.45 156.36,148.67 156.36,149.12 156.14,149.33 155.84,149.33 155.62,149.12 155.62,148.67 155.41,148.45 155.1,148.45 154.88,148.67 154.88,149.12 154.67,149.33 154.36,149.33 154.15,149.12 154.15,148.67 153.93,148.45 153.63,148.45 153.41,148.67 153.41,149.12 153.2,149.33 152.89,149.33 152.67,149.12 152.67,148.67 152.46,148.45 152.15,148.45 151.94,148.67 151.94,149.12 151.72,149.33 151.42,149.33 151.2,149.12 151.2,148.67 150.99,148.45 150.68,148.45 150.47,148.67 150.47,149.12 150.25,149.33 149.94,149.33 149.73,149.12 149.73,148.67 149.51,148.45 149.21,148.45 148.99,148.67 148.99,149.12 148.78,149.33 148.04,149.33 145.36,152.01 139.7,152.01 138.08,153.63
MEM_MA_ADD5: length 47.4
  TOP w0.229: v3(134.32,153.78) 133.89,153.35 U6.R26
  BOTTOM w0.099: 138.61,153.94 137.21,153.94 136.91,154.24 133.93,154.24 133.69,154 133.69,153.67 133.82,153.54 134.08,153.54 v3(134.32,153.78)
  BOTTOM w0.229: 138.61,153.94 139.91,152.64 145.63,152.64 148.34,149.93 157.43,149.93 158.11,150.6 160.02,150.6 160.38,150.24 160.38,149.74 160.6,149.52 160.9,149.52 161.12,149.74 161.12,150.24 161.34,150.46 161.64,150.46 161.86,150.24 161.86,149.74 162.07,149.52 162.38,149.52 162.59,149.74 162.59,150.24 162.81,150.46 163.11,150.46 163.33,150.24 163.33,149.74 163.55,149.52 163.85,149.52 164.07,149.74 164.07,150.24 164.28,150.46 164.59,150.46 164.8,150.24 164.8,149.74 165.02,149.52 165.32,149.52 165.54,149.74 165.54,150.24 165.76,150.46 166.06,150.46 166.28,150.24 166.28,149.74 166.49,149.52 166.8,149.52 167.01,149.74 167.01,150.24 167.23,150.46 168.3,150.46 168.78,150.94 169.74,150.94 J1.58
MEM_MA_ADD6: length 47.8
  TOP w0.229: v3(133.07,153.98) U6.R25
  BOTTOM w0.099: v3(133.07,153.98) 133.55,154.47 137.52,154.47 137.73,154.26 139.1,154.26 ; J1.178 173.13,150.53 172.81,150.53 172.4,150.94 171.25,150.94 170.29,151.9 169.32,151.9 168.99,151.57
  BOTTOM w0.229: 168.99,151.57 168.6,151.57 168.16,151.14 157.65,151.14 157.33,150.82 157.33,150.71 157.11,150.49 156.8,150.49 156.59,150.71 156.59,150.82 156.37,151.03 156.07,151.03 155.85,150.82 155.85,150.71 155.64,150.49 155.33,150.49 155.12,150.71 155.12,150.82 154.9,151.03 154.6,151.03 154.38,150.82 154.38,150.71 154.16,150.49 153.86,150.49 153.64,150.71 153.64,150.82 153.43,151.03 153.12,151.03 152.91,150.82 152.91,150.71 152.69,150.49 152.39,150.49 152.17,150.71 152.17,150.82 151.95,151.03 151.65,151.03 151.43,150.82 151.43,150.71 151.22,150.49 150.91,150.49 150.7,150.71 150.7,150.82 150.48,151.03 150.18,151.03 149.96,150.82 149.96,150.71 149.74,150.49 149.44,150.49 149.22,150.71 149.22,150.82 149.01,151.03 148.13,151.03 145.89,153.28 140.08,153.28 139.1,154.26
MEM_MA_ADD7: length 46.9
  TOP w0.229: v3(135.68,155.22) 135.08,154.62 U6.P27
  BOTTOM w0.099: v3(135.68,155.22) 136.15,155.69 138.44,155.69 138.57,155.55
  BOTTOM w0.229: J1.56 167.64,153.1 167.18,152.64 167.18,152.42 166.96,152.2 166.65,152.2 166.44,152.42 166.44,152.64 166.22,152.85 165.92,152.85 165.7,152.64 165.7,152.42 165.49,152.2 165.18,152.2 164.97,152.42 164.97,152.64 164.75,152.85 164.44,152.85 164.23,152.64 164.23,152.42 164.01,152.2 163.71,152.2 163.49,152.42 163.49,152.64 163.28,152.85 162.97,152.85 162.76,152.64 162.76,152.42 162.54,152.2 162.24,152.2 162.02,152.42 162.02,152.64 161.8,152.85 161.5,152.85 161.28,152.64 161.28,152.42 161.07,152.2 160.76,152.2 160.55,152.42 160.55,152.64 160.33,152.85 160.03,152.85 159.81,152.64 159.81,152.42 159.59,152.2 159.29,152.2 159.07,152.42 159.07,152.64 158.86,152.85 158.55,152.85 158.34,152.64 158.34,152.42 158.12,152.2 157.82,152.2 157.6,152.42 157.6,152.64 157.38,152.85 157.08,152.85 156.86,152.64 156.86,152.42 156.65,152.2 156.34,152.2 156.13,152.42 156.13,152.64 155.91,152.85 155.61,152.85 155.39,152.64 155.39,152.42 155.17,152.2 154.87,152.2 154.65,152.42 154.65,152.64 154.44,152.85 154.13,152.85 153.92,152.64 153.92,152.42 153.7,152.2 153.4,152.2 153.18,152.42 153.18,152.64 152.96,152.85 152.66,152.85 152.44,152.64 152.44,152.42 152.23,152.2 151.92,152.2 151.71,152.42 151.71,152.64 151.49,152.85 151.19,152.85 150.97,152.64 150.97,152.42 150.75,152.2 150.45,152.2 150.23,152.42 150.23,152.64 150.02,152.85 149.71,152.85 149.5,152.64 149.5,152.42 149.28,152.2 148.98,152.2 148.76,152.42 148.76,152.64 148.55,152.85 148.11,152.85 146.42,154.55 140.39,154.55 139.78,155.15 138.97,155.15 138.57,155.55
MEM_MA_ADD8: length 47.3
  TOP w0.229: v3(131.95,154.03) U6.R24
  BOTTOM w0.099: 139.1,154.72 133.05,154.72 132.35,154.03 v3(131.95,154.03) ; J1.177 175.46,151.96 173.01,151.96 172.34,151.29 171.51,151.29 170.5,152.3 168.74,152.3
  BOTTOM w0.102: 168.74,152.3 168.64,152.21
  BOTTOM w0.229: 168.64,152.21 168.39,152.21 167.85,151.67 148.32,151.67 146.08,153.91 140.31,153.91 139.5,154.72 139.1,154.72
MEM_MA_ADD9: length 49.3
  TOP w0.229: v3(135.56,156.48) 134.98,155.89 U6.N27
  BOTTOM w0.099: v3(135.56,156.48) 135.74,156.3 139.03,156.3 ; 168.51,154.65 169.04,154.65 169.3,154.39 170.72,154.39 171.23,154.9 172.24,154.9 173.04,154.1 175.61,154.1 J1.175
  BOTTOM w0.229: 168.51,154.65 168.22,154.65 167.77,155.09 166.1,155.09 165.88,154.88 165.88,154.76 165.67,154.55 165.36,154.55 165.15,154.76 165.15,154.88 164.93,155.09 164.63,155.09 164.41,154.88 164.41,154.76 164.19,154.55 163.89,154.55 163.67,154.76 163.67,154.88 163.46,155.09 163.15,155.09 162.94,154.88 162.94,154.76 162.72,154.55 162.42,154.55 162.2,154.76 162.2,154.88 161.98,155.09 161.68,155.09 161.46,154.88 161.46,154.76 161.25,154.55 160.94,154.55 160.73,154.76 160.73,154.88 160.51,155.09 160.21,155.09 159.99,154.88 159.99,154.76 159.77,154.55 159.47,154.55 159.25,154.76 159.25,154.88 159.04,155.09 158.73,155.09 158.52,154.88 158.52,154.76 158.3,154.55 158,154.55 157.78,154.76 157.78,154.88 157.56,155.09 157.26,155.09 157.04,154.88 157.04,154.76 156.83,154.55 156.52,154.55 156.31,154.76 156.31,154.88 156.09,155.09 155.79,155.09 155.57,154.88 155.57,154.76 155.35,154.55 155.05,154.55 154.83,154.76 154.83,154.88 154.62,155.09 154.31,155.09 154.1,154.88 154.1,154.76 153.88,154.55 153.58,154.55 153.36,154.76 153.36,154.88 153.14,155.09 152.84,155.09 152.62,154.88 152.62,154.76 152.41,154.55 152.1,154.55 151.89,154.76 151.89,154.88 151.67,155.09 151.37,155.09 151.15,154.88 151.15,154.76 150.94,154.55 150.63,154.55 150.41,154.76 150.41,154.88 150.2,155.09 149.89,155.09 149.68,154.88 149.68,154.76 149.46,154.55 149.16,154.55 148.94,154.76 148.94,154.88 148.73,155.09 147.99,155.09 147.04,156.04 140.54,156.04 140.29,156.3 139.03,156.3
MEM_MA_ADD10: length 47
  TOP w0.229: v3(133.07,146.36) U6.Y25
  BOTTOM w0.099: 140.74,146.26 137.63,146.26 137.09,146.8 133.33,146.8 133.07,146.54 v3(133.07,146.36) ; 169.19,139.9 170.85,139.9 171.16,139.6 171.16,138.96 170.88,138.68 170.33,138.68 J1.70
  BOTTOM w0.229: 169.19,139.9 167.7,141.39 166.09,141.39 165.74,141.05 165.35,141.05 165,141.39 164.61,141.39 164.27,141.05 163.88,141.05 163.53,141.39 162.79,141.39 161.93,142.25 161.52,142.25 161.28,142.01 160.55,142.01 160.24,142.32 159.81,142.32 159.5,142.01 159.07,142.01 158.76,142.32 158.34,142.32 158.03,142.01 157.6,142.01 157.29,142.32 156.86,142.32 156.55,142.01 156.13,142.01 155.82,142.32 155.39,142.32 155.08,142.01 154.65,142.01 154.34,142.32 153.92,142.32 153.61,142.01 153.18,142.01 152.87,142.32 152.44,142.32 152.13,142.01 147.55,142.01 144.48,145.08 144.07,145.08 143.67,145.49 143.67,145.9 143.3,146.26 140.74,146.26
MEM_MA_ADD11: length 48.9
  TOP w0.229: v3(133.07,155.25) U6.P25
  BOTTOM w0.099: 138.87,155.93 134.35,155.93 133.67,155.25 v3(133.07,155.25)
  BOTTOM w0.229: 138.87,155.93 139.12,155.68 140.07,155.68 140.45,155.3 146.73,155.3 148.07,153.96 148.32,153.96 148.54,153.74 148.54,153.61 148.75,153.4 149.06,153.4 149.27,153.61 149.27,153.74 149.49,153.96 149.79,153.96 150.01,153.74 150.01,153.61 150.23,153.4 150.53,153.4 150.75,153.61 150.75,153.74 150.96,153.96 151.27,153.96 151.48,153.74 151.48,153.61 151.7,153.4 152,153.4 152.22,153.61 152.22,153.74 152.44,153.96 152.74,153.96 152.96,153.74 152.96,153.61 153.17,153.4 153.48,153.4 153.69,153.61 153.69,153.74 153.91,153.96 154.21,153.96 154.43,153.74 154.43,153.61 154.65,153.4 154.95,153.4 155.17,153.61 155.17,153.74 155.38,153.96 155.69,153.96 155.9,153.74 155.9,153.61 156.12,153.4 156.42,153.4 156.64,153.61 156.64,153.74 156.86,153.96 157.16,153.96 157.38,153.74 157.38,153.61 157.59,153.4 157.9,153.4 158.11,153.61 158.11,153.74 158.33,153.96 158.63,153.96 158.85,153.74 158.85,153.61 159.07,153.4 159.37,153.4 159.59,153.61 159.59,153.74 159.8,153.96 160.11,153.96 160.32,153.74 160.32,153.61 160.54,153.4 160.84,153.4 161.06,153.61 161.06,153.74 161.28,153.96 161.58,153.96 161.8,153.74 161.8,153.61 162.01,153.4 162.32,153.4 162.53,153.61 162.53,153.74 162.75,153.96 163.05,153.96 163.27,153.74 163.27,153.61 163.48,153.4 163.79,153.4 164.01,153.61 164.01,153.74 164.22,153.96 164.53,153.96 164.74,153.74 164.74,153.61 164.96,153.4 165.26,153.4 165.48,153.61 165.48,153.74 165.69,153.96 166,153.96 166.22,153.74 166.22,153.61 166.43,153.4 166.74,153.4 166.95,153.61 166.95,153.74 167.17,153.96 171.66,153.96 J1.55
MEM_MA_ADD12: length 48.3
  TOP w0.229: v3(134.34,156.52) U6.N26
  BOTTOM w0.099: v3(134.34,156.52) 134.82,156.52 135.21,156.91 135.89,156.91 136.17,156.63 139.77,156.63 ; J1.174 173.51,155.31 171.22,155.31 170.34,156.18
  BOTTOM w0.229: 170.34,156.18 169.09,156.18 168.87,155.96 168.87,155.89 168.66,155.67 168.35,155.67 168.14,155.89 168.14,155.96 167.92,156.18 167.62,156.18 167.4,155.96 167.4,155.89 167.19,155.67 166.88,155.67 166.66,155.89 166.66,155.96 166.45,156.18 166.14,156.18 165.93,155.96 165.93,155.89 165.71,155.67 165.41,155.67 165.19,155.89 165.19,155.96 164.98,156.18 164.67,156.18 164.45,155.96 164.45,155.89 164.24,155.67 163.93,155.67 163.72,155.89 163.72,155.96 163.5,156.18 163.2,156.18 162.98,155.96 162.98,155.89 162.77,155.67 162.46,155.67 162.24,155.89 162.24,155.96 162.03,156.18 161.72,156.18 161.51,155.96 161.51,155.89 161.29,155.67 160.99,155.67 160.77,155.89 160.77,155.96 160.56,156.18 160.25,156.18 160.03,155.96 160.03,155.89 159.82,155.67 159.51,155.67 159.3,155.89 159.3,155.96 159.08,156.18 158.78,156.18 158.56,155.96 158.56,155.89 158.35,155.67 158.04,155.67 157.82,155.89 157.82,155.96 157.61,156.18 157.3,156.18 157.09,155.96 157.09,155.89 156.87,155.67 156.57,155.67 156.35,155.89 156.35,155.96 156.14,156.18 155.83,156.18 155.62,155.96 155.62,155.89 155.4,155.67 155.09,155.67 154.88,155.89 154.88,155.96 154.66,156.18 154.36,156.18 154.14,155.96 154.14,155.89 153.93,155.67 153.62,155.67 153.41,155.89 153.41,155.96 153.19,156.18 152.88,156.18 152.67,155.96 152.67,155.89 152.45,155.67 152.15,155.67 151.93,155.89 151.93,155.96 151.72,156.18 151.41,156.18 151.2,155.96 151.2,155.89 150.98,155.67 150.67,155.67 150.46,155.89 150.46,155.96 150.24,156.18 149.94,156.18 149.72,155.96 149.72,155.89 149.51,155.67 149.2,155.67 148.99,155.89 148.99,155.96 148.77,156.18 147.98,156.18 147.53,156.63 139.77,156.63
MEM_MA_ADD13: length 47.1
  TOP w0.229: v3(134.34,142.55) U6.AC26
  BOTTOM w0.099: 139.81,141.67 139.68,141.79 138.84,141.79 138.58,142.05 134.84,142.05 v3(134.34,142.55) ; 168.98,133.92 170.4,133.92 171.46,132.86 172.02,132.86 172.7,133.54 173.27,133.54 J1.196
  BOTTOM w0.229: 139.81,141.67 140.28,141.67 144.78,137.17 148.88,137.17 149.24,136.8 149.61,136.8 149.98,137.17 150.35,137.17 150.72,136.8 151.09,136.8 151.45,137.17 151.82,137.17 152.19,136.8 152.56,136.8 152.93,137.17 153.29,137.17 153.66,136.8 154.03,136.8 154.4,137.17 154.9,137.17 155.23,136.83 155.61,136.83 155.94,137.17 156.39,137.17 158.15,135.41 158.15,134.91 158.03,134.78 158.03,134.47 158.24,134.26 158.55,134.26 158.67,134.38 158.98,134.38 159.35,134.01 168.89,134.01 168.98,133.92
MEM_MA_ADD14: length 50.6
  TOP w0.229: v3(131.8,156.52) U6.N24
  BOTTOM w0.099: 139.98,158.23 139.24,158.23 138.09,157.08 136.54,157.08 136.31,157.31 ; 168.91,157.9 170.5,157.9 171.3,157.1 173.71,157.1 J1.172 ; v3(131.8,156.52) 132.23,156.96 133.71,156.96 133.99,157.24 134.79,157.24 134.86,157.31
  BOTTOM w0.102: 136.31,157.31 134.86,157.31
  BOTTOM w0.229: 139.98,158.23 140.31,157.9 153.89,157.9 154.1,158.11 154.1,158.29 154.32,158.51 154.63,158.51 154.84,158.29 154.84,158.11 155.06,157.9 155.36,157.9 155.58,158.11 155.58,158.29 155.79,158.51 156.1,158.51 156.31,158.29 156.31,158.11 156.53,157.9 156.84,157.9 157.05,158.11 157.05,158.29 157.27,158.51 157.57,158.51 157.79,158.29 157.79,158.11 158,157.9 158.31,157.9 158.52,158.11 158.52,158.29 158.74,158.51 159.05,158.51 159.26,158.29 159.26,158.11 159.48,157.9 159.78,157.9 160,158.11 160,158.29 160.21,158.51 160.52,158.51 160.73,158.29 160.73,158.11 160.95,157.9 161.26,157.9 161.47,158.11 161.47,158.29 161.69,158.51 161.99,158.51 162.21,158.29 162.21,158.11 162.42,157.9 162.73,157.9 162.94,158.11 162.94,158.29 163.16,158.51 163.47,158.51 163.68,158.29 163.68,158.11 163.9,157.9 164.2,157.9 164.42,158.11 164.42,158.29 164.63,158.51 164.94,158.51 165.15,158.29 165.15,158.11 165.37,157.9 165.67,157.9 165.89,158.11 165.89,158.29 166.11,158.51 166.41,158.51 166.63,158.29 166.63,158.11 166.84,157.9 168.91,157.9
MEM_MA_ADD15: length 47.9
  TOP w0.229: U6.M27 135.58,157.77 v3(135.58,158.01)
  BOTTOM w0.099: J1.171 175.44,158.28 173.16,158.28 172.52,158.91 171.09,158.91 170.51,158.33 169.3,158.33 169.1,158.53
  BOTTOM w0.102: 140.76,158.63 138.97,158.63 138.57,158.23 135.8,158.23 v3(135.58,158.01)
  BOTTOM w0.229: 140.76,158.63 141.31,158.63 141.42,158.52 153.15,158.52 154.29,159.66 155.03,159.66 155.24,159.45 155.24,159.32 155.46,159.1 155.76,159.1 155.98,159.32 155.98,159.45 156.2,159.66 156.5,159.66 156.72,159.45 156.72,159.32 156.93,159.1 157.24,159.1 157.45,159.32 157.45,159.45 157.67,159.66 157.97,159.66 158.19,159.45 158.19,159.32 158.4,159.1 158.71,159.1 158.93,159.32 158.93,159.45 159.14,159.66 159.45,159.66 159.66,159.45 159.66,159.32 159.88,159.1 160.18,159.1 160.4,159.32 160.4,159.45 160.61,159.66 160.92,159.66 161.14,159.45 161.14,159.32 161.35,159.1 161.66,159.1 161.87,159.32 161.87,159.45 162.09,159.66 162.39,159.66 162.61,159.45 162.61,159.32 162.82,159.1 163.13,159.1 163.35,159.32 163.35,159.45 163.56,159.66 163.87,159.66 164.08,159.45 164.08,159.32 164.3,159.1 164.6,159.1 164.82,159.32 164.82,159.45 165.03,159.66 165.34,159.66 165.56,159.45 165.56,159.32 165.77,159.1 166.08,159.1 166.29,159.32 166.29,159.45 166.51,159.66 167.96,159.66 169.1,158.53
MEM_MA_BANK0: length 46.9
  TOP w0.229: v3(135.61,145.09) U6.AA27
  BOTTOM w0.099: 140.31,145 140.22,145.09 136.48,145.09 136.15,145.41 135.93,145.41 v3(135.61,145.09) ; J1.71 169.14,138.11
  BOTTOM w0.229: 169.14,138.11 168.31,138.94 167.65,138.94 167.4,139.19 167.4,140.11 167.19,140.31 166.74,140.31 165.88,139.45 165.88,139.12 165.65,138.89 165.19,138.89 164.96,139.12 164.96,139.67 164.73,139.9 164.28,139.9 164.05,139.67 164.05,139.12 163.82,138.89 163.36,138.89 163.13,139.12 163.13,139.67 162.9,139.9 162.17,139.9 161.45,140.62 160.36,140.62 160.05,140.94 159.63,140.94 159.31,140.62 158.89,140.62 158.58,140.94 158.15,140.94 157.84,140.62 157.42,140.62 157.1,140.94 156.68,140.94 156.37,140.62 155.95,140.62 155.63,140.94 155.21,140.94 154.89,140.62 154.47,140.62 154.16,140.94 153.74,140.94 153.42,140.62 153,140.62 152.68,140.94 152.26,140.94 151.95,140.62 151.53,140.62 151.21,140.94 150.79,140.94 150.47,140.62 150.05,140.62 149.74,140.94 149.32,140.94 149,140.62 148.58,140.62 148.26,140.94 147.84,140.94 147.53,140.62 146.79,140.62 146.52,140.89 146.52,141.5 145.86,142.16 145.43,142.16 144.72,142.87 144.72,143.3 144.18,143.84 143.57,143.84 142.41,145 140.31,145
MEM_MA_BANK1: length 46.9
  TOP w0.229: v3(135.61,146.36) U6.Y27
  BOTTOM w0.099: J1.190 174.37,139.11 174.53,138.94 174.53,138.56 174.31,138.33 173.04,138.33 172.47,138.89 171.47,138.89 170.94,138.36 169.5,138.36 169.07,138.79 ; v3(135.61,146.36) 135.09,146.36 134.98,146.25 134.98,145.92 135.11,145.8 138.59,145.8 138.76,145.63 140.52,145.63
  BOTTOM w0.229: 140.52,145.63 142.68,145.63 143.84,144.48 144.31,144.48 147.31,141.47 161.74,141.47 162.7,140.52 166.1,140.52 166.43,140.84 167.42,140.84 169.07,139.19 169.07,138.79
MEM_MA_BANK2: length 47.1
  TOP w0.229: v3(133.07,156.52) U6.N25
  BOTTOM w0.099: v3(133.07,156.52) 133.68,156.52 134.12,156.96 134.9,156.96 135.06,157.11 135.98,157.11 136.24,156.86 138.31,156.86 138.77,157.31 139.71,157.31
  BOTTOM w0.229: 139.71,157.31 147.92,157.31 148.14,157.1 148.14,156.97 148.35,156.76 148.66,156.76 148.87,156.97 148.87,157.1 149.09,157.31 149.39,157.31 149.61,157.1 149.61,156.97 149.83,156.76 150.13,156.76 150.35,156.97 150.35,157.1 150.56,157.31 150.87,157.31 151.08,157.1 151.08,156.97 151.3,156.76 151.6,156.76 151.82,156.97 151.82,157.1 152.04,157.31 152.34,157.31 152.56,157.1 152.56,156.97 152.77,156.76 153.08,156.76 153.29,156.97 153.29,157.1 153.51,157.31 153.81,157.31 154.03,157.1 154.03,156.97 154.24,156.76 154.55,156.76 154.77,156.97 154.77,157.1 154.98,157.31 155.29,157.31 155.5,157.1 155.5,156.97 155.72,156.76 156.02,156.76 156.24,156.97 156.24,157.1 156.45,157.31 156.76,157.31 156.98,157.1 156.98,156.97 157.19,156.76 157.5,156.76 157.71,156.97 157.71,157.1 157.93,157.31 158.23,157.31 158.45,157.1 158.45,156.97 158.66,156.76 158.97,156.76 159.19,156.97 159.19,157.1 159.4,157.31 159.71,157.31 159.92,157.1 159.92,156.97 160.14,156.76 160.44,156.76 160.66,156.97 160.66,157.1 160.87,157.31 161.18,157.31 161.4,157.1 161.4,156.97 161.61,156.76 161.92,156.76 162.13,156.97 162.13,157.1 162.35,157.31 162.65,157.31 162.87,157.1 162.87,156.97 163.08,156.76 163.39,156.76 163.6,156.97 163.6,157.1 163.82,157.31 164.13,157.31 164.34,157.1 164.34,156.97 164.56,156.76 164.86,156.76 165.08,156.97 165.08,157.1 165.29,157.31 165.6,157.31 165.81,157.1 165.81,156.97 166.03,156.76 166.34,156.76 166.55,156.97 166.55,157.1 166.77,157.31 167.07,157.31 167.29,157.1 167.29,156.97 167.5,156.76 167.81,156.76 168.02,156.97 168.02,157.1 168.24,157.31 168.67,157.31 169.15,156.82 169.63,156.82 J1.52
MEM_MA_CAS_N: length 46.9
  TOP w0.229: v3(133.07,143.82) 133.07,144.51 132.97,144.6 132.58,144.6 U6.AB25
  BOTTOM w0.099: v3(133.07,143.82) 132.93,143.82 132.73,143.62 132.73,143.26 132.93,143.05 133.62,143.05 133.82,143.26 133.82,144.12 133.96,144.26 134.55,144.26 135.71,143.1 138.48,143.1 138.89,142.68 139.53,142.68
  BOTTOM w0.229: 139.53,142.68 141.14,142.68 145.49,138.33 157.06,138.33 159.09,136.3 160.44,136.3 161.66,135.08 162.18,135.08 163.16,136.06 165.33,136.06 166.21,135.18 166.94,135.18 167.17,135.41 167.17,136.12 167.38,136.32 167.88,136.32 168.09,136.12 168.09,135.41 168.32,135.18 169.84,135.18 J1.74
MEM_MA_CHECK0: length 46.9
  TOP w0.229: v3(135.61,162.87) U6.H27
  BOTTOM w0.099: J1.39 169.83,174.11 169.07,173.34 ; 140.14,165.49 138,163.36 136.09,163.36 v3(135.61,162.87)
  BOTTOM w0.102: 140.95,165.49 140.14,165.49
  BOTTOM w0.229: 140.95,165.49 141.72,165.49 148.31,172.09 149.05,172.09 149.28,171.86 149.28,171.68 149.51,171.45 149.96,171.45 150.19,171.68 150.19,171.86 150.42,172.09 150.88,172.09 151.11,171.86 151.11,171.68 151.34,171.45 151.79,171.45 152.02,171.68 152.02,171.86 152.25,172.09 152.71,172.09 152.94,171.86 152.94,171.68 153.17,171.45 153.62,171.45 153.85,171.68 153.85,171.86 154.08,172.09 154.54,172.09 154.77,171.86 154.77,171.68 154.99,171.45 155.45,171.45 155.68,171.68 155.68,171.86 155.91,172.09 156.37,172.09 156.59,171.86 156.59,171.68 156.82,171.45 157.28,171.45 157.51,171.68 157.51,171.86 157.74,172.09 158.19,172.09 158.42,171.86 158.42,171.68 158.65,171.45 159.11,171.45 159.34,171.68 159.34,171.86 159.57,172.09 160.02,172.09 160.25,171.86 160.25,171.68 160.48,171.45 160.94,171.45 161.17,171.68 161.17,171.86 161.39,172.09 167.81,172.09 169.07,173.34
MEM_MA_CHECK1: length 46.2
  TOP w0.229: v3(138.15,162.87) U6.H29
  BOTTOM w0.099: 141.31,164.96 140.27,164.96 138.18,162.87 v3(138.15,162.87)
  BOTTOM w0.229: 141.31,164.96 141.95,164.96 147.9,170.92 148.64,170.92 148.87,170.69 148.87,170.1 149.09,169.88 149.55,169.88 149.78,170.1 149.78,170.69 150.01,170.92 150.47,170.92 150.69,170.69 150.69,170.1 150.92,169.88 151.38,169.88 151.61,170.1 151.61,170.69 151.84,170.92 152.29,170.92 152.52,170.69 152.52,170.1 152.75,169.88 153.21,169.88 153.44,170.1 153.44,170.69 153.67,170.92 154.12,170.92 154.35,170.69 154.35,170.1 154.58,169.88 155.04,169.88 155.27,170.1 155.27,170.69 155.49,170.92 155.95,170.92 156.18,170.69 156.18,170.1 156.41,169.88 156.87,169.88 157.09,170.1 157.09,170.69 157.32,170.92 157.78,170.92 158.01,170.69 158.01,170.1 158.24,169.88 158.69,169.88 158.92,170.1 158.92,170.69 159.15,170.92 167.63,170.92 169.82,173.1 J1.40
MEM_MA_CHECK2: length 47.4
  TOP w0.229: U6.K27 134.98,159.7 135.61,160.33 v3(135.61,160.33)
  BOTTOM w0.099: 140.98,161.81 140.04,160.87 137.66,160.87 137.53,160.74 136.02,160.74 135.61,160.33 v3(135.61,160.33) ; J1.45 171.53,167.83 169.5,167.83 168.83,167.16 168.83,166.93
  BOTTOM w0.229: 140.98,161.81 143.43,161.81 147.69,166.07 148.59,166.07 148.82,165.84 148.82,165.46 149.05,165.23 149.51,165.23 149.73,165.46 149.73,165.84 149.96,166.07 150.42,166.07 150.65,165.84 150.65,165.46 150.88,165.23 151.33,165.23 151.56,165.46 151.56,165.84 151.79,166.07 152.25,166.07 152.48,165.84 152.48,165.46 152.71,165.23 153.16,165.23 153.39,165.46 153.39,165.84 153.62,166.07 154.08,166.07 154.31,165.84 154.31,165.46 154.53,165.23 154.99,165.23 155.22,165.46 155.22,165.84 155.45,166.07 155.91,166.07 156.13,165.84 156.13,165.46 156.36,165.23 156.82,165.23 157.05,165.46 157.05,165.84 157.28,166.07 159.95,166.07 160.89,165.13 167.8,165.13 168.83,166.15 168.83,166.93
MEM_MA_CHECK3: length 45.8
  TOP w0.229: v3(133.23,159.14) 133.06,158.98 131.72,158.98 U6.L24
  BOTTOM w0.099: 140.82,161.28 140.17,160.63 139.37,160.63 138.62,159.88 134.35,159.88 133.61,159.14 v3(133.23,159.14)
  BOTTOM w0.229: J1.46 169.56,166.75 169.56,165.99 167.85,164.29 162.88,164.29 162.27,163.68 161.53,163.68 160.92,164.29 160.18,164.29 159.57,163.68 158.84,163.68 158.23,164.29 157.49,164.29 156.88,163.68 156.14,163.68 155.54,164.29 154.8,164.29 154.19,163.68 153.45,163.68 152.84,164.29 152.11,164.29 151.5,163.68 150.76,163.68 150.15,164.29 149.41,164.29 148.8,163.68 148.07,163.68 147.46,164.29 146.72,164.29 143.71,161.28 140.82,161.28
MEM_MA_CHECK4: length 46.9
  TOP w0.229: v3(135.61,164.14) U6.G27
  BOTTOM w0.099: 139.83,166.53 139.48,166.53 137.67,164.73 136.2,164.73 v3(135.61,164.14) ; 168.54,174.98 169.44,175.88 170.34,175.88 171.02,175.19 173.62,175.19 J1.158
  BOTTOM w0.229: 168.54,174.98 167.35,173.79 165.11,173.79 164.75,173.43 164.19,173.43 163.83,173.79 163.28,173.79 162.92,173.43 162.37,173.43 162,173.79 161.45,173.79 161.09,173.43 160.54,173.43 160.17,173.79 159.62,173.79 159.26,173.43 158.71,173.43 158.35,173.79 157.79,173.79 157.43,173.43 156.88,173.43 156.52,173.79 155.96,173.79 155.6,173.43 155.05,173.43 154.69,173.79 154.14,173.79 153.77,173.43 153.22,173.43 152.86,173.79 152.31,173.79 151.94,173.43 151.39,173.43 151.03,173.79 150.48,173.79 150.12,173.43 149.56,173.43 149.2,173.79 148.47,173.79 141.21,166.53 139.83,166.53
MEM_MA_CHECK5: length 47.6
  TOP w0.229: v3(136.88,164.14) U6.G28
  BOTTOM w0.099: J1.159 173.41,174.11 172.68,174.84 171.16,174.84 170.7,174.37 169.14,174.37 168.54,173.78 ; 140.04,166.08 139.45,166.08 138.94,165.57 138.94,164.9 137.66,163.63 137.18,163.63 136.88,163.92 v3(136.88,164.14)
  BOTTOM w0.229: 168.54,173.78 167.66,172.9 166.76,172.9 166.48,172.62 165.85,172.62 165.57,172.9 164.93,172.9 164.65,172.62 164.02,172.62 163.74,172.9 163.1,172.9 162.82,172.62 162.19,172.62 161.91,172.9 161.28,172.9 161,172.62 160.36,172.62 160.08,172.9 159.45,172.9 159.17,172.62 158.53,172.62 158.25,172.9 157.62,172.9 157.34,172.62 156.7,172.62 156.42,172.9 155.79,172.9 155.51,172.62 154.87,172.62 154.6,172.9 153.96,172.9 153.68,172.62 153.05,172.62 152.77,172.9 152.13,172.9 151.85,172.62 151.22,172.62 150.94,172.9 150.3,172.9 150.02,172.62 149.39,172.62 149.11,172.9 148.37,172.9 141.55,166.08 140.04,166.08
MEM_MA_CHECK6: length 46.6
  TOP w0.229: v3(134.34,161.6) U6.J26
  BOTTOM w0.099: J1.164 173.53,169.29 171.13,169.29 170.21,168.37 168.54,168.37 ; 139.88,161.81 139.53,161.46 137.38,161.46 137.07,161.15 134.79,161.15 v3(134.34,161.6)
  BOTTOM w0.229: 139.88,161.81 141.03,162.95 142.9,162.95 147.79,167.84 148.52,167.84 148.85,167.51 149.44,167.51 149.77,167.84 150.35,167.84 150.68,167.51 151.27,167.51 151.6,167.84 152.18,167.84 152.51,167.51 153.1,167.51 153.43,167.84 154.01,167.84 154.34,167.51 154.93,167.51 155.26,167.84 155.84,167.84 156.17,167.51 156.75,167.51 157.08,167.84 160.26,167.84 161.91,166.19 166.21,166.19 168.4,168.37 168.54,168.37
MEM_MA_CHECK7: length 48.1
  TOP w0.229: v3(133.43,160.32) 133.05,160.32 U6.K25
  BOTTOM w0.099: v3(133.43,160.32) 134.06,160.95 137.33,160.95 137.61,161.22 139.83,161.22 ; 168.54,167.61 169.02,168.08 170.37,168.08 171.12,168.84 172.53,168.84 173.26,168.11 J1.165
  BOTTOM w0.229: 139.83,161.22 140.95,162.35 143.1,162.35 147.43,166.67 160.34,166.67 161.35,165.66 166.59,165.66 168.54,167.61
MEM_MA_CKE0: length 46.9
  TOP w0.229: U6.M25 v3(133.07,157.79)
  BOTTOM w0.102: 140.7,159.17 140.46,158.93 138.68,158.93 138.31,158.56 134,158.56 133.23,157.79 v3(133.07,157.79)
  BOTTOM w0.229: 140.7,159.17 153.01,159.17 154.04,160.2 161.77,160.2 162.98,161.41 163.78,161.41 164.01,161.18 164.01,160.48 164.23,160.25 164.69,160.25 164.92,160.48 164.92,161.18 165.15,161.41 165.61,161.41 165.83,161.18 165.83,160.48 166.06,160.25 166.52,160.25 166.75,160.48 166.75,161.18 166.98,161.41 167.43,161.41 167.66,161.18 167.66,160.48 167.89,160.25 168.35,160.25 168.58,160.48 168.58,161.18 168.81,161.41 169.54,161.41 170.19,160.76 170.19,159.39 J1.50
MEM_MA_CKE1: length 47.1
  TOP w0.229: U6.L27 134.98,158.43 135.61,159.06 v3(135.61,159.06)
  BOTTOM w0.102: 140.74,159.8 140.17,159.23 138.22,159.23 138.05,159.06 v3(135.61,159.06)
  BOTTOM w0.229: 140.74,159.8 152.79,159.8 153.71,160.73 161.55,160.73 162.76,161.94 167.28,161.94 167.5,162.16 170.06,162.16 170.85,161.37 174.23,161.37 174.94,162.08 176.54,162.08 177.02,161.59 177.02,160.5 176.63,160.11 J1.169
MEM_MA_DATA0: length 95
  TOP w0.229: v3(119.06,164.17) 119.06,164.1 U6.G14
  BOTTOM w0.099: J1.3 171.64,209.94 169,209.94
  BOTTOM w0.229: 169,209.94 167,211.95 141.66,211.95 141.4,211.69 141.4,211.41 141.63,211.18 143.22,211.18 143.44,210.95 143.44,210.67 143.22,210.44 140.42,210.44 139.06,209.08 138.71,209.08 117.99,188.36 117.99,173.74 117.3,173.04 117.3,167.65 118.39,166.56 118.39,164.84 119.06,164.17 v3(119.06,164.17)
MEM_MA_DATA1: length 95.3
  TOP w0.229: v3(117.9,167.97) 117.9,166.61 U6.E14
  BOTTOM w0.229: v3(117.9,167.97) 117.9,172.75 118.69,173.55 118.69,188.31 138.75,208.36 142.12,208.36 142.35,208.59 142.35,208.87 142.12,209.1 140.71,209.1 140.51,209.3 140.51,209.63 140.71,209.83 143.82,209.83 145.14,211.15 156.12,211.15 156.7,210.57 157.44,210.57 157.66,210.78 157.66,211.18 157.87,211.4 158.18,211.4 158.39,211.18 158.39,210.78 158.61,210.57 158.91,210.57 159.13,210.78 159.13,211.18 159.34,211.4 159.65,211.4 159.87,211.18 159.87,210.78 160.08,210.57 160.39,210.57 160.6,210.78 160.6,211.18 160.82,211.4 161.12,211.4 161.34,211.18 161.34,210.78 161.55,210.57 161.86,210.57 162.08,210.78 162.08,211.18 162.29,211.4 162.6,211.4 162.81,211.18 162.81,210.78 163.03,210.57 163.33,210.57 163.55,210.78 163.55,211.18 163.76,211.4 164.07,211.4 164.29,211.18 164.29,210.78 164.5,210.57 164.81,210.57 165.02,210.78 165.02,211.18 165.24,211.4 165.54,211.4 165.76,211.18 165.76,210.78 165.97,210.57 167.46,210.57 168.92,209.11 J1.4
MEM_MA_DATA2: length 95.3
  TOP w0.229: v3(121.64,166.68) U6.E16
  BOTTOM w0.099: J1.9 171.66,203.96 169.05,203.96 168.83,204.18 168.65,204.18 ; 121.19,167.13 v3(121.64,166.68)
  BOTTOM w0.102: 121.19,171.09 121.19,167.13
  BOTTOM w0.229: 121.19,171.09 121.19,171.79 122.07,172.67 122.07,184.38 122.59,184.9 122.59,185.2 122.39,185.41 122.39,185.71 122.6,185.93 122.91,185.93 123.11,185.72 123.42,185.72 123.63,185.94 123.63,186.24 123.43,186.45 123.43,186.75 123.64,186.97 123.95,186.97 124.15,186.77 124.46,186.77 124.67,186.98 124.67,187.29 124.47,187.49 124.47,187.8 124.69,188.01 124.99,188.01 125.19,187.81 125.5,187.81 125.72,188.02 125.72,188.33 125.51,188.53 125.51,188.84 125.73,189.05 126.03,189.05 126.24,188.85 126.54,188.85 126.76,189.07 126.76,189.37 126.55,189.57 126.55,189.88 126.77,190.1 127.07,190.1 127.28,189.89 127.58,189.89 127.8,190.11 127.8,190.41 127.59,190.62 127.59,190.92 127.81,191.14 128.12,191.14 128.32,190.93 128.63,190.93 128.84,191.15 128.84,191.45 128.64,191.66 128.64,191.96 128.85,192.18 129.16,192.18 129.36,191.97 129.67,191.97 129.88,192.19 129.88,192.5 129.68,192.7 129.68,193.01 129.89,193.22 130.2,193.22 130.4,193.02 130.71,193.02 130.93,193.23 130.93,193.54 130.72,193.74 130.72,194.05 130.94,194.26 131.24,194.26 131.45,194.06 131.75,194.06 131.97,194.27 131.97,194.58 131.76,194.78 131.76,195.09 131.98,195.31 132.28,195.31 132.49,195.1 132.79,195.1 133.01,195.32 133.01,195.62 132.8,195.83 132.8,196.13 133.02,196.35 133.33,196.35 133.53,196.14 133.83,196.14 134.05,196.36 134.05,196.66 133.85,196.87 133.85,197.17 134.06,197.39 134.37,197.39 134.57,197.18 134.88,197.18 135.09,197.4 135.09,197.71 134.89,197.91 134.89,198.21 135.1,198.43 135.41,198.43 135.61,198.23 135.92,198.23 136.13,198.44 136.13,198.75 135.93,198.95 135.93,199.26 136.15,199.47 136.45,199.47 136.66,199.27 136.96,199.27 137.18,199.48 137.18,199.79 136.97,199.99 136.97,200.3 137.19,200.51 137.49,200.51 137.7,200.31 138,200.31 138.22,200.53 138.22,200.83 138.01,201.04 138.01,201.34 138.23,201.56 138.53,201.56 138.74,201.35 139.04,201.35 139.26,201.57 139.26,201.87 139.06,202.08 139.06,202.38 139.27,202.6 139.58,202.6 139.78,202.39 140.09,202.39 141.88,204.18 145.17,204.18 147.75,206.76 165.77,206.76 168.36,204.18 168.65,204.18
MEM_MA_DATA3: length 95.8
  TOP w0.229: v3(121.65,162.85) 121.65,162.83 122.23,162.24 U6.H17
  BOTTOM w0.099: 121.8,171.09 122.07,170.82 122.07,163.28 v3(121.65,162.85)
  BOTTOM w0.229: J1.10 169.58,203.43 167.27,203.43 165.46,205.23 163.84,205.23 163.63,205.45 163.63,206 163.41,206.22 163.11,206.22 162.89,206 162.89,205.45 162.68,205.23 162.37,205.23 162.15,205.45 162.15,206 161.94,206.22 161.63,206.22 161.42,206 161.42,205.45 161.2,205.23 160.9,205.23 160.68,205.45 160.68,206 160.47,206.22 160.16,206.22 159.94,206 159.94,205.45 159.73,205.23 159.42,205.23 159.21,205.45 159.21,206 158.99,206.22 158.69,206.22 158.47,206 158.47,205.45 158.26,205.23 157.95,205.23 157.73,205.45 157.73,206 157.52,206.22 157.21,206.22 157,206 157,205.45 156.78,205.23 156.48,205.23 156.26,205.45 156.26,206 156.05,206.22 155.74,206.22 155.52,206 155.52,205.45 155.31,205.23 155,205.23 154.79,205.45 154.79,206 154.57,206.22 154.27,206.22 154.05,206 154.05,205.45 153.84,205.23 153.53,205.23 153.31,205.45 153.31,206 153.1,206.22 152.79,206.22 152.58,206 152.58,205.45 152.36,205.23 152.06,205.23 151.84,205.45 151.84,206 151.63,206.22 151.32,206.22 151.11,206 151.11,205.45 150.89,205.23 150.58,205.23 150.37,205.45 150.37,206 150.15,206.22 149.85,206.22 149.63,206 149.63,205.45 149.42,205.23 149.11,205.23 148.9,205.45 148.9,206 148.68,206.22 148.37,206.22 148.16,206 148.16,205.45 147.94,205.23 147.21,205.23 145.49,203.52 142,203.52 122.65,184.17 122.65,172.67 121.8,171.83 121.8,171.09
MEM_MA_DATA4: length 95.8
  TOP w0.229: v3(117.92,164.1) 117.92,162.96 U6.H13
  BOTTOM w0.099: 171.05,211.19 173.63,211.19 J1.122
  BOTTOM w0.229: v3(117.92,164.1) 117.92,164.35 117.24,165.03 117.24,166.24 116.35,167.13 116.35,168.45 116.03,168.77 116.03,173.93 116.93,174.83 116.93,188.81 141.29,213.17 169.06,213.17 171.05,211.19
MEM_MA_DATA5: length 95.7
  TOP w0.102: U6.G13 117.19,164.01 117.82,164.64 117.82,165.38 v3(117.84,165.39)
  BOTTOM w0.099: 169.37,210.35 170.46,210.35 170.97,210.86 172.54,210.86 173.29,210.11 J1.123
  BOTTOM w0.229: 169.37,210.35 167.13,212.59 141.47,212.59 117.46,188.58 117.46,174.41 116.67,173.62 116.67,168.94 116.8,168.81 116.8,167.39 117.84,166.35 v3(117.84,165.39)
MEM_MA_DATA6: length 95.5
  TOP w0.229: v3(120.37,166.68) U6.E15
  BOTTOM w0.099: 169.24,205.96 170.49,205.96 171.17,205.28 173.53,205.28 J1.128
  BOTTOM w0.102: 119.84,171.02 120.37,170.48 v3(120.37,166.68)
  BOTTOM w0.229: 169.24,205.96 168.46,205.96 166.54,207.89 146.73,207.89 145.03,206.19 139.77,206.19 133.41,199.83 133.41,199.53 133.64,199.31 133.64,199 133.42,198.78 133.12,198.78 132.89,199.01 132.59,199.01 132.37,198.79 132.37,198.49 132.6,198.26 132.6,197.96 132.38,197.74 132.07,197.74 131.85,197.96 131.55,197.96 131.33,197.75 131.33,197.44 131.55,197.22 131.55,196.92 131.34,196.7 131.03,196.7 130.81,196.92 130.51,196.92 130.29,196.71 130.29,196.4 130.51,196.18 130.51,195.87 130.3,195.66 129.99,195.66 129.77,195.88 129.46,195.88 129.25,195.66 129.25,195.36 129.47,195.14 129.47,194.83 129.25,194.62 128.95,194.62 128.73,194.84 128.42,194.84 128.21,194.62 128.21,194.32 128.43,194.1 128.43,193.79 128.21,193.57 127.91,193.57 127.68,193.8 127.38,193.8 127.16,193.58 127.16,193.28 127.39,193.05 127.39,192.75 127.17,192.53 126.86,192.53 126.64,192.76 126.34,192.76 126.12,192.54 126.12,192.23 126.34,192.01 126.34,191.71 126.13,191.49 125.82,191.49 125.6,191.71 125.3,191.71 125.08,191.5 125.08,191.19 125.3,190.97 125.3,190.67 125.09,190.45 124.78,190.45 124.56,190.67 124.25,190.67 124.04,190.46 124.04,190.15 124.26,189.93 124.26,189.62 124.04,189.41 123.74,189.41 123.52,189.63 123.21,189.63 123,189.41 123,189.11 123.22,188.89 123.22,188.58 123,188.37 122.7,188.37 122.47,188.59 122.17,188.59 120.91,187.33 120.91,172.84 119.84,171.77 119.84,171.02
MEM_MA_DATA7: length 96
  TOP w0.229: v3(121.64,164.14) U6.G16
  BOTTOM w0.099: 168.68,204.93 168.93,204.93 169.55,204.31 170.55,204.31 171.17,204.93 172.52,204.93 173.35,204.1 174.2,204.1 174.28,204.19 175.53,204.19 J1.129 ; 120.81,164.97 v3(121.64,164.14)
  BOTTOM w0.102: 120.81,164.97 120.81,170.94 120.5,171.25
  BOTTOM w0.229: 168.68,204.93 166.27,207.34 147.45,207.34 145.1,205 140.75,205 140.45,205 140.12,205.32 139.82,205.32 139.6,205.1 139.6,204.8 139.93,204.48 139.93,204.17 139.71,203.96 139.41,203.96 139.08,204.28 138.78,204.28 138.56,204.06 138.56,203.76 138.88,203.44 138.88,203.13 138.67,202.91 138.36,202.91 138.04,203.24 137.74,203.24 137.52,203.02 137.52,202.72 137.84,202.39 137.84,202.09 137.63,201.87 137.32,201.87 137,202.19 136.69,202.19 136.48,201.98 136.48,201.67 136.8,201.35 136.8,201.05 136.58,200.83 136.28,200.83 135.96,201.15 135.65,201.15 135.44,200.94 135.44,200.63 135.76,200.31 135.76,200 135.54,199.79 135.24,199.79 134.92,200.11 134.61,200.11 134.39,199.89 134.39,199.59 134.72,199.27 134.72,198.96 121.49,185.74 121.49,172.79 120.5,171.79 120.5,171.25
MEM_MA_DATA8: length 84.2
  TOP w0.229: v3(122.92,166.64) 122.33,166.05 U6.E17
  BOTTOM w0.229: v3(122.92,166.64) 122.96,166.64 122.9,166.69 122.9,170.95 123.65,171.69 123.65,171.89 124.29,172.54 124.29,173.42 124.97,174.09 124.97,182.37 126.5,183.9 126.5,184.21 126.34,184.37 126.34,184.67 126.56,184.89 126.87,184.89 127.02,184.73 127.33,184.73 127.54,184.95 127.54,185.25 127.39,185.41 127.39,185.71 127.6,185.93 127.91,185.93 128.06,185.77 128.37,185.77 128.59,185.99 128.59,186.29 128.43,186.45 128.43,186.76 128.64,186.97 128.95,186.97 129.11,186.81 129.41,186.81 129.63,187.03 129.63,187.34 129.47,187.49 129.47,187.8 129.69,188.01 129.99,188.01 130.15,187.86 130.45,187.86 130.67,188.07 130.67,188.38 130.51,188.53 130.51,188.84 130.73,189.06 131.03,189.06 131.19,188.9 131.5,188.9 131.71,189.11 131.71,189.42 131.55,189.58 131.55,189.88 131.77,190.1 132.07,190.1 132.23,189.94 132.54,189.94 132.75,190.16 132.75,190.46 132.6,190.62 132.6,190.92 132.81,191.14 133.12,191.14 133.27,190.98 133.58,190.98 133.8,191.2 133.8,191.5 133.64,191.66 133.64,191.97 133.85,192.18 134.16,192.18 134.32,192.02 134.62,192.02 134.84,192.24 134.84,192.54 134.68,192.7 134.68,193.01 134.9,193.22 135.2,193.22 135.36,193.07 135.66,193.07 135.88,193.28 135.88,193.59 135.72,193.74 135.72,194.05 135.94,194.27 136.24,194.27 136.4,194.11 136.7,194.11 136.92,194.32 136.92,194.63 136.76,194.79 136.76,195.09 136.98,195.31 137.28,195.31 137.44,195.15 137.75,195.15 137.96,195.37 137.96,195.67 137.81,195.83 137.81,196.13 138.02,196.35 138.33,196.35 138.48,196.19 138.79,196.19 139,196.41 139,196.71 138.85,196.87 138.85,197.17 139.06,197.39 139.37,197.39 139.53,197.23 139.83,197.23 140.05,197.45 140.05,197.75 139.89,197.91 139.89,198.22 140.11,198.43 140.41,198.43 140.57,198.28 140.87,198.28 141.09,198.49 141.09,198.8 140.93,198.95 140.93,199.26 141.15,199.47 141.45,199.47 141.61,199.32 141.91,199.32 142.13,199.53 142.13,199.84 141.97,200 141.97,200.3 142.19,200.52 142.49,200.52 142.65,200.36 142.96,200.36 143.48,200.88 146.66,200.88 148.18,202.4 164.88,202.4 166,201.28 168.96,201.28 169.14,201.11 J1.12
MEM_MA_DATA9: length 81.9
  TOP w0.229: U6.G18 123.54,163.68 v3(124.19,164.32)
  BOTTOM w0.099: 123.92,171.47 124.65,171.47 125.6,172.42 125.6,173.42 ; J1.13 171.62,200.29 170.75,200.29 170.69,200.24 169.09,200.24
  BOTTOM w0.102: 123.92,171.47 123.35,170.9 123.35,165.16 v3(124.19,164.32)
  BOTTOM w0.229: 169.09,200.24 168.99,200.34 166.1,200.34 164.76,201.68 160.34,201.68 159.82,201.16 159.09,201.16 158.87,201.38 158.87,201.65 158.65,201.86 158.35,201.86 158.13,201.65 158.13,201.38 157.92,201.16 157.61,201.16 157.4,201.38 157.4,201.65 157.18,201.86 156.88,201.86 156.66,201.65 156.66,201.38 156.44,201.16 156.14,201.16 155.92,201.38 155.92,201.65 155.71,201.86 155.4,201.86 155.19,201.65 155.19,201.38 154.97,201.16 154.67,201.16 154.45,201.38 154.45,201.65 154.24,201.86 153.93,201.86 153.71,201.65 153.71,201.38 153.5,201.16 153.19,201.16 152.98,201.38 152.98,201.65 152.76,201.86 152.46,201.86 152.24,201.65 152.24,201.38 152.03,201.16 151.72,201.16 151.5,201.38 151.5,201.65 151.29,201.86 150.98,201.86 150.77,201.65 150.77,201.38 150.55,201.16 150.25,201.16 150.03,201.38 150.03,201.65 149.82,201.86 149.51,201.86 149.29,201.65 149.29,201.38 149.08,201.16 147.73,201.16 146.8,200.23 143.62,200.23 125.6,182.22 125.6,173.42
MEM_MA_DATA10: length 82.3
  TOP w0.229: v3(127.99,165.41) U6.F21
  BOTTOM w0.099: v3(127.99,165.41) 128.62,166.04 129.4,166.04
  BOTTOM w0.102: 129.28,167.39 129.59,167.39 129.77,167.21 129.77,166.42 129.4,166.04
  BOTTOM w0.229: J1.18 169.02,195.11 167.49,196.63 148.12,196.63 147.22,195.73 146.91,195.73 146.67,195.98 146.36,195.98 146.15,195.76 146.15,195.45 146.39,195.21 146.39,194.91 146.18,194.69 145.87,194.69 145.63,194.93 145.32,194.93 145.11,194.72 145.11,194.41 145.35,194.17 145.35,193.87 145.13,193.65 144.83,193.65 144.59,193.89 144.28,193.89 144.06,193.68 144.06,193.37 144.31,193.13 144.31,192.82 144.09,192.61 143.79,192.61 143.54,192.85 143.24,192.85 143.02,192.63 143.02,192.33 143.27,192.09 143.27,191.78 143.05,191.57 142.74,191.57 142.5,191.81 142.2,191.81 141.98,191.59 141.98,191.29 142.22,191.04 142.22,190.74 142.01,190.52 141.7,190.52 141.46,190.77 141.16,190.77 140.94,190.55 140.94,190.24 141.18,190 141.18,189.7 140.97,189.48 140.66,189.48 140.42,189.72 140.11,189.72 139.9,189.51 139.9,189.2 140.14,188.96 140.14,188.66 139.92,188.44 139.62,188.44 139.38,188.68 139.07,188.68 138.86,188.47 138.86,188.16 139.1,187.92 139.1,187.61 138.88,187.4 138.58,187.4 138.33,187.64 138.03,187.64 137.81,187.42 137.81,187.12 138.06,186.88 138.06,186.57 137.84,186.36 137.54,186.36 137.29,186.6 136.99,186.6 136.77,186.38 136.77,186.08 137.01,185.83 137.01,185.53 136.8,185.31 136.49,185.31 136.25,185.56 135.95,185.56 135.73,185.34 135.73,185.04 135.97,184.79 135.97,184.49 135.76,184.27 135.45,184.27 135.21,184.51 134.9,184.51 134.69,184.3 134.69,183.99 134.93,183.75 134.93,183.45 134.71,183.23 134.41,183.23 134.17,183.47 133.86,183.47 133.65,183.26 133.65,182.95 133.89,182.71 133.89,182.4 133.67,182.19 133.37,182.19 133.12,182.43 132.82,182.43 132.6,182.21 132.6,181.91 132.85,181.67 132.85,181.36 132.63,181.15 132.33,181.15 132.08,181.39 131.78,181.39 131.56,181.17 131.56,180.87 131.8,180.63 131.8,180.32 131.59,180.1 131.28,180.1 131.04,180.35 130.74,180.35 130.52,180.13 130.52,179.83 130.76,179.58 130.76,179.28 130.55,179.06 130.24,179.06 130,179.3 129.69,179.3 129.48,179.09 129.48,178.78 129.72,178.54 129.72,178.24 129.2,177.71 129.2,170.01 128.71,169.52 128.71,167.67 128.98,167.39 129.28,167.39
MEM_MA_DATA11: length 82
  TOP w0.229: U6.G22 128.62,163.79 v3(129.27,164.43)
  BOTTOM w0.099: 168.54,194.68 168.88,194.34 170.31,194.34 170.77,194.81 171.34,194.81 171.81,194.34 J1.19 ; 129.83,169.26 129.83,167.64 130.08,167.39 130.08,166.32 129.82,166.07 129.82,165.63 130.08,165.37 130.08,164.85 129.66,164.43 v3(129.27,164.43)
  BOTTOM w0.229: 168.54,194.68 168.04,195.18 167.3,195.18 167.09,195.39 167.09,195.85 166.87,196.07 166.56,196.07 166.35,195.85 166.35,195.39 166.13,195.18 165.83,195.18 165.61,195.39 165.61,195.85 165.4,196.07 165.09,196.07 164.88,195.85 164.88,195.39 164.66,195.18 164.35,195.18 164.14,195.39 164.14,195.85 163.92,196.07 163.62,196.07 163.4,195.85 163.4,195.39 163.19,195.18 162.88,195.18 162.67,195.39 162.67,195.85 162.45,196.07 162.14,196.07 161.93,195.85 161.93,195.39 161.71,195.18 161.41,195.18 161.19,195.39 161.19,195.85 160.98,196.07 160.67,196.07 160.46,195.85 160.46,195.39 160.24,195.18 159.93,195.18 159.72,195.39 159.72,195.85 159.5,196.07 159.2,196.07 158.98,195.85 158.98,195.39 158.77,195.18 158.46,195.18 158.25,195.39 158.25,195.85 158.03,196.07 157.72,196.07 157.51,195.85 157.51,195.39 157.29,195.18 156.99,195.18 156.77,195.39 156.77,195.85 156.56,196.07 156.25,196.07 156.04,195.85 156.04,195.39 155.82,195.18 155.52,195.18 155.3,195.39 155.3,195.85 155.08,196.07 154.78,196.07 154.56,195.85 154.56,195.39 154.35,195.18 154.04,195.18 153.83,195.39 153.83,195.85 153.61,196.07 153.31,196.07 153.09,195.85 153.09,195.39 152.87,195.18 152.57,195.18 152.35,195.39 152.35,195.85 152.14,196.07 151.83,196.07 151.62,195.85 151.62,195.39 151.4,195.18 151.1,195.18 150.88,195.39 150.88,195.85 150.66,196.07 150.36,196.07 150.14,195.85 150.14,195.39 149.93,195.18 149.62,195.18 149.41,195.39 149.41,195.85 149.19,196.07 148.89,196.07 148.67,195.85 148.67,195.39 148.45,195.18 147.51,195.18 129.83,177.5 129.83,169.26
MEM_MA_DATA12: length 82.6
  TOP w0.229: v3(122.91,164.14) U6.G17
  BOTTOM w0.099: J1.131 173.19,202.11 172.46,202.84 171.51,202.84 171.04,202.37 169.14,202.37
  BOTTOM w0.102: v3(122.91,164.14) 122.27,164.78 122.27,171.52 122.44,171.68
  BOTTOM w0.229: 122.44,171.68 122.44,171.77 123.23,172.55 123.23,183.1 142.32,202.2 145.9,202.2 147.59,203.89 165.87,203.89 167.08,202.68 168.84,202.68 169.14,202.37
MEM_MA_DATA13: length 81.9
  TOP w0.229: v3(122.91,165.41) U6.F17
  BOTTOM w0.099: 169.02,201.86 170.64,201.86 171.29,201.2 173.61,201.2 J1.132
  BOTTOM w0.102: v3(122.91,165.41) 122.48,165.84 122.48,171.24 123.07,171.83
  BOTTOM w0.229: 123.07,171.83 123.07,171.83 123.84,172.59 123.84,182.93 142.41,201.5 146.07,201.5 147.5,202.93 148.88,202.93 149.3,203.36 149.61,203.36 150.04,202.93 150.35,202.93 150.77,203.36 151.09,203.36 151.51,202.93 151.82,202.93 152.25,203.36 152.56,203.36 152.98,202.93 153.3,202.93 153.72,203.36 154.03,203.36 154.46,202.93 154.77,202.93 155.19,203.36 155.51,203.36 155.93,202.93 156.24,202.93 156.67,203.36 156.98,203.36 157.4,202.93 157.72,202.93 158.14,203.36 158.45,203.36 158.88,202.93 159.19,202.93 159.61,203.36 159.93,203.36 160.35,202.93 160.66,202.93 161.09,203.36 161.4,203.36 161.82,202.93 162.14,202.93 162.56,203.36 162.87,203.36 163.3,202.93 163.61,202.93 164.03,203.36 164.35,203.36 164.77,202.93 165.51,202.93 166.51,201.93 168.95,201.93 169.02,201.86
MEM_MA_DATA14: length 82
  TOP w0.229: v3(127.99,166.68) U6.E21
  BOTTOM w0.099: 168.8,197.17 169.59,196.37 170.66,196.37 171.12,196.84 172.66,196.84 173.39,196.11 175.61,196.11 J1.137
  BOTTOM w0.102: 168.8,197.17 168.79,197.17
  BOTTOM w0.229: 168.79,197.17 168.2,197.76 167.26,197.76 166.89,198.13 166.53,198.13 166.16,197.76 165.79,197.76 165.42,198.13 165.05,198.13 164.68,197.76 164.32,197.76 163.95,198.13 163.58,198.13 163.21,197.76 162.84,197.76 162.47,198.13 162.11,198.13 161.74,197.76 161.37,197.76 161,198.13 160.63,198.13 160.26,197.76 159.9,197.76 159.53,198.13 159.16,198.13 158.79,197.76 158.42,197.76 158.05,198.13 157.69,198.13 157.32,197.76 156.95,197.76 156.58,198.13 156.21,198.13 155.85,197.76 155.48,197.76 155.11,198.13 154.74,198.13 154.37,197.76 154,197.76 153.64,198.13 153.27,198.13 152.9,197.76 152.53,197.76 152.16,198.13 151.79,198.13 151.43,197.76 151.06,197.76 150.69,198.13 150.32,198.13 149.95,197.76 149.59,197.76 149.22,198.13 148.85,198.13 148.48,197.76 148.11,197.76 147.74,198.13 147.38,198.13 147.01,197.76 146.64,197.76 146.27,198.13 145.9,198.13 145.36,197.59 145.06,197.59 145.05,197.6 144.74,197.6 144.53,197.38 144.53,197.08 144.54,197.07 144.54,196.76 144.32,196.55 144.02,196.55 144.01,196.56 143.7,196.56 143.48,196.34 143.48,196.04 143.5,196.03 143.5,195.72 143.28,195.51 142.97,195.51 142.96,195.52 142.66,195.52 142.44,195.3 142.44,195 142.45,194.98 142.45,194.68 142.24,194.46 141.93,194.46 141.92,194.48 141.62,194.48 141.4,194.26 141.4,193.95 141.41,193.94 141.41,193.64 141.2,193.42 140.89,193.42 140.88,193.43 140.57,193.43 140.36,193.22 140.36,192.91 140.37,192.9 140.37,192.6 140.15,192.38 139.85,192.38 139.84,192.39 139.53,192.39 139.32,192.18 139.32,191.87 139.33,191.86 139.33,191.55 139.11,191.34 138.81,191.34 138.8,191.35 138.49,191.35 138.27,191.13 138.27,190.83 138.29,190.82 138.29,190.51 138.07,190.3 137.76,190.3 137.75,190.31 137.45,190.31 137.23,190.09 137.23,189.79 137.24,189.78 137.24,189.47 137.03,189.25 136.72,189.25 136.71,189.27 136.41,189.27 136.19,189.05 136.19,188.74 136.2,188.73 136.2,188.43 135.99,188.21 135.68,188.21 135.67,188.22 135.36,188.22 135.15,188.01 135.15,187.7 135.16,187.69 135.16,187.39 134.94,187.17 134.64,187.17 134.63,187.18 134.32,187.18 134.11,186.97 134.11,186.66 134.12,186.65 134.12,186.34 133.9,186.13 133.6,186.13 133.59,186.14 133.28,186.14 133.07,185.92 133.07,185.62 133.08,185.61 133.08,185.3 132.86,185.09 132.56,185.09 132.54,185.1 132.24,185.1 132.02,184.88 132.02,184.58 132.03,184.57 132.03,184.26 131.82,184.04 131.51,184.04 131.5,184.06 131.2,184.06 130.98,183.84 130.98,183.54 130.99,183.52 130.99,183.22 130.78,183 130.47,183 130.46,183.01 130.16,183.01 129.94,182.8 129.94,182.49 129.95,182.48 129.95,182.18 129.73,181.96 129.43,181.96 129.42,181.97 129.11,181.97 128.9,181.76 128.9,181.45 128.91,181.44 128.91,181.14 127.93,180.16 127.93,170.56 127.76,170.38 127.76,169.5 127.56,169.3 127.43,169.3 127.23,169.1 127.23,168.81 127.43,168.61 127.56,168.61 127.76,168.41 127.76,167 127.99,166.76 v3(127.99,166.68)
MEM_MA_DATA15: length 84.4
  TOP w0.229: v3(129.26,166.68) U6.E22
  BOTTOM w0.099: J1.138 171.64,195.11 170.8,195.95 169.09,195.95
  BOTTOM w0.229: 169.09,195.95 167.87,197.17 146.8,197.17 145.54,195.91 145.24,195.91 144.99,196.15 144.69,196.15 144.47,195.94 144.47,195.63 144.71,195.39 144.71,195.08 144.5,194.87 144.19,194.87 143.95,195.11 143.64,195.11 143.43,194.89 143.43,194.59 143.67,194.34 143.67,194.04 143.46,193.82 143.15,193.82 142.91,194.07 142.6,194.07 142.39,193.85 142.39,193.55 142.63,193.3 142.63,193 142.41,192.78 142.11,192.78 141.86,193.03 141.56,193.03 141.34,192.81 141.34,192.51 141.59,192.26 141.59,191.96 141.37,191.74 141.07,191.74 140.82,191.98 140.52,191.98 140.3,191.77 140.3,191.46 140.55,191.22 140.55,190.91 140.33,190.7 140.03,190.7 139.78,190.94 139.48,190.94 139.26,190.73 139.26,190.42 139.5,190.18 139.5,189.87 139.29,189.66 138.98,189.66 138.74,189.9 138.43,189.9 138.22,189.68 138.22,189.38 138.46,189.14 138.46,188.83 138.25,188.61 137.94,188.61 137.7,188.86 137.39,188.86 137.18,188.64 137.18,188.34 137.42,188.09 137.42,187.79 137.2,187.57 136.9,187.57 136.65,187.82 136.35,187.82 136.13,187.6 136.13,187.3 136.38,187.05 136.38,186.75 136.16,186.53 135.86,186.53 135.61,186.78 135.31,186.78 135.09,186.56 135.09,186.25 135.34,186.01 135.34,185.7 135.12,185.49 134.82,185.49 134.57,185.73 134.27,185.73 134.05,185.52 134.05,185.21 134.3,184.97 134.3,184.66 134.08,184.45 133.77,184.45 133.53,184.69 133.22,184.69 133.01,184.48 133.01,184.17 133.25,183.93 133.25,183.62 133.04,183.4 132.73,183.4 132.49,183.65 132.18,183.65 131.97,183.43 131.97,183.13 132.21,182.88 132.21,182.58 132,182.36 131.69,182.36 131.45,182.61 131.14,182.61 130.92,182.39 130.92,182.09 131.17,181.84 131.17,181.54 130.95,181.32 130.65,181.32 130.4,181.57 130.1,181.57 129.88,181.35 129.88,181.04 130.13,180.8 130.13,180.49 129.91,180.28 129.61,180.28 129.36,180.52 129.06,180.52 128.84,180.31 128.84,180 129.09,179.76 129.09,179.45 128.56,178.93 128.56,170.38 128.21,170.03 128.21,167.25 128.78,166.68 v3(129.26,166.68)
MEM_MA_DATA16: length 63.5
  TOP w0.229: v3(130.53,165.41) U6.F23
  BOTTOM w0.099: 168.81,191.91 171.61,191.91 J1.21 ; 131.84,174.24 131.84,171.45 132.24,171.05 132.24,170.32 131.71,169.8 131.71,168.88 131.15,168.31 131.15,166.03 v3(130.53,165.41)
  BOTTOM w0.229: 168.81,191.91 168.2,192.52 166.52,192.52 166.3,192.3 166.3,191.78 166.09,191.57 165.78,191.57 165.57,191.78 165.57,192.63 165.4,192.8 149.21,192.8 148.67,192.26 148.36,192.26 148.31,192.31 148.01,192.31 147.79,192.09 147.79,191.79 147.84,191.74 147.84,191.43 147.63,191.22 147.32,191.22 147.27,191.27 146.97,191.27 146.75,191.05 146.75,190.75 146.8,190.7 146.8,190.39 146.58,190.17 146.28,190.17 146.23,190.23 145.92,190.23 145.71,190.01 145.71,189.7 145.76,189.65 145.76,189.35 145.54,189.13 145.24,189.13 145.19,189.18 144.88,189.18 144.67,188.97 144.67,188.66 144.72,188.61 144.72,188.31 144.5,188.09 144.2,188.09 144.14,188.14 143.84,188.14 143.62,187.93 143.62,187.62 143.67,187.57 143.67,187.26 131.84,175.43 131.84,174.24
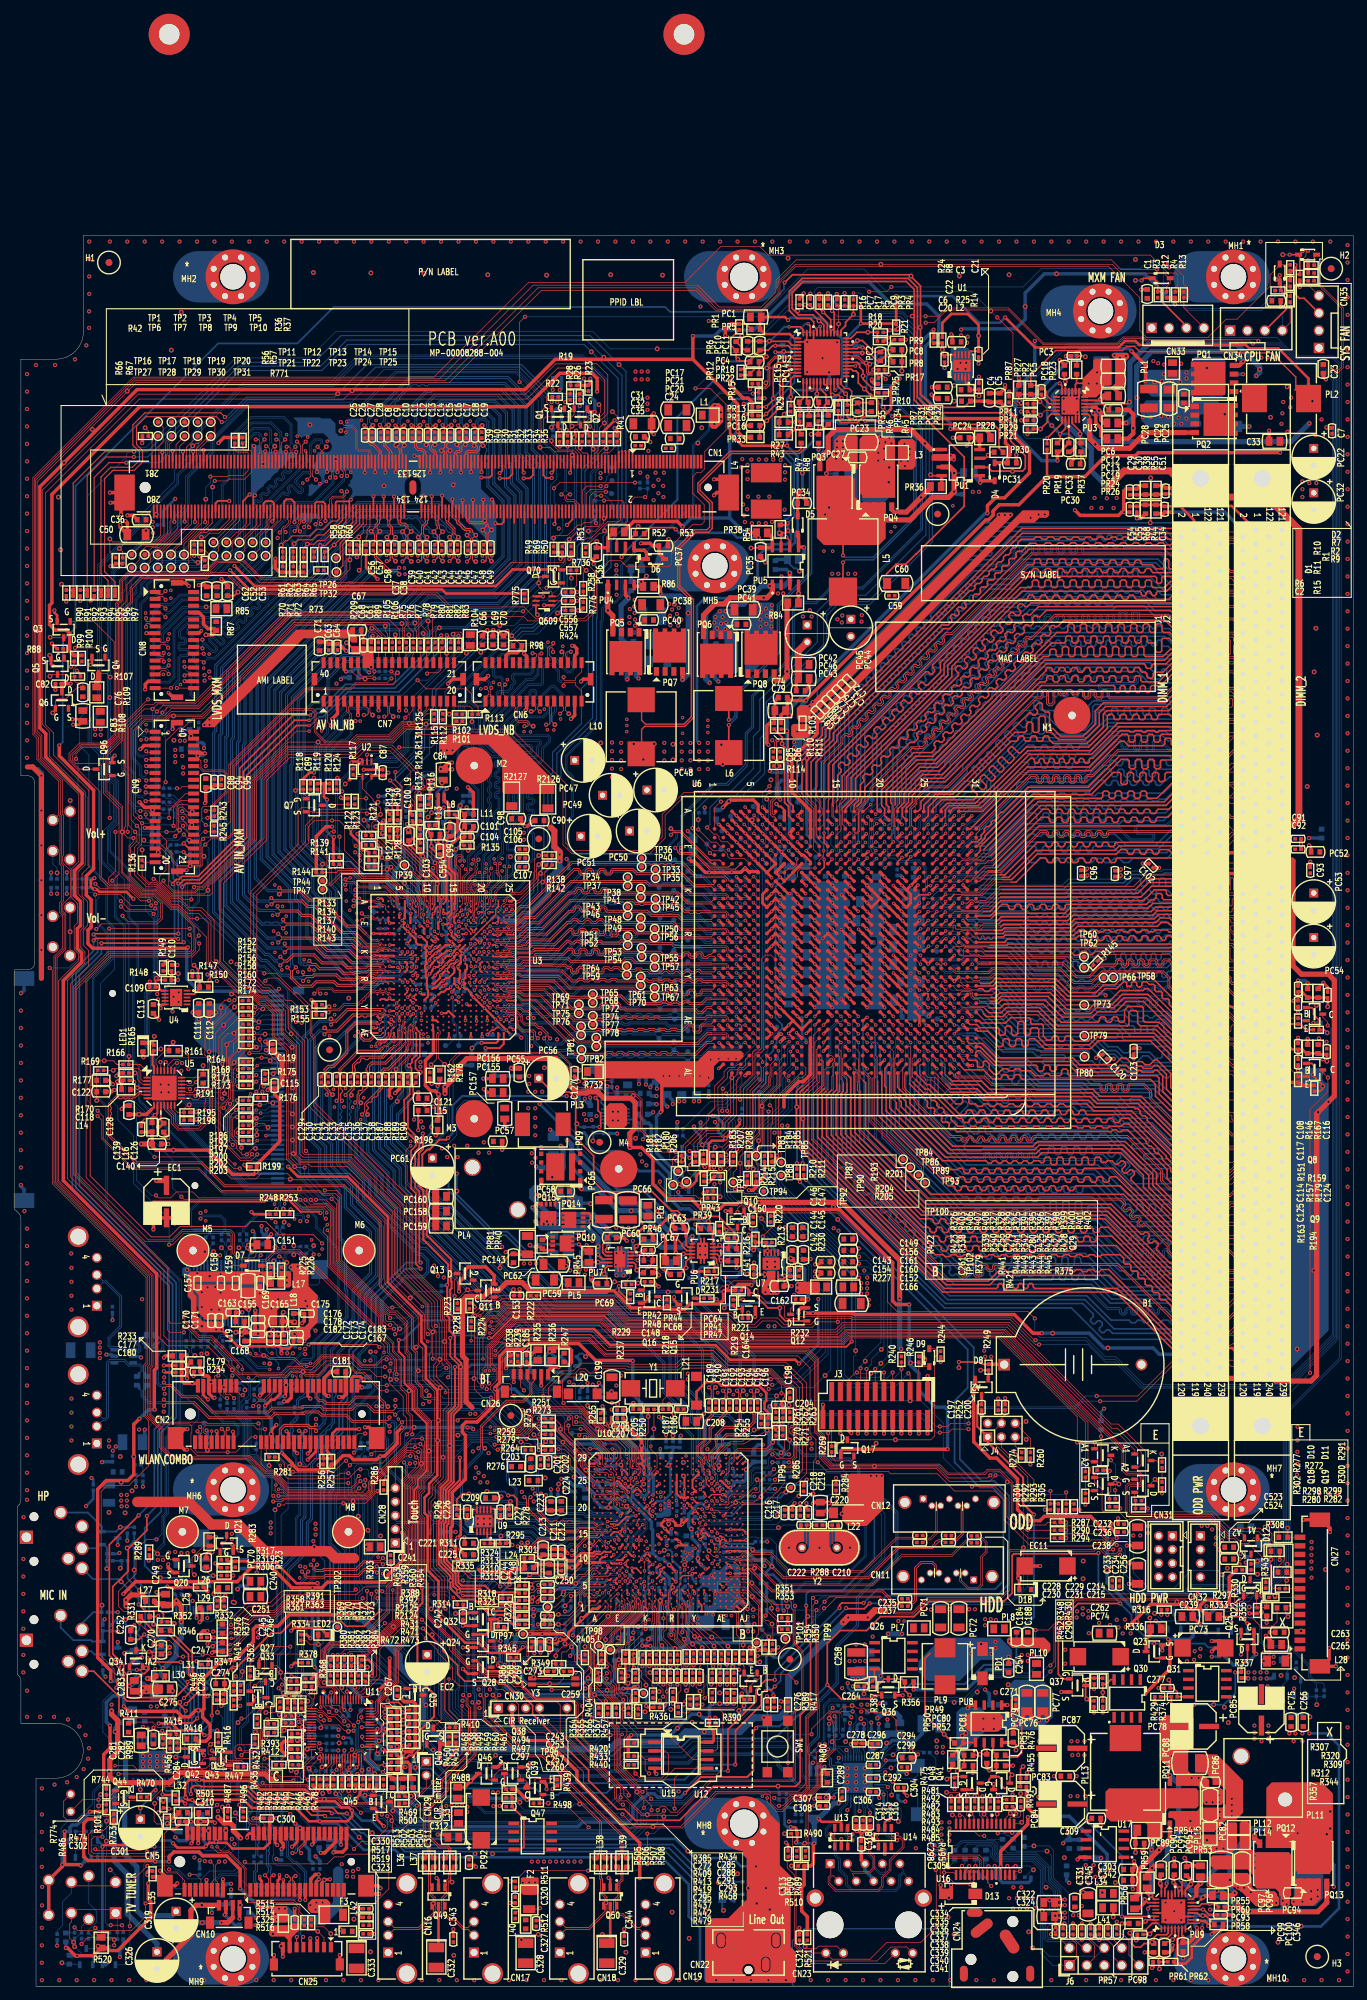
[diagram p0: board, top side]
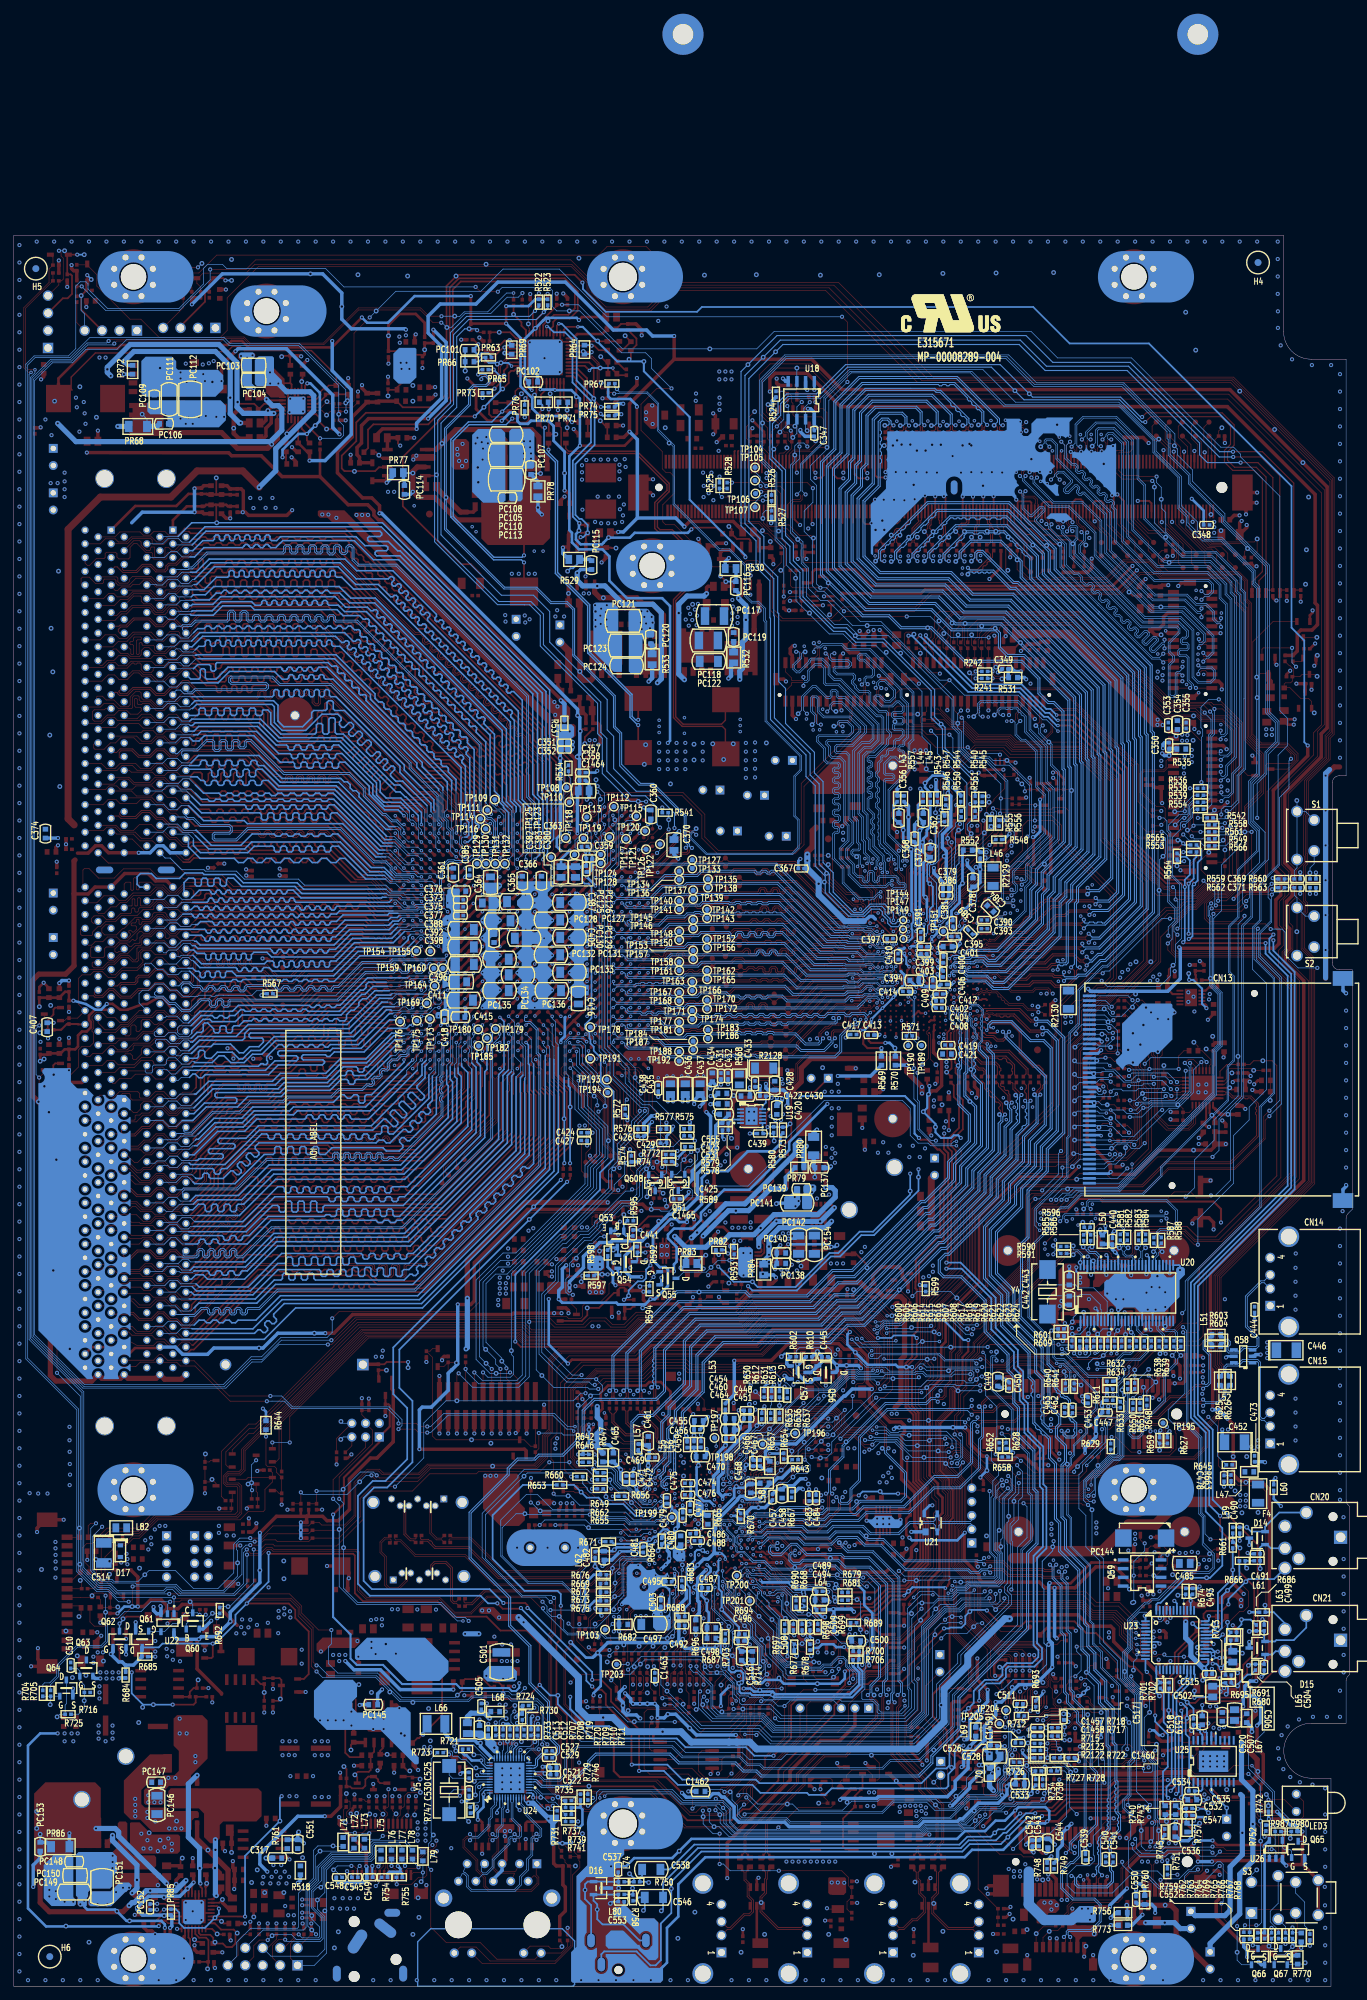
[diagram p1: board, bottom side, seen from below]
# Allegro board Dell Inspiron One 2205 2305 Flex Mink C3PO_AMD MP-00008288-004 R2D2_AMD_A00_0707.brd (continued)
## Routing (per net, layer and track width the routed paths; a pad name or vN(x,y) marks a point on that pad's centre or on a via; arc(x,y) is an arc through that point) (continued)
MEM_MA_DATA17: length 63.2
  TOP w0.229: U6.G23 129.89,163.87 v3(130.54,164.52)
  BOTTOM w0.099: 130.57,164.54 131.35,165.32 131.35,168.13 131.93,168.72 131.93,169.66 132.47,170.2 132.47,174.24
  BOTTOM w0.102: v3(130.54,164.52) 130.57,164.54
  BOTTOM w0.229: J1.22 169.21,190.41 168.04,190.41 167.83,190.62 167.83,191.7 167.61,191.92 167.31,191.92 167.09,191.7 167.09,190.62 166.87,190.41 165.52,190.41 163.79,192.14 156.12,192.14 155.91,191.92 155.91,191.8 155.69,191.58 155.39,191.58 155.17,191.8 155.17,191.92 154.96,192.14 154.65,192.14 154.44,191.92 154.44,191.8 154.22,191.58 153.92,191.58 153.7,191.8 153.7,191.92 153.48,192.14 153.18,192.14 152.96,191.92 152.96,191.8 152.75,191.58 152.44,191.58 152.23,191.8 152.23,191.92 152.01,192.14 151.71,192.14 151.49,191.92 151.49,191.8 151.27,191.58 150.97,191.58 150.75,191.8 150.75,191.92 150.54,192.14 149.38,192.14 135.49,178.24 135.49,177.65 132.47,174.64 132.47,174.24
MEM_MA_DATA18: length 64.9
  TOP w0.229: U6.C26 v3(134.34,169.22)
  BOTTOM w0.099: J1.27 171.61,185.91 169.35,185.91 169.16,186.11 168.97,186.11 ; v3(134.34,169.22) 134.78,169.66 134.78,171.98
  BOTTOM w0.229: 134.78,171.98 138.34,175.54 139.34,175.54 140.1,176.31 140.1,176.61 139.5,177.21 139.5,177.52 139.72,177.74 140.02,177.74 140.63,177.13 140.93,177.13 141.15,177.35 141.15,177.65 140.54,178.26 140.54,178.56 140.76,178.78 141.06,178.78 141.67,178.17 141.97,178.17 142.19,178.39 142.19,178.7 141.59,179.3 141.59,179.6 141.8,179.82 142.11,179.82 142.71,179.22 143.01,179.22 143.62,179.82 143.62,180.14 142.92,180.84 142.92,181.17 143.24,181.49 143.56,181.49 144.26,180.79 144.59,180.79 144.91,181.11 144.91,181.44 144.21,182.14 144.21,182.46 144.53,182.78 144.86,182.78 145.56,182.08 145.88,182.08 146.2,182.41 146.2,182.73 145.5,183.43 145.5,183.75 145.83,184.08 146.15,184.08 146.85,183.38 147.17,183.38 147.55,183.75 147.55,184.15 147.31,184.4 147.31,184.81 147.79,185.29 150.1,185.29 152.46,182.93 155.88,182.93 157.03,184.08 157.03,186.39 157.36,186.72 168.36,186.72 168.97,186.11
MEM_MA_DATA19: length 63.3
  TOP w0.229: v3(134.34,166.68) U6.E26
  BOTTOM w0.099: 135.58,171.83 135.12,171.37 135.12,167.46 v3(134.34,166.68)
  BOTTOM w0.229: 135.58,171.83 138.73,174.98 139.58,174.98 143.12,178.52 147,182.4 147.94,182.4 148.17,182.63 148.17,184.56 148.37,184.76 148.88,184.76 149.08,184.56 149.08,182.63 149.31,182.4 149.77,182.4 150,182.63 150,183.73 150.2,183.93 150.71,183.93 150.91,183.73 150.91,182.63 151.14,182.4 156.1,182.4 157.57,183.86 157.57,185.5 157.97,185.9 158.66,185.9 158.76,185.8 158.76,185.34 159,185.11 159.55,185.11 159.78,185.33 159.78,185.98 159.98,186.18 160.49,186.18 160.69,185.98 160.69,185.33 160.92,185.11 161.38,185.11 161.61,185.33 161.61,185.98 161.81,186.18 162.32,186.18 162.52,185.98 162.52,185.33 162.75,185.11 163.21,185.11 163.44,185.33 163.44,185.98 163.64,186.18 164.15,186.18 164.35,185.98 164.35,185.33 164.58,185.11 165.04,185.11 165.26,185.33 165.26,185.98 165.47,186.18 165.98,186.18 166.18,185.98 166.18,185.33 166.41,185.11 166.86,185.11 167.09,185.33 167.09,185.98 167.3,186.18 167.8,186.18 168.01,185.98 168.01,185.33 168.24,185.11 J1.28
MEM_MA_DATA20: length 63.2
  TOP w0.229: v3(130.51,167.98) 129.89,167.36 U6.D23
  BOTTOM w0.099: v3(130.51,167.98) 130.57,168.04 130.57,174.24 ; 168.54,193.88 170.67,193.88 171.27,193.28 173.53,193.28 J1.140
  BOTTOM w0.229: 130.57,174.24 130.57,175.79 131.69,176.91 131.69,177.12 131.69,177.42 131.96,177.69 132.16,177.69 132.47,177.69 132.73,177.95 132.73,178.16 132.73,178.46 133,178.73 133.2,178.73 133.51,178.73 133.77,179 133.77,179.2 133.77,179.51 134.04,179.77 134.25,179.77 134.55,179.77 134.82,180.04 134.82,180.24 134.82,180.55 135.08,180.81 135.29,180.81 135.59,180.81 135.86,181.08 135.86,181.28 135.86,181.59 136.12,181.86 136.33,181.86 136.63,181.86 136.9,182.12 136.9,182.33 136.9,182.63 137.17,182.9 137.37,182.9 137.68,182.9 137.94,183.16 137.94,183.37 137.94,183.67 138.21,183.94 138.41,183.94 138.72,183.94 138.98,184.21 138.98,184.41 138.98,184.72 139.25,184.98 139.45,184.98 139.76,184.98 140.03,185.25 140.03,185.45 140.03,185.76 140.29,186.02 140.5,186.02 140.8,186.02 141.07,186.29 141.07,186.49 141.07,186.8 141.33,187.07 141.54,187.06 141.84,187.06 142.37,187.59 142.37,188.27 148.05,193.95 168.37,193.95 168.45,193.88 168.54,193.88
MEM_MA_DATA21: length 63.2
  TOP w0.229: U6.E23 v3(130.53,166.68)
  BOTTOM w0.099: 131.2,174.24 131.2,168.75 130.94,168.49 130.94,167.1 v3(130.53,166.68) ; J1.141 173.11,192.11 172.38,192.84 170.77,192.84 170.25,192.31 169.5,192.31 168.46,193.36 168.15,193.36
  BOTTOM w0.229: 131.2,174.24 131.2,175.64 143.03,187.47 143.03,188.15 148.24,193.36 168.15,193.36
MEM_MA_DATA22: length 63.7
  TOP w0.229: v3(133.07,166.68) U6.E25
  BOTTOM w0.099: J1.146 173.71,187.11 171.59,187.11 170.86,187.84 169.02,187.84 ; v3(133.07,166.68) 133.07,167.24 133.63,167.8 133.63,171.18 133.79,171.34
  BOTTOM w0.229: 133.79,171.34 133.79,172.83 138.1,177.14 138.1,177.89 148.05,187.84 148.79,187.84 149.01,188.05 149.01,188.66 149.22,188.88 149.53,188.88 149.75,188.66 149.75,188.05 149.96,187.84 150.27,187.84 150.48,188.05 150.48,188.66 150.7,188.88 151,188.88 151.22,188.66 151.22,188.05 151.43,187.84 151.74,187.84 151.96,188.05 151.96,188.66 152.17,188.88 152.48,188.88 152.69,188.66 152.69,188.05 152.91,187.84 153.21,187.84 153.43,188.05 153.43,188.66 153.64,188.88 153.95,188.88 154.17,188.66 154.17,188.05 154.38,187.84 154.69,187.84 154.9,188.05 154.9,188.66 155.12,188.88 155.42,188.88 155.64,188.66 155.64,188.05 155.85,187.84 156.16,187.84 156.38,188.05 156.38,188.66 156.59,188.88 156.9,188.88 157.11,188.66 157.11,188.05 157.33,187.84 169.02,187.84
MEM_MA_DATA23: length 63.3
  TOP w0.229: v3(133.07,165.41) U6.F25
  BOTTOM w0.099: 169.07,186.75 169.45,186.37 170.73,186.37 171.19,186.84 172.62,186.84 173.35,186.11 J1.147 ; 134.22,171.1 133.9,170.79 133.9,167.71 133.51,167.32 133.51,165.85 v3(133.07,165.41)
  BOTTOM w0.229: 169.07,186.75 168.58,187.25 157.14,187.25 156.5,186.61 156.5,184.3 155.66,183.46 152.92,183.46 151.6,184.78 151.6,185.52 151.29,185.83 149.59,185.83 149.36,186.06 149.36,187.02 149.13,187.25 148.67,187.25 148.45,187.02 148.45,186.06 148.22,185.83 146.82,185.83 138.73,177.74 138.73,176.82 134.22,172.3 134.22,171.1
MEM_MA_DATA24: length 49
  TOP w0.229: v3(135.61,166.68) U6.E27
  BOTTOM w0.099: v3(135.61,166.68) 136.05,167.12 136.05,168.43 136.37,168.75 136.37,169.38 136.85,169.86 137.17,169.86 137.36,170.05 137.36,171.2
  BOTTOM w0.229: J1.30 169.62,182.82 168.74,182.82 168.05,183.51 159.48,183.51 156.77,180.8 155.26,180.8 155.03,180.57 155.03,180.31 154.8,180.09 154.34,180.09 154.11,180.31 154.11,180.57 153.89,180.8 153.43,180.8 153.2,180.57 153.2,180.31 152.97,180.09 152.51,180.09 152.28,180.31 152.28,180.57 152.06,180.8 151.6,180.8 151.37,180.57 151.37,180.31 151.14,180.09 150.68,180.09 150.46,180.31 150.46,180.57 150.23,180.8 149.77,180.8 149.54,180.57 149.54,180.31 149.31,180.09 148.86,180.09 148.63,180.31 148.63,180.57 148.4,180.8 147.66,180.8 142.15,175.28 142.15,173.5 141.12,172.47 138.63,172.47 137.36,171.2
MEM_MA_DATA25: length 46.6
  TOP w0.229: v3(136.88,169.22) U6.C28
  BOTTOM w0.099: 168.79,182.28 171.63,182.28 J1.31 ; v3(136.88,169.22) 137.62,169.96 137.62,170.69 138.31,171.38 138.31,171.38
  BOTTOM w0.229: 138.31,171.38 138.83,171.89 141.01,171.89 142.68,173.57 142.68,175.06 147.17,179.55 147.91,179.55 148.14,179.32 148.14,179.07 148.37,178.84 148.82,178.84 149.05,179.07 149.05,179.32 149.28,179.55 149.74,179.55 149.97,179.32 149.97,179.07 150.19,178.84 150.65,178.84 150.88,179.07 150.88,179.32 151.11,179.55 151.57,179.55 151.79,179.32 151.79,179.07 152.02,178.84 152.48,178.84 152.71,179.07 152.71,179.32 152.94,179.55 153.39,179.55 153.62,179.32 153.62,179.07 153.85,178.84 154.31,178.84 154.54,179.07 154.54,179.32 154.77,179.55 156.4,179.55 159.62,182.78 167.7,182.78 168.2,182.28 168.79,182.28
MEM_MA_DATA26: length 46.8
  TOP w0.229: v3(135.61,165.41) U6.F27
  BOTTOM w0.099: 140.66,167.5 139.58,167.5 138,165.92 136.12,165.92 v3(135.61,165.41)
  BOTTOM w0.229: 140.66,167.5 148.02,174.86 156.38,174.86 158.8,177.27 159.53,177.27 159.76,177.05 159.76,176.4 159.99,176.17 160.45,176.17 160.68,176.4 160.68,177.05 160.91,177.27 161.36,177.27 161.59,177.05 161.59,176.4 161.82,176.17 162.28,176.17 162.51,176.4 162.51,177.05 162.73,177.27 163.19,177.27 163.42,177.05 163.42,176.4 163.65,176.17 164.11,176.17 164.33,176.4 164.33,177.05 164.56,177.27 165.02,177.27 165.25,177.05 165.25,176.4 165.48,176.17 165.93,176.17 166.16,176.4 166.16,177.05 166.39,177.27 169.74,177.27 J1.36
MEM_MA_DATA27: length 47.8
  TOP w0.229: v3(134.34,164.14) U6.G26
  BOTTOM w0.099: 169.22,176.16 171.75,176.16 J1.37 ; v3(134.34,164.14) 135.14,164.94 137.38,164.94 139.45,167.02 140.01,167.02
  BOTTOM w0.229: 169.22,176.16 168.26,176.16 167.74,175.64 167.34,175.64 167.11,175.41 167.11,175.16 166.89,174.93 166.43,174.93 166.2,175.16 166.2,175.41 165.97,175.64 165.51,175.64 165.28,175.41 165.28,175.16 165.06,174.93 164.6,174.93 164.37,175.16 164.37,175.41 164.14,175.64 163.68,175.64 163.46,175.41 163.46,175.16 163.23,174.93 162.77,174.93 162.54,175.16 162.54,175.41 162.31,175.64 161.86,175.64 161.63,175.41 161.63,175.16 161.4,174.93 160.94,174.93 160.71,175.16 160.71,175.41 160.48,175.64 160.03,175.64 159.8,175.41 159.8,175.16 159.57,174.93 159.11,174.93 158.88,175.16 158.88,175.41 158.66,175.64 157.92,175.64 156.6,174.33 148.24,174.33 140.93,167.02 140.01,167.02
MEM_MA_DATA28: length 48.9
  TOP w0.229: U6.C27 v3(135.61,169.22)
  BOTTOM w0.099: J1.149 173.11,184.11 172.38,184.84 171.07,184.84 170.52,184.28 169.36,184.28
  BOTTOM w0.229: 169.36,184.28 169.06,184.57 159.03,184.57 156.33,181.86 147.22,181.86 139.32,173.96 138.69,173.96 137.98,173.25 137.88,173.25 135.61,170.98 v3(135.61,169.22)
MEM_MA_DATA29: length 48.4
  TOP w0.229: v3(135.61,167.95) U6.D27
  BOTTOM w0.099: J1.150 173.71,183.11 171.42,183.11 170.69,183.84 169.48,183.84 169.28,183.64 ; v3(135.61,167.95) 135.61,168.46 136.05,168.91 136.05,169.82
  BOTTOM w0.229: 169.28,183.64 168.96,183.64 168.57,184.04 159.25,184.04 156.55,181.33 147.44,181.33 141.62,175.51 141.62,173.95 140.74,173.08 138.61,173.08 136.05,170.52 136.05,169.82
MEM_MA_DATA30: length 46.8
  TOP w0.229: v3(136.88,166.68) U6.E28
  BOTTOM w0.099: v3(136.88,166.68) 137.49,166.68 138.61,167.8 138.61,168.47 139.05,168.92 139.46,168.92 ; 169.17,178.19 170.5,178.19 171.14,178.84 172.61,178.84 173.34,178.11 J1.155
  BOTTOM w0.229: 169.17,178.19 168.08,179.28 159.29,179.28 155.94,175.93 147.36,175.93 146.87,175.44 146.39,175.44 145.99,175.03 145.99,174.55 145.58,174.15 145.1,174.15 144.69,173.74 144.69,173.26 140.35,168.92 139.46,168.92
MEM_MA_DATA31: length 46.8
  TOP w0.229: v3(138.15,166.68) U6.E29
  BOTTOM w0.099: 140.13,168.51 139.23,168.51 138.94,168.22 138.94,167.32 138.31,166.68 v3(138.15,166.68) ; J1.156 173.71,177.1 171.25,177.1 170.52,177.84 169.4,177.84
  BOTTOM w0.229: 169.4,177.84 169.37,177.81 168.02,177.81 167.79,178.04 167.79,178.33 167.56,178.56 167.1,178.56 166.87,178.33 166.87,178.04 166.65,177.81 166.19,177.81 165.96,178.04 165.96,178.33 165.73,178.56 165.27,178.56 165.05,178.33 165.05,178.04 164.82,177.81 164.36,177.81 164.13,178.04 164.13,178.33 163.9,178.56 163.45,178.56 163.22,178.33 163.22,178.04 162.99,177.81 162.53,177.81 162.3,178.04 162.3,178.33 162.07,178.56 161.62,178.56 161.39,178.33 161.39,178.04 161.16,177.81 160.7,177.81 160.47,178.04 160.47,178.33 160.25,178.56 159.79,178.56 159.56,178.33 159.56,178.04 159.33,177.81 158.58,177.81 156.16,175.39 147.65,175.39 140.77,168.51 140.13,168.51
MEM_MA_DATA32: length 43.9
  TOP w0.229: v3(134.34,138.74) U6.AF27
  BOTTOM w0.099: J1.81 171.63,127.93 170.89,127.93
  BOTTOM w0.102: 168.76,127.93 170.89,127.93 ; 138.75,137.88 138.65,137.98 137.5,137.98 137.19,138.29 135.28,138.29 134.83,138.74 v3(134.34,138.74)
  BOTTOM w0.229: 168.76,127.93 165.96,130.72 156.5,130.72 155.59,131.64 149.3,131.64 147.01,133.92 145.11,133.92 144.88,133.69 144.88,133.39 144.65,133.16 144.19,133.16 143.96,133.39 143.96,133.69 143.73,133.92 143.44,133.92 139.48,137.88 138.75,137.88
MEM_MA_DATA33: length 44.6
  TOP w0.229: v3(138.15,137.47) U6.AG29
  BOTTOM w0.102: v3(138.15,137.47) 138.15,137.44 138.51,137.07 138.9,137.07
  BOTTOM w0.229: 138.9,137.07 139.36,137.07 143.77,132.65 145.39,132.65 145.62,132.88 145.62,133.12 145.85,133.35 146.3,133.35 146.53,133.12 146.53,132.88 146.76,132.65 147.52,132.65 149.11,131.06 155.33,131.06 156.22,130.18 165.45,130.18 165.68,129.95 165.68,129.67 165.45,129.44 162.71,129.44 162.51,129.24 162.51,128.85 162.71,128.65 167.21,128.65 168.75,127.1 J1.82
MEM_MA_DATA34: length 43.8
  TOP w0.229: v3(135.61,136.2) U6.AH27
  BOTTOM w0.099: v3(135.61,136.2) 136.35,135.47 136.35,134.81 137.74,133.41 137.74,132.84 ; 168.67,122.43 168.92,122.43 169.43,121.92 171.62,121.92 J1.87
  BOTTOM w0.229: 168.67,122.43 168.29,122.43 165.56,125.16 161.55,125.16 159.78,126.94 154.25,126.94 153.68,127.51 143.08,127.51 137.74,132.84
MEM_MA_DATA35: length 44.4
  TOP w0.229: v3(135.61,134.93) U6.AJ27
  BOTTOM w0.102: v3(135.61,134.93) 136.22,134.32 136.22,133.41
  BOTTOM w0.229: J1.88 168.72,121.11 165.3,124.52 161.36,124.52 159.59,126.3 152.59,126.3 152.37,126.53 152.37,126.71 152.14,126.94 151.68,126.94 151.45,126.71 151.45,126.53 151.22,126.3 150.77,126.3 150.54,126.53 150.54,126.71 150.31,126.94 149.85,126.94 149.62,126.71 149.62,126.53 149.39,126.3 148.94,126.3 148.71,126.53 148.71,126.71 148.48,126.94 148.02,126.94 147.79,126.71 147.79,126.53 147.56,126.3 147.11,126.3 146.88,126.53 146.88,126.71 146.65,126.94 146.19,126.94 145.96,126.71 145.96,126.53 145.74,126.3 143.33,126.3 136.22,133.41
MEM_MA_DATA36: length 44.8
  TOP w0.229: v3(134.34,140.01) U6.AE26
  BOTTOM w0.099: 168.69,129.96 170.78,129.96 171.44,129.3 173.51,129.3 J1.200
  BOTTOM w0.102: v3(134.34,140.01) 135.08,139.27 137.03,139.27 137.46,138.84 138.67,138.84
  BOTTOM w0.229: 138.67,138.84 139.94,138.84 143.71,135.06 147.46,135.06 149.55,132.97 156.16,132.97 157.31,131.82 166.58,131.82 168.44,129.96 168.69,129.96
MEM_MA_DATA37: length 44.6
  TOP w0.229: v3(136.88,138.74) U6.AF29
  BOTTOM w0.099: 168.54,128.94 169.17,128.31 170.62,128.31 171.25,128.94 172.45,128.94 173.29,128.11 J1.201 ; 137.09,138.59 137.03,138.59 v3(136.88,138.74)
  BOTTOM w0.102: 137.09,138.59 137.99,138.59 138.12,138.47
  BOTTOM w0.229: 168.54,128.94 166.19,131.28 156.89,131.28 155.84,132.33 149.43,132.33 147.27,134.49 143.6,134.49 139.62,138.47 138.12,138.47
MEM_MA_DATA38: length 43.9
  TOP w0.229: v3(138.15,134.93) U6.AJ29
  BOTTOM w0.099: J1.206 173.51,123.3 172.67,123.3
  BOTTOM w0.102: 172.67,123.3 171.2,123.3 170.66,123.84 168.51,123.84 168.2,124.14 168.13,124.14
  BOTTOM w0.229: v3(138.15,134.93) 138.15,134.59 142.89,129.86 143.62,129.86 143.85,129.63 143.85,128.88 144.08,128.65 144.54,128.65 144.77,128.88 144.77,129.63 144.99,129.86 145.43,129.86 145.93,129.35 146.38,129.35 146.89,129.86 147.33,129.86 148.41,128.78 154.76,128.78 155.46,128.08 160.16,128.08 161.81,126.43 165.84,126.43 168.13,124.14
MEM_MA_DATA39: length 45.4
  TOP w0.229: v3(136.88,134.93) U6.AJ28
  BOTTOM w0.102: 168.54,123.25 169.45,122.34 170.65,122.34 171.16,122.84 172.56,122.84 172.95,122.45 173.29,122.11 J1.207
  BOTTOM w0.229: v3(136.88,134.93) 143.73,128.08 154.25,128.08 154.82,127.51 159.97,127.51 161.68,125.79 165.68,125.79 168.1,123.38 168.41,123.38 168.54,123.25
MEM_MA_DATA40: length 62.4
  TOP w0.229: v3(133.07,138.74) U6.AF25
  BOTTOM w0.099: v3(133.07,138.74) 133.6,138.21 133.6,137.95
  BOTTOM w0.102: 134.52,132.74 133.77,133.49 133.77,137.13 133.6,137.29 133.6,137.95
  BOTTOM w0.229: 134.52,132.74 134.52,129.33 139.71,124.14 140.25,124.14 140.48,124.37 140.48,125.12 140.71,125.35 141.17,125.35 141.39,125.12 141.39,124.37 141.62,124.14 142.15,124.14 142.38,123.91 142.38,123.61 142.61,123.38 143.06,123.38 143.29,123.61 143.29,123.91 143.52,124.14 143.98,124.14 144.21,123.91 144.21,123.61 144.44,123.38 144.89,123.38 145.12,123.61 145.12,123.91 145.35,124.14 145.81,124.14 146.04,123.91 146.04,123.61 146.26,123.38 146.72,123.38 146.95,123.61 146.95,123.91 147.18,124.14 147.64,124.14 147.86,123.91 147.86,123.61 148.09,123.38 148.55,123.38 148.78,123.61 148.78,123.91 149.01,124.14 149.46,124.14 149.69,123.91 149.69,123.61 149.92,123.38 150.38,123.38 150.61,123.61 150.61,123.91 150.84,124.14 151.29,124.14 151.52,123.91 151.52,123.61 151.75,123.38 152.21,123.38 152.44,123.61 152.44,123.91 152.66,124.14 153.12,124.14 153.35,123.91 153.35,123.61 153.58,123.38 154.04,123.38 154.27,123.61 154.27,123.91 154.49,124.14 154.95,124.14 155.18,123.91 155.18,123.61 155.41,123.38 155.87,123.38 156.09,123.61 156.09,123.91 156.32,124.14 156.78,124.14 157.01,123.91 157.01,123.61 157.24,123.38 157.69,123.38 157.92,123.61 157.92,123.91 158.15,124.14 158.89,124.14 163.92,119.11 164.66,119.11 164.89,118.88 164.89,118.53 165.12,118.3 165.57,118.3 165.8,118.53 165.8,118.88 166.03,119.11 J1.90
MEM_MA_DATA41: length 62.9
  TOP w0.229: v3(133.07,136.2) U6.AH25
  BOTTOM w0.099: J1.91 171.64,118.27
  BOTTOM w0.102: v3(133.07,136.2) 133.44,136.2 133.52,136.13 133.52,133.07 134.02,132.57 ; 168.54,117.75 169.07,118.27 171.64,118.27
  BOTTOM w0.229: 134.02,132.57 134.02,129.01 134.66,128.36 134.66,128.04 134.29,127.67 134.29,127.34 134.61,127.02 134.94,127.02 135.31,127.39 135.63,127.39 135.96,127.07 135.96,126.75 135.58,126.37 135.58,126.05 135.91,125.73 136.23,125.73 136.6,126.1 136.93,126.1 137.25,125.78 137.25,125.45 136.88,125.08 136.88,124.76 137.2,124.43 137.52,124.43 137.9,124.81 138.22,124.81 140.18,122.85 140.73,122.85 141.14,123.25 141.81,123.25 142.21,122.85 159.3,122.85 159.82,122.32 159.82,122 159.28,121.46 159.28,121.14 159.6,120.82 159.93,120.82 160.46,121.35 160.79,121.35 161.11,121.03 161.11,120.71 160.57,120.17 160.57,119.85 160.9,119.52 161.22,119.52 161.76,120.06 162.08,120.06 162.4,119.74 162.4,119.41 161.87,118.88 161.87,118.55 162.19,118.23 162.51,118.23 163.05,118.77 163.37,118.77 164.48,117.67 166.33,117.67 166.56,117.89 166.56,118.2 166.78,118.43 167.24,118.43 167.47,118.2 167.47,117.89 167.7,117.67 168.46,117.67 168.54,117.75
MEM_MA_DATA42: length 62.3
  TOP w0.229: v3(130.53,137.47) U6.AG23
  BOTTOM w0.102: v3(130.53,137.47) 130.53,134.53 130.76,134.29 130.76,133.69
  BOTTOM w0.229: 130.76,133.69 130.76,132.53 130.44,132.21 130.44,125.98 133.97,122.45 138.13,118.3 157.11,118.3 161.49,113.92 162.31,113.92 162.54,113.69 162.54,113.07 162.77,112.84 163.22,112.84 163.45,113.07 163.45,113.69 163.68,113.92 164.14,113.92 164.37,113.69 164.37,113.07 164.6,112.84 165.05,112.84 165.28,113.07 165.28,113.69 165.51,113.92 165.97,113.92 166.2,113.69 166.2,113.07 166.42,112.84 166.88,112.84 167.11,113.07 167.11,113.69 167.34,113.92 168.1,113.92 168.91,113.1 J1.96
MEM_MA_DATA43: length 63.4
  TOP w0.229: v3(129.26,140.01) U6.AE22
  BOTTOM w0.099: J1.97 171.64,112.27 171.64,112.27
  BOTTOM w0.102: 130.26,133.75 130.26,134.29 130.15,134.4 130.15,137.22 129.85,137.52 129.85,139.42 v3(129.26,140.01) ; 171.64,112.27 168.18,112.27
  BOTTOM w0.229: 130.26,133.75 130.26,132.98 129.8,132.52 129.8,125.78 138.05,117.54 156.86,117.54 162.12,112.27 168.18,112.27
MEM_MA_DATA44: length 62.1
  TOP w0.229: v3(134.34,137.47) U6.AG26
  BOTTOM w0.099: 174.1,120.21 174.42,119.89 175.39,119.89 J1.209
  BOTTOM w0.102: 134.9,134.88 134.9,136.91 v3(134.34,137.47) ; 168.54,120.3 170.54,120.3 171.15,120.91 172.24,120.91 172.94,120.21 174.1,120.21
  BOTTOM w0.229: 134.9,134.88 135.13,134.66 135.52,134.27 135.52,132.72 142.89,125.35 159.33,125.35 161.17,123.51 165.01,123.51 165.24,123.28 165.24,122.97 165.01,122.75 162.99,122.75 162.76,122.52 162.76,122.24 162.99,122.01 166.41,122.01 166.63,121.78 166.63,121.5 166.41,121.27 164.7,121.27 164.48,121.04 164.48,120.76 164.7,120.54 167.99,120.54 168.22,120.3 168.54,120.3
MEM_MA_DATA45: length 62
  TOP w0.229: v3(134.34,134.93) U6.AJ26
  BOTTOM w0.099: J1.210 173.24,119.57 172.6,119.57 172.32,119.28
  BOTTOM w0.102: v3(134.34,134.93) 134.34,134.74 134.83,134.25 ; 169.45,119.93 170.52,119.93 171.17,119.28 172.32,119.28
  BOTTOM w0.229: 134.83,134.25 135.08,134 135.08,132.33 136.26,131.15 136.26,130.83 135.18,129.75 135.18,129.43 135.5,129.11 135.82,129.11 136.9,130.18 137.23,130.18 137.55,129.86 137.55,129.54 136.47,128.46 136.47,128.14 136.79,127.81 137.12,127.81 138.2,128.89 138.52,128.89 138.84,128.57 138.84,128.24 137.76,127.17 137.76,126.84 138.09,126.52 138.41,126.52 139.49,127.6 139.81,127.6 140.14,127.27 140.14,126.95 139.06,125.87 139.06,125.55 139.38,125.23 139.7,125.23 140.78,126.3 141.11,126.3 142.7,124.71 159.21,124.71 164.22,119.7 169.22,119.7 169.45,119.93
MEM_MA_DATA46: length 64.5
  TOP w0.229: v3(130.53,140.01) U6.AE23
  BOTTOM w0.099: J1.215 175.61,114.11
  BOTTOM w0.102: 169.29,114.37 170.71,114.37 171.22,114.88 172.49,114.88 173.26,114.11 175.61,114.11 ; 131.93,133.46 131.93,134.15 131.35,134.72 131.35,139.17 130.53,140 v3(130.53,140.01)
  BOTTOM w0.229: 131.93,133.46 131.93,131.41 131.71,131.19 131.71,126.56 138.63,119.63 157.81,119.63 162.25,115.19 168.48,115.19 169.29,114.37
MEM_MA_DATA47: length 62.1
  TOP w0.229: v3(130.53,138.74) U6.AF23
  BOTTOM w0.102: 131.42,133.92 131.42,134.15 131.04,134.53 131.04,138.22 130.53,138.73 v3(130.53,138.74) ; J1.216 173.05,113.1 172.78,112.84 171.94,112.84 170.87,113.91 168.87,113.91
  BOTTOM w0.229: 168.87,113.91 168.22,114.55 161.81,114.55 157.43,118.94 138.5,118.94 131.07,126.36 131.07,131.76 131.42,132.11 131.42,133.92
MEM_MA_DATA48: length 76.8
  TOP w0.229: v3(127.99,140.01) U6.AE21
  BOTTOM w0.099: 170.75,109.91 171.61,109.91 J1.99
  BOTTOM w0.102: 169.51,109.91 170.75,109.91 ; v3(127.99,140.01) 127.99,139.71 128.55,139.15 128.55,136.92 128.27,136.65 128.27,134.48
  BOTTOM w0.229: 128.27,134.48 127.65,133.86 127.65,124.34 129.54,122.45 136.42,115.57 138.26,113.73 149.71,113.73 149.93,113.5 149.93,113 150.16,112.78 150.62,112.78 150.85,113 150.85,114.16 151.05,114.36 151.56,114.36 151.76,114.16 151.76,113 151.99,112.78 152.45,112.78 152.68,113 152.68,114.16 152.88,114.36 153.39,114.36 153.59,114.16 153.59,113 153.82,112.78 154.28,112.78 154.51,113 154.51,114.16 154.71,114.36 155.22,114.36 155.42,114.16 155.42,113 155.65,112.78 156.11,112.78 156.34,113 156.34,113.5 156.56,113.73 157.3,113.73 161.12,109.91 169.51,109.91
MEM_MA_DATA49: length 75.2
  TOP w0.229: v3(127.99,138.74) U6.AF21
  BOTTOM w0.099: 128.29,137.21 128.29,136.98 127.52,136.21
  BOTTOM w0.102: 128.29,137.21 128.29,138.01 127.99,138.32 v3(127.99,138.74)
  BOTTOM w0.229: J1.100 169.67,109.35 164.66,109.35 164.43,109.12 164.43,108.88 164.2,108.65 163.74,108.65 163.52,108.88 163.52,109.12 163.29,109.35 162.83,109.35 162.6,109.12 162.6,108.88 162.37,108.65 161.92,108.65 161.69,108.88 161.69,109.12 161.46,109.35 160.72,109.35 157.93,112.14 149.74,112.14 149.49,112.39 148.98,112.39 148.73,112.14 148.21,112.14 147.98,112.37 147.98,112.97 147.76,113.2 147.3,113.2 147.07,112.97 147.07,112.37 146.84,112.14 146.38,112.14 146.16,112.37 146.16,112.97 145.93,113.2 145.47,113.2 145.24,112.97 145.24,112.37 145.01,112.14 144.56,112.14 144.33,112.37 144.33,112.97 144.1,113.2 143.64,113.2 143.41,112.97 143.41,112.37 143.18,112.14 142.73,112.14 142.5,112.37 142.5,112.97 142.27,113.2 141.81,113.2 141.58,112.97 141.58,112.37 141.35,112.14 140.9,112.14 140.67,112.37 140.67,112.97 140.44,113.2 139.98,113.2 139.75,112.97 139.75,112.37 139.53,112.14 138.79,112.14 136.4,114.53 127.01,123.92 127.01,134.11 127.52,134.62 127.52,136.21
MEM_MA_DATA50: length 76
  TOP w0.229: v3(122.91,138.74) U6.AF17
  BOTTOM w0.099: 171.81,104.11 J1.105
  BOTTOM w0.102: 168.71,104.2 168.94,103.97 170.75,103.97 170.89,104.11 171.81,104.11 ; 122.5,133.25 122.48,133.27 122.48,138.31 v3(122.91,138.74)
  BOTTOM w0.229: 168.71,104.2 168.71,104.2 166.75,104.2 166.52,103.97 166.52,103.8 166.29,103.57 165.83,103.57 165.61,103.8 165.61,103.97 165.38,104.2 164.92,104.2 164.69,103.97 164.69,103.8 164.46,103.57 164.01,103.57 163.78,103.8 163.78,103.97 163.55,104.2 163.09,104.2 162.86,103.97 162.86,103.8 162.63,103.57 162.18,103.57 161.95,103.8 161.95,103.97 161.72,104.2 160.98,104.2 156.73,108.46 137.49,108.46 123.09,122.85 123.09,132.65 122.5,133.25
MEM_MA_DATA51: length 74.9
  TOP w0.229: v3(122.91,140.01) U6.AE17
  BOTTOM w0.102: 122.15,132.9 122.15,133.42 122.27,133.54 122.27,139.38 v3(122.91,140.01)
  BOTTOM w0.229: 122.15,132.9 122.46,132.6 122.46,122.6 129.49,115.57 133.55,111.51 137.23,107.82 156.54,107.82 161.36,103 166.76,103 167.4,103.63 168.48,103.63 169.11,103 169.8,103 J1.106
MEM_MA_DATA52: length 76.1
  TOP w0.229: v3(129.26,137.47) U6.AG22
  BOTTOM w0.099: J1.218 173.54,111.27 173.54,111.27
  BOTTOM w0.102: 173.54,111.27 171.17,111.27 170.47,111.98 169.24,111.98 168.65,111.38 ; v3(129.26,137.47) 129.26,137.22 129.61,136.87 129.75,136.73 129.75,134.36
  BOTTOM w0.229: 168.65,111.38 161.62,111.38 156.54,116.46 155.8,116.46 155.57,116.23 155.57,115.8 155.34,115.57 154.89,115.57 154.66,115.8 154.66,116.23 154.43,116.46 153.97,116.46 153.74,116.23 153.74,115.8 153.52,115.57 153.06,115.57 152.83,115.8 152.83,116.23 152.6,116.46 152.14,116.46 151.92,116.23 151.92,115.8 151.69,115.57 151.23,115.57 151,115.8 151,116.23 150.77,116.46 150.32,116.46 150.09,116.23 150.09,115.8 149.86,115.57 149.4,115.57 149.17,115.8 149.17,116.23 148.94,116.46 148.49,116.46 148.26,116.23 148.26,115.8 148.03,115.57 147.57,115.57 147.34,115.8 147.34,116.23 147.12,116.46 146.66,116.46 146.43,116.23 146.43,115.8 146.2,115.57 145.74,115.57 145.51,115.8 145.51,116.23 145.29,116.46 144.83,116.46 144.6,116.23 144.6,115.8 144.37,115.57 143.91,115.57 143.69,115.8 143.69,116.23 143.46,116.46 143,116.46 142.77,116.23 142.77,115.8 142.54,115.57 142.09,115.57 141.86,115.8 141.86,116.23 141.63,116.46 141.17,116.46 140.94,116.23 140.94,115.8 140.71,115.57 140.26,115.57 140.03,115.8 140.03,116.23 139.8,116.46 137.65,116.46 128.85,125.26 128.85,133.1 129.75,133.99 129.75,134.36
MEM_MA_DATA53: length 77.2
  TOP w0.229: v3(127.99,141.28) U6.AD21
  BOTTOM w0.099: 128.79,140.27 127.99,141.07 v3(127.99,141.28) ; 128.83,140.23 128.83,139.31 ; 128.28,133.6 128.79,134.11 128.79,135.17 ; 175.61,110.11 J1.219
  BOTTOM w0.102: 128.79,135.17 128.79,135.92 128.61,136.1 128.61,136.48 128.83,136.7 128.83,139.31 ; 175.61,110.11 173.12,110.11 172.28,110.94 171.23,110.94 170.59,110.3 169.59,110.3 169.21,110.68 168.83,110.68 ; 128.79,140.27 128.83,140.23
  BOTTOM w0.229: 168.83,110.68 161.29,110.68 160.47,111.51 156.98,115 149.3,115 149.07,114.77 149.07,114.53 148.85,114.3 148.39,114.3 148.16,114.53 148.16,114.77 147.93,115 147.47,115 147.25,114.77 147.25,114.53 147.02,114.3 146.56,114.3 146.33,114.53 146.33,114.77 146.1,115 145.65,115 145.42,114.77 145.42,114.53 145.19,114.3 144.73,114.3 144.5,114.53 144.5,114.77 144.27,115 143.82,115 143.59,114.77 143.59,114.53 143.36,114.3 142.9,114.3 142.67,114.53 142.67,114.77 142.44,115 141.99,115 141.76,114.77 141.76,114.53 141.53,114.3 141.07,114.3 140.84,114.53 140.84,114.77 140.62,115 140.16,115 139.93,114.77 139.93,114.53 139.7,114.3 139.24,114.3 139.02,114.53 139.02,114.77 138.79,115 138.05,115 128.28,124.77 128.28,133.6
MEM_MA_DATA54: length 76.4
  TOP w0.229: U6.AE18 124.03,141.13 v3(124.18,141.13)
  BOTTOM w0.099: 172.86,105.25 173.57,105.25 J1.224
  BOTTOM w0.102: 168.54,105.51 169.23,105.51 169.56,105.84 170.48,105.84 171.07,105.25 172.86,105.25
  BOTTOM w0.229: v3(124.18,141.13) 123.58,140.53 123.58,133.56 124.36,132.78 124.36,123.36 138.06,109.66 157.11,109.66 161.26,105.51 168.54,105.51
MEM_MA_DATA55: length 75.8
  TOP w0.229: v3(122.91,137.47) U6.AG17
  BOTTOM w0.099: 175.61,104.11 J1.225
  BOTTOM w0.102: 169.27,104.3 169.4,104.3 169.42,104.32 170.5,104.32 171.04,104.86 172.63,104.86 173.38,104.11 175.61,104.11 ; v3(122.91,137.47) 122.91,133.5
  BOTTOM w0.229: 169.27,104.3 168.79,104.78 161.24,104.78 156.92,109.09 137.81,109.09 123.73,123.17 123.73,132.68 122.91,133.5
MEM_MA_DATA56: length 90.7
  TOP w0.229: v3(121.54,140.12) 121.01,140.65 U6.AE16
  BOTTOM w0.102: v3(121.54,140.12) 120.96,139.53 120.96,137.38 120.43,136.85 120.43,132.39 120.55,132.27
  BOTTOM w0.229: J1.108 169.91,101.1 J1.108 ; J1.108 169.12,101.11 168.72,100.71 160.16,100.71 156.47,104.39 150.51,104.39 150.28,104.17 150.28,103.63 150.05,103.4 149.59,103.4 149.36,103.63 149.36,104.17 149.13,104.39 148.68,104.39 148.45,104.17 148.45,103.63 148.22,103.4 147.76,103.4 147.53,103.63 147.53,104.17 147.31,104.39 146.85,104.39 146.62,104.17 146.62,103.63 146.39,103.4 145.93,103.4 145.71,103.63 145.71,104.51 145.5,104.71 144.99,104.71 144.79,104.51 144.79,103.63 144.56,103.4 144.11,103.4 143.88,103.63 143.88,104.51 143.67,104.71 143.17,104.71 142.96,104.51 142.96,103.63 142.73,103.4 142.28,103.4 142.05,103.63 142.05,104.44 141.84,104.65 141.34,104.65 141.13,104.44 141.13,103.63 140.9,103.4 140.45,103.4 140.22,103.63 140.22,104.44 140.02,104.65 139.51,104.65 139.3,104.44 139.3,103.63 139.08,103.4 138.62,103.4 138.39,103.63 138.39,104.17 138.16,104.39 137.42,104.39 120.55,121.27 120.55,132.27
MEM_MA_DATA57: length 88.7
  TOP w0.229: v3(120.37,137.47) U6.AG15
  BOTTOM w0.099: 171.81,100.11 J1.109
  BOTTOM w0.102: 169.43,100.11 171.81,100.11
  BOTTOM w0.229: 169.43,100.11 159.81,100.11 157.05,102.87 156.08,102.87 155.85,103.1 155.85,103.63 155.62,103.86 155.16,103.86 154.93,103.63 154.93,103.1 154.7,102.87 154.25,102.87 154.02,103.1 154.02,103.63 153.79,103.86 153.33,103.86 153.1,103.63 153.1,103.1 152.88,102.87 152.42,102.87 152.19,103.1 152.19,103.63 151.96,103.86 151.5,103.86 151.28,103.63 151.28,103.1 151.05,102.87 138.12,102.87 137.28,103.71 136.96,103.71 136.77,103.53 136.45,103.53 136.13,103.85 136.13,104.17 136.31,104.36 136.31,104.68 135.99,105 135.67,105 135.48,104.82 135.16,104.82 134.83,105.14 134.83,105.47 135.02,105.65 135.02,105.97 134.7,106.3 134.37,106.3 134.19,106.11 133.86,106.11 133.54,106.44 133.54,106.76 133.73,106.94 133.73,107.27 133.4,107.59 133.08,107.59 132.89,107.41 132.57,107.41 132.25,107.73 132.25,108.05 132.43,108.24 132.43,108.56 132.11,108.88 131.79,108.88 131.6,108.7 131.28,108.7 130.95,109.02 130.95,109.35 131.14,109.53 131.14,109.85 130.82,110.18 130.49,110.18 130.31,109.99 129.98,109.99 129.66,110.32 129.66,110.64 129.85,110.82 129.85,111.15 129.52,111.47 129.2,111.47 129.01,111.29 128.69,111.29 128.37,111.61 128.37,111.93 128.55,112.12 128.55,112.44 119.89,121.1 119.89,134.22 120.02,134.35 120.02,137.13 v3(120.37,137.47)
MEM_MA_DATA58: length 88.7
  TOP w0.229: v3(116.56,140.01) U6.AE13
  BOTTOM w0.102: 116.3,134.99 116.3,136.86 116.56,137.12 v3(116.56,140.01)
  BOTTOM w0.229: J1.114 159.92,95.11 159.4,95.63 159.08,95.63 158.67,95.22 158.35,95.22 158.02,95.54 158.02,95.87 158.43,96.27 158.43,96.6 158.11,96.92 157.78,96.92 157.38,96.51 157.05,96.51 156.73,96.84 156.73,97.16 157.14,97.57 157.14,97.89 155.59,99.44 135.58,99.44 116.3,118.73 116.3,134.99
MEM_MA_DATA59: length 90.2
  TOP w0.229: v3(116.56,141.28) U6.AD13
  BOTTOM w0.102: 115.66,136.75 115.66,137.13 116.08,137.55 116.08,140.5 116.56,140.97 v3(116.56,141.28)
  BOTTOM w0.229: 115.66,136.75 115.66,118.6 135.46,98.81 153.93,98.81 158.51,94.23 171.68,94.23 J1.115
MEM_MA_DATA60: length 88.6
  TOP w0.229: v3(122.91,141.28) U6.AD17
  BOTTOM w0.102: v3(122.91,141.28) 122.05,140.43 122.05,135.47 121.19,134.61 121.19,133.11 121.82,132.47 ; J1.227 172.95,102.11 172.22,102.84 171.16,102.84 170.65,102.32 168.45,102.32
  BOTTOM w0.229: 121.82,132.47 121.82,121.71 127.96,115.57 132.03,111.51 136.79,106.74 137.53,106.74 137.76,106.51 137.76,106.15 137.98,105.92 138.44,105.92 138.67,106.15 138.67,106.51 138.9,106.74 139.36,106.74 139.58,106.51 139.58,106.15 139.81,105.92 140.27,105.92 140.5,106.15 140.5,106.51 140.73,106.74 141.18,106.74 141.41,106.51 141.41,106.15 141.64,105.92 142.1,105.92 142.33,106.15 142.33,106.51 142.56,106.74 143.01,106.74 143.24,106.51 143.24,106.15 143.47,105.92 143.93,105.92 144.16,106.15 144.16,106.51 144.38,106.74 155.97,106.74 160.86,101.85 167.98,101.85 168.45,102.32
MEM_MA_DATA61: length 89.4
  TOP w0.229: U6.AG16 121,138.09 v3(121.54,137.55)
  BOTTOM w0.102: 169.01,101.91 170.64,101.91 171.44,101.11 J1.228 ; 120.81,132.73 120.81,136.82 v3(121.54,137.55)
  BOTTOM w0.229: 169.01,101.91 168.38,101.28 160.54,101.28 156.54,105.28 155.51,105.28 155.29,105.51 155.29,105.98 155.06,106.21 154.6,106.21 154.37,105.98 154.37,105.17 154.17,104.97 153.66,104.97 153.46,105.17 153.46,105.98 153.23,106.21 152.77,106.21 152.54,105.98 152.54,105.23 152.34,105.03 151.83,105.03 151.63,105.23 151.63,105.98 151.4,106.21 150.94,106.21 150.71,105.98 150.71,105.23 150.51,105.03 150,105.03 149.8,105.23 149.8,105.98 149.57,106.21 149.11,106.21 148.88,105.98 148.88,105.23 148.68,105.03 148.17,105.03 147.97,105.23 147.97,105.98 147.74,106.21 147.28,106.21 147.06,105.98 147.06,105.3 146.85,105.09 146.34,105.09 146.14,105.3 146.14,105.98 145.91,106.21 145.46,106.21 145.23,105.98 145.23,105.51 145,105.28 137.42,105.28 121.19,121.52 121.19,132.35 120.81,132.73
MEM_MA_DATA62: length 88.5
  TOP w0.229: v3(117.83,137.47) U6.AG14
  BOTTOM w0.099: 175.61,96.11 J1.233
  BOTTOM w0.102: 168.71,96.32 170.65,96.32 171.2,96.86 172.5,96.86 173.26,96.11 175.61,96.11 ; 117.57,135.57 117.38,135.76 117.38,136.59 117.83,137.04 v3(117.83,137.47)
  BOTTOM w0.229: 168.71,96.32 168,97.03 167.26,97.03 166.88,96.65 166.35,96.65 165.97,97.03 165.44,97.03 165.05,96.65 164.52,96.65 164.14,97.03 163.61,97.03 163.23,96.65 162.69,96.65 162.31,97.03 159.71,97.03 156.16,100.58 136.15,100.58 117.57,119.17 117.57,135.57
MEM_MA_DATA63: length 89
  TOP w0.229: v3(117.83,140.01) U6.AE14
  BOTTOM w0.102: v3(117.83,140.01) 117.18,139.36 117.18,137.1 116.93,136.85 116.93,135.14 ; 169.01,95.76 169.1,95.85 170.55,95.85 171.29,95.11 J1.234
  BOTTOM w0.229: 169.01,95.76 160.16,95.76 155.9,100.01 135.9,100.01 116.93,118.98 116.93,135.14
MEM_MA_DM0: length 95.8
  TOP w0.229: v3(120.37,162.87) U6.H15
  BOTTOM w0.099: 169.32,208.2 170.45,208.2 171.24,208.99 172.13,208.99 173.01,208.1 175.61,208.1 J1.125 ; v3(120.37,162.87) 119.54,163.7 119.54,164.15
  BOTTOM w0.102: 119.54,164.15 119.54,165.67 119.44,165.77 118.9,166.3 118.9,167.29 118.5,167.69
  BOTTOM w0.229: 118.5,167.69 118.5,172.72 119.39,173.61 119.39,188.25 138.92,207.78 142.59,207.78 145.38,210.57 155.8,210.57 156.82,209.55 157.56,209.55 157.78,209.77 157.78,209.79 157.99,210.01 158.3,210.01 158.51,209.79 158.51,209.77 158.73,209.55 159.03,209.55 159.25,209.77 159.25,209.79 159.47,210.01 159.77,210.01 159.99,209.79 159.99,209.77 160.2,209.55 160.51,209.55 160.72,209.77 160.72,209.79 160.94,210.01 161.24,210.01 161.46,209.79 161.46,209.77 161.68,209.55 167.3,209.55 168.66,208.2 169.32,208.2
MEM_MA_DM1: length 82.4
  TOP w0.102: U6.E18 123.54,166.22 v3(123.93,166.61)
  BOTTOM w0.099: 124.26,171.2 125.04,171.2 126.24,172.39 ; J1.134 173.35,199.47 172.84,199.47 172.48,199.11 171.59,199.11 170.86,199.84 169.27,199.84
  BOTTOM w0.102: v3(123.93,166.61) 123.6,166.94 123.6,170.54 124.26,171.2
  BOTTOM w0.229: 169.27,199.84 169.14,199.71 165.94,199.71 164.56,201.08 160.5,201.08 159.94,200.51 147.89,200.51 147.02,199.64 144.61,199.64 144.08,199.12 143.78,199.12 143.72,199.18 143.41,199.18 143.2,198.97 143.2,198.66 143.26,198.6 143.26,198.3 143.04,198.08 142.74,198.08 142.68,198.14 142.37,198.14 142.16,197.93 142.16,197.62 142.22,197.56 142.22,197.25 142,197.04 141.7,197.04 141.63,197.1 141.33,197.1 141.11,196.88 141.11,196.58 141.17,196.52 141.17,196.21 140.96,196 140.65,196 140.59,196.06 140.29,196.06 140.07,195.84 140.07,195.54 140.13,195.48 140.13,195.17 139.92,194.95 139.61,194.95 139.55,195.02 139.25,195.02 139.03,194.8 139.03,194.49 139.09,194.43 139.09,194.13 138.87,193.91 138.57,193.91 138.51,193.97 138.2,193.97 137.99,193.76 137.99,193.45 138.05,193.39 138.05,193.09 137.83,192.87 137.53,192.87 137.47,192.93 137.16,192.93 136.95,192.72 136.95,192.41 137.01,192.35 137.01,192.05 136.79,191.83 136.49,191.83 136.42,191.89 136.12,191.89 135.9,191.67 135.9,191.37 135.96,191.31 135.96,191 135.75,190.79 135.44,190.79 135.38,190.85 135.08,190.85 134.86,190.63 134.86,190.33 134.92,190.27 134.92,189.96 134.71,189.75 134.4,189.75 134.34,189.81 134.04,189.81 133.82,189.59 133.82,189.29 133.88,189.22 133.88,188.92 133.66,188.7 133.36,188.7 133.3,188.76 132.99,188.76 132.78,188.55 132.78,188.24 132.84,188.18 132.84,187.88 132.62,187.66 132.32,187.66 132.26,187.72 131.95,187.72 131.74,187.51 131.74,187.2 131.8,187.14 131.8,186.84 131.58,186.62 131.28,186.62 131.22,186.68 130.91,186.68 130.69,186.46 130.69,186.16 130.76,186.1 130.76,185.79 130.54,185.58 130.23,185.58 130.17,185.64 129.87,185.64 129.65,185.42 129.65,185.12 129.71,185.06 129.71,184.75 129.5,184.54 129.19,184.54 129.13,184.6 128.83,184.6 128.61,184.38 128.61,184.08 128.67,184.01 128.67,183.71 128.46,183.49 128.15,183.49 128.09,183.55 127.78,183.55 127.57,183.34 127.57,183.03 127.63,182.97 127.63,182.67 126.24,181.28 126.24,172.39
MEM_MA_DM2: length 63.7
  TOP w0.229: v3(131.8,166.68) U6.E24
  BOTTOM w0.099: J1.143 175.61,190.11 173.15,190.11 172.29,189.24 171.25,189.24 170.63,189.85 169.07,189.85 ; v3(131.8,166.68) 132.34,167.22 132.34,169.63 132.75,170.04 132.75,173.82 133.11,174.18
  BOTTOM w0.229: 169.07,189.85 165.23,189.85 163.57,191.52 157.03,191.52 155.9,190.39 155.17,190.39 154.95,190.61 154.95,190.84 154.74,191.05 154.43,191.05 154.21,190.84 154.21,190.61 154,190.39 153.69,190.39 153.48,190.61 153.48,190.84 153.26,191.05 152.96,191.05 152.74,190.84 152.74,190.61 152.53,190.39 152.22,190.39 152,190.61 152,190.84 151.79,191.05 151.48,191.05 151.27,190.84 151.27,190.61 151.05,190.39 150.75,190.39 150.53,190.61 150.53,190.84 150.32,191.05 150.01,191.05 149.79,190.84 149.79,190.61 149.58,190.39 148.48,190.39 136.27,178.18 136.27,177.56 133.11,174.4 133.11,174.18
MEM_MA_DM3: length 47.8
  TOP w0.229: v3(138.15,170.49) U6.B29
  BOTTOM w0.099: J1.152 171.44,181.11 170.65,181.89 169.38,181.89
  BOTTOM w0.229: 169.38,181.89 168.87,181.39 168,181.39 167.22,182.17 160.03,182.17 156.17,178.31 154.32,178.31 154.09,178.08 154.09,177.65 153.86,177.42 153.4,177.42 153.17,177.65 153.17,178.08 152.94,178.31 152.49,178.31 152.26,178.08 152.26,177.65 152.03,177.42 151.57,177.42 151.34,177.65 151.34,178.08 151.12,178.31 150.66,178.31 150.43,178.08 150.43,177.65 150.2,177.42 149.74,177.42 149.52,177.65 149.52,178.08 149.29,178.31 148.83,178.31 148.6,178.08 148.6,177.65 148.37,177.42 147.92,177.42 147.69,177.65 147.69,178.08 147.46,178.31 146.72,178.31 143.22,174.8 143.22,173.63 140.94,171.36 138.99,171.36 138.16,170.52 138.16,170.5 v3(138.15,170.49)
MEM_MA_DM4: length 44.1
  TOP w0.229: v3(138.15,136.2) U6.AH29
  BOTTOM w0.099: J1.203 175.61,126.11
  BOTTOM w0.102: v3(138.15,136.2) 138.74,136.2 139.4,135.55 140.06,135.55 ; 175.61,126.11 173.27,126.11 172.39,125.23 171.31,125.23 170.43,126.1
  BOTTOM w0.229: 170.43,126.1 168.93,126.1 166.95,128.08 162.41,128.08 160.89,129.6 156.03,129.6 155.14,130.49 148.92,130.49 147.33,132.08 146.47,132.08 146.24,131.85 146.24,131.61 146.01,131.38 145.55,131.38 145.32,131.61 145.32,131.85 145.1,132.08 143.52,132.08 140.06,135.55
MEM_MA_DM5: length 63.4
  TOP w0.229: v3(133.07,134.93) U6.AJ25
  BOTTOM w0.102: J1.212 171.34,117.1 170.51,117.94 169.67,117.94 168.9,117.17 ; v3(133.07,134.93) 133.07,132.79 133.43,132.43
  BOTTOM w0.229: 168.9,117.17 168.64,116.9 162.76,116.9 158.51,121.16 157.21,121.16 156.98,121.39 156.98,122.08 156.75,122.31 156.3,122.31 156.07,122.08 156.07,121.39 155.84,121.16 155.38,121.16 155.15,121.39 155.15,122.08 154.93,122.31 154.47,122.31 154.24,122.08 154.24,121.39 154.01,121.16 153.55,121.16 153.33,121.39 153.33,122.08 153.1,122.31 152.64,122.31 152.41,122.08 152.41,121.39 152.18,121.16 151.73,121.16 151.5,121.39 151.5,122.08 151.27,122.31 150.81,122.31 150.58,122.08 150.58,121.39 150.35,121.16 149.62,121.16 148.64,122.13 141.2,122.13 140.73,121.67 138.82,121.67 138.31,122.18 138.31,122.5 138.78,122.97 138.78,123.3 138.46,123.62 138.13,123.62 137.66,123.15 137.34,123.15 133.43,127.06 133.43,132.43
MEM_MA_DM6: length 75.2
  TOP w0.229: v3(125.45,138.74) U6.AF19
  BOTTOM w0.099: J1.221 175.61,108.1 173.96,108.1
  BOTTOM w0.102: 173.96,108.1 173.04,108.1 172.07,109.08 171.4,109.08 170.45,108.12 169.97,108.12
  BOTTOM w0.229: 169.97,108.12 168.23,108.12 168,108.35 168,108.58 167.77,108.81 167.31,108.81 167.08,108.58 167.08,108.35 166.86,108.12 166.4,108.12 166.17,108.35 166.17,108.58 165.94,108.81 165.48,108.81 165.26,108.58 165.26,108.35 165.03,108.12 160.99,108.12 157.54,111.57 142.24,111.57 141.92,111.25 141.32,111.25 141.01,111.57 140.41,111.57 140.09,111.25 139.5,111.25 139.18,111.57 138.44,111.57 126.38,123.63 126.38,133.22 126.06,133.54 126.06,136.95 125.3,137.7 125.3,138.6 v3(125.45,138.74)
MEM_MA_DM7: length 90.4
  TOP w0.229: v3(120.37,138.74) U6.AF15
  BOTTOM w0.099: 173.71,99.11 J1.230
  BOTTOM w0.102: v3(120.37,138.74) 120.37,138.69 119.61,137.93 119.61,134.7 119.26,134.35 ; 168.74,98.8 169.1,98.44 169.12,98.44 169.19,98.36 170.7,98.36 171.44,99.11 173.71,99.11
  BOTTOM w0.229: 168.74,98.8 168.03,99.5 159.59,99.5 156.86,102.23 136.85,102.23 127.39,111.7 127.39,112.03 127.63,112.27 127.63,112.6 127.31,112.92 126.99,112.92 126.74,112.67 126.42,112.67 126.09,113 126.09,113.32 126.34,113.57 126.34,113.89 126.02,114.21 125.69,114.21 125.45,113.97 125.12,113.97 124.8,114.29 124.8,114.61 125.05,114.86 125.05,115.18 124.72,115.51 124.4,115.51 124.15,115.26 123.83,115.26 123.51,115.58 123.51,115.91 123.75,116.15 123.75,116.48 123.43,116.8 123.11,116.8 122.86,116.55 122.54,116.55 122.21,116.88 122.21,117.2 122.46,117.45 122.46,117.77 122.14,118.09 121.81,118.09 121.57,117.85 121.24,117.85 120.92,118.17 120.92,118.49 121.17,118.74 121.17,119.06 120.84,119.39 120.52,119.39 120.27,119.14 119.95,119.14 119.26,119.83 119.26,134.35
MEM_MA_DM8: length 48.3
  TOP w0.229: U6.J25 132.5,160.97 133.17,161.63 v3(133.22,161.63)
  BOTTOM w0.099: 140.85,164.5 140.39,164.5 138.28,162.39 136.3,162.39 135.95,162.04 133.63,162.04 v3(133.22,161.63) ; J1.161 175.61,172.1 173.11,172.1 172.38,171.37 171.21,171.37 170.62,171.97 169.52,171.97
  BOTTOM w0.229: 169.52,171.97 167.34,169.79 161.42,169.79 160.97,169.34 147.08,169.34 142.24,164.5 140.85,164.5
MEM_MA_DQS0_N: length 96.2
  TOP w0.125: v3(120.37,164.14) U6.G15
  BOTTOM w0.13: J1.6 169.91,206.92 169.71,206.73 169.06,206.73 166.88,208.9 155.84,208.9 155.71,209.03 155.71,209.67 155.42,209.96 154.82,209.96 154.53,209.67 154.53,209.03 154.4,208.9 154.02,208.9 153.89,209.03 153.89,209.67 153.6,209.96 153,209.96 152.71,209.67 152.71,209.03 152.58,208.9 152.2,208.9 152.07,209.03 152.07,209.67 151.78,209.96 151.18,209.96 150.89,209.67 150.89,209.03 150.76,208.9 150.38,208.9 150.25,209.03 150.25,209.67 149.96,209.96 149.36,209.96 149.07,209.67 149.07,208.94 148.88,208.75 148.62,208.75 148.43,208.94 148.43,209.67 148.14,209.96 147.54,209.96 147.25,209.67 147.25,209 147.07,208.81 146.8,208.81 146.61,209 146.61,209.63 146.27,209.97 145.78,209.97 145.43,209.63 145.43,207.82 144.75,207.14 139.19,207.14 120,187.94 120,173.32 118.99,172.31 118.99,170.39 119.61,169.77 119.61,166.33 119.84,166.11 119.84,165.29 120.47,164.66 120.47,164.24 v3(120.37,164.14)
MEM_MA_DQS0_P: length 96.2
  TOP w0.125: v3(120.37,165.41) U6.F15
  BOTTOM w0.13: v3(120.37,165.41) 120.21,165.41 120.11,165.52 120.11,166.22 119.89,166.45 119.89,169.89 119.27,170.51 119.27,172.2 120.27,173.2 120.27,187.83 139.3,206.87 144.86,206.87 145.71,207.71 145.71,209.52 145.89,209.7 146.16,209.7 146.34,209.52 146.34,208.88 146.69,208.54 147.18,208.54 147.52,208.88 147.52,209.56 147.65,209.68 148.03,209.68 148.16,209.56 148.16,208.83 148.51,208.48 149,208.48 149.34,208.83 149.34,209.56 149.47,209.68 149.85,209.68 149.98,209.56 149.98,208.92 150.27,208.63 150.87,208.63 151.16,208.92 151.16,209.56 151.29,209.68 151.67,209.68 151.8,209.56 151.8,208.92 152.09,208.63 152.69,208.63 152.98,208.92 152.98,209.56 153.11,209.68 153.49,209.68 153.62,209.56 153.62,208.92 153.91,208.63 154.51,208.63 154.8,208.92 154.8,209.56 154.93,209.68 155.31,209.68 155.44,209.56 155.44,208.92 155.72,208.63 166.77,208.63 168.95,206.46 169.51,206.46 169.6,206.36 171.55,206.36 171.81,206.11 J1.7
MEM_MA_DQS1_N: length 83.1
  TOP w0.125: U6.F19 v3(125.45,165.41)
  BOTTOM w0.13: J1.15 170.61,198.11 170.38,198.33 169.23,198.33 168.57,198.99 163.99,198.99 163.86,199.12 163.86,200.09 163.51,200.44 163.02,200.44 162.68,200.09 162.68,199.12 162.55,198.99 162.17,198.99 162.04,199.12 162.04,200.06 161.69,200.41 161.2,200.41 160.86,200.06 160.86,199.12 160.73,198.99 160.35,198.99 160.22,199.12 160.22,199.5 159.93,199.78 159.33,199.78 159.04,199.5 159.04,199.12 158.91,198.99 158.53,198.99 158.4,199.12 158.4,199.5 158.11,199.78 157.51,199.78 157.22,199.5 157.22,199.12 157.09,198.99 156.71,198.99 156.58,199.12 156.58,199.5 156.29,199.78 155.69,199.78 155.4,199.5 155.4,199.12 155.27,198.99 154.89,198.99 154.76,199.12 154.76,199.5 154.48,199.78 153.87,199.78 153.58,199.5 153.58,199.12 153.45,198.99 153.07,198.99 152.95,199.12 152.95,199.5 152.66,199.78 152.05,199.78 151.76,199.5 151.76,199.12 151.63,198.99 151.26,198.99 151.13,199.12 151.13,199.5 150.84,199.78 150.23,199.78 149.95,199.5 149.95,199.12 149.82,198.99 149.44,198.99 149.31,199.12 149.31,199.5 149.02,199.78 148.42,199.78 148.13,199.5 148.13,199.12 148,198.99 144.91,198.99 126.91,180.99 126.91,171.27 125.9,170.25 125.43,170.25 124.85,169.66 124.85,167.38 124.7,167.24 124.7,166.08 125.17,165.62 125.25,165.62 v3(125.45,165.41)
MEM_MA_DQS1_P: length 83.2
  TOP w0.125: U6.E19 124.81,166.09 125.4,166.68 v3(125.45,166.68)
  BOTTOM w0.13: v3(125.45,166.68) 125.74,166.68 125.84,166.58 125.84,165.99 125.74,165.89 125.28,165.89 124.98,166.19 124.98,167.13 125.12,167.27 125.12,169.55 125.55,169.98 126.01,169.98 127.19,171.16 127.19,180.87 145.03,198.71 148.11,198.71 148.4,199 148.4,199.38 148.53,199.51 148.91,199.51 149.04,199.38 149.04,199 149.32,198.71 149.93,198.71 150.22,199 150.22,199.38 150.35,199.51 150.73,199.51 150.85,199.38 150.85,199 151.14,198.71 151.75,198.71 152.04,199 152.04,199.38 152.17,199.51 152.54,199.51 152.67,199.38 152.67,199 152.96,198.71 153.57,198.71 153.85,199 153.85,199.38 153.98,199.51 154.36,199.51 154.49,199.38 154.49,199 154.78,198.71 155.38,198.71 155.67,199 155.67,199.38 155.8,199.51 156.18,199.51 156.31,199.38 156.31,199 156.6,198.71 157.2,198.71 157.49,199 157.49,199.38 157.62,199.51 158,199.51 158.13,199.38 158.13,199 158.42,198.71 159.02,198.71 159.31,199 159.31,199.38 159.44,199.51 159.82,199.51 159.95,199.38 159.95,199 160.24,198.71 160.84,198.71 161.13,199 161.13,199.95 161.32,200.13 161.58,200.13 161.77,199.95 161.77,199 162.06,198.71 162.66,198.71 162.95,199 162.95,199.98 163.13,200.16 163.4,200.16 163.59,199.98 163.59,199 163.87,198.71 168.46,198.71 169.12,198.05 170.27,198.05 170.41,197.92 170.41,197.6 J1.16
MEM_MA_DQS2_N: length 64.2
  TOP w0.125: v3(133.07,167.95) U6.D25
  BOTTOM w0.13: J1.24 169.91,188.74 169.7,188.53 169.1,188.53 168.64,188.99 158.35,188.99 158.15,189.2 158.15,189.46 158.33,189.65 163.37,189.65 163.68,189.96 163.68,190.57 163.42,190.83 157.25,190.83 156.16,189.74 148.67,189.74 137.12,178.19 137.12,177.48 133.06,173.42 133.06,169.86 132.62,169.43 132.62,168.99 133.07,168.55 v3(133.07,167.95)
MEM_MA_DQS2_P: length 64.3
  TOP w0.125: v3(133.07,169.22) U6.C25
  BOTTOM w0.13: v3(133.07,169.22) 133.07,169.46 133.33,169.72 133.33,173.3 137.39,177.36 137.39,178.07 148.79,189.47 156.28,189.47 157.36,190.56 163.3,190.56 163.41,190.45 163.41,190.08 163.25,189.92 158.22,189.92 157.87,189.58 157.87,189.09 158.24,188.72 168.52,188.72 168.99,188.26 170.18,188.26 170.72,188.8 171.31,188.8 171.81,188.3 J1.25
MEM_MA_DQS3_N: length 47.7
  TOP w0.125: v3(138.15,169.22) U6.C29
  BOTTOM w0.13: J1.33 171.81,179.91 171.43,179.53 171.17,179.53 170.47,180.23 168.32,180.23 166.97,181.58 166.01,181.58 165.72,181.29 165.72,180.29 165.57,180.14 165.23,180.14 165.08,180.29 165.08,181.29 164.79,181.58 164.18,181.58 163.89,181.29 163.89,180.39 163.74,180.24 163.4,180.24 163.24,180.39 163.24,181.29 162.96,181.58 162.34,181.58 162.06,181.29 162.06,180.67 161.93,180.54 161.54,180.54 161.41,180.67 161.41,181.29 161.12,181.58 160.39,181.58 155.59,176.78 146.03,176.78 143.8,174.56 143.8,173.44 141.2,170.83 140.79,170.83 139.84,169.89 139.13,169.89 138.46,169.22 v3(138.15,169.22)
MEM_MA_DQS3_P: length 47.7
  TOP w0.125: v3(138.15,167.95) U6.D29
  BOTTOM w0.13: J1.34 170.28,179.11 170.52,179.34 170.52,179.8 170.36,179.95 168.21,179.95 166.85,181.31 166.12,181.31 165.99,181.18 165.99,180.18 165.68,179.87 165.12,179.87 164.81,180.18 164.81,181.18 164.68,181.31 164.29,181.31 164.16,181.18 164.16,180.28 163.85,179.97 163.28,179.97 162.97,180.28 162.97,181.18 162.84,181.31 162.46,181.31 162.33,181.18 162.33,180.55 162.04,180.26 161.43,180.26 161.14,180.55 161.14,181.18 161.01,181.31 160.5,181.31 155.7,176.51 146.14,176.51 144.07,174.45 144.07,173.32 141.31,170.56 140.9,170.56 139.96,169.62 139.25,169.62 138.15,168.51 v3(138.15,167.95)
MEM_MA_DQS4_N: length 45.1
  TOP w0.125: v3(136.88,137.47) U6.AG28
  BOTTOM w0.13: J1.84 170.25,124.76 170.25,124.59 170.06,124.4 169.11,124.4 166.07,127.44 162.13,127.44 160.6,128.97 155.83,128.97 155.13,129.67 148.79,129.67 147.71,130.75 144.28,130.75 143.59,131.44 143.19,131.44 143.1,131.35 142.92,131.35 142.74,131.54 142.74,131.72 142.82,131.8 142.82,132.21 142.48,132.55 142.07,132.55 141.98,132.47 141.8,132.47 141.62,132.65 141.62,132.84 141.7,132.92 141.7,133.33 141.36,133.67 140.95,133.67 140.87,133.59 140.68,133.59 140.5,133.77 140.5,133.95 140.58,134.04 140.58,134.44 139.95,135.08 139.25,135.08 138.62,135.72 137.86,135.72 137.7,135.88 137.7,136.54 137.32,136.92 136.27,136.92 136.06,137.13 136.06,137.76 136.18,137.89 136.79,137.89 136.88,137.8 v3(136.88,137.47)
MEM_MA_DQS4_P: length 45
  TOP w0.125: v3(135.61,137.47) U6.AG27
  BOTTOM w0.13: J1.85 171.7,124.22 170.27,124.22 170.18,124.12 169,124.12 165.95,127.17 162.01,127.17 160.49,128.7 155.71,128.7 155.01,129.4 148.68,129.4 147.6,130.47 144.17,130.47 143.48,131.16 143.3,131.16 143.21,131.08 142.81,131.08 142.46,131.42 142.46,131.83 142.55,131.91 142.55,132.1 142.36,132.28 142.18,132.28 142.1,132.2 141.69,132.2 141.35,132.54 141.35,132.95 141.43,133.03 141.43,133.21 141.25,133.4 141.06,133.4 140.98,133.31 140.57,133.31 140.23,133.66 140.23,134.07 140.31,134.15 140.31,134.33 139.83,134.81 139.14,134.81 138.5,135.45 137.74,135.45 137.42,135.76 137.42,136.43 137.2,136.65 136.15,136.65 135.77,137.04 135.77,137.32 v3(135.61,137.47)
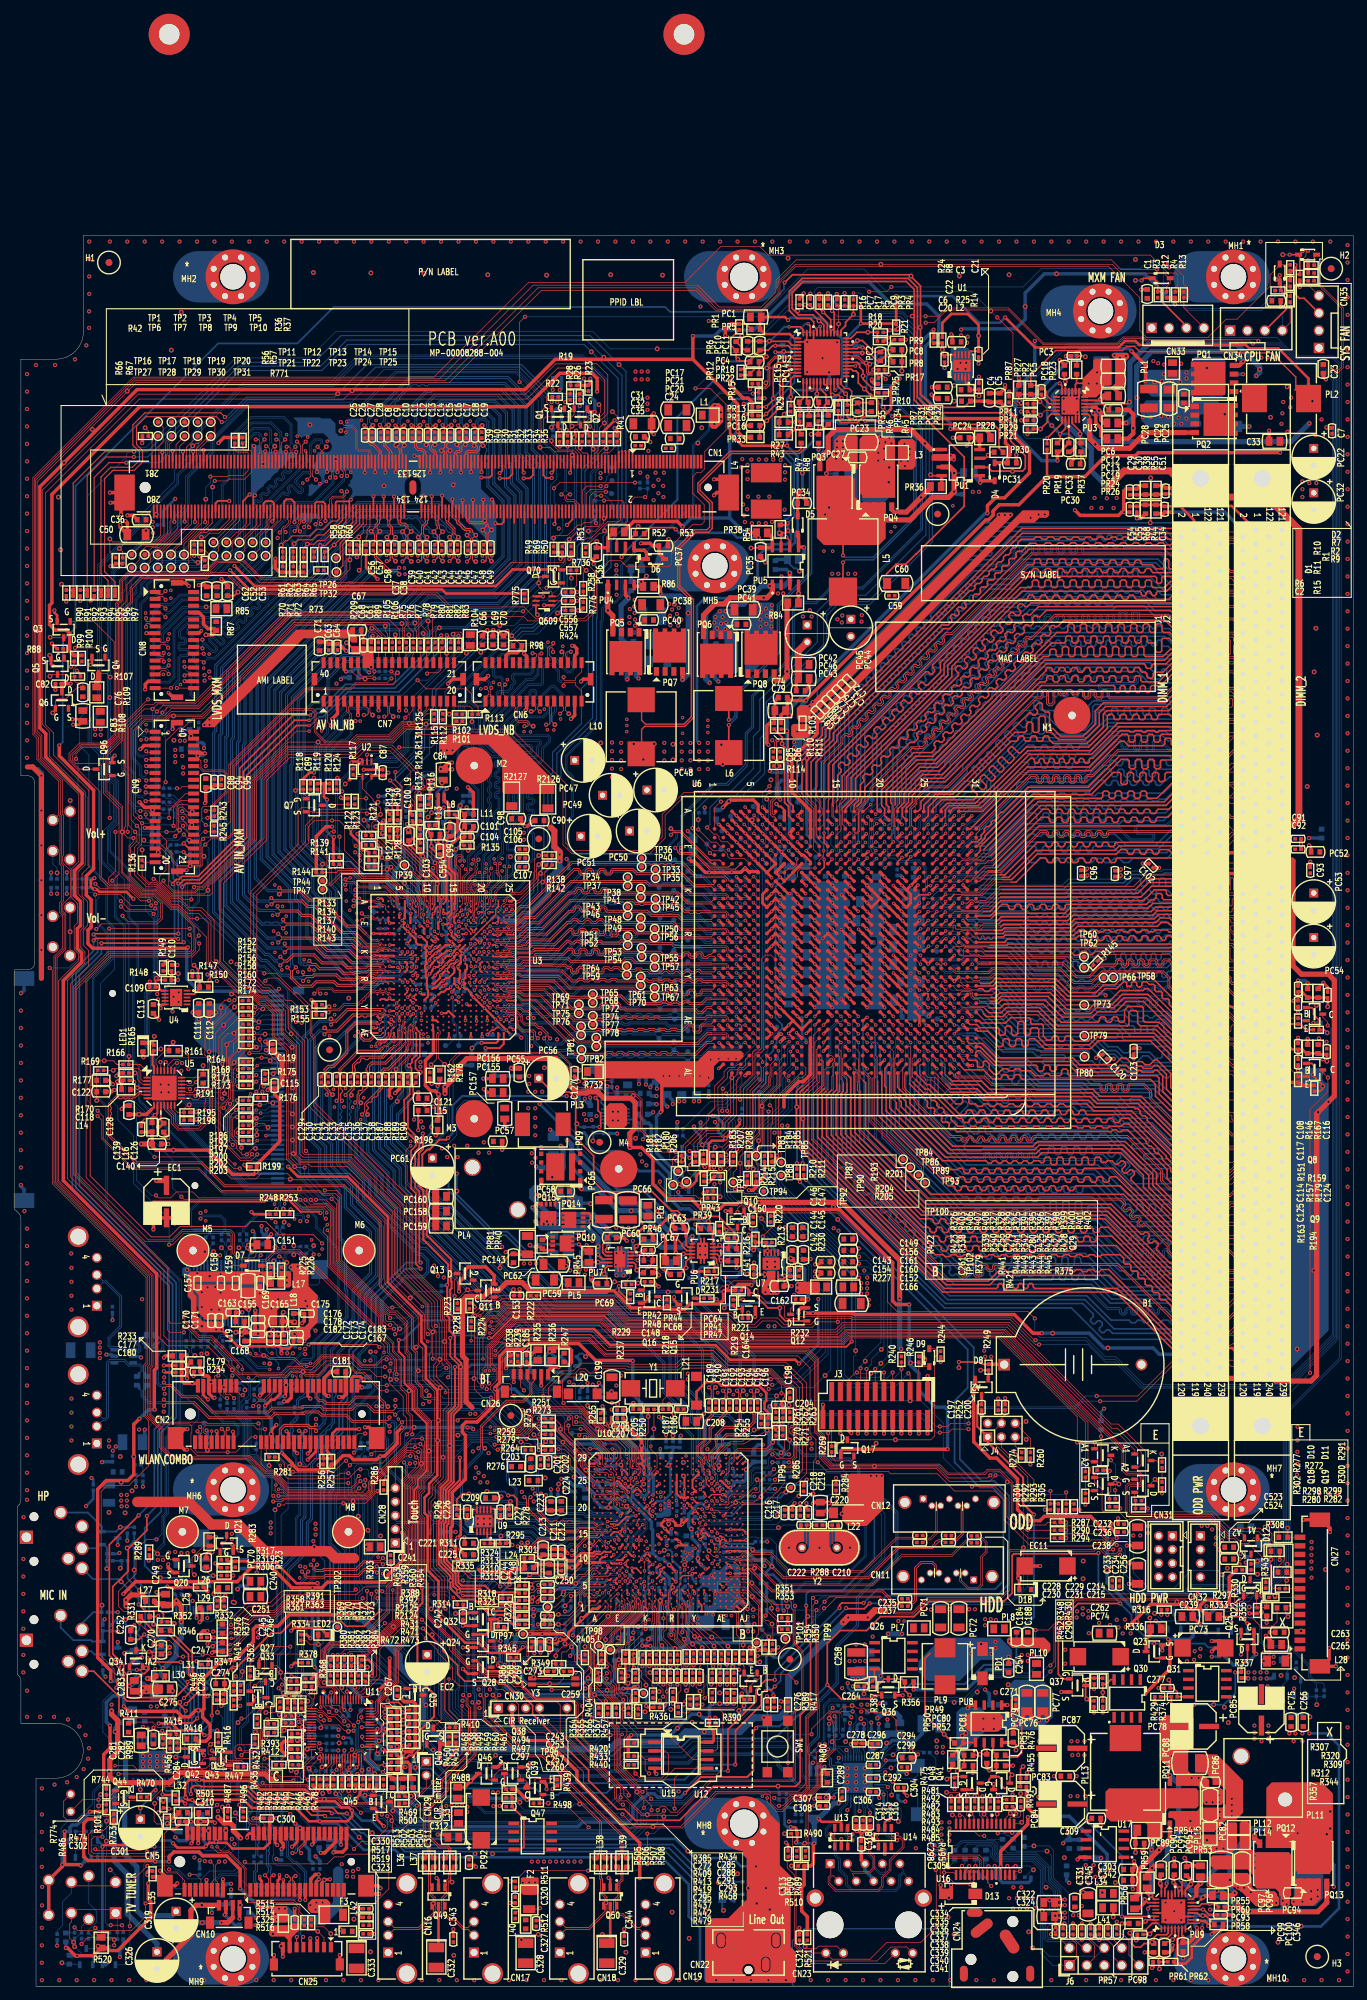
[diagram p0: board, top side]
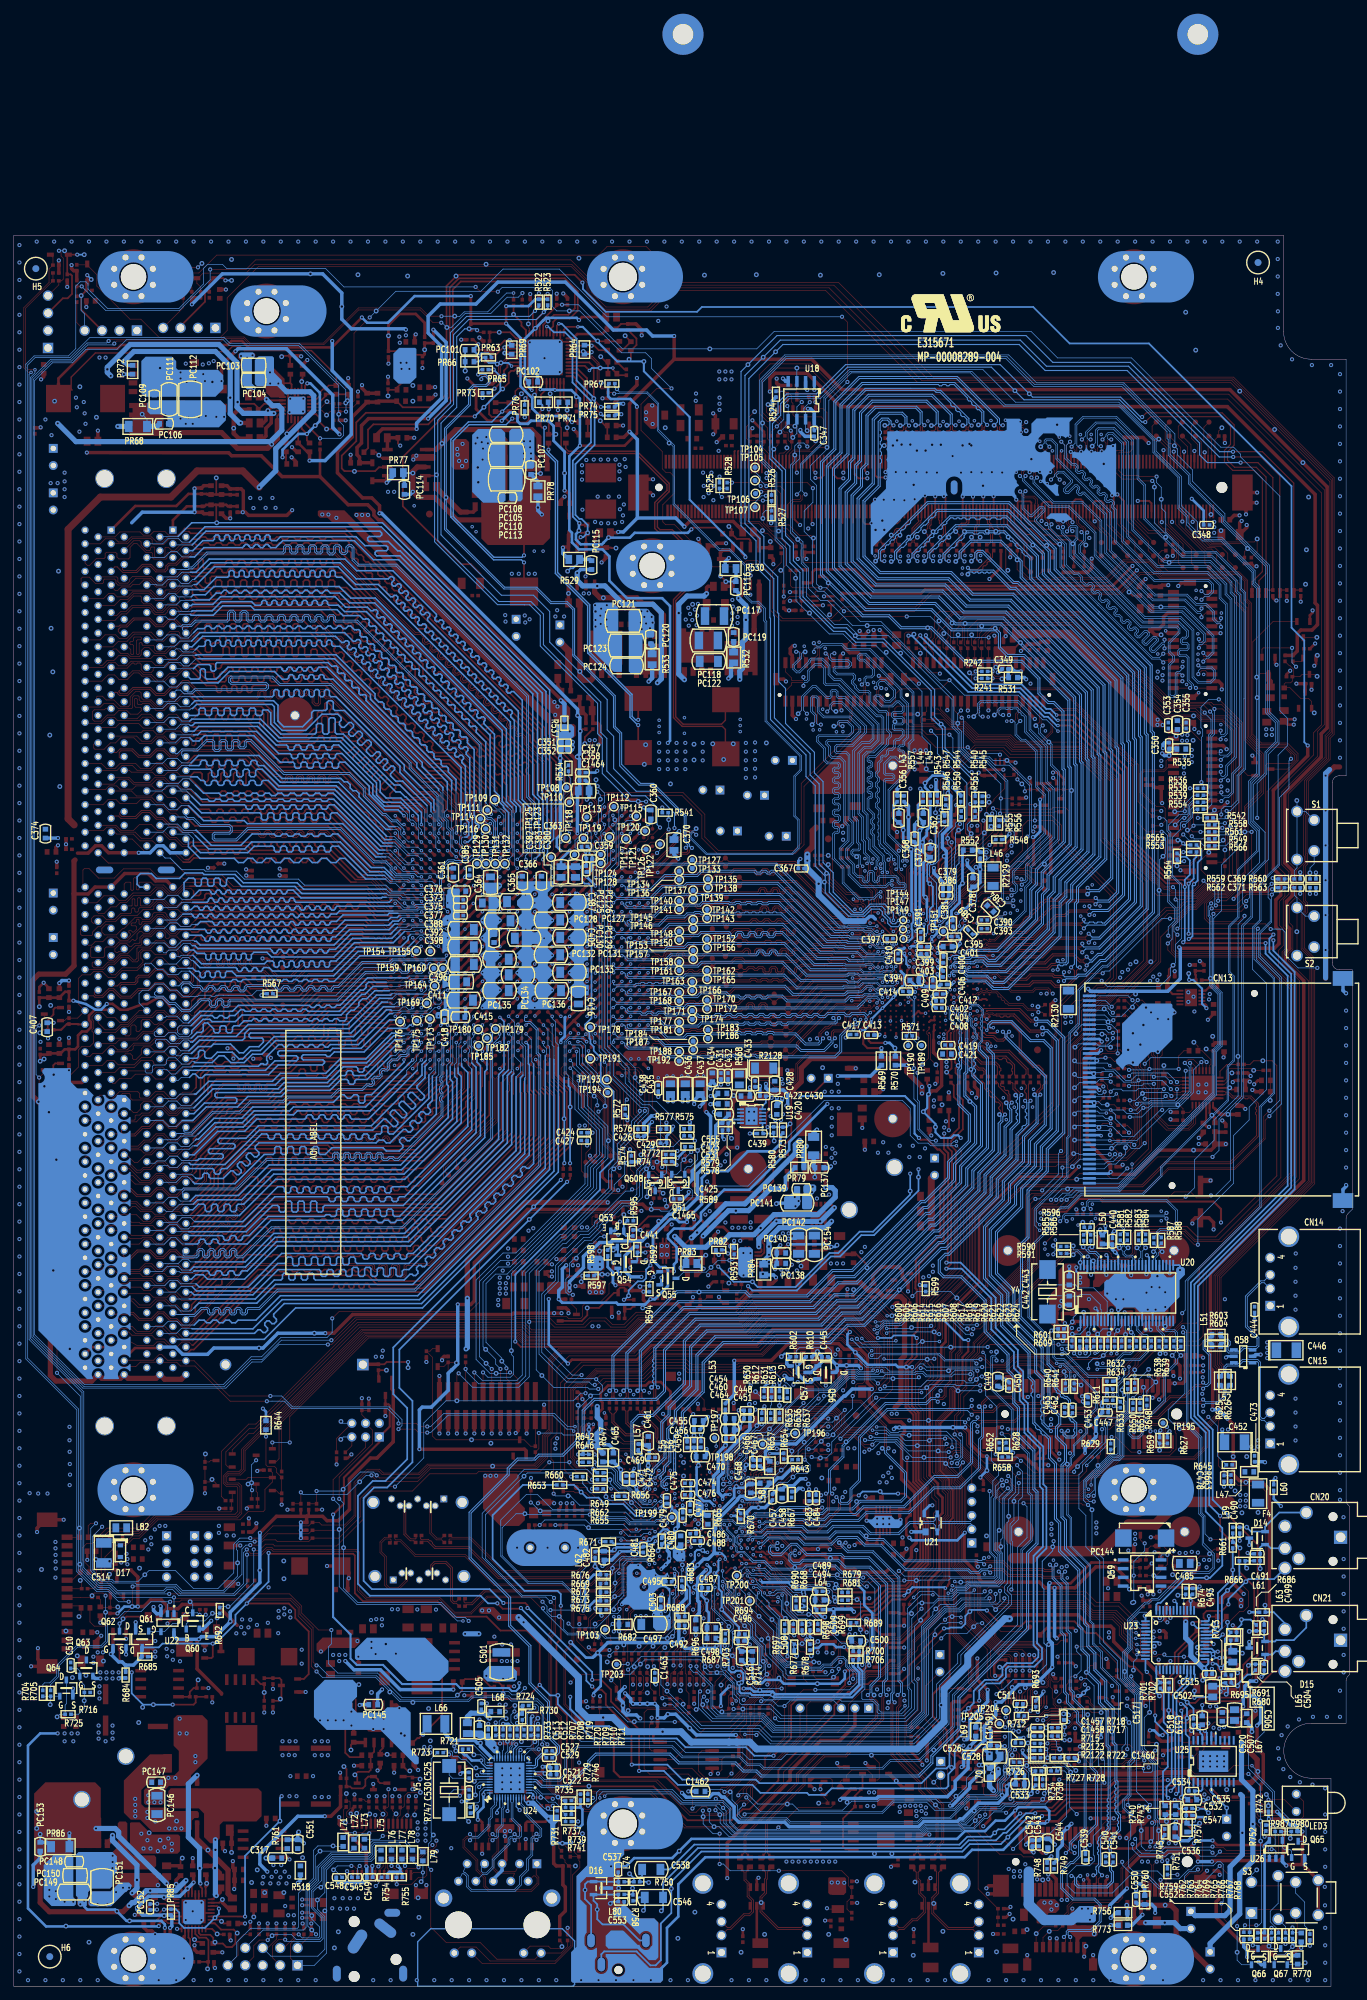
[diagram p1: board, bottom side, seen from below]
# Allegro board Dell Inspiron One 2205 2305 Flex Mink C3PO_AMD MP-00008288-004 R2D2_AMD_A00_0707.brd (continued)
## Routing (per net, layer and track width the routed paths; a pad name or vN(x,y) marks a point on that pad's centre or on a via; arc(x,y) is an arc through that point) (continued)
MEM_MA_DQS5_N: length 63.2
  TOP w0.125: v3(133.07,137.47) U6.AG25
  BOTTOM w0.13: J1.93 171.72,116.01 170.51,116.01 170.26,116.27 162.51,116.27 158.24,120.54 148.7,120.54 148.57,120.67 148.57,121.18 148.26,121.49 147.82,121.49 147.51,121.18 147.51,120.67 147.38,120.54 147.12,120.54 146.99,120.67 146.99,121.19 146.7,121.48 146.22,121.48 145.93,121.19 145.93,120.67 145.8,120.54 145.54,120.54 145.41,120.67 145.41,121.19 145.12,121.48 144.64,121.48 144.35,121.19 144.35,120.67 144.22,120.54 143.96,120.54 143.83,120.67 143.83,121.19 143.54,121.48 143.06,121.48 142.77,121.19 142.77,120.67 142.64,120.54 142.38,120.54 142.25,120.67 142.25,121.19 141.96,121.48 141.48,121.48 141.19,121.19 141.19,120.67 141.06,120.54 140.65,120.54 140.35,120.84 139.73,120.84 139.43,120.54 139.06,120.54 132.74,126.86 132.74,128.78 132.98,129.01 132.98,129.48 132.74,129.71 132.74,130.05 132.98,130.28 132.98,131 132.74,131.24 132.74,131.65 132.92,131.83 132.92,132.46 132.74,132.63 132.74,134.24 132.62,134.37 132.62,137.3 132.78,137.47 v3(133.07,137.47)
MEM_MA_DQS5_P: length 63.2
  TOP w0.125: v3(131.8,137.47) U6.AG24
  BOTTOM w0.13: v3(131.8,137.47) 132.14,137.47 132.34,137.27 132.34,134.25 132.47,134.13 132.47,132.52 132.64,132.35 132.64,131.94 132.47,131.77 132.47,131.12 132.71,130.89 132.71,130.4 132.47,130.16 132.47,129.6 132.71,129.36 132.71,129.13 132.47,128.89 132.47,126.75 138.95,120.27 139.54,120.27 139.84,120.57 140.23,120.57 140.53,120.27 141.17,120.27 141.46,120.56 141.46,121.07 141.59,121.2 141.85,121.2 141.98,121.07 141.98,120.56 142.27,120.27 142.75,120.27 143.04,120.56 143.04,121.07 143.17,121.2 143.43,121.2 143.56,121.07 143.56,120.56 143.85,120.27 144.33,120.27 144.62,120.56 144.62,121.07 144.75,121.2 145.01,121.2 145.14,121.07 145.14,120.56 145.43,120.27 145.91,120.27 146.2,120.56 146.2,121.07 146.33,121.2 146.59,121.2 146.72,121.07 146.72,120.56 147.01,120.27 147.49,120.27 147.78,120.56 147.78,121.07 147.93,121.22 148.15,121.22 148.3,121.07 148.3,120.56 148.59,120.27 158.12,120.27 162.39,116 170.15,116 170.38,115.76 170.38,115.35 170.14,115.11 J1.94
MEM_MA_DQS6_N: length 76
  TOP w0.125: U6.AG19 v3(124.2,138.72)
  BOTTOM w0.13: v3(124.2,138.72) 124.2,138.25 125.5,136.95 125.5,123.55 138.44,110.62 157.49,110.62 161.73,106.38 162.37,106.38 162.5,106.51 162.5,107.15 162.79,107.44 163.27,107.44 163.56,107.15 163.56,106.51 163.69,106.38 163.95,106.38 164.08,106.51 164.08,107.15 164.37,107.44 164.85,107.44 165.14,107.15 165.14,106.51 165.27,106.38 165.53,106.38 165.66,106.51 165.66,107.15 165.95,107.44 166.43,107.44 166.72,107.15 166.72,106.51 166.85,106.38 167.11,106.38 167.24,106.51 167.24,107.15 167.53,107.44 168.01,107.44 168.3,107.15 168.3,106.51 168.43,106.38 170.19,106.38 170.32,106.51 170.32,107 170.21,107.1 J1.102
MEM_MA_DQS6_P: length 76
  TOP w0.125: v3(124.18,137.47) U6.AG18
  BOTTOM w0.13: J1.103 171.68,106.24 170.44,106.24 170.32,106.11 168.32,106.11 168.03,106.4 168.03,107.04 167.9,107.17 167.64,107.17 167.51,107.04 167.51,106.4 167.22,106.11 166.74,106.11 166.45,106.4 166.45,107.04 166.32,107.17 166.06,107.17 165.93,107.04 165.93,106.4 165.64,106.11 165.16,106.11 164.87,106.4 164.87,107.04 164.74,107.17 164.48,107.17 164.35,107.04 164.35,106.4 164.06,106.11 163.58,106.11 163.29,106.4 163.29,107.04 163.16,107.17 162.9,107.17 162.77,107.04 162.77,106.4 162.48,106.11 161.62,106.11 157.38,110.35 138.33,110.35 125.23,123.44 125.23,136.84 124.6,137.47 v3(124.18,137.47)
MEM_MA_DQS7_N: length 89.6
  TOP w0.125: v3(120.37,140.01) U6.AE15
  BOTTOM w0.13: v3(120.37,140.01) 120.14,140.25 119.81,140.25 118.88,139.32 118.88,135.89 118.5,135.51 118.5,119.63 136.6,101.54 156.6,101.54 159.27,98.87 160.94,98.87 161.22,98.58 161.22,98.19 161.35,98.06 161.61,98.06 161.74,98.19 161.74,98.58 162.03,98.87 162.52,98.87 162.8,98.58 162.8,98.19 162.93,98.06 163.19,98.06 163.32,98.19 163.32,98.58 163.61,98.87 164.1,98.87 164.38,98.58 164.38,98.19 164.51,98.06 164.77,98.06 164.9,98.19 164.9,98.58 165.19,98.87 165.68,98.87 165.96,98.58 165.96,98.19 166.09,98.06 166.35,98.06 166.48,98.19 166.48,98.58 166.77,98.87 167.71,98.87 168.73,97.85 171.56,97.85 J1.111
MEM_MA_DQS7_P: length 89.6
  TOP w0.125: v3(120.37,141.28) U6.AD15
  BOTTOM w0.13: J1.112 169.43,97.58 168.62,97.58 167.6,98.6 166.88,98.6 166.75,98.47 166.75,98.08 166.47,97.79 165.98,97.79 165.69,98.08 165.69,98.47 165.56,98.6 165.3,98.6 165.17,98.47 165.17,98.08 164.89,97.79 164.4,97.79 164.11,98.08 164.11,98.47 163.98,98.6 163.72,98.6 163.59,98.47 163.59,98.08 163.31,97.79 162.82,97.79 162.53,98.08 162.53,98.47 162.4,98.6 162.14,98.6 162.01,98.47 162.01,98.08 161.73,97.79 161.24,97.79 160.95,98.08 160.95,98.47 160.82,98.6 159.16,98.6 156.49,101.26 136.49,101.26 118.23,119.52 118.23,135.62 118.61,136 118.61,139.43 119.7,140.52 120.46,140.52 120.6,140.65 120.6,141.05 v3(120.37,141.28)
MEM_MA_DQS8_N: length 47.1
  TOP w0.125: v3(135.61,161.6) U6.J27
  BOTTOM w0.13: v3(135.61,161.6) 136.15,161.6 136.65,162.1 137.17,162.1 137.24,162.03 139.22,162.03 139.89,162.7 139.89,163.08 140.72,163.91 142.48,163.91 147.32,168.76 160.97,168.76 162.62,167.11 165.68,167.11 165.81,167.24 165.81,167.69 165.68,167.82 163.52,167.82 163.16,168.18 163.16,168.84 163.52,169.21 167.74,169.21 168.78,170.25 169.67,170.25 169.91,170.49 J1.42
MEM_MA_DQS8_P: length 47.1
  TOP w0.125: v3(136.88,161.6) U6.J28
  BOTTOM w0.13: J1.43 171.6,170.32 170.12,170.32 169.78,169.98 168.89,169.98 167.85,168.94 163.64,168.94 163.43,168.73 163.43,168.29 163.64,168.09 165.79,168.09 166.08,167.8 166.08,167.13 165.79,166.84 162.5,166.84 160.86,168.48 147.43,168.48 142.59,163.64 140.83,163.64 140.16,162.96 140.16,162.59 139.33,161.76 137.03,161.76 v3(136.88,161.6)
MEM_MA_EVENT_L: length 67.3
  TOP w0.1: v3(139.49,148.89) 139.4,148.89 U6.W30
  TOP w0.102: J1.187 176.73,142.11 178.45,140.39 179.54,140.39 180.25,141.1 181.39,141.1 182.18,141.88 182.94,141.88 183.6,141.22 183.6,140.82 183.35,140.56 183.35,139.57 183.6,139.32 183.6,139.12 183.4,138.91 183.4,137.39 183.91,136.88 185.08,136.88 185.58,136.37 185.58,133.88 R163.2 186.97,132.53 Q9.E
  BOTTOM w0.102: J1.187 176.74,143.24 176.74,144.58 176.24,145.08 175.35,145.08 174.43,146 173.11,146 172.2,145.08 171.23,145.08 170.32,144.17 168.2,144.17 168.02,144.35 166.3,144.35 166.14,144.2 165.68,144.2 165.52,144.35 164.48,144.35 164.42,144.3 163.76,144.3 163.75,144.3 160.33,144.3 159.62,145.01 157.47,145.01 157.24,144.78 R567.1 157.02,144.35 148.04,144.35 143.98,148.41 139.99,148.41 139.52,148.89 v3(139.49,148.89)
MEM_MA_RAS_N: length 46.9
  TOP w0.229: v3(134.34,145.09) U6.AA26
  BOTTOM w0.099: v3(134.34,145.09) 134.34,145.56 134.5,145.72 134.72,145.72 134.88,145.56 134.88,145.14 135.38,144.64 139.82,144.64 ; 169.23,137.54 169.53,137.84 170.29,137.84 170.83,137.3 172.13,137.3 172.13,137.31 172.75,137.92 174.18,137.92 174.36,137.74 174.36,137.38 174.08,137.1 J1.192
  BOTTOM w0.102: 139.82,144.64 139.93,144.52 139.96,144.52
  BOTTOM w0.229: 139.96,144.52 140.11,144.37 142.14,144.37 146.43,140.08 160.85,140.08 162.58,138.35 168.14,138.35 168.96,137.54 169.23,137.54
MEM_MA_RESET_N: length 57.7
  TOP w0.125: v3(126.72,166.69) 126.08,166.05 U6.E20
  BOTTOM w0.125: v3(126.72,166.69) 127.18,166.22 127.18,165.08 127.51,164.76 128.28,164.76 129.06,163.97 130.71,163.97 130.82,164.08 131.75,164.08 132.77,163.05 132.77,161.43 132.96,161.24 132.96,159.59 132.7,159.32 132.7,158.7 132.97,158.43 133.4,158.43 134.48,159.51 139.91,159.51 140.79,160.39 152.64,160.39 153.52,161.26 161.4,161.26 162.56,162.42 167.08,162.42 167.3,162.64 170.51,162.64 172.21,164.33 172.94,164.33 J1.168
MEM_MA_WE_N: length 47.1
  TOP w0.229: v3(135.61,143.82) U6.AB27
  BOTTOM w0.099: v3(135.61,143.82) 135.83,144.04 136.15,144.04 136.25,143.95 136.25,143.48 136.37,143.35 139.2,143.35 139.51,143.04 139.89,143.04 140.2,143.35 140.56,143.35 ; 169.15,135.85 170.41,135.85 170.74,135.53 171.23,135.53 J1.73
  BOTTOM w0.229: 140.56,143.35 141.37,143.35 145.86,138.86 160.49,138.86 160.71,138.63 160.71,138.35 160.49,138.12 158.84,138.12 158.63,137.92 158.63,137.52 159.29,136.86 160.64,136.86 161.53,135.97 162.14,135.97 163.41,137.24 165.9,137.24 166.25,136.88 168.11,136.88 169.07,135.92 169.09,135.92 169.15,135.85
MEM_MB0_CLK0_N: length 55.4
  TOP w0.099: 140.93,147.52 140.91,147.52 140.9,147.53 137.02,147.53 136.72,147.83 136.72,148.1 136.56,148.27 U6.W28
  TOP w0.13: J2.185 184.45,144.27 183.38,144.27 183.17,144.06 182.02,144.06 181.05,145.03 180.54,145.03 179.45,143.95 177.88,143.95 176.78,145.05 175.16,145.05 174.28,145.93 173.34,145.93 172.37,144.97 171.46,144.97 170.52,144.03 169.44,144.03 168,145.48 168,146.88 167.25,147.62 158.48,147.62 156.94,146.08 154.25,146.08 152.27,148.06 142.44,148.06 141.9,147.52 140.93,147.52
MEM_MB0_CLK0_P: length 54.6
  TOP w0.099: 141.01,147.79 140.99,147.79 140.99,147.78 140.82,147.78 140.81,147.78 137.13,147.78 136.97,147.93 136.97,148.15 137.09,148.27 U6.W29
  TOP w0.13: 141.01,147.79 141.78,147.79 142.33,148.33 152.39,148.33 154.36,146.35 156.83,146.35 158.37,147.89 167.36,147.89 168.27,146.99 168.27,145.59 169.56,144.3 170.41,144.3 171.35,145.24 172.26,145.24 173.22,146.2 174.39,146.2 175.28,145.32 176.89,145.32 177.99,144.22 179.34,144.22 180.43,145.31 181.16,145.31 182.13,144.34 183.06,144.34 183.25,144.53 183.25,144.78 182.93,145.11 J2.184
MEM_MB0_CLK1_N: length 53.1
  TOP w0.099: U6.W31 140.05,148.49 140.36,148.8 140.81,148.8 140.82,148.79 140.85,148.79
  TOP w0.13: J2.64 179.15,145.11 179.5,145.45 179.5,145.72 179.28,145.94 177.29,145.94 176.92,146.3 176.92,146.81 176.73,147 175.26,147 174.3,147.96 173.34,147.96 172.4,147.02 171.54,147.02 170.55,146.02 169.17,146.02 168.8,146.4 168.8,147.58 168.49,147.9 168.49,148.92 168.04,149.36 167.54,149.36 167.4,149.22 167.4,148.78 167.06,148.45 166.59,148.45 166.25,148.78 166.25,149.24 166.13,149.36 165.54,149.36 165.41,149.24 165.41,148.72 165.13,148.43 164.64,148.43 164.35,148.72 164.35,149.24 164.22,149.36 163.96,149.36 163.83,149.24 163.83,148.72 163.55,148.43 163.06,148.43 162.77,148.72 162.77,149.24 162.64,149.36 162.38,149.36 162.25,149.24 162.25,148.72 161.97,148.43 161.48,148.43 161.19,148.72 161.19,149.3 161.04,149.45 160.83,149.45 160.67,149.3 160.67,148.93 160.24,148.5 158.19,148.5 156.6,146.91 154.61,146.91 152.64,148.88 142.18,148.88 142.08,148.79 140.85,148.79
MEM_MB0_CLK1_P: length 53.7
  TOP w0.099: U6.V31 140.05,149.29 140.3,149.05 140.81,149.05 140.82,149.05 140.91,149.05 140.91,149.06 140.93,149.06
  TOP w0.13: 140.93,149.06 141.97,149.06 142.06,149.15 152.75,149.15 154.72,147.18 156.48,147.18 158.07,148.77 160.13,148.77 160.4,149.04 160.4,149.41 160.71,149.73 161.15,149.73 161.46,149.41 161.46,148.83 161.59,148.7 161.85,148.7 161.98,148.83 161.98,149.35 162.27,149.64 162.76,149.64 163.04,149.35 163.04,148.83 163.17,148.7 163.43,148.7 163.56,148.83 163.56,149.35 163.85,149.64 164.34,149.64 164.62,149.35 164.62,148.83 164.75,148.7 165.01,148.7 165.14,148.83 165.14,149.35 165.43,149.64 166.24,149.64 166.53,149.35 166.53,148.89 166.7,148.72 166.95,148.72 167.13,148.89 167.13,149.33 167.43,149.64 168.15,149.64 168.76,149.03 168.76,148.01 169.08,147.69 169.08,146.51 169.29,146.3 170.44,146.3 171.43,147.29 172.29,147.29 173.23,148.23 174.42,148.23 175.38,147.27 176.85,147.27 177.19,146.92 177.19,146.42 177.4,146.21 179.4,146.21 179.89,145.71 180.41,145.71 J2.63
MEM_MB0_CS_L0: length 51.7
  TOP w0.099: J2.193 184.61,135.64 184.41,135.43 183.91,135.43 183.46,135.88 182.1,135.88 180.95,137.02 180.49,137.02 179.86,136.38 178.48,136.38 177.49,137.37 175.14,137.37 174.42,138.09 172.98,138.09 172.25,137.35 171.53,137.35 170.5,138.38 169.51,138.38 169.1,138.79 ; 142.05,143.16 142.01,143.19 141.55,143.19
  TOP w0.102: 141.55,143.19 U6.AC31
  TOP w0.229: 142.05,143.16 143.26,143.16 143.75,143.65 150.11,143.65 152.58,141.18 157.02,141.18 157.78,141.93 160.42,141.93 161.92,143.43 164.46,143.43 169.1,138.79
MEM_MB0_CS_L1: length 52.7
  TOP w0.099: J2.76 178.68,133.33 174.81,133.33 174.28,133.87 173.28,133.87 172.79,133.37 171.51,133.37 170.56,134.32 169.6,134.32
  TOP w0.229: U6.AE30 138.78,140.46 139.16,140.08 140.14,140.08 140.61,139.61 143.16,139.61 143.39,139.39 143.39,138.77 143.62,138.54 144.08,138.54 144.31,138.77 144.31,139.64 144.51,139.84 145.02,139.84 145.22,139.64 145.22,138.77 145.45,138.54 145.91,138.54 146.13,138.77 146.13,140.33 146.34,140.54 146.85,140.54 147.05,140.33 147.05,138.77 147.28,138.54 147.73,138.54 147.96,138.77 147.96,139.39 148.19,139.61 148.93,139.61 149.17,139.37 149.17,138.2 150.24,137.13 156.55,137.13 157.71,138.29 165.79,138.29 168.67,135.41 168.67,135.25 169.6,134.32
MEM_MB0_ODT0: length 52.5
  TOP w0.099: 169.09,136.5 169.22,136.37 170.41,136.37 171.41,135.37 172.38,135.37 172.98,135.98 174.38,135.98 175.06,135.3 176.37,135.3 177.44,134.22 179.79,134.22 180.4,134.84 181.4,134.84 182.13,134.11 J2.195
  TOP w0.102: 141.09,141.7 141.09,142.04 140.78,142.35 137.95,142.35 U6.AD29
  TOP w0.229: 169.09,136.5 166.24,139.35 151.75,139.35 149.09,142.01 144.73,142.01 143.96,141.24 141.54,141.24 141.09,141.7
MEM_MB0_ODT1: length 51.2
  TOP w0.099: 169.3,133.87 170.23,133.87 171.18,132.92 172.29,132.92 173.06,132.15 174.33,132.15 175.03,132.85 177.28,132.85 177.91,132.22 179.55,132.22 180.24,131.53 180.6,131.53 180.81,131.74 180.81,132.03 J2.77
  TOP w0.229: U6.AF31 140.31,139.13 141.72,139.13 143.07,137.78 143.07,137.11 143.29,136.88 143.75,136.88 143.98,137.11 143.98,137.78 144.21,138.01 144.67,138.01 144.9,137.78 144.9,137.11 145.12,136.88 145.58,136.88 145.81,137.11 145.81,137.78 146.04,138.01 146.5,138.01 146.72,137.78 146.72,137.11 146.95,136.88 147.41,136.88 147.64,137.11 147.64,137.78 147.87,138.01 148.6,138.01 150.06,136.56 156.73,136.56 157.9,137.72 165.44,137.72 169.3,133.87
MEM_MB_ADD0: length 54.2
  TOP w0.099: 169.09,143.51 169.09,142.76 169.48,142.37 170.47,142.37 171.47,141.37 172.33,141.37 173.06,142.1 174.27,142.1 175.03,141.34 177.13,141.34 178.37,140.09 179.39,140.09 180.16,139.32 181.68,139.32 182.71,140.34 J2.188
  TOP w0.102: U6.AA30 138.31,145.73 137.83,146.21 137.83,146.62 137.98,146.77 138.28,146.77 138.77,146.29 140.49,146.29 140.74,146.04
  TOP w0.229: 140.74,146.04 142.1,146.04 142.82,146.76 151.66,146.76 153.68,144.74 157.5,144.74 158.61,145.85 160.25,145.85 161.34,146.94 165.66,146.94 169.09,143.51
MEM_MB_ADD1: length 52.8
  TOP w0.099: 169.71,150.21 170.24,150.21 171.15,151.12 172.27,151.12 173.26,152.11 174.12,152.11 175.14,151.09 176.31,151.09 176.79,150.61 176.79,149.46 177.04,149.21 177.7,149.21 178.3,149.82 179.35,149.82 180.3,148.88 181.14,148.88 181.93,148.08 184.59,148.08 J2.181 ; 141.8,151.28 141.64,151.44 140.69,151.44
  TOP w0.102: 140.69,151.44 136.88,151.44 U6.U28
  TOP w0.229: 169.71,150.21 168.64,151.28 141.8,151.28
MEM_MB_ADD2: length 51.3
  TOP w0.099: J2.61 180.99,147.93 180.99,147.57 180.73,147.32 180.22,147.32 179.21,148.34 177,148.34 176.58,148.76 176.18,149.16 176.18,149.44 176.48,149.74 176.48,150.53 176.18,150.84 174.96,150.84 174.38,150.25 172.87,150.25 172.78,150.33 172.78,150.73 172.65,150.86 171.25,150.86 171.05,150.66 171.05,150.02 170.85,149.82 169.44,149.82 ; 140.49,151.24 140.92,151.24 141.41,150.75 ; U6.U29 137.5,150.79 137.5,150.34 137.7,150.14 138.01,150.14 138.19,150.32 138.19,151.03 138.4,151.24
  TOP w0.102: 140.49,151.24 138.4,151.24
  TOP w0.229: 169.44,149.82 168.51,150.75 157.44,150.75 156.96,150.27 156.52,150.27 156.04,150.75 155.48,150.75 154.93,150.19 154.34,150.19 153.79,150.75 141.41,150.75
MEM_MB_ADD3: length 52
  TOP w0.099: 168.94,151.81 169.26,152.13 170.6,152.13 170.7,152.03 170.7,151.54 170.86,151.37 172.15,151.37 173.13,152.36 174.27,152.36 175.27,151.37 176.84,151.37 177.05,151.16 177.05,149.73 177.3,149.48 177.56,149.48 178.19,150.11 179.43,150.11 180.35,149.19 181.24,149.19 182.09,148.34 183.3,148.34 183.58,148.62 183.58,149.05 183.45,149.17 182.78,149.17 J2.180 ; 141.21,151.65 140.23,151.65
  TOP w0.102: U6.T29 137.95,151.65 140.23,151.65 ; 142.1,151.65 141.21,151.65
  TOP w0.229: 142.1,151.65 144.54,151.65 144.7,151.81 168.94,151.81
MEM_MB_ADD4: length 52
  TOP w0.099: J2.59 180.88,150.11 180.88,150.11 181.17,150.11 181.32,149.96 181.32,149.66 181.1,149.44 180.46,149.44 179.52,150.38 178.45,150.38 177.21,151.62 176.49,151.62 176.34,151.77 176.34,152.6 176.07,152.87 175.01,152.87 174.04,153.84 173.36,153.84 172.93,153.41 172.93,152.81 172.73,152.61 172.51,152.61 172.28,152.84 171.18,152.84 170.72,152.39 168.98,152.39
  TOP w0.229: U6.T31 144.17,152.08 144.62,152.53 154.49,152.53 154.98,153.02 155.71,153.02 155.94,152.79 155.94,152.58 156.17,152.35 156.63,152.35 156.86,152.58 156.86,152.79 157.08,153.02 157.54,153.02 157.77,152.79 157.77,152.58 158,152.35 158.46,152.35 158.68,152.58 158.68,152.79 158.91,153.02 159.37,153.02 159.6,152.79 159.6,152.58 159.83,152.35 160.28,152.35 160.51,152.58 160.51,152.79 160.74,153.02 161.2,153.02 161.43,152.79 161.43,152.58 161.66,152.35 162.11,152.35 162.34,152.58 162.34,152.79 162.57,153.02 163.03,153.02 163.26,152.79 163.26,152.58 163.49,152.35 163.94,152.35 164.17,152.58 164.17,152.79 164.4,153.02 164.86,153.02 165.09,152.79 165.09,152.58 165.31,152.35 165.77,152.35 166,152.58 166,152.79 166.23,153.02 166.7,153.02 167,152.73 167,152.55 167.2,152.35 167.49,152.35 167.69,152.55 167.69,152.77 167.94,153.02 168.35,153.02 168.98,152.39
MEM_MB_ADD5: length 51.3
  TOP w0.099: 169.04,153.55 169.32,153.83 170.59,153.83 171.33,153.1 172.24,153.1 173.26,154.11 174.15,154.11 175.14,153.12 176.26,153.12 176.61,152.77 176.61,152.05 176.74,151.92 177.41,151.92 177.88,151.45 178.11,151.45 178.52,151.85 179.51,151.85 180.27,151.09 180.27,150.77 180.06,150.57 179.85,150.57 179.68,150.73 179.11,150.73 178.91,150.94 J2.58
  TOP w0.102: U6.R30 138.58,153.15 138.58,152.76 138.79,152.56 139.18,152.56 139.47,152.85 140.3,152.85 140.4,152.75 140.4,152.56 140.51,152.46 140.71,152.46 140.81,152.56 140.81,152.88 140.93,152.99 141.1,152.99 141.22,152.88 141.22,152.56 141.32,152.46 141.52,152.46 141.62,152.56 141.62,152.75 141.73,152.85 141.93,152.85 142.03,152.75 142.03,152.56 142.13,152.46 142.33,152.46 142.44,152.56 142.44,152.75 142.54,152.85 143.28,152.85
  TOP w0.229: 143.28,152.85 144.03,152.85 144.28,153.1 154.3,153.1 155.06,153.86 155.8,153.86 156.08,153.58 156.71,153.58 156.99,153.86 157.63,153.86 157.91,153.58 158.54,153.58 158.82,153.86 159.46,153.86 159.73,153.58 160.37,153.58 160.65,153.86 161.29,153.86 161.56,153.58 162.2,153.58 162.48,153.86 163.11,153.86 163.39,153.58 164.03,153.58 164.31,153.86 164.94,153.86 165.22,153.58 165.86,153.58 166.14,153.86 167.87,153.86 168.18,153.55 169.04,153.55
MEM_MB_ADD6: length 51.3
  TOP w0.099: 168.88,154.09 170.74,154.09 171.46,153.37 172.14,153.37 173.13,154.37 174.25,154.37 175.24,153.38 176.07,153.38 176.35,153.65 176.63,153.65 177.03,153.25 177.03,152.59 177.29,152.33 177.47,152.33 177.62,152.49 177.72,152.49 178.1,152.11 179.66,152.11 180.38,151.38 181.52,151.38 181.75,151.16 181.75,150.06 181.95,149.86 183.65,149.86 183.78,149.99 183.78,151.26 183.65,151.38 182.99,151.38 J2.178
  TOP w0.229: U6.R31 143.99,153.35 144.27,153.63 154.08,153.63 154.84,154.39 166.47,154.39 167.02,154.94 168.03,154.94 168.88,154.09
MEM_MB_ADD7: length 51.5
  TOP w0.099: J2.56 178.91,152.84 178.75,152.68 178.42,152.68 177.97,153.13 177.97,153.27 178.24,153.54 178.24,153.7 178.12,153.82 177.95,153.82 177.69,153.55 177.52,153.55 177.12,153.95 177.12,154.33 177.26,154.47 177.77,154.47 177.89,154.59 177.89,154.76 177.77,154.88 177.31,154.88 177.12,155.08 177.12,155.32 177.01,155.43 176.85,155.43 176.74,155.32 176.74,154.78 176.62,154.66 176.46,154.66 176.34,154.78 176.34,154.99 176.22,155.11 175.12,155.11 174.13,156.09 173.26,156.09 172.27,155.1 171.35,155.1 170.62,155.84 169.25,155.84 ; 140.45,153.98 140.76,153.98 141.06,154.28 143.63,154.28
  TOP w0.102: 140.45,153.98 137.17,153.98 137.07,154.08 137.07,154.4 136.94,154.52 136.77,154.52 136.69,154.45 136.69,153.8 U6.R28 ; 169.25,155.84 169.19,155.78
  TOP w0.229: 169.19,155.78 168.84,156.13 166.65,156.13 165.98,155.46 154.4,155.46 153.64,154.7 144.05,154.7 143.63,154.28
MEM_MB_ADD8: length 51.5
  TOP w0.099: J2.177 184.14,151.64 183.65,151.64 183.14,152.15 182.03,152.15 181.34,152.84 180,152.84 179.53,152.36 178.36,152.36 175.87,154.85 175,154.85 174.01,155.84 173.41,155.84 172.42,154.85 171.1,154.85 170.59,154.34 169.5,154.34 168.54,155.3 ; 142.7,153.78 140.32,153.78
  TOP w0.102: 140.32,153.78 137.95,153.78 U6.R29
  TOP w0.229: 168.54,155.3 168.24,155.6 166.87,155.6 166.2,154.93 154.62,154.93 153.86,154.17 144.18,154.17 143.79,153.78 142.7,153.78
MEM_MB_ADD9: length 51.1
  TOP w0.099: J2.175 185.04,154.11 185.25,153.9 185.25,153.24 185.04,153.03 183.65,153.03 183.54,153.14 183.54,153.53 183.32,153.75 182.74,154.33 182.36,154.33 181.56,155.13 180.13,155.13 179.3,155.96 177.03,155.96 176.15,156.84 174.71,156.84 174.59,156.96 174.59,157.26 174.01,157.84 173.41,157.84 172.43,156.86 171.1,156.86 170.59,156.35 169.66,156.35 168.81,157.2 ; U6.P31 140.05,154.71 140.37,155.02 142.96,155.02 143,155.06
  TOP w0.229: 168.81,157.2 166.21,157.2 165.54,156.53 153.96,156.53 153.2,155.77 143.71,155.77 143,155.06
MEM_MB_ADD10: length 50.8
  TOP w0.099: J2.70 178.91,138.64 178.7,138.43 178.19,138.43 177.94,138.68 177.94,139.81 177.73,140.02 177.38,140.02 177.18,139.81 177.18,139.19 177.05,139.06 176.77,139.06 176.44,139.39 176.44,140.59 176.2,140.83 175.26,140.83 174.51,140.08 174.13,140.08 173.9,140.31 173.18,140.31 172.66,140.83 171.22,140.83 170.21,141.84 169.53,141.84 169.05,141.35 168.79,141.35 168.67,141.48 168.67,141.78 168.61,141.84
  TOP w0.102: 140.43,145.29 140.27,145.13 139.43,145.13 139.27,145.3 138.39,145.3 137.96,145.73 U6.AA29
  TOP w0.229: 140.43,145.29 140.98,145.29 141.36,144.91 141.87,144.91 142.25,145.29 142.81,145.29 143.22,145.69 151.21,145.69 153.23,143.68 159.67,143.68 161.03,145.03 164.35,145.03 164.6,145.29 165.16,145.29 168.61,141.84
MEM_MB_ADD11: length 51.3
  TOP w0.099: 140.51,154.19 141.11,154.79 143.37,154.79 ; 168.54,156.66 168.99,156.66 169.56,156.09 170.74,156.09 171.46,155.37 172.16,155.37 172.68,155.9 172.68,156.09 172.96,156.37 174.55,156.37 174.76,156.16 174.76,155.89 175.27,155.38 176.23,155.38 176.53,155.68 177.33,155.68 178.94,154.07 179.11,154.07 180.04,153.14 181.74,153.14 182.16,153.56 182.16,154.09 181.63,154.62 181.01,154.62 180.81,154.41 J2.55
  TOP w0.102: U6.P29 137.95,154.19 140.51,154.19
  TOP w0.229: 143.37,154.79 143.81,155.23 153.42,155.23 154.18,156 165.76,156 166.43,156.66 168.54,156.66
MEM_MB_ADD12: length 51.6
  TOP w0.099: J2.174 182.98,154.84 183.42,154.84 183.69,155.11 183.69,155.51 183.29,155.91 182.02,155.91 181.5,155.38 180.29,155.38 179.43,156.25 178.01,156.25 177.83,156.42 177.83,156.91 177.68,157.06 177.5,157.06 177.35,156.91 177.35,156.62 177.2,156.47 176.99,156.47 176.84,156.62 176.84,156.91 176.64,157.11 175.14,157.11 174.15,158.1 173.28,158.1 172.29,157.11 171.1,157.11 170.26,157.95 169.25,157.95 169.03,157.74 ; U6.N30 138.65,155.76 138.65,155.51 138.76,155.41 142.14,155.41 142.35,155.62
  TOP w0.102: 169.03,157.74 168.54,157.74
  TOP w0.229: 168.54,157.74 165.81,157.74 165.13,157.06 153.74,157.06 152.98,156.3 143.04,156.3 142.35,155.62
MEM_MB_ADD13: length 50.9
  TOP w0.099: 170.08,136.06 171.28,134.86 172.61,134.86 172.89,134.59 172.89,134.39 173.08,134.2 174.38,134.2 174.61,134.43 174.61,134.6 174.84,134.84 176.45,134.84 177.45,133.84 179.54,133.84 180.27,133.11 182.71,133.11 J2.196
  TOP w0.102: 170.08,136.06 168.78,136.06
  TOP w0.229: 168.78,136.06 166.02,138.82 157.49,138.82 156.33,137.67 154.39,137.67 153.65,138.41 153.19,138.41 152.96,138.19 152.96,137.86 152.76,137.66 152.25,137.66 152.05,137.86 152.05,138.19 151.82,138.41 151.36,138.41 151.13,138.19 151.13,138.03 150.93,137.83 150.4,137.83 149.84,138.39 149.84,139.93 149.61,140.16 148.17,140.16 148,140.33 148,140.88 147.82,141.07 145.09,141.07 144.31,140.3 140.84,140.3 140.49,140.65 U6.AE31
MEM_MB_ADD14: length 51.3
  TOP w0.099: 168.79,159.51 169.16,159.88 170.21,159.88 171.25,158.84 172.41,158.84 173.41,159.84 174.11,159.84 175.05,158.9 177.52,158.9 178.55,157.87 179.45,157.87 180.1,157.23 180.86,157.23 181.82,156.27 182.66,156.27 182.89,156.5 182.89,156.92 J2.172
  TOP w0.102: 141.16,156.54 140.95,156.32 137.95,156.32 U6.N29
  TOP w0.229: 141.16,156.54 142.05,156.54 143.64,158.13 164.46,158.13 166.04,159.7 167.59,159.7 167.78,159.51 167.78,159.13 168.03,158.88 168.59,158.88 168.79,159.08 168.79,159.51
MEM_MB_ADD15: length 52.7
  TOP w0.099: J2.171 184.32,157.81 182.9,157.81 181.88,158.84 180.35,158.84 179.65,158.13 178.73,158.13 177.61,159.24 175.16,159.24 174.3,160.11 173.31,160.11 172.29,159.09 171.38,159.09 170.23,160.24 169.33,160.24
  TOP w0.102: 143.61,158.66 141.97,157.02 141.09,157.02 140.59,156.52 136.88,156.52 U6.N28
  TOP w0.229: 143.61,158.66 164.06,158.66 165.63,160.24 169.33,160.24
MEM_MB_BANK0: length 51.2
  TOP w0.099: J2.71 177.15,138.11 176.15,139.11 174.72,139.11 173.77,140.05 173.32,140.05 172.41,139.14 171.49,139.14 170.41,140.22 169.32,140.22 168.82,140.73
  TOP w0.102: 142.14,143.97 139.83,143.97 139.57,144.23 139.57,144.67 139.14,145.09 137.3,145.09 136.66,145.73 U6.AA28
  TOP w0.229: 168.82,140.73 165.04,144.5 161.36,144.5 159.96,143.1 157.29,143.1 156.49,142.31 153.27,142.31 150.86,144.71 143.52,144.71 142.77,143.97 142.14,143.97
MEM_MB_BANK1: length 51.5
  TOP w0.099: J2.190 182.54,138.94 180.16,138.94 179.26,139.84 178.27,139.84 177.03,141.08 174.85,141.08 174.09,141.84 173.19,141.84 172.47,141.11 171.33,141.11 170.34,142.1 169.1,142.1 168.66,142.53
  TOP w0.229: U6.AA31 140.07,145.71 142.49,145.71 143.01,146.23 151.44,146.23 153.45,144.21 157.73,144.21 158.84,145.31 160.52,145.31 161.51,146.3 161.81,146.3 161.99,146.12 161.99,145.73 162.09,145.63 162.57,145.63 162.7,145.76 162.7,146.18 162.82,146.3 163.24,146.3 163.46,146.09 163.46,145.78 163.68,145.57 163.98,145.57 164.2,145.78 164.2,146.09 164.41,146.3 164.9,146.3 165.28,145.92 165.58,145.92 165.6,145.94 165.91,145.94 166.12,145.72 166.12,145.42 166.1,145.4 166.1,145.09 166.32,144.88 166.63,144.88 166.64,144.9 166.95,144.9 167.17,144.68 167.17,144.38 167.15,144.36 167.15,144.05 167.36,143.84 167.67,143.84 167.69,143.85 167.99,143.85 168.21,143.64 168.21,143.33 168.19,143.32 168.19,143.01 168.66,142.53
MEM_MB_BANK2: length 51.2
  TOP w0.099: 169.92,158.27 170.32,158.27 171.22,157.37 172.18,157.37 173.18,158.38 174.51,158.38 174.7,158.19 174.7,157.93 175.27,157.36 176.46,157.36 176.56,157.46 176.56,158.44 176.68,158.56 176.84,158.56 176.96,158.44 176.96,157.46 177.06,157.36 177.25,157.36 177.35,157.46 177.35,158.28 177.47,158.4 177.63,158.4 177.75,158.28 177.75,157.46 177.85,157.36 178.65,157.36 J2.52
  TOP w0.229: 169.92,158.27 167.4,158.27 167.17,158.5 167.17,158.94 166.94,159.17 166.48,159.17 166.25,158.94 166.25,158.5 166.03,158.27 165.54,158.27 164.87,157.6 153.24,157.6 153.01,157.37 153.01,157.09 152.75,156.83 152.35,156.83 152.1,157.09 152.1,157.37 151.87,157.6 151.41,157.6 151.18,157.37 151.18,157.09 150.95,156.86 150.5,156.86 150.27,157.09 150.27,157.37 150.04,157.6 149.58,157.6 149.35,157.37 149.35,157.09 149.13,156.86 148.67,156.86 148.44,157.09 148.44,157.37 148.21,157.6 147.75,157.6 147.52,157.37 147.52,157.09 147.3,156.86 146.84,156.86 146.61,157.09 146.61,157.37 146.38,157.6 145.92,157.6 145.7,157.37 145.7,157.09 145.47,156.86 145.01,156.86 144.78,157.09 144.78,157.37 144.55,157.6 143.82,157.6 142.11,155.89 U6.N31
MEM_MB_CAS_N: length 51.4
  TOP w0.099: 169.12,137.72 169.24,137.84 170.26,137.84 171.25,136.84 172.46,136.84 173.02,136.28 174.55,136.28 175.11,136.84 176.1,136.84 176.41,136.53 176.41,135.76 177.18,135 177.56,135 177.68,135.13 177.68,135.51 178,135.82 178.7,135.82 178.91,135.62 J2.74
  TOP w0.102: U6.AC29 138.15,142.55 141.18,142.55 141.53,142.2
  TOP w0.229: 169.12,137.72 168.63,137.72 166.46,139.89 163.97,139.89 163.59,140.27 163.59,141.88 163.36,142.11 162.57,142.11 162.32,141.86 162.32,140.09 162.11,139.89 151.97,139.89 149.31,142.54 144.44,142.54 143.71,141.81 141.93,141.81 141.53,142.2
MEM_MB_CHECK0: length 52.2
  TOP w0.099: 169.02,172.31 170.59,172.31 171.42,173.14 172.57,173.14 173.4,173.97 174.33,173.97 174.92,173.37 177.12,173.37 177.85,174.11 J2.39 ; 141.38,163.51 141.85,163.98 142.35,163.98
  TOP w0.102: 141.38,163.51 U6.G31
  TOP w0.229: 169.02,172.31 168.16,171.45 166.56,171.45 166.33,171.22 166.33,171.04 166.1,170.81 165.64,170.81 165.41,171.04 165.41,171.22 165.19,171.45 164.73,171.45 164.5,171.22 164.5,171.04 164.27,170.81 163.81,170.81 163.59,171.04 163.59,171.22 163.36,171.45 162.9,171.45 162.67,171.22 162.67,171.04 162.44,170.81 161.99,170.81 161.76,171.04 161.76,171.22 161.53,171.45 161.07,171.45 160.84,171.22 160.84,171.04 160.61,170.81 160.16,170.81 159.93,171.04 159.93,171.22 159.7,171.45 159.24,171.45 159.01,171.22 159.01,171.04 158.79,170.81 158.33,170.81 158.1,171.04 158.1,171.22 157.87,171.45 157.41,171.45 157.18,171.22 157.18,171.04 156.96,170.81 156.5,170.81 156.27,171.04 156.27,171.22 156.04,171.45 155.58,171.45 155.36,171.22 155.36,171.04 155.13,170.81 154.67,170.81 154.44,171.04 154.44,171.22 154.21,171.45 153.76,171.45 153.53,171.22 153.53,171.04 153.3,170.81 152.84,170.81 152.61,171.04 152.61,171.22 152.38,171.45 151.93,171.45 151.7,171.22 151.7,171.04 151.47,170.81 151.01,170.81 150.78,171.04 150.78,171.22 150.56,171.45 149.82,171.45 142.35,163.98
MEM_MB_CHECK1: length 52.4
  TOP w0.099: 142.52,163.23 142.48,163.27 142.4,163.19 141.88,163.19 ; J2.40 178.91,173.11 174.82,173.11 174.09,172.37 173.26,172.37 172.1,171.21 171.24,171.21 170.52,171.94 169.64,171.94
  TOP w0.102: 141.88,163.19 141.32,163.19 140.37,162.24 U6.H31
  TOP w0.229: 169.64,171.94 167.99,170.28 166.51,170.28 166.28,170.05 166.28,169.77 166.05,169.54 165.6,169.54 165.37,169.77 165.37,170.05 165.14,170.28 164.68,170.28 164.45,170.05 164.45,169.77 164.22,169.54 163.77,169.54 163.54,169.77 163.54,170.05 163.31,170.28 162.85,170.28 162.62,170.05 162.62,169.77 162.39,169.54 161.94,169.54 161.71,169.77 161.71,170.05 161.48,170.28 161.02,170.28 160.79,170.05 160.79,169.77 160.57,169.54 160.11,169.54 159.88,169.77 159.88,170.05 159.65,170.28 159.19,170.28 158.97,170.05 158.97,169.77 158.74,169.54 158.28,169.54 158.05,169.77 158.05,170.05 157.82,170.28 157.37,170.28 157.14,170.05 157.14,169.77 156.91,169.54 156.45,169.54 156.22,169.77 156.22,170.05 155.99,170.28 155.54,170.28 155.31,170.05 155.31,169.77 155.08,169.54 154.62,169.54 154.39,169.77 154.39,170.05 154.17,170.28 153.71,170.28 153.48,170.05 153.48,169.77 153.25,169.54 152.79,169.54 152.57,169.77 152.57,170.05 152.34,170.28 151.88,170.28 151.65,170.05 151.65,169.77 151.42,169.54 150.96,169.54 150.74,169.77 150.74,170.05 150.51,170.28 149.57,170.28 142.52,163.23
MEM_MB_CHECK2: length 52.2
  TOP w0.099: J2.45 180.28,168.11 180.01,167.83 177.58,167.83 176.59,166.84 174.78,166.84 174.23,166.28 173.21,166.28 172.22,165.29 171.33,165.29 170.14,164.11 169.92,164.11
  TOP w0.102: 136.88,159.06 140.69,159.06 142.84,161.21 143.89,161.21
  TOP w0.229: 169.92,164.11 169.53,164.11 168.08,165.56 166.89,165.56 166.66,165.34 166.66,165.13 166.43,164.9 165.97,164.9 165.75,165.13 165.75,165.34 165.52,165.56 165.06,165.56 164.83,165.34 164.83,165.13 164.6,164.9 164.15,164.9 163.92,165.13 163.92,165.34 163.69,165.56 163.23,165.56 163,165.34 163,165.13 162.77,164.9 162.32,164.9 162.09,165.13 162.09,165.34 161.86,165.56 161.12,165.56 160.48,164.92 148.96,164.92 145.24,161.21 143.89,161.21 ; U6.L28 136.25,158.43 136.88,159.06
MEM_MB_CHECK3: length 50.8
  TOP w0.099: J2.46 178.91,167.11 177.74,167.11 175.95,165.31 174.73,165.31 174.08,165.97 173.32,165.97 172.26,164.91 171.47,164.91 170.3,163.73
  TOP w0.102: 137.74,158.66 137.95,158.86 140.92,158.86 140.99,158.93 142.89,160.83 145.13,160.83
  TOP w0.229: 145.13,160.83 145.88,160.83 149.4,164.35 150.13,164.35 150.36,164.12 150.36,163.91 150.59,163.68 151.05,163.68 151.28,163.91 151.28,164.12 151.5,164.35 151.96,164.35 152.19,164.12 152.19,163.91 152.42,163.68 152.88,163.68 153.1,163.91 153.1,164.12 153.33,164.35 153.79,164.35 154.02,164.12 154.02,163.91 154.25,163.68 154.7,163.68 154.93,163.91 154.93,164.12 155.16,164.35 155.62,164.35 155.85,164.12 155.85,163.91 156.08,163.68 156.53,163.68 156.76,163.91 156.76,164.12 156.99,164.35 157.45,164.35 157.68,164.12 157.68,163.91 157.9,163.68 158.36,163.68 158.59,163.91 158.59,164.12 158.82,164.35 159.28,164.35 159.51,164.12 159.51,163.91 159.73,163.68 160.19,163.68 160.42,163.91 160.42,164.12 160.65,164.35 168.76,164.35 169.37,163.73 170.3,163.73 ; 137.74,158.66 U6.L29
MEM_MB_CHECK4: length 51.3
  TOP w0.099: 169.63,174.37 170.37,174.37 171.12,175.12 172.46,175.12 173.17,175.84 174.17,175.84 174.91,175.09 177.57,175.09 178.31,175.84 179.64,175.84 180.37,175.11 J2.158 ; U6.G29 137.98,163.97 138.98,163.97 139.15,164.14 140.79,164.14 142.04,165.39
  TOP w0.102: 142.04,165.5 142.04,165.39
  TOP w0.229: 169.63,174.37 169.33,174.37 167.47,172.52 149.06,172.52 142.04,165.5
MEM_MB_CHECK5: length 51.6
  TOP w0.099: U6.G30 139.14,163.51 139.58,163.94 141.12,163.94 141.92,164.73 142.19,164.73 ; J2.159 184.42,174.3 181.65,174.3 181.11,174.84 179.99,174.84 179.53,174.37 177.66,174.37 177.2,174.84 174.84,174.84 174.35,174.35 172.95,174.35 172.46,174.84 171.29,174.84 170.39,173.94 169.65,173.94
  TOP w0.229: 169.65,173.94 167.69,171.98 149.44,171.98 142.19,164.73
MEM_MB_CHECK6: length 52
  TOP w0.099: J2.164 182.49,169.11 182.48,169.11 180.11,169.11 179.38,168.37 177.52,168.37 176.7,169.2 174.93,169.2 174.1,168.37 173.23,168.37 172.19,167.34 171.32,167.34 170.27,166.29 169.54,166.29
  TOP w0.102: 143.62,161.9 142.49,161.9 140.29,159.7 U6.K31
  TOP w0.229: 143.62,161.9 144.24,161.9 148.97,166.63 149.98,166.63 150.21,166.4 150.21,166.22 150.44,165.99 150.9,165.99 151.12,166.22 151.12,166.4 151.35,166.63 151.81,166.63 152.04,166.4 152.04,166.22 152.27,165.99 152.72,165.99 152.95,166.22 152.95,166.4 153.18,166.63 153.64,166.63 153.87,166.4 153.87,166.22 154.1,165.99 154.55,165.99 154.78,166.22 154.78,166.4 155.01,166.63 155.47,166.63 155.7,166.4 155.7,166.22 155.92,165.99 156.38,165.99 156.61,166.22 156.61,166.4 156.84,166.63 157.3,166.63 157.52,166.4 157.52,166.22 157.75,165.99 158.21,165.99 158.44,166.22 158.44,166.4 158.67,166.63 159.12,166.63 159.35,166.4 159.35,166.22 159.58,165.99 160.04,165.99 160.27,166.22 160.27,166.4 160.5,166.63 169.2,166.63 169.54,166.29
MEM_MB_CHECK7: length 52.5
  TOP w0.099: J2.165 184.38,168.33 181.94,168.33 181.43,168.84 180.22,168.84 179.5,168.11 177.31,168.11 176.42,167.22 174.97,167.22 174.15,168.04 173.32,168.04 172.35,167.07 171.51,167.07 170.44,166 169.67,166 169.41,165.74
  TOP w0.102: 143.87,161.54 142.75,161.54 140.47,159.27 137.95,159.27 U6.K29
  TOP w0.229: 143.87,161.54 144.82,161.54 148.74,165.46 160.26,165.46 160.9,166.1 169.05,166.1 169.41,165.74
MEM_MB_CKE0: length 51.4
  TOP w0.099: J2.50 178.91,160.55 178.64,160.82 178.04,160.82 177.94,160.72 177.94,159.75 177.82,159.63 177.66,159.63 177.54,159.75 177.54,161.35 177.43,161.47 177.26,161.47 177.15,161.35 177.15,159.82 177.03,159.7 176.87,159.7 176.75,159.82 176.75,160.72 176.65,160.82 175.05,160.82 174.64,160.41 173.18,160.41 172.14,159.37 171.48,159.37 170.08,160.77 168.88,160.77
  TOP w0.102: U6.M29 137.95,156.73 140.3,156.73 141.08,157.5 141.85,157.5 143.54,159.2
  TOP w0.229: 168.88,160.77 165.17,160.77 163.6,159.2 143.54,159.2
MEM_MB_CKE1: length 51
  TOP w0.099: 168.97,161.3 170.28,161.3 170.57,161.59 173.98,161.59 175.14,162.76 179,162.76 180.35,161.42 182.64,161.42 184.03,162.81 184.7,162.81 184.92,162.59 184.92,160.42 J2.169
  TOP w0.102: 143.82,159.73 143.52,159.73 141.57,157.78 140.68,157.78 U6.M31
  TOP w0.229: 168.97,161.3 164.79,161.3 163.22,159.73 143.82,159.73
MEM_MB_DATA0: length 97.5
  TOP w0.099: 169.02,210.78 169.42,210.37 170.52,210.37 170.98,210.83 172.32,210.83 173.17,209.98 174.68,209.98 174.83,210.13 174.83,210.67 175.02,210.86 177.69,210.86 178.43,210.12 180.8,210.12 J2.3 ; 115.99,173.08 115.99,172.8 116.76,172.02 116.76,167.75 U6.D13
  TOP w0.229: 115.99,173.08 115.38,173.69 115.38,178.44 118.71,181.77 118.71,182.85 139.16,203.29 139.55,203.29 139.87,203.62 139.87,204.01 140.2,204.33 140.59,204.33 140.91,204.66 140.91,205.05 141.24,205.37 141.63,205.37 141.96,205.7 141.96,206.09 142.28,206.42 142.67,206.42 143,206.74 143,207.13 143.32,207.46 143.71,207.46 144.04,207.78 144.04,208.17 144.37,208.5 144.76,208.5 145.08,208.82 145.08,209.22 145.41,209.54 145.8,209.54 146.12,209.87 146.12,210.26 146.65,210.78 148.46,210.78 148.78,211.1 149.38,211.1 149.69,210.78 150.29,210.78 150.61,211.1 151.21,211.1 151.52,210.78 152.12,210.78 152.44,211.1 153.03,211.1 153.35,210.78 153.95,210.78 154.27,211.1 154.86,211.1 155.18,210.78 155.78,210.78 156.09,211.1 156.69,211.1 157.01,210.78 157.61,210.78 157.92,211.1 158.52,211.1 158.84,210.78 159.44,210.78 159.75,211.1 160.35,211.1 160.67,210.78 161.26,210.78 161.58,211.1 162.18,211.1 162.5,210.78 163.09,210.78 163.41,211.1 164.01,211.1 164.32,210.78 164.92,210.78 165.24,211.1 165.84,211.1 166.15,210.78 166.75,210.78 167.07,211.1 167.66,211.1 167.98,210.78 169.02,210.78
MEM_MB_DATA1: length 97.7
  TOP w0.099: 116.01,173.58 117.19,172.4 U6.A13 ; J2.4 178.91,209.17 178.91,209.17 177.53,210.55 176.64,210.55 176.44,210.36 176.44,209.93 175.62,209.1 175.22,209.1 175.07,209.25 175.07,209.5 174.92,209.65 174.55,209.65 174.49,209.59 174.49,208.3 174.34,208.15 173.12,208.15 172.97,208.3 172.97,209.51 172.88,209.6 172.45,209.6 171.95,209.1 171.58,209.1 170.57,210.12 168.57,210.12
  TOP w0.229: 116.01,173.58 116.01,178.32 119.24,181.55 119.24,182.51 135.01,198.28 135.98,198.28 136.5,198.8 136.5,199.11 136.31,199.29 136.31,199.58 136.55,199.82 136.83,199.82 137.02,199.63 137.33,199.63 137.54,199.84 137.54,200.15 137.3,200.39 137.3,200.67 137.54,200.91 137.82,200.91 138.06,200.67 138.37,200.67 138.58,200.88 138.58,201.19 138.4,201.38 138.4,201.67 138.63,201.9 138.92,201.9 139.11,201.71 139.41,201.71 139.63,201.93 139.63,202.23 139.62,202.24 139.62,202.54 139.84,202.76 140.14,202.76 140.15,202.75 140.45,202.75 140.67,202.97 140.67,203.27 140.66,203.28 140.66,203.58 140.88,203.8 141.18,203.8 141.19,203.79 141.49,203.79 141.71,204.01 141.71,204.31 141.7,204.32 141.7,204.63 141.92,204.84 142.23,204.84 142.23,204.84 142.54,204.84 142.75,205.05 142.75,205.36 142.75,205.36 142.75,205.67 142.96,205.88 143.27,205.88 143.27,205.88 143.58,205.88 143.79,206.09 143.79,206.4 143.79,206.4 143.79,206.71 144,206.93 144.31,206.93 144.32,206.92 144.62,206.92 144.84,207.14 144.84,207.44 144.83,207.45 144.83,207.75 145.05,207.97 145.35,207.97 145.36,207.96 145.66,207.96 145.88,208.18 145.88,208.48 145.87,208.49 145.87,208.79 146.09,209.01 146.39,209.01 146.4,209 146.7,209 147.89,210.19 148.73,210.19 148.98,209.93 149.91,209.93 150.22,210.25 150.83,210.25 151.14,209.93 151.74,209.93 152.05,210.25 152.66,210.25 152.97,209.93 153.57,209.93 153.88,210.25 154.48,210.25 154.8,209.93 155.4,209.93 155.71,210.25 156.31,210.25 156.62,209.93 157.23,209.93 157.54,210.25 158.14,210.25 158.45,209.93 159.06,209.93 159.37,210.25 159.97,210.25 160.28,209.93 160.89,209.93 161.2,210.25 161.8,210.25 162.11,209.93 162.71,209.93 163.03,210.25 163.63,210.25 163.94,209.93 164.54,209.93 164.85,210.25 165.46,210.25 165.77,209.93 166.37,209.93 166.68,210.25 167.29,210.25 167.6,209.93 168.39,209.93 168.57,210.12
MEM_MB_DATA2: length 97.9
  TOP w0.099: J2.9 180.81,203.91 180.22,203.33 179.84,203.33 179.35,203.82 178.01,203.82 177.63,204.2 176.69,204.2 176.05,204.84 175.27,204.84 174.25,203.82 172.9,203.82 172.71,204.01 172.71,204.27 172.14,204.84 171.23,204.84 170.23,205.84 169.56,205.84 169.09,205.37 ; 119.73,172.62 U6.A15
  TOP w0.229: 119.73,172.62 119.87,172.76 119.87,176.39 120.4,176.91 120.4,177.23 120,177.63 120,177.91 120.36,178.27 120.65,178.27 121.04,177.88 121.37,177.88 121.69,178.2 121.69,178.53 121.3,178.91 121.3,179.2 121.66,179.56 121.95,179.56 122.34,179.17 122.66,179.17 122.98,179.5 122.98,179.82 122.59,180.21 122.59,180.49 122.95,180.85 123.24,180.85 123.63,180.47 123.95,180.47 124.28,180.79 124.28,181.11 123.89,181.5 123.89,181.79 124.25,182.15 124.53,182.15 124.92,181.76 125.25,181.76 125.57,182.08 125.57,182.41 125.18,182.79 125.18,183.08 125.54,183.44 125.83,183.44 126.22,183.05 126.54,183.05 126.86,183.38 126.86,183.7 126.47,184.09 126.47,184.38 126.83,184.73 127.12,184.73 127.51,184.35 127.83,184.35 128.16,184.67 128.16,184.99 127.77,185.38 127.77,185.67 128.13,186.03 128.41,186.03 128.8,185.64 129.13,185.64 129.45,185.96 129.45,186.29 129.06,186.67 129.06,186.96 129.42,187.32 129.71,187.32 130.1,186.93 130.42,186.93 130.74,187.26 130.74,187.58 130.35,187.97 130.35,188.26 130.71,188.61 131,188.61 131.39,188.23 131.71,188.23 132.04,188.55 132.04,188.87 131.65,189.26 131.65,189.55 132.01,189.91 132.29,189.91 132.68,189.52 133.01,189.52 134.85,191.37 134.85,192.83 147.4,205.37 166.15,205.37 166.36,205.15 166.36,204.56 166.58,204.34 166.88,204.34 167.1,204.56 167.1,205.15 167.31,205.37 169.09,205.37
MEM_MB_DATA3: length 97.5
  TOP w0.099: 168.54,204.63 169,204.63 169.26,204.37 170.69,204.37 170.88,204.18 170.88,203.98 171.48,203.39 172.83,203.39 172.97,203.24 172.97,202.81 173.43,202.35 174,202.35 175.01,203.36 178.65,203.36 J2.10
  TOP w0.102: 120.53,172.93 120.23,172.62 120.23,172.34 120.17,172.28 120.17,169.22 119.73,168.79 U6.C15
  TOP w0.229: 120.53,172.93 120.53,176.29 125.37,181.13 135.39,191.15 135.39,192.61 146.52,203.73 148.01,203.73 148.24,203.96 148.24,204.61 148.47,204.84 148.93,204.84 149.15,204.61 149.15,203.96 149.38,203.73 149.84,203.73 150.07,203.96 150.07,204.61 150.3,204.84 150.75,204.84 150.98,204.61 150.98,203.96 151.21,203.73 151.67,203.73 151.9,203.96 151.9,204.61 152.13,204.84 152.58,204.84 152.81,204.61 152.81,203.96 153.04,203.73 153.5,203.73 153.73,203.96 153.73,204.61 153.95,204.84 154.41,204.84 154.64,204.61 154.64,203.96 154.87,203.73 155.33,203.73 155.55,203.96 155.55,204.61 155.78,204.84 156.24,204.84 156.47,204.61 156.47,203.96 156.7,203.73 157.16,203.73 157.38,203.96 157.38,204.61 157.61,204.84 158.07,204.84 158.3,204.61 158.3,203.96 158.53,203.73 158.98,203.73 159.21,203.96 159.21,204.61 159.44,204.84 159.9,204.84 160.13,204.61 160.13,203.96 160.36,203.73 160.81,203.73 161.04,203.96 161.04,204.61 161.27,204.84 161.73,204.84 161.96,204.61 161.96,203.96 162.18,203.73 162.64,203.73 162.87,203.96 162.87,204.61 163.1,204.84 163.56,204.84 163.78,204.61 163.78,203.96 164.01,203.73 164.47,203.73 164.7,203.96 164.7,204.61 164.93,204.84 165.38,204.84 165.61,204.61 165.61,203.96 165.84,203.73 167.49,203.73 168.39,204.63 168.54,204.63
MEM_MB_DATA4: length 99.8
  TOP w0.099: U6.F13 116.36,165.62 116.36,171.54 113.98,173.91 113.98,174.24 ; 170.13,212.36 171.11,211.37 172.44,211.37 172.96,211.89 174.6,211.89 175.11,211.37 176.14,211.37 176.6,211.84 179.54,211.84 180.27,211.11 J2.122
  TOP w0.229: 113.98,174.24 113.98,178.55 117.64,182.21 117.64,183.29 146.71,212.36 170.13,212.36
MEM_MB_DATA5: length 99.6
  TOP w0.099: U6.E13 116.56,166.68 116.56,171.82 114.69,173.69 ; J2.123 184.61,210.11 182.39,210.11 181.66,210.84 180.21,210.84 179.75,210.37 178.59,210.37 177.86,211.11 174.92,211.11 174.18,210.37 173.35,210.37 172.61,211.11 171.01,211.11 170.21,211.91 169.49,211.91
  TOP w0.229: 114.69,173.69 114.69,178.51 118.18,181.99 118.18,183.07 146.74,211.63 169.21,211.63 169.49,211.91
MEM_MB_DATA6: length 97.7
  TOP w0.099: 118.53,174.24 118.53,172.97 ; 169,206.45 169.36,206.45 169.45,206.36 170.49,206.36 171.51,205.34 172.39,205.34 173.37,204.37 174.01,204.37 174.98,205.34 177.71,205.34 178.16,204.89 178.16,204.61 178.39,204.37 179.62,204.37 179.83,204.58 179.83,205.12 179.99,205.28 182.53,205.28 J2.128
  TOP w0.102: 118.53,172.97 118.53,171.19 U6.A14
  TOP w0.229: 169,206.45 168.33,206.45 168.11,206.67 168.11,207.7 167.9,207.92 167.59,207.92 167.38,207.7 167.38,206.67 167.16,206.45 166.3,206.45 165.71,207.04 164.3,207.04 164.07,207.27 164.07,207.53 163.84,207.76 163.39,207.76 163.16,207.53 163.16,207.27 162.93,207.04 162.47,207.04 162.24,207.27 162.24,207.53 162.01,207.76 161.56,207.76 161.33,207.53 161.33,207.27 161.1,207.04 160.64,207.04 160.41,207.27 160.41,207.53 160.19,207.76 159.73,207.76 159.5,207.53 159.5,207.27 159.27,207.04 158.81,207.04 158.59,207.27 158.59,207.53 158.36,207.76 157.9,207.76 157.67,207.53 157.67,207.27 157.44,207.04 156.98,207.04 156.76,207.27 156.76,207.53 156.53,207.76 156.07,207.76 155.84,207.53 155.84,207.27 155.61,207.04 155.16,207.04 154.93,207.27 154.93,207.7 154.72,207.9 154.22,207.9 154.01,207.7 154.01,207.27 153.78,207.04 153.33,207.04 153.1,207.27 153.1,207.7 152.9,207.9 152.39,207.9 152.18,207.7 152.18,207.27 151.96,207.04 151.5,207.04 151.27,207.27 151.27,207.7 151.07,207.9 150.56,207.9 150.36,207.7 150.36,207.27 150.13,207.04 149.67,207.04 149.44,207.27 149.44,207.7 149.24,207.9 148.73,207.9 148.53,207.7 148.53,207.27 148.3,207.04 147.56,207.04 118.53,178.01 118.53,174.24
MEM_MB_DATA7: length 98.5
  TOP w0.099: J2.129 184.96,204.11 185.19,204.34 185.19,205.05 184.99,205.25 184.01,205.25 183.09,204.33 182.06,204.33 181.91,204.48 181.91,204.82 181.76,204.97 180.3,204.97 180.11,204.78 180.11,204.39 179.82,204.1 178.19,204.1 177.2,205.09 175.14,205.09 174.15,204.1 173.26,204.1 172.27,205.09 171.38,205.09 170.37,206.11 169.2,206.11 ; 119.73,169.86 119.19,170.4 119.19,170.95
  TOP w0.102: 119.19,171.89 119.19,170.95 ; 119.73,169.86 U6.B15
  TOP w0.229: 119.19,171.89 119.19,177.91 132.74,191.47 133.06,191.47 133.35,191.18 133.67,191.18 134,191.5 134,191.83 133.71,192.11 133.71,192.44 147.18,205.9 148,205.9 148.23,206.13 148.23,206.28 148.45,206.51 148.91,206.51 149.14,206.28 149.14,206.13 149.37,205.9 149.83,205.9 150.05,206.13 150.05,206.28 150.28,206.51 150.74,206.51 150.97,206.28 150.97,206.13 151.2,205.9 151.65,205.9 151.88,206.13 151.88,206.28 152.11,206.51 152.57,206.51 152.8,206.28 152.8,206.13 153.03,205.9 153.48,205.9 153.71,206.13 153.71,206.28 153.94,206.51 154.4,206.51 154.63,206.28 154.63,206.13 154.86,205.9 155.31,205.9 155.54,206.13 155.54,206.28 155.77,206.51 156.23,206.51 156.46,206.28 156.46,206.13 156.68,205.9 157.14,205.9 157.37,206.13 157.37,206.28 157.6,206.51 158.06,206.51 158.28,206.28 158.28,206.13 158.51,205.9 158.97,205.9 159.2,206.13 159.2,206.28 159.43,206.51 159.88,206.51 160.11,206.28 160.11,206.13 160.34,205.9 160.8,205.9 161.03,206.13 161.03,206.28 161.26,206.51 161.71,206.51 161.94,206.28 161.94,206.13 162.17,205.9 162.63,205.9 162.86,206.13 162.86,206.28 163.08,206.51 163.54,206.51 163.77,206.28 163.77,206.13 164,205.9 164.46,205.9 164.68,206.13 164.68,206.28 164.91,206.51 165.37,206.51 165.6,206.28 165.6,206.13 165.83,205.9 168.99,205.9 169.2,206.11
MEM_MB_DATA8: length 88.5
  TOP w0.099: 171.24,201.37 172.56,201.37 172.86,201.07 172.86,200.91 173.44,200.34 174.01,200.34 174.33,200.66 174.33,200.67 175.01,201.36 176.04,201.36 176.42,201.73 176.42,202.36 176.55,202.5 177.51,202.5 J2.12 ; 169.94,202.01 169.36,202.01
  TOP w0.102: 169.94,202.01 170.33,202.4 170.67,202.4 170.85,202.22 170.85,201.76 171.24,201.37
  TOP w0.229: U6.A16 121,171.49 122.46,172.95 122.46,175.92 137.49,190.94 137.49,191.27 137.06,191.69 137.06,192.02 137.38,192.34 137.71,192.34 138.13,191.91 138.46,191.91 138.78,192.24 138.78,192.56 138.35,192.99 138.35,193.31 138.68,193.63 139,193.63 139.43,193.21 139.75,193.21 140.07,193.53 140.07,193.85 139.65,194.28 139.65,194.6 139.97,194.93 140.29,194.93 140.72,194.5 141.04,194.5 141.37,194.82 141.37,195.15 140.94,195.57 140.94,195.9 141.26,196.22 141.59,196.22 142.01,195.79 142.34,195.79 142.66,196.12 142.66,196.44 142.23,196.87 142.23,197.19 142.56,197.51 142.88,197.51 143.31,197.09 143.63,197.09 143.95,197.41 143.95,197.73 143.53,198.16 143.53,198.48 143.85,198.81 144.17,198.81 144.6,198.38 144.92,198.38 145.25,198.7 145.25,199.03 144.82,199.45 144.82,199.78 145.14,200.1 145.47,200.1 145.89,199.67 146.22,199.67 146.54,200 146.54,200.32 146.11,200.75 146.11,201.07 146.44,201.39 146.76,201.39 147.19,200.97 147.51,200.97 148.03,201.49 168.57,201.49 169.09,202.01 169.36,202.01
MEM_MB_DATA9: length 88.8
  TOP w0.099: 171.03,201.1 172.28,201.1 173.29,200.09 174.25,200.09 174.6,200.44 174.6,200.57 175.14,201.1 177.81,201.1 178.65,200.26 179.39,200.26 179.99,199.66 180.36,199.66 J2.13 ; 169.69,200.22 169.07,200.84
  TOP w0.102: 171.03,201.1 170.63,200.7 170.63,200.47 170.39,200.22 169.69,200.22
  TOP w0.229: U6.A17 122.27,172.05 122.92,172.69 122.92,173.23 123.18,173.48 123.18,174.99 123.7,175.51 123.7,175.83 123.58,175.95 123.58,176.28 123.9,176.6 124.22,176.6 124.34,176.48 124.67,176.48 124.99,176.8 124.99,177.13 124.87,177.25 124.87,177.57 125.19,177.89 125.52,177.89 125.64,177.77 125.96,177.77 126.28,178.1 126.28,178.42 126.16,178.54 126.16,178.86 126.49,179.19 126.81,179.19 126.93,179.07 127.25,179.07 127.58,179.39 127.58,179.71 127.46,179.83 127.46,180.16 127.78,180.48 128.1,180.48 128.22,180.36 128.55,180.36 128.87,180.68 128.87,181.01 128.75,181.13 128.75,181.45 129.07,181.77 129.4,181.77 129.52,181.65 129.84,181.65 130.16,181.98 130.16,182.3 130.04,182.42 130.04,182.74 130.37,183.07 130.69,183.07 130.81,182.95 131.13,182.95 131.46,183.27 131.46,183.59 131.34,183.71 131.34,184.04 131.66,184.36 131.98,184.36 132.1,184.24 132.43,184.24 132.75,184.56 132.75,184.89 132.63,185.01 132.63,185.33 132.95,185.65 133.28,185.65 133.4,185.53 133.72,185.53 134.04,185.86 134.04,186.18 133.92,186.3 133.92,186.62 134.25,186.95 134.57,186.95 134.69,186.83 135.01,186.83 135.34,187.15 135.34,187.47 135.22,187.59 135.22,187.92 135.54,188.24 135.86,188.24 135.98,188.12 136.31,188.12 136.63,188.44 136.63,188.77 136.51,188.89 136.51,189.21 136.83,189.53 137.16,189.53 137.28,189.41 137.6,189.41 137.92,189.74 137.92,190.06 137.8,190.18 137.8,190.5 138.13,190.83 138.45,190.83 138.57,190.71 138.89,190.71 139.22,191.03 139.22,191.35 139.1,191.47 139.1,191.8 139.42,192.12 139.74,192.12 139.86,192 140.19,192 140.51,192.32 140.51,192.65 140.39,192.77 140.39,193.09 140.71,193.41 141.04,193.41 141.16,193.29 141.48,193.29 141.8,193.62 141.8,193.94 141.68,194.06 141.68,194.38 142.01,194.71 142.33,194.71 142.45,194.59 142.77,194.59 143.1,194.91 143.1,195.23 142.98,195.35 142.98,195.68 143.3,196 143.62,196 143.74,195.88 144.07,195.88 144.39,196.2 144.39,196.53 144.27,196.65 144.27,196.97 144.59,197.29 144.92,197.29 145.04,197.17 145.36,197.17 145.68,197.5 145.68,197.82 145.56,197.94 145.56,198.26 145.89,198.59 146.21,198.59 146.33,198.47 146.65,198.47 146.98,198.79 146.98,199.11 146.86,199.23 146.86,199.56 147.18,199.88 147.5,199.88 147.62,199.76 147.95,199.76 149.14,200.95 168.96,200.95 169.07,200.84
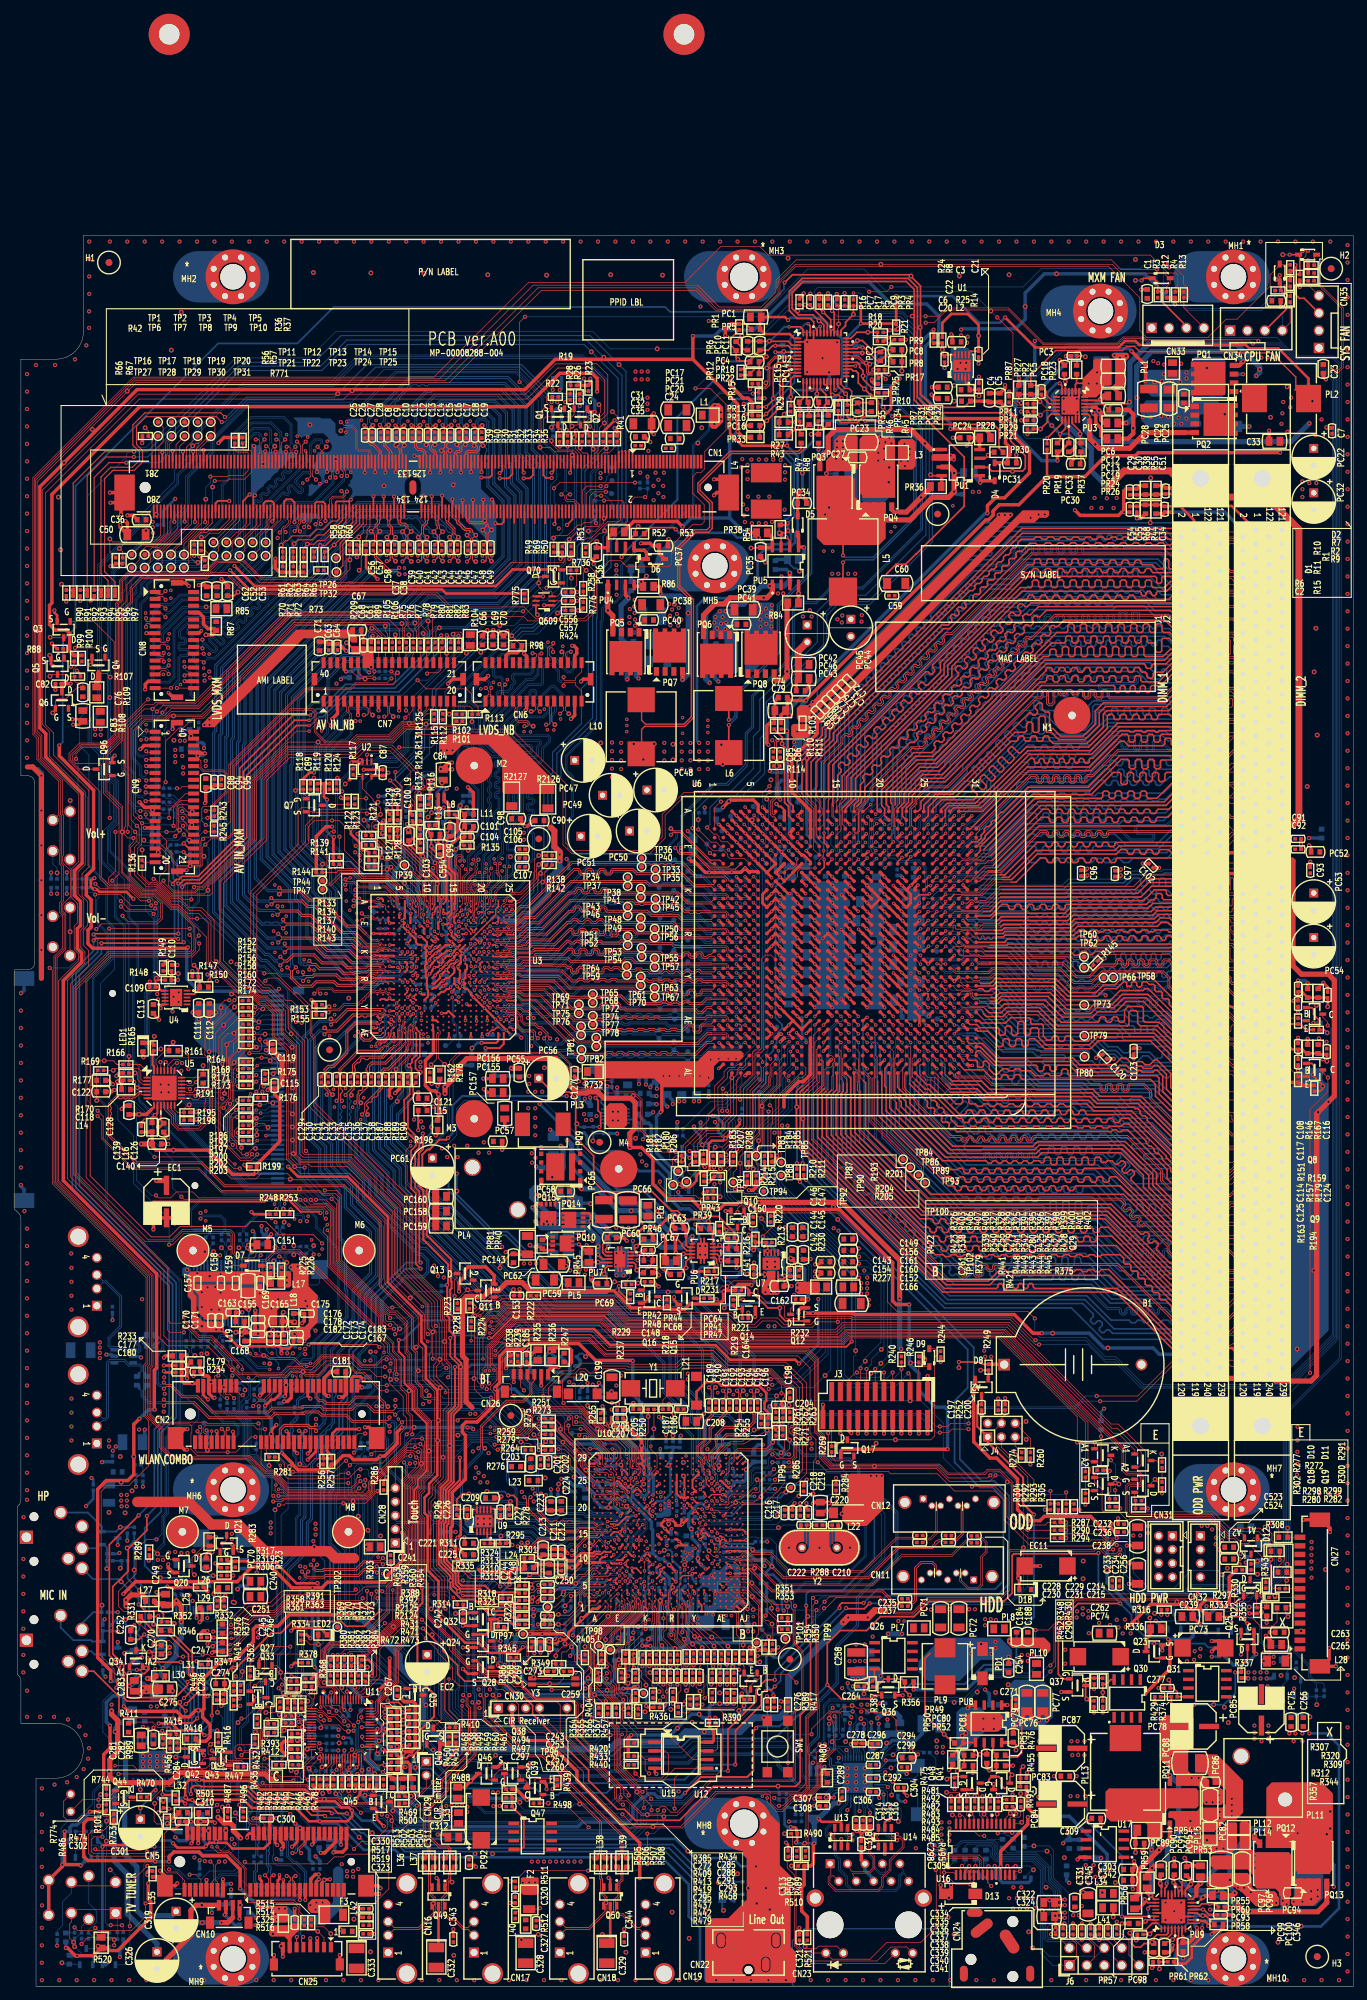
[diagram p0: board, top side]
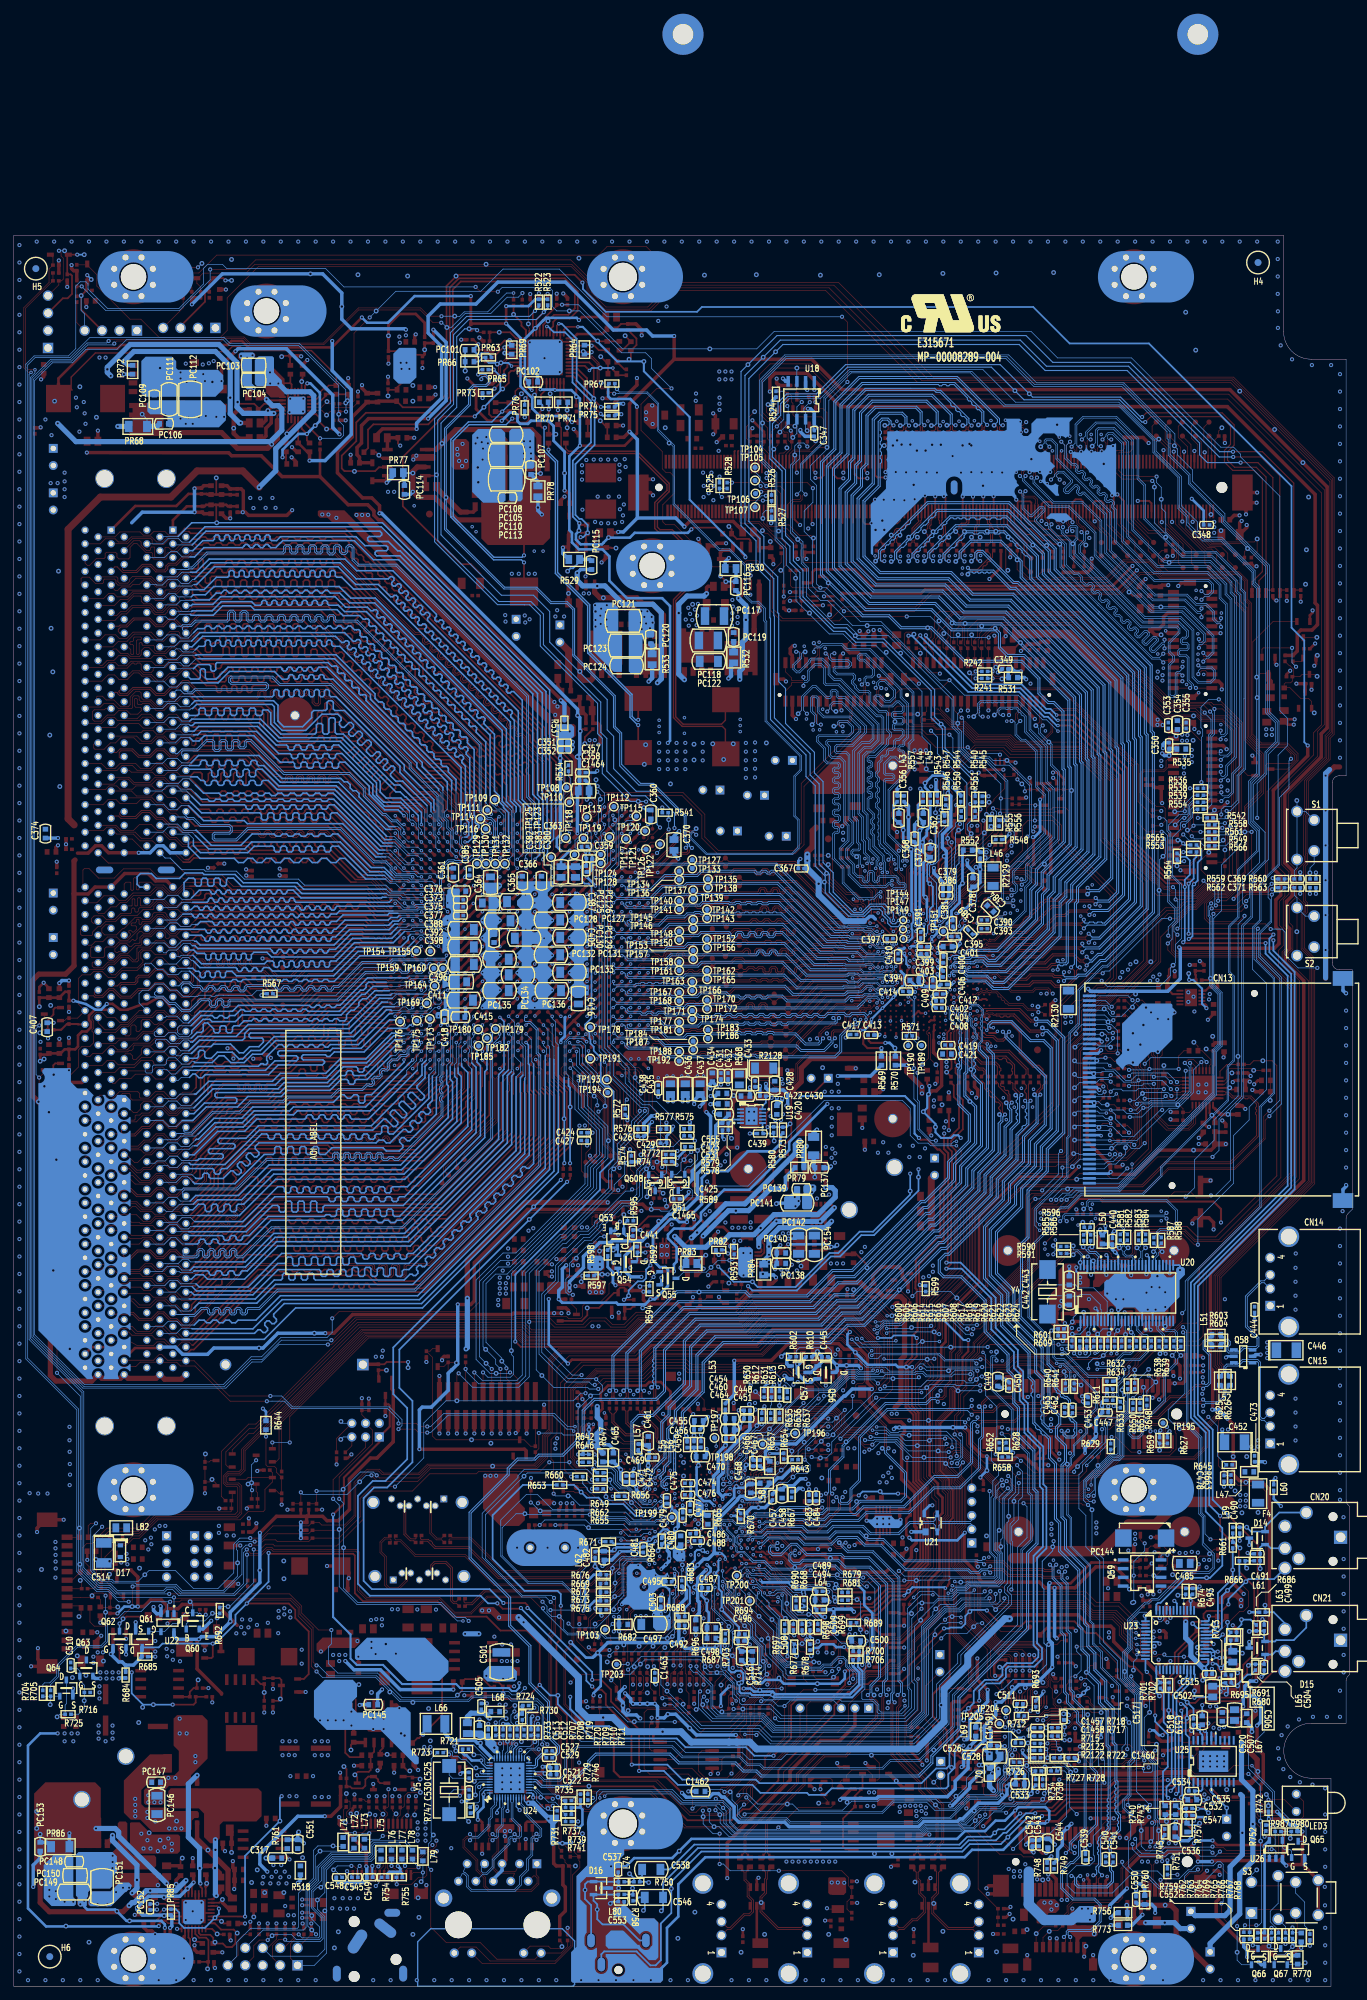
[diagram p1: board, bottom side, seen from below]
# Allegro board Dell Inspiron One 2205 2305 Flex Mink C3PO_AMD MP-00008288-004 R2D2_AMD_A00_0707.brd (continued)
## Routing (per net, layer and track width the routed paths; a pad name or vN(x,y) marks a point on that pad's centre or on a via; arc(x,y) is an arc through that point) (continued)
MEM_MB_DATA10: length 88.5
  TOP w0.099: J2.18 178.35,195.11 177.95,194.7 177.95,194.09 177.82,193.97 177.65,193.97 177.53,194.09 177.53,195.29 177.68,195.44 177.96,195.44 178.08,195.56 178.08,195.73 177.96,195.86 177.7,195.86 177.55,196.01 177.55,196.38 177.4,196.53 176.51,196.53 176.39,196.41 176.39,196.24 176.51,196.13 176.98,196.13 177.13,195.98 177.13,194.1 177.01,193.99 176.84,193.99 176.72,194.1 176.72,195.59 176.6,195.71 176.43,195.71 176.3,195.59 176.3,195.41 176.22,195.33 174.66,195.33 174.48,195.16 174.48,194.69 174.17,194.37 173.03,194.37 172.11,195.29 171.25,195.29 170.69,195.85 168.68,195.85
  TOP w0.229: U6.A21 127.35,171.77 126.96,172.16 126.96,174.19 131.4,178.63 134.01,178.63 151.04,195.66 152.87,195.66 153.1,195.89 153.1,196.44 153.33,196.67 153.78,196.67 154.01,196.44 154.01,195.89 154.24,195.66 154.7,195.66 154.93,195.89 154.93,196.44 155.16,196.67 155.61,196.67 155.84,196.44 155.84,195.89 156.07,195.66 156.53,195.66 156.76,195.89 156.76,196.44 156.98,196.67 157.44,196.67 157.67,196.44 157.67,195.89 157.9,195.66 158.36,195.66 158.58,195.89 158.58,196.44 158.81,196.67 159.27,196.67 159.5,196.44 159.5,195.89 159.73,195.66 160.18,195.66 160.41,195.89 160.41,196.44 160.64,196.67 161.1,196.67 161.33,196.44 161.33,195.89 161.56,195.66 162.01,195.66 162.24,195.89 162.24,196.44 162.47,196.67 162.93,196.67 163.16,196.44 163.16,195.89 163.39,195.66 163.84,195.66 164.07,195.89 164.07,196.44 164.3,196.67 164.76,196.67 164.99,196.44 164.99,195.89 165.21,195.66 165.95,195.66 166.18,195.43 166.18,194.52 166.41,194.29 166.87,194.29 167.09,194.52 167.09,196.17 167.27,196.34 168.18,196.34 168.68,195.85
MEM_MB_DATA11: length 88.5
  TOP w0.099: 169.22,194.74 169.6,194.37 170.77,194.37 171.35,194.95 172.02,194.95 172.85,194.12 174.4,194.12 175.31,195.03 175.96,195.03 176.43,194.55 176.43,193.95 176.69,193.7 177.96,193.7 178.37,194.11 179.38,194.11 180.06,194.78 180.47,194.78 180.81,194.44 J2.19
  TOP w0.102: U6.C21 127.36,168.59 127.79,169.02 127.79,172.25
  TOP w0.229: 169.22,194.74 168.34,194.74 167.28,193.69 164.73,193.69 164.5,193.92 164.5,194.9 164.27,195.13 163.82,195.13 163.59,194.9 163.59,193.92 163.36,193.69 162.9,193.69 162.67,193.92 162.67,194.9 162.45,195.13 161.99,195.13 161.76,194.9 161.76,193.92 161.53,193.69 161.07,193.69 160.85,193.92 160.85,194.9 160.62,195.13 160.16,195.13 159.93,194.9 159.93,193.92 159.7,193.69 159.25,193.69 159.02,193.92 159.02,194.9 158.79,195.13 158.33,195.13 158.1,194.9 158.1,193.92 157.87,193.69 157.42,193.69 157.19,193.92 157.19,194.9 156.96,195.13 156.5,195.13 156.27,194.9 156.27,193.92 156.04,193.69 155.59,193.69 155.36,193.92 155.36,194.9 155.13,195.13 154.67,195.13 154.44,194.9 154.44,193.92 154.22,193.69 153.76,193.69 153.53,193.92 153.53,194.9 153.3,195.13 152.84,195.13 152.62,194.9 152.62,193.92 152.39,193.69 151.93,193.69 151.7,193.92 151.7,194.55 151.5,194.76 150.99,194.76 150.79,194.55 150.79,193.92 150.56,193.69 149.82,193.69 134.23,178.09 131.62,178.09 127.62,174.09 127.62,172.41 127.79,172.25
MEM_MB_DATA12: length 89
  TOP w0.099: J2.131 181.93,202.11 181.17,202.87 180.41,202.87 179.92,202.37 178.41,202.37 177.68,203.11 175.19,203.11 174.17,202.09 173.28,202.09 172.27,203.11 171.38,203.11 170.39,204.1 168.7,204.1
  TOP w0.102: U6.D15 119.73,167.72 120.37,168.36 120.37,172.2 121.19,173.02
  TOP w0.229: 168.7,204.1 167.8,203.2 166.53,203.2 166.31,202.98 166.31,202.77 166.09,202.55 165.79,202.55 165.57,202.77 165.57,202.98 165.36,203.2 165.05,203.2 164.84,202.98 164.84,202.77 164.62,202.55 164.32,202.55 164.1,202.77 164.1,202.98 163.89,203.2 146.74,203.2 135.92,192.38 135.92,190.93 121.19,176.2 121.19,173.02
MEM_MB_DATA13: length 90.2
  TOP w0.099: J2.132 180.35,201.11 179.45,202 178.38,202 177.55,202.84 175.31,202.84 174.31,201.84 173.16,201.84 172.16,202.84 171.25,202.84 170.24,203.85 169.23,203.85 168.96,203.58
  TOP w0.102: U6.C16 121,168.83 120.57,169.26 120.57,171.58 120.67,171.68
  TOP w0.229: 120.67,171.68 121.83,172.84 121.83,176.04 136.53,190.74 136.53,192.24 146.31,202.02 147.37,202.02 147.6,202.25 147.6,202.42 147.83,202.64 148.28,202.64 148.51,202.42 148.51,202.25 148.74,202.02 149.2,202.02 149.43,202.25 149.43,202.42 149.66,202.64 150.11,202.64 150.34,202.42 150.34,202.25 150.57,202.02 151.03,202.02 151.26,202.25 151.26,202.42 151.48,202.64 151.94,202.64 152.17,202.42 152.17,202.25 152.4,202.02 152.86,202.02 153.08,202.25 153.08,202.42 153.31,202.64 153.77,202.64 154,202.42 154,202.25 154.23,202.02 154.68,202.02 154.91,202.25 154.91,202.42 155.14,202.64 155.6,202.64 155.83,202.42 155.83,202.25 156.06,202.02 156.51,202.02 156.74,202.25 156.74,202.42 156.97,202.64 157.43,202.64 157.66,202.42 157.66,202.25 157.88,202.02 158.34,202.02 158.57,202.25 158.57,202.42 158.8,202.64 159.26,202.64 159.48,202.42 159.48,202.25 159.71,202.02 160.17,202.02 160.4,202.25 160.4,202.42 160.63,202.64 161.09,202.64 161.31,202.42 161.31,202.25 161.54,202.02 162,202.02 162.23,202.25 162.23,202.42 162.46,202.64 162.91,202.64 163.14,202.42 163.14,202.25 163.37,202.02 168.13,202.02 168.96,202.85 168.96,203.58
MEM_MB_DATA14: length 88.9
  TOP w0.099: 170.81,197.12 170.81,196.76 170.42,196.38 169.5,196.38 ; 169.17,196.71 169.17,197.39 168.54,198.02 ; 172.26,197.31 173.32,196.25 173.98,196.25 174.98,197.24 177.61,197.24 178.55,196.3 179.61,196.3 180.15,196.85 181.69,196.85 182.43,196.11 J2.137
  TOP w0.102: 172.26,197.31 170.99,197.31 170.81,197.12 ; 169.5,196.38 169.17,196.71
  TOP w0.229: 168.54,198.02 167.58,198.98 152.85,198.98 151.9,198.03 151.58,198.03 151.4,198.21 151.08,198.21 150.76,197.89 150.76,197.56 150.93,197.39 150.93,197.06 150.61,196.74 150.29,196.74 150.11,196.92 149.79,196.92 149.46,196.59 149.46,196.27 149.64,196.09 149.64,195.77 149.32,195.45 148.99,195.45 148.82,195.62 148.49,195.62 148.17,195.3 148.17,194.98 148.35,194.8 148.35,194.48 148.02,194.15 147.7,194.15 147.52,194.33 147.2,194.33 146.88,194.01 146.88,193.68 147.05,193.51 147.05,193.18 146.73,192.86 146.41,192.86 146.23,193.04 145.91,193.04 145.58,192.71 145.58,192.39 145.76,192.21 145.76,191.89 145.44,191.57 145.11,191.57 144.94,191.74 144.61,191.74 144.29,191.42 144.29,191.1 144.47,190.92 144.47,190.6 144.14,190.27 143.82,190.27 143.64,190.45 143.32,190.45 143,190.13 143,189.8 143.17,189.63 143.17,189.3 142.85,188.98 142.53,188.98 142.35,189.16 142.03,189.16 141.7,188.83 141.7,188.51 141.88,188.33 141.88,188.01 141.56,187.69 141.23,187.69 141.06,187.86 140.73,187.86 140.41,187.54 140.41,187.22 140.59,187.04 140.59,186.72 140.26,186.39 139.94,186.39 139.76,186.57 139.44,186.57 139.12,186.25 139.12,185.92 139.29,185.75 139.29,185.42 138.97,185.1 138.65,185.1 138.47,185.28 138.15,185.28 137.82,184.95 137.82,184.63 138,184.45 138,184.13 137.68,183.81 137.35,183.81 137.18,183.98 136.85,183.98 136.53,183.66 136.53,183.34 136.71,183.16 136.71,182.84 136.38,182.51 136.06,182.51 135.88,182.69 135.56,182.69 135.24,182.37 135.24,182.04 135.41,181.87 135.41,181.54 135.09,181.22 134.77,181.22 134.59,181.4 134.27,181.4 133.94,181.07 133.94,180.75 134.12,180.57 134.12,180.25 133.56,179.69 130.96,179.69 125.64,174.37 125.64,171.23 125.75,171.13 U6.A20
MEM_MB_DATA15: length 88.8
  TOP w0.099: 168.88,196.56 168.94,196.56 169.38,196.11 170.58,196.11 171.49,197.02 172.07,197.02 173.17,195.93 174.23,195.93 175.27,196.96 177.43,196.96 178.48,195.91 179.74,195.91 180.56,195.1 182.7,195.1 J2.138
  TOP w0.229: 168.88,196.56 168.24,197.21 167.36,197.21 167.13,197.43 167.13,198.22 166.9,198.45 166.44,198.45 166.22,198.22 166.22,197.43 165.99,197.21 165.53,197.21 165.3,197.43 165.3,198.22 165.07,198.45 164.62,198.45 164.39,198.22 164.39,197.43 164.16,197.21 163.7,197.21 163.47,197.43 163.47,198.22 163.24,198.45 162.79,198.45 162.56,198.22 162.56,197.43 162.33,197.21 161.87,197.21 161.64,197.43 161.64,198.22 161.42,198.45 160.96,198.45 160.73,198.22 160.73,197.43 160.5,197.21 160.04,197.21 159.82,197.43 159.82,198.22 159.59,198.45 159.13,198.45 158.9,198.22 158.9,197.43 158.67,197.21 158.21,197.21 157.99,197.43 157.99,198.22 157.76,198.45 157.3,198.45 157.07,198.22 157.07,197.43 156.84,197.21 156.39,197.21 156.16,197.43 156.16,198.22 155.93,198.45 155.47,198.45 155.24,198.22 155.24,197.43 155.01,197.21 154.56,197.21 154.33,197.43 154.33,198.22 154.1,198.45 153.64,198.45 153.41,198.22 153.41,197.43 153.19,197.21 151.83,197.21 133.78,179.16 131.18,179.16 126.3,174.28 126.3,171.96 126.72,171.54 126.72,170.49 U6.B21
MEM_MB_DATA16: length 72.3
  TOP w0.099: 169.17,192.65 169.47,192.34 170.71,192.34 171.2,192.82 172.16,192.82 172.92,192.06 174.51,192.06 174.69,191.88 174.69,191.65 174.96,191.37 176.03,191.37 176.43,191.77 176.43,192.55 176.62,192.74 176.99,192.74 177.14,192.59 177.39,192.59 177.53,192.74 177.73,192.74 178.47,192 180.7,192 J2.21
  TOP w0.229: U6.A22 128.62,171.45 129.55,172.38 129.55,173.76 132.29,176.49 135.1,176.49 150.26,191.65 150.26,191.86 150.48,192.09 150.94,192.09 151.17,191.86 151.17,191.65 151.4,191.42 151.86,191.42 152.09,191.65 152.09,191.86 152.31,192.09 152.77,192.09 153,191.86 153,191.65 153.23,191.42 153.69,191.42 153.91,191.65 153.91,191.86 154.14,192.09 154.6,192.09 154.83,191.86 154.83,191.65 155.06,191.42 155.51,191.42 155.74,191.65 155.74,191.86 155.97,192.09 156.43,192.09 156.66,191.86 156.66,191.65 156.89,191.42 157.34,191.42 157.57,191.65 157.57,191.86 157.8,192.09 158.26,192.09 158.49,191.86 158.49,191.65 158.71,191.42 159.17,191.42 159.4,191.65 159.4,191.86 159.63,192.09 160.09,192.09 160.31,191.86 160.31,191.65 160.54,191.42 161,191.42 161.23,191.65 161.23,191.86 161.46,192.09 161.91,192.09 162.14,191.86 162.14,191.65 162.37,191.42 162.83,191.42 163.06,191.65 163.06,191.86 163.29,192.09 163.74,192.09 163.97,191.86 163.97,191.65 164.2,191.42 164.71,191.42 164.94,191.19 164.94,190.76 165.17,190.53 165.63,190.53 165.85,190.76 165.85,191.19 166.08,191.42 167.27,191.42 168.5,192.65 169.17,192.65
MEM_MB_DATA17: length 72.2
  TOP w0.099: 168.81,192.09 170.38,192.09 171.25,191.22 172.3,191.22 173.27,190.26 174.12,190.26 174.96,191.11 176.16,191.11 176.66,191.6 177.68,191.6 178.18,191.1 178.91,191.1 J2.22
  TOP w0.229: U6.B23 129.33,170.42 129.33,171.57 130.21,172.45 130.21,173.66 132.51,175.96 135.32,175.96 149.36,190 150.1,190 150.33,190.22 150.33,190.65 150.55,190.88 151.01,190.88 151.24,190.65 151.24,190.22 151.47,190 151.93,190 152.15,190.22 152.15,190.65 152.38,190.88 152.84,190.88 153.07,190.65 153.07,190.22 153.3,190 153.76,190 153.98,190.22 153.98,190.65 154.21,190.88 154.67,190.88 154.9,190.65 154.9,190.22 155.13,190 155.58,190 155.81,190.22 155.81,190.65 156.04,190.88 156.5,190.88 156.73,190.65 156.73,190.22 156.96,190 157.41,190 157.64,190.22 157.64,190.65 157.87,190.88 158.33,190.88 158.56,190.65 158.56,190.22 158.78,190 159.24,190 159.47,190.22 159.47,190.65 159.7,190.88 160.16,190.88 160.38,190.65 160.38,190.22 160.61,190 161.07,190 161.3,190.22 161.3,190.65 161.53,190.88 161.98,190.88 162.21,190.65 162.21,190.22 162.44,190 162.9,190 163.13,190.22 163.13,190.65 163.36,190.88 163.81,190.88 164.04,190.65 164.04,190.22 164.27,190 166.65,190 168.74,192.09 168.81,192.09
MEM_MB_DATA18: length 73.6
  TOP w0.099: J2.27 181.62,186.11 181.8,185.93 183.27,185.93 183.53,185.67 183.53,184.53 183.27,184.28 182.26,184.28 181.37,185.17 180.35,185.17 179.65,185.86 178.56,185.86 177.99,185.29 176.92,185.29 176.42,185.79 176.42,186.16 176.56,186.3 177.22,186.3 177.41,186.49 177.41,187.47 177.29,187.59 177.13,187.59 177.01,187.47 177.01,186.82 176.88,186.69 176.37,186.69 176.24,186.83 175.24,186.83 174.27,185.86 173.08,185.86 172.11,186.84 171.24,186.84 170.59,186.18 168.54,186.18
  TOP w0.229: U6.B25 133.09,170.51 133.09,171.77 134.46,173.15 136.96,173.15 145.16,181.36 145.92,181.36 146.15,181.58 146.15,181.89 146.38,182.12 146.83,182.12 147.06,181.89 147.06,181.58 147.29,181.36 147.75,181.36 147.98,181.58 147.98,181.89 148.21,182.12 148.66,182.12 148.89,181.89 148.89,181.58 149.12,181.36 149.58,181.36 149.81,181.58 149.81,181.89 150.04,182.12 150.49,182.12 150.72,181.89 150.72,181.58 151.26,181.04 156.21,181.04 158.59,183.42 158.59,185.29 159.1,185.8 168.13,185.8 168.51,186.18 168.54,186.18
MEM_MB_DATA19: length 72
  TOP w0.099: 168.54,184.94 169.1,184.37 170.4,184.37 171.32,185.29 172.38,185.29 173.29,184.37 174.17,184.37 175.09,185.29 176.37,185.29 177.04,184.63 178.73,184.63 178.91,184.8 J2.28
  TOP w0.229: U6.A26 133.7,171.43 135.09,172.82 139.72,172.82 140.2,173.3 140.2,173.66 139.37,174.49 139.37,174.81 139.7,175.14 140.02,175.14 140.85,174.31 141.17,174.31 141.5,174.63 141.5,174.95 140.67,175.78 140.67,176.11 140.99,176.43 141.31,176.43 142.14,175.6 142.47,175.6 142.79,175.92 142.79,176.25 141.96,177.08 141.96,177.4 142.28,177.72 142.61,177.72 143.44,176.89 143.76,176.89 144.08,177.22 144.08,177.54 143.25,178.37 143.25,178.69 143.58,179.02 143.9,179.02 144.73,178.19 145.05,178.19 145.57,178.71 145.57,179.03 144.73,179.88 144.73,180.16 145.09,180.52 145.37,180.52 146.22,179.68 146.54,179.68 147.37,180.51 156.43,180.51 159.17,183.25 159.17,185.01 159.42,185.27 159.88,185.27 160.11,185.04 160.11,184.73 160.34,184.51 160.79,184.51 161.02,184.73 161.02,185.04 161.25,185.27 161.71,185.27 161.94,185.04 161.94,184.73 162.16,184.51 162.62,184.51 162.85,184.73 162.85,185.04 163.08,185.27 163.54,185.27 163.76,185.04 163.76,184.73 163.99,184.51 164.45,184.51 164.68,184.73 164.68,185.04 164.91,185.27 165.36,185.27 165.59,185.04 165.59,184.73 165.82,184.51 166.28,184.51 166.51,184.73 166.51,185.04 166.74,185.27 168.21,185.27 168.54,184.94
MEM_MB_DATA20: length 72
  TOP w0.099: 127.98,168.92 127.99,168.93 127.99,171.82 128.26,172.09 ; J2.140 182.77,193.04 182.77,192.75 182.38,192.36 182.15,192.36 181.4,193.11 180.41,193.11 179.68,193.84 178.5,193.84 178.04,193.37 175.07,193.37 174.58,193.86 173.06,193.86 172.56,193.37 171.22,193.37 170.48,194.11 169.5,194.11 169.4,194.2 168.82,194.2
  TOP w0.102: U6.D21 127.98,167.94 127.98,168.92
  TOP w0.229: 168.82,194.2 168.55,194.2 167.5,193.15 150.04,193.15 136.97,180.08 134.45,177.56 131.84,177.56 128.26,173.97 128.26,172.09
MEM_MB_DATA21: length 72.2
  TOP w0.099: 168.94,193.84 170.39,193.84 171.13,193.1 172.34,193.1 173.08,192.36 174.29,192.36 174.93,193 177.9,193 178.56,192.34 179.75,192.34 180.24,192.84 181.16,192.84 181.89,192.11 184.16,192.11 184.16,192.11 J2.141
  TOP w0.102: 128.89,172.26 128.19,171.56 128.19,169.02 U6.C22
  TOP w0.229: 168.94,193.84 167.72,192.62 165.9,192.62 165.67,192.39 165.67,192.18 165.44,191.95 164.98,191.95 164.75,192.18 164.75,192.39 164.52,192.62 150.26,192.62 134.67,177.03 132.06,177.03 128.89,173.85 128.89,172.26
MEM_MB_DATA22: length 72.7
  TOP w0.099: J2.146 182.92,187.31 182.92,187.81 182.81,187.91 182.08,187.91 181.53,187.36 180.41,187.36 179.41,186.37 178.33,186.37 178.03,186.66 178.03,187.79 177.25,188.57 176.63,188.57 176.44,188.38 176.44,187.7 176.1,187.36 ; 175,187.36 174.01,186.37 173.36,186.37 172.37,187.36 171.42,187.36 170.48,188.3 169.34,188.3
  TOP w0.102: 175,187.36 176.1,187.36
  TOP w0.229: U6.A24 131.58,171.13 132.02,171.57 132.02,172.58 133.42,173.98 136.28,173.98 138.27,175.97 140.53,178.23 147.83,185.53 147.99,185.53 148.35,185.17 148.68,185.17 149,185.49 149,185.81 148.68,186.13 148.68,186.47 149.16,186.94 149.53,186.94 149.68,186.79 149.68,186.06 150.13,185.6 150.62,185.6 150.75,185.47 150.75,183.44 151,183.19 151.28,183.19 152.36,182.11 155.65,182.11 157.4,183.86 157.4,185.75 158.6,186.94 167.58,186.94 168.93,188.3 169.34,188.3
MEM_MB_DATA23: length 72.3
  TOP w0.099: J2.147 184.38,186.33 182.36,186.33 181.86,186.84 180.46,186.84 179.75,186.12 177.82,186.12 177.71,186.22 177.71,187.74 177.48,187.97 176.87,187.97 176.72,187.83 176.72,187.37 176.46,187.11 175.11,187.11 174.11,186.12 173.23,186.12 172.24,187.11 171.18,187.11 170.36,187.92 169.31,187.92
  TOP w0.229: U6.A25 132.43,172.01 134.08,173.65 136.71,173.65 137.3,174.24 144.94,181.89 145.7,182.65 147.17,182.65 147.4,182.88 147.4,183.9 147.63,184.12 148.09,184.12 148.31,183.9 148.31,182.88 148.54,182.65 149,182.65 149.23,182.88 149.23,184.81 149.43,185.01 149.94,185.01 150.14,184.81 150.14,182.88 150.37,182.65 151.01,182.65 152.08,181.57 155.87,181.57 157.98,183.68 157.98,185.48 158.92,186.41 167.8,186.41 169.31,187.92
MEM_MB_DATA24: length 54.6
  TOP w0.099: J2.30 178.45,182.64 176.4,182.64 176.17,182.88 174.68,182.88 174.17,182.37 173.28,182.37 172.81,182.84 170.75,182.84 170.29,182.37 169.16,182.37 168.63,182.91
  TOP w0.102: 168.54,182.91 168.63,182.91
  TOP w0.229: 168.54,182.91 166.78,182.91 166.53,182.66 166.25,182.66 166,182.91 164.97,182.91 164.75,182.68 164.36,182.68 164.14,182.91 163.2,182.91 163.01,182.72 162.49,182.72 162.31,182.91 161.09,182.91 157.05,178.87 156.69,178.87 156.56,178.73 156.56,178.37 156.33,178.14 155.99,178.14 155.77,178.36 155.77,178.63 155.56,178.85 155.25,178.85 155.04,178.63 155.04,178.36 154.82,178.14 154.59,178.14 154.37,178.36 154.37,178.62 154.16,178.84 153.85,178.84 153.64,178.62 153.64,178.36 153.42,178.14 153.12,178.14 152.9,178.36 152.9,178.62 152.69,178.84 152.38,178.84 152.17,178.62 152.17,178.36 151.95,178.14 151.64,178.14 151.43,178.36 151.43,178.62 151.21,178.84 150.91,178.84 150.69,178.62 150.69,178.36 150.48,178.14 150.17,178.14 149.96,178.36 149.96,178.62 149.74,178.84 149.43,178.84 149.22,178.62 149.22,178.36 149,178.14 148.72,178.14 148.55,178.31 148.55,178.65 148.35,178.85 147.98,178.85 140.78,171.65 136.76,171.65 U6.A28
MEM_MB_DATA25: length 54.6
  TOP w0.099: 169,182.1 170.57,182.1 171.38,181.29 172.23,181.29 173.04,182.1 174.26,182.1 175.01,181.35 176.34,181.35 177.1,182.11 180.35,182.11 J2.31
  TOP w0.229: U6.A29 141.01,171.13 147.48,177.6 156.54,177.6 161.31,182.37 162.05,182.37 162.28,182.14 162.28,181.46 162.51,181.23 162.96,181.23 163.19,181.46 163.19,182.14 163.42,182.37 163.88,182.37 164.11,182.14 164.11,181.46 164.34,181.23 164.79,181.23 165.02,181.46 165.02,182.14 165.25,182.37 165.71,182.37 165.94,182.14 165.94,181.46 166.17,181.23 166.62,181.23 166.85,181.46 166.85,182.14 167.08,182.37 168.5,182.37 168.77,182.1 169,182.1
MEM_MB_DATA26: length 54.5
  TOP w0.099: J2.36 178.65,177.1 178.65,177.11 178.14,177.11 177.88,176.85 174.82,176.85 174.35,176.37 173.01,176.37 172.54,176.85 171.22,176.85 170.76,176.38 169.17,176.38
  TOP w0.229: 169.17,176.38 168.74,176.81 167.79,176.81 167.56,176.58 167.56,175.69 167.33,175.46 166.88,175.46 166.65,175.69 166.65,176.58 166.42,176.81 165.96,176.81 165.73,176.58 165.73,175.69 165.5,175.46 165.05,175.46 164.82,175.69 164.82,176.58 164.59,176.81 164.13,176.81 163.9,176.58 163.9,175.69 163.68,175.46 163.22,175.46 162.99,175.69 162.99,176.58 162.76,176.81 162.3,176.81 162.07,176.58 162.07,175.26 161.87,175.06 161.36,175.06 161.16,175.26 161.16,176.58 160.93,176.81 160.06,176.81 156.83,173.58 148.24,173.58 140.64,165.98 140.64,165.37 U6.F31
MEM_MB_DATA27: length 56
  TOP w0.099: 141.2,165.6 141.2,165.19 140.36,164.35 139.02,164.35 138.87,164.2 138.1,164.2 U6.F29 ; 169.29,175.95 170.35,175.95 170.93,175.37 172.29,175.37 173.02,176.1 174.4,176.1 175.15,175.36 177.48,175.36 178.22,176.11 J2.37
  TOP w0.229: 141.2,165.6 142.98,167.38 148.65,173.05 158.27,173.05 158.5,173.28 158.5,173.86 158.73,174.09 159.19,174.09 159.42,173.86 159.42,173.28 159.64,173.05 160.1,173.05 160.33,173.28 160.33,173.86 160.56,174.09 161.02,174.09 161.24,173.86 161.24,173.28 161.47,173.05 161.93,173.05 162.16,173.28 162.16,173.86 162.39,174.09 162.84,174.09 163.07,173.86 163.07,173.28 163.3,173.05 163.76,173.05 163.99,173.28 163.99,173.86 164.22,174.09 164.67,174.09 164.9,173.86 164.9,173.28 165.13,173.05 166.39,173.05 169.29,175.95
MEM_MB_DATA28: length 57
  TOP w0.099: 168.74,184.11 170.66,184.11 171.4,184.86 172.29,184.86 173.03,184.11 174.3,184.11 175.05,184.86 176.2,184.86 176.68,184.37 179.86,184.37 180.32,184.84 181.32,184.84 182.26,183.9 184.4,183.9 J2.149
  TOP w0.229: U6.A27 134.97,171.49 135.79,172.31 139.93,172.31 143.92,176.3 147.59,179.97 156.65,179.97 160.65,183.97 168.6,183.97 168.74,184.11
MEM_MB_DATA29: length 55.5
  TOP w0.099: J2.150 182.45,183.36 180.17,183.36 179.58,183.95 176.81,183.95 176.13,183.27 174.76,183.27 174.17,183.86 172.85,183.86 172.26,183.27 170.87,183.27 170.28,183.86 ; 169.47,183.86 169.02,183.4 168.79,183.4
  TOP w0.102: 169.47,183.86 170.28,183.86
  TOP w0.229: U6.B27 135.54,170.42 135.54,171.35 136.16,171.98 140.35,171.98 147.81,179.44 156.87,179.44 160.87,183.44 168.75,183.44 168.79,183.4
MEM_MB_DATA30: length 54.6
  TOP w0.099: 169.7,178.22 170.44,178.22 171.31,177.35 172.24,177.35 173.12,178.23 174.24,178.23 175.09,177.37 176.49,177.37 177.24,178.12 179.5,178.12 180.24,177.37 181.49,177.37 182.22,178.11 J2.155
  TOP w0.229: U6.E30 139.46,166.73 140.28,166.73 140.82,167.26 140.82,167.72 141.23,168.14 141.23,168.56 141.6,168.92 141.88,168.92 142.25,169.29 142.25,169.57 142.49,169.81 142.77,169.81 143.27,170.31 143.27,170.59 143.7,171.02 143.95,171.02 147.58,174.65 156.39,174.65 160.99,179.25 168.67,179.25 169.7,178.22
MEM_MB_DATA31: length 56.6
  TOP w0.099: 169.34,177.89 170.31,177.89 171.1,177.1 172.42,177.1 173.24,177.92 174.14,177.92 174.94,177.12 177.02,177.12 177.74,177.84 179.21,177.84 179.94,177.11 182.71,177.11 J2.156
  TOP w0.229: U6.E31 140.18,166.05 141.37,167.23 141.37,167.6 142.45,168.69 147.88,174.12 156.61,174.12 161.21,178.72 162.13,178.72 162.36,178.49 162.36,177.57 162.59,177.34 163.05,177.34 163.27,177.57 163.27,178.49 163.5,178.72 163.96,178.72 164.19,178.49 164.19,177.57 164.42,177.34 164.87,177.34 165.1,177.57 165.1,178.49 165.33,178.72 165.79,178.72 166.02,178.49 166.02,177.57 166.25,177.34 166.7,177.34 166.93,177.57 166.93,178.49 167.07,178.62 168.6,178.62 169.34,177.89
MEM_MB_DATA32: length 54
  TOP w0.099: 169.01,128.56 169.24,128.33 170.5,128.33 170.84,127.99 171.49,127.34 172.09,127.34 173.11,128.36 174.43,128.36 174.91,128.84 176.1,128.84 176.54,128.4 176.54,127.76 177.05,127.25 177.56,127.25 178.45,128.14 179.54,128.14 180.43,127.25 181.32,127.25 181.57,127.51 181.57,127.82 181.28,128.11 J2.81
  TOP w0.229: 169.01,128.56 167.24,130.33 167.24,132.6 166.42,133.43 166.07,133.43 165.81,133.17 164.23,133.17 164,133.4 163.74,133.4 163.5,133.17 162.15,133.17 161.73,133.58 161.17,133.58 160.75,133.17 154.64,133.17 153.65,134.16 151.97,134.16 151.74,133.93 151.74,133.53 151.51,133.3 151.06,133.3 150.83,133.53 150.83,133.93 150.6,134.16 150.14,134.16 149.91,133.93 149.91,133.53 149.68,133.3 149.23,133.3 149,133.53 149,133.93 148.77,134.16 142.71,134.16 140.6,136.27 140.24,136.27 139.99,136.02 139.99,135.63 U6.AJ31
MEM_MB_DATA33: length 53.8
  TOP w0.099: J2.82 179.61,127.1 179.82,126.9 179.82,126.57 179.41,126.16 177.44,126.16 177.32,126.29 177.32,126.76 177.18,126.9 176.64,126.9 176.35,127.19 175.27,127.19 174.35,128.1 173.23,128.1 172.22,127.09 171.38,127.09 170.39,128.08 168.6,128.08
  TOP w0.229: 168.6,128.08 166.71,129.97 166.71,132.28 166.36,132.63 161.87,132.63 161.63,132.87 161.22,132.87 160.99,132.63 153.65,132.63 153.42,132.86 153.42,133.38 153.19,133.6 152.73,133.6 152.5,133.38 152.5,132.86 152.28,132.63 150.86,132.63 150.55,132.94 150.18,132.94 149.86,132.63 148.68,132.63 147.97,133.35 146.67,133.35 146.39,133.63 145.76,133.63 145.48,133.35 144.84,133.35 144.56,133.63 143.93,133.63 143.17,132.87 142.63,132.87 141.97,133.53 141.97,134.34 141.57,134.75 141.26,134.75 141.11,134.59 141.11,134.06 140.92,133.87 140.41,133.87 140.24,134.04 140.24,134.7 140.05,134.89 139.01,134.89 138.78,135.11 U6.AJ30
MEM_MB_DATA34: length 53.7
  TOP w0.099: J2.87 180.81,121.87 180.43,121.49 179.94,121.49 179.6,121.83 176.49,121.83 176.03,121.37 175.09,121.37 174.23,122.23 173.18,122.23 172.24,121.29 171.34,121.29 170.34,122.29 169.54,122.29 168.82,123.01
  TOP w0.102: 135.61,131.47 134.04,133.03 U6.AL26
  TOP w0.229: 168.82,123.01 168.82,123.41 163.66,128.57 157.66,128.57 156.64,129.59 141.34,129.59 140.19,130.73 136.34,130.73 135.61,131.47
MEM_MB_DATA35: length 53.6
  TOP w0.099: J2.88 178.52,121.11 177.43,120.02 176.92,120.02 175.83,121.11 174.95,121.11 174.12,121.93 173.26,121.93 172.29,120.97 171.2,120.97 170.19,121.98 169.11,121.98
  TOP w0.102: 169.11,121.98 168.59,122.5 ; U6.AL25 133.13,132.33 133.62,132.33 134.16,132.33 136.26,130.23
  TOP w0.229: 136.26,130.23 139.99,130.23 141.16,129.06 156.4,129.06 157.42,128.04 163.03,128.04 163.24,127.84 163.64,127.84 163.96,127.52 163.96,127.21 163.96,127.12 164.28,126.8 164.68,126.8 165,126.48 165,126.17 165,126.07 168.59,122.5
MEM_MB_DATA36: length 53.5
  TOP w0.099: 168.54,130.81 169.12,130.23 170.39,130.23 171.4,129.22 172.03,129.22 173.11,130.3 174.38,130.3 175.31,129.37 176.54,129.37 176.67,129.5 176.67,130.05 176.92,130.3 179.6,130.3 180.73,129.16 181.11,129.16 181.75,129.79 182.45,129.79 182.71,129.54 J2.200
  TOP w0.229: 168.54,130.81 168.41,130.93 168.41,132.94 166.43,134.92 166.05,134.92 165.36,134.23 164.67,134.23 164.24,134.67 163.5,134.67 163.19,134.37 162.75,134.37 161.91,135.2 161.2,135.2 160.23,134.23 155.15,134.23 154.15,135.23 143.09,135.23 140.99,137.33 139.08,137.33 138.78,137.62 U6.AG30
MEM_MB_DATA37: length 53.7
  TOP w0.099: 169.36,129.9 170.23,129.9 171.16,128.97 172.38,128.97 173.36,129.94 174.11,129.94 174.96,129.09 177.73,129.09 178.03,129.4 178.03,129.9 178.16,130.03 179.16,130.03 180.29,128.91 181.24,128.91 181.81,128.33 183.02,128.33 183.14,128.2 183.14,127.76 183.65,127.25 184.41,127.25 184.61,127.45 J2.201
  TOP w0.229: U6.AH31 140.67,136.84 142.81,134.7 153.91,134.7 154.91,133.7 160.53,133.7 161,134.16 161.9,134.16 162.37,133.7 163.28,133.7 163.62,134.04 164.12,134.04 164.45,133.7 165.59,133.7 166.03,134.14 166.46,134.14 167.78,132.82 167.78,130.68 168.56,129.9 169.36,129.9
MEM_MB_DATA38: length 54.2
  TOP w0.099: 168.94,124.8 169.5,124.24 170.39,124.24 171.38,123.25 172.17,123.25 173.08,124.17 ; 174.56,123.88 175.18,123.26 176.02,123.26 176.9,122.37 179.31,122.37 180.04,123.11 182.71,123.11 J2.206
  TOP w0.102: 174.56,123.88 174.27,124.17 173.08,124.17 ; U6.AK27 135.51,133.76 135.51,132.93 136.24,132.2
  TOP w0.229: 136.24,132.2 136.24,132.19 136.57,131.86 140.82,131.86 142.02,130.66 157.09,130.66 158.1,129.64 164.1,129.64 168.54,125.2 168.94,124.8
MEM_MB_DATA39: length 55.7
  TOP w0.099: 173.25,123.91 172.34,123 171.2,123 170.26,123.94 169.05,123.94 ; J2.207 184.52,122.11 184.52,122.11 182.54,122.11 181.81,122.84 180.21,122.84 179.83,122.45 179.46,122.08 176.79,122.08 176.42,122.45 175.9,122.97 175.04,122.97 174.1,123.91
  TOP w0.102: 136.21,131.59 136.16,131.59 134.97,132.78 U6.AL27 ; 174.1,123.91 173.25,123.91
  TOP w0.229: 169.05,123.94 163.88,129.11 157.88,129.11 156.86,130.12 141.64,130.12 140.45,131.32 136.49,131.32 136.21,131.59
MEM_MB_DATA40: length 69.3
  TOP w0.099: 168.95,118.67 169.24,118.37 170.47,118.37 171.47,117.37 172.13,117.37 173.13,118.38 174.25,118.38 175.25,117.37 176.41,117.37 178.14,119.11 178.91,119.11 J2.90
  TOP w0.102: 168.95,118.67 168.95,119.51 ; U6.AJ24 130.73,135.14 130.73,132.57 131.22,132.08
  TOP w0.229: 168.95,119.51 167.78,120.68 167.78,120.9 162.24,126.44 161.24,126.44 161.01,126.21 161.01,126.03 160.78,125.81 160.32,125.81 160.09,126.03 160.09,126.21 159.86,126.44 159.41,126.44 159.18,126.21 159.18,126.03 158.95,125.81 158.49,125.81 158.26,126.03 158.26,126.21 158.04,126.44 157.58,126.44 157.35,126.21 157.35,126.03 157.12,125.81 156.66,125.81 156.44,126.03 156.44,126.21 156.21,126.44 155.75,126.44 155.52,126.21 155.52,126.03 155.29,125.81 154.84,125.81 154.61,126.03 154.61,126.21 154.38,126.44 153.92,126.44 153.69,126.21 153.69,126.03 153.46,125.81 153.01,125.81 152.78,126.03 152.78,126.21 152.55,126.44 152.09,126.44 151.86,126.21 151.86,126.03 151.64,125.81 151.18,125.81 150.95,126.03 150.95,126.21 150.72,126.44 150.26,126.44 150.04,126.21 150.04,126.03 149.81,125.81 149.35,125.81 149.12,126.03 149.12,126.21 148.89,126.44 148.43,126.44 148.21,126.21 148.21,126.03 147.98,125.81 147.52,125.81 147.29,126.03 147.29,126.21 147.06,126.44 146.61,126.44 146.38,126.21 146.38,126.03 146.15,125.81 145.69,125.81 145.46,126.03 145.46,126.21 145.23,126.44 144.78,126.44 144.55,126.21 144.55,126.03 144.32,125.81 143.86,125.81 143.63,126.03 143.63,126.21 143.41,126.44 142.95,126.44 142.72,126.21 142.72,126.03 142.49,125.81 142.03,125.81 141.81,126.03 141.81,126.21 141.58,126.44 141.12,126.44 140.89,126.21 140.89,126.03 140.66,125.81 140.21,125.81 139.98,126.03 139.98,126.21 139.75,126.44 139.29,126.44 139.06,126.21 139.06,126.03 138.83,125.81 138.38,125.81 138.15,126.03 138.15,126.21 137.92,126.44 137.35,126.44 133.11,130.68 132.62,130.68 131.22,132.08
MEM_MB_DATA41: length 68.2
  TOP w0.099: 168.67,118.45 168.67,118.44 168.99,118.12 170.34,118.12 171.35,117.11 172.24,117.11 173.26,118.12 174.14,118.12 175.15,117.11 176.68,117.11 177.68,118.11 179.08,118.11 179.72,118.75 180.17,118.75 J2.91
  TOP w0.102: U6.AH23 129.96,136.91 130.38,136.91 130.53,136.76 130.53,131.99 130.87,131.65
  TOP w0.229: 130.87,131.65 132.45,130.07 132.89,130.07 132.97,130.07 133.3,129.74 133.3,129.43 133.3,129.35 133.62,129.02 133.93,129.02 134.01,129.02 134.34,128.7 134.34,128.39 134.34,128.31 134.66,127.98 134.97,127.98 135.05,127.98 135.38,127.66 135.38,127.35 135.38,127.27 135.71,126.94 136.01,126.94 136.09,126.94 136.42,126.61 136.42,126.31 136.42,126.23 137.37,125.27 138.19,125.27 138.45,125.02 139.11,125.02 139.36,125.27 140.02,125.27 140.28,125.02 140.94,125.02 141.19,125.27 141.85,125.27 142.1,125.02 142.76,125.02 143.02,125.27 143.68,125.27 143.93,125.02 144.59,125.02 144.85,125.27 145.51,125.27 145.76,125.02 146.42,125.02 146.68,125.27 147.34,125.27 147.59,125.02 148.25,125.02 148.51,125.27 149.17,125.27 149.42,125.02 150.08,125.02 150.33,125.27 150.99,125.27 151.25,125.02 151.91,125.02 152.16,125.27 152.82,125.27 153.08,125.02 153.74,125.02 153.99,125.27 154.65,125.27 154.91,125.02 155.57,125.02 155.82,125.27 156.48,125.27 156.73,125.02 157.4,125.02 157.65,125.27 158.31,125.27 158.56,125.02 159.22,125.02 159.48,125.27 161.22,125.27 161.55,125.6 162.32,125.6 164.86,123.06 164.86,122.81 165.3,122.36 165.56,122.36 166,121.92 166,121.67 166.38,121.28 166.63,121.28 167.14,120.78 167.14,120.47 168.4,119.21 168.4,118.72 168.67,118.45
MEM_MB_DATA42: length 68.6
  TOP w0.099: 169.3,112.29 170.34,112.29 170.88,112.84 172.62,112.84 173.1,112.36 174.39,112.36 174.88,112.84 176.49,112.84 177.23,113.58 177.72,113.58 178.19,113.11 178.91,113.11 J2.96
  TOP w0.102: 128.42,129.55 128.22,129.55 127.99,129.79 127.99,136.2 U6.AH21
  TOP w0.229: 128.42,129.55 129.14,128.83 129.14,128.12 135.95,121.31 148.79,121.31 149.46,121.98 161.34,121.98 165.21,118.1 165.21,116.38 169.3,112.29
MEM_MB_DATA43: length 70
  TOP w0.099: J2.97 180.71,112.11 180.71,112.11 179.71,112.11 179.44,112.38 177.12,112.38 176.11,111.37 175.14,111.37 174.42,112.1 173.11,112.1 172.38,111.37 171.1,111.37 170.56,111.92 168.93,111.92
  TOP w0.102: U6.AJ21 127.79,135.14 127.79,129.38 128.43,128.74
  TOP w0.229: 168.93,111.92 168.92,111.92 164.43,116.42 164.43,118.13 161.14,121.41 149.65,121.41 149.01,120.78 135.55,120.78 128.43,127.89 128.43,128.74
MEM_MB_DATA44: length 68
  TOP w0.099: 168.92,121.28 168.92,120.95 169.63,120.25 170.18,120.25 171.14,119.29 172.17,119.29 173.11,120.23 174.24,120.23 175.19,119.27 176.12,119.27 176.52,118.87 177.05,118.87 178.33,120.15 179.72,120.15 180.5,119.37 181.49,119.37 182.39,120.27 183.14,120.27 183.78,120.9 184.41,120.9 184.61,120.71 J2.209
  TOP w0.102: U6.AK25 132,134.3 131.78,134.08 131.78,132.95 132.73,132.01 133.63,132.01 136.05,129.59
  TOP w0.229: 168.92,121.28 162.7,127.51 157.19,127.51 156.18,128.52 154.03,128.52 153.68,128.17 153.12,128.17 152.76,128.52 152.2,128.52 151.85,128.17 151.29,128.17 150.93,128.52 150.37,128.52 150.02,128.17 149.46,128.17 149.1,128.52 148.54,128.52 148.19,128.17 147.63,128.17 147.27,128.52 146.71,128.52 146.36,128.17 145.8,128.17 145.45,128.52 144.89,128.52 144.53,128.17 143.97,128.17 143.62,128.52 143.06,128.52 142.7,128.17 142.14,128.17 141.79,128.52 141.23,128.52 140.87,128.17 140.31,128.17 139.96,128.52 139.22,128.52 138.99,128.75 138.99,129.57 138.77,129.79 138.31,129.79 138.08,129.57 138.08,128.75 137.85,128.52 137.11,128.52 136.05,129.59
MEM_MB_DATA45: length 68.3
  TOP w0.099: 168.84,120.37 169.25,119.96 170.09,119.96 171.01,119.04 172.32,119.04 173.23,119.95 174.08,119.95 175.03,119 176.03,119 176.54,118.49 177.05,118.49 178.39,119.84 179.63,119.84 180.54,118.92 181.32,118.92 182,118.24 182.51,118.24 182.71,118.43 J2.210
  TOP w0.229: U6.AL24 132.86,131.33 133.3,131.33 137.65,126.97 138.39,126.97 138.62,127.2 138.62,127.41 138.85,127.64 139.31,127.64 139.53,127.41 139.53,127.2 139.76,126.97 140.22,126.97 140.45,127.2 140.45,127.41 140.68,127.64 141.13,127.64 141.36,127.41 141.36,127.2 141.59,126.97 142.05,126.97 142.28,127.2 142.28,127.41 142.51,127.64 142.96,127.64 143.19,127.41 143.19,127.2 143.42,126.97 143.88,126.97 144.11,127.2 144.11,127.41 144.33,127.64 144.79,127.64 145.02,127.41 145.02,127.2 145.25,126.97 145.71,126.97 145.94,127.2 145.94,127.41 146.16,127.64 146.62,127.64 146.85,127.41 146.85,127.2 147.08,126.97 147.54,126.97 147.76,127.2 147.76,127.41 147.99,127.64 148.45,127.64 148.68,127.41 148.68,127.2 148.91,126.97 149.36,126.97 149.59,127.2 149.59,127.41 149.82,127.64 150.28,127.64 150.51,127.41 150.51,127.2 150.74,126.97 151.19,126.97 151.42,127.2 151.42,127.41 151.65,127.64 152.11,127.64 152.34,127.41 152.34,127.2 152.56,126.97 153.02,126.97 153.25,127.2 153.25,127.41 153.48,127.64 153.94,127.64 154.16,127.41 154.16,127.2 154.39,126.97 154.85,126.97 155.08,127.2 155.08,127.41 155.31,127.64 155.76,127.64 155.99,127.41 155.99,127.2 156.22,126.97 162.47,126.97 168.41,121.03 168.41,120.8 168.84,120.37
MEM_MB_DATA46: length 68.9
  TOP w0.099: J2.215 182.31,114.11 181.58,113.37 180.4,113.37 179.5,114.27 177.06,114.27 176.16,113.37 175.2,113.37 174.3,114.27 173.19,114.27 172.29,113.37 171.17,113.37 170.25,114.3 168.92,114.3
  TOP w0.229: U6.AL22 128.62,130.95 130.41,129.16 130.41,128.6 136.64,122.38 148.35,122.38 149.02,123.04 161.78,123.04 166.34,118.48 166.34,116.88 168.92,114.3
MEM_MB_DATA47: length 70.4
  TOP w0.099: 169.26,113.9 170.27,113.9 171.08,113.09 172.38,113.09 173.27,113.98 174.15,113.98 175.04,113.09 176.3,113.09 177.19,113.98 179.42,113.98 180.29,113.11 182.71,113.11 J2.216
  TOP w0.102: 128.78,129.71 128.19,130.3 128.19,135.14 U6.AJ22
  TOP w0.229: 128.78,129.71 128.98,129.71 129.8,128.88 129.8,128.37 136.33,121.84 148.57,121.84 149.24,122.51 161.56,122.51 165.8,118.26 165.8,116.66 168.55,113.9 169.26,113.9
MEM_MB_DATA48: length 82.3
  TOP w0.099: 176.31,109.37 177.84,109.37 178.58,110.11 180.81,110.11 J2.99 ; 174.8,109.37 174.21,109.97 173.14,109.97 172.54,109.37 170.78,109.37 170.31,109.84 169.31,109.84
  TOP w0.102: 174.8,109.37 176.31,109.37 ; 169.09,109.62 169.31,109.84
  TOP w0.229: 169.09,109.62 168.77,109.62 160.48,117.91 159.68,117.91 159.45,117.68 159.45,117.35 159.22,117.12 158.76,117.12 158.53,117.35 158.53,117.68 158.3,117.91 157.85,117.91 157.62,117.68 157.62,117.35 157.39,117.12 156.93,117.12 156.7,117.35 156.7,117.68 156.47,117.91 156.02,117.91 155.79,117.68 155.79,117.35 155.56,117.12 155.1,117.12 154.87,117.35 154.87,117.68 154.65,117.91 154.19,117.91 153.96,117.68 153.96,117.35 153.73,117.12 153.27,117.12 153.05,117.35 153.05,117.68 152.82,117.91 152.36,117.91 152.13,117.68 152.13,117.35 151.9,117.12 151.45,117.12 151.22,117.35 151.22,117.68 150.99,117.91 150.53,117.91 150.3,117.68 150.3,117.35 150.07,117.12 149.62,117.12 149.39,117.35 149.39,117.68 149.16,117.91 148.7,117.91 148.47,117.68 148.47,117.35 148.25,117.12 147.79,117.12 147.56,117.35 147.56,117.68 147.33,117.91 146.87,117.91 146.65,117.68 146.65,117.35 146.42,117.12 145.96,117.12 145.73,117.35 145.73,117.68 145.5,117.91 145.04,117.91 144.82,117.68 144.82,117.35 144.59,117.12 144.13,117.12 143.9,117.35 143.9,117.68 143.67,117.91 143.22,117.91 142.99,117.68 142.99,117.35 142.76,117.12 142.3,117.12 142.07,117.35 142.07,117.68 141.84,117.91 141.39,117.91 141.16,117.68 141.16,117.35 140.93,117.12 140.47,117.12 140.24,117.35 140.24,117.68 140.02,117.91 139.56,117.91 139.33,117.68 139.33,117.35 139.1,117.12 138.64,117.12 138.42,117.35 138.42,117.68 138.19,117.91 137.73,117.91 137.5,117.68 137.5,117.35 137.27,117.12 136.82,117.12 136.59,117.35 136.59,117.68 136.36,117.91 135.62,117.91 126.32,127.21 126.32,132.79 U6.AL20
MEM_MB_DATA49: length 82.3
  TOP w0.099: 175.01,109.11 174.14,108.23 173.4,108.23 172.51,109.12 171.11,109.12 170.27,108.28 169.36,108.28 ; J2.100 178.91,109.11 178.25,109.11 178.03,108.89 176.43,108.89 176.21,109.11 ; 124.99,137.51 125.26,137.51 125.42,137.34 125.42,136.97
  TOP w0.102: 125.72,131.83 125.72,132.43 125.65,132.5 125.65,135.36 125.42,135.59 125.42,136.97 ; 175.01,109.11 176.21,109.11 ; U6.AH19 124.81,137.33 124.99,137.51
  TOP w0.229: 169.36,108.28 161.05,116.59 154.6,116.59 154.37,116.36 154.37,116.13 154.14,115.9 153.68,115.9 153.45,116.13 153.45,116.36 153.22,116.59 152.77,116.59 152.54,116.36 152.54,116.13 152.31,115.9 151.85,115.9 151.62,116.13 151.62,116.36 151.39,116.59 150.94,116.59 150.71,116.36 150.71,116.13 150.48,115.9 150.02,115.9 149.79,116.13 149.79,116.36 149.57,116.59 149.11,116.59 148.88,116.36 148.88,116.13 148.65,115.9 148.19,115.9 147.97,116.13 147.97,116.36 147.74,116.59 147.28,116.59 147.05,116.36 147.05,116.13 146.82,115.9 146.37,115.9 146.14,116.13 146.14,116.36 145.91,116.59 145.45,116.59 145.22,116.36 145.22,116.13 144.99,115.9 144.54,115.9 144.31,116.13 144.31,116.36 144.08,116.59 143.62,116.59 143.39,116.36 143.39,116.13 143.17,115.9 142.71,115.9 142.48,116.13 142.48,116.36 142.25,116.59 141.79,116.59 141.57,116.36 141.57,116.13 141.34,115.9 140.88,115.9 140.65,116.13 140.65,116.36 140.42,116.59 139.96,116.59 139.74,116.36 139.74,116.13 139.51,115.9 139.05,115.9 138.82,116.13 138.82,116.36 138.59,116.59 138.14,116.59 137.91,116.36 137.91,116.13 137.68,115.9 137.22,115.9 136.99,116.13 136.99,116.36 136.76,116.59 136.03,116.59 125.72,126.9 125.72,131.83
MEM_MB_DATA50: length 81.2
  TOP w0.099: 168.62,103.85 170.53,103.85 171,103.37 172.6,103.37 173.07,103.85 174.38,103.85 174.85,103.37 176.17,103.37 176.61,103.82 179.86,103.82 180.33,104.29 180.62,104.29 J2.105
  TOP w0.102: U6.AJ16 120.57,135.14 120.57,132.7 121.26,132.01 121.26,131.5
  TOP w0.229: 168.62,103.85 168.27,103.85 159.26,112.86 132.3,112.86 121.02,124.14 121.02,130.07 121.26,130.31 121.26,131.5
MEM_MB_DATA51: length 81.8
  TOP w0.099: 172.44,103.11 173.18,102.37 174.14,102.37 174.88,103.12 178.9,103.12 J2.106 ; 171.12,103.11 170.38,102.37 169.28,102.37
  TOP w0.102: 120.71,131.47 120.71,131.8 120.37,132.14 120.37,136.2 U6.AH15 ; 171.12,103.11 172.44,103.11
  TOP w0.229: 169.28,102.37 168.59,103.06 168.31,103.06 159.04,112.32 132.08,112.32 120.36,124.05 120.36,130 120.71,130.35 120.71,131.47
MEM_MB_DATA52: length 82.4
  TOP w0.099: J2.218 182.5,111.32 179.92,111.32 179.73,111.51 179.37,111.87 178.43,111.87 177.84,111.28 176.73,111.28 176.54,111.09 175.04,111.09 174.28,111.85 173.23,111.85 172.88,111.51 172.48,111.1 171.09,111.1 170.36,110.37 169.22,110.37
  TOP w0.102: 169.02,111.07 169.02,110.58 169.22,110.37
  TOP w0.229: U6.AL21 127.47,132.91 127.47,127.94 135.17,120.24 141.48,120.24 141.84,119.89 142.22,119.89 142.57,120.24 142.96,120.24 143.31,119.89 143.69,119.89 144.05,120.24 144.43,120.24 144.78,119.89 145.16,119.89 145.52,120.24 145.9,120.24 146.26,119.89 146.64,119.89 146.99,120.24 147.37,120.24 147.73,119.89 148.11,119.89 148.47,120.24 149.24,120.24 149.52,119.96 149.79,119.96 150,120.16 150,120.55 150.22,120.77 150.68,120.77 150.91,120.55 150.91,119.89 151.11,119.68 151.62,119.68 151.82,119.89 151.82,120.55 152.05,120.77 152.51,120.77 152.74,120.55 152.74,119.94 152.94,119.74 153.45,119.74 153.65,119.94 153.65,120.55 153.88,120.77 154.34,120.77 154.57,120.55 154.57,119.89 154.77,119.68 155.28,119.68 155.48,119.89 155.48,120.55 155.71,120.77 156.17,120.77 156.4,120.55 156.4,119.89 156.6,119.68 157.11,119.68 157.31,119.89 157.31,120.55 157.54,120.77 158,120.77 158.22,120.55 158.22,120.17 158.4,120 158.92,120 159.17,120.24 159.84,120.24 160.37,119.72 160.69,119.72 161.17,120.2 161.49,120.2 161.82,119.88 161.82,119.56 161.34,119.07 161.34,118.75 161.66,118.43 161.98,118.43 162.46,118.91 162.79,118.91 163.11,118.59 163.11,118.26 162.63,117.78 162.63,117.46 169.02,111.07
MEM_MB_DATA53: length 82.5
  TOP w0.099: J2.219 184.51,110.21 182.06,110.21 181.43,110.84 180.07,110.84 179.61,110.37 178.45,110.37 177.99,110.84 174.78,110.84 174.19,110.25 173.14,110.25 172.55,110.84 171.33,110.84 170.59,110.1 169.05,110.1
  TOP w0.229: 169.05,110.1 159.99,119.15 155.84,119.15 155.61,118.92 155.61,118.67 155.39,118.44 154.93,118.44 154.7,118.67 154.7,118.92 154.47,119.15 154.01,119.15 153.79,118.92 153.79,118.67 153.56,118.44 153.1,118.44 152.87,118.67 152.87,118.92 152.64,119.15 152.19,119.15 151.96,118.92 151.96,118.67 151.73,118.44 151.27,118.44 151.04,118.67 151.04,118.92 150.81,119.15 150.36,119.15 150.13,118.92 150.13,118.67 149.9,118.44 149.44,118.44 149.21,118.67 149.21,118.92 148.99,119.15 148.53,119.15 148.3,118.92 148.3,118.67 148.07,118.44 147.61,118.44 147.39,118.67 147.39,118.92 147.16,119.15 146.7,119.15 146.47,118.92 146.47,118.67 146.24,118.44 145.78,118.44 145.56,118.67 145.56,118.92 145.33,119.15 144.87,119.15 144.64,118.92 144.64,118.67 144.41,118.44 143.96,118.44 143.73,118.67 143.73,118.92 143.5,119.15 143.04,119.15 142.81,118.92 142.81,118.67 142.58,118.44 142.13,118.44 141.9,118.67 141.9,118.92 141.67,119.15 141.21,119.15 140.98,118.92 140.98,118.67 140.76,118.44 140.3,118.44 140.07,118.67 140.07,118.92 139.84,119.15 139.38,119.15 139.16,118.92 139.16,118.67 138.93,118.44 138.47,118.44 138.24,118.67 138.24,118.92 138.01,119.15 137.56,119.15 137.36,118.95 136.38,118.95 136.18,119.15 135.32,119.15 126.93,127.53 126.93,130.95 126.77,131.11 126.77,133.71 U6.AK21
MEM_MB_DATA54: length 81.3
  TOP w0.099: J2.224 179.94,105.11 179.21,104.37 176.74,104.37 175.88,105.24 174.88,105.24 174.01,104.38 173.96,104.37 173.25,104.37 172.39,105.24 171.08,105.24 170.21,104.37 169.4,104.37 169.14,104.64
  TOP w0.229: 169.14,104.64 168.41,105.37 168.26,105.37 166.33,107.3 166.33,107.63 166.59,107.89 166.59,108.21 166.27,108.53 165.94,108.53 165.68,108.27 165.36,108.27 165.03,108.6 165.03,108.92 165.3,109.18 165.3,109.5 164.97,109.83 164.65,109.83 164.39,109.57 164.06,109.57 159.71,113.92 132.75,113.92 131.11,115.57 124.28,122.45 122.39,124.36 122.39,129.87 122.27,129.98 U6.AL17
MEM_MB_DATA55: length 82.3
  TOP w0.099: 168.37,104.59 168.61,104.35 168.81,104.35 169.07,104.1 170.39,104.1 171.27,104.98 172.21,104.98 173.09,104.1 174.2,104.1 175,104.9 175.85,104.9 176.65,104.1 179.44,104.1 180.18,104.84 181.78,104.84 182.28,104.33 183.47,104.33 183.7,104.11 J2.225
  TOP w0.229: U6.AL16 121.77,132.27 121.77,124.15 132.52,113.39 159.48,113.39 168.28,104.59 168.37,104.59
MEM_MB_DATA56: length 97.3
  TOP w0.099: 169.21,99.9 170.57,99.9 171.51,100.84 172.19,100.84 172.66,100.37 174.67,100.37 175.17,100.87 178.68,100.87 J2.108 ; 119.03,132.52 119.03,130.55
  TOP w0.102: U6.AK15 119.23,133.79 119.23,132.72 119.03,132.52
  TOP w0.229: 169.21,99.9 159.83,109.27 157.79,109.27 157.56,109.04 157.56,108.66 157.33,108.43 156.88,108.43 156.65,108.66 156.65,109.04 156.42,109.27 155.96,109.27 155.73,109.04 155.73,108.66 155.5,108.43 155.05,108.43 154.82,108.66 154.82,109.04 154.59,109.27 154.13,109.27 153.9,109.04 153.9,108.66 153.68,108.43 153.22,108.43 152.99,108.66 152.99,109.04 152.76,109.27 152.3,109.27 152.08,109.04 152.08,108.66 151.85,108.43 151.39,108.43 151.16,108.66 151.16,109.04 150.93,109.27 150.48,109.27 150.25,109.04 150.25,108.66 150.02,108.43 149.56,108.43 149.33,108.66 149.33,109.04 149.1,109.27 148.65,109.27 148.42,109.04 148.42,108.66 148.19,108.43 147.73,108.43 147.5,108.66 147.5,109.04 147.28,109.27 146.82,109.27 146.59,109.04 146.59,108.66 146.36,108.43 145.9,108.43 145.68,108.66 145.68,109.04 145.45,109.27 144.99,109.27 144.76,109.04 144.76,108.66 144.53,108.43 144.07,108.43 143.85,108.66 143.85,109.04 143.62,109.27 143.16,109.27 142.93,109.04 142.93,108.66 142.7,108.43 142.25,108.43 142.02,108.66 142.02,109.04 141.79,109.27 141.33,109.27 141.1,109.04 141.1,108.66 140.87,108.43 140.42,108.43 140.19,108.66 140.19,109.04 139.96,109.27 139.5,109.27 139.27,109.04 139.27,108.66 139.05,108.43 138.59,108.43 138.36,108.66 138.36,109.04 138.13,109.27 137.67,109.27 137.45,109.04 137.45,108.66 137.22,108.43 136.76,108.43 136.53,108.66 136.53,109.04 136.3,109.27 135.85,109.27 135.62,109.04 135.62,108.66 135.39,108.43 134.93,108.43 134.7,108.66 134.7,109.04 134.47,109.27 132.87,109.27 118.27,123.87 118.27,129.79 119.03,130.55
MEM_MB_DATA57: length 97.1
  TOP w0.099: 118.2,130.38 118.46,130.64 U6.AL14 ; J2.109 180.51,100.11 180.5,100.11 177.52,100.11 176.65,99.23 175.19,99.23 174.32,100.11 172.84,100.11 171.99,99.25 171.26,99.25 170.3,98.29 169.51,98.29 169.26,98.53
  TOP w0.229: 169.26,98.53 169.09,98.7 169.09,99.25 160.45,107.9 154.4,107.9 154.18,107.67 154.18,107.31 153.95,107.09 153.49,107.09 153.26,107.31 153.26,107.67 153.03,107.9 152.58,107.9 152.35,107.67 152.35,107.31 152.12,107.09 151.66,107.09 151.43,107.31 151.43,107.67 151.2,107.9 150.75,107.9 150.52,107.67 150.52,107.31 150.29,107.09 149.83,107.09 149.6,107.31 149.6,107.67 149.37,107.9 148.92,107.9 148.69,107.67 148.69,107.31 148.46,107.09 148,107.09 147.77,107.31 147.77,107.67 147.55,107.9 147.09,107.9 146.86,107.67 146.86,107.31 146.63,107.09 146.17,107.09 145.95,107.31 145.95,107.67 145.72,107.9 145.26,107.9 145.03,107.67 145.03,107.31 144.8,107.09 144.35,107.09 144.12,107.31 144.12,107.67 143.89,107.9 143.43,107.9 143.2,107.67 143.2,107.31 142.97,107.09 142.52,107.09 142.29,107.31 142.29,107.67 142.06,107.9 141.6,107.9 141.37,107.67 141.37,107.31 141.15,107.09 140.69,107.09 140.46,107.31 140.46,107.67 140.23,107.9 139.77,107.9 139.55,107.67 139.55,107.31 139.32,107.09 138.86,107.09 138.63,107.31 138.63,107.67 138.4,107.9 137.94,107.9 137.72,107.67 137.72,107.31 137.49,107.09 137.03,107.09 136.8,107.31 136.8,107.67 136.57,107.9 136.12,107.9 135.89,107.67 135.89,107.31 135.66,107.09 135.2,107.09 134.97,107.31 134.97,107.67 134.74,107.9 133.49,107.9 117.64,123.75 117.64,129.82 118.2,130.38
MEM_MB_DATA58: length 98.4
  TOP w0.099: J2.114 178.91,95.11 178.71,95.3 178.25,95.3 177.78,94.83 174.88,94.83 174.33,94.28 173.04,94.28 171.95,93.18 171.15,93.18 170.49,93.84 169.46,93.84 169,93.38
  TOP w0.102: U6.AG13 116.56,137.47 116.56,132.32 115.56,131.32
  TOP w0.229: 115.56,131.32 114.83,130.59 114.73,130.59 114.42,130.28 114.42,122.66 114.42,122.66 135.43,101.65 143.01,101.65 143.23,101.87 143.23,102.15 143.44,102.36 143.75,102.36 143.96,102.15 143.96,101.87 144.18,101.65 144.48,101.65 144.7,101.87 144.7,102.15 144.91,102.36 145.22,102.36 145.44,102.15 145.44,101.87 145.65,101.65 145.96,101.65 146.17,101.87 146.17,102.15 146.39,102.36 146.69,102.36 146.91,102.15 146.91,101.87 147.12,101.65 147.43,101.65 147.65,101.87 147.65,102.15 147.86,102.36 148.17,102.36 148.38,102.15 148.38,101.87 148.6,101.65 160.6,101.65 160.92,101.34 168.87,93.38 169,93.38
MEM_MB_DATA59: length 98.8
  TOP w0.099: J2.115 178.38,94.11 177.04,93.36 174.63,93.36 174.13,93.86 173.11,93.86 172.12,92.88 171.3,92.88 170.28,92.31 169.59,92.31
  TOP w0.102: U6.AF13 116.36,138.54 116.36,132.58 114.93,131.15 114.68,131.15
  TOP w0.229: 169.59,92.31 169.17,92.74 168.76,92.74 160.38,101.12 135.21,101.12 113.85,122.48 113.85,130.32 114.68,131.15
MEM_MB_DATA60: length 98.2
  TOP w0.099: J2.227 181.98,102.11 181.02,103.06 180.44,103.06 179.75,102.37 178.49,102.37 178.03,102.84 175.08,102.84 174.35,102.1 173.04,102.1 172.3,102.84 ; 168.83,102.04 170.51,102.04 171.3,102.84
  TOP w0.102: U6.AJ15 120.03,135.57 120.17,135.43 120.17,131.71 120.17,131.3 ; 172.3,102.84 171.3,102.84
  TOP w0.229: 168.83,102.04 168.57,102.04 158.82,111.79 155.08,111.79 154.85,111.56 154.85,111.33 154.63,111.1 154.17,111.1 153.94,111.33 153.94,111.56 153.71,111.79 153.25,111.79 153.02,111.56 153.02,111.33 152.8,111.1 152.34,111.1 152.11,111.33 152.11,111.56 151.88,111.79 151.42,111.79 151.2,111.56 151.2,111.33 150.97,111.1 150.51,111.1 150.28,111.33 150.28,111.56 150.05,111.79 149.6,111.79 149.37,111.56 149.37,111.33 149.14,111.1 148.68,111.1 148.45,111.33 148.45,111.56 148.22,111.79 147.77,111.79 147.54,111.56 147.54,111.33 147.31,111.1 146.85,111.1 146.62,111.33 146.62,111.56 146.4,111.79 145.94,111.79 145.71,111.56 145.71,111.33 145.48,111.1 145.02,111.1 144.8,111.33 144.8,111.56 144.57,111.79 144.11,111.79 143.88,111.56 143.88,111.33 143.65,111.1 143.2,111.1 142.97,111.33 142.97,111.56 142.74,111.79 142.28,111.79 142.05,111.56 142.05,111.33 141.82,111.1 141.37,111.1 141.14,111.33 141.14,111.56 140.91,111.79 140.45,111.79 140.22,111.56 140.22,111.33 139.99,111.1 139.54,111.1 139.31,111.33 139.31,111.56 139.08,111.79 138.62,111.79 138.39,111.56 138.39,111.33 138.17,111.1 137.71,111.1 137.48,111.33 137.48,111.56 137.25,111.79 136.79,111.79 136.57,111.56 136.57,111.33 136.34,111.1 135.88,111.1 135.65,111.33 135.65,111.56 135.42,111.79 134.97,111.79 134.74,111.56 134.74,111.33 134.51,111.1 134.05,111.1 133.82,111.33 133.82,111.56 133.59,111.79 131.86,111.79 119.64,124.01 119.64,129.84 120.17,130.37 120.17,131.3
MEM_MB_DATA61: length 98.1
  TOP w0.099: 169.27,100.59 169.48,100.37 170.54,100.37 171.32,101.15 172.36,101.15 173.05,101.84 174.59,101.84 175.1,101.33 176.02,101.33 176.52,101.84 179.43,101.84 179.89,101.37 182.44,101.37 J2.228
  TOP w0.229: U6.AL15 119.73,130.57 118.96,129.79 118.96,123.94 132.33,110.57 133.09,110.57 133.32,110.34 133.32,110.03 133.55,109.8 134.01,109.8 134.24,110.03 134.24,110.34 134.46,110.57 134.92,110.57 135.15,110.34 135.15,110.03 135.38,109.8 135.84,109.8 136.06,110.03 136.06,110.34 136.29,110.57 136.75,110.57 136.98,110.34 136.98,110.03 137.21,109.8 137.66,109.8 137.89,110.03 137.89,110.34 138.12,110.57 138.58,110.57 138.81,110.34 138.81,110.03 139.04,109.8 139.49,109.8 139.72,110.03 139.72,110.34 139.95,110.57 140.41,110.57 140.64,110.34 140.64,110.03 140.86,109.8 141.32,109.8 141.55,110.03 141.55,110.34 141.78,110.57 142.24,110.57 142.47,110.34 142.47,110.03 142.69,109.8 143.15,109.8 143.38,110.03 143.38,110.34 143.61,110.57 144.07,110.57 144.29,110.34 144.29,110.03 144.52,109.8 144.98,109.8 145.21,110.03 145.21,110.34 145.44,110.57 145.89,110.57 146.12,110.34 146.12,110.03 146.35,109.8 146.81,109.8 147.04,110.03 147.04,110.34 147.27,110.57 147.72,110.57 147.95,110.34 147.95,110.03 148.18,109.8 148.64,109.8 148.87,110.03 148.87,110.34 149.09,110.57 149.55,110.57 149.78,110.34 149.78,110.03 150.01,109.8 150.47,109.8 150.69,110.03 150.69,110.34 150.92,110.57 151.38,110.57 151.61,110.34 151.61,110.03 151.84,109.8 152.29,109.8 152.52,110.03 152.52,110.34 152.75,110.57 153.21,110.57 153.44,110.34 153.44,110.03 153.67,109.8 154.12,109.8 154.35,110.03 154.35,110.34 154.58,110.57 155.04,110.57 155.27,110.34 155.27,110.03 155.5,109.8 155.95,109.8 156.18,110.03 156.18,110.34 156.41,110.57 156.87,110.57 157.1,110.34 157.1,110.03 157.32,109.8 157.78,109.8 158.01,110.03 158.01,110.34 158.24,110.57 159.29,110.57 169.27,100.59
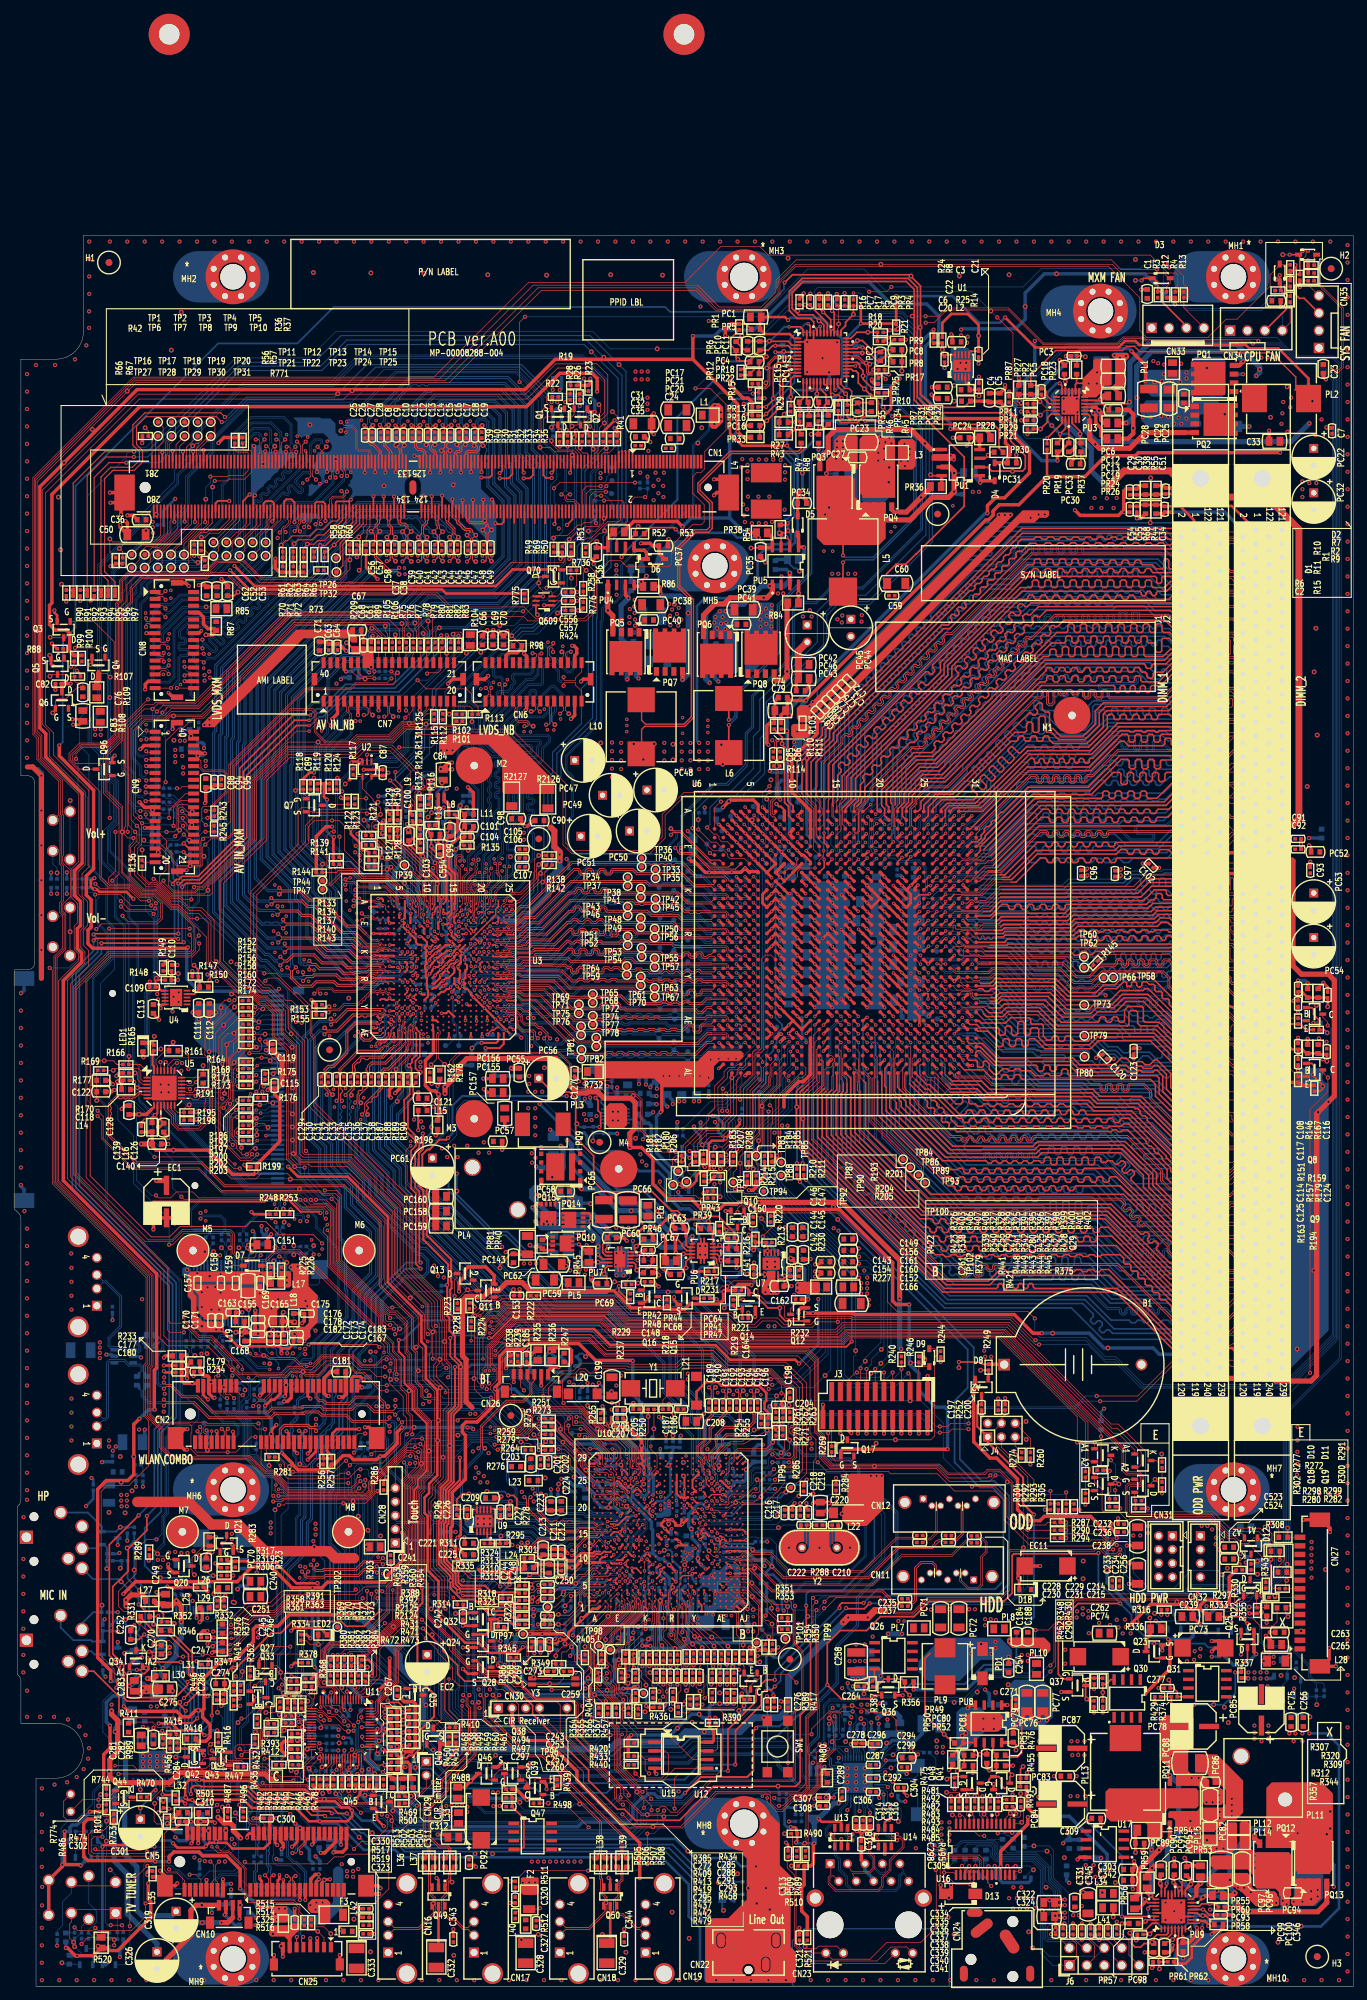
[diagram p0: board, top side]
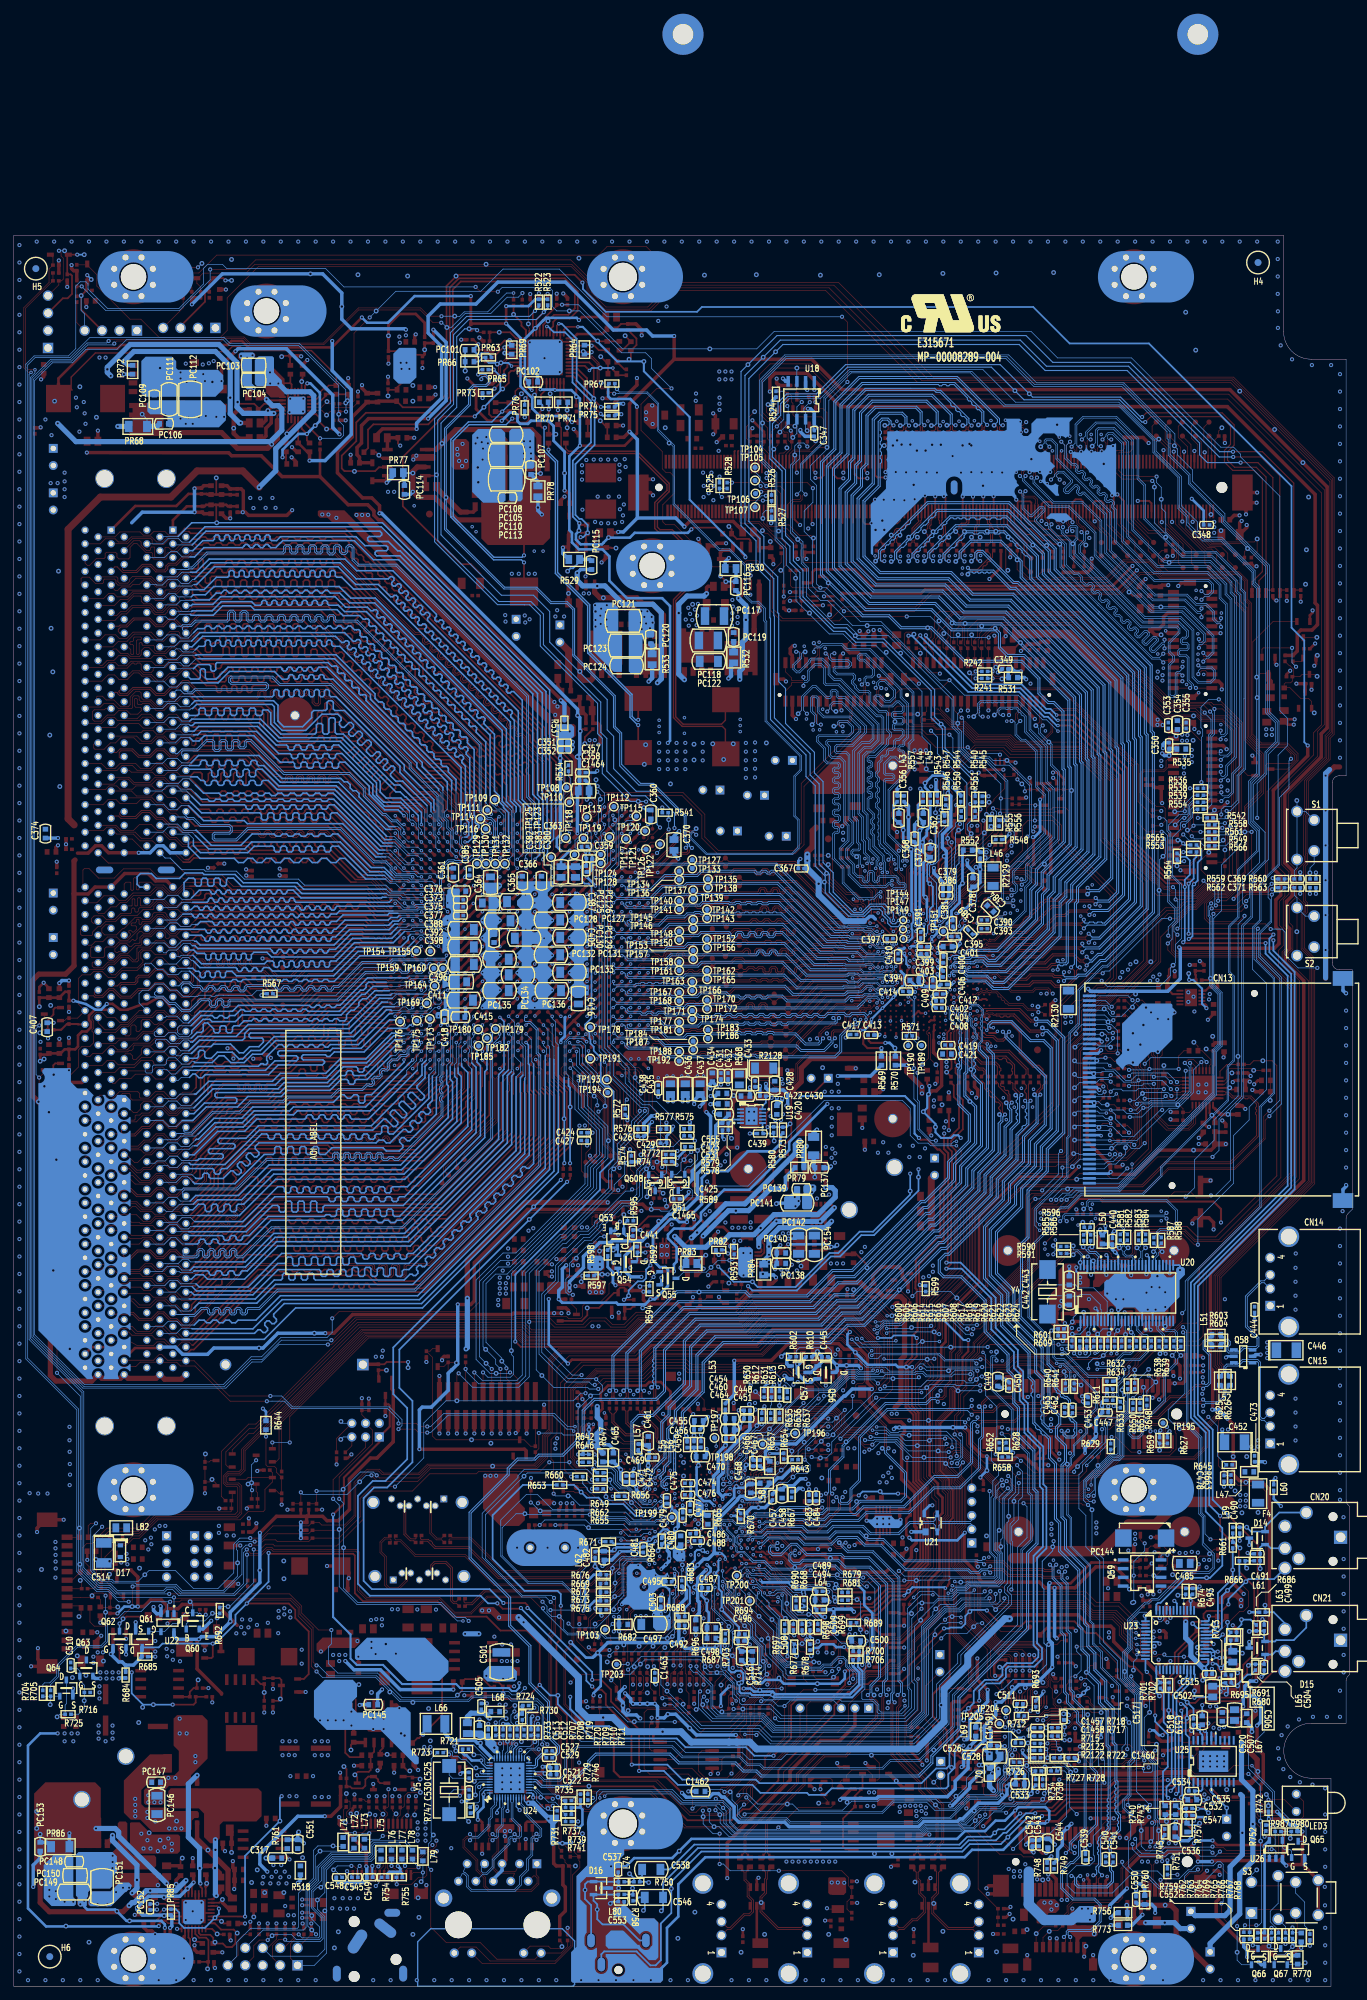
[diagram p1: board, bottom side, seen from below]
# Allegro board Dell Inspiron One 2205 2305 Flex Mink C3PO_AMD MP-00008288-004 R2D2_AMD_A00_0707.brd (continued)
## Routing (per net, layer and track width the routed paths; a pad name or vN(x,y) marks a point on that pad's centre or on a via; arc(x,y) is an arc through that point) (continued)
MEM_MB_DATA62: length 97.1
  TOP w0.099: J2.233 182.26,96.11 181.49,95.34 180.45,95.34 179.66,96.12 177.75,96.12 176.99,95.36 175.19,95.36 174.33,96.23 173.08,96.23 172.09,95.24 171.19,95.24 170.57,94.61 170.33,94.37 169.41,94.37 ; 115.53,130.06 115.53,129.55
  TOP w0.102: 115.53,130.06 117.19,131.73 U6.AL13 ; 169.14,94.64 169.41,94.37
  TOP w0.229: 169.14,94.64 159.38,104.4 158.31,104.4 158,104.09 157.4,104.09 157.09,104.4 156.48,104.4 156.17,104.09 155.57,104.09 155.26,104.4 154.65,104.4 154.35,104.09 153.74,104.09 153.43,104.4 152.82,104.4 152.52,104.09 151.91,104.09 151.6,104.4 151,104.4 150.69,104.09 150.08,104.09 149.77,104.4 149.17,104.4 148.86,104.09 148.25,104.09 147.94,104.4 147.34,104.4 147.03,104.09 146.42,104.09 146.12,104.4 145.51,104.4 145.2,104.09 144.59,104.09 144.29,104.4 143.52,104.4 141.84,102.72 135.88,102.72 115.53,123.06 115.53,129.55
MEM_MB_DATA63: length 97.6
  TOP w0.099: 168.97,94.09 170.62,94.09 171.41,94.88 172.29,94.88 173.35,95.94 174.05,95.94 174.88,95.11 177.28,95.11 178,95.84 179.36,95.84 180.22,94.98 182.58,94.98 J2.234
  TOP w0.102: 168.94,94.06 168.97,94.09 ; 115.48,130.61 116.76,131.89 116.76,136.41 U6.AH13
  TOP w0.229: 168.94,94.06 168.94,94.08 159.47,103.56 143.44,103.56 142.06,102.18 135.66,102.18 114.95,122.88 114.95,130.06 115.48,130.58 115.48,130.61
MEM_MB_DM0: length 97.5
  TOP w0.099: J2.125 184.61,207.31 184.23,206.93 183.99,206.93 182.97,207.95 181.85,207.95 181.68,208.12 181.68,208.7 181.51,208.87 180.16,208.87 179.96,208.67 179.96,208.2 179.68,207.91 178.27,207.91 178.06,208.12 178.06,209.59 177.5,210.15 177.04,210.15 175.73,208.84 174.9,208.84 174.75,208.69 174.75,208.04 174.6,207.89 172.83,207.89 172.68,208.04 172.68,208.69 172.53,208.84 171.32,208.84 170.29,209.87 168.98,209.87 168.54,209.42 ; 116.93,173.1 117.44,172.59 117.44,171.69 117.63,171.51 117.63,170.64 117.19,170.21 U6.B13
  TOP w0.102: 116.93,173.33 116.93,173.1
  TOP w0.229: 116.93,173.33 116.72,173.54 116.72,178.28 119.78,181.33 119.78,182.21 135.31,197.75 136.2,197.75 140.3,201.85 147.82,209.36 168.48,209.36 168.54,209.42
MEM_MB_DM1: length 88.5
  TOP w0.099: J2.134 182.56,198.95 180.25,198.95 179.32,199.89 178.58,199.89 177.63,200.84 175.28,200.84 174.86,200.42 174.86,200.25 174.44,199.83 172.96,199.83 172.61,200.18 172.61,200.35 172.13,200.84
  TOP w0.102: U6.B17 122.27,170.3 122.71,170.74 122.71,171.86 122.71,171.86 ; 169.29,199.91 170.74,199.91 170.94,200.11 170.94,200.42 171.36,200.84 172.13,200.84
  TOP w0.229: 122.71,171.86 123.35,172.51 123.35,172.9 123.84,173.38 123.84,174.61 130.4,181.17 131.04,181.17 131.56,181.69 131.56,182.02 131.42,182.16 131.42,182.48 131.75,182.81 132.07,182.81 132.21,182.66 132.53,182.66 132.86,182.99 132.86,183.31 132.72,183.45 132.72,183.77 133.04,184.1 133.36,184.1 133.5,183.96 133.83,183.96 134.15,184.28 134.15,184.6 134.01,184.75 134.01,185.07 134.33,185.39 134.66,185.39 134.8,185.25 135.12,185.25 135.44,185.57 135.44,185.9 135.3,186.04 135.3,186.36 135.63,186.69 135.95,186.69 136.09,186.54 136.41,186.54 136.74,186.87 136.74,187.19 136.6,187.33 136.6,187.65 136.92,187.98 137.24,187.98 137.38,187.84 137.71,187.84 138.03,188.16 138.03,188.48 137.89,188.63 137.89,188.95 138.21,189.27 138.54,189.27 138.68,189.13 139,189.13 139.32,189.46 139.32,189.78 139.18,189.92 139.18,190.24 139.51,190.57 139.83,190.57 139.97,190.42 140.29,190.42 140.62,190.75 140.62,191.07 140.48,191.21 140.48,191.54 140.8,191.86 141.12,191.86 141.26,191.72 141.59,191.72 141.91,192.04 141.91,192.36 141.77,192.51 141.77,192.83 142.09,193.15 142.42,193.15 142.56,193.01 142.88,193.01 143.2,193.34 143.2,193.66 143.06,193.8 143.06,194.12 143.39,194.45 143.71,194.45 143.85,194.3 144.17,194.3 144.5,194.63 144.5,194.95 144.36,195.09 144.36,195.42 144.68,195.74 145,195.74 145.14,195.6 145.47,195.6 145.79,195.92 145.79,196.24 145.65,196.39 145.65,196.71 145.97,197.03 146.3,197.03 146.44,196.89 146.76,196.89 147.08,197.22 147.08,197.54 146.94,197.68 146.94,198 147.27,198.33 147.59,198.33 147.73,198.19 148.05,198.19 148.38,198.51 148.38,198.83 148.24,198.97 148.24,199.3 148.56,199.62 148.88,199.62 149.02,199.48 149.35,199.48 150.29,200.42 168.33,200.42 168.84,199.91 169.29,199.91
MEM_MB_DM2: length 72.5
  TOP w0.099: J2.143 182.14,190.11 181.24,191.01 180.31,191.01 179.66,190.36 178.47,190.36 177.53,191.3 176.77,191.3 176.31,190.84 175.13,190.84 174.28,189.98 173.12,189.98 172.26,190.84 171.25,190.84 170.25,191.83 169.32,191.83 168.86,191.37
  TOP w0.229: 168.86,191.37 166.95,189.46 165.66,189.46 165.45,189.25 165.45,188.68 165.23,188.46 164.93,188.46 164.71,188.68 164.71,189.25 164.5,189.46 164.19,189.46 163.98,189.25 163.98,188.68 163.76,188.46 163.45,188.46 163.24,188.68 163.24,189.25 163.02,189.46 162.72,189.46 162.5,189.25 162.5,188.68 162.29,188.46 161.98,188.46 161.77,188.68 161.77,189.25 161.55,189.46 161.24,189.46 161.03,189.25 161.03,188.68 160.81,188.46 160.51,188.46 160.29,188.68 160.29,189.25 160.08,189.46 149.58,189.46 135.54,175.43 132.73,175.43 130.79,173.48 130.79,172.49 129.89,171.6 U6.A23
MEM_MB_DM3: length 56.1
  TOP w0.099: 168.72,180.7 168.97,180.7 169.05,180.77 169.05,181.32 169.23,181.5 169.56,181.84 170.38,181.84 171.27,180.94 172.25,180.94 173.16,181.85 174.08,181.85 174.92,181.01 176.65,181.01 177.49,181.85 179.43,181.85 180.17,181.11 180.91,181.11 181.82,180.19 183.17,180.19 183.35,180.37 183.35,180.9 183.14,181.11 J2.152
  TOP w0.229: 168.72,180.7 168.49,180.92 168.49,181.61 168.31,181.79 167.73,181.79 167.55,181.61 167.55,181 167.24,180.7 162.27,180.7 161.61,181.36 161.05,181.36 156.76,177.06 147.7,177.06 139.22,168.59 U6.C30
MEM_MB_DM4: length 54.8
  TOP w0.099: J2.203 182.08,126.11 181.3,126.88 180.49,126.88 179.51,125.91 177.13,125.91 176.16,126.88 175.09,126.88 174.12,127.85 173.39,127.85 172.37,126.83 171.25,126.83 170.26,127.82 169.44,127.82 169.21,127.6 168.63,127.6
  TOP w0.229: 168.63,127.6 168.25,127.6 166.18,129.67 166.18,131.37 165.45,132.1 146.8,132.1 146.52,132.38 146.52,132.56 146.29,132.79 145.83,132.79 145.6,132.56 145.6,132.38 145.38,132.16 144.92,132.16 144.69,132.38 144.69,132.56 144.46,132.79 144,132.79 143.77,132.56 143.77,132.38 143.55,132.16 142.45,132.16 141.13,133.48 138.33,133.48 U6.AK29
MEM_MB_DM5: length 68.3
  TOP w0.099: 169.3,117.77 169.37,117.84 170.24,117.84 171.23,116.85 172.37,116.85 173.39,117.87 174.02,117.87 175.04,116.85 177.31,116.85 178.3,117.84 179.33,117.84 180.06,117.11 182.71,117.11 J2.212
  TOP w0.102: U6.AJ23 130.33,135.14 130.33,131.46
  TOP w0.229: 169.3,117.77 169.05,117.51 169.05,117.35 168.79,117.09 168.41,117.09 167.87,117.64 167.87,118.99 162.12,124.74 161.45,124.74 161.2,124.49 160.72,124.49 160.46,124.74 159.98,124.74 159.72,124.49 137.3,124.49 136.94,124.85 136.64,124.85 136.58,124.79 136.28,124.79 136.06,125.01 136.06,125.31 136.12,125.37 136.12,125.67 135.9,125.89 135.59,125.89 135.54,125.83 135.23,125.83 135.02,126.05 135.02,126.35 135.07,126.41 135.07,126.72 134.86,126.93 134.55,126.93 134.5,126.88 134.19,126.88 133.98,127.09 133.98,127.4 134.03,127.45 134.03,127.76 133.82,127.97 133.51,127.97 133.45,127.92 133.15,127.92 132.93,128.13 132.93,128.44 132.99,128.49 132.99,128.8 130.33,131.46
MEM_MB_DM6: length 82.4
  TOP w0.099: 168.93,107.95 170.39,107.95 171.28,108.84 172.3,108.84 173.19,107.95 174.23,107.95 175.12,108.84 176.01,108.84 176.74,108.1 179.51,108.1 180.28,108.87 181.44,108.87 182,108.31 184.41,108.31 J2.221
  TOP w0.102: U6.AH17 123.11,136 123.11,132.44 123.61,131.95
  TOP w0.229: 168.93,107.95 161.51,115.37 133.42,115.37 123.96,124.82 123.96,131.59 123.61,131.95
MEM_MB_DM7: length 97.7
  TOP w0.099: 119.13,134.1 119.13,134.39 119.41,134.67 ; 168.95,97.92 170.39,97.92 171.39,98.92 172.07,98.92 172.99,99.83 174.12,99.83 175.06,98.89 176.88,98.89 177.82,99.84 179.21,99.84 179.94,99.11 182.71,99.11 J2.230
  TOP w0.102: 118.03,130.82 118.03,133.54 118.28,133.79 118.82,133.79 119.13,134.1 ; U6.AJ14 119.01,135.57 119.41,135.16 119.41,134.67 ; 168.54,98.33 168.95,97.92
  TOP w0.229: 118.03,130.82 117.89,130.68 117.87,130.68 116.98,129.79 116.98,123.66 134.08,106.55 135.26,106.55 135.52,106.3 136.18,106.3 136.43,106.55 137.09,106.55 137.35,106.3 138.01,106.3 138.26,106.55 138.92,106.55 139.17,106.3 139.84,106.3 140.09,106.55 140.75,106.55 141,106.3 141.66,106.3 141.92,106.55 142.58,106.55 142.83,106.3 143.49,106.3 143.75,106.55 144.41,106.55 144.66,106.3 145.32,106.3 145.58,106.55 146.24,106.55 146.49,106.3 147.15,106.3 147.4,106.55 148.06,106.55 148.32,106.3 148.98,106.3 149.23,106.55 149.89,106.55 150.15,106.3 150.81,106.3 151.06,106.55 151.72,106.55 151.98,106.3 152.64,106.3 152.89,106.55 153.55,106.55 153.81,106.3 154.47,106.3 154.72,106.55 155.38,106.55 155.63,106.3 156.29,106.3 156.55,106.55 157.21,106.55 157.46,106.3 158.12,106.3 158.38,106.55 161.04,106.55 161.56,106.03 161.56,105.73 161.55,105.72 161.55,105.41 161.77,105.2 162.07,105.2 162.08,105.21 162.39,105.21 162.6,104.99 162.6,104.68 162.59,104.68 162.59,104.37 162.81,104.15 163.12,104.15 163.12,104.16 163.43,104.16 163.65,103.95 163.65,103.64 163.64,103.63 163.64,103.33 163.85,103.11 164.16,103.11 164.17,103.12 164.47,103.12 164.69,102.91 164.69,102.6 164.68,102.59 164.68,102.29 164.89,102.07 165.2,102.07 165.21,102.08 165.51,102.08 165.73,101.86 165.73,101.56 165.72,101.55 165.72,101.24 165.94,101.03 166.24,101.03 166.25,101.04 166.56,101.04 166.77,100.82 166.77,100.52 166.76,100.51 166.76,100.2 166.98,99.99 167.28,99.99 167.29,100 167.6,100 168.54,99.05 168.54,98.33
MEM_MB_DM8: length 52.8
  TOP w0.099: J2.161 184.52,172.11 184.52,172.11 182,172.11 181.27,172.84 180.07,172.84 179.53,172.29 177.09,172.29 176.54,172.84 175.04,172.84 174.15,171.94 173.29,171.94 172.22,170.87 171.41,170.87 170.67,170.13 169.71,170.13
  TOP w0.102: 143.11,162.92 141.57,162.92 140.38,161.72 138.72,161.72 137.96,160.97 U6.J29
  TOP w0.229: 143.11,162.92 149.21,169.01 168.59,169.01 169.71,170.13
MEM_MB_DQS0_N: length 97.6
  TOP w0.099: 117.52,173.89 117.52,173.34 117.83,173.04 117.83,169.22 U6.C13
  TOP w0.13: 117.52,173.89 117.52,178.24 120.36,181.09 120.36,181.95 120.88,182.47 121.29,182.47 121.44,182.32 121.62,182.32 121.81,182.5 121.81,182.68 121.66,182.83 121.66,183.24 122,183.58 122.41,183.58 122.56,183.44 122.74,183.44 122.92,183.62 122.92,183.8 122.78,183.95 122.78,184.36 123.12,184.7 123.53,184.7 123.68,184.55 123.86,184.55 124.04,184.74 124.04,184.92 123.89,185.07 123.89,185.48 124.24,185.82 124.64,185.82 124.79,185.67 124.98,185.67 125.16,185.85 125.16,186.04 125.01,186.19 125.01,186.59 125.35,186.94 125.76,186.94 125.91,186.79 126.09,186.79 126.28,186.97 126.28,187.15 126.13,187.3 126.13,187.71 126.47,188.05 126.88,188.05 127.03,187.91 127.21,187.91 127.39,188.09 127.39,188.27 127.25,188.42 127.25,188.83 127.59,189.17 128,189.17 128.15,189.02 128.33,189.02 128.51,189.21 128.51,189.39 128.36,189.54 128.36,189.95 128.71,190.29 129.11,190.29 129.26,190.14 129.45,190.14 129.63,190.32 129.63,190.51 129.48,190.65 129.48,191.06 129.82,191.41 130.23,191.41 130.38,191.26 130.56,191.26 130.75,191.44 130.75,191.62 130.6,191.77 130.6,192.18 130.94,192.52 131.35,192.52 131.5,192.37 131.68,192.37 131.86,192.56 131.86,192.74 131.72,192.89 131.72,193.3 132.06,193.64 132.47,193.64 132.61,193.49 132.8,193.49 132.98,193.68 132.98,193.86 132.83,194.01 132.83,194.42 133.18,194.76 133.58,194.76 133.73,194.61 133.91,194.61 134.1,194.79 134.1,194.98 133.95,195.12 133.95,195.53 134.29,195.88 134.7,195.88 134.81,195.76 135.03,195.76 135.18,195.92 135.18,196.13 135.07,196.24 135.07,196.65 135.58,197.16 136.44,197.16 148.06,208.78 169.21,208.78 169.67,208.32 170.35,208.32 171.39,207.28 172.45,207.28 172.84,206.89 172.84,206.5 173.05,206.29 174.18,206.29 175.01,207.12 176.26,207.12 177.18,206.2 178.98,206.2 179.16,206.38 179.16,206.85 J2.6
MEM_MB_DQS0_P: length 98.7
  TOP w0.099: 117.79,173.89 117.79,173.86 117.72,173.79 117.72,173.43 118.03,173.12 118.03,168.68 118.12,168.59 U6.C14
  TOP w0.13: 117.79,173.89 117.79,178.13 120.64,180.97 120.64,181.83 121,182.2 121.18,182.2 121.33,182.05 121.74,182.05 122.08,182.39 122.08,182.8 121.93,182.95 121.93,183.13 122.11,183.31 122.3,183.31 122.45,183.16 122.85,183.16 123.2,183.51 123.2,183.92 123.05,184.06 123.05,184.25 123.23,184.43 123.41,184.43 123.56,184.28 123.97,184.28 124.31,184.62 124.31,185.03 124.17,185.18 124.17,185.36 124.35,185.55 124.53,185.55 124.68,185.4 125.09,185.4 125.43,185.74 125.43,186.15 125.28,186.3 125.28,186.48 125.47,186.66 125.65,186.66 125.8,186.52 126.21,186.52 126.55,186.86 126.55,187.27 126.4,187.42 126.4,187.6 126.58,187.78 126.77,187.78 126.92,187.63 127.32,187.63 127.67,187.98 127.67,188.38 127.52,188.53 127.52,188.72 127.7,188.9 127.88,188.9 128.03,188.75 128.44,188.75 128.78,189.09 128.78,189.5 128.63,189.65 128.63,189.83 128.82,190.02 129,190.02 129.15,189.87 129.56,189.87 129.9,190.21 129.9,190.62 129.75,190.77 129.75,190.95 129.94,191.13 130.12,191.13 130.27,190.99 130.68,190.99 131.02,191.33 131.02,191.74 130.87,191.88 130.87,192.07 131.05,192.25 131.24,192.25 131.38,192.1 131.79,192.1 132.14,192.45 132.14,192.85 131.99,193 131.99,193.19 132.17,193.37 132.35,193.37 132.5,193.22 132.91,193.22 133.25,193.56 133.25,193.97 133.1,194.12 133.1,194.3 133.29,194.49 133.47,194.49 133.62,194.34 134.03,194.34 134.37,194.68 134.37,195.09 134.22,195.24 134.22,195.42 134.41,195.6 134.59,195.6 134.7,195.49 135.14,195.49 135.45,195.8 135.45,196.24 135.34,196.35 135.34,196.54 135.69,196.89 136.56,196.89 148.17,208.5 169.1,208.5 169.55,208.05 170.23,208.05 171.28,207 172.34,207 172.57,206.77 172.57,206.39 172.94,206.01 174.29,206.01 175.12,206.84 176.15,206.84 177.07,205.93 179.09,205.93 179.91,206.74 180.28,206.74 180.81,206.22 J2.7
MEM_MB_DQS1_N: length 89.5
  TOP w0.102: U6.C17 122.27,168.16 122.38,168.05 122.63,168.05 122.91,168.33 122.91,171.45 123.73,172.28 123.73,172.69
  TOP w0.13: 123.73,172.69 124.6,173.56 124.6,174.54 130.6,180.55 132.21,180.55 132.66,181 132.66,181.18 132.47,181.37 132.47,181.78 132.82,182.12 133.23,182.12 133.41,181.93 133.59,181.93 133.78,182.12 133.78,182.3 133.59,182.49 133.59,182.89 133.93,183.24 134.34,183.24 134.53,183.05 134.71,183.05 134.89,183.24 134.89,183.42 134.71,183.6 134.71,184.01 135.05,184.35 135.46,184.35 135.65,184.17 135.83,184.17 136.01,184.35 136.01,184.54 135.83,184.72 135.83,185.13 136.17,185.47 136.58,185.47 136.76,185.29 136.95,185.29 137.13,185.47 137.13,185.65 136.94,185.84 136.94,186.25 137.29,186.59 137.69,186.59 137.88,186.4 138.06,186.4 138.25,186.59 138.25,186.77 138.06,186.96 138.06,187.36 138.4,187.71 138.81,187.71 139,187.52 139.18,187.52 139.36,187.71 139.36,187.89 139.18,188.07 139.18,188.48 139.52,188.82 139.93,188.82 140.11,188.64 140.3,188.64 140.48,188.82 140.48,189.01 140.3,189.19 140.3,189.6 140.64,189.94 141.05,189.94 141.23,189.76 141.41,189.76 141.6,189.94 141.6,190.12 141.41,190.31 141.41,190.72 141.76,191.06 142.16,191.06 142.35,190.87 142.53,190.87 142.72,191.06 142.72,191.24 142.53,191.43 142.53,191.83 142.87,192.18 143.28,192.18 143.47,191.99 143.65,191.99 143.83,192.17 143.83,192.36 143.65,192.54 143.65,192.95 143.99,193.29 144.4,193.29 144.58,193.11 144.77,193.11 144.95,193.29 144.95,193.47 144.77,193.66 144.77,194.07 145.11,194.41 145.52,194.41 145.7,194.23 145.88,194.23 146.07,194.41 146.07,194.59 145.88,194.78 145.88,195.19 146.23,195.53 146.63,195.53 146.82,195.34 147,195.34 147.19,195.53 147.19,195.71 147,195.89 147,196.3 147.34,196.65 147.75,196.65 147.94,196.46 148.12,196.46 151.49,199.84 168.09,199.84 169.78,198.14 170.43,198.14 171.56,199.27 172.34,199.27 173.31,198.3 174.17,198.3 175.17,199.3 177.58,199.3 178.61,198.26 179.51,198.26 179.67,198.11 J2.15
MEM_MB_DQS1_P: length 89.7
  TOP w0.102: U6.D17 122.27,167.75 122.38,167.85 122.72,167.85 123.11,168.25 123.11,171.37 123.94,172.2 123.94,172.51 123.95,172.53
  TOP w0.13: J2.16 179.54,197.1 179.54,197.1 179.77,197.33 179.77,197.62 179.66,197.72 179.4,197.99 178.5,197.99 177.47,199.03 175.29,199.03 174.29,198.02 173.2,198.02 172.23,199 171.67,199 170.55,197.87 169.67,197.87 167.97,199.56 151.61,199.56 148.23,196.19 147.82,196.19 147.64,196.37 147.46,196.37 147.27,196.19 147.27,196.01 147.46,195.82 147.46,195.41 147.11,195.07 146.71,195.07 146.52,195.26 146.34,195.26 146.15,195.07 146.15,194.89 146.34,194.7 146.34,194.3 146,193.95 145.59,193.95 145.4,194.14 145.22,194.14 145.04,193.96 145.04,193.77 145.22,193.59 145.22,193.18 144.88,192.84 144.47,192.84 144.29,193.02 144.1,193.02 143.92,192.84 143.92,192.66 144.1,192.47 144.1,192.06 143.76,191.72 143.35,191.72 143.17,191.9 142.99,191.9 142.8,191.72 142.8,191.54 142.99,191.35 142.99,190.94 142.64,190.6 142.24,190.6 142.05,190.79 141.87,190.79 141.68,190.6 141.68,190.42 141.87,190.24 141.87,189.83 141.53,189.48 141.12,189.48 140.93,189.67 140.75,189.67 140.57,189.49 140.57,189.3 140.75,189.12 140.75,188.71 140.41,188.37 140,188.37 139.82,188.55 139.63,188.55 139.45,188.37 139.45,188.19 139.64,188 139.64,187.59 139.29,187.25 138.88,187.25 138.7,187.44 138.52,187.44 138.33,187.25 138.33,187.07 138.52,186.88 138.52,186.48 138.18,186.13 137.77,186.13 137.58,186.32 137.4,186.32 137.22,186.13 137.22,185.95 137.4,185.77 137.4,185.36 137.06,185.02 136.65,185.02 136.46,185.2 136.28,185.2 136.1,185.02 136.1,184.83 136.28,184.65 136.28,184.24 135.94,183.9 135.53,183.9 135.35,184.08 135.16,184.08 134.98,183.9 134.98,183.72 135.17,183.53 135.17,183.12 134.82,182.78 134.42,182.78 134.23,182.97 134.05,182.97 133.86,182.78 133.86,182.6 134.05,182.41 134.05,182.01 133.71,181.66 133.3,181.66 133.11,181.85 132.93,181.85 132.75,181.66 132.75,181.48 132.93,181.3 132.93,180.89 132.32,180.28 130.72,180.28 124.87,174.43 124.87,173.45 123.95,172.53
MEM_MB_DQS2_N: length 73.2
  TOP w0.13: U6.C23 129.99,168.59 130.38,168.98 130.38,171.59 131.14,172.35 131.14,172.89 131.46,173.2 131.46,173.33 132.97,174.84 135.81,174.84 148.77,187.8 149.41,187.8 149.54,187.93 149.54,188.59 149.82,188.88 150.31,188.88 150.6,188.58 150.6,186.92 150.73,186.79 150.98,186.79 151.26,187.07 151.26,188.55 151.57,188.86 152.08,188.86 152.33,188.61 152.33,188.38 152.48,188.24 152.84,188.24 152.97,188.37 152.97,188.62 153.23,188.88 153.89,188.88 154.15,188.62 154.15,188.47 154.24,188.38 154.7,188.38 154.79,188.47 154.79,188.59 155.08,188.88 155.56,188.88 155.85,188.59 155.85,188 156.06,187.79 156.36,187.79 156.49,187.92 156.49,188.59 156.78,188.88 157.33,188.88 157.62,188.59 157.62,187.87 157.72,187.77 158.16,187.77 158.26,187.87 158.26,188.59 158.55,188.88 159.06,188.88 159.42,188.51 159.42,188.01 159.62,187.8 167.18,187.8 169.57,190.19 170.39,190.19 171.23,189.35 172.06,189.35 173.11,188.3 174.18,188.3 175.08,189.19 177.62,189.19 178.54,188.27 179.45,188.27 179.62,188.44 179.68,188.55 179.68,188.55 179.62,188.73 J2.24
MEM_MB_DQS2_P: length 73.1
  TOP w0.13: U6.C24 131.15,168.59 130.65,169.08 130.65,171.48 131.42,172.24 131.42,172.77 131.73,173.09 131.73,173.22 133.08,174.57 135.92,174.57 148.88,187.53 149.52,187.53 149.81,187.82 149.81,188.48 149.94,188.61 150.2,188.61 150.33,188.47 150.33,186.81 150.62,186.52 151.09,186.52 151.53,186.96 151.53,188.44 151.68,188.59 151.97,188.59 152.06,188.49 152.06,188.27 152.37,187.97 152.95,187.97 153.24,188.26 153.24,188.5 153.35,188.61 153.78,188.61 153.88,188.5 153.88,188.36 154.13,188.11 154.81,188.11 155.06,188.36 155.06,188.48 155.19,188.61 155.45,188.61 155.58,188.48 155.58,187.89 155.95,187.52 156.47,187.52 156.76,187.81 156.76,188.48 156.89,188.61 157.22,188.61 157.35,188.48 157.35,187.76 157.61,187.5 158.27,187.5 158.53,187.76 158.53,188.48 158.66,188.61 158.94,188.61 159.15,188.4 159.15,187.89 159.51,187.53 167.29,187.53 169.68,189.92 170.28,189.92 171.12,189.08 171.95,189.08 173,188.03 174.3,188.03 175.19,188.92 177.51,188.92 178.43,188 179.56,188 179.84,188.28 179.92,188.43 180.09,188.48 180.26,188.48 180.81,188.2 J2.25
MEM_MB_DQS3_N: length 54.9
  TOP w0.13: U6.C31 140.17,168.59 140.3,168.72 140.3,168.83 147.94,176.48 148.81,176.48 149.09,176.19 149.09,175.64 149.22,175.51 149.48,175.51 149.61,175.64 149.61,176.19 149.9,176.48 150.39,176.48 150.67,176.19 150.67,175.64 150.8,175.51 151.06,175.51 151.19,175.64 151.19,176.19 151.48,176.48 151.97,176.48 152.25,176.19 152.25,175.64 152.38,175.51 152.64,175.51 152.77,175.64 152.77,176.19 153.06,176.48 153.55,176.48 153.83,176.19 153.83,175.64 153.96,175.51 154.22,175.51 154.35,175.64 154.35,176.19 154.64,176.48 155.13,176.48 155.41,176.19 155.41,175.69 155.57,175.54 155.78,175.54 155.93,175.69 155.93,176.19 156.22,176.48 157,176.48 160.63,180.11 168.67,180.11 168.78,180.23 170.5,180.23 171.41,179.32 172.14,179.32 173.06,180.23 174.24,180.23 175.18,179.3 176.74,179.3 177.67,180.23 179.5,180.23 180.03,179.7 180.71,179.7 180.81,179.79 J2.33
MEM_MB_DQS3_P: length 55.8
  TOP w0.13: J2.34 178.91,179.03 179.12,178.82 179.42,178.82 179.63,179.03 179.63,179.71 179.39,179.95 177.78,179.95 176.85,179.02 175.07,179.02 174.13,179.96 173.17,179.96 172.26,179.05 171.3,179.05 170.39,179.95 168.9,179.95 168.78,179.84 160.75,179.84 157.12,176.21 156.33,176.21 156.2,176.08 156.2,175.58 155.89,175.27 155.45,175.27 155.14,175.58 155.14,176.08 155.01,176.21 154.75,176.21 154.62,176.08 154.62,175.52 154.34,175.23 153.85,175.23 153.56,175.52 153.56,176.08 153.43,176.21 153.17,176.21 153.04,176.08 153.04,175.52 152.76,175.23 152.27,175.23 151.98,175.52 151.98,176.08 151.85,176.21 151.59,176.21 151.46,176.08 151.46,175.52 151.18,175.23 150.69,175.23 150.4,175.52 150.4,176.08 150.27,176.21 150.01,176.21 149.88,176.08 149.88,175.52 149.6,175.23 149.11,175.23 148.82,175.52 148.82,176.08 148.69,176.21 148.06,176.21 140.57,168.72 140.57,168.36 140.05,167.85 U6.D31
MEM_MB_DQS4_N: length 53.6
  TOP w0.13: J2.84 179.3,124.72 179.3,124.32 179.11,124.13 177.41,124.13 176.31,125.22 175.28,125.22 174.31,126.19 173.21,126.19 172.27,125.25 171.47,125.25 170.55,126.16 168.79,126.16 165.59,129.37 165.59,130.46 164.53,131.51 162.35,131.51 162.06,131.23 162.06,130.63 161.94,130.5 161.68,130.5 161.55,130.63 161.55,131.23 161.26,131.51 160.77,131.51 160.49,131.23 160.49,130.63 160.36,130.5 160.1,130.5 159.97,130.63 159.97,131.23 159.68,131.51 159.19,131.51 158.91,131.23 158.91,130.63 158.78,130.5 158.52,130.5 158.39,130.63 158.39,131.23 158.1,131.51 142.39,131.51 141.33,132.57 137.14,132.57 137.04,132.68 137.04,132.89 137.18,133.03 U6.AL29
MEM_MB_DQS4_P: length 54.7
  TOP w0.13: J2.85 180.75,124.17 179.53,124.17 179.22,123.86 177.29,123.86 176.2,124.95 175.17,124.95 174.2,125.92 173.33,125.92 172.38,124.98 171.36,124.98 170.44,125.89 168.68,125.89 165.31,129.26 165.31,130.35 164.42,131.24 162.47,131.24 162.34,131.11 162.34,130.51 162.05,130.23 161.56,130.23 161.28,130.51 161.28,131.11 161.15,131.24 160.89,131.24 160.76,131.11 160.76,130.51 160.47,130.23 159.98,130.23 159.7,130.51 159.7,131.11 159.57,131.24 159.31,131.24 159.18,131.11 159.18,130.51 158.89,130.23 158.4,130.23 158.12,130.51 158.12,131.11 157.99,131.24 142.27,131.24 141.21,132.3 137.03,132.3 136.76,132.56 136.76,132.79 136.53,133.03 U6.AL28
MEM_MB_DQS5_N: length 68.2
  TOP w0.13: J2.93 180.81,115.82 180.55,115.57 180,115.57 179.36,116.2 177.89,116.2 176.98,115.29 175.19,115.29 174.18,116.3 173.22,116.3 172.19,115.27 171.26,115.27 170.27,116.26 168.36,116.26 167.19,117.42 167.19,118.84 162.13,123.9 148.41,123.9 148.12,123.61 148.12,123.36 147.99,123.23 147.74,123.23 147.61,123.36 147.61,123.61 147.32,123.9 146.83,123.9 146.54,123.61 146.54,123.36 146.41,123.23 146.16,123.23 146.03,123.36 146.03,123.61 145.74,123.9 145.25,123.9 144.96,123.61 144.96,123.36 144.83,123.23 144.58,123.23 144.45,123.36 144.45,123.61 144.16,123.9 143.67,123.9 143.38,123.61 143.38,123.36 143.25,123.23 143,123.23 142.87,123.36 142.87,123.53 142.56,123.84 142.12,123.84 141.8,123.53 141.8,123.36 141.67,123.23 141.42,123.23 141.29,123.36 141.29,123.53 140.98,123.84 140.54,123.84 140.22,123.53 140.22,123.36 140.09,123.23 139.84,123.23 139.71,123.36 139.71,123.53 139.4,123.84 138.96,123.84 138.64,123.53 138.64,123.36 138.52,123.23 138.26,123.23 138.13,123.36 138.13,123.61 137.84,123.9 136.34,123.9 131.6,128.64 131.6,128.89 129.64,130.85 129.64,132.77 U6.AL23
MEM_MB_DQS5_P: length 69.3
  TOP w0.13: J2.94 179.31,115.11 179.51,115.31 179.51,115.67 179.25,115.93 178.01,115.93 177.09,115.02 175.08,115.02 174.07,116.03 173.33,116.03 172.3,115 171.15,115 170.16,115.99 168.24,115.99 166.92,117.31 166.92,118.73 162.02,123.63 148.53,123.63 148.4,123.5 148.4,123.25 148.11,122.96 147.62,122.96 147.33,123.25 147.33,123.5 147.2,123.63 146.95,123.63 146.82,123.5 146.82,123.25 146.53,122.96 146.04,122.96 145.75,123.25 145.75,123.5 145.62,123.63 145.37,123.63 145.24,123.5 145.24,123.25 144.95,122.96 144.46,122.96 144.17,123.25 144.17,123.5 144.04,123.63 143.79,123.63 143.66,123.5 143.66,123.25 143.37,122.96 142.88,122.96 142.59,123.25 142.59,123.42 142.44,123.57 142.23,123.57 142.08,123.42 142.08,123.25 141.79,122.96 141.3,122.96 141.01,123.25 141.01,123.42 140.86,123.57 140.65,123.57 140.5,123.42 140.5,123.25 140.21,122.96 139.72,122.96 139.43,123.25 139.43,123.42 139.28,123.57 139.07,123.57 138.92,123.42 138.92,123.25 138.63,122.96 138.14,122.96 137.85,123.25 137.85,123.5 137.73,123.63 136.22,123.63 131.33,128.52 131.33,128.78 129.37,130.74 129.37,133.77 U6.AK23
MEM_MB_DQS6_N: length 81.2
  TOP w0.099: U6.AJ17 122.91,134.93 122.91,131.81 123,131.72 123,131.36 123.03,131.32 123.03,131.31
  TOP w0.13: 123.03,131.31 123.03,130.6 123.25,130.38 123.25,124.71 133.18,114.78 161.23,114.78 161.84,114.17 161.84,113.76 161.55,113.47 161.55,113.29 161.74,113.11 161.92,113.11 162.21,113.4 162.61,113.4 162.96,113.05 162.96,112.64 162.67,112.36 162.67,112.17 162.85,111.99 163.03,111.99 163.32,112.28 163.73,112.28 164.07,111.94 164.07,111.53 163.79,111.24 163.79,111.06 163.97,110.87 164.15,110.87 164.44,111.16 164.85,111.16 168.16,107.85 168.16,107.1 168.98,106.28 170.35,106.28 171.33,107.26 172.28,107.26 173.28,106.26 174.1,106.26 175.08,107.24 177.03,107.24 178.1,106.17 178.8,106.17 179.06,106.42 179.06,106.96 J2.102
MEM_MB_DQS6_P: length 81.2
  TOP w0.099: 122.76,131.31 122.76,131.32 122.8,131.36 122.8,131.64 122.71,131.73 122.71,133.39 122.27,133.83 U6.AK17
  TOP w0.13: J2.103 180.58,106.11 180.58,106.11 179.13,106.11 178.91,105.89 177.99,105.89 176.91,106.97 175.19,106.97 174.21,105.99 173.17,105.99 172.17,106.99 171.44,106.99 170.46,106.01 168.87,106.01 167.89,106.99 167.89,107.74 164.74,110.89 164.55,110.89 164.27,110.6 163.86,110.6 163.51,110.94 163.51,111.35 163.8,111.64 163.8,111.82 163.62,112.01 163.44,112.01 163.15,111.72 162.74,111.72 162.4,112.06 162.4,112.47 162.69,112.76 162.69,112.94 162.5,113.12 162.32,113.12 162.03,112.84 161.62,112.84 161.28,113.18 161.28,113.59 161.57,113.88 161.57,114.06 161.12,114.51 133.07,114.51 122.98,124.59 122.98,130.27 122.76,130.48 122.76,131.31
MEM_MB_DQS7_N: length 97.8
  TOP w0.099: 117.53,130.84 117.55,130.86 117.55,130.91 117.83,131.18 117.83,134.77 117.56,135.03 117.29,135.03 117.19,135.13 U6.AJ13
  TOP w0.13: J2.111 180.59,97.89 179.92,97.89 179.65,98.16 177.57,98.16 176.69,97.28 174.96,97.28 174.02,98.23 173.12,98.23 172.14,97.25 171.25,97.25 170.19,96.19 169.63,96.19 168.74,97.09 168.74,97.31 160.79,105.25 142.72,105.25 142.43,104.97 142.43,104.52 142.28,104.37 141.94,104.37 141.79,104.52 141.79,104.97 141.5,105.25 140.89,105.25 140.6,104.97 140.6,103.7 140.47,103.57 140.08,103.57 139.95,103.7 139.95,104.97 139.67,105.25 139.05,105.25 138.77,104.97 138.77,103.7 138.64,103.57 138.25,103.57 138.12,103.7 138.12,104.97 137.83,105.25 134.55,105.25 116.39,123.42 116.39,129.7 117.53,130.84
MEM_MB_DQS7_P: length 98.1
  TOP w0.099: 117.34,131.03 117.35,131.04 117.4,131.04 117.62,131.27 117.62,134.69 117.48,134.83 117.29,134.83 117.19,134.73 U6.AK13
  TOP w0.13: 117.34,131.03 116.11,129.81 116.11,123.31 134.44,104.98 137.72,104.98 137.85,104.85 137.85,103.59 138.14,103.3 138.75,103.3 139.04,103.59 139.04,104.85 139.17,104.98 139.55,104.98 139.68,104.85 139.68,103.59 139.97,103.3 140.58,103.3 140.87,103.59 140.87,104.85 141,104.98 141.39,104.98 141.52,104.85 141.52,104.41 141.83,104.1 142.39,104.1 142.7,104.41 142.7,104.85 142.83,104.98 160.68,104.98 168.46,97.19 168.46,96.97 169.52,95.92 170.3,95.92 171.36,96.97 172.25,96.97 173.23,97.95 173.91,97.95 174.85,97.01 176.8,97.01 177.68,97.89 179.54,97.89 179.73,97.7 179.73,97.29 179.54,97.1 J2.112
MEM_MB_DQS8_N: length 52.8
  TOP w0.13: J2.42 179.34,171.11 179.54,170.9 179.54,170.64 179.29,170.39 177.27,170.39 176.4,171.25 175.11,171.25 174.12,170.26 173.23,170.26 172.19,169.22 171.36,169.22 171.34,169.22 170.48,168.35 159.33,168.35 159.04,168.06 159.04,167.71 158.91,167.58 158.65,167.58 158.52,167.71 158.52,168.06 158.23,168.35 157.75,168.35 157.46,168.06 157.46,167.71 157.33,167.58 157.07,167.58 156.94,167.71 156.94,168.06 156.65,168.35 156.17,168.35 155.88,168.06 155.88,167.71 155.75,167.58 155.49,167.58 155.36,167.71 155.36,168.06 155.07,168.35 154.59,168.35 154.3,168.06 154.3,167.71 154.17,167.58 153.91,167.58 153.78,167.71 153.78,168.06 153.49,168.35 153.01,168.35 152.72,168.06 152.72,167.71 152.59,167.58 152.33,167.58 152.2,167.71 152.2,168.06 151.91,168.35 151.43,168.35 151.14,168.06 151.14,167.71 151.01,167.58 150.75,167.58 150.62,167.71 150.62,168.06 150.33,168.35 149.38,168.35 145.12,164.09 145.12,164.08 143.57,162.53 141.79,162.53 140.69,161.44 139.69,161.44 139.22,160.97 U6.J30
MEM_MB_DQS8_P: length 51.8
  TOP w0.13: J2.43 180.47,170.45 179.74,170.45 179.4,170.12 177.15,170.12 176.29,170.98 175.22,170.98 174.23,169.99 173.34,169.99 172.3,168.95 171.46,168.95 170.59,168.08 159.44,168.08 159.31,167.95 159.31,167.6 159.02,167.31 158.54,167.31 158.25,167.6 158.25,167.95 158.12,168.08 157.86,168.08 157.73,167.95 157.73,167.6 157.44,167.31 156.96,167.31 156.67,167.6 156.67,167.95 156.54,168.08 156.28,168.08 156.15,167.95 156.15,167.6 155.86,167.31 155.38,167.31 155.09,167.6 155.09,167.95 154.96,168.08 154.7,168.08 154.57,167.95 154.57,167.6 154.28,167.31 153.8,167.31 153.51,167.6 153.51,167.95 153.38,168.08 153.12,168.08 152.99,167.95 152.99,167.6 152.7,167.31 152.22,167.31 151.93,167.6 151.93,167.95 151.8,168.08 151.54,168.08 151.41,167.95 151.41,167.6 151.12,167.31 150.64,167.31 150.35,167.6 150.35,167.95 150.22,168.08 149.49,168.08 145.39,163.98 145.39,163.97 143.68,162.26 141.93,162.26 140.83,161.16 140.81,161.16 140.61,160.97 U6.J31
MEM_MB_EVENT_L: length 64
  TOP w0.102: U6.V29 137.92,149.54 138.45,150.07 140.37,150.07 140.74,149.69 153,149.69 154.97,147.72 156.12,147.72 R145.1 157.16,148.77 157.16,149.71 157.73,150.28 168.28,150.28 169.19,149.36 169.19,148.69 169.51,148.37 170.81,148.37 171.27,148.84 172.32,148.84 173.39,149.9 174.22,149.9 175.25,148.87 176.12,148.87 177.03,147.96 179.21,147.96 180.24,146.92 181.22,146.92 182.13,147.83 183.34,147.83 183.84,147.32 185.05,147.32 185.56,146.81 185.56,143.06 J2.187 185.7,141.02 R151.2 187.23,141.02 187.59,140.66 Q8.E
MEM_MB_RAS_N: length 51.7
  TOP w0.099: 168.9,139.89 170.26,139.89 171.28,138.87 172.56,138.87 173.07,138.36 174.29,138.36 174.76,138.84 176.04,138.84 177.04,137.84 179.64,137.84 180.19,137.29 182.53,137.29 J2.192
  TOP w0.102: U6.AB29 137.95,144.89 139.04,144.89 139.3,144.63 139.3,144.11 139.71,143.7 140.39,143.7 140.6,143.49 142.22,143.49
  TOP w0.229: 168.9,139.89 164.82,143.97 161.58,143.97 160.15,142.54 157.59,142.54 156.77,141.72 152.98,141.72 150.52,144.18 143.67,144.18 142.98,143.49 142.22,143.49
MEM_MB_RESET_N: length 75.6
  TOP w0.125: v3(138.07,157.78) 138.82,157.78 139.27,158.23 139.57,158.23 139.95,157.85 140.22,157.85 140.5,158.14 141.46,158.14 143.53,160.21 163.01,160.21 164.67,161.87 169.79,161.87 171.52,163.61 181.21,163.61 J2.168 ; U6.B19 124.81,169.89 124.36,170.34 v3(124.29,170.34)
  BOTTOM w0.125: v3(138.07,157.78) 137.63,157.34 136.68,157.34 136.45,157.57 135.23,157.57 134.55,158.25 134.1,158.25 133.76,157.92 133.76,157.51 133.46,157.21 132.59,157.21 132.34,157.46 132.34,159.29 132.67,159.62 132.67,161.17 132.52,161.33 132.52,162.9 131.63,163.79 130.95,163.79 130.82,163.66 128.81,163.66 128.16,164.32 127.34,164.32 126.73,164.93 125.2,164.93 124.85,165.29 124.85,165.52 124.41,165.95 124.41,167.57 124.52,167.68 124.52,170.2 124.37,170.34 v3(124.29,170.34)
MEM_MB_WE_N: length 52.2
  TOP w0.099: 169.02,138.11 170.36,138.11 171.38,137.09 172.36,137.09 173.1,137.83 174.17,137.83 174.91,137.09 177.4,137.09 177.6,136.9 177.6,136.54 177.83,136.32 178.18,136.32 178.39,136.11 J2.73
  TOP w0.102: U6.AC30 139.22,142.76 141.69,142.76 141.94,142.51
  TOP w0.229: 169.02,138.11 166.71,140.42 164.65,140.42 164.42,140.65 164.42,142.49 164.2,142.72 162.19,142.72 161.68,142.21 161.68,140.65 161.45,140.42 160.99,140.42 160.77,140.65 160.77,140.97 160.54,141.19 160.08,141.19 159.85,140.97 159.85,140.65 159.62,140.42 159.17,140.42 158.94,140.65 158.94,140.97 158.71,141.19 158.25,141.19 158.02,140.97 158.02,140.65 157.79,140.42 152.45,140.42 149.79,143.08 144.15,143.08 143.58,142.51 141.94,142.51
MEMA_VREFCA_SUS: length 24.7
  TOP w0.381: v2(181.44,143.08) 181.43,143.09 180.6,143.09 179.46,142.24 178.45,142.24 176.16,143.07 175.59,143.07 173.94,144.02 173.37,144.02 172.76,143.41 J1.67 ; v2(186.3,143.56) C117.1 C108.1 187.51,144.86 188.35,144.02 R146.1 R167.2 191.23,144.01 C116.2 v1(191.27,142.68)
  BOTTOM w0.381: v2(186.3,143.56) 184.48,143.07 183.08,142.24 182.28,142.24 v2(181.44,143.08)
MEMA_VREFDQ_SUS: length 14.5
  TOP w0.254: 165.49,215.72 165.49,213.23 v1(165.43,213.17)
  TOP w0.381: 165.56,215.78 R68.1 164.03,215.78 163.82,215.57 C55.1 C54.1 ; 165.56,215.78 R44.2 166.99,215.78 167.21,215.57 C34.2 169.79,215.57 171.81,213.55 J1.1 ; 165.56,215.78 165.49,215.72
MEMB_VREFCA_SUS: length 17.8
  TOP w0.381: J2.67 180.94,142.24 183.17,142.24 184.03,141.38 184.03,140.74 183.75,140.46 183.75,139.67 184.36,139.07 185.06,139.07 185.64,138.5 185.64,136.89 186.05,136.48 C114.1 ; C125.1 C114.1 ; C114.1 187.57,136.48 188.17,135.88 R157.1 R179.2 190.04,135.71 C124.2 v1(191.15,134.75)
MEMB_VREFDQ_SUS: length 23
  TOP w0.254: 165.49,217.29 v1(165.49,219.71)
  TOP w0.381: J2.1 177.29,215.62 171.31,215.62 169.55,217.38 C51.2 166.87,217.38 166.78,217.29 R55.2 R38.1 163.5,217.29 C30.1 C29.1
MIC1-VREFO: length 4.9
  TOP w0.254: Q34.K 18.74,48.93 18.93,48.74 v2(19.59,48.74) 19.92,48.74 v1(20.28,48.39)
  BOTTOM w0.254: U23.28 20.48,49.17 20.05,48.74 v2(19.59,48.74)
MIC1_JD: length 25.9
  TOP w0.254: v2(26.58,39.03) 25.91,38.35 24.01,38.35 23.2,39.17 16.02,39.17 15.19,39.99 15.19,42.2 11.49,45.9 CN21.5
  BOTTOM w0.254: v2(26.58,39.03) 26.74,39.19 v1(26.74,40.2) 26.74,43.32 R702.2
MIC1_L: length 8.8
  TOP w0.254: v2(24.17,47.22) 24.16,47.22 20.56,47.22 v2(20.33,46.99)
  BOTTOM w0.254: C506.1 18.25,47.22 19.11,46.35 v1(19.12,46.35) 19.19,46.35 19.82,46.99 v2(20.33,46.99) ; v2(24.17,47.22) 24.54,46.84 U23.21
MIC1_L_FIL: length 12.4
  BOTTOM w0.254: CN21.2 6.7,52.24 8.52,50.42 11.06,50.42 11.25,50.23 D15.2 12.84,50.36 C499.1 L63.2 14.92,51.77 v1(15,51.69)
MIC1_R: length 9.5
  TOP w0.254: v2(25.16,44.32) 25.16,43.81 23.38,42.04 v2(23,42.04)
  BOTTOM w0.254: U23.22 24.04,45.18 24.9,44.32 v2(25.16,44.32) ; v1(23,43.03) v2(23,42.04) 22.89,42.14 C502.1
MIC1_R_FIL: length 6.9
  BOTTOM w0.254: v1(15.12,46.74) 14.95,46.91 L65.2 C504.1 12.84,47.49 12.7,47.62 D15.1 11.63,48.33 11.16,48.8 CN21.3
MIC_CLK: length 63.8
  TOP w0.102: R515.1 42.58,10.31 42.02,10.31 41.54,10.79 41.54,11.68 40.65,12.57 34.1,12.57 33.69,12.98 33.69,17.19 31.17,19.71 30.08,19.71 v3(29.47,20.32)
  BOTTOM w0.102: U23.46 27.54,54.01 27.44,53.91 27.44,53.47 27.82,53.09 28.59,53.09 29.98,54.48 31,54.48 32.3,53.18 32.3,49.19 32.95,48.54 32.95,44.91 30.8,42.75 30.8,34.42 28.87,32.49 28.87,24.28 28.67,24.08 28.67,23.59 28.95,23.3 28.95,21.48 v1(29.35,21.08) 29.47,20.95 v3(29.47,20.32)
MIC_CLK_R: length 5.3
  TOP w0.102: R515.2 43.37,8.66 45.05,8.66 v1(46.04,7.67) 46.06,7.65 CN25.1
MIC_DAT: length 58.3
  TOP w0.102: v3(28.71,20.32) 29.54,19.49 31.08,19.49 33.44,17.13 33.44,12.9 34.15,12.19 40.65,12.19 41.29,11.56 41.29,10.59 R514.1
  BOTTOM w0.102: v3(28.71,20.32) 28.71,20.7 28.2,21.21 v1(28.2,22.67) 28.33,22.8 28.33,24.09 28.65,24.41 28.65,32.6 30.59,34.54 30.59,42.85 32.73,44.98 32.73,48.46 32.07,49.12 32.07,52.97 31.82,53.21 31.32,53.21 31,52.9 31,52.77 30.9,52.67 U23.2
MIC_DAT_R: length 5
  TOP w0.102: CN25.2 45.06,7.09 v1(44.14,8) 44.02,8.13 42.89,8.13 R514.2
MXM_BLEN: length 435
  TOP w0.102: D12.A2 179.15,65.57 178.77,65.95 176.76,65.95 174.31,68.4 162.62,68.4 162.04,68.99 162.04,72.75 162.34,73.05 163.92,73.05 164.22,73.36 164.22,74.27 163.76,74.73 162.09,74.73 161.55,75.26 161.55,78.11 144.19,95.48 121.19,95.48 120.18,94.46 105.59,94.46 103.51,96.55 89.19,96.55 86.8,98.93 71.7,98.93 70.25,97.49 69.18,97.49 68.49,96.8 68.49,95.12 67.7,94.34 67.7,88.49 68.77,87.43 v2(68.77,87) ; R32.1 83.67,226.35 83.35,226.67 83.35,227.43 83.86,227.94 85.23,227.94 86.4,229.11 86.4,234.72 84.8,236.32 78.8,236.32 74.38,231.9 17.99,231.9 4.07,217.98 4.07,183.78 5.03,182.81 5.03,179.18 10.26,173.95 10.26,163.39 9.22,162.35 9.22,159.09 10.05,158.26 10.05,154.28 9.53,153.76 9.53,151.34 10.22,150.65 10.22,149.02 7.68,146.48 7.68,117.63 21.27,104.04 21.27,94.26 22.24,93.29 28.07,93.29 33.35,88.01 34.3,88.01 35.19,88.9 39.51,88.9 40.21,89.61 41.93,89.61 42.4,89.13 44.2,89.13 45.72,90.65 48.6,90.65 49.82,89.43 50.91,89.43 52.82,87.53 v2(54.2,87.53)
  BOTTOM w0.102: v2(54.2,87.53) 57.72,87.53 57.82,87.63 61.54,87.63 v1(61.99,87.19) 62.25,86.92 62.93,86.92 62.95,86.89 68.67,86.89 v2(68.77,87)
MXM_CLKREQ_N: length 10.7
  TOP w0.13: CN1.154 51.75,212.59 51.33,212.17 51.33,211.15 51.18,211 R60.1 49.81,209.95 R59.1 49.83,209.98 50.48,209.34 50.48,206.55 v1(50.18,206.25)
MXM_DDPC_CTRLCLK: length 72
  TOP w0.102: R36.2 32.06,223.84 32.44,223.46 33.9,223.46 34,223.36 CN1.225 34,220.78 33.26,220.04 31.15,220.04 31.01,219.9 v2(28.51,219.9) ; CN9.13 19.91,170.73 19.44,171.2 v2(18.3,171.2)
  BOTTOM w0.102: v2(18.3,171.2) 17.79,171.2 16.52,172.47 16.52,176.31 15.55,177.29 15.55,203.01 16.14,203.61 16.14,205.31 19.82,208.99 24.34,208.99 27.17,211.82 27.17,214.68 27.82,215.33 v1(27.82,216.6) 27.82,218.34 28.51,219.02 v2(28.51,219.9)
MXM_DDPC_CTRLDATA: length 71.9
  TOP w0.102: v2(29.14,219.27) 30.95,219.27 31.22,219.53 33.49,219.53 34.5,220.54 CN1.223 34.5,223.56 34.35,223.71 33.46,223.71 33.2,223.96 R37.2 ; CN9.14 19.64,169.73 19.09,170.28 v2(19.09,170.69)
  BOTTOM w0.102: v2(29.14,219.27) 28.81,218.94 28.81,218.39 v1(28.82,218.38) 28.81,218.36 28.81,213.15 24.42,208.76 19.95,208.76 16.34,205.16 16.34,203.48 15.78,202.91 15.78,187.54 15.79,187.53 15.79,177.37 16.77,176.38 16.77,172.72 17.66,171.83 18.68,171.83 19.09,171.42 v2(19.09,170.69)
MXM_DDSP_CLK_DN: length 63.7
  TOP w0.099: v2(36.39,225.3) 35.88,224.79 35.88,223.34 36,223.22 CN1.217 ; v2(19.18,181.63) 19.27,181.73 CN9.2
  BOTTOM w0.099: v2(19.18,181.63) 19.18,181.9 19.04,182.04 18.63,182.04 18.22,182.45 18.22,201.37 19.14,202.29 19.14,204.19 21,206.06 28.85,206.06 33.33,210.54 33.33,224.79 34.86,226.31 35.57,226.31 35.88,226.01 35.88,225.81 v2(36.39,225.3)
MXM_DDSP_CLK_DP: length 63.1
  TOP w0.099: v2(35.12,225.3) 35.5,225.3 35.62,225.17 35.62,223.34 35.5,223.22 CN1.219 ; v2(19.18,182.9) 19.35,182.73 CN9.1
  BOTTOM w0.099: v2(35.12,225.3) 35.5,225.3 35.62,225.43 35.62,225.91 35.47,226.06 34.96,226.06 33.59,224.68 33.59,210.44 30.11,206.96 30.11,206.96 28.95,205.8 21.11,205.8 19.39,204.09 19.39,202.18 18.48,201.27 18.48,182.55 18.73,182.3 19.07,182.3 19.18,182.4 v2(19.18,182.9)
MXM_DDSP_TX0_DN: length 70.2
  TOP w0.099: v5(37.89,224.33) 37.38,223.82 37.38,223.34 37.5,223.22 CN1.211 ; CN9.5 19.24,178.73 v2(19.15,178.63)
  BOTTOM w0.099: v5(37.89,224.33) 37.38,224.83 37.38,226.69 37,227.08 34.69,227.08 32.6,224.98 32.6,211.2 28.34,206.95 20.95,206.95 18.27,204.27 18.27,202.82 17.54,202.09 17.54,179.68 18.15,179.07 18.71,179.07 v2(19.15,178.63)
MXM_DDSP_TX0_DP: length 69.9
  TOP w0.099: v2(19.15,179.9) 19.33,179.73 CN9.4 ; v2(36.62,224.33) 36.82,224.33 37.12,224.02 37.12,223.34 37,223.22 CN1.213
  BOTTOM w0.099: v2(36.62,224.33) 36.96,224.33 37.12,224.49 37.12,226.59 36.89,226.82 34.79,226.82 32.85,224.88 32.85,211.1 28.45,206.69 21.05,206.69 18.53,204.17 18.53,202.72 17.79,201.98 17.79,179.79 18.25,179.32 19.25,179.32 19.39,179.47 19.39,179.7 19.19,179.9 v2(19.15,179.9)
MXM_DDSP_TX1_DN: length 75.6
  TOP w0.099: v2(19.15,175.63) 19.24,175.73 CN9.8 ; CN1.205 39,223.22 38.88,223.34 38.88,224.79 v2(39.39,225.3)
  BOTTOM w0.099: v2(19.15,175.63) 18.84,175.95 18.63,175.95 18.55,176.02 18.17,176.4 18.17,177.69 16.88,178.99 16.88,202.42 17.54,203.08 17.54,204.58 20.63,207.67 27.34,207.67 31.86,212.19 31.86,225.26 34.43,227.84 37.4,227.84 38.88,226.35 38.88,225.81 v2(39.39,225.3)
MXM_DDSP_TX1_DP: length 75.2
  TOP w0.099: v2(19.15,176.9) 19.33,176.73 CN9.7 ; v2(38.12,225.3) 38.4,225.3 38.63,225.07 38.63,223.34 38.5,223.22 CN1.207
  BOTTOM w0.099: v2(38.12,225.3) 38.42,225.3 38.63,225.5 38.63,226.25 37.29,227.58 34.54,227.58 32.11,225.16 32.11,212.09 27.44,207.42 20.74,207.42 17.79,204.47 17.79,202.97 17.13,202.31 17.13,179.1 18.43,177.8 18.43,176.51 18.73,176.2 18.95,176.2 19.15,176.41 v2(19.15,176.9)
MXM_DDSP_TX2_DN: length 81.5
  TOP w0.099: v2(40.89,224.25) 40.38,223.74 40.38,223.34 40.5,223.22 CN1.199 ; CN9.11 19.17,172.73 v2(19.07,172.63)
  BOTTOM w0.099: v2(40.89,224.25) 40.38,224.76 40.38,227.52 39.24,228.66 34.32,228.66 31.1,225.44 31.1,219.68 30.11,218.69 30.11,213.8 24.67,208.36 20.35,208.36 16.77,204.78 16.77,203.28 16.19,202.7 16.19,177.64 17.28,176.55 17.28,173.86 18,173.14 18.57,173.14 v2(19.07,172.63)
MXM_DDSP_TX2_DP: length 80.8
  TOP w0.099: v2(19.07,173.9) 19.25,173.73 CN9.10 ; v2(39.62,224.25) 39.95,224.25 40.12,224.08 40.12,223.34 40,223.22 CN1.201
  BOTTOM w0.099: v2(39.62,224.25) 39.92,224.25 40.12,224.45 40.12,227.42 39.13,228.41 34.42,228.41 31.35,225.34 31.35,219.57 30.36,218.58 30.36,213.69 24.78,208.1 20.46,208.1 17.03,204.67 17.03,203.17 16.44,202.59 16.44,177.75 17.54,176.66 17.54,173.97 18.11,173.4 18.91,173.4 19.11,173.6 19.11,173.87 v2(19.07,173.9)
MXM_DDSPC_HPD: length 7.9
  TOP w0.102: CN1.234 31.75,213.65 29.75,211.66 28.34,211.66 27.76,211.07 v1(27.19,211.07) 27.16,211.04 R57.1
MXM_LVDS_DDC_CLK: length 20.5
  TOP w0.102: CN1.35 81.5,223.23 81.21,223.52 78.69,223.52 78.05,224.16 v1(76.53,224.16) 76.53,229.24 77.07,229.78 Q1.S 78.18,230.06 77.48,230.76 77.48,231.65 77.84,232 80.86,232 R28.2 R19.2
MXM_LVDS_DDC_DATA: length 19.3
  TOP w0.102: R23.2 82.72,232.36 R26.1 81.97,231.95 81.67,231.65 81.67,230.76 81.48,230.57 Q2.S 81.48,228.92 81.16,228.6 77.35,228.6 77.04,228.28 77.04,226.25 v1(78.18,225.11) 78.18,224.72 79.13,223.77 81.41,223.77 82,223.17 CN1.33
MXM_LVDS_L_CLK_DN: length 44.4
  TOP w0.099: CN8.20 27.27,193.09 v2(27.53,192.83) ; v2(48.39,217.73) 48.14,217.47 48.14,217.12 47.81,216.79 46.41,216.79 46.13,216.51 46.13,216.02 46.25,215.9 CN1.176
  BOTTOM w0.099: v2(48.39,217.73) 48.1,217.44 48.1,215.2 46.97,214.07 46.62,214.07 45.37,215.32 45.17,215.32 45.02,215.17 45.02,214.97 46.12,213.87 46.27,213.72 46.27,213.37 42.58,209.67 42.58,206.7 37.09,201.22 37.02,201.14 29.19,193.32 28.02,193.32 v2(27.53,192.83)
MXM_LVDS_L_CLK_DP: length 44
  TOP w0.099: CN8.21 27.52,194.09 v2(27.53,194.1) ; v2(47.6,217.78) 47.88,217.5 47.88,217.22 47.7,217.04 46.31,217.04 45.88,216.61 45.88,215.98 45.75,215.85 CN1.178
  BOTTOM w0.099: v2(47.6,217.78) 47.85,217.53 47.85,215.3 46.87,214.32 46.73,214.32 45.48,215.57 45.06,215.57 44.77,215.28 44.77,214.86 45.94,213.69 46.02,213.61 46.02,213.47 42.32,209.78 42.32,206.81 36.92,201.4 36.91,201.4 29.09,193.57 28.06,193.57 v2(27.53,194.1)
MXM_LVDS_L_TX0_DN: length 45.4
  TOP w0.099: CN1.200 40.25,213.67 40.13,213.55 40.13,213.05 39.5,212.42 39.3,212.42 39.14,212.26 39.14,212.12 v2(39.45,211.81) ; CN8.12 21.26,192.09 21.42,191.92 21.95,191.92 v2(22.43,192.4)
  BOTTOM w0.099: v2(39.45,211.81) 39.14,211.51 39.14,210.62 39.83,209.93 39.83,208.78 30.29,199.24 25.06,199.24 23.33,197.51 23.33,190.63 22.51,189.81 20.58,189.81 19.98,190.42 19.98,191.72 20.43,192.18 22.2,192.18 v2(22.43,192.4)
MXM_LVDS_L_TX0_DP: length 44.8
  TOP w0.099: CN1.202 39.75,213.67 39.87,213.55 39.87,213.15 39.39,212.67 39.2,212.67 38.89,212.37 38.89,212.04 v2(38.61,211.76) ; CN8.13 20.84,191.09 21.42,191.67 21.89,191.67 v2(22.43,191.13)
  BOTTOM w0.099: v2(38.61,211.76) 38.89,211.48 38.89,210.52 39.58,209.83 39.58,208.89 37.83,207.14 33.89,203.2 30.18,199.49 24.95,199.49 23.07,197.62 23.07,190.73 22.41,190.07 20.69,190.07 20.23,190.53 20.23,191.62 20.53,191.92 22.11,191.92 22.43,191.6 v2(22.43,191.13)
MXM_LVDS_L_TX1_DN: length 45.1
  TOP w0.099: CN1.194 41.75,213.74 41.63,213.62 41.63,213.02 41.38,212.78 41.38,212.09 v2(41.56,211.91) ; CN8.15 22.75,189.09 v2(22.78,189.11)
  BOTTOM w0.099: v2(22.78,189.11) 23.12,189.46 23.12,189.61 23.79,190.27 23.79,193.57 24.14,193.93 25.05,193.93 25.16,194.03 25.16,194.46 25.05,194.56 24.04,194.56 23.79,194.82 23.79,195.45 24.04,195.71 24.67,195.71 24.78,195.81 24.78,196.09 24.61,196.25 24.23,196.25 23.89,196.6 23.89,197.46 24.59,198.16 25.26,198.83 30.47,198.83 40.29,208.66 40.29,210.48 39.98,210.79 39.98,212.53 40.23,212.78 41.02,212.78 41.33,212.47 41.33,212.14 v2(41.56,211.91)
MXM_LVDS_L_TX1_DP: length 44.6
  TOP w0.099: v2(40.77,211.96) 40.9,211.96 41.03,212.09 41.03,212.13 41.13,212.23 41.13,212.88 41.37,213.13 41.37,213.55 41.25,213.67 CN1.196 ; CN8.16 23.65,189.09 v2(23.62,189.11)
  BOTTOM w0.099: v2(40.77,211.96) 40.95,211.96 41.08,212.09 41.08,212.37 40.92,212.52 40.34,212.52 40.24,212.42 40.24,210.9 40.55,210.59 40.55,208.55 39.13,207.14 36.91,204.91 35.19,203.2 30.57,198.58 25.36,198.58 24.7,197.91 24.14,197.35 24.14,196.7 24.34,196.5 24.72,196.5 25.03,196.19 25.03,195.71 24.78,195.45 24.14,195.45 24.04,195.35 24.04,194.92 24.14,194.82 25.16,194.82 25.41,194.56 25.41,193.93 25.16,193.68 24.25,193.68 24.04,193.47 24.04,190.17 23.38,189.51 23.38,189.23 23.5,189.11 v2(23.62,189.11)
MXM_LVDS_L_TX2_DN: length 45.5
  TOP w0.099: CN8.18 24.9,191.09 v2(24.74,190.93) ; v2(42.88,212.52) 42.65,212.75 42.65,212.83 43.25,213.42 CN1.188
  BOTTOM w0.099: v2(24.74,190.93) 25.07,191.26 25.41,191.26 25.54,191.14 25.54,188.09 25.88,187.74 26.46,187.74 26.81,188.09 26.81,192.51 26.17,193.15 26.17,193.7 26.81,194.33 26.81,195.76 25.36,197.21 25.36,197.64 25.6,197.88 30.83,197.88 41.23,208.28 41.23,210.47 42.4,211.63 42.4,212.04 v2(42.88,212.52)
MXM_LVDS_L_TX2_DP: length 45.1
  TOP w0.099: v2(24.74,192.2) 24.85,192.09 CN8.19 ; v2(42.14,212.54) 42.4,212.8 42.4,212.93 42.75,213.28 CN1.190
  BOTTOM w0.099: v2(24.74,192.2) 24.74,191.91 25.13,191.52 25.52,191.52 25.79,191.24 25.79,188.19 25.99,187.99 26.36,187.99 26.55,188.19 26.55,192.41 25.92,193.04 25.92,193.8 26.55,194.44 26.55,195.65 25.11,197.1 25.11,197.74 25.5,198.13 30.73,198.13 40.98,208.38 40.98,210.57 42.14,211.74 v2(42.14,212.54)
MXM_LVDS_L_TX3_DN: length 43.5
  TOP w0.099: CN1.182 44.75,213.76 44.35,213.36 44.35,213.2 v2(44.58,212.98) ; v2(27.35,194.88) 27.14,195.09 CN8.22
  BOTTOM w0.099: v2(44.58,212.98) 44.28,212.68 44.28,212.37 41.92,210.01 41.92,207.01 40.52,205.61 39.97,205.61 39.58,205.23 39.58,204.67 39.07,204.16 38.87,203.96 38.49,203.96 38.26,204.19 38.09,204.19 37.83,203.93 37.83,203.78 38.05,203.57 38.05,203.16 37.7,202.82 37.37,202.82 37.16,203.02 37.03,203.02 36.76,202.76 36.76,202.62 36.97,202.42 36.97,202.03 36.51,201.57 36.13,201.57 35.91,201.79 35.77,201.79 35.56,201.58 35.56,201.44 35.8,201.2 35.8,200.89 35.42,200.51 35.07,200.51 34.85,200.73 34.71,200.73 34.5,200.52 34.5,200.38 34.72,200.16 34.72,199.81 34.48,199.57 34.03,199.57 33.79,199.33 33.79,198.88 33.44,198.53 33.09,198.53 32.83,198.79 32.69,198.79 32.48,198.58 32.48,198.44 32.74,198.18 32.74,197.83 32.38,197.47 32.03,197.47 31.77,197.73 31.63,197.73 31.42,197.52 31.42,197.38 31.68,197.12 31.68,196.77 31.32,196.41 30.97,196.41 30.18,197.2 29.98,197.2 29.83,197.05 29.83,196.85 30.62,196.06 30.62,195.71 30.26,195.35 29.91,195.35 28.9,196.37 28.72,196.37 28.51,196.16 28.51,196.05 29.56,195 29.56,194.65 29.17,194.26 28.81,194.26 27.64,195.43 27.42,195.43 27.35,195.36 v2(27.35,194.88)
MXM_LVDS_L_TX3_DP: length 42.9
  TOP w0.099: v2(27.35,196.15) 27.29,196.09 CN8.23 ; v2(43.82,212.95) 44.1,213.23 44.1,213.47 44.35,213.72 44.35,213.84 44.25,213.94 CN1.184
  BOTTOM w0.099: v2(27.35,196.15) 27.35,195.73 27.4,195.68 27.75,195.68 28.92,194.51 29.06,194.51 29.31,194.76 29.31,194.9 28.26,195.95 28.26,196.27 28.61,196.62 29,196.62 30.02,195.61 30.16,195.61 30.37,195.82 30.37,195.96 29.58,196.74 29.58,197.16 29.87,197.45 30.29,197.45 31.08,196.67 31.22,196.67 31.43,196.88 31.43,197.02 31.17,197.28 31.17,197.63 31.53,197.99 31.88,197.99 32.14,197.73 32.28,197.73 32.49,197.94 32.49,198.08 32.23,198.34 32.23,198.69 32.59,199.05 32.94,199.05 33.2,198.79 33.34,198.79 33.54,198.99 33.54,199.44 33.92,199.82 34.37,199.82 34.47,199.92 34.47,200.06 34.24,200.28 34.24,200.63 34.6,200.99 34.95,200.99 35.18,200.77 35.32,200.77 35.55,200.99 35.55,201.1 35.3,201.34 35.3,201.69 35.66,202.05 36.01,202.05 36.24,201.83 36.41,201.83 36.71,202.13 36.71,202.31 36.51,202.52 36.51,202.87 36.92,203.28 37.27,203.28 37.48,203.07 37.6,203.07 37.79,203.27 37.79,203.46 37.58,203.68 37.58,204.04 37.98,204.44 38.37,204.44 38.6,204.22 38.77,204.22 38.89,204.34 39.33,204.78 39.33,205.33 39.86,205.87 40.42,205.87 41.66,207.11 41.66,210.11 44.02,212.47 44.02,212.6 43.82,212.8 v2(43.82,212.95)
MXM_LVDS_PWM: length 405.6
  TOP w0.102: R31.1 82.65,225.88 83.13,226.36 83.13,227.78 83.73,228.37 85.05,228.37 85.91,229.24 85.91,234.01 84.21,235.71 79.09,235.71 74.57,231.19 18.16,231.19 4.5,217.53 4.5,183.73 5.65,182.58 5.65,179.34 10.81,174.18 10.81,163.04 9.82,162.05 9.82,158.81 10.61,158.01 10.61,154.54 10.04,153.97 10.04,151.59 10.76,150.88 10.76,148.64 8.14,146.02 8.14,117.88 21.73,104.29 21.73,94.74 22.49,93.98 28.18,93.98 31.2,90.96 31.2,90.54 32.62,89.12 39.22,89.12 40.04,89.94 41.9,89.94 42.4,89.43 43.68,89.43 45.33,91.08 48.83,91.08 50.13,89.79 51.75,89.79 52.72,88.82 v2(53.96,88.82) ; v2(68.11,87.38) 67.38,88.1 67.38,96.65 69.49,98.76 70.57,98.76 71.36,99.54 87.05,99.54 89.44,97.16 103.87,97.16 105.75,95.28 119.7,95.28 120.76,96.34 144.77,96.34 159.83,81.28 160.64,81.28 164.09,77.83 164.09,75.96 163.76,75.63 D11.A2
  BOTTOM w0.102: v2(53.96,88.82) 54.32,88.82 v1(54.75,88.39) 55.26,87.88 56.2,87.88 56.53,88.21 61.99,88.21 62.83,87.38 v2(68.11,87.38)
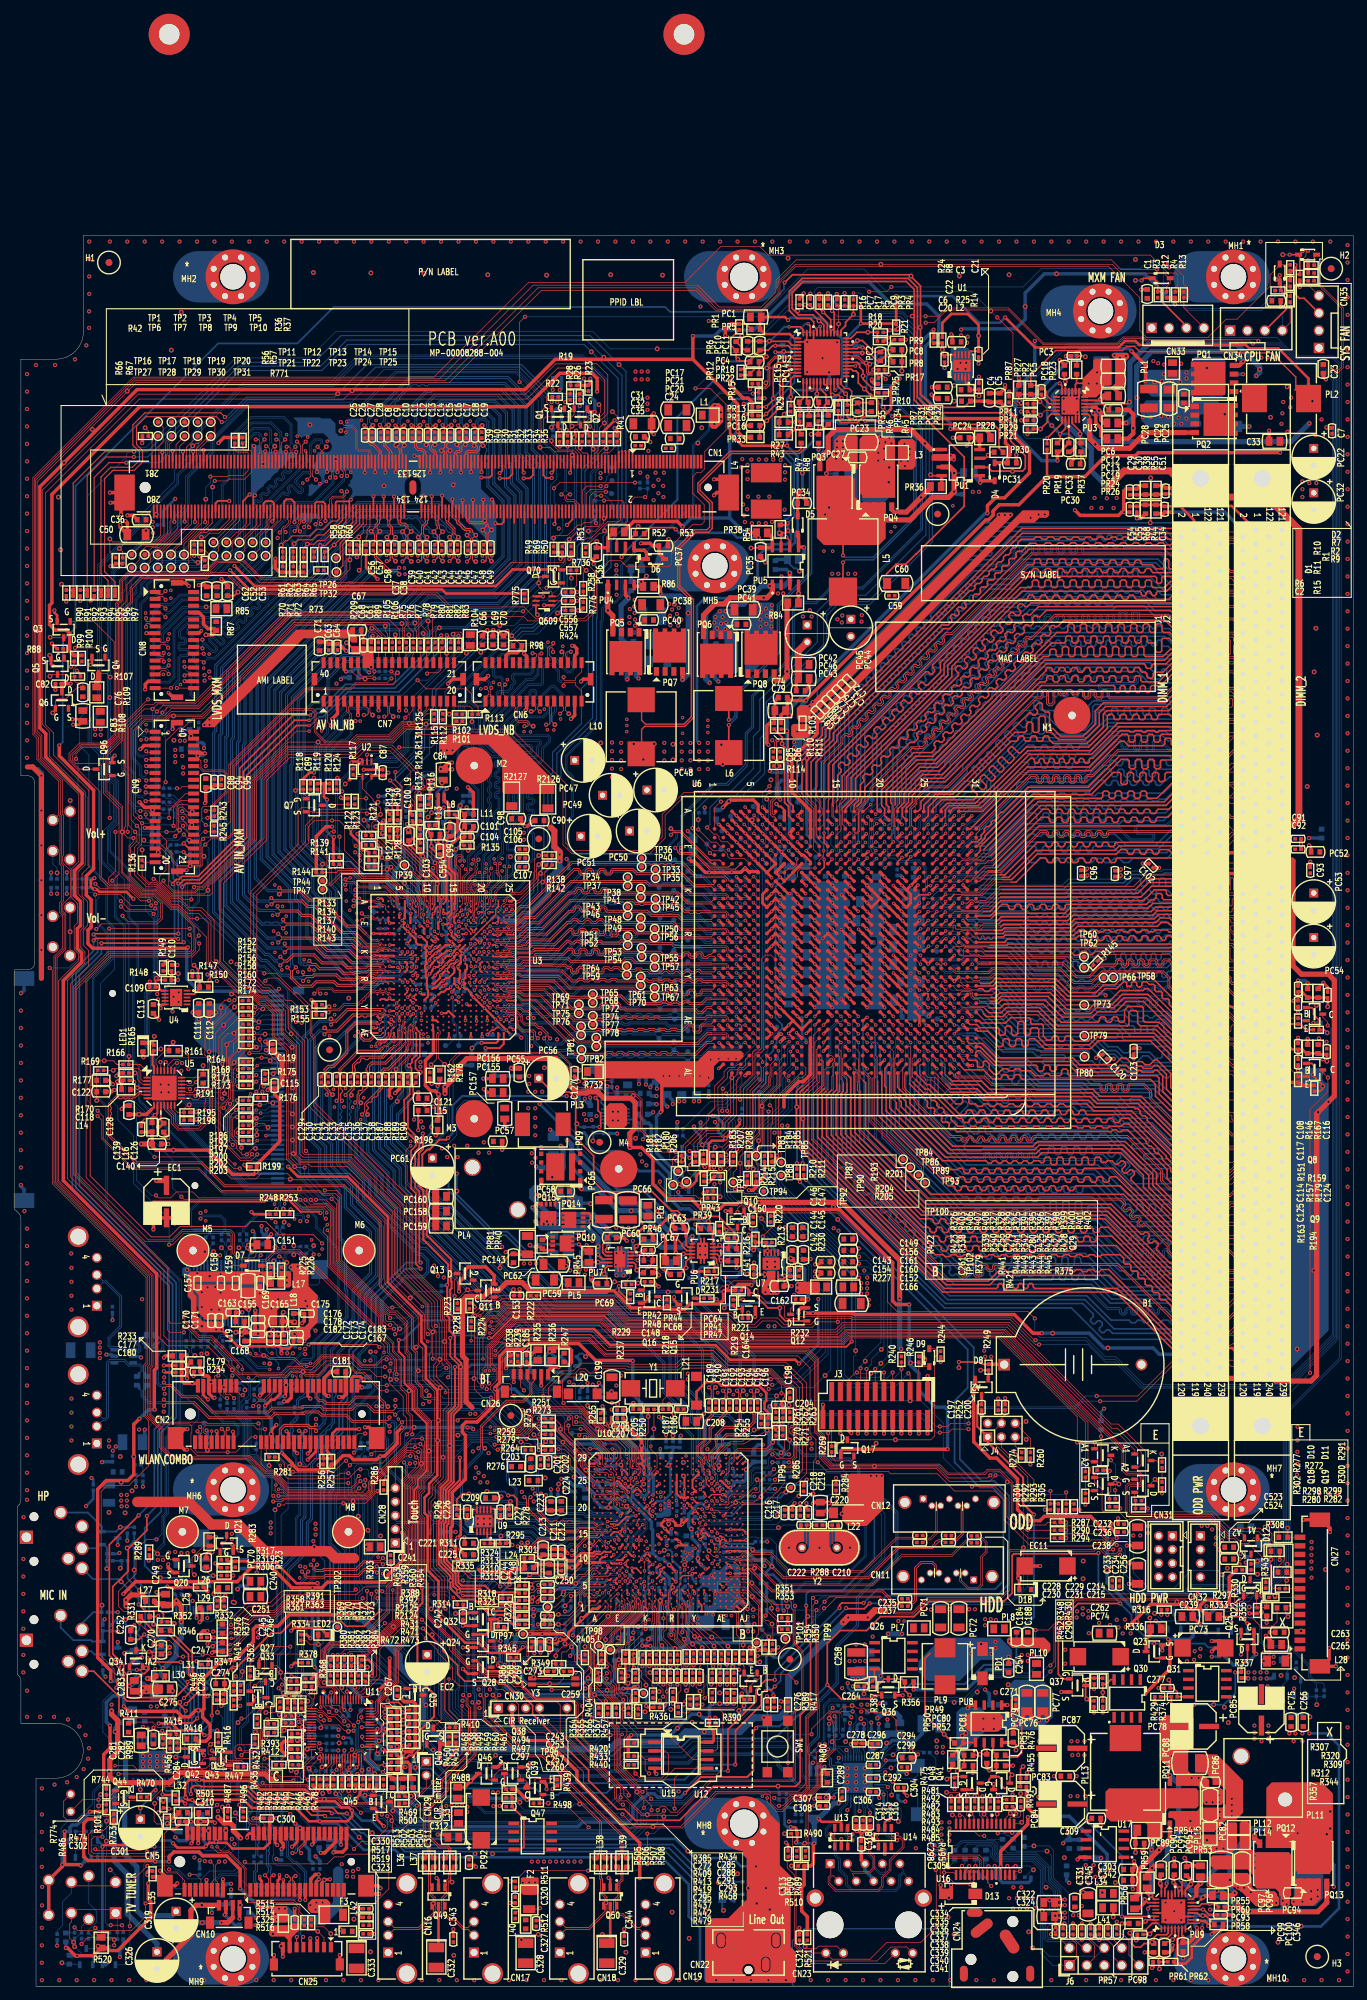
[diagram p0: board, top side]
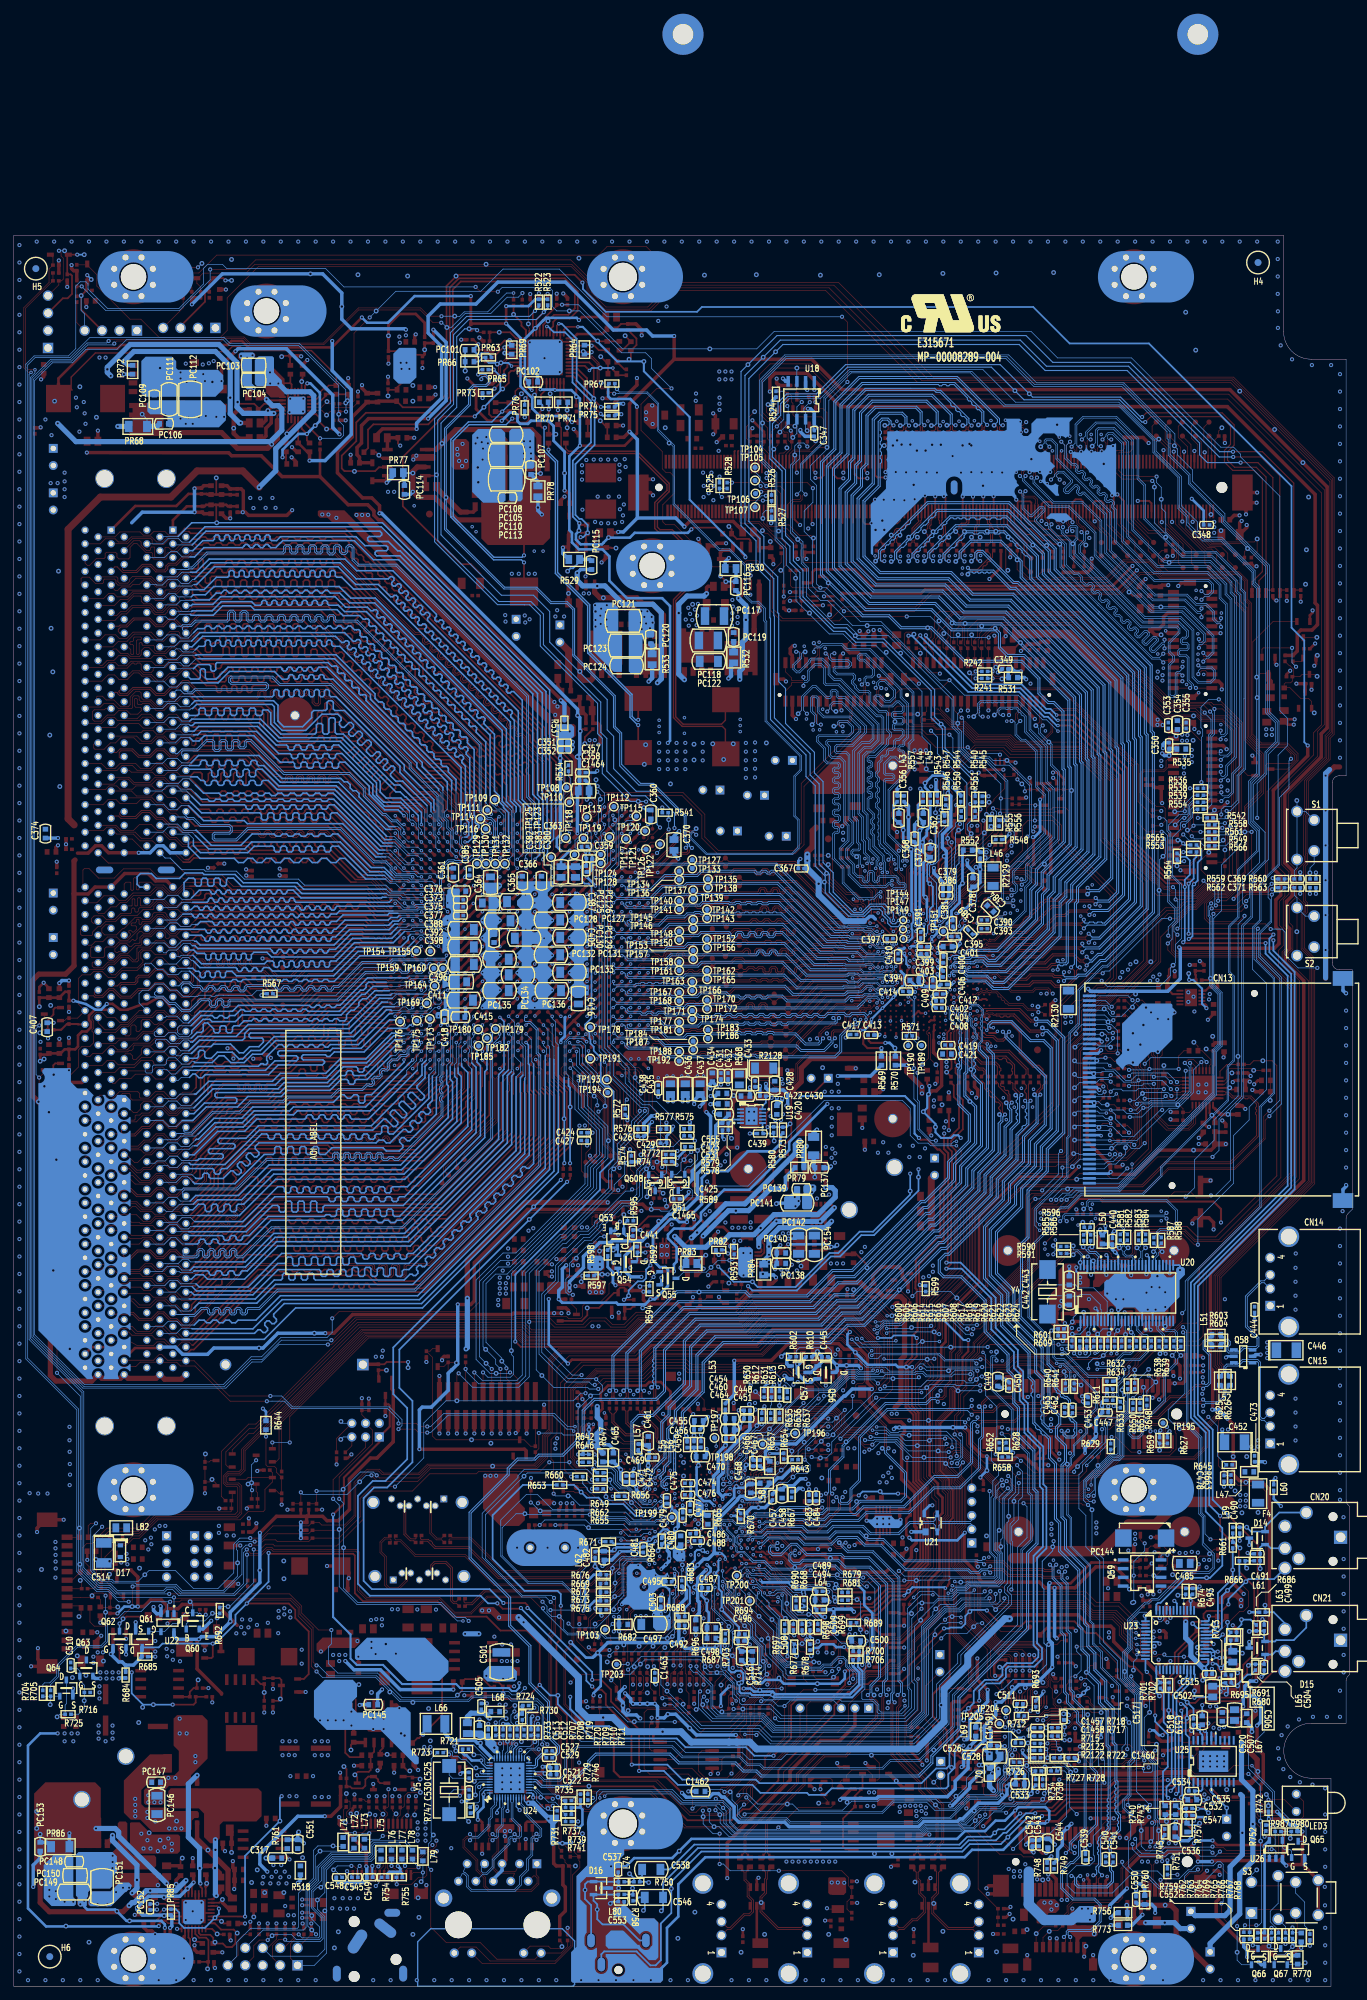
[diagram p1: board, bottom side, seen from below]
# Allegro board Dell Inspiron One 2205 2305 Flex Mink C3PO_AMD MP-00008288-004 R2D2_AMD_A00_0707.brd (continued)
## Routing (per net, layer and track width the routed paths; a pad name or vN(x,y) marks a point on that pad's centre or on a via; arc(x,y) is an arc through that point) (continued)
MXM_LVDS_U_CLK_DN: length 45.1
  TOP w0.099: v2(22.34,196.22) 21.85,195.73 21.3,195.73 20.94,196.09 CN8.8 ; v2(48.42,219.99) 48.16,220.24 48.16,220.65 48,220.81 CN1.169
  BOTTOM w0.099: v2(22.34,196.22) 22.34,195.82 22.24,195.71 21.95,195.71 21.68,195.99 21.68,196.93 24.83,200.08 29.3,200.08 37.59,208.37 37.59,211.65 41.32,215.37 44.13,215.37 48.06,219.3 48.06,219.63 v2(48.42,219.99)
MXM_LVDS_U_CLK_DP: length 45.6
  TOP w0.099: v2(47.6,219.99) 47.91,220.29 47.91,220.54 47.75,220.7 47.75,220.71 47.5,220.95 CN1.171 ; CN8.9 20.93,195.09 21.32,195.48 21.82,195.48 v2(22.34,194.95)
  BOTTOM w0.099: v2(47.6,219.99) 47.81,219.79 47.81,219.41 44.03,215.63 41.21,215.63 37.34,211.75 37.34,208.47 36,207.14 35.34,206.48 32.32,203.45 29.19,200.33 24.72,200.33 21.42,197.03 21.42,195.88 21.85,195.46 22.27,195.46 22.34,195.39 v2(22.34,194.95)
MXM_LVDS_U_TX0_DN: length 46.5
  TOP w0.099: v2(21.97,203.23) 21.96,203.23 21.45,202.72 21.02,202.72 20.65,203.09 CN8.1 ; v2(42.39,224.98) 42.39,224.98 41.88,224.47 41.88,223.34 42,223.22 CN1.193
  BOTTOM w0.099: v2(42.39,224.98) 41.88,224.47 41.88,222.54 40.91,221.57 40.4,221.57 40.19,221.36 40.19,221.22 40.35,221.06 40.35,220.71 39.99,220.35 39.64,220.35 39.48,220.51 39.34,220.51 39.13,220.3 39.13,220.16 39.29,220 39.29,219.65 38.93,219.29 38.58,219.29 38.42,219.45 38.28,219.45 38.07,219.24 38.07,219.1 38.23,218.94 38.23,218.61 37.85,218.23 37.52,218.23 37.36,218.39 37.22,218.39 37.01,218.18 37.01,218.04 37.17,217.88 37.17,217.53 36.81,217.17 36.46,217.17 36.3,217.33 36.16,217.33 35.95,217.12 35.95,216.98 36.11,216.82 36.11,216.47 35.75,216.11 35.4,216.11 35.24,216.27 35.1,216.27 34.89,216.06 34.89,215.92 35.04,215.78 35.04,215.4 34.64,215 34.64,210.42 31.18,206.96 28.88,204.65 21,204.65 20.48,204.14 20.48,203.18 20.94,202.72 21.46,202.72 v2(21.97,203.23)
MXM_LVDS_U_TX0_DP: length 47
  TOP w0.099: CN8.2 20.64,202.09 21.02,202.46 21.55,202.46 21.97,202.05 v2(21.97,201.96) ; CN1.195 41.5,223.22 41.62,223.34 41.62,224.47 v2(41.12,224.98)
  BOTTOM w0.099: v2(41.12,224.98) 41.62,224.47 41.62,222.64 40.81,221.83 40.3,221.83 39.94,221.47 39.94,221.12 40.1,220.96 40.1,220.82 39.89,220.61 39.75,220.61 39.59,220.77 39.24,220.77 38.88,220.41 38.88,220.06 39.04,219.9 39.04,219.76 38.83,219.55 38.69,219.55 38.53,219.71 38.18,219.71 37.82,219.35 37.82,219 37.98,218.84 37.98,218.72 37.75,218.49 37.63,218.49 37.47,218.65 37.12,218.65 36.76,218.29 36.76,217.94 36.92,217.78 36.92,217.64 36.71,217.43 36.57,217.43 36.41,217.59 36.06,217.59 35.7,217.23 35.7,216.88 35.86,216.72 35.86,216.58 35.65,216.37 35.51,216.37 35.35,216.53 35,216.53 34.64,216.17 34.64,215.82 34.78,215.67 34.78,215.5 34.39,215.1 34.39,210.52 28.77,204.91 20.9,204.91 20.23,204.24 20.23,203.07 20.84,202.46 21.46,202.46 v2(21.97,201.96)
MXM_LVDS_U_TX1_DN: length 43.3
  TOP w0.099: CN8.3 21.56,201.09 v2(21.96,200.69) ; v2(43.89,219.46) 43.38,219.96 43.38,220.8 43.5,220.92 CN1.187
  BOTTOM w0.099: v2(21.96,200.69) 21.96,200.4 22.13,200.23 22.49,200.23 24.31,202.06 28.99,202.06 35.8,208.86 35.8,214.43 39.01,217.64 39.36,217.64 39.57,217.43 39.71,217.43 39.92,217.64 39.92,217.78 39.71,217.99 39.71,218.34 40.07,218.7 40.42,218.7 41.44,217.68 41.64,217.68 41.79,217.83 41.79,218.03 40.77,219.05 40.77,219.4 42.04,220.68 42.87,220.68 43.38,220.17 43.38,219.96 v2(43.89,219.46)
MXM_LVDS_U_TX1_DP: length 43.1
  TOP w0.099: v2(42.62,219.46) 43.12,219.96 43.12,220.8 43,220.92 CN1.189 ; v2(21.96,199.42) 21.29,200.09 CN8.4
  BOTTOM w0.099: v2(21.96,199.42) 21.96,199.83 22.11,199.97 22.59,199.97 24.42,201.8 29.1,201.8 36.05,208.76 36.05,214.33 39.11,217.39 39.25,217.39 39.46,217.17 39.81,217.17 40.17,217.53 40.17,217.88 39.96,218.1 39.96,218.24 40.17,218.45 40.31,218.45 41.33,217.43 41.75,217.43 42.04,217.72 42.04,218.14 41.02,219.16 41.02,219.3 42.15,220.42 42.77,220.42 43.12,220.06 43.12,219.96 v2(42.62,219.46)
MXM_LVDS_U_TX2_DN: length 47.9
  TOP w0.099: v2(19.13,199.27) 19.11,199.26 19.11,198.88 19.21,198.78 19.59,198.78 19.9,199.09 CN8.5 ; v5(45.39,224.25) 44.88,223.74 44.88,223.34 45,223.22 CN1.181
  BOTTOM w0.099: v2(19.13,199.27) 19.13,198.9 19.31,198.71 19.6,198.71 20.05,199.16 20.05,200.23 21.24,201.42 22.69,201.42 24.04,202.77 28.71,202.77 35.07,209.13 35.07,214.72 42.92,222.57 42.92,224.58 43.72,225.38 44.66,225.38 44.88,225.16 44.88,224.76 v5(45.39,224.25)
MXM_LVDS_U_TX2_DP: length 47.5
  TOP w0.099: CN8.6 19.98,198.09 19.54,198.53 19.24,198.53 19.11,198.4 19.11,198.02 v2(19.13,198) ; CN1.183 44.5,223.22 44.62,223.34 44.62,223.74 v2(44.12,224.25)
  BOTTOM w0.099: v2(19.13,198) 19.13,198.36 19.22,198.46 19.71,198.46 20.31,199.06 20.31,200.13 21.35,201.17 22.79,201.17 24.14,202.51 28.81,202.51 35.33,209.03 35.33,214.61 43.17,222.46 43.17,224.47 43.83,225.12 44.55,225.12 44.62,225.05 44.62,224.76 v2(44.12,224.25)
MXM_LVDS_U_TX3_DN: length 47.7
  TOP w0.099: v2(21.71,194.22) 21.71,193.78 21.6,193.68 21.37,193.68 20.96,194.09 CN8.10 ; v2(46.74,219.76) 46.38,220.12 46.38,220.8 46.5,220.92 CN1.175
  BOTTOM w0.099: v2(21.71,194.22) 21.2,193.72 21.01,193.72 20.41,194.31 20.41,196.62 24.52,200.74 29.02,200.74 35.05,206.77 35.42,207.14 36.75,208.46 36.75,213.4 39.38,216.03 43.62,216.03 46.51,218.92 46.51,219.53 v2(46.74,219.76)
MXM_LVDS_U_TX3_DP: length 47.9
  TOP w0.099: CN8.11 20.96,193.09 21.3,193.42 21.58,193.42 21.7,193.29 21.7,192.96 v2(21.71,192.95) ; v2(45.93,219.76) 46.13,219.96 46.13,220.79 46,220.92 CN1.177
  BOTTOM w0.099: v2(45.93,219.76) 46.26,219.43 46.26,219.03 43.51,216.29 39.27,216.29 36.49,213.51 36.49,208.57 34.87,206.95 28.92,200.99 24.42,200.99 20.84,197.41 20.84,197.41 20.15,196.73 20.15,194.21 20.9,193.46 21.2,193.46 v2(21.71,192.95)
MXM_LVDSPWR_EN: length 348.5
  TOP w0.102: R33.1 84.69,226.35 v2(83.83,227.2) ; D10.A2 156.79,76.39 156.35,76.83 156.35,82.17 143.67,94.84 121.52,94.84 120.53,93.85 105.32,93.85 103.24,95.94 88.83,95.94 86.44,98.32 72.18,98.32 70.02,96.16 v3(69.23,96.16) ; v2(42.37,114.55) 43.1,113.82 45.39,113.82 46.23,112.98 46.23,105.27 53.76,97.74 53.76,96.84 54.27,96.33 v2(54.68,96.33) ; v2(20.23,156.21) 19.85,156.59 16.17,156.59 v2(15.48,157.28)
  BOTTOM w0.102: v2(54.68,96.33) 56.59,96.33 58.37,98.11 64.65,98.11 65.99,96.77 68.21,96.77 68.82,96.16 v3(69.23,96.16) ; v2(15.48,157.28) 15.96,157.76 15.96,161.21 13.5,163.68 13.5,168.53 14.62,169.65 14.62,175.26 13.5,176.38 13.5,203.86 14.16,204.52 14.16,206.22 19.01,211.07 21.47,211.07 22.56,212.16 22.56,213.3 24.89,215.63 24.89,219.93 28.58,223.62 28.58,224.97 v1(28.19,225.36) 28.63,225.36 34,230.73 49.05,230.73 53.79,235.47 73.27,235.47 77.51,231.24 82,231.24 82.81,230.43 82.81,228.22 v2(83.83,227.2) ; v2(20.23,156.21) 20.38,156.06 20.38,145.89 19.16,144.67 19.16,137.02 20,136.18 20,129.92 33.97,115.95 40.21,115.95 40.9,115.25 41.67,115.25 v2(42.37,114.55)
MXM_PANEL_ID0: length 16
  TOP w0.102: CN9.35 26.63,177.73 27.44,176.91 30.36,176.91 30.68,176.59 30.68,173.99 28.52,171.83 27.51,171.83 27.25,171.58 27.25,169.74 v2(27.82,169.16) 27.97,169.02 R245.1
MXM_PANEL_ID2: length 13.7
  TOP w0.102: v2(27.82,171.2) 27.94,171.31 R243.1 29.09,172.09 30.94,173.93 30.94,176.66 30.43,177.16 27.51,177.16 27.13,177.55 27.13,178.5 26.9,178.73 CN9.36
MXM_PWR_EN: length 15
  TOP w0.102: R258.2 82.81,205.8 v1(83.26,206.25) 82.56,206.95 82.56,210.19 83.32,210.95 83.96,210.95 86.37,213.36 88.02,213.36 88.25,213.59 CN1.8
MXM_PWR_GOOD: length 9.2
  TOP w0.102: CN1.6 88.75,216.15 88.5,216.41 v2(85.86,216.41)
  BOTTOM w0.102: v1(85.86,213.8) 85.86,214.55 85.48,214.93 R527.2 R526.2 84.64,216.41 v2(85.86,216.41)
MXM_PWR_LEVEL: length 8.1
  TOP w0.102: CN1.18 85.75,213.13 84.58,211.96 v1(83.58,211.96) 82.81,211.96 81.04,210.19 R50.2
MXM_PWRGD: length 374.1
  TOP w0.102: v2(20.36,120.8) 28.38,120.8 31.58,117.6 35.13,117.6 35.88,118.35 39.75,118.35 40.63,117.47 48.32,117.47 53.92,111.87 53.92,102.32 58.78,97.46 58.78,93.5 59.45,92.84 59.45,88.33 61.12,86.65 61.12,74.85 59.75,73.48 59.75,72.11 59.22,71.58 59.22,68.73 59.7,68.25 59.7,60.33 61.1,58.93 v3(61.1,57.02) ; R353.2 112.96,51.64 112.96,50.34 110.75,48.13 v2(108.21,48.13)
  BOTTOM w0.102: v3(61.1,57.02) 62.81,57.02 64.79,55.04 64.79,43.31 64.6,43.12 64.6,40.73 65.65,39.69 68.97,39.69 69.23,39.94 69.23,40.89 69.87,41.53 74.41,41.53 74.66,41.78 85.69,41.78 85.94,42.04 87.77,42.04 88.02,42.29 89.23,42.29 89.65,42.71 89.65,44.35 91.35,46.05 91.78,46.05 91.96,46.23 91.96,47.88 92.8,48.72 107.63,48.72 v2(108.21,48.13) ; R526.1 84.59,220.47 86.37,222.25 86.37,233.93 82.69,237.62 50.05,237.62 45.98,233.55 33.28,233.55 25.84,226.11 25.84,224.46 v1(25.92,224.38) 25.46,223.92 25.46,223.06 23.25,220.85 23.25,219.2 18.55,214.5 18.55,213.49 12.08,207.01 12.08,185.67 10.68,184.28 10.68,180.97 12.2,179.45 12.2,164.13 14.76,161.58 14.76,155.83 16.13,154.46 16.13,129.6 19.42,126.31 19.42,121.74 v2(20.36,120.8)
MXM_PWRGD_R: length 10
  TOP w0.102: U10.AJ6 106.54,59.32 110.25,55.61 v1(110.25,55.05) 110.25,54.61 111.26,53.59 111.26,52.48 R353.1
MXM_RST_N: length 14.4
  TOP w0.102: R73.1 46.03,205.23 47.25,205.23 48.27,206.25 48.27,209.74 48.51,209.98 R58.1 48.8,210.28 49.46,210.95 49.97,210.95 v1(50.13,211.1) 50.8,211.78 50.8,212.52 51.25,212.97 CN1.156
MXM_STD_SW_N: length 9.5
  TOP w0.102: CN1.19 85.5,223.11 85.76,223.37 86.58,223.37 87.73,224.52 R41.1 87.78,225 88.28,225.49 88.28,227.14 87.89,227.52 87.89,228.54 v1(87.07,229.36)
MXM_VGA_DDC_CLK: length 8.2
  TOP w0.165: CN1.160 50.25,213.07 47.4,210.22 47.4,208.63 TP26.1
MXM_VGA_DDC_DATA: length 10.4
  TOP w0.165: TP32.1 47.81,206.93 47.81,210.06 50.75,213 CN1.158
MXM_VGA_DISABLE_N: length 4.9
  TOP w0.102: CN1.21 85,223.23 85.8,224.03 v1(86.18,224.03) 85.7,224.51 R34.2 R35.2
NB_ALLOW_LDTSTOP: length 12.9
  TOP w0.102: U3.C12 61.94,157.09 61.97,157.2 61.97,157.32 61.87,157.61 61.92,157.88 62.11,158.12 62.11,158.12 62.11,158.55 62.14,158.57 62.14,161.57 61.4,162.31 61.4,163.46 v1(61.22,163.64) 61.22,163.8 59.64,165.39 59.64,166.31 59.4,166.55 R132.1 R126.2
NB_HDMI_CLK_TX3_DN: length 44.4
  TOP w0.099: v2(50.61,155.3) 50.98,155.67 51.96,155.67 52.31,155.32 53.3,155.32 U3.D2 ; CN7.2 46,186.7 45.58,186.29 45.58,184.13 v5(46.09,183.62)
  BOTTOM w0.099: v2(50.61,155.3) 50.95,155.64 51.35,155.64 51.64,155.34 51.64,154.73 51.63,154.71 51.63,154.69 51.56,154.63 49.84,154.63 47.77,156.7 47.77,160.08 46.95,160.89 46.95,163.07 42.94,167.08 42.94,176.81 43.98,177.86 43.98,180.79 45.67,182.48 45.67,183.2 v5(46.09,183.62)
NB_HDMI_CLK_TX3_DP: length 44.6
  TOP w0.099: v2(50.56,156.29) 50.87,155.98 50.87,155.98 50.92,155.92 52.07,155.92 52.42,155.57 52.76,155.57 U3.D1 ; v2(45.1,183.64) 45.33,183.88 45.33,186.31 44.99,186.64 CN7.1
  BOTTOM w0.099: v2(45.1,183.64) 45.41,183.32 45.41,182.58 43.73,180.9 43.73,177.96 42.68,176.92 42.68,166.98 46.7,162.96 46.7,160.79 47.51,159.97 47.51,156.59 49.73,154.37 51.67,154.37 51.88,154.59 51.88,154.61 51.9,154.62 51.9,155.45 51.45,155.89 50.95,155.89 v2(50.56,156.29)
NB_LCD_BKL_EN: length 285.2
  TOP w0.102: D12.A1 180.52,65.32 179.72,64.52 178.76,64.52 177.68,65.6 176.73,65.6 174.13,68.2 162.44,68.2 161.78,68.86 161.78,72.87 162.22,73.3 163.82,73.3 163.97,73.46 163.97,74.19 163.69,74.47 161.96,74.47 161.3,75.13 161.3,78 144.05,95.25 121.3,95.25 120.31,94.26 105.51,94.26 103.42,96.34 89.1,96.34 86.72,98.73 71.82,98.73 70.32,97.23 69.24,97.23 68.72,96.71 68.72,95.02 68.21,94.51 v3(68.21,91.38) ; v2(59.5,174.73) 59.5,175.77 54.86,180.4 50.75,180.4 49.79,179.45 39.95,179.45 36.31,175.81 36.31,167.21 30.01,160.91 30.01,149.22 33.45,145.77 34.21,145.77 35.76,144.22 36.73,144.22 39.05,141.9 39.05,139.01 41.06,137.01 41.06,121.08 41.77,120.37 48.75,120.37 55.74,113.38 55.74,103.94 60.34,99.34 60.34,95.87 60.89,95.31 v2(60.89,91.4)
  BOTTOM w0.102: v2(60.89,91.4) 60.89,91.38 60.96,91.31 v1(61.92,91.31) 68.15,91.31 v3(68.21,91.38) ; R547.2 59.22,172.94 59.5,173.22 v2(59.5,174.73)
NB_LCD_BKL_EN_R: length 24.6
  TOP w0.127: U3.G12 61.54,153.26 v3(61.14,153.66)
  BOTTOM w0.102: v1(60.72,170.94) 60.72,171.64 60.46,171.89 R543.1 59.95,172.04 R547.1
  BOTTOM w0.125: 61.19,153.71 61.28,153.79 61.28,155.37 60.56,156.08 60.56,160.69 61.58,161.71 61.58,163.27 61.38,163.47 60.78,163.47 60.23,164.02 60.23,167.97 60.01,168.19
  BOTTOM w0.127: 60.01,168.19 58.91,169.29 58.91,171.73 R547.1 ; v3(61.14,153.66) 61.19,153.71
NB_LCD_BKL_PWM: length 221.5
  TOP w0.102: D11.A1 163.17,78.12 160.74,80.54 160.06,80.54 144.59,96.01 120.89,96.01 119.85,94.97 105.7,94.97 103.72,96.95 89.36,96.95 86.97,99.34 71.47,99.34 70.41,98.27 69.33,98.27 67.83,96.77 v3(67.83,95.82) ; v2(61.35,96.19) 61.2,96.34 61.2,99.62 56.59,104.23 56.59,113.8 49.21,121.18 42.15,121.18 41.87,121.46 41.87,137.41 39.86,139.42 39.86,142.27 37.09,145.03 36.1,145.03 34.38,146.76 34.38,159.44 41.29,166.34 41.29,171.2 41.79,171.7 43.57,171.7 43.83,171.45 51.53,171.45 51.66,171.58 v2(52.33,171.58)
  BOTTOM w0.102: R556.2 51.83,170.23 51.83,171.07 v2(52.33,171.58) ; v3(67.83,95.82) 64.34,95.82 v1(64.21,95.95) 64.2,95.96 61.58,95.96 v2(61.35,96.19)
NB_LCD_BKL_PWM_R: length 19.6
  TOP w0.102: U3.F7 57.61,154.06 v3(57.24,154.43)
  BOTTOM w0.102: R556.1 R555.1 52.72,168.91 v1(53.6,168.02) 53.8,167.83 53.8,165.99 53.54,165.74 53.1,165.74 52.72,165.35 52.72,164.59 53.48,163.83 53.48,160.64 54.75,159.37 54.75,157.99 56.09,156.64 56.45,156.64 56.63,156.46 56.63,155.72 57.24,155.11 v3(57.24,154.43)
NB_LCD_DDC_CLK: length 84
  TOP w0.102: v2(79.39,224.28) R39.1 ; R143.1 51.45,163.07 50.81,163.7 50.81,164.85 49.67,165.99 v2(49.67,166.12)
  BOTTOM w0.102: v2(49.67,166.12) 49.26,166.52 49.26,168.05 50.43,169.21 50.43,175.45 53.22,178.24 55.64,178.24 57.41,180.02 57.41,182.5 58.3,183.39 58.3,187.45 67.61,196.76 71.93,196.76 73.54,198.37 75.42,198.37 79.51,202.46 79.51,206.5 80.27,207.26 80.27,210.11 81.83,211.66 81.83,221.58 81.21,222.2 v1(81.21,223.04) 81.21,224.36 80.78,224.79 79.89,224.79 v2(79.39,224.28)
NB_LCD_DDC_DATA: length 77.7
  TOP w0.102: v2(49.6,169.23) 50.48,168.35 50.48,166.95 51.14,166.29 R134.1 ; R40.1 v2(80.53,224.28)
  BOTTOM w0.102: v2(49.6,169.23) 50.18,169.8 50.18,175.58 53.1,178.5 55.57,178.5 57.16,180.09 57.16,182.63 58.05,183.51 58.05,187.8 68.45,198.2 v1(70.67,198.2) 72.78,198.2 76.43,201.84 77.44,201.84 79.2,203.59 79.2,206.57 80.02,207.39 80.02,210.39 81.58,211.94 81.58,221.46 80.53,222.5 v2(80.53,224.28)
NB_LCD_PWR_EN: length 428.6
  TOP w0.102: v2(15.45,158.06) 16.67,156.84 20.33,156.84 v2(20.48,157) ; v2(55.41,94.97) 55.79,95.35 55.79,96.18 55.13,96.84 54.24,96.84 54.01,97.07 54.01,97.79 46.45,105.35 46.45,113.07 45.48,114.05 43.64,114.05 v2(43.13,114.55) ; D10.A1 v2(157.33,79.21) ; v3(69.23,95.12) 69.73,95.12 72.5,97.89 86.3,97.89 88.66,95.53 103.03,95.53 105.12,93.45 120.74,93.45 121.73,94.44 143.32,94.44 154.79,82.97 v2(154.79,79.21)
  BOTTOM w0.102: v3(69.23,95.12) 68.08,96.27 65.67,96.27 64.34,97.6 58.95,97.6 56.32,94.97 v2(55.41,94.97) ; v2(20.48,157) 20.79,156.69 20.79,156.01 20.58,155.8 20.58,145.8 19.37,144.58 19.37,137.1 20.2,136.26 20.2,130.02 34.07,116.15 40.6,116.15 41.23,115.52 42.16,115.52 v2(43.13,114.55) ; v2(157.33,79.21) v2(154.79,79.21) ; v2(15.45,158.06) 14.96,158.56 14.96,161.71 12.71,163.96 12.71,168.08 14.36,169.74 14.36,175.07 12.71,176.72 12.71,179.79 11.21,181.29 11.21,184.07 12.61,185.47 12.61,206.81 19.04,213.23 19.04,214.02 23.86,218.84 23.86,220.06 26.81,223.01 26.81,225.27 26.99,225.45 26.99,226.44 33.57,233.02 46.39,233.02 50.45,237.08 82.46,237.08 85.89,233.65 85.89,222.53 83.83,220.47 83.83,210.85 82.42,209.44 82.42,206.99 81.04,205.61 81.04,201.82 76.19,196.98 74.18,196.98 72.53,195.33 69.42,195.33 62.69,188.59 62.69,182.04 61.47,180.82 61.47,179.26 62.06,178.66 v1(62.06,177.32) 61.66,176.91 59.57,176.91 56.6,173.94 56.6,171.55 R550.2
NB_LCD_PWR_EN_R: length 19.7
  TOP w0.125: v3(59.58,156.1) 59.59,156.09 59.59,155.45
  TOP w0.127: 59.59,155.45 59.59,154.96 U3.E9
  BOTTOM w0.102: v3(59.58,156.1) 59.59,156.12 59.59,156.95 58.3,158.24 58.3,162.09 58.35,162.13 58.35,165.78 58.94,166.37 v1(58.94,167.2) 58.94,167.77 57.8,168.91 57.8,169.42 57.54,169.67 R550.1 57.41,170.77 57.41,171.53 57.03,171.91 R544.1
NB_LDT_STOP_N: length 27
  TOP w0.102: R117.2 49.57,176.2 U2.4 50.67,174.44 52.21,172.9 52.21,172.69 53.29,171.62 v1(53.29,170.69) 52.02,169.42 52.02,168.47 55.21,165.28 56.27,165.28 58.56,162.99 58.56,162.53 60.37,160.71 60.37,157.98 60.27,157.79 60.27,157.72 60.37,157.3 60.37,157.19 U3.C10
NB_LVDS_L_CLK_DN: length 57.2
  TOP w0.099: v3(65.5,163.91) 65.42,163.91 65.31,164.02 65.31,164.53 65.03,164.81 64.53,164.81 64.1,164.38 64.1,163.24 64.7,162.64 64.7,158.7 64.81,158.59 64.81,158.09 U3.A16 ; v2(78.42,194.36) 78.42,194.82 78.28,194.96 78,194.96 77.86,194.82 77.86,193.93 78.58,193.22 CN6.20
  BOTTOM w0.099: v3(65.5,163.91) 65.42,163.91 65.3,164.03 65.3,165.36 67.63,167.69 67.63,174.27 64.7,177.19 64.7,181.06 64.12,181.64 64.12,188.4 70.34,194.62 73.73,194.62 74.43,195.33 77.06,195.33 77.44,194.94 78.24,194.94 78.42,194.77 v2(78.42,194.36)
NB_LVDS_L_CLK_DP: length 57.4
  TOP w0.099: v3(64.86,163.91) 65.05,164.1 65.05,164.43 64.92,164.56 64.64,164.56 64.36,164.28 64.36,163.34 64.96,162.74 64.96,158.8 65.21,158.55 65.21,157.63 U3.B16 ; CN6.21 77.57,193.32 77.61,193.35 77.61,194.92 77.9,195.21 78.29,195.21 78.45,195.37 78.45,195.48 78.44,195.48 v2(78.44,195.64)
  BOTTOM w0.099: v2(78.44,195.64) 78,195.2 77.54,195.2 77.16,195.58 74.33,195.58 73.62,194.88 70.23,194.88 63.86,188.51 63.86,181.54 64.45,180.95 64.45,177.09 67.37,174.17 67.37,167.8 65.05,165.47 65.05,164.1 v3(64.86,163.91)
NB_LVDS_L_TX0_DN: length 50.8
  TOP w0.099: v2(79.45,185.36) 79.95,185.86 79.95,186.32 79.58,186.69 CN6.12 ; U3.B22 69.64,157.27 70.01,157.64 70.01,158.18 70.11,158.28 70.11,159.33 71.81,161.03 71.81,162.86 v3(72.07,163.11)
  BOTTOM w0.099: v3(72.07,163.11) 72.07,163.15 71.95,163.26 71.95,163.26 71.88,163.34 71.88,164.53 71.98,164.63 72.74,164.63 73.04,164.93 73.04,165.34 72.74,165.63 71.98,165.63 71.88,165.73 71.88,166.25 72.2,166.57 72.2,169.72 72.78,170.31 72.78,180 71.49,181.28 70.39,181.28 69.94,181.73 69.94,183.58 73.96,187.59 74.91,187.59 75.17,187.86 75.17,188.47 75.35,188.64 75.68,188.64 75.8,188.52 75.8,187.85 76.05,187.59 76.61,187.59 78.21,189.19 78.55,189.19 79.96,187.78 79.96,185.86 v2(79.45,185.36)
NB_LVDS_L_TX0_DP: length 50.8
  TOP w0.099: v5(80.72,185.36) 80.2,185.87 80.2,186.3 80.58,186.67 CN6.13 ; U3.A22 69.64,158.21 69.86,158.43 69.86,159.44 71.56,161.13 71.56,162.9 v3(71.32,163.13)
  BOTTOM w0.099: v3(71.32,163.13) 71.62,163.43 71.62,164.64 71.87,164.89 72.64,164.89 72.78,165.03 72.78,165.24 72.64,165.38 71.87,165.38 71.62,165.63 71.62,166.36 71.94,166.68 71.94,169.83 72.53,170.41 72.53,179.89 71.39,181.03 70.28,181.03 69.69,181.63 69.69,183.69 73.85,187.85 74.8,187.85 74.92,187.97 74.92,188.57 75.24,188.9 75.78,188.9 76.05,188.63 76.05,187.95 76.16,187.85 76.51,187.85 78.11,189.45 78.65,189.45 80.21,187.89 80.21,185.86 v5(80.72,185.36)
NB_LVDS_L_TX1_DN: length 53.4
  TOP w0.099: U3.B21 69.28,157.29 69.28,158.24 69.48,158.44 69.48,159.61 70.9,161.04 70.9,161.71 70.48,162.13 70.48,163.35 v3(70.69,163.56) ; CN6.15 82.58,188.64 81.7,189.52 81.7,189.83 81.6,189.93 80.16,189.93 79.96,189.73 v2(79.96,189.42)
  BOTTOM w0.099: v2(79.96,189.42) 79.96,189.73 79.75,189.93 79.43,189.93 79.12,190.23 79.12,191.49 78.18,192.44 77.46,192.44 77.03,192.01 77.03,189.78 76.71,189.45 74.87,189.45 69.2,183.78 69.2,181.52 70.13,180.59 71.09,180.59 72.02,179.67 72.02,170.76 71.46,170.21 71.46,166.93 71.18,166.65 71.18,165.05 70.55,164.42 70.55,163.67 70.66,163.56 v3(70.69,163.56)
NB_LVDS_L_TX1_DP: length 53
  TOP w0.099: v3(69.97,163.57) 70.23,163.3 70.23,162.02 70.65,161.6 70.65,161.14 69.23,159.72 69.23,158.56 69.02,158.36 69.02,157.84 U3.A21 ; v2(79.96,190.69) 79.96,190.36 80.13,190.18 81.6,190.18 81.7,190.28 81.7,190.59 82.58,191.47 CN6.16
  BOTTOM w0.099: v2(79.96,190.69) 79.96,190.38 79.76,190.18 79.53,190.18 79.38,190.34 79.38,191.59 78.28,192.69 77.35,192.69 76.78,192.12 76.78,189.88 76.6,189.7 74.76,189.7 68.95,183.89 68.95,181.42 70.03,180.34 70.99,180.34 71.77,179.56 71.77,170.87 71.21,170.31 71.21,167.03 70.93,166.75 70.93,165.16 70.29,164.52 70.29,163.75 70.11,163.57 v3(69.97,163.57)
NB_LVDS_L_TX2_DN: length 54.4
  TOP w0.099: CN6.18 80.58,193.49 80.21,193.86 80.21,194.12 80.48,194.39 v2(81.01,194.39) ; v3(69.43,162.84) 69.25,162.84 69.18,162.76 69.18,162.36 69.3,162.23 69.3,161.86 69.18,161.74 69.18,161.37 69.3,161.24 69.3,160.87 69.18,160.75 69.18,160.55 67.99,159.37 67.99,158.11 U3.A20
  BOTTOM w0.099: v3(69.43,162.84) 69.37,162.9 69.37,163.94 69.2,164.11 69.2,164.33 70.5,165.63 70.5,166.93 70.8,167.23 70.8,170.61 71.36,171.17 71.36,179.25 70.7,179.91 69.8,179.91 68.5,181.21 68.5,184.74 68.68,184.91 69.31,184.91 74.59,190.19 75.5,190.19 76.35,191.04 76.35,192.31 77.24,193.19 78.8,193.19 78.92,193.07 78.92,192.89 80.5,191.31 80.98,191.31 81.49,191.82 81.49,192.5 80.48,193.5 80.48,194.18 80.69,194.39 v2(81.01,194.39)
NB_LVDS_L_TX2_DP: length 54.6
  TOP w0.099: v3(68.69,162.83) 68.7,162.83 68.92,162.61 68.92,160.66 67.74,159.48 67.74,157.93 68.04,157.62 U3.B20 ; v5(79.7,194.37) 79.96,194.12 79.96,193.76 79.58,193.38 CN6.19
  BOTTOM w0.099: v3(68.69,162.83) 69.12,163.26 69.12,163.83 68.94,164.01 68.94,164.44 70.24,165.74 70.24,167.03 70.55,167.34 70.55,170.72 71.11,171.28 71.11,179.14 70.6,179.65 69.69,179.65 68.25,181.1 68.25,184.85 68.57,185.17 69.21,185.17 74.48,190.44 75.39,190.44 76.1,191.15 76.1,192.41 77.13,193.44 78.91,193.44 79.18,193.18 79.18,193 80.61,191.57 80.88,191.57 81.24,191.93 81.24,192.39 80.23,193.4 80.23,194.11 79.97,194.37 v5(79.7,194.37)
NB_LVDS_L_TX3_DN: length 57.3
  TOP w0.099: U3.B19 67.24,157.05 67.57,157.38 67.57,157.69 67.46,158.02 67.46,159.73 68.29,160.55 68.29,162.06 v3(68.46,162.24) ; v2(76.72,194.13) 76.39,194.13 76.26,194 76.26,193.6 76.58,193.28 CN6.22
  BOTTOM w0.099: v3(68.46,162.24) 68.26,162.44 68.26,163.63 68.46,163.83 68.46,164.61 69.84,165.99 69.84,167.57 70.14,167.88 70.14,168.43 69.84,168.73 69.84,169.07 70.14,169.38 70.14,169.93 69.84,170.23 69.84,170.64 70.67,171.48 70.67,172.99 70.43,173.24 70.21,173.24 70.11,173.34 70.11,173.64 70.21,173.74 70.43,173.74 70.67,173.98 70.67,174.49 70.43,174.74 70.21,174.74 70.11,174.84 70.11,175.14 70.21,175.24 70.43,175.24 70.67,175.48 70.67,175.99 70.43,176.24 70.21,176.24 70.11,176.34 70.11,176.64 70.21,176.73 70.43,176.73 70.67,176.98 70.67,177.49 70.43,177.74 70.21,177.74 70.11,177.84 70.11,178.13 70.21,178.23 70.43,178.23 70.67,178.48 70.67,178.99 70.43,179.24 69.53,179.24 67.83,180.94 67.83,181.69 67.41,182.1 67.41,182.5 67.83,182.91 67.83,185.42 67.99,185.58 68.98,185.58 70.39,186.99 70.39,188.32 70.53,188.46 71.86,188.46 72.5,189.1 72.5,189.34 72.97,189.8 72.97,190.18 72.63,190.52 72.63,190.85 72.78,191.01 75.11,191.01 75.62,191.51 75.62,192.02 75.37,192.27 73.44,192.27 73.23,192.48 73.23,192.68 73.51,192.96 75.82,192.96 76.29,193.43 76.29,193.7 76.72,194.13 v2(76.72,194.13)
NB_LVDS_L_TX3_DP: length 57
  TOP w0.099: U3.A19 67.24,157.88 67.21,157.98 67.21,159.83 68.03,160.66 68.03,161.95 67.74,162.24 v3(67.74,162.24) ; CN6.23 75.58,193.29 76.01,193.73 76.01,194 75.96,194.06 75.86,194.16 v2(75.45,194.16)
  BOTTOM w0.099: v3(67.74,162.24) 68.01,162.51 68.01,163.73 68.21,163.93 68.21,164.72 69.58,166.09 69.58,167.68 69.89,167.99 69.89,168.32 69.58,168.63 69.58,169.18 69.89,169.48 69.89,169.82 69.58,170.13 69.58,170.74 70.42,171.58 70.42,172.89 70.32,172.99 70.11,172.99 69.86,173.24 69.86,173.74 70.11,173.99 70.32,173.99 70.42,174.09 70.42,174.39 70.32,174.49 70.11,174.49 69.86,174.73 69.86,175.24 70.11,175.49 70.32,175.49 70.42,175.59 70.42,175.89 70.32,175.99 70.11,175.99 69.86,176.23 69.86,176.74 70.11,176.99 70.32,176.99 70.42,177.09 70.42,177.38 70.32,177.48 70.11,177.48 69.86,177.73 69.86,178.24 70.11,178.49 70.32,178.49 70.42,178.59 70.42,178.88 70.32,178.98 69.43,178.98 67.57,180.84 67.57,181.58 67.16,182 67.16,182.6 67.57,183.02 67.57,185.53 67.88,185.84 68.88,185.84 70.14,187.1 70.14,188.43 70.43,188.71 71.76,188.71 72.25,189.2 72.25,189.44 72.71,189.91 72.71,190.08 72.38,190.41 72.38,190.96 72.68,191.26 75.01,191.26 75.37,191.62 75.37,191.91 75.27,192.01 73.34,192.01 72.98,192.38 72.98,192.79 73.41,193.22 75.72,193.22 76.04,193.54 76.04,194 75.88,194.16 v2(75.45,194.16)
NB_LVDS_U_CLK_DN: length 59.2
  TOP w0.099: v3(65.97,156.18) 65.97,155.78 65.86,155.66 U3.D17 ; v5(75.22,185.7) 75.63,185.7 75.86,185.93 75.86,186.39 75.58,186.66 CN6.8
  BOTTOM w0.099: v3(65.97,156.18) 65.77,156.39 65.77,156.95 66.69,157.86 66.69,158.35 66.41,158.62 65.42,158.62 65.26,158.78 65.26,158.98 65.36,159.08 66.9,159.08 67.17,159.34 67.17,159.72 66.87,160.02 65.38,160.02 65.26,160.14 65.26,160.4 65.39,160.53 66.03,160.53 66.3,160.8 66.3,161.31 66.49,161.49 68.82,161.49 68.92,161.39 68.92,161 69.18,160.73 69.59,160.73 69.86,161.01 69.86,162.13 69.99,162.26 70.24,162.26 70.37,162.13 70.37,161.01 70.64,160.73 71.11,160.73 71.38,161.01 71.38,161.42 71.46,161.49 72.1,161.49 72.76,162.15 72.76,163.32 73.82,164.39 73.82,165.66 72.88,166.6 72.88,169.44 73.44,170 73.44,179.26 73.76,179.58 75.18,179.58 75.43,179.83 75.43,180.58 75.13,180.89 72.83,180.89 71.03,182.68 71.03,183.48 74.43,186.87 75.52,186.87 75.86,186.54 75.86,186.01 75.54,185.7 v5(75.22,185.7)
NB_LVDS_U_CLK_DP: length 59.4
  TOP w0.099: v3(65.27,156.06) 64.87,155.66 U3.D16 ; v2(76.49,185.67) 76.11,186.06 76.11,186.23 76.58,186.7 CN6.9
  BOTTOM w0.099: v2(76.49,185.67) 76.49,185.7 76.11,186.08 76.11,186.64 75.63,187.12 74.32,187.12 70.78,183.58 70.78,182.58 71.5,181.86 72.73,180.63 75.02,180.63 75.18,180.48 75.18,179.93 75.08,179.83 73.66,179.83 73.19,179.36 73.19,170.11 72.63,169.55 72.63,166.49 73.57,165.55 73.57,164.49 72.5,163.43 72.5,162.26 71.99,161.75 71.36,161.75 71.13,161.52 71.13,161.11 71,160.99 70.75,160.99 70.62,161.11 70.62,162.23 70.35,162.51 69.88,162.51 69.61,162.23 69.61,161.11 69.48,160.99 69.29,160.99 69.17,161.1 69.17,161.5 68.92,161.75 66.39,161.75 66.05,161.41 66.05,160.91 65.92,160.78 65.29,160.78 65.01,160.51 65.01,160.03 65.27,159.77 66.76,159.77 66.91,159.61 66.91,159.45 66.8,159.33 65.26,159.33 65.01,159.09 65.01,158.68 65.32,158.37 66.3,158.37 66.43,158.24 66.43,157.97 65.52,157.05 65.52,156.31 v3(65.27,156.06)
NB_LVDS_U_TX0_DN: length 55.4
  TOP w0.099: v2(68.62,189.1) 69.07,188.65 69.07,188.19 68.58,187.69 CN6.1 ; v2(67.56,164.11) 67.31,163.86 67.31,163.64 67.45,163.5 67.45,163.26 67.31,163.12 67.31,162.94 67.41,162.84 67.41,162.67 67.31,162.57 67.31,162.19 67.2,162.08 67.2,161.93 67.04,161.77 66.89,161.77 66.44,161.32 66.44,161.19 66.3,161.05 66.17,161.05 66.03,160.91 66.03,159.41 66.18,159.26 66.35,159.09 66.35,158.15 U3.A18
  BOTTOM w0.099: v2(67.56,164.11) 67.22,164.45 67.22,164.56 67.68,165.03 67.76,165.03 67.83,165.03 68.12,165.31 68.12,165.39 68.12,165.46 68.4,165.75 68.48,165.75 68.55,165.75 68.84,166.03 68.84,166.11 68.84,166.18 68.97,166.32 68.97,166.89 69.1,167.02 69.1,167.42 68.97,167.55 68.97,167.95 69.1,168.08 69.1,168.48 68.97,168.61 68.97,169.01 69.1,169.14 69.1,169.54 68.97,169.67 68.97,170.08 69.1,170.2 69.1,170.61 68.97,170.73 68.97,171.26 69.46,171.75 69.46,172.3 69.15,172.6 69.15,172.94 69.46,173.25 69.46,173.8 69.15,174.1 69.15,174.44 69.46,174.75 69.46,175.29 69.15,175.6 69.15,175.94 69.46,176.25 69.46,176.79 69.15,177.1 69.15,178.22 68.75,178.62 68.75,179.06 68.48,179.33 68.04,179.33 67.83,179.54 67.83,179.98 67.56,180.25 67.12,180.25 66.83,180.54 66.83,181.39 66.52,181.7 66.12,181.7 65.55,182.27 65.55,182.78 65.65,182.89 66.72,182.89 66.97,183.14 66.97,183.74 66.72,183.99 65.65,183.99 65.55,184.09 65.55,184.57 65.65,184.67 66.86,184.67 67.13,184.95 67.13,185.43 66.89,185.68 65.69,185.68 65.55,185.81 65.55,186.42 66.09,186.96 66.31,186.96 66.93,186.34 68.56,186.34 69.67,187.46 69.67,187.86 69.43,188.1 68.78,188.1 67.98,187.29 67.39,187.29 66.81,187.87 66.81,188.73 68.16,190.07 68.75,190.07 69.03,189.8 69.03,189.54 68.62,189.13 v2(68.62,189.1)
NB_LVDS_U_TX0_DP: length 55.8
  TOP w0.099: v2(69.42,189.13) 69.33,189.04 69.33,187.99 69.58,187.74 CN6.2 ; U3.B18 66.44,157.62 66.09,157.97 66.09,158.99 65.77,159.31 65.77,161.01 67.05,162.29 67.05,163.84 v3(66.8,164.1)
  BOTTOM w0.099: v3(66.8,164.1) 66.97,164.27 66.97,164.67 68.72,166.42 68.72,171.37 69.2,171.85 69.2,172.19 68.9,172.5 68.9,173.05 69.2,173.35 69.2,173.69 68.9,174 68.9,174.54 69.2,174.85 69.2,175.19 68.9,175.5 68.9,176.04 69.2,176.35 69.2,176.69 68.9,176.99 68.9,178.11 68.5,178.51 68.5,178.95 68.38,179.08 67.93,179.08 67.58,179.43 67.58,179.87 67.45,180 67.01,180 66.58,180.43 66.58,181.28 66.42,181.45 66.01,181.45 65.29,182.16 65.29,182.89 65.54,183.14 66.62,183.14 66.72,183.24 66.72,183.63 66.62,183.73 65.54,183.73 65.29,183.98 65.29,184.68 65.54,184.93 66.75,184.93 66.88,185.05 66.88,185.32 66.78,185.42 65.58,185.42 65.29,185.71 65.29,186.52 65.98,187.22 66.42,187.22 67.04,186.6 68.45,186.6 69.42,187.57 69.42,187.75 69.33,187.84 68.89,187.84 68.08,187.04 67.29,187.04 66.56,187.77 66.56,188.83 68.05,190.32 68.86,190.32 69.28,189.9 69.28,189.27 v2(69.42,189.13)
NB_LVDS_U_TX1_DN: length 58.1
  TOP w0.099: v2(70.6,189.66) 70.6,189.65 70.89,189.36 70.89,188.15 70.57,187.84 CN6.3 ; v3(66.46,162.7) 66.4,162.7 66.21,162.51 66.21,162.19 65.47,161.44 65.47,159.08 65.84,158.71 65.84,157.9 65.97,157.77 65.97,157.52 65.64,157.19 U3.B17
  BOTTOM w0.099: v3(66.46,162.7) 66.41,162.7 66.2,162.91 66.2,164.51 68.29,166.59 68.29,175.66 68.04,175.91 67.03,175.91 66.89,176.05 66.89,176.26 67.03,176.4 68.04,176.4 68.29,176.65 68.29,178.11 67.22,179.18 66.51,179.18 65.86,178.53 65.58,178.53 65.45,178.66 65.45,179.7 65.55,179.8 65.93,179.8 66.18,180.05 66.18,180.56 65.93,180.8 65.55,180.8 65.45,180.9 65.45,181.41 64.89,181.97 64.89,186.73 65.86,187.7 65.86,188.81 70.96,193.91 71.65,193.91 71.86,193.69 71.86,193.48 71.69,193.3 71.06,193.3 69.61,191.85 69.61,190.95 69.99,190.58 70.73,190.58 70.88,190.43 70.88,189.95 v2(70.6,189.66)
NB_LVDS_U_TX1_DP: length 58.1
  TOP w0.099: U3.A17 65.58,157.72 65.58,158.61 65.21,158.98 65.21,161.55 65.96,162.29 65.96,162.49 65.76,162.69 v3(65.67,162.69) ; CN6.4 71.58,187.79 71.14,188.23 71.14,189.31 v2(71.45,189.61)
  BOTTOM w0.099: v2(71.45,189.61) 71.14,189.92 71.14,190.53 70.84,190.83 70.09,190.83 69.87,191.06 69.87,191.75 71.17,193.05 71.79,193.05 72.12,193.37 72.12,193.8 71.75,194.16 70.86,194.16 65.61,188.91 65.61,187.81 64.63,186.83 64.63,181.87 65.19,181.31 65.19,180.8 65.44,180.55 65.82,180.55 65.92,180.45 65.92,180.15 65.82,180.06 65.44,180.06 65.19,179.81 65.19,178.56 65.47,178.28 65.97,178.28 66.61,178.92 67.11,178.92 68.03,178 68.03,176.76 67.93,176.66 66.93,176.66 66.64,176.36 66.64,175.95 66.93,175.65 67.93,175.65 68.03,175.56 68.03,166.7 65.95,164.62 65.95,162.9 65.73,162.69 v3(65.67,162.69)
NB_LVDS_U_TX2_DN: length 58.1
  TOP w0.099: CN6.5 72.58,186.67 72.93,186.32 72.93,186.09 72.85,186.01 72.85,185.77 72.93,185.7 72.93,185.45 72.83,185.36 72.83,185.14 72.93,185.04 72.93,184.43 73.29,184.07 74.59,184.07 74.79,183.87 74.79,183.59 74.66,183.46 74.33,183.46 v2(74.26,183.54) ; U3.D21 68.6,155.91 68.6,156.22 68.6,156.23 68.6,156.67 68.54,156.73 68.54,156.98 68.6,157.04 68.6,157.47 68.54,157.53 68.54,157.78 68.6,157.84 68.6,158.56 v3(68.72,158.67)
  BOTTOM w0.099: v3(68.72,158.67) 68.72,158.9 68.84,159.03 68.97,159.03 69.65,158.34 70.06,158.34 70.18,158.22 70.45,158.22 70.58,158.34 70.85,158.34 70.98,158.22 71.25,158.22 71.37,158.34 71.97,158.34 74.31,160.68 74.31,162.81 75.7,164.21 75.7,167.87 75.43,168.15 75.05,168.15 74.94,168.25 74.94,168.55 75.05,168.66 75.43,168.66 75.57,168.79 75.7,168.93 75.7,169.53 75.46,169.77 74.94,169.77 74.84,169.87 74.84,170.31 74.97,170.43 75.43,170.43 75.7,170.71 75.7,171.2 75.45,171.45 74.94,171.45 74.84,171.55 74.84,171.98 74.94,172.09 75.43,172.09 75.7,172.36 75.7,172.85 75.45,173.1 74.94,173.1 74.81,173.23 74.81,173.48 74.94,173.61 75.43,173.61 75.7,173.88 75.7,174.37 75.45,174.62 74.97,174.62 74.84,174.75 74.84,175.03 74.98,175.17 75.43,175.17 75.7,175.44 75.7,175.87 75.43,176.15 74.97,176.15 74.84,176.28 74.84,176.53 74.97,176.66 75.44,176.66 75.7,176.92 75.7,177.33 75.46,177.58 74.94,177.58 74.84,177.68 74.84,177.93 74.97,178.05 76.52,178.05 77,178.53 77,180.24 78.06,181.3 78.06,181.99 77.79,182.27 73.38,182.27 72.93,182.72 72.93,183.42 73.6,184.1 74.68,184.1 74.76,184.01 74.76,183.75 74.55,183.54 v2(74.26,183.54)
NB_LVDS_U_TX2_DP: length 58.7
  TOP w0.099: CN6.6 73.58,186.67 73.18,186.28 73.18,184.54 73.39,184.33 74.69,184.33 75.04,183.98 75.04,183.78 75.29,183.54 v5(75.53,183.54) ; v3(68.69,159.41) 68.27,158.99 68.27,158.45 68.35,158.37 68.35,157.93 68.28,157.87 68.28,157.45 68.35,157.39 68.35,157.13 68.28,157.07 68.28,156.65 68.35,156.58 68.35,156.33 68.34,156.33 68.34,155.96 U3.D20
  BOTTOM w0.099: v3(68.69,159.41) 68.82,159.28 69.07,159.28 69.76,158.6 71.87,158.6 74.05,160.78 74.05,162.92 75.45,164.32 75.45,167.77 75.32,167.89 74.94,167.89 74.69,168.15 74.69,168.66 74.94,168.91 75.32,168.91 75.45,169.04 75.45,169.42 75.35,169.52 74.83,169.52 74.59,169.77 74.59,170.41 74.86,170.69 75.32,170.69 75.45,170.81 75.45,171.09 75.34,171.2 74.84,171.2 74.59,171.45 74.59,172.09 74.84,172.34 75.32,172.34 75.45,172.47 75.45,172.74 75.34,172.85 74.84,172.85 74.56,173.12 74.56,173.59 74.84,173.86 75.32,173.86 75.45,173.99 75.45,174.27 75.34,174.37 74.86,174.37 74.59,174.65 74.59,175.14 74.87,175.42 75.32,175.42 75.45,175.55 75.45,175.77 75.32,175.9 74.86,175.9 74.59,176.17 74.59,176.64 74.86,176.91 75.33,176.91 75.45,177.03 75.45,177.22 75.35,177.32 74.83,177.32 74.59,177.57 74.59,178.03 74.86,178.31 76.42,178.31 76.74,178.63 76.74,180.34 77.81,181.41 77.81,181.89 77.68,182.02 73.27,182.02 72.68,182.61 72.68,183.53 73.5,184.35 74.78,184.35 75.02,184.12 75.02,183.72 75.2,183.54 v5(75.53,183.54)
NB_LVDS_U_TX3_DN: length 60
  TOP w0.099: v2(77.42,183.77) 77.76,183.77 77.93,183.94 77.93,186.31 77.57,186.66 CN6.10 ; v3(67.07,160.4) 66.91,160.55 66.77,160.55 66.58,160.37 66.58,159.69 67,159.28 67,158.29 67,158.29 67,157.84 66.94,157.78 66.94,157.53 67,157.47 67,157.04 66.94,156.98 66.94,156.73 67,156.67 67,155.77 67.11,155.66 U3.D19
  BOTTOM w0.099: v3(67.07,160.4) 67.22,160.55 67.42,160.55 67.93,160.05 71.6,160.05 73.44,161.88 73.44,162.94 74.74,164.24 74.74,165.74 73.57,166.9 73.57,169.04 74.13,169.6 74.13,178.33 74.63,178.84 75.85,178.84 76.28,179.27 76.28,180.48 76.69,180.9 76.69,181.32 76.44,181.57 73.11,181.57 71.86,182.82 71.86,183.34 73.28,184.76 77.05,184.76 77.94,185.65 77.94,187.52 78.11,187.7 78.56,187.7 78.66,187.6 78.66,185.77 78.07,185.19 78.07,183.99 77.85,183.77 v2(77.42,183.77)
NB_LVDS_U_TX3_DP: length 60.3
  TOP w0.099: CN6.11 78.58,186.74 78.18,186.35 78.18,184.28 v5(78.69,183.77) ; U3.D18 66.75,155.96 66.75,156.62 66.68,156.68 66.68,157.07 66.75,157.13 66.75,157.39 66.68,157.45 66.68,157.87 66.75,157.93 66.75,158.19 66.74,158.19 66.74,159.18 66.33,159.59 66.33,160.48 66.66,160.81 66.79,160.81 v3(67.04,161.06)
  BOTTOM w0.099: v5(78.69,183.77) 78.68,183.77 78.33,184.13 78.33,185.08 78.91,185.67 78.91,187.71 78.67,187.95 78.01,187.95 77.68,187.62 77.68,185.76 76.94,185.02 73.18,185.02 71.61,183.45 71.61,182.71 73,181.32 76.34,181.32 76.44,181.22 76.44,181 76.02,180.59 76.02,179.37 75.74,179.09 74.53,179.09 73.87,178.44 73.87,169.7 73.32,169.14 73.32,166.8 74.48,165.63 74.48,164.34 73.19,163.05 73.19,161.99 71.5,160.3 68.04,160.3 67.53,160.81 67.3,160.81 v3(67.04,161.06)
NB_OSC: length 151.9
  TOP w0.13: v3(60.16,155.13) 60.43,154.86 U3.E11
  INT1 w0.114: v2(61.37,182.88) 60.86,183.39 47.38,183.39 38.36,174.37 38.36,166.44 30.06,158.13 30.06,147.19 30.41,146.84 30.41,142.32 31.63,141.1 31.63,129.03 31.89,128.78 31.89,128.14 31,127.25 31,119.13 35.19,114.94 35.19,110.36 37.48,108.08 39.89,108.08 43.83,104.14 v2(43.83,95.5)
  BOTTOM w0.13: v2(43.83,95.5) 43.57,95.76 R601.1 R609.1 ; v2(61.37,182.88) 60.44,181.95 60.44,179.55 56.14,175.26 56.14,170.13 56.65,169.62 56.65,168.66 56.91,168.4 v1(57.35,168.4) 57.8,167.96 57.8,164.97 57.92,164.85 57.92,158.24 59.11,157.05 59.11,155.81 59.79,155.13 v3(60.16,155.13)
NB_OSC_R: length 5.1
  BOTTOM w0.13: U20.2 39.09,97.82 39.32,98.04 40.02,98.04 40.65,97.41 40.65,96.9 v1(40.78,96.77) 41.48,96.08 41.67,96.08 41.98,95.76 R601.2
NB_PANEL_ID0: length 6
  TOP w0.102: CN7.35 49.99,191.45 50.63,190.82 52.02,190.82 52.4,191.2 v2(52.4,191.52)
  BOTTOM w0.102: R242.1 v2(52.4,191.52) 52.4,191.67 v1(51.93,192.14)
NB_PANEL_ID2: length 8.9
  TOP w0.102: CN7.36 48.99,191.64 50.14,190.5 v2(52.4,190.5)
  BOTTOM w0.102: v2(52.4,190.5) R241.1 53.11,190.71 53.41,191.01 55.45,191.01 v1(55.76,191.33)
NB_PWRGD: length 94.2
  TOP w0.102: v3(71.45,94.36) 73.38,96.29 85.14,96.29 87.5,93.93 102.31,93.93 104.42,91.82 114.08,91.82 115.86,90.04 115.86,80.49 116.72,79.63 116.72,76.83 116.34,76.45 v2(116.34,71.75) ; v3(101.87,68.43) 101.87,68.44 101.32,68.99 U10.AC19 ; R223.2 66.24,98.68 65.99,98.42 65.99,96.2 66.16,96.03 R224.1 66.5,94.04 v3(66.48,94.03)
  BOTTOM w0.102: v2(116.34,71.75) 116.34,71.69 116.08,71.42 v1(114.23,71.42) 113.91,71.42 112.57,70.08 110.6,70.08 109.59,69.06 105.85,69.06 104.71,67.92 102.39,67.92 v3(101.87,68.43) ; v3(71.45,94.36) 71.02,93.93 66.58,93.93 v3(66.48,94.03)
NB_PWRGD_IN: length 16.6
  TOP w0.102: v1(50.87,169.86) 51.6,169.13 51.6,168.04 R133.2 52,167.21 52.33,166.88 52.97,166.88 54.99,164.86 56.06,164.86 58.11,162.8 58.11,162.39 59.95,160.55 59.95,158.15 U3.A10
NB_RST_IN_N: length 209
  TOP w0.102: U3.D8 58.8,156.02 58.8,157.26 58.67,157.59 58.67,157.74 58.77,157.99 58.77,158.2 58.74,158.28 58.62,158.41 58.62,158.77 57.47,159.92 57.21,159.92 54.63,162.5 50.98,162.5 48.02,165.46 48.02,169.04 47.25,169.8 v2(46.24,169.8) 43.65,169.8 42.78,168.94 42.78,166.5 35.27,158.98 35.27,146.99 36.41,145.85 37.25,145.85 39.48,143.61 40.3,143.61 42.38,141.53 42.38,138.25 42.66,137.97 42.66,128.4 57.03,114.02 57.03,104.37 61.61,99.79 61.61,96.77 61.83,96.55 61.83,90.68 61.45,90.3 61.45,88.73 63.21,86.98 63.21,84.66 62.42,83.87 62.42,74.07 61.25,72.9 61.25,71.21 60.64,70.6 60.64,69.27 61,68.91 61,61.11 62.65,59.46 62.65,55.09 v2(62.75,54.99) ; R123.2 R122.2 48.51,172.15 46.3,172.15 v2(46.18,172.02) Q7.D ; v2(90.13,40.39) 90.13,40.26 90.81,39.58 R457.2
  BOTTOM w0.102: v2(46.24,169.8) 46.24,171.7 46.18,171.77 v2(46.18,172.02) ; v2(90.13,40.39) v1(88.78,40.39) 84.69,40.39 83.3,38.99 65.19,38.99 63.79,40.39 63.79,44.03 64.17,44.41 64.17,53.57 v2(62.75,54.99)
NB_THERMDA: length 113.6
  TOP w0.254: v2(56.5,39.9) 57.16,39.24 C285.1 C288.1 57.24,37.97 R409.1 ; R189.2 57.54,131.32 57.54,129.92 56.73,129.11 56.73,124.83 58.43,123.13 58.43,122.42 57.75,121.73 57.75,116.2 58.43,115.52 58.43,105.22 v2(59.13,104.52)
  BOTTOM w0.254: v2(59.13,104.52) 56.92,104.52 55.77,103.38 52.59,100.19 52.59,95.68 49.29,92.38 49.29,90.04 48.45,89.2 48.45,85.34 47.76,84.66 47.76,80.63 45.52,78.39 45.52,72.81 45.07,72.36 45.07,64.04 46.43,62.67 46.43,49.66 45.73,48.96 45.73,47.96 46.62,47.07 50.31,47.07 50.96,46.41 50.96,45.34 51.67,44.63 53.52,44.63 55.14,43 55.14,41.26 v1(55.92,40.49) v2(56.5,39.9)
NB_THERMDA_R: length 7.2
  TOP w0.254: R189.1 57.8,133.04 57.8,133.73 v1(57.41,134.11) 57.87,134.57 57.87,135 58.51,135.64 58.51,138.79 U3.AE8
NB_THERMDC: length 110.7
  TOP w0.254: v2(54.34,41.61) 54.6,41.35 55.92,41.35 57.01,40.26 R434.1 ; R190.2 58.05,131.22 58.05,129.54 57.29,128.78 57.29,125.03 58.94,123.38 58.94,122.2 58.33,121.59 58.33,116.38 58.94,115.77 58.94,105.6 v2(59.13,105.41)
  BOTTOM w0.254: v2(54.34,41.61) 54.34,43.09 53.31,44.12 51.37,44.12 50.46,45.03 50.46,46.2 50.1,46.56 46.32,46.56 45.2,47.67 45.2,49.25 45.92,49.97 45.92,62.42 44.56,63.78 44.56,72.68 45.01,73.13 45.01,78.6 47.25,80.85 47.25,84.91 47.94,85.6 47.94,89.53 48.72,90.31 48.72,92.67 51.95,95.91 51.95,100.3 57.06,105.41 v2(59.13,105.41)
NB_THERMDC_R: length 8.3
  TOP w0.254: R190.1 58.46,132.51 v1(59.09,133.15) 58.94,133.15 58.38,133.71 58.38,134.77 59.02,135.41 59.02,138.91 58.56,139.37 58.56,139.54 U3.AD8
NB_VDDHT: length 33.6
  TOP w0.254: U3.J17 65.24,151.26
  TOP w0.3: 65.24,151.26 U3.K16 64.84,150.85 v3(65.24,150.45) 64.85,150.06 U3.L16 64.98,149.92 64.98,149.09 U3.M16 64.57,148.68 v3(64.57,148.51)
  TOP w0.305: U3.T16 64.68,146.22 64.68,146.7 U3.R16 U3.P16 64.83,147.96 64.57,148.22 v3(64.57,148.51)
  TOP w0.889: v2(79.39,163.96) v2(79.39,164.85) 79.39,165.23 78.62,165.99 78.62,168.28 78.12,168.78
  BOTTOM w0.305: v3(65.24,150.45) 65.24,150.13 64.98,149.87 64.98,148.92 v3(64.57,148.51)
  BOTTOM w0.4: 65.24,151.26 65.24,151.23 65.37,151.1 66.09,151.1 65.44,150.45 v3(65.24,150.45)
  BOTTOM w0.508: 71.16,155.14 70.31,155.83 69.86,155.83 69.48,155.45 ; C367.1 79.39,162.81
  BOTTOM w0.889: 71.16,155.14 73.9,155.14 77.73,158.98 v1(77.73,160.59) 77.73,161.16 79.39,162.81 v2(79.39,163.96) v2(79.39,164.85)
NB_VGA_B: length 198.3
  TOP w0.165: R95.2 R95.1 R94.1 11.57,219.76 13.74,221.93 v2(16.27,221.93) ; U3.E19 66.84,155.26 v3(66.84,155.28)
  BOTTOM w0.165: v3(66.84,155.28) 66.84,156.37 68.11,157.63 70.25,157.63 71.46,156.42 72.66,156.42 73.19,156.95 75.62,159.38 75.62,162.21 77.09,163.69 77.09,175.47 78.35,176.73 78.35,179.73 82.56,183.94 82.56,189.04 83.56,190.04 83.56,199.94 83.7,200.09 83.7,205.3 85.72,207.31 85.72,211.18 87.9,213.37 87.9,234.18 v1(84.01,238.08) 82.94,239.14 48.53,239.14 44.74,235.35 32.8,235.35 22.24,224.79 22.24,223.08 21.09,221.93 v2(16.27,221.93)
NB_VGA_G: length 201.4
  TOP w0.102: U3.E18 66.44,154.9
  TOP w0.165: v3(66.09,155.26) 66.44,154.91 66.44,154.9 ; R93.1 R93.2 ; R93.1 R92.1 ; R93.1 10.55,220.01 13.3,222.76 v2(17.35,222.76)
  BOTTOM w0.165: v3(66.09,155.26) 66.09,155.25 66.58,154.76 66.99,154.76 67.32,155.09 67.32,155.45 68.07,156.19 68.07,156.85 68.52,157.3 70.1,157.3 71.26,156.15 73,156.15 76.19,159.34 76.19,161.97 77.67,163.45 77.67,175.13 78.98,176.44 78.98,179.55 84.18,184.75 84.18,199.55 84.28,199.64 84.28,205.04 86.29,207.05 86.29,210.86 88.47,213.05 88.47,234.63 v1(85.81,237.28) 83.32,239.78 48.36,239.78 44.55,235.97 32.59,235.97 19.38,222.76 v2(17.35,222.76)
NB_VGA_R: length 206.3
  TOP w0.165: R91.1 8.52,218.95 13.09,223.52 v2(17.37,223.52) ; R91.1 R91.2 ; R91.1 R90.1 ; v3(65.74,154.66) 65.74,154.13 66.44,153.43 U3.G18
  BOTTOM w0.165: v3(65.74,154.66) 65.85,154.66 66.17,154.34 67.18,154.34 67.68,154.84 67.68,155.3 68.46,156.08 68.46,156.5 68.84,156.89 70.05,156.89 71.06,155.87 73.38,155.87 76.78,159.27 76.78,161.7 78.24,163.16 78.24,174.87 79.58,176.22 79.58,179.34 84.75,184.51 84.75,199.23 84.85,199.33 84.85,204.72 86.86,206.74 86.86,210.55 89.04,212.73 89.04,235.2 v1(88.04,236.2) 83.8,240.44 47.54,240.44 43.63,236.54 32.33,236.54 19.31,223.52 v2(17.37,223.52)
NBLINK_RCLK_DN: length 64.8
  TOP w0.099: R155.1 44.78,141.5 45.17,141.88 v2(45.73,141.88) 45.94,142.1 47.27,142.1 48.05,142.87 50.05,142.87 50.12,142.95 50.28,143.1 50.46,143.1 50.66,143.31 50.66,143.48 50.79,143.61 51.01,143.61 51.14,143.74 51.14,143.96 51.27,144.09 51.5,144.09 51.62,144.22 51.62,144.45 51.88,144.7 52.66,144.7 52.71,144.76 52.97,144.76 53.03,144.7 53.45,144.7 53.51,144.76 53.77,144.76 53.83,144.7 54.03,144.7 54.27,144.46 U3.V3
  INT1 w0.089: v2(45.73,141.88) 45.41,142.2 43.14,142.2 42.58,142.76 40.62,142.76 40.13,142.27 40.13,139.17 40.93,138.37 40.93,123.68 41.97,122.63 43.13,122.63 43.7,122.06 43.7,118.75 40.65,115.7 40.65,114.11 42.23,112.53 42.23,111.77 v2(42.56,111.44)
  BOTTOM w0.099: R582.2 33.16,109.9 33.16,110.4 35.28,112.52 41.9,112.52 42.24,112.18 42.24,111.76 v2(42.56,111.44)
NBLINK_RCLK_DP: length 65
  TOP w0.099: U3.V4 54.87,144.46 54.57,144.76 54.33,144.76 54.14,144.95 53.92,144.95 53.85,145.01 53.43,145.01 53.37,144.95 53.12,144.95 53.05,145.01 52.61,145.01 52.55,144.96 51.78,144.96 51.46,144.64 51.19,144.37 49.95,143.13 47.94,143.13 47.16,142.35 46.1,142.35 v5(45.78,142.67) 45.08,142.67 44.77,142.98 R153.1
  INT1 w0.089: v5(45.78,142.67) 45.55,142.44 43.24,142.44 42.68,143 40.52,143 39.89,142.37 39.89,139.07 40.69,138.27 40.69,123.58 41.87,122.39 43.03,122.39 43.46,121.96 43.46,118.85 40.41,115.8 40.41,114.01 41.99,112.43 41.99,111.83 v2(41.6,111.44)
  BOTTOM w0.099: R581.2 33.41,109.9 33.41,110.3 35.38,112.27 41.79,112.27 41.98,112.08 41.98,111.82 v2(41.6,111.44)
NBSILK_CLK_R_DN: length 5.6
  BOTTOM w0.099: R582.1 33.16,108.28 33.16,107.77 32.95,107.57 v1(32.65,107.57) 33.16,107.06 33.16,106.72 32.93,106.49 32.04,106.49 31.71,106.16 31.71,105.85 31.59,105.73 U20.40
NBSILK_CLK_R_DP: length 5.6
  BOTTOM w0.099: R581.1 33.41,108.28 33.41,107.77 33.62,107.57 v1(33.92,107.57) 33.41,107.06 33.41,106.62 33.03,106.24 32.14,106.24 31.97,106.06 31.97,105.85 32.09,105.73 U20.41
NC_MXM_GPIO0: length 5.8
  TOP w0.102: CN1.26 83.75,217.03 84.4,217.68 v2(86.12,217.68)
  BOTTOM w0.102: v2(86.12,217.68) 86.69,217.68 TP106.1
NC_MXM_GPIO1: length 7.1
  TOP w0.102: CN1.28 83.25,217.42 83.83,218 85.67,218 v2(86.18,218.5)
  BOTTOM w0.102: TP105.1 v2(86.18,218.5)
NC_MXM_GPIO2: length 9.4
  TOP w0.102: v2(85.35,218.5) 83.32,218.5 82.75,217.93 CN1.30
  BOTTOM w0.102: v2(85.35,218.5) 86.24,219.39 86.24,219.84 87.01,220.6 TP104.1
P2E_SLOT0_PRSNT_1_N: length 315.2
  TOP w0.102: v2(90.36,219.02) 79.38,219.02 v2(78.57,218.21) ; v2(72.17,94.31) 72.65,94.79 73.39,94.79 73.99,95.39 84.2,95.39 86.55,93.04 101.94,93.04 104.08,90.91 112.3,90.91 115.33,87.88 115.33,74.68 113.93,73.28 110.5,73.28 107.74,70.52 U10.AJ21 ; v3(60.15,93.92) 59.7,94.36 59.7,97.83 54.85,102.68 54.85,112.32 48.78,118.39 41.64,118.39 39.58,120.45 39.58,136.21 37.58,138.22 37.58,141.71 36.38,142.9 35.65,142.9 34.25,144.3 32.82,144.3 27.9,149.22 27.9,152.84 23.67,157.07 22.85,157.07 20.51,159.41 18.6,159.41 15.72,162.29 15.72,171.83 13.43,174.12 13.43,179.21 15.72,181.51 15.72,200.19 17.13,201.6 17.13,203.61 18.57,205.04 28.01,205.04 28.59,205.61 30.87,205.61 33.79,202.69 61.35,202.69 63.76,200.28 v2(74.05,200.28)
  BOTTOM w0.102: v3(60.15,93.92) v1(62.62,93.92) 62.88,93.92 63.27,93.52 71.38,93.52 v2(72.17,94.31) ; v2(74.05,200.28) 76.97,203.2 77.86,203.2 78.65,203.99 78.65,210.72 79.84,211.91 79.84,214.88 78.57,216.15 v2(78.57,218.21) ; R528.1 v2(90.36,219.02)
P2E_SLOT0_PRSNT_1_N_R: length 6.3
  TOP w0.102: CN1.2 89.75,216.33 90.34,216.92 v2(91.83,216.92)
  BOTTOM w0.102: R528.2 R525.2 92.19,217.27 v2(91.83,216.92)
P2E_SLOT0_PRSNT_2_N: length 5.4
  TOP w0.102: v1(19,227.01) 19.46,226.55 R42.2 20,225.26 CN1.281
PANEL_ID0: length 379.6
  TOP w0.102: v2(183.02,67.44) 183.78,67.44 184.15,67.07 R308.1 ; v3(68.54,89.64) 68.54,89.66 68.87,89.99 68.87,93.07 72.92,97.12 85.52,97.12 87.89,94.74 102.65,94.74 104.75,92.65 115.5,92.65 116.92,91.23 116.92,80.96 117.74,80.14 117.74,77.17 119.07,75.84 134.61,75.84 135.9,74.55 141.35,74.55 141.85,75.05 143.37,75.05 145.17,73.26 145.17,68.49 147.24,66.42 R290.2 151.52,66.42 152.03,65.91 158,65.91 159.14,64.77 v2(159.9,64.77) ; U10.E28 87.64,76.3 88.28,76.94 88.28,78.23 87.51,78.99 85.9,78.99 82.73,82.17 v2(81.8,82.17) ; v2(26.81,153.03) 26.36,152.59 26.36,150.81 25.73,150.18 13.94,150.18 9.03,145.26 9.03,118.44 18.96,108.51 22.98,108.51 24.39,109.92 31.38,109.92 31.76,109.54 31.76,106.74 32.65,105.85 36.59,105.85 37.8,107.07 41.36,107.07 52.33,96.1 52.33,95.38 54.31,93.4 54.31,92.28 55.38,91.21 55.38,89.66 55.13,89.41 55.13,88.71 55.45,88.39 v2(55.64,88.39) ; v2(27.78,168.16) R245.2 29.93,168.16 31.45,169.68 31.45,177.9 42.4,188.85 48.97,188.85 49.73,189.61 55,189.61 55.45,190.06 55.45,190.94 v2(54.87,191.52)
  BOTTOM w0.102: v2(81.8,82.17) 81.32,82.65 81.32,82.88 79.87,84.33 79.77,84.33 77.61,86.49 76.34,86.49 73.48,89.34 72.21,89.34 71.97,89.1 69.07,89.1 v3(68.54,89.64) 68.25,89.34 63.76,89.34 63.57,89.53 62.49,89.53 61.99,89.03 58.56,89.03 57.92,89.66 55.38,89.66 55.13,89.41 55.13,88.9 v2(55.64,88.39) ; v2(27.78,168.16) 27.46,168.16 26.93,167.64 26.93,157.99 25.92,156.97 25.92,155.19 26.81,154.31 v2(26.81,153.03) ; R242.2 v2(54.87,191.52) ; v2(159.9,64.77) 162.19,64.77 162.57,64.39 162.57,63.63 162.39,63.45 v1(162.39,61.67) 162.39,59.74 164.48,57.66 170.44,57.66 171.33,58.55 177.11,58.55 177.3,58.74 180.54,58.74 180.8,58.99 182.26,58.99 183.78,60.52 183.78,66.67 v2(183.02,67.44)
PANEL_ID0_R: length 3.1
  TOP w0.102: v1(185.43,66.74) 185.44,66.73 R308.2 185.44,65.4 CN27.14
PANEL_ID1: length 195.9
  TOP w0.102: v3(87.06,78.26) 87.41,78.26 87.79,77.88 87.79,77.07 U10.E29 ; v2(160.54,65.28) 159.01,65.28 157.24,67.06 152.03,67.06 151.52,67.56 R287.2 150.51,67.56 150.12,67.18 146.81,67.18 145.42,68.57 145.42,73.41 143.52,75.31 141.7,75.31 141.15,74.75 136.03,74.75 134.73,76.05 119.19,76.05 117.99,77.24 117.99,80.2 117.12,81.07 117.12,91.37 115.64,92.85 104.86,92.85 102.77,94.95 88.07,94.95 85.7,97.32 72.82,97.32 68.64,93.14 68.64,90.37 68.08,89.81 68.08,88.82 v2(69.1,87.81) ; R320.1 184.02,61.14 184.99,62.1 184.99,63.88 184.35,64.52 183.53,64.52 183.14,64.9 183.14,65.91 v2(182.13,66.93)
  BOTTOM w0.102: v2(160.54,65.28) 162.06,65.28 162.95,64.39 162.95,60.22 165.26,57.91 168.79,57.91 171.46,60.58 175.27,60.58 v1(175.91,59.94) 176.86,58.99 180.41,58.99 180.67,59.25 182.13,59.25 183.53,60.64 183.53,65.53 v2(182.13,66.93) ; v3(87.06,78.26) 85.69,78.26 85.14,78.8 84.93,78.8 84.28,79.46 81.21,79.46 75.51,85.15 75.51,86.3 73.23,88.58 72.46,88.58 72.21,88.33 69.62,88.33 v2(69.1,87.81)
PANEL_ID1_R: length 3.6
  TOP w0.102: CN27.9 186.49,59.15 R320.2 185.31,61.41 v1(185.37,61.47)
PANEL_ID2: length 346
  TOP w0.102: v2(76.97,85.98) 76.97,87 79.61,89.64 81.37,89.64 82.48,90.75 89.39,90.75 89.55,90.6 96.3,90.6 96.96,91.26 101.67,91.26 103.6,89.33 109.94,89.33 111.69,87.58 v2(111.69,86.39) ; v2(54.87,190.5) 54.24,189.87 49.6,189.87 48.84,189.1 42.33,189.1 31.2,177.97 31.2,172.55 R243.2 28.35,170.45 v2(28.08,170.18) ; v2(55.64,89.15) 55.64,91.31 54.57,92.38 54.57,93.5 52.59,95.48 52.59,96.2 41.48,107.31 37.67,107.31 37.43,107.07 35.52,107.07 35.13,106.68 35.13,106.35 34.87,106.1 32.75,106.1 32,106.84 32,109.64 31.42,110.23 24.4,110.23 22.89,108.72 19.46,108.72 10.4,117.79 10.4,146.29 14.03,149.92 25.86,149.92 26.87,150.94 v2(26.87,151.89) ; U10.B28 85.24,76.37 84.55,77.05 84.33,77.05 80.66,80.72 v2(80.66,81.66) ; v2(139.46,72.77) 142.84,72.77 144.54,71.07 144.54,68.38 147.64,65.28 R294.2 151.52,65.28 152.03,64.77 156.6,64.77 156.86,65.02 158.51,65.02 159.27,64.26 v2(160.54,64.26) ; v2(177.68,58.23) 177.68,55.37 179.33,53.72 180.22,53.72 181.49,52.45 183.27,52.45 183.9,53.08 R344.1
  BOTTOM w0.102: v2(111.69,86.39) 112.38,86.39 113.49,85.28 v1(130.44,85.28) 132.03,85.28 135.27,82.04 135.27,76.96 v2(139.46,72.77) ; v2(26.87,151.89) 26.24,152.53 26.24,154.5 25.66,155.07 25.66,157.1 26.68,158.12 26.68,167.96 27,168.28 27,169.74 27.44,170.18 v2(28.08,170.18) ; R241.2 v2(54.87,190.5) ; v2(160.54,64.26) 161.17,64.26 161.76,63.68 161.76,59.99 164.35,57.4 170.57,57.4 171.46,58.29 177.62,58.29 v2(177.68,58.23) ; v2(80.66,81.66) 80.66,81.92 80.08,82.49 80.08,82.74 78.02,84.8 77.77,84.8 76.97,85.6 v2(76.97,85.98) 76.46,85.98 74.94,87.5 74.94,87.57 73.42,89.09 72.34,89.09 72.08,88.84 68.27,88.84 68.02,89.09 63.64,89.09 63.45,89.28 62.62,89.28 62.11,88.77 58.37,88.77 57.99,89.15 v2(55.64,89.15)
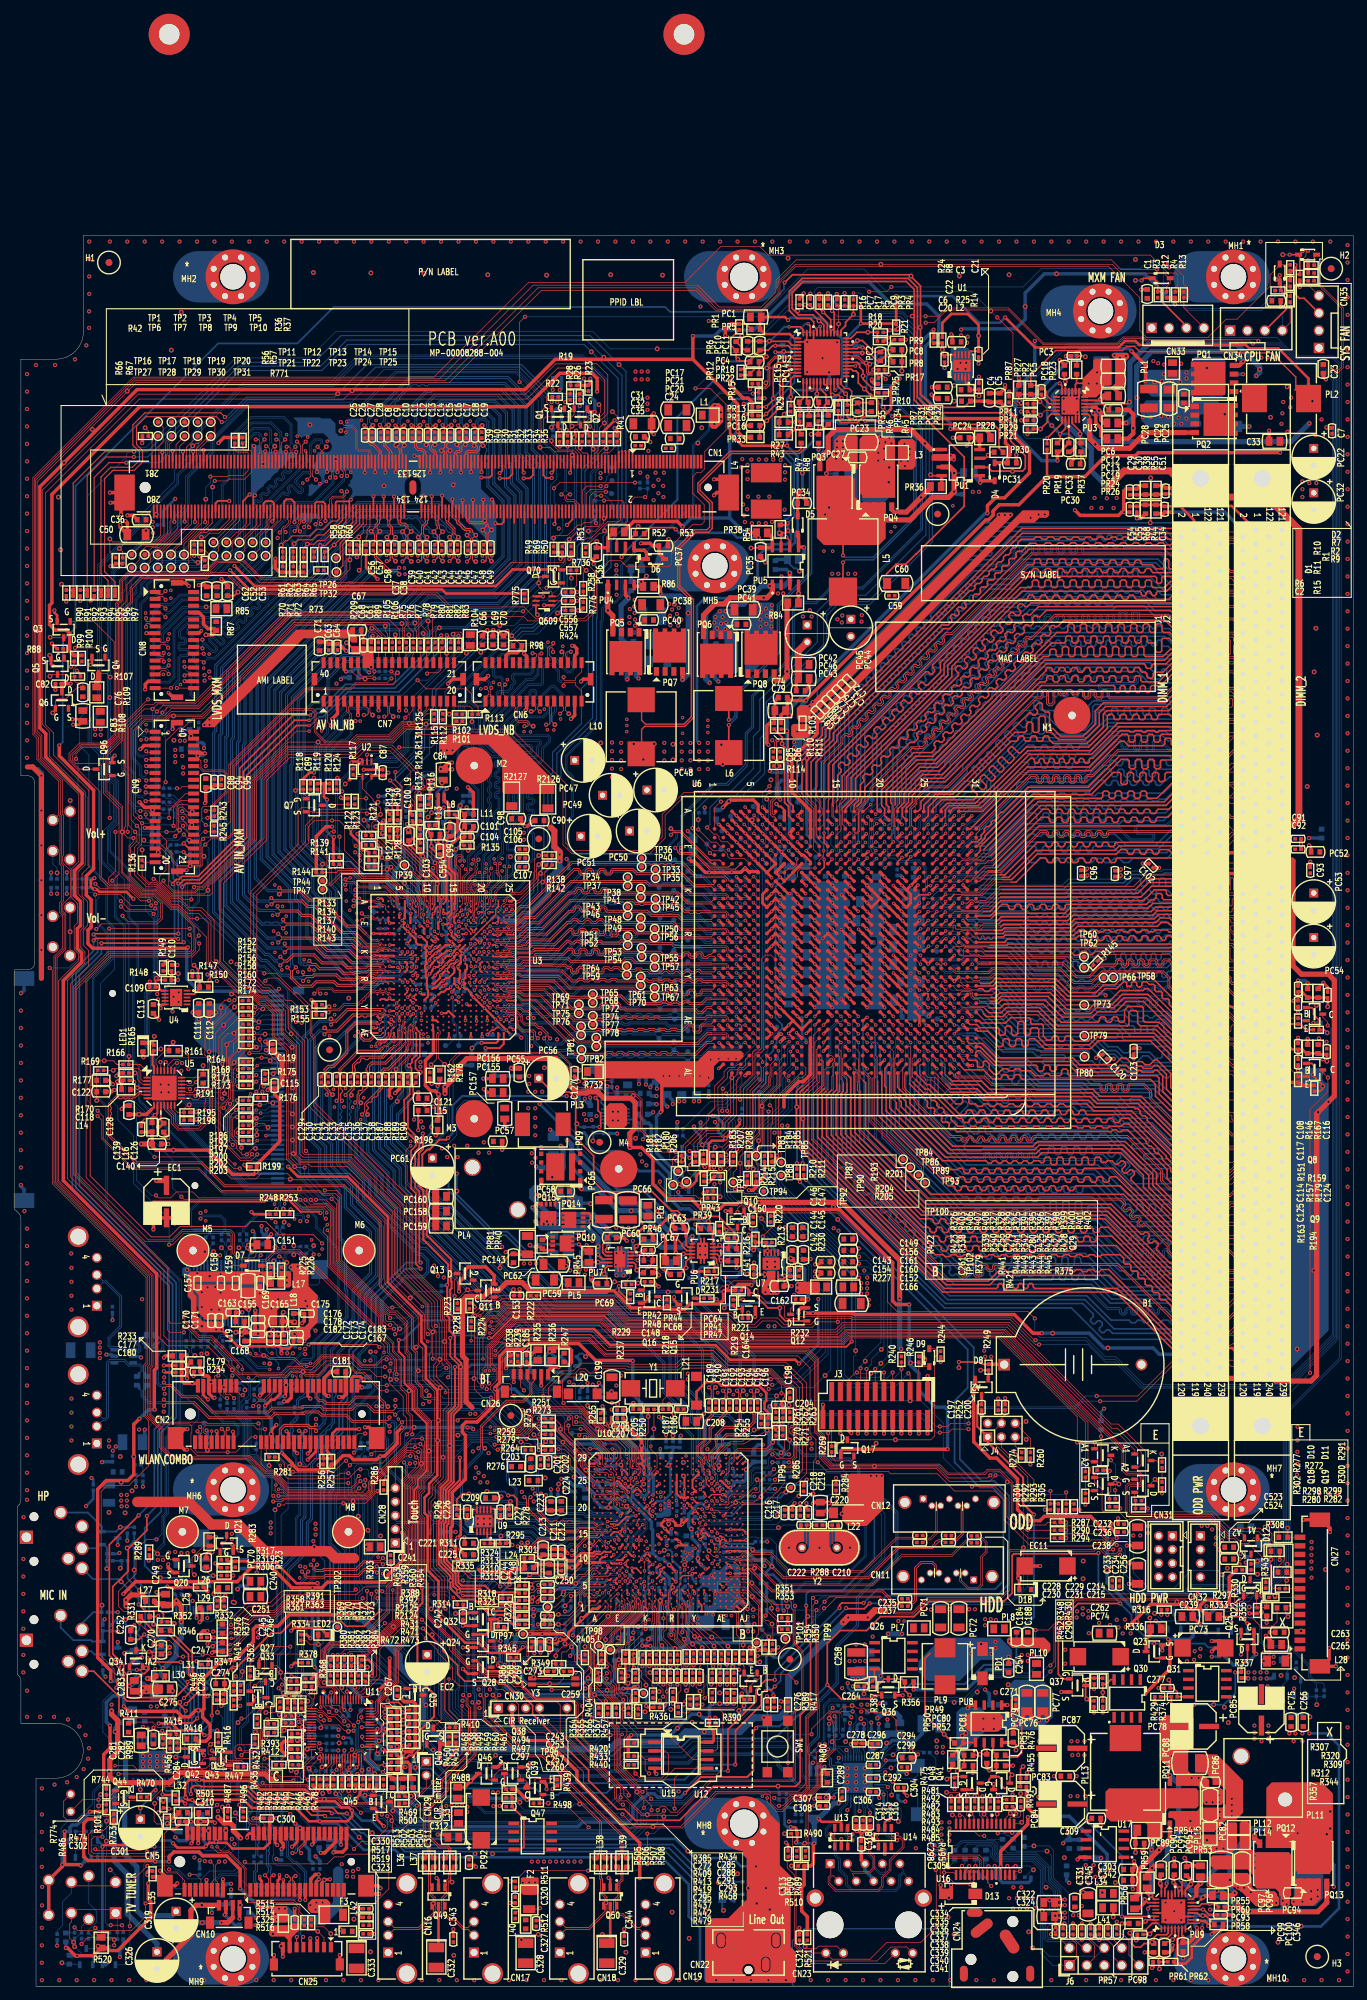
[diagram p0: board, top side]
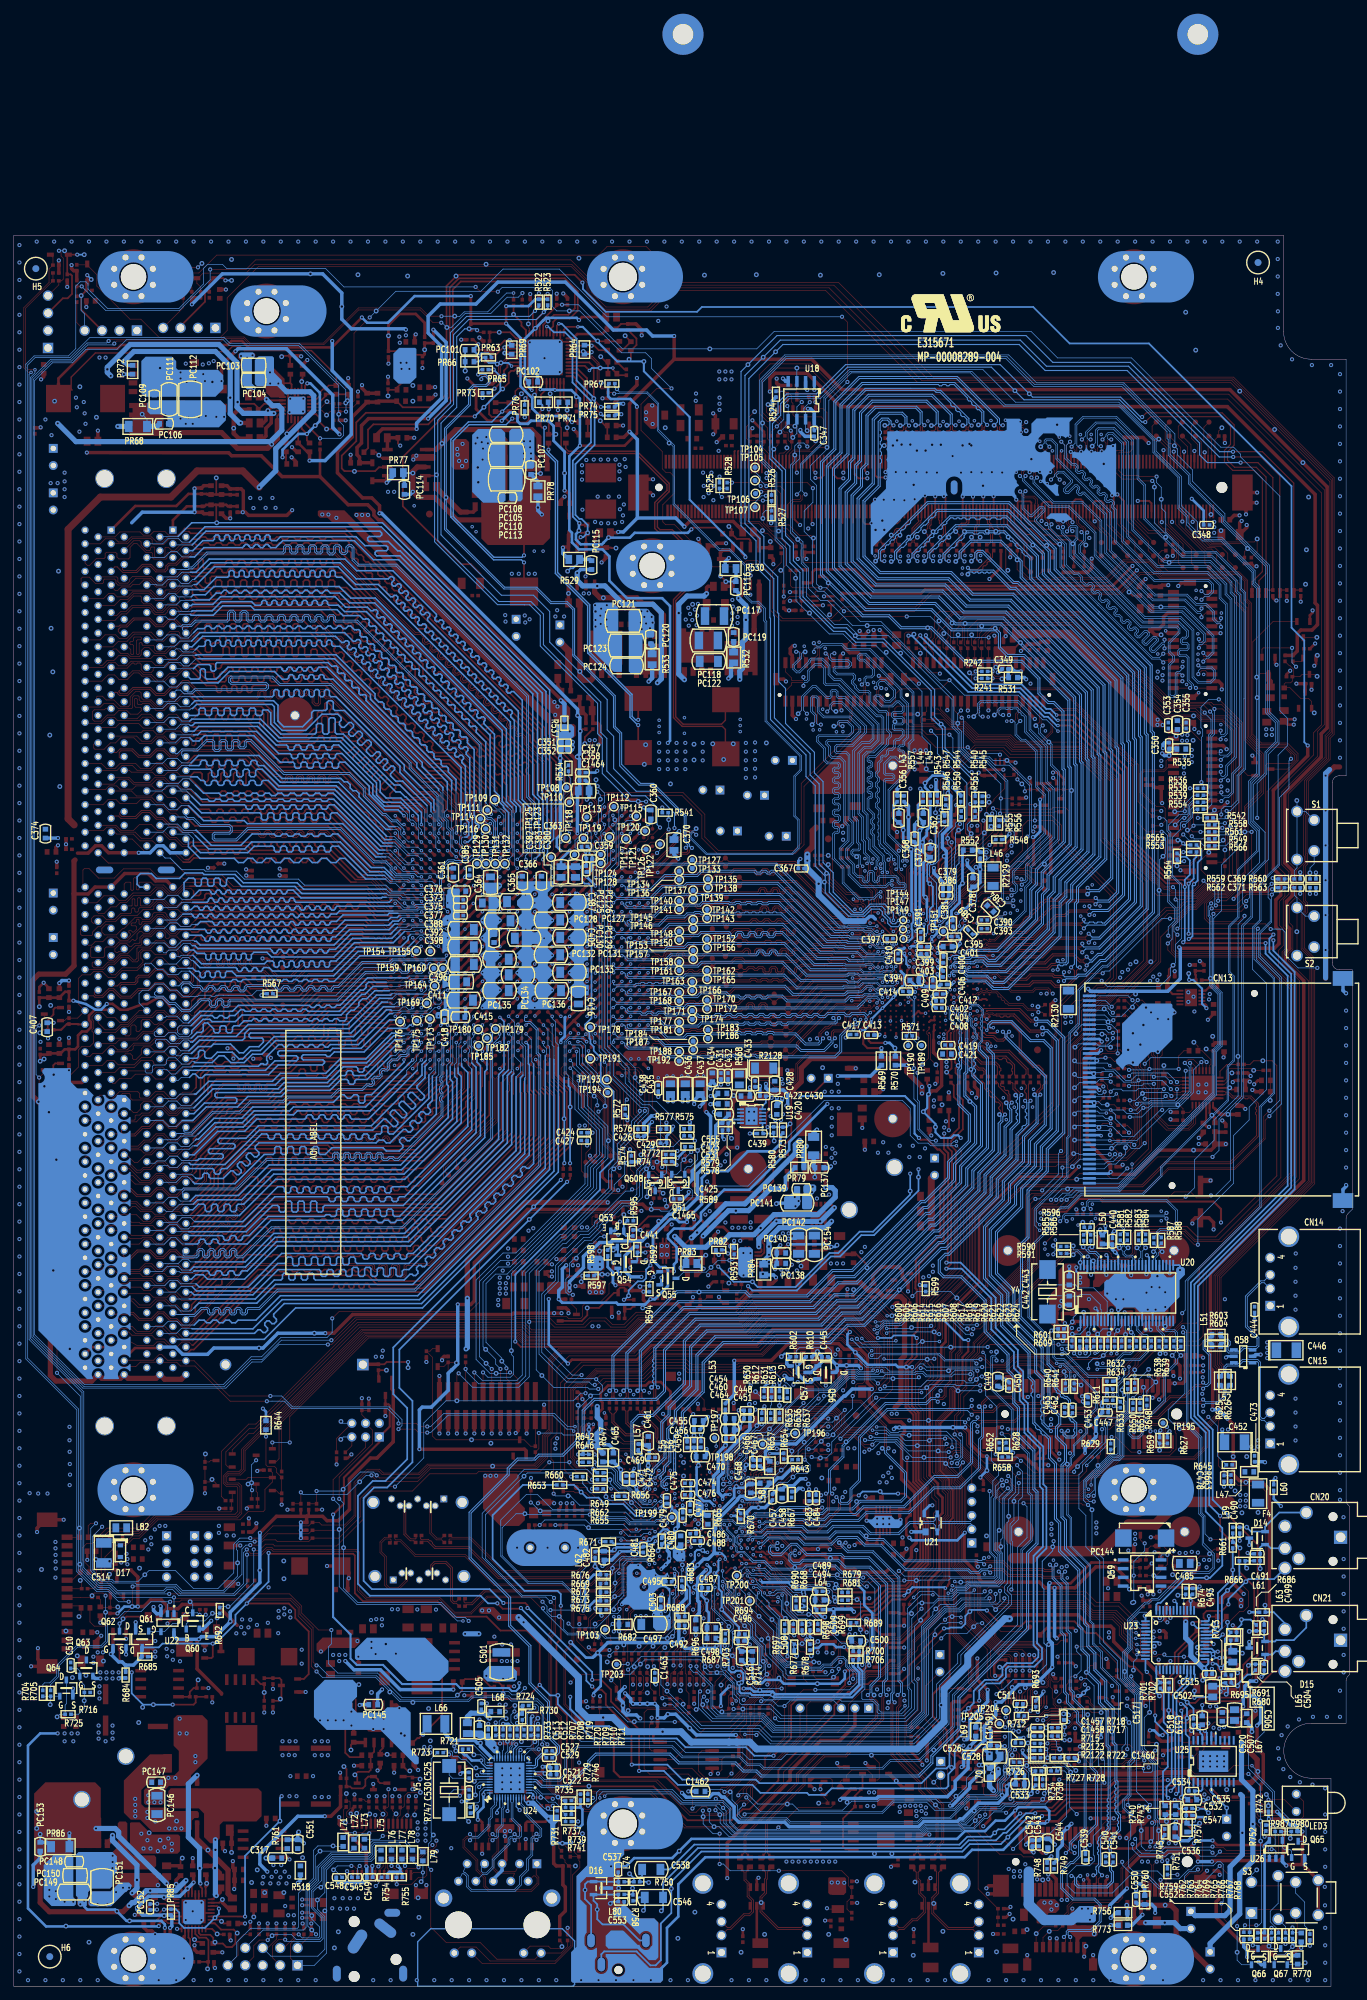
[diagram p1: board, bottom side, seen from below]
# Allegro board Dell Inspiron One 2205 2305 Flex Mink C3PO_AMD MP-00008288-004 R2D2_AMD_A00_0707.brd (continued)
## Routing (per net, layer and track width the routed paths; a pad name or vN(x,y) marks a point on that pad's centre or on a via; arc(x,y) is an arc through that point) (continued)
PANEL_ID2_R: length 3.6
  TOP w0.102: v1(185.49,53.85) 185.19,54.16 R344.2 185.47,55.4 CN27.6
PC_BEEP: length 186.3
  TOP w0.254: v2(59.47,52.12) 59.48,52.12 62.38,49.22 62.38,48.88 64.53,46.74 64.53,45.47 65.54,44.45 70.11,44.45 70.56,44.01 71.41,44.01 72.5,42.91 73.43,42.91 75.45,40.89 75.45,39.62 83.6,31.47 83.6,29.97 87.79,25.78 88.81,25.78 90.41,24.18 96.86,24.18 101.79,29.11 113.76,29.11 114.41,29.77 114.41,39.47 115.94,41 115.94,49.94 115.3,50.57 v2(115.3,55.42) ; v2(53.22,54.74) 50.94,52.45 48.27,52.45 47.57,53.15 40.46,53.15 38.75,51.44 37.33,51.44 32.47,46.57 31.73,46.57 30.56,45.41 C274.2 30.56,42.69 C286.1 R446.1 29.03,42.54 28.78,42.29 28.78,39.5 v2(28.71,39.43)
  BOTTOM w0.254: v2(59.47,52.12) 58.74,52.12 58.61,52.25 56.93,52.25 56.37,52.81 56.37,53.92 v1(55.71,54.58) 55.48,54.81 53.3,54.81 v2(53.22,54.74) ; R740.1 27.57,26.62 27.57,31.27 26.87,31.97 26.87,36.71 28.71,38.55 v2(28.71,39.43) ; R653.2 120.81,73.03 125.23,68.61 125.23,62.26 120.57,57.59 115.77,57.59 115.3,57.12 v2(115.3,55.42)
PC_BEEP_SPEAKER: length 2.6
  BOTTOM w0.254: v1(27.06,24) 27.25,24.19 R740.2 R743.1
PC_MODE: length 254.3
  TOP w0.102: v2(46.16,114.68) 46.87,113.97 46.87,105.54 54.56,97.85 55.38,97.85 56.86,96.38 56.86,92.25 57.29,91.82 57.29,87.77 58.25,86.81 58.25,84.19 60.31,82.13 60.31,74.96 59.04,73.69 59.04,72.64 58.53,72.14 58.53,68.43 59.04,67.92 59.04,59.4 59.9,58.53 59.9,53.92 63.76,50.06 63.76,48.9 66.11,46.55 67.38,46.55 68.53,45.4 70.5,45.4 70.93,44.97 71.75,44.97 72.66,44.07 73.14,44.07 v2(73.26,44.17) ; U10.E4 88.12,58.19 v4(88.14,58.19) ; R76.2 56.78,196.01 56.78,197.93 57.03,198.18 57.03,198.82 56.42,199.43 40.1,199.43 26.78,186.11 22.82,186.11 21.75,185.04 18.27,185.04 16.6,183.36 16.6,169.09 v2(17.54,168.15) 17.79,167.89 17.79,166.8 16.85,165.86 16.85,161.77 18.81,159.82 20.68,159.82 22.94,157.56 23.86,157.56 25.14,156.27 26.78,156.27 28.18,154.88 28.18,149.28 32.93,144.53 34.31,144.53 35.73,143.1 36.49,143.1 37.78,141.81 37.78,138.4 39.84,136.35 39.84,120.57 41.16,119.25 v2(42.23,119.25)
  BOTTOM w0.102: v2(17.54,168.15) 17.98,167.7 19.46,167.7 R549.1 ; v4(88.14,58.19) 88.14,58.18 86.85,56.9 86.85,55.73 v1(84.54,53.42) 83.83,52.7 83.83,48.07 82.43,46.67 79.58,46.67 79.13,46.23 77.48,46.23 77.04,46.67 75.96,46.67 74.88,47.75 74.15,47.75 73.81,47.41 73.81,46.56 73.26,46.01 v2(73.26,44.17) ; v2(42.23,119.25) 42.23,118.01 45.55,114.68 v2(46.16,114.68)
PC_MODE_MXM_R: length 12
  TOP w0.102: v2(23.38,167.51) 23.89,168.02 23.89,171.53 24.12,171.75 24.47,171.75 25.5,170.73 CN9.28
  BOTTOM w0.102: v1(18.81,166.94) 19.12,166.62 20.39,166.62 20.89,167.12 R549.2 23,167.13 v2(23.38,167.51)
PC_MODE_NB_R: length 4.3
  TOP w0.102: v1(57.41,196.85) 57.54,196.72 57.54,195.45 57.03,194.94 R76.1 57.03,194.44 56.99,194.4 CN7.28
PC_STATUS: length 208.8
  TOP w0.102: v2(36.36,147.55) 38.08,147.55 40.9,144.73 41.15,144.73 43.28,142.6 43.28,138.72 43.75,138.25 43.75,128.68 57.73,114.69 57.73,104.58 62.3,100.01 62.3,97.22 62.59,96.93 62.59,91.15 63.38,90.36 63.38,88.96 v2(63.13,88.71) ; U10.D29 86.61,77.14 86.61,77.52 82.98,81.15 v2(82.43,81.15) ; v2(26.55,155.51) 25.55,155.51 23.75,157.31 22.9,157.31 20.6,159.61 18.71,159.61 16.65,161.67 16.65,166.12 17.28,166.75 v2(17.28,167.26) 16.47,167.26 15.95,167.78 15.95,168.72 16.17,168.94 16.17,183.84 19,186.66 20.18,186.66 20.53,187.02 26.12,187.02 39.37,200.27 60.09,200.27 60.84,199.52 60.84,196.47 61.22,196.09 R80.2
  BOTTOM w0.102: v2(82.43,81.15) 80.25,81.15 75.75,85.65 75.75,86.37 73.29,88.84 72.4,88.84 72.15,88.58 66.98,88.58 v1(66.91,88.52) 63.32,88.52 v2(63.13,88.71) ; R566.2 18.43,166.12 v2(17.28,167.26) ; v2(26.55,155.51) 27.76,155.51 35.39,147.88 36.03,147.88 v2(36.36,147.55)
PC_STATUS_MXM_R: length 7.2
  TOP w0.102: v2(24.63,167.77) 25.66,166.73 CN9.24
  BOTTOM w0.102: v1(20.9,165.16) 20.89,165.18 R566.1 21.6,166.12 22.41,166.93 23.08,166.93 23.08,166.93 23.79,166.93 v2(24.63,167.77)
PC_STATUS_NB_R: length 5.9
  TOP w0.102: CN7.24 60.99,194.21 61.22,194.44 R80.1 61.56,194.9 61.73,195.07 61.73,196.15 61.35,196.53 61.35,197.36 v1(61.86,197.87)
PCE_CALRN: length 10.2
  TOP w0.1: 57.89,137.47 57.89,139.04
  TOP w0.102: 57.89,137.47 57.89,136.72 57.77,136.6 ; 57.89,139.04 57.91,139.07 57.91,139.07 57.97,139.13 57.97,139.37 57.91,139.45 57.91,139.91 58.05,140.05 58.05,140.87 U3.AB8
  TOP w0.125: 57.77,136.6 57.77,135.92 55.56,133.71 v1(55.56,133.55) ; R187.1 55.43,132.92
  TOP w0.127: v1(55.56,133.55) 55.56,133.04 55.43,132.92
PCE_CALRP: length 13.3
  TOP w0.102: U3.AC8 58.35,140.36 58.35,140.03 58.12,139.8 58.12,139.55 58.18,139.47 58.18,139.05 58.11,138.99 58.11,136.63 58,136.51 58,135.79 56.35,134.14 56.35,132.85 56.04,132.55 R188.1 56.05,132.51 56.65,131.9 56.65,130.45 55.71,129.51 v1(55.71,128.88)
PCI_AD23: length 13.1
  TOP w0.102: U10.AE9 102.74,61.77 v3(102.4,61.44)
  BOTTOM w0.102: v3(102.4,61.44) 102.42,61.44 102.83,61.85 105.61,61.85 106.12,61.34 106.12,56.9 106.88,56.13 106.88,55.95 107.58,55.25 v1(107.58,54.86) R675.1
PCI_AD24: length 12.9
  TOP w0.102: U10.AD9 101.94,61.92 v3(101.61,61.59)
  BOTTOM w0.102: v3(101.61,61.59) 101.99,61.98 102.5,61.98 102.63,62.1 105.8,62.1 106.37,61.53 106.37,57.21 106.82,56.77 v1(107.45,56.77) 108.09,56.13 R673.1
PCI_AD25: length 12.1
  TOP w0.102: v3(102.29,62.61) 101.77,62.61 U10.AC11
  BOTTOM w0.102: R672.1 107.64,57.4 107.39,57.66 v1(107.39,58.74) 107.39,60.26 106.72,60.93 106.72,61.94 106.31,62.36 102.54,62.36 v3(102.29,62.61)
PCI_AD26: length 13.3
  TOP w0.102: R351.1 111.74,54.01 111.9,54.17 112.41,54.17 112.6,54.36 v1(112.6,55.31) 112.28,55.63 110.61,55.63 106.51,59.72 104.26,59.72 103.85,59.32 U10.AF6
PCI_AD27: length 13.2
  TOP w0.102: U10.AF4 103.99,58.06 104.35,58.06 104.43,58.14 106.46,58.14 108.85,55.75 108.85,53.78 109.36,53.28 109.8,53.28 v1(110.31,52.77) 110.44,52.64 110.44,49.9 R350.1
PCI_AD29: length 8.4
  TOP w0.102: R401.1 v1(106.12,49.72) 106.12,51.44 105.42,52.13 105.42,54.36 104.79,54.99 104.79,55.66 105.15,56.03 U10.AH2
PCI_CLK0: length 9
  TOP w0.102: U10.W2 98.04,55.75 97.67,55.38 97.67,52.48 98.66,51.49 99.13,50.48 99.42,50.2 v1(100.15,49.34) R396.1
PCI_CLK1_R: length 8.6
  TOP w0.102: R397.1 v1(99.77,50.67) 99.77,51.08 97.88,52.97 97.88,55.15 U10.W1
PCI_CLK2: length 5.4
  TOP w0.102: R398.2 102.94,46.85 v1(102.65,46.56) 102.65,46.15 102.75,46.05 R426.1 102.21,45.1 102.21,43.38 R443.1
PCI_CLK2_R: length 10.5
  TOP w0.102: R398.1 102.94,48.45 v1(101.86,49.53) 100.85,50.61 98.34,53.12 98.34,55.44 98.28,55.5 98.28,55.93 98.34,55.99 98.34,56.24 U10.W3
PCI_CLK3: length 6.4
  TOP w0.102: R399.2 103.96,46.86 103.77,46.67 R427.1 103.26,45.13 103.26,43.23 R444.1 102.71,42.72 v1(102.69,42.74)
PCI_CLK3_R: length 11.8
  TOP w0.102: U10.W4 98.34,57.15 98.55,56.33 98.55,55.91 98.49,55.85 98.49,55.59 98.55,55.53 98.55,53.5 99.46,52.59 99.78,52.32 v1(101.55,50.86) 103.96,48.45 R399.1
PCI_CLK4: length 5.5
  TOP w0.102: R400.2 104.98,46.93 v1(104.6,46.55) 104.79,46.35 R428.1 104.28,45.13 104.28,43.23 R445.1
PCI_CLK4_R: length 10.2
  TOP w0.102: R400.1 104.98,48.45 v1(103.9,49.53) 101.99,51.44 100.47,52.32 99.38,52.96 98.84,53.5 U10.Y1
PCI_GNT0_N: length 11
  TOP w0.102: U10.AD12 101.94,63.92 102.12,63.74 v3(102.12,63.75)
  BOTTOM w0.102: v3(102.12,63.75) 102.12,63.5 103.01,62.61 106.44,62.61 107.77,61.28 v1(107.77,60.9) 107.77,60.13 107.96,59.94 R676.2 R669.1
PCI_GNT2_N: length 12.1
  TOP w0.102: TP99.1 111.54,51.33 111.43,51.33 111.01,51.75 111.01,53.28 109.61,54.67 109.61,55.75 106.49,58.87 105.68,58.87 U10.AH6
PCI_REQ2_N: length 9.6
  TOP w0.102: TP101.1 108.09,51.05 108.34,51.31 108.34,55.5 106.54,57.3 105.85,57.3 105.44,57.72 U10.AH4
PCI_RI_R_N: length 8.3
  TOP w0.102: U10.K1 91.53,55.2 91.53,54.3 89.55,52.32 89.55,51.05 v1(89.93,50.67) 89.93,50.55 88.95,49.57 R326.2
PCI_RST_N: length 9.4
  TOP w0.102: R395.2 99.9,46.67 99.77,46.55 C280.1 100.29,45.64 100.4,45.53 100.4,42.55 100.21,42.35 99.85,42.35 R449.1 R448.1 97.85,41.89 97.48,41.53 v1(97.48,41.08)
PCI_RST_R_N: length 101.4
  TOP w0.102: CN2.17 35.88,76.08 36.78,75.18 37.76,75.18 39.66,73.28 48.55,73.28 v2(48.58,73.3) ; R449.2 v2(100.18,41.04)
  BOTTOM w0.102: v2(100.18,41.04) 99.05,41.04 95.15,37.13 86.58,37.13 84.75,35.31 63.86,35.31 60.14,39.03 60.14,43.81 57.01,46.94 57.01,48.24 49.64,55.61 49.64,57 50.24,57.59 50.24,58.05 49.82,58.47 49.82,64.52 49.86,64.56 49.86,67.31 49.29,67.88 v1(49.29,70.64) 49.29,71.13 48.58,71.84 v2(48.58,73.3)
PCIE_CALRN_R: length 10.6
  TOP w0.102: U10.AD28 102.5,76.95 102.5,77.22 104.28,78.99 106.2,78.99 107.52,79.76 v1(109.61,80.96) 109.74,81.09 R255.2
PCIE_CALRP_R: length 9.2
  TOP w0.102: R254.2 108.72,81.41 108.34,81.03 v1(107.71,81.03) 106.06,79.38 104.28,79.38 102.04,77.14 U10.AD29
PCIE_EXPCARD_PWREN_N: length 9.7
  TOP w0.102: U10.H2 89.77,55.85 89.77,55.48 89.7,55.4 89.7,54.64 86.05,50.99 v1(86.05,50.48) 86.05,50.04 85.74,49.72 85.74,49.15 85.48,48.9 R405.1
PCIE_LAN_CLKREQ_N: length 4
  BOTTOM w0.102: v1(111.2,29.15) 111.2,28.61 111.36,28.45 R746.1 R729.2 112.82,27.99 R735.1
PCIE_MXM_NB_RX8N: length 4.5
  TOP w0.152: C26.1 51.75,225.2 51.75,224.97 52,224.71 52.29,224.71 53.4,223.61 53.4,223.14 53.5,223.03 CN1.147
PCIE_MXM_NB_RX8N_C: length 146.3
  TOP w0.152: v5(52.17,227.37) 51.98,227.37 51.69,227.08 51.69,226.72 C26.2 ; v3(57.24,150.66) 56.84,150.26 U3.L6
  BOTTOM w0.145: 56.27,150.22 56.86,150.22 57.24,150.6 v3(57.24,150.66)
  BOTTOM w0.152: v5(52.17,227.37) 51.69,227.86 51.69,228.22 57.66,234.19 71.76,234.19 75.24,230.71 75.24,223.84 77.19,221.9 77.19,205.7 71.26,199.77 67.42,199.77 65.68,198.03 61.26,198.03 56.37,193.14 48.1,193.14 45.5,190.54 45.5,188.41 44.23,187.13 43.41,187.13 42,185.72 42,177.4 41.81,177.21 41.81,166.66 45.87,162.59 45.87,160.45 46.69,159.63 46.69,155.72 51.66,150.75 55.74,150.75 56.27,150.22
PCIE_MXM_NB_RX8P: length 4.5
  TOP w0.152: C25.1 51.45,225.08 51.45,224.85 51.88,224.42 52.17,224.42 53.1,223.49 53.1,223.22 53,223.11 CN1.149
PCIE_MXM_NB_RX8P_C: length 146.1
  TOP w0.152: v3(56.44,150.66) 56.44,150.39 56.26,150.21 U3.L5 ; C25.2 51.39,226.72 51.39,227.08 51.11,227.37 v2(50.9,227.37)
  BOTTOM w0.152: v2(50.9,227.37) 51.2,227.37 51.39,227.56 51.39,228.34 57.54,234.48 71.88,234.48 75.53,230.83 75.53,223.96 77.48,222.02 77.48,205.58 71.38,199.48 67.54,199.48 65.8,197.74 61.38,197.74 56.49,192.85 48.22,192.85 45.79,190.42 45.79,188.29 44.35,186.84 43.53,186.84 42.29,185.6 42.29,177.28 42.1,177.09 42.1,166.78 46.17,162.71 46.17,160.57 46.98,159.75 46.98,155.84 51.78,151.04 55.1,151.04 55.27,151.21 55.51,151.21 55.68,151.04 55.86,151.04 56.24,150.66 v3(56.44,150.66)
PCIE_MXM_NB_RX9N: length 4
  TOP w0.152: CN1.141 55,223.27 54.9,223.37 54.9,223.62 54.04,224.48 54.04,225.21 C28.1
PCIE_MXM_NB_RX9N_C: length 147.2
  TOP w0.152: v5(54.46,227.42) 54.05,227.42 53.94,227.31 53.94,226.76 C28.2 ; U3.L8 58.25,150.21 57.88,149.84 v3(57.88,149.69)
  BOTTOM w0.152: v3(57.88,149.69) 57.73,149.83 57.47,149.83 57.21,149.57 55.69,149.57 55.39,149.87 53.68,149.87 53.05,149.25 51.92,149.25 45.84,155.33 45.84,159.28 45.02,160.09 45.02,162.19 40.94,166.27 40.94,177.55 41.15,177.75 41.15,187.4 47.74,193.99 50.18,193.99 51.26,195.07 51.26,197.17 51.81,197.73 58.29,197.73 61.23,200.67 70.85,200.67 72.44,202.27 74.7,204.53 76.33,206.17 76.33,221.35 74.34,223.35 74.34,230.29 71.32,233.31 60.31,233.31 60.13,233.12 59.83,233.12 59.64,233.31 59.23,233.31 59.04,233.12 58.77,233.12 58.58,233.31 58.03,233.31 56.07,231.35 56.07,231.12 55.86,230.91 55.63,230.91 55.43,230.71 55.43,230.48 55.2,230.25 54.97,230.25 54.77,230.05 54.77,229.82 54.6,229.65 54.58,229.65 54.37,229.65 53.97,229.25 53.97,227.62 54.17,227.42 v5(54.46,227.42)
PCIE_MXM_NB_RX9P: length 4
  TOP w0.152: CN1.143 54.5,223.27 54.61,223.37 54.61,223.5 53.75,224.36 53.75,225.07 C27.1
PCIE_MXM_NB_RX9P_C: length 147.2
  TOP w0.152: C27.2 53.64,226.69 53.64,227.06 53.28,227.42 v2(53.19,227.42) ; v3(58.69,149.68) 58.44,149.44 U3.M8
  BOTTOM w0.145: 57.54,150.15 57.37,150.15 57.31,150.09
  BOTTOM w0.152: v3(58.69,149.68) 58.22,150.15 57.54,150.15 ; v2(53.19,227.42) 53.68,227.91 53.68,229.37 57.91,233.6 71.44,233.6 74.63,230.41 74.63,223.47 76.63,221.47 76.63,206.05 74.82,204.24 74.82,204.24 72.65,202.06 70.97,200.37 61.35,200.37 58.41,197.43 51.94,197.43 51.55,197.05 51.55,194.95 50.3,193.7 47.86,193.7 41.44,187.28 41.44,177.63 41.24,177.43 41.24,166.4 45.32,162.31 45.32,160.22 46.13,159.4 46.13,155.45 52.04,149.54 52.93,149.54 53.55,150.16 55.51,150.16 55.81,149.86 57.08,149.86 57.31,150.09
PCIE_MXM_NB_RX10N: length 4.1
  TOP w0.152: CN1.135 56.5,223.14 56.4,223.24 56.4,223.65 56.29,223.75 56.29,223.96 v1(56.77,224.44) 56.26,224.95 56.26,225.15 C9.1
PCIE_MXM_NB_RX10N_C: length 143.4
  TOP w0.152: C9.2 56.26,226.72 56.26,227.23 56.36,227.33 v5(56.72,227.33) ; U3.M7 57.84,149.21 58.08,148.97 58.08,148.7 v3(57.84,148.46)
  BOTTOM w0.145: 55.61,148.93 55.63,148.93 55.67,148.97 57.85,148.97 58.08,148.75 58.08,148.57 57.96,148.46 v3(57.84,148.46)
  BOTTOM w0.152: v5(56.72,227.33) 56.32,227.33 56.14,227.51 56.14,228.24 56.54,228.64 56.75,228.64 56.82,228.64 57.03,228.86 57.03,229.14 57.26,229.36 57.54,229.36 57.77,229.59 57.77,229.87 58,230.1 58.27,230.1 58.48,230.31 58.48,230.59 60.07,232.17 60.63,232.17 60.92,232.46 64.19,232.46 64.2,232.45 70.85,232.45 73.32,229.98 73.32,223.12 75.43,221.01 75.43,206.66 70.33,201.56 60.7,201.56 57.73,198.59 51.1,198.59 40.3,187.79 40.3,178.11 40.08,177.9 40.08,165.89 44.17,161.8 44.17,159.74 44.99,158.93 44.99,154.73 51.15,148.56 53.27,148.56 53.89,149.19 54.81,149.19 55.07,148.93 55.61,148.93
PCIE_MXM_NB_RX10P: length 4.1
  TOP w0.152: CN1.137 56,223.14 56.1,223.24 56.1,223.53 56,223.63 56,223.94 v1(55.5,224.44) 55.97,224.91 55.97,225.14 C8.1
PCIE_MXM_NB_RX10P_C: length 143.4
  TOP w0.152: v2(55.45,227.33) 55.68,227.33 55.97,227.04 55.97,226.72 C8.2 ; U3.P7 57.79,147.71 v3(58.54,148.46)
  BOTTOM w0.145: 55.61,149.22 55.64,149.22 55.65,149.22 57.95,149.22 58.32,148.85 58.32,148.67 58.53,148.46 v3(58.54,148.46)
  BOTTOM w0.152: 55.61,149.22 55.19,149.22 54.93,149.48 53.77,149.48 53.15,148.86 51.27,148.86 45.28,154.85 45.28,159.05 44.46,159.86 44.46,161.92 40.37,166.01 40.37,177.77 40.59,177.99 40.59,187.67 51.22,198.3 57.85,198.3 60.82,201.27 70.45,201.27 71.95,202.76 75.72,206.54 75.72,221.13 73.61,223.24 73.61,230.11 70.97,232.75 64.32,232.75 64.31,232.75 60.8,232.75 60.51,232.46 59.94,232.46 58.57,231.09 58,230.52 55.85,228.37 55.85,227.73 v2(55.45,227.33)
PCIE_MXM_NB_RX11N: length 4.5
  TOP w0.152: C11.1 58.55,225.15 58.55,224.29 58.86,223.98 59.4,223.98 59.9,223.48 59.9,223.14 60,223.03 CN1.121
PCIE_MXM_NB_RX11N_C: length 138.4
  TOP w0.152: U3.M5 56.04,148.87 v3(56.48,148.44) ; C11.2 58.54,226.72 58.54,227.17 58.75,227.38 v5(59.06,227.38)
  BOTTOM w0.145: v3(56.48,148.44) 56.27,148.23 56.27,147.92 56.02,147.66 53.05,147.66
  BOTTOM w0.152: v5(59.06,227.38) 58.74,227.38 58.57,227.56 58.57,228.89 61.28,231.6 70.38,231.6 72.47,229.51 72.47,222.53 73.09,221.91 73.09,219.47 74.48,218.08 74.48,206.93 70.05,202.5 60.15,202.5 57.1,199.45 50.74,199.45 39.44,188.15 39.44,178.48 39.22,178.25 39.22,165.54 43.28,161.47 43.28,159.39 44.14,158.53 44.14,153.89 50.38,147.65 53.03,147.65 53.05,147.66
PCIE_MXM_NB_RX11P: length 4.5
  TOP w0.152: CN1.123 59.5,223.03 59.6,223.14 59.6,223.36 59.27,223.69 58.74,223.69 58.26,224.17 58.26,225.14 C10.1
PCIE_MXM_NB_RX11P_C: length 138.3
  TOP w0.152: v3(55.81,148.41) 56.17,148.06 56.17,147.84 U3.P5 ; C10.2 58.25,226.72 58.25,227.28 58.15,227.38 v2(57.79,227.38)
  BOTTOM w0.145: 53.05,147.92 55.88,147.92 55.99,148.03 55.99,148.23 v3(55.81,148.41)
  BOTTOM w0.152: 53.05,147.92 53.03,147.94 50.51,147.94 44.43,154.01 44.43,158.65 43.57,159.51 43.57,161.59 39.51,165.66 39.51,178.13 39.74,178.36 39.74,188.03 50.87,199.16 57.22,199.16 60.27,202.21 70.17,202.21 74.77,206.81 74.77,218.2 73.38,219.59 73.38,222.03 72.76,222.65 72.76,229.64 70.51,231.89 61.16,231.89 58.27,229.01 58.27,227.58 58.07,227.38 v2(57.79,227.38)
PCIE_MXM_NB_RX12N: length 4.6
  TOP w0.152: C13.1 61.15,225.5 60.78,225.14 60.78,224.96 v1(61.21,224.54) 60.86,224.54 60.73,224.41 60.73,224.01 60.97,223.77 61.15,223.77 61.4,223.52 61.4,223.09 61.5,222.99 CN1.115
PCIE_MXM_NB_RX12N_C: length 138.9
  TOP w0.152: v3(58.02,147.22) 58.44,147.65 U3.P8 ; v5(61.32,227.33) 60.93,227.33 60.68,227.08 60.68,226.81 61.13,226.36 C13.2
  BOTTOM w0.145: v3(58.02,147.22) 58.11,147.22 58.24,147.35 58.24,147.57 58.07,147.73 56.86,147.73 56.15,147.02 53.26,147.02 52.35,146.12 52.31,146.12 52.27,146.08 52.25,146.08
  BOTTOM w0.152: v5(61.32,227.33) 60.87,227.33 60.62,227.58 60.62,229.26 62.09,230.73 69.86,230.73 71.49,229.11 71.49,222.16 72.2,221.45 72.2,218.91 73.58,217.54 73.58,207.27 69.68,203.38 59.62,203.38 56.56,200.32 50.4,200.32 38.58,188.5 38.58,178.84 38.35,178.61 38.35,165.18 42.43,161.11 42.43,159.04 43.29,158.18 43.29,153.47 50.68,146.08 52.25,146.08
PCIE_MXM_NB_RX12P: length 4.7
  TOP w0.152: C12.1 60.23,225.5 60.49,225.24 60.49,224.97 v1(59.94,224.54) 60.35,224.54 60.43,224.45 60.43,223.89 60.85,223.48 61.03,223.48 61.11,223.4 61.11,223.09 61,222.98 CN1.117
PCIE_MXM_NB_RX12P_C: length 138.8
  TOP w0.152: v2(60.05,227.33) 60.16,227.33 60.39,227.1 60.39,226.57 C12.2 ; U3.R8 58.69,146.96 v3(58.69,147.2)
  BOTTOM w0.145: v3(58.69,147.2) 58.48,147.41 58.48,147.68 58.18,147.98 56.75,147.98 56.04,147.27 53.15,147.27 52.25,146.37 52.25,146.37
  BOTTOM w0.152: v2(60.05,227.33) 60.06,227.33 60.32,227.6 60.32,229.38 61.97,231.03 69.99,231.03 71.78,229.23 71.78,222.28 72.03,222.04 72.49,221.57 72.49,219.03 73.87,217.66 73.87,207.15 69.8,203.09 59.75,203.09 56.69,200.03 50.52,200.03 38.88,188.38 38.88,178.72 38.64,178.49 38.64,165.3 42.72,161.23 42.72,159.16 43.58,158.3 43.58,153.59 50.8,146.37 52.25,146.37
PCIE_MXM_NB_RX13N: length 4.4
  TOP w0.152: CN1.109 63,223.13 62.9,223.23 62.9,223.56 63.02,223.69 v1(63.43,223.69) 62.94,224.17 62.94,224.65 63.12,224.83 63.12,225.14 C15.1
PCIE_MXM_NB_RX13N_C: length 134.1
  TOP w0.152: C15.2 63.14,226.36 62.93,226.58 62.93,227.16 63.15,227.38 v5(63.6,227.38) ; U3.R5 56.08,146.71 v3(56.53,146.25)
  BOTTOM w0.145: 52.58,145.43 53.46,146.3 56.51,146.3 56.53,146.28 v3(56.53,146.25)
  BOTTOM w0.152: 52.58,145.43 52.34,145.19 50.07,145.19 42.42,152.84 42.42,157.82 41.58,158.65 41.58,160.72 37.49,164.81 37.49,178.96 37.73,179.21 37.73,188.87 50.04,201.18 56.16,201.18 59.24,204.27 69.35,204.27 72.71,207.64 72.71,217.07 71.35,218.44 71.35,220.92 70.55,221.72 70.55,228.72 69.43,229.84 63.59,229.84 62.95,229.2 62.95,227.53 63.1,227.38 v5(63.6,227.38)
PCIE_MXM_NB_RX13P: length 4.3
  TOP w0.152: CN1.111 62.5,223.14 62.61,223.24 62.61,223.56 62.48,223.69 v1(62.16,223.69) 62.65,224.18 62.65,224.77 62.82,224.95 62.82,225.14 C14.1
PCIE_MXM_NB_RX13P_C: length 134.2
  TOP w0.152: v2(62.33,227.38) 62.34,227.38 62.63,227.09 62.63,226.53 C14.2 ; U3.R6 56.84,146.67 v3(57.24,146.26)
  BOTTOM w0.145: v3(57.24,146.26) 57.24,146.32 56.86,146.71 56.17,146.71 56.02,146.56 53.34,146.56 52.47,145.69 ; 52.37,145.64 52.39,145.65 52.43,145.65
  BOTTOM w0.152: 52.43,145.65 52.47,145.69 ; v2(62.33,227.38) 62.34,227.38 62.66,227.7 62.66,229.32 63.47,230.14 69.55,230.14 70.84,228.84 70.84,221.84 71.64,221.04 71.64,218.56 73.01,217.2 73.01,207.51 69.47,203.97 59.36,203.97 56.28,200.89 50.16,200.89 38.03,188.75 38.03,179.09 37.78,178.84 37.78,164.93 41.87,160.84 41.87,158.78 42.71,157.94 42.71,152.97 50.2,145.48 52.22,145.48 52.37,145.64
PCIE_MXM_NB_RX14N: length 4.6
  TOP w0.152: C17.1 65.37,225.11 65.37,224.84 v1(65.65,224.56) 65.4,224.56 65.12,224.28 65.12,223.66 64.86,223.39 64.53,223.39 64.38,223.25 64.38,223.06 64.5,222.94 CN1.103
PCIE_MXM_NB_RX14N_C: length 129.7
  TOP w0.102: U3.P3 54.32,147.78 54,147.78 53.8,147.98 53.48,147.98 53.45,147.95 53.03,147.95 53,147.98 51.68,147.98 51.29,147.58 50.29,147.58 50.25,147.54 50.22,147.54
  TOP w0.152: v5(65.84,227.33) 65.47,227.33 65.34,227.2 65.34,226.77 65.75,226.36 C17.2 ; 50.22,147.54 49.61,147.54 49.48,147.41 47.8,147.41 47.15,148.06 44.34,148.06 43.72,148.69 43.04,148.69 42.92,148.57 v2(42.92,148.1)
  BOTTOM w0.152: v5(65.84,227.33) 65.42,227.33 65.16,227.58 65.16,228.5 65.64,228.98 68.8,228.98 69.64,228.15 69.64,218.83 71.85,216.62 71.85,208 69.75,205.9 69.02,205.17 58.75,205.17 55.62,202.04 49.69,202.04 36.87,189.22 36.87,179.56 36.63,179.32 36.63,164.47 40.73,160.37 40.73,158.3 41.37,157.65 41.37,149.09 41.68,148.78 42.04,148.78 42.17,148.64 42.49,148.64 42.63,148.78 42.84,148.78 42.92,148.7 v2(42.92,148.1)
PCIE_MXM_NB_RX14P: length 4.8
  TOP w0.152: C16.1 64.75,225.5 65.08,225.17 65.08,224.88 64.76,224.56 v1(64.38,224.56) 64.83,224.12 64.83,223.78 64.74,223.69 64.41,223.69 64.09,223.37 64.09,223.08 64,222.99 CN1.105
PCIE_MXM_NB_RX14P_C: length 129.5
  TOP w0.102: 50.22,147.83 50.25,147.83 50.29,147.79 51.2,147.79 51.6,148.18 53.08,148.18 53.12,148.15 53.37,148.15 53.4,148.18 53.88,148.18 54.09,147.98 54.57,147.98 54.89,147.66 U3.P4
  TOP w0.152: C16.2 65.05,226.66 65.05,226.96 64.68,227.33 v2(64.57,227.33) ; v2(42.92,149.37) 43.3,148.98 43.84,148.98 44.47,148.36 47.27,148.36 47.92,147.7 49.36,147.7 49.49,147.83 50.22,147.83
  BOTTOM w0.152: v2(42.92,149.37) 42.62,149.07 41.8,149.07 41.67,149.21 41.67,157.77 41.02,158.42 41.02,160.49 36.92,164.59 36.92,179.2 37.16,179.44 37.16,189.1 49.81,201.75 55.75,201.75 58.87,204.88 69.14,204.88 69.96,205.69 71.4,207.14 72.14,207.88 72.14,216.74 69.93,218.95 69.93,228.27 68.93,229.27 65.52,229.27 64.87,228.62 64.87,227.63 v2(64.57,227.33)
PCIE_MXM_NB_RX15N: length 5.7
  TOP w0.152: C19.1 68.05,225.5 67.69,225.14 67.69,224.93 v1(68.19,224.42) 67.89,224.42 67.71,224.23 67.71,223.85 67.25,223.39 66.06,223.39 65.91,223.25 65.91,223.13 66,223.04 CN1.97
PCIE_MXM_NB_RX15N_C: length 129
  TOP w0.102: U3.T3 54.32,146.18 54,146.18 53.8,146.38 53.48,146.38 53.45,146.35 53.03,146.35 53,146.38 52.6,146.38 52.44,146.23 50.31,146.23 49.78,145.7 49.18,145.7 49.13,145.65 49.11,145.65
  TOP w0.152: v5(68.1,227.36) 67.84,227.36 67.61,227.13 67.61,226.8 C19.2 ; v2(39.69,148.41) 40.18,147.92 40.18,146.82 41.47,145.52 43.34,145.52 43.98,146.17 46.46,146.17 46.98,145.65 49.11,145.65
  BOTTOM w0.152: v2(39.69,148.41) 40.07,148.41 40.18,148.53 40.18,157.64 39.88,157.95 39.88,160.01 35.76,164.13 35.76,179.66 36.02,179.91 36.02,189.59 49.34,202.91 55.22,202.91 58.37,206.06 68.71,206.06 70.99,208.34 70.99,216.26 68.77,218.48 68.77,221.79 68.59,221.97 68.59,222.38 68.77,222.56 68.77,222.88 68.59,223.07 68.59,223.42 68.77,223.61 68.77,223.93 68.59,224.11 68.59,224.46 68.77,224.64 68.77,224.97 68.59,225.15 68.59,225.52 68.77,225.71 68.77,226 68.59,226.19 68.59,226.46 68.77,226.65 68.77,227.77 68.42,228.12 67.72,228.12 67.47,227.87 67.47,227.53 67.65,227.36 v5(68.1,227.36)
PCIE_MXM_NB_RX15P: length 5.6
  TOP w0.152: CN1.99 65.5,223 65.62,223.11 65.62,223.37 65.94,223.69 67.13,223.69 67.41,223.97 67.41,224.23 67.22,224.42 v1(66.92,224.42) 67.39,224.89 67.39,225.14 C18.1
PCIE_MXM_NB_RX15P_C: length 129
  TOP w0.102: U3.T4 54.92,146.38 54.09,146.38 53.88,146.58 53.4,146.58 53.37,146.55 53.12,146.55 53.08,146.58 52.51,146.58 52.36,146.43 50.23,146.43 49.69,145.9 49.17,145.9 49.12,145.94 49.11,145.94
  TOP w0.152: C18.2 67.32,226.65 67.32,227.03 66.99,227.36 v2(66.83,227.36) ; 49.11,145.94 47.1,145.94 46.58,146.46 43.86,146.46 43.22,145.82 41.6,145.82 40.47,146.94 40.47,147.92 v2(40.96,148.41)
  BOTTOM w0.152: v2(40.96,148.41) 40.47,148.9 40.47,157.76 40.17,158.07 40.17,160.13 36.05,164.25 36.05,179.54 36.31,179.79 36.31,189.47 49.46,202.62 55.34,202.62 58.49,205.77 68.83,205.77 71.28,208.22 71.28,216.38 69.07,218.6 69.07,227.89 68.55,228.41 67.6,228.41 67.18,227.99 67.18,227.57 66.97,227.36 v2(66.83,227.36)
PCIE_NB_HDMI_TX0_DN: length 41.7
  TOP w0.099: v2(49.36,157.33) 49.69,157.66 51.07,157.66 51.35,157.94 52.37,157.94 52.6,157.71 52.65,157.71 53.03,157.71 53.29,157.45 53.29,157.43 53.47,157.26 U3.B2 ; v2(49.63,184.3) 49.27,184.3 49.06,184.51 49.06,185.32 48.6,185.78 48.6,186.36 48.99,186.75 CN7.5
  BOTTOM w0.099: v2(49.63,184.3) 49.31,184.3 49.12,184.11 49.12,182.23 48.27,181.38 47.69,181.38 46.16,179.85 46.16,174.7 44.92,173.46 44.92,167.94 51.06,161.8 51.06,158.2 50.55,157.68 49.72,157.68 v2(49.36,157.33)
PCIE_NB_HDMI_TX0_DP: length 42.2
  TOP w0.099: v2(48.36,184.3) 48.8,184.74 48.8,185.21 48.35,185.67 48.35,186.38 47.99,186.73 CN7.4 ; v2(49.39,158.17) 49.64,157.91 50.96,157.91 51.24,158.19 52.48,158.19 52.7,157.97 53.13,157.97 53.17,157.93 53.18,157.93 53.52,157.59 53.78,157.59 54.01,157.36 54.01,156.89 U3.C3
  BOTTOM w0.099: v2(49.39,158.17) 49.62,157.94 50.44,157.94 50.81,158.31 50.81,161.69 44.66,167.84 44.66,173.56 45.91,174.81 45.91,179.96 47.59,181.64 48.17,181.64 48.87,182.34 48.87,183.79 v2(48.36,184.3)
PCIE_NB_HDMI_TX1_DN: length 45.4
  TOP w0.099: U3.B4 55.22,157.26 54.85,157.63 54.85,158.26 53.96,159.16 49.9,159.16 v2(49.64,158.9) ; CN7.8 51.99,186.67 51.75,186.43 51.75,185.55 52.13,185.17 v5(52.14,185.17)
  BOTTOM w0.099: v2(49.64,158.9) 49.62,158.9 49.34,159.18 49.11,159.18 48.8,159.49 48.8,160.4 49.26,160.86 49.26,162.3 44,167.56 44,174.1 45.2,175.29 45.2,180.51 47.51,182.81 47.51,184.99 48.83,186.31 51.29,186.31 51.73,185.88 51.73,185.57 52.13,185.17 v5(52.14,185.17)
PCIE_NB_HDMI_TX1_DP: length 44.8
  TOP w0.099: v2(50.87,185.17) 51.32,185.17 51.5,185.34 51.5,186.13 50.99,186.63 CN7.7 ; v2(49.64,159.72) 49.95,159.41 54.06,159.41 55.1,158.37 55.1,158.2 U3.A4
  BOTTOM w0.099: v2(50.87,185.17) 50.95,185.09 51.24,185.09 51.47,185.32 51.47,185.77 51.19,186.06 50.48,186.06 50.38,185.95 50.2,185.95 50.1,186.06 49.87,186.06 49.77,185.95 49.57,185.95 49.46,186.06 48.93,186.06 48.7,185.83 48.7,185.67 48.55,185.52 48.4,185.52 48.25,185.37 48.25,185.24 48.12,185.12 47.99,185.12 47.76,184.88 47.76,182.71 45.45,180.4 45.45,175.18 44.26,173.99 44.26,167.67 49.52,162.41 49.52,160.76 49.06,160.3 49.06,159.59 49.21,159.44 49.36,159.44 v2(49.64,159.72)
PCIE_NB_HDMI_TX2_DN: length 52.2
  TOP w0.099: v5(55.14,184.94) 55.14,184.95 54.62,185.47 54.62,186.36 54.99,186.73 CN7.11 ; v2(48.14,160.45) 48.37,160.68 49.44,160.68 50.12,159.99 53.99,159.99 55.67,158.32 55.67,157.23 U3.B5
  BOTTOM w0.099: v2(48.14,160.45) 47.81,160.78 47.64,160.78 47.36,161.06 47.36,163.27 43.34,167.28 43.34,174.45 43.63,174.74 44.38,175.49 44.38,180.62 46.82,183.06 46.82,185.45 48.67,187.3 54.11,187.3 54.62,186.79 54.62,185.46 v5(55.14,184.94)
PCIE_NB_HDMI_TX2_DP: length 51.6
  TOP w0.099: U3.A5 55.92,157.77 55.92,158.42 54.1,160.25 50.23,160.25 49.54,160.93 48.27,160.93 48.19,161.01 v2(48.19,161.24) ; CN7.10 53.99,186.68 54.37,186.31 54.37,185.19 54.11,184.94 v2(53.85,184.94)
  BOTTOM w0.099: v2(53.85,184.94) 54.19,184.94 54.37,185.12 54.37,185.47 54.27,185.57 54.27,185.75 54.37,185.85 54.37,186.06 54.27,186.16 54.27,186.33 54.37,186.44 54.37,186.69 54.01,187.05 53.76,187.05 53.66,186.94 53.48,186.94 53.38,187.05 53.2,187.05 53.1,186.94 52.92,186.94 52.82,187.05 52.59,187.05 52.49,186.94 52.28,186.94 52.18,187.05 51.98,187.05 51.88,186.94 51.67,186.94 51.57,187.05 51.37,187.05 51.27,186.94 51.06,186.94 50.96,187.05 50.76,187.05 50.66,186.94 50.48,186.94 50.38,187.05 48.78,187.05 47.08,185.35 47.08,182.96 44.64,180.52 44.64,175.39 43.81,174.56 43.6,174.35 43.6,167.39 47.61,163.37 47.61,161.17 47.74,161.04 47.99,161.04 v2(48.19,161.24)
PCIE_NB_MXM_TX8N: length 5.8
  TOP w0.152: C57.2 53.02,209.98 52.7,210.29 52.7,211.45 v1(53.19,211.93) 52.79,212.33 52.79,212.77 53.15,213.12 53.15,213.51 53.25,213.61 CN1.148
PCIE_NB_MXM_TX8P: length 5.6
  TOP w0.152: CN1.150 52.75,213.61 52.86,213.51 52.86,213.25 52.5,212.89 52.5,212.51 v1(51.92,211.93) 52.41,211.45 52.41,210.16 C56.2
PCIE_NB_MXM_TX9N: length 5.6
  TOP w0.152: CN1.142 54.75,213.61 54.65,213.51 54.65,212.92 55.03,212.54 55.03,211.52 v1(55.48,211.07) 54.99,210.58 54.99,210.34 C37.2
PCIE_NB_MXM_TX9P: length 5.6
  TOP w0.152: C58.2 54.7,210.34 54.7,210.58 v1(54.21,211.07) 54.74,211.6 54.74,212.42 54.35,212.8 54.35,213.51 54.25,213.61 CN1.144
PCIE_NB_MXM_TX10N: length 6.3
  TOP w0.152: C39.2 57.27,210.34 57.27,211.4 v1(57.76,211.89) 57.27,212.38 57.27,212.77 56.94,213.11 56.33,213.11 56.15,213.29 56.15,213.51 56.25,213.61 CN1.136
PCIE_NB_MXM_TX10P: length 6.3
  TOP w0.152: CN1.138 55.75,213.61 55.86,213.51 55.86,213.17 56.21,212.81 56.82,212.81 56.98,212.65 56.98,212.38 v1(56.49,211.89) 56.98,211.4 56.98,210.34 C38.2
PCIE_NB_MXM_TX11N: length 5.7
  TOP w0.152: C41.2 59.56,210.34 59.56,210.57 v1(60.05,211.06) 59.56,211.55 59.56,212.52 60.15,213.11 60.15,213.51 60.25,213.61 CN1.120
PCIE_NB_MXM_TX11P: length 5.7
  TOP w0.152: CN1.122 59.75,213.61 59.86,213.51 59.86,213.23 59.27,212.64 59.27,211.55 v1(58.78,211.06) 59.27,210.57 59.27,210.34 C40.2
PCIE_NB_MXM_TX12N: length 5.5
  TOP w0.152: CN1.114 61.75,213.61 61.65,213.51 61.65,213 61.85,212.8 61.85,212.37 v1(62.33,211.88) 61.85,211.39 61.85,210.34 C43.2
PCIE_NB_MXM_TX12P: length 5.5
  TOP w0.152: CN1.116 61.25,213.61 61.35,213.51 61.35,212.88 61.55,212.68 61.55,212.37 v1(61.06,211.88) 61.55,211.39 61.55,210.34 C42.2
PCIE_NB_MXM_TX13N: length 5.8
  TOP w0.152: C45.2 64.13,210.34 64.13,210.58 v1(64.62,211.07) 64.13,211.56 64.13,212.37 63.44,213.06 63.15,213.35 63.15,213.51 63.25,213.61 CN1.108
PCIE_NB_MXM_TX13P: length 5.8
  TOP w0.152: C44.2 63.84,210.34 63.84,210.58 v1(63.35,211.07) 63.84,211.56 63.84,212.25 62.86,213.23 62.86,213.51 62.75,213.61 CN1.110
PCIE_NB_MXM_TX14N: length 6.7
  TOP w0.152: C47.2 66.67,210.34 66.67,210.88 v1(67.16,211.37) 66.67,211.86 66.67,212.07 66.4,212.34 65.66,212.34 65.07,212.93 64.65,213.35 64.65,213.51 64.75,213.61 CN1.102
PCIE_NB_MXM_TX14P: length 6.7
  TOP w0.152: CN1.104 64.25,213.61 64.35,213.51 64.35,213.23 65.54,212.05 66.28,212.05 66.38,211.95 66.38,211.86 v1(65.89,211.37) 66.38,210.88 66.38,210.34 C46.2
PCIE_NB_MXM_TX15N: length 7.9
  TOP w0.152: C49.2 68.96,210.34 68.96,211.64 v1(69.45,212.13) 68.96,212.62 68.96,212.93 68.55,213.33 66.39,213.33 66.15,213.58 66.15,213.74 66.25,213.85 CN1.96
PCIE_NB_MXM_TX15P: length 7.9
  TOP w0.152: C48.2 68.67,210.34 68.67,211.64 v1(68.18,212.13) 68.67,212.62 68.67,212.81 68.43,213.04 66.27,213.04 65.86,213.46 65.86,213.71 65.75,213.82 CN1.98
PCIE_NIC_RX_DN0: length 166.1
  TOP w0.152: v3(53.17,137.26) 53.33,137.41 53.83,137.41 54.73,138.31 54.73,138.57 54.82,138.66 54.82,139.23 U3.AD4
  BOTTOM w0.152: C527.1 116.53,34.29 116.19,33.95 115.99,33.95 115.78,34.15 115.78,34.85 117.23,36.3 117.23,41.35 119.95,44.07 119.95,49.52 122.9,52.46 122.9,56.53 128.66,62.3 128.66,69.04 123.11,74.59 123.11,75.46 121.64,76.94 119.13,76.94 118.56,77.51 115.07,77.51 112.19,80.39 112.19,83.91 110.46,85.64 101.46,85.64 100.34,86.75 100.34,92.72 95.75,97.31 77.82,97.31 75.14,99.99 72.45,99.99 61.41,111.02 60.79,111.02 55.42,116.4 55.42,118.85 52.43,121.84 52.43,135.67 53.22,136.46 53.22,137.21 v3(53.17,137.26)
PCIE_NIC_RX_DP0: length 166.1
  TOP w0.152: v3(52.61,136.93) 52.61,137.39 52.94,137.72 53.31,137.72 53.33,137.71 53.71,137.71 54.44,138.43 U3.AE3
  BOTTOM w0.152: v3(52.61,136.93) 52.75,136.93 52.93,136.75 52.93,136.58 52.14,135.79 52.14,121.72 55.13,118.73 55.13,116.27 60.67,110.73 61.29,110.73 72.32,99.69 75.02,99.69 77.7,97.02 95.63,97.02 100.05,92.6 100.05,86.63 101.34,85.34 110.34,85.34 111.9,83.79 111.9,80.26 114.95,77.22 118.44,77.22 119.01,76.64 121.52,76.64 122.82,75.34 122.82,74.47 128.37,68.92 128.37,62.42 122.6,56.65 122.6,52.58 119.66,49.64 119.66,44.19 116.94,41.47 116.94,36.42 115.49,34.97 115.49,34.03 115.87,33.66 116.17,33.66 C529.1
PCIE_NIC_TX_DN0: length 182.8
  TOP w0.152: C130.2 45.68,131.65 45.4,131.37 45.4,130.94 45.92,130.42 45.92,130.24 v5(46.29,129.87)
  BOTTOM w0.152: v5(46.29,129.87) 46.06,129.64 46.06,125.78 48.04,123.8 48.04,120.21 50.98,117.28 50.98,114.64 58.85,106.77 59.33,106.77 60.31,105.79 60.31,103.92 59.59,103.2 57.02,103.2 53.63,99.82 53.63,95.3 50.29,91.96 50.29,89.61 49.45,88.77 49.45,84.9 48.78,84.23 48.78,80.23 46.53,77.98 46.53,72.37 46.07,71.91 46.07,64.56 47.45,63.18 47.45,52.12 57.45,42.11 57.45,37.53 61.39,33.59 61.39,32.6 63.22,30.77 86.02,30.77 86.75,31.5 88.63,31.5 89.81,32.68 98.04,32.68 99.32,33.96 110.25,33.96 111.36,32.85 111.36,32.28 114.37,29.27 118.03,29.27 118.85,30.1 119.17,30.1 119.23,30.16 U24.18
PCIE_NIC_TX_DP0: length 183.3
  TOP w0.152: v2(45.45,129.87) 45.63,130.05 45.63,130.3 45.11,130.82 45.11,131.21 C129.2
  BOTTOM w0.152: v2(45.45,129.87) 45.77,129.55 45.77,125.66 47.75,123.68 47.75,120.09 50.68,117.16 50.68,114.52 58.73,106.48 59.21,106.48 60.02,105.66 60.02,104.05 59.47,103.49 56.89,103.49 53.34,99.94 53.34,95.42 50,92.08 50,89.73 49.16,88.89 49.16,85.02 48.49,84.35 48.49,80.35 46.24,78.11 46.24,72.49 45.78,72.03 45.78,64.44 47.15,63.06 47.15,52 57.16,41.99 57.16,37.4 61.1,33.47 61.1,32.48 63.1,30.48 86.14,30.48 86.87,31.2 88.75,31.2 89.93,32.38 98.16,32.38 99.45,33.67 110.13,33.67 111.07,32.73 111.07,32.16 114.25,28.98 118.15,28.98 118.98,29.81 119.17,29.81 119.23,29.76 U24.17
PCIE_RST_N: length 98.2
  TOP w0.102: v2(54.27,24.79) 54.27,23.06 52.28,21.08 50.49,21.08 v2(49.41,20) ; R421.1 98.13,39.83 98.63,40.32 102.69,40.32 103.16,39.85 103.16,31.7 102.37,30.91 96.73,30.91 96.12,30.3 v2(96.12,25.88)
  BOTTOM w0.102: v2(54.27,24.79) v1(54.93,24.13) 55.7,23.36 56.74,23.36 57.1,22.99 61.97,22.99 62.72,22.24 90.02,22.24 91.55,23.77 91.55,25.17 92.67,26.29 95.67,26.29 96.07,25.88 v2(96.12,25.88) ; R728.1 41.92,31.37 41.6,31.05 41.6,24.7 44.02,22.29 47.13,22.29 v2(49.41,20)
PCIE_RST_R_N: length 17.5
  TOP w0.102: U10.P1 94.84,54.97 95.62,54.19 95.62,51.84 95.16,51.38 95.16,50.98 95.62,50.52 95.77,50.52 97.17,49.12 97.17,45.59 97.04,45.47 97.04,43.05 96.63,42.65 96.63,40.71 R421.2 96.33,40.69 95.96,40.32 v1(95.58,40.32)
PCIE_RST_TV_N: length 6.2
  TOP w0.102: v1(32.14,25.27) 32.83,24.59 R496.1 33.84,24.59 34.48,23.95 35.98,23.95 36.33,23.6 CN5.22
PCIE_RST_WLAN_N: length 5.9
  TOP w0.102: CN2.22 37.88,86.64 36.46,85.22 35.44,85.22 v2(34.75,84.52)
  BOTTOM w0.102: v2(34.75,84.52) 34.51,84.28 R633.1
PCIE_TUNER_CLKREQ_N: length 4.9
  TOP w0.102: CN5.7 27.13,15.53 26.4,16.26 v2(25.47,16.26)
  BOTTOM w0.102: R751.2 25.49,16.27 v2(25.47,16.26)
PCIE_TUNER_RX_DN1: length 146.4
  TOP w0.145: U3.AD3 53.99,139.21 53.99,138.61
  TOP w0.152: CN5.23 36.73,14.83 36.99,15.09 36.99,15.62 36.45,16.16 v2(36.45,16.17) ; v2(50,139.03) 50.3,138.73 50.3,138.18 50.81,137.67 51.83,137.67 52.36,138.2 53.58,138.2 53.99,138.61
  BOTTOM w0.152: v2(50,139.03) 50.3,138.73 50.3,138.34 44.58,132.61 44.58,125.41 46.89,123.1 46.89,119.75 49.79,116.84 49.79,114.18 53.44,110.53 53.44,103.22 50.93,100.7 50.93,96.31 46.94,92.32 46.94,88.81 46.25,88.13 46.25,82.13 43.97,79.84 43.97,77.06 43.09,76.18 43.09,68.16 42.48,67.55 42.48,63.45 39.7,60.67 39.7,52.6 39.24,52.14 39.24,49.13 38.3,48.2 38.3,45.74 36.69,44.13 36.69,41.35 35.57,40.23 35.57,35.18 35.27,34.87 35.27,22.91 36.11,22.07 36.54,21.64 36.66,21.51 36.66,17.63 36.94,17.35 36.94,16.66 v2(36.45,16.17)
PCIE_TUNER_RX_DP1: length 146.4
  TOP w0.152: CN5.25 37.53,14.83 37.29,15.08 37.29,15.96 37.49,16.17 v2(37.72,16.17) ; v2(50.9,139.03) 50.6,138.73 50.6,138.3 50.93,137.96 51.71,137.96 52.23,138.49 53.27,138.49 U3.AE2
  BOTTOM w0.152: v2(50.9,139.03) 50.6,138.73 50.6,138.21 44.87,132.49 44.87,125.53 47.18,123.22 47.18,119.87 50.09,116.96 50.09,114.3 53.73,110.65 53.73,103.09 51.22,100.58 51.22,96.19 47.23,92.2 47.23,88.69 46.54,88 46.54,87.66 46.75,87.45 46.75,87.12 46.54,86.92 46.54,86.59 46.8,86.33 46.8,86.05 46.54,85.79 46.54,82.01 46.13,81.6 46.13,81.39 46.14,81.35 45.86,81.08 45.62,81.08 45.34,80.81 45.34,80.6 45.34,80.56 45.07,80.29 44.83,80.29 44.26,79.72 44.26,76.94 43.38,76.06 43.38,68.04 42.77,67.43 42.77,63.33 39.99,60.54 39.99,52.48 39.53,52.02 39.53,49.01 38.59,48.08 38.59,45.62 36.98,44.01 36.98,41.23 35.86,40.11 35.86,35.06 35.56,34.75 35.56,27.38 35.7,27.24 35.7,27 35.56,26.86 35.56,26.49 35.7,26.35 35.7,26.17 35.56,26.04 35.56,25.78 35.7,25.64 35.7,25.46 35.56,25.32 35.56,25.08 35.7,24.94 35.7,24.77 35.56,24.63 35.56,24.45 35.7,24.31 35.7,24.13 35.56,23.99 35.56,23.76 35.7,23.62 35.7,23.38 35.56,23.24 35.56,23.03 36.31,22.28 36.74,21.85 36.96,21.64 36.96,21.23 37.09,21.09 37.09,20.8 36.96,20.66 36.96,20.4 37.09,20.26 37.09,19.99 36.96,19.85 36.96,19.63 37.09,19.49 37.09,19.25 36.96,19.11 36.96,17.75 37.35,17.36 37.35,16.99 37.24,16.88 37.24,16.37 37.44,16.17 v2(37.72,16.17)
PCIE_TUNER_TX_DN1: length 12.7
  TOP w0.152: CN5.31 39.93,15.21 40.19,15.46 40.19,15.76 39.88,16.06 v2(39.63,16.06)
  BOTTOM w0.152: v2(39.63,16.06) 39.88,16.06 40.16,15.79 40.16,14.95 39.83,14.63 35.78,14.63 35.09,15.32 35.09,16.55 35.36,16.83 35.36,17.85 35.57,18.06 C540.2
PCIE_TUNER_TX_DP1: length 13.3
  TOP w0.152: v2(40.91,16.06) 40.68,16.06 40.48,15.85 40.48,15.46 40.73,15.21 CN5.33
  BOTTOM w0.152: C541.2 35.07,17.84 35.07,16.95 34.8,16.68 34.8,15.2 35.66,14.34 39.95,14.34 40.45,14.83 40.45,15.82 40.68,16.06 v2(40.91,16.06)
PCIE_WAKE_MXM_N: length 9.4
  TOP w0.102: R51.2 83.2,209.68 85.16,211.65 85.55,211.65 v1(85.93,212.03) 85.93,212.53 86.5,213.11 89.04,213.11 89.25,213.32 CN1.4
PCIE_WAKE_N: length 484.4
  TOP w0.102: v2(119.16,40.56) 116.09,37.49 v2(116.09,36.7) ; v2(29.47,26.42) 29.16,26.1 23.51,26.1 23.32,25.91 23.32,25.53 22.55,24.77 22.44,24.77 R486.1 ; v2(52.84,72.14) 52.84,72.09 51.11,70.36 v2(47.89,70.36) 39.51,70.36 39.25,70.1 v2(38.49,70.1) ; v3(89.13,60.45) 89.13,60.43 U10.H6 ; R51.1 83.2,207.39 84.44,206.15 84.44,200.71 82.93,199.2 75.89,199.2 74.18,200.91 63.61,200.91 61.58,202.95 33.92,202.95 30.92,205.94 28.56,205.94 27.86,205.24 18.34,205.24 16.88,203.78 16.88,201.68 15.52,200.32 15.52,181.69 13.17,179.34 13.17,173.98 15.52,171.64 15.52,162.19 18.5,159.21 20.39,159.21 22.75,156.84 23.58,156.84 26.11,154.32 26.11,150.94 25.6,150.43 13.75,150.43 8.77,145.45 8.77,118.29 22.46,104.6 22.46,96.86 22.74,96.58 24.79,96.58 26.88,94.49 28.65,94.49 32.52,90.61 v3(32.52,90.23) ; v2(71.26,59.54) 70.98,59.82 66.74,59.82 v2(66.05,60.5)
  BOTTOM w0.102: v2(52.84,72.14) 52.84,63.16 52.08,62.4 52.08,59.82 52.26,59.64 58.63,59.64 58.74,59.74 65.26,59.74 66.05,60.53 v2(66.05,60.5) ; v3(32.52,90.23) 32.52,89.22 33.28,88.46 33.28,88.27 34.11,87.44 34.11,86.04 33.73,85.66 33.48,85.66 32.97,85.15 32.97,83.82 34.43,82.36 34.43,78.61 34.86,78.18 R629.1 35.19,77.6 39.14,73.65 39.14,70.75 v2(38.49,70.1) 37.92,69.53 v1(37.92,69.41) 37.92,63.94 36.27,62.29 36.27,50.16 33.76,47.66 33.76,44.8 31.43,42.47 31.43,28.37 30.87,27.82 30.87,27.81 v2(29.47,26.42) ; v3(89.13,60.45) 89.13,60.46 88.52,61.06 86.9,61.06 86.69,60.85 85.5,60.85 84.67,60.02 75.19,60.02 74.71,59.54 v2(71.26,59.54) ; v2(116.09,36.7) 116.01,36.63 113.33,36.63 112.33,35.64 98.72,35.64 97.14,34.06 88.88,34.06 87.84,33.02 83.2,33.02 82.43,33.78 63.17,33.78 58.75,38.2 58.75,42.69 48.78,52.66 48.78,63.94 47.38,65.34 47.38,69.85 v2(47.89,70.36) ; v2(119.16,40.56) 119.52,40.21 119.87,40.21 120.45,39.64 120.45,39.28 R730.2 120.91,37.64 R709.2
PCIE_WAKE_TV_N: length 16.4
  TOP w0.102: v1(20.38,26.64) 20.38,25.88 20.31,25.81 20.31,24.05 20.72,23.64 R486.2 22.17,22.61 21.79,22.23 21.79,16.95 22.24,16.51 23.63,16.51 24.73,15.41 CN5.1
PCIE_WAKE_WLAN_N: length 12
  TOP w0.102: v2(35.06,80.01) 34.43,80.01 32.22,77.8 v2(31.02,77.8) 26.56,77.8 26.28,78.08 CN2.1
  BOTTOM w0.102: v2(35.06,80.01) 35.19,79.88 R629.2
PCIE_WLAN_CLKREQ_N: length 6.5
  TOP w0.102: CN2.7 28.68,80.88 v3(28.69,80.87)
  BOTTOM w0.102: 28.59,79.58 28.59,79.58 28.08,79.07 R659.2 ; 28.59,79.58 28.69,79.68 v3(28.69,80.87) ; 28.59,79.58 R659.2 ; R659.2 28.08,78.09 v1(28.07,78.08) ; R659.2 R627.1
PCIE_WLAN_RX_DN2: length 83.5
  TOP w0.152: v2(43.89,81.8) 43.62,81.53 43.04,81.53 42.73,81.84 39.22,81.84 38.53,81.15 38.53,80.25 38.28,80 CN2.23 ; U3.AD2 v3(53.24,139.26)
  BOTTOM w0.152: v2(43.89,81.8) 44.21,81.48 44.31,81.48 44.92,82.09 44.92,88.45 45.98,89.52 45.98,92.72 50.04,96.77 50.04,101.05 52.59,103.6 52.59,110.15 48.91,113.83 48.91,116.52 46.02,119.41 46.02,122.58 43.71,124.89 43.71,136.72 44.88,137.89 46.81,137.89 49.57,140.65 52.56,140.65 53.1,140.11 53.1,139.4 v3(53.24,139.26)
PCIE_WLAN_RX_DP2: length 83.5
  TOP w0.152: v2(43.89,80.87) 43.95,80.93 43.95,81.13 43.84,81.24 42.92,81.24 42.61,81.55 39.34,81.55 38.82,81.03 38.82,80.31 39.08,80.05 CN2.25 ; U3.AD1 52.66,139.48 52.44,139.48 v3(52.29,139.63)
  BOTTOM w0.152: v2(43.89,80.87) 43.89,80.99 44.09,81.19 44.44,81.19 45.21,81.97 45.21,82.46 45.38,82.62 45.38,83.02 45.21,83.18 45.21,83.58 45.38,83.74 45.38,84.14 45.21,84.3 45.21,84.69 45.38,84.86 45.38,85.25 45.21,85.42 45.21,88.33 46.28,89.4 46.28,92.6 50.33,96.65 50.33,100.93 52.88,103.48 52.88,110.27 49.2,113.95 49.2,116.64 46.31,119.53 46.31,122.7 44,125.01 44,136.59 45,137.6 46.93,137.6 49.69,140.36 52.43,140.36 52.81,139.98 52.81,139.71 52.73,139.63 v3(52.29,139.63)
PCIE_WLAN_TX_DN2: length 8.5
  TOP w0.152: v2(41.42,80.91) 41.74,80.59 41.74,80.27 41.48,80.02 CN2.31
  BOTTOM w0.152: C462.2 41.48,83.51 41.26,83.29 41.26,82.77 41.09,82.6 41.09,82.57 41.09,82.43 40.88,82.22 40.71,82.22 40.44,81.95 40.44,81.25 40.6,81.09 40.6,80.86 40.44,80.69 40.44,80.46 40.75,80.15 41.57,80.15 41.86,80.44 41.86,80.71 41.66,80.91 v2(41.42,80.91)
PCIE_WLAN_TX_DP2: length 8.5
  TOP w0.152: CN2.33 42.28,80.02 42.03,80.27 42.03,80.59 v2(42.35,80.91)
  BOTTOM w0.152: v2(42.35,80.91) 42.15,80.71 42.15,80.31 41.69,79.86 40.63,79.86 40.14,80.34 40.14,82.07 40.97,82.89 40.97,83.3 C463.2
PD#: length 5.9
  TOP w0.102: R225.2 36.86,104.76 36.65,104.97 D7.A ; R225.2 37.3,104.78 37.79,104.78 38.05,104.52 v2(38.05,103.63) ; R225.2 37.29,105.22 v1(37.73,105.66)
  BOTTOM w0.102: v2(38.05,103.63) 37.59,104.09 U20.52
PE6_LAN_RXN_C: length 4
  BOTTOM w0.152: U24.23 119.42,32.16 119.39,32.13 119.11,32.13 118.98,32.26 118.98,33.08 118.13,33.93 117.72,33.93 117.41,34.24 C527.2
PE6_LAN_RXP_C: length 4
  BOTTOM w0.152: C529.2 117.41,33.32 117.72,33.64 118.01,33.64 118.69,32.96 118.69,32.14 118.99,31.84 119.14,31.84 119.22,31.76 U24.22
PE_GPIO0: length 10
  TOP w0.102: U10.AJ4 106.51,57.72 108.6,55.63 108.6,52.13 v1(109.87,50.86) 109.36,50.36 R354.2
PE_WAKE_NIC_N: length 13.9
  BOTTOM w0.102: R724.2 119.77,41.1 118.91,41.1 118.58,40.77 118.58,40.13 118.76,39.95 119.8,39.95 120.13,39.62 120.13,36.91 120.51,36.53 R709.1 120.66,36.5 120.06,35.9 119.35,35.9 v1(119.07,35.62) 119.77,34.92 121.36,34.92 121.8,34.48 U24.28
PERSTB: length 91.9
  TOP w0.102: v2(118.5,34.52) 118.5,34.09 116.95,32.54 116.95,29.18 114.95,27.18 113.57,27.18 111.84,25.45 110.96,25.45 109.61,26.8 v3(109.61,27.43)
  BOTTOM w0.102: v2(118.5,34.52) 118.6,34.42 119.77,34.42 120.6,33.58 U24.25 ; R738.1 45.1,28.96 44.71,28.57 44.71,27.62 v1(45.1,27.24) 45.54,26.8 48.91,26.8 49.29,26.42 50.68,26.42 51.19,25.91 54.27,25.91 56.41,23.76 56.9,23.76 57.27,23.39 62.14,23.39 62.89,22.64 89.56,22.64 90.74,23.83 90.74,25.78 91.76,26.8 97.65,26.8 99.17,28.32 109.23,28.32 109.61,27.94 v3(109.61,27.43)
PLLVDD: length 14.3
  TOP w0.254: 61.64,158.81 U3.A12
  TOP w0.3: 61.64,158.81 61.64,158.82 61.64,161.36 60.29,162.71 60.29,163.75 v1(59.45,164.59) 59.07,164.97 58.81,164.97 57.41,166.37 C100.1
  TOP w0.381: L9.2 58.05,169.62 58.05,168.78 58.3,168.53 58.3,167.51 57.66,166.87 C100.1
PLLVDD18: length 16.8
  TOP w0.292: U3.D14 63.24,155.81 63.64,156.21 63.64,158.34 63.59,158.39
  TOP w0.381: L8.2 64.5,170.25 64.5,168.28 63.73,167.5 C99.1 62.82,166.94 62.82,166.82 v1(62.62,166.62) 62.7,166.55 62.7,162.69 63.59,161.8 63.59,158.39
PSON_N: length 191.1
  TOP w0.254: v2(157.87,63.12) 157.74,62.99 145.55,62.99 145.3,62.74 145.3,57.26 144.12,56.08 133.26,56.08 131.02,53.85 126.12,53.85 124.09,51.82 120.25,51.82 118.37,49.94 v2(118.37,43.89) 120.42,41.85 124.79,41.85 125.32,42.38 Q36.G ; v2(161.05,55.75) 154.93,55.75 153.99,54.81 153.99,53.64 152.03,51.69 152.03,45.47 152.73,44.76 Q37.G ; Q23.G 166.19,47.82 166,48.01 v2(166,49.91) ; v2(84.31,33.58) 81.75,36.14 81.75,40.92 80.83,41.83 75.95,41.83 73.87,43.91 73.87,44.44 72.82,45.49 71.17,45.49 70.72,45.94 68.76,45.94 67.9,46.79 67.89,46.79 67.25,47.43 Q28.G
  TOP w0.508: Q25.G 180.54,48.71 v2(180.86,48.39)
  BOTTOM w0.254: v2(157.87,63.12) 157.87,58.93 v2(161.05,55.75) 162.7,54.1 162.7,52.83 165.62,49.91 v2(166,49.91) 173.33,49.91 173.87,49.36 Q61.D ; v2(118.37,43.89) 116.85,42.36 v1(115.73,42.36) 115.73,41.09 110.73,36.09 98.41,36.09 97.14,34.82 88.35,34.82 87.11,33.58 v2(84.31,33.58)
  BOTTOM w0.508: 178.7,46.78 178.75,46.78 179.21,47.24 179.72,47.24 v2(180.86,48.39) 180.54,48.71 Q62.G ; 178.7,46.78 R684.2 ; 178.7,46.78 177.56,46.78 R685.1 176.34,49.32 Q61.D
PSON_N_1V5: length 9.2
  TOP w0.102: R317.2 30.06,62.55 29.92,62.69 Q21.G 29.92,63.56 29.36,64.12 R283.1 27.53,64.12 25.83,62.42 Q20.D 25.83,60.29 v1(26.17,59.94)
PSON_N_1V5_CTRL: length 7.1
  TOP w0.102: v2(26.93,62.84) 26.93,61.47 27.33,61.08 PC70.1 27.89,60.52 28.59,59.82 v1(28.9,59.82) R306.2
  BOTTOM w0.102: v2(26.93,62.84) 27.73,62.84 27.87,62.7 27.87,62.1 Q59.4
PSON_N_3V3_CTRL: length 4.4
  TOP w0.254: C290.1 v1(158.51,42.8) R430.2 159.03,44.02 159.68,44.67 Q30.4
PSON_N_5V_CTRL: length 4.9
  TOP w0.254: v1(168.13,44.63) 168.33,44.43 C277.1 168.79,43.43 169.35,42.88 R374.2 Q31.4
PSON_N_12V_CTRL: length 4.5
  TOP w0.254: v1(123.71,42.61) 123.71,43.64 C264.1 124.34,44.27 124.75,44.27 R387.2 125.27,44.79 Q26.4
PSOUT_SIO_N: length 87.8
  TOP w0.102: v2(36.1,29.64) 36.33,29.41 42.45,29.41 44.37,27.5 47.06,27.5 47.88,26.68 48.97,26.68 49.11,26.54 52.84,26.54 53.48,25.91 v2(53.48,25.02) ; R471.1 39.21,33.4 R472.1 37.17,33.15 v2(36.4,33.15) ; R365.1 86.37,38.76 87.62,37.52 87.62,31.78 90.94,28.45 90.94,28.09 92.77,26.26 v2(92.77,25.65)
  BOTTOM w0.102: v2(36.4,33.15) 36.1,32.85 v2(36.1,29.64) ; v2(53.48,25.02) 53.48,24.82 55.14,23.15 56.65,23.15 57.02,22.78 61.89,22.78 62.64,22.03 90.32,22.03 92.09,23.8 92.09,24.94 v1(92.14,24.99) 92.77,25.63 v2(92.77,25.65)
PU_DVI_HPD: length 11.4
  TOP w0.102: CN1.31 82.5,223.15 81.66,223.99 R30.2 81.94,225 82.18,225.23 82.18,226.23 82.32,226.38 82.72,226.38 82.93,226.59 82.93,228.08 83.65,228.8 84.86,228.8 85.35,229.3 85.35,230.13 v1(85.1,230.39)
PU_SIO_PSON_N: length 4.1
  TOP w0.102: U11.33 44.34,33.21 v1(42.86,31.72) 43.44,31.14 R462.1
PU_SIO_RSTOUT1_N: length 3.3
  TOP w0.102: U11.38 46.51,32.34 46.18,32 46.18,31.1 v1(46.37,30.91) 46.49,30.78 R465.1
PU_SIO_RSTOUT2_N: length 5.6
  TOP w0.102: U11.37 46.11,32.38 45.48,31.75 R464.1 45.45,30.15 44.97,29.67 44.97,28.19 v1(44.87,28.09)
PVIEN: length 7.1
  TOP w0.102: v2(99.58,168.5) 101.43,166.65 102.2,166.65 102.8,166.05 U6.E2
  BOTTOM w0.102: R541.1 99.58,170.86 v1(99.58,169.93) v2(99.58,168.5)
PWM1_P0: length 50.8
  TOP w0.254: PU2.48 114.87,241.27 114.44,241.71 v3(112.81,241.71) ; v2(88.4,208.15) 88.96,208.71 PU4.2
  BOTTOM w0.305: v2(88.4,208.15) 88.4,208.41 96.53,216.53 96.53,228.57 103.2,235.24 v1(103.2,236.66) 103.21,236.68 107.08,236.68 112.11,241.71 v3(112.81,241.71)
PWM1_P0_SENSE_N: length 2
  TOP w0.254: PR35.2 114.37,227.93 v1(114.37,227.01) 114.37,226.26 R47.1
PWM1_P0_SENSE_P: length 6.3
  TOP w0.254: PU2.14 115.38,230.93 PC15.1 115.58,229.73 v2(115.72,229.59) R46.1
  BOTTOM w0.254: PC15.1 115.72,230.58 v2(115.72,229.59)
PWM3_P0: length 39.3
  TOP w0.254: PU2.46 115.88,241.87 v3(115.58,242.16) ; v2(112.41,211.07) 112.91,210.57 PU5.2
  BOTTOM w0.254: v3(115.58,242.16) 115.17,242.16 112.99,239.98 112.99,233.88 110.37,231.27 110.37,224.51 113.17,221.72 113.17,214.31 112.6,213.74 112.28,213.74 111.39,212.85 v1(111.39,211.71) 112.02,211.07 v2(112.41,211.07)
PWM3_P0_SENSE_N: length 3
  TOP w0.254: v1(116.03,226.06) 116.03,226.06 R48.1 117.05,226.1 PR34.2
PWM3_P0_SENSE_P: length 7
  TOP w0.254: PU2.18 117.38,232.65 118.18,231.84 118.18,230.94 PC14.1 117.99,230.31 v2(117.99,229.74) 117.99,229.65 118.51,229.13 R45.1
  BOTTOM w0.254: PR70.2 118.4,230.73 117.99,230.31 v2(117.99,229.74)
PWR_ACT_LED1_N: length 18.6
  TOP w0.102: R362.1 34.3,47.05 36.71,49.47 v2(40.14,49.47) ; v2(40.33,45.15) 40.95,45.15 41.08,45.02 R358.1 41.67,43.86 41.67,42.1 41.79,41.97 R454.1 42.48,41.32 v1(42.68,41.53)
  BOTTOM w0.102: v2(40.33,45.15) 39.51,45.97 39.51,48.13 40.14,48.77 v2(40.14,49.47)
PWR_ACT_LED1_WHITE: length 9.2
  BOTTOM w0.102: Q67.G 11.38,3.14 11.38,4.06 10.87,4.57 9.92,4.57 v1(8.71,5.78) R766.2 R765.1 9.73,8.71 S3.L1
PWR_ACT_LED1_WHITE_R: length 9
  TOP w0.102: v2(9.73,6.16) 10.7,7.13 R520.2 14.15,7.13 v1(14.49,6.79) v2(14.49,5.97)
  BOTTOM w0.102: R769.1 R765.2 v2(9.73,6.16) ; Q66.D 13.73,5.77 13.93,5.97 v2(14.49,5.97)
PWR_ACT_LED_AMBER: length 13.7
  BOTTOM w0.102: Q67.D 11.8,5.5 v1(12.14,5.84) 11.76,6.22 R764.2 R769.2 10.74,8.19 11.95,9.4 11.95,10.92 10.79,12.08 S3.L2
PWR_ACT_LED_AMBER_R: length 67.7
  TOP w0.102: Q33.C 35.71,42.04 35.56,41.89 35.56,41.01 33.54,38.99 v2(33.03,38.99) ; v2(19.06,12.06) 19.06,10.16 17.03,8.13 12.14,8.13 v2(11.76,8.51) 11.38,8.13 9.15,8.13 v2(8.71,8.57)
  BOTTOM w0.102: v2(33.03,38.99) 33.03,38.93 v1(32.52,38.42) 32.14,38.04 32.14,33.17 32.68,32.64 32.68,27.91 33.44,27.15 33.44,25.96 32.27,24.79 32.27,21.46 32.59,21.15 32.59,17.44 31.94,16.79 28.39,16.79 27.24,15.65 25.22,15.65 23.91,16.95 23.44,16.95 22.85,17.55 20.25,17.55 19.67,18.14 19.19,18.14 18.81,17.75 18.81,12.32 v2(19.06,12.06) ; R763.2 R764.1 v2(11.76,8.51) ; v2(8.71,8.57) R766.1 7.48,7.8 R767.2
PWR_ACT_LED_N: length 7.7
  TOP w0.102: R453.1 37.72,40.55 36.25,40.55 35.82,40.13 35.82,38.69 R432.1 35.32,37.34 v1(35.06,37.08) 35,37.02 R435.1
PWRBTN_R_N: length 16.6
  TOP w0.102: v1(8.58,6.41) 8.01,6.99 8.01,9.14 8.25,9.38 S3.2 8.76,11.18 14.18,11.18 S3.1
  BOTTOM w0.102: R762.2 14.87,6.94 C552.1 R759.1 14.95,10.41 S3.1
PWRBTN_SIO_N: length 54.1
  TOP w0.102: R473.1 R472.2 38.92,31.8 38.75,31.62 37.54,31.62 36.78,32.38 33.54,32.38 33.03,32.89 31.13,32.89 30.62,33.4 29.92,33.4 29.73,33.21 29.73,32.64 29.47,32.38 28.52,32.38 27.89,31.75 23.76,31.75 22.94,30.92 v2(15.12,30.92) ; v2(15.63,8.89) v2(13.98,8.89)
  BOTTOM w0.102: v2(15.12,30.92) 13.35,29.15 v1(13.35,21.15) 13.35,19.05 13.22,18.92 13.22,9.27 13.6,8.89 v2(13.98,8.89) ; R759.2 15.81,8.71 v2(15.63,8.89)
PWRGD_PS: length 388.2
  TOP w0.102: R477.1 47.64,29.08 47.29,28.74 47.29,28.29 47.56,28.01 47.56,27.37 48.03,26.9 49.18,26.9 49.31,26.77 53.03,26.77 55.04,24.76 55.04,22.9 51.37,19.24 48.29,19.24 47.9,18.84 46.55,18.84 45.54,17.83 33.82,17.83 v2(33.52,18.13) ; Q70.D 76.59,205.36 76.34,205.1 v1(76.34,204.41) 76.34,203.84 76.97,203.2 78.12,203.2 78.27,203.05 Q609.3 79.02,202.45 79.64,203.07 C556.1 80.23,202.61 80.4,202.44 81.97,202.44 R776.2 v2(82.81,202.44) R258.1
  INT1 w0.089: v2(13.85,170.18) 16.65,170.18 16.97,169.86 16.97,167.77 16.71,167.51 16.71,141.86 15.44,140.59 15.44,130.37 13.92,128.84 13.92,112.84 16.9,109.86 16.9,55.37 22.11,50.16 23.19,50.16 23.63,49.72 23.63,25.78 22.55,24.7 22.55,18.92 21.92,18.29 21.92,17.59 v2(22.49,17.02)
  BOTTOM w0.102: v2(33.52,18.13) 33.52,17.69 32.21,16.38 29.92,16.38 28.08,14.54 25.09,14.54 24.46,15.18 24.46,16 23.76,16.7 22.81,16.7 v2(22.49,17.02) ; v2(13.85,170.18) 13.85,175.2 12.46,176.59 12.46,179.71 10.93,181.23 10.93,184.15 12.33,185.55 12.33,206.88 18.81,213.36 18.81,214.12 23.63,218.95 23.63,220.22 26.55,223.14 26.55,226.44 33.41,233.3 46.24,233.3 50.3,237.36 82.56,237.36 86.12,233.81 86.12,222.38 84.08,220.34 84.08,210.69 82.81,209.42 v2(82.81,202.44)
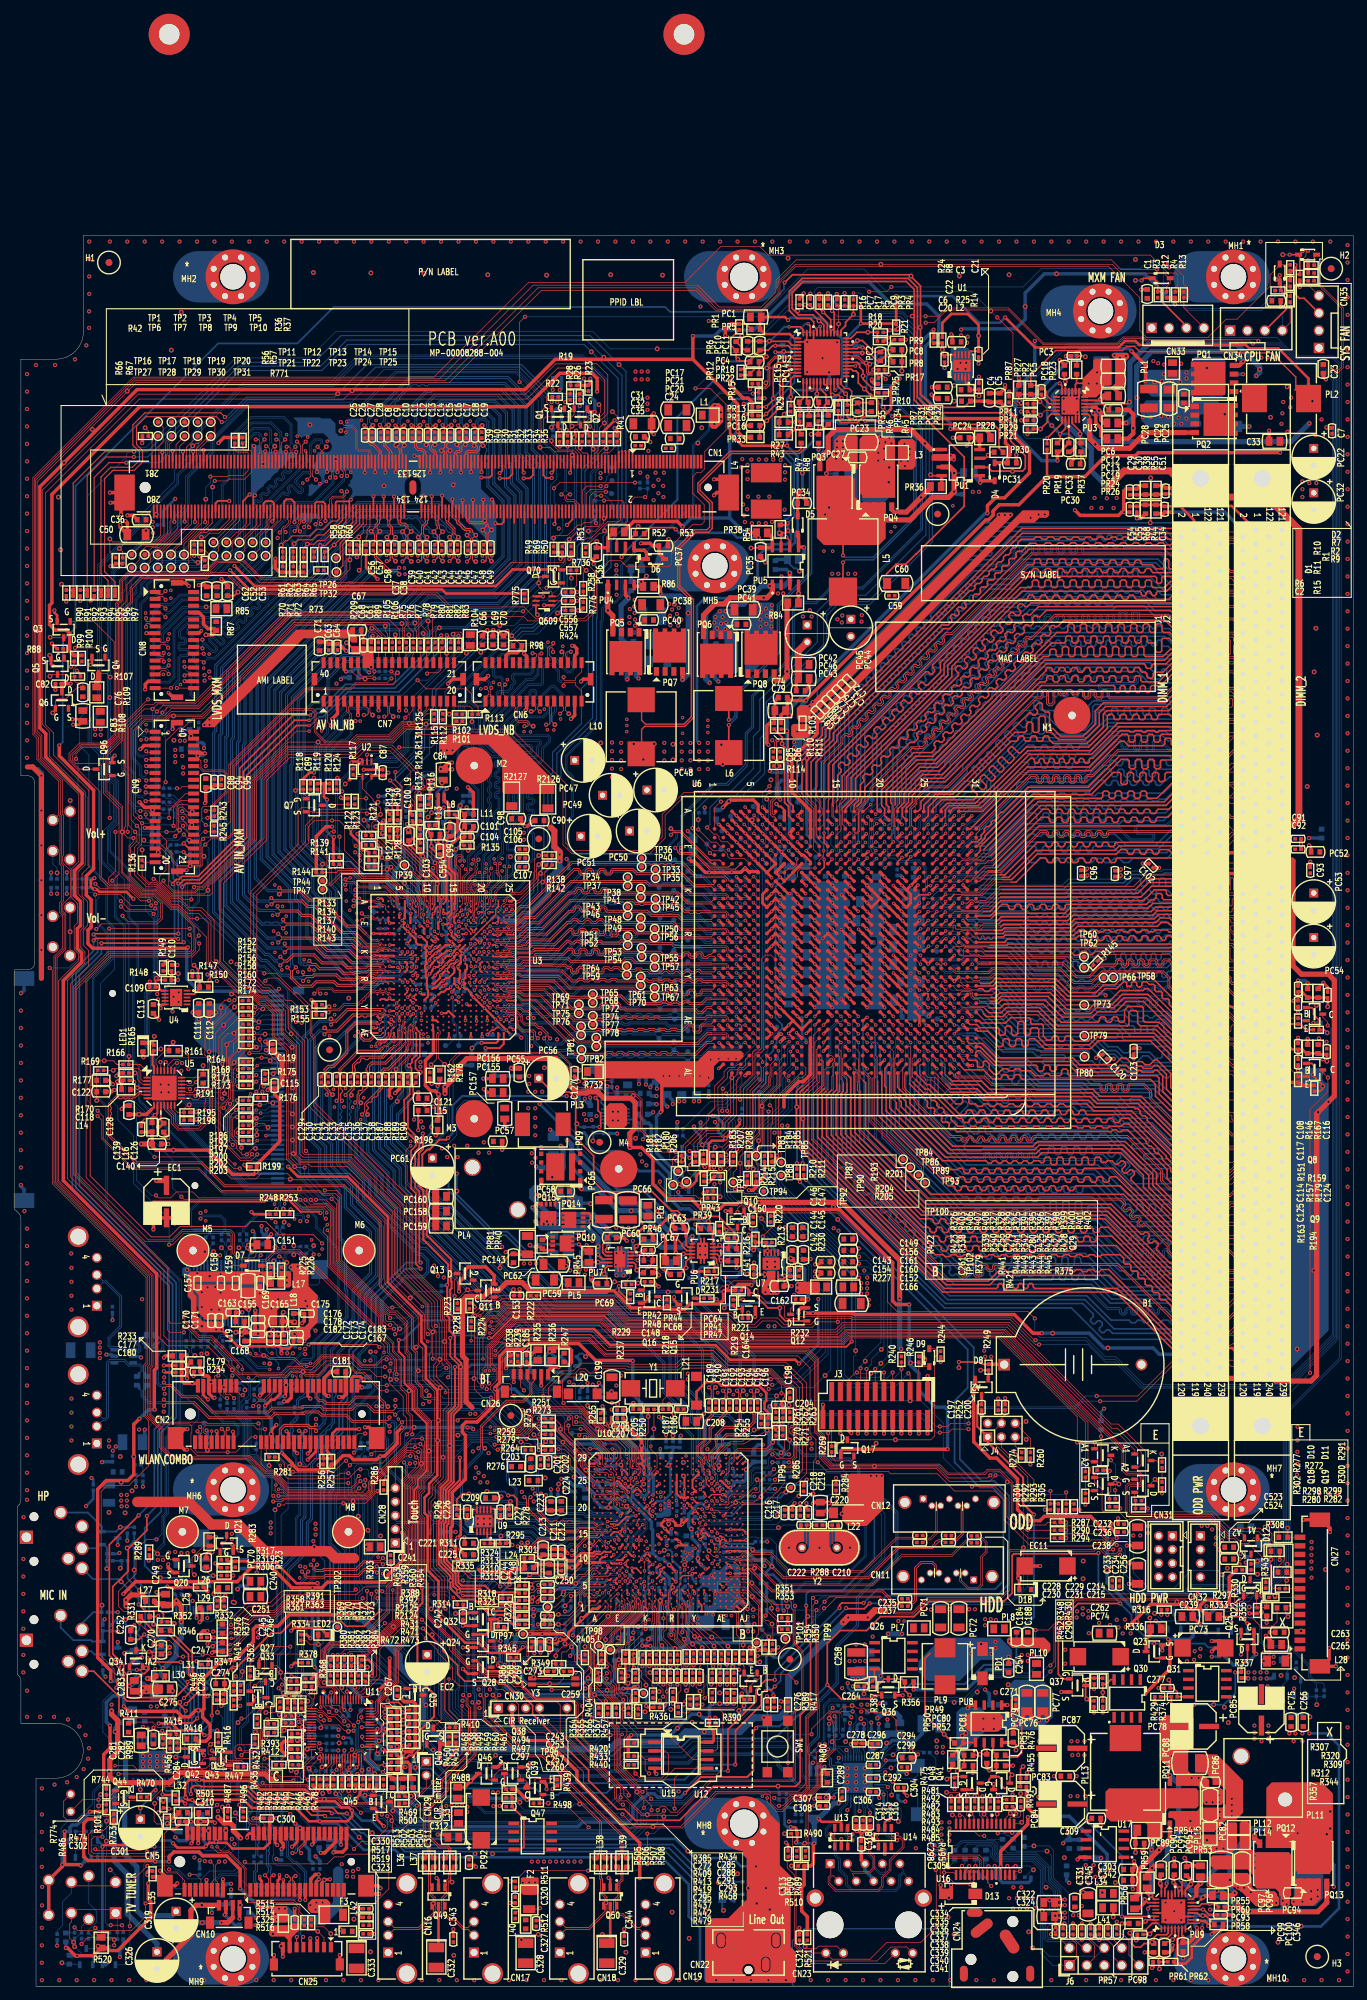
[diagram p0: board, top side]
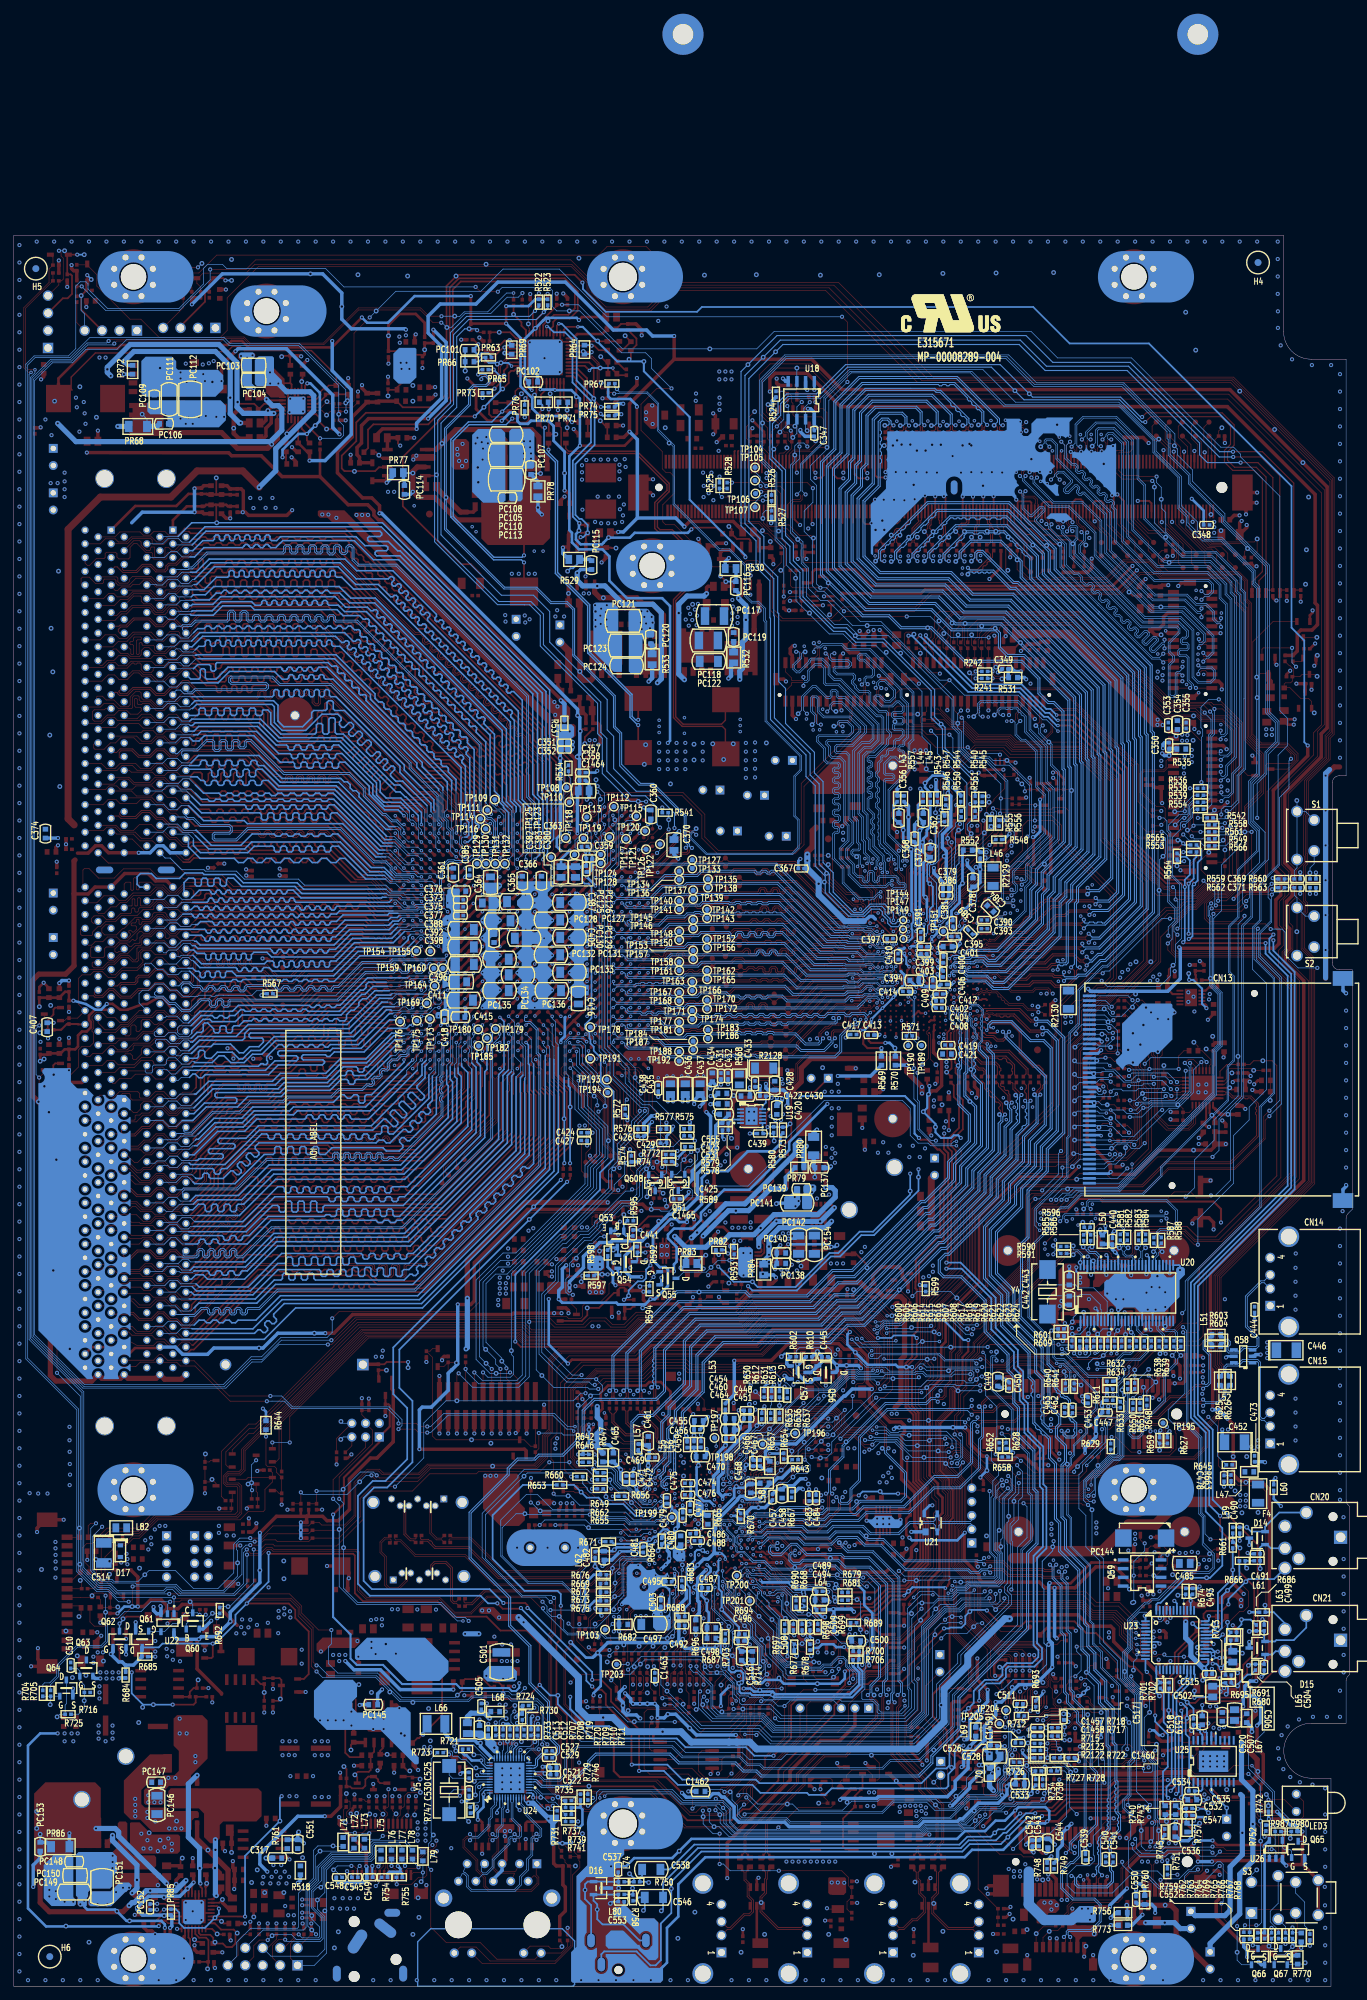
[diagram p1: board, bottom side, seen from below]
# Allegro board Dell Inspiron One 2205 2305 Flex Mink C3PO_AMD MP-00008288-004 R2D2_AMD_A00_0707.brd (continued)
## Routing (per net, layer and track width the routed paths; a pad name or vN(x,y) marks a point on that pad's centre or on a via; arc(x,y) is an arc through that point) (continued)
PWROK_SIO: length 5.6
  TOP w0.102: U11.41 47.71,31.17 48.65,30.23 R466.1 48.57,30.15 48.14,29.72 48.14,28.98 v1(48.65,28.47)
REF0/SEL_HTT6: length 4.2
  BOTTOM w0.102: R605.2 R606.2 38.68,94.81 v1(38.43,95.06) 38.24,95.25 38.24,95.89 38.09,96.03 U20.4
REFCLK_N: length 19.2
  TOP w0.102: v3(60.12,154.48) 60.27,154.48 U3.F11
  BOTTOM w0.13: v3(60.12,154.48) 59.72,154.87 59.7,154.87 58.87,155.71 58.87,156.92 58.66,157.12 57.67,158.12 57.67,163.19 57.29,163.58 57.29,166.12 v1(55.51,167.89) 56.08,168.47 56.08,169.23 55.51,169.8 R551.1
REMOTE_P: length 6.3
  TOP w0.102: v1(59.89,40.96) 59.49,41.36 Q35.C 59.49,43.08 59.2,43.37 Q35.B 56.34,43.37 56.13,43.16 C267.1
RESERVED_3: length 3.1
  TOP w0.102: v2(27,81.47) 27.19,81.28 27.19,80.52 27.08,80.41 CN2.3
  BOTTOM w0.102: TP195.1 v2(27,81.47)
RESTORE#: length 4.1
  TOP w0.102: R226.2 38.98,104.76 v1(39.63,105.41) 38.75,106.3 v2(38.56,106.3)
  BOTTOM w0.102: U20.53 38.09,106.02 38.36,106.3 v2(38.56,106.3)
RIA: length 4.7
  TOP w0.102: U16.18 143.64,22.87 144.16,22.35 v2(145.3,22.35)
  BOTTOM w0.102: v2(145.3,22.35) 146.33,22.35 L71.1
RIA_L: length 36.9
  TOP w0.102: C341.1 161.48,7.57 162.32,6.73 162.32,4.54 J6.9
  BOTTOM w0.102: L71.2 148.4,20.37 v1(148.47,20.45) 150.69,20.45 151.33,19.8 151.33,15.75 153.49,13.59 153.49,8.64 153.68,8.45 160.48,8.45 162.51,6.41 162.51,4.35 J6.9
RSMRST_N: length 86.8
  TOP w0.102: v2(91.45,28.32) 87.84,31.93 87.84,37.59 87.13,38.3 87.13,41.27 84.5,43.91 84.5,45.2 R422.1 84.47,46.23 84.47,50.01 89.24,54.79 U10.G1 ; R478.1 50.41,29.29 50.18,29.53 50.18,30.67 v2(49.92,30.92)
  BOTTOM w0.102: v2(49.92,30.92) 49.92,30.48 50.94,29.46 50.94,27.94 51.7,27.18 55.71,27.18 58.48,24.41 62.62,24.41 63.26,23.77 81.95,23.77 82.51,24.33 89.11,24.33 89.57,24.79 89.57,26.37 90.36,27.15 90.36,28.05 v1(90.63,28.32) v2(91.45,28.32) 91.77,28.64 93.48,28.64 93.73,28.38 C1462.1
RST_PLTRST_N: length 265
  TOP w0.102: v2(40.14,25.08) 39.78,25.45 R496.2 33.28,25.84 v2(32.71,26.42) ; R58.2 48.8,207.8 v1(48.83,207.77) 48.83,206.38 47.4,204.95 35.85,204.95 33.23,207.57 29.55,207.57 27.63,205.65 16.69,205.65 15.69,204.65 15.69,201.89 15.11,201.31 15.11,182.01 13.56,180.45 9.87,180.45 8.93,179.51 v2(8.93,178.79) ; v2(24.78,98.04) 24.78,96.91 26.95,94.74 28.78,94.74 33.16,90.36 v3(33.16,89.85)
  BOTTOM w0.102: v2(24.78,98.04) 24.33,98.49 24.33,102.71 13.47,113.57 13.47,128.18 11.52,130.13 11.52,146.8 14.31,149.6 14.31,154.2 13.29,155.22 13.29,160.6 10.6,163.29 10.6,173.14 9.22,174.53 9.22,178.5 v2(8.93,178.79) ; v2(40.14,25.08) 41.16,26.1 41.16,31.31 41.86,32 43.64,32 43.87,31.77 R728.2 R727.1 45.1,31.16 R738.2 ; v2(32.71,26.42) 32.65,26.48 32.65,27.3 32.24,27.71 32.24,32.28 31.7,32.83 31.7,42.41 34.21,44.91 34.21,47.4 36.78,49.97 36.78,61.98 38.81,64.01 38.81,68.58 39.83,69.6 39.83,74.49 39.32,74.99 39.32,75.88 35.95,79.25 35.95,81.34 36.14,81.53 36.14,82.36 35.7,82.8 34.3,82.8 33.22,83.88 33.22,84.57 R633.2 34.36,85.71 34.36,87.57 33.54,88.39 33.54,88.58 33.16,88.96 v3(33.16,89.85)
RSVD: length 1.7
  TOP w0.102: U3.G11 60.28,152.84 v3(60.21,152.84)
  BOTTOM w0.102: TP151.1 59.57,153.48 v3(60.21,152.84)
RSVD1: length 1.5
  TOP w0.102: v3(64.67,155.13) 64.94,154.86 U3.E17
  BOTTOM w0.102: TP144.1 65.25,155.13 v3(64.67,155.13)
RSVD2: length 2.1
  TOP w0.102: U3.F17 65.17,154.06 65.16,154.05 65.09,154.05 v3(64.63,153.59)
  BOTTOM w0.102: v3(64.63,153.59) 65.39,152.83 TP149.1
RSVD3: length 1.6
  TOP w0.102: v3(64.74,154.43) 64.37,154.06 U3.F15
  BOTTOM w0.102: TP147.1 65.23,153.95 v3(64.74,154.43)
RTC_CLK: length 2.7
  TOP w0.102: v4(87.89,57.15) 87.69,57.15 86.84,56.3 U10.D2
  BOTTOM w0.102: v4(87.89,57.15) 87.77,57.02 TP201.1
RTSA: length 4.2
  TOP w0.102: v2(136.03,17.34) 136.22,17.14 137.62,17.14 137.79,16.97 U16.2
  BOTTOM w0.102: L78.1 136.92,18.22 v2(136.03,17.34)
RTSA_L: length 42.5
  TOP w0.102: J6.7 160.03,4.29 160.03,5.91 159.21,6.73 v2(158,6.73) C339.1
  BOTTOM w0.102: v2(158,6.73) v1(157.36,7.37) 157.17,7.56 154.57,7.56 153.81,6.79 150.51,6.79 150.19,7.11 150.19,9.97 151.65,11.43 151.65,13.91 150.19,15.37 150.19,17.27 148.54,18.92 143.33,18.92 142.95,19.3 142.95,20.51 142.5,20.95 138.05,20.95 L78.2
RXDA: length 7.6
  TOP w0.102: U16.27 137.79,22.73 137.98,22.54 139.84,22.54 140.47,21.91 v2(141.23,21.91)
  BOTTOM w0.102: L73.1 141.73,21.41 v2(141.23,21.91)
RXDA_L: length 22.4
  TOP w0.102: v2(150.97,7.57) C334.1 J6.2
  BOTTOM w0.102: L73.2 143.95,20.12 144.64,19.43 148.79,19.43 150.82,17.4 150.82,15.49 152.16,14.16 152.16,8.76 v1(151.59,8.19) v2(150.97,7.57)
SA0: length 21.3
  TOP w0.102: U6.AK4 105.31,134.3 104.83,133.82 103.93,133.82 103.34,133.22 103.34,132.49 101.98,131.12 101.98,127.89 101.12,127.03 101.12,126.23 97.17,122.28 R181.2 96.3,120.95 95.85,120.5 95.85,119.56 TP87.1
SATA_CALRN: length 10.5
  TOP w0.32: U10.AA14 99.54,65.8 v3(99.32,66.01)
  BOTTOM w0.32: v3(99.32,66.01) 99.32,66.09 99.78,66.55 100.39,66.55 101.46,65.48 101.74,65.48 102.13,65.09 v1(102.37,65.09) 102.82,64.64 103.8,64.64 104,64.44 107.58,64.44 R671.2
SATA_CALRP: length 2.9
  TOP w0.32: v3(99.85,65.06) 99.85,65.08 100.31,65.54 U10.AB14
  BOTTOM w0.32: v1(101.15,63.45) 100.59,64.01 R664.2 100.5,64.42 v3(99.85,65.06)
SATA_RX_C_DN0: length 11
  TOP w0.13: C235.1 130.55,56.01 130.82,56.01 131.07,56.26 131.07,60.96 131.96,61.85 133.75,61.85 134.24,61.35 134.24,60.58 CN11.5
SATA_RX_C_DN1: length 6.5
  TOP w0.13: CN12.5 137.88,69.53 137.88,65.91 137.14,65.17 136.49,65.17 136.39,65.27 136.39,65.59 C229.1
SATA_RX_C_DP0: length 10.8
  TOP w0.13: C237.1 130.47,55.74 130.93,55.74 131.35,56.15 131.35,60.85 132.07,61.58 133.63,61.58 133.97,61.24 133.97,60.49 133.67,60.19 CN11.6
SATA_RX_C_DP1: length 6.6
  TOP w0.13: C231.1 136.71,64.9 137.25,64.9 138.15,65.8 138.15,69.44 CN12.6
SATA_RXN0: length 26.3
  TOP w0.102: U10.AJ8 106.01,60.88 106.01,60.79 106.09,60.71 106.48,60.71 106.66,60.88 106.94,60.88 106.96,60.9 107.14,60.9 107.15,60.88 107.23,60.88 107.24,60.87
  TOP w0.13: C235.2 129.4,56.3 129.4,55.98 129.27,55.85 128.31,55.85 126.44,57.72 110.39,57.72 107.24,60.87
SATA_RXN1: length 35.5
  TOP w0.102: U10.AG10 104.54,62.42 104.57,62.39 104.9,62.39 105.04,62.25 105.06,62.25 105.13,62.19 105.35,62.19 105.42,62.25 105.86,62.25 105.92,62.19 106.55,62.19 106.59,62.23 106.65,62.23 106.65,62.22 106.66,62.22
  TOP w0.13: 106.66,62.22 109.47,62.22 112.05,59.64 124.29,59.64 128.68,64.03 133.53,64.03 134,64.49 134,64.64 134.24,64.88 134.39,64.88 134.6,65.09 135.64,65.09 135.75,65.2 135.75,65.51 C229.2
SATA_RXP0: length 26.5
  TOP w0.102: U10.AH8 105.59,60.92 106.01,60.5 106.56,60.5 106.74,60.68 107.03,60.68 107.03,60.69 107.04,60.69 107.05,60.68
  TOP w0.13: 107.05,60.68 110.28,57.45 126.33,57.45 128.2,55.58 129.04,55.58 129.25,55.37 C237.2
SATA_RXP1: length 35.6
  TOP w0.102: U10.AF10 104.3,62.19 104.81,62.19 104.95,62.05 104.98,62.05 105.04,61.98 105.44,61.98 105.5,62.05 105.77,62.05 105.84,61.98 106.55,61.98 106.58,61.95 106.61,61.95
  TOP w0.13: 106.61,61.95 109.36,61.95 111.94,59.37 124.41,59.37 128.79,63.75 133.64,63.75 134.71,64.82 135.42,64.82 C231.2
SATA_TX_C_DN0: length 13.8
  TOP w0.099: CN11.3 137.65,59.71 137.65,59.04 138.91,57.78 140.35,57.78 140.98,58.42 140.98,62.51 141.64,63.17 141.64,64.72 140.96,65.41 140.39,65.41 C214.1
SATA_TX_C_DN1: length 6.9
  TOP w0.099: CN12.3 134.38,69.48 134.38,65.96 133.44,65.02 132.65,65.02 C230.1
SATA_TX_C_DP0: length 13.8
  TOP w0.099: CN11.2 138.44,60.33 138.38,60.39 138.06,60.39 137.9,60.23 137.9,59.15 139.01,58.04 140.24,58.04 140.73,58.53 140.73,62.61 141.39,63.27 141.39,64.62 140.85,65.15 140.16,65.15 140.03,65.02 140.03,64.75 C215.1
SATA_TX_C_DP1: length 6.6
  TOP w0.099: C228.1 132.65,65.28 133.33,65.28 134.12,66.07 134.12,69.79 133.92,69.98 CN12.2
SATA_TXN0: length 38.5
  TOP w0.099: C214.2 139.48,65.46 139.48,65.18 139.33,65.02 138.59,65.02 136.43,62.87 129.17,62.87 124.9,58.6 110.96,58.6 110.41,59.15 110.41,59.15 109.86,59.7 109.86,59.7 108.6,60.96 108.06,61.49 105.67,61.49 105.6,61.57 105.6,61.68 U10.AJ9
SATA_TXN1: length 29.5
  TOP w0.099: C230.2 131.58,64.82 131.58,65.05 131.48,65.15 128.51,65.15 123.69,60.33 112.75,60.33 110.18,62.89 107.4,62.89 107.04,62.53 106.51,62.53 106.31,62.74 106.13,62.74 106.04,62.65 U10.AJ10
SATA_TXP0: length 38.6
  TOP w0.099: U10.AH9 104.97,61.72 105.45,61.24 107.96,61.24 108.42,60.78 109.75,59.45 109.75,59.45 110.16,59.04 110.16,59.04 110.85,58.34 125.01,58.34 129.28,62.61 136.54,62.61 138.69,64.77 139.15,64.77 139.34,64.58 C215.2
SATA_TXP1: length 29.8
  TOP w0.099: C228.2 131.15,65.41 128.41,65.41 123.58,60.58 112.86,60.58 110.29,63.14 107.29,63.14 106.94,62.79 106.61,62.79 106.41,62.99 106.03,62.99 105.55,62.52 U10.AH10
SATA_X1: length 20.5
  TOP w0.102: R288.2 v2(116.09,67.18) C222.2 115.38,64.56 Y2.2 ; v3(102.35,65.99) 102.35,66.21 101.94,66.62 U10.AD16
  BOTTOM w0.102: v2(116.09,67.18) 111.9,67.18 111.26,66.55 106.44,66.55 105.43,65.54 103.63,65.54 103.24,65.94 102.4,65.94 v3(102.35,65.99)
SATA_X2: length 23.8
  TOP w0.102: R288.1 v2(118.37,67.18) C210.2 119.09,64.56 Y2.1 ; U10.AC16 101.14,66.64 v3(101.56,66.22)
  BOTTOM w0.102: v3(101.56,66.22) 101.56,66.22 101.91,66.57 103.56,66.57 103.96,66.17 105.1,66.17 106.2,67.26 111.01,67.26 111.67,67.92 117.64,67.92 v2(118.37,67.18)
SB800_MEMHOT_N: length 4.6
  TOP w0.102: Q29.E 106.25,46.61 106.12,46.74 R401.2 R402.2 107.6,47.24 v1(108.53,47.24)
SB_A_RST_N: length 13.9
  TOP w0.102: v1(89.36,44.13) 89.93,44.7 89.93,45.13 R338.2 89.94,45.64 89.5,46.08 89.5,49.42 91.39,51.31 91.39,53.12 92.16,53.9 92.16,54.74 92.39,54.97 92.39,55.67 U10.L1
SB_AZ_VDDIO: length 36.8
  BOTTOM w0.305: R706.1 72.02,47.42 72.02,46.53 71.36,45.87 71.36,43.59 72.86,42.09 84.26,42.09 84.59,42.42 87.45,42.42 87.7,42.67 89.04,42.67 89.27,42.9 89.27,43.97 v1(88.97,44.26) 88.72,44.51 88.72,45.59 89.08,45.96 89.77,45.96 89.99,45.74 90.46,45.74 90.83,46.11 90.83,47.61 91.35,48.13 91.5,48.13 92.01,48.64 92.01,49.97 R687.2
  BOTTOM w0.381: C500.1 71.63,49.75 71.84,49.53 R700.1 R706.1
SB_OSC: length 92.7
  TOP w0.13: v2(113.8,74.23) 114.74,75.17 114.74,87.7 112,90.45 103.94,90.45 101.77,92.62 86.23,92.62 83.91,94.95 74.14,94.95 73.42,94.23 v3(72.91,94.23) ; v2(53.12,93.12) 52.77,93.47 v2(42.81,93.47)
  BOTTOM w0.13: R600.1 40.86,93.17 41.1,93.41 42.75,93.41 v2(42.81,93.47) ; R660.1 v2(113.8,74.23) ; v2(53.12,93.12) 58.47,93.12 v1(58.49,93.09) 71.77,93.09 v3(72.91,94.23)
SB_OSC_R: length 4.5
  BOTTOM w0.13: U20.3 38.59,96.04 39.63,95 v1(40.78,95) 40.78,94.74 40.84,94.68 R600.2
SB_PCI_RST_R_N: length 9.2
  TOP w0.102: R395.1 v1(98.75,49.85) 97.84,51.18 97.84,51.65 97.32,52.17 97.32,55.33 97.62,55.63 97.62,55.88 U10.V2
SB_PCIE_LAN_CLKREQ_N: length 89
  TOP w0.102: v3(100.65,67.28) 100.42,67.05 99.88,67.05 U10.AA16 ; v2(116.8,54.8) 116.65,54.64 116.65,51.71 117.03,51.33 117.03,40.46 115.58,39.01 115.58,28.78 114.7,27.9 113.07,27.9 112.6,27.43 v2(110.63,27.43) ; v2(111.09,68.71) 111.09,71.32 111.64,71.88 113.22,71.88 113.42,72.09 R285.1
  BOTTOM w0.102: v2(116.8,54.8) 113.54,54.8 112.96,55.37 112.96,56.84 115.03,58.92 120.03,58.92 123.85,62.74 123.85,66.79 121.8,68.83 v1(120.53,68.83) 120.41,68.71 v2(111.09,68.71) 110.26,67.88 106.02,67.88 105.34,67.21 100.73,67.21 v3(100.65,67.28) ; v2(110.63,27.43) 110.93,27.13 R746.2
SB_PDRST_N: length 81.1
  TOP w0.102: U10.AG4 104.44,57.69 104.79,57.34 105.42,57.34 105.64,57.12 105.64,56.67 105.8,56.52 106.5,56.52 107.07,55.94 107.07,55.28 v2(106.74,54.95) ; R252.2 C200.1 144.28,83.25 143.74,82.71 J4.4 142.76,81.03 142.76,78.99 147.58,74.17 v2(147.58,70.99)
  INT1 w0.089: v2(128.73,53.21) 128.47,52.96 125.61,52.96 123.33,50.67 115.01,50.67 114.69,50.99 114.69,52.32 v2(114.18,52.83)
  BOTTOM w0.102: v2(147.58,70.99) 146.95,70.36 v1(146.95,63.88) 146.95,57.98 144.85,55.88 132.66,55.88 130.5,53.71 129.23,53.71 v2(128.73,53.21) ; v2(114.18,52.83) 113.56,52.21 110.11,52.21 108.02,54.29 107.04,54.29 106.74,54.59 v2(106.74,54.95)
SB_PWRGD: length 125.3
  TOP w0.102: R345.2 73.16,47.88 v2(74.81,46.23) ; R753.1 14.43,24.17 12.93,22.67 11.31,22.67 10.73,22.09 10.73,19.35 11.14,18.95 19.85,18.95 v2(20.36,19.46) ; U10.H5 90.14,58.49 90.49,58.14 v3(90.51,58.14)
  INT1 w0.102: v2(74.81,46.23) 74.69,46.23 73.16,47.75 71.51,47.75 70.75,48.51 61.8,48.51 60.47,47.18 56.53,47.18 55.7,46.35 53.86,46.35 53.29,46.93 51.51,46.93 49.6,48.83 44.97,48.83 42.82,46.68 42.82,44.88 41.55,43.62 41.55,40.71 40.15,39.31 40.15,39.06 36.93,35.84 36.93,32.08 35.51,30.65 35.51,24.26 34.75,23.5 33.33,23.5 31.63,21.8 v2(31.63,21.46)
  BOTTOM w0.102: v2(20.36,19.46) 20.74,19.84 26.96,19.84 27.49,19.3 30.67,19.3 31.43,20.07 31.43,21.26 v2(31.63,21.46) ; v3(90.51,58.14) 90.08,57.71 90.08,55.96 86.96,52.83 86.96,51.14 85.46,49.65 85.46,48.36 82.94,45.85 82.94,45.28 82.37,44.7 75.89,44.7 v1(75.58,45.02) 74.81,45.78 v2(74.81,46.23)
SB_RTCRST_N: length 102.8
  TOP w0.102: v2(75.7,48.51) 75.32,48.9 R386.2 ; J4.3 143.74,78.52 148.47,73.79 v2(148.47,70.99)
  INT1 w0.089: v2(75.7,48.51) 76.46,49.28 79.32,49.28 79.83,48.77 89.1,48.77 89.67,48.2 102.18,48.2 102.5,48.51 106.37,48.51 107.45,47.43 110.63,47.43 113.61,50.42 123.39,50.42 125.68,52.7 129.04,52.7 v3(129.55,53.21)
  BOTTOM w0.102: v3(129.55,53.21) 130.38,53.21 132.79,55.63 145,55.63 147.58,58.21 v1(147.58,66.55) 147.58,70.1 v2(148.47,70.99)
SB_SRC_CLK_DN: length 104
  TOP w0.099: U10.P23 94.67,71.86 v3(94.11,71.3)
  INT1 w0.089: v3(94.11,71.3) 94.3,71.49 94.52,71.49 94.59,71.43 94.59,71.15 94.3,70.85 93.83,70.85 93.42,70.45 93.42,67.94 93.27,67.79 92.43,67.79 92.21,68.01 87.89,68.01 87.02,68.88 72.18,68.88 71.98,69.09 64.46,69.09 58.3,62.93 54.94,62.93 53.89,63.98 42.84,63.98 42.04,64.78 42.04,71.78 46.62,76.37 46.62,87.06 44.85,88.82 43.14,88.82 41.03,90.93 38.28,90.93 37.69,90.35 37.49,90.35 v6(37.16,90.68)
  BOTTOM w0.099: R617.2 32.03,93.17 31.95,93.09 31.95,92.71 32.4,92.27 33.41,92.27 35.44,90.24 36.72,90.24 v6(37.16,90.68)
SB_SRC_CLK_DP: length 104.8
  TOP w0.099: U10.M23 93.51,71.8 93.59,71.72 93.88,71.72 v3(94.13,71.97)
  INT1 w0.089: v3(37.16,89.85) 37.41,90.11 37.79,90.11 38.38,90.69 40.93,90.69 43.04,88.58 44.75,88.58 46.38,86.96 46.38,76.47 41.79,71.88 41.79,64.68 42.74,63.73 53.79,63.73 54.84,62.69 58.4,62.69 64.56,68.85 71.88,68.85 72.08,68.64 86.92,68.64 87.79,67.77 92.11,67.77 92.33,67.55 93.37,67.55 93.66,67.84 93.66,70.35 93.93,70.61 94.4,70.61 94.83,71.05 94.83,71.53 94.62,71.73 94.37,71.73 v3(94.13,71.97)
  BOTTOM w0.099: R618.2 31.7,92.92 31.7,92.6 32.29,92.01 33.31,92.01 35.33,89.99 37.02,89.99 v3(37.16,89.85)
SB_SRC_CLK_R_DN: length 3.5
  BOTTOM w0.099: R617.1 32.16,94.03 31.95,94.23 31.95,94.81 32.47,95.32 32.47,96.14 32.59,96.26 U20.15
SB_SRC_CLK_R_DP: length 3.3
  BOTTOM w0.099: U20.16 32.09,96.26 32.21,96.14 32.21,95.43 31.7,94.91 31.7,94.28 R618.1
SB_TEST0: length 6.2
  TOP w0.102: U10.B3 85.05,56.92 84.69,56.57 83.74,56.57 v3(83.65,56.66)
  BOTTOM w0.102: R697.1 82.59,52.85 v1(82.59,53.59) 83.16,54.17 83.16,56.17 v3(83.65,56.66)
SB_TEST1: length 9.9
  TOP w0.102: v4(85.65,57.3) 86.04,57.69 U10.C4
  BOTTOM w0.102: R698.1 80.15,53.12 80.25,53.22 80.85,53.22 82.37,54.74 v1(82.37,55.75) 82.37,56.93 82.83,57.39 83.67,57.39 84.15,56.91 85.26,56.91 v4(85.65,57.3)
SB_TEST2: length 15
  TOP w0.102: U10.F6 88.54,59.38 v4(88.13,58.97)
  BOTTOM w0.102: R699.1 77.86,53.21 78.81,54.17 v1(79.2,54.17) 79.26,54.1 80.84,54.1 81.54,54.8 81.54,56.9 82.66,58.01 86.21,58.01 86.72,58.52 87.64,58.52 88.09,58.97 v4(88.13,58.97)
SCLK1: length 5.9
  BOTTOM w0.102: R731.2 116.84,25.58 v1(117.17,25.91) 117.66,25.91 118.81,27.05 118.81,28.05 119.31,28.56 U24.14
SCLK2: length 12.8
  TOP w0.102: U10.D25 86.74,73.81 86.27,73.81 85.94,74.14 84.36,74.14 82.69,75.82 82.69,76.64 80.31,79.02 80.07,79.02 v1(79.84,79.25) 78.62,80.47 78.62,81.07 R273.1
SD_D0/MMC_D0/MS_D0/XD_D0: length 46.3
  TOP w0.102: R202.1 33.23,124.4 33.23,124.39 32.58,124.39 v2(32.52,124.33) ; v2(30.43,127.95) 30.87,128.4 30.87,128.71 31.44,129.29 31.44,131.57 31.63,131.76 31.63,134.24 v1(31.95,134.56) 33.79,136.4 34.43,136.4 34.68,136.14 35.57,136.14 35.95,136.53 35.95,137.29 35.7,137.54 v2(35.7,137.92) ; U5.24 22.28,134.16 23.12,135 23.89,135 v2(24.39,134.49)
  BOTTOM w0.102: CN13.P17 37.12,128.17 36.59,127.64 v3(35.19,127.64) ; v2(35.7,137.92) 35.82,138.05 35.82,138.49 36,138.67 CN13.P32 ; v3(35.19,127.64) 33.35,127.64 32.84,127.13 31.25,127.13 v2(30.43,127.95) 29.73,127.95 29.16,128.52 25.54,128.52 23.76,130.3 23.76,133.86 v2(24.39,134.49) ; v3(35.19,127.64) 34.49,126.94 34.49,126.3 v2(32.52,124.33)
SD_D1/MMC_D1/MS_D1/XD_D1: length 32.9
  TOP w0.102: v3(35.32,123.19) 34.68,122.56 33.87,122.56 R203.1 32.78,123.19 32.01,123.95 32.01,124.65 32.77,125.41 33.23,125.41 33.23,125.41 R200.1 ; U5.25 21.78,134.42 v2(21.98,134.62)
  BOTTOM w0.102: v2(21.98,134.62) 23.12,133.48 23.12,130.18 25.41,127.89 26.68,127.89 31.38,123.19 v3(35.32,123.19) 35.4,123.27 CN13.P10 40.44,123.27 v1(40.46,123.25)
SD_D2/MMC_D2/MS_D2/XD_D2: length 33.2
  TOP w0.102: v5(30.55,130.05) 30.55,130.49 30.64,130.58 30.64,133.31 31.13,133.79 31.13,135.21 31.89,135.97 31.89,137.29 32.69,138.09 33.22,138.09 R172.1 ; v2(26.35,129.67) 26.17,129.85 U5.16 ; R186.1 v2(32.4,129.03) 32.4,128.46 31.25,127.32 31.25,123.06 v2(31.76,122.56)
  BOTTOM w0.102: v2(26.35,129.67) 26.86,130.18 30.43,130.18 v5(30.55,130.05) 31.57,129.03 v2(32.4,129.03) ; v2(31.76,122.56) 32.14,122.94 34.55,122.94 34.92,122.57 CN13.P9
SD_D3/MMC_D3/MS_D3/XD_D3: length 40.4
  TOP w0.102: v2(30.24,122.81) 29.92,123.13 29.92,128.14 31.13,129.35 v2(31.13,131.95) 31.13,133.29 31.38,133.54 31.38,135.13 v1(32.65,136.4) 33.24,136.98 R174.1 ; U5.17 24.86,130.35 25.03,130.18 25.92,130.18 v2(26.43,130.68)
  BOTTOM w0.102: v2(30.24,122.81) 31.02,122.02 32.12,122.02 32.78,122.68 34.24,122.68 35.05,121.87 CN13.P8 ; CN13.P24 38.3,133.07 36.61,133.07 36.46,133.22 34.81,133.22 33.28,131.7 31.38,131.7 v2(31.13,131.95) 27.7,131.95 v2(26.43,130.68)
SD_D4/MMC_D4/MS_D4/XD_D4: length 33.4
  TOP w0.102: R164.1 33.23,134.68 32.72,134.18 32.46,134.18 31.89,133.6 31.89,131.7 31.7,131.51 31.7,128.84 v2(31.38,128.52) 31.38,128.14 30.74,127.51 30.74,122.43 32.9,120.27 34.43,120.27 v2(35.33,121.17) ; v2(25.54,130.68) 25.37,130.85 U5.18
  BOTTOM w0.102: v2(31.38,128.52) 31.13,128.78 29.6,128.78 29.35,129.03 25.92,129.03 25.54,129.41 v2(25.54,130.68) ; v2(35.33,121.17) 35.33,121.17 CN13.P7 39.76,121.17 39.88,121.28 v1(40.59,121.28)
SD_D5/MMC_D5/MS_D5/XD_D5: length 32.1
  TOP w0.102: v2(25.54,131.7) 25.39,131.85 U5.20 ; v2(34.55,121.21) 34.55,121.03 34.17,120.65 32.9,120.65 31,122.56 31,127.44 31.91,128.36 31.91,131.34 32.14,131.57 32.14,132.21 v2(32.52,132.59) 32.65,132.46 R171.1
  BOTTOM w0.102: v1(40.78,119.38) 39.69,120.47 CN13.P6 35.24,120.47 34.55,121.16 v2(34.55,121.21) ; v2(32.52,132.59) 32.08,133.03 26.87,133.03 v2(25.54,131.7)
SD_D6/MMC_D6/MS_D6/XD_D6: length 29.1
  TOP w0.102: v2(24.27,133.35) 24.26,133.36 U5.22 ; R192.1 32.46,127.83 v2(32.27,127.64) 31.51,126.87 31.51,123.57 32.33,122.75 32.33,122.01 33.18,121.16 v2(33.79,121.16) 34.68,122.05 v1(35.06,122.05)
  BOTTOM w0.102: v2(32.27,127.64) 31.51,127.64 30.62,128.52 29.54,128.52 29.28,128.78 25.66,128.78 24.27,130.18 v2(24.27,133.35) ; CN13.P5 36.08,119.77 35.71,120.14 34.81,120.14 v2(33.79,121.16)
SD_D7/MMC_D7/MS_D7/XD_D7: length 29.8
  TOP w0.102: v2(23.63,134.49) 23.38,134.49 22.78,133.9 U5.23 ; R197.1 v2(32.4,126.62) 32.01,126.62 31.76,126.36 31.76,123.7 33.03,122.43 v5(33.03,122.15)
  BOTTOM w0.102: v2(23.63,134.49) 23.51,134.37 23.51,130.18 25.47,128.21 29.09,128.21 30.68,126.62 v2(32.4,126.62) ; v5(33.03,122.15) 33.03,121.16 34.43,119.76 35.44,119.76 36.13,119.07 CN13.P4
SD_ON: length 6.9
  TOP w0.102: U10.AE19 102.74,69 102.4,69.34 101.66,69.34 v3(101.51,69.49)
  BOTTOM w0.102: R656.1 105.93,71.37 v1(105.01,70.46) 103.8,69.24 101.76,69.24 v3(101.51,69.49)
SDA2: length 16.9
  TOP w0.102: U10.F23 88.24,72.02 87.84,72.42 87.66,72.42 87.4,72.68 87.4,73.15 87.17,73.38 87.17,73.94 86.99,74.12 86.65,74.12 86.5,74.27 86.5,74.58 86.22,74.85 85.18,74.85 84.85,75.18 84.85,75.39 84.52,75.72 83.53,75.72 83.2,76.05 83.2,76.94 79.51,80.62 v1(79.51,81.15) 79.51,81.79 78.62,82.68 R251.1
SDATA1: length 8.4
  BOTTOM w0.102: U24.15 119.33,28.96 118.22,27.85 v1(118.22,27.51) 117.79,27.51 117.1,26.82 116.11,26.82 115.1,25.81 115.1,25.5 R739.2 R741.2
SDCDN/XDWRN: length 42.4
  TOP w0.102: v3(32.08,119.76) 31.89,119.76 29.67,121.98 29.67,130.62 30.2,131.16 30.2,134.33 v2(30.24,134.37) 30.17,134.43 30.17,137.86 31.13,138.81 v1(31.95,138.81) 31.95,138.86 R158.2 ; v2(21.22,134.62) 21.28,134.56 U5.26
  BOTTOM w0.102: v2(21.22,134.62) 21.85,135.25 29.35,135.25 v2(30.24,134.37) ; v3(32.08,119.76) 32.08,118.81 33.92,116.97 CN13.P1
SDCLK/XDALE/MSBS: length 30.6
  TOP w0.102: R191.2 v2(27.44,130.68) 27.82,130.3 27.82,128.84 27.7,128.71 v2(27.7,127.64) ; R176.1 35.4,130.1 v2(35.19,130.3) 35.63,130.75 35.63,131.21 R175.2
  BOTTOM w0.102: v2(35.19,130.3) 34.81,130.68 33.67,130.68 33.41,130.43 31.51,130.43 31.19,130.75 27.51,130.75 v2(27.44,130.68) ; v2(27.7,127.64) 27.95,127.64 31.79,123.8 33.52,123.8 34.94,125.22 35.57,125.22 35.72,125.37 CN13.P13 40.25,125.37 v1(40.46,125.16)
SDCLK/XDALE/MSBS_P35_R: length 15.9
  TOP w0.102: R175.1 37.65,132.89 v1(37.67,132.91) 38.3,133.54 38.3,134.62 37.25,135.67 36.56,135.67 36.33,135.89 v2(34.17,135.89)
  BOTTOM w0.102: v2(34.17,135.89) 34.17,139.16 35.08,140.06 35.3,140.06 36.01,140.77 CN13.P35
SDCLK/XDALE/MSBS_R: length 5.2
  TOP w0.102: v1(37.6,128.65) 37.03,128.64 R176.2 36.08,129.59 v2(36.08,130.3)
  BOTTOM w0.102: CN13.P20 37.32,130.27 36.97,129.92 36.46,129.92 v2(36.08,130.3)
SDCMD/XDRBN: length 29
  TOP w0.102: v2(26.43,131.7) 25.92,131.19 25.19,131.19 25.03,131.35 U5.19 ; v2(28.9,132.46) 28.65,132.72 28.65,135.38 28.97,135.7 28.97,139.57 v1(32.01,142.62) 32.97,143.57 R152.2
  BOTTOM w0.102: v2(26.43,131.7) 27.19,132.46 v2(28.9,132.46) 29.16,132.72 31.44,132.72 32.21,131.95 33.03,131.95 34.55,133.48 35.91,133.48 36.21,133.77 CN13.P25
SDWP/XDCLE/MSCLK: length 46.2
  TOP w0.102: v2(25.28,133.6) 25.28,135.51 24.52,136.27 R161.1 ; v2(32.52,133.48) 32.71,133.66 33.23,133.66 33.23,133.67 R168.1 ; v2(32.78,119.13) 31.89,119.13 29.25,121.77 29.25,130.9 29.8,131.45 29.8,133.34 v2(29.54,133.6) 29.54,135.19 29.73,135.38 29.73,138.24 32.9,141.41 R156.2
  BOTTOM w0.102: v2(32.52,133.48) 29.67,133.48 v2(29.54,133.6) v2(25.28,133.6) ; v2(32.78,119.13) 34.23,117.67 CN13.P2 40.01,117.67 v1(40.14,117.54)
SENSE_A: length 5.8
  BOTTOM w0.254: R701.1 R702.1 ; R701.1 28.54,44.84 U23.13 ; R701.1 28.03,44.24 28.59,43.69 28.59,42.8 v1(28.08,42.29)
SENSE_B: length 3.2
  TOP w0.254: v5(23.25,52.83) 23,53.09 R352.2
  BOTTOM w0.254: U23.34 22.59,52.17 v5(23.25,52.83)
SERIRQ: length 163.9
  TOP w0.102: v2(59.32,53.39) 63.31,49.4 63.31,49.02 66.04,46.29 67.32,46.29 68.46,45.15 70.43,45.15 70.88,44.7 71.69,44.7 72.75,43.64 73.72,43.64 75.93,41.43 79,41.43 79.46,40.97 79.46,37.13 87.69,28.91 87.69,27.41 88.1,27 89.19,27 91.32,24.87 96.48,24.87 101.42,29.8 113.3,29.8 113.72,30.22 113.72,39.87 114.84,41 114.84,48.82 113.67,49.99 v2(113.67,55.41) ; v3(57.01,53.75) 56.58,53.31 56.58,53.04 52.72,49.18 52.72,45.21 51.91,44.4 R384.1 51.06,43.5 50.43,42.86 50.04,42.86 49.71,42.53 U11.3 ; U10.AB19 100.57,68.76 v3(100.57,68.45)
  BOTTOM w0.102: v2(113.67,55.41) 113.44,55.63 113.44,57 115.13,58.69 120.08,58.69 124.05,62.65 124.05,67.91 120.34,71.62 118.68,71.62 116.51,69.44 110.85,69.44 109.8,68.39 105.87,68.39 105.16,67.69 101.69,67.69 101.41,67.97 100.81,67.97 100.57,68.21 v3(100.57,68.45) ; v3(57.01,53.75) 57.11,53.85 v1(58.3,53.85) 58.86,53.85 v2(59.32,53.39)
SIO_CIR_LED: length 70
  TOP w0.102: U11.64 50.89,40.46 49.92,39.5 49.92,38.61 v2(50.05,38.48) ; v2(88.28,27.51) 88.28,28.68 80.45,36.5 CN30.6
  BOTTOM w0.102: v2(88.28,27.51) 86.19,25.43 68.51,25.43 66.94,27 61.3,27 v1(60.72,26.42) 60.13,25.83 58.02,25.83 55.92,27.94 52.08,27.94 51.7,28.32 51.7,29.84 50.81,30.73 50.81,32.12 50.48,32.45 50.48,34.37 50.05,34.8 v2(50.05,38.48)
SIO_CIR_RX: length 94.5
  TOP w0.102: v2(53.63,31.2) 53.39,31.2 52.69,31.9 52.36,31.9 51.13,33.13 51.13,34.04 50.75,34.42 49.79,34.42 49.31,33.93 U11.45 ; v2(86.12,41.53) 86.12,41.91 84.26,43.76 84.26,50.11 88.89,54.74 88.89,55.04 88.95,55.11 88.95,55.53 88.89,55.59 88.89,56.26 88.44,56.71 U10.F3 ; v2(82.71,40.82) 82.71,36.27 85.66,33.32 85.66,32 89.44,28.22 v2(89.44,27.81)
  BOTTOM w0.102: v2(53.63,31.2) 53.92,31.5 55,31.5 56.22,30.28 56.22,29.08 58.51,26.8 60.21,26.8 60.62,27.21 68.86,27.21 69.12,26.95 72.94,26.95 74.23,25.65 80.66,25.65 81.54,26.54 v1(82.31,26.54) 86.62,26.54 88.15,28.07 89.19,28.07 v2(89.44,27.81) ; v2(86.12,41.53) 86.07,41.58 84.42,41.58 83.65,40.82 v2(82.71,40.82) 81.95,41.58 75.51,41.58 CN30.3
SIO_CIR_TX: length 7.6
  TOP w0.102: U11.46 49.71,33.89 49.99,34.16 50.62,34.16 50.91,33.88 50.91,33.03 52.14,31.79 52.14,31.28 v1(52.44,30.99) 52.72,30.71 R438.2 R499.1
SIO_CIR_WB: length 78.8
  TOP w0.102: v2(88.61,26.47) 88.3,26.47 87.39,27.38 87.39,28.85 76.45,39.79 CN30.4 ; U11.21 43.95,38.86 44.77,38.05 47.22,38.05 48.03,37.24 v2(49.36,37.24)
  BOTTOM w0.102: v1(48.6,37.13) 48.7,37.24 v2(49.36,37.24) 49.64,36.96 49.64,34.44 50.07,34.01 50.07,32.28 50.4,31.95 50.4,30.38 51.19,29.59 51.19,28.07 51.83,27.43 55.79,27.43 58.61,24.61 62.75,24.61 63.38,23.98 81.82,23.98 82.38,24.54 88.89,24.54 89.34,24.99 89.34,25.73 v2(88.61,26.47)
SIO_DEEP_S5: length 3.9
  TOP w0.102: R463.1 44.46,31.65 v1(44.77,31.95) 45.25,31.95 45.71,32.41 U11.36
SIO_GND: length 28.5
  TOP w0.178: U11.56 52.6,37.26 v2(52.85,37.51)
  TOP w0.508: 55.69,34.75 56.49,33.95 v2(56.63,33.95) 56.84,34.16 57.79,34.16 58.35,34.72 R458.2 C293.2 C291.2 C288.2 C285.2 R434.2 58.35,41.16 58.05,41.47 57.13,41.47 Q35.E 56.71,41.47 55.88,42.31 C267.2 ; 55.69,34.75 55.69,34.69 55.28,34.29 53.86,34.29 v2(53.6,34.54) ; 55.69,34.75 C295.2 ; R479.2 55.99,31.93 v2(56.91,31.93)
  BOTTOM w0.508: v2(52.85,37.51) 52.64,37.26 C526.2 53.12,35.05 53.6,34.57 v2(53.6,34.54) 52.87,33.8 C528.2 ; L69.2 54.85,35.81 55.7,34.96 v1(55.7,34.92) 55.74,34.92 56.63,34.04 v2(56.63,33.95) 56.63,32.11 v2(56.91,31.93)
SIO_GRN_LED: length 8.3
  TOP w0.102: U11.23 42.5,38.06 41.56,39.01 41.04,39.01 40.8,39.25 40.8,39.72 40.64,39.88 40.35,39.88 R359.1 39.33,40.46 39.2,40.59 R453.2 38.62,40.57 37.93,39.88 v1(36.59,39.88)
SIO_KBCLK: length 3.3
  TOP w0.102: U11.29 44.13,35.66 v2(44.41,35.38)
  BOTTOM w0.102: v2(44.41,35.38) 45.42,35.38 R715.1 R2123.2
SIO_KBDATA: length 5.2
  TOP w0.102: v2(44.59,34.54) 44.26,34.54 44.08,34.72 44.08,35.03 43.84,35.27 U11.30
  BOTTOM w0.102: R2122.2 v1(44.38,33.27) ; v1(44.38,33.27) 44.38,34.34 v2(44.59,34.54) ; v1(44.38,33.27) R722.1
SIO_LPC_LAD0: length 3.2
  TOP w0.102: R380.1 47,44.13 v1(47.64,43.5) 47.64,42.96 47.86,42.74 47.89,42.74 48.11,42.52 U11.7
SIO_LPC_LAD1: length 2.9
  TOP w0.102: U11.6 48.51,42.61 48.4,42.72 v2(48.4,42.93) 48.4,44 48.02,44.38 R381.1
SIO_LPC_LAD2: length 3.2
  TOP w0.102: R382.1 49.54,43.89 v1(49.54,43.54) 49.54,43.24 48.91,42.61 U11.5
SIO_LPC_LAD3: length 6
  TOP w0.102: U11.4 49.31,42.5 50.18,43.37 50.18,43.81 50.05,43.94 R383.1 50.2,44.4 50.56,44.75 50.56,45.92 50.79,46.15 51.04,46.15 v1(51.37,46.48)
SIO_MSECLK: length 4.3
  TOP w0.102: R2125.2 41.72,36.83 v2(41.91,36.64) 42.08,36.46 U11.27
  BOTTOM w0.102: R718.1 42.04,37.66 v1(41.92,37.77) 41.91,37.76 v2(41.91,36.64)
SIO_MSEDATA: length 4.2
  TOP w0.102: U11.28 42.15,36.07 v2(41.92,35.84) 41.77,35.69 R2124.2
  BOTTOM w0.102: v1(41.16,35.88) 41.2,35.84 v2(41.92,35.84) 42.31,35.84 42.89,36.42 R717.1
SIO_OVT_N: length 3.7
  TOP w0.102: R467.1 49.67,30.18 48.75,31.09 v1(48.7,31.09) 48.11,31.68 U11.42
SIO_P1V5_DDR3_SENSE: length 3.3
  TOP w0.102: U11.53 52.78,36.07 v1(53.1,35.75) 53.92,35.75 54.11,35.94 R419.2
SIO_P5V_SENSE: length 6
  TOP w0.102: R442.2 R479.1 54.49,31.62 v1(53.88,32.23) 52.72,32.23 51.77,33.18 U11.49
SIO_PSIN_N: length 4.6
  TOP w0.102: U11.32 43.25,33.53 41.98,32.26 R473.2 41.33,31.48 v1(41.03,31.18)
SIO_PSOUT_N: length 4.4
  TOP w0.102: U11.31 42.49,34.86 42.17,34.54 42.17,33.58 v1(42.18,33.58) 42,33.4 R471.2 R431.1
SIO_RSMRST_N: length 4.1
  TOP w0.102: U11.48 50.51,31.52 v1(50.58,31.45) 50.68,31.34 R478.2 R468.1
SIO_RSTOUT0_N: length 4.6
  TOP w0.102: U11.39 46.91,31.57 v2(46.89,31.55)
  BOTTOM w0.102: v1(47.43,32.16) 47.43,32.01 46.97,31.55 v2(46.89,31.55) 46.71,31.37 R727.2 46.11,31.32 R734.1
SIO_SMB_CLK: length 6.7
  TOP w0.102: R412.1 38.92,36.96 v1(39.24,37.27) 39.57,37.6 39.57,37.61 R392.1 40.54,38.35 41.28,37.62 41.62,37.62 42.37,36.87 U11.26
SIO_SMB_DATA: length 7.9
  TOP w0.102: U11.25 42.33,37.26 41.76,37.83 41.35,37.83 40.83,38.36 40.83,38.87 40.33,39.37 R388.1 40.29,39.37 39.74,39.93 38.9,39.93 v1(38.54,39.57) 38.54,38.99 R393.1
SIO_VCCP_SENSE: length 4.4
  TOP w0.102: R437.2 53.03,33.66 v1(52.84,33.85) 52.68,34 52.68,35.08 52.5,35.27 U11.51
SIO_YLW_LED: length 4.1
  TOP w0.102: U11.22 42.44,38.47 42.3,38.6 42.3,39.43 v1(42.06,39.68) 42.06,40.2 R454.2 R360.1
SLP_S3_N: length 626.1
  TOP w0.102: v2(25.73,158.31) 24.59,158.31 24.21,158.68 22.69,158.68 20.61,160.76 19.54,160.76 18.55,161.75 R136.1 ; v2(30.3,32.89) 30.55,32.64 32.9,32.64 33.33,32.21 R447.1 36.51,31.95 37.41,31.05 38.17,31.05 38.64,30.58 41.39,30.58 41.87,30.1 v2(42.68,30.1) 42.24,30.54 42.24,32.07 44.21,34.04 44.71,34.04 44.91,33.84 U11.34 ; v2(26.12,160.1) 26.25,160.22 27.31,160.22 34.22,167.14 34.22,176 41.04,182.82 v3(42.87,182.82) ; v3(108.91,27.69) 109.17,27.94 109.87,27.94 110.12,27.69 110.12,26.73 111.07,25.78 111.77,25.78 113.39,27.41 114.87,27.41 116.75,29.29 116.75,33.96 v2(118.02,35.23) ; v2(91.65,25.98) 91.65,27.03 90.69,27.99 90.69,28.32 87.36,31.65 87.36,37.44 R364.1 ; v2(24.65,95.25) 22.62,95.25 22.24,95.63 22.24,104.52 8.56,118.2 8.56,145.66 13.59,150.69 25.47,150.69 25.73,150.94 25.73,152.91 v2(25.47,153.16) ; v2(172.22,56.01) 170.83,56.01 170.57,56.26 154.72,56.26 153.57,55.11 153.57,53.92 151.65,52 151.65,46.61 v2(150.89,45.85) ; v2(73.54,233.68) 73.54,242.39 v2(74.33,243.18) ; v2(58.68,190.25) 59.95,188.98 65.8,188.98 66.56,188.21 66.56,187.32 67.5,186.39 R113.1 ; R736.1 81.85,204.01 81.54,203.71 v2(77.48,203.71) ; v2(143.14,243.08) 145.43,240.79 145.43,230.95 146.06,230.31 146.7,230.31 146.89,230.5 PR11.1
  BOTTOM w0.102: v2(25.47,153.16) 25.98,153.67 25.98,154.43 25.41,155 25.41,157.99 v2(25.73,158.31) 25.73,159.7 v2(26.12,160.1) ; v2(42.68,30.1) 42.68,28.57 44.71,26.54 48.78,26.54 49.16,26.16 50.56,26.16 51.06,25.65 54.16,25.65 56.26,23.56 56.82,23.56 57.19,23.19 62.06,23.19 62.81,22.44 89.93,22.44 91.22,23.73 91.22,25.55 v2(91.65,25.98) 92.21,26.54 97.85,26.54 99.32,28.02 108.58,28.02 v3(108.91,27.69) ; R705.1 189.62,43.94 188.48,45.09 188.48,46.61 185.68,49.4 182.13,49.4 181.37,50.16 181.37,52.58 180.35,53.59 179.84,53.59 178.83,54.61 176.41,54.61 175.02,56.01 v2(172.22,56.01) 172.6,55.63 U22.2 ; v2(73.54,233.68) 76.26,230.97 76.26,224.16 78.92,221.49 78.92,219.5 78.04,218.61 78.04,204.26 v2(77.48,203.71) 76.59,203.71 71.67,198.79 68.66,198.79 60.12,190.25 v2(58.68,190.25) 56.5,188.06 48.68,188.06 45.08,184.47 44.52,184.47 v3(42.87,182.82) ; v2(143.14,243.08) v1(142.2,244.02) 139.33,246.89 126.95,246.89 123.71,250.13 115.52,250.13 108.57,243.18 v2(74.33,243.18) ; v2(30.3,32.89) 31.2,33.79 31.2,42.55 33.44,44.78 33.44,48.67 32.73,49.38 32.73,53.45 30.24,55.94 29.79,55.94 29.27,56.46 28.36,56.46 24.42,60.4 20.92,60.4 20.31,61.01 20.31,62.78 21.85,64.33 21.85,68.3 22.36,68.81 22.36,79.81 24.22,81.66 25.79,81.66 26.81,82.68 26.81,83.95 24.39,86.36 24.39,95 v2(24.65,95.25) ; v2(118.02,35.23) 118.02,40.79 118.78,41.55 122.54,41.55 123.02,42.04 128.15,42.04 128.74,41.45 138.75,41.45 142.25,44.96 150,44.96 v2(150.89,45.85)
SLP_S5_N: length 601.3
  TOP w0.102: v2(146.59,229.36) PR14.1 ; v2(171.65,56.64) 171.53,56.52 154.6,56.52 153.31,55.23 153.31,54.17 151.39,52.25 151.39,47.24 v2(150.89,46.74) ; v2(24.65,96.01) 24.97,96.01 26.74,94.23 28.51,94.23 31.63,91.11 31.63,90.49 32.78,89.34 38.83,89.34 39.74,90.25 41.95,90.25 42.41,89.79 43.24,89.79 44.97,91.52 49.13,91.52 50.48,90.17 53.9,90.17 v2(53.92,90.2) ; v2(40.6,29.97) 38.95,29.97 38.11,30.81 37.35,30.81 36.66,31.5 31.71,31.5 31.51,31.7 v3(30.41,31.7) ; v2(92.72,27.3) 92.72,27.43 92.09,28.07 92.09,28.7 91.83,28.96 91.2,28.96 88.05,32.11 88.05,37.72 87.64,38.13 R366.1 ; v2(117.26,35.23) 115.78,33.76 115.78,28.68 114.74,27.63 113.22,27.63 111.89,26.3 v2(111.34,26.3) ; R498.1 75.58,26.41 75.96,26.04 80.72,26.04 83.6,23.15 v2(83.6,23.14)
  BOTTOM w0.102: U22.1 v2(171.65,56.64) 180.03,56.64 181.18,57.78 182.83,57.78 185.56,60.52 185.56,84.08 192.97,91.49 192.97,236.15 191.88,237.24 186.83,237.24 183.91,240.16 164.35,240.16 163.46,239.27 153.35,239.27 146.63,232.55 v1(146.63,230.63) 146.59,230.59 v2(146.59,229.36) ; v2(40.6,29.97) 40.9,30.28 40.9,31.37 42.05,32.51 46.87,32.51 47.13,32.77 47.83,32.77 47.95,32.64 R726.1 48.14,32.31 48.14,32.11 47.13,31.09 47.13,28.26 47.51,27.88 48.1,27.88 48.55,28.32 48.91,28.32 49.29,27.94 49.29,26.92 49.54,26.67 50.89,26.67 51.4,26.16 54.39,26.16 56.59,23.96 56.99,23.96 57.36,23.6 62.23,23.6 62.98,22.85 83.31,22.85 v2(83.6,23.14) 83.89,22.85 89.47,22.85 90.54,23.91 90.54,25.91 91.68,27.05 92.47,27.05 v2(92.72,27.3) 92.97,27.05 97.45,27.05 99.02,28.63 109.68,28.63 110.12,28.18 110.12,27.18 111,26.3 v2(111.34,26.3) ; v2(24.65,96.01) 24.17,95.53 24.17,81.92 22.13,79.88 22.13,68.88 21.65,68.4 21.65,64.57 20.1,63.02 20.1,60.87 20.84,60.13 24.28,60.13 28.15,56.26 29.09,56.26 29.67,55.69 30.11,55.69 32.52,53.28 32.52,49.28 33.21,48.59 33.21,44.86 31,42.65 31,34.29 29.07,32.36 29.07,31.39 29.35,31.11 30.34,31.11 30.41,31.19 v3(30.41,31.7) ; v2(53.92,90.2) 62.04,90.2 62.49,90.65 62.95,90.65 64.01,89.6 67.41,89.6 67.98,90.17 70.8,90.17 72.07,91.44 75.5,91.44 75.86,91.8 75.86,92.61 76.27,93.03 80.54,93.03 80.99,92.58 R602.1 ; v2(117.26,35.23) 117.79,35.76 117.79,40.94 118.71,41.86 122.44,41.86 122.87,42.29 128.28,42.29 128.87,41.71 138.62,41.71 142.12,45.21 149.11,45.21 150.63,46.74 v2(150.89,46.74)
SMB_CLK_MAIN: length 196.7
  TOP w0.102: v3(102.33,70.68) 101.94,71.06 U10.AD22 ; J1.118 170.08,91.27 170.08,91.27 ; 170.08,91.27 169.91,91.1 168.71,91.1 163.59,85.98 v2(157.62,85.98) ; 170.08,91.27 170.17,91.19 172.6,91.19 173.45,92.04 173.79,92.04 174.64,91.19 178.83,91.19 J2.118 ; v2(134.76,80.64) 136.03,80.64 136.54,81.15 v2(138.95,81.15) ; v3(70.01,92.58) 71.03,93.6 73.67,93.6 74.38,94.31 83.65,94.31 85.97,92 101.51,92 103.77,89.74 110.15,89.74 112.28,87.6 112.92,87.6 113.68,86.85 113.68,81.13 v3(113.42,80.87) 113.65,80.64 113.65,77.11 113.27,76.73 113.27,76.05 112.99,75.77 111.36,75.77 110.81,76.33 v2(110.37,76.33) ; v3(35.13,92.14) 35.32,91.95 36.78,91.95 37.16,91.57 40.78,91.57 41.6,90.74 v3(43.06,90.74) 43.5,90.74 44.73,91.97 49.35,91.97 50.73,90.59 52.56,90.59 53.8,91.82 54.37,91.82 54.81,91.38 54.81,90.77 v2(54.75,90.7)
  BOTTOM w0.102: v2(138.95,81.15) 138.44,81.66 138.44,82.55 140.28,84.39 154.38,84.39 155.97,85.98 v2(157.62,85.98) ; R646.1 v2(110.37,76.33) 110.25,76.2 110.25,75.87 109.75,75.37 107.83,75.37 107.33,74.87 107.33,73.47 106.56,72.71 105.58,72.71 103.25,70.38 102.54,70.38 102.33,70.6 v3(102.33,70.68) ; R641.2 41.04,87.46 41.04,88.29 40.98,88.35 40.98,89.67 42.05,90.74 v3(43.06,90.74) ; v2(54.75,90.7) 55.13,91.08 59.4,91.08 60.29,91.97 68.57,91.97 69.1,91.44 70.24,91.44 70.5,91.69 70.5,92.1 v3(70.01,92.58) ; v3(113.42,80.87) 113.7,81.15 114.44,81.15 116.47,83.19 131.71,83.19 134.25,80.64 v2(134.76,80.64) ; v3(35.13,92.14) 34.62,92.65 R607.1
SMB_CLK_MAIN_R: length 3.3
  BOTTOM w0.102: U20.13 33.59,96.09 v1(34.17,95.5) 34.62,95.06 R607.2
SMB_CLK_SUS: length 313.7
  TOP w0.102: v2(79.64,217.3) 79.89,217.3 80.15,217.04 80.15,216.53 80.4,216.28 81.42,216.28 81.75,215.95 CN1.34 ; v2(33.03,33.66) 33.41,34.04 35.13,34.04 36.08,34.99 36.08,37.08 36.46,37.47 38.49,37.47 38.87,37.85 38.87,38.1 39.13,38.35 R392.2
  BOTTOM w0.102: v2(79.64,217.3) 80.15,217.81 80.15,221.69 76.72,225.12 76.72,231.27 72.97,235.01 55.62,235.01 50.75,230.15 34,230.15 29.04,225.19 29.04,223.42 25.39,219.77 25.39,215.25 24.14,213.99 24.14,212.85 21.8,210.52 19.14,210.52 14.59,205.97 14.59,204.24 13.93,203.58 13.93,176.71 15.12,175.51 15.12,169.41 13.93,168.21 13.93,165.43 16.7,162.66 16.7,155.76 18.02,154.44 18.02,147.68 17.37,147.03 17.37,134.88 18.22,134.04 18.22,129.08 27.93,119.38 27.93,118.11 30.53,115.51 39.51,115.51 41.46,113.55 42.47,113.55 44.06,111.96 44.06,110.64 47.26,107.44 47.26,97.46 43.62,93.82 43.62,91.63 43.18,91.19 42.05,91.19 40.09,89.23 40.09,89.13 37.41,86.45 37.41,84.2 38.81,82.8 38.81,80.66 40.64,78.83 40.64,77.45 41.1,76.99 41.1,76.07 41.6,75.56 41.6,68.65 41.1,68.15 41.1,64.02 38.31,61.24 38.31,53.17 37.84,52.7 37.84,49.83 36.65,48.64 36.65,46.37 34.07,43.79 34.07,38.57 33.03,37.53 33.03,35.31 33.54,34.8 33.54,34.16 v2(33.03,33.66)
SMB_CLK_WLAN_R: length 4.2
  TOP w0.102: v3(40.46,88.9) 40.9,88.9 41.08,88.72 CN2.30
  BOTTOM w0.102: v3(40.46,88.9) 40.52,88.84 R641.1 39.75,87.81 v1(39.51,87.57)
SMB_DATA_MAIN: length 194.7
  TOP w0.102: J2.238 182.71,91.1 180.44,91.1 179.59,90.26 177.22,90.26 176.57,90.91 173.91,90.91 ; 173.91,90.91 173.91,90.91 173.71,91.1 173.5,90.89 171.25,90.89 170.71,90.35 168.59,90.35 163.46,85.22 v2(158.13,85.22) ; 173.91,90.91 J1.238 ; v2(138.95,81.98) 136.35,81.98 135.9,81.53 v2(134.76,81.53) ; U10.AE22 102.74,71.11 v3(103.05,70.79) ; v2(54.16,91.31) 53.67,91.31 52.74,90.39 50.62,90.39 49.26,91.74 44.83,91.74 43.38,90.3 v3(42.56,90.3) 42.37,90.49 41.48,90.49 40.65,91.31 37.03,91.31 36.65,91.69 34.75,91.69 v3(34.3,92.14) ; v3(69.99,91.88) 71.5,93.39 73.75,93.39 74.47,94.11 83.57,94.11 85.88,91.8 101.42,91.8 103.68,89.53 110.04,89.53 112.18,87.4 112.83,87.4 113.42,86.81 113.42,81.71 v3(113.23,81.52) 112.91,81.2 112.91,80.75 113.45,80.21 113.45,77.27 113.02,76.83 111.01,76.83 v2(110.37,77.47)
  BOTTOM w0.102: R642.1 v2(110.37,77.47) 109.8,76.9 109.8,75.82 109.61,75.63 107.71,75.63 107.07,74.99 107.07,73.6 106.44,72.96 105.54,72.96 103.37,70.79 v3(103.05,70.79) ; v2(54.16,91.31) 59.27,91.31 60.16,92.2 69.67,92.2 v3(69.99,91.88) ; v3(34.3,92.14) 34.3,92.46 33.6,93.15 R608.1 ; v3(42.56,90.3) 42.37,90.49 42.11,90.49 41.18,89.56 41.18,88.47 41.27,88.38 41.27,87.47 R640.2 ; v2(158.13,85.22) 157.37,85.22 155.59,85.22 154.51,84.14 140.54,84.14 138.95,82.55 v2(138.95,81.98) ; v2(134.76,81.53) 134.25,81.53 132.34,83.44 116.22,83.44 114.3,81.52 v3(113.23,81.52)
SMB_DATA_MAIN_R: length 3.1
  BOTTOM w0.102: R608.2 33.6,94.36 v1(33.03,94.93) 33.09,94.99 U20.14
SMB_DATA_SUS: length 314.1
  TOP w0.102: v2(80.91,217.3) 80.53,217.3 80.4,217.17 80.4,216.66 80.53,216.53 81.54,216.53 82.25,215.83 CN1.32 ; v2(32.78,34.54) 33.03,34.29 35,34.29 35.82,35.12 35.82,37.21 36.33,37.72 38.36,37.72 38.62,37.97 38.62,38.61 39.38,39.37 R388.2
  BOTTOM w0.102: v2(80.91,217.3) 80.39,217.81 80.39,221.73 76.97,225.15 76.97,231.39 73.15,235.22 55.4,235.22 50.54,230.35 33.91,230.35 28.84,225.28 28.84,223.5 25.14,219.81 25.14,215.38 23.93,214.17 23.93,213.15 21.5,210.72 18.98,210.72 14.39,206.12 14.39,204.37 13.7,203.68 13.7,176.56 14.87,175.39 14.87,169.51 13.7,168.34 13.7,165.35 16.5,162.56 16.5,155.67 17.82,154.35 17.82,147.78 17.17,147.13 17.17,134.78 18.02,133.93 18.02,128.98 27.72,119.28 27.72,118.01 30.48,115.25 39.44,115.25 41.35,113.35 42.38,113.35 43.85,111.88 43.85,110.46 47.05,107.26 47.05,97.54 43.42,93.91 43.42,91.74 43.12,91.44 42,91.44 39.89,89.33 39.89,89.23 37.16,86.5 37.16,84.07 38.61,82.63 38.61,80.56 40.44,78.72 40.44,77.36 40.89,76.91 40.89,75.96 41.39,75.46 41.39,68.75 40.89,68.25 40.89,64.11 38.11,61.32 38.11,53.26 37.64,52.78 37.64,49.95 36.4,48.7 36.4,46.47 33.79,43.86 33.79,38.67 32.78,37.66 v2(32.78,34.54)
SMB_DATA_WLAN_R: length 3.4
  TOP w0.102: v3(41.67,88.9) 41.88,88.69 CN2.32
  BOTTOM w0.102: v1(41.98,89.53) 41.98,89.22 v3(41.67,88.9) 41.79,88.77 R640.1
SP_DDR3_RST_N: length 10.5
  TOP w0.102: U10.H4 90.04,57.47 90.51,57 90.51,56.52 90.59,56.32 90.59,55.9 90.51,55.83 90.51,55.56 90.55,55.53 90.55,55.11 90.49,55.04 90.49,54.41 87.16,51.08 87.16,49.43 TP100.1
SPDIF-OUT: length 200.9
  TOP w0.254: v2(12.63,151.94) 24.5,151.94 v2(24.62,152.07) ; v3(42.87,183.64) 41.04,183.64 33.79,176.39 33.79,167.32 27.13,160.66 24.93,160.66 v2(24.39,160.12) ; R83.2 v2(64.65,196.72)
  BOTTOM w0.254: v2(24.62,152.07) 24.39,152.3 v2(24.39,160.12) 24.39,161.16 23.66,161.9 23.66,163.98 24.19,164.52 24.95,164.52 25.46,165.02 R564.2 ; v2(12.63,151.94) 12.63,150.42 9.41,147.19 9.41,116.59 23.51,102.49 23.51,82.82 21.35,80.67 21.35,69.15 18.93,66.74 18.93,61.28 20.71,59.5 v1(21.22,59.5) 24.28,59.5 27.93,55.85 28.31,55.85 28.54,55.62 U23.48 ; v2(64.65,196.72) 64.15,196.72 55.97,188.54 48.54,188.54 44.91,184.91 44.33,184.91 43.06,183.64 v3(42.87,183.64)
SPDIF-OUT_MXM_R: length 3.8
  TOP w0.254: CN9.21 24.65,163.73 v2(24.5,163.88)
  BOTTOM w0.254: v2(24.5,163.88) 24.54,163.83 25.21,163.83 R564.1 v1(25.54,163.19)
SPDIF-OUT_NB_R: length 6.6
  TOP w0.102: CN7.21 63.99,194.24 R83.1 65.09,194.9 65.26,195.07 65.26,196.96 64.98,197.24 64.16,197.24 v1(63.86,196.94)
SPEK_SUMOUT_L: length 26.5
  TOP w0.254: v2(24.95,41.12) 26.55,42.72 26.55,45.09 25.86,45.78 25.86,48.58 22.63,51.81 R346.2
  BOTTOM w0.254: v2(24.95,41.12) 24.7,41.12 24.08,40.5 v1(24.08,39.05) 24.27,38.86 24.27,36.74 23.76,36.22 23.76,28.5 C534.1
SPEK_SUMOUT_R: length 20.1
  TOP w0.254: R331.2 18.35,53.67 20.89,51.13 22.54,51.13 25.32,48.36 25.32,45.37 25.92,44.77 25.92,43.23 v2(24.67,41.99)
  BOTTOM w0.254: v2(24.67,41.99) v1(24.04,41.36) 23.12,40.44 C518.1
SPI_CLK: length 37.5
  TOP w0.102: U10.K4 91.64,58.22 v3(91.74,58.32) ; U15.6 98.82,33.02 94.24,37.59 90.69,37.59 88.78,39.5 88.78,40.89 87.39,42.29 87.39,43.62 86.86,44.15 86.86,45.7 86.25,46.31 86.25,46.56 v2(86.26,46.58)
  BOTTOM w0.102: v2(86.26,46.58) 86.37,46.69 86.37,49.41 87.87,50.91 87.87,51.84 v1(88.53,52.5) 91.5,55.47 91.5,57.73 91.74,57.97 v3(91.74,58.32)
SPI_CS_N: length 35.1
  TOP w0.102: v2(86.23,44.83) 86.23,44.4 87.13,43.5 87.13,42.23 88.53,40.83 88.53,38.86 90.76,36.63 90.76,35.96 90.36,35.56 ; U10.K9 v3(91.74,60.5) ; 90.36,35.56 U12.1 U15.1 ; 90.36,35.56 R420.2
  BOTTOM w0.102: v3(91.74,60.5) 91.74,59.62 91.09,58.97 91.09,58.06 90.37,57.34 90.37,56.58 90.64,56.31 90.64,55.91 87.36,52.63 87.36,50.98 85.86,49.48 85.86,48.18 85.25,47.57 85.25,47.1 85.49,46.86 85.49,45.65 v1(85.28,45.44) 85.89,44.83 v2(86.23,44.83)
SPI_DATAIN: length 32.4
  TOP w0.102: v3(91.71,58.97) 91.36,58.62 U10.J5 ; v2(86.26,45.6) 85.74,45.07 85.74,44.58 86.88,43.43 86.88,42.16 88.28,40.77 88.28,38.23 89.19,37.31 89.19,36.65 88.78,36.25 88.78,32.84 R440.1
  BOTTOM w0.102: v2(86.26,45.6) 85.69,46.17 85.69,47.2 v1(85.81,47.32) 86.12,47.62 86.12,49.44 87.64,50.96 87.64,52.47 90.94,55.77 90.94,56.52 90.65,56.81 90.65,57.29 91.32,57.96 91.32,58.57 v3(91.71,58.97)
SPI_DATAOUT: length 44.5
  TOP w0.102: U15.5 96.2,31.75 94.3,29.84 90.69,29.84 88.28,32.26 88.28,36.47 v3(88.48,36.68) ; U10.E2 87.64,56.49 88.16,55.96 88.16,55.5 88.05,55.39 88.05,54.87 83.65,50.47 83.65,46.24 82.88,45.47 82.88,44.4 83.65,43.62 83.65,42.09 84.67,41.07 84.67,38.73 v2(86.8,36.6)
  BOTTOM w0.102: v3(88.48,36.68) 86.88,36.68 v2(86.8,36.6)
SPI_DI_R: length 11.5
  TOP w0.102: U15.2 94.75,34.29 95.26,33.78 95.26,31.37 94.24,30.35 91.07,30.35 v2(90.43,30.99) 90.23,31.19 R440.2
SPI_HOLD_N: length 6.3
  TOP w0.102: v2(102.07,39.12) R390.2 102.4,38.05 102.4,34.63 102.06,34.29 U12.7 U15.7
SPI_WP_N: length 5.5
  TOP w0.102: 91.83,33.02 91.83,31.56 v2(92.4,30.99) ; 91.83,33.02 U12.3 U15.3 ; 91.83,33.02 91.32,33.53 R433.2
SPK_L-N: length 3.9
  TOP w0.508: CN10.1 32.75,10.82 v2(32.75,9.86)
  BOTTOM w0.254: v1(32.85,11.81) 32.77,11.72 R756.1
  BOTTOM w0.508: R756.1 32.77,9.87 v2(32.75,9.86)
SPK_L-P: length 10.7
  TOP w0.508: CN10.2 31.75,10
  TOP w0.762: 31.75,10 31.02,9.27 v2(30.11,9.27)
  BOTTOM w0.762: C319.2 25.05,8.4 25.92,9.27 v1(27.32,9.27) v2(30.11,9.27)
SPK_R-N: length 15
  TOP w0.508: 27.27,11.8 v1(27.25,11.81) ; CN10.4 29.34,11.8
  TOP w0.762: v1(27.25,11.81) 27.24,11.8 26.41,11.8 25.66,11.05 25.66,7.46 C326.2 ; 29.34,11.8 27.27,11.8
SPK_R-P: length 4.3
  TOP w0.508: CN10.3 30.75,10.6 v2(30.57,10.41)
  BOTTOM w0.508: R773.1 32.09,8.89 v2(30.57,10.41)
SPM_CLKN: length 8.8
  TOP w0.101: 63.19,143.66 63.34,143.66 v3(63.74,144.06)
  TOP w0.127: 63.19,143.66 U3.W14
  BOTTOM w0.101: v3(63.74,144.06) 63.74,143.76 63.74,143.76
  BOTTOM w0.102: 63.74,143.76 63.74,140.36 64.32,139.78 64.32,138.66 R571.2 64.1,138.05 63.08,137.03 TP189.1
SPM_CLKP: length 8.7
  TOP w0.102: U3.V15 64.54,144.11 v3(64.69,144.11)
  BOTTOM w0.102: v3(64.69,144.11) 64.52,144.11 63.96,143.55 63.96,140.49 64.63,139.83 64.63,138.76 R571.1 64.96,137.92 64.69,137.66 TP190.1
SPM_COMPN: length 7.1
  TOP w0.102: R178.2 62.62,134.12 v1(62.62,134.29) 61.76,135.15 61.76,138.5 61.76,138.5 61.98,138.72 61.98,139.07 61.64,139.41 U3.AD12
SPM_COMPP: length 6.2
  TOP w0.102: R162.2 60.46,134.05 v1(60.65,134.24) 61.46,135.05 61.46,138.68 61.64,138.86 U3.AE12
STRP_DAT: length 7.4
  TOP w0.102: TP39.1 56.81,163.32 59.65,160.48 59.65,159.17 59.7,159.13 59.7,158.01 60.04,157.31 U3.B10
SUMOUT_L: length 2.7
  TOP w0.254: R346.1 20.42,52.73 v5(20.23,52.73)
  BOTTOM w0.254: v5(20.23,52.73) 20.29,52.67 U23.35
SUMOUT_R: length 2.5
  TOP w0.254: R331.1 20.81,53.85 v2(20.89,53.92)
  BOTTOM w0.254: v2(20.89,53.92) 20.89,53.34 21.06,53.17 U23.36
SUS_STAT_N: length 221.8
  TOP w0.102: v2(74.56,47.24) 74.81,47.5 74.81,47.88 74.6,48.09 74.6,49.63 74.25,49.99 72.48,49.99 71.75,49.26 68.98,49.26 67.77,50.48 65.86,50.48 62.24,54.1 62.24,59.23 60.59,60.88 60.59,68.73 60.23,69.09 60.23,70.89 60.82,71.48 60.82,73.04 62.01,74.23 62.01,87.02 60.38,88.65 60.38,92.1 60.67,92.38 60.67,95.25 60.13,95.78 60.13,99.25 55.54,103.85 55.54,113.27 48.64,120.17 41.67,120.17 40.85,120.98 40.85,136.92 38.85,138.93 38.85,141.82 36.67,143.99 35.71,143.99 34.13,145.57 33.37,145.57 29.81,149.13 29.81,160.99 35.93,167.12 35.93,175.81 40.01,179.9 49.6,179.9 50.5,180.79 54.98,180.79 60.02,175.76 60.02,174.43 59.83,174.24 59.19,174.24 59.07,174.37 58.75,174.37 58.3,173.93 58.3,173.1 58.63,172.77 58.63,171.56 59.07,171.13 R131.2 ; U10.G6 89.32,59.42 v3(88.94,59.03)
  BOTTOM w0.102: v3(88.94,59.03) 89.06,58.9 89.06,58.65 89.2,58.51 89.2,57.92 88.38,57.1 88.38,55.85 v1(86.42,53.89) 84.31,51.79 84.31,48.23 82.5,46.42 79.64,46.42 79.2,45.97 77.35,45.97 76.91,46.42 75.39,46.42 v2(74.56,47.24)
SUS_STAT_R_N: length 20.7
  TOP w0.102: R125.1 59.64,172.04 59.76,172.16 R116.1 60.65,171.85 60.65,170.75 v1(60.21,170.31) 59.65,169.75 R131.1 59.88,168.94 59.88,166.7 60.08,166.5 60.08,165.67 61.81,163.94 61.81,162.48 62.55,161.74 62.55,158.37 62.55,158.37 62.55,158.26 62.28,158 62.11,157.77 62.09,157.6 62.17,157.36 62.17,157.09 62.07,156.8 61.96,156.37 61.95,156.34 U3.D12
SYS_FAN1_PWM: length 307.8
  TOP w0.102: v3(191.91,235.46) 191.97,235.52 192.94,235.52 193.3,235.89 193.3,244.4 R9.1 R2.2 ; U10.W5 98.51,58.22 v3(98.58,58.22) ; v2(117.97,56.01) 118.78,56.82 126.07,56.82 128.41,54.48 130.77,54.48 132.93,56.64 143.56,56.64 144.66,57.75 144.66,63.25 145.04,63.63 157.11,63.63 157.36,63.88 158.2,63.88 159.04,63.04 160.46,63.04 v2(161.05,63.63)
  BOTTOM w0.102: v2(161.05,63.63) 161.5,63.17 161.5,58.67 163.03,57.15 170.7,57.15 171.59,58.04 172.79,58.04 173.18,57.66 179.91,57.66 180.95,58.71 182.54,58.71 184.8,60.96 184.8,86.59 189.01,90.81 192.36,94.16 192.56,94.36 192.56,234.36 191.91,235.01 v3(191.91,235.46) ; v2(117.97,56.01) 117.31,55.35 117.31,54.56 116.62,53.87 v1(115.53,53.87) 114.87,53.21 114.87,52.03 114.28,51.44 109.23,51.44 108.62,50.83 100.06,50.83 98.94,51.94 98.94,56.54 98.58,56.91 v3(98.58,58.22)
SYS_FAN1_TACH: length 312.7
  TOP w0.102: v3(98.74,60.8) 98.7,60.8 U10.W7 ; v3(192.48,235.08) 192.86,235.08 193.53,235.75 193.53,244.5 189.85,248.18 189.85,250.14 R7.1 189.29,251.85 D2.A ; v2(117.89,55.07) 118.13,55.07 119.66,56.59 125.99,56.59 128.36,54.23 130.85,54.23 133.01,56.39 143.66,56.39 144.92,57.65 144.92,63.12 145.17,63.37 157.24,63.37 157.49,63.63 158.08,63.63 158.91,62.79 160.95,62.79 v2(161.02,62.87)
  BOTTOM w0.102: v2(117.89,55.07) 117.89,54.76 114.31,51.18 109.36,51.18 108.8,50.62 99.38,50.62 v1(99.05,50.95) 98.74,51.26 98.74,56.39 98.13,57 98.13,60.2 98.74,60.8 v3(98.74,60.8) ; v3(192.48,235.08) 192.76,234.79 192.76,94.2 185.05,86.49 185.05,60.83 182.61,58.39 181.02,58.39 180.03,57.4 173.05,57.4 172.67,57.78 171.84,57.78 170.95,56.9 162.85,56.9 161.02,58.72 v2(161.02,62.87)
SYS_FAN_PWM: length 414.5
  TOP w0.102: R13.1 R4.2 169.05,247.46 169.43,247.84 169.43,249.29 169.16,249.56 168.03,249.56 165.43,252.16 109.8,252.16 108.57,253.39 102.83,253.39 97.6,248.16 74.82,248.16 61.04,234.38 17.28,234.38 2.64,219.74 2.64,182.34 3.23,181.76 3.23,178.69 6.4,175.51 6.4,170.58 6.59,170.39 6.59,165.01 6.52,164.93 6.52,163.45 6.85,163.12 6.85,158.17 6.55,157.87 6.55,156.4 6.98,155.97 6.98,151.26 5.71,149.99 5.71,117.06 19.38,103.39 19.38,90.68 19.06,90.36 19.06,83.12 21.09,81.09 21.09,78.49 22.88,76.7 33.77,76.7 36.3,74.17 37.57,74.17 39.83,71.91 50.58,71.91 51.06,72.39 v2(51.06,73.76) ; U11.63 52.47,40.07 52.58,40.17 52.58,41.52 53.48,42.42 53.48,42.74 55.26,44.51 55.26,49.07 57.69,51.51 57.69,58.75 v3(57.91,58.96)
  BOTTOM w0.102: v3(57.91,58.96) 57.81,58.86 v1(57.03,58.86) 56.21,58.86 56.07,59 52.2,59 51.62,59.58 51.62,62.82 52.23,63.43 52.23,71.03 51.95,71.31 51.95,72.87 v2(51.06,73.76)
SYS_FAN_TACH: length 411.8
  TOP w0.102: U11.62 52.47,39.66 52.8,39.99 52.8,41.46 53.69,42.35 53.69,42.63 55.46,44.4 55.46,48.95 57.9,51.38 57.9,57.96 v3(58.28,58.34) ; v2(50.35,73.58) 49.16,72.39 39.92,72.39 37.63,74.68 36.5,74.68 34.07,77.1 23.11,77.1 21.6,78.61 21.6,81.22 19.57,83.25 19.57,90.11 19.89,90.42 19.89,103.52 6.16,117.24 6.16,149.78 7.44,151.06 7.44,156.14 7.01,156.57 7.01,157.6 8.11,158.71 8.11,162.53 6.98,163.66 6.98,164.59 7.09,164.69 7.09,170.59 6.93,170.74 6.93,175.66 3.72,178.87 3.72,182.03 3.05,182.7 3.05,219.38 17.54,233.87 62.7,233.87 76.22,247.4 99.26,247.4 102.37,244.28 108.91,244.28 111.2,246.57 111.2,248.3 113.69,250.79 159.9,250.79 161.16,249.53 167.42,249.53 168.16,248.79 D3.A 168.32,248.07 167.78,247.52 R12.1
  BOTTOM w0.102: v3(58.28,58.34) 58.23,58.29 56.48,58.29 55.97,58.8 52.02,58.8 51.4,59.42 51.4,62.94 52.03,63.58 52.03,70.94 51.75,71.22 51.75,72.24 51.01,72.97 v1(50.94,72.97) 50.35,73.56 v2(50.35,73.58)
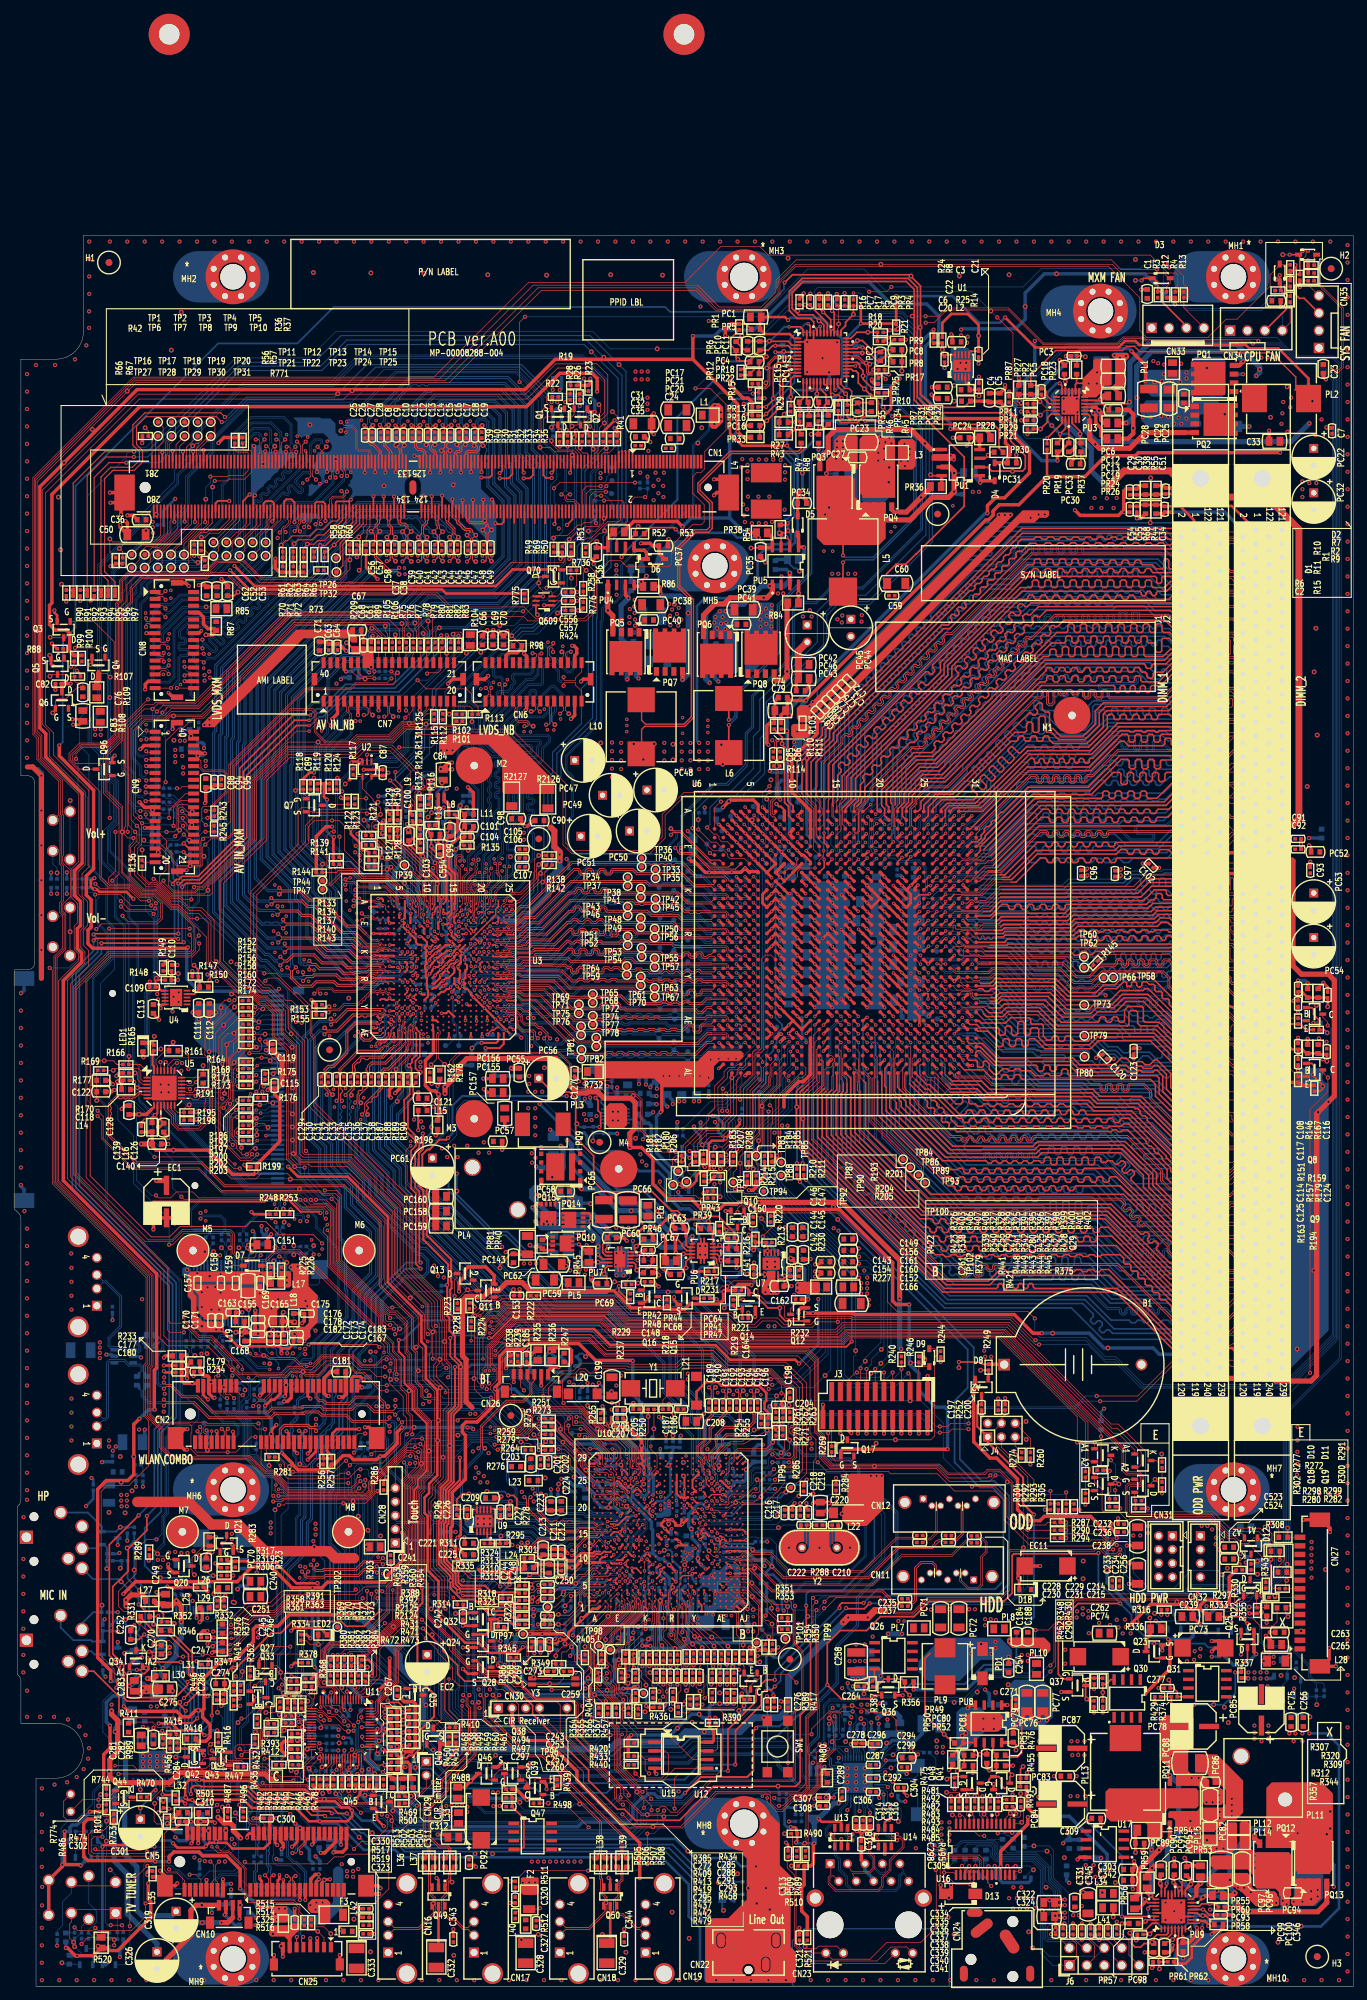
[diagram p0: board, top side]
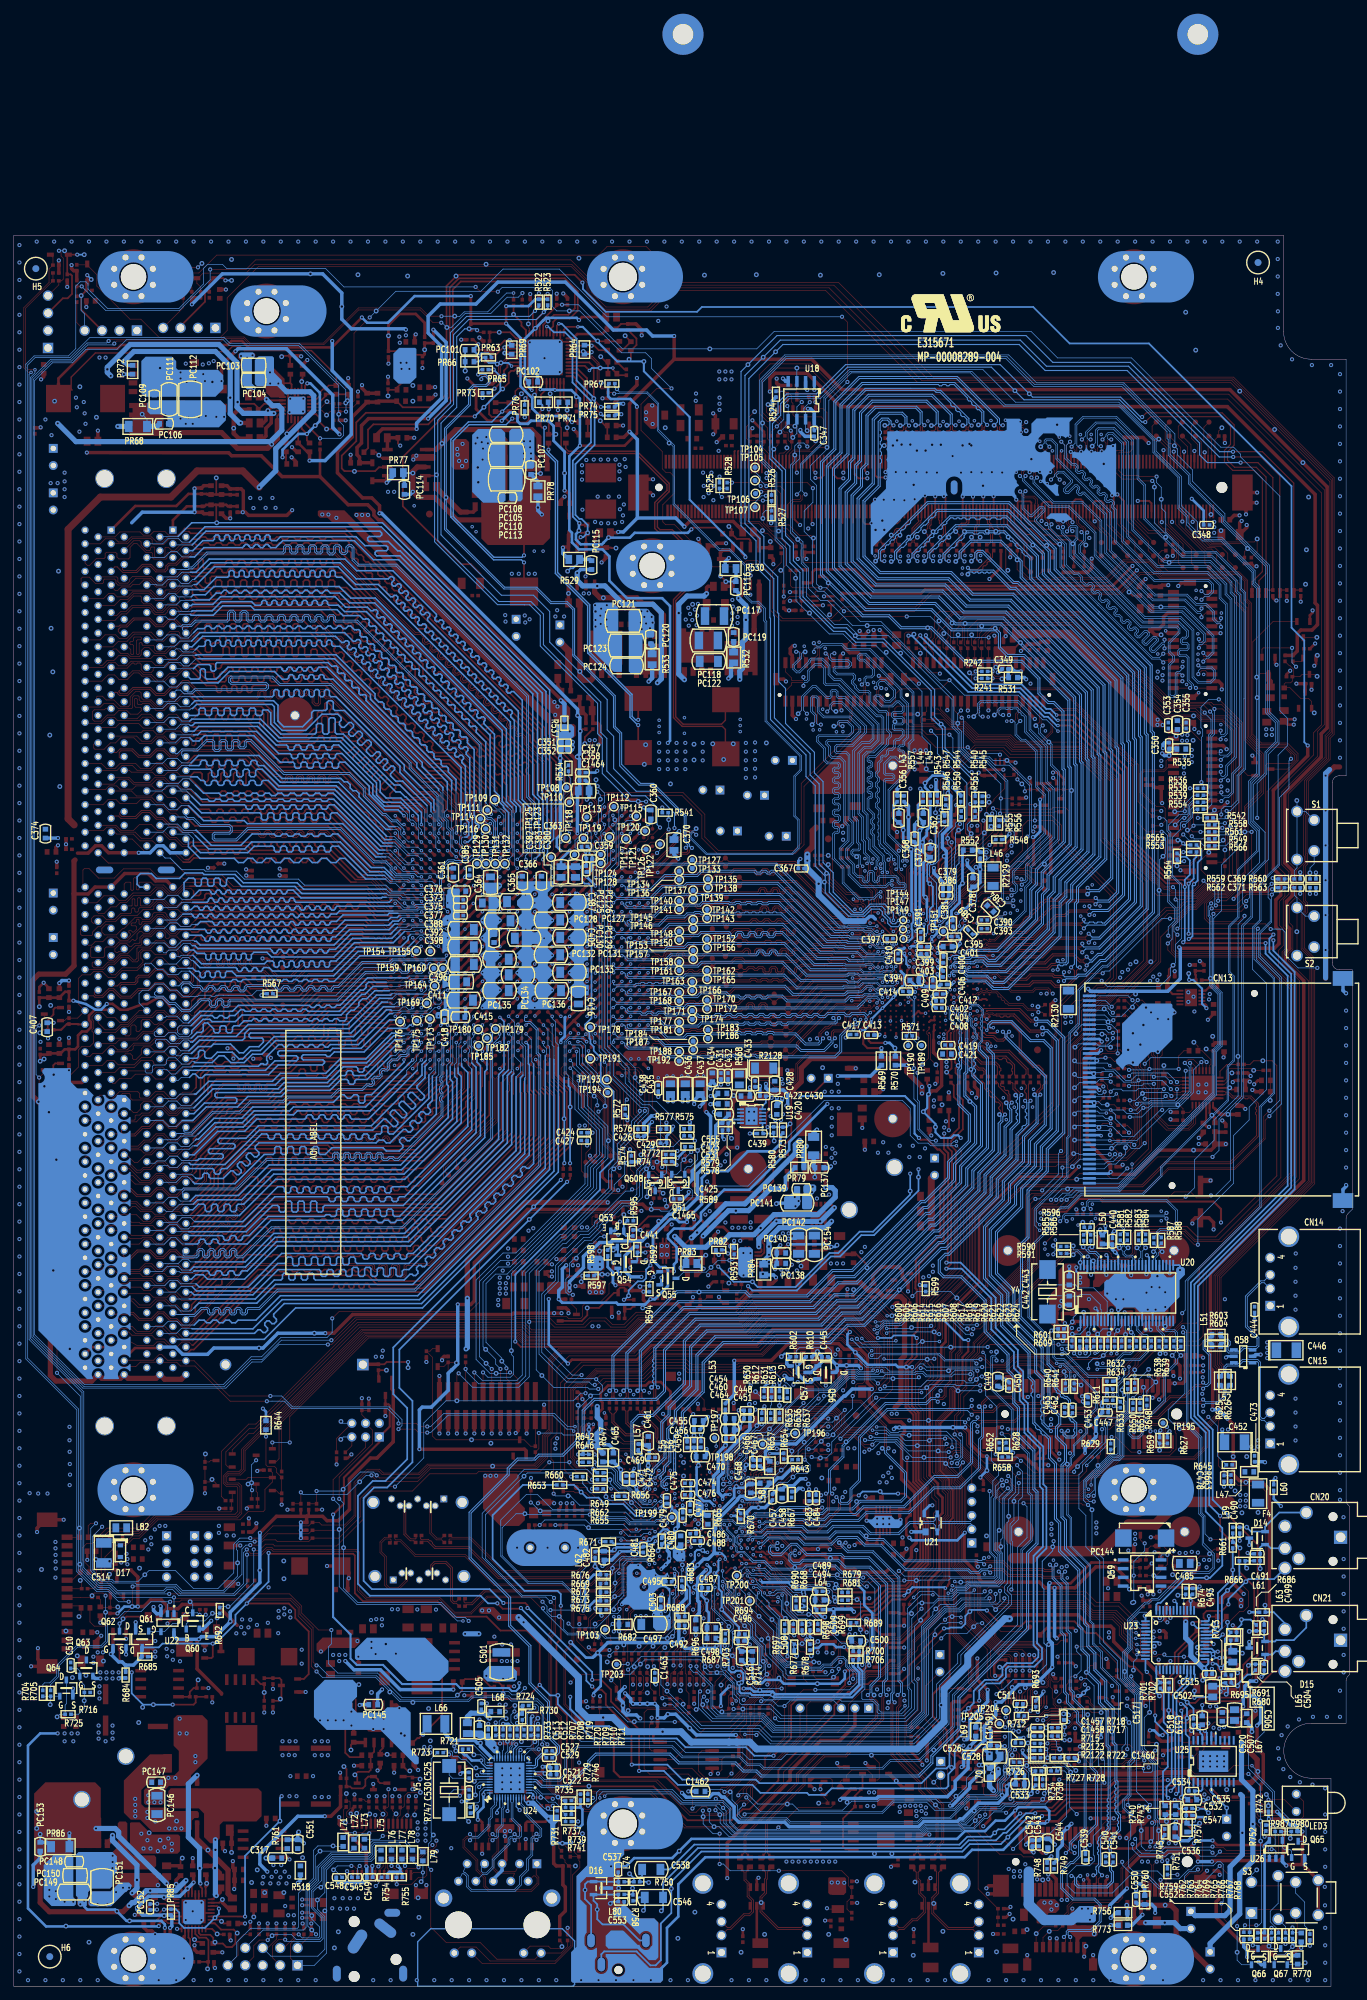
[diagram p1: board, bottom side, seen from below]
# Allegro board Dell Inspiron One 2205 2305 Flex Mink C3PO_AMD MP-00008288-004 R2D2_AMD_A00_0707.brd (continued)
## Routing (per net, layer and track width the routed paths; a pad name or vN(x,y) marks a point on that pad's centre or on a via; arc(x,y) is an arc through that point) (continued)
SYS_PWROK: length 344.2
  TOP w0.102: R222.2 76.03,100.56 87.48,100.56 89.86,98.17 104.33,98.17 106.09,96.42 107.8,96.42 108.72,97.35 111.14,97.35 112.06,96.42 115.99,96.42 116.85,97.28 121.8,97.28 121.98,97.1 145.04,97.1 148.68,93.47 v2(149.24,93.47) ; v2(181.18,239.65) 180.97,239.85 164.83,239.85 164.45,240.23 161.45,240.23 160.56,239.34 149.9,239.34 144.78,244.46 135.71,244.46 134.5,243.26 v2(132.69,243.26) ; PR4.1 v3(122.18,246.63)
  BOTTOM w0.102: v2(149.24,93.47) 156.35,93.47 158.89,90.93 160.28,90.93 164.09,87.12 184.92,87.12 192.36,94.56 192.36,234.25 189.62,236.98 186.7,236.98 184.32,239.36 181.46,239.36 v2(181.18,239.65) ; v2(132.69,243.26) 130.77,243.26 v1(130.76,243.27) 130.69,243.21 130.06,243.21 129.37,243.89 125.94,243.89 123.2,246.63 v3(122.18,246.63)
TDMS_HPD: length 15.2
  TOP w0.102: v2(52.84,166.24) 52.97,166.24 56.53,162.69 57.03,162.69 59.4,160.32 59.4,158.9 59.47,158.83 59.47,157.99 59.61,157.69 59.61,156.75 59.14,156.28 59.14,155.76 U3.D9
  BOTTOM w0.102: R548.1 52.06,167.03 v2(52.84,166.24)
TEMPIN: length 9.1
  TOP w0.102: U10.B5 U10.A5 ; U10.A5 84.84,58.92 U10.A6 U10.B6 ; U10.A5 83.45,58.52 81.79,56.85 v2(81.04,56.85) 81.04,56.29 v1(80.17,55.42)
  BOTTOM w0.102: R690.1 v2(81.04,56.85)
TEST_EN: length 13.9
  TOP w0.102: R135.1 64.83,166.17 v1(64.27,165.61) 63.63,164.96 63.63,163.03 64.5,162.15 64.5,156.8 64.04,156.34 64.04,156.16 63.69,155.8 63.69,155.58 63.4,155.3 63.05,155.3 62.69,155.66 U3.D13
TH_PWM_MXM: length 5.8
  TOP w0.102: v2(85.42,217.11) 84.85,217.11 84.25,216.51 CN1.24
  BOTTOM w0.102: v2(85.42,217.11) 86.05,217.11 87.01,216.15 TP107.1
THERMALERT_VGA_N: length 9.7
  TOP w0.102: R49.2 v1(78.5,210.95) 78.88,211.33 80.53,211.33 82.05,212.85 82.56,212.85 82.94,213.23 83.98,213.23 84.34,213.59 84.57,213.59 84.75,213.77 CN1.22
THERMTRIP_VGA_N: length 285.5
  TOP w0.102: v2(14.21,161.04) 15.19,162.01 15.19,171.51 12.92,173.78 12.92,179.47 15.31,181.86 15.31,200.78 16.33,201.8 16.33,204.15 17.63,205.45 27.76,205.45 29.67,207.37 32.8,207.37 35.7,204.47 69.35,204.47 72.27,207.39 79.89,207.39 80.15,207.65 80.15,208.15 80.4,208.41 80.4,209.17 79.85,209.73 R69.2 79.77,209.74 v1(80.78,210.76) 82.33,212.3 82.81,212.3 83.13,212.62 84.95,212.62 85.25,212.92 CN1.20 ; v3(45.45,112.65) 45.45,112.93 45,113.38 42.01,113.38 40.17,115.22 36.5,115.22 36.11,114.84 26.79,114.84 25.93,115.7 23.56,115.7 22.7,114.84 20.94,114.84 v2(20.58,115.19) ; v2(96.3,121.51) 94.27,121.51 91.13,124.65 91.13,129.03 90.05,130.11 86.18,130.11 85.47,130.82 83.28,130.82 83.13,130.67 82.12,130.67 80.84,131.96 80.84,134.25 79.26,135.83 64.91,135.83 63.86,134.78 v2(63.86,133.73)
  INT1 w0.089: v3(57.67,123.06) 47.7,113.09 45.89,113.09 v3(45.45,112.65)
  BOTTOM w0.102: v2(14.21,161.04) 14.55,160.7 14.55,155.7 15.89,154.37 15.89,129.41 17.73,127.57 17.73,117.41 19.95,115.19 v2(20.58,115.19) ; v2(63.86,133.73) 63.86,129.25 63.28,128.68 63.28,124.81 61.17,122.69 58.4,122.69 58.03,123.06 v3(57.67,123.06) ; C1465.1 98.87,116.57 99.13,116.84 Q51.S 98.4,118.28 97.8,118.87 97.8,119.95 v1(97.36,120.4) 97.36,120.46 v2(96.3,121.51)
TOUCH_PANEL_DETECT: length 39.9
  TOP w0.102: v3(69.29,81.47) 71.19,81.47 71.26,81.41 73.16,81.41 73.92,82.17 v2(73.92,83.95) ; v2(57.63,77.24) 56.93,77.24 55.43,75.74 CN28.5 55.15,72.28 R286.1
  BOTTOM w0.102: v3(69.29,81.47) 68.02,81.47 67.19,80.64 66.17,80.64 65.97,80.84 59.13,80.84 57.72,79.43 57.72,77.81 57.63,77.72 v2(57.63,77.24) ; R643.2 80.73,78.03 76.59,82.17 75.73,82.17 v1(75.14,82.75) 73.95,83.95 v2(73.92,83.95)
TP_DP_A_AUX: length 3.8
  TOP w0.102: TP6.1 20.5,225.25 CN1.279
TP_DP_A_AUX_N: length 6.3
  TOP w0.102: TP1.1 21.62,227.09 21.62,224.92 21,224.3 CN1.277
TP_DP_A_L0: length 4.8
  TOP w0.102: CN1.255 26.5,223.22 26.5,223.22 26.5,224.03 28.27,225.81 TP10.1
TP_DP_A_L0_N: length 7.4
  TOP w0.102: CN1.253 27,224.03 28.12,225.15 28.88,225.15 29.16,225.43 29.16,227.23 TP5.1
TP_DP_A_L1: length 4.4
  TOP w0.102: TP9.1 25,224.16 25,223.27 25,223.27 CN1.261
TP_DP_A_L1_N: length 7
  TOP w0.102: CN1.259 25.5,223.87 26.36,224.73 26.74,224.73 27.25,225.23 27.25,227.23 TP4.1
TP_DP_A_L2: length 4.3
  TOP w0.102: CN1.267 23.5,223.19 23.5,223.19 23.5,224.56 TP8.1
TP_DP_A_L2_N: length 6.6
  TOP w0.102: CN1.265 24,224.25 25.35,225.6 25.35,227.23 TP3.1
TP_DP_A_L3: length 4.1
  TOP w0.102: CN1.273 22,223.14 22,223.14 22,224.96 22.84,225.8 TP7.1
TP_DP_A_L3_N: length 6.4
  TOP w0.102: TP2.1 23.42,227.25 23.42,225.48 22.5,224.55 CN1.271
TP_DP_B_AUX: length 9.7
  TOP w0.102: CN1.272 22.25,211.58 20.63,209.96 18.45,209.96 TP16.1
TP_DP_B_AUX_N: length 11.5
  TOP w0.102: TP27.1 18.14,207.74 18.14,208.74 19.15,209.75 20.76,209.75 22.75,211.75 CN1.270
TP_DP_B_L0: length 8.1
  TOP w0.102: TP20.1 24.65,210.07 26.85,212.27 27.46,212.27 28.25,213.06 CN1.248
TP_DP_B_L0_N: length 10.2
  TOP w0.102: CN1.246 28.75,213.15 27.59,211.99 26.98,211.99 25.35,210.36 25.35,207.33 TP31.1
TP_DP_B_L1: length 7.9
  TOP w0.102: CN1.254 26.75,213.01 22.74,209 TP19.1
TP_DP_B_L1_N: length 10.1
  TOP w0.102: CN1.252 27.25,213.13 23.4,209.27 23.4,207.28 TP30.1
TP_DP_B_L2: length 8.1
  TOP w0.102: TP18.1 20.86,208.53 25.25,212.93 CN1.260
TP_DP_B_L2_N: length 10.2
  TOP w0.102: CN1.258 25.75,213 21.47,208.72 21.47,207.26 TP29.1
TP_DP_B_L3: length 8.9
  TOP w0.102: TP17.1 18.99,208.53 20.01,209.55 21.03,209.55 23.75,212.27 CN1.266
TP_DP_B_L3_N: length 10.8
  TOP w0.102: TP28.1 19.74,207.43 19.74,208.58 20.5,209.35 21.26,209.35 24.25,212.33 CN1.264
TP_DP_D_AUX: length 5.9
  TOP w0.102: CN1.232 32.25,213.63 TP11.1
TP_DP_D_AUX_N: length 8.1
  TOP w0.102: CN1.230 32.75,213.49 29.72,210.46 29.72,209.13 TP21.1
TP_DP_D_L0: length 5.2
  TOP w0.102: CN1.208 38.25,213.41 36.55,211.71 TP15.1
TP_DP_D_L0_N: length 7.4
  TOP w0.102: CN1.206 38.75,213.6 37.49,212.34 37.49,209.28 TP25.1
TP_DP_D_L1: length 5.4
  TOP w0.102: CN1.214 36.75,212.8 34.65,210.69 TP14.1
TP_DP_D_L1_N: length 7.6
  TOP w0.102: TP24.1 35.65,209.34 35.65,211.19 37.04,212.57 37.04,213.61 37.25,213.82 CN1.212
TP_DP_D_L2: length 5.5
  TOP w0.102: TP13.1 32.74,210.39 35.25,212.89 CN1.220
TP_DP_D_L2_N: length 7.7
  TOP w0.102: TP23.1 33.53,209.13 33.53,210.69 35.75,212.91 CN1.218
TP_DP_D_L3: length 5.8
  TOP w0.102: TP12.1 32.34,211.81 32.54,211.81 33.75,213.02 CN1.226
TP_DP_D_L3_N: length 7.9
  TOP w0.102: TP22.1 31.66,209.17 31.66,210.48 34.25,213.06 CN1.224
TP_GPIO61: length 8.9
  TOP w0.102: TP98.1 85.1,50.34 89.5,54.74 89.5,55.48 89.57,55.56 89.57,55.96 89.24,56.29 U10.G2
TP_SIO_PECI_REQ_N: length 2.3
  TOP w0.102: U11.57 50.61,37.67 v2(50.56,37.72)
  BOTTOM w0.102: v2(50.56,37.72) 50.89,37.72 TP205.1
TSI: length 2.9
  TOP w0.102: v2(50.49,39.18) 50.49,38.73 50.76,38.47 U11.59
  BOTTOM w0.102: TP204.1 50.49,40.13 v2(50.49,39.18)
TV_ON: length 8
  TOP w0.102: CN5.20 35.53,23.33 35.24,23.62 34.43,23.62 33.98,24.07 32.67,24.07 32.14,24.59 R487.2 31,24.62 30.24,25.38 v1(30.24,26.1)
TXDA: length 2.7
  TOP w0.102: v2(138,17.53) 138.44,17.09 U16.3
  BOTTOM w0.102: L77.1 138.44,17.97 v2(138,17.53)
TXDA_L: length 38.2
  TOP w0.102: J6.3 157.3,4.16 157.3,5.91 156.41,6.79 v2(155.46,6.79) C337.1
  BOTTOM w0.102: L77.2 138.44,20.38 138.76,20.7 142.38,20.7 142.7,20.38 142.7,19.18 143.2,18.67 148.47,18.67 149.93,17.21 149.93,14.73 v1(150.25,14.41) 150.76,14.41 151.39,13.78 151.39,11.49 149.93,10.03 149.93,6.92 150.32,6.54 155.2,6.54 v2(155.46,6.79)
USB0N: length 20.4
  BOTTOM w0.13: CN14.2 12.82,102.48 13.22,102.48 15.3,100.41 15.3,96.17 13.6,94.48 13.6,93.23 13.93,92.9 14.32,92.9 Q58.3 14.73,92.9 15.76,92.9 16.42,92.24 18.03,92.24 18.36,92.57 18.36,93.22 18.05,93.54 18.05,93.79 18.22,93.96 18.44,93.96 18.74,93.67 L51.3
USB0P: length 20.4
  BOTTOM w0.13: L51.2 18.71,94.52 18.43,94.23 18.1,94.23 17.77,93.9 17.77,93.42 18.09,93.11 18.09,92.68 17.92,92.51 17.43,92.51 Q58.4 17.06,92.51 16.53,92.51 15.87,93.17 14.04,93.17 13.87,93.34 13.87,94.36 15.57,96.06 15.57,100.52 13.34,102.76 12.82,102.76 CN14.3
USB5V2: length 1.2
  BOTTOM w0.381: Q58.5 18.22,91.76 v2(18.39,91.59)
  vias: v1(15.38,77.15) v1(15.5,73.41) v1(17.08,72.16) v1(17.35,77.15) v2(12.39,93.79) v2(12.39,93.03) v2(12.39,92.27) v2(12.39,91.5) v2(13.73,79.5) v2(13.73,78.61) v2(14.29,78) v2(14.72,78.61)
USB6N: length 16.8
  BOTTOM w0.13: CN15.2 12.82,82.43 13.23,82.43 13.65,82.85 13.65,90.79 13.87,91.01 14.33,91.01 Q58.1 14.72,91.01 15.9,91.01 16.56,90.35 18.19,90.35 18.42,90.13 18.42,89.6 18.12,89.3 L52.3
USB6P: length 17.2
  BOTTOM w0.13: L52.2 18.97,89.29 18.69,89.58 18.69,90.24 18.31,90.62 17.44,90.62 Q58.6 17.05,90.62 16.68,90.62 16.02,91.28 13.76,91.28 13.38,90.91 13.38,82.97 13.12,82.71 12.82,82.71 CN15.3
USB_0N: length 90.3
  TOP w0.102: 81.88,66.58 81.89,66.59 81.94,66.59 82.2,66.85 84.53,66.85 84.87,66.51 U10.B16
  TOP w0.13: v2(21.73,87.04) 22.05,87.36 22.76,87.36 24.38,85.73 26.52,85.73 28.76,83.5 37,83.5 37.58,84.07 41.84,84.07 42.1,84.33 44.51,84.33 44.93,83.9 49.14,83.9 49.8,84.56 51.31,84.56 52.31,83.57 55.11,83.57 v2(55.43,83.25) ; 81.88,66.58 81.72,66.42 78.01,66.42 74.83,69.6 74.83,70.93 v2(75.15,71.25)
  BOTTOM w0.13: v2(21.73,87.04) 21.41,87.36 21.11,87.36 20.63,87.83 20.63,92.06 21.46,92.88 21.46,93.87 21.37,93.96 21.15,93.96 20.86,93.67 L51.4 ; v2(75.15,71.25) 74.83,70.93 74.83,70.5 74.55,70.21 73.43,70.21 72.89,70.75 72.89,72.38 71.64,73.63 71.64,79.91 67.66,83.89 56.07,83.89 v2(55.43,83.25)
USB_0P: length 89.8
  TOP w0.102: 82.07,66.39 82.09,66.41 82.09,66.46 82.28,66.65 84.3,66.65 U10.A16
  TOP w0.13: v2(74.24,71.25) 74.56,70.93 74.56,69.49 77.9,66.15 81.83,66.15 82.07,66.39 ; v2(55.43,84.54) 55.43,84.16 55.11,83.84 52.42,83.84 51.42,84.84 49.69,84.84 49.03,84.18 45.04,84.18 44.62,84.6 41.99,84.6 41.73,84.35 37.46,84.35 36.89,83.77 28.87,83.77 26.63,86 24.5,86 22.87,87.63 22.05,87.63 v2(21.73,87.95)
  BOTTOM w0.13: L51.1 20.87,94.52 21.16,94.23 21.48,94.23 21.73,93.98 21.73,92.77 20.9,91.94 20.9,87.95 21.22,87.63 21.41,87.63 v2(21.73,87.95) ; v2(55.43,84.54) 55.81,84.16 67.77,84.16 71.91,80.02 71.91,73.74 73.16,72.49 73.16,70.87 73.54,70.48 74.43,70.48 74.56,70.61 74.56,70.93 v2(74.24,71.25)
USB_1N: length 122.1
  TOP w0.102: U10.A17 84.7,67.32 84.39,67.62 82.28,67.62 82.24,67.66 82.23,67.66
  TOP w0.13: 82.23,67.66 81.2,67.66 81.05,67.81 80.67,67.81 80.52,67.66 80.14,67.66 79.99,67.81 79.6,67.81 79.46,67.66 79.07,67.66 78.93,67.81 78.54,67.81 78.4,67.66 78,67.66 76.41,69.24 76.41,71.58 76.59,71.75 v2(76.67,71.75) ; U5.6 18.59,129.85 18.48,129.96 18.08,129.96 17.52,129.4 17.19,129.4 17.05,129.26 16.78,129.26 16.65,129.4 16.43,129.4 16.29,129.26 16.07,129.26 15.94,129.4 15.69,129.4 15.56,129.26 15.28,129.26 15.15,129.4 14.85,129.4 13.96,128.5 13.96,128.12 14.08,127.99 14.08,127.79 13.96,127.66 13.96,127.41 14.08,127.28 14.08,127.03 13.96,126.9 13.96,123.9 17.78,120.08 27.28,120.08 30.63,116.73 48.04,116.73 53.37,111.4 53.37,102.09 58.06,97.41 58.06,92.96 58.62,92.39 58.62,88.13 59.45,87.31 59.45,86.06 59.76,85.74 60.07,85.74 v5(60.39,86.06)
  BOTTOM w0.13: v2(76.67,71.75) 76.44,71.75 76.3,71.89 76.3,75.21 74.32,77.19 74.32,78.75 68.04,85.03 62.12,85.03 61.41,85.74 60.71,85.74 v5(60.39,86.06)
USB_1P: length 122.9
  TOP w0.102: U10.B17 85.27,67.32 84.97,67.01 84.71,67.01 84.3,67.42 82.29,67.42 82.26,67.39 82.23,67.39
  TOP w0.13: v2(60.39,85.15) 60.07,85.47 59.65,85.47 59.18,85.94 59.18,87.19 58.35,88.02 58.35,92.28 57.78,92.84 57.78,97.29 53.1,101.98 53.1,111.29 47.92,116.46 30.52,116.46 27.17,119.81 17.66,119.81 13.68,123.79 13.68,128.61 14.74,129.67 17.41,129.67 17.97,130.23 18.48,130.23 18.59,130.35 U5.5 ; 82.23,67.39 77.88,67.39 76.14,69.13 76.14,71.38 v2(75.76,71.75)
  BOTTOM w0.13: v2(75.76,71.75) 76.03,72.02 76.03,75.09 74.05,77.08 74.05,78.64 67.93,84.76 62,84.76 61.3,85.47 60.71,85.47 v2(60.39,85.15)
USB_2N: length 79.6
  TOP w0.13: v3(90.69,67.24) 90.69,67.77 U10.J18 ; L39.4 88.04,19.13 88.33,19.42 88.33,21.91 80.71,29.54 80.71,30.81 77.05,34.47 73.81,34.47 69.13,39.15 69.13,41.49 69.44,41.79 69.89,41.79 70,41.9 70,42.09 v5(69.66,42.42)
  BOTTOM w0.102: v3(90.69,67.24) 90.99,66.94 90.99,66.56 90.01,65.58 90.01,64.4 89.62,64.01 89.62,63.47 89.5,63.35 88.6,63.35 87.64,62.39 87.59,62.39 87.57,62.37
  BOTTOM w0.13: 87.57,62.37 87.24,62.04 85.62,62.04 84.48,60.9 80.05,60.9 79.59,61.37 75.27,61.37 74.26,60.35 70.71,60.35 68.74,58.38 68.74,44.96 69.98,43.71 69.98,42.74 v5(69.66,42.42)
USB_2P: length 79.4
  TOP w0.13: L39.1 88.89,19.13 88.6,19.42 88.6,22.03 80.98,29.65 80.98,30.92 77.16,34.74 73.93,34.74 69.4,39.27 69.4,41.37 69.55,41.52 70,41.52 70.27,41.78 70.27,42.11 v2(70.57,42.42) ; v3(91.5,67.25) 91.47,67.25 U10.J16
  BOTTOM w0.102: 87.77,62.18 87.78,62.2 87.78,62.25 88.68,63.14 89.58,63.14 89.83,63.39 89.83,63.92 90.22,64.32 90.22,65.49 91.2,66.47 91.2,66.94 91.5,67.24 v3(91.5,67.25)
  BOTTOM w0.13: 87.77,62.18 87.35,61.77 85.73,61.77 84.59,60.63 79.94,60.63 79.48,61.09 75.38,61.09 74.37,60.08 70.82,60.08 69.01,58.27 69.01,45.07 70.25,43.83 70.25,42.74 v2(70.57,42.42)
USB_3N: length 60.9
  TOP w0.13: v2(53.51,84.45) 53.6,84.45 53.76,84.61 53.76,84.88 52.96,85.68 49.78,85.68 48.84,84.74 45.27,84.74 44.85,85.16 44.32,85.16 43.75,85.74 43.75,86.41 43.48,86.68 CN2.36 ; U10.E16 87.24,66.69 87.01,66.93 86.4,66.93 v3(86.37,66.95)
  BOTTOM w0.102: v3(86.37,66.95) 86.37,67.06 86.16,67.27 85.74,67.27 85.45,67.56 82.65,67.56 82.35,67.87 82.08,67.87 82.04,67.83 82.02,67.83
  BOTTOM w0.13: 82.02,67.83 80.04,67.83 79.13,66.93 76.64,66.93 75.88,67.69 71.89,67.69 70.74,68.85 64.51,68.85 60.89,72.47 57.08,72.47 54.16,75.39 54.16,79.58 53.72,80.02 53.72,84.25 v2(53.51,84.45)
USB_3P: length 60.4
  TOP w0.13: v5(54.35,84.43) 54.03,84.75 54.03,85 53.07,85.95 49.66,85.95 48.72,85.01 45.38,85.01 44.96,85.43 44.44,85.43 44.02,85.85 44.02,86.42 44.28,86.69 CN2.38 ; U10.E18 87.59,67.69 v3(86.37,67.69)
  BOTTOM w0.102: 82.02,68.11 82.04,68.11 82.08,68.07 82.43,68.07 82.74,67.77 85.53,67.77 85.82,67.48 86.16,67.48 v3(86.37,67.69)
  BOTTOM w0.13: v5(54.35,84.43) 53.99,84.07 53.99,80.13 54.43,79.69 54.43,75.5 57.19,72.74 61,72.74 64.62,69.12 70.85,69.12 72.01,67.96 75.99,67.96 76.75,67.2 79.02,67.2 79.92,68.11 82.02,68.11
USB_4N: length 72.1
  TOP w0.13: L38.1 85.78,19.13 85.49,19.42 85.49,23.94 80,29.44 80,30.66 76.97,33.69 73.83,33.69 68.53,39 68.53,42.2 v2(68.75,42.42) ; v3(81.16,63.5) 81.34,63.32 81.57,63.32 81.73,63.49 81.73,64.02 83.34,65.63 84.75,65.63 U10.A14
  BOTTOM w0.13: v3(81.16,63.5) 81.43,63.24 81.78,63.24 82.07,62.95 82.07,61.99 81.55,61.47 80.42,61.47 79.96,61.93 74.93,61.93 73.91,60.92 70.33,60.92 67.96,58.54 67.96,44.81 68.44,44.32 68.44,42.72 v2(68.75,42.42)
USB_4P: length 72.7
  TOP w0.13: v2(67.83,42.42) 68.26,42 68.26,38.89 73.72,33.42 76.85,33.42 79.72,30.55 79.72,29.33 85.22,23.83 85.22,19.42 84.93,19.13 L38.4 ; U10.B14 85.4,65.72 85.04,65.35 83.45,65.35 82,63.91 82,63.37 81.68,63.05 81.49,63.05 81.18,62.74 v3(81.16,62.74)
  BOTTOM w0.13: v3(81.16,62.74) 81.39,62.97 81.67,62.97 81.8,62.84 81.8,62.1 81.44,61.74 80.54,61.74 80.07,62.2 74.81,62.2 73.8,61.19 70.22,61.19 67.68,58.66 67.68,44.69 68.17,44.21 68.17,42.76 v2(67.83,42.42)
USB_5N: length 69
  TOP w0.102: U10.C16 86.23,66.51 86.34,66.4 86.34,66.3 86.24,66.21 85.87,66.21 85.85,66.23 85.43,66.23 85.41,66.21 85.07,66.21 85.05,66.23 84.63,66.23 84.61,66.21 82.82,66.21 82.2,65.58 82.15,65.58 82.14,65.57
  TOP w0.13: L36.1 60.76,19.13 60.47,19.42 60.47,20.38 59.79,21.07 59.79,26.38 62.29,28.88 62.29,29.9 66.39,33.99 66.39,40.62 66.03,40.98 66.03,42.21 v2(66.24,42.42) ; v5(74.73,64.61) 74.48,64.37 74.48,64.16 74.61,64.03 75.03,64.03 76.3,65.3 81.87,65.3 82.14,65.57
  BOTTOM w0.13: v2(66.24,42.42) 65.81,42.84 65.81,44.07 66.18,44.43 66.18,59.44 69.89,63.15 73.53,63.15 74.48,64.11 74.48,64.37 v5(74.73,64.61)
USB_5P: length 70
  TOP w0.102: 82.33,65.38 82.35,65.4 82.35,65.45 82.9,66 84.69,66 84.71,66.02 84.97,66.02 84.99,66 85.49,66 85.51,66.02 85.76,66.02 85.78,66 86.33,66 U10.D16
  TOP w0.13: v2(65.33,42.42) 65.75,41.99 65.75,40.87 66.11,40.51 66.11,34.1 62.02,30.01 62.02,28.99 59.52,26.49 59.52,20.95 60.2,20.27 60.2,19.42 59.91,19.13 L36.4 ; 82.33,65.38 81.98,65.03 76.41,65.03 75.14,63.76 74.5,63.76 74.21,64.05 74.21,64.22 v2(73.82,64.61)
  BOTTOM w0.13: v2(65.33,42.42) 65.54,42.64 65.54,44.18 65.91,44.54 65.91,59.55 69.78,63.42 73.41,63.42 74.21,64.22 74.21,64.41 74.01,64.61 v2(73.82,64.61)
USB_6N: length 88.4
  TOP w0.13: v3(88.86,66.19) 88.91,66.24 88.91,67.44 89.31,67.84 U10.G18 ; v2(21.73,84.55) 22.05,84.87 26.09,84.87 28.28,82.68 37.35,82.68 37.93,83.26 42.17,83.26 42.43,83.52 44.17,83.52 44.65,83.04 48.23,83.04 49.12,82.15 54,82.15 54.58,81.57 v2(54.6,81.57)
  BOTTOM w0.102: 83.7,68.29 83.73,68.29 83.76,68.33 86.85,68.33 88.42,66.75 89.11,66.75 89.22,66.65 89.22,66.55 v3(88.86,66.19)
  BOTTOM w0.13: v2(21.73,84.55) 21.41,84.87 19.47,84.87 18.41,85.93 18.41,86.8 18.12,87.1 L52.4 ; v2(54.6,81.57) 54.6,81.79 54.93,82.12 55.13,82.12 55.33,81.91 55.33,76.25 57.46,74.12 60.83,74.12 65.24,69.71 71.15,69.71 72.27,68.58 76.13,68.58 76.89,67.82 78.75,67.82 79.64,68.71 82.81,68.71 83.23,68.29 83.7,68.29
USB_6P: length 87.2
  TOP w0.13: U10.G16 89.34,66.63 v3(89.77,66.19) ; v2(21.73,85.46) 22.05,85.14 26.2,85.14 28.39,82.95 37.24,82.95 37.82,83.53 42.06,83.53 42.32,83.79 44.29,83.79 44.77,83.31 48.35,83.31 49.24,82.42 54.4,82.42 54.6,82.62 v2(54.6,82.86)
  BOTTOM w0.102: 83.7,68.56 83.73,68.56 83.76,68.53 86.93,68.53 88.5,66.95 89.2,66.95 89.42,66.73 89.42,66.55 v3(89.77,66.19)
  BOTTOM w0.13: v2(21.73,85.46) 21.41,85.14 19.59,85.14 18.68,86.04 18.68,86.81 18.97,87.1 L52.1 ; 83.7,68.56 83.34,68.56 82.92,68.98 79.53,68.98 78.64,68.09 77.01,68.09 76.24,68.85 72.39,68.85 71.26,69.98 65.35,69.98 60.94,74.39 57.57,74.39 55.6,76.36 55.6,82.02 55.24,82.39 54.78,82.39 54.6,82.58 v2(54.6,82.86)
USB_7N: length 41.5
  TOP w0.13: U10.G14 89.34,65.28 v3(89.04,64.98)
  BOTTOM w0.102: v3(89.04,64.98) 89.05,64.96 89.05,64.63 89.19,64.49 89.33,64.49 89.61,64.76 89.61,65.31 89.36,65.56 87.84,65.56 87.35,66.04 86.08,66.04 85.27,66.85 81.99,66.85 81.95,66.82 81.93,66.82
  BOTTOM w0.13: 81.93,66.82 80.16,66.82 79.39,66.04 76.39,66.04 75.56,66.86 71.32,66.86 70.24,65.79 66.02,65.79 64.39,67.42 61.02,67.42 61.02,67.41 60.74,67.13 60.74,66.47 U21.2 60.21,66.45 60.21,67.11 59.9,67.42 55.64,67.42 55.43,67.22 CN28.2
USB_7P: length 42.1
  TOP w0.13: v3(88.99,63.8) 89.34,64.16 U10.G12
  BOTTOM w0.102: v3(88.99,63.8) 88.99,64.08 89.19,64.29 89.42,64.29 89.81,64.68 89.81,65.39 89.44,65.76 87.92,65.76 87.44,66.24 86.17,66.24 85.35,67.06 81.99,67.06 81.95,67.09 81.93,67.09
  BOTTOM w0.13: 81.93,67.09 80.05,67.09 79.27,66.31 76.5,66.31 75.68,67.13 71.2,67.13 70.13,66.06 66.13,66.06 64.5,67.69 60.98,67.69 60.74,67.93 60.74,68.53 U21.3 60.23,68.58 60.23,67.94 59.98,67.69 55.64,67.69 55.43,67.89 CN28.3
USB_8N: length 117.9
  TOP w0.13: U10.C13 85.99,64.87 85.99,64.14 v3(86.24,63.88) ; CN25.6 41.05,7.14 v2(41.09,7.18) ; v2(52.74,60.25) 52.42,60.57 50.98,60.57 50.1,59.69 45.33,59.69 45.08,59.44 42.5,59.44 42.16,59.78 42.16,60.08 v2(41.84,60.4)
  BOTTOM w0.13: v2(52.74,60.25) 53.02,60.53 53.96,60.53 54.32,60.16 55.63,60.16 55.99,60.53 65.11,60.53 68.7,64.12 71.09,64.12 72.21,65.23 74.85,65.23 75.83,64.26 79.89,64.26 80.8,65.17 84.98,65.17 86.24,63.9 v3(86.24,63.88) ; v2(41.09,7.18) 41.4,7.48 41.4,7.89 41.3,7.98 38,7.98 36.59,9.39 36.59,11.94 37.49,12.84 40.67,12.84 42.21,14.39 42.21,16.63 40.96,17.88 40.63,17.88 39.62,18.89 39.62,20.97 37.12,23.47 37.12,31.2 37.91,31.99 37.91,37.8 39.03,38.92 39.03,40.44 40.51,41.92 40.51,42.86 40.95,43.3 40.95,51.44 41.4,51.89 41.4,58.65 42.16,59.41 42.16,60.08 v2(41.84,60.4)
USB_8P: length 117.1
  TOP w0.13: CN25.5 42.06,6.23 41.78,6.5 41.78,6.96 v2(42,7.18) ; v3(86.47,64.59) 86.8,64.92 U10.D13 ; v2(42.75,60.4) 42.43,60.08 42.43,59.89 42.61,59.72 44.97,59.72 45.21,59.96 49.99,59.96 50.87,60.84 52.42,60.84 v2(52.74,61.16)
  BOTTOM w0.13: v2(42,7.18) 41.67,7.52 41.67,8 41.41,8.26 38.11,8.26 36.86,9.51 36.86,11.83 37.61,12.57 40.78,12.57 42.48,14.27 42.48,16.74 41.07,18.15 40.74,18.15 39.89,19 39.89,21.09 37.39,23.58 37.39,31.09 38.18,31.88 38.18,37.69 39.3,38.8 39.3,40.32 40.78,41.8 40.78,42.74 41.22,43.19 41.22,51.33 41.67,51.78 41.67,58.54 42.43,59.3 42.43,60.08 v2(42.75,60.4) ; v3(86.47,64.59) 85.94,64.59 85.09,65.44 80.69,65.44 79.78,64.53 75.94,64.53 74.97,65.51 72.09,65.51 70.97,64.39 68.59,64.39 65,60.8 55.88,60.8 55.51,60.43 54.44,60.43 54.07,60.8 53.1,60.8 v2(52.74,61.16)
USB_9N: length 70
  TOP w0.13: U10.B13 85.05,64.92 84.28,64.16 84.21,64.16 v2(83.74,63.69) ; v2(66.67,41.36) 66.92,41.1 66.92,33.77 62.86,29.7 62.86,28.58 60.35,26.08 60.35,21.62 61.83,20.14 63.1,20.14 63.25,20 63.25,19.42 62.96,19.13 L37.4
  BOTTOM w0.13: v2(83.74,63.69) 83.74,63.69 84.04,63.99 84.63,63.99 84.76,63.86 84.76,63.34 84.43,63.01 83.31,63.01 81.8,64.52 80.91,64.52 79.43,63.04 74.42,63.04 73.95,62.57 70.37,62.57 66.75,58.94 66.75,42.74 66.96,42.52 66.96,41.66 v2(66.67,41.36)
USB_9P: length 69.7
  TOP w0.13: v5(67.58,41.36) 67.41,41.36 67.19,41.15 67.19,33.66 63.13,29.59 63.13,28.47 60.63,25.97 60.63,21.74 61.95,20.41 63.21,20.41 63.52,20.11 63.52,19.42 63.81,19.13 L37.1 ; U10.A13 84.44,64.7 84.17,64.43 83.88,64.43 v2(83.74,64.56)
  BOTTOM w0.13: v2(83.74,64.56) 83.74,64.55 84.03,64.26 84.74,64.26 85.03,63.97 85.03,63.22 84.54,62.74 83.2,62.74 81.69,64.24 81.02,64.24 79.54,62.76 74.53,62.76 74.06,62.29 70.49,62.29 67.02,58.83 67.02,42.85 67.24,42.63 67.24,41.7 v5(67.58,41.36)
USB_10N: length 57.4
  TOP w0.13: CN26.4 74.69,88.22 75.06,87.85 75.06,86.35 74.07,85.36 71.58,85.36 67.88,81.67 67.88,78.68 v2(67.56,78.36) ; v3(90.62,64.99) 90.94,65.31 U10.J14
  BOTTOM w0.102: 84.62,68.76 84.65,68.79 86.99,68.79 88.6,67.18 89.77,67.18 90.33,67.74 91.73,67.74 91.92,67.56 91.92,66.69 90.84,65.62 90.84,65.21 v3(90.62,64.99)
  BOTTOM w0.13: v2(67.56,78.36) 67.89,78.04 67.89,77.79 64.95,74.85 64.95,71.26 65.7,70.52 71.61,70.52 72.74,69.39 76.47,69.39 77.15,68.71 78.5,68.71 79.39,69.6 83.27,69.6 84.11,68.76 84.62,68.76
USB_10P: length 57.6
  TOP w0.13: U10.J12 90.94,64.67 v3(91.26,64.99) ; CN26.3 75.7,88.22 75.33,87.85 75.33,86.24 74.18,85.09 71.69,85.09 68.16,81.56 68.16,78.68 v5(68.47,78.36)
  BOTTOM w0.102: v3(91.26,64.99) 91.04,65.21 91.04,65.53 92.12,66.61 92.12,67.64 91.81,67.94 90.25,67.94 89.69,67.39 88.68,67.39 87.07,69 84.67,69 84.63,69.03 84.62,69.03
  BOTTOM w0.13: 84.62,69.03 84.22,69.03 83.38,69.87 79.27,69.87 78.38,68.98 77.26,68.98 76.58,69.66 72.85,69.66 71.72,70.79 65.81,70.79 65.23,71.37 65.23,74.74 68.16,77.67 68.16,78.04 v5(68.47,78.36)
USB_11N: length 98.5
  TOP w0.13: CN5.36 41.93,21.52 42.2,21.25 42.2,21 41.2,20 41.2,19.62 40.99,19.41 v2(40.45,19.41) ; v2(53.63,61.46) 53.39,61.7 50.91,61.7 49.79,60.58 45.07,60.58 44.9,60.41 43.79,60.41 43.45,60.75 43.45,61.21 43.26,61.4 v2(43.13,61.4) ; U10.E12 87.39,64.74 v3(87.39,65.02)
  BOTTOM w0.13: v2(40.45,19.41) 40.95,19.91 40.95,20.78 38.78,22.95 38.78,37.45 39.87,38.54 39.87,39.93 41.37,41.42 41.37,42.5 41.79,42.93 41.79,51.14 42.28,51.63 42.28,58.35 43.45,59.52 43.45,61.09 v2(43.13,61.4) ; v2(53.63,61.46) 53.92,61.75 54.6,61.75 54.68,61.83 65.25,61.83 68.37,64.96 70.73,64.96 71.82,66.05 75.21,66.05 76.11,65.15 79.64,65.15 80.48,65.99 85.15,65.99 85.86,65.28 87.13,65.28 v3(87.39,65.02)
USB_11P: length 98.2
  TOP w0.13: v3(88.02,65.02) 88.02,65.26 U10.E14 ; CN5.38 42.73,21.52 42.47,21.25 42.47,20.89 41.47,19.89 41.47,19.67 v2(41.72,19.41) ; v2(53.63,62.37) 53.23,61.97 50.8,61.97 49.68,60.85 44.96,60.85 44.79,60.68 43.9,60.68 43.72,60.86 43.72,61.08 v2(44.04,61.4)
  BOTTOM w0.13: v2(53.63,62.37) 53.98,62.02 54.49,62.02 54.57,62.1 65.13,62.1 68.26,65.23 70.62,65.23 71.71,66.32 75.32,66.32 76.22,65.42 79.53,65.42 80.37,66.27 85.26,66.27 85.98,65.55 87.5,65.55 v3(88.02,65.02) ; v2(44.04,61.4) 43.72,61.08 43.72,59.41 42.56,58.24 42.56,51.52 42.07,51.03 42.07,42.81 41.64,42.38 41.64,41.31 40.14,39.81 40.14,38.43 39.06,37.34 39.06,23.06 41.23,20.89 41.23,19.91 v2(41.72,19.41)
USB_48M_R: length 13.6
  TOP w0.13: U10.A10 84.55,62.23 82.92,62.23 82.61,61.93 82.61,61.26 80.78,59.44 78.75,59.44 78.63,59.56 76.67,59.56 76.29,59.94 v1(75.02,59.94) 74.33,59.26 R324.1
USB_OC0: length 16.3
  TOP w0.102: U10.F8 88.54,60.99 v4(88.15,60.6)
  BOTTOM w0.102: v4(88.15,60.6) 87.99,60.6 87.49,60.1 85.63,60.1 84.97,59.44 81.7,59.44 80.73,58.47 77.28,58.47 76.82,58.93 75.58,58.93 v1(75.19,58.55) 74.33,57.68 R679.2
USB_OC1: length 11
  TOP w0.102: v4(88.12,59.77) 87.74,60.16 U10.E7
  BOTTOM w0.102: R668.2 v1(79.89,57.09) 80.15,57.34 81.41,57.34 82.31,58.24 86.11,58.24 86.83,58.96 86.83,59.18 87.13,59.49 87.84,59.49 v4(88.12,59.77)
USB_OC2: length 17.4
  TOP w0.102: v4(88.93,59.77) 88.54,60.16 U10.F7
  BOTTOM w0.102: v4(88.93,59.77) 88.86,59.77 88.44,60.19 87.91,60.19 87.54,59.82 85.74,59.82 85.1,59.18 81.77,59.18 80.83,58.24 77.13,58.24 76.85,57.96 76.13,57.96 75.75,57.58 75.75,56.95 v1(75.45,56.64) 75.04,56.24 R681.2
USB_OCP_0_6: length 88.2
  TOP w0.102: v2(50.37,75.31) 49.99,75.31 48.59,73.91 39.83,73.91 38.68,75.06 v3(38.68,75.87) ; v2(65.26,59.11) 65.44,58.93 70.04,58.93 v2(70.74,58.23) ; v2(35.51,81.98) 28.13,81.98 27.94,82.17 21.73,82.17 v2(20.97,82.93)
  BOTTOM w0.102: v2(35.51,81.98) 35.7,81.79 35.7,78.87 38.68,75.88 v3(38.68,75.87) ; v2(50.37,75.31) 51.34,75.31 51.51,75.15 51.51,74.45 52.36,73.6 52.36,71.48 52.64,71.2 52.64,63.24 51.85,62.46 51.85,59.73 52.14,59.44 58.49,59.44 58.76,59.17 62.91,59.17 62.98,59.11 v1(63.51,59.11) v2(65.26,59.11) ; R679.1 73.47,58.72 73.14,59.05 71.92,59.05 71.09,58.23 v2(70.74,58.23) ; v2(20.97,82.93) 19.63,81.6 19.63,77.23 R645.1 18.68,75.61 C478.1 17.73,74.41 R663.1
USB_OCP_2_4: length 84.6
  TOP w0.102: v2(94.6,25.58) 94.12,25.1 91.48,25.1 88.73,27.84 88.73,28.6 85.46,31.88 85.46,33.24 82.08,36.62 82.08,41.07 79.97,43.18 v2(78.22,43.18) ; v2(92.16,22.23) v2(92.16,17.81) ; R512.1 73.08,10.72 73.61,11.24 73.61,12.3 C320.1 R511.1 73.18,14.43 73.42,14.67 73.42,15.88 74.37,16.83 v2(83.54,16.83)
  BOTTOM w0.102: v2(78.22,43.18) 73.24,43.18 72.17,44.25 72.17,45.54 73.23,46.6 73.23,48.96 73.49,49.22 73.49,49.61 73.87,49.99 74.45,49.99 76.59,52.13 76.91,52.13 77.23,52.45 77.23,53.09 78.62,54.48 78.62,54.49 79.46,55.32 R668.1 ; v2(94.6,25.58) 94.6,24.74 v1(94.56,24.7) 94.56,23.66 93.13,22.23 v2(92.16,22.23) ; v2(92.16,17.81) 91.6,17.81 90.63,16.83 v2(83.54,16.83)
USB_OCP_5_9: length 62.9
  TOP w0.102: R519.1 R517.1 C330.1 54.49,14.18 54.49,20.83 57.73,24.07 57.73,26.43 61.02,29.71 61.02,29.76 65.16,33.9 v3(65.16,40.87)
  BOTTOM w0.102: R681.1 73.39,56.31 72.16,56.31 ; 72.16,56.31 71.96,56.31 71.64,55.99 71.64,53.72 70.27,52.35 70.27,49.5 71.03,48.74 71.03,47.17 70.88,47.02 70.88,46.33 71,46.2 71,43.31 71.45,42.86 71.45,41.91 71.32,41.78 69.73,41.78 68.97,41.02 68.97,40.26 68.65,39.94 65.99,39.94 65.16,40.77 v3(65.16,40.87) ; 72.16,56.31 v1(72.15,56.32)
USB_RCOMP_R: length 2.2
  TOP w0.32: U10.G19 89.35,68.99 v3(89.71,69.35)
  BOTTOM w0.32: v1(89.1,69.91) 89.14,69.91 v3(89.71,69.35) 89.56,69.35 R670.1
USB_SB_REAR_P_DN2_FILTER: length 13.2
  TOP w0.13: CN19.2 91.04,8.28 90.53,8.28 88.53,10.29 87.77,10.29 87.23,10.82 87.23,12.55 87.88,13.19 87.88,14.25 Q50.1 87.88,14.63 87.88,15.1 88.33,15.55 88.33,16.65 88.04,16.94 L39.3
USB_SB_REAR_P_DN4_FILTER: length 15.2
  TOP w0.13: CN18.2 80.26,8.28 83.72,8.28 86.28,10.84 86.28,12.99 85.62,13.64 85.62,14.25 Q50.3 85.62,14.63 85.62,15.62 85.49,15.75 85.49,16.65 85.78,16.94 L38.2
USB_SB_REAR_P_DN5_FILTER: length 15.3
  TOP w0.13: L36.2 60.76,16.9 60.56,16.7 60.56,14.67 Q49.3 60.56,14.21 60.56,13.61 61.25,12.93 61.25,10.6 58.93,8.28 55.26,8.28 CN16.2
USB_SB_REAR_P_DN9_FILTER: length 13.3
  TOP w0.13: L37.3 62.96,16.9 63.25,16.61 63.25,15.74 62.88,15.37 62.88,14.64 Q49.1 62.88,14.24 62.88,13.59 62.21,12.92 62.21,10.72 63.38,9.55 64.03,9.55 65.32,8.26 66.06,8.26 CN17.2
USB_SB_REAR_P_DP2_FILTER: length 12.7
  TOP w0.13: CN19.3 91.04,8.56 90.65,8.56 88.64,10.56 87.88,10.56 87.51,10.93 87.51,11.54 Q50.6 87.51,11.91 87.51,12.43 88.15,13.08 88.15,14.98 88.6,15.44 88.6,16.65 88.89,16.94 L39.2
USB_SB_REAR_P_DP4_FILTER: length 14.8
  TOP w0.13: L38.3 84.93,16.94 85.22,16.65 85.22,15.64 85.35,15.5 85.35,13.53 86.01,12.88 86.01,11.92 Q50.4 86.01,11.53 86.01,10.96 83.6,8.56 80.26,8.56 CN18.3
USB_SB_REAR_P_DP5_FILTER: length 14.9
  TOP w0.13: L36.3 59.91,16.94 60.29,16.55 60.29,13.5 60.98,12.82 60.98,11.91 Q49.4 60.98,11.54 60.98,10.72 58.82,8.56 55.26,8.56 CN16.3
USB_SB_REAR_P_DP9_FILTER: length 12.8
  TOP w0.13: L37.2 63.81,16.92 63.52,16.63 63.52,15.63 63.15,15.26 63.15,13.48 62.48,12.81 62.48,11.92 Q49.6 62.67,11.71 62.48,11.52 62.48,10.84 63.49,9.82 64.14,9.82 65.43,8.53 66.01,8.53 CN17.3
V_AMP: length 4
  BOTTOM w0.305: U25.16 20.53,37.01 ; U25.15 19.88,37.01
  BOTTOM w0.508: L67.2 14.62,37.65 v1(14.62,37.08)
  vias: v2(18.68,37.78) v2(19.38,37.53) v2(20.2,37.66)
VCT_LAN: length 14.7
  TOP w0.508: CN23.5 123.33,18.38 C318.2
  INT1 w0.508: v2(131.27,20.11) 130.71,19.55 127.91,19.55 127.26,20.2 126.08,20.2 123.86,17.99 CN23.5
  BOTTOM w0.508: CN23.6 125.13,15.59 123.86,16.86 CN23.5
VGA_BLUE: length 14.3
  TOP w0.165: CN1.172 47.25,213.74 46.94,213.42 46.16,213.42 44.95,212.22 43.98,212.22 43.03,211.26 40.43,211.26 39.71,210.55 39.43,210.55 v1(38.81,209.93) 39.05,209.69 R61.1 R61.2 R70.1
VGA_GREEN: length 13.1
  TOP w0.165: CN1.170 47.75,213.55 47.06,212.85 46.48,212.85 45.02,211.39 44.05,211.39 43.35,210.69 41.29,210.69 v1(40.71,210.12) 40.57,209.98 R62.1 R62.2 R71.1
VGA_RED: length 12
  TOP w0.165: R72.1 R63.2 R63.1 42.09,209.53 v1(42.62,210.06) 43.6,210.06 44.11,210.57 45.08,210.57 46.79,212.28 47.3,212.28 48.25,213.23 CN1.168
VLDT_HT3_RUN_B: length 13.1
  TOP w0.5: U6.H5 107.16,162.37 108.17,162.37 U6.H6
  TOP w0.508: U6.H5 v3(106.4,162.87) 105.79,162.27 v3(104.45,162.27) 104.42,162.24 U6.H2 U6.H1 v3(101.17,162.24) 100.6,162.24 98.96,163.87 98.54,163.87 v2(98.18,164.24)
  BOTTOM w0.508: v2(98.18,164.24) 98.82,164.87 C370.1
VLDT_P1V2: length 40.3
  BOTTOM w0.508: v2(114.03,101.35) v2(114.03,102.11) 114.03,102.64 112,104.67 112,106.3 111.19,107.11 110.86,107.11 109.64,108.33 108.09,108.33 107.83,108.58 103.44,108.58 99.57,112.46 99.07,112.46 98.3,113.23 96.96,113.23 95.39,114.81 95.39,118.36 92.72,121.03 92.72,125.35 92.34,125.73 R579.1 91.75,126 90.87,126.88 C531.1
  vias: v1(90.12,129.73)
VREF_AUD: length 7.2
  TOP w0.254: C283.1 17.58,44.54 18.59,45.55 18.92,45.55 19.53,46.16 19.53,47.64 v2(19.34,47.83)
  BOTTOM w0.254: U23.27 20.64,48.67 20.25,48.29 v1(20.25,47.9) 20.18,47.83 v2(19.34,47.83)
VREF_DDR: length 2.6
  TOP w0.254: PU3.5 153.06,233.73 v1(153.05,233.74) 153.06,233.76 153.06,234.14 152.92,234.28 PC18.2
VREF_SIO: length 5
  TOP w0.102: v2(50.61,36.35) 50.61,36.01 50.95,35.66 U11.52 52.42,35.66 52.97,35.12 54.64,35.12 C295.1
VRM_PWRGD: length 339.4
  TOP w0.102: v2(22.49,108.01) 23,108.01 24.64,109.65 31.14,109.65 31.51,109.28 31.51,105.41 31.95,104.97 D7.C 33.54,104.97 34.17,105.6 36.71,105.6 37.92,106.81 41.16,106.81 51.89,96.08 51.89,95.25 53.81,93.33 53.81,92.34 v3(53.8,92.33) ; R314.1 64.48,56.06 v3(63.89,56.64)
  TOP w0.254: PU2.41 118.37,242.29 115.9,244.77 PC7.2 v2(115.12,244.93) R16.2
  BOTTOM w0.102: v3(53.8,92.33) 53.4,91.94 53.4,86.03 51.77,84.4 51.77,80.06 52.59,79.25 52.59,76.58 51.95,75.95 49.86,75.95 49.49,75.58 49.49,72.26 50.71,71.04 50.71,64.26 50.66,64.21 50.66,59.01 51.48,58.19 55.67,58.19 56.22,57.63 57.54,57.63 58.35,56.82 60.26,56.82 60.97,57.53 63,57.53 v3(63.89,56.64) ; v2(115.12,244.93) 112.73,244.93 106.31,238.51 v1(93.59,238.51) 86.75,238.51 84.21,241.05 46.79,241.05 42.93,237.19 32.15,237.19 19.15,224.18 17.28,224.18 16.27,223.16 16.27,222.76 10.55,217.04 10.55,185.81 9.42,184.68 9.42,180.71 10.81,179.32 10.81,163.37 13.49,160.69 13.49,155.31 14.51,154.28 14.51,148.11 12.51,146.1 12.51,130.58 15.02,128.07 15.02,126.19 17.28,123.93 17.28,116.97 22.49,111.76 v2(22.49,108.01)
VSYNC: length 8.9
  TOP w0.165: CN1.162 49.75,213.14 v1(46.54,209.93) 45.57,208.96 R65.1 R65.2
VSYNC_N: length 195.6
  TOP w0.165: U3.B11 61.22,157.55 61.22,158.93 61.3,159 61.3,161.11 59.84,162.57 59.84,163.31 56.53,166.62 56.02,166.62 55.76,166.88 R128.2 55.84,167.46 56.34,167.96 56.34,169.31 R130.1 56.1,169.88 56.4,170.18 56.4,174.75 55.45,175.7 v2(55.45,176.85) ; v2(30.16,227.84) 29.37,228.62 19.13,228.62 17.74,227.23 17.74,224.59 18.62,223.71 18.62,222.01 17.41,220.8 14.29,220.8 13.1,219.61 13.1,206.05 14.62,204.53 R97.1 R97.2
  BOTTOM w0.165: v2(30.16,227.84) 30.63,227.84 33.88,231.09 47.82,231.09 v1(49.14,232.41) 52.57,235.84 73.54,235.84 77.8,231.58 82.22,231.58 83.27,230.53 83.27,228.8 84.47,227.61 84.47,222.76 82.56,220.85 82.56,211.3 81.42,210.16 81.42,207.65 80.02,206.25 80.02,202.39 75.5,197.87 73.67,197.87 72.06,196.25 68.25,196.25 60.84,188.85 60.84,184.91 59.32,183.39 59.32,180.34 55.83,176.85 v2(55.45,176.85)
WLAN_ON: length 68.2
  TOP w0.102: v2(74.56,79.76) 74.9,80.1 74.9,80.45 75.71,81.26 75.71,81.59 76.29,82.17 78.62,82.17 78.88,81.92 78.88,80.97 82.94,76.9 82.94,75.95 83.96,74.93 84.59,74.93 85.01,74.52 U10.B26 ; v3(34.86,86.16) 35.49,85.52 36.31,85.52 37.08,86.29 CN2.20 37.08,88.52 37.24,88.68 39.6,88.68 40.32,89.39 41.81,89.39 42.33,88.87 44.23,88.87 45.78,90.42 48.52,90.42 49.72,89.23 50.73,89.23 53.22,86.74 v2(54.2,86.74)
  BOTTOM w0.102: v2(74.56,79.76) 68.72,85.6 62.52,85.6 60.74,87.38 58.08,87.38 v1(57.44,86.74) v2(54.2,86.74) ; R632.2 35.75,87.85 R634.1 34.89,86.18 v3(34.86,86.16) 34.86,85.37 R611.1
XDCDN: length 34.5
  TOP w0.102: U5.12 22.28,127.72 23.12,126.87 23.12,125.73 23.89,124.97 26.81,124.97 28.59,126.75 28.59,130.68 28.4,130.87 28.4,136.08 v1(28.33,136.14) 28.33,139.45 30.68,141.8 30.68,142.3 v2(32.01,143.64)
  BOTTOM w0.102: CN13.P40 32.65,144.27 v2(32.01,143.64)
XDCEN: length 35.9
  TOP w0.102: U5.13 22.78,127.72 23.44,127.06 23.44,125.79 23.89,125.35 26.81,125.35 28.36,126.9 28.36,130.53 28.14,130.75 28.14,135.19 27.7,135.64 27.7,139.19 30.05,141.54 v1(30.05,142.56) 30.05,143.07 30.61,143.64 v2(31.25,143.64)
  BOTTOM w0.102: CN13.P37 35.82,142.17 35.51,141.86 35.51,141.67 35.13,141.29 33.6,141.29 v2(31.25,143.64)
XDCIS: length 4.8
  TOP w0.102: R195.1 23.72,127.29 23.28,127.73 U5.14 ; R195.1 R198.1 ; R195.1 24.65,127.83 25.22,128.4 v1(25.41,128.4)
XDRDN/MSINS: length 33.2
  TOP w0.102: v2(32.52,131.13) 32.65,131.25 R173.1 ; U5.11 21.78,127.71 22.81,126.68 22.81,125.67 23.76,124.71 27.06,124.71 28.84,126.49 28.84,131.38 v2(28.9,131.44) 29.39,131.93 29.39,132.74 28.88,133.25 28.88,135.25 29.22,135.6 29.22,138.81 v1(30.43,140.02) 32.97,142.56 R154.2
  BOTTOM w0.102: v2(28.9,131.44) 30.39,131.44 30.64,131.19 32.46,131.19 v2(32.52,131.13)
XDWPN: length 18.2
  TOP w0.102: v2(30.24,129.29) 29.92,129.6 29.92,130.43 30.43,130.94 30.43,133.49 30.87,133.93 v1(30.87,137.16) 31.35,137.64 31.67,137.64 32.65,138.62 32.65,138.94 32.84,139.13 R160.2 ; U5.15 25.79,129.35 25.98,129.16 26.68,129.16 v2(27.19,129.67)
  BOTTOM w0.102: v2(30.24,129.29) 27.57,129.29 v2(27.19,129.67)
N52255643: length 3.3
  BOTTOM w0.102: v1(52.91,172.47) 52.92,172.48 R545.1 R540.2 R551.2
N56144747: length 4.8
  TOP w0.102: Q7.G 42.45,173.33 42.05,173.74 R118.2 ; R118.2 41.05,174.32 v1(40.9,174.18) ; R118.2 C89.2 R119.2
N87830775: length 3.8
  TOP w0.102: R31.2 82.37,224.71 v1(82.37,224.09) 82.37,223.77 82.81,223.33 83.37,223.33 83.5,223.2 CN1.27
N87830784: length 3.3
  TOP w0.102: CN1.25 84,223.63 v1(84.28,223.9) 83.67,224.51 R32.2
N87830786: length 6.5
  TOP w0.102: v1(85.91,227.71) 85.21,227.01 85.21,225.43 84.78,225 R33.2 84.69,224.53 85,224.22 85,223.73 84.5,223.24 CN1.23
N174239812: length 17.5
  TOP w0.102: R366.2 87.64,41.08 86.31,42.42 v1(86.31,43.12) 86.31,43.65 85.51,44.45 85.51,46.65 85.99,47.13 85.99,49.53 86.72,50.26 86.72,51.22 89.93,54.42 89.93,55.2 U10.H1
N174239814: length 17.5
  TOP w0.102: U10.F1 88.44,54.93 83.86,50.34 83.86,45.62 83.51,45.28 v1(83.51,44.89) 83.51,44.2 83.86,43.85 83.86,42.27 85.1,41.02 R364.2
N182610771: length 2.2
  TOP w0.102: R263.2 112.79,83.74 v1(112.79,84.65) 112.79,85.55 C198.1
N182623261: length 2.5
  TOP w0.102: v1(110.98,86) 110.83,85.85 C204.1 110.83,83.66 R261.2
N182697602: length 4.4
  TOP w0.102: v1(11.95,129.03) 11.94,129.04 C122.1 R177.1 11.94,133.26 R169.1
N182697659: length 4.6
  TOP w0.102: v1(27.44,134.11) R191.1 27.33,132.85 26.82,132.35 U5.21
N182697747: length 6.8
  TOP w0.102: R168.2 34.87,133.67 v3(35.32,134.11)
  BOTTOM w0.102: v3(35.32,134.11) 35.68,134.47 CN13.P26 40.12,134.47 v1(40.46,134.81)
N182697749: length 6.8
  TOP w0.102: v2(35.19,132.72) 34.94,132.46 R171.2
  BOTTOM w0.102: v1(40.46,132.84) 39.99,132.37 CN13.P23 35.53,132.37 v2(35.19,132.72)
N182697751: length 4.6
  TOP w0.102: v6(35.7,128.4) 34.66,128.4 34.09,127.83 R192.2
  BOTTOM w0.102: CN13.P18 36.97,128.87 36.49,128.4 v6(35.7,128.4)
N182697755: length 6.9
  TOP w0.102: R197.2 34.67,127.19 v3(35.82,127.19)
  BOTTOM w0.102: v3(35.82,127.19) 36.84,127.19 37.12,127.47 CN13.P16 40.05,127.47 v1(40.46,127.06)
N182697757: length 6
  TOP w0.102: R164.2 34.09,134.68 34.09,134.68 34.61,134.68 35.19,135.25 v2(35.95,135.25) 36.78,135.25 v1(37.22,134.81)
  BOTTOM w0.102: CN13.P27 36.04,135.17 v2(35.95,135.25)
N182697759: length 7.2
  TOP w0.102: v2(35.19,131.76) 34.68,131.25 R173.2
  BOTTOM w0.102: v1(40.46,130.87) 39.66,131.67 CN13.P22 37.25,131.67 36.84,132.08 35.51,132.08 v2(35.19,131.76)
N182697767: length 5.3
  TOP w0.102: v3(35.25,124.71) v1(35.25,124.02) 35.25,123.89 34.55,123.19 R203.2
  BOTTOM w0.102: CN13.P12 35.3,124.67 v3(35.25,124.71)
N182697769: length 7.2
  TOP w0.102: R172.2 v2(34.87,138.11)
  BOTTOM w0.102: v2(34.87,138.11) 34.87,137.86 35.65,137.08 37.05,137.08 37.23,137.27 CN13.P30 39.91,137.27 v1(40.4,136.78)
N182697771: length 4.5
  TOP w0.102: v5(35.21,136.78) 34.89,137.1 R174.2
  BOTTOM w0.102: v5(35.21,136.78) 35.28,136.86 36.89,136.86 37.18,136.57 CN13.P29
N182697773: length 7
  TOP w0.102: R202.2 35.19,125.49 v3(35.19,125.67) 36.33,125.67 v1(36.9,125.09)
  BOTTOM w0.102: v3(35.19,125.67) 35.6,126.07 CN13.P14
N182697798: length 6.6
  TOP w0.102: R154.1 34.11,142.56 v2(34.87,141.8) 35.44,142.37 v1(36.14,142.37)
  BOTTOM w0.102: v2(34.87,141.8) 35.57,142.49 35.57,142.75 35.69,142.87 CN13.P38
N182697803: length 5.7
  TOP w0.102: R156.1 34.11,141.41 v2(34.81,140.72) 35.06,140.46 v1(35.57,140.46)
  BOTTOM w0.102: CN13.P36 36.07,141.47 35.32,140.72 v2(34.81,140.72)
N182697808: length 4.8
  TOP w0.102: v6(35.19,126.43) 34.17,125.41 R200.2
  BOTTOM w0.102: CN13.P15 36.33,126.77 35.99,126.43 v6(35.19,126.43)
N182697810: length 7.6
  TOP w0.102: v3(34.36,129.98) 34.1,129.72 R186.2
  BOTTOM w0.102: v1(40.46,128.97) 39.86,129.57 CN13.P19 34.78,129.57 v3(34.36,129.98)
N182697812: length 7.4
  TOP w0.102: R158.1 34.67,139.57 v2(35.38,139.57)
  BOTTOM w0.102: v2(35.38,139.57) 35.88,140.07 CN13.P34 39.39,140.07 40.27,139.19 v1(40.27,138.75)
N182697814: length 6.2
  TOP w0.102: v1(36.46,138.68) 35.06,138.68 v2(34.87,138.87) 34.62,139.13 R160.1
  BOTTOM w0.102: CN13.P33 36,139.37 35.51,138.87 v2(34.87,138.87)
N182697816: length 8
  TOP w0.102: v1(31.57,144.53) 31.95,144.53 32.46,144.02 33.92,144.02 34.07,143.87 R152.1 34.14,143.57 v2(35.04,142.67)
  BOTTOM w0.102: CN13.P39 35.93,143.57 v2(35.04,142.67)
N182697915: length 5.6
  TOP w0.102: v1(23.07,137.51) 22.48,136.91 R161.2 21.88,136.27 20.58,134.97 20.58,134.31 20.78,134.11 U5.27
N182698008: length 3.7
  TOP w0.102: U5.3 18.65,131.35 17.92,132.08 17.92,132.65 v1(17.54,133.03) R170.2
N182698044: length 3
  TOP w0.102: R165.1 20.26,138.29 v1(20.33,138.37)
  TOP w0.508: R165.1 19.95,137.42 LED1.C
N182698057: length 5.2
  TOP w0.13: U5.1 19.27,133.27 18.26,134.28 R166.2 16.62,135.42 v1(16.65,135.45)
N182846361: length 16.4
  TOP w0.102: Q4.G 13.15,194.76 12.96,194.94 v2(8.77,194.94) ; v2(8.19,192.2) 8.65,192.65 R99.2 7.43,192.99 7.18,193.23 Q5.G 7.18,194.68 R88.1 7.12,194.9 Q3.D 5.21,196.43 v1(5.16,196.48)
  BOTTOM w0.102: v2(8.19,192.2) 8.77,192.78 v2(8.77,194.94)
N183186081: length 4.3
  TOP w0.178: 53.56,36.46 U11.54
  TOP w0.254: v1(54.04,37.44) 54.34,37.44 54.35,37.44 ; v1(54.04,37.44) 54.04,36.95 53.56,36.46 ; v1(54.04,37.44) 54.35,37.44 ; R413.2 54.35,37.44
N183186300: length 6.5
  TOP w0.127: R409.2 54.83,38.18 55.1,38.46 56.3,38.46 v1(56.63,38.79)
  TOP w0.178: U11.55 53.07,36.87
  TOP w0.254: 53.07,36.87 53.42,37.21 53.42,37.98 53.73,38.29 54.51,38.29 R409.2
N183418266: length 111
  TOP w0.102: v3(55.07,57.72) 55.07,53.26 51.4,49.59 46.16,49.59 45.17,48.61 45.17,45.61 44.71,45.15 44.71,44.68 44.44,44.41 44.44,43.87 44.63,43.69 46.3,43.69 46.91,43.08 U11.10 ; v2(105.5,46.13) 105.29,45.92 105.29,40.77 105.07,40.54 98.84,40.54 98.37,41.01 R448.2
  BOTTOM w0.102: v2(105.5,46.13) 103.59,48.03 94.84,48.03 94.18,47.37 94.18,46.35 93.63,45.81 91.68,45.81 90.05,44.18 90.05,42.54 89.29,41.78 89.29,41.34 88.97,41.02 84.7,41.02 83.08,39.4 65.36,39.4 64.2,40.56 64.2,43.1 64.58,43.48 64.58,54.43 63.18,55.83 v1(62.7,55.83) 61.02,55.83 60.34,56.52 58.35,56.52 57.47,57.4 55.38,57.4 v3(55.07,57.72)
N183418576: length 4.2
  TOP w0.102: U11.9 47.31,43.05 45.98,44.38 R368.2 45.22,44.4 v1(45.07,44.25)
N184743934: length 2.8
  TOP w0.102: v1(78.18,227.08) 78.52,227.42 Q1.D 79.13,226.11 R39.2
N184744092: length 3
  TOP w0.102: Q2.D 81.38,227.42 v1(81.2,227.23) 80.91,226.95 80.91,226.24 R40.2
N185605081: length 4.4
  TOP w0.102: v5(28.84,49.53) 29.35,50.04 30.23,50.04 R347.1 R332.2
  BOTTOM w0.102: v5(28.84,49.53) 29.2,49.17 U23.9
N185663521: length 5.4
  BOTTOM w0.254: v1(12.71,55.5) 12.66,55.45 R686.2 11.44,54.48 9.8,52.84 CN21.6
N185663595: length 5.9
  BOTTOM w0.254: L65.1 14.76,45.4 15.25,45.4 16.71,43.94 v1(16.71,43.75) 17.22,43.75 17.62,44.15 R695.1 R713.2
N185663597: length 5.8
  BOTTOM w0.254: L63.1 14.03,52.63 14.81,53.4 v1(16.14,53.4) 16.14,52.7 16.85,51.99 R691.2 R680.1
N185693726: length 33.8
  BOTTOM w0.762: C326.1 20.71,6.22 16.39,10.54 16.39,16.33 14.49,18.24 v1(14.49,23.62) 14.49,28.45 16.14,30.1 16.14,35.56
N185693750: length 24
  BOTTOM w0.762: 16.27,27.94 16.01,27.69 v1(16.01,22.35) 16.01,19.18 17.79,17.4 17.79,11.05 18.55,10.29 22.89,10.29 C319.1
N187384381: length 6.6
  TOP w0.254: R430.1 R348.2 156.27,44.88 156.01,44.62 Q37.D 156.01,42 v1(156.16,41.84) 156.43,41.58 R452.1
N187384477: length 20.4
  TOP w0.254: v2(177.81,45.72) 178.65,45.72 R337.2 178.7,46.74 179.59,47.62 Q25.D ; v2(171.84,41.02) 168.79,41.02 168.49,41.32 R374.1 R429.1
  BOTTOM w0.254: v2(171.84,41.02) v1(174.66,41.02) 176.16,41.02 177.81,42.67 v2(177.81,45.72)
N187857917: length 4.2
  TOP w0.102: U11.58 52.62,38.06 52.86,38.31 52.86,38.74 53.91,39.79 v1(53.91,39.96) 53.96,40.01 R385.2
N188827131: length 18.6
  TOP w0.102: U10.F2 88.44,55.75 88.74,55.44 88.74,55.19 88.64,55.09 88.64,54.82 84.06,50.24 84.06,42.89 v1(84.47,42.48) 85.48,41.47 85.48,41.45 R365.2
N188975577: length 5.7
  TOP w0.102: U11.40 47.31,32.36 47.43,32.23 47.43,30.94 47.64,30.73 R477.2 47.61,30.15 47.06,29.6 47.06,28.87 46.77,28.57 v1(46.77,28.04)
N192917727: length 1.4
  TOP w0.508: U17.4 155.14,18.8 v2(154.82,18.48)
  vias: v1(152.92,18.73)
N192922009: length 82.3
  TOP w0.254: R48.2 v2(117.09,223.82) ; 104.02,188.31 L6.1 v2(104.02,184.47)
  TOP w0.508: v2(112.91,205.87) PU5.7
  BOTTOM w0.203: v2(104.02,184.47) 104.4,184.47 104.91,184.98 104.91,188.17 105.01,188.27 111.09,194.35 111.09,201.24 115.77,205.92 115.77,222.12 117.09,223.45 v2(117.09,223.82)
  BOTTOM w0.508: v2(112.91,205.87) 112.42,206.36 PC115.2
  BOTTOM w0.635: R533.1 101.99,190.56 v2(102.5,190.06)
  BOTTOM w0.762: v2(101.23,189.87) 100.66,190.44 100.66,200.09 101.86,201.29 106.18,201.29 108.86,203.97 109.98,203.97 v1(109.99,203.96) 110.01,203.97 112.11,203.97 112.91,204.77 v2(112.91,205.87)
N192922017: length 13.7
  TOP w0.508: PQ8.G1 110.63,190.5
  TOP w0.762: 110.63,190.5 110.88,190.24 111.96,190.24 112.52,190.8 112.52,191.5 v1(112.53,191.52) 112.52,191.53 112.52,201.4 R84.2
N192922021: length 19.2
  TOP w0.508: v2(94.07,202.84) 94.07,203.71 93.86,203.91 R86.2
  TOP w0.635: PQ7.G1 v2(97.29,190.31)
  BOTTOM w0.762: v2(97.29,190.31) 98.12,191.13 v1(98.12,200.03) 98.12,201.29 96.91,202.5 94.41,202.5 v2(94.07,202.84)
N192922293: length 86
  TOP w0.203: R47.2 114.56,223.98 114.18,223.6 104.2,223.6 99.52,218.91 99.52,217.7 101.23,215.99 101.23,212.55 100.85,212.17 99.08,212.17 96.56,209.64 96.56,203.84 98.56,201.83 98.56,184.91 97.48,183.83 91.9,183.83 91.32,184.4 91.32,187.33 L10.1
  TOP w0.508: PU4.7 88.96,202.64 v2(89.42,202.18)
  BOTTOM w0.508: PC116.2 89.42,202.94 v2(89.42,202.18)
  BOTTOM w0.635: R532.1 90.5,192.38 90.5,190.88 v2(90.88,190.5)
  BOTTOM w0.762: v2(89.42,202.18) 88.34,201.1 v1(88.34,199.03) 88.34,196.28 88.85,195.77 88.85,191.96 89.23,191.58 v2(89.23,190.37)
N192922340: length 6.3
  TOP w0.508: PU4.1 90.23,209.37 90.43,209.17 91.7,209.17 92.05,208.83 D6.C 90.94,207.9 v2(90.82,208.03)
  BOTTOM w0.508: R530.1 91.35,207.5 v2(90.82,208.03)
N192922344: length 5.3
  TOP w0.254: PU4.3 87.69,210.62 87.89,210.82 89.66,210.82 R53.2 90.42,212.24 v1(90.82,212.63)
N192922348: length 7.2
  TOP w0.762: PQ5.G1 87.13,199.64 86.4,200.38 v1(86.4,200.41) 86.4,204.1 PU4.5
N192922350: length 3.1
  TOP w0.254: R86.1 91.5,204.9 v1(92.02,205.42)
  TOP w0.508: R86.1 90.45,203.91 PU4.8
N192922354: length 3.4
  BOTTOM w0.254: v1(91.26,204.6) 91.25,204.61 PC116.1
  BOTTOM w0.508: PC116.1 89.78,204.63 R530.2
N192922358: length 5.2
  TOP w0.254: v1(84.78,210.44) 84.78,209.6 PC36.2
  TOP w0.508: PC36.2 86.32,209.53 PU4.4 86.42,211.02 R52.2
N192922382: length 4.9
  TOP w0.508: D5.C 114.18,211.42 PU5.1 114.91,209.64 v2(115,209.55)
  BOTTOM w0.508: R529.1 114.15,207.84 115,208.69 v2(115,209.55)
N192922384: length 4.5
  BOTTOM w0.254: v1(114.31,206.12) 113.9,206.53 113.52,206.53 112.57,207.48 R529.2
  BOTTOM w0.508: PC115.1 111,207.84 R529.2
N192922424: length 1.6
  BOTTOM w0.635: PC119.1 R532.2
N192922446: length 1.5
  BOTTOM w0.762: PC120.1 101.99,195.37 R533.2
N192922456: length 3.3
  TOP w0.254: PU5.3 111.64,211.44 R54.2 111.65,211.71 112.34,211.71 v1(112.66,212.03)
N192922460: length 15.4
  TOP w0.762: PQ6.G1 100.34,199.71 101.99,201.36 103.33,201.36 104.21,202.25 v1(109.1,202.25) 109.59,202.25 110.37,203.03 PU5.5
N192922462: length 2.6
  TOP w0.508: PU5.8 v1(114.18,202.88) 114.18,201.5 R84.1
N192922466: length 5.6
  TOP w0.254: PC35.2 108,209.56 107.93,209.49 v1(107.26,209.49)
  TOP w0.508: PR38.1 110.37,210.97 PU5.4 110.3,209.56 PC35.2
N192993943: length 12.5
  TOP w0.254: PR33.2 PC16.1 108.86,227.34 v1(109.55,228.03) 110.81,229.29 110.81,229.31 111.17,229.68 111.9,230.38 111.91,230.39 111.91,233.87 113.07,235.03 PU2.11
N192993945: length 12.4
  TOP w0.254: PU2.8 111.16,236.53 110.5,235.87 v1(110.5,231.27) 110.5,231.09 v2(109.46,230.05) 108.31,230.05 PR13.1
  BOTTOM w0.254: PR74.1 v2(109.46,230.05)
N192993947: length 6
  TOP w0.254: PU2.21 118.85,233.75 118.85,232.06 v1(119.14,231.78) 120,231.78 v2(120.46,231.31) 120.22,231.31 119.96,231.05 PR7.2
  BOTTOM w0.254: PR76.1 120.56,230.34 120.56,231.21 v2(120.46,231.31)
N192993966: length 11.8
  TOP w0.254: PU2.10 112.78,235.53 111.47,234.22 111.47,231.03 v2(109.48,229.04) 109.23,228.78 PR16.1
  BOTTOM w0.254: PR16.1 109.23,228.78 v2(109.48,229.04)
N192993980: length 9.4
  TOP w0.254: PU2.9 111.81,236.03 v3(111.14,235.36) ; v3(107.71,235.71) 107.71,235.47 PR18.1 106.91,234.67 PR12.1
  BOTTOM w0.254: v3(111.14,235.36) 110.78,235.71 v1(109.55,235.71) v3(107.71,235.71)
N192993988: length 5.3
  TOP w0.102: PC9.2 119.78,244.81 ; 119.78,244.81 120.03,244.56 v1(120.03,242.14) 120.03,241.6 119.88,241.45 PU2.38 ; 119.78,244.81 PR3.2
N192993994: length 4.8
  TOP w0.254: PU2.37 120.38,241.22 121.03,241.87 121.03,242.37 v1(122.18,243.52) PR4.2
N192994000: length 30.6
  TOP w0.254: PU2.22 119.38,232.64 119.52,232.5 v3(119.52,232.47) ; PU2.1 113.55,240.03
  TOP w0.305: 113.55,240.03 113.29,240.28
  TOP w0.381: v2(112.66,242.7) 112.22,243.14 PC1.1 108.58,242.97 PR5.2 109.28,240.66 112.91,240.66 113.29,240.28
  BOTTOM w0.381: v2(112.66,242.7) 112.98,243.02 117.11,243.02 117.46,243.03 117.89,242.6 117.91,242.6 v1(119.01,241.49) 120.53,239.97 120.53,234.24 PC102.1 119.96,233.67 119.96,232.92 v3(119.52,232.47)
N192994006: length 8.6
  TOP w0.254: PU2.29 122.71,236.53 123.08,236.16 123.08,235.83 123.58,235.33 v1(123.58,234.57) 123.58,234.09 v2(124.95,232.71) 125.56,232.11 PR10.1
  BOTTOM w0.254: v2(124.95,232.71) 125.56,232.11 PR10.1
N192994026: length 3
  TOP w0.254: v1(129.23,235.33) 129.24,235.34 PR8.2 PC8.1
N192994032: length 7.6
  TOP w0.254: PU2.3 113.26,239.03 112.69,239.6 109.98,239.6 v1(109.93,239.65) 109.88,239.6 PC11.2 PC10.2
N192994036: length 6.4
  TOP w0.254: PR35.1 v5(114.38,229.58) 114.29,229.67 PC15.2 114.87,231.31 PU2.13
  BOTTOM w0.254: PC15.2 114.38,230.63 v5(114.38,229.58)
N192994062: length 7
  TOP w0.152: PR17.2 125.85,235.34 125.49,234.98 124.52,234.98 124.37,235.12 124.37,236.09 v1(124.56,236.28) 124.11,236.28 122.96,237.43 121.89,237.43 121.79,237.53 PU2.31
N192994066: length 6.2
  TOP w0.254: PU2.36 121.8,240.03 122.69,240.92 v1(124.27,240.92) 125.66,240.92 R18.2 R20.2
N192994068: length 15.3
  TOP w0.254: PU2.33 122.72,238.53 122.9,238.71 v2(123.51,238.71) 123.68,238.71 125.64,236.76 PC2.1 126.85,237.5 v2(127.26,237.5) 127.95,236.82 PR8.1 ; v2(127.33,239.16) 128,239.84 PR9.2
  BOTTOM w0.254: v2(123.51,238.71) 123.2,239.02 PR69.1 ; v2(127.33,239.16) 127.34,239.16 127.95,238.56 PC101.2 127.95,238.18 v2(127.26,237.5) 126.89,237.87 125.89,237.87 125.4,237.38 PR63.2
N192994078: length 17
  TOP w0.254: PR7.1 119.96,228.16 120.35,227.77 122.76,227.77 123.58,228.6 125.37,228.6 125.75,228.98 125.75,230.88 124.69,231.93 124.5,231.93 v1(123.77,232.66) 122.88,233.55 122.88,234.96 122.55,235.3 122.13,235.3 121.89,235.53 PU2.27
N192994094: length 18.4
  TOP w0.254: PC4.2 107.02,236.73 105.61,236.73 v1(105.36,236.98) 105.09,237.25 PR6.1 104.28,239.07 104.28,240.01 PR1.2 ; PC4.2 107.14,236.9 PC11.1 109.76,238.31 110.42,238.96 v2(110.81,238.96) 112.67,238.96 113.1,238.53 PU2.4 ; PC4.2 106.04,235.52 PR12.2
  BOTTOM w0.254: v2(110.81,238.96) 110.88,239.04 PR64.1
N192994131: length 7.9
  TOP w0.254: PC8.2 126.42,238.37 PC2.2 125.16,238.05 123.49,239.71 v1(122.76,239.71) 122.61,239.71 121.93,239.03 PU2.34
N192994159: length 23.1
  TOP w0.508: 133.49,223.84 PU1.5
  TOP w0.635: PQ3.G1 117.3,222.5
  TOP w0.762: 133.49,223.84 v1(132.6,224.73) 130.58,226.74 119.56,226.74 118.5,225.68 118.5,223.71 117.3,222.5
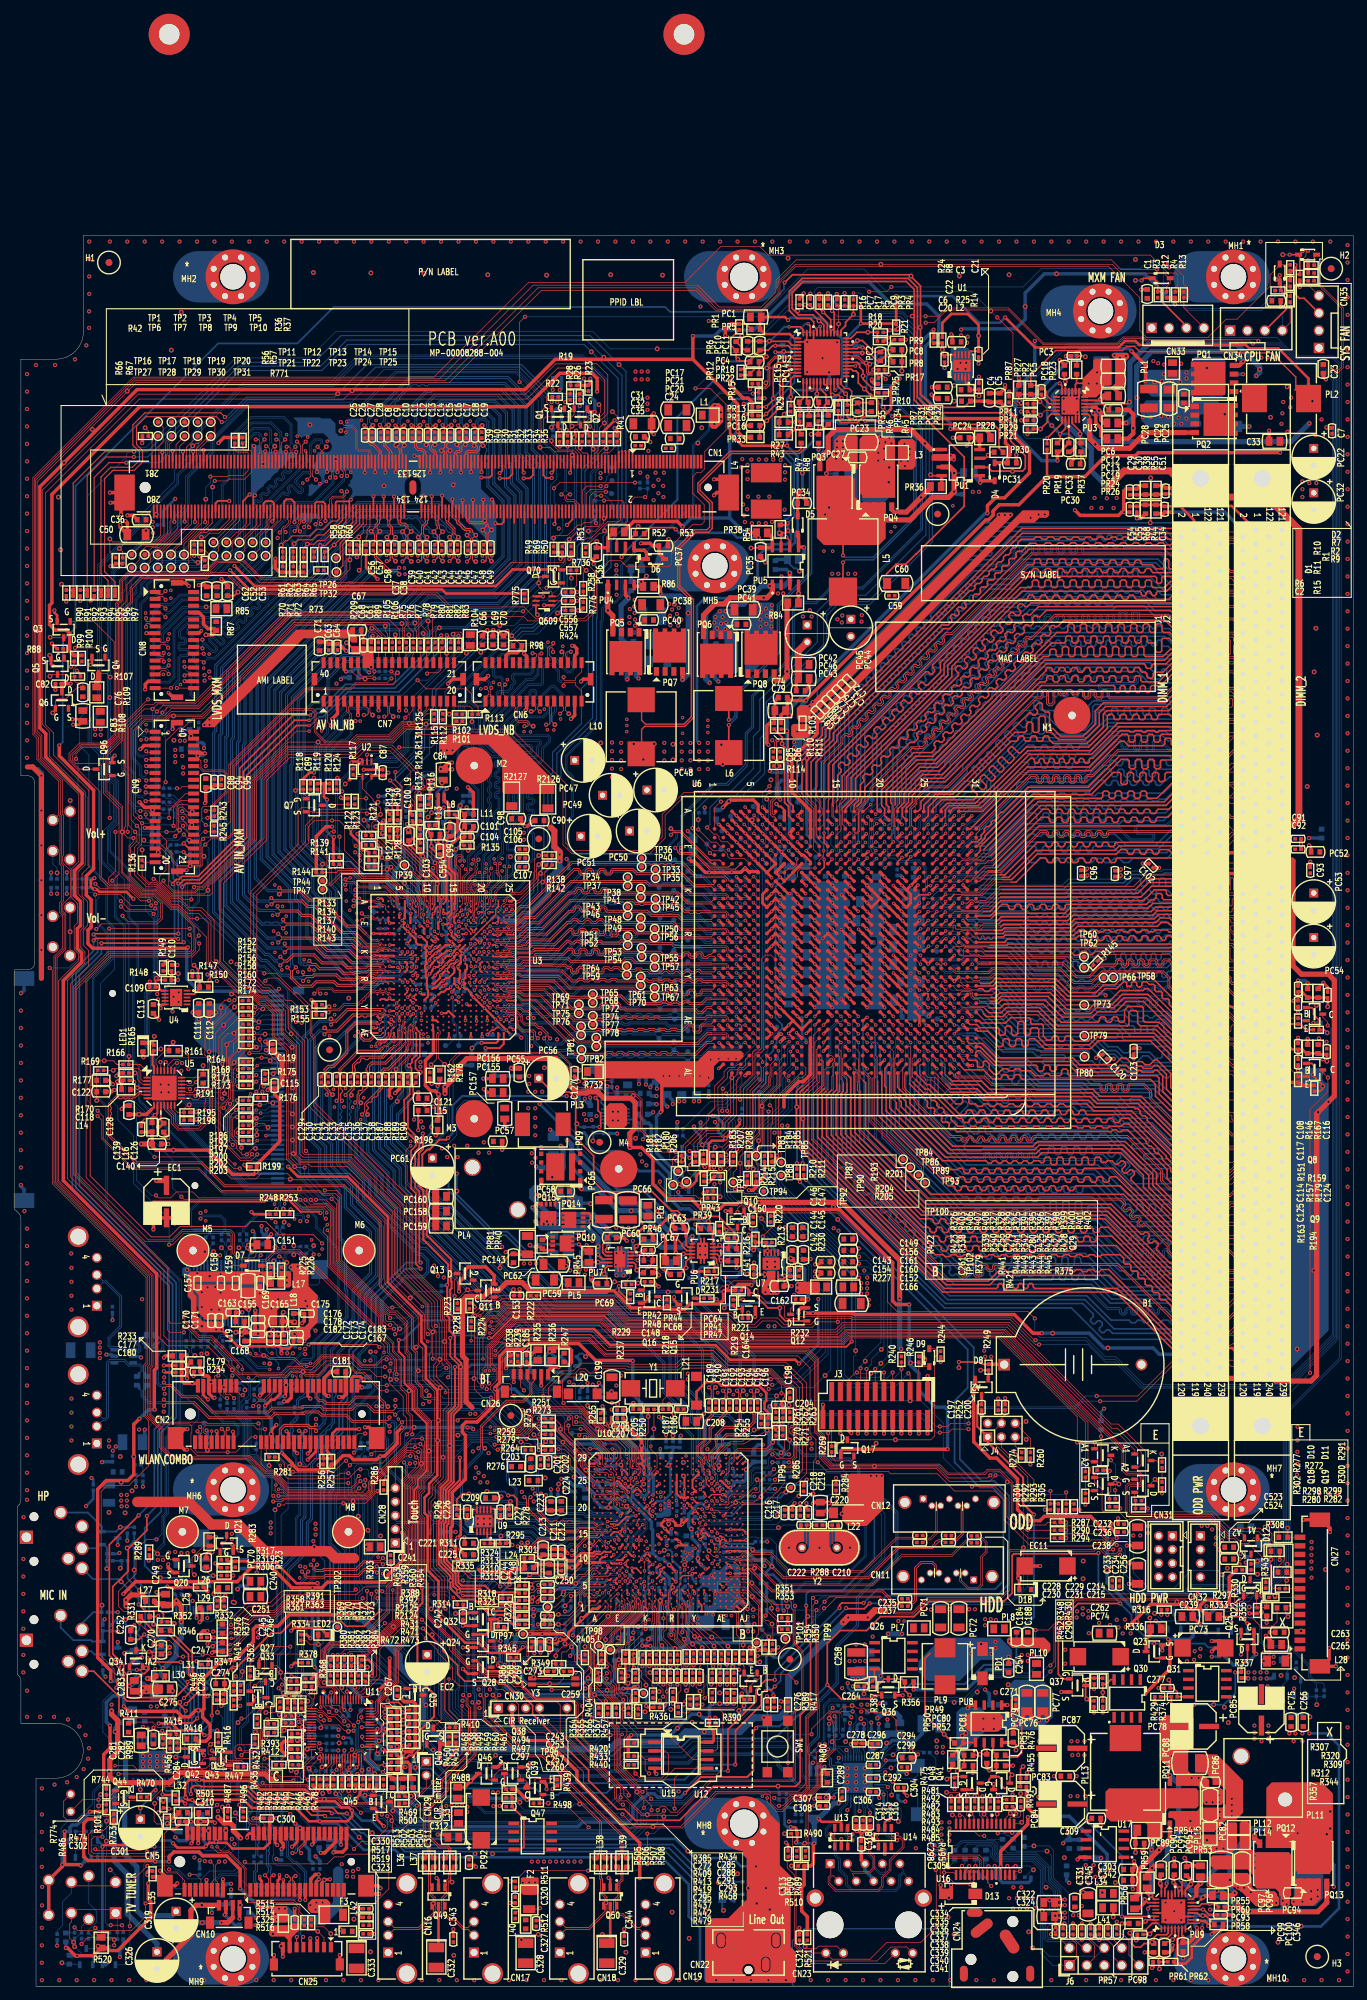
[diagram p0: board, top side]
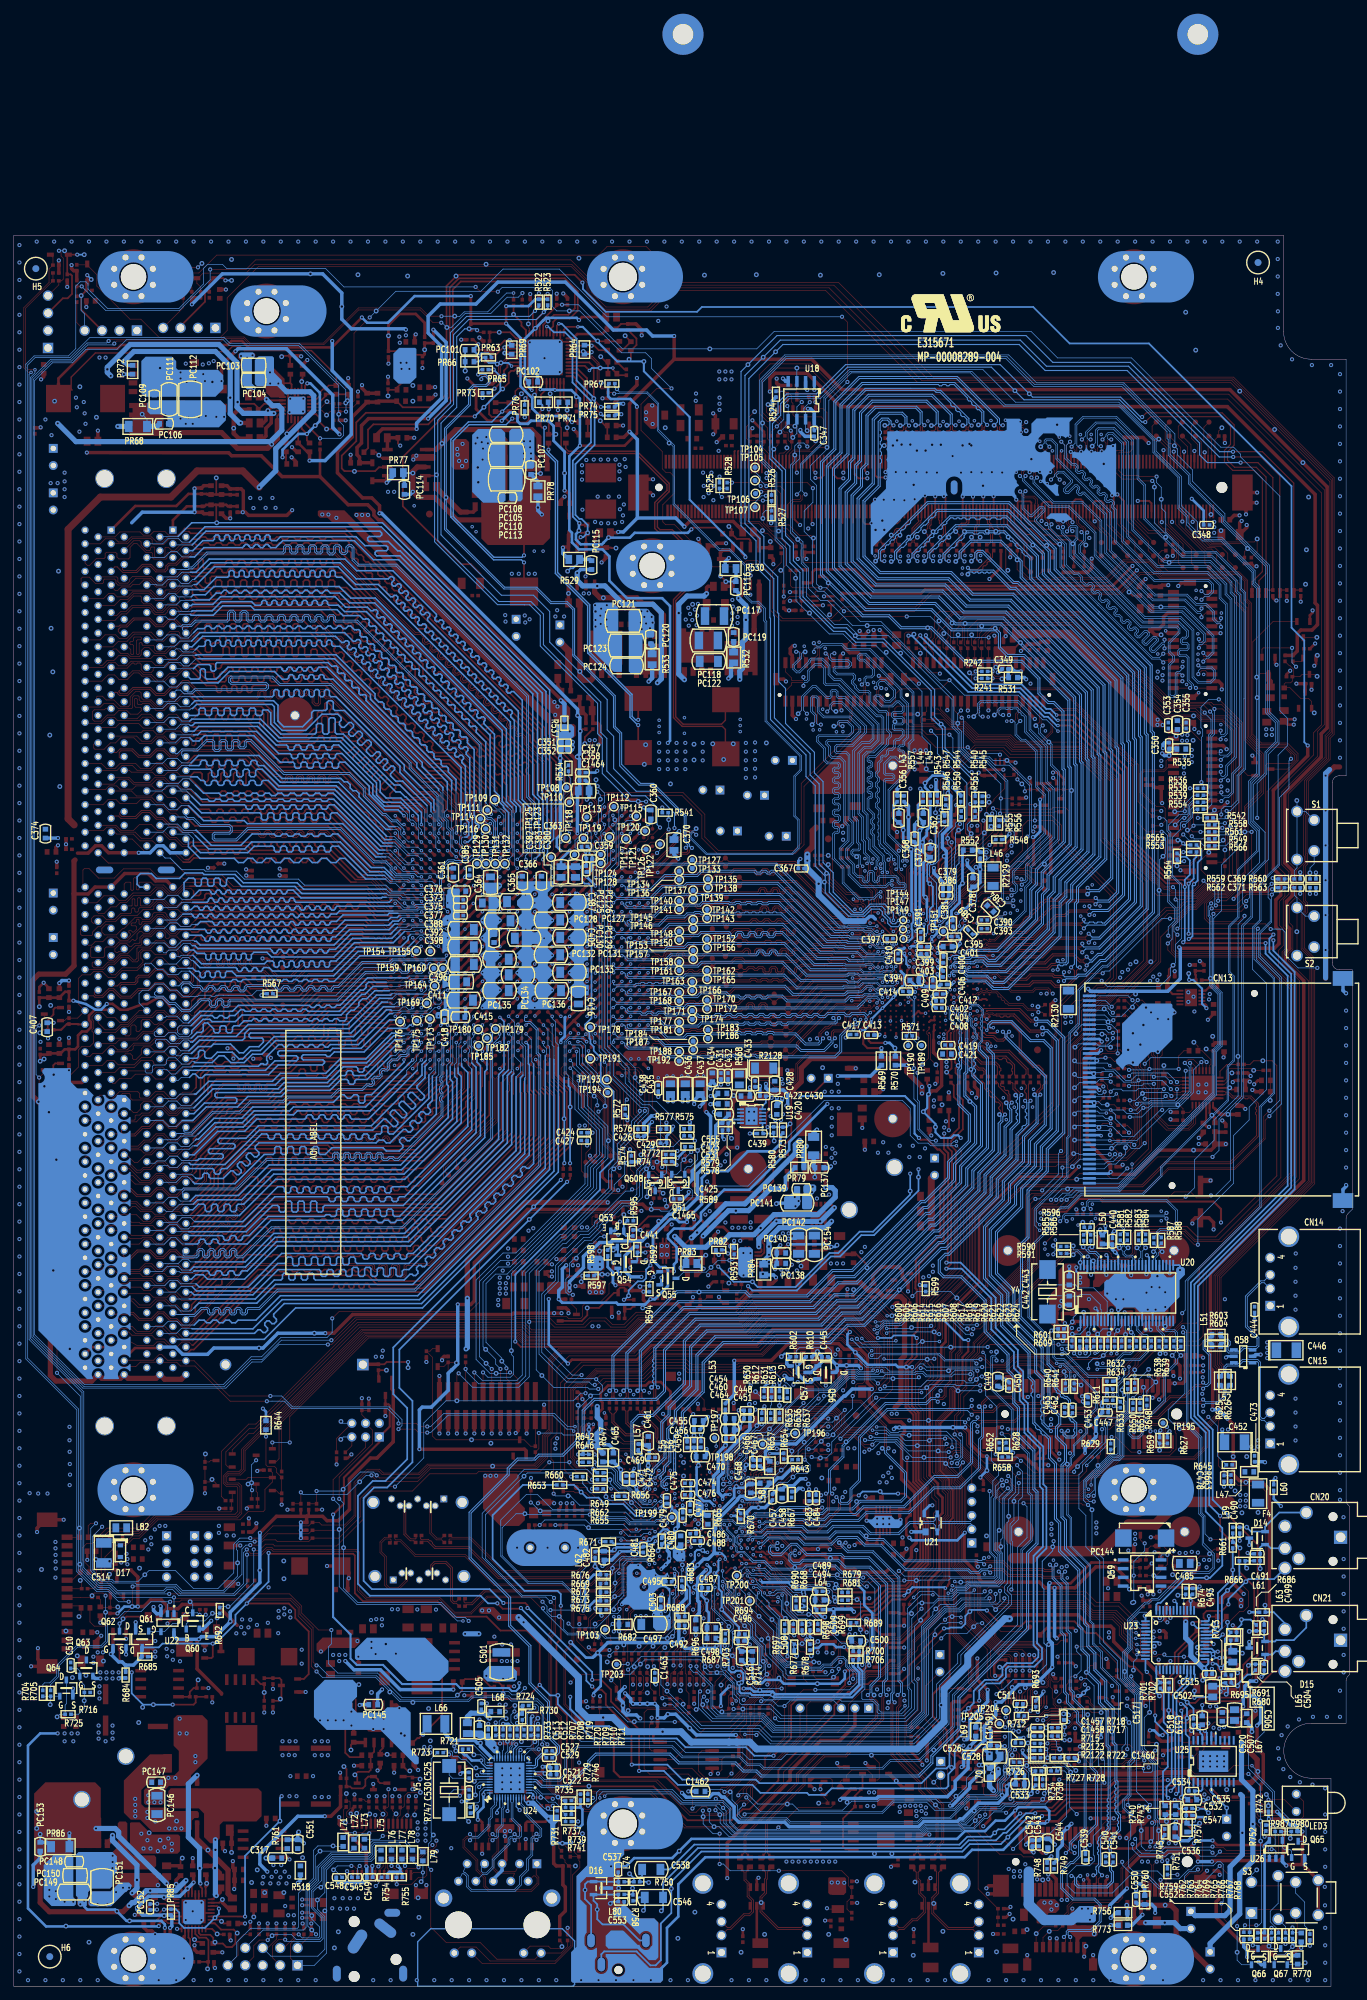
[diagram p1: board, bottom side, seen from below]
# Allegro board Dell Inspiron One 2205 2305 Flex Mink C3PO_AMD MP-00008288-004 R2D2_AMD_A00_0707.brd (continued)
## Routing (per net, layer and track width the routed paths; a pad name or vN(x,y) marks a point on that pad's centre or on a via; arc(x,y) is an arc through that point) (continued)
N192994176: length 2.5
  TOP w0.254: PR30.2 142.25,223.46 v1(141.81,223.01) 141.36,222.57 PU1.3
N192994181: length 4.6
  TOP w0.254: PC24.2 139.02,224.74 v2(138.69,224.41)
  TOP w0.508: PU1.4 140.56,225.54 PR28.1 PC24.2
N192994193: length 7.9
  TOP w0.508: PQ4.G1 127.77,215.01 128.05,214.73 128.92,214.73
  TOP w0.762: 128.92,214.73 129.91,214.73 v1(132.03,216.85) 133.23,218.06 133.23,218.08 133.42,218.27 133.42,218.42 PR36.2
N192994197: length 5.1
  TOP w0.508: PU1.1 140.66,219.93 v2(140.66,219.01) 140.94,219.29 D4.C
  BOTTOM w0.508: PR77.1 139.8,219.88 v2(140.66,219.01)
N192994201: length 61.7
  TOP w0.254: PR31.2 121.28,228.59 121.53,228.35 v2(122.38,228.35) ; 120.66,212.57 v2(120.66,208.42)
  TOP w0.762: PU1.7 136.22,221.3 136.85,220.66 v2(136.85,217.69) 136.03,216.87 133.69,216.87 130.41,213.59 126.55,213.59 126.33,213.82
  BOTTOM w0.203: v2(122.38,228.35) 123.26,227.46 128.66,227.46 130.97,225.15 130.97,214.08 125.04,208.15 120.93,208.15 v2(120.66,208.42)
  BOTTOM w0.508: v2(118.06,214.38) 118.63,214.95 v1(118.63,215.39) PR78.2 ; PC114.2 137.23,217.31 v2(136.85,217.69)
N192994203: length 3.3
  BOTTOM w0.254: v1(136.85,220.41) 138.16,220.41 PR77.2
  BOTTOM w0.508: PC114.1 138.09,219.28 138.23,219.42 PR77.2
N192994205: length 3.3
  TOP w0.254: PU1.8 133.55,220.03 v1(133.42,220.15)
  TOP w0.508: PU1.8 135.05,218.52 PR36.1
N192994229: length 6.2
  TOP w0.254: v1(113.04,231.52) 113.04,232.59 113.05,232.6 ; 113.05,232.6 R29.2 ; 113.05,232.6 113.05,234.1 113.48,234.53 PU2.12
N192994235: length 3.6
  BOTTOM w0.254: PC107.1 119.51,220.34 v1(118.25,220.34)
  BOTTOM w0.508: PR78.1 118.63,219.19 PC107.1
N192994292: length 4.5
  TOP w0.254: PU2.5 112.12,238.03 v1(112.02,238.12) 111.93,238.03 v2(110.81,238.03)
  BOTTOM w0.254: PR64.2 111.09,237.75 v2(110.81,238.03)
N192994300: length 4.4
  TOP w0.254: R29.1 112.49,229.38 v1(112.09,228.98) 111.37,228.26 R27.2 R43.1
N192994369: length 7.8
  TOP w0.254: PU2.28 122.43,236.03 v3(122.47,235.99)
  BOTTOM w0.254: PR66.1 127.25,236.64 126.64,237.25 PR63.1 126.26,236.92 125.79,236.45 124.05,236.45 v1(124.03,236.47) 124,236.45 122.93,236.45 v3(122.47,235.99)
N192994816: length 3.5
  TOP w0.254: PU2.32 123.33,238.03 123.48,237.88 v6(123.48,237.9)
  BOTTOM w0.254: PR69.2 122.46,237.72 123.3,237.72 v6(123.48,237.9)
N192995254: length 3.1
  TOP w0.254: v1(109.48,237.36) 108.74,236.62 PC4.1 PR18.2
N192995282: length 3.1
  BOTTOM w0.254: PC101.1 PR66.2 129.24,235.27 v1(129.23,235.27)
N192995298: length 10.1
  TOP w0.152: PU2.6 113.46,237.53 113.36,237.43 110.73,237.43 109.74,236.44 109.74,236.23 109.74,236.23 109.74,233.74 109.55,233.55 v1(109.42,233.55) 109.55,233.43 109.55,233.19 109.3,232.94 108.49,232.94 108.31,233.12 PR22.2
N192995372: length 3.4
  TOP w0.254: v1(105.93,240.41) 105.93,240.39 PR6.2 106.33,238.31 PC10.1
N193056398: length 2.8
  TOP w0.254: PR57.1 164.41,9.14 v1(164.73,9.46) 164.94,9.67 PU9.31
N193056406:
  vias: v1(171.27,24.07) v2(170.57,22.99) v2(171.46,22.99) v2(172.35,22.99) v2(174.38,24) v2(175.52,25.4) v2(175.52,24.51) v2(177.3,27.3) v2(177.3,26.42) v2(177.3,25.53) v2(177.3,24.77)
N193056421: length 19.9
  TOP w0.254: PU9.16 171.56,12.67 172.15,13.26
  TOP w0.635: 172.15,13.26 172.15,14.4 v2(172.73,14.99)
  TOP w0.762: v2(172.73,14.99) PR53.1
  BOTTOM w0.508: PR86.1 v2(186.89,22.29)
  BOTTOM w0.762: v2(183.02,22.99) 180.22,22.99 179.72,22.48 179.72,21.84 173.92,16.15 173.9,16.15 v2(172.73,14.99)
  vias: v1(191.65,25.46) v1(191.65,22.99)
N193056423: length 3.5
  TOP w0.254: v1(170.44,18.67) 170.7,18.41 PC95.1
  TOP w0.508: PC95.1 170.84,17.55 PR53.2
N193056457: length 8.6
  TOP w0.254: PR61.2 166.63,3.6 166.63,6.73 166.98,7.08 168,7.08 168.55,7.63 PU9.4 ; PR61.2 PR62.1 ; PR61.2 166.68,2.62 v1(166.76,2.54)
N193056459: length 3.2
  TOP w0.254: 170.95,14.48 170.54,14.07 PU9.17
  TOP w0.508: 170.95,14.48 v1(171.33,14.86) 171.33,15.48 PC95.2
N193056479: length 13.5
  TOP w0.762: PR55.1 177.28,13.21 177.75,13.56 v2(177.75,13.59) ; v2(180.6,21.97) 180.6,21.53 PQ12.G1
  BOTTOM w0.762: v2(180.6,21.97) 180.6,21.21 177.05,17.65 v1(177.05,15.49) 177.05,14.29 v2(177.75,13.59)
N193056505: length 4.1
  TOP w0.254: PR58.1 174.75,9.03 173.49,10.29 v1(173.09,10.29) 172.67,10.29 172.28,10.67 PU9.12
N193056515: length 28.5
  TOP w0.254: PU9.18 170.04,15.29 v2(169.91,15.42)
  TOP w0.762: v2(178.19,11.75) 179.08,10.86 189.81,10.86 191.15,12.19 PQ13.G1
  BOTTOM w0.762: v2(169.91,15.42) 171.41,13.92 v1(175.12,13.92) 175.7,13.92 177.43,12.19 177.75,12.19 v2(178.19,11.75)
N193056523: length 3.6
  TOP w0.254: PU9.15 172.33,12.17 172.86,12.7
  TOP w0.508: 172.86,12.7 v1(173.11,12.95) 173.37,13.21 PR55.2
N193057133: length 19.8
  TOP w0.254: PU9.23 167.54,14.24 167.8,14.5 v2(167.8,14.97)
  TOP w0.635: PQ11.G3 v2(168.29,30.73)
  BOTTOM w0.508: v1(167.9,17.21) 167.9,15.07 v2(167.8,14.97)
  BOTTOM w0.762: v2(168.29,30.73) 169.56,29.46 169.56,21.72 167.93,20.09 167.93,17.23 v1(167.9,17.21)
N193057135: length 13.1
  TOP w0.635: PQ11.G2 168.29,21.45
  TOP w0.762: PR56.2 163.78,13.48 163.78,16.94 166.68,19.84 v1(166.71,19.84) 166.71,19.87 168.29,21.45
N193057155: length 10.5
  TOP w0.254: v2(165.49,13.21) 166.03,12.67 PU9.25
  TOP w0.635: PR59.2 164.98,13.72 v2(165.49,13.21)
  BOTTOM w0.762: v2(165.49,13.21) 165.62,13.34 v1(165.62,19.88) v2(165.62,21.34)
N193057159: length 3.4
  TOP w0.381: PC89.1 163.26,19.5 v1(163.27,19.49)
  TOP w0.508: PR54.2 163.26,22.47 PC89.1
N193057381: length 13.5
  TOP w0.254: PU9.32 165.71,9.17 164.79,8.26 162.95,8.26 v1(162.44,7.75) 162.7,7.49 162.7,6.22 163.21,5.71 164.03,5.71 164.54,6.22 165.93,6.22 PC99.1 165.94,7.06 166.37,7.49 167.78,7.49 168.04,7.76 PU9.3
N193057437: length 3.1
  TOP w0.635: PC90.2 166.01,17.54 v1(165.69,17.22) 164.98,16.51 PR59.1
N193057441: length 4.1
  TOP w0.254: PU9.26 165.07,12.17 v1(164.6,12.64)
  TOP w0.508: v1(164.6,12.64) 164.6,12.19 163.69,11.28 PR56.1
N193057451: length 2.9
  TOP w0.254: PU9.24 167.04,14.58
  TOP w0.508: PC90.1 166.89,16.12 v1(166.89,14.99) 166.89,14.73 167.04,14.58
N193057466: length 3.1
  TOP w0.254: PU9.5 169.04,7.17 v1(168.67,6.79) 168.35,6.48 167.77,6.48 PC100.1
N193057470: length 3
  TOP w0.254: PC98.1 165.3,7.56 v1(165.36,7.62) 166.11,8.36 PU9.1
N193064874: length 11.2
  TOP w0.254: v2(84.59,129.41) 84.97,129.03 84.97,127.56 85.35,127.18 85.35,125.32 v2(85.18,125.14)
  BOTTOM w0.254: v1(81.9,125.63) 82.39,125.14 R573.2 84.24,125.14 R580.1 85.13,125.19 v2(85.18,125.14) ; U19.10 85.91,128.22 85.43,128.7 C430.1 84.85,129.67 v2(84.59,129.41)
N193064906: length 4.4
  BOTTOM w0.102: R578.1 90.89,123.97 v1(90.43,123.51)
  BOTTOM w0.254: U19.4 90.38,126.25 R579.2 R578.1
N193064914: length 4.4
  BOTTOM w0.254: U19.6 85.91,124.31 C439.1 84.42,124.21 R580.2 84.29,123.2 v1(84.21,123.13)
N193065496: length 5.8
  TOP w0.254: R230.2 C142.1
  TOP w0.279: U7.10 111.2,103.19 111.39,103 111.92,103 112.15,103.23 v2(112.15,103.5)
  TOP w0.305: C142.1 112.23,103.43 v2(112.15,103.5)
  BOTTOM w0.102: v1(112.33,102.62) 112.33,103.33 v2(112.15,103.5)
  BOTTOM w0.305: v2(112.15,103.5) R597.1
N193065531: length 4.4
  TOP w0.254: U7.4 109.7,107.67 109.44,107.93 R213.2 109.38,108.38 R216.1 107.91,107.52 v1(107.64,107.25)
N193065687: length 4.3
  TOP w0.305: U4.6 21.36,145.02 20.84,145.54 C109.1 20.51,146.67 v1(20.65,146.81) 20.9,146.56 R148.2
N193065695: length 11.2
  TOP w0.305: U4.10 21.39,143.02 21.25,142.88 v2(21.25,142.47) ; v2(23.76,146.58) 23.73,146.56 R148.1 22.79,147.29 22.87,147.37 C110.1 R149.2
  BOTTOM w0.254: v1(23.82,147.51) 23.82,146.65 v2(23.76,146.58)
  BOTTOM w0.305: v2(23.76,146.58) 23.15,146.58 21.88,145.31 21.88,143.1 v2(21.25,142.47)
N193065727: length 5.9
  TOP w0.254: R147.1 26.73,148.1 v1(26.11,148.72)
  TOP w0.305: R147.1 26.73,146.58 26.92,146.39 R150.2 26.92,145.28 26.17,144.52 U4.4
N193065785: length 5
  TOP w0.254: C22.1 135.69,237.64 U1.10
  TOP w0.406: C22.1 135.14,237.73 v1(135.14,238.38) R8.1 R24.2
N193065820: length 4.5
  TOP w0.254: v1(140.47,231.65) R14.1 140.39,232.54 R25.1 139.15,232.87 138.5,233.52 U1.4
N193065828: length 14.2
  TOP w0.254: U1.6 139,237.92 139.25,238.17 C21.1
  TOP w0.406: C21.1 v1(140.41,240.41) 140.41,242 138.82,243.59 136.43,243.59 135.14,242.29 R8.2
N193066078: length 14.1
  TOP w0.102: v2(31.82,59.82) R306.1 R319.1 32.06,60.96 R323.2 ; v2(30.24,64.52) 30.36,64.52 30.87,65.02 Q21.D
  BOTTOM w0.102: v1(31.82,55.94) v2(31.82,59.82) 31.82,61.85 30.24,63.44 v2(30.24,64.52)
N193066341: length 17.3
  TOP w0.254: R278.1 72.61,68.66 73.16,69.22 73.16,70.99 72.65,71.5 v2(71.89,71.5) ; v2(66.18,71.75) 65.23,71.75 64.4,70.93 R296.2 64.45,69.47 65.88,69.47 C226.1 66.02,69.42 U9.10
  BOTTOM w0.254: v2(66.18,71.75) 68.46,71.75 v1(68.78,72.07) 68.79,72.06 71.33,72.06 v2(71.89,71.5)
N193066404: length 4.4
  TOP w0.254: v1(70.81,65.6) 70.7,65.48 R295.1 R311.1 69.27,64.95 68.84,65.39 U9.4
N193066412: length 3.9
  TOP w0.254: v1(72.21,70.61) 72.02,70.42 R278.2 C227.1 69.44,69.52 U9.6
N193073716: length 4.6
  TOP w0.254: PR21.2 v1(149.43,226.82) 150.47,227.87 150.47,228.5 150.97,229 PU3.12
N193073747: length 30.3
  TOP w0.635: v2(178.95,236.66) 178.38,236.09 PQ1.G1 ; PR24.2 v2(161.94,227.71)
  BOTTOM w0.508: PR72.1 178.46,236.1 178.95,236.6
  BOTTOM w0.762: 178.95,236.6 v2(178.95,236.66) 177.49,238.12 165.61,238.12 163.46,235.97 v1(163.46,231.39) 163.46,229.06 162.11,227.71 v2(161.94,227.71)
N193073757: length 29.2
  TOP w0.254: PR21.1 v2(147.54,226.06)
  TOP w0.508: v2(164.73,233.81) 164.73,236.12 v2(162.7,238.15)
  BOTTOM w0.508: v2(162.7,238.15) 162.32,238.53 155.28,238.53 148.52,231.78 148.52,227.05 v2(147.54,226.06)
  vias: v1(166.06,233.68) v1(173.68,235.71) v2(167.14,233.81) v2(167.4,234.82) v2(168.54,233.81) v2(169.81,233.68) v2(170.7,235.08) v2(170.7,234.19)
N193073929: length 2.7
  TOP w0.254: v1(155.97,237.36) 155.84,237.49 PC3.2 154.75,236.15 PR23.1
N193074055: length 7.9
  TOP w0.635: PC19.2 162.32,229.62 162.95,228.98 v1(162.95,226.95) 162.95,226.19 162.19,225.43 PR26.1
N193074069: length 4.1
  BOTTOM w0.102: PR68.2 175.59,228.29 v1(176.29,228.98)
  BOTTOM w0.762: PC106.1 174.14,227.2 PR68.2
N193081910: length 11.2
  TOP w0.254: 145.17,41.78 145.17,39.5 146.7,37.97 146.7,34.01 146.06,33.38 144.57,33.38 PR51.2
  vias: v1(142.89,42.8) v1(144.73,43.94)
N193081924: length 15.3
  TOP w0.254: PR49.2 136.21,36.13 135.96,36.13 v1(135.39,36.7) 134.22,37.87 134.21,37.87 132.6,39.49 132.6,47.75 133.36,48.51
N193082210: length 2.5
  BOTTOM w0.508: PC145.2 141.99,42.59 141.35,43.23 v2(141.34,43.23)
  vias: v1(136.85,41.34) v1(140.22,42.86)
N193082214: length 5.4
  TOP w0.254: PR49.1 138.2,35.38 137.25,34.43 137.25,34.2 136.71,33.67 PR50.2 ; PR49.1 138.81,35.43 138.87,35.5 PU8.5 ; PR49.1 138.2,36.38 v1(138.06,36.51)
N193082220: length 3.9
  TOP w0.254: PU8.6 141.23,34.67 141.62,34.29 PC81.1 140.61,33.79 v1(140.6,33.78) 140.47,33.66 PC80.1
N193082230: length 2.2
  TOP w0.508: PU8.1 v2(144.6,40.95)
  BOTTOM w0.508: PC145.1 144.54,41.02 v2(144.6,40.95)
N193082234: length 2.9
  TOP w0.254: PC80.2 PR52.1 138.3,32.08 137.59,31.37 v1(137.3,31.37)
N193082279: length 8.1
  TOP w0.254: Q41.D 144.96,30.45 v1(145.3,30.8) 144.85,31.24 143.27,31.24 143,31.51 R476.1 PR51.1 142.5,34.15 PU8.7
N193082337: length 3
  TOP w0.254: v1(145.87,34.42) 145.87,35.16 PC79.2
  TOP w0.508: PC79.2 145.43,35.5 PU8.8
N193417260: length 11.6
  TOP w0.102: v2(167.9,54.1) 167.9,54.85 R316.2
  BOTTOM w0.102: Q61.G 175.26,51.65 U22.4 173.03,51.65 171.84,52.83 171.08,52.83 170.7,53.21 170.7,53.72 170.03,54.39 Q60.C ; Q60.C 168.92,55.63 v1(169.3,56.01) ; Q60.C 168.2,54.39 v2(167.9,54.1)
N193492984: length 6.6
  TOP w0.254: v2(179.59,52.83) 178.57,53.85 R333.2
  BOTTOM w0.203: Q62.D v2(179.59,52.83) 179.08,53.34 v1(179.08,53.53)
N193492998: length 5.2
  TOP w0.102: R336.2 165.47,53.55 v1(165.36,53.66)
  TOP w0.508: Q23.D 164.82,50.55 165.47,51.2 R336.2
N193522844: length 3.8
  TOP w0.508: R488.2 65.5,28.98 v1(66.43,29.91) 67.51,30.99 Q46.D
N193522855: length 14.9
  TOP w0.102: v1(73.59,26.8) 72.96,27.43 R497.1
  TOP w0.254: Q38.D 71.35,28.95 R494.2 71.59,28.6 72.45,27.74 R497.1 C297.1 74.18,24.43 74.18,20.32 73.8,19.94 Q47.4
N193554651:
  vias: v1(67.07,19.3) v1(69.61,19.3)
N194450047: length 6.1
  TOP w0.254: PU2.17 116.88,231.99 v1(116.85,231.97) 116.88,231.94 116.88,230.96 PC14.2 117.11,229.75 v2(117.05,229.69) PR34.1
  BOTTOM w0.254: PR70.1 117.05,230.65 v2(117.05,229.69)
N194724765: length 6.7
  TOP w0.381: R322.1 70.42,53.14 v1(70.75,53.47) Q32.C 69.39,51.98 68.65,51.24 Q24.G
N194724769: length 4.3
  TOP w0.254: C242.1 64.22,54.28 v1(64.21,54.29)
  TOP w0.381: R314.2 65.34,54.33 C242.1 65.97,54.28 66.11,54.42 Q32.B
N194724824: length 12.6
  TOP w0.102: Q28.D 69.39,47.03 69.61,47.24 70.94,47.24 v2(71.38,46.8) 72.23,47.64 R345.1 ; Q24.D v2(70.76,50.29)
  BOTTOM w0.102: v2(71.38,46.8) 71.32,46.86 71.32,49.21 70.75,49.78 70.75,50.28 v2(70.76,50.29) 70.76,50.56 71.64,51.44 v1(71.64,51.94) 72.23,52.53 R689.1
N194724852: length 6
  TOP w0.102: Q13.G 66.79,102.41 67.47,101.73 Q11.C 66.08,101.35 v1(65.97,101.45) 65.9,101.45 64.46,100.01 R228.1
N194724856: length 9.1
  TOP w0.102: v1(72.65,101.47) 72.73,101.39 C153.1 70.69,100.58 70.5,100.4 Q11.B 69.23,100.4 66.5,97.66 R224.2
N194724902: length 108.4
  TOP w0.102: R133.1 51.14,168.58 49.16,170.56 43.83,170.56 42.38,169.11 42.38,166.7 34.81,159.13 34.81,146.86 36.23,145.44 37.07,145.44 40.27,142.24 40.27,139.65 42.25,137.67 42.25,121.84 v2(42.43,121.67) ; v2(45.17,115.93) 46.9,115.93 47.57,115.25 47.57,105.79 54.49,98.87 v2(55,98.87) ; v2(64.08,100.52) 64.08,102.87 64.43,103.21 Q13.D
  BOTTOM w0.102: v2(42.43,121.67) 42.81,121.28 42.81,118.29 v2(45.17,115.93) ; v2(55,98.87) 56.21,98.87 v1(57.61,100.27) 58.54,101.2 R599.1 63.41,101.2 v2(64.08,100.52)
N195279140: length 7.1
  TOP w0.102: R469.1 v1(57.73,27.69) 58.13,27.69 58.97,28.52 58.97,31.74 CN29.1
N195279169: length 7.2
  TOP w0.102: CN29.2 59.95,29.04 58.86,27.95 58.86,27.94 57.59,26.67 R500.1
  BOTTOM w0.102: CN29.2 v1(60.97,29.72)
N195279187: length 4.1
  TOP w0.102: R499.2 53.73,28.07 53.48,27.81 52.24,27.81 Q45.B 51,27.81 v1(51,27.81)
N195352331: length 9.4
  TOP w0.102: SW1.3 v2(112.64,32.58) SW1.4 112.64,40.57 R417.1
N195361688: length 6.2
  TOP w0.102: R98.2 73.43,195.7 v1(72.4,196.72)
  TOP w0.508: R98.2 73.87,194.89 73.21,194.23 71.97,194.23 71.58,193.84 CN6.27
N195453329: length 6.5
  TOP w0.102: v2(80.2,230.76) 80.53,231.09 R28.1
  BOTTOM w0.102: v2(80.2,230.76) 80.91,230.05 U18.6 80.91,226.19 v1(81.5,225.6)
N195453367: length 5.5
  TOP w0.102: v2(79.03,230.73) 79.18,230.88 R22.1
  BOTTOM w0.102: v1(79.41,226.59) 79.64,226.82 U18.7 79.64,229.24 79.89,229.49 79.89,229.87 v2(79.03,230.73)
N195453377: length 6.2
  BOTTOM w0.102: R524.1 82.89,232.33 82.69,232.54 81.04,232.54 80.91,232.66 U18.3 v1(80.91,235.71)
N195454034: length 6.7
  TOP w0.508: v1(27.85,196.85) 28.72,196.85 R87.2 29.08,197.74 28.15,197.74 27.49,198.4 27.49,199.44 26.85,200.09 CN8.27
N195764479: length 7.5
  BOTTOM w0.102: U24.46 126.5,28.96 127.14,28.32 127.14,26.95 127.37,26.72 127.85,26.72 128.47,26.1 R747.1 128.82,26.08 129.12,25.78 129.12,24.38 v1(128.74,24)
N195806874: length 7.3
  TOP w0.102: R521.2 115.14,6.37 v1(115.14,5.78) 115.39,5.52 116.79,5.52 117.1,5.84 119.77,5.84 120.71,4.9 CN23.L2
N196390709: length 3.7
  TOP w0.102: v2(49.13,34.49) 49.13,34.46 48.51,33.83 U11.43
  BOTTOM w0.102: v2(49.13,34.49) 49.54,34.09 v1(49.54,33.66) 49.54,32.84 R726.2
N196851843: length 4
  TOP w0.254: v2(29.92,45.78) 29.27,45.14 C274.1
  BOTTOM w0.254: v2(29.92,45.78) 30.13,45.99 U23.12
N197768843: length 3.6
  TOP w0.254: C141.1 v2(108.47,103.69) 109.17,103.69 U7.6
  BOTTOM w0.305: v2(108.47,103.69) 109.28,103.69 v1(109.29,103.7) 109.3,103.69 110.27,103.69 R597.2
N198554672: length 8.2
  TOP w0.102: v3(88.02,74.09) 88.5,73.62 U10.F25
  BOTTOM w0.102: R643.1 83.12,75.18 v1(83.2,75.18) 84.21,74.17 87.95,74.17 v3(88.02,74.09)
N198880140: length 6.3
  BOTTOM w0.102: R692.2 165.01,54.33 v1(166.05,54.33) 167.17,53.21 169.43,53.21 169.87,52.77 Q60.B
N199565995: length 2.7
  BOTTOM w0.254: L59.1 R661.2 17.22,64.69 v1(16.37,63.84)
N199565999: length 2.5
  BOTTOM w0.254: L61.1 R666.2 15.58,61.1 v1(15.38,60.9)
N200059938: length 5.3
  TOP w0.102: v2(82.31,230.17) R26.2
  BOTTOM w0.102: v1(83.38,226.38) 82.18,227.58 U18.5 82.18,230.05 v2(82.31,230.17)
N200259909: length 2.3
  BOTTOM w0.254: v1(104.85,14.29) 104.79,14.22 R758.2 104.85,13.39 L80.1
N200335304: length 3.3
  BOTTOM w0.254: C538.2 103.45,16.1 103.8,15.75 R750.1 102.6,15.21 v1(102.5,15.11)
N200335513: length 3.9
  BOTTOM w0.254: v1(103.26,11.05) 103.07,11.24 C546.2 103.91,12.95 104.4,12.46 R758.1
N200484025: length 4.3
  BOTTOM w0.102: R560.1 6.16,162.16 v1(6.17,162.18) 6.16,162.19 6.16,162.89 5.55,163.5 S1.1
N201366209: length 10.6
  TOP w0.254: CN34.3 185.18,244.22 185.18,246.25 184.46,246.97 R6.2 184.46,248.07 D1.C v2(184.29,249.24)
  BOTTOM w0.254: v2(184.29,249.24) 183.72,248.67 v1(183.72,248.6)
N201366217: length 9.9
  TOP w0.102: R15.2 185.81,242.32 CN34.4
  BOTTOM w0.102: v1(185.18,246.25) 185.18,244.09 184.67,243.59 CN34.4
N201366253: length 12.3
  TOP w0.254: CN33.3 170.7,241.81 167.14,245.36 167.14,246.63 166.95,246.82 166.52,246.82 R3.2 166.51,248.16 165.87,248.79 D3.C 164.48,248.79 v2(164.16,248.48)
  BOTTOM w0.254: v2(164.16,248.48) v1(163.27,248.48)
N201366255: length 13
  TOP w0.102: v2(168.16,250.38) 168.98,250.38 170.25,249.11 170.25,247.97 170.95,247.27 170.95,246.13 170.78,245.95 R13.2 170.32,244.47 CN33.4
  BOTTOM w0.102: v1(167.59,250.95) v2(168.16,250.38)
N201793917: length 4.6
  TOP w0.102: v2(74.18,86.8) 73.69,87.29 CN26.5 73.69,90.61 R239.2
N203761921: length 1.6
  TOP w0.102: F2.2 76.4,11.24 v2(76.53,11.37)
N203766757:
  vias: v1(49.41,9.78)
N204331890: length 16.2
  TOP w0.254: v2(84.97,106.55) 85.61,105.92 PU7.8
  BOTTOM w0.508: v2(84.97,106.55) 85.74,105.79 PR84.2
  BOTTOM w0.762: v2(75.86,111.43) 76.8,110.49 83.45,110.49 84.97,108.97 v1(84.97,107.75) v2(84.97,106.55)
N204331892: length 5.1
  TOP w0.254: v1(70.69,104.65) 70.69,105.09 72.28,106.69 PC143.1
  TOP w0.508: PC143.1 72.73,106.62 PR81.2
N204331896: length 3
  TOP w0.254: PR48.1 91.02,103.94 v1(90.63,104.33) 90.46,104.5 90.46,105.13 90.17,105.42 PU7.2
N204331899: length 3.1
  TOP w0.254: PR46.1 91.58,108.81 v1(90.57,107.8) 90.36,107.59 90.36,107.16 90.16,106.96 89.67,106.96 PU7.5
N204331902: length 11.5
  TOP w0.102: PU7.3 90.56,105.92 v2(90.74,105.74)
  BOTTOM w0.102: Q55.D 98.31,103.12 97.42,104.01 94.12,104.01 v1(93.42,104.71) 92.39,105.74 v2(90.74,105.74) 90.23,105.74 90.05,105.92 R593.2
N204331904: length 15.2
  TOP w0.102: Q10.C 105.29,109.42 105.93,108.79 105.93,104.52 105.52,104.11 102.98,104.11 102.17,103.3 v2(101.79,103.3)
  BOTTOM w0.102: Q55.G 101.14,104.07 101.79,103.43 v2(101.79,103.3) 102.37,102.72 R594.2 103.66,102.03 v1(103.77,101.92)
N204331910: length 4.7
  TOP w0.102: R220.2 109.28,111.33 v1(108.79,111.82) 108.55,112.06 C150.1 106.9,112.06 106.24,112.72 Q10.B
N204331919: length 3.2
  TOP w0.254: PU7.10 86.39,104.92 85.99,104.52 85.99,103.89 v1(85.86,103.76) 86.25,103.37 PC69.1
N204331920: length 3.5
  TOP w0.508: v2(83.96,103.25) 83.96,102.87 84.47,102.36 PC69.2
  BOTTOM w0.508: PR84.1 84.32,103.61 v2(83.96,103.25)
N204331927:
  vias: v1(80.3,104.9) v2(80.72,105.6) v2(80.91,104.27) v2(81.65,105.11)
N204331931: length 3
  TOP w0.254: PU7.9 85.11,105.42 v1(84.97,105.47) 84.81,105.45 PR45.1
N204331932: length 11.9
  TOP w0.381: PR45.2 83.24,107.02 v2(82.18,108.08) ; v2(75.89,107.7) 76.58,107.7 PR40.1 77.05,107.23 PQ10.G1
  BOTTOM w0.381: v1(75.07,107.95) 75.32,107.7 v2(75.89,107.7) 76.27,108.08 v2(82.18,108.08)
N204331939: length 5.4
  TOP w0.254: PR42.2 91.64,107.05 PC67.1 91.48,107.26 v2(90.94,106.73) 90.94,106.68 90.69,106.43 89.64,106.43 PU7.4
  BOTTOM w0.254: v2(90.94,106.73) 91.48,107.26 PC67.1
N204332065: length 3.6
  TOP w0.102: R229.1 90.63,102.23 v1(90.82,102.43) 91.01,102.62 C148.1 91.78,101.68 91.51,101.41 Q16.B
N204332069: length 4.4
  TOP w0.102: Q15.G 95.19,101.15 v1(95.16,101.12) 95.01,100.97 R218.2 94.96,99.95 94.37,99.95 93.86,100.46 Q16.C
N204332072: length 6.3
  TOP w0.102: PU7.1 89.63,103.31 88.99,102.67 R229.2 ; R237.1 88.99,101.57 R229.2 ; v1(87.39,102.62) 88.61,102.62 R229.2
N205761409: length 4.3
  TOP w0.102: v1(103.37,98.82) 103.7,99.14 R219.1
  TOP w0.254: C164.1 106.01,98.63 Q14.B 105.16,98.64 R219.1
N205761415: length 34.4
  TOP w0.254: v2(96.3,109.03) 97.23,108.1 97.23,107.82 97.92,107.14 PU6.8
  TOP w0.508: v2(96.35,106.83) 96.25,106.93 96.25,108.98 v2(96.3,109.03)
  BOTTOM w0.508: v2(96.35,106.83) 97.06,106.12 PR83.2
  BOTTOM w0.635: v2(77.99,124.76) 78.47,124.28 PR80.1
  BOTTOM w0.762: v2(80.5,123.22) 81.14,122.58 81.14,121.31 88.48,113.97 91.27,113.97 v1(95.45,109.79) 96.21,109.03 v2(96.3,109.03) ; v2(79.54,122.38) 79.88,122.03 PR79.2
N205761421: length 1.7
  BOTTOM w0.508: PC141.1 83.81,114.07 v1(83.89,113.98)
  vias: v2(80.66,114.38) v2(81.11,113.61) v2(81.21,114.96)
N205761425: length 12.7
  TOP w0.254: Q12.G 112.26,96.92 111.44,97.74 111.44,98.79 v1(111.45,98.81) 109.74,98.81 107.54,101 Q14.C 106.94,101.47 106.67,101.75 106.06,101.75 105.85,101.55 R221.2
N205761490: length 11.2
  TOP w0.254: v2(102.25,105.03) 102.25,105.92 102.03,106.14 PU6.1 ; R219.2 v2(106.1,100)
  TOP w0.305: v2(102.25,105.03) 101.91,104.7 R217.1
  BOTTOM w0.254: v2(102.25,105.03) 102.88,104.39 102.88,103.12 103.33,102.68 104.09,102.68 105.42,101.35 v1(105.42,100.58) 106.01,100 v2(106.1,100)
N205761590: length 3.3
  BOTTOM w0.254: PC137.1 78.28,117.88 v1(78.31,117.86)
  BOTTOM w0.635: PC137.1 78.47,119.42 PR80.2
N205761596: length 2.8
  TOP w0.254: PR47.1 102.94,105.66 v1(102.88,105.73) 102.65,105.96 102.65,106.32 102.34,106.64 PU6.2
N205761604: length 4.3
  TOP w0.254: v2(102.98,106.88) 102.73,107.14 PU6.3
  BOTTOM w0.254: v2(102.98,106.88) 102.99,106.89 R592.2 104.15,105.69 104.3,105.54 Q54.D
N205761606: length 4
  BOTTOM w0.102: v1(109.66,107.09) 109.51,107.24 R598.2
  BOTTOM w0.254: Q54.G 106.98,107.57 Q53.C 108.05,107.66 R598.2
N205761614: length 3.6
  TOP w0.254: PU6.5 101.67,109.93 PR39.1 101.24,111.24 v1(101.04,111.44)
N205761624: length 4.7
  BOTTOM w0.102: R595.2 105.6,111.87 v1(106.12,112.39)
  BOTTOM w0.254: C441.1 105.83,109.3 106.12,109.59 Q53.B 106.12,110.98 R595.2
N205761636: length 4.5
  TOP w0.508: v2(94.5,104.52) 95.34,103.68 PC68.2
  BOTTOM w0.254: v1(94.18,106.49) 94.37,106.49 95.39,105.47 95.39,105.28
  BOTTOM w0.508: v2(94.5,104.52) 94.63,104.52 95.39,105.28 PR83.1
N205761638: length 3.4
  TOP w0.254: PC68.1 97.78,104.61 v1(97.8,104.65) 97.78,104.67 97.78,105.54 98.37,106.14 PU6.10
N205761660: length 23.6
  TOP w0.508: v2(94.56,109.28) 94.81,109.04 PR44.2
  TOP w0.635: v2(82.59,116.15) 82.37,116.37 PQ9.G2
  BOTTOM w0.508: PR79.1 82.59,117.84 v2(82.59,116.15)
  BOTTOM w0.762: v2(94.56,109.28) 90.87,112.98 89.81,112.98 v1(89.8,112.97) 89.79,112.98 87.95,112.98 84.77,116.15 v2(82.59,116.15)
N205761662: length 2.8
  TOP w0.254: PU6.9 97.46,106.64 v1(97.42,106.68) 97.37,106.68 PR44.1
N205761686: length 5.9
  TOP w0.254: PR43.1 103.59,108.97 PC64.1 103.98,107.53 PR41.2 103.69,107.64 103,107.64 v1(102.69,107.95) 102.69,107.95 102.37,107.64 PU6.4
N205761688: length 31.8
  TOP w0.254: v2(98.71,109.22) PU6.6
  TOP w0.635: PQ9.G3 v2(76.7,116.34)
  BOTTOM w0.762: v2(76.7,116.34) 75.77,116.34 75.32,115.89 75.32,114.94 77.86,112.39 84.24,112.39 v1(86.19,110.44) 87.16,109.47 90.69,109.47 91.7,108.46 93.36,108.46 94.17,107.65 97.12,107.65 98.69,109.22 v2(98.71,109.22)
N206167081: length 6.5
  TOP w0.102: v2(12.2,27.18) 9.88,27.18 LED3.A
  BOTTOM w0.102: R742.1 v2(12.2,27.18) 12.2,27.62 v1(12.52,27.94)
N206210192: length 14.7
  TOP w0.102: U10.A8 84.27,60.92 83.05,59.7 82.75,59.7 v1(81.74,58.67) 81.53,58.48 79.04,58.48 78.59,58.03 76.64,58.03 76.56,57.95 76.12,57.95 75.53,57.35 75.25,57.35 74.58,56.69 72.7,56.69 72.53,56.52 R335.1
N207033685: length 4.2
  TOP w0.102: R334.2 42.43,50.37 43.01,49.78 v1(44.23,49.78) 44.2,49.82 LED2.A
N208253507: length 2.6
  TOP w0.254: v2(20.2,49.85) 20.38,49.67 C270.1
  BOTTOM w0.254: v2(20.2,49.85) 20.53,50.17 U23.30
N208253520: length 2.9
  TOP w0.254: C270.2 21.49,48.38 22.49,49.38 v5(22.57,49.38)
  BOTTOM w0.254: U23.29 22.27,49.67 v5(22.57,49.38)
N208262425: length 5.1
  TOP w0.254: C252.2 18.1,50.54 v2(18.87,51.24)
  BOTTOM w0.254: v2(18.87,51.24) 19.38,50.74 20.5,50.74 20.57,50.67 U23.31
N208289349: length 2.8
  BOTTOM w0.254: L74.1 R750.2 104.66,15.75 v1(105.29,16.38)
N208402932: length 3.7
  TOP w0.254: Q34.A2 18.61,46.29 18.43,46.1 v2(17.79,46.1)
  BOTTOM w0.254: R713.1 18.47,45.74 18.11,46.1 v2(17.79,46.1) 17.16,46.1 v1(16.71,45.66)
N208403148: length 8.2
  TOP w0.254: v2(18.55,47.88) 17.79,47.88 16.71,46.8 Q34.A1
  BOTTOM w0.254: v1(18.17,53.02) 18.17,52.01 17.73,51.56 R691.1 17.71,51.45 18.55,50.61 v2(18.55,47.88)
N208745696: length 13.3
  TOP w0.254: 190,243.71 187.84,245.87 187.15,245.87 186.51,246.51 186.51,249.16 186.7,249.35 R1.2 187.21,252.06 D2.C v2(185.75,252.22)
  BOTTOM w0.254: v2(185.75,252.22) v1(184.73,252.22)
N208745698: length 8.8
  TOP w0.102: CN35.4 188.43,247.83 R9.2 188.03,248.41 187.78,248.67 187.78,251.71 188.1,252.03 188.1,252.48 v2(188.42,252.79)
  BOTTOM w0.102: v2(188.42,252.79) v1(187.59,252.79)
N208938368: length 4
  BOTTOM w0.254: v1(18.36,42.55) 18.11,42.8 18.11,43.75 18.47,44.12 R695.2 18.93,44.2 19.42,43.71 C502.2
N208939242: length 3.3
  BOTTOM w0.254: v1(16.01,48.51) 16.29,48.79 C506.2 17.71,49.09 R680.2
N209450511: length 1.6
  TOP w0.254: R209.2 49.23,194.81 49.23,194.87 48.4,195.71 v1(48.33,195.71)
N209450591: length 5.8
  TOP w0.508: CN7.37 47.99,191.79 v2(48.27,191.52)
  BOTTOM w0.254: v1(51.04,190.42) 50.84,190.63 R531.2
  BOTTOM w0.508: v2(48.27,191.52) 49.16,191.52 49.54,191.9 C349.1 50.13,190.7 R531.2
N210544606: length 5.1
  TOP w0.508: CN9.37 27,179.73 27.15,179.58 v2(27.7,179.58)
  BOTTOM w0.508: R535.2 25.63,180.29 C350.1 v1(26.68,179.26) 27.38,179.26 v2(27.7,179.58)
N211359803: length 2.6
  TOP w0.203: Q48.G 137.06,30.54 R475.2 136.03,30.4 v1(135.8,30.18)
N211486769: length 7.5
  TOP w0.254: v1(130.36,42.41) 129.67,43.11 R356.2 129.25,44.74 Q36.D 126.64,44.74 125.54,43.64 R387.1
N212412188: length 5.7
  BOTTOM w0.508: Q57.D 78.81,89.41 Q56.G 77.28,90.95 C445.1 77.28,91.81 v1(77.93,92.46) 78.69,91.69 R610.2
N212418796: length 3.6
  BOTTOM w0.254: R602.2 82.31,92.15 82.73,92.15 v1(83.16,91.72)
  BOTTOM w0.508: R602.2 82.38,91.16 82.38,90.65 82.09,90.36 Q57.G
N214468883: length 2.4
  TOP w0.102: Q44.D R470.1 18.38,28.56 v1(18.3,28.64)
N214468911: length 3.3
  TOP w0.102: Q42.D v1(23.44,33.4) 23.12,33.4 22.62,33.91 R456.2
N214468913: length 6.1
  TOP w0.102: Q42.G 27.35,32.93 27.57,33.15 Q43.D 28.87,33.57 28.71,33.72 28.29,33.72 28.15,33.86 28.15,34.87 v1(28.52,35.24) 28.79,35.51 R416.2
N214468931: length 3
  TOP w0.102: R447.2 32.11,31.95 31.86,32.2 Q43.G 29.99,32.2 v2(29.67,31.88)
N214485400: length 10.7
  TOP w0.102: R411.2 16.59,38.3 16.77,38.48 20.08,38.48 20.84,37.72 22.24,37.72 v1(22.43,37.53) 22.73,37.53 R415.1 23.55,36.15 23.63,36.07 C284.1 24.56,35.48 R418.2
N214797167: length 4.6
  TOP w0.102: v1(160.86,73.15) Q18.D 159.69,72.1 159.47,71.88 R298.2 R280.1
N214902487: length 4.4
  TOP w0.102: Q19.D 165.53,73.24 v1(166.12,73.83) 166.49,73.45 R300.1 R291.2
N214902576: length 4
  TOP w0.102: v1(181.05,60.01) 180.4,60.66 R330.2 ; R330.2 180.1,59.35 Q22.D ; R330.2 180.08,60.64 R297.1
N215117175: length 6
  BOTTOM w0.254: v1(22.24,23.75) 22.62,23.5 23.81,23.5 R757.2 24.19,23.87 C547.2 C532.1 24.25,25.84 25.27,25.84 R743.2
N215339663: length 6.4
  BOTTOM w0.102: v1(188.68,39.24) 188.3,39.62 R725.1 187.51,40.97 187.34,41.15 Q64.D
N215339673: length 3.7
  BOTTOM w0.102: v1(189.69,41.02) 189.69,41.72 189.62,41.79 R705.2 ; R705.2 189.61,42.25 Q64.G ; R705.2 R704.2
N215401845: length 17.4
  TOP w0.102: S3.4 8.79,14.63 14.15,14.63 S3.3
  BOTTOM w0.102: v1(13.92,16.95) 14.69,16.18 S3.3 ; S3.4 8.25,13.57 6.93,12.26 6.93,8.83 6.17,8.06 R768.1
N215440771: length 88.9
  TOP w0.102: v2(19.31,17.53) 16.77,14.99 v2(16.77,8.76) ; v2(36.4,34.04) 35.51,33.15 33.28,33.15 33.25,33.12 32.81,33.12 32.78,33.15 32.33,33.15 32.08,33.4 32.08,34.8 32.46,35.18 34.92,35.18 R435.2 ; v2(39.51,44.83) 39.89,44.45 R358.2
  BOTTOM w0.102: v2(16.77,8.76) v1(16.77,4.95) 16.77,3.81 16.1,3.14 Q66.G ; v2(19.31,17.53) 22.65,14.2 28.17,14.2 30.1,16.13 32.4,16.13 34.94,13.59 40.45,13.59 41.54,14.68 41.54,16.23 40.2,17.56 38.25,17.56 37.58,18.24 37.58,18.98 37.73,19.13 37.73,21.87 36.59,23.01 36.59,31.83 36.95,32.19 36.95,33.48 v2(36.4,34.04) 37.16,34.8 37.16,38.35 37.61,38.8 37.61,43.77 38.67,44.83 v2(39.51,44.83)
N216543933: length 2.5
  TOP w0.102: R485.2 143.27,25.22 v1(143.14,25.1) 142.99,24.94 U16.19
N218750210: length 9.4
  INT1 w0.089: v2(6.17,159.13) 6.17,157.91 6.75,157.33 6.75,152.57 S2.1
  BOTTOM w0.102: R563.1 6.16,159.15 v2(6.17,159.13)
N218776850: length 9.5
  BOTTOM w0.102: C510.1 185.76,46.31 185.36,45.91 Q63.G 185.36,44.51 184.72,43.86 R716.1 184.72,42.37 184.73,42.35 v1(184.73,41.59) 184.73,40.45 185.56,39.62 R725.2
N219210322: length 12.7
  TOP w0.102: Q27.B 38.14,46.71 38.75,46.1 v1(38.75,45.72) 38.75,44.85 39.51,44.08 39.51,43.56 39.7,43.37 R361.1 39.06,42.21 38.54,42.21 38.11,41.78 38.11,41.27 37.63,40.79 36.17,40.79 35.32,39.94 R432.2
N219249647: length 31.5
  TOP w0.102: R376.1 31.89,44.83 v2(32.21,45.15) ; Q27.C 35.6,44.35 v2(35,43.75)
  INT1 w0.089: v2(32.21,45.15) 33.6,43.75 v2(35,43.75)
  BOTTOM w0.102: R745.2 28.08,23.67 28.08,24.23 28.4,24.55 28.4,32.75 30.3,34.66 30.3,39.13 v1(29.53,39.9) 29.54,39.92 29.54,42.15 32.21,44.82 v2(32.21,45.15)
N220111595: length 16.9
  TOP w0.102: EC2.2 62.11,43.77 62.11,38.77 Q40.D 59.99,37.63 59.51,37.15 59.51,34.35 58.37,33.21 v1(58.37,31.88)
N220115319: length 6.2
  TOP w0.102: R410.2 62.62,37.72 61.35,36.45 60.46,36.45 60.02,36.01 Q40.G 60.02,34.99 60.59,34.42 v1(60.97,34.42)
N220126171: length 2.7
  BOTTOM w0.102: v1(6.87,3.43) 7.07,3.23 R770.1 8.75,3.23 8.84,3.14 Q67.S
N221267533: length 12
  TOP w0.102: v2(102.12,114.05) 101.79,114.38 R205.1
  BOTTOM w0.102: v2(102.12,114.05) v1(102.12,113.16) 100.98,113.16 100.72,112.9 99.45,112.9 98.56,113.79 97.29,113.79 96.15,114.94 96.15,115.95 96.4,116.2 97.42,116.2 97.71,115.91 Q51.D
N222009354: length 35.4
  TOP w0.102: R377.1 32.95,43.86 34.25,45.16 R362.2 ; R362.2 34.3,43.03 Q33.B ; R362.2 34.32,45.15 35.44,45.15 36.4,46.1 36.4,47.69 37.09,48.39 42.56,48.39 v2(42.94,48.01) 42.73,47.8 R378.2
  INT1 w0.089: EC2.1 57.08,48.3 55.7,46.93 53.86,46.93 53.35,47.43 51.57,47.43 49.73,49.28 44.21,49.28 v2(42.94,48.01)
N222009357: length 4.4
  TOP w0.102: v1(33.16,45.85) 33.16,45.09 32.4,44.32 32.4,43.43 31.97,43 ; 31.97,43 R377.2 ; 31.97,43 R376.2
N222245952: length 4.2
  TOP w0.102: v1(12.23,26.26) 12.43,26.46 R1017.1 R744.2 14.09,27.89 Q44.G
N222245969: length 3.1
  TOP w0.102: v1(13.37,24.05) 14.38,25.07 R753.2 14.43,25.63 14.7,25.91 Q44.S
N222289486: length 16.6
  TOP w0.102: v2(32.78,41.91) 32.57,41.7 R414.2
  INT1 w0.089: v2(28.04,53.63) 28.2,53.47 29.6,53.47 30.74,52.32 30.74,45.85 32.78,43.81 v2(32.78,41.91)
  BOTTOM w0.102: U23.47 v2(28.04,53.63)
N222354100: length 2.5
  TOP w0.254: L14.2 17.6,130.62 v1(17.85,130.87) 17.88,130.85 U5.4
N224524412: length 3.5
  TOP w0.254: v2(22.49,25.84) 22.35,25.99 R774.1
  BOTTOM w0.254: C532.2 23.27,25.84 v2(22.49,25.84) 21.54,25.84 v1(20.97,25.27)
N224651695: length 28.1
  TOP w0.102: R989.2 21.6,34.54 22.49,33.66 22.49,31.75 22.11,31.37 18.04,31.37 17.28,32.13 v3(14.62,32.13)
  BOTTOM w0.102: v3(14.62,32.13) 13.78,31.29 v1(13.75,31.29) 13.75,30.76 11.35,28.35 11.35,26.58 8.77,24 7.69,24 6.74,23.05 6.74,21.44 7.06,21.12 Q65.D
N224726667: length 3
  BOTTOM w0.254: PC153.1 v1(191.15,22.15)
  BOTTOM w0.508: PR86.2 190.2,20.97 PC153.1
N224816065: length 19.1
  TOP w0.254: PU7.6 86.19,106.92 86.07,107.05 86.07,107.34 v2(86.45,107.72)
  TOP w0.381: v2(75.45,113.41) 75.96,113.92 PQ15.G1 ; PQ14.G1 83.62,112.61 83.89,112.34 v2(83.89,111.41)
  BOTTOM w0.762: v2(86.45,107.72) 86.45,108.85 v2(83.89,111.41) 77.54,111.41 v1(77.53,111.4) 77.46,111.4 v2(75.45,113.41)
N225179532: length 1.7
  BOTTOM w0.102: R718.2 v1(44.59,37.66) C1457.1
N225179536: length 4.1
  BOTTOM w0.102: C1458.1 R717.2 43.75,36.31 43.06,35.62 43.06,34.99 v1(42.62,34.54)
N225179540: length 2
  BOTTOM w0.102: C1459.1 v1(47.25,35.43) 46.35,35.43 R715.2
N225179544: length 3.5
  BOTTOM w0.102: v1(40.27,31.43) 41.33,32.5 C1460.1 R722.2
N228109207: length 4.7
  TOP w0.102: Q609.2 C557.1 R424.2 79.45,200.41 v1(79.07,200.03)
N228109241: length 1.5
  TOP w0.254: v1(76.15,199.77) 75.93,199.99 Q609.6
N228109265: length 2.5
  TOP w0.102: v1(81.1,205.1) 80.99,205.22 R736.2 80.93,206.31 Q70.S
N228231724: length 4.9
  BOTTOM w0.102: R74.2 101.23,120.14 v1(101.29,120.08) ; R74.2 100.01,119.57 99.88,119.44 99.88,118.5 100.17,118.21 Q608.G ; R74.2 R772.2
N228265287: length 252.3
  TOP w0.102: v2(94.63,122.49) 93.67,122.49 91.39,124.78 91.39,129.16 90.18,130.37 87.32,130.37 87.01,130.68 87.01,131.51 86.58,131.93 85.03,131.93 84.13,131.03 83.2,131.03 83.09,130.93 82.2,130.93 81.05,132.07 81.05,134.34 79.34,136.05 64.65,136.05 63.34,134.74 v2(63.34,133.05) ; v2(45.32,111.81) 45.27,111.81 45.01,112.07 45.01,112.95 44.81,113.15 41.85,113.15 40,115 36.63,115 36.26,114.63 24.65,114.63 v2(24.27,115.01) ; R73.2 44.16,205.82 43.57,205.23 35.89,205.23 33.34,207.78 29.43,207.78 27.5,205.85 16.6,205.85 15.47,204.72 15.47,201.96 14.9,201.38 14.9,182.08 13.47,180.66 9.79,180.66 8.44,179.31 8.44,178.58 8.92,178.11 12.37,178.11 12.66,177.81 12.66,161.47 13.83,160.3 16.8,160.3 18.3,158.8 20.18,158.8 21.22,157.76 21.22,155.62 20.66,155.06 16.56,155.06 v2(15.7,155.91)
  INT1 w0.089: v2(45.32,111.81) 46.92,111.81 56.86,121.75 58,121.75 58.91,122.66 60.14,122.66 v2(60.66,123.17)
  BOTTOM w0.102: v2(63.34,133.05) 63.34,129.16 63.07,128.88 63.07,124.89 61.35,123.17 v2(60.66,123.17) ; v1(95.39,121.73) v2(94.63,122.49) ; v1(95.39,121.73) 95.96,122.3 R589.1 ; v1(95.39,121.73) 95.39,120.4 96.4,119.38 96.91,119.38 97.23,119.06 Q51.G ; v2(15.7,155.91) 15.7,155.64 16.63,154.71 16.63,129.68 20.12,126.19 20.12,123.24 23,120.36 23,116.29 v2(24.27,115.01)
N229157893: length 6.5
  TOP w0.254: R194.2 190.21,130.38 190.54,130.71 v1(190.54,131.09) 190.54,131.27 189.24,132.56 189.24,134.14 188.95,134.43 Q9.B
N229157940: length 5.8
  TOP w0.254: Q8.B 188.2,142.54 188.96,142.54 189.22,142.29 189.22,141.54 190.05,140.71 R159.2 190.78,139.32 191.2,138.89 v1(191.2,138.88)
N229158005: length 7.3
  TOP w0.102: v1(105.5,40.16) 105.5,40.16 R375.2 107.12,42.19 106.61,42.7 106.61,44.63 107.62,45.63 Q29.B

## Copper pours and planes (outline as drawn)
AVDD33_LAN on BOTTOM (solid shape): 117.54,24.98 117.54,24.6 116.31,23.38 115.57,24.12 115.57,24.99 117.53,24.99
AVDD33_LAN on TOP: 119.71,27.05 119.71,26.54 119.96,26.29 125.74,26.29 126.76,27.3 126.76,28.19 126.5,28.45 126.5,29.46 126.95,29.91 127.46,29.91 127.77,30.23 127.77,30.8 127.58,30.99 127.46,30.99 127.07,30.61 126.5,30.61 126.19,30.92 126.19,31.88 127.14,32.83 127.14,33.53 126.82,33.85 126.82,35.18 126.38,35.62 125.61,35.62 125.49,35.5 125.49,34.99 125.3,34.8 121.38,34.8 121.09,35.09 121.09,36.99 121.51,37.42 126.18,37.42 126.51,37.75 126.51,39.01 125.96,39.55 121,39.55 119.94,38.5 119.94,34.31 121.11,33.15 124.98,33.15 125.19,32.94 125.19,27.84 125.04,27.69 120.34,27.69
AVDD33_LAN on BOTTOM: 124.53,37.15 124.53,37.91 124.47,37.97 124.47,38.99 124.98,39.5 124.98,40.39 125.36,40.77 128.53,40.77 129.8,39.5 129.8,38.04 129.68,37.91 128.22,37.91 127.84,38.29 127.84,39.18 127.65,39.37 126.88,39.37 126.5,38.99 126.5,38.8 126.31,38.61 125.36,38.61 125.11,38.35 125.11,37.15 125.04,37.08 124.6,37.08
AVDD33_REG on BOTTOM (solid shape): 129.55,36.51 129.36,36.32 127.52,36.32 127.26,36.07 126.69,36.07 126.31,35.69 126.31,35.18 125.04,33.91 124.19,33.91 124.19,34.16 124.37,34.34 124.37,34.85 124.66,35.14 124.66,35.5 125.61,36.45 125.61,36.83 126.31,36.83 126.76,37.27 129.55,37.27
GND on TOP (solid shape): 89.22,128.04 89.22,125.48 88.61,124.87 86.8,124.87 86.04,125.63 86.04,128.04 86.62,128.63 88.63,128.63
GND on TOP (solid shape): 120.26,239.31 120.26,235.25 119.67,234.67 115.47,234.67 115.03,235.11 115.03,239.48 115.43,239.87 119.7,239.87
GND on TOP (solid shape): 137.11,223.01 137.11,222.44 136.85,222.19 133.68,222.19 133.55,222.31 133.55,222.95 133.81,223.2 136.92,223.2
GND on TOP (solid shape): 143.98,39.27 143.98,37.77 143.31,37.1 139.01,37.1 138.28,37.84 138.28,39.07 138.95,39.74 143.51,39.74
GND on TOP (solid shape): 190.29,15.63 190.29,12.81 189.21,11.73 186.23,11.73 185.94,12.02 185.94,12.65 186.5,13.22 186.5,15.42 186.79,15.71 190.21,15.71
GND on TOP (solid shape): 122.76,225.66 122.76,221.09 122.34,220.67 118.23,220.67 118.18,220.71 118.18,222.25 119.39,223.46 119.39,225.19 120.11,225.91 122.5,225.91
GND on TOP (solid shape): 150.89,49.91 150.89,48.9 150.38,48.39 150.12,48.39 149.24,49.28 145.3,49.28 144.54,50.04 144.54,50.55 144.79,50.8 150,50.8
GND on TOP (solid shape): 124.98,23.5 124.98,22.61 124.72,22.35 123.81,22.35 123.58,22.12 123.58,20.89 123.56,20.87 123.08,20.87 123.08,22.17 122.89,22.35 122.57,22.35 122.06,22.86 122.06,23.5 122.18,23.62 124.85,23.62
GND on TOP (solid shape): 162.34,237.67 162.34,237.19 161.78,236.63 161.78,233.38 161.02,232.61 160.06,232.61 159.85,232.82 159.85,233.02 160.31,233.48 160.31,236.93 159.8,237.44 159.8,237.72 159.98,237.9 162.11,237.9
GND on TOP (solid shape): 145.42,214.52 145.42,214.24 116.45,185.27 116.45,184.86 115.71,184.12 114.44,184.12 113.94,184.63 113.94,184.97 113.93,184.98 113.93,186.18 114.38,186.63 115.64,186.63 143.04,214.03 143.04,214.41 143.29,214.66 143.67,214.66 143.68,214.67 145.27,214.67
GND on TOP (solid shape): 180.22,15.88 180.22,14.48 180.86,13.84 183.53,13.84 183.91,13.46 183.91,13.21 184.22,12.89 184.22,11.91 183.97,11.65 180.83,11.65 178.76,13.72 178.64,13.72 177.94,14.41 173.81,14.41 173.62,14.61 173.62,14.99 173.87,15.24 173.87,15.88 174.51,16.51 179.59,16.51
GND on TOP (solid shape): 171.71,38.99 171.71,35.05 170.95,34.29 170.95,31.37 171.59,30.73 173.24,30.73 174,29.97 174,29.08 174.25,28.83 175.78,28.83 176.03,28.57 176.03,26.67 175.78,26.42 173.37,26.42 173.11,26.67 173.11,28.45 172.37,29.19 169.32,29.19 169.17,29.34 169.17,30.73 166.76,33.15 166.76,38.73 167.52,39.5 171.21,39.5
GND on TOP (solid shape): 42.81,104.27 42.81,101.98 44.14,100.65 44.14,96.71 43.06,95.63 43.06,94.61 42.17,93.73 41.22,93.73 41.16,93.79 41.16,95.38 40.71,95.82 40.71,96.01 40.78,96.08 42.24,96.08 42.81,96.65 42.81,98.36 42.37,98.81 38.56,98.81 38.24,98.49 38.24,96.39 38.11,96.27 37.22,96.27 36.71,95.76 36.71,94.36 36.84,94.23 39.51,94.23 39.63,94.11 39.63,93.79 39.51,93.66 33.16,93.66 33.16,94.3 35.25,94.3 35.57,94.61 35.57,98.81 35.32,99.06 34.81,99.06 34.36,98.62 34.36,98.42 34.3,98.36 33.73,98.36 33.35,98.74 31.82,98.74 31.57,98.49 31.57,97.85 30.81,97.09 27.76,97.09 26.78,98.08 26.78,100.68 26.36,101.09 26.36,102.23 32.4,102.23 32.9,101.73 35,101.73 35.51,102.23 36.02,102.23 36.02,101.66 36.46,101.22 40.08,101.22 40.52,101.66 40.52,104.01 39.89,104.65 39.89,104.84 40.33,105.28 41.79,105.28
GND on TOP (solid shape): 114.97,64.7 114.96,64.69 113.94,63.49 115.51,63.63 115.71,63.87 115.71,66.55 118.7,66.55 118.7,64.05 118.88,63.84 120.49,63.36 119.53,64.74 119.49,64.78 119.49,66.55 120.53,66.55 123.2,63.88 120.53,61.21 113.93,61.21 111.26,63.88 113.93,66.55 114.97,66.55
GND on TOP (solid shape): outline of 246 points within 27.8,245 35.8,253
GND on TOP (solid shape): outline of 246 points within 27.8,68.32 35.8,76.32
GND on TOP (solid shape): outline of 246 points within 27.8,0 35.8,8
GND on TOP (solid shape): outline of 246 points within 98,202.91 106,210.91
GND on TOP (solid shape): outline of 246 points within 154.18,240.01 162.18,248.01
GND on TOP (solid shape): outline of 246 points within 173.55,245 181.55,253
GND on TOP (solid shape): outline of 246 points within 173.55,68.32 181.55,76.32
GND on TOP (solid shape): outline of 246 points within 173.55,0 181.55,8
GND on TOP (solid shape): outline of 250 points within 102.25,245 110.25,253
GND on TOP (solid shape): outline of 250 points within 102.25,19.7 110.25,27.7
GND on BOTTOM (solid shape): 111.44,105.92 111.44,104.57 111.09,104.22 109.43,104.22 109.03,104.62 109.03,106.02 109.43,106.43 110.93,106.43
GND on BOTTOM (solid shape): 114.72,181.41 114.72,179.91 114.44,179.63 113.75,179.63 113.35,180.03 113.35,181.41 113.52,181.58 114.54,181.58
GND on BOTTOM (solid shape): 120.02,239.54 120.02,235.02 119.67,234.67 115.47,234.67 115.03,235.11 115.03,239.48 115.43,239.87 119.7,239.87
GND on BOTTOM (solid shape): 139.71,237.79 139.71,234.19 138.95,233.43 137.25,233.43 136.33,234.34 136.33,238.48 136.51,238.66 138.85,238.66
GND on BOTTOM (solid shape): 155.08,231.24 155.08,229.26 154.77,228.96 152.79,228.96 152.49,229.26 152.49,231.39 152.64,231.55 154.77,231.55
GND on BOTTOM (solid shape): 170.32,12.32 170.32,9.27 170.06,9.02 167.78,9.02 167.27,9.53 167.27,12.32 167.52,12.57 170.06,12.57
GND on BOTTOM (solid shape): 89.47,107.38 89.47,103.71 89.01,103.25 87.54,103.25 87.31,103.48 87.31,107.3 87.67,107.66 89.18,107.66
GND on BOTTOM (solid shape): 98.99,63.5 98.99,62.48 98.38,61.87 97.34,61.87 97.17,62.04 97.17,63.31 97.48,63.63 97.48,64.57 97.93,64.57
GND on BOTTOM (solid shape): 126.58,45.9 126.58,44.96 125.99,44.37 122.01,44.37 121.7,44.68 121.7,45.9 122.46,46.66 125.82,46.66
GND on BOTTOM (solid shape): 190.64,17.65 190.64,12.83 189.49,11.68 186.19,11.68 185.94,11.94 185.94,12.57 186.32,12.95 186.32,18.8 186.7,19.18 189.11,19.18
GND on BOTTOM (solid shape): 122.82,226.5 122.82,216.53 122.57,216.28 121.17,216.28 120.85,216.6 120.85,220.85 120.66,221.04 119.39,221.04 119.14,221.3 119.14,226.27 119.15,226.27 119.75,226.87 122.45,226.87
GND on BOTTOM (solid shape): 145.3,49.02 145.3,47.75 145.07,47.52 142,47.52 142,47.52 140.71,47.52 137.65,44.46 132.99,44.46 131.66,45.8 131.66,47.38 135.05,50.77 143.55,50.77
GND on BOTTOM (solid shape): 175.52,230.63 175.52,229.36 175.14,228.98 172.86,228.98 172.6,228.73 172.6,227.33 172.35,227.08 165.11,227.08 164.09,228.09 164.09,230.25 164.86,231.01 175.14,231.01
GND on BOTTOM (solid shape): 69.95,68.02 70.8,68.02 70.88,67.94 70.88,67.69 70.75,67.56 70.43,67.56 69.61,66.74 66.03,66.74 65.52,67.25 65.52,67.91 65.63,68.02 66.64,68.02 67.15,68.53 69.44,68.53
GND on BOTTOM (solid shape): 162.19,237.74 162.19,237.24 161.78,236.83 161.78,233.38 161.02,232.61 160.06,232.61 159.85,232.82 159.85,233.02 160.31,233.48 160.31,236.96 159.9,237.36 159.9,237.74 160.16,238 161.94,238
GND on BOTTOM (solid shape): 79.93,116.57 79.93,115.49 80.15,115.28 80.15,113.36 79.96,113.17 78.93,113.17 78.65,113.45 78.65,114.99 78.64,115 78.64,115.38 78.09,115.93 78.09,116.56 78.32,116.79 79.72,116.79
GND on BOTTOM (solid shape): 105.4,200.28 105.4,191.52 105.1,191.21 104.89,191.21 104.88,191.2 103.9,191.2 103.39,191.71 103.39,196.15 103.07,196.47 101.86,196.47 101.67,196.66 101.67,199.58 102.75,200.66 105.02,200.66
GND on BOTTOM (solid shape): 180.86,13.84 183.53,13.84 183.91,13.46 183.91,12.97 184.09,12.79 184.09,11.93 183.81,11.65 180.83,11.65 178.76,13.72 178.64,13.72 177.81,14.54 177.81,14.73 178.19,15.11 179.59,15.11
GND on BOTTOM (solid shape): 151.27,43.07 151.27,39.2 149.41,37.34 143.55,37.34 141.6,37.34 136.58,32.32 136.15,32.32 135.98,32.49 135.98,33.34 137.17,34.52 137.17,39.88 137.93,40.64 140.6,40.64 141.36,39.88 144.98,39.88 145.68,40.58 145.68,41.47 144.98,42.16 144.98,44.02 145.62,44.65 149.68,44.65
GND on BOTTOM (solid shape): 25.66,104.52 25.66,103.82 26.24,103.25 27,103.25 27.63,103.89 29.22,103.89 29.22,103.44 29.67,103 32.52,103 33.09,103.57 33.09,103.95 33.16,104.01 33.6,104.01 33.86,103.76 34.68,103.76 35.51,102.93 35.76,102.93 36.14,102.55 36.14,100.65 34.43,98.93 34.43,98.49 34.17,98.23 33.92,98.23 33.28,98.87 31.63,98.87 31,98.23 27.32,98.23 25.16,100.39 25.16,102.85 24.38,103.63 24.38,104.5 24.65,104.78 25.41,104.78
GND on BOTTOM (solid shape): 30.64,143.1 30.68,143.06 33.11,140.63 33.54,140.2 33.54,135.85 34.43,134.96 34.45,134.91 34.48,134.86 34.4,134.67 34.38,134.47 34.38,134.45 33.49,133.57 33.39,133.54 33.32,133.62 32.77,134.25 31.95,134.05 31.93,134.04 31.16,134.04 31.15,134.07 31.07,134.27 30.94,134.43 29.3,136.07 28.03,136.07 26.2,137.9 26.2,141.33 25.79,141.73 25.79,142.18 26.2,142.58 26.2,142.96 26.39,143.16 30.59,143.16
GND on BOTTOM (solid shape): 43.96,214.53 44.53,213.96 44.55,213.85 44.47,213.78 44.32,213.75 44.17,213.68 43.55,213.72 43.09,213.31 42.8,213.33 42.53,213.26 42.14,213.35 41.75,213.25 41.71,213.23 41.6,213.35 41.33,213.53 41.02,213.59 40.92,213.59 40.83,213.65 40.85,213.76 41.65,214.56 43.96,214.56
GND on BOTTOM (solid shape): 34.54,224.73 34.8,224.55 35.12,224.49 35.7,224.49 35.78,224.45 36.02,223.77 36.62,223.51 37.29,223.51 37.43,223.65 37.46,223.63 38.33,223.64 38.69,224.43 38.69,224.49 38.82,224.49 38.82,224.42 38.98,223.74 39.62,223.44 40.26,223.44 40.41,223.59 40.44,223.57 40.6,223.49 40.77,223.44 40.81,223.44 40.81,222.64 40.55,222.64 40.24,222.58 39.98,222.4 39.62,222.04 39.46,221.82 39.39,221.57 39.13,221.49 38.92,221.34 38.56,220.98 38.4,220.76 38.33,220.51 38.07,220.43 37.86,220.28 37.5,219.92 37.34,219.7 37.27,219.45 37.01,219.37 36.8,219.22 36.44,218.86 36.28,218.64 36.21,218.39 35.95,218.31 35.74,218.16 35.38,217.8 35.23,217.58 35.15,217.33 34.89,217.25 34.68,217.1 34.57,216.99 34.46,216.97 34.4,217.06 34.4,224.67 34.5,224.77
GND on BOTTOM (solid shape): outline of 245 points within 23.05,245.25 37.05,252.75
GND on BOTTOM (solid shape): outline of 245 points within 23.05,68.57 37.05,76.07
GND on BOTTOM (solid shape): outline of 245 points within 23.05,0.25 37.05,7.75
GND on BOTTOM (solid shape): outline of 245 points within 93.25,203.16 107.25,210.66
GND on BOTTOM (solid shape): outline of 245 points within 149.43,240.26 163.43,247.76
GND on BOTTOM (solid shape): outline of 245 points within 168.8,245.25 182.8,252.75
GND on BOTTOM (solid shape): outline of 245 points within 168.8,68.57 182.8,76.07
GND on BOTTOM (solid shape): outline of 245 points within 168.8,0.25 182.8,7.75
GND on BOTTOM (solid shape): outline of 249 points within 97.5,245.25 111.5,252.75
GND on BOTTOM (solid shape): outline of 249 points within 97.5,19.95 111.5,27.45
GND on BOTTOM (solid shape): outline of 255 points within 111.26,61.21 123.2,66.55
GND on BOTTOM (solid shape): outline of 345 points within 99.28,51.8 106.56,61.53
GND on BOTTOM (solid shape): outline of 195 points within 40.68,208.48 70.15,228.52
GND on BOTTOM (solid shape): outline of 3844 points within 177.97,88.44 191.41,133.73
GND on GND1 (solid shape): outline of 2775 points within 0.51,0.51 194.49,254.49
GND on VCC (solid shape): 111.45,192.14 111.45,189.31 108.47,186.32 108.47,182.39 108.26,182.18 89.02,182.18 88.59,182.6 88.59,192.14 89.05,192.6 110.99,192.6
GND on VCC (solid shape): 96.91,1.27 144.31,1.27 144.46,0.84 144.77,0.51 23.12,0.51 23.12,1.27 54.43,1.27 56.02,2.86 95.32,2.86
GND on VCC (solid shape): 170.41,212.62 184.89,212.62 185.34,212.17 185.88,211.63 185.88,164.54 185.35,164.02 184.37,164.02 183.97,164.41 183.97,165.37 183.12,166.22 181.73,166.22 180.05,164.55 179.95,164.53 171.53,164.53 170.39,163.39 170.14,163.39 169.25,162.5 164.35,162.5 162.85,161 146.69,161 146.39,160.69 142.93,160.69 140.94,158.7 138.12,158.7 137.67,158.26 137.4,158.26 137.2,158.45 136.79,158.45 136.57,158.24 136.22,158.24 135.85,158.61 135.47,158.61 135.12,158.26 134.74,158.26 134.33,158.66 133.34,158.66 132.89,159.11 132.89,161.75 132.22,162.42 131.18,162.42 129.78,163.82 128.6,163.82 128.6,206.18 140.04,206.18 146.65,212.79 170.24,212.79
GND on VCC (solid shape): 135.26,139.47 136.98,139.47 137.47,138.99 138.23,138.99 139.71,137.51 141.21,137.51 143.15,135.57 149.17,135.57 149.35,135.39 154.52,135.39 155.39,134.53 158.15,134.53 159.6,135.98 165.9,135.98 168.65,133.25 168.65,130.93 169.25,130.34 170.42,130.34 170.92,130.83 172.35,130.83 173.11,131.6 174.22,131.6 174.99,130.85 177.33,130.85 178.09,131.61 179.28,131.61 180.06,130.83 181.08,130.83 181.82,130.09 183.53,130.09 184.32,130.87 185.42,130.87 185.88,130.41 185.88,91.77 185.61,91.5 184.24,91.5 183.67,92.12 183.67,92.13 183.61,92.18 183.56,92.24 182.25,92.24 181.57,91.55 180.48,91.55 180.13,91.91 178.19,91.91 177.81,91.53 175.02,91.53 174.05,92.49 173.24,92.49 172.27,91.53 171.13,91.53 170.55,92.11 168.77,92.11 160.16,100.72 160.08,100.72 135.15,100.71 113.04,122.82 113.04,130.16 114.33,131.44 114.71,131.44 116.15,132.89 116.15,138.48 116.74,139.06 130.44,139.06 130.52,139.06 130.57,139.12 131.01,139.54 131.01,139.55 131.8,140.33 134.39,140.33
GND on VCC (solid shape): 194.49,0.51 146.03,0.51 146.34,0.84 146.5,1.27 193.75,1.27 193.75,253.75 11.44,253.75 11.25,253.56 11.25,240.92 9.74,237.28 6.11,235.78 2.11,235.78 2.11,177.74 2.3,177.55 2.87,177.55 4.07,176.34 4.07,148.08 2.93,146.94 2.11,146.94 1.15,145.99 1.15,113.6 2.17,112.58 2.17,71.63 1.41,71.63 1.41,111.86 1.29,112.43 0.97,112.92 0.51,113.38 0.51,147.06 0.96,147.51 2.74,147.51 3.44,148.21 3.44,176.02 2.68,176.78 1.73,176.78 1.41,177.1 1.41,177.55 1.41,177.55 1.41,236.49 6,236.49 9.19,237.81 10.51,241 10.51,254.49 194.49,254.49
GND on GND2 (solid shape): outline of 2759 points within 0.51,0.51 194.49,254.49
GND on TOP: 91.51,196.74 91.51,197.36 92.15,197.99 92.15,201.87 91.77,202.25 90.37,202.25 89.55,201.42 88.66,201.42 88.02,200.79 88.02,196.62 88.03,196.61 91.38,196.61
GND on TOP: 74.69,78.33 74.69,77.34 74.81,77.22 75.58,77.22 75.83,76.96 77.86,76.96 77.99,76.83 77.99,76.58 77.86,76.45 73.67,76.45 72.78,77.34 70.88,77.34 70.75,77.47 70.75,77.85 71.64,78.74 74.28,78.74
GND on TOP: 35.25,56.4 35.33,56.32 36.27,56.32 37.6,57.66 37.6,60.07 37.03,60.64 35.13,60.64 34.87,60.39 34.87,60.01 35.25,59.63
GND on TOP: outline of 93 points within 1.41,0.51 194.49,254.49
GND on TOP: 152.49,231.39 152.49,229.26 152.79,228.96 154.77,228.96 155.08,229.26 155.08,231.24 154.77,231.55 152.64,231.55
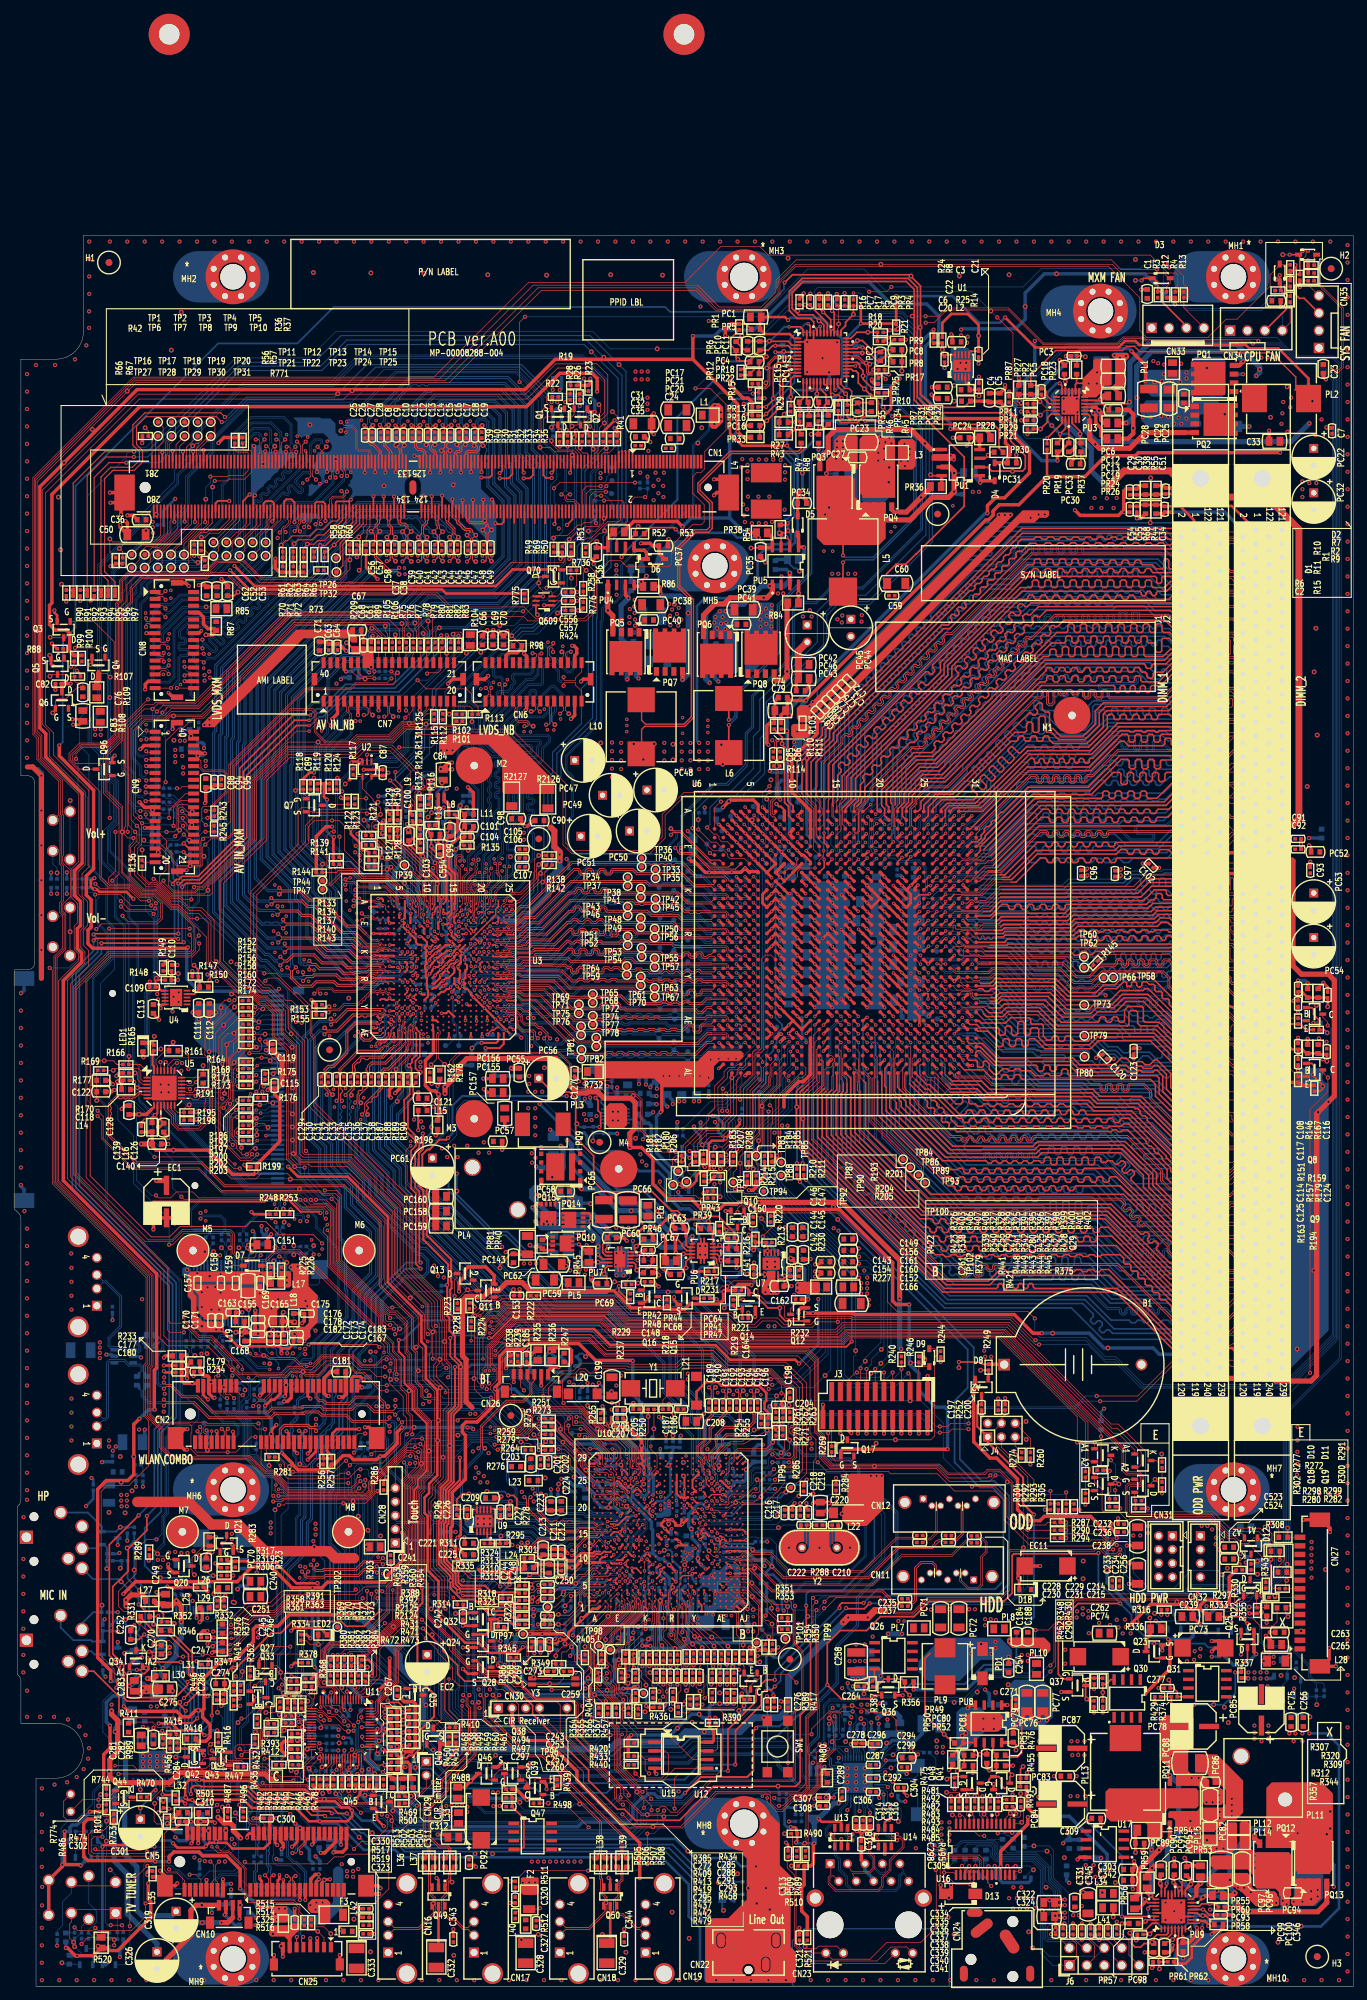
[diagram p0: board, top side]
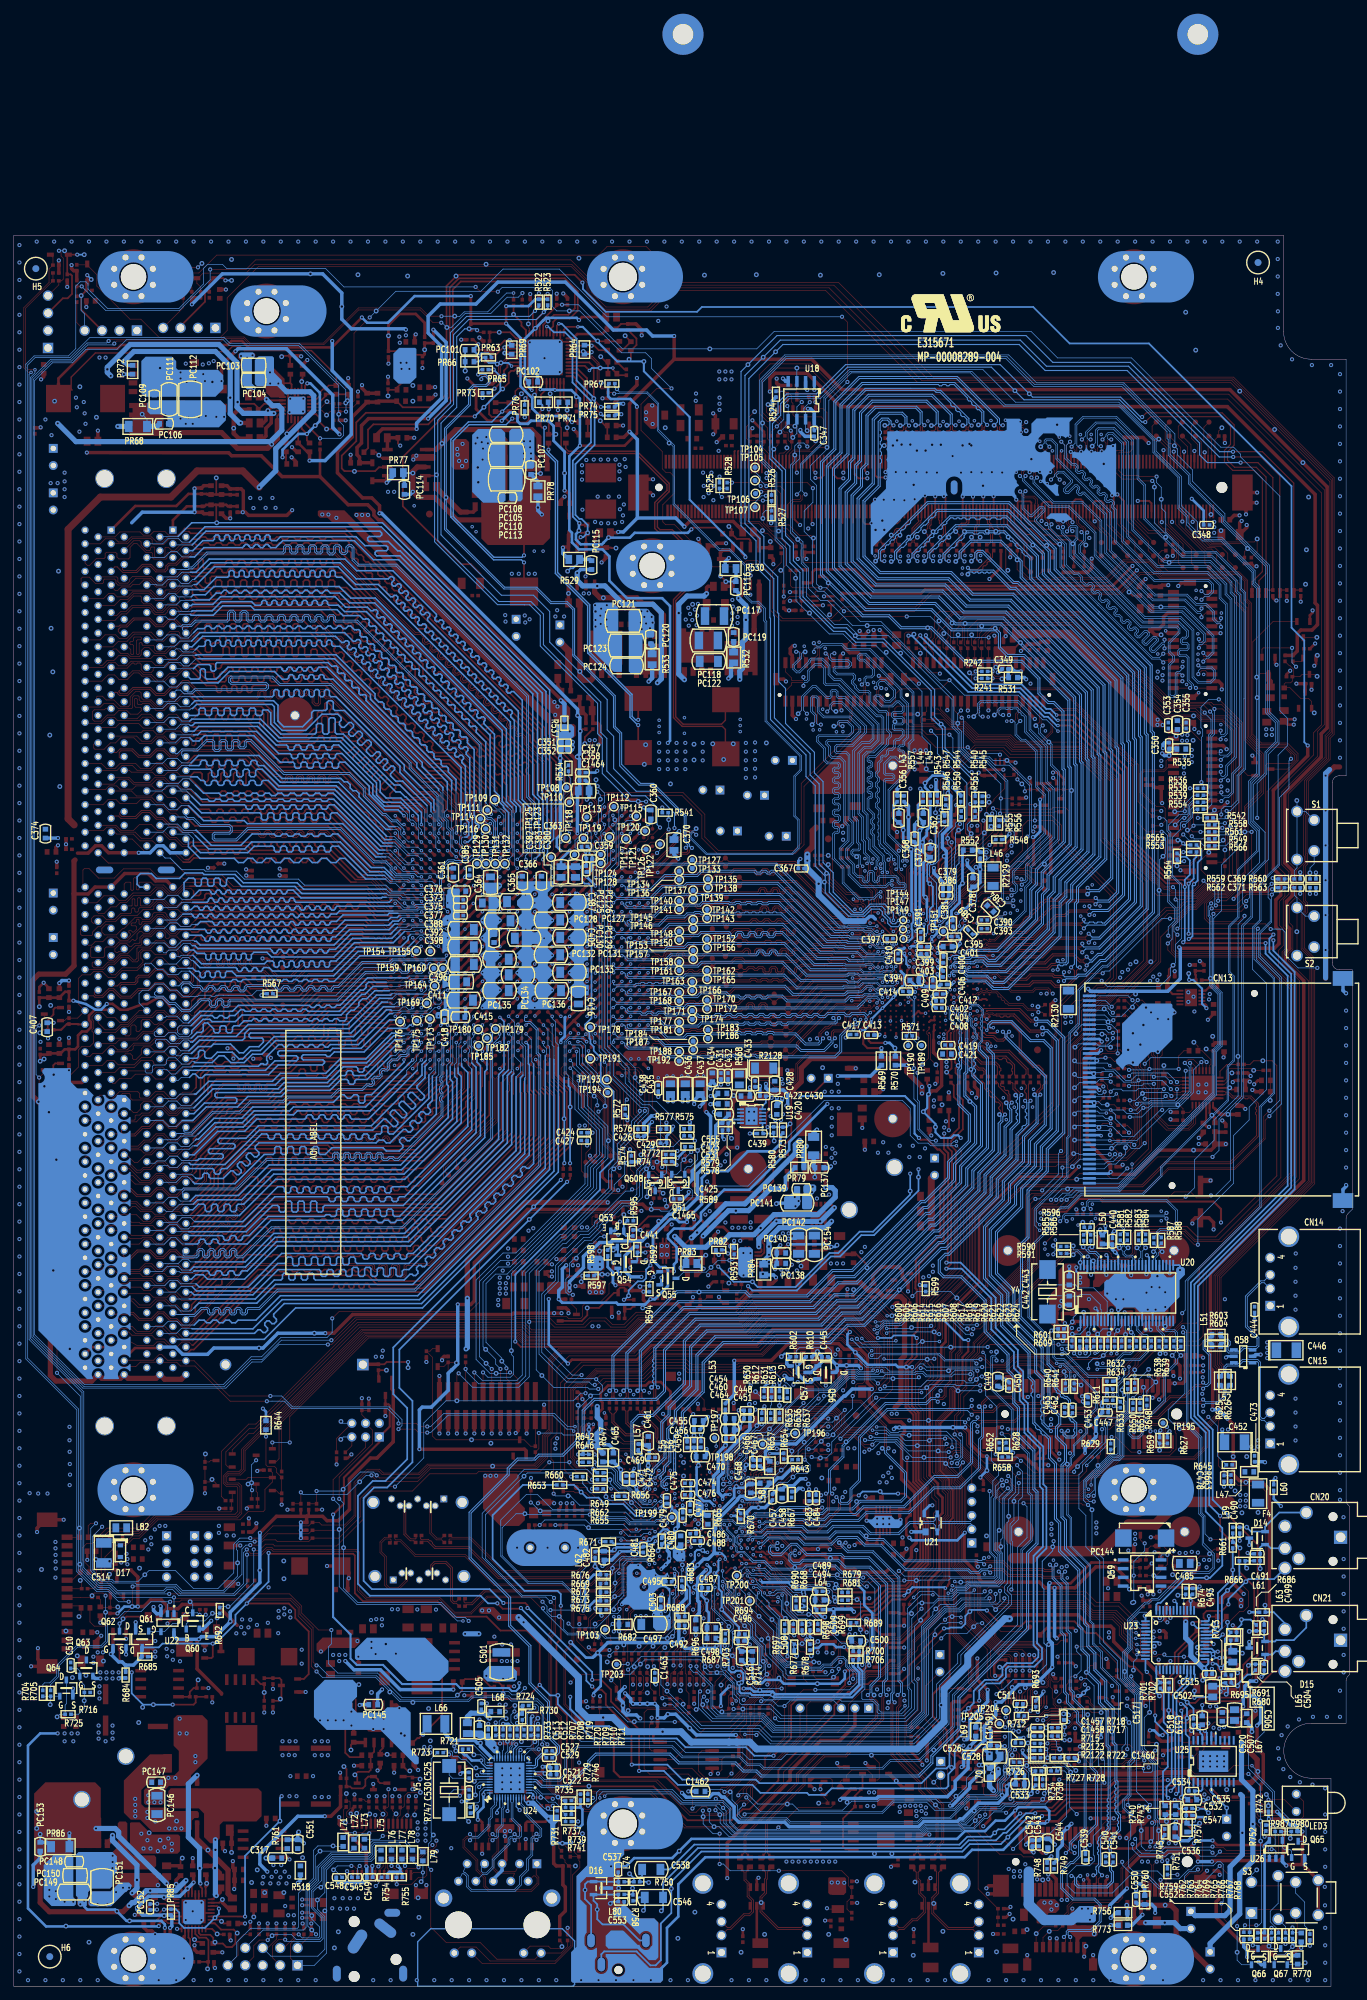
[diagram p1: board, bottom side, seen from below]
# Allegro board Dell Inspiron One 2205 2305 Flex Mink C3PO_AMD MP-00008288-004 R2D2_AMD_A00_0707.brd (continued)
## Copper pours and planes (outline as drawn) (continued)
GND on TOP: 174,50.42 174,47.88 174.51,47.37 177.05,47.37 177.56,47.88 177.56,50.67 177.3,50.93 174.51,50.93
GND on TOP: 153.87,11.49 153.87,10.16 154.06,9.97 157.11,9.97 157.17,10.03 157.17,11.18 156.41,11.94 154.32,11.94
GND on TOP: 48.5,0.51 27.09,0.51 27.07,0.52 24.14,0.52 23.63,1.03 23.63,3.81 24.47,4.65 28.84,4.65 29.5,3.99 29.5,1.6 34.11,1.6 34.11,4.38 34.75,5.02 37.98,5.02 38.24,4.76 38.24,4.13 38.62,3.75 40.08,3.75 40.59,4.25 47.76,4.25 48.52,3.49 62.75,3.49 63.13,3.11 67.7,3.11 68.65,4.06 75.77,4.06 76.72,3.11 80.91,3.11 81.86,4.06 87.58,4.06 88.85,2.79 92.59,2.79 93.48,3.68 93.55,3.68 94.51,4.64 94.51,12.72 92.95,14.27 92.95,16.84 103.8,27.69 105.98,27.69 105.98,26.59 105.55,26.16 104.33,26.16 103.13,24.97 103.13,22.86 105.17,20.83 105.17,18.8 105.17,18.79 106.25,17.71 106.25,12.88 103.68,10.31 101.49,10.31 99.96,8.78 99.96,1.45 99.97,1.44 99.97,1.08 99.4,0.51
GND on TOP: 87.26,202.44 87.51,202.18 88.02,202.18 88.21,202.37 88.21,207.26 88.09,207.39 87.44,207.39 87.01,206.96 87.01,205.1 87.26,204.85
GND on TOP: 71.69,212.98 71.69,212.34 72.07,211.96 80.32,211.96 80.96,212.6 80.96,213.36 72.07,213.36
GND on TOP: 177.24,64.33 177.24,61.72 177.75,61.21 179.21,61.21 179.65,61.66 179.65,63.63 179.33,63.94 178.26,63.94 177.87,64.33
GND on TOP: 122.64,100 122.64,98.7 122.96,98.38 124.13,98.38 124.83,99.09 124.83,103.91 123.45,105.28 123.45,108.33 122.41,109.38 121.75,109.38 121.63,109.26 121.63,101.01
GND on TOP: 77.61,105.79 72.15,105.79 71.89,105.54 71.89,103.76 72.15,103.5 73.92,103.5 75.32,102.11 76.85,102.11 77.22,102.48 77.22,103.94 77.61,104.33
GND on TOP: 139.46,50.67 142.89,50.67 143.28,50.28 143.28,48.64 142.69,48.05 139.17,48.05 138.66,48.56 138.66,49.88
GND on TOP: 6.49,2.26 5.45,3.3 5.45,8.51 4.33,9.63 4.33,10.82 4.63,11.13 5.5,11.13 7.19,9.44 7.19,4.95 8.46,3.68 11.87,3.68 12.84,4.65 15.63,4.65 20.58,9.6 20.58,11.68 20.84,11.94 20.84,16 23,16 23,12.45 22.24,11.68 22.24,8.89 19.44,6.1 19.44,3.78 17.92,2.26
GND on TOP: 91.35,225.07 90.97,224.69 90.97,223.72 90.33,223.08 90.33,220.17 90.97,219.53 90.97,218.66 91.59,218.05 92.17,218.05 92.76,217.46 92.76,216.89 92.17,216.31 90.46,216.31 90.08,215.93 90.08,213.97 90.18,213.87 94.91,213.87 94.91,219.68 95.16,219.93 95.16,224.72 95.37,224.93 95.79,224.93 95.9,225.04 95.9,231.78 95.86,231.81 95.86,231.9 95.35,232.41 92.56,232.41 91.35,231.2
GND on TOP: 87.31,108.08 87.31,103.48 87.54,103.25 88.89,103.25 88.99,103.35 88.99,108 88.68,108.31 87.54,108.31
GND on TOP: 164.6,57.53 164.86,57.78 164.86,58.86 164.48,59.25 162.06,59.25 161.36,58.55 156.47,58.55 156.35,58.42 156.35,57.66 156.47,57.53
GND on TOP: 88.53,89.15 88.53,88.84 88.02,88.33 88.02,87.38 87.77,87.12 87.13,87.12 86.75,87.5 86.12,87.5 85.74,87.88 85.74,88.9 86.12,89.28 88.4,89.28
GND on TOP: 133.72,55.63 140.04,55.63 140.32,55.35 140.32,54.58 140.04,54.31 133.51,54.31 133.21,54.61 133.21,55.12
GND on TOP: 154.25,53.28 158.13,53.28 158.63,52.77 158.63,50.8 157.36,49.53 157.36,46.48 156.86,45.97 153.3,45.97 152.54,46.74 152.54,51.56
GND on TOP: 127.9,202.31 127.9,203.07 129.17,204.34 129.17,205.1 139.2,215.14 139.2,217.81 139.46,218.06 140.6,218.06 140.85,217.81 140.85,214 129.17,202.31
GND on TOP: 22.64,145.26 22.64,141.71 22.77,141.58 24.22,141.58 24.39,141.76 24.39,145.36 24.09,145.67 23.05,145.67
GND on TOP: 111.2,202.56 111.01,202.76 111.01,205.49 111.14,205.61 112.02,205.61 112.28,205.36 112.28,202.76 112.09,202.56
GND on TOP: 107.64,243.84 101.23,243.84 100.15,244.92 99.71,244.92 99.58,244.79 99.58,243.08 100.4,242.25 101.99,242.25 102.63,242.89 105.87,242.89 106.25,242.51 107.64,242.51
GND on TOP: 77.23,113.6 77.23,114.36 77.04,114.55 75.96,114.55 75.64,114.87 75.64,115.38 75.96,115.7 77.54,115.7 78.88,114.36 78.88,113.67 78.81,113.6
GND on TOP: 101.29,199.58 102.4,200.69 103.58,200.69 104.34,201.45 105.36,201.45 105.61,201.2 105.61,196.47 105.23,196.09 101.36,196.09 101.29,196.15
GND on TOP: 71.77,107.57 71.77,106.81 71.26,106.3 64.02,106.3 60.84,109.47 60.84,110.74 61.86,110.74 61.86,109.98 62.49,109.35 68.34,109.35 69.73,107.95 71.38,107.95
GND on TOP: 82.46,112.04 82.46,110.27 82.62,110.11 82.62,109.54 83.83,108.33 84.59,108.33 84.78,108.52 84.78,109.79 83.45,111.12 83.45,111.96 83.27,112.14 82.56,112.14
GND on TOP: 111.39,111.43 115,111.43 115.38,111.05 115.38,110.26 115.2,110.08 111.29,110.08 111.05,110.32 111.05,111.09
GND on TOP: 1.73,71.63 1.41,71.95 1.41,111.86 1.41,111.91 1.28,112.46 0.97,112.92 0.51,113.38 0.51,146.94 0.76,147.19 3.12,147.19 3.82,148.02 4.07,147.76 4.07,147.19 4.76,146.51 4.76,116.34 9.14,111.97 9.15,111.97 10.65,110.46 10.65,108.4 9.35,107.1 9.35,97.78 10.71,96.42 10.71,95.02 9.54,93.84 9.54,91.57 10.77,90.34 10.77,88.13 8.92,86.28 8.92,78.29 10.26,76.95 10.26,74.38 7.5,71.63 2.17,71.63 1.94,71.63
GND on TOP: 66.5,28.57 66.5,26.42 67.19,25.72 71.64,25.72 71.89,25.97 71.89,27.69 71.58,28 71.13,28 70.37,28.77 66.69,28.77
GND on TOP: 90.36,110.16 84.82,110.16 84.54,110.44 84.54,112.37 84.82,112.65 90.51,112.65 90.64,112.52 90.64,110.44
GND on TOP: 80.1,116.41 80.1,115.29 79.89,115.09 78.47,115.09 77.71,115.85 77.71,116.43 78.07,116.79 79.72,116.79
GND on TOP: 164.86,231.01 172.1,231.01 172.53,230.58 172.53,227.26 172.35,227.08 165.11,227.08 164.09,228.09 164.09,230.25
GND on TOP: 120.03,32.05 120.03,28.45 120.28,28.19 124.6,28.19 124.85,28.45 124.85,32.51 124.6,32.77 120.74,32.77
GND on TOP: 77.05,118.54 76.85,118.34 75.68,118.34 75.3,118.72 75.3,119.35 75.02,119.63 75.02,122.2 75.47,122.66 76.82,122.66 77.05,122.43
GND on TOP: 180.6,43.56 180.6,41.27 181.62,40.26 183.91,40.26 185.43,38.73 188.73,38.73 189.49,39.5 189.49,43.69 188.99,44.2 181.24,44.2
GND on TOP: outline of 281 points within 89.25,60.94 99.6,74.72 ; 1 cut-out
GND on TOP: 60.04,137.11 59.89,137.26 59.89,138.85 59.89,138.87 59.89,139.65 59.89,139.67 59.89,140.45 59.89,140.47 59.89,141.25 59.89,141.27 59.89,141.71 59.91,141.72 60.08,141.96 60.04,142.25 60.02,142.29 60.11,142.37 60.11,142.39 60.53,142.81 60.54,142.89 60.57,142.94 60.6,142.98 60.64,143.01 60.74,143.01 61.1,142.65 61.1,141.1 61.35,140.84 61.86,140.84 61.99,140.72 61.99,140.34 61.86,140.21 61.61,140.21 61.22,140.59 60.85,140.59 60.47,140.22 60.44,140.04 60.49,139.87 60.49,139.86 60.49,139.45 60.49,139.44 60.44,139.29 60.46,139.13 60.46,137.23 60.34,137.11
GND on TOP: 148.22,35.94 148.22,26.42 148.73,25.91 151.78,25.91 152.79,26.92 152.79,35.56 151.65,36.7 148.98,36.7
GND on TOP: 121.37,46.66 123.96,46.66 124.22,46.41 124.22,44.83 123.81,44.42 121.84,44.42 121.18,45.09 121.18,46.47
GND on TOP: 85.02,220.6 85.02,219.46 85.27,219.2 87.31,219.2 87.62,219.52 87.62,220.73 85.15,220.73
GND on TOP: 73.8,170.94 75.58,170.94 76.08,170.43 76.08,169.29 74.69,167.89 74.69,166.37 75.32,165.74 75.32,162.81 74.94,162.43 74.43,162.43 74.18,162.69 74.18,166.12 73.42,166.88 73.42,170.56
GND on BOTTOM: 101.8,79.38 101.8,76.75 101.77,76.71 101.1,76.71 100.59,77.22 100.59,78.36 101.1,78.87 101.1,79.25 101.36,79.5 101.36,82.04 101.67,82.36 103.45,82.36 103.58,82.23 103.58,81.15 103.13,80.71 103.13,79.82 103.01,79.69 102.12,79.69
GND on BOTTOM: 51.45,157.23 51.45,156.84 52.46,155.83 52.46,154.05 52.08,153.67 52.08,153.16 52.21,153.03 53.22,153.03 53.48,153.29 53.48,155.96 52.08,157.35 51.57,157.35
GND on BOTTOM: 1.73,71.63 1.41,71.95 1.41,111.86 1.41,111.91 1.28,112.46 0.97,112.92 0.51,113.38 0.51,147.26 3.29,147.26 3.88,147.85 3.92,147.85 4.51,147.26 5.34,147.26 6.68,145.92 6.68,115 11,110.68 11,108.71 9.03,106.74 9.03,98.74 10.68,97.09 10.68,95.19 10.11,94.61 9.03,94.61 8.84,94.42 8.84,91.06 9.28,90.61 10.3,90.61 10.87,90.04 10.87,88.39 9.03,86.55 9.03,78.55 10.87,76.71 10.87,73.15 9.35,71.63 1.94,71.63
GND on BOTTOM: 22.11,182.5 22.11,185.04 22.87,185.8 26.3,185.8 27.06,185.04 27.06,183.9 26.93,183.77 23.89,183.77 23.38,183.26 23.38,183.01 22.74,182.37 22.24,182.37
GND on BOTTOM: 171.5,26.42 170.81,27.11 170.81,30.21 171.33,30.73 173.49,30.73 174,30.23 174,29.21 174.38,28.83 175.78,28.83 176.03,28.57 176.03,26.67 175.78,26.42
GND on BOTTOM: outline of 225 points within 111.22,138.49 129.77,163.65
GND on BOTTOM: 77.33,118.85 77.33,120.12 76.97,120.47 76.97,122.5 76.82,122.66 74.97,122.66 74.74,122.43 74.74,119.79 75.78,118.75 77.23,118.75
GND on BOTTOM: 20.33,62.04 20.78,62.48 24.01,62.48 24.14,62.36 24.14,60.83 24.01,60.71 20.58,60.71 20.33,60.96
GND on BOTTOM: 17.54,81.66 18.93,81.66 19.31,81.28 19.31,78.17 19.25,78.11 17.92,78.11 17.16,78.87 17.16,81.28
GND on BOTTOM: 93.07,51.53 92.94,51.4 92.12,51.4 91.5,52.02 91.5,52.86 92.44,53.8 92.87,53.8 93.07,53.59
GND on BOTTOM: 30.03,56.44 29.79,56.68 29.79,57.53 29.6,57.72 29.6,59.37 29.6,61.04 29.09,61.55 29.09,62.15 29.08,62.17 29.08,62.29 28.41,62.97 28.41,63.37 28.92,63.88 28.92,67.84 27.58,69.18 28.91,69.18 28.92,69.17 34.68,69.17 34.68,64.13 33.79,63.25 31.43,63.25 31.05,63.63 31.05,64.59 30.62,65.02 29.86,65.02 29.6,64.77 29.6,63.07 30.81,61.86 30.81,59.68 31.25,59.24 31.46,59.09 31.72,59.01 31.76,59.01 31.76,56.51 31.69,56.44
GND on BOTTOM: 100.21,188.79 100.59,189.17 104.02,189.17 104.53,188.66 104.53,186.25 103.39,185.1 103.39,182.44 102.91,181.96 100.69,181.96 100.21,182.44
GND on BOTTOM: 58.2,137.57 58.63,137.57 58.79,137.41 58.79,135.41 59.42,134.77 59.42,133.6 59.31,133.49 58.65,133.49 57.97,134.16 57.97,137.34
GND on BOTTOM: 88.97,196.98 88.97,200.79 90.43,202.25 92.28,202.25 92.66,201.87 92.66,197.99 93.48,197.17 93.48,192.09 93.17,191.77 91.7,191.77 91.26,192.21 91.26,196.28 90.82,196.72 89.23,196.72
GND on BOTTOM: 22.64,144.91 22.64,141.71 22.77,141.58 23.96,141.58 24.34,141.96 24.34,144.98 24.12,145.21 22.95,145.21
GND on BOTTOM: 100.21,108.81 100.93,108.81 101.26,108.48 101.26,105.99 100.95,105.69 99.3,105.69 99.07,105.92 99.07,107.67
GND on BOTTOM: 92.02,127.7 91.77,127.44 91.77,126.62 91.83,126.56 92.66,126.56 93.42,127.32 93.42,127.89 93.8,128.27 93.8,129.92 93.74,129.98 93.23,129.98 92.78,130.43 92.02,130.43
GND on BOTTOM: 177.62,62.55 177.62,59.63 177.87,59.37 180.1,59.37 180.35,59.63 181.81,59.63 182.26,60.07 182.26,62.36 181.68,62.93 179.36,62.93 178.98,63.3 178.37,63.3
GND on BOTTOM: outline of 92 points within 1.41,0.51 194.49,254.49 ; 2 cut-outs
GND on BOTTOM: 88.02,185.99 88.53,186.5 88.53,188.66 89.42,189.55 97.23,189.55 98.34,188.44 98.34,182.63 97.77,182.05 88.53,182.05 88.02,182.56
GND on BOTTOM: 77.29,109.73 77.29,108.84 77.54,108.58 82.24,108.58 82.43,108.78 82.43,109.79 82.31,109.92 77.48,109.92
GND on BOTTOM: 23.38,0.51 23.12,0.76 23.12,1.4 23.33,1.6 34.68,1.6 36.09,3.01 36.04,3.06 36.04,6.55 42.15,6.55 43.07,7.46 45.26,7.46 51.18,13.38 51.18,14.94 52.94,16.7 82.84,16.7 83.42,16.13 95.32,16.13 96.01,15.44 96.01,14.28 97.29,13 97.29,9.78 99.07,8 99.07,2.16 99.71,1.52 99.71,0.82 99.39,0.51 48.55,0.51 24.75,0.51 24.75,0.51 24.52,0.51 24.52,0.51
GND on INT1: 1.41,71.63 1.41,111.86 1.29,112.43 0.97,112.92 0.51,113.38 0.51,147.37 0.65,147.51 0.96,147.51 1.15,147.32 1.15,113.6 2.17,112.58 2.17,71.63
GND on INT1: 114.22,0.51 114.22,1.27 193.75,1.27 193.75,253.75 11.57,253.75 11.34,253.65 11.25,253.43 11.25,240.92 9.74,237.28 6.11,235.78 2.11,235.78 2.11,177.29 1.98,177.17 1.66,177.17 1.41,177.42 1.41,236.49 6,236.49 9.19,237.81 10.51,241 10.51,254.49 194.49,254.49 194.49,0.51
GND on INT1: 89.02,182.18 88.59,182.6 88.59,192.14 89.05,192.6 110.56,192.6 110.95,192.21 110.95,189.67 108.47,187.2 108.47,182.39 108.26,182.18
GND on INT1: 24.52,0.51 24.52,1.27 99.92,1.27 99.92,0.51
GND_AUDIO on TOP (solid shape): 21.6,43.81 21.6,42.8 21.35,42.55 17.41,42.55 16.9,43.05 16.9,43.43 18.17,43.43 18.68,43.94 21.47,43.94
GND_AUDIO on TOP (solid shape): outline of 285 points within 100.59,0.51 113.8,26.02
GND_AUDIO on BOTTOM (solid shape): 106.55,11.56 107.34,11.56 107.6,11.3 107.6,10.21 107.44,10.06 106.34,10.06 103.86,7.58 103.78,7.55 103.71,7.6 102.65,8.02 101.96,7.11 101.96,6.23 102.78,5.29 103.81,6 103.82,6.03 104.12,6.03 106.2,8.11 108.02,8.11 108.76,7.37 108.76,5.88 108.34,5.46 104.12,5.46 102.47,3.81 101.48,3.81 101.1,4.19 101.1,9.32 101.68,9.9 103.97,9.9 105.63,11.56 105.66,11.56 105.99,11.88 106.22,11.88
GND_AUDIO on BOTTOM (solid shape): outline of 240 points within 100.4,0.51 113.8,26.29
GND_AUDIO on GND1 (solid shape): outline of 147 points within 100.4,0.51 113.8,27.37
GND_AUDIO on GND1 (solid shape): outline of 528 points within 0.91,0.51 35.49,71.12
GND_AUDIO on VCC (solid shape): 2.17,69.2 1.82,68.66 1.85,68.03 1.96,67.7 2.17,67.43 2.17,62.7 1.82,62.16 1.85,61.53 1.96,61.2 2.17,60.93 2.17,54.2 1.82,53.66 1.85,53.03 1.96,52.7 2.17,52.43 2.17,47.7 1.82,47.16 1.85,46.53 1.96,46.2 2.17,45.93 2.17,39.56 6.16,39.56 11.21,34.32 6.16,29.08 4.33,29.08 4.33,27.73 3.74,26.72 4.33,25.71 4.33,16.83 3.95,16.45 3.95,14.92 4.33,14.54 4.33,11.56 3.95,11.18 3.95,9.21 4.33,8.83 4.33,1.27 22.62,1.27 22.62,0.51 3.61,0.51 3.61,29.8 6,29.8 10.51,34.31 6,38.82 1.41,38.82 1.41,44.49 1.29,45.06 0.97,45.55 0.91,45.61 0.91,69.69 0.97,69.75 1.29,70.24 1.41,70.81 1.41,71.12 2.17,71.12
GND_AUDIO on GND2 (solid shape): outline of 147 points within 100.4,0.51 113.8,27.37
GND_AUDIO on GND2 (solid shape): outline of 530 points within 0.91,0.51 35.49,71.12
GND_AUDIO on TOP: 4.22,0.56 3.62,1.17 3.62,16.96 3.61,16.97 3.61,29.8 6,29.8 10.51,34.31 6,38.82 2.35,38.82 1.83,38.82 1.41,38.82 1.41,39.24 1.41,39.24 1.41,44.49 1.41,44.54 1.28,45.09 0.97,45.55 0.91,45.61 0.91,69.69 0.97,69.75 1.29,70.24 1.41,70.81 1.41,70.93 1.6,71.12 1.98,71.12 1.99,71.12 10,71.12 11.35,69.77 11.35,49.18 8.53,46.37 8.53,45.13 12.47,41.19 12.47,30.5 11,29.03 7.74,29.03 7.74,29.04 6.74,28.04 6.74,24.72 6.16,24.14 6.16,17.54 5.63,17 4.44,17 3.93,16.5 3.93,15.01 4.44,14.5 4.44,11.81 3.88,11.25 3.88,9.44 4.8,8.53 4.8,2.39 5.27,1.91 22.24,1.91 22.62,1.53 22.62,0.89 22.29,0.56
GND_AUDIO on TOP: 17.41,35.05 17.41,32.51 18.17,31.75 21.98,31.75 22.11,31.88 22.11,33.4 20.58,34.92 20.58,35.43 20.46,35.56 17.92,35.56
GND_AUDIO on BOTTOM: 3.61,0.51 3.61,8.79 3.62,8.8 3.62,16.96 3.61,16.97 3.61,29.8 6,29.8 10.51,34.31 6,38.82 2.35,38.82 1.41,38.82 1.41,44.49 1.41,44.54 1.28,45.09 0.97,45.55 0.91,45.61 0.91,69.69 0.97,69.75 1.29,70.24 1.41,70.81 1.41,70.93 1.6,71.12 4.42,71.12 4.98,70.56 4.98,67.62 5.48,67.11 8.28,67.11 8.95,67.78 10.35,67.78 10.94,67.19 10.94,66.19 10.03,65.28 8.52,65.28 8.23,64.98 8.23,63.07 8.95,62.34 8.95,61.79 8.08,60.91 8.08,57.97 5.15,55.04 5.15,52.61 8.34,49.41 8.34,48.22 8.62,47.94 8.62,46.94 8.06,46.38 8.06,45.6 12.46,41.2 12.46,30.5 10.99,29.03 10.99,26.66 8.77,24.45 6.55,24.45 6.23,24.13 6.23,8.95 5.6,8.32 5.6,5.14 6.23,4.51 6.23,2.48 6.8,1.91 22.29,1.91 22.62,1.59 22.62,0.89 22.24,0.51
GND_AUDIO on BOTTOM: 18.2,39.64 18.43,39.41 19.93,39.41 20.84,40.32 20.84,40.32 21.11,40.59 21.11,40.96 20.85,41.22 16.71,41.22 16.35,40.87 16.35,39.86 16.57,39.64
GND_AUDIO on BOTTOM: 23.38,30.73 23.38,34.8 23.25,34.92 23.25,35.94 23,35.94 23,34.95 22.92,34.87 22.69,34.87 22.62,34.95 22.62,35.94 22.36,35.94 22.36,34.95 22.29,34.87 19.47,34.87 19.37,34.98 19.37,35.94 19.09,35.94 19.09,34.98 18.98,34.87 17.51,34.87 17.41,34.98 17.41,35.94 17.13,35.94 17.13,34.95 16.77,34.59 16.77,30.99 17.16,30.61 17.16,29.59 17.41,29.59 17.41,30.61 17.54,30.73 18.96,30.73 19.09,30.61 19.09,29.49 19.19,29.39 19.31,29.39 19.38,29.45 19.38,30.61 19.51,30.73 19.62,30.73 19.75,30.61 19.75,29.49 19.85,29.39 19.95,29.39 20.03,29.46 20.03,30.61 20.15,30.73 20.92,30.73 21.04,30.61 21.04,29.49 21.09,29.44 21.27,29.44 21.32,29.49 21.32,30.61 21.45,30.73 22.21,30.73 22.34,30.61 22.34,29.51 22.39,29.46 22.57,29.46 22.62,29.51 22.62,30.61 22.74,30.73 22.87,30.73 23,30.61 23,29.51 23.07,29.44 23.2,29.44 23.28,29.51 23.28,30.63
GND_AUDIO on INT1: 3.61,0.51 3.61,29.8 6,29.8 10.51,34.31 6,38.82 1.41,38.82 1.41,44.49 1.29,45.06 0.97,45.55 0.91,45.61 0.91,69.69 0.97,69.75 1.29,70.24 1.41,70.81 1.41,71.12 2.17,71.12 2.17,39.56 6.16,39.56 11.21,34.32 6.16,29.08 4.33,29.08 4.33,1.27 24.01,1.27 24.01,0.51
GND_AUDIO on INT1: 100.41,0.51 100.41,1.26 113.8,1.26 113.8,0.51
P0V75_VTT_SUS on TOP (solid shape): 159.75,236.78 159.75,233.32 159.6,233.17 158.84,233.17 158.23,232.56 158.23,232.11 157.54,231.42 155.54,231.42 155.54,234.14 157.11,235.71 157.11,236.73 157.47,237.08 159.45,237.08
P0V75_VTT_SUS on BOTTOM (solid shape): 159.88,236.88 159.88,233.38 159.6,233.1 156.27,233.1 155.94,233.43 155.94,233.91 157.08,235.05 157.08,237.21 157.31,237.44 159.32,237.44
P0V75_VTT_SUS on TOP: 186.78,169.54 186.78,163.86 186.37,163.45 186.09,163.45 185.41,164.13 185.41,169.09 186.07,169.75 186.57,169.75
P1V1 on TOP (solid shape): 126.63,74.42 126.63,69.57 124.12,67.06 121.37,67.06 120.53,67.89 120.53,69.66 121.3,70.42 121.3,74.3 121.68,74.68 126.38,74.68
P1V1 on TOP (solid shape): 78.62,175.54 78.62,173.8 78.5,173.67 71.32,173.67 71,173.99 71,178.84 69,180.85 65.24,180.85 63.76,179.37 62.34,179.37 61.81,179.91 61.81,181.02 63.17,182.37 71.79,182.37
P1V1 on BOTTOM (solid shape): 95.64,70.61 95.64,68.71 95.32,68.39 94.56,68.39 94.44,68.26 93.61,68.26 93.42,68.45 93.42,68.9 93.48,68.96 94.24,68.96 94.56,69.28 94.56,70.04 95.26,70.74 95.51,70.74
P1V1 on TOP: 81.72,85.47 81.52,85.27 80.22,85.27 80,85.5 80,87.99 80.4,88.39 81.54,88.39 81.72,88.21
P1V1 on TOP: 76.36,124 75.7,123.34 72.86,123.34 72.38,123.83 72.38,127.15 72.15,127.38 71.13,127.38 70.62,127.89 70.62,132.72 70.89,132.98 72.64,132.98 72.71,133.05 76.87,133.05 77.35,132.56 77.35,128.88 76.36,127.89
P1V1 on TOP: 100.21,88.27 100.21,89.51 99.78,89.94 98.05,89.94 97.65,89.53 97.65,88.21 97.95,87.91 99.86,87.91
P1V1 on BOTTOM: 124.34,74.42 124.34,75.56 122.12,77.79 119.33,77.79 119.07,78.04 115.77,78.04 115.39,78.42 115.39,79.69 115.71,80.01 125.49,80.01 126.69,78.8 126.69,74.17 126.25,73.72 125.04,73.72
P1V1 on BOTTOM: 53.16,162.37 53.16,163.51 51.19,165.48 49.54,165.48 49.29,165.23 49.29,164.21 51.13,162.37
P1V1 on BOTTOM: 40.84,139.89 41.86,139.89 42.17,140.21 42.17,142.94 40.46,142.94 40.27,142.75 40.27,140.46
P1V1 on INT1: 64.27,70.8 64.27,105.36 58.56,111.08 58.56,123.51 57.99,124.08 56.72,124.08 55.38,122.75 45.48,122.75 42.46,125.76 42.46,138.42 40.78,140.1 40.78,141.54 41.04,141.81 42.1,141.81 44.36,139.55 46.54,139.55 47,140.01 47,144.27 44.46,146.81 38.81,146.81 36.71,148.91 36.71,159.76 41.29,164.33 41.29,169.67 50.3,178.69 60.27,178.69 61.86,180.28 64.91,180.28 66.05,179.13 69.23,179.13 70.43,177.93 70.43,157.43 69.8,156.8 69.8,156.09 65.58,151.87 65.58,144.7 72.72,137.54 72.72,136.07 74.23,134.56 79.02,134.56 79.64,133.93 79.64,103.62 80.79,102.48 80.85,102.42 80.85,92.89 82.04,91.69 108.33,91.69 116.41,83.61 116.41,77.93 108.26,69.79 95.36,69.79 95.13,70.02 95.13,70.54 95.44,70.86 95.44,72.58 94.93,73.09 93.15,73.09 92.21,72.15 92.21,70.26 91.74,69.79 65.29,69.79
P1V1ALW on TOP: 66.69,60.96 65.42,60.96 64.88,61.49 64.88,61.82 65.03,61.98 66.18,61.98 66.43,62.23 66.43,64.9 67.19,65.66 67.19,66.29 67.45,66.29 67.45,65.66 67.57,65.53 67.7,65.66 67.7,66.29 67.96,66.29 67.96,65.66 68.08,65.53 68.21,65.66 68.21,66.29 68.46,66.29 68.46,65.28 68.72,65.02 68.72,64.19 69.05,63.86 71.66,63.86 72.02,63.5 73.92,63.5 74.56,62.87 74.56,60.58 73.92,59.94 72.02,59.94 71.89,60.07 67.57,60.07
P1V2_CPU_VDDHT on TOP (solid shape): 106.18,135.89 106.18,135.38 105.55,134.75 102.63,134.75 101.86,133.99 101.86,132.21 100.59,130.94 94.42,130.94 93.14,132.22 86.74,132.22 86.71,132.25 84.68,132.25 84.47,132.46 84.47,134.24 84.97,134.75 99.45,134.75 100.98,136.27 105.8,136.27
P1V2_CPU_VDDHT on BOTTOM: 90.61,132.77 91.63,132.77 91.64,132.75 93.57,132.75 94.05,132.27 94.05,131.32 94.38,130.99 101.56,130.99 101.92,131.34 101.92,132.79 101.86,132.84 101.86,133.99 102.25,134.37 104.05,134.37 104.47,134.78 104.95,134.78 105.42,135.25 105.42,135.38 105.29,135.51 101.64,135.51 99.83,133.71 96.81,133.71 96,134.52 87.29,134.52 87.26,134.49 86.43,134.49 86.24,134.3 86.24,132.14 86.75,131.64 87.83,131.64 88.38,132.18 90.03,132.18
P1V2_CPU_VDDNB_RUN on VCC (solid shape): 120.53,206.95 120.79,206.95 121.61,207.77 126.8,207.77 128.22,206.36 128.22,163.58 127.06,162.42 123.86,162.42 122.74,161.3 117.87,161.3 116.72,162.46 116.18,162.46 113.04,162.46 108.85,166.64 108.85,186.17 111.83,189.15 111.83,192.71 114.25,195.12 114.25,199.69 117.3,202.74 117.3,207.38 117.69,207.77 119.71,207.77
P1V2_CPU_VDDNB_RUN on TOP: 116.72,189.75 115.44,189.75 115.07,190.12 115.07,193.29 116.72,194.94 116.72,196.34 116.22,196.85 113.9,196.85 113.39,197.36 113.39,199.32 115.39,201.32 115.39,204.4 117.31,206.32 127.65,206.32 127.65,200.68
P1V2_CPU_VDDNB_RUN on INT1: 117.87,161.3 116.72,162.46 116.18,162.46 113.04,162.46 108.85,166.64 108.85,177.48 112.09,180.72 112.09,187.2 113.17,188.28 113.17,192.15 114.25,193.23 114.25,199.14 117.68,202.56 117.68,207.39 118.06,207.77 119.71,207.77 120.53,206.95 120.79,206.95 121.61,207.77 126.8,207.77 128.22,206.36 128.22,163.58 127.06,162.42 123.86,162.42 122.74,161.3
P1V2_CPU_VDDR on TOP (solid shape): 150.7,214.83 150.7,214.24 150.36,213.89 149.26,213.89 148.55,213.17 146.5,213.17 117.32,183.99 116.99,183.99 116.68,184.3 116.68,184.84 146.34,214.5 146.34,214.51 146.83,214.99 150.55,214.99
P1V2_CPU_VDDR on TOP: 121.27,109.68 121.27,98.72 121.07,98.52 117.34,98.52 116.49,99.37 116.49,100.31 116.72,100.55 117.4,100.55 117.74,100.89 117.74,102.59 118.27,103.12 118.27,106.3 117.77,106.81 112.15,106.81 111.69,106.35 110.04,106.35 110.04,107.9 109.99,107.95 109.99,109.09 110.63,109.73 115.96,109.73 116.95,110.72 120.23,110.72
P1V2_CPU_VDDR on TOP: 112.96,124.99 112.69,124.71 111.62,124.71 111.44,124.89 111.44,128.73 111.64,128.93 112.69,128.93 112.96,128.65
P1V2_CPU_VDDR on BOTTOM: 121.27,109.52 121.27,109.09 120.95,108.78 120.32,108.78 111.87,117.22 111.87,122.15 112.02,122.3 112.02,124.64 111.57,125.09 111.57,125.76 111.87,126.06 113.12,126.06 113.63,125.55 113.63,117.17
P1V2_CPU_VDDR on INT1: 115.45,109.79 113.04,112.2 113.04,120.98 114.08,122.02 140.47,122.02 145.17,126.72 145.17,160.1 144.58,160.69 142.93,160.69 140.94,158.7 138.12,158.7 137.67,158.26 137.4,158.26 137.2,158.45 136.79,158.45 136.57,158.24 136.22,158.24 135.85,158.61 135.47,158.61 135.12,158.26 134.74,158.26 134.33,158.66 133.34,158.66 132.89,159.11 132.89,161.75 132.22,162.42 131.18,162.42 129.78,163.82 128.6,163.82 128.6,206.18 138.84,206.18 147.66,215.01 150.62,215.01 150.89,214.74 150.89,213.06 149.68,211.85 149.68,211.77 149.68,206.36 154.57,201.47 154.57,113.41 150.95,109.79
P1V5 on TOP: 27.7,25.68 27.7,24.89 28.27,24.32 29.92,24.32 30.24,24.64 30.24,25.27 29.67,25.84 27.86,25.84
P1V5 on BOTTOM: 27.95,68.07 28.56,67.46 28.56,64.01 28.28,63.73 26.53,63.73 26.3,63.5 26.3,61.72 26.81,61.21 28.71,61.21 29.09,60.83 29.09,57.91 28.57,57.39 27.68,57.39 24.52,60.55 24.52,62.36 24.12,62.76 22.62,62.76 22.17,63.21 22.17,67.32 22.92,68.07
P1V5 on INT1: 24.01,29.46 24.01,49.85 23.25,50.61 22.17,50.61 17.22,55.56 17.22,89.73 17.88,90.39 18.74,90.39 19.19,90.83 19.19,106.81 18.11,107.89 18.11,111 18.74,111.63 19.31,111.63 19.57,111.38 19.57,109.66 23.12,106.11 23.12,91.06 25.66,88.52 25.66,87.5 23.38,85.22 23.38,68.07 25.03,66.42 25.03,64.96 26.36,63.63 26.36,56.94 27.44,55.88 27.44,53.47 27.95,52.96 29.35,52.96 30.43,51.88 30.43,46.35 32.14,44.64 32.14,26.42 29.98,24.26 29.22,24.26
P1V5_CPU_VDDIO_SUS on TOP (solid shape): 110.78,104.11 110.78,103.02 111.31,102.49 111.31,101.6 111.47,101.45 111.47,100.98 111.2,100.71 109.1,100.71 108.79,101.03 108.79,102.68 108.91,102.81 109.36,102.81 109.61,103.06 109.61,104.14 109.68,104.2 110.69,104.2
P1V5_CPU_VDDIO_SUS on BOTTOM (solid shape): 131.2,160.06 131.38,159.94 131.58,159.89 131.84,159.64 131.84,159.13 132.02,158.95 132.02,157.15 131.88,157.02 131.3,156.46 132.01,156.07 132.56,155.51 132.56,154.66 132.29,154.4 132.26,154.42 132.01,154.53 131.74,154.48 131.32,153.84 132.01,153.53 132.16,153.57 132.3,153.66 132.31,153.68 132.42,153.66 132.44,153.69 132.56,153.64 132.56,150.55 132.49,150.46 132.38,150.49 131.62,150.59 131.56,149.82 131.37,149.63 131.37,149.18 131.39,149.16 131.39,147.92 131.37,147.38 131.85,147.13 131.87,147.14 132.16,146.85 132.56,146.85 132.56,145.39 132.2,145.39 132.18,145.41 131.3,145.16 132.09,144.68 132.27,144.68 132.35,144.6 132.35,142.5 132.94,141.92 133.33,141.92 133.56,141.69 133.56,141.11 133.41,140.96 132.73,140.96 132.62,141.22 132.35,141.33 132.05,141.33 131.78,141.22 131.67,140.96 131.67,140.65 130.06,140.65 130.02,140.68 130.02,159.79 130.06,159.82 130.76,159.82 130.91,159.97 131.01,160.08 131.19,160.08
P1V5_CPU_VDDIO_SUS on GND1 (solid shape): 183.59,165.22 183.59,164.25 184.21,163.64 185.56,163.64 185.88,163.34 185.88,144.29 185.68,144.1 185.68,142.86 185.88,142.67 185.88,131.42 185.72,131.25 184.28,131.25 184.22,131.27 184.2,131.25 184.18,131.25 184.14,131.21 184.08,131.17 183.37,130.47 181.98,130.47 181.24,131.21 180.22,131.21 179.44,131.99 177.94,131.99 177.17,131.23 175.15,131.23 174.38,131.98 172.95,131.98 172.19,131.21 170.76,131.21 170.26,130.72 169.41,130.72 169.04,131.09 169.04,133.25 169.03,133.4 166.05,136.36 159.44,136.36 157.99,134.91 155.54,134.91 154.5,135.95 149.33,135.95 143.31,135.95 141.37,137.89 139.87,137.89 138.39,139.37 137.63,139.37 137.14,139.85 135.42,139.85 134.55,140.71 131.72,140.71 130.85,140.72 130.17,141.42 130.17,157.76 130.69,158.27 134.17,158.28 134.59,157.88 135.28,157.88 135.63,158.23 135.69,158.23 136.06,157.86 136.73,157.86 136.95,158.07 137.05,158.07 137.24,157.88 137.83,157.88 138.27,158.32 141.09,158.32 143.09,160.31 146.55,160.31 146.85,160.62 163.01,160.62 164.5,162.12 169.41,162.12 170.3,163 170.55,163 171.69,164.15 179.99,164.15 180.24,164.19 181.89,165.84 182.96,165.84
P1V5_CPU_VDDIO_SUS on VCC (solid shape): outline of 138 points within 60.78,102.93 185.88,165.84
P1V5_CPU_VDDIO_SUS on GND2 (solid shape): 185.37,163.75 185.37,131.59 185.1,131.32 184.35,131.32 184.28,131.38 183.39,132.27 182.28,132.27 181.49,131.48 180.54,131.48 179.64,130.58 178.3,130.58 177.34,131.53 175.22,131.53 174.69,132.07 173.03,132.07 172.19,131.21 171.31,131.21 171.28,131.24 171.13,131.21 171.05,131.21 170.34,130.51 168.81,130.51 166.83,132.47 157.69,132.52 157.57,132.62 156.45,133.79 150.05,133.79 148.12,135.72 143.9,135.72 140.82,138.81 140.82,138.82 140.26,139.38 137.74,139.38 137.28,139.84 135.54,139.84 134.68,140.7 132.66,140.7 131.97,141.39 131.43,141.92 130.17,143.18 130.17,157.91 130.61,158.35 132.24,158.35 132.39,158.35 133.41,158.35 134.58,159.51 139.78,159.51 140.8,160.53 140.83,160.57 144.44,160.57 145.91,162.04 161.71,162.04 162.37,162.7 165.34,162.7 165.88,163.23 170.29,163.23 170.45,163.23 172.96,165.76 174.43,165.76 176.54,163.65 179.99,163.65 182.13,165.8 183.32,165.8
P1V5_CPU_VDDIO_SUS on TOP: 188.22,151.89 188.22,162.28 188.38,162.43 189.09,162.43 189.27,162.61 189.27,164.05 189.75,164.53 189.75,166.01 189.27,166.5 189.27,213.08 183.78,218.57 183.78,230.89 186.32,233.43 190.38,233.43 191.02,232.79 191.02,226.82 191.4,226.44 192.16,226.44 193.43,225.17 193.43,151.97 193.05,151.59 188.53,151.59
P1V5_CPU_VDDIO_SUS on TOP: 120.15,93.34 122.52,93.34 123.25,94.08 129.35,94.08 129.93,93.5 129.93,91.69 129.68,91.44 123.12,91.44 121.91,90.22 121.22,90.22 120.53,89.53 120.53,86.49 120.03,86.49 120.03,88.27 119.9,88.39 119.39,88.39 119.26,88.27 119.26,86.49 118.76,86.49 118.76,91.95
P1V5_CPU_VDDIO_SUS on TOP: 191.42,137.83 191.42,136.29 190.76,136.29 190.56,136.49 189.74,136.49 189.37,136.86 189.37,138.18 189.67,138.48 190.76,138.48
P1V5_CPU_VDDIO_SUS on TOP: 37.03,67.94 43.76,67.94 44.14,67.56 44.14,65.66 43.95,65.47 37.29,65.47 36.9,65.85 36.9,67.82
P1V5_CPU_VDDIO_SUS on BOTTOM: 32.52,62.74 33.67,62.74 35.06,64.14 35.06,67.94 36.02,68.9 37.35,68.9 37.6,68.64 37.6,64.26 36.41,63.07 36.41,54.13 35.7,53.42 35.7,50.61 35.38,50.29 33.34,50.29 33.31,50.31 32.4,51.23 32.4,62.61
P1V5_CPU_VDDIO_SUS on BOTTOM: 182.51,230.84 185.1,233.43 188,233.43 188,233.4 191.02,230.38 191.02,138.94 191.15,138.81 191.22,138.81 191.39,138.65 191.39,134.99 190.64,134.24 186.45,134.24 186.19,133.99 186.19,131.95 185.56,131.32 184.16,131.32 183.14,130.3 182.26,130.3 181.24,131.32 179.97,131.32 179.46,130.81 178.06,130.81 177.43,131.44 177.43,213.42 182.7,213.42 183.78,214.5 183.78,223.2 182.51,224.47
P1V5_CPU_VDDIO_SUS on BOTTOM: 90.02,120.24 91.07,119.19 92.09,119.19 92.34,119.44 92.34,119.7 92.09,119.95 92.09,122.17 91.64,122.62 90.56,122.62 90.02,122.08
P1V5_CPU_VDDIO_SUS on BOTTOM: 86.37,127.38 86.37,126.11 84.97,126.11 84.85,125.98 82.92,125.98 82.64,126.26 82.64,127.23 82.79,127.38
P1V5_CPU_VDDIO_SUS on INT1: 35.19,51.69 35.19,50.8 35.44,50.55 36.33,50.55 36.49,50.7 36.49,51.72 36.33,51.88 35.38,51.88
P1V5_CPU_VDDIO_SUS on INT1: 99.28,112.2 97.24,114.24 91.83,114.24 90.63,115.44 90.63,122.69 90.13,123.19 82.71,123.19 81.44,124.46 81.44,133.1 82.27,133.92 103.95,133.92 104.64,134.61 105.7,134.61 107.81,136.72 110.26,136.72 115.28,141.73 116.17,141.74 129.4,141.74 130.17,142.52 130.17,157.76 130.7,158.28 134.17,158.28 134.59,157.88 135.28,157.88 135.63,158.23 135.69,158.23 136.06,157.86 136.73,157.86 136.95,158.07 137.05,158.07 137.24,157.88 137.83,157.88 138.27,158.32 141.09,158.32 143.09,160.31 144.42,160.31 144.79,159.94 144.79,127.2 140.12,122.53 113.68,122.53 112.66,121.51 112.66,104.84 111.52,103.7 111.52,101.03 111.2,100.71 108.91,100.71 104.85,104.78 104.85,106.68 99.32,112.2
P1V5_CPU_VDDIO_SUS on INT1: 53.06,105.02 55.48,107.44 61.65,107.44 63.89,105.2 63.89,72.52 61.99,70.61 60.65,70.61 60.46,70.42 60.46,69.09 56.91,65.53 43.83,65.53 43.51,65.85 43.51,70.42 45.48,72.39 50.87,72.39 52.08,73.6 52.08,76.77 49.92,78.93 49.92,83.66 54.16,87.89 54.16,88.13 54.6,88.57 54.6,89.1 54.16,89.53 54.16,94.12 53.06,95.22
P1V5_WW on VCC (solid shape): 47.7,85.61 46.41,84.33 27.7,84.33 26.81,85.22 25.93,85.22 25.54,85.61 25.54,86.36 34.32,86.36 34.44,86.49 47.7,86.49
P1V8 on VCC (solid shape): 69.29,177.72 69.29,165.34 69.97,164.66 74.76,164.66 75.26,164.16 75.26,161.75 73.34,159.83 71.56,159.83 70.43,158.7 70.43,157.43 69.8,156.8 69.8,156.09 65.67,151.96 65.29,151.96 65.24,151.96 60.27,151.96 60.27,152.35 59.89,152.73 59.89,154.45 58.95,155.38 58.07,155.38 57.49,155.96 52.7,155.96 51.76,155.02 51.76,147.78 51.38,147.4 51.38,146.54 51.76,146.16 51.76,139.3 52.45,138.62 57.59,138.62 60.64,135.57 62.03,135.57 62.69,134.92 62.69,132.64 63.07,132.26 63.07,129.62 60.15,126.7 60.15,123.9 59.62,123.38 58.38,123.38 58,123.76 57.47,123.76 57.08,123.38 42.19,123.38 41.48,124.09 41.48,138.57 31.95,148.1 31.95,157.27 35.59,160.91 42.25,160.91 45.62,164.27 48.45,164.27 49.65,163.07 50.7,163.07 53.11,165.48 56.67,165.48 58.19,167 60.86,167 61.29,167.43 61.29,173.94 59.91,175.32 46.89,175.32 46.56,175.66 46.56,176.39 48.92,178.75 68.26,178.75
P1V8 on TOP: 24.65,144.08 26.87,144.08 27.7,144.91 27.7,147.65 27.93,147.88 28.89,147.88 30.81,145.96 30.81,144.28 29.12,142.6 24.67,142.6 24.61,142.66 24.61,144.04
P1V8 on TOP: 61.54,176.15 64.33,176.15 65.54,174.94 66.21,174.94 66.43,174.72 66.43,174.37 65.42,173.35 61.1,173.35 60.59,173.86 60.59,174.88 61.35,175.64 61.35,175.96
P1V8 on TOP: 57.8,125.98 57.81,125.97 57.81,124.98 59.35,123.44 59.57,123.44 59.95,123.83 59.95,125.86 59.17,126.64 59.17,127.99 59.09,128.07 58.23,128.07 57.8,127.64
P1V8 on BOTTOM: 32.09,149.61 34.17,147.52 34.17,146.43 33.81,146.06 28.32,146.06 27.67,146.71 27.67,148.13 29.14,149.61
P1V25 on VCC (solid shape): 65.58,151.35 65.58,144.7 72.72,137.54 72.72,136.07 74.23,134.56 80.51,134.56 81.15,133.92 83.48,133.92 84.02,133.38 84.02,131.52 81.85,129.35 74.73,129.35 73.99,128.6 73.99,121.62 73.15,120.78 70.54,120.78 67.56,117.79 62.23,117.79 61.46,117.03 60.54,117.03 60.21,117.36 60.21,121.27 60.53,121.58 60.53,126.54 63.45,129.46 63.45,132.41 63.07,132.79 63.07,135.08 62.24,135.91 62.24,140.26 60.97,141.53 60.97,143.12 60.27,143.82 60.27,146.99 60.15,147.12 60.15,151.7 65.24,151.7
P1V25 on TOP: 62.49,117.73 60.21,120.02 60.21,121.03 62.11,122.94 67.89,122.94 68.39,123.44 69.99,123.44 69.99,116.97 67.7,114.68 67.7,111.38 66.43,110.11 62.49,110.11
P1V25 on TOP: 82.81,133.86 82.81,131.44 83.07,131.19 83.7,131.19 83.96,131.44 83.96,133.86 83.89,133.92 82.88,133.92
P3V3 on TOP (solid shape): 40.27,103.89 40.27,102.04 40.02,101.79 38.43,101.79 38.24,101.98 38.24,102.93 38.56,103.25 38.56,104.2 39.95,104.2
P3V3 on VCC (solid shape): outline of 1400 points within 9.57,16.64 167.84,241.68
P3V3 on TOP: 163.97,48.13 163.97,54.21 160.52,54.21 159.01,52.7 159.01,46.1 159.33,45.78 160.86,45.78 161.17,45.47 161.17,43.88 164.35,43.88 164.35,47.75
P3V3 on TOP: 20.08,144.75 20.94,144.75 21.09,144.6 22.36,144.6 22.41,144.56 22.41,143.48 22.36,143.43 21.04,143.43 20.76,143.15 20.76,142.42 20.71,142.37 19.77,142.37 19.52,142.62 19.52,144.2
P3V3 on TOP: 19.03,216.36 20.5,216.36 20.87,215.99 20.87,211.44 20.06,210.63 18.49,210.63 18.11,211.01 18.11,212.57 18.49,212.95 18.49,215.82
P3V3 on TOP: 138.63,237.11 137.36,237.11 137.36,242.39 137.77,242.8 138.8,242.8 139.18,242.41 139.18,239.12 138.63,238.57
P3V3 on BOTTOM: 19.7,213.04 18.74,212.09 18.74,211.77 19.06,211.46 20.71,211.46 21.09,211.84 21.09,214.25 20.58,214.76 20.39,214.76 19.7,214.06
P3V3 on BOTTOM: 106.44,54.23 106.44,51.56 106.69,51.31 107.58,51.31 107.96,51.69 107.96,54.1 107.83,54.23 107.2,54.23 107.07,54.36 106.56,54.36
P3V3_AUDIO_DVDD on TOP: 29.22,53.34 29.22,52.96 29.86,52.32 30.62,52.32 30.74,52.45 30.74,53.47 33.48,56.2 34.68,56.2 34.68,59.63 33.65,59.63 32.45,58.42 30.74,58.42 30.62,58.29 30.62,57.53 31,57.15 31,55.88 30.74,55.63 28.08,55.63 27.95,55.5 27.95,54.61
P3V3_BT on TOP: 75.58,91.82 79.07,91.82 79.7,92.46 80.4,92.46 80.4,90.17 80.02,89.79 79.51,89.79 78.12,88.39 77.48,88.39 77.35,88.52 77.35,90.04 77.23,90.17 74.18,90.17 74.05,90.3 74.05,91.06 74.31,91.31 75.07,91.31
P3V3_SB on VCC (solid shape): 100.07,68.71 104.14,68.71 104.72,68.12 104.72,60.75 105.87,59.61 105.87,53.8 105.6,53.53 100.29,53.53 99.52,54.31 99.52,57.86 98.5,58.88 98.5,61.17 98.01,61.66 97.63,61.66 96.91,62.37 96.91,63.61 97.74,64.44 97.74,68.36 97.75,68.36 97.77,68.4 99.02,69.66 99.12,69.66
P3V3_SB on BOTTOM: 103.26,51.31 105.55,51.31 105.93,51.69 105.93,53.98 105.55,54.36 102.5,54.36 102.37,54.23 102.37,52.2
P3V3_STBY on TOP (solid shape): 49.54,196.94 49.89,196.6 49.89,195.77 49.1,195.77 48.52,196.34 45.67,196.34 45.54,196.47 43.64,196.47 43.51,196.34 42.05,196.34 29.09,183.39 27.39,183.39 27.31,183.48 27.31,183.89 41.03,197.61 49.54,197.61
P3V3_STBY on VCC (solid shape): outline of 136 points within 36.33,23.3 156.92,88.96
P3V3_STBY on TOP: 66.22,84.95 66.57,84.95 66.58,84.96 67.19,84.96 67.57,84.58 67.57,83.39 67.27,83.08 66.1,83.08 65.86,83.32 65.86,84.59
P3V3_STBY on TOP: 24.33,177.86 24.71,177.86 24.97,177.61 24.97,177.29 25.22,177.04 26.87,177.04 27.25,176.66 29.98,176.66 30.36,176.28 30.36,175.51 26.93,175.51 26.81,175.39 24.39,175.39 24.14,175.64 24.14,177.67
P3V3_STBY on TOP: 153.3,26.16 153.55,25.91 157.49,25.91 158.32,26.73 158.32,28.77 161.68,32.13 164.29,32.13 165.17,33.02 165.17,43.18 160.03,43.18 159.65,42.8 159.65,40.26 158.76,39.37 156.47,39.37 153.3,36.2
P3V3_STBY on TOP: 67.7,69.22 67.7,69.98 66.75,70.93 66.75,75.76 67.7,76.71 72.4,76.71 72.78,76.33 72.78,74.8 73.02,74.56 74.93,74.56 75.32,74.17 75.32,73.28 75.19,73.15 73.16,73.15 72.58,72.57 69.92,72.57 68.97,71.63 68.97,69.22 68.72,69.22 68.72,69.98 68.65,70.04 68.53,70.04 68.46,69.98 68.46,69.22 68.21,69.22 68.21,69.98 68.15,70.04 68.02,70.04 67.96,69.98 67.96,69.22
P3V3_STBY on BOTTOM: 123.07,39.5 124.66,39.5 124.72,39.56 124.72,41.15 124.47,41.4 123.07,41.4 122.76,41.08 122.76,39.81
P3V3_STBY on INT1: 23.26,176.67 25.16,178.56 25.16,180.59 26.81,182.25 26.81,183.39 29.92,186.5 30.87,185.55 30.87,182.12 25.03,176.28 23.66,176.28
P3V3_STBY on INT1: 31.95,47.94 31.95,52.9 30.17,54.67 29.35,54.67 28.65,55.37 28.65,58.55 29.47,58.55 33.35,54.67 33.35,49.91 35.95,47.31 37.92,47.31 38.75,46.48 39.83,46.48 39.83,46.04 39.38,45.59 39.38,43.37 38.94,42.93 36.97,42.93
P3V3_TV on TOP: 24.52,24.26 24.52,23.75 24.71,23.56 25.92,23.56 26.05,23.69 26.05,25.65 25.92,25.78 24.9,25.78 24.78,25.65 24.78,24.51
P3V3_TV1 on BOTTOM: 45.35,15.11 43.57,15.11 43.06,15.62 43.06,17.27 43.19,17.4 44.71,17.4 44.71,16.76 45.48,16 45.48,15.24
P3V3_WW on VCC (solid shape): 50.81,87.42 50.81,87.14 50.54,86.87 34.29,86.87 34.16,86.74 25.54,86.74 25.54,87.68 25.81,87.95 50.29,87.95
P5V on TOP (solid shape): 39.76,11.43 39.76,9.53 39.51,9.27 37.6,9.27 37.35,9.53 37.35,11.68 39.51,11.68
P5V on BOTTOM (solid shape): 40.78,10.67 40.78,9.78 40.27,9.27 37.6,9.27 37.35,9.53 37.35,11.43 37.6,11.68 39.76,11.68
P5V on VCC (solid shape): outline of 238 points within 43.38,13.21 139.52,27.37
P5V on TOP: 183.91,247.27 183.91,246.63 183.53,246.25 183.53,244.73 180.86,242.06 180.86,240.66 180.6,240.41 178.45,240.41 178.19,240.66 178.19,242.32 183.27,247.4 183.78,247.4
P5V on TOP: 188.35,242.32 192.67,242.32 193.05,241.94 193.05,236.09 192.8,235.84 188.22,235.84 187.72,236.35 187.72,241.68
P5V on TOP: 161.43,67.69 167.14,67.69 167.4,67.44 167.4,65.15 167.14,64.9 165.49,64.9 165.11,65.28 161.81,65.28 161.3,65.79 161.3,67.56
P5V on TOP: 164.54,246.25 164.54,243.4 165.11,242.82 166.51,242.82 167.21,242.13 167.21,240.98 167.52,240.66 168.92,240.66 169.11,240.86 169.11,242.7 166.76,245.05 166.76,246.25
P5V on TOP: 87.86,223.33 90.27,223.33 90.71,223.76 90.71,225.19 90.91,225.39 90.91,231.78 92.59,233.46 92.59,235.33 92.21,235.71 87.77,235.71 87.26,235.2 87.26,228.85 88.3,227.82 88.3,227.69 88.29,227.69 88.29,224.49 87.86,224.06
P5V on TOP: 168.92,49.91 167.78,51.05 166.76,51.05 166.51,51.31 166.51,52.96 167.02,53.47 168.67,53.47 168.92,53.72 168.92,54.36 169.05,54.48 170.57,54.48 170.57,53.13 173.11,50.59 173.11,47.5 172.41,46.8 172.41,43.62 171.97,43.18 170.06,43.18 168.92,44.32
P5V on BOTTOM: 134.82,20.89 134.63,21.08 134.63,29.65 141.81,36.83 149.62,36.83 151.78,38.99 151.78,47.88 149.24,50.42 149.24,68.77 151.27,70.8 155.08,70.8 156.03,71.75 160.41,71.75 161.3,72.64 161.3,76.33 159.4,78.23 159.4,86.18 158.38,87.2 149.86,87.2 145.04,92.01 143.01,92.01 142.31,91.31 141.11,91.31 140.6,91.82 140.6,93.22 141.3,93.92 147.33,93.92 150.7,90.55 160.09,90.55 168.16,82.49 168.16,69.34 169.24,68.26 178.57,68.26 179.02,67.82 179.02,66.17 174.32,66.17 173.87,66.61 167.84,66.61 167.4,66.17 167.4,65.41 166.89,64.9 162.95,64.9 161.3,66.55 158.76,66.55 157.36,65.15 157.36,56.9 164.73,49.53 172.98,49.53 173.24,49.28 173.24,42.55 171.59,40.89 171.59,40.77 160.16,29.34 151.78,29.34 148.35,25.91 148.35,23.69 147.78,23.11 141.55,23.11 140.54,22.1 138.5,22.1 137.3,20.89
P5V on BOTTOM: 46.43,17.65 46.43,16.07 46.75,15.75 46.75,13.4 47.06,13.08 49.73,13.08 50.43,13.78 50.43,18.92 49.86,19.49 48.27,19.49
P5V on BOTTOM: 101.17,100.27 105.67,95.76 110.82,95.76 111.07,96.01 111.07,99.19 111.52,99.63 111.07,99.63 111.07,99.76 107.07,99.76 106.82,99.5 103.83,99.5 103.07,100.27
P5V on INT1: outline of 145 points within 18.24,42.99 193.11,253.11 ; 1 cut-out
P5V_AUDIO_AVDD on TOP: 23.12,42.86 22.36,42.86 22.11,43.12 22.11,44.07 21.47,44.7 21.47,45.97 21.22,46.23 21.22,46.74 21.35,46.86 22.36,46.86 23.38,45.85 23.38,43.12
P5V_ODD on TOP: 171.27,65.91 171.27,63.25 171.78,62.74 173.43,62.74 175.65,60.52 176.86,60.52 177.11,60.77 177.11,61.21 176.67,61.66 176.67,64.58 175.46,65.79 174.19,65.79 173.68,66.29 171.65,66.29
P5V_ODD on BOTTOM: 179.65,67.37 179.65,66.17 179.14,65.66 174.76,65.66 174.51,65.41 174.51,64.01 175.27,63.25 177.75,63.25 178.13,63.63 182,63.63 182.26,63.88 182.26,66.04 180.86,67.44 179.72,67.44
P5V_STBY on VCC (solid shape): outline of 1441 points within 1.79,1.91 193.11,253.11
P5V_STBY on TOP: 75,23.5 75,17.97 75.7,17.27 82.18,17.27 82.81,17.91 82.81,22.54 81.2,24.16 75.67,24.16
P5V_STBY on TOP: 27.44,178.56 27.44,177.67 27.63,177.48 29.54,177.48 41.48,189.42 47.64,189.42 48.27,190.06 48.27,190.63 47.57,191.33 41.35,191.33 29.73,179.71 28.59,179.71
P5V_STBY on TOP: 189.75,32.89 189.75,37.08 188.62,38.23 185.05,38.23 183.78,39.5 180.99,39.5 177.3,43.18 177.3,46.35 177.05,46.61 173.43,46.61 172.92,46.1 172.92,40.58 172.35,40.01 172.35,36.58 174,34.92 175.14,34.92 179.08,30.99 187.84,30.99
P5V_STBY on BOTTOM: 22.87,180.47 22.87,176.15 23.63,175.39 27.19,175.39 28.08,176.28 28.08,178.5 27.89,178.69 25.79,178.69 24.65,179.83 24.65,180.72 23.12,180.72
P5V_STBY on BOTTOM: 49.16,191.01 47.51,191.01 46.49,189.99 46.49,189.48 46.56,189.42 47.19,189.42 47.89,190.12 49.16,190.12
P5V_STBY on INT1: outline of 135 points within 1.79,1.91 193.11,253.11 ; 4 cut-outs
P5V_TOUCH on TOP: 54.11,65.41 55.89,65.41 56.08,65.21 56.08,63.16 55.43,62.51 54.47,62.51 54.11,62.87 53.07,62.87 52.74,63.2 52.74,65.05 52.78,65.09 52.78,65.66 53.1,65.98 53.54,65.98
P5V_USB on TOP (solid shape): 76.34,15.75 76.34,13.59 76.08,13.34 74.05,13.34 73.73,13.65 73.73,15.68 73.92,15.88 76.21,15.88
P5V_USB on TOP (solid shape): 45.98,12.19 45.98,9.27 45.86,9.14 44.59,9.14 44.33,9.4 44.33,10.54 44.21,10.67 43.19,10.67 42.68,11.18 42.68,12.06 43.32,12.7 45.48,12.7
P5V_USB on TOP: 50.96,65.05 52.11,65.05 52.28,64.87 52.28,63.42 51.95,63.09 51.4,63.09 49.82,61.52 48.86,61.52 48.68,61.7 48.68,62.76
P5V_USB on TOP: 66.18,25.15 65.8,24.77 64.07,24.77 63.71,24.41 62.34,24.41 61.73,25.02 61.73,26.04 63.51,27.81 65.29,27.81 66.18,26.92
P5V_USB on TOP: 15.45,72.14 17.41,72.14 18.71,70.83 17.47,69.6 15.25,69.6 14.78,70.07 14.78,71.46
P5V_USB on BOTTOM: 12.71,70.87 12.71,69.09 13.16,68.64 16.2,68.64 16.71,69.15 16.71,71.75 16.46,72.01 15.19,72.01 14.23,71.06 12.9,71.06
P5V_USB on INT1: 20.39,12.57 15.31,17.65 15.31,40.34 14.68,40.97 14.68,44.27 14.06,44.89 9.36,44.89 8.96,45.29 8.96,46.09 9.41,46.53 9.41,47.45 8.46,48.4 8.46,61.01 9.03,61.58 9.03,62.5 8.46,63.07 8.46,72.06 11.38,74.98 11.38,76.91 9.73,78.56 9.73,85.17 6.68,88.22 6.68,93.65 7.2,94.17 15.7,94.17 16.58,93.28 16.58,55.18 23.25,48.51 23.25,25.91 22.11,24.77 22.11,18.99 21.6,18.48 21.6,17.21 22.24,16.57 29.86,16.57 32.01,18.73 46.18,18.73 47.38,19.94 47.38,24.64 45.48,26.54 39.83,26.54 39.44,26.92 39.44,34.42 39.76,34.73 40.71,34.73 41.1,34.35 42.87,34.35 43.57,35.05 53.86,35.05 54.37,34.54 54.37,28.45 56.14,26.67 72,26.67 74.43,24.24 74.43,17.96 76.21,16.18 76.21,13.73 75.81,13.34 74,13.34 73.54,13.79 73.54,15.06 71.84,16.76 66.19,16.76 64.73,18.22 55.89,18.22 50.24,12.57 46.62,12.57 44.97,10.92 42.68,10.92 41.03,12.57
P5V_USB5V1 on TOP: 89.58,3.4 88.15,4.83 81.86,4.83 80.72,3.68 77.35,3.68 75.58,5.46 72.91,5.46 72.08,6.29 72.08,9.59 72.65,10.16 73.16,10.16 73.16,8.89 73.42,8.64 75.45,8.64 75.83,9.02 76.34,9.02 76.85,8.51 76.85,7.49 78.62,5.71 80.08,5.71 81.35,6.99 86.24,6.99 86.75,7.49 87.26,6.99 87.89,6.99 88.21,6.67 89.79,6.67 90.82,5.65 93.11,5.65 93.23,5.52 93.23,4.32 92.31,3.4
P5V_USB5V3 on TOP: 67.57,5.71 65.23,5.71 64.21,6.73 56.65,6.73 55.7,5.78 52.02,5.78 51.06,6.73 51.06,9.14 50.94,9.27 50.3,9.27 49.67,8.64 48.91,8.64 48.65,8.38 48.65,6.73 48.02,6.1 48.02,4.7 48.52,4.19 63.07,4.19 63.51,3.75 67.38,3.75 67.77,4.13 67.77,5.52
P5V_USB_CAM on TOP (solid shape): 41.54,9.02 41.54,8.26 40.35,7.06 40.35,4.88 40.27,4.8 39.86,4.8 39.76,4.9 39.76,6.76 39.28,7.24 37.32,7.24 37.07,7.49 37.07,8.74 37.22,8.89 40.14,8.89 40.4,9.14 41.41,9.14
P12V on TOP: 121.17,50.42 123.45,50.42 124.72,51.69 125.61,51.69 126.12,51.18 126.12,47.24 125.99,47.12 121.04,47.12 120.28,47.88 120.28,49.53
P12V on TOP: 143.27,53.47 143.27,51.44 143.01,51.18 141.62,51.18 140.73,52.07 140.73,53.59 141.23,54.1 142.63,54.1
P12V on BOTTOM: 124.76,47.02 124.7,46.96 121.32,46.96 120.79,47.5 120.79,49.53 123.73,52.48 123.73,54.23 124.72,55.22 127.07,55.22 128.03,54.27 128.03,53.09 128.66,52.45 130,52.45 132.76,55.22 142.09,55.22 143.27,54.04 143.27,52.45 142.31,51.5 134.31,51.5 129.84,47.02
P12V_HDD on TOP: 165.36,64.39 167.27,64.39 167.65,64.01 167.65,59.44 167.14,58.93 165.87,58.93 164.98,59.82 162.19,59.82 161.17,58.8 155.46,58.8 152.03,55.37 152.03,53.98 151.39,53.34 149.24,53.34 148.09,52.2 148.09,51.31 147.97,51.18 143.9,51.18 143.65,51.44 143.65,54.61 145.81,56.77 147.2,56.77 147.71,57.28 147.71,58.67 148.03,58.99 148.66,58.99 152.28,62.61 157.61,62.61 157.84,62.38 161.43,62.38 161.66,62.61 164.6,62.61 165.11,63.12 165.11,64.14
P12V_STBY on TOP: 127.39,53.21 131.07,53.21 131.46,52.83 131.46,50.93 131.84,50.55 131.84,45.97 131.33,45.47 129.8,45.47 129.55,45.72 127.01,45.72 126.63,46.1 126.63,52.45
P12V_STBY on TOP: 13.47,41.78 14.36,41.78 14.62,41.53 14.62,39.62 14.49,39.5 13.35,39.5 13.09,39.75 13.09,41.4
P12V_STBY on BOTTOM: 14.06,41.35 14.62,41.35 15.84,40.13 15.84,39.34 15.71,39.22 13.94,39.22 13.75,39.41 13.75,41.05
P19V_CONVERTER on TOP: 180.8,47.43 180.8,46.93 181.11,46.61 183.4,46.61 183.65,46.86 183.65,48.51 183.27,48.9 181.87,48.9 181.49,48.51 181.49,48.13
P19V_CONVERTER on BOTTOM: 181.49,48.64 181.49,47.24 182,46.74 184.67,46.74 184.8,46.86 186.83,46.86 186.95,46.99 186.95,47.5 185.43,49.02 181.87,49.02
P19V_FILT on BOTTOM (solid shape): 110.56,201.23 110.56,194.44 107.58,191.45 106.45,191.45 106.39,191.52 106.39,196.78 106.94,197.33 106.94,200.82 107.69,201.57 110.23,201.57
P19V_FILT on VCC (solid shape): outline of 119 points within 93.04,192.98 116.91,217.31
P19V_FILT on TOP: 111.58,200.19 111.58,193.48 110.75,192.66 106.5,192.66 105.99,193.17 105.99,201.23 106.21,201.45 110.32,201.45
P19V_FILT on TOP: 106.27,212.75 110.3,212.75 111.18,213.63 111.98,213.63 112.47,214.12 112.47,216.73 111.9,217.3 106.24,217.3 105.8,216.86 105.8,213.22
P19V_FILT on TOP: 97.42,193.04 93.48,193.04 92.59,193.93 92.59,199.96 93.04,200.41 93.04,201.74 93.42,202.12 96.66,202.12 97.8,200.98 97.8,193.42
P19V_FILT on BOTTOM: 93.48,201.17 93.48,197.99 93.99,197.49 93.99,192.02 94.44,191.58 96.02,191.58 96.85,192.41 96.85,197.99 97.29,198.44 97.29,200.66 96.4,201.55 93.86,201.55
P19V_FILT on INT1: 93.56,192.98 93.04,193.5 93.04,205.99 93.39,206.34 93.39,211.3 96.28,214.19 103.58,214.19 106.69,217.3 110.37,217.3 115.47,212.2 115.47,203.28 111.96,199.77 111.96,194.88 110.06,192.98
P19V_FILT_NB on TOP (solid shape): 128.22,225.27 128.22,217.68 127.58,217.04 123.58,217.04 123.07,217.55 123.07,225.36 123.57,225.86 127.63,225.86
P19V_FILT_NB on BOTTOM (solid shape): 128.22,225.98 128.22,217.68 126.63,216.09 123.71,216.09 123.39,216.41 123.39,226.28 123.95,226.83 127.36,226.83
P19V_INVERTER on TOP: 189.11,53.47 189.11,49.02 187.21,47.12 187.21,45.21 186.57,44.57 184.48,44.57 184.03,45.02 184.03,50.8 184.41,51.18 184.41,52.83 184.8,53.21 185.68,53.21 186.07,53.59 186.07,54.36 186.19,54.48 188.1,54.48
P19V_MXM on TOP: 95.34,224.36 95.65,224.67 96.15,224.67 96.4,224.92 96.4,225.43 96.75,225.78 96.75,230.5 97.64,231.39 99.8,231.39 100.69,230.5 100.69,221.4 98.94,219.66 98.94,216.79 100.09,215.65 100.09,214.16 100.08,214.15 100.08,214.02 99.91,213.84 95.08,213.84 95.08,219.56 95.34,219.81
P19V_SYS on TOP (solid shape): 103.21,230.04 103.21,227.84 102.22,226.85 101.56,226.85 101.18,227.23 101.18,230.05 101.73,230.61 102.65,230.61
P19V_SYS on TOP (solid shape): 131.27,224.92 131.27,221.42 130.76,220.92 128.92,220.92 128.66,221.17 128.66,224.92 129.11,225.36 130.82,225.36
P19V_SYS on TOP (solid shape): 178.06,23.75 178.06,20.19 177.18,19.3 171.14,19.3 170.76,19.68 170.76,21.84 171.02,22.1 174.89,22.1 176.67,23.88 177.94,23.88
P19V_SYS on VCC (solid shape): outline of 302 points within 79.89,14.67 193.11,239.52
P19V_SYS on TOP: 81.67,101.98 81.67,104.24 82.21,104.78 83.2,104.78 83.45,104.52 83.45,102.36 82.94,101.85 81.8,101.85
P19V_SYS on TOP: 179.33,45.85 179.33,44.83 179.59,44.58 182.89,44.58 183.4,45.09 183.4,45.72 182.76,46.35 179.84,46.35
P19V_SYS on TOP: 186.32,81.53 187.08,82.3 191.34,82.3 193.01,80.63 193.01,71.4 191.71,70.1 187.84,70.1 186.32,71.63
P19V_SYS on TOP: 159.01,10.79 159.01,16.26 157.24,18.03 155.59,18.03 154.57,17.02 154.57,14.1 154.06,13.59 154.06,12.51 156.28,12.51 158,10.79
P19V_SYS on TOP: 156.6,217.3 160.54,217.3 160.92,216.92 160.92,215.39 160.54,215.01 156.6,215.01 156.22,215.39 156.22,216.92
P19V_SYS on TOP: 169.81,235.97 165.66,235.97 165.36,236.26 165.36,236.92 165.65,237.2 170.1,237.2 170.57,236.73 170.57,236.23 170.31,235.96 169.81,235.96
P19V_SYS on TOP: 146.19,48.26 146.19,47.24 146.95,46.48 149.49,46.48 149.49,48.39 149.11,48.77 146.7,48.77
P19V_SYS on TOP: 93.48,111.05 94.63,112.19 94.63,112.65 93.98,113.3 93.47,113.3 93.03,112.85 91.4,112.85 91.07,112.52 91.07,111.25 91.27,111.05
P19V_SYS on TOP: 112.16,219.01 106.44,219.01 105.93,219.52 105.93,220.68 105.5,221.1 105.5,222.52 105.87,222.88 110.44,222.88 110.44,222.88 111.52,222.88 112.53,221.87 112.53,219.38
P19V_SYS on BOTTOM: 175.72,19.05 176.86,20.19 176.86,22.61 176.67,22.8 174.64,22.8 173.87,22.03 171.33,22.03 170.83,21.53 170.83,19.56 171.33,19.05
P19V_SYS on BOTTOM: 179.33,45.85 179.33,44.83 179.59,44.58 182.76,44.58 183.14,44.2 183.14,43.05 183.65,42.55 183.91,42.55 184.16,42.8 184.16,45.34 183.14,46.35 179.84,46.35
P19V_SYS on BOTTOM: 154.44,16.7 154.44,14.29 155.46,13.27 158.7,13.27 159.9,14.48 159.9,17.21 159.21,17.91 155.65,17.91
P19V_SYS on INT1: outline of 132 points within 79.89,14.67 193.11,239.97 ; 1 cut-out
P19V_SYS_FILE on TOP (solid shape): 179.84,23.75 179.84,20.32 180.68,19.49 185.63,19.49 185.94,19.18 185.94,13.21 185.75,13.02 185.75,11.87 185.49,11.62 184.67,11.62 184.41,11.87 184.41,13.08 184.16,13.34 184.16,13.72 183.65,14.22 180.99,14.22 180.6,14.61 180.6,16 179.59,17.02 174.76,17.02 174.25,17.53 174.25,18.8 174.51,19.05 177.56,19.05 178.45,19.94 178.45,23.75 178.7,24 179.59,24
P19V_SYS_FILE on BOTTOM (solid shape): 185.94,19.18 185.94,13.21 185.68,12.95 185.68,11.94 185.37,11.62 184.48,11.62 184.35,11.75 184.35,12.89 184.16,13.08 184.16,13.72 183.65,14.22 180.99,14.22 180.6,14.61 180.6,16 179.97,16.64 179.97,18.92 180.6,19.56 185.56,19.56
VDD_PCIE on VCC (solid shape): 57.91,155 58.8,155 59.51,154.29 59.51,152.58 59.89,152.19 59.89,147.01 60.02,146.89 60.02,143.71 60.72,143.01 60.72,141.43 61.99,140.16 61.99,135.95 60.8,135.95 57.75,139 52.6,139 52.14,139.46 52.14,146.32 51.76,146.7 51.76,147.24 52.14,147.62 52.14,154.86 52.86,155.57 57.34,155.57
VDD_PCIE on TOP: 59.38,151.96 59.38,151.45 59.57,151.26 59.57,144.65 59.32,144.4 58.94,144.4 58.56,144.78 57.8,144.78 57.67,144.91 57.67,145.29 57.8,145.41 58.68,145.41 58.81,145.54 58.81,151.51 57.67,152.65 56.65,152.65 56.14,153.16 56.14,155.83 56.78,156.46 56.91,156.46 57.03,156.34 57.03,154.31
